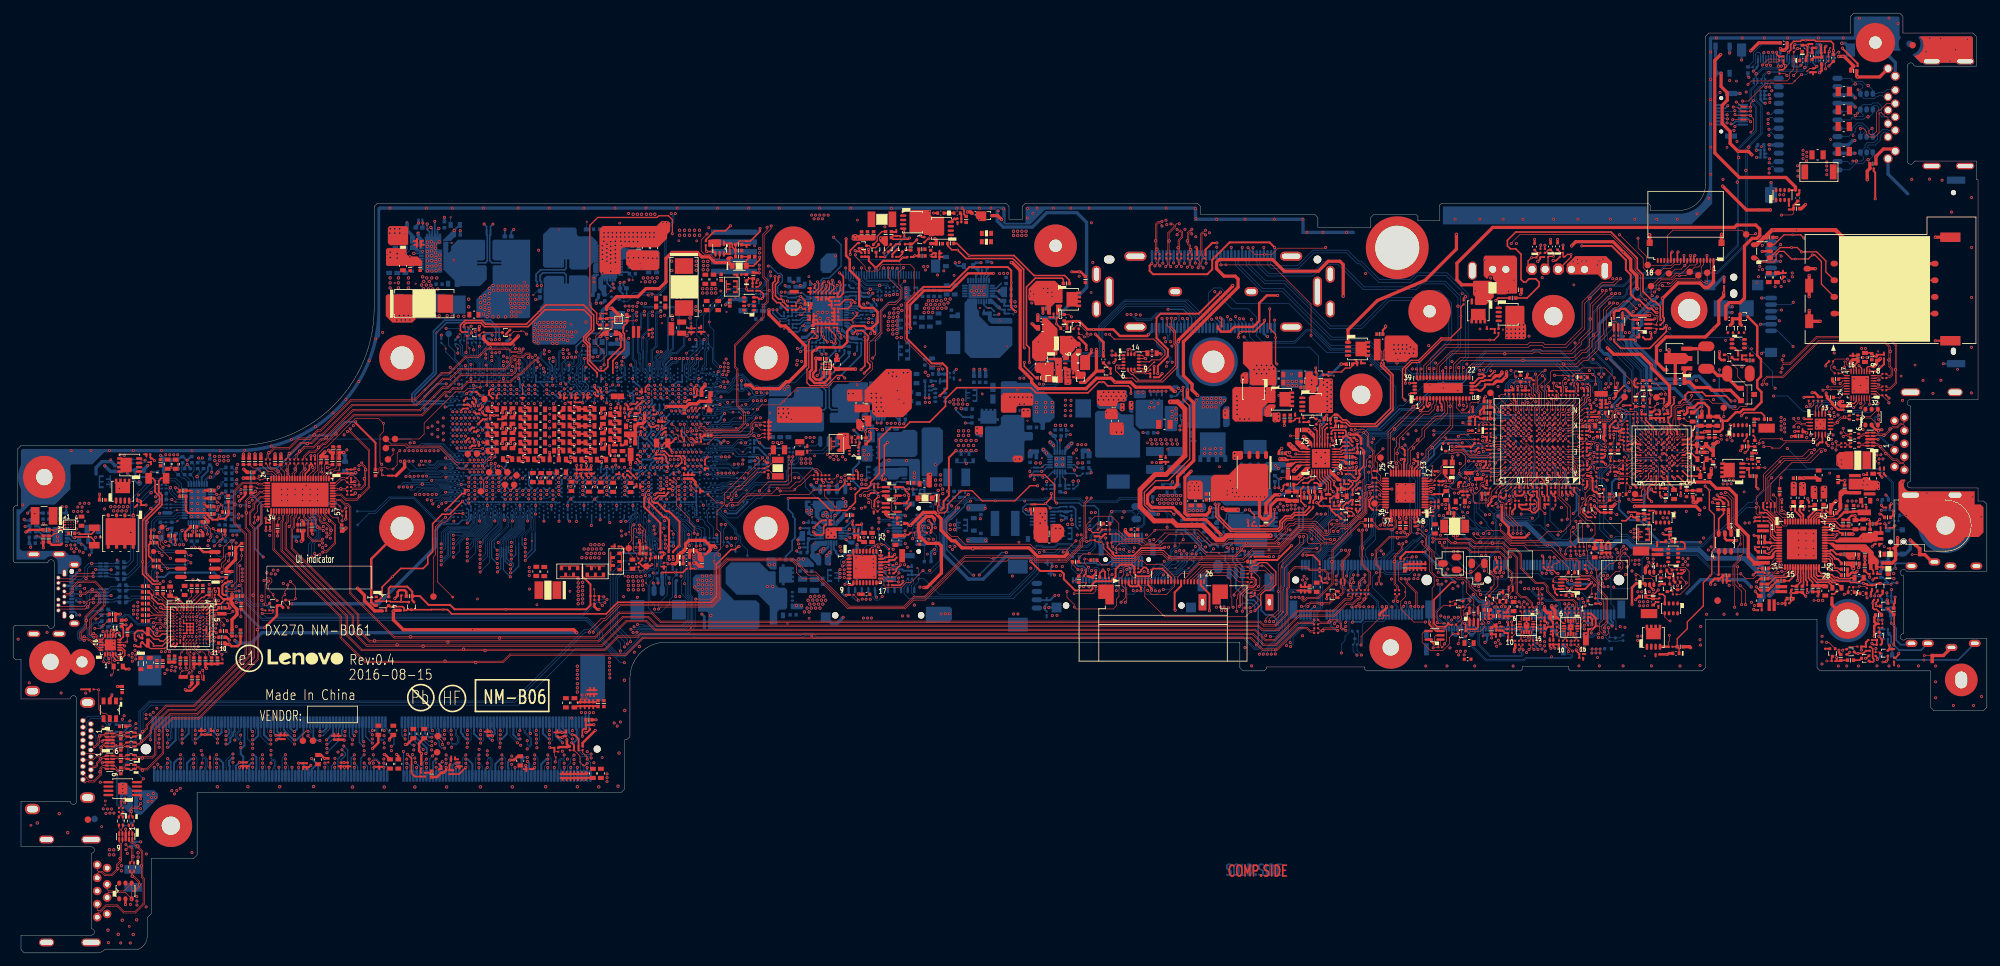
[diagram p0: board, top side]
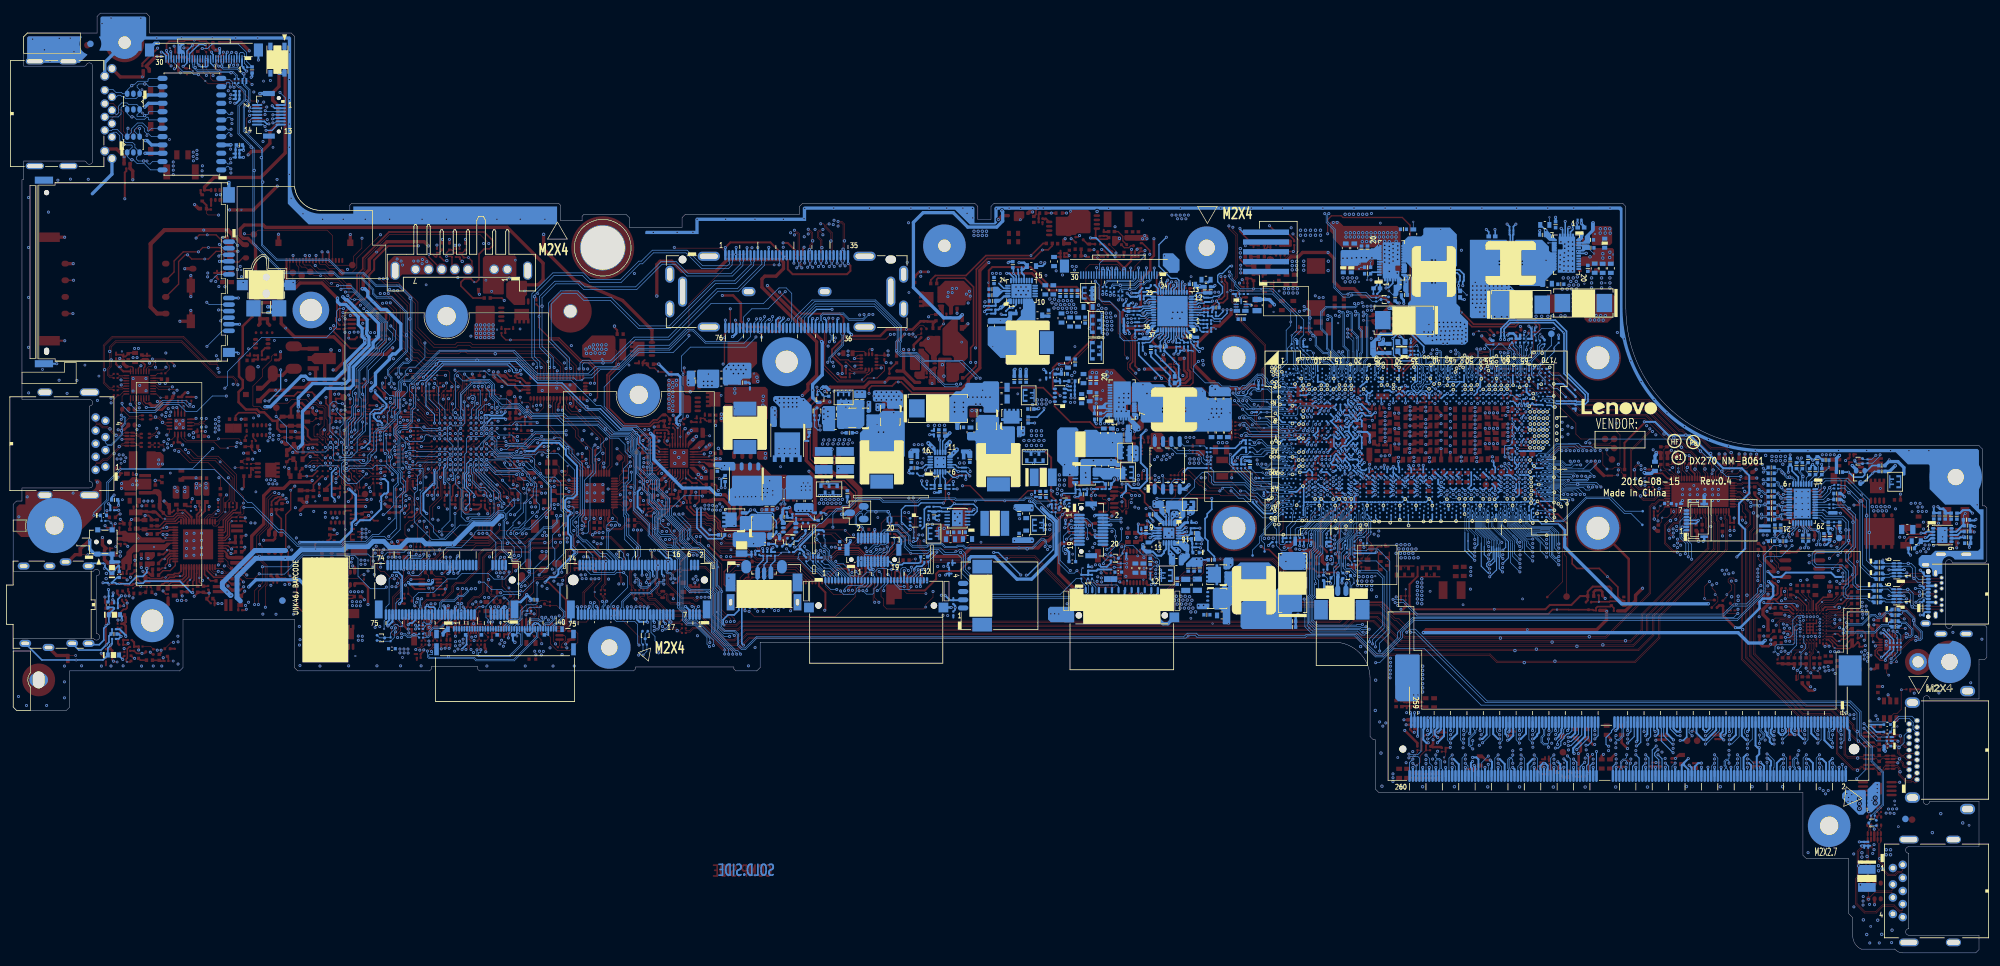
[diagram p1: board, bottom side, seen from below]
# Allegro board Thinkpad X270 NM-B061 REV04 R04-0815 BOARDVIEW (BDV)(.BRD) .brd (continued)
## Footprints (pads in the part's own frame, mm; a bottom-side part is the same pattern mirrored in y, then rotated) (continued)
JUMP_43X39
  custom 0.191x0.191 smd: 1(0,0) 2(0.914,0)
JUMP_43X79
  custom 0.188x0.188 smd: 1(0,0) 2(1.1,0)
JUMP_43X118
  custom 0.187x0.187 smd: 1(0,0) 2(1.1,0)
KX023-1025_LGA16_3X3
  oval 0.61x0.356 smd: 1(0,0) 2(0,-0.5) 3(0,-1) 4(0,-1.5) 5(0,-2) 9(2.325,-2) 10(2.325,-1.5) 11(2.325,-1) 12(2.325,-0.5) 13(2.325,0)
  oval 0.356x0.61 smd: 6(0.662,-2.163) 7(1.163,-2.163) 8(1.663,-2.163) 14(1.663,0.163) 15(1.163,0.163) 16(0.662,0.163)
LSK3541G1ET2L_VMT3
  rect 0.508x0.457 smd: 1(0,0)
  rect 0.406x0.457 smd: 2(-0.4,-1.15) 3(0.4,-1.15)
MEC1653TMP-TN_WFBGA_169P-T
  round 0.356 smd: A1(0,0) A2(0.8,0) A3(1.6,0) A4(2.4,0) A5(3.2,0) A6(4,0) A7(4.8,0) A8(5.6,0) A9(6.4,0) A10(7.2,0) A11(8,0) A12(8.8,0) A13(9.6,0) B1(0,-0.8) B2(0.8,-0.8) B3(1.6,-0.8) B4(2.4,-0.8) B5(3.2,-0.8) B6(4,-0.8) B7(4.8,-0.8) B8(5.6,-0.8) B9(6.4,-0.8) B10(7.2,-0.8) B11(8,-0.8) B12(8.8,-0.8) B13(9.6,-0.8) C1(0,-1.6) C2(0.8,-1.6) C3(1.6,-1.6) C4(2.4,-1.6) C5(3.2,-1.6) C6(4,-1.6) C7(4.8,-1.6) C8(5.6,-1.6) C9(6.4,-1.6) C10(7.2,-1.6) C11(8,-1.6) C12(8.8,-1.6) C13(9.6,-1.6) D1(0,-2.4) D2(0.8,-2.4) D3(1.6,-2.4) D4(2.4,-2.4) D5(3.2,-2.4) D6(4,-2.4) D7(4.8,-2.4) D8(5.6,-2.4) D9(6.4,-2.4) D10(7.2,-2.4) D11(8,-2.4) D12(8.8,-2.4) D13(9.6,-2.4) E1(0,-3.2) E2(0.8,-3.2) E3(1.6,-3.2) E4(2.4,-3.2) E5(3.2,-3.2) E6(4,-3.2) E7(4.8,-3.2) E8(5.6,-3.2) E9(6.4,-3.2) E10(7.2,-3.2) E11(8,-3.2) E12(8.8,-3.2) E13(9.6,-3.2) F1(0,-4) F2(0.8,-4) F3(1.6,-4) F4(2.4,-4) F5(3.2,-4) F6(4,-4) F7(4.8,-4) F8(5.6,-4) F9(6.4,-4) F10(7.2,-4) F11(8,-4) F12(8.8,-4) F13(9.6,-4) G1(0,-4.8) G2(0.8,-4.8) G3(1.6,-4.8) G4(2.4,-4.8) G5(3.2,-4.8) G6(4,-4.8) G7(4.8,-4.8) G8(5.6,-4.8) G9(6.4,-4.8) G10(7.2,-4.8) G11(8,-4.8) G12(8.8,-4.8) G13(9.6,-4.8) H1(0,-5.6) H2(0.8,-5.6) H3(1.6,-5.6) H4(2.4,-5.6) H5(3.2,-5.6) H6(4,-5.6) H7(4.8,-5.6) H8(5.6,-5.6) H9(6.4,-5.6) H10(7.2,-5.6) H11(8,-5.6) H12(8.8,-5.6) H13(9.6,-5.6) J1(0,-6.4) J2(0.8,-6.4) J3(1.6,-6.4) J4(2.4,-6.4) J5(3.2,-6.4) J6(4,-6.4) J7(4.8,-6.4) J8(5.6,-6.4) J9(6.4,-6.4) J10(7.2,-6.4) J11(8,-6.4) J12(8.8,-6.4) J13(9.6,-6.4) K1(0,-7.2) K2(0.8,-7.2) K3(1.6,-7.2) K4(2.4,-7.2) K5(3.2,-7.2) K6(4,-7.2) K7(4.8,-7.2) K8(5.6,-7.2) K9(6.4,-7.2) K10(7.2,-7.2) K11(8,-7.2) K12(8.8,-7.2) K13(9.6,-7.2) L1(0,-8) L2(0.8,-8) L3(1.6,-8) L4(2.4,-8) L5(3.2,-8) L6(4,-8) L7(4.8,-8) L8(5.6,-8) L9(6.4,-8) L10(7.2,-8) L11(8,-8) L12(8.8,-8) L13(9.6,-8) M1(0,-8.8) M2(0.8,-8.8) M3(1.6,-8.8) M4(2.4,-8.8) M5(3.2,-8.8) M6(4,-8.8) M7(4.8,-8.8) M8(5.6,-8.8) M9(6.4,-8.8) M10(7.2,-8.8) M11(8,-8.8) M12(8.8,-8.8) M13(9.6,-8.8) N1(0,-9.6) N2(0.8,-9.6) N3(1.6,-9.6) N4(2.4,-9.6) N5(3.2,-9.6) N6(4,-9.6) N7(4.8,-9.6) N8(5.6,-9.6) N9(6.4,-9.6) N10(7.2,-9.6) N11(8,-9.6) N12(8.8,-9.6) N13(9.6,-9.6)
MMBT3904_SOT23-3
  oval 1.016x1.524 smd: 1(0,0) 2(0.965,2.083) 3(-0.965,2.083)
MOLEX_52435-2671_26P-T
  oval 0.305x0.787 smd: 1(0,0) 2(-0.5,0) 3(-1,0) 4(-1.5,0) 5(-2,0) 6(-2.5,0) 7(-3,0) 8(-3.5,0) 9(-4,0) 10(-4.5,0) 11(-5,0) 12(-5.5,0) 13(-6,0) 14(-6.5,0) 15(-7,0) 16(-7.5,0) 17(-8,0) 18(-8.5,0) 19(-9,0) 20(-9.5,0) 21(-10,0) 22(-10.5,0) 23(-11,0) 24(-11.5,0) 25(-12,0) 26(-12.5,0)
  custom 0.597x0.597 smd: 27(2.45,1.925) 28(-14.95,1.925)
MOLEX_78048-0543_5P-T
  rect 0.838x7.01 smd: 1(0,0) 2(1.5,0) 3(3,0) 4(4.5,0) 5(6,0)
MURAT_BLM18PG221SN1D_2P
  rect 0.61x0.711 smd: 1(0,0) 2(1.3,0)
NCP431AISNT1G_SOT23-3
  rect 0.787x0.889 smd: 1(0,0) 2(0.95,2) 3(-0.95,2)
NCP81208MNTXG_QFN48_6X6
  oval 0.787x0.305 smd: 1(0,0) 2(0,-0.4) 3(0,-0.8) 4(0,-1.2) 5(0,-1.6) 6(0,-2) 7(0,-2.4) 8(0,-2.8) 9(0,-3.2) 10(0,-3.6) 11(0,-4) 12(0,-4.4) 25(5.72,-4.4) 26(5.72,-4) 27(5.72,-3.6) 28(5.72,-3.2) 29(5.72,-2.8) 30(5.72,-2.4) 31(5.72,-2) 32(5.72,-1.6) 33(5.72,-1.2) 34(5.72,-0.8) 35(5.72,-0.4) 36(5.72,0)
  oval 0.305x0.787 smd: 13(0.66,-5.06) 14(1.06,-5.06) 15(1.46,-5.06) 16(1.86,-5.06) 17(2.26,-5.06) 18(2.66,-5.06) 19(3.06,-5.06) 20(3.46,-5.06) 21(3.86,-5.06) 22(4.26,-5.06) 23(4.66,-5.06) 24(5.06,-5.06) 37(5.06,0.66) 38(4.66,0.66) 39(4.26,0.66) 40(3.86,0.66) 41(3.46,0.66) 42(3.06,0.66) 43(2.66,0.66) 44(2.26,0.66) 45(1.86,0.66) 46(1.46,0.66) 47(1.06,0.66) 48(0.66,0.66)
  rect 4.648x4.648 smd: 49(2.86,-2.2)
NCP81382MNTXG_QFN39-31_6X4
  rect 0.711x0.305 smd: 1(0,0) 2(0,-0.4) 3(0,-0.8) 4(0,-1.2) 5(0,-1.6) 6(0,-2)
  rect 0.305x0.711 smd: 7(0.65,-2.85) 8(1.05,-2.85) 9(1.45,-2.85) 10(1.85,-2.85) 11(2.25,-2.85) 12(2.65,-2.85) 13(3.05,-2.85) 14(3.45,-2.85) 15(3.85,-2.85) 16(4.25,-2.85) 17(4.65,-2.85) 18(5.05,-2.85) 20(5.05,0.85) 21(4.65,0.85) 22(4.25,0.85) 23(3.85,0.85) 24(3.45,0.85) 25(3.05,0.85) 26(2.65,0.85) 27(2.25,0.85) 28(1.85,0.85) 29(1.45,0.85) 30(1.05,0.85) 31(0.65,0.85)
  custom 0.665x0.665 smd: 19(2.85,-1)
NL17SG07DFT2G_SC-88A5
  rect 0.406x0.508 smd: 1(0,0) 2(0.65,0) 3(1.3,0) 4(1.3,1.9) 5(0,1.9)
PAD_C5P6D3P4
  round 5.588 hole 3.404: 1(0,0)
PAD_C6P5D1P9
  round 6.502 hole 1.905: 1(0,0)
PAD_C6P5D2P5
  round 6.502 hole 2.489: 1(0,0)
PAD_C6P5D2P8
  round 6.502 hole 2.794: 1(0,0)
PAD_CT4P0B2P7D1P7
  round 3.988 hole 1.702: 1(0,0)
PAD_CT5P0D1P8X2P6
  round 5.004 hole 2.591x1.803: 1(0,0)
PAD_CT5P6B6P6D3P4
  round 5.588 hole 3.404: 1(0,0)
PAD_CT6P0B5P0D1P9
  round 5.994 hole 1.905: 1(0,0)
PAD_CT6P5B7P5D3P4
  round 6.502 hole 3.404: 1(0,0)
PAD_CT6P5B8P0D2P5
  round 6.502 hole 2.489: 1(0,0)
PAD_CT6P5D1P9
  round 6.502 hole 1.905: 1(0,0)
PAD_CT7P0B6P5D3P5
  round 7.01 hole 3.505: 1(0,0)
PAD_CT7P0B8P4D2P8
  round 7.01 hole 2.794: 1(0,0)
PAD_CT9P6D6P7
  round 9.601 hole 6.706: 1(0,0)
PANAS_EXC24CH900U_4P
  oval 0.356x0.559 smd: 1(0,0) 2(0,1.25) 3(0.6,1.25) 4(0.6,0)
PESD5V0U2BT_SOT23-3
  oval 1.016x1.524 smd: 1(0,0) 2(0.965,2.083) 3(-0.965,2.083)
PI2EQX862XUAEX_TQFN18_2X2
  custom 0.05x0.05 smd: 1(0,0) 5(0,-1.6) 6(0.4,-1.8) 9(1.6,-1.8) 10(2,-1.6) 14(2,0) 15(1.6,0.2) 18(0.4,0.2)
  rect 0.61x0.305 smd: 2(0,-0.4) 3(0,-0.8) 4(0,-1.2) 11(2,-1.2) 12(2,-0.8) 13(2,-0.4)
  rect 0.305x0.61 smd: 7(0.8,-1.8) 8(1.2,-1.8) 16(1.2,0.2) 17(0.8,0.2)
  rect 0.889x0.889 smd: 19(1,-0.8)
PI3L720ZHELFCX_TQFN42_9X3P5
  oval 0.381x0.737 smd: 1(0,0) 2(0.5,0) 3(1,0) 4(1.5,0) 5(2,0) 6(2.5,0) 7(3,0) 8(3.5,0) 9(4,0) 10(4.5,0) 11(5,0) 12(5.5,0) 13(6,0) 14(6.5,0) 15(7,0) 16(7.5,0) 17(8,0) 22(8,3.18) 23(7.5,3.18) 24(7,3.18) 25(6.5,3.18) 26(6,3.18) 27(5.5,3.18) 28(5,3.18) 29(4.5,3.18) 30(4,3.18) 31(3.5,3.18) 32(3,3.18) 33(2.5,3.18) 34(2,3.18) 35(1.5,3.18) 36(1,3.18) 37(0.5,3.18) 38(0,3.18)
  oval 0.737x0.381 smd: 18(8.34,0.84) 19(8.34,1.34) 20(8.34,1.84) 21(8.34,2.34) 39(-0.34,2.34) 40(-0.34,1.84) 41(-0.34,1.34) 42(-0.34,0.84)
  rect 5.994x1.499 smd: 43(4,1.59)
PS8349BQFN66GTR-A0_QFN66_5X10
  oval 0.914x0.305 smd: 1(0,0) 2(0,-0.4) 3(0,-0.8) 4(0,-1.2) 5(0,-1.6) 6(0,-2) 7(0,-2.4) 8(0,-2.8) 9(0,-3.2) 10(0,-3.6) 11(0,-4) 12(0,-4.4) 13(0,-4.8) 14(0,-5.2) 15(0,-5.6) 16(0,-6) 17(0,-6.4) 18(0,-6.8) 19(0,-7.2) 20(0,-7.6) 21(0,-8) 22(0,-8.4) 23(0,-8.8) 34(4.95,-8.8) 35(4.95,-8.4) 36(4.95,-8) 37(4.95,-7.6) 38(4.95,-7.2) 39(4.95,-6.8) 40(4.95,-6.4) 41(4.95,-6) 42(4.95,-5.6) 43(4.95,-5.2) 44(4.95,-4.8) 45(4.95,-4.4) 46(4.95,-4) 47(4.95,-3.6) 48(4.95,-3.2) 49(4.95,-2.8) 50(4.95,-2.4) 51(4.95,-2) 52(4.95,-1.6) 53(4.95,-1.2) 54(4.95,-0.8) 55(4.95,-0.4) 56(4.95,0)
  oval 0.305x0.914 smd: 24(0.675,-9.375) 25(1.075,-9.375) 26(1.475,-9.375) 27(1.875,-9.375) 28(2.275,-9.375) 29(2.675,-9.375) 30(3.075,-9.375) 31(3.475,-9.375) 32(3.875,-9.375) 33(4.275,-9.375) 57(4.275,0.575) 58(3.875,0.575) 59(3.475,0.575) 60(3.075,0.575) 61(2.675,0.575) 62(2.275,0.575) 63(1.875,0.575) 64(1.475,0.575) 65(1.075,0.575) 66(0.675,0.575)
  rect 3.708x8.712 smd: 67(2.475,-4.4)
PS8743BQFN40GTR-B0_QFN40_4X6
  oval 0.914x0.305 smd: 1(0,0) 2(0,-0.4) 3(0,-0.8) 4(0,-1.2) 5(0,-1.6) 6(0,-2) 7(0,-2.4) 8(0,-2.8) 21(5.95,-2.8) 22(5.95,-2.4) 23(5.95,-2) 24(5.95,-1.6) 25(5.95,-1.2) 26(5.95,-0.8) 27(5.95,-0.4) 28(5.95,0)
  oval 0.305x0.914 smd: 9(0.775,-3.375) 10(1.175,-3.375) 11(1.575,-3.375) 12(1.975,-3.375) 13(2.375,-3.375) 14(2.775,-3.375) 15(3.175,-3.375) 16(3.575,-3.375) 17(3.975,-3.375) 18(4.375,-3.375) 19(4.775,-3.375) 20(5.175,-3.375) 29(5.175,0.575) 30(4.775,0.575) 31(4.375,0.575) 32(3.975,0.575) 33(3.575,0.575) 34(3.175,0.575) 35(2.775,0.575) 36(2.375,0.575) 37(1.975,0.575) 38(1.575,0.575) 39(1.175,0.575) 40(0.775,0.575)
  rect 4.597x2.591 smd: 41(2.975,-1.4)
R0201_SHORT
  rect 0.483x0.305 smd: 1(0,0) 2(0.584,0)
R0402_SHORT
  rect 0.737x0.559 smd: 1(0,0) 2(0.914,0)
R0603_SHORT
  rect 1.041x0.889 smd: 1(0,0) 2(1.397,0)
R0805_SHORT
  rect 1.295x1.397 smd: 1(0,0) 2(1.702,0)
R_0201
  rect 0.33x0.305 smd: 1(0,0) 2(0.584,0)
R_0402
  rect 0.508x0.559 smd: 1(0,0) 2(0.914,0)
R_0402-TH
  rect 0.711x0.61 smd: 1(0,0) 2(0.989,0)
R_0603
  rect 0.635x0.889 smd: 1(0,0) 2(1.397,0)
R_0603_LE
  rect 0.508x1.803 smd: 1(0,0) 2(0.747,0)
R_0805
  rect 0.813x1.397 smd: 1(0,0) 2(1.702,0)
R_1206
  rect 1.016x1.651 smd: 1(0,0) 2(2.667,0)
R_1206_LE
  rect 1.041x3.302 smd: 1(0,0) 2(1.65,0)
R_1210
  oval 1.524x2.489 smd: 1(-1.715,0) 2(1.715,0)
RB520CS-30GT2RA_VMN2-2
  rect 0.457x0.559 smd: 1(0,0) 2(0.95,0)
RB520SM-30T2R_EMD2-2
  rect 0.61x0.787 smd: 1(0,0) 2(1.7,0)
RB521CS-30GT2RA_VMN2-2
  rect 0.457x0.559 smd: 1(0,0) 2(0.95,0)
RB751V-40_SOD323-2
  rect 0.787x0.889 smd: 1(0,0) 2(2.14,0)
RCLAMP0502BPTCT_SC75-3
  oval 0.406x0.787 smd: 1(0,0) 2(-0.5,-1.4) 3(0.5,-1.4)
RSB5P6SGTE61_SC-79-2-2
  rect 0.61x0.787 smd: 1(0,0) 2(1.7,0)
RT8068AZQW_WDFN10_3X3
  oval 0.254x0.889 smd: 1(0,0) 2(0.5,0) 3(1,0) 4(1.5,0) 5(2,0) 6(2,3.1) 7(1.5,3.1) 8(1,3.1) 9(0.5,3.1) 10(0,3.1)
  rect 2.464x1.626 smd: 11(1,1.55)
RTM002P02GT2L_VMT3
  oval 0.508x0.457 smd: 1(0,0)
  oval 0.406x0.457 smd: 2(-0.4,-1.15) 3(0.4,-1.15)
RTS5232-GR_QFN32_4X4
  oval 0.203x0.914 smd: 1(0,0) 2(0.4,0) 3(0.8,0) 4(1.2,0) 5(1.6,0) 6(2,0) 7(2.4,0) 8(2.8,0) 17(2.8,4.077) 18(2.4,4.077) 19(2,4.077) 20(1.6,4.077) 21(1.2,4.077) 22(0.8,4.077) 23(0.4,4.077) 24(0,4.077)
  oval 0.914x0.203 smd: 9(3.438,0.639) 10(3.438,1.039) 11(3.438,1.438) 12(3.438,1.838) 13(3.438,2.239) 14(3.438,2.639) 15(3.438,3.039) 16(3.438,3.438) 25(-0.639,3.438) 26(-0.639,3.039) 27(-0.639,2.639) 28(-0.639,2.239) 29(-0.639,1.838) 30(-0.639,1.438) 31(-0.639,1.039) 32(-0.639,0.639)
  rect 2.692x2.692 smd: 33(1.4,2.039)
RW1E014SNT2R_WEMT6
  oval 0.406x0.457 smd: 1(0,0) 3(1.1,0) 4(1.1,1.55) 6(0,1.55)
  oval 0.305x0.457 smd: 2(0.55,0) 5(0.55,1.55)
SI7121DN-T1-GE3_POWERPAK-8-5
  oval 0.406x0.991 smd: 1(0,0) 2(0.66,0) 3(1.32,0) 4(1.98,0)
  custom 0.559x0.559 smd: 5(0.99,2.247)
SINGA_2RJ3047-108411F_12P
  round 1.295 hole 0.889: 1(0,0) 2(-1.02,-1.1) 3(-2.04,0) 4(-3.06,-1.1) 5(-4.08,0) 6(-5.1,-1.1) 7(-6.12,0) 8(-7.14,-1.1)
  round 1.397 hole 0.991: 9(2.15,-1.1) 10(3.3,0) 11(-10.44,0) 12(-9.29,-1.1)
  oval 0.991x2.794 hole 0.61x2.388: 13(-11.56,-6.65) 14(-11.56,-11.75) 15(4.42,-6.65) 16(4.42,-11.75)
SINGA_2SJ3052-012111F_6P
  oval 1.092x1.803 hole 0.508x1.194: 1(0,0) 2(-11.8,0) 3(0,9.9) 4(0,5.95) 5(-11.8,2.5) 6(-11.8,9.65) 7(0.625,3.5) 8(-12.425,6.1)
SINGA_2UB3908-000101F_9P
  round 1.295 hole 0.711: 1(0,0) 2(-2.5,0) 3(-4.5,0) 4(-7,0) 5(-7.5,-1.5) 6(-5.5,-1.5) 7(-3.5,-1.5) 8(-1.5,-1.5) 9(0.5,-1.5)
  oval 1.194x2.311 hole 0.787x1.956: 10(4.35,-9.23) 13(-11.35,-9.23)
  oval 1.194x2.997 hole 0.787x2.591: 11(4.35,-2.43) 12(-11.35,-2.43)
SIP32451DB-T2-GE1_WCSP_4P
  round 0.305 smd: A1(0,0) A2(0.4,0) B1(0,-0.4) B2(0.4,-0.4)
SIS402DNT1GE_POWERPAK1212-8-5
  oval 0.406x0.991 smd: 1(0,0) 2(0.66,0) 3(1.32,0) 4(1.98,0)
  custom 0.559x0.559 smd: 5(0.99,2.247)
SIS406DN-T1-GE3_PAK1212-8-5
  oval 0.406x0.991 smd: 1(0,0) 2(0.66,0) 3(1.32,0) 4(1.98,0)
  custom 0.559x0.559 smd: 5(0.99,2.248)
SKYLAKE-U_BGA_1356P-T
  round 0.356 smd: A3(-0.965,0) A70(-40.166,0) B2(-0.483,0.483) B71(-40.629,0.462) BA1(0,22.166) BA71(-40.629,22.166) BB2(-0.462,22.628) BB70(-40.166,22.628) C1(0,0.965)
  round 0.33 smd: A4(-1.615,0) A69(-39.516,0) AY1(0,21.516) AY71(-40.629,21.516) B3(-1.118,0.635) B70(-39.999,0.63) BA2(-0.629,21.999) BA70(-39.999,21.999) BB3(-1.113,22.628) BB69(-39.516,22.628) C2(-0.635,1.118) C71(-40.629,1.113) D1(0,1.615)
  round 0.305 smd: A5(-2.266,0) A68(-38.866,0) AA2(-0.975,10.804) AA4(-1.951,10.804) AA63(-35.427,10.719) AA64(-36.077,10.719) AA65(-36.727,10.719) AA66(-37.377,10.719) AA67(-38.028,10.719) AA68(-38.678,10.719) AA69(-39.328,10.719) AA70(-39.978,10.719) AA71(-40.629,10.719) AB4(-1.951,11.467) AB6(-2.729,11.181) AB7(-3.379,11.181) AB8(-4.029,11.181) AB9(-4.679,11.181) AB10(-5.33,11.181) AB11(-5.98,11.181) AB12(-6.63,11.181) AB13(-7.28,11.181) AB15(-8.126,11.305) AB16(-8.776,11.305) AB17(-9.426,11.305) AB18(-10.077,11.305) AB19(-10.727,11.305) AB20(-11.377,11.305) AB21(-12.027,11.305) AB62(-34.958,11.176) AC3(-1.626,12.13) AC63(-35.427,11.633) AC64(-36.077,11.633) AC65(-36.727,11.633) AC66(-37.377,11.633) AC67(-38.028,11.633) AC68(-38.678,11.633) AC69(-39.328,11.633) AC70(-39.978,11.633) AC71(-40.629,11.633) AD4(-1.951,12.792) AD6(-2.729,12.248) AD7(-3.379,12.248) AD8(-4.029,12.248) AD9(-4.679,12.248) AD10(-5.33,12.248) AD11(-5.98,12.248) AD12(-6.63,12.248) AD13(-7.28,12.248) AD15(-8.126,12.143) AD16(-8.776,12.143) AD17(-9.426,12.143) AD18(-10.077,12.143) AD19(-10.727,12.143) AD20(-11.377,12.143) AD21(-12.027,12.143) AD62(-34.958,12.09) AE62(-34.958,13.005) AE63(-35.427,12.547) AE64(-36.077,12.547) AE65(-36.727,12.547) AE66(-37.377,12.547) AE67(-38.028,12.547) AE68(-38.678,12.547) AE69(-39.328,12.547) AF2(-0.975,13.455) AF4(-1.951,13.455) AF6(-2.729,13.315) AF7(-3.379,13.315) AF8(-4.029,13.315) AF9(-4.679,13.315) AF10(-5.33,13.315) AF11(-5.98,13.315) AF12(-6.63,13.315) AF13(-7.28,13.315) AF15(-8.126,12.982) AF16(-8.776,12.982) AF17(-9.426,12.982) AF18(-10.077,12.982) AF19(-10.727,12.982) AF20(-11.377,12.982) AF21(-12.027,12.982) AF63(-35.427,13.462) AF64(-36.077,13.462) AF65(-36.727,13.462) AF66(-37.377,13.462) AF67(-38.028,13.462) AF68(-38.678,13.253) AF69(-39.328,13.253) AG4(-1.951,14.118) AG15(-8.126,13.82) AG16(-8.776,13.82) AG17(-9.426,13.82) AG18(-10.077,13.82) AG19(-10.727,13.82) AG20(-11.377,13.82) AG21(-12.027,13.82) AG62(-34.958,13.919) AG69(-39.003,13.916) AH3(-1.626,14.781) AH6(-2.729,14.381) AH7(-3.379,14.381) AH8(-4.029,14.381) AH9(-4.679,14.381) AH10(-5.33,14.381) AH11(-5.98,14.381) AH12(-6.63,14.381) AH13(-7.28,14.381) AH63(-35.427,14.376) AH64(-36.077,14.376) AH65(-36.727,14.376) AH66(-37.377,14.376) AH67(-38.028,14.376) AJ4(-1.951,15.444) AJ15(-8.126,14.658) AJ16(-8.776,14.658) AJ17(-9.426,14.658) AJ18(-10.077,14.658) AJ19(-10.727,14.658) AJ20(-11.377,14.658) AJ21(-12.027,14.658) AJ62(-34.958,14.833) AK6(-2.729,15.321) AK7(-3.379,15.321) AK8(-4.029,15.321) AK9(-4.679,15.321) AK10(-5.33,15.321) AK11(-5.98,15.321) AK12(-6.63,15.321) AK13(-7.28,15.321) AK15(-8.126,15.496) AK16(-8.776,15.496) AK17(-9.426,15.496) AK18(-10.077,15.496) AK19(-10.727,15.496) AK20(-11.377,15.496) AK21(-12.027,15.496) AK22(-12.719,15.323) AK23(-13.633,15.323) AK25(-14.547,15.323) AK27(-15.462,15.323) AK28(-16.376,15.323) AK30(-17.291,15.323) AK32(-18.205,15.323) AK33(-19.119,15.323) AK35(-20.034,15.323) AK37(-20.948,15.323) AK38(-21.863,15.323) AK40(-22.777,15.323) AK42(-23.691,15.323) AK43(-24.606,15.323) AK45(-25.52,15.323) AK46(-26.435,15.323) AK48(-27.349,15.323) AK50(-28.263,15.323) AK52(-29.178,15.323) AK53(-30.092,15.323) AK55(-31.007,15.323) AK56(-31.921,15.323) AK58(-32.835,15.323) AK60(-33.75,15.323) AK62(-34.774,15.458) AK63(-35.427,15.291) AK64(-36.077,15.291) AK65(-36.727,15.291) AK66(-37.377,15.291) AK67(-38.028,15.291) AK68(-38.678,15.143) AK69(-39.653,15.143) AL2(-0.975,16.107) AL4(-1.951,16.107) AL23(-13.176,15.788) AL25(-14.09,15.788) AL27(-15.005,15.788) AL28(-15.919,15.788) AL30(-16.833,15.788) AL32(-17.748,15.788) AL33(-18.662,15.788) AL35(-19.577,15.788) AL37(-20.491,15.788) AL38(-21.405,15.788) AL40(-22.32,15.788) AL42(-23.234,15.788) AL43(-24.149,15.788) AL45(-25.063,15.788) AL46(-25.977,15.788) AL48(-26.892,15.788) AL50(-27.806,15.788) AL52(-28.721,15.788) AL53(-29.635,15.788) AL55(-30.549,15.788) AL56(-31.464,15.788) AL58(-32.378,15.788) AL60(-33.293,15.788) AL61(-34.207,15.788) AL63(-35.427,16.159) AL64(-36.077,16.159) AL65(-36.727,16.159) AL66(-37.377,16.159) AM4(-1.951,16.77) AM5(-2.66,16.261) AM7(-3.575,16.261) AM8(-4.489,16.261) AM10(-5.403,16.261) AM11(-6.318,16.261) AM13(-7.232,16.261) AM15(-8.147,16.261) AM16(-9.061,16.261) AM18(-9.975,16.261) AM20(-10.89,16.261) AM21(-11.804,16.261) AM22(-12.719,16.261) AM23(-13.633,16.261) AM25(-14.547,16.261) AM27(-15.462,16.261) AM28(-16.376,16.261) AM30(-17.291,16.261) AM32(-18.205,16.261) AM33(-19.119,16.261) AM35(-20.034,16.261) AM37(-20.948,16.261) AM38(-21.863,16.261) AM40(-22.777,16.261) AM42(-23.691,16.261) AM43(-24.606,16.261) AM45(-25.52,16.261) AM46(-26.435,16.261) AM48(-27.349,16.261) AM50(-28.263,16.261) AM52(-29.178,16.261) AM53(-30.092,16.261) AM55(-31.007,16.261) AM56(-31.921,16.261) AM58(-32.835,16.261) AM60(-33.75,16.261) AM61(-34.664,16.261) AM68(-38.353,16.37) AM69(-39.003,16.37) AN3(-1.626,17.433) AN5(-2.66,16.911) AN7(-3.575,16.911) AN8(-4.489,16.911) AN10(-5.403,16.911) AN11(-6.318,16.911) AN13(-7.232,16.911) AN15(-8.147,16.911) AN16(-9.061,16.911) AN18(-9.975,16.911) AN20(-10.89,16.911) AN21(-11.804,16.911) AN22(-12.719,16.911) AN23(-13.633,16.911) AN25(-14.547,16.911) AN27(-15.462,16.911) AN28(-16.376,16.911) AN30(-17.291,16.911) AN32(-18.205,16.911) AN33(-19.119,16.911) AN35(-20.034,16.911) AN37(-20.948,16.911) AN38(-21.863,16.911) AN40(-22.777,16.911) AN42(-23.691,16.911) AN43(-24.606,16.911) AN45(-25.52,16.911) AN46(-26.435,16.911) AN48(-27.349,16.911) AN50(-28.263,16.911) AN52(-29.178,16.911) AN53(-30.092,16.911) AN55(-31.007,16.911) AN56(-31.921,16.911) AN58(-32.835,16.911) AN60(-33.75,16.911) AN61(-34.664,16.911) AN63(-35.579,16.911) AN65(-36.493,16.911) AN66(-37.407,16.911) AN68(-38.678,17.033) AN69(-39.328,17.033) AP4(-1.951,18.096) AP5(-2.66,17.561) AP7(-3.575,17.561) AP8(-4.489,17.561) AP10(-5.403,17.561) AP11(-6.318,17.561) AP13(-7.232,17.561) AP15(-8.147,17.561) AP16(-9.061,17.561) AP18(-9.975,17.561) AP20(-10.89,17.561) AP21(-11.804,17.561) AP22(-12.719,17.561) AP23(-13.633,17.561) AP25(-14.547,17.561) AP27(-15.462,17.561) AP28(-16.376,17.561) AP30(-17.291,17.561) AP32(-18.205,17.561) AP33(-19.119,17.561) AP35(-20.034,17.561) AP37(-20.948,17.561) AP38(-21.863,17.561) AP40(-22.777,17.561) AP42(-23.691,17.561) AP43(-24.606,17.561) AP45(-25.52,17.561) AP46(-26.435,17.561) AP48(-27.349,17.561) AP50(-28.263,17.561) AP52(-29.178,17.561) AP53(-30.092,17.561) AP55(-31.007,17.561) AP56(-31.921,17.561) AP58(-32.835,17.561) AP60(-33.75,17.561) AP61(-34.664,17.561) AP63(-35.579,17.561) AP65(-36.493,17.561) AP66(-37.407,17.561) AP68(-38.353,17.646) AP70(-39.572,17.646) AR5(-2.66,18.211) AR7(-3.575,18.211) AR8(-4.489,18.211) AR10(-5.403,18.211) AR11(-6.318,18.211) AR13(-7.232,18.211) AR15(-8.147,18.211) AR16(-9.061,18.211) AR18(-9.975,18.211) AR20(-10.89,18.211) AR21(-11.804,18.211) AR22(-12.719,18.211) AR23(-13.633,18.211) AR25(-14.547,18.211) AR27(-15.462,18.211) AR28(-16.376,18.211) AR30(-17.291,18.211) AR32(-18.205,18.211) AR33(-19.119,18.211) AR35(-20.034,18.211) AR37(-20.948,18.211) AR38(-21.863,18.211) AR40(-22.777,18.211) AR42(-23.691,18.211) AR43(-24.606,18.211) AR45(-25.52,18.211) AR46(-26.435,18.211) AR48(-27.349,18.211) AR50(-28.263,18.211) AR52(-29.178,18.211) AR53(-30.092,18.211) AR55(-31.007,18.211) AR56(-31.921,18.211) AR58(-32.835,18.211) AR60(-33.75,18.211) AR61(-34.664,18.211) AR63(-35.579,18.211) AR65(-36.493,18.211) AR66(-37.407,18.211) AR68(-38.678,18.26) AR69(-39.328,18.26) AT2(-0.975,18.759) AT4(-1.951,18.759) AT5(-2.66,18.862) AT7(-3.575,18.862) AT8(-4.489,18.862) AT10(-5.403,18.862) AT11(-6.318,18.862) AT13(-7.232,18.862) AT15(-8.147,18.862) AT16(-9.061,18.862) AT18(-9.975,18.862) AT20(-10.89,18.862) AT21(-11.804,18.862) AT22(-12.719,18.862) AT23(-13.633,18.862) AT25(-14.547,18.862) AT27(-15.462,18.862) AT28(-16.376,18.862) AT30(-17.291,18.862) AT32(-18.205,18.862) AT33(-19.119,18.862) AT35(-20.034,18.862) AT37(-20.948,18.862) AT38(-21.863,18.862) AT40(-22.777,18.862) AT42(-23.691,18.862) AT43(-24.606,18.862) AT45(-25.52,18.862) AT46(-26.435,18.862) AT48(-27.349,18.862) AT50(-28.263,18.862) AT52(-29.178,18.862) AT53(-30.092,18.862) AT55(-31.007,18.862) AT56(-31.921,18.862) AT58(-32.835,18.862) AT60(-33.75,18.862) AT61(-34.664,18.862) AT63(-35.579,18.862) AT65(-36.493,18.862) AT66(-37.407,18.862) AT68(-38.353,18.823) AT69(-39.003,18.823) AU4(-1.951,19.422) AU5(-2.66,19.512) AU7(-3.575,19.512) AU8(-4.489,19.512) AU10(-5.403,19.512) AU11(-6.318,19.512) AU13(-7.232,19.512) AU15(-8.147,19.512) AU16(-9.061,19.512) AU18(-9.975,19.512) AU20(-10.89,19.512) AU21(-11.804,19.512) AU22(-12.719,19.512) AU23(-13.633,19.512) AU25(-14.547,19.512) AU27(-15.462,19.512) AU28(-16.376,19.512) AU30(-17.291,19.512) AU32(-18.205,19.512) AU33(-19.119,19.512) AU35(-20.034,19.512) AU37(-20.948,19.512) AU38(-21.863,19.512) AU40(-22.777,19.512) AU42(-23.691,19.512) AU43(-24.606,19.512) AU45(-25.52,19.512) AU46(-26.435,19.512) AU48(-27.349,19.512) AU50(-28.263,19.512) AU52(-29.178,19.512) AU53(-30.092,19.512) AU55(-31.007,19.512) AU56(-31.921,19.512) AU58(-32.835,19.512) AU60(-33.75,19.512) AU61(-34.664,19.512) AU63(-35.579,19.512) AU65(-36.493,19.512) AU66(-37.407,19.512) AV3(-1.626,20.113) AV68(-38.343,20.026) AV69(-39.328,20.215) AV70(-39.978,20.215) AW1(0,20.866) AW5(-2.534,20.226) AW6(-3.184,20.353) AW7(-3.75,20.678) AW8(-4.328,20.353) AW9(-4.898,20.678) AW10(-5.561,20.353) AW11(-6.171,20.678) AW12(-6.749,20.353) AW13(-7.319,20.678) AW14(-7.982,20.353) AW15(-8.592,20.678) AW16(-9.17,20.353) AW17(-9.74,20.678) AW18(-10.403,20.353) AW20(-11.012,20.678) AW21(-11.59,20.353) AW22(-12.16,20.678) AW23(-12.849,20.353) AW25(-13.486,20.678) AW26(-14.05,20.353) AW27(-14.713,20.678) AW28(-15.326,20.353) AW29(-15.94,20.678) AW30(-16.603,20.353) AW31(-17.167,20.678) AW32(-17.83,20.353) AW33(-18.467,20.678) AW34(-19.031,20.353) AW35(-19.694,20.678) AW36(-20.307,20.353) AW37(-20.921,20.678) AW38(-21.584,20.353) AW39(-22.148,20.678) AW41(-22.785,20.353) AW42(-23.423,20.678) AW43(-23.986,20.353) AW44(-24.649,20.678) AW45(-25.263,20.353) AW46(-25.876,20.678) AW47(-26.477,20.353) AW48(-27.041,20.678) AW49(-27.669,20.353) AW50(-28.298,20.678) AW51(-28.862,20.353) AW52(-29.463,20.678) AW53(-30.076,20.353) AW54(-30.69,20.678) AW55(-31.352,20.353) AW56(-31.916,20.678) AW57(-32.554,20.353) AW59(-33.191,20.678) AW60(-33.755,20.353) AW61(-34.418,20.678) AW62(-35.032,20.353) AW63(-35.645,20.678) AW64(-36.308,20.353) AW65(-36.872,20.678) AW66(-37.407,20.215) AW67(-38.332,20.685) AW68(-38.936,20.936) AW69(-39.581,20.85) AW70(-39.999,21.349) AW71(-40.629,20.866) AY2(-0.629,21.348) AY3(-1.286,21.342) AY4(-2.04,21.357) AY5(-2.649,21.003) AY8(-4.328,21.003) AY12(-6.749,21.003) AY16(-9.17,21.003) AY21(-11.59,21.003) AY26(-14.05,21.003) AY27(-14.713,21.328) AY29(-15.94,21.328) AY30(-16.603,21.003) AY34(-19.031,21.003) AY35(-19.694,21.328) AY37(-20.921,21.328) AY38(-21.584,21.003) AY43(-23.986,21.003) AY44(-24.649,21.328) AY46(-25.876,21.328) AY47(-26.477,21.003) AY51(-28.862,21.003) AY52(-29.463,21.328) AY54(-30.69,21.328) AY55(-31.352,21.003) AY60(-33.755,21.003) AY61(-34.418,21.328) AY63(-35.645,21.328) AY64(-36.308,21.003) AY66(-37.535,21.003) AY68(-38.85,21.581) B5(-2.266,0.65) B6(-2.847,0.975) B10(-5.325,0.975) B14(-7.803,0.975) B18(-10.281,0.975) B22(-12.759,0.975) B26(-15.237,0.975) B30(-17.715,0.975) B34(-20.194,0.975) B39(-22.672,0.975) B44(-25.15,0.975) B48(-27.628,0.975) B53(-30.106,0.975) B58(-32.584,0.975) B62(-35.062,0.975) B66(-37.54,0.975) B69(-39.349,0.63) BA3(-1.279,21.999) BA5(-2.599,21.94) BA8(-4.328,21.653) BA12(-6.749,21.653) BA16(-9.17,21.653) BA21(-11.59,21.653) BA23(-12.849,21.572) BA28(-15.326,21.572) BA32(-17.83,21.572) BA36(-20.307,21.572) BA41(-22.785,21.572) BA45(-25.263,21.572) BA49(-27.669,21.653) BA53(-30.076,21.572) BA57(-32.554,21.572) BA62(-35.032,21.572) BA68(-39.349,21.999) BB4(-1.763,22.628) BB68(-38.866,22.628) C4(-1.699,0.978) C5(-2.266,1.3) C7(-3.523,1.3) C8(-4.086,0.975) C9(-4.65,1.3) C11(-6.001,1.3) C12(-6.564,0.975) C13(-7.128,1.3) C15(-8.479,1.3) C16(-9.042,0.975) C17(-9.606,1.3) C19(-10.957,1.3) C20(-11.52,0.975) C21(-12.084,1.3) C23(-13.435,1.3) C24(-13.998,0.975) C25(-14.562,1.3) C27(-15.913,1.3) C28(-16.476,0.975) C29(-17.04,1.3) C31(-18.391,1.3) C32(-18.954,0.975) C33(-19.518,1.3) C36(-20.869,1.3) C37(-21.433,0.975) C38(-21.996,1.3) C40(-23.347,1.3) C41(-23.911,0.975) C42(-24.474,1.3) C45(-25.825,1.3) C46(-26.389,0.975) C47(-26.952,1.3) C50(-28.303,1.3) C51(-28.867,0.975) C52(-29.43,1.3) C54(-30.781,1.3) C55(-31.345,0.975) C56(-31.908,1.3) C59(-33.259,1.3) C60(-33.823,0.975) C61(-34.386,1.3) C63(-35.737,1.3) C64(-36.301,0.975) C65(-36.864,1.3) C67(-38.799,1.015) C68(-38.936,1.693) C70(-39.999,1.28) D3(-0.975,1.706) D4(-1.624,1.646) D5(-2.224,1.951) D6(-2.873,1.991) D7(-3.523,1.951) D8(-4.086,1.626) D9(-4.65,1.951) D10(-5.325,1.991) D11(-6.001,1.951) D12(-6.564,1.626) D13(-7.128,1.951) D14(-7.803,1.991) D15(-8.479,1.951) D16(-9.042,1.626) D17(-9.606,1.951) D18(-10.281,1.991) D19(-10.957,1.951) D20(-11.52,1.626) D21(-12.084,1.951) D22(-12.759,1.991) D23(-13.435,1.951) D24(-13.998,1.626) D25(-14.562,1.951) D26(-15.237,1.991) D27(-15.913,1.951) D28(-16.476,1.626) D29(-17.04,1.951) D30(-17.715,1.991) D31(-18.391,1.951) D32(-18.954,1.626) D33(-19.518,1.951) D34(-20.194,1.991) D36(-20.869,1.951) D37(-21.433,1.626) D38(-21.996,1.951) D39(-22.672,1.991) D40(-23.347,1.951) D41(-23.911,1.626) D42(-24.474,1.951) D44(-25.15,1.991) D45(-25.825,1.951) D46(-26.389,1.626) D47(-26.952,1.951) D48(-27.628,1.991) D50(-28.303,1.951) D51(-28.867,1.626) D52(-29.43,1.951) D53(-30.106,1.991) D54(-30.781,1.951) D55(-31.345,1.626) D56(-31.908,1.951) D58(-32.584,1.991) D59(-33.259,1.951) D60(-33.823,1.626) D61(-34.386,1.951) D62(-35.062,1.991) D63(-35.737,1.951) D64(-36.301,1.626) D65(-36.864,1.951) D66(-37.54,1.991) D67(-38.213,1.3) D68(-39.582,1.779) D69(-38.876,2.343) D71(-40.629,1.763) E1(0,2.274) E2(-0.65,2.274) E3(-1.3,2.274) E5(-2.66,2.723) E6(-3.575,2.723) E8(-4.489,2.723) E10(-5.403,2.723) E11(-6.318,2.723) E13(-7.232,2.723) E15(-8.147,2.723) E16(-9.061,2.723) E18(-9.975,2.723) E20(-10.89,2.723) E21(-11.804,2.723) E22(-12.719,2.723) E23(-13.633,2.723) E25(-14.547,2.723) E27(-15.462,2.723) E28(-16.376,2.723) E30(-17.291,2.723) E32(-18.205,2.723) E33(-19.119,2.723) E35(-20.034,2.723) E37(-20.948,2.723) E38(-21.863,2.723) E40(-22.777,2.723) E42(-23.691,2.723) E43(-24.606,2.723) E45(-25.52,2.723) E46(-26.435,2.723) E48(-27.349,2.723) E50(-28.263,2.723) E52(-29.178,2.723) E53(-30.092,2.723) E55(-31.007,2.723) E56(-31.921,2.723) E58(-32.835,2.723) E60(-33.75,2.723) E61(-34.664,2.723) E63(-35.629,2.659) E65(-36.645,2.659) E66(-37.661,2.659) E68(-38.213,1.951) F2(-0.975,2.848) F4(-1.951,2.848) F5(-2.66,3.373) F6(-3.575,3.373) F8(-4.489,3.373) F10(-5.403,3.373) F11(-6.318,3.373) F13(-7.232,3.373) F15(-8.147,3.373) F16(-9.061,3.373) F18(-9.975,3.373) F20(-10.89,3.373) F21(-11.804,3.373) F22(-12.719,3.373) F23(-13.633,3.373) F25(-14.547,3.373) F27(-15.462,3.373) F28(-16.376,3.373) F30(-17.291,3.373) F32(-18.205,3.373) F33(-19.119,3.373) F35(-20.034,3.373) F37(-20.948,3.373) F38(-21.863,3.373) F40(-22.777,3.373) F42(-23.691,3.373) F43(-24.606,3.373) F45(-25.52,3.373) F46(-26.435,3.373) F48(-27.349,3.373) F50(-28.263,3.373) F52(-29.178,3.373) F53(-30.092,3.373) F55(-31.007,3.373) F56(-31.921,3.373) F58(-32.835,3.373) F60(-33.75,3.373) F61(-34.664,3.373) F63(-35.629,3.31) F65(-36.645,3.31) F66(-37.661,3.31) F68(-38.876,2.994) G4(-1.951,3.511) G5(-2.66,4.023) G6(-3.575,4.023) G8(-4.489,4.023) G10(-5.403,4.023) G11(-6.318,4.023) G13(-7.232,4.023) G15(-8.147,4.023) G16(-9.061,4.023) G18(-9.975,4.023) G20(-10.89,4.023) G21(-11.804,4.023) G22(-12.719,4.023) G23(-13.633,4.023) G25(-14.547,4.023) G27(-15.462,4.023) G28(-16.376,4.023) G30(-17.291,4.023) G32(-18.205,4.023) G33(-19.119,4.023) G35(-20.034,4.023) G37(-20.948,4.023) G38(-21.863,4.023) G40(-22.777,4.023) G42(-23.691,4.023) G43(-24.606,4.023) G45(-25.52,4.023) G46(-26.435,4.023) G48(-27.349,4.023) G50(-28.263,4.023) G52(-29.178,4.023) G53(-30.092,4.023) G55(-31.007,4.023) G56(-31.921,4.023) G58(-32.835,4.023) G60(-33.75,4.023) G61(-34.664,4.023) G63(-35.629,3.96) G65(-36.645,3.96) G66(-37.661,3.96) G68(-38.678,3.655) G69(-39.328,3.655) H3(-1.626,4.174) H5(-2.66,4.674) H6(-3.575,4.674) H8(-4.489,4.674) H10(-5.403,4.674) H11(-6.318,4.674) H13(-7.232,4.674) H15(-8.147,4.674) H16(-9.061,4.674) H18(-9.975,4.674) H20(-10.89,4.674) H21(-11.804,4.674) H63(-35.629,4.61) H65(-36.645,4.61) H66(-37.661,4.61) H69(-39.003,4.218) J4(-1.951,4.837) J5(-2.66,5.324) J6(-3.575,5.324) J8(-4.489,5.324) J10(-5.403,5.324) J11(-6.318,5.324) J13(-7.232,5.324) J22(-13.176,4.488) J23(-14.09,4.488) J25(-15.005,4.488) J27(-15.919,4.488) J28(-16.833,4.488) J30(-17.748,4.488) J32(-18.662,4.488) J33(-19.577,4.488) J35(-20.491,4.488) J37(-21.405,4.488) J38(-22.32,4.488) J40(-23.234,4.488) J42(-24.149,4.488) J43(-25.063,4.488) J45(-25.977,4.488) J46(-26.892,4.488) J48(-27.806,4.488) J50(-28.721,4.488) J52(-29.635,4.488) J53(-30.549,4.488) J55(-31.464,4.488) J56(-32.378,4.488) J58(-33.293,4.488) J60(-34.207,4.488) J68(-38.676,4.794) K15(-8.126,5.438) K16(-8.776,5.438) K17(-9.426,5.438) K18(-10.077,5.438) K19(-10.727,5.438) K20(-11.377,5.438) K21(-12.027,5.438) K22(-12.719,4.952) K23(-13.633,4.952) K25(-14.547,4.952) K27(-15.462,4.952) K28(-16.376,4.952) K30(-17.291,4.952) K32(-18.205,4.952) K33(-19.119,4.952) K35(-20.034,4.952) K37(-20.948,4.952) K38(-21.863,4.952) K40(-22.777,4.952) K42(-23.691,4.952) K43(-24.606,4.952) K45(-25.52,4.952) K46(-26.435,4.952) K48(-27.349,4.952) K50(-28.263,4.952) K52(-29.178,4.952) K53(-30.092,4.952) K55(-31.007,4.952) K56(-31.921,4.952) K58(-32.835,4.952) K60(-33.75,4.952) K61(-34.664,4.952) K63(-35.447,5.26) K64(-36.097,5.26) K65(-36.747,5.26) K66(-37.398,5.26) K67(-38.048,5.26) K68(-38.666,5.468) K70(-39.653,5.57) L2(-0.975,5.5) L4(-1.951,5.5) L6(-2.729,5.974) L7(-3.379,5.974) L8(-4.029,5.974) L9(-4.679,5.974) L10(-5.33,5.974) L11(-5.98,5.974) L12(-6.63,5.974) L13(-7.28,5.974) L15(-8.126,6.276) L16(-8.776,6.276) L17(-9.426,6.276) L18(-10.077,6.276) L19(-10.727,6.276) L20(-11.377,6.276) L21(-12.027,6.276) L62(-34.958,5.689) L63(-35.427,6.147) L64(-36.077,6.147) L65(-36.727,6.147) L66(-37.377,6.147) L67(-38.028,6.147) L68(-38.678,6.147) L69(-39.328,6.147) L70(-39.978,6.147) L71(-40.629,6.147) M4(-1.951,6.163) M62(-34.958,6.604) N3(-1.626,6.826) N6(-2.729,6.914) N7(-3.379,6.914) N8(-4.029,6.914) N9(-4.679,6.914) N10(-5.33,6.914) N11(-5.98,6.914) N12(-6.63,6.914) N13(-7.28,6.914) N15(-8.126,7.114) N16(-8.776,7.114) N17(-9.426,7.114) N18(-10.077,7.114) N19(-10.727,7.114) N20(-11.377,7.114) N21(-12.027,7.114) N63(-35.427,7.061) N64(-36.077,7.061) N65(-36.727,7.061) N66(-37.377,7.061) N67(-38.028,7.061) N68(-38.678,7.061) N69(-39.328,7.061) N70(-39.978,7.061) N71(-40.629,7.061) P4(-1.951,7.489) P15(-8.126,7.952) P16(-8.776,7.952) P17(-9.426,7.952) P18(-10.077,7.952) P19(-10.727,7.952) P20(-11.377,7.952) P21(-12.027,7.952) P62(-34.958,7.518) R6(-2.729,7.981) R7(-3.379,7.981) R8(-4.029,7.981) R9(-4.679,7.981) R10(-5.33,7.981) R11(-5.98,7.981) R12(-6.63,7.981) R13(-7.28,7.981) R63(-35.427,7.975) R64(-36.077,7.975) R65(-36.727,7.975) R66(-37.377,7.975) R67(-38.028,7.975) R68(-38.678,7.975) R69(-39.328,7.975) R70(-39.978,7.975) R71(-40.629,7.975) T2(-0.975,8.152) T4(-1.951,8.152) T15(-8.126,8.791) T16(-8.776,8.791) T17(-9.426,8.791) T18(-10.077,8.791) T19(-10.727,8.791) T20(-11.377,8.791) T21(-12.027,8.791) T62(-34.958,8.433) U4(-1.951,8.815) U6(-2.729,9.047) U7(-3.379,9.047) U8(-4.029,9.047) U9(-4.679,9.047) U10(-5.33,9.047) U11(-5.98,9.047) U12(-6.63,9.047) U13(-7.28,9.047) U63(-35.427,8.89) U64(-36.077,8.89) U65(-36.727,8.89) U66(-37.377,8.89) U67(-38.028,8.89) U68(-38.678,8.89) U69(-39.328,8.89) U70(-39.978,8.89) U71(-40.629,8.89) V3(-1.626,9.478) V15(-8.126,9.629) V16(-8.776,9.629) V17(-9.426,9.629) V18(-10.077,9.629) V19(-10.727,9.629) V20(-11.377,9.629) V21(-12.027,9.629) V62(-34.958,9.347) W4(-1.951,10.141) W6(-2.729,10.114) W7(-3.379,10.114) W8(-4.029,10.114) W9(-4.679,10.114) W10(-5.33,10.114) W11(-5.98,10.114) W12(-6.63,10.114) W13(-7.28,10.114) W63(-35.427,9.804) W64(-36.077,9.804) W65(-36.727,9.804) W66(-37.377,9.804) W67(-38.028,9.804) W68(-38.678,9.804) W69(-39.328,9.804) W70(-39.978,9.804) W71(-40.629,9.804) Y15(-8.126,10.467) Y16(-8.776,10.467) Y17(-9.426,10.467) Y18(-10.077,10.467) Y19(-10.727,10.467) Y20(-11.377,10.467) Y21(-12.027,10.467) Y62(-34.958,10.261)
  oval 0.254x0.343 smd: A6(-2.847,0.325) A7(-3.523,0) A9(-4.65,0) A10(-5.325,0.325) A11(-6.001,0) A13(-7.128,0) A14(-7.803,0.325) A15(-8.479,0) A17(-9.606,0) A18(-10.281,0.325) A19(-10.957,0) A21(-12.084,0) A22(-12.759,0.325) A23(-13.435,0) A25(-14.562,0) A26(-15.237,0.325) A27(-15.913,0) A29(-17.04,0) A30(-17.715,0.325) A31(-18.391,0) A33(-19.518,0) A34(-20.194,0.325) A36(-20.869,0) A38(-21.996,0) A39(-22.672,0.325) A40(-23.347,0) A42(-24.474,0) A44(-25.15,0.325) A45(-25.825,0) A47(-26.952,0) A48(-27.628,0.325) A50(-28.303,0) A52(-29.43,0) A53(-30.106,0.325) A54(-30.781,0) A56(-31.908,0) A58(-32.584,0.325) A59(-33.259,0) A61(-34.386,0) A62(-35.062,0.325) A63(-35.737,0) A65(-36.864,0) A66(-37.54,0.325) A67(-38.215,0) AY7(-3.763,21.328) AY9(-4.898,21.328) AY11(-6.184,21.328) AY13(-7.319,21.328) AY15(-8.604,21.328) AY17(-9.74,21.328) AY20(-11.025,21.328) AY22(-12.16,21.328) AY25(-13.486,21.328) AY31(-17.167,21.328) AY33(-18.467,21.328) AY39(-22.148,21.328) AY42(-23.423,21.328) AY48(-27.103,21.328) AY50(-28.236,21.328) AY56(-31.916,21.328) AY59(-33.191,21.328) AY65(-36.872,21.328) AY67(-38.216,21.328) B7(-3.523,0.65) B9(-4.65,0.65) B11(-6.001,0.65) B13(-7.128,0.65) B15(-8.479,0.65) B17(-9.606,0.65) B19(-10.957,0.65) B21(-12.084,0.65) B23(-13.435,0.65) B25(-14.562,0.65) B27(-15.913,0.65) B29(-17.04,0.65) B31(-18.391,0.65) B33(-19.518,0.65) B36(-20.869,0.65) B38(-21.996,0.65) B40(-23.347,0.65) B42(-24.474,0.65) B45(-25.825,0.65) B47(-26.952,0.65) B50(-28.303,0.65) B52(-29.43,0.65) B54(-30.781,0.65) B56(-31.908,0.65) B59(-33.259,0.65) B61(-34.386,0.65) B63(-35.737,0.65) B65(-36.864,0.65) B67(-38.215,0.65) BA4(-1.948,22.004) BA6(-3.141,21.572) BA7(-3.705,21.978) BA9(-4.898,21.978) BA10(-5.561,21.572) BA11(-6.125,21.978) BA13(-7.319,21.978) BA14(-7.982,21.572) BA15(-8.546,21.978) BA17(-9.74,21.978) BA18(-10.403,21.572) BA20(-10.966,21.978) BA22(-12.16,21.978) BA25(-13.486,21.978) BA26(-14.149,21.653) BA27(-14.812,21.978) BA29(-15.841,21.978) BA30(-16.504,21.653) BA31(-17.167,21.978) BA33(-18.467,21.978) BA34(-19.13,21.653) BA35(-19.793,21.978) BA37(-20.822,21.978) BA38(-21.485,21.653) BA39(-22.148,21.978) BA42(-23.423,21.978) BA43(-24.086,21.653) BA44(-24.748,21.978) BA46(-25.777,21.978) BA47(-26.44,21.653) BA48(-27.103,21.978) BA50(-28.236,21.978) BA51(-28.899,21.653) BA52(-29.562,21.978) BA54(-30.59,21.978) BA55(-31.253,21.653) BA56(-31.916,21.978) BA59(-33.191,21.978) BA60(-33.854,21.653) BA61(-34.517,21.978) BA63(-35.546,21.978) BA64(-36.209,21.653) BA65(-36.872,21.978) BA66(-37.535,21.653) BA67(-38.216,21.978) BB5(-2.529,22.628) BB6(-3.141,22.303) BB7(-3.705,22.628) BB9(-4.898,22.628) BB10(-5.561,22.303) BB11(-6.125,22.628) BB13(-7.319,22.628) BB14(-7.982,22.303) BB15(-8.546,22.628) BB17(-9.74,22.628) BB18(-10.403,22.303) BB20(-10.966,22.628) BB22(-12.16,22.628) BB23(-12.849,22.222) BB25(-13.486,22.628) BB26(-14.149,22.303) BB27(-14.812,22.628) BB29(-15.841,22.628) BB30(-16.504,22.303) BB31(-17.167,22.628) BB32(-17.83,22.222) BB33(-18.467,22.628) BB34(-19.13,22.303) BB35(-19.793,22.628) BB37(-20.822,22.628) BB38(-21.485,22.303) BB39(-22.148,22.628) BB41(-22.785,22.222) BB42(-23.423,22.628) BB43(-24.086,22.303) BB44(-24.748,22.628) BB46(-25.777,22.628) BB47(-26.44,22.303) BB48(-27.103,22.628) BB50(-28.236,22.628) BB51(-28.899,22.303) BB52(-29.562,22.628) BB54(-30.59,22.628) BB55(-31.253,22.303) BB56(-31.916,22.628) BB57(-32.554,22.222) BB59(-33.191,22.628) BB60(-33.854,22.303) BB61(-34.517,22.628) BB63(-35.546,22.628) BB64(-36.209,22.303) BB65(-36.872,22.628) BB66(-37.535,22.303) BB67(-38.216,22.628)
  oval 0.343x0.254 smd: AA1(-0.325,10.804) AB1(0,11.467) AB2(-0.65,11.467) AB3(-1.3,11.467) AC1(-0.325,12.13) AC2(-0.975,12.13) AD1(0,12.792) AD2(-0.65,12.792) AD3(-1.3,12.792) AF1(-0.325,13.455) AF70(-39.978,13.154) AF71(-40.629,13.154) AG1(0,14.118) AG2(-0.65,14.118) AG3(-1.3,14.118) AG70(-39.653,13.817) AG71(-40.303,13.817) AH1(-0.325,14.781) AH2(-0.975,14.781) AH68(-38.678,14.48) AH69(-39.328,14.48) AH70(-39.978,14.48) AH71(-40.629,14.48) AJ1(0,15.444) AJ2(-0.65,15.444) AJ3(-1.3,15.444) AK70(-40.303,15.143) AL1(-0.325,16.107) AL68(-38.678,15.806) AL69(-39.328,15.806) AL70(-39.978,15.806) AL71(-40.629,15.806) AM1(0,16.77) AM2(-0.65,16.77) AM3(-1.3,16.77) AM70(-39.653,16.469) AM71(-40.303,16.469) AN1(-0.325,17.433) AN2(-0.975,17.433) AN70(-39.978,17.132) AN71(-40.629,17.132) AP1(0,18.096) AP2(-0.65,18.096) AP3(-1.3,18.096) AR70(-39.978,18.16) AR71(-40.629,18.16) AT1(-0.325,18.759) AT70(-39.653,18.823) AT71(-40.303,18.823) AU1(0,19.422) AU2(-0.65,19.422) AU3(-1.3,19.422) AU68(-38.678,19.461) AU69(-39.328,19.486) AU70(-39.978,19.486) AU71(-40.629,19.486) AV1(0,20.142) AV2(-0.95,20.113) AV71(-40.629,20.215) AW2(-0.625,20.677) AW3(-1.275,20.677) E70(-39.978,2.305) E71(-40.629,2.413) F1(-0.325,2.848) F70(-39.526,2.994) F71(-40.176,2.931) G1(0,3.511) G2(-0.65,3.511) G3(-1.3,3.511) G70(-39.978,3.555) G71(-40.629,3.555) H1(-0.325,4.174) H2(-0.975,4.174) H70(-39.653,4.218) H71(-40.303,4.218) J1(0,4.837) J2(-0.65,4.837) J3(-1.3,4.837) J69(-39.328,4.881) J70(-39.978,4.881) J71(-40.629,4.881) K71(-40.303,5.57) L1(-0.325,5.5) M1(0,6.163) M2(-0.65,6.163) M3(-1.3,6.163) N1(-0.325,6.826) N2(-0.975,6.826) P1(0,7.489) P2(-0.65,7.489) P3(-1.3,7.489) T1(-0.325,8.152) U1(0,8.815) U2(-0.65,8.815) U3(-1.3,8.815) V1(-0.325,9.478) V2(-0.975,9.478) W1(0,10.141) W2(-0.65,10.141) W3(-1.3,10.141)
SLB9670VQ2P0_VQFN32_5X5
  oval 0.356x0.813 smd: 1(0,0) 2(0.5,0) 3(1,0) 4(1.5,0) 5(2,0) 6(2.5,0) 7(3,0) 8(3.5,0) 17(3.5,4.8) 18(3,4.8) 19(2.5,4.8) 20(2,4.8) 21(1.5,4.8) 22(1,4.8) 23(0.5,4.8) 24(0,4.8)
  oval 0.813x0.356 smd: 9(4.15,0.65) 10(4.15,1.15) 11(4.15,1.65) 12(4.15,2.15) 13(4.15,2.65) 14(4.15,3.15) 15(4.15,3.65) 16(4.15,4.15) 25(-0.65,4.15) 26(-0.65,3.65) 27(-0.65,3.15) 28(-0.65,2.65) 29(-0.65,2.15) 30(-0.65,1.65) 31(-0.65,1.15) 32(-0.65,0.65)
  rect 3.607x3.607 smd: 33(1.75,2.4)
SLG59M1470VTR_FC-TDFN9_1P5X2
  rect 0.787x0.203 smd: 1(0,0) 2(0,-0.4) 5(1.5,-0.4) 6(1.5,0)
  rect 0.991x0.61 smd: 3(0.1,-1) 4(1.4,-1)
  rect 0.203x0.787 smd: 7(0.75,0.4)
SSM6J402TU_UF6
  oval 0.457x0.787 smd: 1(0,0) 2(0.65,0) 3(1.3,0) 4(1.3,1.9) 5(0.65,1.9) 6(0,1.9)
SSM6K210FE_2-2N1A
  oval 0.305x0.457 smd: 1(0,0) 2(0.5,0) 3(1,0) 4(1,1.35) 5(0.5,1.35) 6(0,1.35)
SW_SKRPABE010_4P
  rect 1.041x0.66 smd: 1(0,0) 2(4.15,0) 3(0,-2.15) 4(4.15,-2.15)
SW_SPVR310100_4P
  round 0.711 hole 0.711 unplated: (-1.8,-1.85) (0.2,-1.85)
  rect 0.787x0.787 smd: 1(0,0) 2(-2.2,0) 3(-2.2,-3.7) 4(0,-3.7)
SW_SPVT210101_4P
  oval 1.092x1.295 hole 1.092x1.295 unplated: (3.65,-1.3)
  round 1.092 hole 1.092 unplated: (3.65,1.2)
  rect 1.702x1.6 smd: 1(0,0) 4(7.3,0)
  rect 2.21x2.489 smd: 2(1.7,-3.55) 3(5.6,-3.55)
TC7SB385FU_SSOP5
  oval 0.381x1.321 smd: 1(0,0) 2(0.65,0) 3(1.3,0) 4(1.3,1.8) 5(0,1.8)
TC7SG17FE_SON5
  oval 0.305x0.457 smd: 1(0,0) 2(0.5,0) 3(1,0) 4(1,1.35) 5(0,1.35)
TC7SPB9306TU_UF6
  oval 0.457x0.787 smd: 1(0,0) 2(0.65,0) 3(1.3,0) 4(1.3,1.9) 5(0.65,1.9) 6(0,1.9)
TDK_FLF3215T-4R7M_2P
  rect 1.194x2.007 smd: 1(0,0) 2(3.2,0)
TDK_MMZ1005Y152CT_2P
  rect 0.508x0.508 smd: 1(0,0) 2(0.9,0)
TDK_MPZ1608S300AT_2P
  rect 0.61x0.787 smd: 1(0,0) 2(1.4,0)
TE_2-2199119-2_75P-T
  round 1.092 hole 1.092 unplated: (-0.75,-5.275)
  round 1.6 hole 1.6 unplated: (19.25,-5.275)
  oval 0.406x1.651 smd: 1(0,0) 2(0.25,-7.55) 3(0.5,0) 4(0.75,-7.55) 5(1,0) 6(1.25,-7.55) 7(1.5,0) 8(1.75,-7.55) 9(2,0) 10(2.25,-7.55) 11(2.5,0) 20(4.75,-7.55) 21(5,0) 22(5.25,-7.55) 23(5.5,0) 24(5.75,-7.55) 25(6,0) 26(6.25,-7.55) 27(6.5,0) 28(6.75,-7.55) 29(7,0) 30(7.25,-7.55) 31(7.5,0) 32(7.75,-7.55) 33(8,0) 34(8.25,-7.55) 35(8.5,0) 36(8.75,-7.55) 37(9,0) 38(9.25,-7.55) 39(9.5,0) 40(9.75,-7.55) 41(10,0) 42(10.25,-7.55) 43(10.5,0) 44(10.75,-7.55) 45(11,0) 46(11.25,-7.55) 47(11.5,0) 48(11.75,-7.55) 49(12,0) 50(12.25,-7.55) 51(12.5,0) 52(12.75,-7.55) 53(13,0) 54(13.25,-7.55) 55(13.5,0) 56(13.75,-7.55) 57(14,0) 58(14.25,-7.55) 59(14.5,0) 60(14.75,-7.55) 61(15,0) 62(15.25,-7.55) 63(15.5,0) 64(15.75,-7.55) 65(16,0) 66(16.25,-7.55) 67(16.5,0) 68(16.75,-7.55) 69(17,0) 70(17.25,-7.55) 71(17.5,0) 72(17.75,-7.55) 73(18,0) 74(18.25,-7.55) 75(18.5,0)
  rect 1.194x2.743 smd: 76(-1.1,-0.775) 77(19.6,-0.775)
TE_2-2199119-3_75P-T
  round 1.092 hole 1.092 unplated: (-0.75,-5.275)
  round 1.6 hole 1.6 unplated: (19.25,-5.275)
  oval 0.406x1.651 smd: 1(0,0) 2(0.25,-7.55) 3(0.5,0) 4(0.75,-7.55) 5(1,0) 6(1.25,-7.55) 7(1.5,0) 16(3.75,-7.55) 17(4,0) 18(4.25,-7.55) 19(4.5,0) 20(4.75,-7.55) 21(5,0) 22(5.25,-7.55) 23(5.5,0) 24(5.75,-7.55) 25(6,0) 26(6.25,-7.55) 27(6.5,0) 28(6.75,-7.55) 29(7,0) 30(7.25,-7.55) 31(7.5,0) 32(7.75,-7.55) 33(8,0) 34(8.25,-7.55) 35(8.5,0) 36(8.75,-7.55) 37(9,0) 38(9.25,-7.55) 39(9.5,0) 40(9.75,-7.55) 41(10,0) 42(10.25,-7.55) 43(10.5,0) 44(10.75,-7.55) 45(11,0) 46(11.25,-7.55) 47(11.5,0) 48(11.75,-7.55) 49(12,0) 50(12.25,-7.55) 51(12.5,0) 52(12.75,-7.55) 53(13,0) 54(13.25,-7.55) 55(13.5,0) 56(13.75,-7.55) 57(14,0) 58(14.25,-7.55) 59(14.5,0) 60(14.75,-7.55) 61(15,0) 62(15.25,-7.55) 63(15.5,0) 64(15.75,-7.55) 65(16,0) 66(16.25,-7.55) 67(16.5,0) 68(16.75,-7.55) 69(17,0) 70(17.25,-7.55) 71(17.5,0) 72(17.75,-7.55) 73(18,0) 74(18.25,-7.55) 75(18.5,0)
  rect 1.194x2.743 smd: 76(-1.1,-0.775) 77(19.6,-0.775)
TE_2041180-2_2P-T
  oval 0.787x1.6 smd: 1(0,0) 2(-1.25,0)
  rect 2.108x2.997 smd: 3(2.55,2.9) 4(-3.8,2.9)
TE_2129525-2_70P
  round 1.194 hole 1.194 unplated: (-6.525,-0.65)
  oval 1.6x1.194 hole 1.6x1.194 unplated: (25.225,-0.65)
  oval 0.381x1.6 smd: 1(0,0) 2(0.55,0) 3(1.1,0) 4(1.65,0) 5(2.2,0) 6(2.75,0) 7(3.3,0) 8(3.85,0) 9(4.4,0) 10(4.95,0) 11(5.5,0) 12(6.05,0) 13(6.6,0) 14(7.15,0) 15(7.7,0) 16(8.25,0) 17(8.8,0) 18(9.35,0) 19(9.9,0) 20(10.45,0) 21(11,0) 22(11.55,0) 23(12.1,0) 24(12.65,0) 25(13.2,0) 26(13.75,0) 27(14.3,0) 28(14.85,0) 29(15.4,0) 30(15.95,0) 31(16.5,0) 32(17.05,0) 33(17.6,0) 34(18.15,0) 35(18.7,0) 36(18.7,-11.1) 37(18.15,-11.1) 38(17.6,-11.1) 39(17.05,-11.1) 40(16.5,-11.1) 41(15.95,-11.1) 42(15.4,-11.1) 43(14.85,-11.1) 44(14.3,-11.1) 45(13.75,-11.1) 46(13.2,-11.1) 47(12.65,-11.1) 48(12.1,-11.1) 49(11.55,-11.1) 50(11,-11.1) 51(10.45,-11.1) 52(9.9,-11.1) 53(9.35,-11.1) 54(8.8,-11.1) 55(8.25,-11.1) 56(7.7,-11.1) 57(7.15,-11.1) 58(6.6,-11.1) 59(6.05,-11.1) 60(5.5,-11.1) 61(4.95,-11.1) 62(4.4,-11.1) 63(3.85,-11.1) 64(3.3,-11.1) 65(2.75,-11.1) 66(2.2,-11.1) 67(1.65,-11.1) 68(1.1,-11.1) 69(0.55,-11.1) 70(0,-11.1)
  oval 1.397x4.597 hole 0.787x3.988: 71(25.225,-5.55) 72(-6.525,-5.55)
  oval 3.404x1.397 hole 2.794x0.787: 73(21.225,-0.15) 76(21.225,-10.95) 77(-2.525,-10.95) 80(-2.525,-0.15)
  oval 1.397x2.591 hole 0.787x2.007: 74(27.175,-2.9) 75(27.175,-8.2) 78(-8.475,-8.2) 79(-8.475,-2.9)
  oval 2.108x1.397 hole 1.499x0.787: 81(15.15,-5.55) 82(3.55,-5.55)
TPC12
  round 0.305 smd: 1(0,0)
TPC16
  round 0.406 smd: 1(0,0)
TPC32
  round 0.813 smd: 1(0,0)
TPC40
  round 1.016 smd: 1(0,0)
TPCA8059-H_PPAK56-8-5
  oval 0.61x1.27 smd: 1(0,0) 2(1.27,0) 3(2.54,0) 4(3.81,0)
  custom 1.105x1.105 smd: 5(1.905,3.715)
TPCF8002_2-3U1A
  oval 0.406x0.66 smd: 1(0,0) 2(0.65,0) 3(1.3,0) 4(1.95,0) 5(1.95,1.5) 6(1.3,1.5) 7(0.65,1.5) 8(0,1.5)
TPCF8004_2-3U1S
  oval 0.406x0.66 smd: 1(0,0) 2(0.65,0) 3(1.3,0) 4(1.95,0) 5(1.95,1.5) 6(1.3,1.5) 7(0.65,1.5) 8(0,1.5)
TPD8S300_QFN20_3X3
  oval 0.711x0.305 smd: 1(0,0) 2(0,-0.4) 3(0,-0.8) 4(0,-1.2) 5(0,-1.6) 11(2.8,-1.6) 12(2.8,-1.2) 13(2.8,-0.8) 14(2.8,-0.4) 15(2.8,0)
  oval 0.305x0.711 smd: 6(0.6,-2.2) 7(1,-2.2) 8(1.4,-2.2) 9(1.8,-2.2) 10(2.2,-2.2) 16(2.2,0.6) 17(1.8,0.6) 18(1.4,0.6) 19(1,0.6) 20(0.6,0.6)
  rect 1.702x1.702 smd: 21(1.4,-0.8)
TPS2069DGNR_MSOP8
  oval 0.381x1.575 smd: 1(0,0) 2(0.65,0) 3(1.3,0) 4(1.95,0) 5(1.95,4.35) 6(1.3,4.35) 7(0.65,4.35) 8(0,4.35)
  rect 1.753x1.422 smd: 9(0.975,2.175)
TPS2546RTER_QFN16_4X4
  oval 0.254x0.889 smd: 1(0,0) 2(0.5,0) 3(1,0) 4(1.5,0) 9(1.5,3.1) 10(1,3.1) 11(0.5,3.1) 12(0,3.1)
  oval 0.889x0.254 smd: 5(2.3,0.8) 6(2.3,1.3) 7(2.3,1.8) 8(2.3,2.3) 13(-0.8,2.3) 14(-0.8,1.8) 15(-0.8,1.3) 16(-0.8,0.8)
  rect 1.702x1.702 smd: 17(0.75,1.55)
TPS2553DBVR_SOT23-6
  rect 0.61x1.041 smd: 1(0,0) 2(0.95,0) 3(1.9,0) 4(1.9,2.7) 5(0.95,2.7) 6(0,2.7)
TPS22918DBVR_SOT23-6
  oval 0.61x1.041 smd: 1(0,0) 2(0.95,0) 3(1.9,0) 4(1.9,2.7) 5(0.95,2.7) 6(0,2.7)
TPS51285BRUKR_WQFN20_3X3
  oval 0.889x0.305 smd: 1(0,0) 2(0,-0.4) 3(0,-0.8) 4(0,-1.2) 5(0,-1.6) 11(3,-1.6) 12(3,-1.2) 13(3,-0.8) 14(3,-0.4) 15(3,0)
  oval 0.305x0.889 smd: 6(0.7,-2.3) 7(1.1,-2.3) 8(1.5,-2.3) 9(1.9,-2.3) 10(2.3,-2.3) 16(2.3,0.7) 17(1.9,0.7) 18(1.5,0.7) 19(1.1,0.7) 20(0.7,0.7)
  rect 1.803x1.803 smd: 21(1.5,-0.8)
TPS51367RVER_QFN28_3P5X4P5
  oval 0.305x0.889 smd: 1(0,0) 2(0.4,0) 3(0.8,0) 4(1.2,0) 5(1.6,0) 6(2,0) 7(2.4,0) 8(2.8,0) 9(3.2,0) 15(3.2,3.17) 16(2.8,3.17) 17(2.4,3.17) 18(2,3.17) 19(1.6,3.17) 20(1.2,3.17) 21(0.8,3.17) 22(0.4,3.17) 23(0,3.17)
  oval 0.889x0.305 smd: 10(3.685,0.785) 11(3.685,1.185) 12(3.685,1.585) 13(3.685,1.985) 14(3.685,2.385) 24(-0.485,2.385) 25(-0.485,1.985) 26(-0.485,1.585) 27(-0.485,1.185) 28(-0.485,0.785)
  rect 3.099x2.108 smd: 29(1.6,1.585)
TPS51716RUKR_WQFN20_3X3
  oval 0.305x0.889 smd: 1(0,0) 2(0.4,0) 3(0.8,0) 4(1.2,0) 5(1.6,0) 11(1.6,3) 12(1.2,3) 13(0.8,3) 14(0.4,3) 15(0,3)
  oval 0.889x0.305 smd: 6(2.3,0.7) 7(2.3,1.1) 8(2.3,1.5) 9(2.3,1.9) 10(2.3,2.3) 16(-0.7,2.3) 17(-0.7,1.9) 18(-0.7,1.5) 19(-0.7,1.1) 20(-0.7,0.7)
  rect 1.702x1.702 smd: 21(0.8,1.5)
TPS61041DRVR_SON6_2X2
  oval 0.305x0.711 smd: 1(0,0) 2(-0.65,0) 3(-1.3,0) 4(-1.3,-2.1) 5(-0.65,-2.1) 6(0,-2.1)
  rect 1.6x0.991 smd: 7(-0.65,-1.05)
TPS65982DAZQZR_BGA_96P
  round 0.254 smd: A1(0,0) A2(0.5,0) A3(1,0) A4(1.5,0) A5(2,0) A6(2.5,0) A7(3,0) A8(3.5,0) A9(4,0) A10(4.5,0) A11(5,0) B1(0,-0.5) B2(0.5,-0.5) B3(1,-0.5) B4(1.5,-0.5) B5(2,-0.5) B6(2.5,-0.5) B7(3,-0.5) B8(3.5,-0.5) B9(4,-0.5) B10(4.5,-0.5) B11(5,-0.5) C1(0,-1) C2(0.5,-1) C10(4.5,-1) C11(5,-1) D1(0,-1.5) D2(0.5,-1.5) D5(2,-1.5) D6(2.5,-1.5) D7(3,-1.5) D8(3.5,-1.5) D10(4.5,-1.5) D11(5,-1.5) E1(0,-2) E2(0.5,-2) E4(1.5,-2) E5(2,-2) E6(2.5,-2) E7(3,-2) E8(3.5,-2) E10(4.5,-2) E11(5,-2) F1(0,-2.5) F2(0.5,-2.5) F4(1.5,-2.5) F5(2,-2.5) F6(2.5,-2.5) F7(3,-2.5) F8(3.5,-2.5) F10(4.5,-2.5) F11(5,-2.5) G1(0,-3) G2(0.5,-3) G4(1.5,-3) G5(2,-3) G6(2.5,-3) G7(3,-3) G8(3.5,-3) G10(4.5,-3) G11(5,-3) H1(0,-3.5) H2(0.5,-3.5) H4(1.5,-3.5) H5(2,-3.5) H6(2.5,-3.5) H7(3,-3.5) H8(3.5,-3.5) H10(4.5,-3.5) H11(5,-3.5) J1(0,-4) J2(0.5,-4) J10(4.5,-4) J11(5,-4) K1(0,-4.5) K2(0.5,-4.5) K3(1,-4.5) K4(1.5,-4.5) K5(2,-4.5) K6(2.5,-4.5) K7(3,-4.5) K8(3.5,-4.5) K9(4,-4.5) K10(4.5,-4.5) K11(5,-4.5) L1(0,-5) L2(0.5,-5) L3(1,-5) L4(1.5,-5) L5(2,-5) L6(2.5,-5) L7(3,-5) L8(3.5,-5) L9(4,-5) L10(4.5,-5) L11(5,-5)
TYCO_2041180-4_4P-T
  oval 0.787x1.6 smd: 1(0,0) 2(-1.25,0) 3(-2.5,0) 4(-3.75,0)
  rect 2.108x2.997 smd: 5(2.55,2.9) 6(-6.3,2.9)
W25Q80BLSNIG_SO8
  oval 0.635x1.854 smd: 1(0,0) 2(1.27,0) 3(2.54,0) 4(3.81,0) 5(3.81,5.165) 6(2.54,5.165) 7(1.27,5.165) 8(0,5.165)
W25Q128FVSIQ_SO8
  oval 0.635x1.676 smd: 1(0,0) 2(1.27,0) 3(2.54,0) 4(3.81,0) 5(3.81,7.25) 6(2.54,7.25) 7(1.27,7.25) 8(0,7.25)
WGI219LM-QREF-A0_QFN48_6X6
  oval 0.305x1.092 smd: 1(0,0) 2(0.4,0) 3(0.8,0) 4(1.2,0) 5(1.6,0) 6(2,0) 7(2.4,0) 8(2.8,0) 9(3.2,0) 10(3.6,0) 11(4,0) 12(4.4,0) 25(4.4,6) 26(4,6) 27(3.6,6) 28(3.2,6) 29(2.8,6) 30(2.4,6) 31(2,6) 32(1.6,6) 33(1.2,6) 34(0.8,6) 35(0.4,6) 36(0,6)
  oval 1.092x0.305 smd: 13(5.2,0.8) 14(5.2,1.2) 15(5.2,1.6) 16(5.2,2) 17(5.2,2.4) 18(5.2,2.8) 19(5.2,3.2) 20(5.2,3.6) 21(5.2,4) 22(5.2,4.4) 23(5.2,4.8) 24(5.2,5.2) 37(-0.8,5.2) 38(-0.8,4.8) 39(-0.8,4.4) 40(-0.8,4) 41(-0.8,3.6) 42(-0.8,3.2) 43(-0.8,2.8) 44(-0.8,2.4) 45(-0.8,2) 46(-0.8,1.6) 47(-0.8,1.2) 48(-0.8,0.8)
  rect 2.997x2.997 smd: 49(2.2,3)
Y_8Y24000011_4P
  rect 0.889x0.787 smd: 1(0,0) 2(1.4,0) 3(1.4,1.1) 4(0,1.1)
Y_8Y25000004_4P
  rect 0.889x0.787 smd: 1(0,0) 2(1.4,0) 3(1.4,1.1) 4(0,1.1)
Y_9H03200042_2P
  rect 0.991x1.803 smd: 1(0,0) 2(2.5,0)

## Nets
1.2V_B+: PC308.1 PC309.1 PC310.1 PC319.1 PC320.1 PC321.1 PJ301.2 PQ301.5(D)
1.2V_GND: PC305.2 PC306.2 PC307.2 PR303.1 PR304.2 PR308.2 PR312.1 PU301.7(GND)
3V_VIN: PC206.1 PC207.1 PC208.1 PC209.1 PC221.1 PC229.2 PJ202.2 PQ202.5(D)
5V_VIN: PC203.1 PC204.1 PC205.1 PC219.1 PC226.1 PC228.2 PJ201.1 PQ201.5(D)
+3V_MUX: C8337.1 C8338.1 C8339.1 C8340.1 C8341.1 R679.1 R681.2 R682.2 R9083.2 R9084.1 R9087.2 R9090.2 R9091.1 R9093.1 R9096.1 R9100.1 R9106.1 R9112.1 R9116.1 U183.6(VDD33_1) U183.20(VDD33_2) U183.28(VDD33_3)
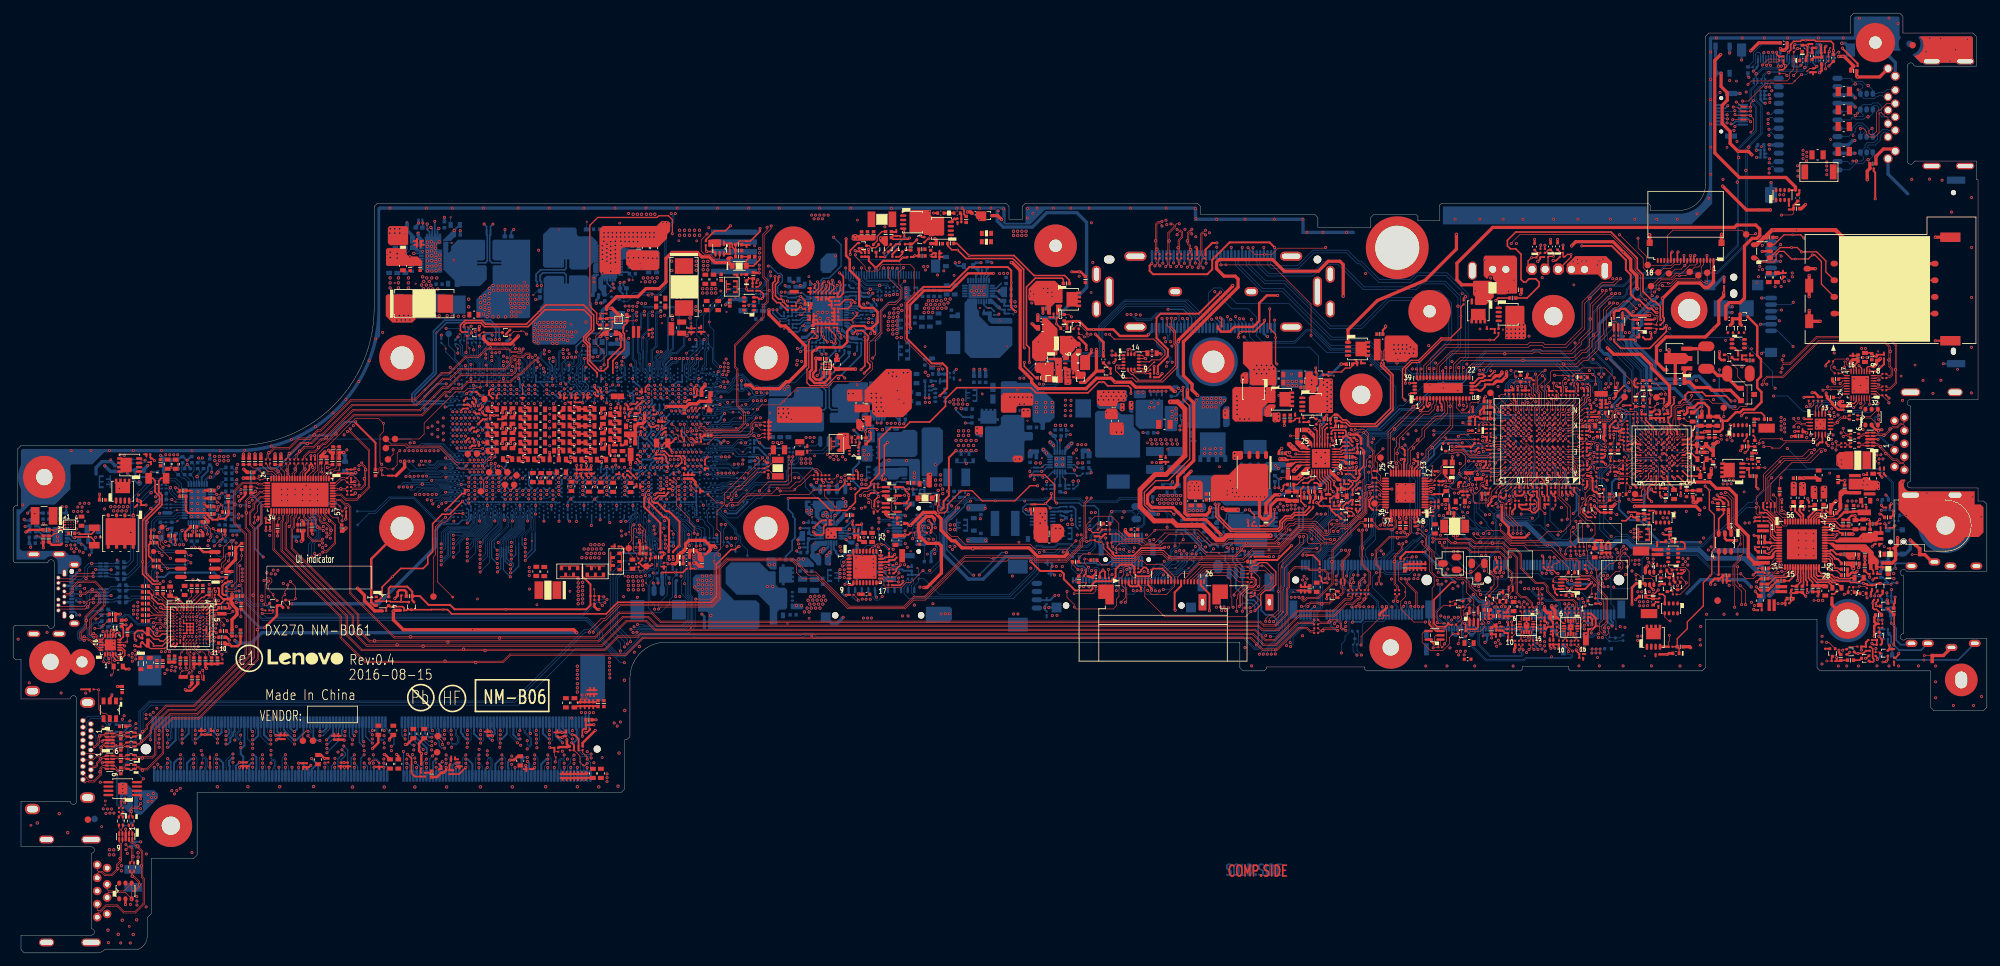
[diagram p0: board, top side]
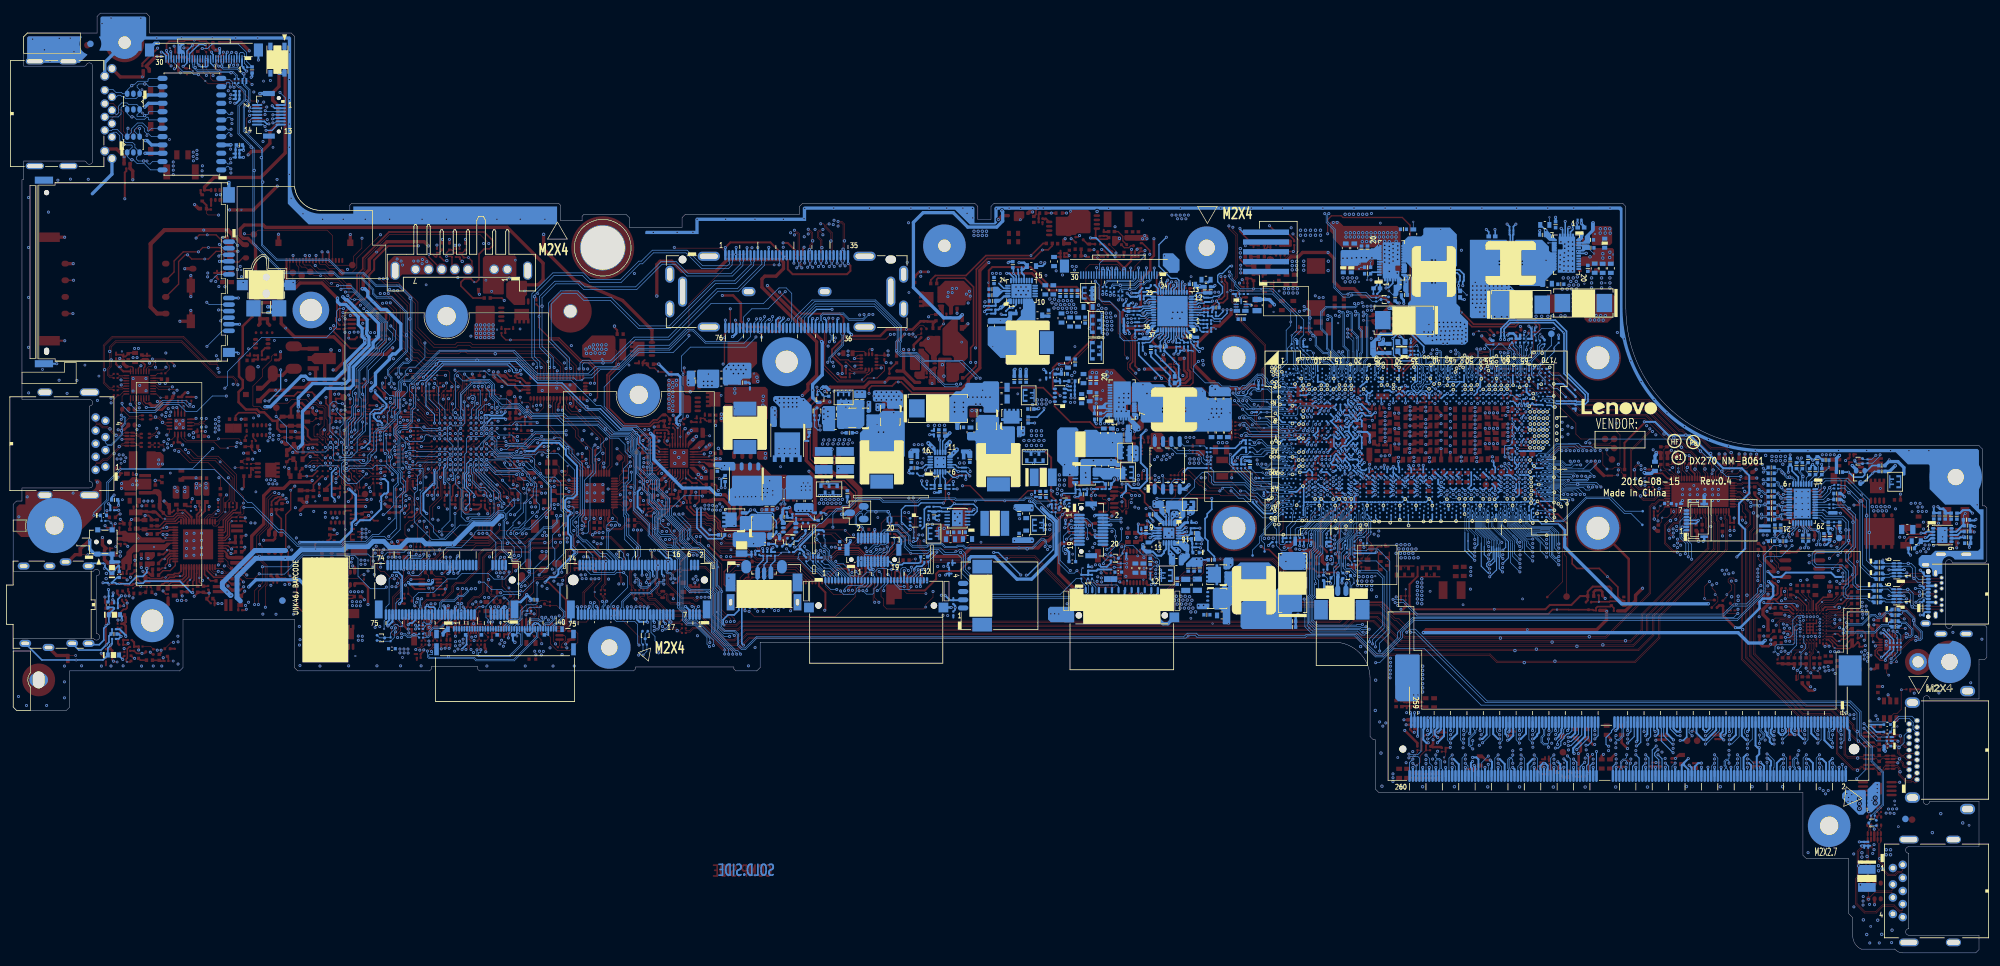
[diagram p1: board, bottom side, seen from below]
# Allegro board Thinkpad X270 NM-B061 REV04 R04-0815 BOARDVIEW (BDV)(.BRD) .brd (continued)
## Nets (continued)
GND: C1.2 C2.1 C3.1 C4.1 C5.1 C6.1 C7.1 C8.1 C19.1 C20.1 C21.1 C36.1 C75.1 C76.1 C77.1 C78.1 C79.1 C90.1 C91.1 C92.1 C99.1 C100.1 C101.2 C107.1 C108.1 C109.2 C110.2 C111.1 C112.1 C113.1 C114.1 C115.1 C116.1 C117.1 C118.1 C119.1 C120.1 C121.1 C122.1 C123.1 C124.1 C125.1 C126.1 C127.1 C128.1 C129.1 C130.1 C131.1 C132.1 C133.1 C134.1 C135.1 C136.2 C138.2 C140.1 C141.1 C142.1 C143.1 C155.2 C156.2 C157.2 C158.1 C159.1 C168.1 C169.1 C170.1 C171.1 C172.1 C173.1 C174.1 C175.2 C176.1 C177.1 C178.2 C180.1 C181.1 C184.1 C185.1 C186.2 C187.2 C188.1 C189.1 C190.2 C191.1 C192.1 C193.2 C194.1 C195.1 C196.1 C197.1 C198.1 C199.1 C200.1 C201.1 C203.1 C205.1 C206.1 C207.1 C208.1 C209.1 C211.1 C212.1 C213.1 C215.1 C216.1 C217.1 C229.2 C230.1 C232.1 C234.2 C238.2 C256.1 C257.2 C258.2 C259.2 C260.1 C261.2 C262.2 C263.2 C264.2 C265.2 C266.1 C267.1 C268.2 C269.1 C271.2 C272.2 C273.2 C274.2 C275.1 C277.1 C278.2 C279.1 C280.2 C281.2 C282.1 C283.1 C284.1 C285.1 C286.1 C287.1 C288.1 C289.1 C290.1 C292.2 C293.2 C294.2 C296.2 C297.2 C298.1 C299.2 C300.2 C301.2 C302.1 C303.2 C304.1 C305.1 C306.2 C307.1 C308.2 C309.1 C310.2 C311.1 C312.2 C318.1 C333.1 C500.2 C502.1 C535.2 C536.2 C537.2 C538.2 C539.2 C546.2 C547.2 C549.2 C553.2 C555.2 C556.2 C558.2 C564.1 C709.2 C796.2 C800.1 C809.2 C810.1 C811.2 C812.1 C813.1 C814.2 C815.2 C816.1 C817.2 C818.1 C821.2 C822.2 C823.2 C824.2 C830.1 C852.1 C900.2 C1417.1 C2543.1 C2544.1 C2545.1 C2546.1 C2573.1 C2574.1 C2575.1 C2576.1 C2587.1 C2729.1 C2730.1 C8333.2 C8337.2 C8338.2 C8339.2 C8340.2 C8341.2 C8356.2 C9130.1 C9142.1 C9197.1 C9463.1 C9464.2 C9487.1 CA5.2 CA37.1 CA44.1 CA45.1 CA46.1 CA52.1 CA53.1 CA54.1 CA55.1 CA56.1 CA73.1 CA117.2 CA119.1 CA122.2 CA124.1 CA127.2 CA142.1 CA243.2 CA913.2 CC5.2 CC10.1 CC11.1 CC12.2 CC13.2 CC14.2 CC15.2 CC17.1 CC18.2 CC19.2 CC20.2 CC21.2 CC22.2 CC23.2 CC24.2 CC25.1 CC26.1 CC27.1 CC28.1 CC29.1 CC30.1 CC31.2 CC32.1 CC33.1 CC34.1 CC35.1 CC36.1 CC37.1 CC38.1 CC39.1 CC40.1 CC41.2 CC42.1 CC43.1 CC44.1 CC45.1 CC46.1 CC47.1 CC48.1 CC49.1 CC50.1 CC51.1 CC52.1 CC53.1 CC54.1 CC55.1 CC56.1 CC57.1 CC58.1 CC59.1 CC60.1 CC61.1 CC62.1 CC63.1 CC64.1 CC65.1 CC66.1 CC67.1 CC68.1 CC69.2 CC70.2 CC71.2 CC72.2 CC73.1 CC76.1 CC78.1 CC79.1 CC80.1 CC81.1 CC82.1 CC83.1 CC84.1 CC85.1 CC86.1 CC87.1 CC88.1 CC89.1 CC90.1 CC91.1 CC92.1 CC93.1 CC94.1 CC95.1 CC96.1 CC97.1 CC99.1 CD1.2 CD2.2 CD3.2 CD4.2 CD5.2 CD6.2 CD7.2 CD8.2 CD9.2 CD10.2 CD11.1 CD12.1 CD13.2 CD14.2 CD15.1 CD16.1 CD17.1 CD18.1 CD19.1 CD20.1 CD21.1 CD22.1 CD23.1 CD24.2(G) CD25.1 CD27.2 CD28.1 CD29.1 CD30.2 CD31.1 CD32.2 CD33.1 CD34.2 CD35.1 CD36.2 CD37.1 CD38.1 CD39.1 CD40.1 CD41.1 CD42.1 CD43.1 CD44.1 CD45.1 CD46.1 CD47.1 CD48.1 CD49.1 CD50.1 CD51.1 CL5.2 CL6.1 CL7.1 CL8.1 CL9.1 CL10.1 CL11.1 CL12.1 CL13.1 CL14.1 CL16.1 CL17.1 CW1.1 CW2.1 D13.2(GND) D15.3(GND) D17.1 D18.4 D19.1 D24.2 D26.2 D51.3(GND) D52.3(GND) D53.3(GND) D54.2(GND) D55.2 D56.2 D57.2 D70.2 D87.3(GND) D88.3(GND) D94.2 D99.2 D710.2 D711.1 DA5.2 H1.1 H2.1 H3.1 H4.1 H5.1 H6.1 H8.1 H9.1 H10.1 H11.1 H12.1 H13.1 H14.1 H15.1 H16.1 J1.15 J1.16 J1.17 J1.18 J1.19 J1.25 J1.28 J1.31 J1.34 J1.37 J1.40 J1.41(GND1) J1.42(GND2) J1.43(GND3) J1.44(GND4) J1.45(GND5) J1.46(GND6) J1.47(GND7) J1.48(GND8) J1.49(GND9) J1.50(GND10) J1.51(GND11) J1.52(GND12) J3.10(GREEN_LED-) J3.12(YELLOW_LED-) J3.13(G1) J3.14(G2) J3.15(G3) J3.16(G4) J4.5(GND1) J4.6(GND2) J5.3 J5.12 J5.15(GND1) J5.16(GND2) J8.3 J8.6 J8.9 J8.19 J8.25 J10.2 J10.5 J10.8 J10.11 J10.16 J10.17 J10.19 J10.20 J10.21 J10.22 J10.31(G1) J10.32(G2) J11.3 J11.7 J11.14 J11.15 J11.18 J11.21 J11.30 J11.31(G1) J11.32(G2) J12.2 J12.3(GND1) J12.4(GND2) J15.3 J15.4 J15.8(GND1) J15.9(GND2) J16.7 J16.9 J16.12 J16.21(GND1) J16.22(GND2) J17.4(GND_5) J17.7(GND_6) J17.10(GND_7) J17.13(GND_8) J17.20(GND_9) J17.23(GND_10) J17.26(GND_11) J17.29(GND_12) J17.32(GND_13) J17.39(GND_4) J17.42(GND_3) J17.45(GND_2) J17.55(DOCK_DISCHARGE) J17.70(GND_1) J17.72(GND_14) J17.73(SHELL_1) J17.74(SHELL_2) J17.75(SHELL_3) J17.76(SHELL_4) J17.77(SHELL_5) J17.78(SHELL_6) J17.79(SHELL_7) J17.80(SHELL_8) J17.81(SHELL_9) J17.82(SHELL_10) J21.1(VSS_1) J21.2(VSS_2) J21.5(VSS_3) J21.6(VSS_4) J21.9(VSS_5) J21.10(VSS_6) J21.14(VSS_7) J21.15(VSS_8) J21.18(VSS_9) J21.19(VSS_10) J21.22(VSS_11) J21.23(VSS_12) J21.26(VSS_13) J21.27(VSS_14) J21.30(VSS_15) J21.31(VSS_16) J21.35(VSS_17) J21.36(VSS_18) J21.39(VSS_19) J21.40(VSS_20) J21.43(VSS_21) J21.44(VSS_22) J21.47(VSS_23) J21.48(VSS_24) J21.51(VSS_25) J21.52(VSS_26) J21.56(VSS_27) J21.57(VSS_28) J21.60(VSS_29) J21.61(VSS_30) J21.64(VSS_31) J21.65(VSS_32) J21.68(VSS_33) J21.69(VSS_34) J21.72(VSS_35) J21.73(VSS_36) J21.77(VSS_37) J21.78(VSS_38) J21.81(VSS_39) J21.82(VSS_40) J21.85(VSS_41) J21.86(VSS_42) J21.89(VSS_43) J21.90(VSS_44) J21.93(VSS_45) J21.94(VSS_46) J21.98(VSS_47) J21.99(VSS_48) J21.102(VSS_49) J21.103(VSS_50) J21.106(VSS_51) J21.107(VSS_52) J21.167(VSS_53) J21.168(VSS_54) J21.171(VSS_55) J21.172(VSS_56) J21.175(VSS_57) J21.176(VSS_58) J21.180(VSS_59) J21.181(VSS_60) J21.184(VSS_61) J21.185(VSS_62) J21.188(VSS_63) J21.189(VSS_64) J21.192(VSS_65) J21.193(VSS_66) J21.196(VSS_67) J21.197(VSS_68) J21.201(VSS_69) J21.202(VSS_70) J21.205(VSS_71) J21.206(VSS_72) J21.209(VSS_73) J21.210(VSS_74) J21.213(VSS_75) J21.214(VSS_76) J21.217(VSS_77) J21.218(VSS_78) J21.222(VSS_79) J21.223(VSS_80) J21.226(VSS_81) J21.227(VSS_82) J21.230(VSS_83) J21.231(VSS_84) J21.234(VSS_85) J21.235(VSS_86) J21.238(VSS_87) J21.239(VSS_88) J21.243(VSS_89) J21.244(VSS_90) J21.247(VSS_91) J21.248(VSS_92) J21.251(VSS_93) J21.252(VSS_94) J21.261(GND_1) J21.262(GND_2) J22.3(GND1) J22.5(GND2) J22.11(GND3) J22.27(GND4) J22.33(GND5) J22.39(GND6) J22.45(GND7) J22.51(GND8) J22.57(GND9) J22.71(GND10) J22.73(GND11) J22.76(PEG1) J22.77(PEG2) J23.3(VSS1) J23.6(VSS2) J23.11(COM) J23.13(GND1) J23.14(GND2) J23.15(GND3) J23.16(GND4) J25.5(GND1) J25.8(RESERVED2) J25.9(SWITCH) J25.10(GND2) J25.11(GND3) J25.12(GND4) J25.13(GND5) J26.8 J26.14 J26.16 J26.21(GND1) J26.22(GND2) J32.1(GND1) J32.7(GND2) J32.18(GND16) J32.23(GND3) J32.24(GND13) J32.29(GND4) J32.30(GND14) J32.33(GND5) J32.36(GND15) J32.39(GND6) J32.45(GND7) J32.51(GND8) J32.57(GND9) J32.63(GND10) J32.69(GND11) J32.75(GND12) J32.76(PEG1) J32.77(PEG2) J34.4(GND_1) J34.7(GND_DRAIN) J34.10(GND_2) J34.11(GND_3) J34.12(GND_4) J34.13(GND_5) J37.7 J37.12 J37.13(GND1) J37.14(GND2) J38.30 J38.33(GND1) J38.34(GND2) J41.8(GND4) J41.10(GND3) J41.12(GND2) J41.14(GND1) J41.19(PEG1) J41.20(PEG2) J42.4(GND_1) J42.7(GND_DRAIN) J42.10(GND_2) J42.11(GND_3) J42.12(GND_4) J42.13(GND_5) J43.2(D2_SHIELD) J43.5(D1_SHIELD) J43.8(D0_SHIELD) J43.11(CK_SHIELD) J43.17(DDC/CEC_GND) J43.20(GND1) J43.21(GND2) J43.22(GND3) J43.23(GND4) JTYC1.1(GND_A1) JTYC1.12(GND_A12) JTYC1.13(GND_B1) JTYC1.24(GND_B12) JTYC1.25(GND25) JTYC1.26(GND26) JTYC1.27(GND27) JTYC1.28(GND28) JTYC1.29(GND29) JTYC1.30(GND30) JTYC1.31(GND31) JTYC1.32(GND32) JTYC1.33(GND33) JTYC1.34(GND34) PC3.1 PC4.1 PC5.2 PC6.2 PC7.2 PC8.2 PC9.1 PC11.1 PC13.1 PC14.2 PC15.2 PC16.1 PC17.2 PC18.1 PC19.1 PC20.1 PC21.1 PC22.1 PC23.1 PC24.1 PC25.1 PC28.2 PC50.2 PC51.2 PC53.2 PC54.2 PC80.2(G) PC81.2 PC82.2 PC83.2 PC84.2 PC102.2 PC129.2 PC132.2 PC134.2 PC135.2 PC136.2 PC138.2 PC140.2 PC146.2 PC149.2 PC150.2 PC151.2 PC153.2 PC154.2 PC156.2 PC160.2 PC161.2 PC163.2 PC167.2 PC180.2 PC181.2 PC182.2 PC183.2 PC203.2 PC204.2 PC205.2 PC206.2 PC207.2 PC208.2 PC209.2 PC210.2 PC211.2 PC212.2 PC213.2 PC216.2 PC217.2 PC218.2 PC219.2 PC220.2(G) PC221.2 PC222.2(G) PC223.2(G) PC224.2 PC225.1 PC226.2 PC227.2 PC228.1 PC229.1 PC230.1 PC231.1 PC301.2 PC302.1 PC303.2 PC304.2 PC308.2 PC309.2 PC310.2 PC312.2 PC313.2 PC314.2(G) PC316.2 PC317.2 PC319.2 PC320.2 PC321.2 PC401.2 PC435.2 PC436.2 PC437.2 PC438.2 PC439.2 PC440.1 PC441.1 PC442.1 PC443.1 PC444.1 PC445.1 PC446.1 PC447.1 PC448.1 PC450.2 PC451.2 PC452.1 PC453.2 PC454.1 PC455.1 PC456.1 PC457.1 PC458.1 PC459.1 PC460.2(G) PC461.1 PC462.1 PC463.2 PC464.2 PC465.2 PC466.2 PC467.2 PC468.2 PC469.2 PC471.2 PC472.1 PC473.1 PC474.1 PC475.1 PC476.1 PC477.1 PC478.1 PC479.1 PC480.2 PC481.1 PC482.1 PC483.1 PC484.1 PC485.1 PC486.2 PC487.2(G) PC488.1 PC489.1 PC490.1 PC491.1 PC492.1 PC493.1 PC494.1 PC495.1 PC496.1 PC497.1 PC498.2 PC499.2 PC500.2(G) PC501.2(G) PC502.2(G) PC503.2(G) PC506.1 PC507.1 PC508.1 PC510.1 PC511.1 PC512.1 PC513.1 PC514.1 PC515.1 PC516.1 PC517.1 PC522.2 PC523.2 PC524.2 PC525.2 PC526.2 PC528.2 PC529.2 PC530.1 PC531.1 PC532.1 PC533.1 PC534.1 PC535.1 PC536.2 PC537.1 PC538.1 PC539.1 PC540.1 PC712.2 PC713.2 PC714.2 PC715.2 PC716.1 PC717.2 PC718.2 PC719.1 PC720.1 PC721.1 PC722.1 PC723.2 PC724.1 PC737.2 PC738.2 PC739.2 PC740.2 PC743.2 PC745.1 PC746.2 PC756.2 PC776.2 PC783.2 PC784.2 PC785.2 PC786.2 PC787.2 PC788.2 PC790.2 PC791.2 PC792.1 PC793.2 PC794.2 PC795.2 PC801.2 PC802.1 PD5.2 PD7.2 PD8.2 PD9.2 PD30.2 PJ1.1 PJ1.2 PJ2.5 PJ2.9(GND) PJ3.6 PJ3.7 PJ3.8(GND1) PJ3.9(GND2) PQ5.3(S) PQ9.3(S) PQ11.4(S2) PQ15.3(S) PQ22.3(GND) PQ24.3(GND) PQ41.3(S) PQ104.3(S) PQ109.3(S) PQ111.1(S1) PQ111.2(S2) PQ111.3(S3) PQ113.1(S1) PQ113.2(S2) PQ113.3(S3) PQ203.1(S1) PQ203.2(S2) PQ203.3(S3) PQ204.1(S1) PQ204.2(S2) PQ204.3(S3) PQ302.1(S1) PQ302.2(S2) PQ302.3(S3) PR19.2 PR46.2 PR79.2 PR83.2 PR88.2 PR89.1 PR98.2 PR153.2 PR156.2 PR162.2 PR216.2 PR217.2 PR218.2 PR219.2 PR220.1 PR312.2 PR417.2 PR437.2 PR462.2 PR721.2 PR753.2 PR761.1 PR762.2 PR766.1 PR801.2 PR802.2 PRT402.2 PRT404.2 PU4.11(GND) PU5.1(GND) PU5.7(THERMAL_PAD) PU101.33(PAD) PU201.21(GND) PU301.4(VTTGND) PU301.10(PGND) PU301.21(PAD) PU402.3(SMOD#) PU402.5(CGND1) PU402.19(PGND1) PU402.26(PGND2) PU403.5(CGND1) PU403.19(PGND1) PU403.26(PGND2) PU405.3(SMOD#) PU405.5(CGND1) PU405.19(PGND1) PU405.26(PGND2) PU701.11(GND) PU702.10(PGND1) PU702.11(PGND2) PU702.12(PGND3) PU702.13(PGND4) PU702.14(PGND5) PU702.19(GND1) PU702.23(GSNS) PU702.24(REFIN2) PU702.29(GND2) PU706.11(GND) Q4.3(EMITTER) Q7.3(S) Q28.3(EMITTER) Q29.3(S) Q34.B2(GND) Q35.B2(GND) Q36.3(S) Q39.3(S) Q40.3(S) Q60.2(GND) Q175.3(GND) Q197.3(S) Q226.3(S) Q227.3(S) Q228.3(S) Q263.3(S) QA7.3(S) QA8.3(GND) QC2.3(S) QC3.3(S) R3.1 R51.2 R67.2 R89.2 R90.2 R100.1 R113.1 R118.2 R130.1 R132.1 R133.1 R146.1 R147.2 R149.2 R154.2 R156.1 R168.1 R170.1 R171.1 R182.1 R183.1 R184.1 R185.1 R186.1 R187.1 R192.1 R193.1 R194.1 R195.1 R196.1 R197.1 R198.1 R200.1 R201.1 R202.1 R205.1 R206.1 R207.1 R230.1 R236.1 R239.2 R265.1 R266.1 R268.1 R269.1 R279.1 R312.1 R314.2 R346.1 R347.1 R348.1 R349.1 R352.2 R360.1 R361.1 R362.1 R363.1 R369.1 R374.1 R377.1 R399.2 R401.1 R402.2 R403.2 R413.1 R428.2 R436.1 R443.1 R458.2 R486.1 R490.2 R509.1 R537.2 R678.1 R680.1 R721.1 R722.1 R723.1 R724.1 R727.1 R728.2 R729.1 R780.1 R781.1 R783.2 R784.2 R785.2 R786.2 R790.1 R791.1 R799.1 R819.1 R849.1 R850.1 R862.2 R908.1 R1119.1 R1239.1 R1897.2 R1899.2 R2512.1 R2515.1 R2516.1 R2517.1 R2524.2 R2526.2 R2528.2 R2530.2 R2562.2 R9085.1 R9097.2 R9098.1 R9102.1 R9107.1 R9108.1 R9110.2 R9113.1 R9117.1 R9130.2 R10082.1 R10141.1 R10248.1 R10250.1 R10324.2 RA8.1 RA9.1 RA22.1 RA25.1 RA37.1 RA124.1 RC2.2 RC3.2 RC4.2 RC5.2 RC9.1 RC11.2 RC12.2 RC13.2 RC17.1 RC18.1 RC19.1 RC20.1 RC21.2 RC35.1 RC43.2 RC48.1 RC51.2 RC52.2 RC53.2 RC54.2 RC82.2 RC90.1 RC91.1 RC92.2 RC100.1 RC101.1 RC102.1 RC103.1 RC104.2 RC107.2 RC137.2 RC142.2 RC150.1 RC151.1 RC156.1 RC157.1 RC159.2 RC162.2 RC166.2 RD4.1 RD5.1 RD6.1 RD9.1 RD10.1 RL3.2 RL10.1 RL11.1 RT8.2 S1.1 S1.2 S2.3 S3.3 S3.4 ST1.1 ST2.1 ST3.1 ST4.1 ST5.1 TP5.1 TP8.1 TP9.1 U1.A67(VSS_A67) U1.A70(VSS_A70) U1.AA2(VSS_AA2) U1.AA4(VSS_AA4) U1.AA65(VSS_AA65) U1.AA68(VSS_AA68) U1.AB8(VSS_AB8) U1.AB15(VSS_AB15) U1.AB16(VSS_AB16) U1.AB18(VSS_AB18) U1.AB21(VSS_AB21) U1.AD8(VSS_AD8) U1.AD13(VSS_AD13) U1.AD16(VSS_AD16) U1.AD19(VSS_AD19) U1.AD20(VSS_AD20) U1.AD21(VSS_AD21) U1.AD62(VSS_AD62) U1.AE64(VSS_AE64) U1.AE65(VSS_AE65) U1.AE66(VSS_AE66) U1.AE67(VSS_AE67) U1.AE68(VSS_AE68) U1.AE69(VSS_AE69) U1.AF1(VSS_AF1) U1.AF2(VSS_AF2) U1.AF4(VSS_AF4) U1.AF10(VSS_AF10) U1.AF15(VSS_AF15) U1.AF17(VSS_AF17) U1.AF63(VSS_AF63) U1.AG16(VSS_AG16) U1.AG17(VSS_AG17) U1.AG18(VSS_AG18) U1.AG19(VSS_AG19) U1.AG20(VSS_AG20) U1.AG21(VSS_AG21) U1.AG71(VSS_AG71) U1.AH6(VSS_AH6) U1.AH13(VSS_AH13) U1.AH63(VSS_AH63) U1.AH64(VSS_AH64) U1.AH67(VSS_AH67) U1.AJ4(VSS_AJ4) U1.AJ15(VSS_AJ15) U1.AJ18(VSS_AJ18) U1.AJ20(VSS_AJ20) U1.AK8(VSS_AK8) U1.AK11(VSS_AK11) U1.AK16(VSS_AK16) U1.AK18(VSS_AK18) U1.AK21(VSS_AK21) U1.AK22(VSS_AK22) U1.AK27(VSS_AK27) U1.AK63(VSS_AK63) U1.AK68(VSS_AK68) U1.AK69(VSS_AK69) U1.AL2(VSS_AL2) U1.AL4(VSS_AL4) U1.AL28(VSS_AL28) U1.AL32(VSS_AL32) U1.AL35(VSS_AL35) U1.AL38(VSS_AL38) U1.AL45(VSS_AL45) U1.AL48(VSS_AL48) U1.AL52(VSS_AL52) U1.AL55(VSS_AL55) U1.AL58(VSS_AL58) U1.AL64(VSS_AL64) U1.AL65(VSS_AL65) U1.AL66(VSS_AL66) U1.AM8(VSS_AM8) U1.AM13(VSS_AM13) U1.AM21(VSS_AM21) U1.AM25(VSS_AM25) U1.AM27(VSS_AM27) U1.AM43(VSS_AM43) U1.AM45(VSS_AM45) U1.AM46(VSS_AM46) U1.AM55(VSS_AM55) U1.AM60(VSS_AM60) U1.AM61(VSS_AM61) U1.AM68(VSS_AM68) U1.AM71(VSS_AM71) U1.AN20(VSS_AN20) U1.AN23(VSS_AN23) U1.AN28(VSS_AN28) U1.AN30(VSS_AN30) U1.AN32(VSS_AN32) U1.AN33(VSS_AN33) U1.AN35(VSS_AN35) U1.AN37(VSS_AN37) U1.AN38(VSS_AN38) U1.AN40(VSS_AN40) U1.AN42(VSS_AN42) U1.AN58(VSS_AN58) U1.AN63(VSS_AN63) U1.AP10(VSS_AP10) U1.AP18(VSS_AP18) U1.AP20(VSS_AP20) U1.AP23(VSS_AP23) U1.AP28(VSS_AP28) U1.AP32(VSS_AP32) U1.AP35(VSS_AP35) U1.AP38(VSS_AP38) U1.AP42(VSS_AP42) U1.AP58(VSS_AP58) U1.AP63(VSS_AP63) U1.AP68(VSS_AP68) U1.AP70(VSS_AP70) U1.AR5(VSS_AR5) U1.AR8(VSS_AR8) U1.AR11(VSS_AR11) U1.AR15(VSS_AR15) U1.AR16(VSS_AR16) U1.AR20(VSS_AR20) U1.AR23(VSS_AR23) U1.AR28(VSS_AR28) U1.AR35(VSS_AR35) U1.AR42(VSS_AR42) U1.AR43(VSS_AR43) U1.AR45(VSS_AR45) U1.AR46(VSS_AR46) U1.AR48(VSS_AR48) U1.AR50(VSS_AR50) U1.AR52(VSS_AR52) U1.AR53(VSS_AR53) U1.AR55(VSS_AR55) U1.AR58(VSS_AR58) U1.AR63(VSS_AR63) U1.AT2(VSS_AT2) U1.AT4(VSS_AT4) U1.AT20(VSS_AT20) U1.AT23(VSS_AT23) U1.AT28(VSS_AT28) U1.AT35(VSS_AT35) U1.AT42(VSS_AT42) U1.AT56(VSS_AT56) U1.AT58(VSS_AT58) U1.AT63(VSS_AT63) U1.AT68(VSS_AT68) U1.AT71(VSS_AT71) U1.AU10(VSS_AU10) U1.AU15(VSS_AU15) U1.AU20(VSS_AU20) U1.AU32(VSS_AU32) U1.AU38(VSS_AU38) U1.AV68(VSS_AV68) U1.AV69(VSS_AV69) U1.AV70(VSS_AV70) U1.AV71(VSS_AV71) U1.AW6(VSS_AW6) U1.AW8(VSS_AW8) U1.AW10(VSS_AW10) U1.AW12(VSS_AW12) U1.AW14(VSS_AW14) U1.AW16(VSS_AW16) U1.AW18(VSS_AW18) U1.AW21(VSS_AW21) U1.AW23(VSS_AW23) U1.AW26(VSS_AW26) U1.AW28(VSS_AW28) U1.AW30(VSS_AW30) U1.AW32(VSS_AW32) U1.AW34(VSS_AW34) U1.AW36(VSS_AW36) U1.AW38(VSS_AW38) U1.AW41(VSS_AW41) U1.AW43(VSS_AW43) U1.AW45(VSS_AW45) U1.AW47(VSS_AW47) U1.AW49(VSS_AW49) U1.AW51(VSS_AW51) U1.AW53(VSS_AW53) U1.AW55(VSS_AW55) U1.AW57(VSS_AW57) U1.AW60(VSS_AW60) U1.AW62(VSS_AW62) U1.AW64(VSS_AW64) U1.AW66(VSS_AW66) U1.AY66(VSS_AY66) U1.B10(VSS_B10) U1.B14(VSS_B14) U1.B18(VSS_B18) U1.B22(VSS_B22) U1.B30(VSS_B30) U1.B34(VSS_B34) U1.B39(VSS_B39) U1.B44(VSS_B44) U1.B48(VSS_B48) U1.B53(VSS_B53) U1.B58(VSS_B58) U1.B62(VSS_B62) U1.B66(VSS_B66) U1.BA6(VSS_BA6) U1.BA10(VSS_BA10) U1.BA14(VSS_BA14) U1.BA18(VSS_BA18) U1.BA23(VSS_BA23) U1.BA28(VSS_BA28) U1.BA32(VSS_BA32) U1.BA36(VSS_BA36) U1.BA41(VSS_BA41) U1.BA45(VSS_BA45) U1.BA49(VSS_BA49) U1.BA53(VSS_BA53) U1.BA57(VSS_BA57) U1.BA62(VSS_BA62) U1.BA66(VSS_BA66) U1.BB6(VSS_BB6) U1.BB18(VSS_BB18) U1.BB26(VSS_BB26) U1.BB30(VSS_BB30) U1.BB34(VSS_BB34) U1.BB38(VSS_BB38) U1.BB43(VSS_BB43) U1.BB55(VSS_BB55) U1.BB60(VSS_BB60) U1.BB64(VSS_BB64) U1.C1(VSS_C1) U1.C5(VSS_C5) U1.C25(VSS_C25) U1.D6(VSS_D6) U1.D10(VSS_D10) U1.D11(VSS_D11) U1.D14(VSS_D14) U1.D18(VSS_D18) U1.D22(VSS_D22) U1.D25(VSS_D25) U1.D26(VSS_D26) U1.D30(VSS_D30) U1.D34(VSS_D34) U1.D39(VSS_D39) U1.D44(VSS_D44) U1.D45(VSS_D45) U1.D47(VSS_D47) U1.D48(VSS_D48) U1.D53(VSS_D53) U1.D58(VSS_D58) U1.D62(VSS_D62) U1.D66(VSS_D66) U1.D69(VSS_D69) U1.E6(VSS_E6) U1.E11(VSS_E11) U1.E15(VSS_E15) U1.E18(VSS_E18) U1.E21(VSS_E21) U1.E46(VSS_E46) U1.E50(VSS_E50) U1.E53(VSS_E53) U1.E56(VSS_E56) U1.E65(VSS_E65) U1.F1(VSS_F1) U1.F2(VSS_F2) U1.F4(VSS_F4) U1.F8(VSS_F8) U1.F13(VSS_F13) U1.F22(VSS_F22) U1.F23(VSS_F23) U1.F27(VSS_F27) U1.F28(VSS_F28) U1.F32(VSS_F32) U1.F33(VSS_F33) U1.F35(VSS_F35) U1.F37(VSS_F37) U1.F38(VSS_F38) U1.F40(VSS_F40) U1.F42(VSS_F42) U1.F68(VSS_F68) U1.G5(VSS_G5) U1.G6(VSS_G6) U1.G10(VSS_G10) U1.G22(VSS_G22) U1.G43(VSS_G43) U1.G45(VSS_G45) U1.G48(VSS_G48) U1.G52(VSS_G52) U1.G55(VSS_G55) U1.G58(VSS_G58) U1.G60(VSS_G60) U1.G63(VSS_G63) U1.G66(VSS_G66) U1.H15(VSS_H15) U1.H18(VSS_H18) U1.H71(VSS_H71) U1.J8(VSS_J8) U1.J11(VSS_J11) U1.J13(VSS_J13) U1.J25(VSS_J25) U1.J28(VSS_J28) U1.J32(VSS_J32) U1.J35(VSS_J35) U1.J38(VSS_J38) U1.J42(VSS_J42) U1.K16(VSS_K16) U1.K18(VSS_K18) U1.K22(VSS_K22) U1.K61(VSS_K61) U1.K63(VSS_K63) U1.K64(VSS_K64) U1.K65(VSS_K65) U1.K66(VSS_K66) U1.K67(VSS_K67) U1.K68(VSS_K68) U1.K70(VSS_K70) U1.K71(VSS_K71) U1.L2(VSS_L2) U1.L4(VSS_L4) U1.L8(VSS_L8) U1.L11(VSS_L11) U1.L16(VSS_L16) U1.L17(VSS_L17) U1.L18(VSS_L18) U1.L20(VSS_L20) U1.N6(VSS_N6) U1.N10(VSS_N10) U1.N13(VSS_N13) U1.N19(VSS_N19) U1.N21(VSS_N21) U1.N65(VSS_N65) U1.N68(VSS_N68) U1.P17(VSS_P17) U1.P19(VSS_P19) U1.P20(VSS_P20) U1.P21(VSS_P21) U1.R6(VSS_R6) U1.R13(VSS_R13) U1.T2(VSS_T2) U1.T4(VSS_T4) U1.T15(VSS_T15) U1.T17(VSS_T17) U1.T18(VSS_T18) U1.T21(VSS_T21) U1.U10(VSS_U10) U1.U63(VSS_U63) U1.U64(VSS_U64) U1.U66(VSS_U66) U1.U67(VSS_U67) U1.U69(VSS_U69) U1.U70(VSS_U70) U1.V16(VSS_V16) U1.V17(VSS_V17) U1.V18(VSS_V18) U1.W6(VSS_W6) U1.W9(VSS_W9) U1.W13(VSS_W13) U1.Y17(VSS_Y17) U1.Y19(VSS_Y19) U1.Y20(VSS_Y20) U1.Y21(VSS_Y21) U5.A1(GND_1) U5.B8(GND_2) U5.D8(GND_4) U5.E5(GND_5) U5.E6(GND_6) U5.E7(GND_7) U5.E8(GND_8) U5.F5(GND_9) U5.F6(GND_10) U5.F7(GND_11) U5.F8(GND_12) U5.G5(GND_13) U5.G6(GND_14) U5.G7(GND_15) U5.G8(GND_16) U5.H4(GND_17) U5.H5(GND_18) U5.H8(GND_19) U5.L1(GND_20) U5.L11(NC_L11) U7.3(GND) U12.14(GND) U12.17(GPAD) U13.1(GND_1) U13.9(GND_2) U14.42(LEDA2) U14.43(PAD_GND) U15.33(GND) U16.A3(BGND) U16.F7(VSS2) U16.G4(VSS_RO) U16.G5(VSS1) U16.H5(VSS0) U16.K4(VSS_ADC) U17.5(GND_1) U17.10(NC_3) U17.12(GND_2) U17.13(TRIG) U17.15(NC_4) U17.16(NC_5) U19.3(GND) U20.3(GND) U21.A3(PGND1) U21.B9(PGND2) U21.G5(TEST) U21.G9(DGND1) U21.J2(AGND1) U23.2(GND) U24.3(GND1) U24.12(GND2) U24.19(GND_PAD) U25.3(GND1) U25.12(GND2) U25.19(GND_PAD) U26.9(GND2) U26.16(GND/NCI10) U26.23(GND3) U26.32(GND4) U26.33(GND5) U27.3(GND) U36.3(GND) U147.67(EPAD) U163.2(GND) U183.41(EPAD) U184.3(GND) U185.3(GND) U186.4(GND) U187.A1(EN#) U187.A4(GND_1) U187.B4(GND_2) U187.C4(GND_3) U191.4(GND) U193.8(GND1) U193.13(GND2) U193.18(GND3) U193.21(THERMAL_PAD) UA1.57(THERMAL_PAD) UC3.3(GND) UC4.6(GND) UC5.4(GND) UL1.49(GND) Y1.2(GND1) Y1.4(GND2) YL1.2(GND1) YL1.4(GND2)
GND_81208: PC402.2 PC403.2 PC408.2 PC409.1 PC411.1 PC412.1 PC417.1 PC418.2 PC425.2 PC428.1 PC431.1 PC432.1 PR412.2 PR418.1 PR419.1 PR420.1 PR425.1 PR441.1 PR442.1 PR443.1 PR444.1 PR445.1 PR446.2 PR447.1 PR448.2 PR449.2 PR462.1 PU401.49(TAB)
GNDA: C30.1 C36.2 C73.1 C540.2 C541.2 C542.2 C543.2 C544.2 C545.2 C551.2 C552.2 C559.2 C561.2 C1416.1 C2571.1 C2572.1 C2575.2 C9134.2 C9135.2 C9137.2 C9138.2 C9139.2 C9140.2 C9141.1 C9146.2 CA37.2 CA46.2 CA47.1 CA52.2 Q50.3(S) R484.2 R537.1 R742.1 R743.1 R10082.2 RA35.1 RA36.1 RA37.2 UA1.20(AVSS2) UA1.30(CPVREF) UA1.42(AVSS1)
VCC0R6B: CD13.1 CD14.1 CD15.2 CD36.1 CD37.2 CD46.2 CD47.2 CD48.2 CD49.2 J21.258(VTT) PJ304.1
VCC0R6BP: PC303.1 PC304.1 PJ304.2 PU301.1(VTTSNS) PU301.3(VTT)
VCC0R9GBE: CL6.2 CL7.2 CL9.2 FL6.2 UL1.8(VDD0P9_8) UL1.11(VDD0P9_11) UL1.16(VDD0P9_16) UL1.22(VDD0P9_22) UL1.37(VDD0P9_37) UL1.40(VDD0P9_40) UL1.43(VDD0P9_43) UL1.46(VDD0P9_46) UL1.47(VDD0P9_47)
VCC0R9GBE_L: FL6.1 UL1.7(CTRL0P9)
VCC1R0_SUS: C292.1 C296.1 CC50.2 CC51.2 CC52.2 CC63.2 CC66.2 CC67.2 CC68.2 J8.16 PJ702.1 PJ703.1 Q33.1 Q33.2 Q33.3 Q33.6 Q33.7 Q33.8 Q34.A1(IN) Q35.A1(IN) R431.1 RC57.1 RC73.2 RC95.2 RC96.2 RC98.1 RC99.2 RC116.1 U1.A10(VCCCLK6) U1.A14(VCCCLK1) U1.AB17(VCCPRIM_1P0_AB17) U1.AB19(VCCPRIM_1P0_AB19) U1.AB20(VCCPRIM_1P0_AB20) U1.AF18(VCCPRIM_CORE_AF18) U1.AF19(VCCPRIM_CORE_AF19) U1.AK20(VCCPRIM_1P0_AK20) U1.K17(VCCMPHYAON_1P0_K17) U1.L1(VCCMPHYAON_1P0_L1) U1.L21(VCCCLK3) U1.P18(VCCPRIM_1P0_P18) U1.T1(VCCPRIM_1P0_T1) U1.V20(VCCPRIM_CORE_V20) U1.V21(VCCPRIM_CORE_V21) U1.Y18(VCCPRIM_1P0_Y18) UC4.2(D1) UC4.3(D2)
VCC1R2A: C709.1 CC18.1 CC19.1 CC20.1 CC21.1 CC22.1 CC23.1 CC24.1 CC25.2 CC26.2 CC27.2 CC31.1 CC32.2 PJ302.1 PJ303.1 QC1.2(BASE) RC10.2 RJ2.2 U1.AL23(VCCPLL_OC) U1.AM40(VDDQC) U1.AU23(VDDQ_AU23) U1.AU28(VDDQ_AU28) U1.AU35(VDDQ_AU35) U1.AU42(VDDQ_AU42) U1.BB23(VDDQ_BB23) U1.BB32(VDDQ_BB32) U1.BB41(VDDQ_BB41) U1.BB47(VDDQ_BB47) U1.BB51(VDDQ_BB51) U36.5(VCC)
VCC1R2A_DIMN: C310.1 C311.2 CD1.1 CD2.1 CD3.1 CD4.1 CD5.1 CD6.1 CD7.1 CD8.1 CD16.2 CD17.2 CD18.2 CD19.2 CD20.2 CD21.2 CD22.2 CD23.2 CD24.1(P) CD32.1 CD33.2 CD38.2 CD39.2 CD40.2 CD41.2 CD42.2 CD43.2 CD44.2 CD45.2 J21.12(DM0_N/DBL0_N) J21.33(DM1_N/DBL1_N) J21.54(DM2_N/DBL2_N) J21.75(DM3_N/DBL3_N) J21.96(DM8_N/DBL8_N/NC) J21.111(VDD_1) J21.112(VDD_2) J21.117(VDD_3) J21.118(VDD_4) J21.123(VDD_5) J21.124(VDD_6) J21.129(VDD_7) J21.130(VDD_8) J21.135(VDD_9) J21.136(VDD_10) J21.141(VDD_11) J21.142(VDD_12) J21.147(VDD_13) J21.148(VDD_14) J21.153(VDD_15) J21.154(VDD_16) J21.159(VDD_17) J21.160(VDD_18) J21.163(VDD_19) J21.178(DM4_N/DBL4_N) J21.199(DM5_N/DBL5_N) J21.220(DM6_N/DBL6_N) J21.241(DM7_N/DBL7_N) Q26.5(D) RD7.1 RD11.1 RJ2.1
VCC1R8_SUS: C2573.2 C2574.2 C9464.1 CC62.2 CC65.2 PJ711.1 Q60.1(VIN) R322.1 R600.2 R601.2 R10203.1 RC152.2 U1.AA1(VCCATS_1P8) U1.AF16(VCCPGPPF) U163.1(VCC(A)) U191.8(VCC(B))
VCC1R8_SUSA: C556.1 C2571.2 C2572.2 Q60.5(QOD) Q60.6(VOUT) R10076.1 R10203.2 R10324.1
VCC1V2B: C308.1 C309.2 Q26.1(S1) Q26.2(S2) Q26.3(S3) R355.1 R372.1
VCC2R5A: CD9.1 CD10.1 CD11.2 CD12.2 CD34.1 CD35.2 CD50.2 CD51.2 J21.257(VPP_1) J21.259(VPP_2) PJ716.1
VCC3_LDO_TBTA: C814.1 C816.2 C900.1 PR87.1 PR90.1 R489.1 R711.2 R712.2 R713.1 R714.1 R715.1 R716.1 U5.G1(LDO_3V3) U186.8(VCC) U193.10(VPWR)
VCC3_MC: C133.2 CW1.2 CW2.2 J23.4(VDD) U15.12(CARD_3V3)
VCC3_SUS: CC33.2 CC34.2 CC35.2 CC53.2 CC58.2 CC59.2 CC60.2 CC61.2 CC64.2 DC4.2 J41.1(VCCSUS3_3) Q41.3(S) Q170.2(G) Q171.2(G) R237.2 R238.1 R251.2 R252.2 R397.1 R485.2 R2745.2 R9134.2 R9135.2 R10199.1 RC23.2 RC24.2 RC25.2 RC26.2 RC27.2 RC28.2 RC32.2 RC33.2 RC34.2 RC36.1 RC38.2 RC44.2 RC45.2 RC47.2 RC72.2 RC117.2 RC134.2 RC135.2 RC140.2 RC141.2 RC153.2 RC164.2 RC167.2 RC168.2 RJ4.1 TP1.1 U1.AD15(VCCPGPPG) U1.AG15(VCCPGPPB) U1.AJ16(VCCSPI) U1.AJ19(VCCHDA) U1.AJ21(VCCPRIM_3P3_AJ21) U1.AK15(VCCPGPPA) U1.AK17(VCCRTCPRIM_3P3) U1.T16(VCCPGPPE) U1.V19(VCCPRIM_3P3_V19) U1.Y15(VCCPGPPD) U1.Y16(VCCPGPPC) U163.6(VCC(B)) UC4.1(VDD)
VCC3B: C131.2 C132.2 C134.2 C135.2 C284.2 F3.2 F5.2 F15.2 F41.2 F42.2 PR405.1 Q20.1(S1) Q20.2(S2) Q20.3(S3) R6.2 R46.2 R52.2 R108.2 R109.2 R110.2 R112.2 R117.1 R126.2 R164.2 R226.2 R227.2 R248.2 R249.2 R284.2 R296.2 R302.2 R325.1 R354.1 R368.2 R370.2 R375.1 R376.1 R382.2 R394.1 R409.2 R532.2 R951.2 R1867.2 R1868.2 R1869.2 R1875.1 R1877.1 R2378.2 R2379.2 R2500.2 R2523.1 R2527.1 R2529.1 R2531.1 R2561.1 R2572.2 R2746.2 R2747.2 R9129.1 R9131.1 R9136.2 R9137.2 R10095.2 R10133.2 R10197.1 RC22.2 RC29.2 RC111.2 RC169.2 RD1.2 RD2.2 RD3.2 RD12.1 RL1.2 RX55.1 U15.11(3V3_IN) U15.27(3V3AUX)
VCC3B_DRV: C212.2 D44.1 R299.1 U21.A6(3B_DRV)
VCC3B_PS8349B: C2543.2 C2544.2 C2545.2 C2546.2 C2576.2 RX55.2 U147.1(VDD33_1) U147.10(VDD33_2) U147.34(VDD33_3)
VCC3FP: F152.2 Q14.1(DRAIN1) Q14.2(DRAIN2) Q14.5(DRAIN3) Q14.6(DRAIN4)
VCC3GBE: C111.2 C112.2 C113.2 C114.2 C115.2 CL5.1 CL13.2 CL14.2 R91.2 R395.2 RL2.2 RL6.2 RL7.1 RL8.1 U14.1(VDD1) U14.4(VDD2) U14.8(VDD3) U14.14(VDD4) U14.21(VDD5) U14.30(VDD6) U14.39(VDD7) UL1.4(VDD3P3_4) UL1.5(VDD3P3_IN) UL1.15(VDD3P3_15) UL1.19(VDD3P3_19) UL1.29(VDD3P3_29)
VCC3LAN: CL11.2 CL12.2 R395.1 RJ5.1
VCC3LAN_DRV: C211.2 D42.1 R295.1 U21.C3(RD1_DRV)
VCC3LCD: C3.2 C4.2 C5.2 C265.1 C266.2 F2.1 J10.13 J10.14
VCC3M: C184.2 C185.2 C194.2 C312.1 C796.1 F4.2 F9.2 J41.3(VCCDSW3_3) J41.7(+V3.3DS) PD4.1 PJ203.1 PR15.1 PR26.2 PR33.2 PR305.1 PR738.1 PR751.2 Q1.1 Q1.2 Q1.3 Q1.6 Q1.7 Q1.8 Q14.4(S) Q17.1(D1) Q17.2(D2) Q17.5(D3) Q17.6(D4) Q19.1 Q19.2 Q19.3 Q19.6 Q19.7 Q19.8 Q20.5(D) Q23.1 Q23.2 Q23.3 Q23.6 Q23.7 Q23.8 Q24.1 Q24.2 Q24.3 Q24.6 Q24.7 Q24.8 Q266.1(DRAIN_1) Q266.2(DRAIN_2) Q266.3(DRAIN_3) Q266.6(DRAIN_4) Q266.7(DRAIN_5) Q266.8(DRAIN_6) R120.2 R124.1 R125.1 R128.2 R129.2 R131.2 R134.2 R136.2 R138.2 R148.2 R151.2 R152.2 R153.2 R155.2 R158.2 R159.2 R160.2 R161.2 R172.1 R173.1 R181.2 R188.1 R189.1 R208.2 R209.2 R210.2 R211.2 R212.2 R213.2 R214.2 R215.2 R216.2 R217.2 R218.2 R219.2 R234.2 R235.2 R270.2 R285.2 R350.2 R353.2 R398.2 R404.2 R405.2 R439.1 R440.2 R450.2 R483.2 R702.2 R703.2 R782.2 R798.2 R851.2 R852.2 R2574.2 R9083.1 R10251.2 RC8.2 RC64.2 RC69.1 RC70.1 U1.AD17(VCCDSW_3P3_AD17) U1.AD18(VCCDSW_3P3_AD18) U1.AJ17(VCCDSW_3P3_AJ17) U5.B1(VDDIO) U5.H1(VIN_3V3) U17.1(IO_VDD) U17.14(VDD) UC3.5(VCC)
VCC3M_BST: PR208.1 PU201.9(VBST2)
VCC3M_DH: PQ202.4(G) PU201.10(DRVH2)
VCC3M_DL: PQ204.4(G) PU201.11(DRVL2)
VCC3M_EC: C169.2 C170.2 C171.2 R173.2 R175.2 U16.F12(VTR_FLASH) U16.G6(VTR) U16.G8(VTR_18) U16.H3(VTR_REG) U16.H8(VTR_LPC)
VCC3M_LX: PC215.2 PL202.1 PQ202.1(S1) PQ202.2(S2) PQ202.3(S3) PQ204.5(D) PR213.2 PU201.8(SW2)
VCC3M_VFB2: PR214.2 PR219.1 PU201.4(VFB2)
VCC3MP: PC218.1 PC220.1(P) PC227.1 PC231.2 PJ203.2 PL202.2 PR211.1
VCC3P: F2.2 Q1.5 R1.2 R4.2
VCC3P_DRV: C2.2 D1.1 R2.1 R3.2 U21.B5(3P_DRV)
VCC3SW: C189.2 C191.2 C192.2 C198.2 DC5.2 J11.1 PR163.2 PR164.2 PR167.2 R5.2 R116.1 R127.2 R174.2 R176.2 R177.2 R178.2 R179.2 R180.2 R254.1 R256.2 R257.2 R258.2 R259.2 R271.2 R283.2 R288.2 R427.1 R10088.2 R10089.2 R10090.2 R10198.1 RC158.1 U21.J4(VCC3SW) U191.1(VCC(A)) U191.5(DIR)
VCC3TP: F6.2 Q266.5(SOURCE) R15.2 R10320.1
VCC3TP_ON: C9487.2 D744.1 R200.2 R350.1 R10321.1 U16.M3(ADC6/GPIO206)
VCC3WAN: C125.2 C126.2 C127.2 C277.2 C278.1 J22.2(3.3VAUX1) J22.4(3.3VAUX2) J22.70(3.3VAUX3) J22.72(3.3VAUX4) J22.74(3.3VAUX5) Q30.2(G) R101.2 R385.1
VCC3WAN_DRV: C216.2 D47.1 R306.1 U21.E3(RD6_DRV)
VCC3WLAN: C128.2 C129.2 C130.2 C279.2 C280.1 C299.1 C300.1 C303.1 C304.2 C305.2 J32.2(3.3VAUX1) J32.4(3.3VAUX2) J32.72(3.3VAUX4) J32.74(3.3VAUX5) R384.1
VCC3WLAN_DRV: C215.2 D46.1 R305.1 U21.D1(RD5_DRV)
VCC5_TP: C174.2 F10.2 R220.2 R221.2 R222.2 R304.2
VCC5B: C229.1 C318.2 C333.2 F7.2 F8.2 F11.2 F14.2 F16.2 F40.2 R277.2 R304.1 R387.1 R10200.2 R10201.2 R10202.1 U7.5(VCC) U23.1(IN) U23.3(EN) U27.5(VCC)
VCC5B_DRV: C213.2 D43.1 R301.1 U21.C4(5B_DRV)
VCC5B_HDMI: C238.1 J43.18(+5V) R340.1 R341.1 U23.6(OUT)
VCC5B_NFC: F40.1 J26.19
VCC5BA: C30.2 C9141.2 R10079.2 R10202.2
VCC5M: C107.2 C108.2 C109.1 C110.1 C188.2 C195.2 C274.1 C275.2 C306.1 C307.2 C809.1 C9130.2 D37.2 PC312.1 PC450.1 PC480.1 PC529.1 PC716.2 PJ204.1 PJ712.2 PJ715.2 PR403.1 PR450.2 PR451.1 PR457.1 PR469.1 PR474.2 PR708.2 PU301.12(V5IN) PU402.7(VCCD) PU402.31(ZCD_EN) PU403.3(SMOD#) PU403.7(VCCD) PU403.31(ZCD_EN) PU405.7(VCCD) PU405.31(ZCD_EN) PU702.18(V5) Q21.1 Q21.2 Q21.3 Q21.6 Q21.7 Q21.8 U5.A11(PP_5V0_1) U5.B11(PP_5V0_2) U5.C11(PP_5V0_3) U5.D11(PP_5V0_4) U5.H10(PP_CABLE) U12.1(IN) U12.4(ILIM_SEL) U12.7(CTL2) U13.2(IN#2) U13.3(IN#3) U19.5(VCC) U20.5(VCC) U21.A5(VCC5M) U184.5(VCC) U185.5(VCC)
VCC5M_BST: PR209.2 PU201.17(VBST1)
VCC5M_DH: PQ201.4(G) PU201.16(DRVH1)
VCC5M_DL: PQ203.4(G) PU201.15(DRVL1)
VCC5M_FB1: PR215.2 PR220.2 PU201.2(VFB1)
VCC5M_LX: PC214.1 PL201.2 PQ201.1(S1) PQ201.2(S2) PQ201.3(S3) PQ203.5(D) PR212.2 PU201.18(SW1)
VCC5MP: PC210.1 PC222.1(P) PC223.1(P) PC224.1 PC225.2 PC230.2 PJ204.2 PL201.1 PR210.1 PU201.14(VO1)
VCC_SENSE: PC404.1 PC406.1 PR414.1 RC75.2 U1.E32(VCC_SENSE)
VCCCPUCORE: CC78.2 CC79.2 CC80.2 CC81.2 CC82.2 CC83.2 CC84.2 CC85.2 PC440.2 PC441.2 PC442.2 PC443.2 PC444.2 PC445.2 PC446.2 PC447.2 PC448.2 PC452.2 PC454.2 PC455.2 PC456.2 PC457.2 PC458.2 PC459.2 PC460.1(P) PC461.2 PC462.2 PL401.2 PR464.1 RC75.1 U1.A30(VCC_A30) U1.A34(VCC_A34) U1.A39(VCC_A39) U1.A44(VCC_A44) U1.AK33(VCC_AK33) U1.AK35(VCC_AK35) U1.AK37(VCC_AK37) U1.AK38(VCC_AK38) U1.AK40(VCC_AK40) U1.AL33(VCC_AL33) U1.AL37(VCC_AL37) U1.AL40(VCC_AL40) U1.AM32(VCC_AM32) U1.AM33(VCC_AM33) U1.AM35(VCC_AM35) U1.AM37(VCC_AM37) U1.AM38(VCC_AM38) U1.G30(VCC_G30) U1.G32(VCC_G32) U1.G33(VCC_G33) U1.G35(VCC_G35) U1.G37(VCC_G37) U1.G38(VCC_G38) U1.G40(VCC_G40) U1.G42(VCC_G42) U1.J30(VCC_J30) U1.J33(VCC_J33) U1.J37(VCC_J37) U1.J40(VCC_J40) U1.K33(VCC_K33) U1.K35(VCC_K35) U1.K37(VCC_K37) U1.K38(VCC_K38) U1.K40(VCC_K40) U1.K42(VCC_K42) U1.K43(VCC_K43)
VCCCPUIO: C286.2 C287.2 C288.2 C289.2 C290.2 RC1.2 RC86.2 RJ3.1 U1.AK28(VCCIO_AK28) U1.AK30(VCCIO_AK30) U1.AL30(VCCIO_AL30) U1.AL42(VCCIO_AL42) U1.AM28(VCCIO_AM28) U1.AM30(VCCIO_AM30) U1.AM42(VCCIO_AM42)
VCCCPUIO_DRV: R407.1 U21.D2(RD4_DRV)
VCCGFXCORE_I: CC86.2 CC87.2 CC88.2 CC89.2 CC90.2 CC91.2 CC92.2 CC94.2 PC472.2 PC473.2 PC474.2 PC475.2 PC476.2 PC477.2 PC478.2 PC479.2 PC481.2 PC482.2 PC483.2 PC484.2 PC485.2 PC487.1(P) PC488.2 PC489.2 PC490.2 PC491.2 PC492.2 PC493.2 PC494.2 PC495.2 PC496.2 PC497.2 PC506.2 PC507.2 PC508.2 PC510.2 PC511.2 PC512.2 PC513.2 PC514.2 PC515.2 PC516.2 PC517.2 PL402.2 PR466.1 RC88.2 U1.A48(VCCGT_A48) U1.A53(VCCGT_A53) U1.A58(VCCGT_A58) U1.A62(VCCGT_A62) U1.A66(VCCGT_A66) U1.AA63(VCCGT_AA63) U1.AA64(VCCGT_AA64) U1.AA66(VCCGT_AA66) U1.AA67(VCCGT_AA67) U1.AA69(VCCGT_AA69) U1.AA70(VCCGT_AA70) U1.AA71(VCCGT_AA71) U1.AC64(VCCGT_AC64) U1.AC65(VCCGT_AC65) U1.AC66(VCCGT_AC66) U1.AC67(VCCGT_AC67) U1.AC68(VCCGT_AC68) U1.AC69(VCCGT_AC69) U1.AC70(VCCGT_AC70) U1.AC71(VCCGT_AC71) U1.J43(VCCGT_J43) U1.J45(VCCGT_J45) U1.J46(VCCGT_J46) U1.J48(VCCGT_J48) U1.J50(VCCGT_J50) U1.J52(VCCGT_J52) U1.J53(VCCGT_J53) U1.J55(VCCGT_J55) U1.J56(VCCGT_J56) U1.J58(VCCGT_J58) U1.J60(VCCGT_J60) U1.K48(VCCGT_K48) U1.K50(VCCGT_K50) U1.K52(VCCGT_K52) U1.K53(VCCGT_K53) U1.K55(VCCGT_K55) U1.K56(VCCGT_K56) U1.K58(VCCGT_K58) U1.K60(VCCGT_K60) U1.L62(VCCGT_L62) U1.L63(VCCGT_L63) U1.L64(VCCGT_L64) U1.L65(VCCGT_L65) U1.L66(VCCGT_L66) U1.L67(VCCGT_L67) U1.L68(VCCGT_L68) U1.L69(VCCGT_L69) U1.L70(VCCGT_L70) U1.L71(VCCGT_L71) U1.M62(VCCGT_M62) U1.N63(VCCGT_N63) U1.N64(VCCGT_N64) U1.N66(VCCGT_N66) U1.N67(VCCGT_N67) U1.N69(VCCGT_N69) U1.N70(VCCGT_N70) U1.N71(VCCGT_N71) U1.R63(VCCGT_R63) U1.R64(VCCGT_R64) U1.R65(VCCGT_R65) U1.R66(VCCGT_R66) U1.R67(VCCGT_R67) U1.R68(VCCGT_R68) U1.R69(VCCGT_R69) U1.R70(VCCGT_R70) U1.R71(VCCGT_R71) U1.T62(VCCGT_T62) U1.U65(VCCGT_U65) U1.U68(VCCGT_U68) U1.U71(VCCGT_U71) U1.W63(VCCGT_W63) U1.W64(VCCGT_W64) U1.W65(VCCGT_W65) U1.W66(VCCGT_W66) U1.W67(VCCGT_W67) U1.W68(VCCGT_W68) U1.W69(VCCGT_W69) U1.W70(VCCGT_W70) U1.W71(VCCGT_W71) U1.Y62(VCCGT_Y62)
VCCGT_SENSE: PC413.2 PU401.47(VSP_2PH) RC88.1 U1.J70(VCCGT_SENSE)
VCCLAN_ON: TP40.1 U21.D9(LANON) U21.G4(RD1_ON)
VCCMPHY_GATE: CC54.2 CC55.2 CC56.2 CC57.2 R431.2 RC97.1 U1.AF20(VCCSRAM_1P0_AF20) U1.AF21(VCCSRAM_1P0_AF21) U1.N15(VCCMPHYGT_1P0_N15) U1.N16(VCCMPHYGT_1P0_N16) U1.N17(VCCMPHYGT_1P0_N17) U1.N18(VCCAPLLEBB) U1.P15(VCCMPHYGT_1P0_P15) U1.P16(VCCMPHYGT_1P0_P16) U1.T19(VCCSRAM_1P0_T19) U1.T20(VCCSRAM_1P0_T20) UC4.4(S1) UC4.5(S2)
VCCPD_VBUS: C811.1 C821.1 C822.1 C823.1 C824.1 C8333.1 D70.1 PC80.1(P) PC81.1 PF11.1 PJ4.2 PR82.1 PR95.1 PR97.1 PR99.1 PU4.2(VIN) U5.H11(VBUS_1) U5.J10(VBUS_2) U5.J11(VBUS_3) U5.K11(VBUS_4) U187.A2(OUT1) U187.A3(OUT2) U187.B2(OUT3)
VCCPD_VBUS_1: PC13.2 PJ4.1 PQ13.1(S1) PQ13.2(S2) PQ13.3(S3) PQ37.1(S1) PQ37.2(S2) PQ37.3(S3) PR20.2 PU4.5(VOUT)
VCCPD_VBUS_CONN: C502.2 JTYC1.4(VBUS_A4) JTYC1.9(VBUS_A9) JTYC1.16(VBUS_B4) JTYC1.21(VBUS_B9) R508.1 U187.B3(IN1) U187.C2(IN2) U187.C3(IN3)
VCCRE: C77.2 C78.2 C79.2 C90.2 C91.2 C92.2 C272.1 C273.1 R342.2 R343.2 R344.2 R345.2 R351.1 R354.2 R355.2 R356.2 R357.2 R358.2 R359.2 R365.2 R383.1 U24.6(VDD1) U24.15(VDD2) U25.6(VDD1) U25.15(VDD2)
VCCSA: CC93.2 CC95.2 CC96.2 CC97.2 PC530.2 PC531.2 PC532.2 PC533.2 PC534.2 PC535.2 PC537.2 PC538.2 PC539.2 PC540.2 PL404.2 PR468.1 RC87.2 U1.AK23(VCCSA_AK23) U1.AK25(VCCSA_AK25) U1.G23(VCCSA_G23) U1.G25(VCCSA_G25) U1.G27(VCCSA_G27) U1.G28(VCCSA_G28) U1.J22(VCCSA_J22) U1.J23(VCCSA_J23) U1.J27(VCCSA_J27) U1.K23(VCCSA_K23) U1.K25(VCCSA_K25) U1.K27(VCCSA_K27) U1.K28(VCCSA_K28) U1.K30(VCCSA_K30)
VCCSA_SENSE: PC424.1 PC426.2 PR435.1 RC87.1 U1.H20(VCCSA_SENSE)
VCCST: C293.1 PC401.1 PR401.1 PR404.1 Q34.A2(OUT) RC15.2 RC76.1 RC77.2 RC85.1 RC110.2 RC161.2 U16.B11(VREF_VTT)
VCCST_CPU: CC28.2 CC30.2 RC85.2 U1.A18(VCCST) U1.K20(VCCPLL_K20) U1.K21(VCCPLL_K21)
VCCST_PWRGD: QC3.1(D) RC73.1 U1.B65(VCCST_PWRGD)
VCCSTG: C294.1 Q35.A2(OUT) Q199.2(BASE) RC14.2 RC74.1 RC112.2 RC138.1 RC139.1
VCCSTG_CPU: CC29.2 RC74.2 U1.A22(VCCSTG_A22) U1.G20(VCCSTG_G20)
VDD10: C196.2 C201.2 D36.1 U21.A2(VDD10)
VDDA: PC165.1 PR136.2 PR147.2 PR154.2 PR168.1 PU101.7(VDDA)
VDDPALW_PWRGD: PR738.2 PR749.1 PU702.1(PGOOD)
VDDSPD: CD30.1 CD31.2 J21.255(VDDSPD) RD12.2
VINT20_IN: PC14.1 PC15.1 PC16.2 PC138.1 PC149.1 PC151.1 PC163.1 PL102.2 PL103.2 PR25.2 PR92.2 PR158.1 PR196.2
VSS_SENSE: PC406.2 PC407.1 PR415.1 RC82.1 U1.E33(VSS_SENSE)
VSSGT_SENSE: PC413.1 PC416.1 PR424.1 RC92.1 U1.J69(VSSGT_SENSE)
VSSSA_SENSE: PC426.1 PC427.1 PR438.1 RC91.2 U1.H21(VSSSA_SENSE)
1R2A_BST: PR309.1 PU301.15(VBST)
1R2A_LG: PQ302.4(G) PU301.11(DRVL)
1R2A_LX: PC311.2 PL301.1 PQ301.1(S1) PQ301.2(S2) PQ301.3(S3) PQ302.5(D) PR311.2 PU301.13(SW)
1R2A_SW: PC314.1(P) PC316.1 PC317.1 PJ302.2 PJ303.2 PL301.2 PU301.2(VLDOIN) PU301.9(VDDQSNS)
1R2A_UG: PQ301.4(G) PU301.14(DRVH)
2R5A_PWRGD: PR306.1 PR751.1 PU701.4(PG)
3FP_DRV: C180.2 R231.2 U21.D3(RD3_DRV)
3FP_ON: C181.2 D31.2 R232.2 U21.J5(RD3_ON)
5M_3M_PWRG: D714.1 PR222.2 R307.1
+VTT_REFP: PC305.1 PU301.5(VTTREF)
-AOU_IFLG: R158.1 U12.9(STATUS#) U16.H9(GPIO025/UART_CLK)
-BATLOW: R206.2 U1.AU13(GPD0/BATLOW#) U16.C1(BGPO0)
-BEEP_ENABLE: Q228.2(G) R124.2 TP15.1 U16.K5(GPIO166)
-CHG_PROCHOT: Q199.1(COLLECTOR) R2574.1 U16.H7(GPIO223)
-CL_RST_WLAN: J32.38(RESERVED1) RC23.1 U1.G1(CL_RST#)
-CLKREQ_DEVSLP: J1.23 Q5.3(S) R426.1 U7.1(A)
-CLKREQ_PCIE0: R112.1 U1.AR10(GPP_B5/SRCCLKREQ0#) U15.2(CLK_REQ#)
-CLKREQ_PCIE1: J32.68(CLKREQ1#) R108.1 U1.AT7(GPP_B6/SRCCLKREQ1#)
-CLKREQ_PCIE2: J32.53(CLKREQ0#) R370.1 U1.AT8(GPP_B7/SRCCLKREQ2#)
-CLKREQ_PCIE3: RL1.1 U1.AT10(GPP_B8/SRCCLKREQ3#) UL1.48(CLK_REQ_N)
-CLKREQ_PCIE4: Q5.1(D) R52.1 R426.2 U1.AU8(GPP_B9/SRCCLKREQ4#)
-CLKREQ_PCIE5: J22.52(CLKREQ#) R2746.1 U1.AU7(GPP_B10/SRCCLKREQ5#)
-CLKRUN: J5.7 RC29.1 U1.AW11(GPP_A8/CLKRUN#) U16.L5(CLKRUN#)
-DCIN_PWR_DTCT: D709.1 PR166.1
-DOCK_ATTACHD_20: D707.2 PR2.1
-DOCK_ATTACHED_3M: D25.3 R120.1 R208.1 TP11.1 U16.B10(GPIO150/JTAG_TMS)
-DOCK_ATTACHED_AUX: D25.2 R91.1 U14.13(SEL)
-DOCK_CAP_ID: R1119.2 U1.V1(GPP_D21/SPI1_IO2)
-DOCK_HP_DCT: J17.59(DOCK_MICIN_DCT#) Q175.2(IN) R1868.1
-DOCK_MIC_DCT: CA73.2 J17.58(DOCK_HPOUT_DCT#) QA8.2(IN) R951.1
-DOCK_PWR_DTCT: C9197.2 D708.1 J17.54(#DOCK_PWRDCT)
-DOCK_PWR_DTCT_R: D708.2 R440.1 U16.K1(ADC1/GPIO201)
-DOCKED0: J17.1(DOCKED0#) J17.35(DOCKED1#)
-DRAMRST: CD29.2 J21.108(RESET_N) RC154.2
-EC_RESET: R134.1 U16.F1(RESETI#) U21.B6(EC_RST#)
-EC_SCI: RC33.1 U1.AD3(GPP_C22/UART2_RTS#) U16.K6(EC_SCI#)
-EC_SLP_LAN: R192.2 U16.N4(ADC15/GPIO217) U21.G6(SLP_LAN#)
-EC_WAKE: RC32.1 U1.AD4(GPP_C23/UART2_CTS#) U16.N7(SMI#)
-ECSPI_SS: R263.2 U16.L10(SPI_CS#)
-ECSPI_SS_R: R263.1 R269.2 U21.G8(SPISS#)
-EXT_PWR_GATE: RC155.1 U1.AM10(GPP_B11/EXT_PWR_GATE#)
-EXTPWR: D28.1 PC128.1 PQ106.1(D) PR164.1 Q16.3(S)
-EXTPWR_ASIC: Q16.1(D) R254.2 U21.F5(EXTPWR#)
-FLT_REPORT: R439.2 U193.9(\\F\L\T)
-HDA_RST: RA124.2 RC42.1 UA1.15(AUDIOLINK_RESETO/MCLK)
-HDA_RST_R: RC42.2 U1.AW22(HDA_RST#/I2S1_SCLK)
-HDD_DTCT: C302.2 J1.20 R176.1 U16.D2(VCI_IN0#/GPIO163)
-HOTKEY: C852.2 J38.29 R127.1 U16.C2(VCI_IN2#/GPIO161)
-INT_MIC_DTCT: J11.6 U1.AH12(GPP_F7/I2C3_SCL)
-INTRUDER: CC17.2 DC1.1 RC62.1 RC71.2 U1.AP16(INTRUDER#)
-INTRUDER_EC: DC1.2 R177.1 U16.G1(VCI_IN1#/GPIO162)
-JTAG_RST: C173.2 R181.1 R182.2 U16.A10(JTAG_RST#)
-KBD_BL_DTCT: J37.9 R125.2 U16.A6(GPIO036)
-KBRC: R126.1 U1.AW13(GPP_A0/RCIN#) U16.J5(KBRST)
-LANWAKE: RC70.2 U1.AM15(GPD2/LAN_WAKE#) UL1.2(LANWAKE_N)
-LED_CAPSLOCK: R404.1 U16.H2(GPIO221)
-LED_FNLOCK: R225.1 U16.F6(GPIO034)
-LED_LOGO: R10.1 U16.A4(LED0/GPIO156)
-LED_MICMUTE: R223.1 U16.C3(GPIO024)
-LED_MUTE: R224.1 U16.D12(GPIO035)
-LED_PWR: R7.1 U16.F5(LED1/GPIO157)
-LID_CLOSE: C21.2 C269.2 D2.1 J11.2 R5.1 R393.1
-LPC_FRAME: J5.5 U1.BA12(GPP_A5/LFRAME#/ESPI_CS#) U16.L6(LFRAME#)
-M_A_CAS: J21.156(A15/CAS_N) U1.AU48(DDR0_CAS#/DDR0_CAB[1]/DDR0_MA[1)
-M_A_CS0: J21.149(CS0_N) U1.AU45(DDR0_CS#[0])
-M_A_CS1: J21.157(CS1_N) U1.AU43(DDR0_CS#[1])
-M_A_DDRCLK0_1866M: J21.139(CK0_C) U1.AU53(DDR0_CKN[0])
-M_A_DDRCLK1_1866M: J21.140(CK1_C/NF) U1.AU55(DDR0_CKN[1])
-M_A_DQS0: J21.11(DQS0_C) U1.AM70(DDR0_DQSN[0])
-M_A_DQS1: J21.32(DQS1_C) U1.AT69(DDR0_DQSN[1])
-M_A_DQS2: J21.198(DQS5_C) U1.AH66(DDR1_DQSN[0]/DDR0_DQSN[2])
-M_A_DQS3: J21.177(DQS4_C) U1.AG69(DDR1_DQSN[1]/DDR0_DQSN[3])
-M_A_DQS4: J21.53(DQS2_C) U1.BA64(DDR0_DQSN[2]/DDR0_DQSN[4])
-M_A_DQS5: J21.74(DQS3_C) U1.AY60(DDR0_DQSN[3]/DDR0_DQSN[5])
-M_A_DQS6: J21.219(DQS6_C) U1.AR66(DDR1_DQSN[2]/DDR0_DQSN[6])
-M_A_DQS7: J21.240(DQS7_C) U1.AR61(DDR1_DQSN[3]/DDR0_DQSN[7])
-M_A_DQS8: J21.95(DQS8_C) TP30.1
-M_A_ODT0: J21.155(ODT0) U1.AT45(DDR0_ODT[0])
-M_A_ODT1: J21.161(ODT1) U1.AT43(DDR0_ODT[1])
-M_A_RAS: J21.152(A16/RAS_N) U1.AU50(DDR0_RAS#/DDR0_CAB[3]/DDR0_MA[1)
-M_A_WE: J21.151(A14/WE_N) U1.AT46(DDR0_WE#/DDR0_CAB[2]/DDR0_MA[14)
-MIC_HW_EN: RC35.2 RC152.1 U1.AH11(GPP_F6/I2C3_SDA)
-NFC_DTCT: J26.7 R394.2 U1.V2(GPP_D22/SPI1_IO3)
-PAD_RESET: C157.1 J16.17 R375.2 U16.J7(GPIO052)
-PCH_SLP_LAN: R201.2 RC64.1 U1.AW15(SLP_LAN#) U16.F10(GPIO135)
-PCH_SLP_M: J41.6(SLP_A#) TP47.1 U1.AN16(GPD6/SLP_A#) U21.F6(SLP_M#)
-PCH_SLP_S0: D63.1 J41.15(SLP_S0#) TP45.1 U1.AT11(GPP_B12/SLP_S0#)
-PCH_SLP_S3: D60.1 D65.1 J41.2(SLP_S3#) TP42.1 U1.AP15(GPD4/SLP_S3#) U16.G11(GPIO110) U21.H7(SLP_S3#)
-PCH_SLP_S4: J41.5(SLP_S4#) PR302.1 TP48.1 U1.BA16(GPD5/SLP_S4#) U16.G12(GPIO111) U21.J7(SLP_S4#)
-PCH_SLP_S5: J41.4(SLP_S5#) TP43.1 U1.AY16(GPD10/SLP_S5#) U21.J8(SLP_S5#)
-PCH_SLP_SUS: U1.AN15(SLP_SUS#) U16.K12(GPIO140/SMB06_CLK)
-PCH_SLP_WLAN: U1.BB17(GPD9/SLP_WLAN#) U16.A12(GPIO043)
-PCIE0_CLK_100M: U1.D42(CLKOUT_PCIE_N0) U15.6(REFCLKN)
-PCIE1_CLK_100M: J32.73(REFCLKN1) U1.B42(CLKOUT_PCIE_N1)
-PCIE2_CLK_100M: J32.49(REFCLKN0) U1.D41(CLKOUT_PCIE_N2)
-PCIE3_CLK_100M: U1.D40(CLKOUT_PCIE_N3) UL1.45(PE_CLKN)
-PCIE4_CLK_100M: J1.39 U1.B40(CLKOUT_PCIE_N4)
-PCIE5_CLK_100M: J22.53(REFCLKN) U1.E40(CLKOUT_PCIE_N5)
-PCIE_WAKE: J32.55(PEWAKE0#) J32.70(PEWAKE1#) RC69.2 U1.BB15(WAKE#) U21.F7(PME#)
-PE_DTCT: Q4.1(COLLECTOR) Q29.2(G) Q36.2(G) RC47.1 U1.H3(GPP_E1/SATAXPCIE1/SATAGP1) U7.4(OE)
-PLTRST: U1.AN10(GPP_B13/PLTRST#) UC3.2(IN_A)
-PLTRST_FAR: C260.2 CC15.1 J32.52(PERST0#) J32.66(PERST1#) R435.1 R2750.1 RC60.1 U16.M5(LRESET#) U21.A7(PLTRST#) U26.17(RST#) U27.1(A) UL1.36(PE_RST_N)
-PLTRST_FAR_HDD: J1.24 R435.2 U27.2(B)
-PLTRST_FAR_WWAN: J22.50(PERST#) R2750.2
-PLTRST_NEAR: CC14.1 J5.11 RC59.1 U15.1(PERST#)
-PROCHOT: PR142.1 PR410.2 Q199.3(EMITTER) R392.2 RC14.1 RC16.1
-PROCHOT_R: RC16.2 U1.C65(PROCHOT#)
-PWRON_DOCK: J17.52(DOCK_PWRON#) U21.B8(PWRON_DOCK#)
-PWRSHUTDOWN: PQ5.2(G) PQ105.2(G) PQ109.2(G) R283.1 R289.1 U21.D8(PWRSHUTDWN#)
-PWRSW: D34.2 R270.1 U16.D7(GPIO127/A20M)
-PWRSW_ASIC: C193.1 D35.2 R271.1 U21.F8(PWRSW#)
-PWRSW_EC: U1.BA15(GPD3/PWRBTN#) U16.G2(GPIO106)
-PWRSWITCH: D34.1 D35.1 J5.2 J11.27 J17.65(DOCK_PWR_SW#) J41.11(PWRBTN#) TP49.1
-REAR_EJECT_LEVER: R131.1 R414.2 S2.1 S2.2 U16.G7(GPIO224)
-RSMRST: Q40.1(D) R430.1 RC118.1 U1.AY17(RSMRST#)
-RSMRST_EC: R146.2 R430.2 U16.E3(BGPO3/GPIO172)
-RTCRST: CC70.1 J41.9(RTCRST#) RC123.2 TP44.1 U1.AM16(RTCRST#)
-SC_DTCT: J26.10 U1.AF13(GPP_F23)
-SD_MMC_CD: J23.10(CD) U15.30(SD_CD#)
-SHUTDOWN: Q8.1(OUT) R288.1 R289.2 U21.D7(SHUTDWNIN#)
-SPI_CS0: RC128.1 U1.AU3(SPI0_CS0#)
-SPI_CS0_R: RC125.1 RC128.2 UC5.1(/CS)
-SPI_CS2: R240.1 R434.2 U1.AU1(SPI0_CS2#)
-SPI_CS2_R: R238.2 R240.2 U26.20(CS#)
-SPK_MUTE: R144.1 R908.2 TP10.1 UA1.52(EAPD+PD#/GPIO11)
-SRTCRST: CC71.1 RC124.2 U1.AN18(SRTCRST#)
-SUS_STAT: J5.14 U1.BA11(GPP_A14/SUS_STAT#/ESPI_RESET#) U16.H6(LPCPD#)
-SUSWARN: RC68.1 U1.AR13(GPP_A13/SUSWARN#/SUSPWRDNACK)
-SVID_ALERT: PR409.1 RC76.2 RC79.1
-SVID_ALERT_R: RC79.2 U1.B63(VIDALERT#)
-THRM: R164.1 R166.1 R169.2
-TPM_IRQ: R396.1 RC153.1 U1.BB11(GPP_A7/PIRQA#)
-TPM_IRQ_R: R396.2 R397.2 U26.18(PIRQ#)
-USB_PORT0_OC0: RC44.1 U1.A9(GPP_E9/USB2_OC0#) U12.13(FAULT#)
-USB_PORT1_OC1: RC45.1 U1.C9(GPP_E10/USB2_OC1#) U13.5(OC#)
-USB_PORT2_OC2: RC135.1 U1.D9(GPP_E11/USB2_OC2#)
-WIGIG_RF_KILL: J32.56(W_DISABLE#1) R209.1 TP6.1 U16.C10(GPIO147/JTAG_CLK)
-WWAN_DISABLE: J22.8(W_DISABLE#1) R210.1 TP12.1 U16.A11(GPIO146/JTAG_TDO)
-WWAN_PE_DTCT: R2745.1 U1.G4(GPP_E2/SATAXPCIE2/SATAGP2) U163.4(B)
-WWAN_RESET: Q30.1(D) R408.2 U1.AH9(GPP_F4/I2C2_SDA)
-WWAN_SSD_DTCT: Q263.1(D) R178.1 R602.1 U16.B1(VCI_IN4#/GPIO234)
-XDP_DBR: J8.18 J41.13(SYS_RESET#) RC111.1 RC164.1 TP46.1 U1.B5(SYS_RESET#)
-XDP_PRDY: J8.2 U1.D56(PROC_PRDY#)
-XDP_PREQ: J8.1 U1.D61(PROC_PREQ#)
-XDP_TRST: J8.21 RC137.1 U1.B59(PROC_TRST#) U1.C61(PCH_TRST#)
A_ON: PD301.1 PR750.2 R457.1 TP38.1 U21.F9(AON)
AC_PRESENT: R151.1 U1.AY15(GPD1/ACPRESENT) U16.E2(GPIO022)
ACDC_ID: PD4.2 PD5.1 PR17.2 U16.L2(ADC2/GPIO202)
ACDC_ID_DOCK: J17.47(DOCK_ACDC_ID) PC5.1 PC17.1 PC28.1 PJ1.5 PQ11.1(S1) PR16.1 PR17.1
ADAPTER_ID_ON#: PQ11.5(G2) R184.2 U16.N10(GPIO056/PWM3)
ADDR_SEL: R234.1 R236.2 U17.7(SDO/ADDR)
AOU_SEL1: R152.1 U12.6(CTL1) U16.M10(GPIO015/PWM7)
AOU_SEL2: R154.1 U12.8(CTL3) U16.L8(GPIO016)
B_DRV: C256.2 D58.1 R373.1 R406.1 R437.2
B_DRV_R: R437.1 U21.F3(RD7_DRV)
B_ON: D62.1 D64.1 J5.13 R205.2 U16.N11(GPIO014/PWM6) U21.E9(BON)
BACKLIGHT_ON: C19.2 J10.23 R4.1 U16.A8(GPIO144/SMB04_CLK)
BAT-PWR: PC141.2 PC153.1 PQ18.5(D) PQ20.5(D) PR151.2 PR155.2
BAT_CRG: R436.2 TP84.1 U21.B7(BATCRG)
BATDRV#: PR170.1 PU101.21(BATDRV#)
BDC_ON: J32.54(RESERVED/W_DISABLE#2) R211.1 TP7.1 U16.C11(GPIO145/JTAG_TDI)
BEEP_MIX_ATT: C2503.1 Q228.1(D) R66.2 R67.1
BPWRG: C207.2 D714.2 Q8.2(IN) R284.1 R324.1 RC65.1 U16.F3(VCC_PWRGD) U19.4(OE) U20.4(OE) U21.D5(B_PGS) U184.4(OE) U185.4(OE)
BYPASS_PAD: J16.5 R374.2 U16.C12(GPIO134)
CACHE_DTCT: D705.2 R2747.1 U163.5(OE)
CACHE_DTCT_SW: D705.1 Q226.1(D) Q227.1(D) Q263.2(G) R10090.1
CFG3: J8.8 RC101.2 U1.D67(CFG[3])
CFG_RCOMP: RC103.2 U1.E60(CFG_RCOMP)
CH_AGND: PC128.2 PC131.1 PC133.1 PC137.2 PC139.1 PC144.2 PC148.1 PC152.1 PC155.2 PC157.2 PC158.2 PC164.2 PC165.2 PC166.2 PQ105.3(S) PQ106.3(S) PQ107.3(S) PR101.1 PR135.2 PR140.1 PR145.1 PR150.1 PR162.1 PR190.2 PU101.27(PGND)
CL_CLK_WLAN: J32.42(RESERVED3) U1.G3(CL_CLK)
CL_DATA_WLAN: J32.40(RESERVED2) U1.G2(CL_DATA)
CLKREQ_SLECTE: Q5.2(G) Q36.1(D) R409.1 U27.4(OE)
COEX1: J32.48(COEX1) R425.2
COEX2: J32.46(COEX2) R424.2
COEX3: J32.44(COEX3) R423.2
CPU_PWRGD: TP41.1 U1.A68(PROCPWRGD)
CPUCORE_ON: D59.2 D60.2 PR406.1 QC2.2(G) R382.1
CPUCORE_ON_ASIC: D59.1 U21.E6(CPUON)
CPUCORE_PWRGD: PR477.2 RC66.1
CPUCORE_PWRGD_R: PR405.2 PR477.1 PU401.38(VR_RDY)
CSN1: PR423.1 PR466.2
CSN_1A: PC405.2 PC433.2 PR464.2 PRT401.2 PU401.28(CSN_1A)
CSN_1B: PC430.2 PC434.1 PR468.2 PRT405.2 PU401.41(CSN_1B)
CSP1: PR421.2 PR427.2 PR465.2
CTL0: R572.2 R574.2 U5.B2(GPIO0)
CTL1: R573.2 U5.G11(GPIO3)
CV20: PQ6.5(D) PQ7.5(D)
DAV12: C140.2 C141.2 C142.2 U15.10(AV12) U15.14(DV12S)
DCIN_ID_ON: PQ11.2(G1) PQ11.3(D2) PR18.2 PR19.1
DCIN_PWR: PC3.2 PC6.1 PC7.1 PC8.1 PF2.1 PJ1.3 PJ1.4 PQ2.1(S1) PQ2.2(S2) PQ2.3(S3) PR1.1
DCIN_PWR20_F: PC9.2 PC10.2 PD102.2 PF2.2 PF6.1 PQ6.1(S1) PQ6.2(S2) PQ6.3(S3) PQ8.3(GND) PR8.2 PR14.2 PR18.1 PR152.2
DDI_PRIORITY1: R2500.1 U1.D8(GPP_D17/DMIC_CLK1) U147.5(SW0)
DDI_PRIORITY2: R532.1 R2526.1 U1.C8(GPP_D18/DMIC_DATA1) U147.4(SW1)
DDIP1_0N: C8346.1 U1.E55(DDI1_TXN[0])
DDIP1_0N_TYPEC: C8346.2 U183.10(ML0N)
DDIP1_0P: C8342.1 U1.F55(DDI1_TXP[0])
DDIP1_0P_TYPEC: C8342.2 U183.9(ML0P)
DDIP1_1N: C8353.1 U1.E58(DDI1_TXN[1])
DDIP1_1N_TYPEC: C8353.2 U183.13(ML1N)
DDIP1_1P: C8352.1 U1.F58(DDI1_TXP[1])
DDIP1_1P_TYPEC: C8352.2 U183.12(ML1P)
DDIP1_2N: C8351.1 U1.F53(DDI1_TXN[2])
DDIP1_2N_TYPEC: C8351.2 U183.16(ML2N)
DDIP1_2P: C8350.1 U1.G53(DDI1_TXP[2])
DDIP1_2P_TYPEC: C8350.2 U183.15(ML2P)
DDIP1_3N: C8344.1 U1.F56(DDI1_TXN[3])
DDIP1_3N_TYPEC: C8344.2 U183.19(ML3N)
DDIP1_3P: C8343.1 U1.G56(DDI1_TXP[3])
DDIP1_3P_TYPEC: C8343.2 U183.18(ML3P)
DDIP1_AUXN: C8355.1 U1.G50(DDI1_AUXN)
DDIP1_AUXN_TYPEC: C8355.2 R9084.2 U183.25(AUXN)
DDIP1_AUXP: C8354.1 U1.F50(DDI1_AUXP)
DDIP1_AUXP_TYPEC: C8354.2 R9085.2 U183.24(AUXP)
DDIP1_CTRLCLK: TP80.1 U1.L13(GPP_E18/DDPB_CTRLCLK)
DDIP1_CTRLDATA: RC117.1 U1.L12(GPP_E19/DDPB_CTRLDATA)
DDIP1_HPD: R725.1 R9095.2 RC162.1 U1.L9(GPP_E13/DDPB_HPD0)
DDIP2_0N: C2523.1 U1.C50(DDI2_TXN[0])
DDIP2_0N_C: C2523.2 U147.12(IN_D0N)
DDIP2_0P: C2522.1 U1.D50(DDI2_TXP[0])
DDIP2_0P_C: C2522.2 U147.11(IN_D0P)
DDIP2_1N: C2525.1 U1.C52(DDI2_TXN[1])
DDIP2_1N_C: C2525.2 U147.15(IN_D1N)
DDIP2_1P: C2524.1 U1.D52(DDI2_TXP[1])
DDIP2_1P_C: C2524.2 U147.14(IN_D1P)
DDIP2_2N: C2527.1 U1.A50(DDI2_TXN[2])
DDIP2_2N_C: C2527.2 U147.17(IN_D2N)
DDIP2_2P: C2526.1 U1.B50(DDI2_TXP[2])
DDIP2_2P_C: C2526.2 U147.16(IN_D2P)
DDIP2_3N: C2529.1 U1.D51(DDI2_TXN[3])
DDIP2_3N_C: C2529.2 U147.20(IN_D3N)
DDIP2_3P: C2528.1 U1.C51(DDI2_TXP[3])
DDIP2_3P_C: C2528.2 U147.19(IN_D3P)
DDIP2_AUXN: C2531.1 U1.E48(DDI2_AUXN)
DDIP2_AUXN_C: C2531.2 R9129.2 U147.63(IN_AUXN)
DDIP2_AUXP: C2530.1 U1.F48(DDI2_AUXP)
DDIP2_AUXP_C: C2530.2 U147.64(IN_AUXP)
DDIP2_CTRLCLK: R2378.1 U1.N7(GPP_E20/DDPC_CTRLCLK) U147.66(IN_DDC_SCL)
DDIP2_CTRLDATA: R2379.1 U1.N8(GPP_E21/DDPC_CTRLDATA) U147.65(IN_DDC_SDA)
DDIP2_HPD: RC5.1 U1.L7(GPP_E14/DDPC_HPD1) U147.7(IN_HPD)
DDR4_VREF_CA: CD25.2 CD27.1 CD28.2 J21.164(VREFCA) RD7.2 RD8.2 RD9.2
DDR4_VREF_CA_M3: CD26.2 RD8.1 U1.AY67(DDR_VREF_CA)
DDR_PG_CTRL: QC1.3(EMITTER) RC9.2 U1.AW67(DDR_VTT_CNTL) U36.2(A)
DDR_VREF: PC306.1 PR307.1 PU301.6(VREF)
DDR_VTT_PG_CTRL: PR301.1 QC1.1(COLLECTOR) RC8.1 RC169.1 U36.4(Y)
DH2_CHG: PR161.1 PU101.24(HIDRV2)
DISCHARGE: PQ9.2(G) PQ41.2(G) PQ104.2(G) R265.2 U21.E4(PGPIO4) U21.J6(DISCHARGE)
DL1_CHG: PQ111.4(G) PU101.29(LODRV1)
DL2_CHG: PQ113.4(G) PU101.26(LODRV2)
DMIC_CLK: C500.1 J11.4 R677.2
DMIC_DATA: J11.5 UA1.54(DMIC-DATA1)
DN1_DP4: C160.1 C161.2 C255.2 Q9.1(COLLECTOR) Q9.2(BASE) Q25.3(EMITTER) U16.F13(DN1_DP4)
DN2_DP5: C162.1 C163.2 C164.2 Q10.1(COLLECTOR) Q10.2(BASE) Q11.3(EMITTER) U16.D13(DN2_DP5)
DN3_DP6: C165.1 C166.2 C167.2 Q12.1(COLLECTOR) Q12.2(BASE) Q13.3(EMITTER) U16.B13(DN3_DP6)
DOCK_CONSUMP: J17.46(DOCK_CONSUMP) PR165.2
DOCK_DCIN20: J17.67(DOCK_DCIN20) PF5.1
DOCK_DDIP2_0N: C150.1 U147.54(DP1_D0N)
DOCK_DDIP2_0P: C152.1 U147.55(DP1_D0P)
DOCK_DDIP2_1N: C148.1 U147.51(DP1_D1N)
DOCK_DDIP2_1P: C149.1 U147.52(DP1_D1P)
DOCK_DDIP2_2N: C146.1 U147.49(DP1_D2N)
DOCK_DDIP2_2P: C147.1 U147.50(DP1_D2P)
DOCK_DDIP2_3N: C144.1 U147.46(DP1_D3N)
DOCK_DDIP2_3P: C145.1 U147.47(DP1_D3P)
DOCK_DDIP2_AUXN: J17.21(DOCK_DP0_AUXN) R117.2 U147.61(DP1_AUXN_SDA)
DOCK_DDIP2_AUXP: J17.22(DOCK_DP0_AUXP) R118.1 U147.62(DP1_AUXP_SCL)
DOCK_DDIP2_HPD: J17.16(DOCK_DP0_HPD) U147.53(DP1_HPD)
DOCK_DP0N: C150.2 J17.33(DOCK_DP0_LANE0N)
DOCK_DP0P: C152.2 J17.34(DOCK_DP0_LANE0P)
DOCK_DP1N: C148.2 J17.30(DOCK_DP0_LANE1N)
DOCK_DP1P: C149.2 J17.31(DOCK_DP0_LANE1P)
DOCK_DP2N: C146.2 J17.27(DOCK_DP0_LANE2N)
DOCK_DP2P: C147.2 J17.28(DOCK_DP0_LANE2P)
DOCK_DP3N: C144.2 J17.24(DOCK_DP0_LANE3N)
DOCK_DP3P: C145.2 J17.25(DOCK_DP0_LANE3P)
DOCK_HP_JD: Q197.1(D) R319.1
DOCK_I2S_BCLK: J17.61(DOCK_I2S_BCLK) R1236.2
DOCK_I2S_LRCLK: J17.60(DOCK_I2S_LRCLK) R1238.2
DOCK_I2S_MCLK: J17.64(DOCK_I2S_MCLK) R1235.2
DOCK_I2S_SD_I: J17.63(DOCK_I2S_SD_I) R1239.2 UA1.5(GPIO5/I2S-IN)
DOCK_I2S_SD_O: J17.62(DOCK_I2S_SD_O) R1237.2
DOCK_MDI_0+: J17.2(DOCK_MDI_0P) U14.24(B3-)
DOCK_MDI_0-: J17.3(DOCK_MDI_0N) U14.25(B3+)
DOCK_MDI_1+: J17.5(DOCK_MDI_1P) U14.28(B2-)
DOCK_MDI_1-: J17.6(DOCK_MDI_1N) U14.29(B2+)
DOCK_MDI_2+: J17.8(DOCK_MDI_2P) U14.33(B1-)
DOCK_MDI_2-: J17.9(DOCK_MDI_2N) U14.34(B1+)
DOCK_MDI_3+: J17.11(DOCK_MDI_3P) U14.37(B0-)
DOCK_MDI_3-: J17.12(DOCK_MDI_3N) U14.38(B0+)
DOCK_MIC_EN: QA8.1(OUT) R46.1 RA50.1
DOCK_MIC_JD: QA7.1(D) RA290.1
DOCK_PWR20_IN: J17.71(PWR20) PC4.2 PQ2.5(D)
DOCKID0: J17.48(DOCK_ID0) U1.M1(GPP_D0/SPI1_CS#)
DOCKID1: J17.49(DOCK_ID1) U1.M2(GPP_D1/SPI1_CLK)
DOCKID2: J17.50(DOCK_ID2) U1.M3(GPP_D2/SPI1_MISO)
DOCKID3: J17.51(DOCK_ID3) U1.J4(GPP_D3/SPI1_MOSI)
DP1_DN4: C160.2 C161.1 C255.1 Q9.3(EMITTER) Q25.1(COLLECTOR) Q25.2(BASE) U16.G13(DP1_DN4)
DP2_DN5: C162.2 C163.1 C164.1 Q10.3(EMITTER) Q11.1(COLLECTOR) Q11.2(BASE) U16.E13(DP2_DN5)
DP3_DN6: C165.2 C166.1 C167.1 Q12.3(EMITTER) Q13.1(COLLECTOR) Q13.2(BASE) U16.C13(DP3_DN6)
DRV0: J38.7 U16.L11(KSO0)
DRV1: J38.13 U16.B7(KSO1)
DRV2: J38.11 U16.E6(KSO2)
DRV3: J38.14 U16.B6(KSO3)
DRV4: J38.10 U16.H12(KSO4)
DRV5: J38.17 U16.G10(KSO5)
DRV6: J38.15 U16.G9(KSO6)
DRV7: J38.16 U16.H13(KSO7)
DRV8: J38.23 U16.C6(KSO8)
DRV9: J38.20 U16.C7(KSO9)
DRV10: J38.22 U16.B5(KSO10)
DRV11: J38.24 U16.H10(KSO11)
DRV12: J38.21 U16.H11(KSO12)
DRV13: J38.19 U16.A5(KSO13)
DRV14: J38.4 U16.L13(KSO14)
DRV15: J38.18 U16.N12(KSO15)
DRV16: R130.2 U16.M11(KSO16/GPIO152)
DRV17: R132.2 U16.D5(KSO17/GPIO175)
DRVON: PR474.1 PR475.2 PU402.2(DISB#) PU403.2(DISB#) PU405.2(DISB#)
DSWPWROK: RC67.2 U1.BB20(DSW_PWROK)
EC_PWRREQ: R207.2 U16.D1(VCI_OUT) U21.C7(PGPIO1)
EC_SCL2: R167.2 RC27.1 U1.W3(GPP_C6/SML1CLK)
EC_SDA2: R165.2 RC28.1 U1.V3(GPP_C7/SML1DATA)
EC_SPKR: D740.2 R490.1 U16.J8(PWM2/GPIO055)
ECSPI_CLK: R261.2 U16.J9(SPI_CLK)
ECSPI_CLK_R: C259.1 R261.1 R268.2 U21.H9(SPICLK)
ECSPI_MISO: R264.2 U16.K8(SPI_MISO)
ECSPI_MISO_R: R264.1 U21.G7(SPIMISO)
ECSPI_MOSI: R262.2 U16.K9(SPI_MOSI)
ECSPI_MOSI_R: R262.1 U21.H8(SPIMOSI)
EDP_AUXN: C9.1 U1.E45(EDP_AUXN)
EDP_AUXN_CONN: C9.2 J10.10
EDP_AUXP: C10.1 U1.F45(EDP_AUXP)
EDP_AUXP_CONN: C10.2 J10.9
EDP_COMP: RC1.1 U1.E52(EDP_RCOMP)
EDP_HPD: J10.18 RC4.1 U1.L10(GPP_E17/EDP_HPD)
EDP_TXN0: C12.1 U1.C47(EDP_TXN[0])
EDP_TXN0_CONN: C12.2 J10.6
EDP_TXN1: C14.1 U1.D46(EDP_TXN[1])
EDP_TXN1_CONN: C14.2 J10.3
EDP_TXP0: C11.1 U1.C46(EDP_TXP[0])
EDP_TXP0_CONN: C11.2 J10.7
EDP_TXP1: C13.1 U1.C45(EDP_TXP[1])
EDP_TXP1_CONN: C13.2 J10.4
EN_+1.8VS: PC794.1 PD701.2 PR718.1 PR762.1 PU706.5(EN)
FAN_FRQ: J15.2 U16.D6(FAN_TACH0/GPIO050)
FAN_ID: J15.1 R159.1 U16.M1(ADC3/GPIO203)
FAN_ON: J15.5 U16.N9(PWM1/GPIO054)
FLIP: R571.2 R576.2 U5.G10(GPIO6)
GSENSE_INT: U16.K2(ADC9/GPIO211) U17.11(INT1)
HDA_BCLK: CC5.1 RA163.1 RC40.1 UA1.13(AUDIOLINK_BCLK/BCLK)
HDA_BCLK_R: RC40.2 U1.AY22(HDA_BLK/I2S0_SCLK)
HDA_SDIN0: U1.BA21(HDA_SDI0/I2S0_RXD) UA1.16(AUDIOLINK_SDATA-IN/DOUT)
HDA_SDO: C9142.2 RC41.1 UA1.17(AUDIOLINK_SDATA-OUT/DIN)
HDA_SDO_R: RC37.2 RC41.2 TP2.1 U1.BB22(HDA_SDO/I2S0_TXD)
HDA_SYNC: RC39.1 UA1.14(AUDIOLINK_SYNC/LRCK)
HDA_SYNC_R: RC38.1 RC39.2 U1.BA22(HDA_SYNC/I2S0_SFRM)
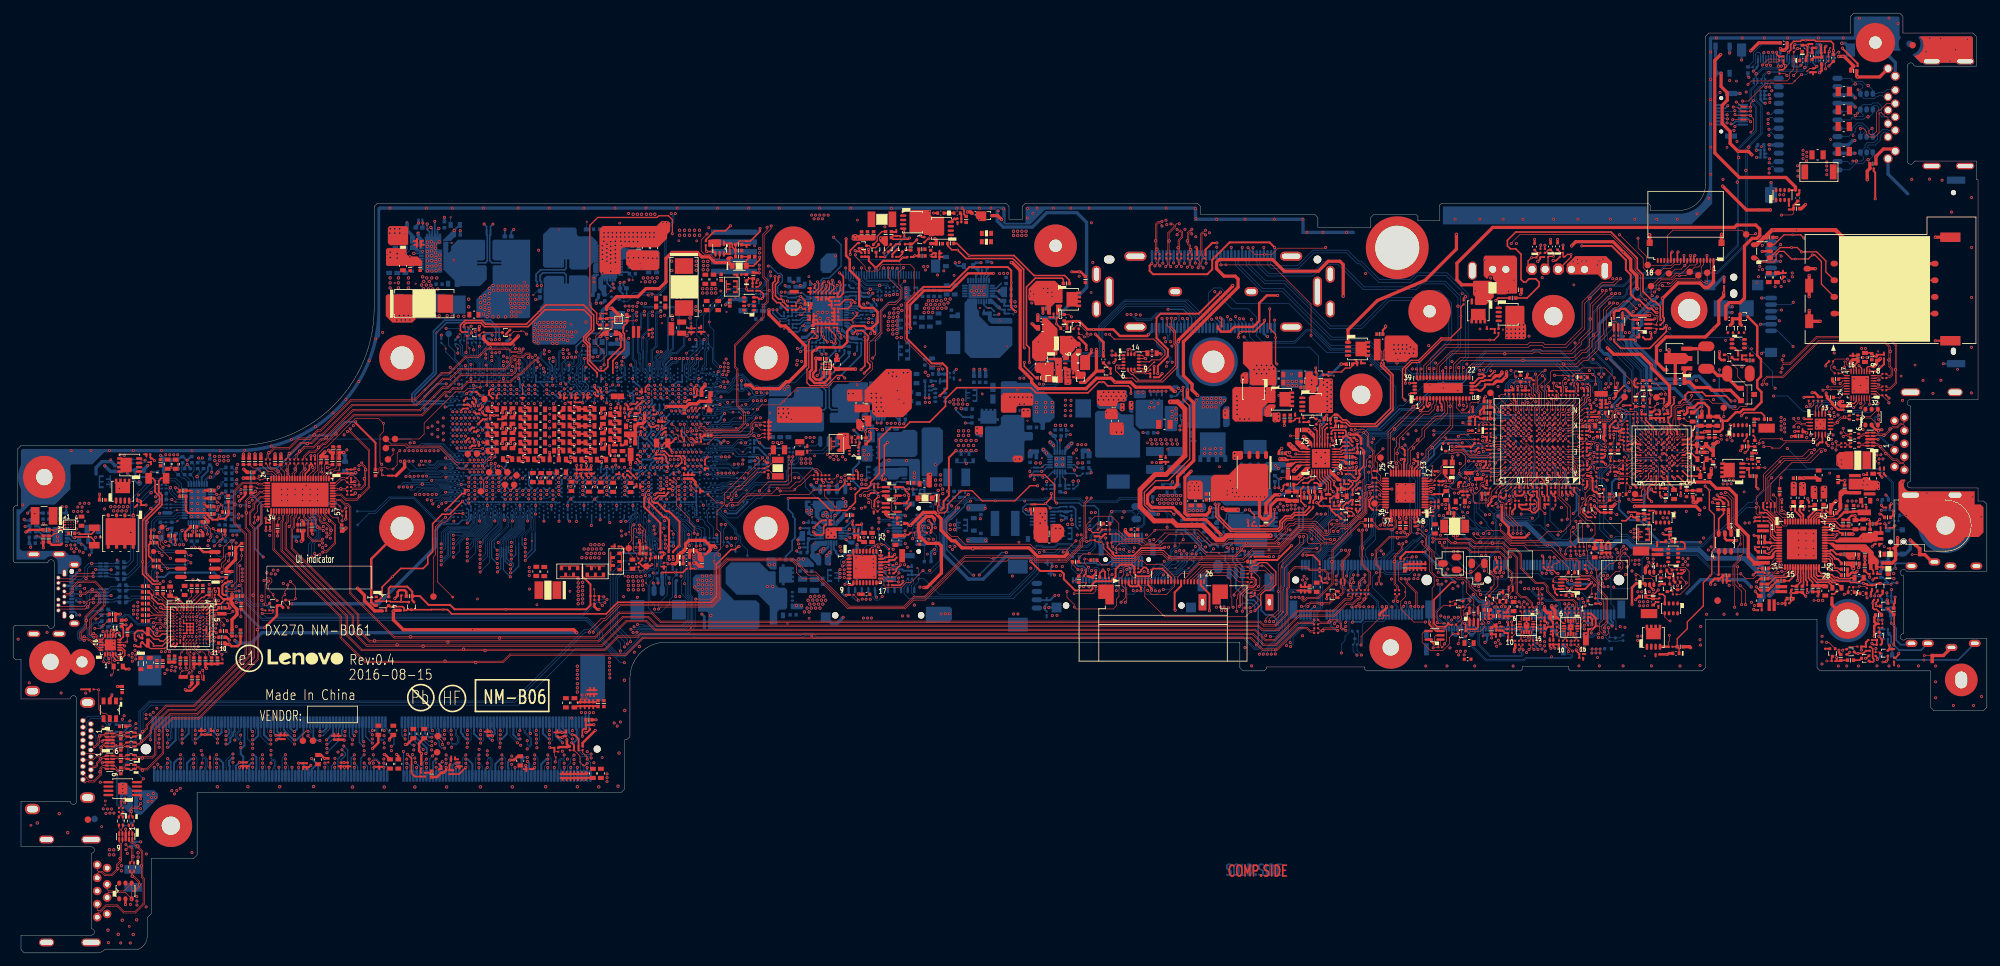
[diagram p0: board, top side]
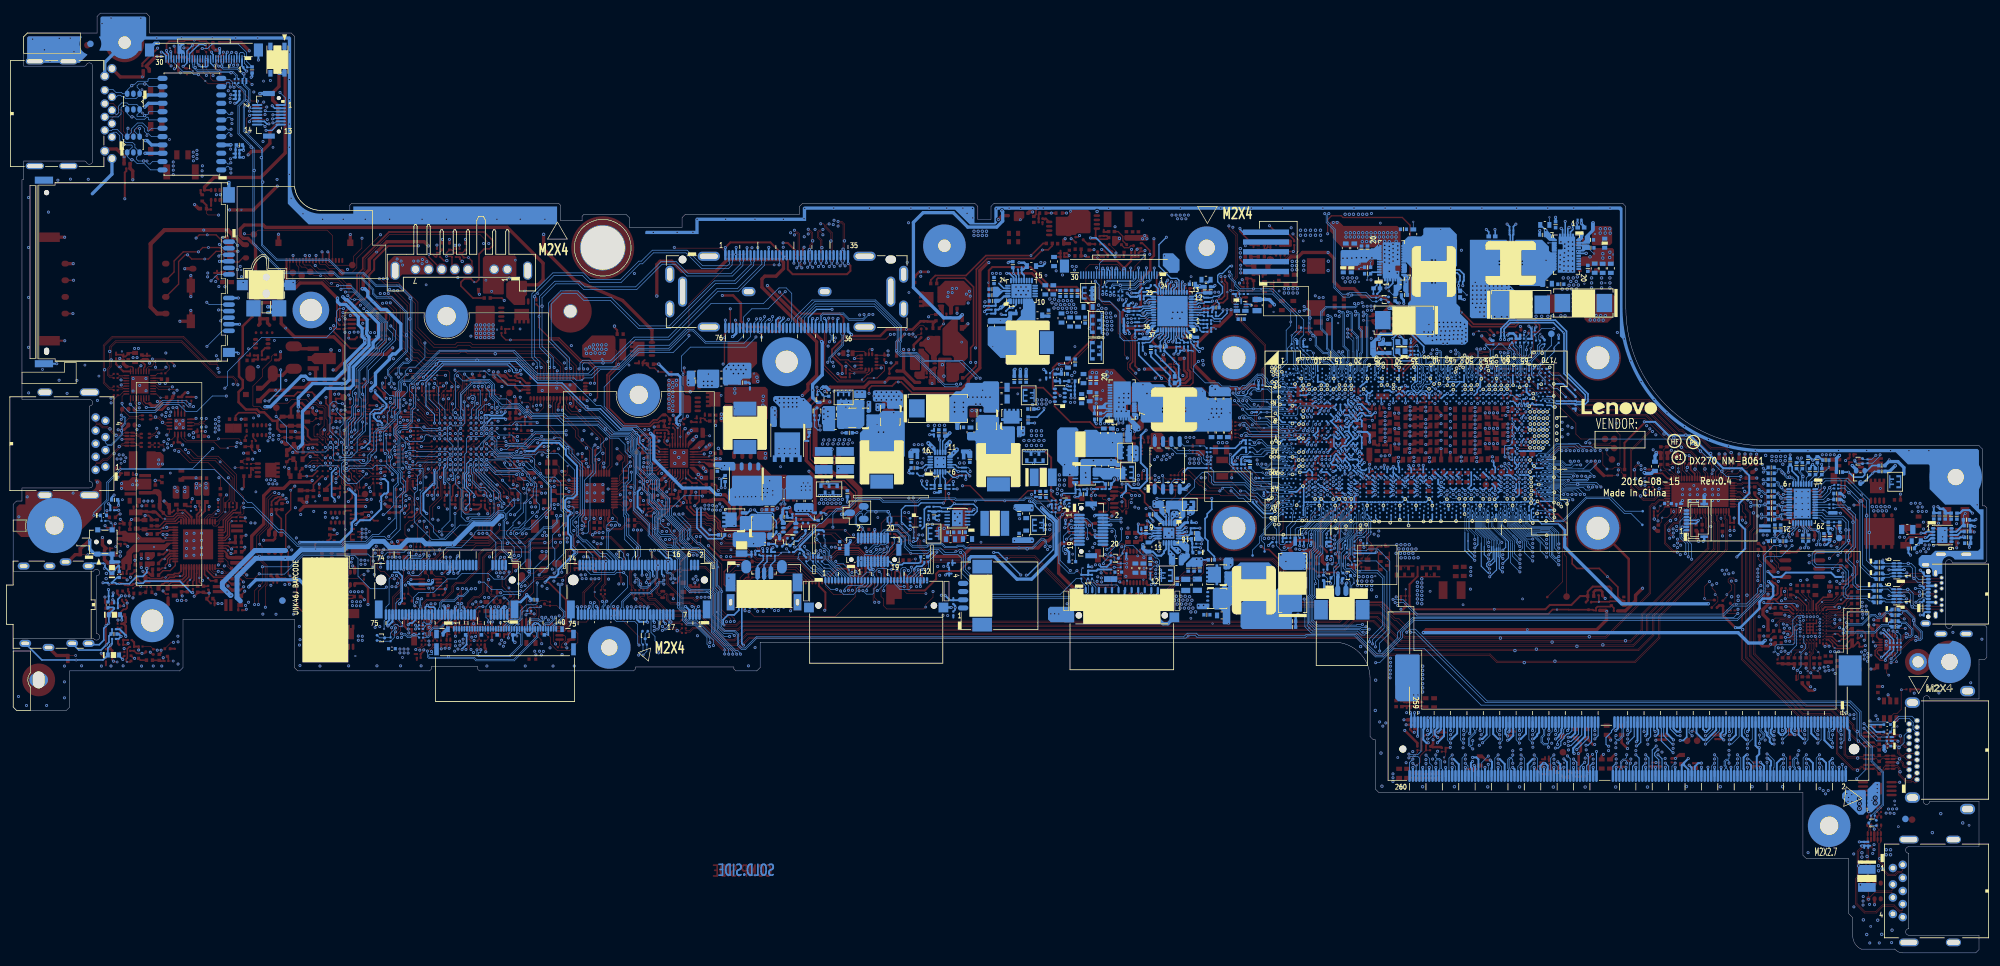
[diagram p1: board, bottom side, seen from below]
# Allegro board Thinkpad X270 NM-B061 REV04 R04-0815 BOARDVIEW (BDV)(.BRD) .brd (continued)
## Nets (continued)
HDMI_CLKN: L7.4 R309.1 U147.24(TMDS_CLKN)
HDMI_CLKN_CONN: D51.1(LINE-1) D51.9(NC1) J43.12(CK-) L7.3 R309.2 R9121.1
HDMI_CLKP: L7.1 R310.1 U147.25(TMDS_CLKP)
HDMI_CLKP_CONN: D51.2(LINE-2) D51.8(NC2) J43.10(CK+) L7.2 R310.2 R9121.2
HDMI_DATA0N: L9.4 R318.1 U147.27(TMDS_CH0N)
HDMI_DATA0N_CONN: D51.4(LINE-3) D51.7(NC3) J43.9(D0-) L9.3 R318.2 R9125.1
HDMI_DATA0P: L9.1 R316.1 U147.28(TMDS_CH0P)
HDMI_DATA0P_CONN: D51.5(LINE-4) D51.6(NC4) J43.7(D0+) L9.2 R316.2 R9125.2
HDMI_DATA1N: L8.4 R313.1 U147.29(TMDS_CH1N)
HDMI_DATA1N_CONN: D52.1(LINE-1) D52.9(NC1) J43.6(D1-) L8.3 R313.2 R9123.1
HDMI_DATA1P: L8.1 R311.1 U147.30(TMDS_CH1P)
HDMI_DATA1P_CONN: D52.2(LINE-2) D52.8(NC2) J43.4(D1+) L8.2 R311.2 R9123.2
HDMI_DATA2N: L10.4 R320.1 U147.32(TMDS_CH2N)
HDMI_DATA2N_CONN: D52.4(LINE-3) D52.7(NC3) J43.3(D2-) L10.3 R320.2 R9127.1
HDMI_DATA2P: L10.1 R323.1 U147.33(TMDS_CH2P)
HDMI_DATA2P_CONN: D52.5(LINE-4) D52.6(NC4) J43.1(D2+) L10.2 R323.2 R9127.2
HDMI_DDC_CLK: C2729.2 D55.1 J43.15(SCL) R340.2 U147.58(TMDS_SCL)
HDMI_DDC_DATA: C2730.2 D56.1 J43.16(SDA) R341.2 U147.57(TMDS_SDA)
HDMI_HPD_CONN: D57.1 J43.19(HP_DET) R2512.2 U147.31(TMDS_HPD)
HP_JACK_IN: D253.1 R145.1 RA25.2 TP14.1
HP_JACK_SYS: D253.3 D710.1 J19.6(#6) RA22.2 RA49.1
HP_JD_SYS: CA119.2 R10132.2 R10133.1 UA1.9(HP-JD/LINE-JD)
HP_L_JACK: C559.1 FL3.1 R315.1 R742.2
HP_L_JACK_CONN: CA44.2 D99.1 FL3.2 J19.1(#1)
HP_L_JACK_R: R315.2 UA1.32(HPOUT-L)
HP_R_JACK: C561.1 FL5.1 R317.1 R743.2
HP_R_JACK_CONN: CA45.2 D94.1 FL5.2 J19.2(#2)
HP_R_JACK_R: R317.2 UA1.33(HPOUT-R)
HV_GATE1: PR22.1 PR23.1 U5.B9(HV_GATE1)
HV_GATE2: PR20.1 PR21.1 U5.A9(HV_GATE2)
I2C0_CLK: R9134.1 U1.U6(GPP_C17/I2C0_SCL) U184.2(B)
I2C0_CLK_NFC: J26.13 R9136.1 U184.1(A)
I2C0_DATA: R9135.1 U1.U7(GPP_C16/I2C0_SDA) U185.2(B)
I2C0_DATA_NFC: J26.15 R9137.1 U185.1(A)
I2C_CLK_BT0: PR27.2 R129.1 U16.A7(SMB00_CLK)
I2C_CLK_BT1: PR34.2 R850.2 R851.1 U16.K11(GPIO013/SMB07_CLK)
I2C_CLK_CHARGE: PR146.1 R138.1 R142.1
I2C_CLK_CPU: Q170.3(S) RC168.1 U1.U9(GPP_C19/I2C1_SCL)
I2C_CLK_CPU_PD: Q170.1(D) R703.1 U5.D2(I2C_SCL1)
I2C_CLK_GSENSE: R160.1 U16.C8(SMB01_CLK/GPIO006) U17.4(SCLK/SCL)
I2C_CLK_USBPD: R189.2 U5.B5(I2C_SCL2) U16.B9(GPIO142/SMB05_CLK)
I2C_DATA_BT0: PR28.2 R128.1 U16.E7(SMB00_DATA)
I2C_DATA_BT1: PR35.2 R849.2 R852.1 U16.L12(GPIO012/SMB07_DATA)
I2C_DATA_CHARGE: PR148.1 R136.1 R140.1
I2C_DATA_CPU: Q171.3(S) RC167.1 U1.U8(GPP_C18/I2C1_SDA)
I2C_DATA_CPU_PD: Q171.1(D) R702.1 U5.D1(I2C_SDA1)
I2C_DATA_GSENSE: R161.1 U16.D8(SMB01_DATA/GPIO005) U17.6(SDI/SDA)
I2C_DATA_USBPD: R188.2 U5.A5(I2C_SDA2) U16.E9(GPIO141/SMB05_DATA)
I2S_CTRL: D22.2 R10071.2
I2S_JD: CA124.2 R319.2 R2572.1 RA290.2 UA1.8(I2S-OUT-JD/MIC-JD)
IFDET: C800.2 J1.21 Q4.2(BASE) Q28.2(BASE) R51.1 R377.2
INT#_TYPEC: R171.2 R483.1 R801.1 U16.D11(GPIO220/VIN)
INT#_TYPEC_CPU: R485.1 R486.2 R802.1 U1.AD2(GPP_C21/UART2_TXD)
INT#_TYPEC_CPU_R: R802.2 U5.C1(I2C_IRQ1Z)
INT#_TYPEC_R: R801.2 U5.B6(I2C_IRQ2Z)
IPDCLK: J16.15 R137.2 R226.1
IPDCLK_R: C155.1 R137.1 U16.F11(PS2_CLK0A/GPIO114)
IPDDATA: J16.13 R139.2 R227.1
IPDDATA_R: C156.1 D26.1 R139.1 U16.K13(PS2_DAT0A/GPIO115)
IRQSER: J5.9 RC22.1 U1.AY11(GPP_A6/SERIRQ) U16.N5(SER_IRQ)
ITP_PMODE: J8.17 RC116.2 U1.E8(ITP_PMODE)
KBD_BL_PWM: C175.1 J37.11 R133.2 U16.M9(PWM0/GPIO053)
LANPHYPC: RL2.1 U1.AW17(GPD11/LANPHYPC) UL1.3(LAN_DISABLE_N)
LDO_1V8D_LFT: C812.2 U5.A2(LDO_1V8D)
LPC_AD0: R244.1 U1.AY13(GPP_A1/LAD0/ESPI_IO0) U16.M6(LAD0)
LPC_AD1: R245.1 U1.BA13(GPP_A2/LAD1/ESPI_IO1) U16.M7(LAD1)
LPC_AD2: R246.1 U1.BB13(GPP_A3/LAD2/ESPI_IO2) U16.L7(LAD2)
LPC_AD3: R247.1 U1.AY12(GPP_A4/LAD3/ESPI_IO3) U16.K7(LAD3)
LPC_AD_DBG0: J5.4 R244.2
LPC_AD_DBG1: J5.6 R245.2
LPC_AD_DBG2: J5.8 R246.2
LPC_AD_DBG3: J5.10 R247.2
LPCCLK_DEBUG_24M: C258.1 J5.1 RC31.2
LPCCLK_DEBUG_24M_R: RC31.1 U1.AY9(GPP_A10/CLKOUT_LPC1)
LPCCLK_EC_24M: C257.1 RC30.2 U16.N6(PCI_CLK)
LPCCLK_EC_24M_R: RC30.1 U1.AW9(GPP_A9/CLKOUT_LPC0/ESPI_CLK)
LX1_CHG: PC142.1 PC147.2 PL101.1 PQ14.1(S1) PQ14.2(S2) PQ14.3(S3) PQ110.1(S1) PQ110.2(S2) PQ110.3(S3) PQ111.5(D) PU101.32(SW1)
LX2_CHG: PC143.1 PC162.2 PL101.2 PQ112.1(S1) PQ112.2(S2) PQ112.3(S3) PQ113.5(D) PU101.23(SW2)
M1_DRV: PR31.1 U21.E2(M1_DRV)
M2_DRV: PR32.1 U21.C1(M2_DRV)
M-BAT-PWR: PF3.2 PF7.1 PQ17.1(S1) PQ17.2(S2) PQ17.3(S3)
M-BAT-TRCL: PD12.2 PD12.3 PD15.1 PD16.1 PF7.2
M-BAT-TRCL_A: PD15.2 PD15.3 PD16.2 PD16.3 PQ21.1(D1) PQ21.2(D2) PQ21.5(D3) PQ21.6(D4)
M_A_A0: J21.144(A0) U1.AY50(DDR0_MA[0]/DDR0_CAB[9]/DDR0_MA[)
M_A_A1: J21.133(A1) U1.BB50(DDR0_MA[1]/DDR0_CAB[8]/DDR0_MA[)
M_A_A2: J21.132(A2) U1.AY51(DDR0_MA[2]/DDR0_CAB[5]/DDR0_MA[)
M_A_A3: J21.131(A3) U1.BA50(DDR0_MA[3])
M_A_A4: J21.128(A4) U1.BB52(DDR0_MA[4])
M_A_A5: J21.126(A5) U1.BA51(DDR0_MA[5]/DDR0_CAA[0]/DDR0_MA[)
M_A_A6: J21.127(A6) U1.BA52(DDR0_MA[6]/DDR0_CAA[2]/DDR0_MA[)
M_A_A7: J21.122(A7) U1.AW52(DDR0_MA[7]/DDR0_CAA[4]/DDR0_MA[)
M_A_A8: J21.125(A8) U1.AY52(DDR0_MA[8]/DDR0_CAA[3]/DDR0_MA[)
M_A_A9: J21.121(A9) U1.BB54(DDR0_MA[9]/DDR0_CAA[1]/DDR0_MA[)
M_A_A10: J21.146(A10/AP) U1.AT50(DDR0_MA[10]/DDR0_CAB[7]/DDR0_MA)
M_A_A11: J21.120(A11) U1.BA54(DDR0_MA[11]/DDR0_CAA[7]/DDR0_MA)
M_A_A12: J21.119(A12) U1.AW54(DDR0_MA[12]/DDR0_CAA[6]/DDR0_MA)
M_A_A13: J21.158(A13) U1.AU46(DDR0_MA[13]/DDR0_CAB[0]/DDR0_MA)
M_A_ACT_N: J21.114(ACT_N) U1.BA55(DDR0_MA[15]/DDR0_CAA[8]/DDR0_AC)
M_A_ALERT_N: J21.116(ALERT_N) U1.AW50(DDR0_ALERT#)
M_A_BG0: J21.115(BG0) U1.AY55(DDR0_BA[2]/DDR0_CAA[5]/DDR0_BG[)
M_A_BG1: J21.113(BG1) U1.AY54(DDR0_MA[14]/DDR0_CAA[9]/DDR0_BG)
M_A_BS0: J21.150(BA0) U1.AU52(DDR0_BA[0]/DDR0_CAB[4]/DDR0_BA[)
M_A_BS1: J21.145(BA1) U1.AT48(DDR0_BA[1]/DDR0_CAB[6]/DDR0_BA[)
M_A_CKE0: J21.109(CKE0) U1.BA56(DDR0_CKE[0])
M_A_CKE1: J21.110(CKE1) U1.BB56(DDR0_CKE[1])
M_A_DDRCLK0_1866M: J21.137(CK0_T) U1.AT53(DDR0_CKP[0])
M_A_DDRCLK1_1866M: J21.138(CK1_T/NF) U1.AT55(DDR0_CKP[1])
M_A_DQ0: J21.7(DQ1) U1.AL71(DDR0_DQ[0])
M_A_DQ1: J21.3(DQ5) U1.AL68(DDR0_DQ[1])
M_A_DQ2: J21.21(DQ3) U1.AN68(DDR0_DQ[2])
M_A_DQ3: J21.16(DQ6) U1.AN69(DDR0_DQ[3])
M_A_DQ4: J21.4(DQ4) U1.AL70(DDR0_DQ[4])
M_A_DQ5: J21.8(DQ0) U1.AL69(DDR0_DQ[5])
M_A_DQ6: J21.17(DQ7) U1.AN70(DDR0_DQ[6])
M_A_DQ7: J21.20(DQ2) U1.AN71(DDR0_DQ[7])
M_A_DQ8: J21.28(DQ8) U1.AR70(DDR0_DQ[8])
M_A_DQ9: J21.24(DQ12) U1.AR68(DDR0_DQ[9])
M_A_DQ10: J21.38(DQ14) U1.AU71(DDR0_DQ[10])
M_A_DQ11: J21.42(DQ11) U1.AU68(DDR0_DQ[11])
M_A_DQ12: J21.29(DQ9) U1.AR71(DDR0_DQ[12])
M_A_DQ13: J21.25(DQ13) U1.AR69(DDR0_DQ[13])
M_A_DQ14: J21.41(DQ10) U1.AU70(DDR0_DQ[14])
M_A_DQ15: J21.37(DQ15) U1.AU69(DDR0_DQ[15])
M_A_DQ16: J21.194(DQ41) U1.AF65(DDR1_DQ[0]/DDR0_DQ[16])
M_A_DQ17: J21.195(DQ40) U1.AF64(DDR1_DQ[1]/DDR0_DQ[17])
M_A_DQ18: J21.204(DQ47) U1.AK65(DDR1_DQ[2]/DDR0_DQ[18])
M_A_DQ19: J21.203(DQ46) U1.AK64(DDR1_DQ[3]/DDR0_DQ[19])
M_A_DQ20: J21.190(DQ45) U1.AF66(DDR1_DQ[4]/DDR0_DQ[20])
M_A_DQ21: J21.191(DQ44) U1.AF67(DDR1_DQ[5]/DDR0_DQ[21])
M_A_DQ22: J21.207(DQ42) U1.AK67(DDR1_DQ[6]/DDR0_DQ[22])
M_A_DQ23: J21.208(DQ43) U1.AK66(DDR1_DQ[7]/DDR0_DQ[23])
M_A_DQ24: J21.186(DQ35) U1.AF70(DDR1_DQ[8]/DDR0_DQ[24])
M_A_DQ25: J21.174(DQ32) U1.AF68(DDR1_DQ[9]/DDR0_DQ[25])
M_A_DQ26: J21.173(DQ33) U1.AH71(DDR1_DQ[10]/DDR0_DQ[26])
M_A_DQ27: J21.183(DQ38) U1.AH68(DDR1_DQ[11]/DDR0_DQ[27])
M_A_DQ28: J21.182(DQ39) U1.AF71(DDR1_DQ[12]/DDR0_DQ[28])
M_A_DQ29: J21.187(DQ34) U1.AF69(DDR1_DQ[13]/DDR0_DQ[29])
M_A_DQ30: J21.169(DQ37) U1.AH70(DDR1_DQ[14]/DDR0_DQ[30])
M_A_DQ31: J21.170(DQ36) U1.AH69(DDR1_DQ[15]/DDR0_DQ[31])
M_A_DQ32: J21.46(DQ20) U1.BB65(DDR0_DQ[16]/DDR0_DQ[32])
M_A_DQ33: J21.62(DQ18) U1.AW65(DDR0_DQ[17]/DDR0_DQ[33])
M_A_DQ34: J21.63(DQ19) U1.AW63(DDR0_DQ[18]/DDR0_DQ[34])
M_A_DQ35: J21.45(DQ21) U1.AY63(DDR0_DQ[19]/DDR0_DQ[35])
M_A_DQ36: J21.50(DQ16) U1.BA65(DDR0_DQ[20]/DDR0_DQ[36])
M_A_DQ37: J21.49(DQ17) U1.AY65(DDR0_DQ[21]/DDR0_DQ[37])
M_A_DQ38: J21.59(DQ23) U1.BA63(DDR0_DQ[22]/DDR0_DQ[38])
M_A_DQ39: J21.58(DQ22) U1.BB63(DDR0_DQ[23]/DDR0_DQ[39])
M_A_DQ40: J21.66(DQ28) U1.BA61(DDR0_DQ[24]/DDR0_DQ[40])
M_A_DQ41: J21.70(DQ24) U1.AW61(DDR0_DQ[25]/DDR0_DQ[41])
M_A_DQ42: J21.79(DQ30) U1.BB59(DDR0_DQ[26]/DDR0_DQ[42])
M_A_DQ43: J21.84(DQ27) U1.AW59(DDR0_DQ[27]/DDR0_DQ[43])
M_A_DQ44: J21.67(DQ29) U1.BB61(DDR0_DQ[28]/DDR0_DQ[44])
M_A_DQ45: J21.71(DQ25) U1.AY61(DDR0_DQ[29]/DDR0_DQ[45])
M_A_DQ46: J21.83(DQ26) U1.BA59(DDR0_DQ[30]/DDR0_DQ[46])
M_A_DQ47: J21.80(DQ31) U1.AY59(DDR0_DQ[31]/DDR0_DQ[47])
M_A_DQ48: J21.211(DQ52) U1.AT66(DDR1_DQ[16]/DDR0_DQ[48])
M_A_DQ49: J21.215(DQ49) U1.AU66(DDR1_DQ[17]/DDR0_DQ[49])
M_A_DQ50: J21.225(DQS5) U1.AP65(DDR1_DQ[18]/DDR0_DQ[50])
M_A_DQ51: J21.229(DQ51) U1.AN65(DDR1_DQ[19]/DDR0_DQ[51])
M_A_DQ52: J21.216(DQ48) U1.AN66(DDR1_DQ[20]/DDR0_DQ[52])
M_A_DQ53: J21.212(DQ53) U1.AP66(DDR1_DQ[21]/DDR0_DQ[53])
M_A_DQ54: J21.224(DQ54) U1.AT65(DDR1_DQ[22]/DDR0_DQ[54])
M_A_DQ55: J21.228(DQ50) U1.AU65(DDR1_DQ[23]/DDR0_DQ[55])
M_A_DQ56: J21.233(DQ61) U1.AT61(DDR1_DQ[24]/DDR0_DQ[56])
M_A_DQ57: J21.237(DQ56) U1.AU61(DDR1_DQ[25]/DDR0_DQ[57])
M_A_DQ58: J21.246(DQ63) U1.AP60(DDR1_DQ[26]/DDR0_DQ[58])
M_A_DQ59: J21.250(DQ59) U1.AN60(DDR1_DQ[27]/DDR0_DQ[59])
M_A_DQ60: J21.236(DQ57) U1.AN61(DDR1_DQ[28]/DDR0_DQ[60])
M_A_DQ61: J21.232(DQ60) U1.AP61(DDR1_DQ[29]/DDR0_DQ[61])
M_A_DQ62: J21.249(DQ58) U1.AT60(DDR1_DQ[30]/DDR0_DQ[62])
M_A_DQ63: J21.245(DQ62) U1.AU60(DDR1_DQ[31]/DDR0_DQ[63])
M_A_DQS0: J21.13(DQS0_T) U1.AM69(DDR0_DQSP[0])
M_A_DQS1: J21.34(DQS1_T) U1.AT70(DDR0_DQSP[1])
M_A_DQS2: J21.200(DQS5_T) U1.AH65(DDR1_DQSP[0]/DDR0_DQSN[2])
M_A_DQS3: J21.179(DQS4_T) U1.AG70(DDR1_DQSP[1]/DDR0_DQSN[3])
M_A_DQS4: J21.55(DQS2_T) U1.AY64(DDR0_DQSP[2]/DDR0_DQSP[4])
M_A_DQS5: J21.76(DQS3_T) U1.BA60(DDR0_DQSP[3]/DDR0_DQSP[5])
M_A_DQS6: J21.221(DQS6_T) U1.AR65(DDR1_DQSP[2]/DDR0_DQSP[6])
M_A_DQS7: J21.242(DQS7_T) U1.AR60(DDR1_DQSP[3]/DDR0_DQSP[7])
M_A_DQS8: J21.97(DQS8_T) TP29.1
M_A_PARITY: J21.143(PARITY) U1.AT52(DDR0_PAR)
M_BAT_IN: PC21.2 PF3.1 PJ2.1 PJ2.8(VCC)
M_BAT_PWR_A: PQ17.5(D) PQ18.1(S1) PQ18.2(S2) PQ18.3(S3) PR29.2
M_ON: PR221.1 R232.1 R233.1 R260.2 TP39.1
M_TEMP: PC19.2 PJ2.4 PR26.1 R135.1
M_TRCL: PQ22.2(IN) U21.H3(MTRCL)
MDI_0+: U14.12(A3-) UL1.13(MDI_PLUS[0])
MDI_0-: U14.11(A3+) UL1.14(MDI_MINUS[0])
MDI_1+: U14.10(A2-) UL1.17(MDI_PLUS[1])
MDI_1-: U14.9(A2+) UL1.18(MDI_MINUS[1])
MDI_2+: U14.7(A1-) UL1.20(MDI_PLUS[2])
MDI_2-: U14.6(A1+) UL1.21(MDI_MINUS[2])
MDI_3+: U14.3(A0-) UL1.23(MDI_PLUS[3])
MDI_3-: U14.2(A0+) UL1.24(MDI_MINUS[3])
MIC1_VREFOL: C1416.2 R1219.2 UA1.38(MIC1-VREFO-L/AGPO-0)
MIC1_VREFOR: C73.2 R460.2 UA1.39(MIC1-VREFO-L/AGPO-1)
MIC_RING2: CA142.2 DA5.1 J19.3(#3) RA36.2 RA126.1
MIC_SLEEVE: C1417.2 D24.1 J19.4(#4) RA35.2 RA125.1
MPWRG: Q39.2(G) R285.1 R286.2 R307.2 RC67.1
MUX_TYPEC_C_TXN1: C8359.2 L12.1 R9104.1
MUX_TYPEC_C_TXN2: C8360.2 L13.4 R9105.1
MUX_TYPEC_C_TXP1: C8358.2 L12.4 R9103.1
MUX_TYPEC_C_TXP2: C8361.2 L13.1 R9109.1
MUX_TYPEC_RXN1: L14.1 R9114.1 U183.31(RX1N)
MUX_TYPEC_RXN2: L15.4 R9115.1 U183.39(RX2N)
MUX_TYPEC_RXP1: L14.4 R9111.1 U183.30(RX1P)
MUX_TYPEC_RXP2: L15.1 R9118.1 U183.40(RX2P)
MUX_TYPEC_TXN1: C8359.1 U183.34(TX1N)
MUX_TYPEC_TXN2: C8360.1 U183.36(TX2N)
MUX_TYPEC_TXP1: C8358.1 U183.33(TX1P)
MUX_TYPEC_TXP2: C8361.1 U183.37(TX2P)
NFC_ACTIVE: R904.1 R9133.1
NFC_ACTIVE_R: R9133.2 U1.AK6(GPP_F0/I2S2_SCLK)
NFC_DLREQ: J26.3 U1.AN8(GPP_B15/GSPI0_CS#)
NFC_INT: J26.9 R401.2 U1.B9(GPP_E12/USB2_OC3#)
NFC_ON: J26.5 R230.2 U1.J1(GPP_E4/DEVSLP0)
PA_CDE_TI_DPEQ0: R9112.2 R9113.2 U183.14(CDE/DCI_CLK)
PA_CEDP_ TI_CTL1: R573.1 R9090.1 U183.23(CE_DP)
PA_CEQ_TI_CTL0: R572.1 R9091.2 R10248.2 U183.22(CEQ/CSDA)
PA_CEXT_TI_VCC: C8356.1 R682.1 U183.1(CEXT)
PA_DCICFG_TI_ SSEQ1: R9100.2 R9102.2 U183.3(DCICFG/ADDR)
PA_DPEQ_TI_FLIP: R571.1 R9093.2 R10250.2 U183.21(DPEQ/CSCL)
PA_FLIP_TI_EQ0: R576.1 R9116.2 R9117.2 U183.38(FLIP)
PA_I2C_EN_TI_EN: R678.2 R9087.1 R9089.1 U183.29(I2C_EN)
PA_REXT_TI_DPEQ1: R681.1 R9097.1 U183.2(REXT)
PA_SSDE_TI_SSEQ: R9096.2 R9098.2 U183.11(SSDE/DCI_DATA)
PA_TI_HPD_PD: R9095.1 U183.32(IN_HPD)
PA_USB_TI_EQ1: R574.1 R9106.2 R9107.2 U183.35(CE_USB)
PA_VDDDCI_TI_I2CEN: R679.2 R680.2 U183.17(VDD_DCI)
PANEL_BKLT_CTRL: J10.24 U1.R11(EDP_BKLTCTL)
PANEL_POWER_ON: RC2.1 U1.U13(EDP_VDDEN) U21.F4(3P_ON)
PCH_PWROK: RC66.2 U1.BA20(PCH_PWROK)
PCH_SPKR: D739.2 RA39.1 U1.AW5(GPP_B14/SPKR)
PCH_TCK: RC142.1 RC149.1 U1.B56(PCH_JTAG_TCK)
PCIE0_CLK_100M: U1.C42(CLKOUT_PCIE_P0) U15.5(REFCLKP)
PCIE0_RXN: C139.1 U1.H13(PCIE1_RXN/USB3_5_RXN)
PCIE0_RXN_C: C139.2 U15.8(HSON)
PCIE0_RXP: C137.1 U1.G13(PCIE1_RXP/USB3_5_RXP)
PCIE0_RXP_C: C137.2 U15.7(HSOP)
PCIE0_TXN: CC75.1 U1.B17(PCIE1_TXN/USB3_5_TXN)
PCIE0_TXN_C: CC75.2 U15.4(HSIN)
PCIE0_TXP: CC74.1 U1.A17(PCIE1_TXP/USB3_5_TXP)
PCIE0_TXP_C: CC74.2 U15.3(HSIP)
PCIE1_CLK_100M: J32.71(REFCLKP1) U1.A42(CLKOUT_PCIE_P1)
PCIE1_RXN: J32.67(PERN1) U1.F16(PCIE5_RXN)
PCIE1_RXP: J32.65(PERP1) U1.E16(PCIE5_RXP)
PCIE1_TXN: C219.2 U1.C19(PCIE5_TXN)
PCIE1_TXN_C: C219.1 J32.61(PETN1)
PCIE1_TXP: C220.2 U1.D19(PCIE5_TXP)
PCIE1_TXP_C: C220.1 J32.59(PETP1)
PCIE2_CLK_100M: J32.47(REFCLKP0) U1.C41(CLKOUT_PCIE_P2)
PCIE2_RXN: J32.43(PERN0) U1.H16(PCIE3_RXN)
PCIE2_RXP: J32.41(PERP0) U1.G16(PCIE3_RXP)
PCIE2_TXN: C254.2 U1.D17(PCIE3_TXN)
PCIE2_TXN_C: C254.1 J32.37(PETN0)
PCIE2_TXP: C253.2 U1.C17(PCIE3_TXP)
PCIE2_TXP_C: C253.1 J32.35(PETP0)
PCIE3_CLK_100M: U1.C40(CLKOUT_PCIE_P3) UL1.44(PE_CLKP)
PCIE3_RXN: CL3.1 U1.G15(PCIE4_RXN)
PCIE3_RXN_C: CL3.2 UL1.39(PETN)
PCIE3_RXP: CL2.1 U1.F15(PCIE4_RXP)
PCIE3_RXP_C: CL2.2 UL1.38(PETP)
PCIE3_TXN: CL1.1 U1.B19(PCIE4_TXN)
PCIE3_TXN_C: CL1.2 UL1.42(PERN)
PCIE3_TXP: CL4.1 U1.A19(PCIE4_TXP)
PCIE3_TXP_C: CL4.2 UL1.41(PERP)
PCIE4_CLK_100M: J1.38 U1.A40(CLKOUT_PCIE_P4)
PCIE4_L0_SATA1_RXN: C86.2 U1.G21(PCIE8_RXN/SATA1A_RXN)
PCIE4_L0_SATA1_RXN_C: C86.1 U24.4(BO-)
PCIE4_L0_SATA1_RXN_CONN: C420.1 J1.33
PCIE4_L0_SATA1_RXN_CONN_R: C420.2 U24.11(BI-)
PCIE4_L0_SATA1_RXP: C84.2 U1.F21(PCIE8_RXP/SATA1A_RXP)
PCIE4_L0_SATA1_RXP_C: C84.1 U24.5(BO+)
PCIE4_L0_SATA1_RXP_CONN: C419.1 J1.32
PCIE4_L0_SATA1_RXP_CONN_R: C419.2 U24.10(BI+)
PCIE4_L0_SATA1_TXN: C85.1 U1.D21(PCIE8_TXN/SATA1A_TXN)
PCIE4_L0_SATA1_TXN_C: C85.2 U24.2(AI-)
PCIE4_L0_SATA1_TXN_CONN: C422.2 J1.35
PCIE4_L0_SATA1_TXN_CONN_R: C422.1 U24.13(AO-)
PCIE4_L0_SATA1_TXP: C83.1 U1.C21(PCIE8_TXP/SATA1A_TXP)
PCIE4_L0_SATA1_TXP_C: C83.2 U24.1(AI+)
PCIE4_L0_SATA1_TXP_CONN: C421.2 J1.36
PCIE4_L0_SATA1_TXP_CONN_R: C421.1 U24.14(AO+)
PCIE4_L1_RXN: C244.2 U1.F20(PCIE7_RXN/SATA0_RXN)
PCIE4_L1_RXN_C: C244.1 U25.4(BO-)
PCIE4_L1_RXN_CONN: J1.27 R416.1
PCIE4_L1_RXN_CONN_R: R416.2 U25.11(BI-)
PCIE4_L1_RXP: C243.2 U1.E20(PCIE7_RXP/SATA0_RXP)
PCIE4_L1_RXP_C: C243.1 U25.5(BO+)
PCIE4_L1_RXP_CONN: J1.26 R415.1
PCIE4_L1_RXP_CONN_R: R415.2 U25.10(BI+)
PCIE4_L1_TXN: C242.1 U1.B21(PCIE7_TXN/SATA0_TXN)
PCIE4_L1_TXN_C: C242.2 U25.2(AI-)
PCIE4_L1_TXN_CONN: C418.2 J1.29
PCIE4_L1_TXN_CONN_R: C418.1 U25.13(AO-)
PCIE4_L1_TXP: C241.1 U1.A21(PCIE7_TXP/SATA0_TXP)
PCIE4_L1_TXP_C: C241.2 U25.1(AI+)
PCIE4_L1_TXP_CONN: C417.2 J1.30
PCIE4_L1_TXP_CONN_R: C417.1 U25.14(AO+)
PCIE5_CLK_100M: J22.55(REFCLKP) U1.E38(CLKOUT_PCIE_P5)
PCIE10_L0_SATA2_RXN: J22.43(PERP0/SATA-B-) U1.E30(PCIE12_RXN/SATA2_RXN)
PCIE10_L0_SATA2_RXP: J22.41(PERN0/SATA-B+) U1.F30(PCIE12_RXP/SATA2_RXP)
PCIE10_L0_SATA2_TXN: C2764.1 U1.A25(PCIE12_TXN/SATA2_TXN)
PCIE10_L0_SATA2_TXN_C: C2764.2 J22.47(PETN0/SATA-A-)
PCIE10_L0_SATA2_TXP: C2765.1 U1.B25(PCIE12_TXP/SATA2_TXP)
PCIE10_L0_SATA2_TXP_C: C2765.2 J22.49(PETP0/SATA-A+)
PCIE10_L1_RXN: R547.1 U1.E28(PCIE11_RXN/SATA1B_RXN)
PCIE10_L1_RXN_R: J22.29(USB3.0-TX-(DEVICE)) R547.2
PCIE10_L1_RXP: R546.1 U1.E27(PCIE11_RXP/SATA1B_RXP)
PCIE10_L1_RXP_R: J22.31(USB3.0-TX+(DEVICE)) R546.2
PCIE10_L1_TXN: C9113.1 U1.D24(PCIE11_TXN/SATA1B_TXN)
PCIE10_L1_TXN_C: C9113.2 J22.35(USB3.0-RX-(DEVICE))
PCIE10_L1_TXP: C9112.1 U1.C24(PCIE11_TXP/SATA1B_TXP)
PCIE10_L1_TXP_C: C9112.2 J22.37(USB3.0-RX+(DEVICE))
PCIE REDR _EN: Q28.1(COLLECTOR) R351.2 U25.7(EN#)
PCIE_RCOMPN: RC49.2 U1.F5(PCIE_RCOMPN)
PCIE_RCOMPP: RC49.1 U1.E5(PCIE_RCOMPP)
PECI: R163.2 U1.A54(PECI)
PECI_R: C159.2 R163.1 U16.B12(PECI_DAT)
PLANARID0: RC54.1 U1.AP4(GPP_F12/EMMC_CMD)
PLANARID1: RC51.1 U1.AP2(GPP_F13/EMMC_DATA0)
PLANARID2: RC52.1 U1.AP1(GPP_F14/EMMC_DATA1)
PLANARID3: RC53.1 U1.AP3(GPP_F15/EMMC_DATA2)
PROCHOT_EC: Q7.2(G) R156.2 U16.D3(LED2/GPIO153)
PS8349B_DP_CFG0: R2531.2 U147.2(DP_CFG0/SDA_CTL)
PS8349B_DP_CFG1: R2523.2 R2524.1 U147.3(DP_CFG1/SCL_CTL)
PS8349B_MODE: R2527.2 R2528.1 U147.21(MODE)
PS8349B_PC1: R2529.2 R2530.1 U147.22(PC1)
PS8349B_PC2: R9130.1 R9131.2 U147.45(PC2)
PS8349B_PEQ: R2561.2 R2562.1 U147.18(PEQ)
PS8349B_TMDS_DDCBUF: R1877.2 R1899.1 U147.23(TMDS_DDCBUF)
PS8349B_TMDS_PRE: R1875.2 R1897.1 U147.26(TMDS_PRE)
PSYS: PC152.2 PR150.2 PR412.1 PU101.10(PSYS) PU401.46(PSYS)
PWM1_2PH: PU401.16(PWM1_2PH) PU403.4(PWM)
PWM_1A: PU401.22(PWM_1A) PU402.4(PWM)
PWM_1B: PU401.36(PWM_1B) PU405.4(PWM)
REFIN: PC307.1 PR307.2 PR308.1 PU301.8(REFIN)
REGN: PC155.1 PR136.1 PU101.28(REGN)
RING2: C9134.1 R10096.2 RA126.2 UA1.36(MIC1-L/RING2)
RJ45_ACTIVITY: R92.2 UL1.27(LED1)
RJ45_ACTIVITY_SYS: CL16.2 R94.2 RL13.1
RJ45_LINKUP: R93.2 U16.G3(GPIO033) UL1.26(LED0)
RJ45_LINKUP_SYS: CL17.2 R95.2 RL12.2
RJ45_TXD0N: DL2.3(CH2) J3.2(PR1-) T1.23(MX1-)
RJ45_TXD0P: DL2.1(CH1) J3.1(PR1+) T1.24(MX1+)
RJ45_TXD1N: DL2.6(CH4) J3.6(PR2-) T1.19(MX2-)
RJ45_TXD1P: DL2.4(CH3) J3.3(PR2+) T1.20(MX2+)
RJ45_TXD2N: DL1.6(CH4) J3.5(PR3-) T1.17(MX3-)
RJ45_TXD2P: DL1.4(CH3) J3.4(PR3+) T1.18(MX3+)
RJ45_TXD3N: DL1.3(CH2) J3.8(PR4-) T1.13(MX4-)
RJ45_TXD3P: DL1.1(CH1) J3.7(PR4+) T1.14(MX4+)
RT1_R: RT1.2 RT2.1
RT2_R: RT2.2 RT3.1
RT3_R: RT3.2 RT4.1
RT4_R: RT4.2 RT5.1
RT5_R: RT5.2 RT6.1
RT6_R: RT6.2 RT7.1
RT7_R: RT7.2 RT8.1
RTCVCC: CC43.2 CC69.1 DC2.1 DC3.1 RC62.2 RC123.1 RC124.1 U1.AK19(VCCRTC_AK19) U1.BB14(VCCRTC_BB14)
RTCX1: CC12.1 RC58.2 U1.AM18(RTCX1) Y2.2
RTCX2: CC13.1 RC58.1 U1.AM20(RTCX2) Y2.1
S1_DRV: PR38.1 U21.F1(S1_DRV)
S2_DRV: PR39.1 U21.C2(S2_DRV)
S3_1.2V: PC302.2 PR301.2 PU301.17(S3)
S5_1.2V: PC301.1 PD301.2 PR302.2 PR306.2 PU301.16(S5)
S-BAT-PWR: PF4.2 PF8.1 PQ19.1(S1) PQ19.2(S2) PQ19.3(S3)
S-BAT-TRCL: PD13.2 PD13.3 PD17.1 PD18.1 PF8.2
S-BAT-TRCL_A: PD17.2 PD17.3 PD18.2 PD18.3 PQ23.1(D1) PQ23.2(D2) PQ23.5(D3) PQ23.6(D4)
S_BAT_IN: PC25.2 PF4.1 PJ3.1 PJ3.2
S_BAT_PWR_A: PQ19.5(D) PQ20.1(S1) PQ20.2(S2) PQ20.3(S3) PR36.2
S_TEMP: PC23.2 PD9.1 PJ3.5 PR33.1 R143.1
S_TRCL: PQ24.2(IN) U21.G3(STRCL)
SA0: J21.256(SA0) RD1.1 RD4.2
SA1: J21.260(SA1) RD2.1 RD5.2
SA2: J21.166(SA2) RD3.1 RD6.2
SATA1_DEVSLP: R433.1 U1.J2(GPP_E5/DEVSLP1) U7.2(B)
SATA2_DEVSLP: R789.1 U1.J3(GPP_E6/DEVSLP2)
SATA2_DEVSLP_C: J22.38(DEVSLP) R789.2
SATA_PCIE_SELECT: Q29.1(D) R383.2 U24.18(MODE)
SD_MMC_CLK: R111.1 U15.17(SP3)
SD_MMC_CLK_R: C138.1 J23.5(CLK) R111.2
SD_MMC_CMD: J23.2(CMD) U15.19(SP4)
SD_MMC_D0: J23.7(DAT0) U15.16(SP2)
SD_MMC_D1: J23.8(DAT1) U15.15(SP1)
SD_MMC_D2: J23.9(DAT2) U15.21(SP6)
SD_MMC_D3: J23.1(CD/DAT3) U15.20(SP5)
SD_MMC_WP: J23.12(WP) U15.29(SP7)
SENSE0: J38.9 R213.1 U16.N13(KSI0)
SENSE1: J38.6 R215.1 U16.J6(KSI1)
SENSE2: J38.8 R214.1 U16.N8(KSI2)
SENSE3: J38.1 R219.1 U16.J11(KSI3)
SENSE4: J38.5 R216.1 U16.J12(KSI4)
SENSE5: J38.12 R212.1 U16.J13(KSI5)
SENSE6: J38.3 R217.1 U16.M12(KSI6)
SENSE7: J38.2 R218.1 U16.M13(KSI7)
SENSEN: PR92.1 U5.A10(SENSEN)
SENSEP: PR91.1 U5.B10(SENSEP)
SLEEVE: C9135.1 R10097.2 RA125.2 UA1.37(MIC1-R/SLEEVE)
SM_RCOMP0: RC11.1 U1.AR18(DDR_RCOMP[0])
SM_RCOMP1: RC12.1 U1.AT18(DDR_RCOMP[1])
SM_RCOMP2: RC13.1 U1.AU18(DDR_RCOMP[2])
SMB_CLK: R251.1 U1.R7(GPP_C0/SMBCLK) U19.2(B)
SMB_CLK_3B: J16.14 J21.253(SCL) R249.1 U19.1(A)
SMB_DATA: R252.1 U1.R8(GPP_C1/SMBDATA) U20.2(B)
SMB_DATA_3B: J16.20 J21.254(SDA) R248.1 U20.1(A)
SML0_CLK: RC25.1 RL4.1 U1.R9(GPP_C3/SML0CLK)
SML0_DATA: RC26.1 RL5.1 U1.W2(GPP_C4/SML0DATA)
SP_OUTL+: CA53.2 J4.4 LA14.2
SP_OUTL+_AUDIO: CA122.1 LA14.1 UA1.47(SPK-OUT-LP)
SP_OUTL-: CA54.2 J4.3 LA13.2
SP_OUTL-_AUDIO: CA127.1 LA13.1 UA1.48(SPK-OUT-LN)
SP_OUTR+: CA55.2 J4.2 LA12.2
SP_OUTR+_AUDIO: CA243.1 LA12.1 UA1.50(SPK-OUT-RP)
SP_OUTR-: CA56.2 J4.1 LA11.2
SP_OUTR-_AUDIO: CA117.1 LA11.1 UA1.49(SPK-OUT-RN)
SPI_CLK: R241.1 RC129.1 U1.AV2(SPI0_CLK)
SPI_CLK_2_R: R241.2 U26.19(SCLK)
SPI_CLK_LFT: R441.1 U186.6(CLK)
SPI_CLK_LFT_R: R441.2 U5.A3(SPI_CLK)
SPI_CLK_R: RC129.2 UC5.6(CLK)
SPI_CS#_LFT: R715.2 U5.B3(SPI_SSZ) U186.1(/CS)
SPI_IO2: RC131.2 RC151.2 U1.AW2(SPI0_IO2)
SPI_IO2_R: RC126.1 RC131.1 UC5.3(/WP(IO2))
SPI_IO3: RC133.2 RC150.2 U1.AU4(SPI0_IO3)
SPI_IO3_R: RC127.1 RC133.1 UC5.7(/HOLD/RESET(IO3))
SPI_MISO_IO1: R243.1 RC132.1 RC141.1 U1.AW3(SPI0_MISO)
SPI_MISO_IO1_2_R: R243.2 U26.24(MISO)
SPI_MISO_IO1_R: RC132.2 UC5.2(DO(IO1))
SPI_MISO_LFT: R714.2 U5.A4(SPI_MISO) U186.2(DO(IO1))
SPI_MOSI_IO0: R242.1 RC130.1 RC140.1 U1.AV3(SPI0_MOSI)
SPI_MOSI_IO0_2_R: R242.2 U26.21(MOSI)
SPI_MOSI_IO0_R: RC130.2 UC5.5(DI(IO0))
SPI_MOSI_LFT: U5.B4(SPI_MOSI) U186.5(DI(IO0))
SUS_DRV: C209.2 D41.1 R290.1 U21.D4(RD2_DRV)
SUS_ON1: PD701.1 PR718.2 R147.1 U16.B2(BGPO1/GPIO101) U21.H4(RD2_ON)
SUS_ON2: PR755.1 R149.1 U16.C4(BGPO2/GPIO102)
SUSACK: RC68.2 U1.AP11(GPP_A15/SUSACK#)
SUSCLK_32K: J32.50(SUSCLK) U1.BA17(GPD8/SUSCLK) U16.B3(32KHZ_IN/GPIO165)
SVID_CLK: PR404.2 PR407.1 RC77.1 U1.A63(VIDSCK)
SVID_DATA: PR401.2 PR408.1 RC161.1 U1.D64(VIDSOUT)
SW_1A: PR411.2 PR463.2
SW_1B: PR439.2 PR467.2
SYS_MDI_0+: T1.1(TD1+) U14.22(C3-)
SYS_MDI_0-: T1.2(TD1-) U14.23(C3+)
SYS_MDI_1+: T1.5(TD2+) U14.26(C2-)
SYS_MDI_1-: T1.6(TD2-) U14.27(C2+)
SYS_MDI_2+: T1.7(TD3+) U14.31(C1-)
SYS_MDI_2-: T1.8(TD3-) U14.32(C1+)
SYS_MDI_3+: T1.11(TD4+) U14.35(C0-)
SYS_MDI_3-: T1.12(TD4-) U14.36(C0+)
SYS_PWROK: RC65.2 U1.B6(SYS_PWROK)
T1_PIN3: C116.2 C117.2 C118.2 C119.2 C120.2 C121.2 C123.2 T1.3(TCT1) T1.4(TCT2) T1.9(TCT3) T1.10(TCT4)
T1_PIN15: R96.2 T1.15(MCT4)
T1_PIN16: R97.2 T1.16(MCT3)
T1_PIN21: R99.2 T1.21(MCT2)
T1_PIN22: R98.2 T1.22(MCT1)
TH_DET: C208.2 RT1.1 U21.J3(TH_DTCT)
TOUCH_EN: D16.1 J11.11 R353.1 R10141.2 U16.N3(ADC7/GPIO207)
TP4_RESET: J16.11 J37.2 R222.1 U16.A13(GPIO133)
TP4CLK: J16.18 J37.6 R221.1
TP4DATA: J16.16 J37.1 R220.1
TP_DIMM0_CHA_S2_N: J21.162(C0/CS2_N/NC) TP31.1
TP_DIMM0_CHA_S3_N: J21.165(C1/CS3_N/NC) TP32.1
TYPEC_CON_RXN1: D87.2(LINE-2) D87.8(NC2) JTYC1.22(RX1-_B10) L14.2 R9114.2
TYPEC_CON_RXN2: D88.4(LINE-3) D88.7(NC3) JTYC1.10(RX2-_A10) L15.3 R9115.2
TYPEC_CON_RXP1: D87.1(LINE-1) D87.9(NC1) JTYC1.23(RX1+_B11) L14.3 R9111.2
TYPEC_CON_RXP2: D88.5(LINE-4) D88.6(NC4) JTYC1.11(RX2+_A11) L15.2 R9118.2
TYPEC_CON_TXN1: D87.5(LINE-4) D87.6(NC4) JTYC1.3(TX1-_A3) L12.2 R9104.2
TYPEC_CON_TXN2: D88.1(LINE-1) D88.9(NC1) JTYC1.15(TX2-_B3) L13.3 R9105.2
TYPEC_CON_TXP1: D87.4(LINE-3) D87.7(NC3) JTYC1.2(TX1+_A2) L12.3 R9103.2
TYPEC_CON_TXP2: D88.2(LINE-2) D88.8(NC2) JTYC1.14(TX2+_B2) L13.2 R9109.2
TYPEC_HPD_PD: R725.2 U5.C10(GPIO4)
U24_DE_A: R342.1 R346.2 U24.17(DE_A)
U24_DE_B: R343.1 R347.2 U24.8(DE_B)
U24_EN#: R352.1 U24.7(EN#)
U24_EQ_A: R344.1 R348.2 U24.16(EQ_A)
U24_EQ_B: R345.1 R349.2 U24.9(EQ_B)
U25_DE_A: R356.1 R360.2 U25.17(DE_A)
U25_DE_B: R357.1 R361.2 U25.8(DE_B)
U25_EQ_A: R358.1 R362.2 U25.16(EQ_A)
U25_EQ_B: R359.1 R363.2 U25.9(EQ_B)
U25_MODE: R365.1 U25.18(MODE)
U28_HOLD#: R716.2 U186.7(/HOLD(IO3))
U28_WP#: R713.2 U186.3(/WP(IO2))
UIM_CLK: D18.5(P1_5) J25.3(CLOCK) R104.2
UIM_DATA: D18.3(P1_3) J22.34(UIM-DATA) J25.7(IO)
UIM_PWR: C124.2 D18.2 J22.36(UIM-PWR) J25.1(VCC)
UIM_RESET: D18.1 J22.30(UIM-RESET) J25.2(RESET)
USB2_ID: RC157.2 U1.AG3(USB2_ID)
USB2_VBUSSENSE: RC156.2 U1.AG4(USB2_VBUSSENSE)
USB3P0_RXN: E_L2.1 U1.H8(USB3_1_RXN)
USB3P0_RXN_CONN: D15.5(LINE-4) D15.6(NC4) E_L2.2 J34.5(STDA_SSRX-)
USB3P0_RXP: E_L2.4 U1.G8(USB3_1_RXP)
USB3P0_RXP_CONN: D15.4(LINE-3) D15.7(NC3) E_L2.3 J34.6(STDA_SSRX+)
USB3P0_TXN: C97.2 U1.C13(USB3_1_TXN)
USB3P0_TXN_C: C97.1 E_L3.1
USB3P0_TXN_CONN: D15.2(LINE-2) D15.8(NC2) E_L3.2 J34.8(STDA_SSTX-)
USB3P0_TXP: C98.2 U1.D13(USB3_1_TXP)
USB3P0_TXP_C: C98.1 E_L3.4
USB3P0_TXP_CONN: D15.1(LINE-1) D15.9(NC1) E_L3.3 J34.9(STDA_SSTX+)
USB3P1_RXN: C8345.1 U1.J10(USB3_3_RXN/SSIC_2_RXN)
USB3P1_RXN_TYPEC: C8345.2 U183.4(SSRXN)
USB3P1_RXP: C8347.1 U1.H10(USB3_3_RXP/SSIC_2_RXP)
USB3P1_RXP_TYPEC: C8347.2 U183.5(SSRXP)
USB3P1_TXN: C8349.1 U1.B15(USB3_3_TXN/SSIC_2_TXN)
USB3P1_TXN_TYPEC: C8349.2 U183.7(SSTXN)
USB3P1_TXP: C8348.1 U1.A15(USB3_3_TXP/SSIC_2_TXP)
USB3P1_TXP_TYPEC: C8348.2 U183.8(SSTXP)
USB3P3_RXN_DOCK: J17.40(DOCK_USB_SS_RXN) U1.E10(USB3_4_RXN)
USB3P3_RXN_SYS: E_L8.1 U1.G11(PCIE2_RXN/USB3_6_RXN)
USB3P3_RXN_SYS_CONN: D53.1(LINE-1) D53.9(NC1) E_L8.2 J42.5(STDA_SSRX-)
USB3P3_RXP_DOCK: J17.41(DOCK_USB_SS_RXP) U1.F10(USB3_4_RXP)
USB3P3_RXP_SYS: E_L8.4 U1.F11(PCIE2_RXP/USB3_6_RXP)
USB3P3_RXP_SYS_CONN: D53.2(LINE-2) D53.8(NC2) E_L8.3 J42.6(STDA_SSRX+)
USB3P3_TXN_DOCK: J17.43(DOCK_USB_SS_TXN) U1.C15(USB3_4_TXN)
USB3P3_TXN_SYS: C236.2 U1.D16(PCIE2_TXN/USB3_6_TXN)
USB3P3_TXN_SYS_C: C236.1 E_L7.1
USB3P3_TXN_SYS_CONN: D53.4(LINE-3) D53.7(NC3) E_L7.2 J42.8(STDA_SSTX-)
USB3P3_TXP_DOCK: J17.44(DOCK_USB_SS_TXP) U1.D15(USB3_4_TXP)
USB3P3_TXP_SYS: C235.2 U1.C16(PCIE2_TXP/USB3_6_TXP)
USB3P3_TXP_SYS_C: C235.1 E_L7.4
USB3P3_TXP_SYS_CONN: D53.5(LINE-4) D53.6(NC4) E_L7.3 J42.9(STDA_SSTX+)
USB20_N1_B: L16.1 R10253.1 U5.L7(C_USB_BN)
USB20_N1_B_C: JTYC1.19(D-_B7) L16.2 R10253.2 U193.17(D3)
USB20_N1_T: L17.4 R10255.1 U5.L6(C_USB_TN)
USB20_N1_T_C: JTYC1.7(D-_A7) L17.3 R10255.2 U193.19(D2)
USB20_P1_B: L16.4 R10254.1 U5.K7(C_USB_BP)
USB20_P1_B_C: JTYC1.18(D+_B6) L16.3 R10254.2 U193.16(D4)
USB20_P1_T: L17.1 R10256.1 U5.K6(C_USB_TP)
USB20_P1_T_C: JTYC1.6(D+_A6) L17.2 R10256.2 U193.20(D1)
USB_ON1: U13.4(EN) U16.B4(BGPO4/GPIO173)
USB_ON2: U12.5(EN) U16.E4(BGPO5/GPIO174)
USB_PWR_S1: C99.2 C100.2 C101.1 J34.1(VBUS) U12.12(OUT)
USB_PWR_S2: C230.2 C232.2 C234.1 J42.1(VBUS) U13.6(OUT#6) U13.7(OUT#7) U13.8(OUT#8)
USBC_CC1: C815.1 R707.2 R10245.1 TP77.1 U5.L9(C_CC1) U193.12(CC1)
USBC_CC1_CONN: JTYC1.5(CC1_A5) R10245.2 U193.4(C_CC1) U193.7(RPD_G1)
USBC_CC2: C817.1 R708.2 R10246.1 TP78.1 U5.L10(C_CC2) U193.11(CC2)
USBC_CC2_CONN: JTYC1.17(CC2_B5) R10246.2 U193.5(C_CC2) U193.6(RPD_G2)
USBC_DPAUX1: R10243.1 U183.27(SBU1) U193.15(SBU1)
USBC_DPAUX1_C: JTYC1.8(SBU1_A8) R9110.1 R10243.2 U193.1(C_SBU1)
USBC_DPAUX2: R10244.1 U183.26(SBU2) U193.14(SBU2)
USBC_DPAUX2_C: JTYC1.20(SBU2_B8) R9108.2 R10244.2 U193.2(C_SBU2)
USBCOMP: RC48.2 U1.AB6(USB2_COMP)
USBP0+: U1.AB10(USB2P_1) U12.3(DP_OUT)
USBP0+_AOU: E_L1.4 U12.10(DP_IN)
USBP0+_CONN: D13.3(I/O1) E_L1.3 J34.3(D+)
USBP0-: U1.AB9(USB2N_1) U12.2(DM_OUT)
USBP0-_AOU: E_L1.1 U12.11(DM_IN)
USBP0-_CONN: D13.4(I/O3) E_L1.2 J34.2(D-)
USBP1+: U1.AD7(USB2P_2) U5.L5(USB_RP_P)
USBP1-: U1.AD6(USB2N_2) U5.K5(USB_RP_N)
USBP2+: R102.2 U1.AJ3(USB2P_3)
USBP2+_CONN: D17.2 J22.7(USB_D+) R102.1
USBP2-: R103.2 U1.AH3(USB2N_3)
USBP2-_CONN: D17.3 J22.9(USBD-) R103.1
USBP3+_DOCK: J17.38(DOCK_USB_SS_DP) U1.AD10(USB2P_4)
USBP3+_SYS: E_L9.1 U1.AF7(USB2P_6)
USBP3+_SYS_CONN: D54.3(I/O1) E_L9.2 J42.3(D+)
USBP3-_DOCK: J17.37(DOCK_USB_SS_DN) U1.AD9(USB2N_4)
USBP3-_SYS: E_L9.4 U1.AF6(USB2N_6)
USBP3-_SYS_CONN: D54.4(I/O3) E_L9.3 J42.2(D-)
USBP4+: J26.6 U1.AJ2(USB2P_5)
USBP4-: J26.4 U1.AJ1(USB2N_5)
USBP6+: R105.2 U1.AH2(USB2P_7)
USBP6+_CONN: D19.3 J32.3(USB_D+) R105.1
USBP6-: R106.2 U1.AH1(USB2N_7)
USBP6-_CONN: D19.2 J32.5(USB_D-) R106.1
USBP7+: R12.1 U1.AF9(USB2P_8)
USBP7+_CONN: J11.8 R12.2
USBP7-: R11.1 U1.AF8(USB2N_8)
USBP7-_CONN: J11.9 R11.2
USBP8+: R461.1 U1.AG2(USB2P_9)
USBP8+_CONN: D711.2 J16.6 R461.2
USBP8-: R462.1 U1.AG1(USB2N_9)
USBP8-_CONN: D711.3 J16.4 R462.2
USBP9+: R9.1 U1.AH8(USB2P_10)
USBP9+_CONN: J11.19 R9.2
USBP9-: R8.1 U1.AH7(USB2N_10)
USBP9-_CONN: J11.20 R8.2
VBL20: C6.2 C7.2 C8.2 C267.2 C268.1 F1.2 J10.26 J10.27 J10.28 J10.29
VGA_BLON: RC3.1 U1.R12(EDP_BKLTEN) U16.C9(GPIO143/SMB04_DATA)
VIDEO_ID: R183.2 U16.F2(GPIO062)
VL5: PC212.1 PU201.13(VREG5) R255.1
VREGIN20: PD10.1 PD11.1 PD12.1 PD13.1 PD14.1 PD31.1 R274.2 R275.2 R276.2 R280.2
VSYS: C1.1 C205.2 D38.2 F1.1 PC167.1 PC211.1 PC500.1(P) PC501.1(P) PC502.1(P) PC503.1(P) PJ201.2 PJ202.1 PJ301.1 PJ701.1 PL405.1 PL406.1 PL407.1 PL408.1 PL410.1 PQ108.5(D) PR402.1 PU201.12(VIN) R273.2
VSYS_OUT: PC129.1 PC132.1 PC135.1 PC140.1 PC150.1 PC156.1 PC160.1 PC161.1 PC170.2 PC182.1 PC183.1 PF9.1 PQ42.2(COLLECTOR) PQ103.1(S1) PQ103.2(S2) PQ103.3(S3) PQ108.1(S1) PQ108.2(S2) PQ108.3(S3) PQ112.5(D) PR24.1 PR169.1 PU101.22(VSYS)
WIGIG_AUXN: J32.20(DP_AUXN) R368.1 U147.59(DP2_AUXN_SDA)
WIGIG_AUXP: J32.22(DP_AUXP) R369.2 U147.60(DP2_AUXP_SCL)
WIGIG_DP0N: C247.1 U147.43(DP2_D0N)
WIGIG_DP0N_C: C247.2 J32.32(DP_ML0N)
WIGIG_DP0P: C248.1 U147.44(DP2_D0P)
WIGIG_DP0P_C: C248.2 J32.34(DP_ML0P)
WIGIG_DP1N: C245.1 U147.40(DP2_D1N)
WIGIG_DP1N_C: C245.2 J32.26(DP_ML1N)
WIGIG_DP1P: C246.1 U147.41(DP2_D1P)
WIGIG_DP1P_C: C246.2 J32.28(DP_ML1P)
WIGIG_DP2N: C251.2 U147.38(DP2_D2N)
WIGIG_DP2N_C: C251.1 J32.25(DP_ML2N)
WIGIG_DP2P: C252.2 U147.39(DP2_D2P)
WIGIG_DP2P_C: C252.1 J32.27(DP_ML2P)
WIGIG_DP3N: C249.2 U147.35(DP2_D3N)
WIGIG_DP3N_C: C249.1 J32.19(DP_ML3N)
WIGIG_DP3P: C250.2 U147.36(DP2_D3P)
WIGIG_DP3P_C: C250.1 J32.21(DP_ML3P)
WIGIG_HPD: J32.31(DP_HPD) U147.42(DP2_HPD)
WWAN_CFG0: D30.2 R601.1 U1.AF11(GPP_F8/I2C4_SDA) U191.7(1B)
WWAN_CFG0_SW: D30.1 J22.21(CONFIG_0) Q226.2(G) R10089.1 U191.2(1A)
WWAN_CFG1: J22.69(CONFIG_1) R322.2 U1.AF12(GPP_F9/I2C4_SCL) U163.3(A)
WWAN_CFG2: J22.75(CONFIG_2) U1.AD11(GPP_F10/I2C5_SDA/ISH_I2C2_SDA)
WWAN_CFG3: D29.2 R600.1 U1.AD12(GPP_F11/I2C5_SCL/ISH_I2C2_SCL) U191.6(2B)
WWAN_CFG3_SW: D29.1 J22.1(CONFIG_3) Q227.2(G) R602.2 R10088.1 U191.3(2A)
XCLK_BIASREF: RC57.2 U1.E42(XCLK_BIASREF)
XDP_TCK0: J8.26 RC21.1 U1.A59(JTAGX) U1.B61(PROC_TCK)
XDP_TCK1: J8.24 RC149.2
XDP_TDI: J8.22 RC138.2 U1.D59(PCH_JTAG_TDI) U1.D60(PROC_TDI)
XDP_TDO: J8.20 RC112.1 U1.A56(PCH_JTAG_TDO) U1.A61(PROC_TDO)
XDP_TMS: J8.23 RC139.2 U1.C59(PCH_JTAG_TMS) U1.C60(PROC_TMS)
XTAL24_IN: CC11.2 RC55.2 U1.E37(XTAL24_IN) Y1.3
XTAL24_OUT: RC55.1 RC56.1 U1.E35(XTAL24_OUT)
XTAL24_OUT_R: CC10.2 RC56.2 Y1.1
N8823807: C202.2 D36.2 D37.1
N8824787: C202.1 U21.A4(CP10OUT)
N8840754: C197.2 R273.1 U21.G1(VINT20)
N8903373: R276.1 R278.1 R279.2
N8905800: C199.2 R278.2 U21.G2(BAT_VOLT)
N8910919: C200.2 R274.1 R275.1 U21.H1(VREGIN20)
N8950489: CC72.1 CC73.2 DC4.1 RC125.2 RC126.2 RC127.2 UC5.8(VCC)
N8978758: C204.2 U21.E1(CP25OUT)
N8979199: C204.1 D38.1 D39.2
N8985093: C206.2 D39.1 U21.B1(VCPIN25)
N9125912: J8.10 RC118.2
N9822465: C281.1 F16.1 J15.6 J15.7
N10270973: C190.1 Q16.2(G) R255.2
N11760620: J12.1 RC122.1
N16856048: C564.2 J19.5(#5) R1867.1
N17607913: C203.2 R280.1 R281.2 U21.H2(SW_OFF#)
N18158289: Q197.2(G) R2481.2
N18159741: D253.2 Q175.1(OUT) R1869.1 R2481.1
N18161722: QA7.2(G) RA50.2
N18163387: R1219.1 R10096.1
N18163400: R460.1 R10097.1
N19352549: PC133.2 PR134.2 PU101.16(COMP1)
N19352559: PC134.1 PC141.1 PC154.1 PC159.1 PQ103.5(D) PR139.2 PR151.1
N19352573: PR138.1 PR165.1 PU101.2(ACN)
N19352583: PC144.1 PR133.1 PU101.3(ACP)
N19352658: PC136.1 PC146.1 PC180.1 PC181.1 PD102.1 PQ14.5(D) PQ110.5(D) PR102.1 PR103.1 PR158.2 PR197.2
N19352692: PR149.1 PU101.30(BTST1)
N19352696: PR137.1 PU101.25(BTST2)
N19352868: PR145.2 PR154.1 PU101.18(CELL_BATPRES)
N19352870: PC139.2 PR101.2 PR157.2
N19352874: PQ107.1(D) PR135.1 PR147.1 PU101.6(ILIM_HIZ)
N19352884: PC148.2 PR134.1
N19352890: PC131.2 PR141.2
N19352894: PR146.2 PU101.13(SCL)
N19352896: PR148.2 PU101.12(SDA)
N19352902: PC137.1 PR144.1 PU101.17(COMP2)
N19352908: PQ106.2(G) PR163.1 PU101.4(CHRG_OK)
N19352926: PC157.1 PR144.2
N19352946: PR142.2 PU101.11(PROCHOT#)
N19353084: PR157.1 PU101.8(IADPT)
N19353108: PR141.1 PU101.9(IBAT)
N19353922: PR139.1 PU101.20(SRP)
N19353928: PR155.1 PU101.19(SRN)
N19358397: PQ14.4(G) PQ110.4(G) PR160.1
N19358401: PR160.2 PU101.31(HIDRV1)
N19359177: PC142.2 PR153.1
N19359682: PC147.1 PR149.2
N19359877: PC162.1 PR137.2
N19359919: PC143.2 PR156.1
N19361354: PQ112.4(G) PR161.2
N19364702: PC159.2 PQ103.4(G) PR170.2 PR179.1
N19366130: PQ104.1(D) PR179.2
N19368369: PC166.1 PR152.1 PR190.1 PU101.14(CMPIN)
N19368440: PR140.2 PR168.2 PU101.5(ENZ_OTG)
N19370291: PQ105.1(D) PQ107.2(G) PR167.1
N19397717: PD14.2 PD14.3 PF9.2
N19399630: PC145.2 PC164.1 PR133.2 PR196.1
N19402841: PR166.2 PU101.15(CMPOUT)
N19577504: RL7.2 UL1.33(JTAG_TMS)
N19577505: RL8.2 UL1.35(JTAG_TCK)
N19577509: RL9.2 UL1.9(XTAL_OUT)
N19577510: CL10.2 UL1.10(XTAL_IN) YL1.3
N19577511: CL8.2 RL9.1 YL1.1
N19577517: RL10.2 UL1.30(TEST_EN)
N19577520: RL11.2 UL1.12(RBIAS)
N19577582: RL6.1 UL1.1(RSVD1_VCC3P3)
N19578386: C176.2 C177.2 F11.1 J37.10
N19578390: F10.1 J37.8
N19578404: C217.2 F9.1 J38.25
N20831933: PC24.2 PD7.1 PJ3.3 PR34.1
N20831943: PC22.2 PD8.1 PJ3.4 PR35.1
N20861957: PC145.1 PC158.1 PR138.2 PR197.1
N21745234: D22.1 D25.1 D707.1 J17.36(DOCKED2#)
N21915637: J17.56(#DOCK_PWRSHUTDOWN) R116.2
N22083088: R93.1 U14.16(LEDA1)
N22083090: R92.1 U14.15(LEDA0)
N22083114: R95.1 U14.20(LEDC1)
N22083116: R94.1 U14.19(LEDC0)
N22933987: J22.32(UIM-CLK) R104.1
N23175964: C136.1 U15.18(DV33_18)
N23177820: R113.2 U15.9(RREF)
N23204723: R109.1 U15.28(GPIO)
N23216653: C9140.1 C9146.1 UA1.21(VBG/VREF1)
N23216659: R677.1 UA1.53(DMIC-CLK1)
N23216890: C535.1 C536.1 R10197.2 UA1.7(DVDD)
N23216953: R10198.2 UA1.10(VD33STB)
N23216975: C537.1 C538.1 UA1.18(LDO3-CAP)
N23217017: C539.1 R10199.2 UA1.19(DVDD-IO)
N23217050: C545.1 R484.1 UA1.44(LDO1-CAP)
N23217060: C544.1 UA1.31(CPVEE)
N23217075: C543.1 UA1.29(CPVPP)
N23217089: C541.1 C542.1 R10076.2 UA1.24(AVDD2/CPVDD)
N23217095: C540.1 UA1.22(LDO2-CAP)
N23217182: C546.1 C547.1 C549.1 R10200.1 UA1.51(PVDD2)
N23217319: C553.1 C555.1 CA913.1 R10201.1 UA1.46(PVDD1)
N23217371: C551.1 C552.1 R10079.1 UA1.45(AVDD1)
N23217529: C9136.2 UA1.27(CBP1)
N23217531: C9136.1 UA1.28(CBN1)
N23217548: C557.2 UA1.25(CBN2)
N23217550: C557.1 UA1.26(CBP2)
N23217742: C9137.1 C9138.1 UA1.43(VREF)
N23217756: C9139.1 UA1.41(MIC1-CAP)
N23217805: C2503.2 UA1.23(PCBEEP)
N23217875: R1235.1 R10071.1 UA1.55(GPIO8/I2S-MCLK/SPDIF-IN)
N23217894: R1236.1 UA1.56(GPIO7/I2S-BCLK)
N23217896: R1237.1 UA1.3(GPIO6/I2S-OUT)
N23217898: R1238.1 UA1.1(I2S-LRCK/GPIO9)
N23330164: PQ108.4(G) PR171.2
N23330167: PC170.1 PR169.2 PR171.1 PR172.2
N23330170: PQ109.1(D) PR172.1
N23333711: PC18.2 PJ2.3 PR28.1
N23759272: R10095.1 UA1.6(GPIO0/IRQOUT/HD-I2S-SEL)
N24322210: RL3.1 UL1.6(SVR_EN_N)
N24475194: R135.2 U16.K3(ADC0/GPIO200)
N24475200: R143.2 U16.L4(ADC4/GPIO204)
N24476449: D28.2 R148.1 U16.L9(GPIO001/PWM4)
N24476470: R155.1 R393.2 U16.A1(VCI_IN3#/GPIO000)
N24476566: R170.2 U16.E11(VSET)
N24476572: R169.1 U16.E12(SYS_SHDN#)
N24476580: Q8.3(GND) R166.2 R168.2
N24477822: C168.2 R172.2 U16.J1(AVTR_ADC) U16.J3(VREF_ADC)
N24477835: R174.1 R175.1 U16.F4(VBAT)
N24477845: C172.2 U16.H4(VR_CAP)
N24628827: R110.1 U15.32(WAKE#)
N24848500: Q50.1(D) R10132.1
N24852194: PC50.1 PF11.2 PL1.1 PR77.1
N24852299: PC51.1 PD30.1 PR77.2 PU5.2(VIN) PU5.3(EN)
N24852549: PD32.2 PL1.2 PU5.6(SW)
N24852575: PC52.2 PR78.2 PR79.1 PU5.4(FB)
N24852818: PC52.1 PC53.1 PC54.1 PD31.2 PD31.3 PD32.1 PR78.1
N26183937: PC449.1 PR453.2
N26485146: PC214.2 PR209.1
N26485301: PR221.2 PU201.6(EN2) PU201.20(EN1)
N26485546: PC213.1 PU201.3(VREG3)
N26485948: PR217.1 PU201.1(CS1)
N26485951: PR218.1 PU201.5(CS2)
N26486260: PR216.1 PU201.19(VCLK)
N26487268: PC215.1 PR208.2
N28056116: J22.6(FULL_CARD_POWER_OFF#) R101.1
N29079723: PR222.1 PU201.7(PGOOD)
N29084014: PR210.2 PR215.1
N29087944: PR211.2 PR214.1
N29091068: PC435.1 PC436.1 PC437.1 PC438.1 PC439.1 PC498.1 PC499.1 PL405.2 PL406.2 PU402.20(VIN1) PU402.21(VIN2) PU402.22(VIN3) PU402.23(VIN4) PU402.24(VIN5) PU402.25(VIN6)
N29092457: PL401.1 PR455.2 PR463.1 PU402.12(VSW1) PU402.13(VSW2) PU402.14(VSW3) PU402.15(VSW4) PU402.16(VSW5) PU402.17(VSW6) PU402.18(VSW7)
N29129873: PC402.1 PR402.2 PU401.12(VRMP)
N29129876: PC403.1 PR403.2 PU401.13(VCC)
N29130035: PR406.2 PU401.37(EN)
N29130072: PR407.2 PU401.34(SCLK)
N29134352: PR409.2 PU401.33(ALERT#)
N29134792: PR408.2 PU401.32(SDIO)
N29138194: PC429.1 PR441.2
N29138197: PC428.2 PC429.2 PU401.43(COMP_1B)
N29140206: PR410.1 PU401.31(VR_HOT#)
N29143318: PC419.2 PC420.1 PR427.1 PR430.2 PU401.7(CSSUM_2PH)
N29338898: PC430.1 PC434.2 PR439.1 PR440.1 PU401.40(CSP_1B)
N29339953: PR444.2 PU401.14(ROSC_COREGT)
N29340096: PR445.2 PU401.15(ROSC_SAUS)
N29340279: PR447.2 PU401.19(ICCMAX_1A)
N29340282: PR446.1 PU401.18(ICCMAX_2PH)
N29340285: PR448.1 PU401.20(ICCMAX_1B)
N29340288: PR449.1 PU401.21(ADDR_VBOOT)
N29342092: PC432.2 PR442.2 PU401.42(ILIM_1B)
N29342095: PC431.2 PR443.2 PU401.39(IOUT_1B)
N29343341: PC427.2 PR438.2 PU401.44(VSN_1B)
N29343369: PR435.2 PR473.2 PU401.45(VSP_1B)
N29343684: PC421.2 PC423.2 PU401.4(COMP_2PH)
N29343703: PC422.2 PC423.1 PR428.2 PR432.1 PU401.3(FB_2PH)
N29343706: PC421.1 PR432.2
N29343716: PC422.1 PR434.2
N29343719: PR428.1 PR434.1 PU401.2(DIFFOUT_2PH)
N29344201: PC417.2 PR425.2 PU401.1(IOUT_2PH)
N29344430: PC416.2 PR424.2 PU401.48(VSN_2PH)
N29344768: PC412.2 PR419.2 PU401.27(ILIM_1A)
N29344811: PC411.2 PR420.2 PU401.30(IOUT_1A)
N29345521: PC409.2 PC410.2 PU401.26(COMP_1A)
N29345533: PC410.1 PR418.2
N29346155: PR414.2 PR452.2 PU401.24(VSP_1A)
N29346158: PC407.2 PR415.2 PU401.25(VSN_1A)
N29347050: PR440.2 PRT405.1
N29347534: PC425.1 PR436.1 PU401.11(TSENSE_2PH)
N29348069: PR436.2 PR437.1 PRT404.1
N29348378: PR433.1 PU401.5(ILIM_2PH)
N29348381: PC419.1 PC420.2 PR429.1 PR433.2 PRT403.1 PU401.6(CSCOMP_2PH)
N29348448: PR429.2 PR430.1 PRT403.2
N29349112: PC414.2 PC418.1 PR423.2 PU401.8(CSREF_2PH)
N29349219: PC414.1 PR421.1 PU401.10(CSP1_2PH)
N29349790: PC408.1 PR416.1 PU401.23(TSENSE_1PH)
N29349854: PR416.2 PR417.1 PRT402.1
N29350272: PC405.1 PC433.1 PR411.1 PR413.1 PU401.29(CSP_1A)
N29350295: PR413.2 PRT401.1
N29547847: PR453.1 PU402.30(BOOT)
N29548224: PC449.2 PU402.27(PHASEF) PU402.29(PHASED)
N29548894: PU402.8(GL1) PU402.9(GL2) PU402.10(GL3) PU402.11(GL4)
N29600783: PC424.2 PR473.1
N29600817: PR475.1 PU401.35(DRVON)
N29612662: PR305.2 PU301.20(PGOOD)
N29612670: PR304.1 PU301.19(MODE)
N29612674: PR303.2 PU301.18(TRIP)
N29612764: PC311.1 PR309.2
N29665536: PR749.2 TP56.1
N29668691: PC404.2 PR452.1
N29795820: PR450.1 PU401.9(CSP2_2PH)
N29796111: PC451.1 PR451.2 PU402.6(VCC)
N30910915: R90.1 U12.16(ILIM_HI)
N31995447: R89.1 U12.15(ILIM_LO)
N36983374: Q14.3(G) R231.1
N37033408: PC27.1 PR43.1 PR44.1 PR45.2
N37033752: Q23.4 R305.2
N37033767: Q33.4 R389.2
N39421875: CC76.2 RC10.1 RC154.1 U1.AT13(DRAM_RESET#)
N39422981: RC15.1 U1.C63(THERMTRIP#)
N39424064: RC17.2 U1.AT16(PROC_POPIRCOMP)
N39424067: RC18.2 U1.AU16(PCH_OPIRCOMP)
N39424070: RC19.2 U1.H66(OPCE_RCOMP)
N39424073: RC20.2 U1.H65(OPC_RCOMP)
N39427468: RC24.1 U1.R10(GPP_C2/SMBALERT#)
N39479511: RC34.1 U1.AR7(GPP_B18/GSPI0_MOSI)
N39481801: RC36.2 RC37.1
N39482349: RC43.1 U1.AB7(SD_RCOMP)
N39518225: QC2.1(D) QC3.2(G) RC72.1
N39518574: RC59.2 RC60.2 UC3.4(OUT_Y)
N39523416: RC71.1 S1.3 S1.4
N39556609: TP26.1 U1.AK42(VCCGTX_AK42) U1.AK43(VCCGTX_AK43) U1.AK45(VCCGTX_AK45) U1.AK46(VCCGTX_AK46) U1.AK48(VCCGTX_AK48) U1.AK50(VCCGTX_AK50) U1.AK52(VCCGTX_AK52) U1.AK53(VCCGTX_AK53) U1.AK55(VCCGTX_AK55) U1.AK56(VCCGTX_AK56) U1.AK58(VCCGTX_AK58) U1.AK60(VCCGTX_AK60) U1.AK70(VCCGTX_AK70) U1.AL43(VCCGTX_AL43) U1.AL46(VCCGTX_AL46) U1.AL50(VCCGTX_AL50) U1.AL53(VCCGTX_AL53) U1.AL56(VCCGTX_AL56) U1.AL60(VCCGTX_AL60) U1.AM48(VCCGTX_AM48) U1.AM50(VCCGTX_AM50) U1.AM52(VCCGTX_AM52) U1.AM53(VCCGTX_AM53) U1.AM56(VCCGTX_AM56) U1.AM58(VCCGTX_AM58) U1.AU58(VCCGTX_AU58) U1.AU63(VCCGTX_AU63) U1.BB57(VCCGTX_BB57) U1.BB66(VCCGTX_BB66)
N39575490: RC86.1 U1.AM23(VCCIO_SENSE)
N39575498: RC90.2 U1.AM22(VSSIO_SENSE)
N39920601: PC26.2 PC27.2 PQ21.4(S) PQ23.4(S) PR6.2 PR40.2 PR43.2 PU6.1(ANODE)
N39920640: PC26.1 PR40.1 PR41.1 PR42.2
N39920674: PQ22.1(OUT) PR42.1
N39920740: PQ24.1(OUT) PR45.1
N39921018: PQ21.3(G) PR41.2
N40031233: D1.2 R1.1
N40031285: Q1.4 R2.2
N40033673: C298.2 F5.1 F6.1 J11.23 J11.24 J11.25
N40033695: C20.2 J11.13 R10.2
N40033718: F3.1 J11.10
N40033888: D2.2 D16.2 J11.22 R6.1 R15.1
N40033918: F4.1 J11.12 J11.29
N40034001: J11.28 R7.2
N40088132: CC39.2 CC40.2 CC41.1 RC97.2 U1.K15(VCCAMPHYPLL_1P0_K15) U1.L15(VCCAMPHYPLL_1P0_L15)
N40088146: CC46.2 CC47.2 CC99.2 RC98.2 U1.V15(VCCAPLL_1P0)
N40088321: CC38.2 U1.AL1(DCPDSW_1P0)
N40089937: CC36.2 CC37.2 RC95.1 U1.K19(VCCCLK2)
N40089981: CC42.2 U1.BB10(DCPRTC)
N40089989: CC44.2 CC45.2 RC96.1 U1.N20(VCCCLK4)
N40090005: CC48.2 CC49.2 RC99.1 U1.L19(VCCCLK5)
N40121322: RC100.2 U1.E70(CFG[4])
N40140775: RC102.2 U1.G69(CFG[9])
N40141073: TP27.1 U1.AR56(ZVM#)
N40141075: TP28.1 U1.AP56(MSM#)
N40141187: RC104.1 U1.AY3(RSVD_AY3)
N40141189: RC107.1 U1.AY71(VSS_AY71)
N40141199: RC110.1 U1.C64(PROC_SELECT#)
N40169308: RL4.2 UL1.28(SMB_CLK)
N40169311: RL5.2 UL1.31(SMB_DATA)
N40199736: R140.2 U16.E8(SMB02_DATA)
N40199739: R142.2 U16.B8(SMB02_CLK)
N40201576: R144.2 U16.D10(GPIO171/MSDATA)
N40201579: R145.2 U16.E10(GPIO170/MSCLK)
N40213362: R165.1 U16.D9(SMB03_DATA/GPIO007)
N40213365: R167.1 U16.F8(SMB03_CLK/GPIO010)
N40218948: R186.2 U16.F9(GPIO104/UART_TX)
N40218953: R187.2 U16.A9(GPIO105/UART_RX)
N40218963: R185.2 U16.E5(GPIO051/FAN_TACH1)
N40220825: R180.1 U16.D4(VCI_IN6#/GPIO167)
N40220830: R179.1 U16.A2(VCI_IN5#/GPIO235)
N40224251: R193.2 U16.M4(ADC14/GPIO216)
N40224256: R194.2 U16.N2(ADC13/GPIO215)
N40224261: R195.2 U16.M2(ADC12/GPIO214)
N40224266: R196.2 U16.L3(ADC11/GPIO213)
N40224271: R197.2 U16.L1(ADC10/GPIO212)
N40224294: R198.2 U16.J2(ADC8/GPIO210)
N40224614: R202.2 U16.E1(GPIO023)
N40238712: D31.1 R233.2
N40247293: R266.2 U21.H6(SUS_PWR_ACK)
N40247656: R258.1 U21.C6(PGPIO0)
N40247661: R257.1 U21.C8(PGPIO2)
N40247666: R256.1 U21.C9(PGPIO3)
N40248108: R259.1 U21.A8(PGPIO5)
N40249057: R260.1 U21.E7(MON)
N40255208: R286.1 U21.D6(M_PGS)
N40255459: R277.1 U21.C5(VCC5B)
N40256670: D64.2 D65.2 R405.1 U21.H5(RD4_ON)
N40257016: R281.1 S3.1 S3.2
N40263086: Q17.3(G) R290.2
N40263128: Q17.4(S) R292.2 RJ4.2
N40263130: D41.2 R292.1
N40263477: Q19.4 R295.2
N40263481: Q19.5 R294.2 RJ5.2
N40263483: D42.2 R294.1
N40264076: C283.2 Q21.5 R297.1 R387.2
N40264078: D43.2 R297.2
N40264116: Q20.4(G) R299.2
N40264120: Q21.4 R301.2
N40264254: D44.2 R296.1
N40298441: J21.134(EVENT_N/NF) RD11.2
N40300707: CD26.1 RD10.2
N40660374: C75.2 C76.2 C271.1 C301.1 F7.1 J1.10 J1.11 J1.12
N40843801: J38.28 R223.2
N40843803: J38.27 R224.2
N40843805: J38.26 R225.2
N40893685: TP17.1 U1.AY68(DDR0_VREF_DQ)
N40914474: TP19.1 U1.AJ62(VSSEOPIO_SENSE)
N40914475: TP18.1 U1.AL63(VCCEOPIO_SENSE)
N40914505: TP21.1 U1.AE63(VSSOPC_SENSE)
N40914507: TP20.1 U1.AC63(VCCOPC_SENSE)
N40914545: TP22.1 U1.AE62(VCCEOPIO_AE62) U1.AG62(VCCEOPIO_AG62)
N40914597: TP23.1 U1.AB62(VCCOPC_AB62) U1.P62(VCCOPC_P62) U1.V62(VCCOPC_V62)
N40914964: TP24.1 U1.AK62(VCCGTX_SENSE)
N40914967: TP25.1 U1.AL61(VSSGTX_SENSE)
N40915396: RC134.1 RC155.2 UC4.7(ON)
N40941652: J22.67(RESET#) Q30.3(S) R408.1
N41161893: R314.1 U23.5(ILIM)
N41183802: Q26.4(G) R373.2
N41183816: D58.2 R372.2
N41203653: TP37.1 U1.G61(VCC_OPC_1P8_G61) U1.H63(VCC_OPC_1P8_H63)
N41608255: PC216.1 PR212.1
N41608262: PC217.1 PR213.1
N41611184: PC453.1 PR455.1
N41615282: PC313.1 PR311.1
N41768122: PC718.1 PC719.2 PC720.2 PC721.2 PC722.2 PC723.1 PC724.2 PJ702.2 PJ703.2 PL702.2 PU702.22(VSNS)
N41768357: PC787.1 PR760.1
N41768359: PC789.2 PL702.1 PR760.2 PU702.6(SW1) PU702.7(SW2) PU702.8(SW3) PU702.9(SW4)
N41769760: PR761.2 PU702.3(MODE)
N41769790: PR709.1 PU702.5(BST)
N41769795: PC789.1 PR709.2
N41772153: PC712.1 PC713.1 PC714.1 PC715.1 PC788.1 PC790.1 PJ701.2 PU702.15(VIN1) PU702.16(VIN2) PU702.17(VIN3)
N41772969: PC776.1 PU702.21(SLEW)
N41773230: PR708.1 PU702.20(TRIP)
N41773891: PC792.2 PR765.2 PU702.26(VREF)
N41773970: PR765.1 PR766.2 PU702.25(REFIN)
N41775214: PC717.1 PR755.2 PU702.28(EN)
N41952574: Q23.5 R303.2 R384.2
N42326188: TP50.1 U1.D63(CATERR#)
N42347050: TP52.1 UL1.34(JTAG_TDO)
N42347059: TP51.1 UL1.32(JTAG_TDI)
N42411102: C297.1 U15.24(NC4)
N42801050: D61.2 R390.1
N42801054: C282.2 D61.1 R389.1 R406.2 R407.2
N42801106: C285.2 Q33.5 R390.2 RJ3.2
N43195754: PC737.1 PC738.1 PC795.1 PJ712.1 PU706.8(SVIN1) PU706.9(PVIN1) PU706.10(PVIN2)
N43196090: PL703.1 PR722.2 PU706.1(LX1) PU706.2(LX2) PU706.3(LX3)
N43196119: PC745.2 PR722.1
N43196335: PC739.1 PC740.1 PC741.1 PC743.1 PC746.1 PJ711.2 PL703.2 PR723.1
N43196339: PC741.2 PR721.1 PR723.2 PU706.6(FB)
N43202964: PC783.1 PC784.1 PC791.1 PC801.1 PJ715.1 PU701.8(SVIN1) PU701.9(PVIN1) PU701.10(PVIN2)
N43202984: PL704.1 PR803.2 PU701.1(LX1) PU701.2(LX2) PU701.3(LX3)
N43203008: PC803.2 PR724.2 PR753.1 PU701.6(FB)
N43203016: PC756.1 PC785.1 PC786.1 PC793.1 PC803.1 PJ716.2 PL704.2 PR724.1
N43203049: PR750.1 PR801.1 PR802.1 PU701.5(EN)
N43203071: PC802.2 PR803.1
N43454717: R413.2 U16.K10(GPIO131/SMB10_CLK)
N43522042: R414.1 S2.4
N43583220: J22.60(COEX3) R423.1
N43583233: J22.62(COEX2) R424.1
N43583240: J22.64(COEX1) R425.1
N43980886: DC2.2 DC5.1 RC158.2 RC159.1
N44069167: C158.2 Q7.1(D) R392.1
N45388838: Q39.1(D) Q40.2(G) R427.2
N45392029: CA47.2 Q50.2(G) RA49.2
N45551848: PQ37.5(D) PR95.2 PU4.3(ISENSE)
N45551858: PQ37.4(G) PR96.2
N45551860: PC82.1 PR96.1 PU4.4(DRV)
N45551870: PC83.1 PR97.2 PR98.1 PU4.1(VCNTL)
N45551886: PR88.1 PR90.2 PU4.9(EN)
N45551892: PR46.1 PR84.1 PR99.2 PU4.10(VINSEL)
N45551902: PR89.2 PU4.7(OCSET)
N45551908: PC84.1 PU4.6(DELAY)
N45551914: PR87.2 PU4.8(POK)
N45799415: C2587.2 U147.56(CEXT)
N45799418: R2515.2 U147.9(REXT)
N45799426: R2517.2 U147.37(DP2_CA_DET)
N45799427: R2516.2 U147.48(DP1_CA_DET)
N45907884: R9089.2 TC5.1
N45959248: F41.1 J1.1 J1.2 J1.3 J1.4 J1.5 J1.6 J1.7
N46276125: R235.1 U17.8(NCS)
N46276518: TP16.1 U17.9(INT2)
N46487430: R785.1 U5.K2(DEBUG2)
N46487432: R786.1 U5.L2(DEBUG1)
N46487434: R781.2 U5.K3(DEBUG4)
N46487436: R780.2 U5.L3(DEBUG3)
N46487444: C810.2 U5.E1(LDO_BMC)
N46487448: C813.2 U5.K1(LDO_1V8A)
N46487566: R784.1 U5.G2(R_OSC)
N46487568: R728.1 U5.E11(MRESET)
N46487592: R707.1 U5.K9(RPD_G1)
N46487596: R708.1 U5.K10(RPD_G2)
N46487598: R729.2 U5.L4(LSX_R2P)
N46487604: R727.2 U5.E2(UART_TX) U5.F2(UART_RX)
N46487612: R819.2 U5.F1(I2C_ADDR)
N46487616: R782.1 R783.1 U5.F10(BUSPOWERZ)
N46487618: TP57.1 U5.F4(SWD_DATA)
N46487626: R489.2 R724.2 U5.H6(GPIO8)
N46487628: R723.2 U5.D7(GPIO7)
N46487646: TP58.1 U5.F11(RESETZ)
N46487654: R712.1 U5.D5(DEBUG_CTL2)
N46487656: R711.1 U5.E4(DEBUG_CTL1)
N46487724: C818.2 U5.H7(SS)
N46487818: R721.2 U5.E10(GPIO5)
N46508024: PQ13.4(G) PR21.2
N46508038: PQ12.1(S1) PQ12.2(S2) PQ12.3(S3) PR23.2 PR25.1 PR91.2
N46508050: PQ12.4(G) PR22.2
N46508065: PQ12.5(D) PQ13.5(D)
N46562271: PC20.2 PJ2.2 PR27.1
N46562292: PR29.1 PR30.1 PR32.2
N46562298: PD11.2 PD11.3 PF6.2
N46562306: PD10.2 PD10.3 PF5.2
N46562316: PQ17.4(G) PR31.2
N46562349: PQ19.4(G) PR38.2
N46562353: PR36.1 PR37.1 PR39.2
N46562358: PQ20.4(G) PR37.2
N46562406: PQ18.4(G) PR30.2
N46688728: J19.7(GND1) RA8.2
N46688732: J19.8(GND2) RA9.2
N46889804: R508.2 R509.2 U187.C1(OVLO)
N46889918: R450.1 U187.B1(ACOK#)
N46895327: D739.1 D740.1 R66.1 RA39.2
N46963521: R153.1 U16.J4(GPIO227)
N46986221: D709.2 R798.1 U16.N1(ADC5/GPIO205)
N47211988: TP82.1 U5.G4(SWD_CLK)
N47236723: C9463.2 U193.3(VBIAS)
N47456916: F14.1 J16.19
N47681284: J26.11 R904.2
N47749037: C178.1 F42.1 F152.1 J16.2
N47750172: F15.1 J26.20
N47750211: C143.2 F8.1 J26.2
N47896201: CA5.1 RA163.2
N47953170: R10251.1 U16.M8(GPIO222)
N48013537: Q24.5 R302.1 R385.2 R10252.2
N48013539: D47.2 R10252.1
N48013583: Q24.4 R306.2
N48033774: C830.2 U5.H2(VOUT_3V3)
N48288623: TP83.1 U16.J10(GPIO130/SMB10_DATA)
N48312738: R790.2 U5.J1(AUX_P)
N48312901: R791.2 U5.J2(AUX_N)
N48496902: J1.22 R433.2
N49159192: R862.1 U5.A6(PP_FCM_A6) U5.A7(PP_FCM_A7) U5.A8(PP_FCM_A8) U5.B7(PP_FCM_B7)
N49224973: RC166.1 U1.AN43(DDR1_ALERT#)
N49767541: J3.9(GREEN_LED+) RL12.1
N49767564: J3.11(YELLOW_LED+) RL13.2
N50058241: R799.2 U5.C2(GPIO1)
N50058724: R722.2 U5.D10(GPIO2)
N50063965: R443.2 U26.2(GND1)
N50065476: Q41.1(D) R376.2 R428.1 U26.3(NCI1)
N50065544: Q41.2(G) R434.1
N50065958: C186.1 C187.1 C261.1 C262.1 C263.1 C264.1 R237.1 U26.1(NCI/VDD1) U26.8(VDD2) U26.14(VDD/NCI8) U26.22(VDD3)
N50066946: R239.1 U26.27(NCI13)
N50533265: R402.1 U16.H1(GPIO226)
N50533267: R403.1 U16.C5(GPIO225)
N50672369: PC10.1 PD1.2 PR8.1 PR9.1 PR11.2
N50672380: PQ6.4(G) PR9.2
N50672386: PQ8.2(IN) PQ9.1(D)
N50672387: PQ8.1(OUT) PR11.1
N50672395: PQ7.4(G) PR10.2
N50672396: PD2.2 PR10.1 PR12.1
N50672400: PC11.2 PL102.1 PL103.1 PQ7.1(S1) PQ7.2(S2) PQ7.3(S3) PR12.2
N50672407: PQ10.1(D) PR13.1
N50672411: PQ10.2(G) PQ41.1(D) PR14.1
N50672484: PQ11.6(D1) PR15.2 PR16.2
N50674722: PQ5.1(D) PQ10.3(S)
N50675461: PQ2.4(G) PR3.2
N50675493: PR1.2 PR2.2 PR3.1
N50708166: PC102.1 PR102.2 PR103.2 PU101.1(VBUS)
N50730040: PQ15.2(G) PR82.2 PR83.1
N50730081: PQ15.1(D) PR84.2
N50760102: PL404.1 PR467.1 PR476.2 PU405.12(VSW1) PU405.13(VSW2) PU405.14(VSW3) PU405.15(VSW4) PU405.16(VSW5) PU405.17(VSW6) PU405.18(VSW7)
N50760177: PC522.1 PC523.1 PC524.1 PC525.1 PC526.1 PL410.2 PU405.20(VIN1) PU405.21(VIN2) PU405.22(VIN3) PU405.23(VIN4) PU405.24(VIN5) PU405.25(VIN6)
N50760367: PC527.2 PU405.27(PHASEF) PU405.29(PHASED)
N50767547: PC527.1 PR470.2
N50767548: PR470.1 PU405.30(BOOT)
N50767551: PC528.1 PR469.2 PU405.6(VCC)
N50767593: PC536.1 PR476.1
N50767596: PU405.8(GL1) PU405.9(GL2) PU405.10(GL3) PU405.11(GL4)
N50768257: PC463.1 PC464.1 PC465.1 PC466.1 PC467.1 PC468.1 PC469.1 PL407.2 PL408.2 PU403.20(VIN1) PU403.21(VIN2) PU403.22(VIN3) PU403.23(VIN4) PU403.24(VIN5) PU403.25(VIN6)
N50768281: PL402.1 PR461.2 PR465.1 PU403.12(VSW1) PU403.13(VSW2) PU403.14(VSW3) PU403.15(VSW4) PU403.16(VSW5) PU403.17(VSW6) PU403.18(VSW7)
N50768289: PC470.1 PR456.2
N50768292: PR456.1 PU403.30(BOOT)
N50768448: PC470.2 PU403.27(PHASEF) PU403.29(PHASED)
N50768459: PU403.8(GL1) PU403.9(GL2) PU403.10(GL3) PU403.11(GL4)
N50768485: PC471.1 PR457.2 PU403.6(VCC)
N50768505: PC486.1 PR461.1
N50781896: PD1.1 PD2.1 PR13.2
N50782907: PQ42.3(EMITTER) PR7.1
N50782909: PR6.1 PR7.2 PU6.2(REFERENCE)
N50782911: PQ42.1(BASE) PR24.2 PU6.3(CATHODE)
N51213401: TP85.1 U1.A5(VSS_A5)
N51220377: TP88.1 U1.AV1(VSS_AV1)
N51221448: TP90.1 U1.BA71(VSS_BA71)
N51224590: TP92.1 U1.BB70(VSS_BB70)
N51224599: TP91.1 U1.BB67(VSS_BB67)
N51225679: TP94.1 U1.E71(VSS_E71)
N51228720: TP97.1 U1.BA2(VSS_BA2)
N51228736: TP96.1 U1.BA1(VSS_BA1)
N51228745: TP95.1 U1.B71(VSS_B71)
N51231994: C122.2 R96.1 R97.1 R98.1 R99.1 R100.2
N52114023: Q34.B1(EN) R457.2 R458.1
N52114279: D62.2 D63.2 Q35.B1(EN) R398.1 R399.1
N52338190: R312.2 U5.D6(GND_3/HRESET)
N52703631: Q266.4(GATE) R10321.2
N52703637: D744.2 R10320.2
N52706025: C558.1 Q60.4(CT)
N52706078: Q60.3(ON) R324.2 R325.2
N84550702: D46.2 R303.1
N100056917: DC3.2 RC122.2
N529948291: PQ23.3(G) PR44.2
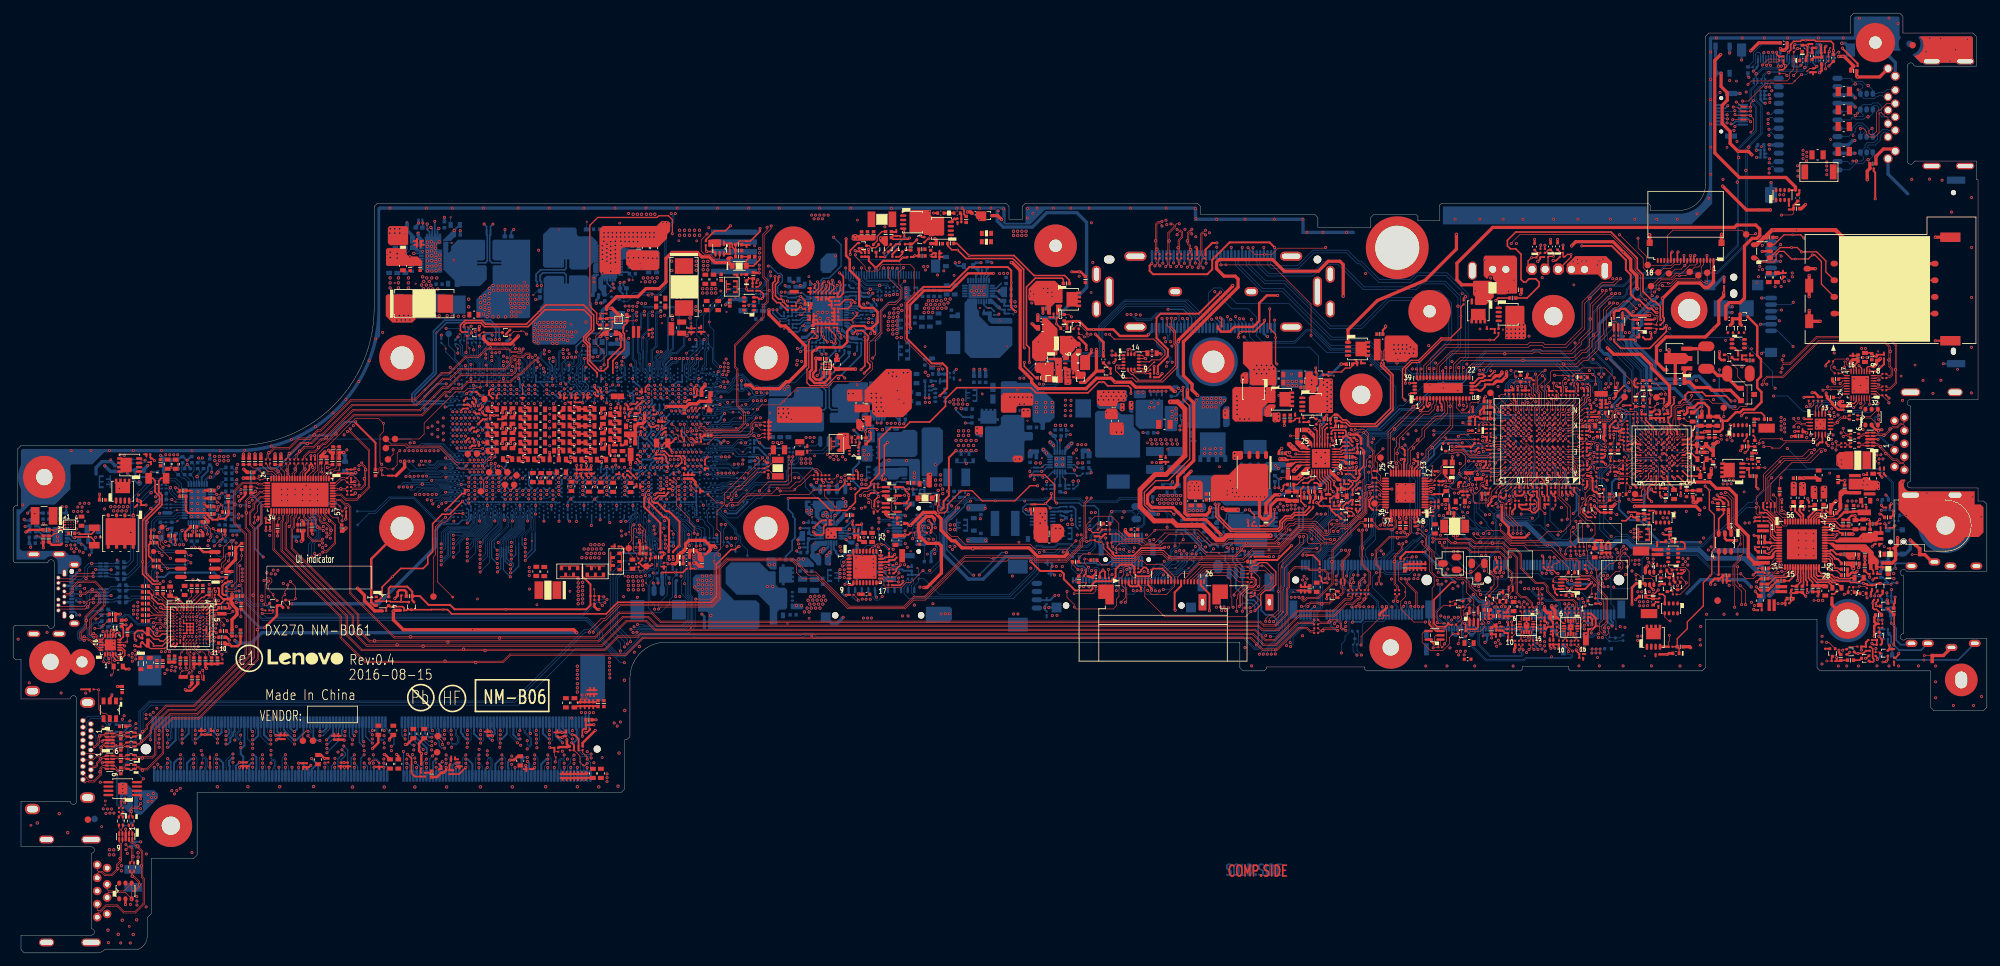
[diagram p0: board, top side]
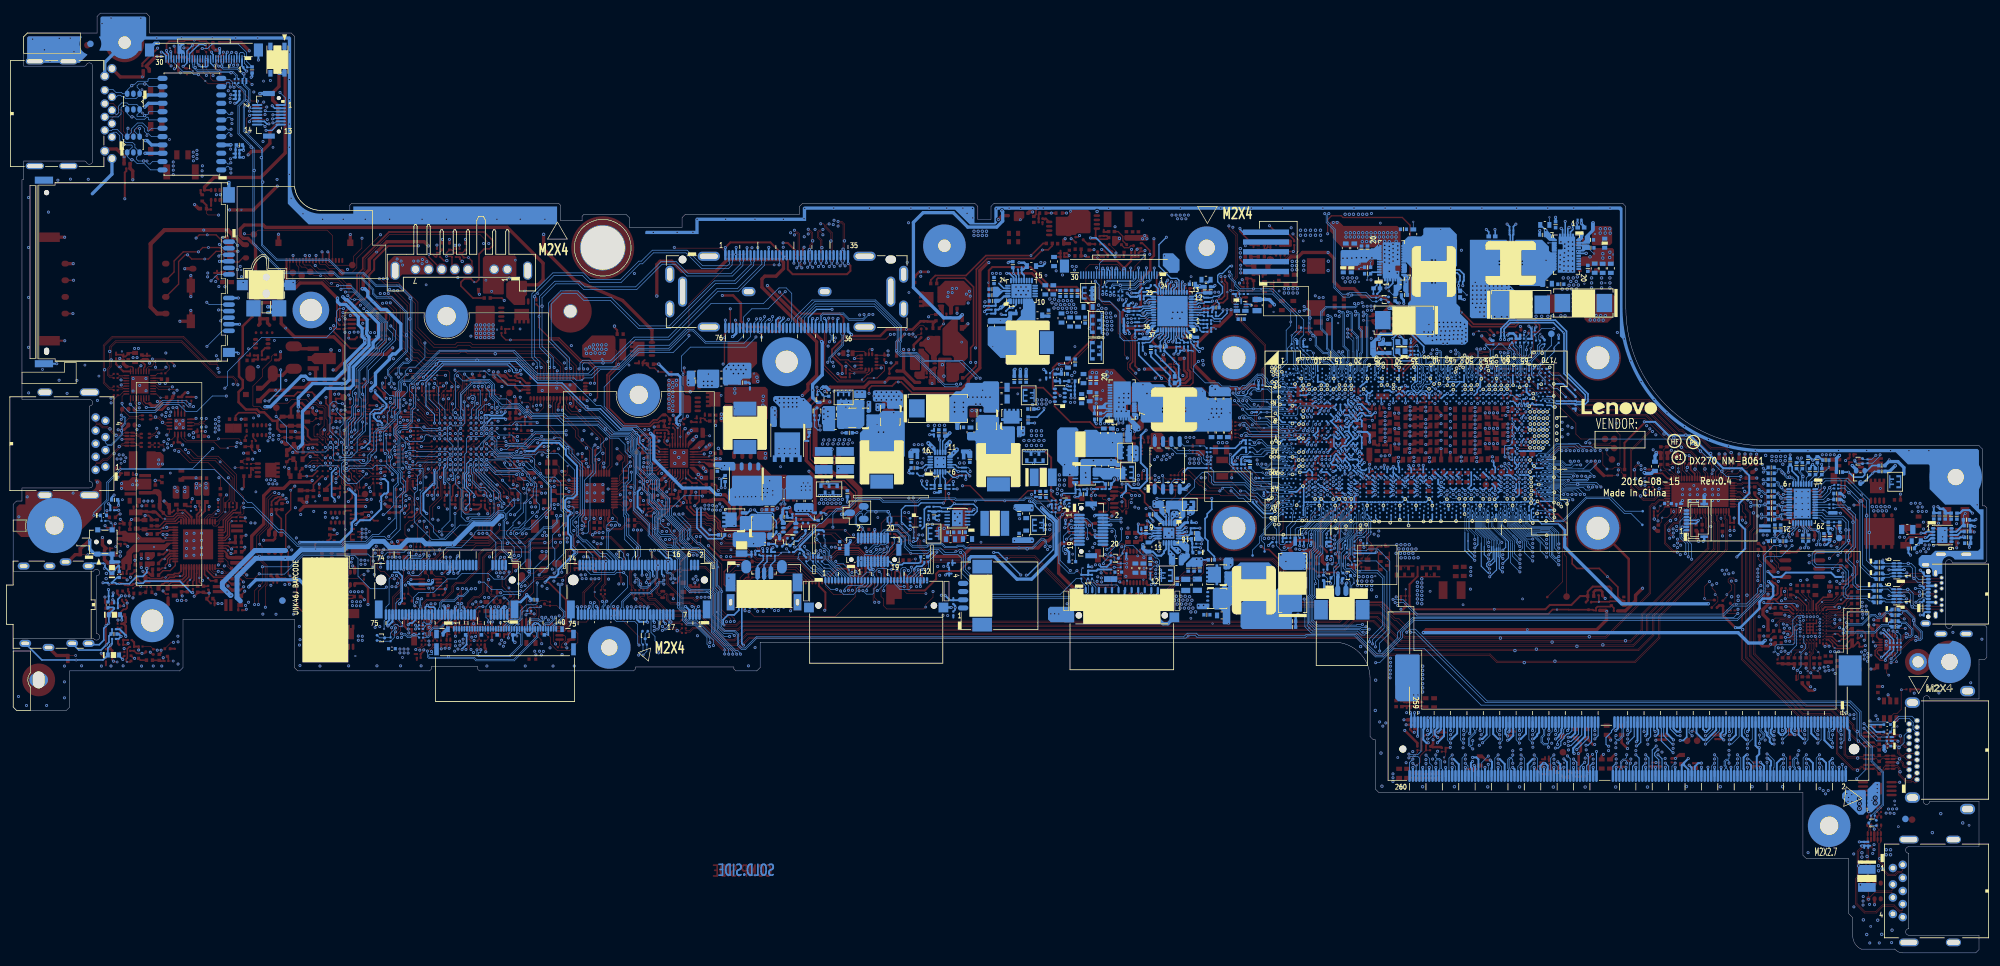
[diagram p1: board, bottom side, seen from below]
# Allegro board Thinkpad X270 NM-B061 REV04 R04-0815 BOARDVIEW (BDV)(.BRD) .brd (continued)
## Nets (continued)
Pads without a net: D13 1 5 6; D54 1 5 6; DL1 2 5; DL2 2 5; FD1 1; FD2 1; FD3 1; FD4 1; FD5 1; FD6 1; H7 1; J1 8 9 13 14; J8 4 5 7 11 12 13 14 15 27 28; J10 1 12 15 25 30; J11 16 17 26; J16 1 3 8 10; J17 14 15 17 18 19 53 57 66 68 69; J21 87 88 91 92 100 101 104 105; J22 10 20 22 23 24 25 26 28 40 42 44 46 48 54 56 58 59 61 63 65 66 68; J25 4 6; J26 1 12 17 18; J32 6 16 17 58 60 62 64; J37 3 4 5; J38 31 32; J41 16 17 18; J43 13 14; PJ2 6 7; PU5 5; PU401 17; PU402 1 28; PU403 1 28; PU405 1 28; PU701 7; PU702 2 4 27; PU706 4 7; U1 A3 A4 A6 A7 A11 A13 A23 A26 A27 A29 A31 A33 A36 A38 A45 A47 A52 A65 A69 AB1 AB2 AB3 AB4 AB11 AB12 AB13 AC1 AC2 AC3 AD1 AH10 AK7 AK9 AK10 AK12 AK13 AK32 AL25 AL27 AM1 AM2 AM3 AM4 AM5 AM7 AM11 AN1 AN2 AN3 AN5 AN7 AN11 AN13 AN21 AN22 AN25 AN27 AN45 AN46 AN48 AN50 AN52 AN53 AN55 AN56 AP5 AP7 AP8 AP13 AP21 AP22 AP25 AP27 AP30 AP33 AP37 AP40 AP43 AP45 AP46 AP48 AP50 AP52 AP53 AP55 AR21 AR22 AR25 AR27 AR30 AR32 AR33 AR37 AR38 AR40 AT1 AT5 AT15 AT21 AT22 AT25 AT27 AT30 AT32 AT33 AT37 AT38 AT40 AU2 AU5 AU11 AU21 AU22 AU25 AU27 AU30 AU33 AU37 AU40 AU56 AW1 AW7 AW20 AW25 AW27 AW29 AW31 AW33 AW35 AW37 AW39 AW42 AW44 AW46 AW48 AW56 AW68 AW69 AW70 AW71 AY1 AY2 AY4 AY5 AY7 AY8 AY20 AY21 AY25 AY26 AY27 AY29 AY30 AY31 AY33 AY34 AY35 AY37 AY38 AY39 AY42 AY43 AY44 AY46 AY47 AY48 AY56 B2 B3 B7 B11 B13 B23 B26 B27 B29 B31 B33 B36 B38 B45 B47 B52 B54 B67 B69 B70 BA3 BA4 BA5 BA7 BA8 BA9 BA25 BA26 BA27 BA29 BA30 BA31 BA33 BA34 BA35 BA37 BA38 BA39 BA42 BA43 BA44 BA46 BA47 BA48 BA67 BA68 BA70 BB2 BB3 BB4 BB5 BB7 BB9 BB25 BB27 BB29 BB31 BB33 BB35 BB37 BB39 BB42 BB44 BB46 BB48 BB68 BB69 C2 C4 C7 C11 C12 C20 C23 C27 C28 C29 C31 C32 C33 C36 C37 C38 C54 C55 C56 C67 C68 C70 C71 D1 D3 D4 D5 D7 D12 D20 D23 D27 D28 D29 D31 D32 D33 D36 D37 D38 D54 D55 D65 D68 D71 E1 E2 E3 E13 E22 E23 E25 E43 E61 E63 E66 E68 F6 F18 F25 F43 F46 F52 F60 F61 F63 F65 F66 F70 F71 G18 G46 G65 G68 G70 G71 H1 H2 H5 H6 H11 H69 H70 J5 J6 J68 J71 K32 K45 K46 L6 M4 N1 N2 N3 N9 N11 N12 P1 P2 P3 P4 U1 U2 U3 U4 U11 U12 W1 W4 W7 W8 W10 W11 W12; U5 K4 K8 L8; U14 5 17 18 40 41; U15 13 22 23 25 26 31; U17 2 3; U21 A1 A9 B2 B3 B4 E8 F2 J1 J9; U23 4; U26 4 5 6 7 10 11 12 13 15 25 26 28 29 30 31; U36 1; U147 6 8 13; UA1 2 4 11 12 34 35 40; UC3 1; UL1 25

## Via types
v1: diameter 0.457, hole 0.203, TOP to BOTTOM, 4065 vias
v2: diameter 0.508, hole 0.254, TOP to BOTTOM, 1089 vias
v3: diameter 0.406, hole 0.203, TOP to BOTTOM, 345 vias
v4: diameter 0.305, hole 0.152, TOP to BOTTOM, 351 vias

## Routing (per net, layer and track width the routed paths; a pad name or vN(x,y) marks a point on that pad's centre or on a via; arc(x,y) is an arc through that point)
1.2V_B+:
  vias: v4(116.88,60.16)
1.2V_GND: length 4.3
  TOP w0.305: 124.86,66 PR304.2 PR303.1 124.86,65.39
  BOTTOM w0.254: PU301.7 127.32,64.45 v2(127.52,64.66) ; PC305.2 127.64,66.51 127.14,66 v1(127.14,65.87)
  BOTTOM w0.305: PR308.2 128.94,64.9
  vias: v4(125.75,65.98)
3V_VIN:
  vias: v3(147.76,85.31)
5V_VIN:
  vias: v1(173.29,83.25) v1(173.97,83.27) v1(174.56,83.86) v3(173.57,83.98)
+3V_MUX: length 24.3
  TOP w0.305: v1(26.41,62.99) 26.24,63.16 R9084.1 26.24,64.2 R9090.2 ; R9116.1 v3(26.34,68.52) 26.34,67.5 26.72,67.12 29.57,67.12 R679.1 29.72,66.74 30.35,66.11 31.14,66.11 v1(31.27,66.23) 32.23,66.23 32.84,66.84 R9112.1 32.84,68.75 32.79,68.8 R9096.1
  BOTTOM w0.254: U183.6 28.75,72.6 29.71,73.55 29.71,74.19 C8339.1 30.28,74.19 v1(30.28,73.35)
  BOTTOM w0.305: v1(23.55,64.63) 23.73,64.81 R9087.2 24.18,64.23 C8338.1 ; R9100.1 27.1,75.73 v1(26.56,75.19) 26.43,75.19 25.91,75.71 R681.2 25.6,75.71 25.1,75.2 R682.2
  BOTTOM w0.381: v1(21.72,69.59) 22.23,70.1 R9106.1
  vias: v1(31.08,63.5) v1(34.01,62.55)
GND: length 1521.8
  TOP w0.102: 159.38,88.35 159.05,88.02 v2(159.03,88.02) ; v2(92.67,108.6) v3(92.74,107.91) ; C77.1 234.41,51.91
  TOP w0.152: v1(172.6,89.55) 172.45,89.7 U17.10 ; U17.5 168.66,89.2 v1(168.59,89.27) ; U17.13 172.18,91.2 v1(172.68,90.7) U17.12 ; U17.15 170.47,92.06 170.29,92.24 170.15,92.24 v1(169.97,92.06) U17.16
  TOP w0.203: v2(22.51,52.72) 22.79,52.44 24.32,52.44 U5.L1 ; v1(15.01,49.27) 14.82,49.07 U193.13 ; v1(188.72,54.4) 189.1,54.4 189.33,54.62 RC137.2 ; U5.G6 U5.G5 ; U5.G6 U5.G7 ; U5.G6 U5.F6 ; U5.G5 U5.H5 U5.H4 ; U5.G5 U5.F5 ; Q35.B2 91.42,96.39 R399.2 91.34,95.42 C296.2 ; U5.F7 U5.F8 U5.E8 U5.E7 ; U5.F7 U5.E7 ; U5.F7 U5.G7 ; U5.F7 U5.F6 ; U5.F5 U5.F6 ; U5.F5 U5.E5 U5.E6 ; U5.F6 U5.E6 ; v1(103.6,82.69) 103.62,82.69 104.09,83.16 RC162.2 ; U187.A1 7.53,65.74 v1(7.37,65.57) ; U5.E7 U5.E6 ; U5.G7 U5.G8
  TOP w0.254: RC35.1 102.42,75.62 v1(102.42,75.3) CC58.1 ; C312.2 32.87,53.22 32.87,52.82 v1(33.07,52.62) 33,52.54 32.41,52.54 C812.1 ; CC79.1 85.16,85.22 85.07,85.31 v1(85.02,85.31) ; v1(271.68,138.6) 271.5,138.42 C21.1 ; PC22.1 232.91,106.18 PC24.1 232.84,105.89 v2(232.47,105.52) ; C2576.1 v1(39.18,64.45) ; v1(273.19,68.11) 273.16,68.08 CA117.2 ; R133.1 230.61,85.83 R154.2 ; v1(133.41,66.66) 133.64,66.43 C143.1 ; C113.1 225.19,88.03 v1(225.89,88.73) ; C134.1 283.26,91.57 C135.1 283.82,91.01 C142.1 284.41,91.29 R113.1 ; v1(259.82,69.87) 260.1,69.59 260.61,69.59 260.78,69.41 260.99,69.41 261.55,68.85 C9464.2 ; v1(69.78,83.43) 69.71,83.43 69.48,83.65 CC86.1 68.77,83.65 RC19.1 ; U13.1 19.24,24.09 19.44,23.89 v1(19.44,23.51) ; v1(214.21,65.21) 214.09,65.1 CL9.1 ; C184.1 168.11,90.36 v1(167.83,90.08) ; PC51.2 155.94,87.74 154.18,89.5 v1(154.18,90.11) ; C539.2 268.97,56.78 v1(268.18,55.99) ; R230.1 136.51,63.79 v1(135.99,63.79) ; PC17.2 111.15,108.03 PC5.2 112.32,108.03 112.33,108.01 ; v1(95.08,72.45) 94.93,72.45 93.84,73.55 RC90.1 ; v1(244.97,78.29) 244.99,78.27 245.41,78.27 R269.1 ; R374.1 224.08,75 224.06,75.02 v1(224.01,75.02) ; R194.1 237.01,85.7 237.01,85.71 236.81,85.71 R200.1 ; CC28.1 97.34,95.06 v1(97.47,95.19) ; J25.5 v1(291.83,97.56) ; C9142.1 266.35,57.12 v1(265.84,56.61) ; v1(268.89,137.45) 268.89,137.15 269.24,136.8 269.34,136.8 ; TP9.1 245.94,65.96 v1(246.74,66.76) ; C549.2 278.6,72.1 v2(279.28,72.1) 279.28,71.41 C555.2 ; v1(96.91,86.62) 96.78,86.62 96.42,86.26 CC29.1 ; R402.2 240.12,79.03 240.32,78.83 v1(240.37,78.83) ; CA122.2 276.7,67.22 277.01,67.22 CA913.2 ; RC166.2 58.4,72.83 ; CA243.2 271.12,68.05 v1(271.05,68.11) ; U26.23 132.73,60.14 132.95,60.36 133.49,60.36 C187.2 R239.2 ; D19.1 200.31,54.51 200.31,54.06 v1(200.29,54.04) ; CC83.1 v1(87.44,74.36) ; C238.2 17.71,34.58 v1(17.84,34.71) ; CA127.2 273.82,68.87 273.63,69.06 v1(273.63,69.32) ; R369.1 199.22,59.68 198.2,60.69 v1(197.24,60.69) ; Q175.3 279.69,45.54 v1(280.04,45.89) ; v1(252.97,106.97) 252.76,106.77 J41.14 ; v1(128.56,73.6) 128.83,73.33 CC72.2 CC73.1 ; J41.10 v1(254.76,106.43) ; U12.14 275.81,83.04 v1(276,83.23) ; CD33.1 v1(50.45,29.04) CD32.2 ; v1(240.47,77.08) 240.46,77.08 239.96,77.08 R183.1 R202.1 ; U7.3 223.36,49.71 223.05,49.39 221.77,49.39 Q36.3 221.49,50.11 v1(221.32,50.28) ; v1(24.75,62.29) 24.75,63.07 24.64,63.19 C818.1 ; v1(30.03,28.33) 30.01,28.34 CD42.1 ; v2(50.71,66.2) 50.77,66.27 C2730.1 C2729.1 ; v1(214.54,82.77) 214.67,82.77 215.11,83.21 C111.1 ; v1(286.65,67.49) 286.65,66.84 R10082.1 ; CC99.1 99.36,80.11 99.16,79.91 v1(98.91,79.91) 98.91,80.45 CC56.1 ; C2544.1 v1(38.54,64.45) ; v1(98.74,70.68) 98.88,70.81 RC17.1 ; CC78.1 86.99,85.27 v1(86.9,85.36) ; v1(215.95,50.47) 215.95,50.11 216.94,49.11 U27.3 ; U14.42 213.17,85.45 v1(212.93,85.21) ; R352.2 234.78,50.39 R347.1 ; 102.93,95.34 102.97,95.3 CC63.1 103.93,95.3 103.97,95.34 ; PC153.2 203.08,80.35 203.18,80.25 v1(203.21,80.25) ; 269.34,136.8 C20.1 ; 269.34,136.8 C500.2 ; TP5.1 244.45,85.38 C260.1 ; RL10.1 207.25,71.15 206.84,71.15 v1(206.74,71.06) ; CC67.1 99.82,77.32 100.39,76.75 100.39,76.48 v1(100.49,76.38) ; CC67.1 100.34,77.81 v1(101.05,78.52) ; CC67.1 99.35,77.81 v1(98.92,77.38) ; v1(265.64,55.21) 265.64,55.1 266.26,54.48 C2574.1 ; D51.3 13.76,32.49 v1(13.57,32.3) ; v1(19.11,48.37) 19.43,48.06 19.72,48.06 C817.2 C815.2 ; v1(17.01,46.84) 16.85,47 U193.8 ; v1(247.3,77.99) 246.95,77.63 246.36,77.63 C193.2 ; J41.12 253.76,106.88 v1(253.86,106.97) ; C538.2 266.3,55.36 v1(265.79,55.87) ; v1(265.57,66.38) 265.67,66.48 R1239.1 ; CC60.1 105.5,75.3 v1(105.88,75.68) ; PC23.1 235.28,105.65 v2(234.82,105.65) ; 104.5,95.36 104.52,95.35 CC51.1 ; U25.19 U25.12 ; RD9.1 CD25.1 68.01,27.29 v1(69.03,28.3) ; C78.1 C272.2 R349.1 ; v1(265.31,57.67) 265.76,58.11 CA5.2 266.89,58.11 RA124.1 ; C190.2 244.82,79.61 v1(244.97,79.46) 245.09,79.46 245.2,79.35 R268.1 ; v1(254.67,82.71) 254.25,82.71 C203.1 ; U24.12 U24.19 U24.3 ; v1(282.42,44.95) 282.57,44.95 Q197.3 ; U5.G8 U5.H8 ; U19.3 250.17,96.63 v1(250.33,96.79) ; v1(96.96,80.75) 96.96,80.51 97.21,80.26 97.81,80.26 98.02,80.47 CC54.1 ; v1(128.53,60.31) 128.12,60.73 U26.32 ; RC2.2 102.33,78.41 v1(102.19,78.55) 101.89,78.85 RC3.2 ; R2515.1 46.03,75.83 v1(45.98,75.88) ; C536.2 C535.2 266.02,63.64 265.54,63.64 v1(265.44,63.74) ; RC91.1 94.88,83.76 v1(94.17,83.76) ; R197.1 240.63,83.52 v1(240.42,83.73) ; C195.1 251.09,69.78 v1(251.32,69.56) ; D52.3 14.74,29.09 13.67,29.09 v1(13.58,29.01) ; RC43.2 104.89,78.55 v1(104.89,78.55) 104.8,78.64 104.8,79.09 104.78,79.11 RC48.1 ; RD6.1 81.89,31.29 v1(81.82,31.36) ; C207.1 244.93,71.68 v1(244.88,71.63) 244.79,71.54 TP8.1 ; v1(240.29,56.96) 240.23,57.02 U191.4 ; R348.1 240.12,50.67 R346.1 ; D17.1 226.69,55.04 v1(226.6,54.95) ; RC103.1 73.72,85.03 v1(74.05,85.35) ; PC11.1 145,112.71 145,113.34 v1(144.69,113.65) ; C318.1 282.22,72.95 v1(282.15,73.01) ; v1(173.05,58.06) 173.05,58.46 172.7,58.82 172.39,58.82 171.96,58.39 171.96,58.23 171.8,58.08 CC68.1 ; PQ11.4 107.08,106.78 106.84,107.02 v1(105.75,107.02) 105.61,107.16 PR19.2 ; C274.2 276.45,77.75 v1(276.79,77.41) ; CC80.1 86.79,84.01 v1(86.85,83.95) ; RC18.1 100.3,70.81 v1(100.54,70.57) ; v1(234.83,69.86) 235.16,69.53 R403.2 ; RA25.1 283.98,45.32 284.24,45.06 v1(284.24,44.77) ; v1(17.17,18.89) D53.3 ; PQ41.3 138.57,109.23 v1(138.34,109.46) ; v1(85.17,32.06) 85.52,31.71 RD4.1 ; v1(238.34,46.24) 238.34,46.08 C308.2 C309.1 ; CC52.1 95.12,75.37 v1(95.63,74.86) ; v1(52.13,73.93) 51.97,73.76 C2545.1 C2543.1 ; J41.8 v1(255.76,106.41) ; v1(227.95,47.71) R363.1 R361.1 ; v1(45.68,63.89) 45.53,64.05 R2516.1 ; C138.2 276.86,90.26 276.38,89.78 v1(276.38,89.58) ; CL13.1 218.02,70.01 RL3.2 ; v1(85.28,33.29) 85.58,33.29 86.2,32.66 RD5.1 ; v1(69.43,70.57) 69.33,70.67 RC107.2 ; v1(88.15,74.36) CC82.1 ; v1(24.06,46.8) 24.48,47.22 U5.L11 ; R2517.1 v1(40.32,63.62) ; U193.18 U193.21 ; R908.1 v1(269.68,69.18) ; v1(163.56,58.41) 163.56,57.87 163.26,57.57 C217.1 ; v1(98.24,82.38) 98.05,82.18 CC50.1 ; v1(217.22,82.82) C112.1 ; C2546.1 v1(45.4,75.88) ; C2573.1 265.52,52.29 265.39,52.41 v1(265.39,52.44) ; v1(86.62,74.41) CC84.1 ; CA124.1 v1(265.62,61.91) ; v1(193.42,70.58) 193.68,70.83 193.68,71.28 193.87,71.47 PC102.2 ; CC32.1 92.81,62.01 93.1,61.72 v1(93.1,61.18) ; U5.A1 30.06,52.84 v2(30.64,52.84) ; CC57.1 95.69,79.09 v1(95.66,79.06) ; CC33.1 99.58,75.02 CC61.1 99.58,75.68 99.22,76.03 CC34.1 98.03,76.33 v1(98.26,76.56) ; C155.2 224.09,78.75 v1(224.04,78.8) ; v1(85.94,74.41) 85.91,74.38 CC81.1 ; v1(286.93,65.19) 286.6,64.86 R537.2 ; R401.1 139.9,64.51 140.12,64.72 140.12,65.44 v1(139.61,65.95) ; D15.3 284.33,78.39 v1(284.36,78.36) ; R10141.1 235.31,84.54 v1(235.37,84.49) ; v1(284.48,48.3) 284.96,47.83 QA8.3 ; v2(198.13,81.9) 198.57,81.46 PQ109.3
  TOP w0.305: v1(250.98,56.11) 251.16,56.29 Q263.3 ; C140.1 281.19,91.12 C141.1 ; 260.69,57.56 C556.2 ; 260.69,57.56 260.24,57.1 C558.2 260.02,56.76 ; 260.69,57.56 R10324.2 260.69,56.46 ; R849.1 223.66,81.55 223.38,81.82 v1(222.82,81.82) ; 87.99,39.17 C311.1 ; C311.1 C310.2 ; C311.1 87.56,39.51 v1(87.41,39.36) ; CL12.1 CL11.1 220.63,70.42 v1(220.35,70.14) ; v1(68.99,77.95) 68.99,78.05 CC88.1 ; v1(247.01,69.18) 247.05,69.14 R436.1 ; CC62.1 121.09,77.56 ; v1(249.64,94.68) 249.79,94.53 v3(249.79,93.82) 249.61,93.64 248.82,93.64 C188.1 ; C180.1 165.6,63.58 v1(165.85,63.33) 165.88,63.33 166.47,63.92 C181.1 ; v1(67.53,28.94) 67.63,29.04 CD45.1 ; CC81.1 CC84.1 CC83.1 CC82.1 ; C198.1 250,82.52 v1(250.35,82.87) ; R723.1 31.24,44.19 R312.1 ; U21.A3 v1(253.32,72.35) ; CD12.1 86.51,38.25 CD11.1 ; CD12.1 87.16,38.6 ; CD12.1 CD35.1 ; PR162.2 204.5,78.6 v1(204.91,78.19) ; v1(240.85,81.27) 240.37,81.27 R198.1 ; PC134.2 208.85,95.03 209.25,95.44 v2(209.25,95.64) ; v1(175.04,91.38) 174.91,91.51 C185.1 ; CD46.1 CD37.1 ; CD46.1 85.55,26.7 CD47.1 ; CD46.1 85.56,26.36 ; CD37.1 86.14,26.36 ; CD37.1 CD36.2 ; C175.2 127.09,54.65 v1(127.01,54.57) ; CC92.1 v1(73.35,82.02) 73.34,82.03 CC91.1 CC90.1 ; v1(228.43,86.4) 228.74,86.09 R205.1 228.1,85.85 R130.1 228.08,85.83 R413.1 ; C91.1 225.59,49.8 C75.1 ; C91.1 225.83,50.11 ; C91.1 226.17,49.28 C271.2 C301.2 227.11,49.2 227.5,48.81 R361.1 ; C91.1 226.17,50.17 226.16,50.18 ; R850.1 224.29,84.67 v1(224.49,84.87) ; C212.1 v1(265.82,76.26) ; QA7.3 276.3,46.41 276.29,46.41 276.28,46.42 ; C293.2 123.62,89.04 Q34.B2 ; C115.1 212.19,76.71 v1(211.77,77.13) ; v1(104.89,78.55) 105.32,78.99 R1119.1 ; C310.2 89.01,39.51 ; C310.2 88.58,39.17 ; U21.G5 v1(251.76,77.93) ; v1(220.11,67.77) 220.01,67.88 CL14.1 ; v1(69.64,79.78) 70,80.14 CC87.1 ; v1(235.66,46.4) 235.66,47.02 R349.1 235.71,46.73 ; C141.1 280.53,91.47 ; C141.1 280.1,91.12 ; v1(247.4,53.89) 247.4,53.92 247.86,54.37 C215.1 ; v1(34.53,29.09) 34.54,29.07 CD22.1 CD41.1 ; v1(248.3,82.76) R266.1 R265.1 ; C156.2 222.92,81.72 v1(222.82,81.82) ; C209.1 130.08,77.67 130.79,78.38 130.79,79.34 v1(130.56,79.57) ; C267.1 141.59,106.77 ; C267.1 C268.2 ; C267.1 141.25,107.15 ; R171.1 224.2,74.12 224.57,74.48 R374.1 ; RC102.1 70.67,85.61 v1(71.21,85.08) ; C125.1 226.25,59.83 226.02,60.06 v1(226.02,60.36) ; CL17.1 283.69,119.32 283.92,119.08 v1(283.92,115.08) ; v1(283.26,54.47) 283.26,55.03 283.41,55.19 R67.2 ; R51.2 224.99,52.12 225.21,52.34 C800.1 ; R51.2 R377.1 225.33,51.02 ; R51.2 225.33,51.6 ; CD19.1 83.17,32.88 v1(83.73,32.88) 83.91,33.06 CD44.1 ; CA119.1 266,61.2 265.62,61.58 v1(265.62,61.91) ; CC41.2 102.89,84.38 102.64,84.13 v1(102.32,84.13) ; 83.47,26.7 CD49.1 ; CD49.1 83.8,26.36 ; CD49.1 CD48.1 ; v1(219.44,75.73) YL1.2 ; Q228.3 285.06,54.82 284.74,54.5 v1(284.43,54.5) ; CC95.1 93.21,83.22 ; C158.1 241.92,69.82 Q7.3 241.13,70.33 240.83,70.64 R156.1 240.83,72.44 v1(240.55,72.71) 240.48,72.78 240.07,72.78 R206.1 ; CD39.1 CD23.1 43.54,28.94 v1(43.53,28.96) ; C280.2 195.81,55.3 ; C280.2 196.93,55.3 C279.1 ; C280.2 196.35,54.95 ; Q227.3 252.14,58.25 252.56,57.82 v1(252.99,57.82) 253.17,57.64 253.17,56.8 Q226.3 ; C268.2 141.71,106.21 ; C268.2 141.25,105.88 ; CL16.1 281.24,135.72 278.92,138.04 v1(278.92,138.07) ; R168.1 222.82,77.67 R201.1 222.15,77.27 v1(219.99,77.27) ; CD11.1 86.04,38.24 ; CD11.1 86.5,38.59 ; v1(219.06,72.05) 219.06,72.13 218.34,72.85 YL1.4 ; 215.33,59.66 C300.2 C299.2 ; R118.2 180.53,107.5 v1(180.35,107.68) ; v1(134.43,60.79) 134.07,60.44 C187.2 ; C305.1 212.33,59.32 C303.2 ; C305.1 212.94,59.66 ; C305.1 C304.1 ; J8.25 181.08,56.1 182.41,54.77 v1(182.41,52.21) ; C278.2 242.93,61.7 242.83,61.8 242.83,62.32 v1(243.21,62.7) 243.52,62.39 C277.1 ; PC154.2 199.91,81.65 v1(200.31,82.05) ; U16.H5 v1(234.31,79.25) ; v1(27.25,70.38) 27.1,70.54 R9117.1 ; CC51.1 104.91,95.69 ; v1(177.2,52.29) 177.1,52.39 177.1,55 178.08,55.99 J8.19 ; C9130.1 136.85,68.43 v1(136.18,67.75) ; CD36.2 CD15.1 ; CD36.2 86.72,26.36 ; CD15.1 87.31,26.36 ; CD15.1 88.39,26.71 CD14.2 ; CA73.1 284.96,47.22 QA8.3 ; 84.97,26.36 CD47.1 ; CD47.1 CD48.1 ; v1(276.4,138.37) 276.24,138.21 C298.1 ; C130.1 197.53,55.27 C279.1 ; R490.2 222.28,81.82 v1(222.82,81.82) ; RC11.2 99.12,61.12 v1(99.35,60.9) 98.84,60.39 CC69.2 ; J8.6 171.58,56.15 ; 171.58,56.15 171.97,55.76 v1(171.97,55.26) ; 171.58,56.15 171.38,55.94 170.37,55.94 170.08,56.23 J8.3 ; v1(40.12,32.5) 40.24,32.63 CD18.1 CD40.1 ; U16.G4 v1(235.11,78.45) ; v1(15.06,39.39) 15.06,39.17 14.74,38.85 U23.2 ; R10250.1 32.26,63.82 v1(32.33,63.75) ; R1897.2 36.7,70.19 v2(36.93,70.43) ; R185.1 242.62,76.14 v1(242.71,76.06) 242.71,75.77 242.49,75.55 R146.1 ; C6.1 138.1,106.4 C7.1 137.5,106.36 v1(137.47,106.39) 137.3,106.21 C265.2 ; C114.1 v1(214.18,76.19) ; 84.39,26.36 CD48.1 ; CC89.1 71.02,77.88 v1(70.94,77.95) ; CC40.1 106.18,83.18 v1(105.88,83.48) 105.62,83.48 105.32,83.17 105.28,83.17 RC5.2 ; v1(217.28,73.49) 216.75,73.49 RL11.1 ; R132.1 234.51,70.18 v1(234.83,69.86) 235.15,70.18 R149.2 ; v1(22.66,58.34) 22.28,58.72 C816.1 ; R9113.1 29.19,69.36 v1(29.08,69.47) ; C199.1 257.78,79.4 v1(257.93,79.56) ; v1(79.53,28.3) 79.28,28.05 CD43.1 ; C299.2 C128.1 ; C299.2 214.74,59.66 ; 93.3,81.57 CC30.1 ; 94.75,71.16 CC43.1 95.04,71.58 ; CA37.1 286.8,43.88 ; v1(239.12,86.19) 239.38,86.19 239.53,86.04 R195.1 ; v1(83.25,85.43) 83.25,85.32 83.44,85.13 CC85.1 ; D26.2 v1(221.86,79.7) ; 92.61,82.84 CC93.1 92.61,83.46 ; C279.1 196.96,54.93 ; C171.1 243.16,83.22 ; v1(247.61,73.48) 247.65,73.53 U21.B9 ; C128.1 C304.1 ; C128.1 214.11,59.66 ; C304.1 213.52,59.66 ; 88.87,38.25 CD34.2 ; CD34.2 88.45,38.6 ; CD34.2 CD35.1 ; CD38.1 29.25,33.31 v1(29.28,33.29) 29.29,33.3 CD16.1 ; U21.J2 253.75,79.57 v1(253.5,79.82) ; v1(114.61,75.07) 114.88,74.8 CC13.2 ; C284.1 265.77,71.08 v1(266.05,70.8) ; C194.1 v1(254.27,71.53) ; v1(234.04,86.4) 234.17,86.27 R192.1 R193.1 ; v1(71.57,83.46) 71.57,83.28 71.17,82.88 CC94.1 ; v1(230.63,86.44) 230.61,86.42 R133.1 230.33,85.83 R184.1 ; 92.66,77.74 CC96.1 93.04,77.46 CC48.1 ; U16.A3 235.53,72.98 235.8,72.71 v1(235.8,72.58) ; PC13.1 v1(13.18,70.02) ; R2512.1 37.4,66.17 v1(37.26,66.03) ; U26.9 128.12,56.3 127.96,56.15 127.49,56.15 v1(127.42,56.22) ; J25.13 v1(293.07,93.41) ; CC12.2 v1(115.15,72.5) ; U16.G5 v1(234.31,78.45) ; v1(237.09,69.83) 236.8,70.13 R147.2 ; C213.1 263.66,76.92 v1(263.38,76.64) ; v1(236.81,86.28) R200.1 ; v1(87.3,33.67) 87.53,33.67 87.93,34.07 CD31.1 ; R346.1 240.49,51.23 240.78,50.94 240.78,50.12 v1(240.72,50.06) ; C266.1 129.11,107.05 128.5,107.05 v1(128.37,107.18) ; 11.68,39.89 R314.2 10.35,40.22 ; 243.16,83.78 C169.1 C170.1 ; R236.1 174.7,87.84 175.19,88.33 v1(175.19,88.4) ; R680.1 29.54,68.11 v1(29.1,68.55) ; v1(271.63,79.56) 271.66,79.59 C108.1 ; PC129.2 v1(193.84,80.48) ; v1(73.03,78.17) 73.34,77.86 PC510.1 ; C273.2 C90.1 227.86,51.99 227.86,52.42 228.15,52.72 v1(228.15,52.82) ; CD30.2 v1(88.88,35.57) ; C79.1 234.35,50.96 234.78,50.53 R352.2 ; R170.1 v1(224.01,75.02) ; v1(286.39,68.54) 286.18,68.33 C36.1 ; CD35.1 87.82,38.6 ; PQ9.3 129.43,107.52 v1(129.57,107.38) 129.9,107.05 129.9,106.84 C5.1 ; 284.3,73.19 C100.1 284.63,72.92 v1(284.96,72.59) ; C4.1 130.46,106.83 130.46,107.31 v1(130.41,107.36) ; v1(247.3,77.99) 247.66,77.63 248.04,77.63 U21.G9 ; R196.1 237.37,85.71 R194.1 ; U16.K4 v1(235.11,80.85) ; C142.1 284.13,91.35 ; C189.1 251.82,82.28 C208.1 252.29,82.35 252.29,82.71 v1(252.18,82.82) ; R207.1 v1(240.01,74.97) ; v1(29.08,70.43) 29.22,70.58 R9098.1 ; C307.1 C306.2 62.49,108.62 ; C307.1 62.65,108.06 ; C307.1 62.15,107.73 ; R347.1 234.03,49.77 233.7,49.44 R362.1 233.51,50.01 R360.1 ; C263.2 128.84,64.64 ; R113.1 285.25,91.63 ; CC63.1 103.41,95.64 ; C318.1 282.69,73.29 ; U163.2 249.52,55.96 250.08,55.4 v1(250.13,55.4) ; v1(250.94,82.82) 251.09,82.66 C192.1 C191.1 ; v1(100.06,60.01) 99.96,60.11 RC13.2 ; v1(209.74,65.28) CL7.1 ; RC82.2 88.98,84.96 88.67,85.27 v1(88.67,85.4) ; v1(132.22,56.62) 132.09,56.49 U26.16 ; 285.56,72.76 285.26,73.05 C99.1 ; R186.1 224.71,78.27 C155.2 ; v1(271.14,78.76) 271.23,78.85 C107.1 ; PD7.2 v1(231.99,108.88) ; U16.F7 v1(232.71,76.9) ; 234.85,46.73 C272.2 ; v1(173.59,55.33) 173.59,55.61 173.08,56.12 J8.9 ; 269.66,102.78 269.86,102.98 CW1.1 270.19,103.17 ; 94.09,97.14 93.61,97.14 C294.2 93.61,97.57 ; 234.29,46.73 C78.1 ; C216.1 252.16,64.71 v1(252,64.55) ; C262.2 128.25,64.64 ; C9197.1 243.75,83.6 ; v1(218.45,72.01) 217.98,72.01 CL8.1 217.42,71.95 CL10.1 ; v1(246.74,66.76) 247.05,66.46 247.35,66.46 C211.1 ; C173.1 229.02,67.86 228.58,67.42 v1(228.58,67.02) ; R187.1 230.41,70.14 230.06,69.79 229.22,69.79 v1(229.17,69.84) 229.03,69.98 R182.1 ; v1(70.34,83.48) 70.32,83.5 70.32,83.65 70.01,83.96 RC20.1 ; C159.1 v1(224.69,71.46) ; U25.3 U25.19 ; v1(75.17,94.25) 75.17,94.47 QC2.3 ; PC224.2 175.73,75.86 ; RC12.2 v1(100.64,60.03) ; 111.82,107.68 PC5.2
  TOP w0.381: R862.2 34.67,47.21 34.27,46.8 33.28,46.8 v1(32.97,47.11) ; PC506.1 83.22,82.32 v1(83.22,82.03) 83.5,81.75 PC477.1 ; C127.1 241.15,62.7 241.42,62.97 242.18,62.97 v1(242.35,62.8) 242.19,62.64 C126.1 ; CD6.2 55.69,32.07 v1(54.8,31.18) ; v1(87.94,81.44) 87.53,81.44 PC442.1 87.22,81.75 PC445.1 ; v1(29.49,43.43) 29.35,43.57 29.35,44.1 29.34,44.11 ; v1(87.36,74.99) 86.94,74.99 PC447.1 ; v1(85.56,83.3) 85.98,83.3 PC454.1 87.22,83.02 PC446.1 87.53,82.71 v1(87.94,82.71) ; v3(161.4,103.92) v1(162.57,103.92) 162.79,103.92 PC4.1 ; PD9.2 v1(235.49,108.88) ; PC456.1 89.3,74.99 v1(89.72,74.99) ; C9463.1 17.12,43.32 v1(17.68,43.32) ; PC440.1 89.67,82.78 v1(89.67,82.36) ; CD17.1 CD20.1 50.39,32.54 v1(50.48,32.45) ; PC507.1 78.46,78.14 v1(78.04,78.14) ; v1(58.2,54.09) 58.64,54.53 RC9.1 58.64,55.1 58.89,55.35 59.68,55.35 59.95,55.08 C709.2 ; 122.41,90.72 122.41,88.89 121.97,88.46 121.97,87.93 122.4,87.5 123.15,87.5 123.62,87.97 C293.2 ; v1(57.36,32.47) 57.36,32.55 57.39,32.57 57.39,32.69 CD7.2 ; PD8.2 v1(234.43,108.88) ; v1(284.94,79.82) 284.02,79.82 283.37,80.48 D13.2 ; D54.2 v1(17.13,7.35) ; PQ24.3 260.45,90.47 260.17,90.75 v1(260.17,91.74) ; v1(242.78,78.12) 242.5,78.4 C172.1 242.63,78.9 C168.1 ; v1(75.85,80.05) 75.85,80.47 PC512.1 ; PC490.1 83.59,78.22 v1(83.22,78.22) ; v1(91.75,78.68) 92.17,78.68 PC534.1 ; PC452.1 85.42,75.58 v1(85,75.58) ; v1(104.28,71.24) 104.05,71.47 104.05,71.86 CC53.1 CC59.1 CC35.1 ; v1(87.99,76.34) 87.58,76.34 PC441.1 87.25,76.67 PC459.1 ; PC476.1 79.73,75.04 v1(80.15,75.04) ; CD5.2 60.05,31.8 v1(59.8,31.8) ; R89.2 R90.2 275.19,85.03 274.74,85.48 v1(274.3,85.48) ; v1(26.24,40.2) 26.42,40.02 27.15,40.02 28.15,41.02 R783.2 ; PC475.1 74.61,82.83 v1(74.61,82.41) ; v1(89.34,52.44) 89.04,52.44 88.63,52.84 CC76.1 ; v1(73.09,33.08) 73,33.17 CD21.1 ; v1(83.22,80.76) 83.64,80.76 PC484.1 ; v1(244.05,84.62) 244.36,84.92 C260.1 ; v1(78.04,80.68) 78.46,80.68 PC516.1 ; CD27.2 64.63,26.83 CD28.1 65.64,27.49 66.03,27.88 v1(66.03,28.3) ; PC53.2 163.43,90.62 164.39,91.58 v1(164.39,92.04) ; v1(276.44,85.44) 276.44,85.1 276.64,84.9 C297.2 276.64,84.65 277.25,84.04 277.4,83.89 C131.1 277.4,83.76 278.28,82.88 C132.1 ; v1(58.48,30.29) 58.73,30.03 CD3.2 ; CD8.2 61.91,32 61.91,30.8 v1(62.29,30.42) 62.24,30.37 RD10.1 ; v1(78.04,81.95) 78.46,81.95 PC517.1 ; C229.2 v1(15.9,40.65) ; v1(91.09,75.93) 90.9,76.12 CC97.1 ; PC491.1 83.59,79.49 v1(83.22,79.49) ; C157.2 v1(223.96,69.15) ; R9085.1 28.93,64.13 v1(28.6,64.47) ; v1(74.61,80.05) 74.61,80.47 PC513.1 ; v1(73.03,80.71) 73.45,80.71 PC496.1 ; PC472.1 83.21,76.94 v1(83.22,76.95) 83.59,76.95 PC514.1 ; v1(29.1,66.57) 29.72,65.96 R10248.1 ; v1(89.65,80.02) 89.65,80.44 PC443.1 ; CD1.2 76.95,30 76.38,29.43 v1(75.73,29.43) ; v1(89.65,77.66) 89.65,78.08 PC461.1 ; CD4.2 46.96,30.2 v1(47.48,29.68) 47.5,29.69 48.04,29.69 CD29.1 ; v1(56.58,30.29) 56.7,30.29 CD2.2 ; v1(78.04,76.87) 78.46,76.87 PC478.1 ; U186.4 29.01,61.18 v1(28.4,61.79) ; PC533.1 92.17,81.22 v1(91.75,81.22) ; v1(73.03,79.44) 73.45,79.44 PC492.1 ; H3.1 54.61,60.12 54.61,53.48 55.08,53.01 U36.3 ; v1(78.04,79.41) 78.46,79.41 PC483.1 ; PC535.1 92.17,79.95 v1(91.75,79.95) ; v1(258.83,56.25) 258.83,56.48 259.45,57.1 C558.2 ; v1(75.85,77.71) 75.85,78.13 PC494.1 ; D18.4 v1(266.68,107.06) ; 29.34,44.11 R728.2 ; 29.34,44.11 R722.1 30.27,44.11 R723.1 ; v1(277.75,86.9) 277.42,87.23 C136.2 ; C282.1 112.91,103.77 v1(113.78,103.77) ; v1(133.87,69.23) 133.28,69.23 133.07,69.44 U184.3 ; v1(73.03,76.9) 73.45,76.9 PC479.1 ; v1(27.56,43.45) R724.1 27.57,44.11 R721.1 ; PC489.1 74.61,78.13 v1(74.61,77.71) ; v1(87.97,77.61) 87.55,77.61 PC458.1 86.31,77.89 PC444.1 ; QC3.3 71.04,95.51 v1(71.13,95.59) ; v1(73.03,83.25) 73.45,83.25 PC481.1 ; v1(17.25,50.84) 17.18,50.77 C900.2 ; C283.1 v1(266.18,81.44) ; CL5.2 219.68,66.53 v1(219.6,66.46) ; v1(16.36,51.7) R9110.2 15.6,50.79 R9108.1 ; PC25.1 229.98,100.63 v1(229.85,100.5) ; PC474.1 78.2,75.6 v1(77.78,75.6) ; v1(32.95,47.74) 32.51,48.18 R799.1 ; v1(268.18,55.99) 268.18,55.94 267.6,55.36 C537.2 ; PC473.1 74.98,75.07 v1(75.4,75.07) ; v1(44,66.01) 44.33,65.68 R9130.2 ; CC71.2 95.6,60.96 CC70.2 95.6,62.48 95.49,62.6 v1(95.49,62.98) ; v1(4.6,61.82) R509.1 ; PC511.1 75.85,82.83 v1(75.85,82.41) ; v1(244.97,79.46) 244.97,79.56 245.35,79.95 C259.2 ; PC3.1 v1(157.02,97.6) ; v1(87.97,80.43) PC457.1 86.31,80.43 PC455.1 85.98,80.76 v1(85.56,80.76) ; PC493.1 78.46,83.22 v1(78.04,83.22) ; PC532.1 92.17,82.49 v1(91.75,82.49) ; C124.1 v1(268.94,109.19) ; v1(262.77,62.97) 261.28,62.97 261.01,63.24 Q60.2 ; v1(87.97,78.88) 87.55,78.88 PC448.1 87.22,79.21 PC462.1 85.98,79.49 v1(85.56,79.49)
  TOP w0.508: v1(287.33,63.39) 287.33,62.27 286.8,61.73 C1417.1 287.02,61.51 D24.2 287.03,60.83 287.03,60.01 286.51,59.49 DA5.2 285.07,59.49 CA142.1 ; v1(133.41,66.66) 133.07,67 U185.3 ; C821.2 C822.2 ; J41.19 v1(260.49,109.66) ; PC50.2 156.27,95.39 155.99,95.39 v1(155.37,96) ; R2530.2 v1(36,76.11) ; C196.1 256.17,69.55 v1(256.17,68.77) 256.71,68.77 C201.1 ; v1(169.58,64.6) 169.58,64.3 170.14,63.74 C178.2 ; v1(105.5,86.8) 105.5,86.58 104.96,86.04 CC39.1 ; C9487.1 272.67,113.58 v1(273.28,114.19) ; 58.4,72.83 59.7,74.13 59.7,75.02 v1(59.71,75.03) ; C546.2 275.02,72.49 v1(273.06,72.49) 273.01,72.44 C547.2 ; C292.2 125.6,91.2 v1(125.53,91.28) ; v1(48.12,76.69) 48.5,76.31 R2524.2 48.7,76.24 R2526.2 ; C809.2 32.44,47.11 v1(32.97,47.11) ; v1(257.49,82.69) 257.49,82 C200.1 ; 255.78,46.58 255.63,46.72 C256.1 ; v1(273.86,100.15) J25.12 v1(273.86,103.37) ; C197.1 v1(258.31,76.38) ; v1(257.93,79.56) R279.1 ; v2(50.73,64.83) 50.28,64.38 C2587.1 ; v1(89.52,94.04) 90.05,94.58 C296.2 ; v1(233.49,52.82) 233.49,52.36 233.94,51.91 234.41,51.91 234.41,51.23 C79.1 ; CA913.2 277.12,68.11 C553.2 v1(277.94,68.95) ; C206.1 258.91,73.01 v1(258.91,73.93) ; RC159.2 104.66,58.99 104.15,59.5 v2(103.82,59.5) ; v1(273.86,98.04) J25.11 v1(275.52,96.39) ; v1(289.26,63) 290.09,62.18 290.19,62.18 290.68,61.69 RA8.1 ; v1(260,77.96) 259.78,77.96 259.46,77.65 C205.1 ; v1(122.39,90.74) 122.41,90.72 122.8,90.71 122.84,90.67 R458.2 ; J25.10 v1(293.1,109.21) ; R2528.2 v1(37.78,76.14) ; RA37.1 277.33,53.13 ST4.1 ; J25.9 v1(274.78,104.41) ; R2562.2 v1(39.94,76.14) ; J25.8 v1(291.79,105.18) ; v1(135.99,63.79) 135.87,63.68 134.55,63.68 C186.2 ; J41.20 v1(249.54,109.61) ; v1(35.09,72.45) R1899.2
  GND1 w0.102: 92.8,74.36 92.8,73.7 ; 279.4,55.24 279.12,55.24 278.72,54.83 278.72,54.7
  GND1 w0.127: 94.57,74.33 94.57,73.8 94.6,73.77
  GND1 w0.152: 95.89,76.14 95.31,76.14
  IN3 w0.102: v1(91.75,82.49) 91.9,82.49 92.08,82.31 92.08,82.06 93.3,80.84 93.88,80.84 94.11,81.07 94.11,81.42 93.88,81.65 93.17,81.65 92.58,82.24 92.58,82.57 91.7,83.45 91.7,84.04 90.73,85.01 89.07,85.01 v1(88.67,85.4) 88.67,85.72 86.84,87.55 84.99,87.55 v1(84.87,87.67) 84.76,87.77 82.33,87.77 v1(82.19,87.64) 81.87,87.31 81.87,85.77 v1(82.25,85.38) 82.83,85.96 82.83,86.83 83.24,87.24 84.38,87.24 84.58,87.04 86.62,87.04 88.13,85.52 88.13,85.04 88.72,84.45 90.01,84.45 v1(90.51,83.95)
  GND2 w0.089: 84.54,86.44 83.84,86.44 ; 83.69,85.69 84.56,85.69
  BOTTOM w0.102: v3(141.45,89.81) 140.6,89.81 PC720.1 ; 85.89,91.71 85.86,91.68 85.86,91.5 86.17,91.2 86.17,90.03 85.63,89.5 85.23,89.5 85.07,89.34 85.07,88.55 U1.B39 ; 61.82,111.85 PR437.2
  BOTTOM w0.127: U1.D39 84.67,87.08 84.97,86.78 85.61,86.78 85.99,86.4 85.99,86.16 U1.F37
  BOTTOM w0.152: v1(87.11,90.72) 87.11,89.8 86.8,89.5 86.8,87.26 86.93,87.13 U1.D34 87.72,86.57 87.72,86.16 U1.F35 U1.F33 ; v1(14.94,54.53) 14.91,54.5 D87.3 ; v1(73.45,65.91) 73.47,65.93 73.47,66.8 U1.BB60 ; U1.F37 U1.F38
  BOTTOM w0.178: U1.BB64 71.14,66.64 71.14,66.29 71.14,65.91 v1(71.14,65.91) ; v1(65.94,75.53) 65.96,75.46 66.16,75.31 U1.AG71 ; v1(88.17,65.23) 88.21,65.27 88.21,66.55 U1.BB34 ; U1.BB26 93.19,66.42 93.19,66.35 v1(92.67,65.82) ; v1(90.97,65.65) 90.84,65.78 90.84,66.17 U1.BB30 ; v1(85.9,65.84) 85.87,65.86 85.87,66.81 U1.BB38 ; v1(96.97,65.9) 96.94,65.93 U1.BB18 ; v1(76.13,65.91) 76.09,65.95 76.09,66.43 U1.BB55 ; v1(83.23,65.87) 83.26,65.89 U1.BB43 ; v1(66.04,84.99) 66.12,84.91 U1.H71 ; U1.AM71 67.04,72.64 66.05,72.64 v1(65.99,72.59)
  BOTTOM w0.203: U1.AT71 65.94,70.3 v1(65.94,70.3) ; U1.J32 88.64,84.6 v1(88.64,83.92) ; v1(278.36,137.46) 278.18,137.46 277.65,136.92 J11.30 ; D88.3 v1(14.94,58.46) ; v1(271.68,138.6) 272.65,138.6 274.05,137.2 J11.21 ; J10.20 134.15,104.45 v1(134.09,104.51) 134.09,104.41 133.75,104.07 J10.19 ; U1.AP63 U1.AR63 ; U1.C1 107.34,88.42 107.5,88.58 v1(107.5,88.68) ; U1.AV69 U1.AV70 U1.AV71 66.17,68.91 v1(65.99,68.73) ; U1.AB16 98.57,77.73 v1(98.92,77.38) 99.22,77.68 U1.AB15 ; 271.64,135.23 271.39,135.23 271.25,135.37 J11.14 ; 271.64,135.23 272.36,135.23 v1(272.6,135.47) 272.85,135.72 J11.18 ; 271.64,135.23 271.65,135.24 J11.15 ; U1.D47 80.39,86.92 U1.E46 ; U1.D47 80.11,87.17 80.07,87.13 U1.D48 ; U1.D47 80.74,87.17 80.81,87.11 81.11,87.11 81.18,87.17 U1.D45 81.81,87.17 81.85,87.13 U1.D44 v1(82.19,87.64) U1.B44 ; U1.AW12 100.2,68.77 100.17,68.8 99.88,68.8 99.85,68.77 U1.AW14 99.27,68.77 v1(98.75,69.29) 98.24,68.77 U1.AW16 97.78,68.77 97.75,68.8 97.46,68.8 97.43,68.77 U1.AW18 96.51,68.77 96.48,68.8 96.18,68.8 96.15,68.77 U1.AW21 95.68,68.85 94.57,68.85 U1.AW23 94.04,68.77 94.01,68.8 93.71,68.8 93.68,68.77 U1.AW26 92.81,68.77 92.78,68.8 92.48,68.8 92.45,68.77 U1.AW28 91.58,68.77 91.55,68.8 91.26,68.8 91.23,68.77 U1.AW30 90.36,68.77 90.32,68.8 90.03,68.8 90,68.77 U1.AW32 89.17,68.77 v1(88.68,69.26) 88.31,68.9 U1.AW34 87.83,68.77 87.8,68.8 87.5,68.8 87.47,68.77 U1.AW36 86.6,68.77 86.57,68.8 86.28,68.8 86.25,68.77 U1.AW38 85.53,68.77 v1(85.02,69.28) ; U1.W13 100.6,78.47 101,78.47 v1(101.05,78.52) ; J10.22 134.95,104.34 v1(134.8,104.49) 134.55,104.24 J10.21 ; U1.J25 92.34,83.88 v1(92.24,83.78) ; J11.7 268.45,137.29 v1(268.28,137.45) ; v1(69.48,68.64) 69.03,69.1 U1.AV68 ; v1(69.48,68.64) 69.59,68.71 U1.AW66 70.02,68.82 70.99,68.82 U1.AW64 71.52,68.77 71.55,68.8 71.85,68.8 71.88,68.77 U1.AW62 72.75,68.77 72.78,68.8 73.07,68.8 73.1,68.77 U1.AW60 73.97,68.77 74.01,68.8 74.3,68.8 74.33,68.77 U1.AW57 75.25,68.77 75.28,68.8 75.58,68.8 75.61,68.77 U1.AW55 76.48,68.77 76.51,68.8 76.8,68.8 76.83,68.77 U1.AW53 77.7,68.77 77.73,68.8 78.03,68.8 78.06,68.77 U1.AW51 78.76,68.77 78.84,68.85 79.15,68.85 79.22,68.77 U1.AW49 80.13,68.77 80.16,68.8 80.45,68.8 80.48,68.77 U1.AW47 81.29,68.77 81.32,68.8 81.62,68.8 81.65,68.77 U1.AW45 82.52,68.77 82.55,68.8 82.84,68.8 82.95,68.69 83.28,68.69 U1.AW43 ; v1(69.48,68.64) U1.AY66 U1.BA66 ; J10.8 v1(129.35,104.54) ; U1.F2 U1.F4 105.39,86.7 v1(105.5,86.8) ; U1.J28 v1(90.51,83.95) ; U1.K71 66.44,83.55 66.19,83.3 v1(65.87,83.3) ; U1.AL48 80.45,73.32 U1.AM46 ; U1.F40 85.02,85.36 v1(85.02,85.31) 85.03,85.36 U1.F38 ; U1.K61 72.2,84.17 U1.K63 ; v1(90.59,93.76) 90.48,93.66 90.48,91.2 89.62,90.33 87.84,90.33 87.46,90.72 v1(87.11,90.72) ; U1.AL64 71.17,72.97 71.12,72.92 70.74,72.92 70.7,72.97 U1.AL65 70.53,72.97 70.49,72.92 70.11,72.92 70.06,72.97 U1.AL66 ; U1.AF1 107.07,75.72 107.97,75.72 v1(108,75.69) ; U1.F1 107.14,86.4 107.83,86.4 v1(107.88,86.45) ; U1.AK27 v1(91.88,74.43) ; U1.AT68 69.16,70.3 v1(69.43,70.57) ; J10.17 132.95,104.3 v1(132.74,104.51) 132.55,104.32 J10.16 ; PR220.1 v2(161.63,71.97) ; U1.J35 v1(86.85,83.95) ; v1(66.65,89.35) 66.88,89.12 U1.A70 ; U1.AW10 102.27,68.77 102.3,68.8 102.59,68.8 102.62,68.77 U1.AW8 103.42,68.77 103.45,68.8 103.74,68.8 103.77,68.77 U1.AW6 ; v1(112.18,98.82) 112.18,98.93 112.23,98.98 UC4.6 ; v1(130.74,94.5) 130.74,94.77 PC401.2 ; J11.3 266.85,137.29 v1(266.95,137.39) ; J10.2 v1(126.95,104.51) ; 95.32,78.72 v1(95.66,79.06) 95.97,78.76 U1.Y20 ; J10.5 v1(128.15,104.54) ; J10.11 v1(130.55,104.51) ; PR219.2 v2(157.59,71.92) ; U1.AF63 71.99,75.59 72.02,75.56 72.02,74.85 U1.AH63 ; U1.G10 v1(101.47,85.36)
  BOTTOM w0.254: U1.BB6 U1.BA6 104.2,68.26 104.16,68.31 U1.AW6 104.16,71.12 v1(104.28,71.24) 104.36,71.24 U1.AR5 105.23,70.37 U1.AT4 U1.AT2 ; U1.AF2 105.89,75.67 v1(105.88,75.68) 105.87,75.67 U1.AF4 ; U1.BA57 74.84,67.6 v1(74.84,68.26) 74.84,68.72 U1.AW57 ; U1.AD62 72.9,77.03 v1(73.03,76.9) ; CA45.1 C2575.1 284.98,53.95 v1(284.43,54.5) ; U1.W6 104.74,78.8 104.81,78.68 v1(104.89,78.55) 105.16,78.55 U1.AA4 U1.AA2 ; U1.AR45 v1(81.37,70.55) 81.1,70.76 U1.AR46 ; U1.AN38 v1(85.94,71.82) 85.95,71.83 U1.AN37 ; v1(71.57,74.29) 71.62,74.22 U1.AK63 ; v1(71.57,74.29) U1.AH63 ; v1(71.57,74.29) U1.AH64 ; J1.47 231.81,48.39 231.81,47.08 232.5,46.39 v1(232.5,46.29) ; J17.29 v1(176.95,105.3) ; PR761.1 150.19,97.36 v1(150.3,97.47) ; J17.70 v1(192.35,96.57) ; J17.10 187.4,107.62 v1(187.41,107.63) ; U1.AB8 103.36,77.93 v1(103.62,77.53) ; 96.48,68.8 96.45,68.83 U1.AU20 v1(96,69.91) U1.AT20 ; U1.A67 68.95,89.3 v1(68.95,89.62) ; 204.28,50.53 204.3,50.56 J32.33 204.3,52.62 v1(204.12,52.79) ; U1.K66 70.13,83.84 70.35,83.56 v1(70.34,83.48) 70.34,83.54 U1.K65 ; U1.AP23 v1(93.25,71.18) ; U1.D14 99.58,87.17 v1(99.58,87.64) 99.54,87.67 U1.B14 ; v1(67.94,86.78) 67.94,86.78 U1.D69 U1.F68 ; U1.AR43 v1(83.2,71.18) U1.AP42 ; J17.20 v1(181.9,105.24) ; v1(104.89,80.69) 104.81,80.82 104.71,80.98 U1.R6 ; U1.F37 86.78,85.36 v1(86.9,85.36) 86.92,85.36 U1.F35 ; U1.G45 81.64,85.1 v1(81.38,85.36) ; v2(64.9,110.55) 64.7,110.34 PU403.5 ; PR753.2 v2(161.38,66.1) ; J32.24 202.05,57.79 v1(201.75,57.5) ; U1.F42 83.54,85.75 83.25,85.46 v1(83.25,85.43) ; U1.AT56 v1(74.97,69.91) ; U1.AN58 v1(74.05,71.82) ; v1(103.31,85.35) U1.G6 U1.G5 ; U1.AD13 100.42,76.42 100.49,76.35 v1(100.49,76.38) ; J17.55 184.1,96.16 183.5,96.76 v1(183.5,96.89) ; J1.34 220.55,49.93 220.9,50.28 v1(221.32,50.28) 221.55,50.28 221.75,50.08 J1.31 221.75,49.01 222.23,48.53 J1.51 222.54,48.53 222.95,48.94 J1.28 ; U1.B66 v1(69.8,87.64) U1.D66 ; J26.16 135.88,63.31 136.04,63.47 136.04,63.74 v1(135.99,63.79) 135.95,63.79 135.91,63.84 134.81,63.84 J26.14 ; U1.L20 95.97,82.9 96.29,83.22 v1(96.29,83.31) ; U1.AW36 v1(87.04,68.26) U1.BA36 ; U1.AM60 73.41,72.86 73.34,72.93 72.96,72.93 72.89,72.86 U1.AM61 72.62,72.86 v1(72.22,72.47) 72.02,72.47 U1.AN63 ; J32.30 203.55,58.42 203.42,58.29 203.42,57.6 v1(203.33,57.51) ; v1(70.94,77.95) U1.AA65 ; v1(140.23,86.61) 140.07,86.45 C2.1 ; PC794.2 137.17,70.14 137.17,70.67 137.19,70.7 v1(137.19,70.78) 137.25,70.73 PR762.2 ; v1(100.54,70.57) 100.62,70.65 100.76,70.65 U1.AR11 101.05,70.91 101.32,71.18 v1(101.51,71.18) 101.94,71.54 U1.AP10 ; U1.AW12 100.93,68.77 100.98,68.82 101.05,68.82 v1(101.5,69.27) ; v1(93.1,61.18) 93.29,60.98 CC5.2 ; U1.BA45 v1(82.08,68.26) ; U1.B58 v1(74.76,87.64) U1.D58 ; v1(108.57,67.4) 108.92,67.05 110.26,67.05 111.95,68.74 RC151.1 ; R3.1 v1(139.66,84.7) ; U1.Y19 96.94,79.08 97.09,79.26 U1.V18 ; U1.Y19 96.38,78.42 96.2,78.42 U1.Y20 ; U1.Y19 96.62,78.47 U1.AB18 97.42,77.63 97.6,77.4 98.15,77.4 U1.AD16 v1(98.26,76.56) ; U1.AW53 v1(77.27,68.26) U1.BA53 ; J15.3 44.34,65.51 44,65.85 v1(44,66.01) J15.4 ; U1.AP28 v1(90.51,71.18) ; 102.64,79.01 U1.W9 ; 102.64,79.01 102.59,79.01 102.01,79.59 U1.U10 ; 102.64,79.01 v1(102.19,78.55) ; U1.G52 77.71,85.56 77.71,85.94 U1.E53 77.25,86.42 77.29,86.46 77.25,86.5 77.25,86.88 77.24,86.89 U1.D53 77.24,87.45 v1(77.07,87.62) 77.07,87.98 U1.B53 ; U1.D34 87.15,87.38 v1(87.39,87.62) 87.15,87.85 U1.B34 ; J1.50 224.36,48.53 224.15,48.74 J1.25 ; U1.B30 89.63,87.81 v1(89.82,87.62) 89.63,87.42 U1.D30 ; J32.23 201.8,50.56 201.48,50.24 v1(201.48,50.23) ; v1(65.78,32.65) 65.67,32.65 65.29,33.03 65.29,33.22 64.88,33.62 64.88,33.97 64.88,34.18 64.78,34.28 J21.167 ; J21.99 45.78,32.94 46.29,32.42 v1(46.77,32.42) ; RC150.1 v1(110.25,69.79) ; U1.AR55 76.43,70.91 v1(76.79,70.55) U1.AR53 ; v1(96.93,83.31) 96.93,83.35 U1.K18 97.4,83.79 97.47,84.32 U1.H18 ; U1.C5 104.9,87.64 v1(104.56,87.64) 104.56,87.63 104.47,87.55 U1.D6 ; 96.98,82.41 96.67,82.02 U1.N19 96.62,81.93 95.97,81.28 ; 96.98,82.41 v1(96.97,82.39) ; 96.98,82.41 97.28,82.79 U1.L18 ; v1(102.42,75.3) 102.42,75.5 102.12,75.81 U1.AF10 ; U1.AR63 72.13,70.55 ; 72.13,70.55 72.05,70.55 U1.AT63 ; 72.13,70.55 v1(72.2,70.55) ; U1.B48 U1.D48 ; U1.B22 94.55,88.11 94.55,87.74 v1(94.46,87.65) 94.55,87.57 94.55,87.17 U1.D22 94.57,87.12 94.71,87.12 95.08,86.75 95.19,86.75 U1.E21 ; JTYC1.30 9.82,55.95 10.11,55.95 v1(10.21,56.05) ; v1(102.43,86.07) 102.82,85.87 U1.F8 ; U1.J42 82.74,85.09 U1.G43 82.64,85.1 82.36,85.38 v1(82.25,85.38) ; D55.2 16.85,33.72 v1(17.84,34.71) 17.71,34.84 D57.2 ; v1(185.73,107.66) 185.75,107.64 J17.13 ; U1.H15 99.04,84.45 98.76,84.72 v1(98.76,84.75) ; CA56.1 157.31,52.37 v1(157.31,52.69) ; U1.K16 U1.L16 98.24,82.43 ; U1.BA49 v1(79.67,68.26) U1.AW49 ; v1(88.43,90.9) 88.27,90.9 87.88,91.29 CC10.1 ; J32.18 200.55,60.03 200.8,60.29 201.36,60.29 v1(202.53,61.46) ; U1.V18 U1.T18 ; U1.V18 97.36,79.59 97.82,79.59 U1.V17 ; 94.32,85.43 94.63,85.73 U1.F22 ; 94.32,85.43 94.63,85.12 U1.G22 94.57,85.05 94.57,84.22 U1.K22 94.55,84.17 94.19,83.82 94.19,83.79 v1(94.17,83.76) ; 94.32,85.43 94.04,85.43 U1.F23 ; v1(102.42,71.13) 102.68,71.13 102.86,70.95 U1.AR8 ; v1(136.56,70.8) 136.08,70.8 136.05,70.78 PR721.2 ; U1.AL52 78.62,71.37 U1.AR50 v1(78.62,70.55) U1.AR52 v1(77.71,70.55) ; v1(89.11,90.99) 89.21,90.99 89.82,91.6 Y1.4 ; U1.AR35 86.89,70.58 v1(86.85,70.55) 86.98,70.47 U1.AT35 ; U1.AR20 v1(96,70.55) ; v1(103.36,86.73) 103.69,86.4 U1.E6 ; RC4.2 112.02,82.51 v1(112.1,82.43) ; v1(46.42,69.02) 46.76,68.68 C281.2 ; J17.42 176.95,96.51 v1(177.25,96.81) ; v1(261.45,129.27) 261.07,128.89 J5.3 ; v1(89.72,74.99) 89.72,74.99 89.72,74.22 89.6,74.09 U1.AL32 ; U1.AW14 v1(99.36,68.26) U1.BA14 ; U1.AT23 v1(93.25,70.55) U1.AR23 ; J22.45 236.6,52.55 236.81,52.77 237.51,52.77 v1(237.8,53.05) 238.1,52.75 J22.51 ; U1.AL4 v1(105.88,73.02) U1.AL2 ; U1.AL38 v1(85.94,74.41) ; 97.59,75.72 U1.AG18 97.17,75.3 97.13,75.27 96.75,75.27 96.71,75.3 U1.AG19 U1.AG20 95.97,75.2 v1(95.63,74.86) ; 97.59,75.72 U1.AF17 ; 97.59,75.72 97.92,75.4 U1.AG17 ; v1(75.4,75.07) 75.19,74.87 75.19,74.36 74.97,74.13 U1.AL58 ; R9102.1 26.8,74.11 26.8,74.31 v1(26.56,74.55) 26.13,74.12 R9097.2 ; v1(101.5,69.27) 101.78,68.99 U1.AW10 v1(101.78,68.26) U1.BA10 ; v1(101.5,69.27) U1.AU10 ; U1.P17 v1(97.59,81.59) ; v1(284.24,44.77) 284.8,45.34 D710.2 ; U1.B10 U1.D10 U1.D11 101.18,87.06 v1(100.57,86.62) U1.E11 ; U1.U66 69.85,80.07 69.76,79.95 v1(69.64,79.78) 69.52,79.95 69.43,80.07 U1.U67 ; U1.N6 104.62,82.13 v1(104.24,81.75) ; U1.AR15 99.06,70.93 v1(98.74,70.68) 98.65,70.68 98.41,70.91 U1.AR16 ; U1.AM21 95.54,72.8 95.15,72.45 v1(95.08,72.45) ; v1(88.68,71.82) U1.AN32 ; v1(107.27,63.82) 107.38,63.72 RC104.2 C257.2 ; v1(90.59,93.76) 89.8,94.55 87.87,94.55 85.86,92.54 85.86,91.73 85.89,91.71 v1(85.87,91.71) ; v1(240.72,50.06) 240.44,50.33 240.11,50.33 239.6,50.84 J22.57 ; v1(109.53,62.17) 109.03,62.67 C258.2 ; U1.T18 97.14,80.5 v1(96.96,80.75) 96.77,80.98 U1.P19 U1.P20 95.97,81.28 ; U1.T18 97.4,80.2 97.78,80.2 U1.T17 ; v1(232.33,52.78) 232.1,52.55 J22.27 ; CC42.1 104.76,62.17 v1(104.78,62.14) ; U1.G58 v1(74.05,85.35) ; v1(70.19,86.62) U1.E65 ; v2(91.82,105.41) 91.89,105.48 PU402.26 ; U1.AK22 94.8,73.63 U1.AK21 95.64,73.95 v1(95.64,74.05) 95.97,74.37 U1.AJ20 95.97,74.52 v1(95.63,74.86) ; v1(91.35,74.13) 91.43,74.05 U1.AL28 ; U1.AJ4 v1(104.89,74.29) U1.AH6 ; 95.97,81.28 v1(95.66,81.59) ; U1.G48 79.99,85.12 79.57,85.35 v1(79.56,85.38) ; U1.D25 92.74,87.13 U1.D26 92.11,87.56 v1(92.22,87.67) 92.34,87.79 92.75,87.79 U1.C25 ; RA22.1 284.86,47.92 v1(284.48,48.3) ; U1.AP58 v1(74.05,71.18) ; U1.L17 98.24,82.43 ; 98.24,82.43 v1(98.24,82.38) ; U1.AP35 86.98,71.29 v1(86.85,71.18) ; JTYC1.29 9.88,53.51 v1(10.19,53.51) ; CA54.1 158.23,58.79 v1(158.43,58.99) ; U1.G55 v1(75.88,85.35) ; U1.AW62 v1(72.31,68.26) U1.BA62 ; v1(98.75,69.29) 99.2,69.61 U1.AU15 ; 219.36,48.48 219.35,48.49 J1.37 ; U1.AD19 96.62,76.91 v1(96.28,76.57) 96.28,76.67 U1.AD20 ; v1(95.66,81.59) 95.32,81.93 U1.N21 ; v1(95.66,81.59) 95.32,81.25 U1.P21 U1.T21 ; U1.AL66 69.97,72.94 v1(69.48,72.45) 69.18,72.75 U1.AM68 ; U1.AP32 v1(88.68,71.18) ; v1(69.78,83.43) 69.34,83.86 U1.K67 69.09,83.66 U1.K68 67.79,83.66 U1.K70 ; JTYC1.1 9.43,52.01 9.63,51.81 JTYC1.28 v1(10.16,51.56) ; U1.AM46 80.55,72.56 v1(80.45,72.47) ; U1.AL55 76.79,73.32 U1.AM55 v1(75.88,72.47) ; v1(67.69,77.07) 67.69,76.9 U1.AE69 U1.AE68 U1.AE67 U1.AE66 U1.AE65 U1.AE64 ; U1.AW18 v1(96.94,68.08) U1.BA18 ; U1.N13 100.06,82.19 v1(99.49,81.61) 99.95,81.14 U1.R13 99.4,80.5 99.22,80.34 U1.T15 98.91,80.02 v1(98.91,79.91) U1.V16 98.39,79.26 U1.Y17 ; U1.T4 105.7,80.97 v1(105.88,80.79) 106.06,80.97 U1.T2 ; U1.AP20 96.25,71.56 v1(96,71.82) 96.04,71.82 96.45,72.18 U1.AN20 ; J17.39 175.3,96.68 v1(175.17,96.81) ; U1.E15 99.2,86.33 99.45,86.08 99.54,86.08 99.58,86.03 v1(99.62,86.03) 99.78,86.03 100.06,85.75 U1.F13 ; J17.45 178.6,96.53 v1(178.32,96.81) ; Y1.2 88.72,93.42 89.34,94.04 v1(89.52,94.04) ; U1.B18 97.08,88.13 v1(97.08,87.64) 97.02,87.58 97.02,87.18 U1.D18 ; v1(266.61,91.48) 266.77,91.64 J23.14 ; PC529.2 136.04,80.99 v1(135.79,80.74) ; v1(71.21,85.08) 71.38,85.01 U1.G63 ; U1.AT42 v1(83.2,70.55) U1.AR42 ; U1.AM27 v1(91.43,72.47) ; J17.32 v1(175.3,105.24) ; v1(10.16,58.41) 9.71,57.96 JTYC1.31 9.63,57.73 9.41,57.51 JTYC1.12 ; U1.N68 v1(68.99,81.61) ; U1.AU32 v1(88.68,69.26) ; v1(102.32,84.13) 102.33,84.13 U1.J8 ; U1.AL45 82.28,73.32 U1.AM43 v1(82.28,72.47) ; v1(92.54,102.3) 92.53,101.9 92.53,101.41 PRT402.2 92.53,101 PR417.2 ; 142.78,113.63 v1(147.32,113.63) ; U1.N65 v1(70.94,81.61) ; U1.AW32 v1(89.51,68.26) U1.BA32 ; U1.U64 71.38,80.07 71.47,79.95 v1(71.59,79.78) 71.71,79.95 71.8,80.07 U1.U63 ; J17.4 v1(190.7,107.64) ; U1.AK69 U1.AK68 68.74,73.98 v1(69.06,74.3) 69.32,74.56 U1.AH67 ; J5.12 262.64,126.89 262.26,126.51 v1(261.95,126.51) ; v1(95.63,74.86) 95.32,75.17 U1.AG21 ; U1.B39 84.87,87.95 v1(84.87,87.67) 84.87,87.33 U1.D39 ; U1.J13 v1(100.57,84.08) U1.J11 ; PU403.26 v2(61.1,106.75) ; U1.AN28 v1(90.51,71.82) U1.AN30 ; U1.AN35 86.98,71.93 v1(86.85,71.82) ; U1.E18 96.94,86.61 v1(96.91,86.62) ; U1.F27 91.79,85.85 91.06,85.85 U1.F28 90.8,85.58 v1(90.53,85.58) ; C852.1 162,59.4 162.41,59 163.17,59 163.56,58.61 v1(163.56,58.41) ; U1.AT58 v1(74.05,70.55) U1.AR58 ; J16.12 169.6,64.53 169.58,64.55 v1(169.58,64.6) ; U1.AD21 U1.AB21 U1.Y21 95.32,78.72 ; U1.AN40 84.88,72.53 v1(85,72.53) ; RT8.2 119.69,59.98 v2(119.8,60.08) ; U1.AD8 v1(103.6,76.42) ; U1.BA41 v1(84.56,68.26) U1.AW41 84.56,68.81 v1(85.02,69.28) U1.AU38 ; CC15.2 CC14.2 142.86,68.45 v1(143.11,68.2) ; U1.AA68 v1(68.99,77.95) ; U1.E56 v1(74.97,86.62) ; U1.F32 89.02,85.75 v1(88.67,85.4) 88.32,85.75 U1.F33 ; v1(85.02,71.18) 85.4,71.5 U1.AP38 ; U1.AW28 v1(92.02,68.26) U1.BA28 ; U1.AT28 v1(90.51,70.55) 90.73,70.73 U1.AR28 ; U1.AR48 v1(79.54,70.55) ; U1.AG17 97.27,74.65 U1.AJ18 97.05,74.25 97.05,73.85 U1.AK18 ; U1.AG17 97.92,75.22 v1(98.26,74.89) 98.3,74.94 98.33,74.99 U1.AG16 U1.AF15 99.49,75.87 99.49,75.6 99.65,75.43 99.65,75.15 U1.AH13 99.79,74.47 U1.AJ15 98.86,74.1 v1(98.86,74.05) 98.57,73.76 U1.AK16 ; U1.AP18 97.36,71.52 96.96,71.18 v1(96.91,71.18) ; C8356.2 25.17,74.53 v1(25.2,74.57) ; J16.9 170.1,58.79 169.83,58.52 v1(169.81,58.52) 169.9,58.43 170.34,58.43 170.6,58.69 J16.7 ; U1.U70 67.48,80.07 67.57,79.95 v1(67.69,79.78) 67.81,79.95 67.9,80.07 U1.U69 ; U1.AN23 93.64,72.16 v1(93.25,71.82) ; J17.26 v1(178.6,105.24) ; v1(103.6,82.69) U1.L8 ; U1.K63 v1(71.57,83.46) U1.K64 ; J17.7 v1(189.05,107.62) ; U1.AM8 102.86,73.34 U1.AK8 103.78,73.34 v1(104.76,73.34) ; U1.AM45 v1(81.37,72.47) ; J17.23 v1(180.25,105.27) ; U1.AK11 101.58,73.52 v1(101.56,73.37) 100.62,73.37 U1.AM13 ; v1(29.99,76) C8339.2 ; U1.AM25 v1(92.34,72.47) ; v1(66.04,86.84) 64.61,86.84 62.71,84.94 RC92.2 ; U1.AW23 v1(94.5,68.26) U1.BA23 ; U1.L11 v1(101.7,82.69) 101.7,82.53 U1.N10 ; U1.G60 v1(73.14,85.35) ; J32.36 v1(205.05,57.64) ; U1.B62 U1.D62 72.28,86.68 v1(72.22,86.62) ; U1.AL35 87.77,73.93 88.15,74.31 v1(88.15,74.36) ; U1.AP68 v1(68.33,71.48) U1.AP70 ; U1.E50 v1(78.62,86.63) ; D87.3 13.69,54.5 ; CC11.1 v1(87.84,93.66)
  BOTTOM w0.305: v1(74.28,32.65) 74.53,32.65 75.28,33.4 J21.209 ; J21.22 26.53,28.97 27.15,29.6 v1(27.53,29.6) ; PR216.2 164.32,73.71 164.32,73.34 v1(164.37,73.29) 164.25,73.16 PR217.2 ; CA55.1 157.31,52.96 v1(157.31,52.69) ; v1(70.19,86.62) 70.19,85.59 69.77,85.16 U1.G66 ; J22.33 233.6,52.7 v1(233.49,52.82) ; C8341.2 C8340.2 v1(32.33,63.75) ; v1(85.28,33.29) 85.16,33.29 84.78,33.67 J21.247 ; J21.56 35.03,28.14 35.09,28.21 35.09,29.96 34.71,30.34 v1(34.71,31.33) 34.97,31.33 35.28,31.64 J21.57 ; v1(1.68,66.16) 1.85,65.99 2.57,65.99 PR88.2 ; RC53.2 RC52.2 113.7,75.37 v1(113.51,75.56) 113.36,75.71 RC157.1 ; CA52.1 286.13,68.27 v1(286.39,68.54) ; J21.175 v1(66.78,33.92) ; v1(78.42,29.84) 77.83,29.84 77.53,29.53 J21.218 ; J21.93 44.28,33.56 43.22,32.5 v1(42.91,32.5) 42.78,32.5 41.28,34.01 J21.81 ; 144.81,69.6 PC218.2 ; v1(285.56,69.86) 285.93,69.49 CA46.1 ; J21.168 65.03,28.2 65.05,28.23 65.05,28.8 v1(65.43,29.17) ; J21.252 v1(86.03,28.31) ; PC213.2 159.78,70.24 v1(160.49,70.24) ; J21.103 v1(46.78,33.77) 47.31,33.77 47.78,34.24 J21.107 ; D94.2 284.38,51.34 v1(284.38,50.79) ; v1(81.78,33.92) J21.235 ; J11.31 v1(263.55,136.24) ; v1(140.67,68.51) 140.67,68.87 140.44,69.11 UC3.3 ; v1(203.16,50.43) 203.3,50.57 J32.29 ; v2(179.31,67.5) 178.97,67.16 PQ22.3 ; v1(34.53,29.09) 33.97,28.53 33.97,28.08 34.03,28.02 J21.52 ; v1(143.65,105.32) 143.65,105.17 144,104.81 PC716.1 ; v1(69.28,32.65) 69.07,32.65 68.57,33.15 68.57,33.33 68.28,33.63 J21.181 ; C118.1 C123.1 C121.1 266.44,130.15 266.93,129.66 v1(267.16,129.66) ; J21.36 v1(30.03,28.33) ; R486.1 112.96,77.07 RC156.1 113.59,77.11 115.04,75.66 v1(115.04,75.54) 115.13,75.44 115.13,74.76 114.92,74.55 RC54.2 RC51.2 ; C19.1 143.43,88.68 143.79,89.05 v1(143.82,89.05) ; U1.AN33 88.29,72.21 v1(88.68,71.82) ; v1(185.1,61.84) 185.38,61.56 PC18.1 PC19.1 ; J21.210 75.53,28.2 75.46,28.27 75.46,29.15 v1(75.73,29.43) ; v1(165.85,63.33) 165.54,63.03 165.54,62.42 165.9,62.06 J16.22 ; J21.184 v1(69.03,28.3) ; v1(32.45,33.14) 32.58,33.14 32.96,33.52 32.96,34.04 32.78,34.23 J21.47 ; v1(2.21,67.1) 2.66,67.56 3.66,67.56 4.11,67.1 PR46.2 ; J21.60 36.03,27.95 35.95,28.02 35.95,28.64 36.27,28.96 v1(36.53,28.96) ; J37.12 126.4,54.88 126.7,54.57 v1(127.01,54.57) ; v1(22.28,64.18) 22.43,64.33 R678.1 ; v1(131.15,60.08) 131.21,60.15 R428.2 ; v1(72.96,93.53) 72.75,93.74 RC21.2 ; J23.15 v1(294.3,89.91) ; v2(91.12,104) 90.99,103.87 PU402.3 ; J21.176 67.03,28.02 66.96,28.08 66.96,28.57 67.33,28.94 v1(67.53,28.94) 67.7,28.94 68.08,28.56 68.08,28.08 68.03,28.02 J21.180 ; v1(28.68,28.33) 28.53,28.17 J21.30 ; J21.238 v1(82.53,28.3) ; v1(43.53,28.96) 44.01,28.96 44.53,28.45 J21.94 ; J21.196 72.03,28.03 v1(72.3,28.3) ; U1.J38 v1(85.02,85.31) ; J21.48 33.03,28.52 32.9,28.64 32.9,29.25 33.38,29.72 v1(33.53,29.72) ; v1(39.28,32.5) 39.02,32.5 38.28,33.25 J21.69 ; J21.77 40.28,33.76 40.61,33.43 40.61,33 v1(40.12,32.5) ; J21.189 70.28,33.45 71.07,32.65 v1(71.27,32.65) ; v1(38.02,28.33) 38.03,28.32 J21.68 ; v1(8.1,68.09) PC83.2 PR98.2 ; v1(136.46,58.91) 137.01,58.91 C174.1 137.02,59.25 ; v1(23.53,33.92) 23.28,34.17 J21.9 ; J21.197 72.28,34.3 72.22,34.25 72.22,33.15 72.85,32.53 73.01,32.53 v1(73.09,32.45) ; J21.231 80.78,33.49 81.61,32.65 v1(81.78,32.65) ; J21.244 v1(84.03,28.3) ; v1(19.45,16.94) C232.1 C230.1 ; v1(162.62,55.92) 162.62,56.84 J38.30 ; v1(85.17,32.06) 85.47,32.06 85.93,32.52 85.93,34.09 85.78,34.25 J21.251 ; J21.98 45.53,28 46.16,28.64 46.16,29.02 ; v1(198.43,52.84) 198.38,52.84 197.8,52.27 J32.7 ; J21.217 v1(77.28,33.92) ; J21.5 v1(22.28,33.92) ; J21.192 v1(71.03,28.3) ; v1(210.21,52.82) 210.3,52.73 J32.57 ; J21.222 78.53,28.19 78.67,28.33 78.67,28.97 v1(78.42,29.22) ; PC21.1 v1(187.78,61.32) 187.75,61.34 PC20.1 ; v2(224.44,47.39) 224.75,47.7 J1.50 ; J21.65 37.28,34.3 37.37,34.2 37.37,33.16 36.72,32.5 v1(36.51,32.5) ; v1(208.74,52.84) 208.8,52.78 J32.51 ; v1(213.11,52.9) 213.11,52.65 213.3,52.45 J32.69 ; J22.5 226.6,52.42 226.12,52.89 225.97,52.89 v1(225.84,52.77) 226.1,52.51 J22.3 ; v1(214.94,52.82) 214.8,52.69 J32.75 ; J21.1 21.28,34.23 20.94,33.89 v1(20.94,32.52) ; R9107.1 22.16,69.19 v1(21.79,68.83) ; J22.71 243.1,50.53 243.15,50.53 v1(243.8,49.88) 243.9,49.99 243.9,50.48 243.6,50.78 J22.73 ; 160.54,80.02 PC225.1 160.91,79.68 ; v1(83.73,32.88) 84.19,33.34 84.19,33.91 83.78,34.32 J21.243 ; PC776.2 149.08,105.47 v1(149.23,105.32) ; v1(69.03,29.57) 69.27,29.57 70.03,28.82 J21.188 ; v1(158.43,58.99) 158.43,59.37 CA53.1 ; J21.27 v1(27.78,33.92) ; v1(12.63,54.5) 13.68,54.5 13.69,54.5 ; v1(204.2,50.46) 204.28,50.53 205.48,50.53 205.8,50.86 J32.39 ; v1(25.78,32.65) 25.94,32.65 26.78,33.48 J21.23 ; D88.3 12.63,58.46 v1(12.57,58.51) ; J21.82 v1(41.53,28.33) ; U1.L2 106.03,83.62 v1(105.88,83.48) 105.73,83.62 U1.L4 ; J21.39 30.78,34.28 30.67,34.18 30.67,33.67 31.05,33.29 v1(31.18,33.29) 31.43,33.29 31.78,33.63 J21.43 ; J21.44 32.03,28.98 31.41,29.6 v1(31.03,29.6) ; C8337.2 24.82,63.09 C8338.2 23.95,62.76 24.42,62.29 v1(24.75,62.29) ; J21.239 82.78,33.07 v1(83.78,32.07) ; J21.193 71.28,33.92 v1(71.27,33.92) ; v1(25.53,29.6) 25.12,29.6 24.53,29 J21.14 ; J21.205 v1(74.28,33.92) ; J21.227 v1(79.78,33.92) ; v1(32.45,31.87) 32.75,31.87 33.11,32.22 33.11,32.75 33.57,33.21 33.57,33.61 33.78,33.82 J21.51 ; v1(23.53,31.38) 23.71,31.38 24.78,32.45 J21.15 ; v1(81.53,29.57) 81.3,29.57 80.53,28.79 J21.230 ; J21.171 v1(65.78,33.92) ; J21.213 76.28,33.29 76.91,32.65 v1(77.28,32.65) ; J21.106 v1(47.53,28.33) ; 46.16,29.02 46.53,28.66 J21.102 ; 46.16,29.02 v1(45.53,29.65) ; J21.2 v1(21.53,28.33) ; PC312.2 127.43,62.64 v1(127.01,63.05) 126.81,63.25 PU301.10 ; RC100.1 65.29,94.27 v1(65.29,94.28) ; v1(78.87,33.5) 78.83,33.5 78.83,33.49 78.78,33.54 J21.223 ; J21.73 v1(39.28,33.77) ; J21.85 42.28,34.25 42.75,33.77 v1(42.91,33.77) 43.28,34.14 J21.89 ; v1(284.48,48.3) 284.84,48.66 C564.1 ; v1(100.64,60.03) 100.64,60.43 CC17.1 ; v1(131.65,54.27) 131.48,54.45 131.48,55.28 J37.7 ; J21.90 v1(43.53,28.33) ; J32.77 215.9,50.51 v1(215.95,50.47) ; J21.172 v1(66.03,28.3) ; PR218.2 v1(155.69,72.25) ; v1(74.53,29.57) 74.27,29.57 73.53,28.82 J21.202 ; J21.206 v1(74.53,28.3) ; PR89.1 PC84.2 2.67,62.32 v1(2.67,61.89) ; v1(67.85,94.01) 67.45,93.6 RC101.1 ; J21.61 36.28,34.01 v1(36.51,33.77) ; J21.226 v1(79.53,28.3) ; 46.41,68.52 C281.2 ; J21.86 v1(42.53,28.33) ; U1.AP42 U1.AN42 ; PU402.5 90.19,103.46 v2(89.9,103.75) ; J21.234 v1(81.53,28.3) ; v1(212.02,52.89) 211.82,52.69 211.82,51.65 J32.63 ; J21.64 37.03,28.01 37.09,28.08 37.09,29.83 36.69,30.23 v1(36.53,30.23) ; v1(40.53,28.33) J21.78 ; J22.11 228.1,52.77 v1(228.15,52.82) ; J21.185 v1(69.28,33.92) ; J21.31 28.78,34.26 28.71,34.2 28.71,33.31 28.05,32.65 v1(27.78,32.65) ; v1(29.28,33.29) 29.4,33.29 29.84,33.73 29.84,34.16 29.78,34.23 J21.35 ; v1(265.82,121.4) 265.83,121.39 C119.1 C117.1 C120.1 265.9,122.55 v1(265.82,122.47) 265.82,123.1 C116.1 ; J21.19 v1(25.78,33.92) ; J21.10 v1(23.53,28.33) ; J21.26 v1(27.53,28.33) ; J21.201 73.28,34.19 73.42,34.05 73.42,33.41 v1(73.09,33.08) ; J21.18 v1(25.53,28.33) ; v1(39.02,28.33) 39.03,28.33 J21.72 ; J21.214 v1(76.53,28.3) ; J21.6 v1(22.53,28.33) ; PC210.2 v1(173.75,68.8) ; J32.45 v1(207.3,52.82) ; J21.248 v1(85.03,28.3) ; J21.40 v1(31.03,28.33)
  BOTTOM w0.381: v1(235.27,52.96) 235.1,52.79 J22.39 ; v1(97.6,56.45) 97.73,56.32 J12.2 ; J26.21 136.58,68.16 v1(136.18,67.75) ; v1(101.03,54.37) 101.03,56.7 Q40.3 ; v1(113.11,75.1) 112.46,75.1 CC38.1 ; C302.1 221.98,54.01 v1(222.64,54.67) 222.64,54.47 223.57,53.54 224.28,53.54 224.5,53.32 J22.76 ; J38.34 v1(157.91,52.71) ; RC142.2 75.5,93.43 v1(75.75,93.69) ; PC317.2 PC316.2 105.39,51.32 v1(105.03,51.69) ; PC480.2 68.17,110.22 v1(68.18,110.22) ; Q39.3 98.33,57.02 v1(98.33,56.45) ; 147.38,88.18 PC206.2 ; v1(65.76,112.25) PC471.2 ; J23.6 v1(266.6,99.93) ; PC451.2 89.9,99.17 v1(89.6,99.17) ; v1(173.31,62.95) 173.31,62.65 173.8,62.16 J16.21 ; v2(144.56,83.1) 144.66,82.99 PC207.2 ; J23.3 v1(269.49,105.53) ; PC450.2 89.26,99.96 88.91,99.61 v1(88.91,99.12) ; J23.11 v1(266.42,95.93) ; PRT404.2 61.4,110.85 61.82,111.27 v1(61.82,111.39) 61.82,111.85 ; v1(264.65,133.62) 264.52,133.76 C269.1 ; J26.8 v1(133.56,65.31) ; v1(43.24,62.8) 43.1,62.94 J15.8
  BOTTOM w0.508: PQ15.3 19.93,73.77 v1(20.52,74.36) ; v1(108.63,98.9) 109.44,99.71 CC55.1 ; v1(289.26,63) 289.26,61.61 288.52,60.86 S1.1 S1.2 285.89,60.82 D99.2 285.86,59.66 CA44.1 ; v1(121.66,71.42) 122.3,70.78 UC5.4 ; 288.88,115.84 285.88,118.84 J3.10 ; v1(174.63,66.94) 174.1,66.94 173.87,67.17 D711.1 ; J37.14 124.88,50.23 125.59,50.23 v1(126.55,51.19) ; J11.32 280.15,137.98 279.33,138.8 v2(278.83,138.8) ; D56.2 15.67,30.97 v1(15.5,30.8) ; v1(42.99,69.91) 43.1,69.8 J15.9 ; v1(262.1,97.73) 261.03,97.73 S2.3 260.63,98.59 v1(262.13,98.59) ; PC221.2 148.29,88.94 v1(148.19,89.05) ; J1.41 234.77,49.4 235.39,48.78 235.39,48.48 ; H9.1 286.98,135.88 J3.12 ; v1(22.48,75.91) 22.94,75.46 PR83.2 ; v1(92.03,93.66) 92.03,93.29 CC44.1 CC45.1 ; S3.3 v1(261.73,137.33) ; v1(147.38,89.05) 147.38,88.18 ; PC229.1 v1(146.49,89.05) ; J5.15 v1(263.32,131.14) ; J23.13 v1(268.04,117.57)
  vias: v1(0.76,47.87) v1(1.47,68.37) v1(2.47,41.22) v1(5.18,48.91) v1(6.76,63.49) v1(6.78,62.88) v1(7.32,39.67) v1(8.85,76.65) v1(9.68,65.73) v1(9.65,64.69) v1(11.08,39.64) v1(11.89,76.65) v1(12.57,63.42) v1(13.29,63.44) v1(14.53,1.57) v1(14.69,76.64) v1(15.34,47.54) v1(15.34,46.96) v1(16.44,38.77) v1(16.41,1.52) v1(16.72,25.67) v1(16.71,25.07) v1(16.72,24.47) v1(17.41,15.18) v1(17.54,23.28) v1(17.89,7.4) v1(17.86,1.52) v1(18.32,76.67) v1(18.35,52.29) v1(18.35,51.7) v1(18.4,52.92) v1(18.93,51.68) v1(18.86,8.6) v1(18.88,7.91) v1(18.88,7.3) v1(19.01,53.5) v1(19.01,52.89) v1(19.01,52.29) v1(18.96,51.09) v1(20.3,15.1) v1(20.28,7.02) v1(21.9,37.32) v1(22.28,32.65) v1(22.28,31.38) v1(22.41,50.81) v1(22.46,49.62) v1(22.62,76.67) v1(22.89,56.7) v1(23.14,42.64) v1(23.27,76.01) v1(23.48,43.19) v1(23.88,76.01) v1(23.94,56.63) v1(24.09,43.12) v1(24.21,43.71) v1(24.49,76.01) v1(24.6,24.27) v1(24.66,43.02) v1(24.82,43.6) v1(25.1,76.01) v1(25.49,25.11) v1(27.25,68.61) v1(27.22,67.67) v1(27.22,66.57) v1(27.29,76.64) v1(27.27,69.44) v1(27.26,15.3) v1(27.42,56.93) v1(28.14,67.67) v1(28.19,70.38) v1(28.21,69.44) v1(28.15,68.57) v1(28.19,66.6) v1(28.41,56.83) v1(28.68,30.87) v1(29.1,67.67) v1(29.91,56.22) v1(31.15,32.04) v1(31.58,76.64) v1(33.81,32.48) v1(34.24,74.54) v1(34.37,69.66) v1(34.9,66.67) v1(35.32,76.69) v1(36.45,69.11) v1(36.51,31.23) v1(38.02,29.6) v1(39.33,30.9) v1(39.38,77.33) v1(40.94,70.72) v1(40.95,69.91) v1(40.95,69.02) v1(41.2,56.38) v1(41.53,29.6) v1(41.82,69.89) v1(41.84,69.02) v1(41.86,70.76) v1(42.45,78.35) v1(43,70.76) v1(44.14,70.76) v1(44.13,69.91) v1(44.13,69.02) v1(45.29,70.76) v1(45.27,69.91) v1(45.27,69.02) v1(46.11,80.3) v1(46.39,70.76) v1(46.42,69.91) v1(46.69,62.22) v1(46.75,60.77) v1(47.69,62.17) v1(47.84,64.71) v1(47.84,31.21) v1(48.37,63.28) v1(48.78,82.41) v1(49.06,29.68) v1(49.54,30.64) v1(50.48,79.06) v1(50.73,84.44) v1(51.7,31.84) v1(51.88,80.45) v1(52.03,29.6) v1(52.71,87.18) v1(52.71,73.75) v1(53.53,30.87) v1(54.29,90.36) v1(54.29,29.58) v1(54.77,32.65) v1(55.28,93.69) v1(56.53,29.6) v1(56.58,31.3) v1(57.46,113.65) v1(57.69,30.87) v1(59.78,33.29) v1(60.03,29.57) v1(60.36,76.63) v1(60.54,77.81) v1(60.98,75.03) v1(61.1,30.97) v1(61.25,29.73) v1(61.63,76.63) v1(61.78,72.76) v1(63,113.65) v1(63.03,28.94) v1(63.27,69.95) v1(63.8,30.97) v1(64.37,31.94) v1(66.01,29.56) v1(66.35,31.99) v1(66.96,113.65) v1(67.12,63.09) v1(67.12,61.12) v1(67.2,65.89) v1(69.25,62.48) v1(69.25,60.52) v1(69.22,31.38) v1(71.03,29.57) v1(71.05,31.05) v1(71.18,60.74) v1(71.18,58.79) v1(71.71,113.65) v1(72.3,30.84) v1(73.81,60.77) v1(73.85,58.79) v1(74.2,31.38) v1(75.96,61.37) v1(76.51,90.51) v1(76.59,92.21) v1(77,113.65) v1(77.39,31.68) v1(78.09,62.45) v1(78.09,61.18) v1(78.7,58.81) v1(78.7,58.2) v1(78.7,57.59) v1(78.75,55.51) v1(79.53,29.57) v1(79.64,91.2) v1(79.79,32.65) v1(79.87,31.3) v1(80.37,89.7) v1(81.75,113.65) v1(81.74,91.79) v1(83.75,30.77) v1(84.54,92.01) v1(84.52,29.58) v1(84.77,91.43) v1(85.53,29.5) v1(86.75,39.36) v1(86.75,38.77) v1(87,113.65) v1(87.33,38.77) v1(87.54,30.72) v1(88.55,29.02) v1(90.56,27.32) v1(90.56,26.73) v1(90.56,26.15) v1(91.75,113.65) v1(91.76,75.84) v1(92.36,75.84) v1(93.32,98.7) v1(93.81,98.06) v1(93.91,98.7) v1(94.45,98.06) v1(94.49,98.67) v1(94.72,45.89) v1(95.08,98.67) v1(95.18,54.27) v1(95.26,99.22) v1(96.5,113.65) v1(98.72,86.68) v1(99.07,111.47) v1(99.32,97.29) v1(99.65,111.44) v1(101.2,100.01) v1(101.25,113.65) v1(101.65,54.37) v1(101.81,99.99) v1(102.4,100.27) v1(104.81,97.9) v1(106.08,110.65) v1(107.4,113.65) v1(108.67,73.21) v1(109.94,74.56) v1(111.28,75.22) v1(112.15,113.65) v1(113.78,104.94) v1(113.78,104.36) v1(116.82,113.65) v1(117.13,100.82) v1(117.71,100.82) v1(119.67,63) v1(120.91,78.65) v1(121.52,78.65) v1(122.13,78.65) v1(122.97,113.65) v1(125.39,106.37) v1(127.72,113.65) v1(128.08,108.98) v1(128.41,109.46) v1(128.51,58.71) v1(128.74,108.98) v1(129.73,63.41) v1(130.97,64.83) v1(131.05,63.41) v1(131.17,58.86) v1(131.28,57.47) v1(133.28,80.81) v1(133.92,113.63) v1(133.89,80.81) v1(134.52,80.81) v1(135.08,84.5) v1(135.82,83.89) v1(140.95,103.45) v1(141.51,51.73) v1(141.91,104.08) v1(142.15,51.75) v1(142.73,51.75) v1(143.22,61.56) v1(143.87,113.65) v1(144.25,105.38) v1(148.22,67.83) v1(148.27,62.9) v1(149.08,113.65) v1(150.43,103.67) v1(151.04,113.55) v1(151.04,103.69) v1(151.62,103.69) v1(152.35,57.5) v1(152.54,51.73) v1(153.2,51.73) v1(154.64,112.16) v1(154.67,113.6) v1(155.18,58.71) v1(156.14,113.66) v1(158.61,113.65) v1(159.06,75.42) v1(159.06,74.51) v1(160.03,75.4) v1(160.03,74.48) v1(161.27,113.66) v1(162.34,77.56) v1(162.92,77.56) v1(163.56,77.56) v1(164.07,113.65) v1(169.86,97.42) v1(170.37,113.65) v1(170.96,61.81) v1(171.87,97.34) v1(175.57,93.84) v1(175.83,113.65) v1(175.78,111.8) v1(175.9,111.14) v1(175.85,89.52) v1(176.69,92.6) v1(178.67,110.4) v1(180.25,113.6) v1(180.35,112.05) v1(180.32,109.28) v1(182.41,109.89) v1(183.5,111.95) v1(183.47,52.74) v1(184.06,52.79) v1(184.27,52.24) v1(184.64,52.79) v1(184.86,52.24) v1(185.3,52.67) v1(187.84,111.95) v1(187.82,46.6) v1(188.83,43.8) v1(192.31,111.95) v1(194.87,54.27) v1(195.46,54.27) v1(196.66,111.95) v1(197.29,109.94) v1(199.7,109.94) v1(203.34,109.94) v1(206.36,64.55) v1(211.03,71.46) v1(211.01,70.17) v1(211.01,64.15) v1(211.06,69.02) v1(211.64,57.11) v1(212.28,71.44) v1(212.26,70.19) v1(212.28,69.05) v1(212.4,62.75) v1(213.34,89.12) v1(213.45,71.44) v1(213.45,70.22) v1(213.45,68.97) v1(213.95,60.44) v1(215.39,43.78) v1(215.45,64.45) v1(216.04,86.65) v1(216.9,90.03) v1(217.15,56.86) v1(217.64,63.74) v1(217.68,51.43) v1(218.05,86.19) v1(218.63,43.78) v1(219.33,50.8) v1(219.39,90.23) v1(219.77,70.17) v1(219.87,111.95) v1(219.92,64.2) v1(220.28,85.81) v1(220.3,61.26) v1(221.24,45.48) v1(221.42,46.04) v1(221.65,89.85) v1(222.89,56.05) v1(222.86,43.78) v1(223.63,111.95) v1(226.65,50.41) v1(227.19,111.95) v1(228.71,43.78) v1(230.21,111.95) v1(230.74,50.23) v1(230.76,45.84) v1(230.87,53.23) v1(234.47,46.47) v1(234.88,111.95) v1(235.08,46.5) v1(237.51,49.68) v1(237.88,105.47) v1(238.54,105.8) v1(238.59,111.95) v1(238.59,105.17) v1(238.74,43.8) v1(239.2,105.57) v1(239.45,53.51) v1(239.86,105.57) v1(241.56,104.96) v1(241.79,105.57) v1(241.87,43.8) v1(242.17,87.87) v1(242.33,48.12) v1(242.4,105.88) v1(243.27,86.36) v1(243.44,84.01) v1(243.54,111.95) v1(243.54,101.26) v1(243.9,102.88) v1(244.61,99.12) v1(244.97,100.62) v1(245.04,49.8) v1(245.47,43.8) v1(245.83,94.65) v1(245.75,49.67) v1(246.44,94.65) v1(247.25,111.95) v1(249.79,43.8) v1(250.61,111.95) v1(253.35,67.19) v1(253.76,111.95) v1(254.16,43.78) v1(256.75,112.79) v1(257.2,47.79) v1(257.21,43.85) v1(257.31,49.82) v1(257.29,46.98) v1(257.76,63.31) v1(258.2,51.68) v1(258.56,115.15) v1(258.84,137.45) v1(258.84,133.26) v1(258.84,130.21) v1(258.84,126.48) v1(258.84,122.95) v1(258.84,118.81) v1(259.51,56.2) v1(259.7,139.61) v1(260.44,78.96) v1(260.87,51.68) v1(261.73,133.13) v1(262.85,123.81) v1(262.87,51.7) v1(263.66,139.61) v1(266.13,103.19) v1(267.01,139.61) v1(267.59,126.56) v1(267.74,119.02) v1(267.82,121.18) v1(268.15,131.56) v1(268.67,101.66) v1(269.58,101.69) v1(269.55,88.61) v1(269.96,91.12) v1(270.06,102.45) v1(270.57,139.61) v1(272.09,120.11) v1(272.14,119.35) v1(272.14,118.53) v1(272.21,81.57) v1(272.24,80.23) v1(272.22,64.06) v1(272.23,62.97) v1(272.23,61.82) v1(272.23,60.74) v1(272.92,122.47) v1(272.92,121.84) v1(272.92,121.2) v1(273.36,64.03) v1(273.38,62.9) v1(273.38,61.76) v1(273.38,60.68) v1(273.48,122.19) v1(273.48,121.53) v1(273.46,120.87) v1(274.48,64.01) v1(274.48,62.86) v1(274.51,61.72) v1(274.56,60.6) v1(275.02,80.15) v1(275.07,81.22) v1(275.27,139.61) v1(275.56,80.68) v1(275.83,48.32) v1(275.8,47.46) v1(275.8,44.08) v1(276.08,81.19) v1(276.08,80.12) v1(277.43,77.69) v1(277.38,77.08) v1(278.18,74.59) v1(278.29,43.78) v1(278.73,79.34) v1(278.75,75.22) v1(278.79,74.59) v1(279.05,139.61) v1(279.58,43.78) v1(280.7,87.64) v1(280.68,85.77) v1(281.37,43.78) v1(281.49,142.63) v1(281.64,86.6) v1(281.85,92.24) v1(282.43,92.24) v1(282.65,87.65) v1(282.66,85.74) v1(284.18,43.8) v1(286.01,142.66) v1(286.03,43.78) v1(287.38,141.82) v1(287.49,43.78) v1(288.1,84.31) v1(288.12,71.84) v1(289.49,118.05) v1(290.51,43.8) v1(291.22,87.36) v1(291.68,137.5) v1(291.8,70.17) v1(292.24,139.59) v1(292.21,118.07) v1(292.72,85.38) v1(293.13,43.78) v1(293.13,41.36) v1(293.13,38.92) v1(293.91,139.56) v1(293.94,87.39) v1(294.12,117.91) v1(295.32,136.08) v1(295.56,113.04) v1(295.84,37.76) v1(296.17,137.81) v1(297.98,139.43) v1(298.61,115.27) v1(298.61,107.65) v1(298.61,100.03) v1(298.61,92.41) v1(298.59,85.46) v1(298.81,69.59) v1(298.92,37.76) v1(300.08,66.54) v1(300.14,39.13) v2(3.68,19.83) v2(7.04,21.25) v2(8.32,18.35) v2(14.46,3.47) v2(16.04,2.83) v2(16.65,4.99) v2(18.32,2.81) v2(18.83,5.04) v2(31.15,25.36) v2(35.8,25.36) v2(40.65,25.36) v2(45.81,25.39) v2(51.75,25.31) v2(56.6,25.31) v2(57.48,103) v2(57.48,102.24) v2(57.48,101.48) v2(58.75,103) v2(58.75,102.24) v2(58.75,101.48) v2(60.28,103) v2(60.28,102.24) v2(60.28,101.48) v2(61.25,25.31) v2(62.29,101.92) v2(62.44,103.16) v2(62.61,102.47) v2(62.56,101.32) v2(63,101.92) v2(63.05,97.91) v2(63.07,103) v2(63.08,100.55) v2(63.05,99.89) v2(63.05,99.26) v2(63.06,98.57) v2(63.17,108.47) v2(63.17,107.83) v2(63.17,107.05) v2(63.17,106.35) v2(63.17,105.58) v2(63.17,104.75) v2(63.17,104.08) v2(63.32,101.32) v2(63.45,102.47) v2(63.7,101.88) v2(63.81,108.5) v2(63.8,107.83) v2(63.81,107.12) v2(63.84,106.39) v2(63.84,105.63) v2(63.84,104.81) v2(63.83,103) v2(63.85,104.06) v2(63.98,101.3) v2(64.32,97.22) v2(64.37,108.17) v2(64.37,107.53) v2(64.4,106.82) v2(64.47,106.13) v2(64.47,105.5) v2(64.47,104.84) v2(64.5,104.1) v2(64.59,103) v2(64.75,101.3) v2(64.96,108.5) v2(64.96,97.22) v2(65.06,106.49) v2(65.06,105.78) v2(65.08,105.02) v2(65.11,104.36) v2(66.1,25.31) v2(66.18,97.22) v2(66.94,97.14) v2(67.88,97.14) v2(68.74,97.14) v2(69.45,99.76) v2(69.45,98.59) v2(71.26,25.34) v2(76.11,25.34) v2(81.19,25.36) v2(86.04,25.36) v2(89.29,25.34) v2(89.82,107.89) v2(89.82,107.25) v2(89.85,106.59) v2(89.85,105.83) v2(90.09,109.88) v2(90.09,109.25) v2(90.08,108.6) v2(90.54,107.47) v2(90.54,106.84) v2(90.54,106.2) v2(90.54,105.57) v2(90.55,108.14) v2(90.73,109.88) v2(90.73,109.25) v2(91.12,108.52) v2(91.12,107.81) v2(91.12,107.17) v2(91.12,106.54) v2(91.12,105.9) v2(91.12,105.27) v2(91.36,109.88) v2(91.36,109.25) v2(91.82,108.58) v2(91.82,107.95) v2(91.82,107.31) v2(91.82,106.68) v2(91.82,106.04) v2(92,109.88) v2(92,109.25) v2(92.24,25.44) v2(92.39,30.49) v2(92.63,109.88) v2(92.63,109.25) v2(93.2,41.62) v2(93.27,109.88) v2(93.27,109.25) v2(93.3,108.57) v2(93.25,36.99) v2(93.9,109.88) v2(93.9,109.25) v2(93.94,108.55) v2(94.55,112.71) v2(94.54,109.88) v2(94.54,109.25) v2(94.57,108.55) v2(95.18,112.71) v2(95.17,109.88) v2(95.17,109.25) v2(95.23,108.52) v2(95.49,46.75) v2(95.82,112.71) v2(95.81,109.88) v2(95.81,109.25) v2(96.44,109.88) v2(96.44,109.25) v2(96.58,112.71) v2(97.08,109.88) v2(97.08,109.25) v2(97.22,112.71) v2(97.71,109.88) v2(97.71,109.25) v2(97.85,112.71) v2(103.82,60.77) v2(103.82,60.13) v2(105.25,105.52) v2(105.23,104.24) v2(105.27,104.88) v2(105.92,105.53) v2(105.92,104.87) v2(105.92,104.23) v2(107.65,60.74) v2(113.83,107.48) v2(113.83,106.82) v2(115.88,77.86) v2(116.54,77.86) v2(117.18,77.86) v2(117.66,86.02) v2(118.14,86.45) v2(120.48,60.08) v2(120.66,52.03) v2(121.07,52.62) v2(121.22,53.81) v2(121.37,52.03) v2(121.47,53.23) v2(121.57,54.37) v2(121.7,52.62) v2(121.93,53.83) v2(122.13,53.23) v2(122.23,54.42) v2(122.36,52.62) v2(122.59,53.83) v2(122.79,53.23) v2(122.89,54.42) v2(123.02,52.62) v2(123.25,53.83) v2(123.45,53.23) v2(123.58,54.42) v2(123.89,53.81) v2(124.27,64.53) v2(124.27,63.54) v2(124.73,64.05) v2(125.33,66.76) v2(125.26,63.54) v2(126.93,68.85) v2(126.93,68.21) v2(130.87,85.36) v2(130.9,84.7) v2(131.25,82.64) v2(131.58,85.36) v2(131.61,84.7) v2(131.63,84.01) v2(131.63,83.27) v2(131.98,82.67) v2(132.27,109.03) v2(132.32,84.7) v2(132.34,84.01) v2(132.36,83.3) v2(132.56,79.85) v2(132.67,82.66) v2(133.5,88.49) v2(133.54,75.17) v2(134.04,88) v2(134.16,88.64) v2(134.7,87.98) v2(135.76,88.54) v2(136.23,75.12) v2(136.4,88.56) v2(137.42,73.24) v2(137.4,72.58) v2(138.91,97.71) v2(138.96,98.37) v2(139.1,88.61) v2(139.24,98.95) v2(139.55,99.51) v2(139.52,88.1) v2(139.6,98.39) v2(139.57,97.76) v2(139.9,98.95) v2(140.18,99.53) v2(140.21,97.73) v2(140.29,98.37) v2(140.59,98.92) v2(140.65,72.15) v2(140.67,71.39) v2(140.83,99.53) v2(140.95,98.37) v2(141.06,70.57) v2(141.25,98.92) v2(141.41,72.94) v2(141.41,72.17) v2(141.41,71.39) v2(141.51,99.5) v2(141.61,98.37) v2(141.72,70.78) v2(141.74,70.09) v2(141.94,99) v2(142.17,99.76) v2(142.24,98.42) v2(142.55,99.2) v2(142.88,99.79) v2(145.63,67.88) v2(145.6,62.95) v2(146.19,101.03) v2(146.52,101.61) v2(146.52,100.44) v2(146.9,101.05) v2(147.28,101.61) v2(147.28,100.44) v2(147.66,101.05) v2(148.04,101.61) v2(148.04,100.44) v2(152,84.8) v2(152.66,84.8) v2(152.76,99.35) v2(153.29,84.8) v2(153.49,83.74) v2(153.95,84.8) v2(154.15,83.74) v2(154.61,84.8) v2(155.27,84.8) v2(156.06,83.99) v2(156.06,83.25) v2(156.06,82.57) v2(156.6,67.07) v2(156.6,65.57) v2(156.96,66.51) v2(157.34,65.95) v2(157.41,83.99) v2(157.43,83.28) v2(157.41,82.57) v2(157.36,67.04) v2(158.45,83.98) v2(158.48,83.27) v2(158.48,82.56) v2(158.94,80.5) v2(159.26,89.76) v2(159.7,80.5) v2(160.46,80.5) v2(165.52,84.39) v2(165.9,84.95) v2(166.28,85.56) v2(166.28,84.39) v2(166.66,84.95) v2(167.04,85.56) v2(167.04,84.39) v2(167.42,84.95) v2(167.8,85.56) v2(167.8,84.39) v2(168.18,84.95) v2(168.56,85.56) v2(168.56,84.39) v2(168.94,84.95) v2(169.33,85.56) v2(169.33,84.39) v2(169.66,84.98) v2(171.51,85.56) v2(172.27,85.56) v2(173.47,78.29) v2(173.64,77.69) v2(174.2,78.29) v2(174.38,77.69) v2(174.96,78.29) v2(175.14,77.69) v2(175.75,78.29) v2(175.93,77.69) v2(176.56,78.27) v2(176.72,82.64) v2(176.72,81.85) v2(176.74,77.66) v2(177.33,83.02) v2(177.33,82.23) v2(177.35,81.42) v2(177.35,78.27) v2(177.53,77.66) v2(179.94,67.5) v2(180.58,67.5) v2(181.21,67.5) v2(181.47,84.59) v2(181.47,83.96) v2(181.47,83.32) v2(182.1,84.59) v2(182.1,83.96) v2(182.1,83.32) v2(182.74,84.59) v2(182.74,83.96) v2(182.74,83.32) v2(183.41,84.62) v2(183.41,83.96) v2(183.41,83.3) v2(184.1,84.62) v2(184.1,83.94) v2(184.44,67.86) v2(184.68,84.29) v2(186.78,67.6) v2(189.21,89.01) v2(189.59,89.65) v2(189.59,88.4) v2(189.98,89.01) v2(190.36,89.65) v2(190.36,88.4) v2(190.74,89.01) v2(191.12,89.65) v2(191.12,88.4) v2(191.5,89.01) v2(191.83,89.65) v2(192.21,89.12) v2(197.7,85.64) v2(197.98,87.39) v2(197.98,86.73) v2(198.71,76.36) v2(198.66,74.69) v2(199.45,75.6) v2(200.06,76.34) v2(200.06,74.69) v2(230.46,55.59) v3(2.72,19.47) v3(13.5,19.27) v3(14.06,23.18) v3(17.71,4.05) v3(18.04,8.19) v3(25.45,50.94) v3(25.48,50.41) v3(25.47,48.81) v3(25.5,48.28) v3(25.83,51.33) v3(26.75,48.3) v3(27.28,48.28) v3(27.97,50.74) v3(28.47,48.96) v3(28.47,48.35) v3(44.69,71.34) v3(62.42,107.05) v3(70.8,54.01) v3(79.87,53.12) v3(92.49,111.37) v3(113.06,107.89) v3(121.37,51.07) v3(121.88,78.02) v3(129.47,60.59) v3(142.43,70.45) v3(153.12,85.86) v3(155.5,112.84) v3(172.96,77.84) v3(176.03,76.85) v3(180.44,84.32) v3(234.58,45.2) v3(237.97,101.95) v3(261.32,122.92) v3(262.77,133.03) v3(265.87,102.3) v3(287.87,88.02) v3(290,89.7) v3(296.47,89.04) v4(58.18,102.22) v4(61.38,102.12) v4(103.39,96.1) v4(108.76,97.82) v4(195.2,55.05) v4(245.63,94.12) v4(284.36,91.78)
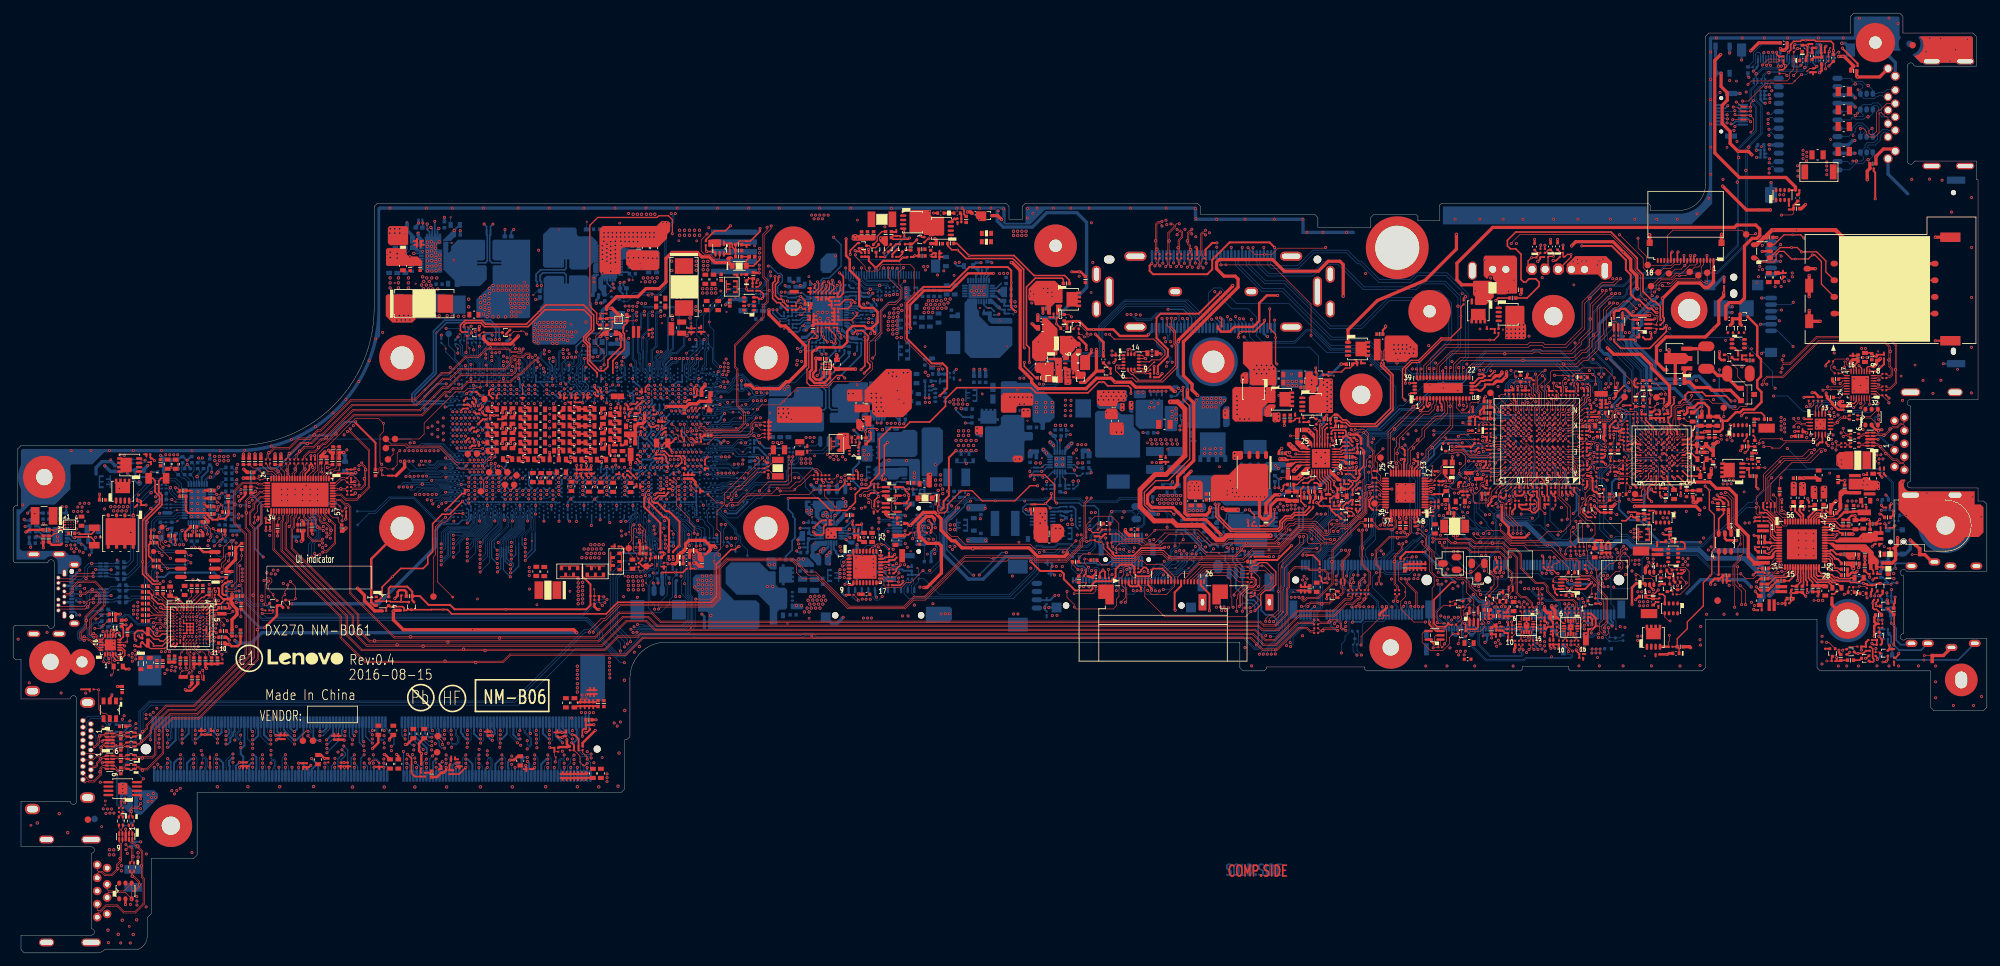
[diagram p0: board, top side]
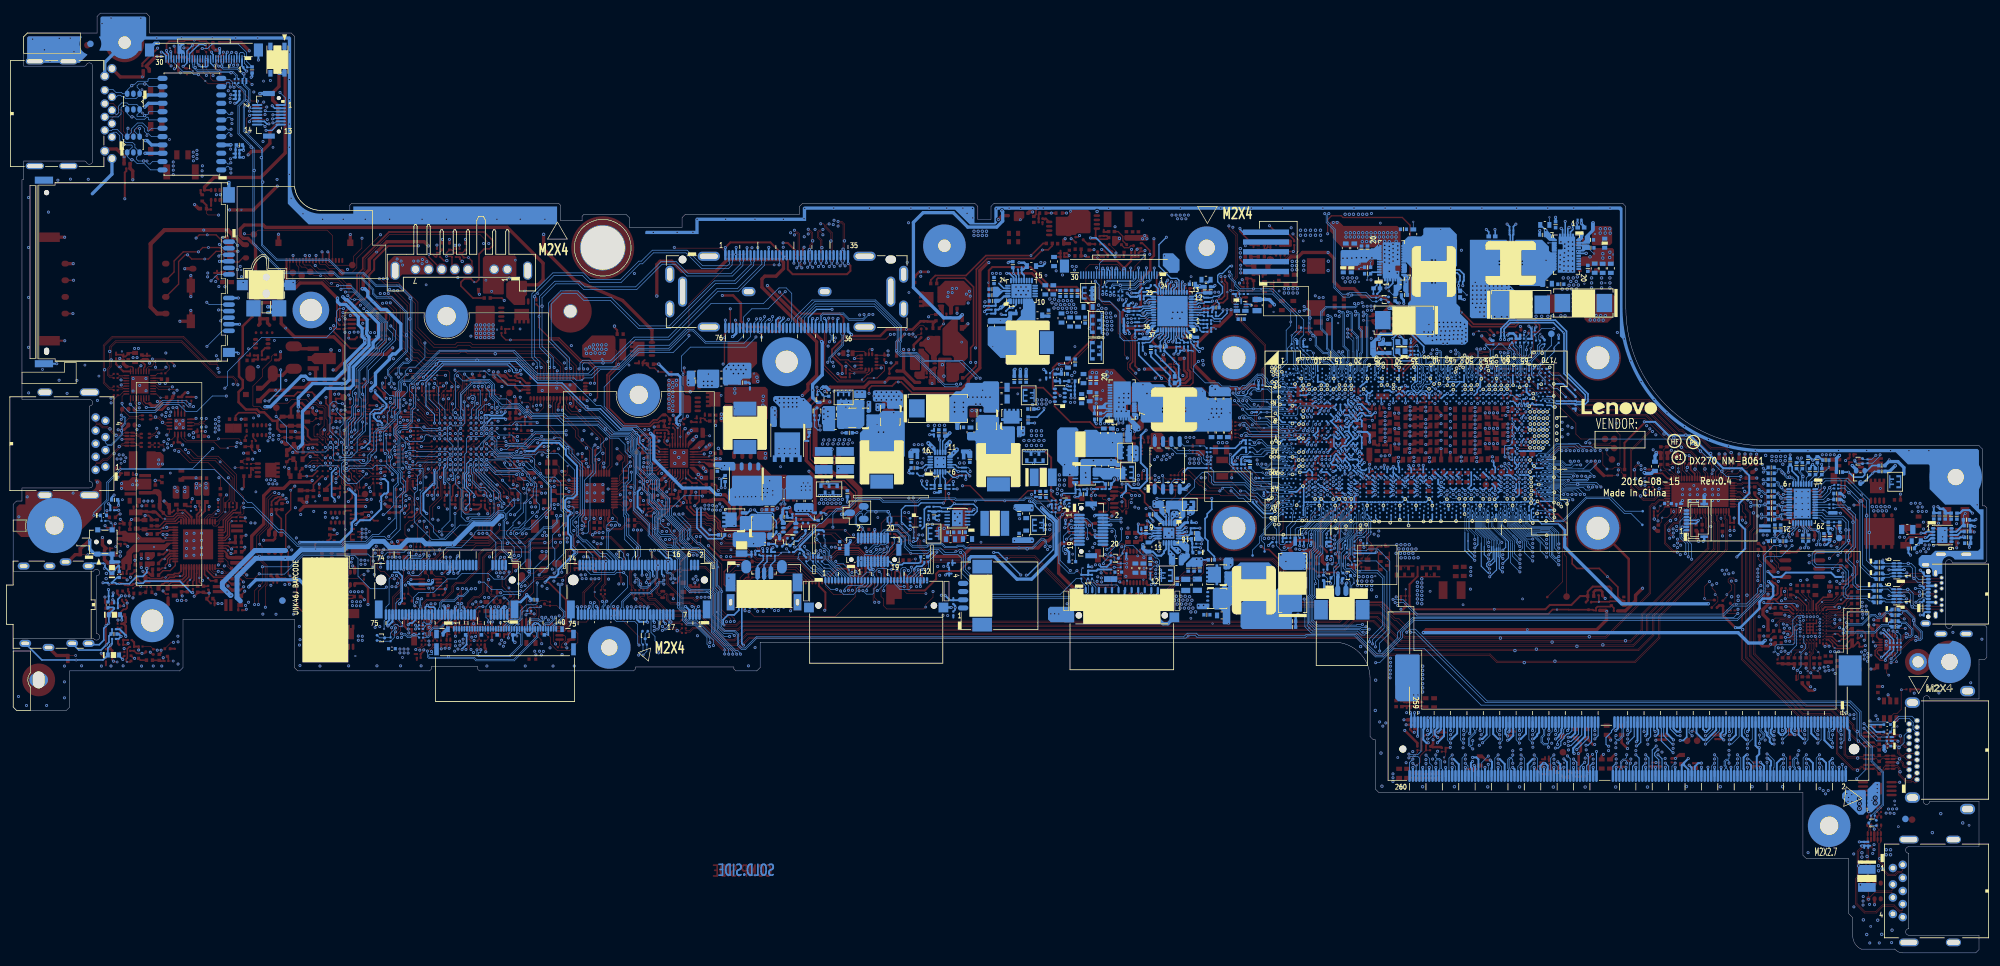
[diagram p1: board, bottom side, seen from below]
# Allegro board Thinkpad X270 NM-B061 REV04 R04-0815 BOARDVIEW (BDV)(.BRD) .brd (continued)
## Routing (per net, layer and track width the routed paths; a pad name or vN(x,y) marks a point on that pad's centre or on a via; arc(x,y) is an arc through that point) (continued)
GND_81208: length 22.4
  TOP w0.203: PC418.2 121.83,98.28 ; PC418.2 121.36,97.89 121.35,97.88 ; PC418.2 121.36,98.7 PC425.2
  TOP w0.254: PR449.2 124.55,99.92 124.28,99.66 ; PR448.2 123.91,99.59 ; PR446.2 122.74,99.54 ; PR447.1 123.33,99.57
  TOP w0.305: PR445.1 PR444.1 121.23,101.43 ; PR445.1 121.57,100.52 ; PR445.1 121.22,100.85 ; PC428.1 122.68,96.02 PR441.1 ; PC428.1 123.28,96.01 PC432.1 ; PC428.1 123.27,96.37 ; 121.89,96.28 PC417.1 ; PC417.1 122.54,96.61 122.54,96.61 ; PC417.1 122.06,95.86 PR412.2 121.94,95.76 122.21,96.02 PR441.1 ; PC417.1 122.07,96.61 PR425.1 ; 124.88,97.57 PR419.1 ; PR419.1 PR420.1 ; PR419.1 124.77,97.73 ; PR419.1 PC412.1 124.88,98.31 ; PC431.1 124.47,96 PR442.1 ; PC431.1 125.1,95.99 PR443.1 ; PC431.1 125.22,96.13 PC411.1 ; 123.17,99.71 PR447.1 ; PR448.2 124.23,99.72 PR449.2 PC408.2 ; 122.41,100.06 PR446.2 ; PC432.1 123.89,96 PR442.1 ; PC432.1 123.88,96.35 ; PR420.1 PC411.1 ; PR420.1 124.88,97.15 ; PR425.1 122.53,97.21 ; PR425.1 122.07,97.54 ; PC411.1 124.83,96.58 ; PR441.1 122.68,96.37 ; PC409.1 PR418.1 124.43,99.48 ; PC409.1 124.37,98.89 ; PC409.1 124.77,98.56 ; PR442.1 124.46,96.35 ; PC418.2 121.7,98.6
  vias: v1(120.02,101.85) v2(122.72,97.75) v2(123.04,96.82) v2(123.4,97.75) v2(124.11,97.75) v2(124.24,96.83) v4(121.62,99.92)
GNDA: length 36.7
  TOP w0.203: v1(277.07,59.12) 277.07,59.93 276.86,60.14 UA1.30
  TOP w0.254: UA1.20 272.15,58.14 272.13,58.11 272.13,56.89 v1(272.07,56.83) ; R10082.2 284.84,66.97 v1(284.63,66.97) ; v1(271.08,54.9) 271.08,54.39 C2571.1 271.41,53.95 C2572.1 ; v1(277.53,64.94) UA1.42 ; v1(285.75,53.89) 285.88,53.76 Q50.3 ; CA37.2 287.02,45.03 287.51,45.53 v1(287.51,45.73) ; C9135.2 283.14,65.47 C73.1 283.12,65.49 283.12,65.94 v1(282.91,66.14) ; C36.2 285.18,67.96 284.87,68.26 v1(284.87,68.31) ; RA37.2 277.67,54.76 278.09,55.18 v1(278.09,55.23) ; RA36.1 283.88,57.23 v1(283.57,56.91) ; v1(285.38,65.49) 285.54,65.33 R537.1 ; C542.2 C541.2
  TOP w0.305: C9146.2 271.09,55.33 271.09,54.92 v1(271.08,54.9) 271.79,54.9 C9140.2 C540.2 272.81,54.95 v1(273.34,54.42) ; v1(286.95,54.3) 286.95,53.43 286.75,53.24 CA47.1 ; v1(282.38,59.92) 282.33,59.87 C1416.1 ; C541.2 275.27,54.57 v1(275.17,54.47) ; C30.1 281.99,68.44 ; v1(282.91,66.14) C9137.2 282,66.04 C9138.2 280.91,66.66 v1(280.83,66.74) 280.27,66.74 279.87,66.33 R484.2 C545.2 ; RA35.1 283.85,62.42 v1(283.47,62.04)
  TOP w0.381: C544.2 C543.2 279.94,57.64 280.32,58.03 280.96,58.03 v1(281.16,58.23) ; C9134.2 282.34,59.96 v1(282.38,59.92) ; v1(281.39,58.79) 281.47,58.86 C559.2 ; C561.2 v1(281.4,60.18)
  TOP w0.508: C9139.2 280.5,63.92 v1(280.53,63.89)
  BOTTOM w0.254: R742.1 286.51,56.48 v1(287.25,56.48) ; CA52.2 v1(284.84,67.55)
  BOTTOM w0.305: v1(285.7,54.93) 285.7,54.51 R743.1 ; v1(285.75,53.89) 285.54,53.67 285.54,53.38 C2575.2 ; CA46.2 284.87,68.99 v1(284.87,68.31)
  vias: v1(279.74,68.95) v1(280.4,68.95) v1(281.01,68.95) v1(281.31,68.21)
VCC0R6B: length 8
  TOP w0.254: 87.66,27.47 87.47,27.29 CD15.2
  TOP w0.305: CD49.2 83.8,27.63 ; CD49.2 83.45,27.29 ; CD49.2 CD48.2 ; CD36.1 86.72,27.64 ; CD36.1 CD37.2 ; CD36.1 CD15.2 87.31,27.64 ; CD48.2 84.39,27.63 ; CD48.2 CD47.2 ; CD46.2 84.98,27.29 CD47.2 ; CD46.2 85.56,27.64 ; CD46.2 CD37.2 ; CD47.2 84.97,27.63 ; CD37.2 86.14,27.64
  BOTTOM w0.305: J21.258 v1(87.53,28.3)
  vias: v1(91.65,35.09) v1(92.11,34.61) v1(92.59,35.24) v2(121.04,67.47) v2(121.47,66.94) v2(121.73,67.53) v3(89.82,29.81)
VCC0R6BP:
  vias: v4(124.75,66.59)
VCC0R9GBE: length 13.2
  TOP w0.254: UL1.46 213.66,66.33 v1(213.61,66.28) ; CL9.2 213.94,65.68 214.16,65.9 214.16,66.41 214.06,66.5 UL1.47 ; v1(211.4,66.3) 211.4,66.43 211.26,66.57 UL1.40 ; UL1.8 215.86,70.79 216.05,70.98 216.51,70.98 v1(216.61,70.88) ; UL1.11 216.04,71.99 v1(216.2,72.15) ; v1(210.86,74.13) UL1.22 ; v1(212.38,66.28) 212.4,66.28 212.46,66.34 UL1.43 ; v1(213.26,74.18) UL1.16
  TOP w0.305: CL9.2 213.67,66.03 ; UL1.37 210.06,66.54 210.25,66.36 CL7.2 210,65.86 v1(209.56,66.31)
  IN4 w0.381: v1(216.2,72.15) 216.2,71.28 v1(216.61,70.88)
  vias: v1(215.15,65.72) v3(214.89,65.11)
VCC0R9GBE_L: length 0.9
  TOP w0.254: UL1.7 216.17,70.39 v1(216.2,70.42)
  vias: v1(221.14,66.61) v1(221.78,67.2) v3(221.01,67.27)
VCC1R0_SUS: length 174.7
  TOP w0.254: v1(92.67,93.66) 92.67,92.44 90.69,90.46 90.69,89.45 90.08,88.84 89.39,88.84 87.94,90.28 87.94,92.87 87.36,93.46 87.36,93.87 88.53,95.03 88.53,97.32 86.98,98.87 81.19,98.87 v4(80.04,97.73) 78.27,95.95 72.05,95.95 71.49,96.51 68.92,96.51 68.2,95.79 68.2,95 68.46,94.74 RC73.2 ; RC57.1 95.35,82.29 95.64,82.58 v1(95.64,83.24) ; CC52.2 95.42,75.97 v1(95.67,75.73) ; J8.16 176.58,57.27 175.21,58.64 173.86,58.64 173.64,58.41 173.64,57.88 173.25,57.49 171.36,57.49 170.96,57.89 CC68.2
  TOP w0.305: 103.41,94.37 CC63.2 ; CC63.2 103.86,94.72 ; CC63.2 102.97,94.72 ; 92.51,97.2 Q35.A1 ; RC99.2 93.46,79.02 93.89,78.59 93.89,78.59 94.03,78.45 94.03,78.45 94.1,78.38 v1(94.1,77.94) ; 104.91,94.42 CC51.2 ; CC51.2 104.44,94.77 ; CC51.2 105.43,94.77 ; Q34.A1 124.69,89.81 125.4,89.1 C292.1 ; CC68.2 RC116.1 170.96,58.89 170.61,59.24 168.79,59.24 168.11,58.56 168.11,57.42 167.4,56.7 165.01,56.7 164.58,56.27 164.58,55.54 164.35,55.31 161.93,55.31 160.21,57.03 160.21,57.85 159.78,58.28 156.63,58.28 v1(155.18,59.73) ; CC50.2 97.65,83.06
  TOP w0.508: v1(91.14,98.36) 91.35,98.36 92.51,97.2 ; v1(94.12,74.56) 94.12,75.35 RC98.1 ; v1(128.45,89.1) C292.1 ; C296.1 92.39,94.58 92.67,94.3 v1(92.67,93.66)
  IN2 w0.081: 113.29,77.44 114.33,77.44 ; 115.39,77.44 117.73,77.44
  IN3 w0.305: v1(107.78,83.68) 107.78,83.04 v1(108.5,82.33)
  IN3 w0.508: v1(144.13,67.91) 144.13,68.82 143.29,69.66 143.29,73.34 142.43,74.21 142.43,80.56 140.52,82.46 138.77,82.46 135.84,85.39 134.06,85.39 131.5,87.95 131.5,88.41 130.28,89.63 128.98,89.63 v1(128.45,89.1)
  BOTTOM w0.203: U1.A14 99.54,89.84 v1(100.42,90.72) ; v1(95.08,73.09) 95.38,73.27 95.46,73.27 95.59,73.4 95.69,73.46 95.78,73.51 U1.AK20 ; v1(102.22,90.72) 102.04,90.54 102.04,88.82 U1.A10
  BOTTOM w0.254: v1(97.59,79.08) 97.27,78.75 U1.Y18 97.68,78.24 97.68,78.06 U1.AB17 ; 96.62,77.77 96.94,77.44 v1(96.94,77.35) ; 96.62,77.77 96.29,77.44 v1(96.29,77.35) 95.97,77.67 U1.AB20 ; 96.62,77.77 U1.AB19 ; U1.AF18 v1(96.94,75.72) U1.AF19 ; v1(97.59,80.75) U1.P18 ; v1(97.57,83.31) 97.57,83.37 97.82,83.69 U1.K17 ; v1(107.78,83.68) 107.73,83.62 U1.L1 ; U1.T1 107.42,80.97 107.91,81.46 107.91,81.75 108.49,82.33 108.49,82.33 v1(108.5,82.33) ; v1(95.64,83.24) 95.34,82.85 U1.L21
  BOTTOM w0.305: v1(94.1,77.94) 94.1,79.09 94.5,79.5 U1.V21 95.36,79.54 95.92,79.54 U1.V20
  BOTTOM w0.508: v1(155.18,59.73) 155.18,60.16 154.87,60.46 151.32,60.46 147.89,57.04 145.67,57.04 141.91,60.79 141.91,65.87 142.68,66.64 142.86,66.64 v1(144.13,67.91) ; RC96.2 93.6,93.17 93.13,93.64 92.69,93.64 v1(92.67,93.66) 92.69,93.68 92.69,94.1 92.38,94.4 90.76,94.4 89.84,95.32 89.84,98.01 90.19,98.36 v1(91.14,98.36)
  vias: v1(103.16,93.61) v2(119.49,89.75) v2(119.57,90.39) v2(133.44,95.72) v2(133.44,95.08) v2(133.45,96.36) v2(133.63,97.63) v2(133.58,96.99) v2(134.12,96.35) v2(134.12,95.72) v2(134.12,95.08) v2(134.12,94.45) v2(134.22,96.99) v2(134.31,98.31) v2(134.27,97.63) v2(134.76,96.43) v2(134.76,95.8) v2(134.76,95.16) v2(134.76,94.53) v2(134.76,93.89) v2(134.93,97.71) v2(134.86,97.07) v2(134.96,98.37) v2(135.43,98.85) v2(135.42,93.92) v2(135.51,98.04)
VCC1R2A: length 51.5
  TOP w0.305: C709.1 62,54.45 63.35,53.1 66.63,53.1 67.29,52.44 75.1,52.44 v3(75.11,52.44) 75.11,52.44 87.41,52.44 88.03,53.06 RC10.2 88.03,56.24 86.8,57.47 86.8,58.91 ; C709.1 60.86,53.8 QC1.2 ; C709.1 60.86,55.14 60.1,55.9 57.56,55.9 57.26,55.6 U36.5 ; 91.22,62.01 CC32.2 91.72,62.34
  BOTTOM w0.178: U1.BB23 94.22,66.62 94.22,66.36 93.71,65.85 v1(93.41,65.85) ; U1.BB51 78.45,65.93 v1(78.46,65.92) ; U1.BB47 80.9,65.92 v1(80.94,65.88)
  BOTTOM w0.203: U1.AL23 94.17,73.99 v1(94.17,73.99)
  BOTTOM w0.254: v1(89.51,66.1) U1.BB32 ; U1.AU42 83.19,69.92 v1(83.19,69.96) ; v1(86.85,69.91) 86.98,69.83 U1.AU35 ; v1(84.13,72.5) 84.21,72.5 U1.AM40 ; U1.BB41 84.56,66.15 v1(84.85,65.87) ; v1(90.51,69.91) 90.79,69.73 U1.AU28 ; U1.AU23 v1(93.25,69.91)
  vias: v2(86.72,60.31) v2(87.06,61.63) v2(87.39,60.29) v2(87.51,60.97) v2(87.69,61.63) v2(88.05,60.29) v2(88.07,62.29) v2(88.15,60.97) v2(88.33,61.63) v2(88.71,62.29) v2(88.68,60.31) v2(88.78,60.97) v2(88.96,61.63) v2(89.34,62.29) v2(89.32,60.29) v2(89.42,60.97) v2(89.65,61.66) v2(89.98,62.29) v2(90.08,60.97)
VCC1R2A_DIMN: length 77.3
  TOP w0.305: v1(78.17,28.61) 78.24,28.54 CD43.2 ; 51.44,28.46 CD33.2 ; CD33.2 50.66,28.46 v1(50.53,28.33) 50.39,28.46 CD32.1 ; CD33.2 51.04,28.12 ; C310.1 C311.2 ; C310.1 88.58,40.44 ; C310.1 88.96,40.09 ; C311.2 87.99,40.44 ; C311.2 87.54,40.09 ; CD17.2 CD20.2 ; CD17.2 48.96,33.46 ; CD17.2 48.59,33.12 ; CD20.2 49.59,33.46 ; CD20.2 49.99,33.12 ; CD41.2 36.03,28.49 ; CD41.2 35.62,28.14 ; CD41.2 CD22.2 ; 35.04,28.14 CD22.2 ; CD22.2 34.68,28.49 v1(34.53,28.33) ; CD40.2 41.89,33.21 ; CD40.2 CD18.2 ; CD40.2 41.39,33.55 ; CD32.1 49.62,28.46 ; CD32.1 49.95,28.12 ; CD18.2 40.8,33.55 ; CD18.2 v1(40.07,33.21) ; 30.16,34.23 CD16.2 30.6,33.88 ; v1(55.03,28.33) 55.1,28.4 RD11.1 ; v1(45.4,28.64) 45.12,28.36 CD39.2 ; CD38.2 29.25,33.9 v1(29.28,33.92) ; CD38.2 28.33,33.9 ; CD38.2 28.69,34.24 ; CD45.2 67.68,28.46 v1(67.53,28.3) ; CD45.2 68.08,28.12 ; CD45.2 68.44,28.46 ; 78.24,27.72 CD43.2 ; CD43.2 77.83,28.05 ; 44.79,28.02 CD39.2 ; CD39.2 CD23.2 44.21,28.02 ; CD21.2 71.93,33.76 ; CD21.2 72.37,34.1 ; CD21.2 72.87,33.76 v1(72.91,33.72) ; 84.31,33.99 CD44.2 83.74,33.64 v1(83.7,33.67) 83.67,33.64 CD19.2 ; 55.81,28.05 RD11.1 ; RD11.1 56.45,28.4 v1(56.53,28.33) ; 67.37,29.88 RD7.1 67.85,29.55 ; CD19.2 82.51,33.64 ; CD19.2 82.99,33.99 ; CD42.2 30.01,29.98
  BOTTOM w0.127: v1(63.84,32.91) 63.83,32.91
  BOTTOM w0.254: v1(23.56,29.65) 24.03,29.18 J21.12 ; J21.117 50.28,34.17 50.09,33.99 50.09,33.44 50.4,33.14 v1(50.59,33.14) ; v1(40.07,33.21) 39.78,33.5 J21.75 ; J21.163 63.78,34.1 v1(63.95,33.92)
  BOTTOM w0.305: J21.112 v1(49.03,28.33) ; J21.136 v1(55.03,28.33) ; J21.124 v1(52.03,28.33) ; J21.159 62.78,33.53 63.4,32.91 63.83,32.91 ; J21.142 v1(56.53,28.33) ; v1(47.79,32.5) 48.78,33.49 J21.111 ; J21.129 53.28,32.39 v1(53.45,32.22) ; J21.148 v1(60.03,28.3) ; J21.135 54.77,35.2 v1(54.77,33.92) ; J21.147 v1(59.78,33.92) ; v1(83.7,33.67) 83.28,34.1 J21.241 ; J21.178 v1(67.53,28.3) ; J21.220 78.03,28.47 v1(78.17,28.61) ; v1(45.4,28.64) 45.03,28.26 J21.96 ; J21.118 v1(50.53,28.33) ; J21.160 v1(63.03,28.3) ; J21.123 51.78,33.39 v1(52.03,33.14) ; J21.153 61.28,33.03 63.08,31.23 63.08,30.57 v1(62.93,30.42) ; J21.33 v1(29.28,33.92) ; J21.154 v1(61.53,28.3) ; J21.130 v1(53.53,28.33) ; v1(72.91,33.72) 72.78,33.85 J21.199 ; v1(56.59,33.92) 56.28,34.23 J21.141 ; J21.54 v1(34.53,28.33)
  vias: v1(247.71,48.32) v1(247.71,47.69) v1(248.32,48.35) v1(248.32,47.71) v2(86.04,43.75) v2(86.04,43.12) v2(86.04,42.48) v2(86.04,41.85) v2(86.04,41.08) v2(86.04,40.45) v2(86.04,39.81) v2(86.17,57.09) v2(86.17,56.45) v2(86.17,55.82) v2(86.17,55.18) v2(86.17,54.55) v2(86.17,53.91) v2(86.17,53.28) v2(86.83,56.55) v2(86.83,55.92) v2(86.83,55.28) v2(86.83,54.65) v2(86.83,54.01) v2(86.83,53.38) v3(84.9,55.18)
VCC1R8_SUS: length 181.3
  TOP w0.254: v1(235.06,55.54) 235.06,54.99 R601.2 ; v1(235.06,55.54) 235.08,55.52 U191.8 ; v1(235.06,55.54) 234.82,55.77 R600.2 ; v1(98.91,76.56) 99.35,76.56 100.08,75.84 RC152.2
  TOP w0.305: 121.09,76.29 CC62.2 ; C2573.2 266.62,52.62
  TOP w0.381: v1(246.84,53.15) 246.84,55.73 247.47,56.37 R322.1 248.69,56.38 U163.1
  TOP w0.508: Q60.1 261.96,64.45 261.55,64.86 v1(261.55,66.9) C9464.1
  TOP w0.762: v1(191.7,63.66) 185.07,63.66 184.46,63.05 183.52,63.05 181.33,65.24 177.45,65.24 176.77,65.93 173.97,65.93 171.83,68.07 171.83,70.68 174.15,73 175.79,73 178.67,75.88 178.67,82.99 177.58,84.09 v1(176.44,84.09)
  IN2 w0.762: v1(226.42,66.66) 226.73,66.66 227.53,65.85 227.53,65.02 225.44,62.92 222.67,62.92 221.78,62.04 218.68,62.04 218.07,61.43 216.14,61.43 215.55,62.01 212.51,62.01 212.15,61.66 210.58,61.66 209.91,62.32 202.02,62.32 201.69,61.99 199.73,61.99 199.17,62.55
  IN3 w0.381: v1(259.46,60.22) 259.46,59.87 251.5,51.91 247.55,51.91 246.84,52.62 v1(246.84,53.15) 245.29,51.6 241.5,51.6 240.92,52.19 239.32,52.19 238.56,52.95 238.56,53.08 236.79,54.85 235.75,54.85 v1(235.06,55.54)
  IN3 w0.508: v1(261.55,66.9) 260,65.35 260,61.71 259.46,61.18 v1(259.46,60.22)
  BOTTOM w0.203: U1.AA1 107.37,78.32 107.56,78.13
  BOTTOM w0.254: U1.AF16 v1(98.91,76.56)
  BOTTOM w0.381: 107.56,78.13 v1(107.91,77.79) 108.04,77.79 v1(108.39,78.14)
  BOTTOM w0.762: v1(226.42,66.66) 226.65,66.66 227.84,65.47 230.69,65.47 233.74,62.42 238.03,62.42 238.59,62.98 240.83,62.98 241.95,61.86 243.49,61.86 244.43,62.8 246.04,62.8 246.85,61.99 250.1,61.99 250.58,61.51 257.06,61.51 258.35,60.22 v1(259.46,60.22) 263.96,60.22 266.81,57.37 266.81,54.22 266.3,53.71
  vias: v1(265.06,53.5) v1(265.52,53.02) v2(120.18,75.37) v2(120.18,74.74) v2(120.86,75.37) v2(120.86,74.74) v2(121.52,75.37) v2(121.55,74.74) v2(129.75,76.69) v2(129.75,76.01) v2(130.06,75.37) v2(130.41,76.01) v3(122.21,75.86)
VCC1R8_SUSA: length 12.4
  TOP w0.102: v3(274.58,53.78) v2(275.27,53.78)
  TOP w0.254: v1(269.71,53.3) 269.76,53.35 C2572.2 270.23,53.8 C2571.2
  TOP w0.305: C556.1 261.28,57.23 R10324.1 ; R10324.1 261.82,56.79 ; R10324.1 261.28,56.46 ; 270.23,53.02 C2572.2
  IN4 w0.508: v1(261.65,56.1) 263.04,54.7 265.25,54.7 266.73,53.23 268.66,53.23
  vias: v1(269.12,53.3) v2(275.9,53.78)
VCC1V2B: length 1
  TOP w0.305: C308.1 239.74,45.61 ; 250.44,45.22 R372.1 ; 239.39,44.69 C309.2
  vias: v4(248.77,45.31)
VCC2R5A: length 7.2
  TOP w0.305: 86.5,37.31 CD11.2 ; CD11.2 86.12,37.66 ; CD11.2 87.15,37.66 CD12.2 ; CD12.2 CD35.2 ; CD12.2 87.16,37.32 ; CD35.2 87.82,37.32 ; CD35.2 CD34.1 ; 88.45,37.32 CD34.1 ; CD34.1 88.97,37.67
  BOTTOM w0.254: J21.259 87.78,36.55 v1(87.89,36.66) ; J21.257 v1(87.28,36.66)
  vias: v1(86.65,36.69) v1(88.48,36.66) v1(92.72,64.38) v1(92.8,63.64) v1(93.43,63.89) v2(142.88,65.32) v2(142.88,64.6) v2(143.54,65.32) v2(143.57,64.6) v3(85.15,35.83)
VCC3_LDO_TBTA: length 62.6
  TOP w0.254: v3(21.01,64.56) R489.1 ; R711.2 20.68,62.27 20.68,60.57 R716.1 ; 16.57,49.92 C900.1 16.78,49.62 16.8,48.25 16.35,47.8 U193.10 ; R712.2 34.77,62.48 34.16,61.87 33.95,61.87 ; U5.G1 26.48,53.74
  TOP w0.305: R711.2 R489.1 ; 16.57,49.92 16.7,50.06 v1(17.22,50.06)
  TOP w0.508: v1(33.38,58.19) R715.1 32.49,58.62 33.92,60.05 R714.1 R713.1 33.95,61.87
  IN4 w0.254: v1(21.97,57.37) 21.74,57.37 17.73,53.36 17.73,50.56 v1(17.22,50.06)
  IN4 w0.305: v1(1.83,65.07) 2.06,65.07 2.16,64.96 2.19,64.96 4.93,62.22 7.34,62.22 9.42,60.14 19.79,60.14 v1(21.97,57.95)
  BOTTOM w0.305: v1(21.97,57.37) 23.09,57.37 23.75,58.03 30.66,58.03 31.32,57.37 32.56,57.37 v1(33.38,58.19) ; v1(1.83,65.07) 2.06,65.07 2.18,65.19 2.55,65.19 ; 2.55,65.19 2.55,64.31 PR87.1 ; 2.55,65.19 PR90.1
VCC3_MC: length 2.7
  TOP w0.203: v1(281.46,89.6) 281.85,89.21 U15.12
  TOP w0.305: CW1.2 270.28,103.76 270.29,103.77 ; CW1.2 CW2.2 ; CW1.2 269.86,104.1
  vias: v1(266.33,104.76) v1(266.73,104.28) v1(271.27,103.75) v1(271.3,103.17) v1(277.67,91.54) v4(266.17,104.21)
VCC3_SUS: length 458.9
  TOP w0.254: v1(97.39,59.24) 97.14,58.99 TP1.1 96,58.99 95.5,59.49 RC36.1 95.93,60.03 RC38.2 ; R9134.2 130.79,70.19 v1(130.41,69.81) ; v1(251.49,99.91) 251.56,99.83 251.56,97.05 251.75,96.86 251.75,96.42 R251.2 ; v1(135.29,59.22) 134.65,58.58 134.65,58.26 134.31,57.92 R238.1 ; v1(135.67,56.7) 135.67,56.5 135.26,56.09 R397.1 ; v1(123.55,71.8) 123.28,72.07 RC141.2
  TOP w0.305: 105.97,73.94 CC60.2 105.5,73.65 ; RC34.2 105.22,70.45 ; RC34.2 104.77,70.81 ; RC34.2 104.77,70.17 ; RC168.2 32.12,54.62 31.9,54.83 31.9,56.02 32.3,56.42 RC167.2 32.75,56.68 v1(33.3,56.68) ; 115.19,78.35 RC25.2 ; RC25.2 RC26.2 ; RC25.2 115.58,78.68 ; R252.2 247.13,93.6 v1(247.33,93.41) ; CC59.2 102.92,73.25 ; CC59.2 CC53.2 ; CC59.2 CC35.2 102.28,73.25 ; RC117.2 55.25,77.84 52.23,80.86 v1(52.23,81.04) ; CC53.2 103.54,73.25 ; CC53.2 103.91,72.95 ; RC26.2 RC27.2 ; RC26.2 115.53,79.23 ; RC27.2 RC28.2 ; RC27.2 115.53,79.79 ; RC164.2 189.44,59.96 192.74,59.96 v1(194.93,62.14) ; 131.23,67.02 R9135.2 ; 98.99,75.2 CC61.2 98.56,75.48 98.54,75.45 CC34.2 97.75,75.45 ; 99.81,73.91 CC33.2 99.5,74.21 ; RC28.2 RC24.2 ; RC28.2 115.53,80.4 ; RC24.2 115.19,81.32 ; RC24.2 115.6,80.99 ; RC153.2 100.72,73.32 ; 102.05,74.02 CC58.2 102.42,73.72 ; J41.1 259.26,104.46
  TOP w0.381: Q170.2 40.81,53.03 40.34,53.03 Q171.2 40.22,52.91 R485.2 40.22,51.49 v1(38.36,49.62)
  TOP w0.508: 257.2,67.53 256.57,68.16 247.25,68.16 v1(247.2,68.11) ; v1(77.02,94.14) 77.02,94.09 75.85,92.93 72.49,92.93 71.76,93.65 RC72.2 ; 259.26,104.46 259.26,102.38 258.42,101.54 257.87,101.54 257.18,102.22 253.86,102.22 251.55,99.91 v1(251.49,99.91) ; U163.6 248.87,58.73 v1(249.18,59.04) ; v1(115.24,98.14) 115.24,97.45 117.03,95.67 117.76,95.67 120.84,92.6 120.84,89.7 118.3,87.16 117.89,87.16 116.82,86.09 113.95,86.09 113.9,86.14 112.94,86.14 112.43,86.65 111.62,86.65
  IN1 w0.305: v1(38.13,60.42) 35,60.42 34.01,59.43 34.01,57.4 v1(33.3,56.68) ; v1(77.02,94.14) 77.02,94.42 75.7,95.74 72.09,95.74 69.73,93.38 67.27,93.38 64.12,90.23 64.12,88.96 59.22,84.06 55.58,84.06 52.56,81.04 v1(52.23,81.04)
  IN1 w0.508: v1(249.18,59.04) 248.85,59.04 248.57,59.33 248.57,60.7 250.09,62.22 251.12,62.22 256.83,67.94 v1(257.91,67.94) 257.91,69.02 259.22,70.32 259.22,73.24 260.13,74.15 260.13,75.17 263.15,78.19 263.15,81.02 262.54,81.62 v1(262.54,83.35)
  IN2 w0.508: v1(115.24,98.14) 110.25,98.14 105.72,93.61 v1(105.37,93.61)
  IN2 w0.635: 235.64,64.81 235.29,64.46 232.41,64.46 232.06,64.81 228.46,64.81 225.31,61.66 223.05,61.66 221.7,60.31 215.05,60.31 214.18,61.18 212.84,61.18 211.74,60.08 198.97,60.08 197.49,61.56 195.84,61.56 195.26,62.14 v1(194.93,62.14) 194.8,62.27 192.13,62.27 189.9,64.5 182.79,64.5 182.51,64.23 176.04,64.23 170.6,58.79 170.6,57.37 169.94,56.7 142.91,56.7 142.45,57.16 138.03,57.16 137.58,56.7 v1(135.67,56.7)
  IN3 w0.508: 94.29,71.54 94.19,71.44 94.19,70.45 93.92,70.18 93.92,66.83 94.04,66.71 94.04,61.51 94.88,60.67 95.97,60.67 v1(97.39,59.24) ; v1(105.37,93.61) 105.34,93.59 v1(104.07,93.59) 103.26,92.77 100.26,92.77 99.83,93.2 96.38,93.2 94.9,94.68 93.41,94.68 92.9,95.19 87.28,95.19 84.79,92.7 83.61,92.7 83.29,92.37 82.02,92.37 81.76,92.63 80.57,92.63 80.32,92.37 79.33,92.37 77.56,94.14 v1(77.02,94.14)
  BOTTOM w0.152: R2745.2 114.51,86.05 114.51,85.28 114.27,85.03 113.31,85.03 113.23,85.11 113.03,85.11 112.71,85.43 112.71,85.71 112.17,86.25 111.51,86.25 111.3,86.04 RC47.2
  BOTTOM w0.203: U1.AD15 99.57,77.33 99.57,79.01
  BOTTOM w0.254: U1.AK17 97.94,73.61 97.94,73.17 v1(97.86,73.09) ; v1(113.83,77.84) 113.83,77.81 114.63,77.01 RC140.2 ; U1.AJ19 v1(96.29,74.05) ; U1.AK15 99.32,73.63 99.45,73.47 v1(99.7,73.44) ; v1(96.32,79.04) 96.32,79.2 U1.V19 ; v1(135.29,59.22) 135.29,59.12 135.09,58.91 134.17,58.91 133.58,59.51 Q41.3 ; v1(104.07,93.59) 104.25,93.41 104.25,92.85 104.2,92.8 RC44.2 RC45.2 ; v1(98.21,74.08) 98.57,74.43 U1.AJ16 ; U1.Y16 98.8,78.42 98.98,78.42 U1.Y15 99.57,79.01 v1(99.57,79.03) ; U1.T16 98.28,79.95 v1(98.26,79.91) ; U1.AJ21 95.28,74.47 v1(94.93,74.82) ; v1(98.91,74.89) 98.95,74.94 98.98,74.99 99.16,75.23 U1.AG15
  BOTTOM w0.305: v1(113.83,77.84) 113.8,77.84 113.39,78.24 RC32.2 RC33.2 ; v1(111.06,87.34) RC23.2 RC47.2 ; v1(38.13,60.42) 36.86,61.69 36.86,64.61 37.8,65.55 37.8,68.57 36.23,70.13 36.23,72.83 37.36,73.96 40.21,73.96 45.21,78.96 48.52,78.96 50.59,81.04 v1(52.23,81.04) ; 114.55,100.21 RC134.2 115,100.54
  BOTTOM w0.381: v1(33.3,56.68) 32.59,55.97 32.59,54.5 33.02,54.07 34.19,54.07 34.67,53.59 34.67,52.57 37.62,49.62 v1(38.36,49.62) ; v1(105.37,93.61) 105.17,93.41 RC135.2
  BOTTOM w0.508: v1(262.54,83.35) 261.7,83.35 257.06,88 256.37,88 255.91,87.54 251.8,87.54 250.87,88.47 250.36,88.98 250.36,89.99 247.33,93.03 v1(247.33,93.41) 247.33,93.67 247.74,94.08 247.74,95.29 248.32,95.87 248.32,97.04 250.22,98.95 251.07,98.95 251.49,99.36 v1(251.49,99.91)
  BOTTOM w0.762: 259.41,61.41 264.09,61.41 269.05,56.45 269.05,55.79 v1(268.32,55.07) 267.83,54.57 v1(267.73,54.57)
  vias: v1(124.16,76.09) v1(124.57,75.63) v1(125,76.03) v1(125.13,75.3) v1(125.56,75.81) v1(125.82,75.25) v1(127.75,70.85) v1(128.36,70.83) v1(130.46,68.72) v1(133.41,64.32) v1(135.92,59.22) v1(258.47,61.49) v1(258.9,61.94) v3(115.4,82.41)
VCC3B: length 383
  TOP w0.203: 280.13,83.83 280.68,83.83 281.05,84.2 U15.27 ; R112.2 v1(286.03,84.66)
  TOP w0.254: v1(131.95,69.64) 131.93,69.64 131.33,69.04 131.33,68.52 131.31,68.5 R9137.2 ; R284.2 v1(244.87,72.32) ; R368.2 199.47,57.28 199.47,56.73 199.72,56.48 v1(200.33,56.48) ; v1(239.98,58.03) 239.98,58.27 R2746.2 ; v1(52.13,71.94) 51.98,71.94 51.85,71.82 R2379.2 R2378.2 ; R409.2 219.04,50.08 R52.2 218.81,50.14 218.44,49.78 217.12,49.78 216.65,50.25 216.65,53.9 219.31,56.56 v1(219.84,56.56) ; v2(52.18,70.17) 51.93,69.91 R9129.1 ; C284.2 264.69,72.92 R296.2 Q20.3 ; 265.41,65.75 265.57,65.9 R10095.2 ; R382.2 245.55,83.55 v1(245.5,83.5) ; R375.1 224.49,70.89 v1(224.09,71.28) ; v1(252.08,95.72) 252.08,94.82 249.53,92.26 245.14,92.26 244.1,93.31 R248.2 ; R226.2 166.87,61.87 167.64,61.11 R227.2 167.64,60.91 167.95,60.59 170.81,60.59 172.01,61.78 175.47,61.78 v1(175.6,61.91) ; v1(131.26,71.54) 131.29,71.51 R9136.2 ; RL1.2 216.49,67.23 215.95,67.23 v1(215.83,67.12)
  TOP w0.305: v1(252.08,95.72) 251.56,95.2 R249.2 ; v1(34.49,68.95) 35.39,69.85 R1875.1 ; v1(215.27,61.18) 212.38,61.18 211.54,60.34 R108.2 ; R117.1 181.8,107.3 182.84,108.34 v1(183.55,108.34) ; R6.2 274.9,134.38 ; R6.2 274.44,134.04 ; R6.2 274.04,134.38 273.97,134.31 ; v1(250.66,97.7) 250.45,97.7 249.82,98.34 249.26,98.34 247.9,99.69 247.45,99.69 246.64,100.49 246.64,103.49 245.91,104.23 245.91,105.73 243.75,107.89 v1(239.18,107.89) ; 264.35,73.69 R296.2 ; v1(222.89,76.57) 223.36,77.03 R164.2 ; v1(281.81,46.22) 281.8,46.23 R1868.2 282.44,46.75 R1869.2 282.5,47.38 282.54,47.42 282.54,47.43 282.86,47.74 R951.2 ; v1(241.89,81.75) 241.84,81.8 R126.2 ; v1(278.39,46.19) 278.39,45.84 R2572.2 ; v1(273.06,84.77) 273.12,84.84 R109.2 R110.2 ; R325.1 260.81,68.67 260.28,69.21 259.49,69.21 v1(259.34,69.36) ; v1(191.55,60.46) RC111.2 ; R2747.2 250.67,59.4
  TOP w0.381: v1(209.4,52.87) 209.4,52.64 208.8,52.03 208.68,52.03 208.38,51.73 R370.2 ; v1(275.44,134.31) 275.74,134.61 F5.2 ; RD3.2 83.23,31.41 84.49,31.41 84.6,31.51 84.79,31.51 ; 84.79,31.51 84.44,31.86 v1(84.44,32.52) ; 84.79,31.51 RD1.2 ; v1(283.77,48.3) 283.77,49.88 284.11,50.22 ; v1(88.76,33.95) 86.84,32.03 RD2.2 ; 284.11,50.22 284.08,50.22 283.8,50.5 283.8,51.22 283.97,51.4 R10133.2 ; 284.11,50.22 R46.2 ; RD12.1 v1(88.55,34.81)
  TOP w0.508: R2527.1 v1(36.89,76.14) ; v1(47.53,76.44) 46.92,75.83 R2500.2 R532.2 ; F3.2 266.17,138.88 v1(264.95,137.66) ; v1(50.43,76.36) 49.77,76.36 R2523.1 R2531.1 ; v1(35.18,73.8) 35.64,73.34 R1877.1 ; v2(43.95,62.83) 44.15,63.03 44.15,64.27 R9131.1 ; v1(278.95,84.14) 278.62,84.14 C131.2 278.69,83.46 C132.2 279.09,83.48 279.78,83.48 280.13,83.83 ; v1(52.5,55.64) 53.57,54.58 53.57,53.74 55.12,52.19 RC169.2 ; v1(140.48,66.04) 140.48,66.24 140.12,66.61 139.28,66.61 138.05,65.38 138.05,64.23 138.18,64.1 F15.2 138.48,63.37 139.35,62.5 141.12,62.5 141.54,62.09 141.54,57.96 139.34,55.77 v1(138.87,55.77) ; R2561.1 v1(40.83,76.14) ; R2529.1 v1(35.11,76.11)
  IN1 w0.305: v1(128.2,79.77) 128.35,79.77 129.12,80.54 129.12,85.61 127.77,86.96 126.55,86.96 v1(125.84,87.67) ; v1(131.95,69.64) 132.67,69.64 133.92,68.39 136.36,68.39 138.06,66.69 139.63,66.69 140.28,66.04 v1(140.48,66.04) ; v1(104.17,62.06) 103.22,62.06 v1(103.13,62.16)
  IN2 w0.305: v1(222.89,76.57) 222.89,75.22 222.51,74.84 222.51,72.86 v1(224.09,71.28)
  IN2 w0.381: v1(278.39,46.19) 278.39,46.52 278.64,46.78 281.26,46.78 v1(281.81,46.22)
  IN2 w0.508: v1(250.5,87.57) 249.04,86.1 247.64,86.1 245.5,83.96 v1(245.5,83.5) 244.69,82.69 243.06,82.69 242.12,81.75 v1(241.89,81.75) ; v1(281.81,46.22) 281.81,46.88 282.81,47.87 283.34,47.87 v1(283.77,48.3) 283.77,51.48 281.14,54.11 278.37,54.11 276.72,52.46 272.88,52.46 272.35,51.93 267.83,51.93 265.03,54.73 v1(265.03,55.85)
  IN3 w0.305: v1(183.55,108.34) 183.55,108.44 184.39,109.28 190.4,109.28 191.01,108.67 200.49,108.67 207.98,101.19 214.34,101.19 222.56,109.41 237.83,109.41 239.18,108.06 v1(239.18,107.89) ; v1(93.07,54.37) 93.33,54.37 93.81,54.85 97.57,54.85 100.19,57.47 100.62,57.47 103.13,59.98 v1(103.13,62.16)
  IN4 w0.508: v1(256.65,87.36) 256.45,87.16 250.91,87.16 v1(250.5,87.57)
  BOTTOM w0.254: R376.1 127.54,57.04 126.83,56.32 v1(126.83,56.22) ; v1(104.17,62.06) 104.17,62.17 104.15,62.19 RC29.2 ; PR405.1 129.31,91.22 125.84,87.74 v1(125.84,87.67) ; v1(140.48,66.04) R394.1
  BOTTOM w0.305: v1(103.13,62.16) 103.11,62.16 103.01,62.26 RC22.2 ; v1(248.7,65.37) 248.04,66.03 246.54,66.03 244.83,67.74 244.83,69.62 244.36,70.09 244.03,70.09 243.77,70.34 243.77,71.79 244.3,72.32 244.5,72.32 244.5,72.32 v1(244.87,72.32) ; v1(222.89,76.57) 221.5,76.57 220.23,77.84 217.74,77.84 216.67,76.77 216.67,76.03 214.97,74.33 214.97,69.96 215.55,69.38 216.44,69.38 216.77,69.05 216.77,67.88 216.35,67.46 216.18,67.46 v1(215.83,67.12) 216.34,66.61 216.34,63.99 215.88,63.54 215.88,61.78 v1(215.27,61.18) 215.27,61.05 217.81,58.51 217.81,57.8 218.29,57.32 219.1,57.32 219.84,56.58 v1(219.84,56.56) ; R1867.2 284.71,49.39 283.77,48.45 v1(283.77,48.3) ; v1(131.95,69.64) 131.95,69.77 131.26,70.46 v1(131.26,71.54) 131,71.54 130.39,70.93 129.17,70.93 128.05,72.05 128.05,73.82 129.01,74.78 129.01,78.96 v1(128.2,79.77)
  BOTTOM w0.508: v1(265.03,55.85) 263.93,56.94 257.32,56.94 255.23,54.85 ; RX55.1 50.61,75.86 50.43,76.03 v1(50.43,76.36)
  vias: v1(38.69,58.01) v1(39.35,57.85) v1(39.68,58.41) v1(39.98,57.8) v1(40.36,58.39) v1(50.89,76.77) v1(176.18,61.91) v1(228.43,54.24) v1(229.07,54.24) v1(247.73,55.11) v1(248.31,55.11) v1(248.9,55.11) v1(249.48,55.11) v1(250.07,60.11) v1(250.07,59.52) v1(264.07,65.59) v1(264.7,65.62) v1(282.05,90.84) v1(282.66,90.84) v3(263.93,70.35)
VCC3B_DRV: length 26
  TOP w0.102: R299.1 265.73,74.61 D44.1 265.74,75.35 C212.2 v1(264.42,75.35)
  TOP w0.254: U21.A6 250.55,71.76 250.17,71.39 249.72,71.39 249.23,70.9 249.23,69.48 v1(249.84,68.88)
  IN4 w0.203: v1(264.42,75.35) 259.23,75.35 257.56,73.68 257.56,73.07 254.71,70.22 254.07,70.22 253.67,69.82 253.67,69.36 252.7,68.39 250.32,68.39 v1(249.84,68.88)
VCC3B_PS8349B: length 12.9
  TOP w0.254: v1(38.54,66.36) C2544.2 C2576.2 39.18,66.61 39.35,66.78 U147.34 ; v2(45.68,74.08) 45.63,74.13 45.63,74.47 C2546.2 45.4,74.61 45.17,74.38 45.17,73.75 44.55,73.13 U147.10 ; U147.1 48.69,72.39 49.48,73.18 C2543.2 C2545.2 52.12,73.18 v2(52.23,73.29)
  BOTTOM w0.508: v2(52.23,73.29) 52.1,73.16 51.16,73.16 50.78,73.55 RX55.2
  vias: v3(41.92,73.11)
VCC3FP:
  vias: v1(164.4,67.2) v1(165.01,67.2) v3(169.1,66.43)
VCC3GBE: length 26.6
  TOP w0.254: v1(213.6,75.32) 213.89,75.03 C114.2 214.23,74.98 214.23,74.44 213.66,73.88 UL1.15 ; UL1.29 v1(210.23,70.79) ; U14.1 213.91,84.47 213.62,84.47 v1(213.42,84.26) ; v1(217.98,88.83) 218.05,88.75 U14.30 ; v1(215.99,83.86) 215.99,83.55 215.78,83.35 C111.2 215.5,83.54 215.5,84.24 215.55,84.28 U14.4 ; v1(217.84,82.84) 217.84,83.31 C112.2 217.8,83.72 217.55,83.97 U14.8 ; U14.14 220.55,83.62 v1(220.51,83.58) ; U14.39 213.7,86.94 v1(212.91,86.94) ; v1(211.64,75.27) 211.73,75.36 C115.2 212.19,75.06 212.06,74.93 212.06,74.18 212.06,74.17 UL1.19 ; 224.33,88.03 C113.2
  TOP w0.305: v1(223.5,88.3) 224.11,88.3 224.33,88.08 224.33,88.03 224.02,87.72 223.48,87.72 222.7,86.94 222.4,86.94 U14.21 ; RL2.2 217.33,69.12 ; RL7.1 207.29,69.54 v1(206.79,69.05) 206.79,68.12 RL8.1 ; R91.2 v1(222.55,83.31) ; 218.97,68.43 CL14.2 218.97,67.55 ; 217.33,67.82 RL6.2
  IN1 w0.305: v1(206.79,69.05) 208.49,69.05 v1(210.23,70.79)
  vias: v1(217.87,68.41) v1(218.45,68.41) v1(218.4,67.8)
VCC3LAN: length 1
  TOP w0.305: 221.76,69.49 CL12.2 222.07,69.83 ; CL11.2 221.31,69.83
  vias: v1(221.28,68.06) v1(221.89,68.06) v1(222.09,68.72) v1(247.15,64.66) v1(247.15,64.05) v1(247.15,63.44) v1(247.74,64.66) v1(247.74,64.05) v1(247.74,63.44) v3(246.64,64.3)
VCC3LAN_DRV: length 18.4
  TOP w0.254: v1(246.28,67.25) 247.45,67.25 247.71,66.99 C211.2 247.78,67.04 D42.1 248.81,66.9 R295.1
  TOP w0.305: U21.C3 253.32,74.7 v1(253.32,74.74)
  IN3 w0.203: v1(253.32,74.74) 253.32,73.19 252.74,72.61 252.74,71.87 252.16,71.28 251.34,71.28 250.86,71.77 250.86,72.02 250.2,72.68 249.26,72.68 248.22,71.64 248.22,69.51 247.43,68.72 247.05,68.72 246.28,67.95 v1(246.28,67.25)
VCC3LCD: length 33.8
  TOP w0.305: C266.2 C5.2 130.28,106.24 130.29,106.23 C4.2 130.48,105.58 v1(131.57,104.49) 131.57,104.54 132.64,105.6 135.12,105.6 v4(135.62,106.11) 136.24,106.11 C265.1
  IN3 w0.254: v1(131.57,104.49) 131.95,104.11 131.95,103.8 132.79,102.96 134.29,102.96 135.36,101.9 136.55,101.9 136.93,101.52 136.93,96.33 137.64,95.62 137.64,92.5 141.07,89.07 v1(141.12,89.07)
  BOTTOM w0.203: J10.14 131.75,104.31 v1(131.57,104.49) 131.47,104.49 131.35,104.37 J10.13
  BOTTOM w0.381: F2.1 141.15,88.32 C3.2 v1(141.12,89.07)
VCC3M: length 297.2
  TOP w0.152: U17.1 168.13,91.2 C184.2 ; C185.2 172.69,91.78 171.21,91.78 170.98,91.55 U17.14
  TOP w0.254: R212.2 166.48,58.13 v1(166.18,58.43) 165.68,57.93 F9.2 ; R350.2 236.02,86.19 R353.2 235.52,86.34 v1(235.33,86.53) ; v1(276.86,135.35) 277.56,136.04 F4.2 ; J41.3 v1(258.26,106.43) ; v1(238.52,86.83) 238.62,86.73 R798.2 ; v1(240.47,76.24) 240.47,76.16 240.22,75.91 R151.2 ; R129.2 R125.1 232.34,69.56 232.62,69.28 232.62,67.73 232.09,67.2 231.66,67.2 v1(231.17,67.68) 231.34,67.84 R138.2 231.34,68.48 R161.2 ; PR15.1 109.28,105.63 ; PR15.1 109.01,106.12 108.82,105.93 ; PR15.1 109.55,106.12 109.66,106.01 ; C194.2 v1(254.27,69.76) ; v1(243.56,75.67) 243.56,75.67 R285.2 ; R270.2 v1(243.48,79.07) ; U5.B1 28.98,52.38 29.91,53.3 30.99,53.3 31.07,53.23 31.64,53.23 32.41,54 ; R153.2 240.52,79.49 v1(240.37,79.64) 240.34,79.62 R404.2 ; U5.H1 25.98,52.47 26.04,52.52 26.04,53.18 24.95,54.27 24.18,54.27 C796.1 23.96,54.53 v1(23.96,55.18) ; R440.2 240.95,82.49 v1(241.18,82.71) ; R208.2 227.61,69.68 v1(227.31,69.38) 227.06,69.38 R210.2 ; 230.64,87.74 231.21,87.74 R10251.2 231.41,87.74 231.76,87.38 R124.1 ; v1(256.42,106.44) 256.26,106.28 J41.7 ; v1(242.76,76.64) 242.62,76.78 R131.2 ; v1(239.35,67.7) 239.35,67.25 240.12,66.48 R2574.2
  TOP w0.305: 168.11,91.52 C184.2 167.57,91.17 v1(167.52,91.22) ; R188.1 224.89,68.35 225.41,68.87 225.41,69.26 v1(225.61,69.46) 225.61,69.49 225.77,69.65 R209.2 ; v1(237.74,69.84) 237.74,69.92 237.43,70.23 R155.2 ; v1(239.99,86.27) 240.12,86.14 R159.2 ; v1(173.97,89.52) R235.2 R234.2 ; v1(247.43,87.57) 247.2,87.34 247.2,86.58 247.46,86.32 R405.2 ; R852.2 R851.2 223.68,82.69 v1(223.68,82.23) ; v1(229.43,86.45) 229.41,86.43 R152.2 ; R158.2 v1(224.16,79.95) ; C312.1 31.98,54 R703.2 31.4,54.72 31.4,55.53 31.28,55.64 R702.2 ; v2(143.77,76.67) 142.68,75.58 v3(142.68,70.6) 142.68,69.76 141.87,68.95 141.87,67.98 v1(141.49,67.6) ; v1(233.54,67.91) 233.51,67.93 R136.2 R128.2 ; v1(231.17,67.68) 230.03,67.68 229.6,68.11 R181.2 230.67,68.4 R160.2 ; R189.1 229.66,71.48 v1(229.6,71.54) ; R148.2 230.83,87.93 230.83,88.21 v1(230.95,88.33) ; R172.1 240.37,80.28 v1(240.37,79.64) ; R134.2 240.01,77.66 240.62,77.66 v1(240.64,77.64) ; v1(152.84,97.85) 152.18,98.51 152.18,104.13 151.65,104.66 145.81,104.66 142.78,101.64 138.81,101.64 136.27,99.1 136.27,93.77 140.08,89.96 141.73,89.96 142.42,89.27 142.42,86.15 v1(141.3,85.02) ; 108.96,105.78 PR15.1 ; PR33.2 v1(236.33,108.01)
  TOP w0.381: v1(18.01,50.06) 18.01,49.97 R439.1 ; v1(220.38,71.18) 220.38,71.67 220.54,71.83 R211.2 ; R120.2 163.63,92.78 v1(163.63,92.04) ; R782.2 27.26,41 v1(26.87,40.61) ; v1(1.93,64.23) 2.06,64.23 2.39,64.56 R450.2
  TOP w0.508: 33.22,54 C312.1 ; 33.22,54 33.22,53.56 33.4,53.38 33.4,53.15 34.14,52.42 34.14,51.63 33.38,50.87 R483.2 ; 33.22,54 33.38,54.15 v1(33.38,54.75) ; R398.2 90.48,98.59 92.04,100.14 95.26,100.14 96.49,101.37 98.52,101.37 99.55,102.4 99.55,105.98 v1(100.45,106.88) 104.34,106.88 105.01,106.21 106.16,106.21 107.02,105.35 109.12,105.35 PD4.1 ; RC8.2 59.01,52.27 58.1,52.27 v3(57.96,52.14) 57.99,52.11 57.99,50.82 59.49,49.32 v3(70.08,49.32) 85.48,49.32 v1(85.92,48.87)
  IN1 w0.305: v1(163.63,92.04) 163.63,91.99 ; 163.63,91.99 164.4,91.22 v1(167.52,91.22) ; 163.63,91.99 163.2,91.99 162.23,91.02 156.75,91.02 156.04,91.73 154.01,91.73 152.84,92.9 v1(152.84,97.85)
  IN2 w0.305: v1(26.87,40.61) 27.89,41.62 31.19,41.62 33.81,44.24 v1(33.81,47.69)
  IN4 w0.254: v1(247.43,87.57) 246.97,88.03 244.9,88.03 244.13,87.26 244.13,86.12 243.87,85.86 242.78,85.86 242.73,85.91 v1(242.73,86.12)
  BOTTOM w0.254: PR26.2 181.84,61.15 181.41,61.58 R219.2 ; PR751.2 161.63,68.08 162.01,67.7 162.01,65.09 162.39,64.71 ; UC3.5 141.39,68.11 141.49,68.01 v1(141.49,67.6) ; U1.AJ17 v1(97.59,74.05) ; U1.AD18 97.54,76.64 v1(97.61,76.56) U1.AD17 ; v1(152.84,97.85) 152.54,98.16 PR738.1
  BOTTOM w0.305: v1(120.53,65.65) PR305.1 121.29,65.98 ; 178.14,64.5 R214.2 ; 178.14,64.5 177.53,64.5 R213.2 ; 178.14,64.5 178.57,64.5 181.01,62.06 R219.2 180.81,61.58 180.37,61.15 v1(180.37,60.9) 180.37,60.69 R218.2 ; R217.2 178.98,60.9 v1(178.95,60.92) ; v1(178.12,60.9) 178.12,60.67 178.27,60.52 R216.2 R215.2
  BOTTOM w0.381: RC70.1 100.66,62.08 v2(100.67,62.09) 100.71,62.13 100.71,62.67 RC64.2 RC69.1
  BOTTOM w0.508: v1(85.92,48.87) 37.93,48.87 36.35,47.29 34.22,47.29 v1(33.81,47.69)
  vias: v1(33.5,63.75) v1(34.11,63.77) v1(119.19,72.5) v1(119.8,72.5) v1(126.48,75.7) v1(126.91,75.27) v1(162.26,63.77) v1(162.85,63.79) v1(167.55,91.86) v1(173.64,91.83) v1(173.64,91.2) v1(243.42,84.62) v1(251.58,66.4) v1(252.21,66.38) v1(254.61,60.16) v1(254.61,59.25) v1(254.99,59.71) v1(255.35,59.2) v1(255.37,60.19) v1(260.74,71.56) v1(261.05,72.07) v1(261.35,71.56) v1(261.68,72.2) v1(261.96,71.59) v1(262.29,72.17) v1(269.37,115.69) v1(269.95,115.69) v2(108.82,63.28) v2(109.51,63.28) v2(110.17,63.26) v2(143.77,78.19) v2(144.15,79.67) v2(144.15,78.96) v2(144.15,77.43) v2(144.54,78.19) v2(144.54,76.67) v2(144.92,79.67) v2(144.92,78.96) v2(144.92,77.43) v2(145.3,78.19) v2(145.3,76.67) v2(145.68,79.67) v2(145.68,78.96) v2(145.68,77.43) v2(146.06,78.19) v2(146.06,76.67) v2(146.44,77.43) v2(146.82,78.19) v2(146.82,76.67)
VCC3M_BST:
  vias: v4(156.88,75.5)
VCC3M_DH: length 7.6
  IN1 w0.889: 148.47,79.92 152.66,79.92 155.05,77.53
  vias: v2(146.97,80.05) v2(146.97,79.36) v2(157.08,76.82) v2(157.54,76.29) v4(147.55,78.86)
VCC3M_DL: length 3.3
  IN1 w0.889: 157.24,78.9 154.9,81.24
  vias: v1(158.63,77.43) v2(154.1,82.74) v2(154.74,82.74) v2(158.12,77.94)
VCC3M_EC: length 46.3
  TOP w0.305: U16.H8 231.15,78.5 v1(231.15,78.45) U16.G8 ; U16.F12 v1(227.92,77.69) ; C169.2 C171.2 241.89,83.22 ; C169.2 241.89,83.78 ; C169.2 C170.2 241.89,84.37 ; U16.H3 v1(235.91,79.25) ; U16.G6 v1(233.51,78.45)
  TOP w0.508: v1(244.26,68.49) 243.87,68.11 R175.2
  IN2 w0.381: v1(244.26,68.49) 244.36,68.49 245.66,69.79 246.71,69.79 247.99,71.07 247.99,72.66 248.4,73.06 248.4,73.95 250.05,75.6 250.25,75.6 250.76,76.11 250.76,77.29 250.34,77.7 250.34,78.23 250.94,78.83 251.82,78.83 252.82,79.82 252.82,84.34 252.51,84.64 252.51,86.35 250.15,88.71 247.15,88.71 244.61,86.17 244.1,86.17 243.16,85.23 241.28,85.23
  IN4 w0.254: v1(231.15,78.45) 230.69,77.99 229.75,77.99 229.5,78.24 228.56,78.24 228,77.69 v1(227.92,77.69)
  vias: v1(241.03,83.93) v1(241.33,84.44) v3(241.46,83.5)
VCC3M_LX:
  vias: v1(152.82,75.35) v2(153.45,75.37) v2(155.94,74.76) v2(156.63,74.76)
VCC3M_VFB2: length 2.8
  BOTTOM w0.203: PU201.4 159.21,72.68 v4(158.81,72.28) PR214.2 PR219.1
VCC3MP: length 17
  IN4 w0.254: v1(145.35,74.69) 145.35,72.33 148.62,69.05 153.78,69.05 155.53,70.8 v1(157.01,70.8)
  BOTTOM w0.203: PR211.1 v1(157.01,70.8)
  BOTTOM w0.305: PC218.1 145.14,70.52
VCC3P: length 1.9
  BOTTOM w0.254: 141.4,87.6 141.31,87.5 R1.2
  BOTTOM w0.305: F2.2 142,87.23 R1.2 141.31,86.9 ; 143.43,87.46 R4.2
  vias: v3(144.38,87.42)
VCC3P_DRV: length 188.3
  TOP w0.305: U21.B5 v1(251.72,73.15)
  IN2 w0.203: v1(162.56,103.25) 163.29,103.25 163.69,103.64 163.69,106.51 164.98,107.81 168.36,107.81 168.74,107.43 168.74,104.84 170.29,103.29 191.32,103.29 198.6,96.01 201.11,96.01 206.59,101.49 214.2,101.49 218.72,106.01 228,106.01 228.88,105.13 228.88,103.7 232.09,100.49 236.28,100.49 241.06,95.72 241.06,92.31 242.17,91.2 243.13,91.2 243.9,90.44 250.27,90.44 250.69,90.01 251.77,90.01 252.69,89.09 252.69,88.02 254.77,85.94 256.24,85.94 256.78,85.41 256.78,83.82 255.66,82.7 255.66,79.26 253.98,77.58 253.98,74.54 252.6,73.15 v1(251.72,73.15)
  IN3 w0.254: v1(139.07,84.69) 137.31,86.45 134.6,86.45 132.74,88.31 132.74,97.07 v1(132.87,97.2)
  IN4 w0.203: v1(132.87,97.2) 132.87,98.02 134.22,99.38 136.14,99.38 137.87,101.1 143.29,101.1 145.07,102.88 152.16,102.88 152.86,102.18 157.49,102.18 158,102.68 161.99,102.68 v1(162.56,103.25)
  BOTTOM w0.254: D1.1 139.07,87.2 C2.2 139.07,85.85 R2.1 139.08,85.24 R3.2 v1(139.07,84.69)
VCC3SW: length 418.3
  TOP w0.254: PR163.2 205.08,70.9 205.34,70.9 v1(205.37,70.93) ; v1(246.74,76.92) 246.64,76.81 R271.2 ; R258.2 250.16,70.3 249.82,70.64 v1(249.82,70.78) ; R10089.2 R10090.2 254.5,57.89 254.82,58.2 v1(254.82,58.36) 254.72,58.46 R10088.2 ; PR167.2 204.72,67.54 v1(204.99,67.27) 205.06,67.27 205.37,67.58 PR164.2
  TOP w0.305: RC158.1 105.62,60.82 105.99,61.19 ; R259.2 247.12,71.42 v1(247.12,71.49) ; v1(244.89,73.88) 245.36,73.88 R256.2 R283.2 ; v1(252.15,80.15) 252.26,80.04 252.26,79.23 U21.J4 ; v1(236.23,69.86) 236.16,69.93 R179.2 ; R180.2 242.43,74.97 v1(242.83,74.56) ; U191.1 239.68,55.52 v1(240.69,56.53) ; R176.2 240.11,73.73 v1(240.53,74.15) ; v1(237,56.82) 236.81,57.02 U191.5 ; 251.73,81.26 C189.2 C192.2 ; 251.09,81.26 C192.2 ; C192.2 C191.2 ; R127.2 R178.2 240.01,71.18 v1(239.71,70.88) ; 250.46,81.26 C191.2 ; C191.2 C198.2 ; R257.2 245.05,73.13 v1(244.89,73.29) 244.64,73.29 244.49,73.44 R288.2 ; R254.1 v1(249.56,84.54)
  TOP w0.381: R116.1 183.69,95.32 184.2,94.81 185.5,94.81 186.21,95.52 189.08,95.52 189.99,96.44 189.99,99.15 191.16,100.32 v1(192.81,100.32) ; v1(238.69,78.73) 238.95,78.47 R177.2 ; v1(241.98,68.09) 242,68.11 R174.2
  TOP w0.508: v1(252.03,83.45) 252.06,83.45 252.28,83.67 252.28,83.68 252.56,83.96 252.56,86.52 249.83,89.26 v4(249.83,89.69) 248.17,91.35 244.05,91.35 v1(243.07,92.33) ; v1(255.36,72.1) 255.61,71.84 258.73,71.84 259.69,70.88 261.62,70.88 262.74,69.77 262.74,65.45 264.57,63.62 264.57,60.5 265.56,59.5 265.82,59.5 ; 106.28,62.12 106.28,61.48 105.99,61.19 ; 106.28,62.12 106.89,62.12 v1(107.15,61.86) ; 106.28,62.12 105.44,62.95 103.07,62.95 102.52,62.41 102.52,61.67 102.52,61.66 102.52,61.61 DC5.2 101.97,61.07 101.81,61.07 101.33,60.59 101.33,59.73 100.97,59.37 v1(100.47,59.37)
  IN2 w0.508: v1(138.26,55.82) 138.26,56.17 138.57,56.48 141.66,56.48 142.17,55.97 161.58,55.97 162.26,55.28 166.18,55.28 166.89,55.99 170.27,55.99 171.46,57.19 171.46,58.31 172.09,58.94 173.54,58.94 174.25,59.65 174.25,61.43 175.75,62.93 177.3,62.93 177.89,62.34 179.3,62.34 180.16,63.21 189.75,63.21 191.55,61.4 194.78,61.4 196.83,59.35 224.14,59.35 226.91,62.12 238.11,62.12 238.97,62.98 240.83,62.98 241.79,62.01 243.49,62.01 244.07,62.59 245.11,62.59 246.43,63.91 246.43,64.9 247,65.47 247.63,65.47 249.2,67.03 249.2,70.16 v1(249.82,70.78) 250.58,70.78 250.91,70.45 254.21,70.45 255.36,71.59 v1(255.36,72.1)
  IN3 w0.381: v1(192.81,100.32) 194.39,100.32 198.96,95.75 207.23,95.75 208.29,96.81 211.87,96.81 214.91,93.77 225.66,93.77 226.9,92.52 235.33,92.52 236.96,94.15 241.81,94.15 243.07,92.89 v1(243.07,92.33) ; v1(237,56.82) 237,56.52 237.27,56.25 237.85,56.25 241.78,52.32 244.83,52.32 246.99,54.47 251.21,54.47 254.82,58.09 v1(254.82,58.36) 255.37,58.36 255.94,58.93 255.94,60.96 257.25,62.27 v1(257.25,62.67)
  IN3 w0.508: v1(265.34,134.56) 265.34,130.71 263.7,129.07 263.7,123.42 262.06,121.78 262.06,113.63 256.98,108.55 251.95,108.55 249.97,106.57 v1(249.97,104.3) ; v1(107.15,61.86) 108.06,61.86 108.62,61.3 117.13,61.3 121.22,57.21 123.68,57.21 125.64,55.26 128.43,55.26 128.71,55.54 133.08,55.54 133.67,54.95 136.28,54.95 137.14,55.82 v1(138.26,55.82)
  IN4 w0.508: v1(243.07,92.33) 242.94,92.46 242.94,94.12 244.31,95.49 246.19,95.49 249.23,98.54 249.23,103.57 v1(249.97,104.3)
  BOTTOM w0.254: v1(265.34,134.56) 265.39,134.56 265.85,135.01 R5.2 266.05,135.34 J11.1
  BOTTOM w0.305: v1(100.47,59.37) 100.56,59.28 R427.1 ; v1(204.99,67.27) 205.73,68.01 205.73,70.39 205.37,70.75 v1(205.37,70.93)
  BOTTOM w0.381: v1(249.82,70.78) 249.68,70.78 248.8,69.9 248.7,69.9 248.7,66.2 249.31,65.59 249.31,64.43 251.06,62.67 v1(257.25,62.67) ; v1(237,56.82) 237,56.52 237.24,56.27 240.43,56.27 v1(240.69,56.53)
  vias: v1(251.11,81.04) v1(251.73,81.07)
VCC3TP: length 49.2
  TOP w0.305: R15.2 274.3,138.08 F6.2 ; Q266.5 271.77,116.4 R10320.1
  TOP w0.381: R15.2 v1(274.92,138.1)
  TOP w0.508: v1(260.36,137.09) 259.46,136.19 259.46,122.06 263.2,118.33 270.31,118.33 271.77,116.87 R10320.1
  IN4 w0.508: v1(274.92,138.1) 273.61,136.8 272.26,136.8 270.38,138.68 261.98,138.68 260.39,137.09 v1(260.36,137.09)
VCC3TP_ON: length 73.2
  TOP w0.102: U16.M3 235.53,82.34 235.92,82.74 235.92,83.55 236.81,84.43 R200.2 R350.1 236.02,85.13 236.37,85.49 236.37,86.5 236.27,86.61 236.27,87.27 v1(236.65,87.65) ; C9487.2 271.48,112.87 271.22,112.62 269.65,112.62 v1(269.62,112.59)
  TOP w0.305: R10321.1 271.34,113.44 C9487.2 271.48,114.1 D744.1
  IN1 w0.076: v1(236.65,87.65) 237.52,87.65 238.08,87.09 238.08,86.15 238.51,85.72 244.91,85.72 246.64,83.99 249.71,83.99 250.34,84.62 252.2,84.62 253.62,83.2 253.62,82.85 254.26,82.21 255.58,82.21 257.79,84.42 v1(259.26,84.42)
  IN3 w0.081: v1(269.62,112.59) 267.92,110.89 267.92,90.31 264.31,86.71 262.28,86.71 260,84.42 v1(259.26,84.42)
VCC3WAN: length 11
  TOP w0.254: Q30.2 242.01,53.31 v1(242.05,53.28)
  TOP w0.305: C278.1 242.29,61.09 C126.2 ; C278.1 C277.2 243.52,60.74 ; C278.1 242.93,60.74 ; v1(226.09,58) 225.84,58.25 225.84,58.51 C125.2 ; v1(226.68,58) 226.68,58.22 226.88,58.42 R101.2
  BOTTOM w0.254: v1(242.05,53.28) 241.63,53.69 241.63,57.5 242.21,58.08 242.93,58.08
  vias: v1(226.98,57.47) v1(227.26,58) v1(242,60.38) v1(242.58,60.39) v1(243.16,60.39) v1(243.75,60.39) v1(247.32,59.91) v1(247.28,59.3) v1(247.91,59.94) v1(247.91,59.3) v4(246.81,59.88)
VCC3WAN_DRV: length 17.1
  TOP w0.254: R306.1 253.04,62.73 252.96,62.81 ; U21.E3 253.32,75.55 v1(253.35,75.55) ; 252.96,62.81 D47.1 ; 252.96,62.81 252.53,63.25 252.53,63.67 C216.2 251.74,63.8 v1(251.54,64)
  IN3 w0.203: v1(253.35,75.55) 253.37,75.53 253.37,75.5 254.01,74.86 254.01,72.3 252.83,71.12 252.83,64.51 252.33,64 v1(251.54,64)
VCC3WLAN: length 7.1
  TOP w0.305: 215.33,58.39 C300.1 C299.1 ; 196.35,56.22 C280.1 196.37,55.85 C279.2 ; C299.1 C128.2 ; C299.1 214.74,58.39 ; C279.2 197.53,55.85 C130.2 ; C279.2 196.96,56.2 ; C303.1 212.25,58.28 212.71,58.74 C305.2 ; C128.2 C304.2 ; C128.2 214.11,58.39 ; C305.2 C304.2 ; C305.2 212.94,58.39 ; C304.2 213.52,58.39
  vias: v1(196.61,56.91) v1(196.83,57.47) v1(197.01,56.48) v1(197.27,57.06) v1(213.57,57.11) v1(213.7,57.7) v1(214.18,57.11) v1(214.36,57.67) v1(247.99,53.58) v1(248.01,52.97) v1(248.57,53.58) v1(248.6,52.97) v1(249.23,53.61) v1(249.21,53)
VCC3WLAN_DRV: length 37.6
  TOP w0.102: U21.D1 255.43,75.13 v1(256.3,74.26)
  TOP w0.203: v1(250.83,55.38) 250.28,54.83 v3(250.04,54.83) 249.76,54.55 249.1,54.55 C215.2 249.2,54.09 250.01,54.09 D46.1 250.92,54.04 R305.1
  IN3 w0.203: v1(257.1,66.9) 254.79,66.9 253.35,68.34 253.35,69.71 254.8,71.16 254.8,72.94 254.57,73.16 254.57,74.38 254.9,74.71 256.02,74.71 256.3,74.43 v1(256.3,74.26)
  IN4 w0.203: v1(250.83,55.38) 250.33,55.89 250.33,56.65 250.96,57.29 253.35,57.29 254.11,58.05 254.11,59.86 252.81,61.16 252.81,63.69 253.24,64.13 254.33,64.13 v1(257.1,66.9)
VCC5_TP: length 7
  BOTTOM w0.102: v4(137.87,58.74) 138.07,58.54 R220.2
  BOTTOM w0.254: R220.2 138.07,57.7 R222.2 R221.2
  BOTTOM w0.305: R222.2 137.02,57.75 C174.2 135.76,58.32 135.57,58.51 133.47,58.51
VCC5B: length 40.7
  TOP w0.254: v1(221.51,51.73) 221.86,51.73 222.06,51.93 U7.5
  TOP w0.381: F8.2 136.31,65.54 136.6,65.25 v1(136.83,65.25) ; U27.5 216.01,47.81 v1(216.7,47.13)
  TOP w0.508: v1(136.83,65.25) 138.79,67.22 140.52,67.22 141.49,66.26 141.49,64.5 143.1,62.89 143.61,62.89 144.69,61.81 v3(147.58,61.81) 154.9,61.81 156.22,60.49 160.3,60.49 160.72,60.91 v1(160.72,61.18)
  IN3 w0.381: v1(136.83,65.25) 136.83,65.15 140.39,61.59 v1(140.49,61.59)
  BOTTOM w0.305: v1(160.72,61.18) 160.72,61.12 161.4,60.44 F14.2
  BOTTOM w0.381: F40.2 139.96,61.16 140.39,61.59 v1(140.49,61.59)
  vias: v1(20.28,36.36) v1(20.28,35.75) v1(20.89,36.33) v1(21.37,36.72) v1(129.47,53.99) v1(129.65,51.09) v1(130.06,53.96) v1(130.29,51.09) v1(130.69,53.96) v1(130.87,51.09) v1(135.01,57.21) v1(135.57,57.39) v1(219.08,46.54) v1(220.1,46.01) v1(220.41,45.48) v1(220.68,46.04) v1(269.58,81.72) v1(269.58,81.11) v1(269.58,80.4) v1(269.58,79.82) v1(270.11,81.39) v1(270.09,80.73) v1(270.11,80.1) v1(270.14,79.49) v1(282.05,71.41) v1(282.15,72.02) v1(282.71,71.44) v1(284.41,71.64) v1(284.41,70.88) v2(37.92,54.42) v2(37.92,53.79) v2(38.91,54.35)
VCC5B_DRV: length 19.2
  TOP w0.127: U21.C4 v1(252.56,73.91)
  TOP w0.203: R301.1 264.54,77.32 C213.2 ; D43.1 265.52,77.28 C213.2 ; C213.2 264.58,76.8 264.12,76.34 v1(264.07,76.34)
  IN3 w0.203: v1(252.56,73.91) 252,74.47 252,75.86 252.54,76.39 253.91,76.39 255.23,75.07 259.37,75.07 260.41,76.11 263.84,76.11 v1(264.07,76.34)
VCC5B_HDMI: length 0.7
  BOTTOM w0.305: 14.31,32.35 R341.1 ; 14.31,32.93 R340.1
  vias: v1(16.66,35.65) v1(16.92,36.19) v4(13.65,34.56)
VCC5B_NFC: length 3.2
  BOTTOM w0.102: J26.19 139,62.31 139,60.15 138.93,60.09 F40.1
  vias: v3(139.4,60.85)
VCC5BA: length 0.3
  TOP w0.305: 282.57,67.78 C30.2
  vias: v3(284.29,69.15)
VCC5M: length 49.2
  TOP w0.254: U185.5 136.25,68.61 C9130.2 136.27,68.86 136.56,69.15 v1(136.56,69.79) 136.56,70.04 v4(136.32,70.27) 136.05,70.54 136.05,70.74 135.72,71.07 U184.5 ; U5.H10 25.98,48.12 v1(26.16,48.3) ; U12.1 273.2,81.43 v1(273.06,81.57) ; U12.7 275.81,78.77 275.87,78.71 C274.1 ; U21.A5 v1(251.72,72.35)
  TOP w0.305: 251.09,71.23 C195.2 D37.2 ; 247.56,93.94 C188.2 247.94,94.42 ; C307.2 C306.1 ; C307.2 61.15,108.06 ; C307.2 61.57,107.73 ; C306.1 61.57,108.95 ; C306.1 61.12,108.62 ; v2(273.47,79.36) 273.39,79.44 272.86,79.44 C108.2 ; 272.86,79.92 C108.2 ; C108.2 273.2,79.59 ; C274.1 275.5,77.91 v1(275.09,77.51)
  TOP w0.381: v1(249.54,97.27) 246.82,97.27 245.8,98.28 245.12,98.28 244.84,98.01 244.38,98.01 244.09,97.71 U20.5
  IN1 w0.508: v2(135.15,80.74) 135.15,81.22 134.82,81.55 129.82,81.55 v2(129.72,81.65)
  VCC w0: 209.23,74.1 209.36,74.1
  IN4 w0.508: v1(249.54,97.27) 249.54,95.62 248.95,95.03 v1(248.95,94.73) v1(248.35,94.73)
  BOTTOM w0.203: v1(128.74,94.45) 128.78,94.5 PR474.2 ; PC529.1 134.93,81.42 134.1,82.25 PU405.31 ; PR450.2 118.22,99.33 v1(118.07,99.48)
  BOTTOM w0.254: PR457.1 67.27,110.32 v2(67.27,110.25) ; PU403.3 63.9,110.5 v2(63.7,110.69) ; 146.92,103.52 146.8,103.4 PU702.18
  BOTTOM w0.305: PR708.2 146.91,104.28 PC716.2 ; PR708.2 147.16,104.61 ; PR708.2 147.16,103.76 146.92,103.52 ; PC312.1 127.17,61.24 126.55,60.62 125.89,60.62 125.49,61.02 125.49,61.28 125.13,61.63 PU301.12
  BOTTOM w0.381: PC529.1 135.15,81.4 v2(135.15,80.74) ; PC716.2 146.38,104.9 146.8,105.32 v1(147.58,105.32) ; v1(119.06,102.35) 118.74,102.35 PR403.1
  BOTTOM w0.508: v1(128.69,62.29) 128.69,61.71 128.22,61.24 PC312.1
  vias: v1(20.61,24.14) v1(20.58,23.1) v1(21.09,23.71) v1(21.17,23.13) v1(21.37,24.32) v1(21.73,23.71) v1(28.23,46.75) v1(30.79,46.04) v1(31.23,46.54) v1(31.37,45.97) v1(31.81,46.54) v1(34.93,58.56) v1(34.93,57.98) v1(34.93,57.4) v1(34.93,56.81) v1(61.76,109.82) v1(88.55,102.96) v1(88.55,102.35) v1(93.91,102.7) v1(251.72,71.77) v1(261.3,78.98) v1(261.32,78.29) v1(261.81,80.58) v1(261.78,79.95) v1(261.81,79.31) v1(261.83,78.68) v1(262.09,78.14) v2(129.37,72.86) v2(129.4,72.2) v2(129.4,71.54) v2(130.03,72.17) v2(130.03,71.49) v2(160.79,65.39) v2(161.48,65.39) v2(174.51,69.2) v2(174.84,69.79) v2(174.84,68.62) v2(175.14,69.2) v2(175.47,69.79) v2(175.47,68.62) v2(175.78,69.2) v2(176.11,69.79) v2(176.11,68.62) v2(176.41,69.2) v2(176.74,69.79) v2(176.74,68.62) v2(177.05,69.2) v2(177.38,69.79) v2(177.38,68.62) v2(177.68,69.2) v2(178.01,69.79) v2(178.01,68.62) v2(273.47,78.65) v2(274.1,79.03) v4(32.51,45.89) v4(247.23,94.22)
VCC5M_BST:
  vias: v4(162.16,75.48)
VCC5M_DH: length 8.1
  IN1 w0.889: 169.5,81.27 168.49,81.27 163.94,76.72 163.26,76.72
  vias: v1(161.65,76.26) v2(162.11,76.75) v2(170.52,83.96) v2(170.54,83.27)
VCC5M_DL: length 8
  IN1 w0.889: 162.19,78.5 167.04,83.35 168.18,83.35
  vias: v2(160.86,77.21) v2(161.4,77.74) v2(169.12,83.58) v2(169.15,82.94)
VCC5M_FB1: length 2.8
  BOTTOM w0.203: PR220.2 PR215.2 v4(160.44,72.25) 160.01,72.68 PU201.2
VCC5M_LX: length 5.5
  IN1 w0.889: 168,78.55 164.4,74.94 164.02,74.94
  vias: v2(162.37,74.76) v2(163.05,74.76) v2(168.23,79.46) v2(169,79.46) v4(169.22,80.63)
VCC5MP: length 37.6
  TOP w0.305: 175.73,74.59 PC224.1 ; PC224.1 176.15,74.93 176.16,74.92 ; PC224.1 175.08,74.93 PC230.2
  IN1 w0.254: v2(176.77,71.87) 174.66,71.87 171.76,68.97 166.2,68.97 163.15,72.02 v2(162.42,72.02)
  IN4 w0.508: v1(173.67,74.84) 172.65,75.86 172.65,77.86 171.33,79.18 171.33,79.64 170.29,80.68 165.9,80.68 164.3,79.08 v1(161.2,79.08)
  BOTTOM w0.203: v2(162.42,72.02) 162.42,71.46 161.78,70.83 PR210.1
  BOTTOM w0.305: 160.87,79.1 PC225.2 160.54,78.76
  vias: v1(174.33,74.82) v3(175.09,73.9)
VCC_SENSE: length 71.3
  TOP w0.254: RC75.2 89.57,85.7 v1(89.57,86.12)
  IN3 w0.254: v1(130.41,100.7) 131.58,101.87 134.88,101.87 135.69,101.06 135.69,99.99 134.93,99.23 133.91,99.23 132.36,97.68 132.36,94.15 130.48,92.26 121.9,92.26 120.54,90.9 119.61,90.9 116.41,94.09 108.9,94.09 105.75,90.94 105.75,90.23 105.04,89.52 98.1,89.52 97.31,90.32 94.41,90.32 93.15,91.58 92.67,91.58 91.5,90.41 91.5,89.32 90.48,88.3 89.8,88.3 89.09,87.59 89.09,86.85 89.57,86.37 v1(89.57,86.12)
  BOTTOM w0.254: v1(130.41,100.7) PC406.1 129.35,100.7 PR414.1 129.18,101.02 PC404.1 ; v1(89.57,86.12) 89.29,86.4 U1.E32
VCCCPUCORE: length 41.4
  TOP w0.254: CC83.2 87.44,72.83 v1(87.74,72.53) ; CC85.2 84.02,85.23 v1(84.12,85.33) ; 88.15,72.73 CC82.2 ; CC81.2 85.91,72.5 v1(85.94,72.47) ; v1(86.85,72.45) 86.62,72.68 CC84.2
  TOP w0.305: CC79.2 86.17,84.72 ; CC79.2 85.75,84.44 ; CC79.2 85.75,85.17 v1(85.93,85.35) ; 89.99,84.67 RC75.1 89.72,84.47 ; 85.06,83.73 CC80.2 84.67,84.01 ; 88.58,73.16 88.57,73.15 CC82.2 87.87,73.15 ; 86.34,73.15 CC84.2 ; 87.16,73.15 CC83.2 ; 84.02,84.44 CC85.2 84.46,84.72 ; 85.63,73.15 CC81.2 ; CC78.2 88.05,84.77 ; CC78.2 87.58,85.16 87.74,85.33 v1(87.74,85.35) ; CC78.2 87.58,84.49
  TOP w0.381: PC444.2 85.21,77.58 v1(85.56,77.58) ; v1(87.36,75.63) 87.7,75.63 PC447.2 ; v1(90.28,77.66) 90.28,77.32 PC461.2 ; PC454.2 85.21,82.66 v1(85.56,82.66) ; v1(89.72,75.63) 90.07,75.63 PC456.2 ; v1(87.94,83.35) 88.29,83.35 PC446.2 ; PC448.2 88.31,79.51 v1(87.97,79.51) ; v1(85,74.94) 84.65,74.94 PC452.2 ; v1(85.56,76.31) 85.21,76.31 PC459.2 ; PC455.2 85.21,80.12 v1(85.56,80.12) ; PC440.2 90.31,82.02 v1(90.31,82.36) ; PC442.2 88.29,82.08 v1(87.94,82.08) ; v1(85.56,81.39) 85.21,81.39 PC445.2 ; PC462.2 85.21,78.85 v1(85.56,78.85) ; PC441.2 88.34,76.97 v1(87.99,76.97) ; PC443.2 90.28,79.68 v1(90.28,80.02)
  BOTTOM w0.127: U1.K43 82.38,83.81 v1(82.38,83.81)
  BOTTOM w0.203: v1(81.77,90.69) 81.77,90.03 82.19,89.61 U1.A44
  BOTTOM w0.254: U1.G32 89.6,85.4 U1.G30 ; U1.A39 84.77,88.9 v1(84.77,89.7) ; 84.33,101.16 84.33,103.47 84.02,103.78 80.77,103.78 80.35,103.36 PR464.1 ; U1.G35 87.56,85.35 v1(87.74,85.35) 87.97,85.35 U1.G33 ; v1(88.71,72.48) 88.61,72.48 U1.AM33 ; U1.G38 85.73,85.35 v1(85.93,85.35) 86.15,85.35 U1.G37 ; v1(87.74,72.53) 87.64,72.53 U1.AM35 ; U1.AM38 85.55,72.86 v1(85.94,72.47) 86,72.47 U1.AM37 86.44,72.86 v1(86.85,72.45)
  BOTTOM w0.305: U1.A34 87.15,89.18 v1(87.36,89.39) ; U1.A30 v1(89.63,89.34)
  vias: v1(84.16,83.83) v2(79.44,95.29) v2(79.44,94.63) v2(79.46,93.99) v2(79.46,93.33) v2(79.64,95.92) v2(79.99,94.96) v2(80.02,94.32) v2(80.04,93.05) v2(80.07,93.69) v2(80.27,96.18) v2(80.27,95.54) v2(80.63,94.96) v2(80.65,94.32) v2(80.71,93.69) v2(80.93,96.23) v2(80.91,95.57) v2(81.26,94.96) v2(81.31,94.32) v2(81.34,93.66) v2(81.54,95.57) v2(81.59,96.2) v2(81.9,94.91) v2(81.95,94.22) v2(81.98,93.59) v2(82.23,96.2) v2(82.18,95.54) v2(82.28,93.03) v2(82.56,94.91) v2(82.64,93.59) v2(82.66,94.22) v2(82.81,95.54) v2(82.86,96.2) v2(82.91,93.01) v2(83.22,94.91) v2(83.32,94.22) v2(83.27,93.59) v2(83.45,95.54) v2(83.5,96.2) v2(83.85,94.91) v2(83.91,93.59) v2(83.96,94.25) v2(84.13,96.2) v2(84.08,95.54) v2(84.52,94.75) v2(84.54,93.46) v2(84.59,94.12) v2(85.15,94.73) v2(85.23,94.09) v2(85.81,94.75) v2(87.33,96.25) v3(85.07,95.9)
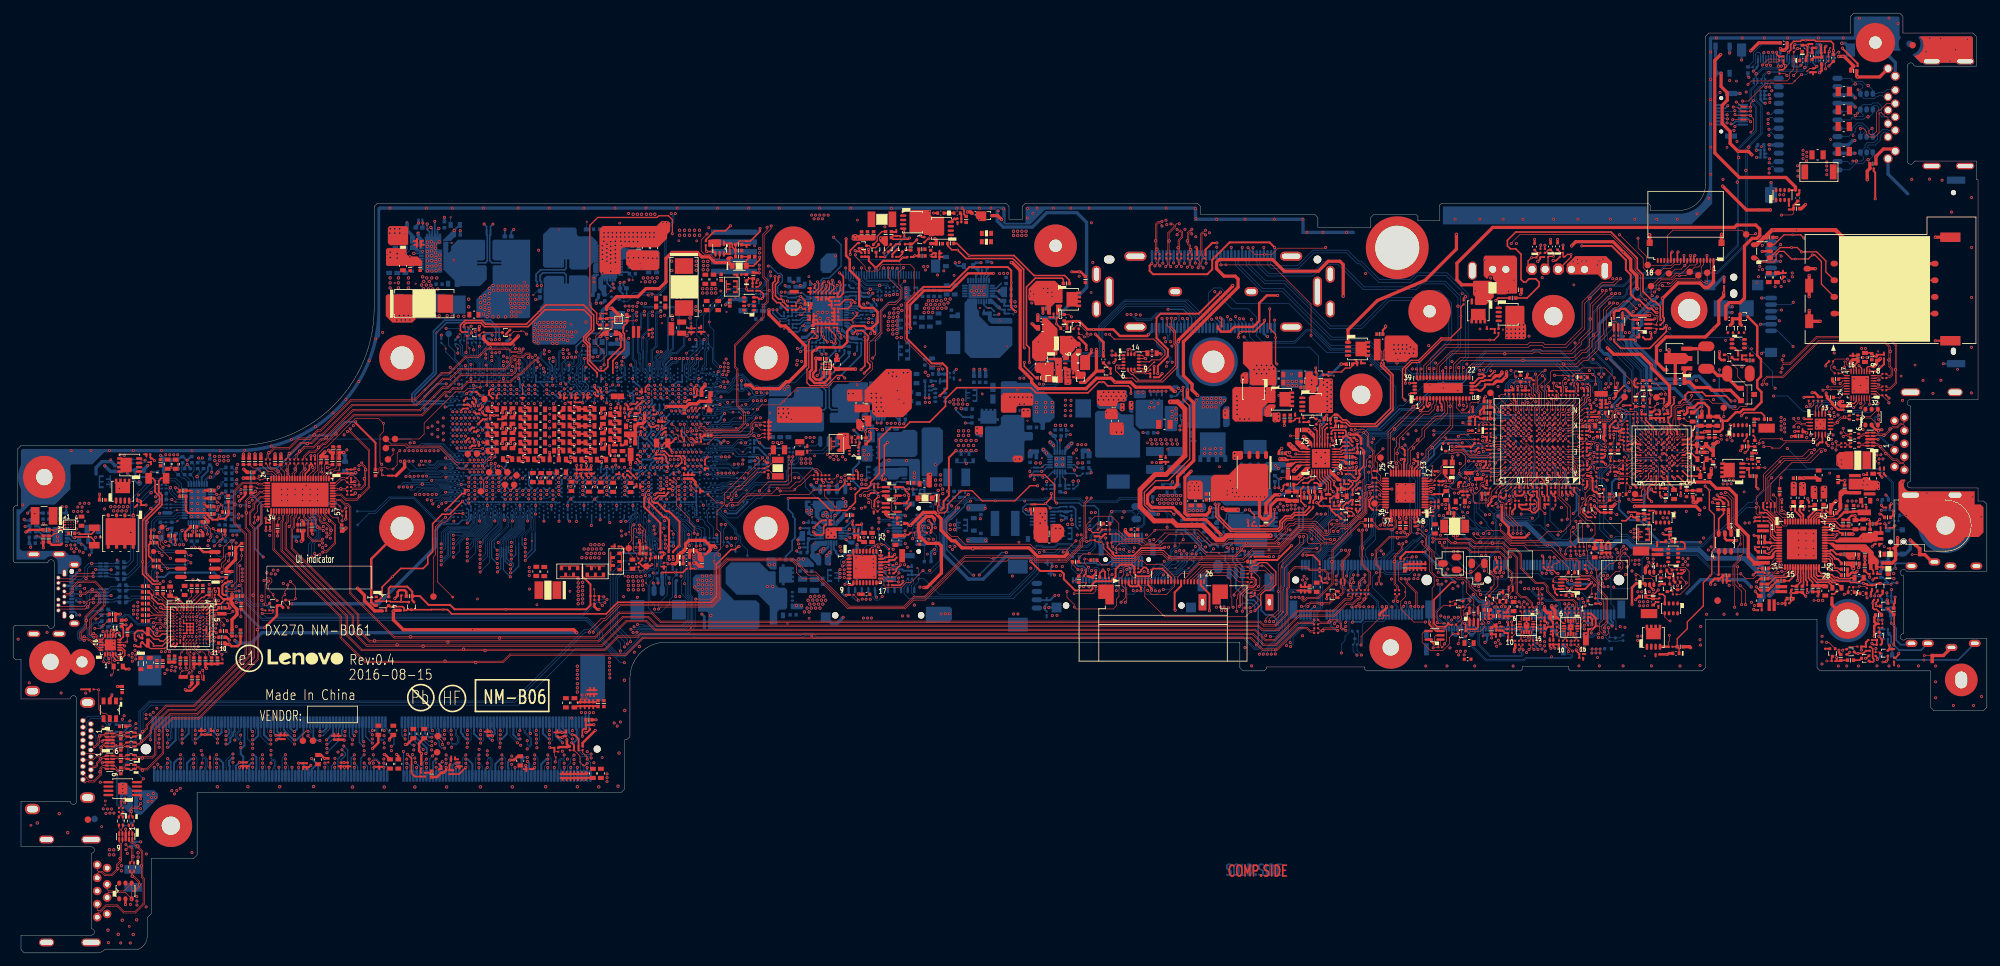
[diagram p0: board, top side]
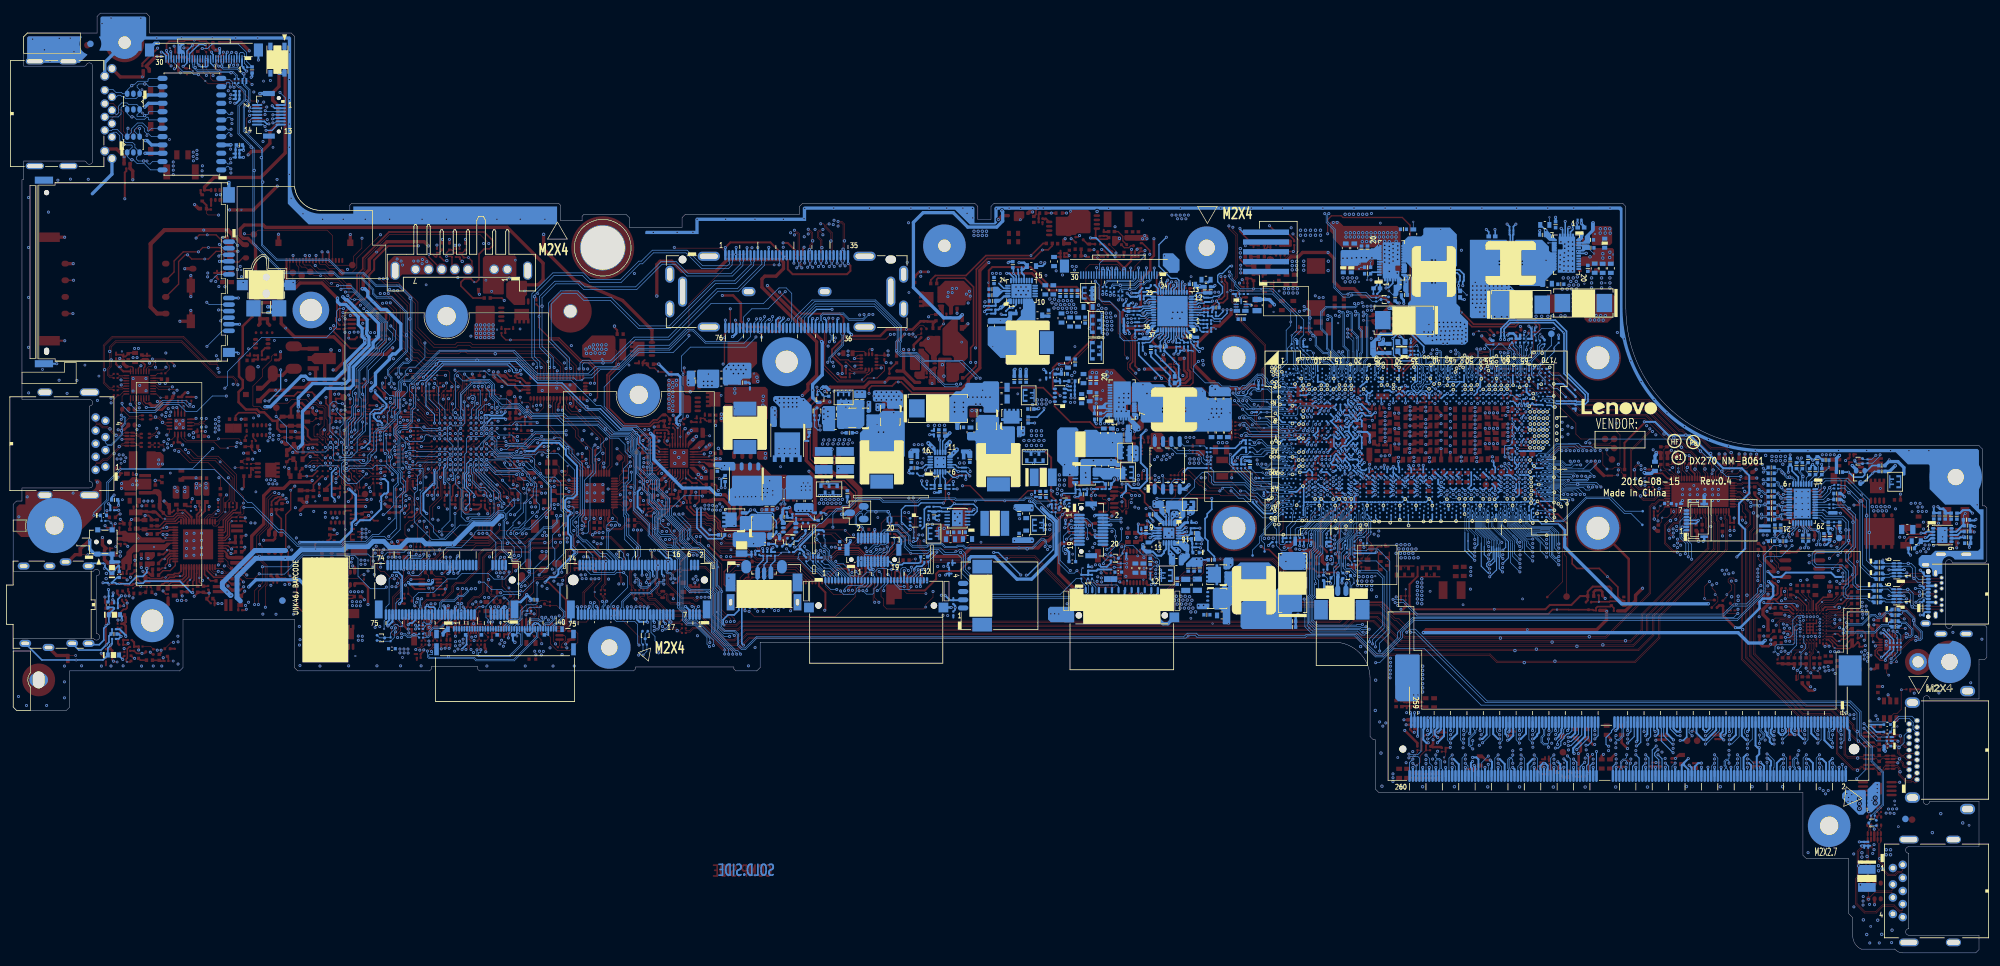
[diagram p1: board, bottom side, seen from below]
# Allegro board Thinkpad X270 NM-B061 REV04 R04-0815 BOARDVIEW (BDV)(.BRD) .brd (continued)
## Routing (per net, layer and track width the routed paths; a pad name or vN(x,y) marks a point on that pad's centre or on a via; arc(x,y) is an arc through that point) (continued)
VCCCPUIO: length 37.7
  TOP w0.254: 77.34,84.71 RC1.2 78,84.71
  TOP w0.305: 77.68,84.42 RC1.2 ; 91.93,73.06 RC86.2 92.41,73.34
  IN1 w0.508: v1(90.51,72.47) v1(89.6,72.47) 89.44,72.32 89.44,70.93 88.93,70.42 88.45,70.42 87.28,69.25 86.29,69.25 85.3,70.24 84.85,70.24 84.26,70.83 84.26,71.56 83.36,72.47 v1(83.2,72.47)
  IN3 w0.508: v1(83.2,72.47) 83.2,73.83 83.42,74.05 83.73,74.36 84.31,74.94 84.31,82.74 82.31,84.75 78.55,84.75 v1(77.64,83.85)
  BOTTOM w0.203: v1(90.51,74.22) U1.AK28 ; v1(90.51,74.22) U1.AK30 ; v1(90.51,74.22) U1.AL30 ; U1.AM30 90.05,72.88 U1.AL30 ; U1.AL30 v1(90.51,72.47)
  BOTTOM w0.254: v1(83.2,72.47) U1.AM42 84.11,73.32 U1.AL42 ; v1(89.6,72.47) U1.AM30 ; U1.AM28 v1(90.51,72.47)
  vias: v2(105.14,101.36) v2(105.14,100.7) v2(105.8,101.36) v2(105.8,100.7) v2(106.49,101.36) v2(106.49,100.7) v2(107.12,101.36) v2(107.12,100.7) v3(107.91,101.01)
VCCCPUIO_DRV: length 186.2
  TOP w0.102: U21.D2 253.89,75.13 254.31,75.55 255.48,75.55 v1(255.66,75.73)
  TOP w0.203: R407.1 113.62,101.64 113.95,101.97 v1(113.95,102.22)
  IN1 w0.203: v1(113.95,102.22) 115.38,102.22 115.91,102.76 116.99,102.76 117.25,103.01 123.57,103.01 125.88,105.33 137.31,105.33 139.65,107.66 155.3,107.66 158.18,104.79 160.54,104.79 163,107.25 167.55,107.25 170.87,103.93 178.82,103.93 182.66,100.09 184.13,100.09 184.57,100.52 184.57,102.09 186.99,104.52 194.79,104.52 195.31,105.04 196.61,105.04 197.11,105.55 197.11,106.16 198.13,107.17 202.63,107.17 203.33,106.47 203.33,103.55 205.31,101.57 213.36,101.57 214.28,102.48 217.24,102.48 220.89,106.13 228.23,106.13 231.2,103.16 232.37,103.16 232.95,102.58 237.19,102.58 241.8,97.97 245.18,97.97 245.73,97.42 248.17,97.42 248.55,97.8 249.69,97.8 250.25,97.24 251.57,97.24 252.56,96.25 v1(252.56,95.29)
  IN3 w0.203: v1(255.66,75.73) 256.47,76.54 256.47,80.17 256.22,80.43 256.22,83.35 253.43,86.14 253.43,94.42 v1(252.56,95.29)
VCCGFXCORE_I: length 38
  TOP w0.254: CC86.2 68.59,83.07 68.31,82.79 v1(68.31,82.56)
  TOP w0.305: v1(69.66,77.08) 69.99,77.41 CC89.2 ; CC88.2 70.29,78.28 v1(70.29,77.94) ; CC87.2 70.69,79.55 v1(70.9,79.76) ; v1(71.59,82.57) 71.59,82.33 71.9,82.03 CC91.2 ; PC496.2 72.69,80.07 v1(73.03,80.07) ; CC94.2 70.56,82.3 v1(70.29,82.56) ; PC475.2 74.61,81.43 CC92.2 ; v1(71.61,77.96) 71.71,77.86 PC510.2 ; v1(70.9,80.7) 71.62,81.42 CC90.2
  TOP w0.381: v1(78.04,82.59) 77.7,82.59 PC493.2 ; v1(80.15,75.68) 80.49,75.68 PC476.2 ; v1(75.24,82.41) 75.24,82.07 PC475.2 ; v1(73.03,78.8) 72.69,78.8 PC492.2 ; v1(76.49,77.71) 76.49,77.37 PC494.2 ; v1(81.82,76.39) 81.81,76.38 PC472.2 ; v1(78.04,77.51) 77.7,77.51 PC507.2 ; v1(73.03,82.61) 72.69,82.61 PC481.2 ; PC516.2 77.7,80.05 v1(78.04,80.05) ; PC483.2 77.7,78.78 v1(78.04,78.78) ; PC474.2 77.44,74.97 v1(77.78,74.97) ; v1(78.04,76.24) 77.7,76.24 PC478.2 ; PC512.2 76.49,79.7 v1(76.49,80.05) ; PC473.2 75.74,75.7 v1(75.4,75.7) ; v1(75.24,80.05) 75.24,79.7 PC513.2 ; v1(78.04,81.32) 77.7,81.32 PC517.2 ; PC479.2 72.69,76.26 v1(73.03,76.26) ; PC511.2 76.49,82.07 v1(76.49,82.41) ; v1(75.24,77.71) 75.24,77.37 PC489.2
  BOTTOM w0.203: U1.A48 79.72,89.19 v1(79.87,89.34) ; v1(72.12,89.7) 72.26,89.56 72.26,88.82 U1.A62 ; U1.A53 77.12,88.91 v1(77.12,89.27) ; U1.A58 v1(74.76,89.65) ; U1.A66 v1(69.8,89.81)
  BOTTOM w0.254: PL402.2 73.01,105.3 72.67,105.64 72.67,109.53 PR466.1
  BOTTOM w0.305: 62.71,82.71 RC88.2 63.17,83.05
  vias: v1(62.25,75.03) v1(62.9,76.63) v1(63.26,80.15) v1(63.89,80.4) v1(63.87,79.15) v1(64.17,76.63) v1(64.75,80.98) v1(64.75,79.86) v1(64.75,78.75) v1(65.59,81.62) v1(65.57,80.4) v1(65.59,79.3) v1(65.59,78.26) v1(67.04,82.58) v1(67.01,81.62) v1(67.04,80.73) v1(67.07,79.79) v1(67.07,78.9) v1(67.07,77.96) v1(67.62,81.59) v1(67.68,82.56) v1(67.67,80.71) v1(67.67,78.9) v1(67.7,77.96) v1(68.31,81.59) v1(68.34,80.7) v1(68.31,79.79) v1(68.34,78.88) v1(68.34,77.08) v1(68.36,77.96) v1(68.97,82.56) v1(68.97,80.71) v1(69,79.79) v1(68.97,78.85) v1(68.97,77.08) v1(69.63,82.56) v1(69.63,81.62) v1(69.61,80.7) v1(69.63,77.96) v1(70.29,81.62) v1(70.98,78.9) v1(73.09,83.88) v1(74.02,83.77) v1(74.99,83.88) v1(75.88,83.88) v1(76.77,83.88) v1(78.57,83.83) v1(79.46,83.83) v1(80.45,83.88) v1(81.82,83.07) v1(81.82,82.21) v1(81.8,81.11) v1(81.8,80.07) v1(81.8,78.73) v1(81.82,77.41) v2(71.31,99.99) v2(71.28,99.22) v2(71.31,98.49) v2(71.74,97.5) v2(71.92,100.32) v2(71.89,99.55) v2(71.94,98.82) v2(71.94,98.18) v2(72.27,97.09) v2(72.53,99.07) v2(72.63,101.41) v2(72.55,99.83) v2(72.58,98.34) v2(72.58,97.7) v2(72.65,100.65) v2(73.19,101.84) v2(73.16,97.07) v2(73.26,101.13) v2(73.95,101.76) v2(73.95,101.13) v2(74,97.07) v2(74.58,101.76) v2(74.58,101.13) v2(75.07,97.07) v2(75.22,101.76) v2(75.22,101.13) v2(75.85,101.76) v2(75.85,101.13) v2(75.85,100.39) v2(75.85,99.76) v2(75.85,99.12) v2(76.03,98.49) v2(76.03,97.8) v2(76.03,97.17) v2(76.49,101.76) v2(76.49,101.13) v2(76.49,100.39) v2(76.49,99.76) v2(76.49,99.12) v2(76.67,98.49) v2(76.67,97.8) v2(76.67,97.17) v2(77.12,101.76) v2(77.12,101.13) v2(77.12,100.39) v2(77.12,99.76) v2(77.12,99.12) v2(77.3,98.49) v2(77.3,97.8) v2(77.76,101.76) v2(77.76,101.13) v2(77.76,100.39) v2(77.76,99.76) v2(77.76,99.12) v2(77.94,98.49) v2(78.39,101.76) v2(78.39,101.13) v2(78.42,100.39) v2(78.42,99.76) v2(78.42,99.12) v3(78,102.33)
VCCGT_SENSE: length 90.9
  IN3 w0.203: v1(120.06,91.76) 120.06,92.53 119.85,92.75 119.24,92.75 116.95,95.03 108.26,95.03 104.89,91.66 99.98,91.66 99.4,91.07 97.98,91.07 97.65,91.4 94.83,91.4 93.56,92.66 92.18,92.66 90.05,90.54 89.06,90.54 88.71,90.18 87.03,90.18 85.37,88.52 84.32,88.52 84.32,88.52 82.01,88.52 81.49,88 80.25,88 78.09,90.16 78.09,90.72 77.4,91.4 76.56,91.4 74.36,93.61 v1(74.15,93.61)
  BOTTOM w0.127: 65.69,83.81 65.83,83.95 67.07,83.95 U1.J70
  BOTTOM w0.203: v1(120.06,91.76) 120.19,91.76 120.95,92.52 PC413.2 121.42,93.15 121.42,93.56 122.38,94.52 PU401.47
  BOTTOM w0.254: 65.69,83.81 62.88,83.81 RC88.1 62.64,83.71 61.27,83.71 60.82,84.16 v4(60.82,84.7) 60.82,85.29 64.1,88.57 64.1,94.86 65.8,96.56 72.8,96.56 74.1,95.26 74.1,94.15 74.15,94.09 v1(74.15,93.61)
VCCLAN_ON: length 23
  TOP w0.102: v1(260.84,81.85) 260.84,83.17 TP40.1 ; v1(252.53,77.94) 252.15,77.55 U21.G4 ; U21.D9 v1(247.51,75.13)
  BOTTOM w0.102: v1(247.51,75.13) 247.68,75.3 250.63,75.3 250.73,75.2 251.87,75.2 252.1,75.43 252.1,76.13 252.1,76.14 252.1,76.95 252.1,76.96 252.1,77.51 v1(252.53,77.94) 252.93,77.54 252.93,76.84 253.32,76.44 257.67,76.44 259.26,78.03 259.26,80.27 v1(260.84,81.85)
VCCMPHY_GATE: length 8.2
  TOP w0.254: CC57.2 96,80.21 v1(96.32,79.89)
  TOP w0.305: CC56.2 99.49,81.06 ; CC56.2 CC54.2 98.37,81.35 ; CC56.2 98.93,81.35
  BOTTOM w0.254: U1.P15 99.19,81.17 98.88,81.48 v1(98.88,81.59) ; v1(98.88,81.59) 98.57,81.28 U1.P16 ; v1(98.88,81.59) 98.88,81.7 99.19,82.01 U1.N15 ; v1(96.94,81.6) U1.N18 97.31,82.05 97.87,82.05 U1.N17 ; U1.N16 98.57,82.03 98.87,82.37 98.87,82.38 v1(98.89,82.41) ; U1.AF21 95.32,76.24 v1(95.64,76.56) 95.69,76.51 95.69,76.42 U1.AF20 ; U1.T19 96.62,80.28 96.32,79.98 v1(96.32,79.89) 96.28,79.94 96.28,80.05 95.99,80.33 U1.T20
  vias: v1(108.21,88.25) v1(108.44,90.03) v1(108.44,89.39) v1(108.39,88.81) v1(108.8,88.2) v1(109.03,89.95) v1(109.03,89.34) v1(109.03,88.76) v4(105.22,81.5)
VCCPD_VBUS: length 229.1
  TOP w0.254: v1(24.67,46.77) 24.98,47.08 U5.K11 ; U5.J10 U5.J11 ; v1(10.03,64.05) 10.19,63.9 11.94,63.9 12.37,64.33 PR95.1 ; 25.98,46.74 U5.H11
  TOP w0.508: PF11.1 v1(156.24,97.38)
  IN1 w0.508: v1(93.84,112.84) 93.81,112.86 57.18,112.86 55.84,111.52 55.84,96.28 56.35,95.77 v1(56.35,94.68) ; v2(33.73,75.91) 33.53,75.71 33.53,74.64 32.84,73.96 32.84,73.42 32.03,72.61 26.32,72.61 25.27,73.65 13.87,73.65 11.56,71.34 v1(11.56,68.6)
  IN4 w0.508: v1(93.84,112.84) 93.84,112.46 94.22,112.08 98.23,112.08 98.28,112.13 101.66,112.13 102.52,112.99 119.82,112.99 121.7,111.11 123.89,111.11 124.95,112.18 149.11,112.18 v1(150.17,113.25) ; v2(33.73,75.91) 34.83,74.82 41.54,74.82 45.88,79.16 47.13,79.16 54.92,86.96 54.92,90.76 55.35,92.38 55.89,93.51 v1(56.35,94.68)
  BOTTOM w0.254: v1(10.03,64.05) 9.45,64.05 9.23,64.27 PU4.2
  BOTTOM w0.381: PR99.1 6.33,67.1 PR97.1 6.35,67.45 6.66,67.76 7.14,67.76 v1(7.47,68.09)
  BOTTOM w0.508: v1(156.24,97.38) 156.71,96.91 159.04,96.91 163.68,101.54 163.68,111.47 162.19,112.96 157.6,112.96 155.4,110.76 150.98,110.76 150.06,111.68 150.06,113.1 150.17,113.21 v1(150.17,113.25) ; PR82.1 15.55,74.39 14.96,74.97 13.57,74.97 12.65,74.06 12.65,73.07
  vias: v1(9.22,67.38) v1(9.86,68.04) v1(9.86,67.35) v1(10.19,68.6) v1(10.52,68.04) v1(10.47,67.38) v1(10.9,68.62) v1(18.14,45.12) v1(18.17,45.71) v1(18.2,44.51) v1(18.58,46.16) v1(18.7,45.45) v1(18.7,44.84) v1(19.11,45.91) v1(22.61,45.97) v1(23.22,45.97) v1(23.85,45.97) v3(11.41,67.33) v3(17.65,45.43)
VCCPD_VBUS_1: length 12
  TOP w0.305: 18.58,68.02 PR20.2
  IN1 w0.381: v2(14.89,68.09) 14.58,68.39 13.49,68.39 11.89,66.79 9.17,66.79 8.13,65.75 v1(8.13,62.17)
  vias: v2(15.32,67.45) v2(15.52,68.09) v2(15.95,67.45) v2(16.16,68.09) v2(16.59,67.45) v2(16.82,68.09) v2(17.25,67.45) v2(17.48,68.09) v3(16.23,70.88)
VCCPD_VBUS_CONN: length 4.5
  TOP w0.381: 7.44,62.45 7.27,62.27 5.89,62.27 R508.1
  BOTTOM w0.381: JTYC1.9 7.86,56.01 JTYC1.16 ; JTYC1.4 7.86,53.51 JTYC1.21
  vias: v1(8.79,62.25) v1(8.89,61.66) v1(9.3,61.21) v1(9.42,62.25) v1(9.63,61.69) v1(10.11,61.31) v1(10.67,61.08) v3(10.39,62.35)
VCCRE: length 17.1
  TOP w0.203: 235.85,50.8 236.36,50.28 U24.6
  TOP w0.254: R343.2 234.78,48.61 R345.2 234.37,48.61 ; 226.76,52.16 226.74,52.17 R383.1
  TOP w0.305: 234.44,49.03 R343.2 ; R342.2 240.59,51.79 241.31,51.07 241.31,49.87 240.85,49.42 v1(240.7,49.42) 240.69,49.4 R344.2 240.17,49.06 ; 227.31,51.03 C273.1 C90.2 ; 234.79,48.28 R345.2 ; R358.2 233.51,48.88 v1(233.51,48.33) ; C91.2 227.1,49.8 ; 227.61,49.42 R357.2 ; v1(233.99,50.31) 233.93,50.31 233.64,50.61 R356.2 R365.2 ; C79.2 235.48,51.17 235.85,50.8 ; C90.2 228.66,51.37 ; C90.2 227.9,51.03 ; R351.1 227.95,50.33 ; C78.2 234.29,48 ; C272.1 234.85,48 ; 226.37,51.83 R383.1
  TOP w0.381: v1(228.88,45.94) 228.88,46.4 229.03,46.55 R359.2
  TOP w0.508: v1(234.6,52.97) 234.6,52.74 235.09,52.25 C77.2 235.09,51.34 C79.2
  vias: v1(227.85,50.51) v1(240.62,48.83)
VCCSA: length 14
  TOP w0.305: v1(93.41,83.76) 93.8,83.36 CC95.2 94.32,82.94 RC87.2 ; CC96.2 CC97.2 91.49,77.54 91.75,77.81 v1(91.75,78.04) 91.41,78.04 PC534.2 ; 91.73,83.12 CC93.2 92.02,83.34 92.01,83.35
  TOP w0.381: PC532.2 91.41,81.85 v1(91.75,81.85) ; v1(91.75,79.31) 91.41,79.31 PC535.2 ; v1(91.75,80.58) 91.41,80.58 PC533.2
  BOTTOM w0.254: PL404.2 122.3,82.92 122.35,82.87 123.66,82.87 123.91,83.13 123.91,85.85 PR468.1
  vias: v1(91.12,83.68) v1(91.12,83.1) v1(92.36,74.11) v1(93.23,74.1) v2(116.71,83.01) v2(116.71,82.34) v2(117.08,81.77) v2(117.43,83.02) v2(117.46,82.33) v2(117.94,81.75) v2(118.14,83.02) v2(118.25,82.36) v3(118.64,81.42) v4(119.59,85.71)
VCCSA_SENSE: length 41.8
  TOP w0.102: v1(96.01,84.19) 96.2,84.19 v4(96.51,83.88)
  TOP w0.254: v1(96.01,84.19) 95.96,84.19 95.01,83.24 RC87.1
  IN3 w0.254: v1(96.01,84.19) 95.79,84.19 95.51,84.47 95.51,87.31 96.97,88.76 105.55,88.76 108.39,91.61 110.27,91.61 111.56,90.31 111.56,89.42 113.44,87.53 116.22,87.53 117.65,88.97 120.3,88.97 121.57,90.24 122.57,90.24 123.33,91 v1(123.33,91.36)
  BOTTOM w0.203: v1(123.33,91.36) 123.3,91.36 123.01,91.65 PC426.2 122.71,91.91 122.71,91.92 PC424.1 122.39,92.17 122.43,92.2 PR435.1
  BOTTOM w0.254: U1.H20 96.27,84.26 96.08,84.26 v1(96.01,84.19)
VCCST: length 340.9
  TOP w0.102: U16.B11 v1(228.75,73.7)
  TOP w0.305: Q34.A2 124.54,89.25 C293.1
  TOP w0.381: 130.82,95.29 130.16,95.29 129.78,95.67 128,95.67 127.19,94.86 127.19,93.21 126.38,92.4 122.81,92.4 v3(122.4,91.99) 122.15,91.99 121.81,91.65 121.81,89.02 121.46,88.68 121.46,87.7 122.2,86.96 123.67,86.96 124.54,87.83 C293.1 ; 130.82,95.29 130.9,95.29 131.81,96.2 131.81,97.8 131.19,98.42 129.44,98.42 129.01,98.85 129.01,102.73 127.56,104.18 127.56,105.84 127.01,106.39 v1(127.01,108.98) ; 130.82,95.29 131.37,94.73 v1(131.37,94.51) ; v1(231.12,63.97) 230.54,63.39 228.56,63.39 228.03,63.92 228.03,64.96 226.98,66 226.98,68.26 v1(226.93,68.31)
  IN1 w0.381: v1(206.22,103.67) 205.79,104.11 205.79,108.35 204.78,109.36 183.6,109.36 182.84,108.6 170.04,108.6 166.25,112.38 158.38,112.38 154.27,108.27 137.97,108.27 136.4,106.7 134.55,106.7 132.97,108.27 127.72,108.27 v1(127.01,108.98)
  IN2 w0.381: v1(206.22,103.67) 207.95,101.95 213.89,101.95 218.75,106.8 227.99,106.8 229.41,105.38 229.41,103.83 232.24,101 236.46,101 241.54,95.92 241.54,92.59 242.42,91.71 243.28,91.71 244.08,90.92 250.42,90.92 250.77,90.57 251.82,90.57 253.17,89.22 253.17,88.15 254.8,86.52 256.27,86.52 258.05,84.75 258.05,81.9 256.63,80.48 256.63,79.49 254.52,77.38 254.52,74.38 254.23,74.09 254.23,72.39 252.97,71.13 251.22,71.13 250.83,71.51 249.41,71.51 248.35,70.45 248.35,67.25 247.23,66.13 246.62,66.13 244.66,64.17 242.2,64.17 241.74,63.72 237.83,63.72 237.25,63.13 231.96,63.13 v1(231.12,63.97)
  IN3 w0.381: v1(69.83,95.64) 69.68,95.64 69,94.96 69,92.46 69.96,91.49 70.8,91.49 72.32,93.02 72.32,93.69 72.91,94.27 v1(73.06,94.27) 73.17,94.16 74.42,94.16 75.73,92.85 77.96,92.85 79,91.81 79.94,91.81 80.35,91.39 80.35,91.24 81.11,90.48 81.11,90.26 81.75,89.62 82.94,89.62 83.58,90.26 85.89,90.26 86.45,90.82 86.45,93.26 87.79,94.6 92.67,94.6 93.48,93.79 v1(93.86,93.79) 94.43,93.79 95.83,92.39 99.77,92.39 100.05,92.11 104.68,92.11 107.97,95.4 117.14,95.4 119.29,93.26 123.05,93.26 123.85,94.06 124.89,94.06 125.76,93.18 130.22,93.18 131.37,94.33 v1(131.37,94.51) ; v1(228.75,73.7) 228.75,71.68 226.76,69.68 226.76,69.05 226.93,68.87 v1(226.93,68.31)
  BOTTOM w0.305: RC161.2 RC110.2 69.43,93.79 69.43,95.24 v1(69.83,95.64)
  BOTTOM w0.381: RC76.1 71.17,93.74 RC77.2 RC15.2 71.82,94.14 72.2,94.52 72.81,94.52 v1(73.06,94.27) ; v1(131.37,94.51) 131.58,94.71 PC401.1 131.58,95.03 PR404.1 131.59,95.66 PR401.1
  vias: v4(93.53,94.91)
VCCST_CPU: length 14.8
  TOP w0.254: CC30.2 93.89,82.28 v1(94.07,82.47)
  TOP w0.305: 96.91,94.13 CC28.2
  IN3 w0.508: v1(97.06,89.81) 95.51,89.81 93.81,88.11 93.81,85.05 94.46,84.4 94.46,84.35 94.75,84.06 94.75,83.34 94.07,82.67 v1(94.07,82.47)
  BOTTOM w0.203: v1(97.06,89.81) U1.A18
  BOTTOM w0.254: v1(94.07,82.47) 94.1,82.47 U1.K21 95.36,83.73 95.92,83.73 U1.K20
  vias: v4(96.1,93.89)
VCCST_PWRGD: length 8.6
  TOP w0.102: v1(69.05,91.6) 69.17,91.73 RC73.1 69.54,94.16 69.89,94.51 QC3.1 69.89,94.9 v4(69.34,95.45)
  BOTTOM w0.076: v1(69.05,91.6) 69.05,91.56 70.75,89.85 70.75,88.74 U1.B65
VCCSTG: length 322.6
  TOP w0.102: v3(95.05,96.54) 94.97,96.46 C294.1
  TOP w0.203: RC138.1 RC139.1 189.16,57.29 189.52,56.93 189.52,56.22 189.11,55.82 188.27,55.82 187.08,54.62 187.08,53 v1(186.95,52.87) ; RC112.2 189.05,59.14 189.62,59.14 190.03,59.55 191.14,59.55 192.53,58.16 192.53,56.19 191.68,55.33 190.92,55.33 190.23,54.65 190.23,53.1 v1(189.34,52.21) ; Q199.2 240.54,67.81 241.26,67.09 v1(241.28,67.09) ; Q35.A2 93.51,96.39 C294.1
  TOP w0.254: 91.45,88.43 91.45,90.39 93.2,92.14 93.2,94.5 93.02,94.69 93.02,95.57 93.58,96.13 C294.1 ; 89.06,88 89.06,88.53 87.59,90 87.59,92.72 86.98,93.33 86.98,93.99 88.15,95.16 88.15,97.01 87.03,98.13 v3(84.01,98.13) 81.09,98.13 78.52,95.57 71.89,95.57 71.33,96.13 69.05,96.13 68.75,95.83 v1(68.75,95.52)
  IN3 w0.254: v1(236.15,66.05) 236.15,65.29 227.14,56.27 226.2,56.27 224.44,54.52 224.44,52.48 221.21,49.24 217.66,49.24 216.98,48.55 213.57,48.55 212.38,49.75 208.76,49.75 206.49,47.47 206.49,47.08 205.8,46.39 203.44,46.39 203.34,46.49 196.96,46.49 192.06,51.4 190.41,51.4 189.59,52.21 v1(189.34,52.21) 189.34,51.78 186.45,48.88 98.08,48.88 96.28,50.69 94.32,50.69 91.72,48.08 65.68,48.08 52.77,61 52.77,68.21 54.44,69.89 54.44,79.54 68.47,93.57 68.47,95.23 v1(68.75,95.52)
  IN4 w0.203: 241.28,67.14 v1(241.28,67.09)
  IN4 w0.508: v1(236.15,66.05) 236.15,67.11 236.78,67.73 237.83,67.73 238.44,68.34 240.09,68.34 241.28,67.14
  BOTTOM w0.203: v1(186.95,52.87) 187.44,53.35 188.83,53.35 189.34,52.84 v1(189.34,52.21) ; RC14.2 68.94,95.33 v1(68.75,95.52)
VCCSTG_CPU: length 2.7
  TOP w0.305: 95.54,85.61 CC29.2 ; CC29.2 95.83,85.34 ; CC29.2 95.83,86.11
  BOTTOM w0.203: U1.A22 94.5,88.89 94.5,89.39 v1(94.17,89.72)
  BOTTOM w0.254: v1(96.86,84.77) 96.78,84.77 U1.G20
  vias: v3(94.07,85.03)
VDD10: length 4.8
  TOP w0.254: U21.A2 253.89,72.73 255.16,71.46 D36.1 256.08,70.56 C196.2 256.57,70.55 256.57,70.56 257.09,70.56 C201.2
VDDA: length 13.4
  TOP w0.178: v1(201.42,71.94) 200.42,72.95 PU101.7
  TOP w0.203: v1(201.23,78.12) 201.01,78.33 PR154.2
  TOP w0.254: PR147.2 200.78,68.8 PR168.1 200.99,69.37 201.3,69.68 PR136.2 201.93,70.69 PC165.1 201.42,71.35 v1(201.42,71.94)
  IN4 w0.381: v1(201.42,71.94) 201.42,73.38 201.69,73.65 201.69,75.78 201.23,76.24 v1(201.23,78.12)
VDDPALW_PWRGD: length 1.5
  BOTTOM w0.305: v4(150.4,98.46) 150.71,98.16 PR738.2 151.18,97.61 PR749.1
VDDSPD: length 5.1
  TOP w0.254: v1(86.8,33.06) 86.8,33.95 87.06,34.2 CD31.2 RD12.2 87.33,34.82 CD30.1
  BOTTOM w0.254: J21.255 86.78,33.08 v1(86.8,33.06)
VINT20_IN: length 25.2
  TOP w0.254: PR196.2 198.23,67.91 197.14,66.81 195.46,66.81 194.94,66.29 194.15,66.29 193.51,65.65 193.51,64.86 192.97,64.32 185.63,64.32 183.4,66.56 183.4,68.36 v1(183.27,68.49) ; PR25.2 22.57,72.42 22.21,72.06 PR92.2
  BOTTOM w0.114: PR158.1 183.12,70.93 183.32,70.73 183.32,68.54 v1(183.27,68.49)
  vias: v1(179.43,71.21) v1(179.43,70.62) v1(179.77,71.72) v1(180.12,71.21) v1(180.12,70.62) v1(180.45,71.72) v1(180.76,71.18) v1(180.76,70.6) v2(30.74,75.76) v2(30.76,75.12) v2(31.12,74.57) v2(31.45,75.76) v2(31.47,75.12) v2(32.11,75.73) v2(32.13,75.1) v2(32.77,75.76) v2(32.79,75.12) v2(152.54,110.12) v2(152.54,109.49) v2(153.17,110.12) v2(153.17,109.49) v2(153.81,110.12) v2(153.81,109.49) v2(154.44,110.12) v2(154.44,109.49) v3(31.01,73.09)
VSS_SENSE: length 70.5
  TOP w0.254: v1(88.68,86.61) 88.68,86.22 89.16,85.73 RC82.1
  IN3 w0.254: v1(88.68,86.61) 88.68,87.74 89.66,88.72 90.14,88.72 90.84,89.42 90.84,90.28 92.52,91.96 93.33,91.96 94.59,90.7 97.47,90.7 98.29,89.88 104.91,89.88 105.39,90.36 105.39,91.07 108.76,94.44 116.65,94.44 119.8,91.28 120.38,91.28 121.75,92.65 130.35,92.65 131.98,94.28 131.98,97.83 133.73,99.59 134.77,99.59 135.33,100.14 135.33,100.86 134.72,101.46 131.88,101.46 v1(131.09,100.68)
  BOTTOM w0.254: v1(88.68,86.61) 88.48,86.4 U1.E33
  BOTTOM w0.305: v1(131.09,100.68) 131.09,100.65 130.55,100.12 PC406.2 129.54,100.12 129.37,100.29 PC407.1 129.13,99.74 PR415.1
VSSGT_SENSE: length 87
  IN3 w0.203: v1(73.55,93.59) 73.55,93.48 73.87,93.15 74.36,93.15 76.44,91.07 77.25,91.07 77.73,90.59 77.73,90.08 80.15,87.67 81.62,87.67 82.18,88.23 85.51,88.23 87.13,89.85 88.81,89.85 89.16,90.21 90.15,90.21 92.29,92.34 93.48,92.34 94.75,91.07 97.55,91.07 97.88,90.74 99.54,90.74 100.12,91.33 105.11,91.33 108.54,94.75 116.81,94.75 119.31,92.25 v1(119.59,92.25)
  BOTTOM w0.127: 65.61,84.22 66.08,84.22 66.4,84.54 67.72,84.54 U1.J69
  BOTTOM w0.203: PC416.1 PR424.1 120.3,92.9 120.37,92.84 PC413.1 120.37,92.56 120.06,92.25 v1(119.59,92.25)
  BOTTOM w0.254: 65.61,84.22 62.74,84.22 RC92.1 62.57,84.11 61.54,84.11 61.23,84.43 61.23,85.16 64.48,88.42 64.48,94.57 v4(64.58,94.66) 66.09,96.18 72.64,96.18 73.61,95.2 73.61,94.18 73.55,94.12 v1(73.55,93.59)
VSSSA_SENSE: length 39.6
  TOP w0.254: RC91.2 95.89,84.64 v1(96,84.75)
  IN3 w0.254: v1(96,84.75) 95.87,84.88 95.87,87.18 97.11,88.42 105.71,88.42 105.84,88.54 108.55,91.26 110.11,91.26 111.18,90.19 111.18,89.3 113.28,87.2 116.36,87.2 117.79,88.63 120.6,88.63 121.79,89.83 122.63,89.83 123.96,91.16 v1(123.96,91.38)
  BOTTOM w0.203: PC427.1 PR438.1 PC426.1 123.6,91.75 123.96,91.38 v1(123.96,91.38)
  BOTTOM w0.254: v1(96,84.75) 95.84,84.75 U1.H21
1R2A_BST:
  vias: v4(122.21,62.45)
1R2A_LG: length 9.7
  IN4 w0.762: 119.44,53.48 119.44,53.5 126.22,60.29 126.25,60.29 126.25,60.39
  vias: v2(119.44,53.02) v2(120.2,52.97) v2(126.09,61.99) v2(126.25,61.33)
1R2A_LX: length 8.9
  IN4 w0.762: 116.67,55.92 119.29,55.92 123.73,60.36
  vias: v1(115.02,55.92) v2(115.81,55.92) v2(124.09,60.64) v2(124.52,61.12) v4(115.63,50.28)
1R2A_SW: length 36.6
  IN4 w0.254: v2(106.38,51.5) 107.71,50.18 127.49,50.18 127.9,50.58 127.9,58.78 127.59,59.09 v1(127.59,63.36)
  BOTTOM w0.254: PU301.9 127.03,63.65 127.11,63.57 127.31,63.57 127.52,63.36 v1(127.59,63.36)
  vias: v2(93.79,57.42) v2(93.79,56.73) v2(93.81,56.07) v2(93.81,55.41) v2(94.45,57.42) v2(94.55,56.73) v2(94.57,56.07) v2(94.57,55.41) v2(95.08,57.42) v2(95.31,56.73) v2(95.34,56.07) v2(95.34,55.41) v2(95.73,57.42) v2(95.97,56.76) v2(95.97,56.12) v2(96.1,55.41) v2(103.95,55.82) v2(104.45,56.91) v2(104.48,56.25) v2(104.45,55.43) v2(105.09,57.49) v2(105.09,56.81) v2(105.11,56.15) v2(105.11,55.49) v2(105.11,54.85) v2(105.75,57.52) v2(105.75,56.83) v2(105.77,56.17) v2(105.77,55.51) v2(105.77,54.88) v2(106.41,57.49) v2(106.41,56.81) v2(106.44,56.15) v2(106.44,55.49) v2(106.44,54.85) v2(123.5,66.71) v2(123.91,67.22) v2(124.19,66.64) v4(93.24,57.5)
1R2A_UG: length 7.4
  IN4 w0.762: 122.7,61.19 120.76,59.24 v2(116.06,59.24)
  vias: v2(115.3,59.22) v2(123.1,61.3) v2(123.61,61.68) v4(115.13,60.16)
2R5A_PWRGD: length 59.4
  IN3 w0.203: v1(147.3,57.67) 146.87,58.1 146.16,58.1 145.45,57.39 136.84,57.39 135.47,58.76 134.2,58.76 133.74,58.31 130.56,58.31 129.07,59.8 128.3,59.8 127.34,60.77 126.25,60.77 124.84,59.36 123.52,59.36 121.07,61.81 v1(119.9,61.81)
  IN4 w0.203: v1(158.12,67.91) 158.35,67.68 158.38,67.68 158.38,63.49 156.5,61.61 154.37,61.61 153.86,61.1 v1(151.44,61.1)
  BOTTOM w0.203: v1(151.44,61.1) 150.73,61.1 v1(147.3,57.67) ; PR751.1 159.6,68.08 159.42,67.91 v1(158.12,67.91) 157.57,68.47 154.49,68.47 153.96,67.93 153.96,67.37 154.5,66.83 PU701.4 ; v1(119.9,61.81) 119.97,61.89 PR306.1
3FP_DRV: length 106.9
  TOP w0.152: v1(163.69,62.78) 163.98,62.78 164.19,62.99 C180.2 165.17,62.72 v3(165.9,62.72) 166.3,62.32 166.3,61.73 167.85,60.18 170.84,60.18 172.06,61.4 175.42,61.4 176.38,60.44 186.32,60.44 187.39,61.51 187.39,61.68 187.7,62 193.11,62 196.07,64.96 198.18,64.96 200.01,63.13 200.82,63.13 v1(200.87,63.08) ; U21.D3 v1(252.56,74.74)
  IN4 w0.152: v1(252.56,74.74) 251.72,74.74 250.35,73.37 249.36,73.37 248.7,74.03 245.73,74.03 245.32,74.43 243.49,74.43 242.58,73.52 242.58,72.8 240.13,70.34 239.1,70.34 237.36,68.6 228.99,68.6 227.99,67.6 224.06,67.6 221.62,65.16 221.62,62.67 220.81,61.86 218.83,61.86 218.37,61.4 216.09,61.4 215.66,61.84 213,61.84 212.44,61.28 210.7,61.28 209.71,62.27 208.39,62.27 207.7,61.58 206.51,61.58 205.67,60.74 202.4,60.74 201.79,61.35 201.79,62.12 200.87,63.03 v1(200.87,63.08)
  BOTTOM w0.152: v1(163.69,62.78) 163.31,62.78 163.04,63.04 R231.2
3FP_ON: length 119.8
  TOP w0.102: U21.J5 v1(251.72,79.5) ; D31.2 167.22,65.51 R232.2 C181.2 v3(168.18,63.92) 168.46,63.92 169.35,63.03 172.35,63.03 172.85,62.52 174.05,62.52 175.6,64.07 180.58,64.07 182.41,62.24 184.95,62.24 185.38,62.67 192.39,62.67 194.08,64.36 194.08,65.07 194.51,65.51 195.22,65.51 195.59,65.87 198.66,65.87 v1(200.16,64.38)
  IN4 w0.076: v1(251.72,79.5) 251.61,79.5 249.67,81.44 249.67,83.68 250.3,84.31 250.3,85.69 249.23,86.75 247.2,86.75 246.54,87.41 246.16,87.41 245.2,86.45 245.2,84.8 242.48,82.08 242.48,80.5 241.39,79.41 241.39,78.09 241.12,77.83 241.12,77.22 242.05,76.29 242.05,73.31 240.93,72.2 236.84,72.2 234.96,70.32 230.51,70.32 230.31,70.52 224.32,70.52 222.84,69.05 222.84,67.09 221.08,65.33 221.08,62.83 220.47,62.22 218.66,62.22 218.36,61.92 216.15,61.92 215.88,62.19 212.86,62.19 212.38,61.71 210.79,61.71 209.78,62.72 208.36,62.72 207.67,62.04 203.84,62.04 202.03,63.86 200.68,63.86 v1(200.16,64.38)
5M_3M_PWRG: length 106.1
  TOP w0.102: D714.1 v3(244.97,68.91) 244.47,68.91 244.28,69.1 R307.1 242.96,68.64 241.46,68.64 241.26,68.85 241.25,68.85 v1(241.07,69.03)
  IN4 w0.076: v1(155.03,73.47) 155.48,73.93 157.16,73.93 159.17,71.92 159.17,69.79 162.52,66.43 182.38,66.43 183.22,65.59 197.8,65.59 201.56,61.83 201.56,61.28 202.41,60.44 206.08,60.44 206.99,61.35 207.74,61.35 208.45,62.06 209.65,62.06 210.19,61.52 210.19,61.15 210.35,61 212.43,61 213.01,61.58 215.55,61.58 215.96,61.18 218.45,61.18 218.93,61.66 220.96,61.66 221.95,62.65 221.95,64.87 224.38,67.3 228.04,67.3 229.14,68.39 237.63,68.39 238.13,68.9 240.93,68.9 v1(241.07,69.03)
  BOTTOM w0.102: PR222.2 155.32,74.05 155.03,73.76 v1(155.03,73.47)
+VTT_REFP: length 1.4
  BOTTOM w0.102: v3(127.61,67.99) 126.73,67.11 PC305.1
-AOU_IFLG: length 70.9
  TOP w0.102: U12.9 277.11,79.43 v1(277.5,79.03) ; U16.H9 v1(231.11,79.25) ; R158.1 v1(225.95,79.95)
  IN3 w0.081: v1(247.08,73.1) 247.08,75.44 245.74,76.78 244.73,76.78 242.63,78.87 242.63,79.47 241.55,80.56 240.93,80.56 240.39,81.09 240.39,81.55 238.87,83.07 235.17,83.07 233.91,81.81 233.91,79.9 233.67,79.66 231.51,79.66 v1(231.11,79.25) ; v1(255.41,73.67) 255.79,73.29 258.89,73.29 261.48,75.88 264.4,75.88 265.52,77 265.52,77.76 266.05,78.29 266.96,78.29 268.74,76.52 273.34,76.52 274,75.86 274.63,75.86 275.12,76.34 275.12,76.82 277.33,79.03 v1(277.5,79.03)
  IN4 w0.076: v1(231.11,79.25) 230.69,79.67 226.24,79.67 v1(225.95,79.95)
  BOTTOM w0.102: v1(247.08,73.1) 248.56,71.61 249.92,71.61 251.16,72.86 251.16,73.93 251.57,74.33 254.24,74.33 254.9,73.67 v1(255.41,73.67)
-BATLOW: length 180.8
  TOP w0.102: U16.C1 237.67,74.87 238.26,74.28 238.26,73.58 239,72.84 R206.2 239.88,73.3 v1(240.57,73.3)
  IN1 w0.076: v1(240.34,62.06) 240.09,62.06 239.55,62.6 223.18,62.6 220.79,60.21 215.03,60.21 214.39,60.85 213.19,60.85 212.59,60.25 210.77,60.25 210.35,59.83 187.16,59.83 186.04,60.95 181.67,60.95 180.68,61.94 180.68,62.37 180.45,62.6 177.78,62.6 177.48,62.9 175.42,62.9 174.53,62.01 171.99,62.01 171.23,62.78 167.37,62.78 167.07,62.47 164.23,62.47 163.92,62.15 161.62,62.15 161.22,62.55 158.98,62.55 156.17,59.73 156.17,58.89 155.6,58.32 145.31,58.32 144.33,57.34 137.65,57.34 135.96,55.65 126.34,55.65 123.99,58 123.53,58 120.48,61.05 120.48,62.88 118.94,64.41 118.94,66.05 116.44,68.56 111.5,68.56 109.22,66.28 107.93,66.28 104.8,63.14 103.11,63.14 100.89,65.37 100.89,69.56 v1(100.55,69.9)
  IN3 w0.081: v1(240.34,62.06) 240.37,62.1 240.37,62.93 242.42,64.98 242.42,71.45 v1(240.57,73.3)
  BOTTOM w0.076: U1.AU13 100.27,69.61 v1(100.55,69.9)
-BEEP_ENABLE: length 101.2
  TOP w0.102: R124.2 231.83,85.31 TP15.1 232.17,84.98 v1(232.17,84.09) ; v1(263.55,53.15) 263.55,55.21 262.51,56.25 262.51,59.07 263.37,59.94 v3(263.37,60.55) 263.81,60.98 263.81,63.67 262.26,65.22 262.26,69.36 261.37,70.25 v1(261.06,70.25) ; v1(283.85,54.47) 283.85,54.81 Q228.2 ; U16.K5 v1(234.31,80.85)
  IN4 w0.076: v1(235.57,63.78) 235.58,63.78 236.15,63.21 243.44,63.21 244.13,62.52 251.25,62.52 251.98,63.25 251.98,63.56 252.99,64.56 253.92,64.56 257.25,67.9 257.25,68.98 258.78,70.5 260.81,70.5 v1(261.06,70.25)
  IN4 w0.081: v1(263.55,53.15) 264.67,52.03 275.46,52.03 277.43,54 278.02,54 278.75,54.74 278.75,54.87 279.06,55.17 283.15,55.17 v1(283.85,54.47)
  BOTTOM w0.102: v1(232.17,84.09) 232.09,84.01 232.09,80.86 232.52,80.43 233.88,80.43 v1(234.31,80.85) 234.31,80.65 234.71,80.24 234.71,78.27 233.9,77.46 233.9,75.82 234.03,75.69 234.52,75.69 234.71,75.5 234.71,74.04 234.96,73.79 234.96,72.07 234.34,71.45 234.34,65.96 235.57,64.73 v1(235.57,63.78)
-CHG_PROCHOT: length 20.6
  TOP w0.102: R2574.1 240.45,67.26 Q199.1 240.14,68.92 v1(240.55,69.33) ; U16.H7 v1(232.71,79.25)
  IN3 w0.081: v1(240.55,69.33) 239.96,69.91 238.92,69.91 238.21,70.62 238.21,72.2 239.3,73.29 239.3,74.76 238.19,75.88 238.19,76.34 236.31,78.22 236.31,78.68 236.1,78.88 233.08,78.88 232.71,79.25 v1(232.71,79.25)
-CL_RST_WLAN: length 134.9
  IN3 w0.081: v1(113.4,85.51) 113.99,84.92 114.87,84.92 115.15,84.64 115.15,80.96 116.47,79.64 119.11,79.64 120.78,77.96 126.2,77.96 126.91,77.25 130.59,77.25 130.92,76.92 130.92,75.68 135.16,71.44 135.16,69.43 135.57,69.02 137.07,69.02 137.25,69.2 139.07,69.2 141.49,66.79 145.41,66.79 147.11,68.48 158.41,68.48 159.01,67.88 160.31,67.88 160.87,68.44 171.72,68.44 175.77,72.48 180.06,72.48 181.26,73.68 191.49,73.68 194.31,70.87 199.69,70.87 200.06,71.23 201.66,71.23 203.41,72.99 206.28,72.99 206.66,73.37 v1(206.69,73.37)
  BOTTOM w0.102: U1.G1 107.39,85.66 108.92,85.66 109.89,86.63 RC23.1 110.47,87.49 110.75,87.77 111.2,87.77 111.68,87.29 111.68,86.87 v4(111.74,86.8) 112.11,86.8 v1(113.4,85.51) ; J32.38 205.55,60.26 205.31,60.5 205.31,62 207.07,63.77 207.07,66.79 207.45,67.17 207.45,71.34 206.69,72.1 v1(206.69,73.37)
-CLKREQ_DEVSLP: length 20.2
  TOP w0.102: v1(220.35,47.18) 220.46,47.28 220.46,47.81 220.81,48.17 220.81,50.38 221.12,50.69 221.52,50.69 221.75,50.46 U7.1 222.06,51.16 221.97,51.25 221.42,51.25 221.11,51.56 221.11,52.23 221.52,52.64 221.52,52.88 222.18,53.53 v3(222.18,53.74) 222.18,53.92 222.02,54.07 221.5,54.07 Q5.3 220.61,53.65 220.48,53.78 219.69,53.78 219.48,53.57 R426.1
  IN3 w0.081: v1(220.35,47.18) 221.98,47.18 223.15,48.35 225.15,48.35 v1(225.43,48.07)
  BOTTOM w0.102: J1.23 224.95,49.11 225.43,48.63 v1(225.43,48.07)
-CLKREQ_PCIE0: length 235.4
  TOP w0.102: U15.2 284.07,85.7 284.67,85.1 R112.1 285,85.05 286.01,84.04 v1(286.01,83.93)
  IN3 w0.081: v1(196.61,48.4) 196.07,48.4 192.57,51.9 192.56,51.9 192.45,52.01 190.75,52.01 188.82,53.94 187.92,53.94 186.68,55.18 180.29,55.18 179.69,54.58 179.69,51.95 178.62,50.88 178.3,50.88 140.89,50.88 139.43,52.34 137.8,52.34 136.89,51.42 v1(136.46,51.42) ; v1(217.25,45.53) 218.55,44.23 228.53,44.23 229.15,44.85 231.87,44.85 239.24,44.85 239.35,44.74 242.6,44.74 249.18,51.32 252.14,51.32 257.65,56.83 261.57,56.83 266.61,61.87 266.61,62.47 269.18,65.04 272.63,65.04 278.66,71.07 278.66,72.09 281.31,74.73 281.31,81.73 282.24,82.66 283.83,82.66 284.31,83.15 285.23,83.15 v1(286.01,83.93)
  IN4 w0.076: v1(217.25,45.53) 216.18,45.53 211.76,49.95 208.71,49.95 206.19,47.43 206.19,46.97 205.74,46.52 199.95,46.52 198.1,48.38 196.63,48.38 v1(196.61,48.4) ; v1(102.42,70.57) 102.53,70.57 102.79,70.31 102.79,69.83 103.17,69.45 106.22,69.45 107.67,70.9 110.27,70.9 111.98,69.19 117.28,69.19 117.86,69.77 118.67,69.77 119.24,69.19 123.54,69.19 126.48,66.26 126.48,65.85 126.86,65.47 128.23,65.47 128.92,64.78 128.92,64.44 129.11,64.25 129.11,62.97 129.46,62.61 129.46,61.65 130.26,60.85 130.26,56.98 131.54,55.7 133.17,55.7 136.46,52.41 v1(136.46,51.42)
  BOTTOM w0.076: U1.AR10 102.08,70.91 v1(102.42,70.57)
-CLKREQ_PCIE1: length 149.3
  TOP w0.102: v1(215.35,50.48) 213.57,50.48 211.58,52.47 211.58,53.66 212.27,54.35 v4(212.27,55.06) 212.27,55.8 211.24,56.83 211.24,59.5 211.49,59.75 211.93,59.75 212.12,59.95 R108.1 212.42,60.38 213.18,60.38 213.23,60.43 v1(213.33,60.43)
  IN3 w0.081: v1(140.24,53.28) 140.47,53.5 159.88,53.5 160.18,53.81 163.23,53.81 164.3,52.74 175.62,52.74 179.22,56.34 192.13,56.34 193.56,54.91 193.56,52.67 195.92,50.3 200.29,50.3 202.32,48.27 204.1,48.27 204.38,48.55 205.64,48.55 208.31,51.22 214.61,51.22 v1(215.35,50.48)
  IN4 w0.076: v1(140.24,53.28) 139.86,53.66 136.33,53.66 131.66,58.33 131.66,60.77 130.5,61.92 130.5,63.78 129.9,64.38 129.9,64.64 129.82,64.72 129.82,65.63 129.57,65.88 129.26,65.88 128.4,66.74 127.26,66.74 124.05,69.95 119.61,69.95 119.04,70.53 117.54,70.53 116.96,69.95 112.34,69.95 110.63,71.67 106.92,71.67 105.55,70.29 103.69,70.29 v1(103.34,70.65)
  BOTTOM w0.076: U1.AT7 103.38,70.65 v1(103.34,70.65)
  BOTTOM w0.102: v1(213.33,60.43) 213.23,60.43 213.05,60.25 J32.68
-CLKREQ_PCIE2: length 136.6
  TOP w0.102: v1(205.52,46.98) 205.52,48.27 208.24,50.99 208.85,50.99 208.96,51.1 R370.1 209.61,51.5 v4(209.74,51.37)
  IN4 w0.076: v1(102.42,69.91) 102.3,69.91 101.96,69.58 101.96,69.07 102.17,68.87 106.72,68.87 107.99,70.14 109.14,70.14 110.85,68.43 122.29,68.43 122.84,67.88 122.84,66.64 123.92,65.56 125.12,65.56 126.5,64.17 127.85,64.17 128.35,63.67 128.35,62.91 128.25,62.81 128.25,61.79 129.45,60.59 129.45,56.53 131.1,54.88 131.81,54.88 132.11,54.57 132.11,53.71 137.52,48.3 188.44,48.3 189.53,47.21 191.53,47.21 192.64,48.32 195.53,48.32 196.01,48.81 198.25,48.81 200.1,46.96 205.44,46.96 205.46,46.98 v1(205.52,46.98)
  BOTTOM w0.076: U1.AT8 102.77,70.26 v1(102.42,69.91)
  BOTTOM w0.102: J32.53 209.3,50.91 208.97,50.58 206.18,50.58 205.73,50.14 205.73,47.19 v1(205.52,46.98)
-CLKREQ_PCIE3: length 140.8
  TOP w0.102: UL1.48 214.96,67.19 v1(214.99,67.22) 215.52,66.7 RL1.1
  IN3 w0.081: v1(213.55,74.71) 213.14,74.71 212.68,74.26 212.68,73.82 209.76,70.9 209.76,69.66 208.04,67.93 205.06,67.93 203.51,66.38 202.68,66.38 202.3,66.76 200.51,66.76 200.29,66.53 199.48,66.53 199,66.05 195.19,66.05 195.02,65.88 190.04,65.88 189.31,65.16 182.81,65.16 182.29,65.68 176.35,65.68 176.28,65.74 175.47,65.74 174.91,65.19 169.07,65.19 168.44,64.56 165.37,64.56 164.53,63.72 164.53,62.9 163.51,61.89 159.6,61.89 158.68,60.97 158.68,60.69 156.31,58.32 148.51,58.32 147.43,59.4 144.28,59.4 144.06,59.17 137.9,59.17 136.43,60.64 135.72,60.64 133.99,62.37 129.63,62.37 128.18,63.82 127.19,63.82 125.92,65.09 125.08,65.09 124.37,65.8 122.97,65.8 122.34,66.43 122.34,67.75 122.01,68.08 120.35,68.08 118.37,70.07 112.58,70.07 112.15,70.5 106.08,70.5 104.1,68.52 102.17,68.52 101.96,68.72 101.36,68.72 101.13,68.95 101.13,69.5 v1(101.55,69.91)
  IN4 w0.076: v1(213.55,74.71) 213.85,74.41 213.85,69.13 215.05,67.93 215.05,67.27 v1(214.99,67.22)
  BOTTOM w0.076: U1.AT10 101.88,70.26 101.53,69.91 v1(101.55,69.91)
-CLKREQ_PCIE4: length 146
  TOP w0.102: R52.1 217.25,50.31 v1(217.15,50.41) 217.13,50.43 217.13,52.07 218.04,52.98 R426.2 219.67,52.98 Q5.1
  IN3 w0.081: v1(217.15,50.41) 217.15,50.07 216.62,49.54 213.98,49.54 213.12,50.41 208.59,50.41 205.93,47.74 204.91,47.74 204.56,47.38 201.58,47.38 199.76,49.21 195.84,49.21 192.79,52.27 192.79,54.59 191.81,55.56 180.12,55.56 179.31,54.75 179.31,52.11 178.46,51.26 160.01,51.26 159.37,51.9 157.69,51.9 157.08,51.29 141.02,51.29 139.59,52.72 137.63,52.72 136.76,51.85 136.03,51.85 v1(135.59,51.42)
  IN4 w0.076: v1(102.42,69.28) 102.53,69.18 106.49,69.18 107.83,70.52 110.09,70.52 111.8,68.81 122.93,68.81 124.85,66.89 124.85,66.64 126.4,65.09 127.82,65.09 128.43,64.48 128.43,64.15 128.73,63.85 128.73,62.81 129.08,62.46 129.08,61.5 129.88,60.7 129.88,56.68 131.3,55.26 132.42,55.26 135.59,52.08 v1(135.59,51.42)
  BOTTOM w0.076: v1(102.42,69.28) 102.76,69.61 U1.AU8
-CLKREQ_PCIE5: length 171
  TOP w0.102: v1(240.64,58.01) 240.64,58.62 240.1,59.16 R2746.1
  IN3 w0.081: v1(228.3,60.44) 228.3,60.11 227.06,58.86 225.49,58.86 224.52,57.9 224.16,57.9 222.46,56.2 222.46,55.16 219.59,52.29 217.53,52.29 216.66,51.41 216.66,50.39 216.26,50 214.74,50 213.93,50.81 208.45,50.81 205.79,48.15 204.76,48.15 204.48,47.87 202.04,47.87 200.11,49.8 195.84,49.8 193.17,52.47 193.17,54.75 191.97,55.95 179.49,55.95 175.19,51.65 160.31,51.65 159.67,52.29 157.53,52.29 157.53,52.29 140.57,52.29 139.98,52.88 139.75,53.11 137.47,53.11 v1(137.43,53.07)
  IN4 w0.076: v1(103.39,69.91) 105.75,69.91 107.12,71.28 110.45,71.28 112.16,69.57 117.12,69.57 117.7,70.15 118.87,70.15 119.45,69.57 123.74,69.57 126.96,66.36 128.2,66.36 128.91,65.65 128.91,65.34 129.32,64.92 129.32,64.58 129.52,64.39 129.52,64.2 130.12,63.6 130.12,61.57 130.64,61.05 130.64,57.44 131.89,56.2 133.23,56.2 136.36,53.07 v1(137.43,53.07) ; v1(228.3,60.44) 228.43,60.57 232.44,60.57 233.64,59.37 239.27,59.37 v1(240.64,58.01)
  BOTTOM w0.102: v1(103.39,69.91) 103.69,69.61 U1.AU7 ; v1(240.64,58.01) 240.23,57.6 239.12,57.6 238.35,58.37 J22.52
-CLKRUN: length 277.9
  TOP w0.102: U16.L5 v1(234.31,81.65)
  IN1 w0.076: v1(246.03,59.8) 245.78,60.06 244.92,60.06 243.67,61.3 242.3,61.3 240.66,62.94 223.08,62.94 220.66,60.51 215.16,60.51 214.52,61.16 212.94,61.16 212.45,60.67 210.55,60.67 210.03,60.15 195.96,60.15 195.23,60.87 186.57,60.87 186.19,61.25 181.85,61.25 181.06,62.04 181.06,62.57 179.84,63.79 175.62,63.79 174.23,62.39 172.35,62.39 171.54,63.21 167.22,63.21 166.87,62.86 165.57,62.86 165.12,63.31 163.53,63.31 162.7,62.47 161.78,62.47 161.4,62.85 158.86,62.85 156.51,60.5 155.35,60.5 153.76,58.91 145.09,58.91 144.12,57.94 135.98,57.94 135.28,58.64 133.77,58.64 133.03,57.9 132.37,57.9 131.3,56.83 125.81,56.83 124.06,58.58 123.66,58.58 120.99,61.25 120.99,64.38 119.79,65.58 119.79,65.95 116.72,69.02 111.31,69.02 109.03,66.74 107.63,66.74 104.76,63.87 v1(104.4,63.87)
  IN3 w0.081: v1(234.31,81.65) 235.47,82.82 238.87,82.82 240.04,81.65 240.04,81.06 241.51,79.59 241.51,79.23 242.2,78.55 242.2,78.09 242.6,77.69 243.34,77.69 244.57,76.45 245.67,76.45 246.36,75.75 246.36,71.67 245.4,70.7 245.4,63.76 246.59,62.57 246.59,60.39 246.03,59.83 v1(246.03,59.8)
  IN4 w0.076: v1(234.31,81.65) 235.01,82.36 236.43,82.36 239.58,85.51 239.58,86.5 239.79,86.7 239.79,88.12 239.25,88.66 239.25,91.55 240.09,92.39 240.09,94.02 243.25,97.18 244.67,97.18 247.1,99.61 247.1,101.36 248.07,102.32 248.07,104.08 251.42,107.43 259.21,107.43 264.47,112.69 264.47,131.16 v1(264.25,131.37) 263.81,131.82 263.04,131.82 262.24,131.02 262.24,130.69 260.96,129.4 260.96,128.09 261.16,127.89 v1(261.34,127.89)
  BOTTOM w0.102: RC29.1 104.15,63.61 v1(104.4,63.87) 104.4,64.28 102.61,66.08 102.07,66.08 101.49,66.66 101.49,66.96 101.51,66.98 101.51,67.31 101.46,67.37 101.46,67.96 101.17,68.24 U1.AW11
  BOTTOM w0.127: v1(261.34,127.89) J5.7
-DCIN_PWR_DTCT: length 42.5
  TOP w0.203: D709.1 v1(238.39,87.85) ; PR166.1 204.23,76.72 v1(204.4,76.9)
  BOTTOM w0.203: v1(238.39,87.85) 235.95,90.28 224.32,90.28 221.01,86.98 v3(218.04,86.98) 217.26,86.98 213.29,83.02 211.39,83.02 208.31,79.95 206.54,79.95 205.39,78.8 205.39,77.89 v1(204.4,76.9)
-DOCK_ATTACHD_20: length 2
  TOP w0.254: D707.2 v3(159.08,95.99) 159.08,96.82 PR2.1
-DOCK_ATTACHED_3M: length 99.3
  TOP w0.102: R208.1 227.88,70.53 TP11.1 228.38,71.94 229.55,73.11 v1(229.55,73.69) U16.B10 ; D25.3 162.48,95.21 162.49,95.2 R120.1 162.63,94.37 162.98,94.37 v3(163.35,94) 163.93,94 v1(164.34,94.4)
  IN4 w0.076: v1(164.34,94.4) 164.9,93.84 167.22,93.84 167.62,94.25 167.62,96.92 169.98,99.28 172.04,99.28 174.93,96.39 177.52,96.39 177.83,96.71 177.83,97.34 179.18,98.69 195.82,98.69 199.35,95.16 206.54,95.16 207.98,93.71 218.87,93.71 222.31,90.27 222.31,84.06 221.67,83.42 221.67,81.9 223.07,80.5 223.07,77.8 222.3,77.02 222.3,76.56 222.87,75.98 224.24,75.98 224.6,75.63 226.22,75.63 228.53,73.32 229.17,73.32 v1(229.55,73.69)
-DOCK_ATTACHED_AUX: length 85.9
  TOP w0.102: v1(223.63,84.8) 223.63,84.26 v4(223.35,83.98) 222.34,83.98 222.13,83.78 222.13,82.82 221.97,82.65 R91.1 221.87,82.41 220.84,82.41 220.05,83.2 U14.13 ; v1(163.76,94.43) 163.76,94.68 162.66,95.78 162.22,95.78 D25.2
  IN4 w0.076: v1(163.76,94.43) 163.78,94.43 164.33,94.98 164.68,94.98 172.73,103.04 193.65,103.04 199.93,96.76 212.94,96.76 214.54,95.16 219.85,95.16 224.62,90.39 224.62,88 223.63,87.01 v1(223.63,84.8)
-DOCK_CAP_ID: length 15.9
  TOP w0.102: R1119.2 111.91,78.99 112.49,79.56 112.49,80.82 v1(113.32,81.65)
  BOTTOM w0.102: U1.V1 107.14,79.65 107.29,79.71 107.57,79.71 108.22,80.36 109.46,80.36 109.8,80.7 111.54,80.7 112.35,81.5 113.17,81.5 v1(113.32,81.65)
-DOCK_HP_DCT: length 169.9
  TOP w0.102: v1(278.97,46.19) 279.12,46.34 Q175.2 279.98,46.75 R1868.1
  IN1 w0.076: v1(185.63,96.66) 185.94,96.66 186.31,96.29 186.61,96.29 187.16,95.74 189.19,95.74 190.69,97.24 192.82,97.24 193.33,97.75 196.12,97.75 199.32,94.55 203.62,94.55 206.51,97.45 212.27,97.45 214.81,94.91 218.32,94.91 221.62,98.21 230.36,98.21 232.17,100.02 236.05,100.02 241.51,94.55 244.66,94.55 246.52,92.7 267.87,92.7 268.99,91.58 270.98,91.58 272.5,90.06 272.5,88.53 276.13,84.9 278.78,84.9 279.49,84.2 279.49,82.97 281.71,80.74 v1(281.71,80.46)
  IN3 w0.081: v1(278.97,46.19) 278.21,46.95 277.7,46.95 276.26,48.4 276.26,51.7 275.95,52.01 271.76,52.01 271.43,51.68 267.78,51.68 267.01,52.44 267.01,61.89 269.76,64.63 272.71,64.63 281.89,73.82 281.89,78.91 281.66,79.14 281.66,80.41 v1(281.71,80.46)
  BOTTOM w0.102: v1(185.63,96.66) 185.91,96.66 186.3,96.27 J17.59
-DOCK_MIC_DCT: length 176.2
  TOP w0.254: R951.1 284.15,47.74 QA8.2 284.16,47.06 CA73.2 283.62,47.03 v1(283.41,47.24)
  IN1 w0.076: v1(185.15,97.09) 185.78,97.09 186.27,96.61 186.62,96.61 187.11,96.13 188.81,96.13 190.1,97.42 192.62,97.42 193.15,97.95 196.17,97.95 199.42,94.7 203.45,94.7 206.53,97.78 212.19,97.78 214.86,95.11 218.19,95.11 221.49,98.41 230.16,98.41 232.04,100.29 236.15,100.29 241.61,94.83 244.87,94.83 246.74,92.95 267.98,92.95 269.1,91.83 271.76,91.83 277.56,86.04 277.93,86.04 279.76,84.2 279.76,83.02 282.14,80.64 282.14,79.93 v1(282.07,79.85)
  IN3 w0.081: v1(282.07,79.85) 282.07,79.29 282.32,79.04 282.32,73.94 272.84,64.46 269.86,64.46 267.22,61.81 267.22,52.56 267.9,51.88 271.38,51.88 271.69,52.18 276.06,52.18 276.44,51.8 276.44,48.5 277.81,47.13 279.46,47.13 280.46,46.13 280.46,45.52 280.85,45.13 281.59,45.13 283.41,46.96 v1(283.41,47.24)
  BOTTOM w0.102: v1(185.15,97.09) 185.15,96.56 185.75,95.96 J17.58
-DOCK_PWR_DTCT: length 77.5
  TOP w0.102: v1(243.19,81.8) 243.16,81.83 243.06,81.83 242.75,82.14 D708.1 242.99,82.68 C9197.2
  IN3 w0.081: v1(182.74,96.68) 183.17,96.25 185.1,96.25 187.28,94.07 187.28,93.79 188.17,92.9 198.46,92.9 199.65,94.09 213.55,94.09 215.6,92.04 216.04,92.04 217.33,93.33 225.58,93.33 226.73,92.19 237.27,92.19 v1(238.16,93.08)
  BOTTOM w0.102: J17.54 183.55,96.02 182.89,96.68 v1(182.74,96.68) ; v1(243.19,81.8) 243.19,81.83 243.21,81.85 243.21,82.97 242.6,83.58 242.6,85.58 242.22,85.97 242.22,87.11 241.16,88.18 241.16,88.76 240.53,89.38 239.62,89.38 238.16,90.84 v1(238.16,93.08)
-DOCK_PWR_DTCT_R: length 5.9
  TOP w0.102: D708.2 241.51,82.15 240.12,82.15 240.05,82.22 R440.1 239.68,82.49 239.15,81.95 238.88,81.95 237.4,80.47 U16.K1
-DOCKED0: length 26.2
  TOP w0.305: v1(192.36,107.63) 191.58,108.42 185.48,108.42 v3(183.22,106.16) 182.83,105.77 182.83,104.31 182.09,103.57 173.8,103.57 173.29,104.08 173.29,104.86 v1(173.62,105.19)
  BOTTOM w0.305: v1(173.62,105.19) 173.65,105.23 J17.35 ; J17.1 192.35,107.62 v1(192.36,107.63)
-DRAMRST: length 71
  TOP w0.102: RC154.2 89.34,53.5 v1(89.83,53.01) ; CD29.2 47.64,29.08 v1(47.53,28.96)
  IN4 w0.076: v1(47.53,28.96) 48.17,28.32 48.17,27.88 48.52,27.52 86.6,27.52 86.95,27.88 86.95,31.31 89.46,33.81 89.46,40.81 88.96,41.31 88.96,51.4 89.83,52.27 v1(89.83,53.01)
  BOTTOM w0.102: J21.108 48.03,28.46 v1(47.53,28.96)
-EC_RESET: length 30.4
  TOP w0.102: U16.F1 238.7,77.27 v1(238.7,77.27) 238.99,77.56 239.18,77.56 R134.1 ; v1(246.34,69.23) 246.85,68.72 248.52,68.72 248.8,69 v4(248.8,70.55) 248.8,71.21 249.26,71.67 249.89,71.67 250.17,71.94 250.17,73.15 U21.B6
  IN1 w0.076: v1(238.7,77.27) 238.75,77.22 238.75,75.37 239.7,74.42 239.7,74.22 240.17,73.75 240.85,73.75 241.07,73.53 242.18,73.53 242.51,73.86 242.97,73.86 244.04,74.93 244.04,75.21 245.11,76.28 245.93,76.28 246.62,75.59 246.62,72.6 247.63,71.59 247.63,70.62 246.34,69.33 v1(246.34,69.23)
-EC_SCI: length 151.9
  TOP w0.102: v1(232.71,80.85) 232.71,80.85 232.73,80.83 232.77,80.83 U16.K6
  IN1 w0.076: v1(213.9,79.69) 213.9,79.9 214.51,80.5 223.18,80.5 223.68,81.01 225.9,81.01 226.2,80.71 227.23,80.71 227.77,81.24 228.18,81.24 228.36,81.07 228.36,80.58 228.48,80.45 231.61,80.45 232,80.85 v1(232.71,80.85)
  IN3 w0.081: v1(213.9,79.69) 213.9,78.32 212.05,76.47 210.03,76.47 208.15,74.59 208.15,73.07 207.01,71.92 206.21,71.92 205.65,71.36 203.34,71.36 201.61,69.63 199.75,69.63 199.46,69.92 197.58,69.92 196.76,69.1 192.62,69.1 191.55,68.03 185.78,68.03 185.01,67.26 184.21,67.26 184.14,67.33 182.25,67.33 181.34,68.24 179.05,68.24 178.57,67.75 173.85,67.75 173.44,67.35 167.66,67.35 166.62,66.31 163.71,66.31 160.92,63.51 158.05,63.51 155.99,61.45 153.48,61.45 152.38,60.36 148.77,60.36 148.07,61.06 146.35,61.06 145.17,62.24 144.36,63.05 142.45,63.05 141.8,63.71 139.26,63.71 138.44,64.53 138.44,64.96 137.4,66 135.9,66 132.98,68.92 132.98,69.76 132.32,70.42 127.57,70.42 127.24,70.75 127.24,73.32 126.73,73.82 125.08,73.82 122.41,76.49 120.32,76.49 119.38,77.43 111.31,77.43 110.98,77.76 v1(110.98,77.84)
  BOTTOM w0.076: U1.AD3 106.04,76.52 106.68,76.83 106.68,77.11 106.78,77.21 106.97,77.27 107.06,77.27 107.31,77.2 107.62,77.2 107.66,77.16
  BOTTOM w0.102: 107.66,77.16 109.82,77.16 110.5,77.84 v1(110.98,77.84) 111.11,77.84 111.54,77.41 112.14,77.41 RC33.1
-EC_SLP_LAN: length 23.6
  TOP w0.102: U16.N4 234.73,84.39 v1(234.55,84.57) 234.53,84.57 234.17,84.92 R192.2 ; U21.G6 250.55,77.57 v1(250.9,77.92)
  IN1 w0.076: v1(250.9,77.92) 250.62,77.92 249.95,78.6 249.95,79.73 249.32,80.37 246.78,80.37 245.96,81.19 242.93,81.19 242.55,81.57 242.55,82.28 242.29,82.55 241.68,82.55 241.23,82.1 238.85,82.1 237.09,83.86 235.34,83.86 234.63,84.57 v1(234.55,84.57)
-EC_WAKE: length 165.1
  TOP w0.102: U16.N7 232.33,83.12 232.75,83.54 232.75,85.41 232.42,85.74 232.42,87.97 233.21,88.76 233.44,88.76 v1(233.59,88.91)
  IN3 w0.081: v1(111.69,77.84) 113.04,77.84 113.57,78.37 118.67,78.37 120.37,76.67 122.49,76.67 124.93,74.23 126.96,74.23 127.8,73.39 127.8,71.97 129.12,70.65 132.47,70.65 133.16,69.96 133.16,69 135.98,66.18 137.5,66.18 138.68,65 138.68,64.67 139.47,63.88 141.88,63.88 142.53,63.23 144.46,63.23 146.43,61.26 148.17,61.26 148.87,60.57 152.18,60.57 153.25,61.63 155.91,61.63 158,63.72 160.84,63.72 163.63,66.51 166.46,66.51 167.5,67.55 173.29,67.55 173.67,67.93 178.47,67.93 178.95,68.41 181.44,68.41 182.35,67.51 184.19,67.51 184.26,67.43 184.61,67.43 185.39,68.21 191.47,68.21 192.54,69.28 196.71,69.28 197.51,70.08 199.53,70.08 199.8,69.81 201.51,69.81 204.07,72.38 207.01,72.38 207.91,73.28 207.91,74.76 209.79,76.64 211.95,76.64 213.47,78.17 213.47,83.17 217.59,87.29 218.88,87.29 219.92,88.33 221.83,88.33 222.87,89.37 224.47,89.37 224.85,88.99 224.85,88.58 225.1,88.33 226.15,88.33 226.35,88.53 226.35,89.17 226.73,89.55 232.98,89.55 233.59,88.94 v1(233.59,88.91)
  BOTTOM w0.076: 107.79,77.37 107.3,77.37 107.08,77.44 106.91,77.44 106.75,77.38 106.15,77.38 106.05,77.28 106.05,76.89 105.49,76.33 U1.AD4
  BOTTOM w0.102: 107.79,77.37 109.63,77.37 110.6,78.35 111.13,78.35 111.64,77.84 v1(111.69,77.84) 111.74,77.84 112.15,78.24 RC32.1
-ECSPI_SS: length 22.3
  TOP w0.102: v1(229.56,81.66) 229.58,81.65 229.58,81.63 U16.L10 ; v1(244.97,78.88) 245.13,78.72 R263.2
  IN1 w0.076: v1(229.56,81.66) 229.59,81.66 230.18,82.26 232.11,82.26 232.72,82.87 235.87,82.87 237.55,81.19 238.67,81.19 239,80.86 239.45,80.86 240.28,81.69 241.07,81.69 241.62,82.24 241.99,82.24 242.33,81.9 242.33,81.52 242.81,81.04 245.43,81.04 245.72,80.75 245.72,79.62 244.98,78.88 v1(244.97,78.88)
-ECSPI_SS_R: length 3.9
  TOP w0.102: U21.G8 248.51,77.96 247.91,77.96 247.43,78.45 247.02,78.45 246.66,78.08 R269.2 R263.1
-EXT_PWR_GATE: length 49.4
  IN1 w0.076: v1(107.86,89.45) 107.58,89.45 106.33,88.2 106.33,85.36 105.5,84.52 105.5,80.09 104.55,79.14 103.56,79.14 103.38,78.96 101.6,78.96 100.64,79.92 100.34,79.92 100.11,79.69 100.11,77.09 99.72,76.7 99.72,76.04 99.42,75.73 99.42,74.82 99.06,74.46 97.41,74.46 97.13,74.19 97.13,73.89 96.55,73.31 96.55,72.45 96.78,72.22 97.21,72.22 97.49,72.5 98.13,72.5 98.51,72.88 100.09,72.88 100.56,72.41 v1(101.48,72.41)
  BOTTOM w0.102: U1.AM10 v1(101.48,72.41) ; RC155.1 108.95,100.55 106.14,97.74 v3(106.14,96.28) 106.14,95.7 106.84,95.01 106.84,90.46 v1(107.86,89.45)
-EXTPWR: length 61.9
  TOP w0.102: Q16.3 244.53,81.8 v1(244.43,81.8) ; v1(204.83,69.02) 205.32,69.51 PQ106.1 ; v1(229.14,87.9) 228.91,88.12 228.91,88.58 v4(229.12,88.79) 229.6,88.79 229.85,88.54 D28.1
  TOP w0.203: PQ106.1 205.37,69.49 PR164.1 205.33,68.39 PC128.1
  IN3 w0.081: v1(244.43,81.8) 244.43,82.03 242.98,83.49 242.98,85.24 242.07,86.15 242.07,87.24 241.16,88.15 239.43,88.15 239.12,88.45 236.46,88.45 235.67,87.67 229.37,87.67 v1(229.14,87.9) 228.41,87.16 225.74,87.16 225.46,86.88 219.52,86.88 219.24,86.6 217.81,86.6 215.5,84.29 215.5,78.35 211.72,74.56 211.72,74.21 207.04,69.53 206.33,69.53 205.83,69.02 v1(204.83,69.02)
-EXTPWR_ASIC: length 18.9
  TOP w0.102: v1(245.25,81.77) 245.25,81.84 Q16.1 ; v1(250.73,83.81) 250.73,83.78 v4(250.38,83.43) 250.22,83.27 R254.2 ; v1(251.7,77.13) 251.7,77.08 U21.F5
  IN3 w0.081: v1(245.25,81.77) 245.25,82.1 245.5,82.36 247.3,82.36 247.53,82.13 248.68,82.13 250.35,83.81 v1(250.73,83.81)
  BOTTOM w0.102: v1(250.73,83.81) 251.39,83.81 251.7,84.11 252.23,84.11 252.64,83.71 252.64,79.67 251.34,78.37 251.34,77.48 v1(251.7,77.13)
-FLT_REPORT: length 2.2
  TOP w0.102: R439.2 17.43,47.56 v3(17.33,47.46) 17.28,47.4 U193.9
-HDA_RST: length 202.4
  TOP w0.102: UA1.15 270.15,58.74 270.05,58.64 269.1,58.64 268.56,58.1 267.81,58.1 RA124.2 267.65,57.82 267.42,57.59 265.85,57.59 265.39,57.14 264.14,57.14 v1(263.42,57.85)
  IN1 w0.076: v1(94.98,61.89) 96.88,61.89 97.82,60.95 97.82,59.57 98.73,58.66 98.79,58.66 101.28,56.17 102.45,56.17 104.38,58.1 106.82,58.1 108.92,60.21 116.99,60.21 121.18,56.02 123.5,56.02 127.3,52.22 133.02,52.22 134.63,53.83 153.56,53.83 157.92,58.2 157.92,59.04 158.79,59.91 161.45,59.91 161.76,60.21 164.58,60.21 165.87,58.91 170.09,58.91 170.21,58.79 176.23,58.79 176.49,59.04 184.97,59.04 186.12,57.9 202.01,57.9 202.88,57.04 206.71,57.04 206.94,56.81 208.62,56.81 209.48,57.67 211.85,57.67 212.3,58.13 216.06,58.13 216.89,57.29 217.45,57.29 217.58,57.17 220.3,57.17 220.47,56.99 221.03,56.99 221.41,57.37 221.41,58.72 222.93,60.24 225.03,60.24 225.79,61 235.69,61 236.45,60.24 236.61,60.24 237.94,58.9 240.35,58.9 241.1,58.16 241.1,56.74 242.53,55.31 243.53,55.31 v1(244.04,55.82)
  BOTTOM w0.102: RC42.1 95.09,62 v1(94.98,61.89) ; v1(244.04,55.82) 244.3,55.57 246.46,55.57 248.36,57.47 248.36,60.15 248.85,60.64 256.73,60.64 259.57,57.8 263.2,57.8 263.25,57.85 v1(263.42,57.85)
-HDA_RST_R: length 6.6
  BOTTOM w0.076: U1.AW22 94.96,68.03 94.79,67.47 94.79,67.39 94.73,67.23 94.73,67.09 94.8,66.87 94.8,66.75 94.77,66.67 94.75,66.64 94.75,66.48 94.5,66.23
  BOTTOM w0.102: 94.5,66.23 93.94,65.67 v4(93.94,64.23) 93.94,63.89 94.51,63.32 RC42.2
-HDD_DTCT: length 54.2
  TOP w0.102: U16.D2 236.7,75.3 237.67,75.3 238.49,74.48 238.49,74.1 238.9,73.7 v1(238.9,73.52) 239.11,73.73 R176.1
  IN3 w0.081: v1(223.86,60.64) 223.86,59.69 221.03,56.86 v1(221.03,56.46)
  BOTTOM w0.102: v1(221.03,56.46) 221.03,56.1 221.07,56.07 C302.2 221.04,53.86 221.04,53.35 221.27,53.12 222.69,53.12 223.63,52.18 223.63,51.06 223.83,50.86 225.13,50.86 226.15,49.84 J1.20 ; v1(223.86,60.64) 224.37,60.13 224.7,60.13 226.24,61.68 226.24,65.96 225.87,66.33 225.87,66.97 226.17,67.27 226.88,67.27 228.14,66.01 230.96,66.01 231.68,65.29 232.8,65.29 235.01,63.08 237.09,63.08 239.79,65.77 239.79,70.09 239.28,70.6 239.28,72.78 238.89,73.16 238.89,73.51 v1(238.9,73.52)
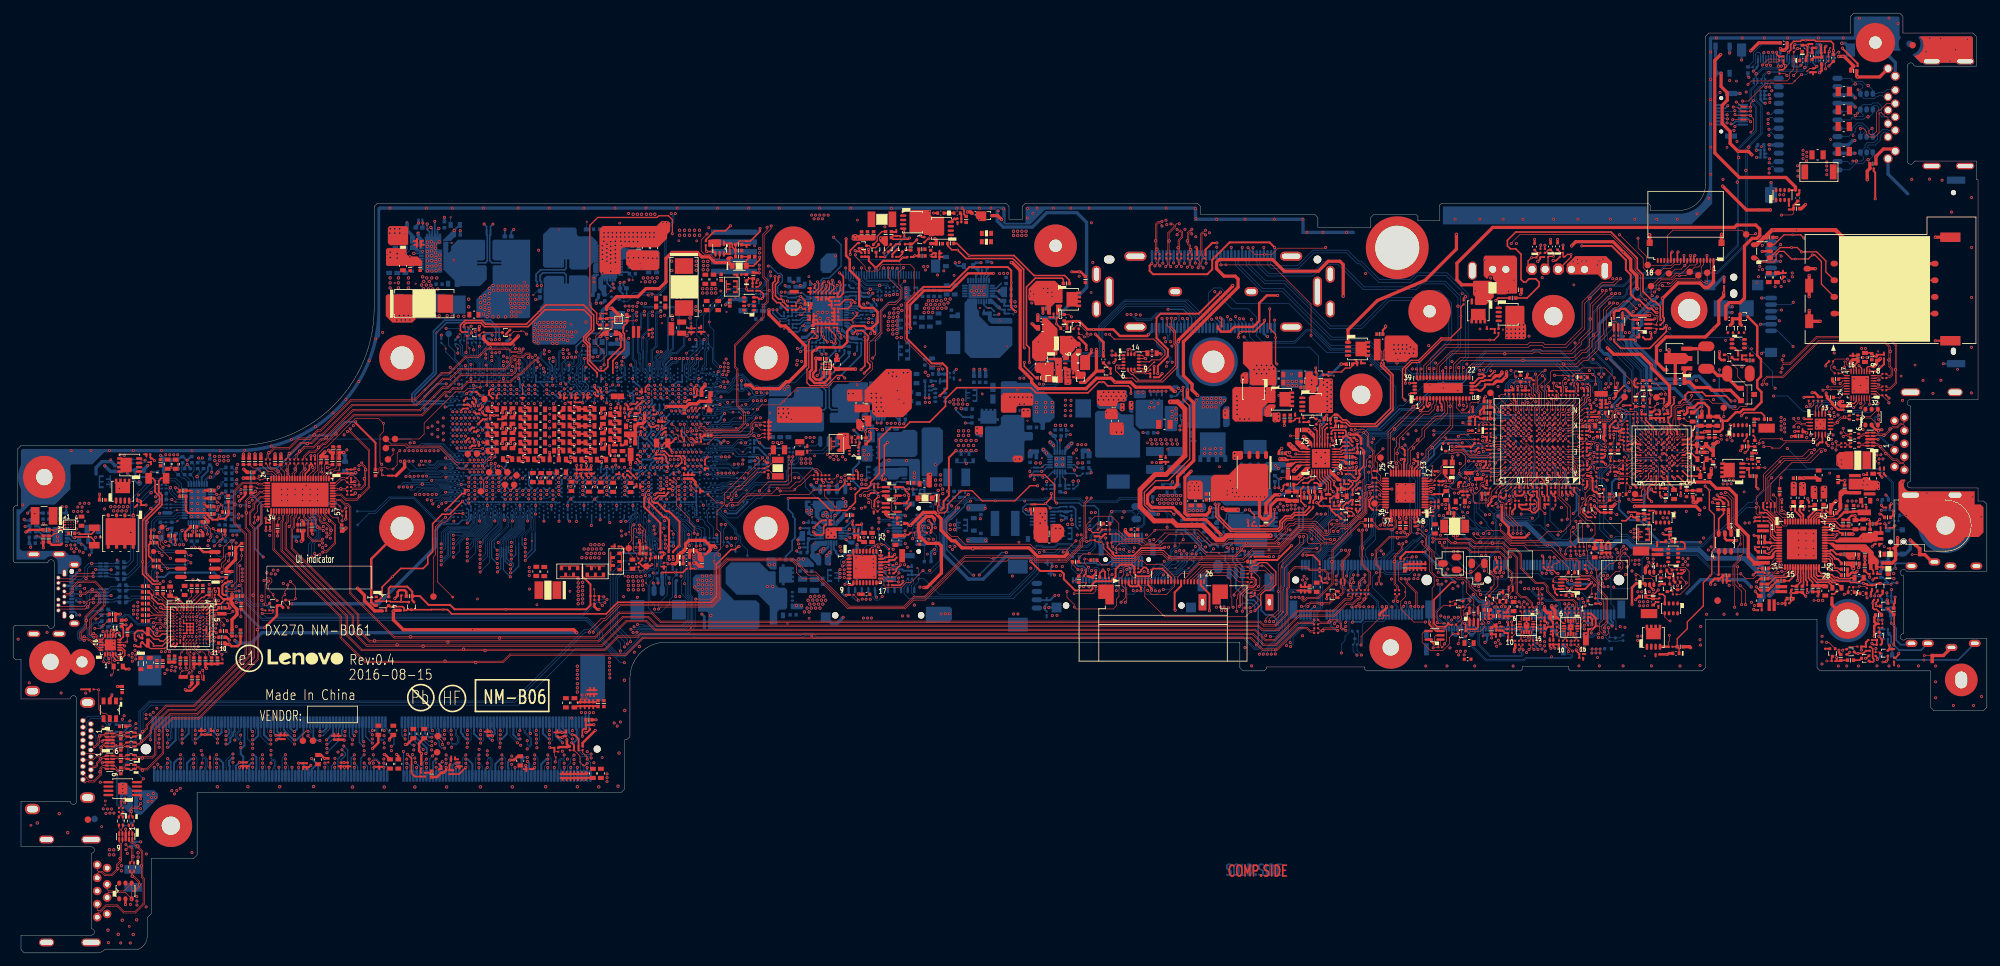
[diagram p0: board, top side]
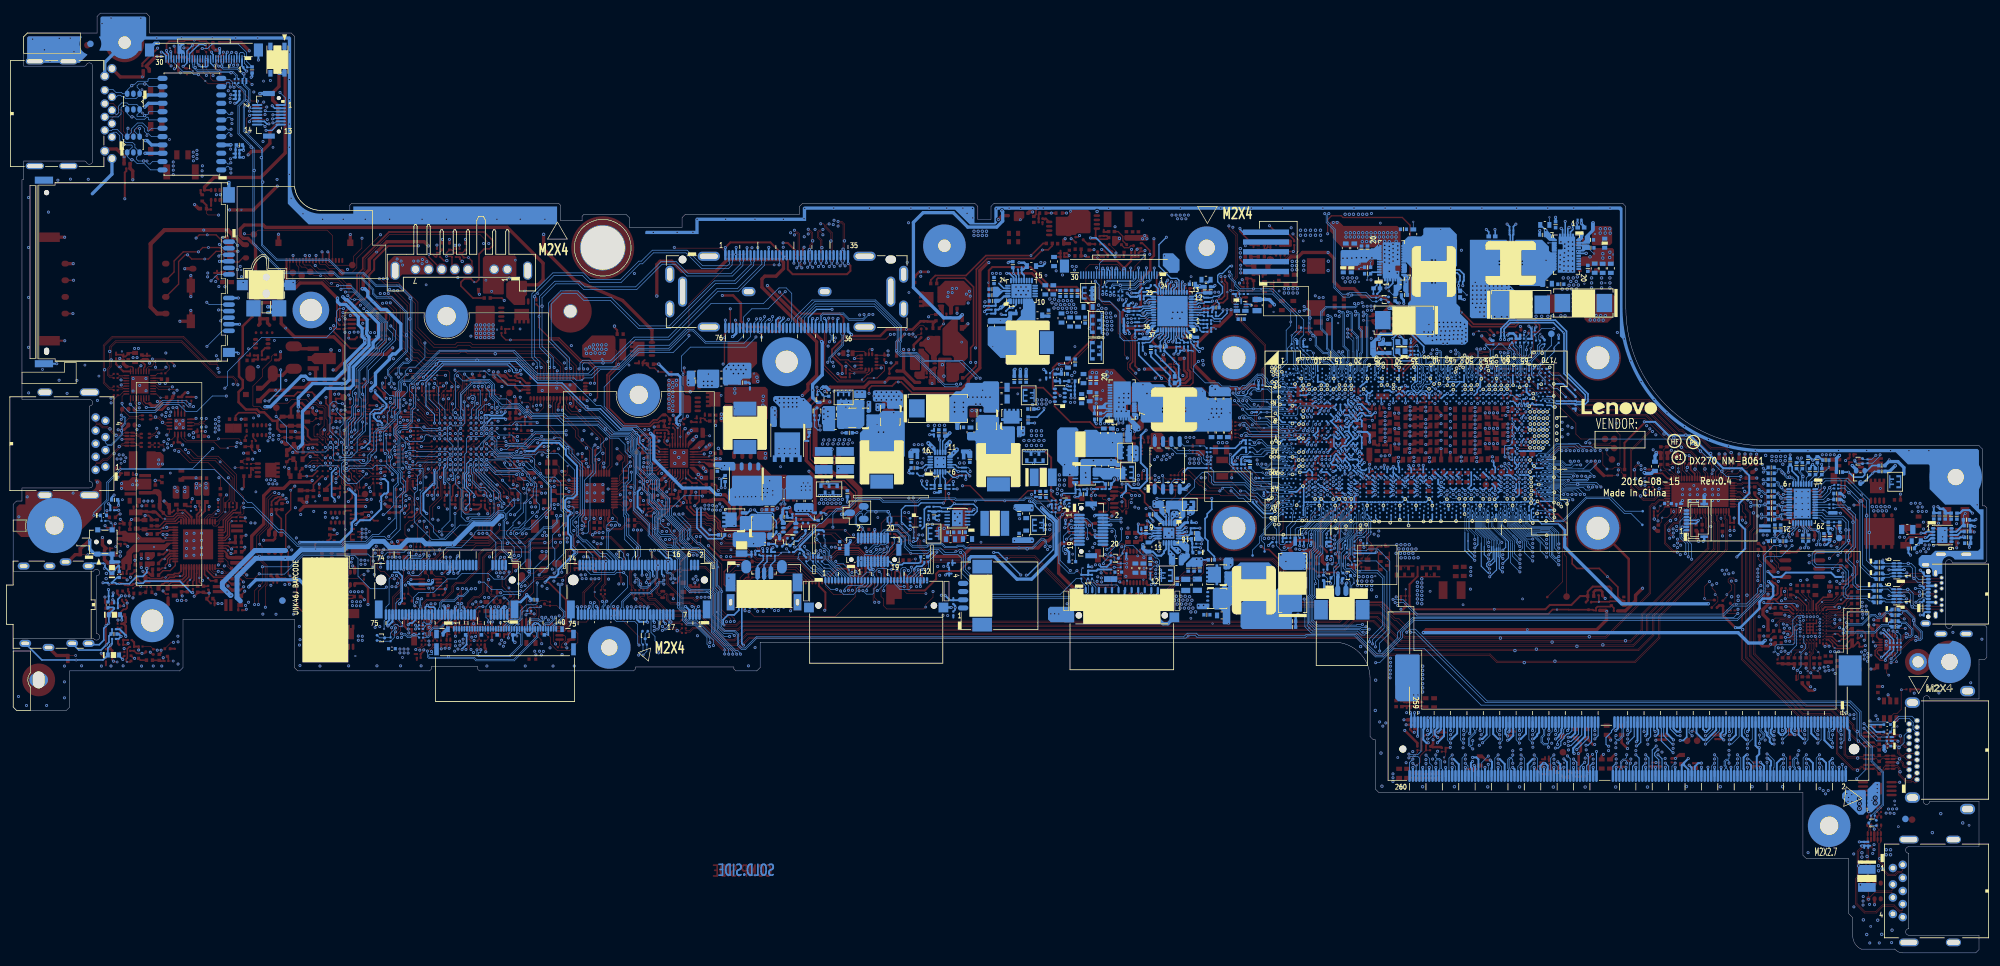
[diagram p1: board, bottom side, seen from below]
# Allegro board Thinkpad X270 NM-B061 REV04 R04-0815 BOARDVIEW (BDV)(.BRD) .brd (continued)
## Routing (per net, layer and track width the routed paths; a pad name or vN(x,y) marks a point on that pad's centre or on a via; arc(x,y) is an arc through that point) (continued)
-HOTKEY: length 122
  TOP w0.102: U16.C2 236.74,74.46 237.73,74.46 238.06,74.13 238.06,73.5 239.02,72.53 239.02,72.45 239.43,72.04 R127.1 239.43,72.22 239.63,72.42 240.26,72.42 240.44,72.24 240.44,70.87 239.68,70.12 239.68,69.07 239.24,68.63 239.24,68.27 238.95,67.98 238.95,67.12 240.12,65.95 240.52,65.95 241.2,65.27 241.2,63.82 239.93,62.55 239.93,61.41 240.09,61.25 240.09,59.8 241.41,58.48 v3(241.41,58.44) 241.41,57.24 241.94,56.71 241.94,56.2 242.27,55.87 v1(242.57,55.87)
  IN1 w0.076: v1(160.11,61.18) 160.5,60.78 160.93,60.78 161.21,61.06 167.1,61.06 168,60.16 171.48,60.16 172.17,60.85 175.68,60.85 176.67,59.85 185.51,59.85 186.62,58.74 206.59,58.74 207.71,57.62 208.26,57.62 209.23,58.58 210.96,58.58 211.39,59.02 221.1,59.02 223.52,61.43 236.86,61.43 237.09,61.2 237.09,60.44 238.06,59.47 240.39,59.47 241.61,58.25 241.61,57.47 242.22,56.86 242.45,56.86 242.77,56.53 242.77,56.07 v1(242.57,55.87)
  BOTTOM w0.102: v1(160.11,61.18) 160.11,60.99 C852.2 161.37,59.63 161.37,58.69 162.14,57.92 162.43,57.92 163.1,57.25 J38.29
-INT_MIC_DTCT: length 231.8
  IN1 w0.076: v1(267.62,137.43) 266.51,136.31 265.93,136.31 262.85,133.23 262.85,131.87 260.52,129.53 260.52,126.17 261.15,125.54 261.15,114.57 257.36,110.78 222.48,110.78 215.34,103.65 213.78,103.65 212.87,102.73 206.58,102.73 205.41,103.9 205.41,105.63 204.6,106.44 204.6,107.36 202.95,109 185.63,109 184.31,107.68 v1(183.52,107.68) ; v1(155.33,99.17) 153.98,99.17 150.73,102.42 149.03,102.42 148.6,102.86 146.2,102.86 144.65,101.31 144.65,98.57 142.52,96.44 141.66,96.44 140.9,95.67 140.9,94.81 137.19,91.1 133.22,91.1 131.41,92.91 129.21,92.91 129.02,93.1 125.84,93.1 125.2,93.74 123.61,93.74 123.3,93.43 118.93,93.43 117.59,94.78 112.96,94.78 109.97,91.78 109.97,88.79 108.87,87.69 107.68,87.69 106.56,86.58 106.56,85.23 106.26,84.92 106.26,80.47 104.7,78.91 104.04,78.91 103.79,78.66 103.79,78.33 103.53,78.07 101.61,78.07 100.12,76.58 100.12,75.87 99.76,75.51 99.76,74.94 v1(100.39,74.31)
  IN4 w0.076: v1(155.33,99.17) 154.59,99.92 154.59,101.29 155.17,101.87 157.72,101.87 158.3,102.45 162.37,102.45 163,103.09 163,104.46 166.86,108.32 182.03,108.32 182.66,107.68 v1(183.52,107.68)
  BOTTOM w0.076: v1(100.39,74.31) 100.71,74.63 U1.AH12
  BOTTOM w0.127: v1(267.62,137.43) 268.05,137 J11.6
-INTRUDER: length 260.2
  TOP w0.102: v1(99.86,59.37) 99.7,59.52 RC62.1
  IN3 w0.081: v1(270.52,76.97) 268.61,76.97 267.04,78.55 264.58,78.55 262.47,76.44 260.38,76.44 259.27,75.32 255.33,75.32 254.87,75.78 254.87,78.07 253.7,79.23 252.31,79.23 252.05,78.98 251.16,78.98 250.4,78.22 250.4,77.53 250.63,77.3 250.63,76.99 250.35,76.71 249.14,76.71 245.96,79.9 244.47,79.9 243.6,80.77 243.6,82 242.27,83.32 240.95,83.32 240.78,83.15 240.14,83.15 238.13,85.15 228.03,85.15 227.09,84.21 222.87,84.21 222.08,83.43 222.08,82.54 221.09,81.55 220.71,81.55 218.75,79.59 218.75,77.02 217.2,75.48 217.2,74.79 214.59,72.17 214.59,69.53 213.04,67.98 211.79,67.98 210.49,66.67 210.49,65.15 209.94,64.6 208.09,64.6 207.5,65.19 205.01,65.19 203.31,63.49 199.63,63.49 198.97,64.14 195.95,64.14 195.27,63.46 192.19,63.46 191.91,63.18 186.39,63.18 185.73,62.52 182.95,62.52 182.28,63.19 181.26,63.19 180.66,63.79 177.23,63.79 176.27,62.83 175.29,62.83 174.41,61.94 172.32,61.94 171,60.62 167.55,60.62 167.27,60.9 166.23,60.9 165.31,59.98 162.41,59.98 161.4,58.97 161.4,57.98 160.05,56.63 158.18,56.63 157.24,55.69 140.36,55.69 139.84,56.21 136.91,56.21 136.17,55.47 133.93,55.47 133.44,55.97 128.23,55.97 127.9,55.64 126.02,55.64 123.76,57.9 122.77,57.9 121.44,59.23 119.75,59.23 118.37,60.62 118.37,65.93 116.19,68.11 113.39,68.11 111.41,66.13 111.41,63.74 110.27,62.6 108.54,62.6 108.21,62.27 105.85,62.27 105.19,62.93 102.75,62.93 102.23,62.41 102.23,60.5 100.67,58.94 100.29,58.94 v1(99.86,59.37)
  IN4 w0.076: v1(99.86,59.37) 99.6,59.63 99.6,60.34 100.24,60.97 100.24,66 98.61,67.63 98.61,68.62 98.31,68.92 98.31,70.83 v1(98.74,71.26)
  BOTTOM w0.102: CC17.2 99.91,60.57 99.63,60.29 99.63,59.6 v1(99.86,59.37) ; U1.AP16 98.59,71.26 v1(98.74,71.26) ; RC71.2 287.47,66.58 DC1.1 v3(288.65,66.76) 288.65,67.18 286.67,69.15 286.67,71.82 284.55,73.94 273.55,73.94 v1(270.52,76.97)
-INTRUDER_EC: length 75.1
  TOP w0.102: U16.G1 237.39,77.81 238.64,77.81 238.92,78.09 239.61,78.09 239.85,78.33 R177.1 240.26,78.07 240.9,78.07 v4(241.13,77.84) 241.74,77.84 242.35,77.23 v1(242.81,77.23)
  BOTTOM w0.102: DC1.2 287.05,67.11 287.05,68.47 286.46,69.06 286.46,71.73 284.45,73.74 270.21,73.74 265.24,68.76 264.6,68.76 260.43,64.59 259.79,64.59 257.45,62.25 250.92,62.25 250.4,62.78 247.22,62.78 246.15,63.84 245.2,63.84 242.71,66.33 242.71,70.93 242.15,71.49 242.15,73.11 243.39,74.36 243.39,75.15 243.11,75.42 243.11,75.86 243.34,76.09 243.34,76.72 242.83,77.23 v1(242.81,77.23)
-JTAG_RST: length 5.7
  TOP w0.102: U16.A10 229.93,72.48 229.17,71.72 229.17,71.12 R182.2 228.96,70.97 228.56,70.57 228.56,69.79 v4(228.67,69.67) 229.02,69.33 C173.2 R181.1
-KBD_BL_DTCT: length 188.2
  TOP w0.102: v1(233.58,67.06) 232.93,67.7 232.93,69.51 232.75,69.68 232.75,70.87 232.62,70.99 R125.2 232.34,71.44 232.56,71.65 232.56,72.21 232.62,72.28 232.62,72.77 U16.A6
  IN4 w0.127: v1(191.7,48.3) 191.3,47.89 189.35,47.89 188.59,48.66 137.68,48.66 132.52,53.81 v1(132.52,54.37)
  BOTTOM w0.102: J37.9 129.4,54.69 129.57,54.52 130.77,54.52 131.45,53.83 131.99,53.83 v1(132.52,54.37) ; v1(191.7,48.3) 192.55,48.3 193.58,49.33 193.58,54.95 194.16,55.53 194.16,59.25 196.55,61.65 197.45,61.65 198.88,63.07 198.88,64.43 201.13,66.68 201.13,69.23 202.63,70.73 202.63,72.17 203.67,73.21 203.67,74.46 204,74.79 204,78.24 205.95,80.2 208.01,80.2 211.33,83.52 212.01,83.52 215.89,87.4 221.03,87.4 224.19,90.56 236.29,90.56 239.83,87.02 239.83,86.69 239.56,86.42 239.56,83.27 240.04,82.79 240.04,81.04 240.9,80.17 241.93,80.17 242.44,79.66 242.44,79.3 241.12,77.98 241.12,77.09 241.5,76.71 241.5,74.69 240.95,74.14 240.95,73.98 240.7,73.72 240.27,73.72 240.06,73.93 238.49,73.93 238.44,73.88 238.44,70.61 238.87,70.18 238.87,67.14 236.86,65.14 236.86,64.25 235.9,63.28 235.21,63.28 233.58,64.92 v1(233.58,67.06)
-KBRC: length 206.8
  TOP w0.102: R126.1 239.66,81.8 239.15,81.29 v1(239.12,81.29) ; U16.J5 v1(234.31,80.05)
  IN1 w0.076: v1(101.84,57.49) 103.43,59.08 105.15,59.08 107.39,61.32 117.26,61.32 121.54,57.04 123.88,57.04 127.73,53.19 132.39,53.19 134.02,54.83 153.18,54.83 156.94,58.59 156.94,59.43 159.24,61.72 160.95,61.72 161.31,61.37 167.25,61.37 168.08,60.54 171.28,60.54 171.91,61.17 175.96,61.17 176.95,60.18 185.63,60.18 186.76,59.06 210.79,59.06 211.06,59.32 220.98,59.32 223.39,61.74 239.14,61.74 240.06,60.82 240.06,60.29 240.29,60.06 240.9,60.06 241.66,59.3 243.65,59.3 244.76,58.18 245.73,58.18 245.87,58.03 v1(245.87,57.75)
  IN3 w0.081: v1(234.31,80.05) 234.35,80.05 234.76,80.46 236.87,80.46 238.14,81.73 238.69,81.73 v1(239.12,81.29) 239.43,81.29 241.26,79.46 241.26,79.01 241.82,78.45 241.82,78.09 242.25,77.66 242.25,75.78 242.4,75.63 242.93,75.63 243.33,75.23 243.89,75.23 244.33,75.68 244.94,75.68 245.68,74.94 245.68,71.36 245.07,70.75 245.07,63.66 246.41,62.32 246.41,60.79 245.6,59.98 245.6,58.31 245.87,58.03 v1(245.87,57.75)
  BOTTOM w0.076: 100.68,64.74 100.68,64.95 99.78,65.85 99.78,66.07 99.61,66.24 99.61,66.67 99.62,66.69 99.62,66.95 99.61,66.98 99.61,67.39 99.85,68.17 100.03,68.35 U1.AW13
  BOTTOM w0.127: v1(101.84,57.49) v4(101.84,59.4) 101.84,60.41 101.25,61 101.25,64.17 100.68,64.74
-LANWAKE: length 160.3
  TOP w0.102: v1(216.23,68.13) 216.18,68.13 215.92,68.39 UL1.2
  IN1 w0.076: v1(217.3,58.08) 217.15,58.08 216.54,58.69 211.54,58.69 211.11,58.25 209.33,58.25 208.39,57.31 207.55,57.31 206.45,58.42 186.48,58.42 185.35,59.55 176.18,59.55 175.95,59.31 170.64,59.31 170.38,59.58 168.11,59.58 166.92,60.76 161.37,60.76 161.05,60.44 158.6,60.44 157.41,59.25 157.41,58.41 153.36,54.36 134.33,54.36 132.7,52.73 127.51,52.73 123.66,56.58 121.35,56.58 117.21,60.72 108.69,60.72 106.6,58.62 104.17,58.62 102.35,56.79 101.55,56.79 99.17,59.17 99.17,60.44 98.96,60.65 98.96,61.29 v1(99.45,61.78) 98.66,62.57 98.66,66.01 100.46,67.8 100.46,69.44 100.06,69.83 100.06,72.13 v1(99.68,72.51)
  BOTTOM w0.102: U1.AM15 99.28,72.87 v1(99.68,72.51) ; v1(99.45,61.78) 99.74,61.49 RC70.2 ; v1(216.23,68.13) 216.2,68.16 215.66,68.16 215.43,67.93 215.43,66.66 215.99,66.1 215.99,64.22 215.58,63.82 215.58,62.12 214.84,61.38 214.84,61.02 217.3,58.57 v1(217.3,58.08)
-LED_CAPSLOCK: length 3.2
  TOP w0.102: U16.H2 236.79,79.34 237.58,79.34 237.85,79.62 R404.1
-LED_FNLOCK: length 96
  TOP w0.102: v1(206.92,70.17) 206.92,69.74 206.42,69.24 206.42,67.11 205.52,66.2 205.2,66.2 v4(202.23,63.24) 201.4,62.41 199.56,62.41 197.6,64.38 196.12,64.38 193.07,61.33 188.92,61.33 187.55,59.96 176.06,59.96 175.17,60.85 172.13,60.85 170.89,59.6 167.8,59.6 167.4,59.19 166,59.19 R225.1 ; U16.F6 v1(233.51,76.9)
  IN1 w0.076: v1(233.51,76.9) 233.1,76.49 232.56,76.49 232.13,76.06 232.13,75.2 232.44,74.89 232.9,74.89 233.11,74.69 233.11,73.21 233.51,72.81 233.51,70.14 233.74,69.91 233.74,69.25 233.38,68.9 230.72,68.9 229.35,70.27 228.79,70.27 228.41,70.65 226.45,70.65 225.03,72.07 223.12,72.07 221.98,73.21 221.37,73.21 220.86,72.71 220.86,72.1 221.04,71.92 221.04,69.76 220.3,69.02 217.79,69.02 217.08,69.74 214.79,69.74 213.55,68.49 206.61,68.49 206.36,68.74 206.36,69.61 v1(206.92,70.17)
-LED_LOGO: length 107.3
  TOP w0.102: v1(234.53,72.28) 234.73,72.48 U16.A4 ; v1(270.46,133.88) 270.17,134.17 R10.1
  IN4 w0.076: v1(270.46,133.88) 268.35,135.98 266.17,135.98 261.73,131.55 261.73,130.86 260.45,129.57 260.45,126.64 261.38,125.71 261.38,123.12 262.03,122.47 262.03,114.24 257.2,109.41 250.98,109.41 248.23,106.67 236.48,106.67 234.63,104.81 234.63,103.14 238.06,99.71 238.06,96.05 234.12,92.11 232.55,92.11 232.04,91.6 232.04,89.5 231.35,88.81 231.35,86 230.43,85.08 230.43,84.4 230.59,84.24 230.59,83.53 230.03,82.97 229.5,82.97 229.14,82.61 229.14,82.28 229.35,82.08 229.75,82.08 229.98,81.85 229.98,80.61 230.11,80.48 231.28,80.48 231.6,80.16 231.6,77.97 232.23,77.33 233.68,77.33 233.89,77.12 233.89,74.28 234.04,74.13 234.63,74.13 234.96,73.8 234.96,72.71 v1(234.53,72.28)
-LED_MICMUTE: length 95.4
  TOP w0.102: R223.1 162.43,60.19 163.09,60.85 166.81,60.85 167.8,59.85 170.84,59.85 172.13,61.15 175.19,61.15 176.13,60.21 187.47,60.21 189.03,61.77 193.21,61.77 196.1,64.66 197.9,64.66 v4(197.97,64.59) 199.89,62.66 201.06,62.66 v1(201.48,63.08) ; U16.C3 v1(235.91,74.5)
  IN4 w0.076: v1(236.89,69.25) 236.57,68.94 229.51,68.94 228.72,69.73 228.72,69.91 228.38,70.24 224.32,70.24 223.05,68.97 223.05,66.99 221.23,65.18 221.23,62.76 220.54,62.07 218.76,62.07 218.43,61.74 216.06,61.74 215.76,62.04 212.93,62.04 212.45,61.56 210.69,61.56 209.68,62.57 208.42,62.57 207.64,61.78 206.36,61.78 205.6,61.02 202.4,61.02 202.02,61.4 202.02,62.39 201.48,62.93 v1(201.48,63.08)
  BOTTOM w0.102: v1(236.89,69.25) 236.66,69.48 236.66,70.67 236.32,71.02 236.32,73.46 235.91,73.88 v1(235.91,74.5)
-LED_MUTE: length 102
  TOP w0.102: v1(163.2,55.89) 163.61,56.3 163.61,56.43 v4(163.56,56.48) 163.48,56.55 R224.1 ; U16.D12 227.95,76.05 v1(227.95,76.09)
  IN3 w0.081: v1(224.32,58.31) 223.81,58.31 222.03,56.53 222.03,55.21 219.47,52.64 217.36,52.64 216.29,51.57 208.14,51.57 205.48,48.91 204,48.91 203.72,48.63 202.73,48.63 202.52,48.83 202.52,49.95 201.65,50.82 196.24,50.82 193.94,53.12 193.94,55 192.27,56.67 178.97,56.67 175.4,53.1 171.66,53.1 170.54,54.22 164.53,54.22 163.2,55.54 v1(163.2,55.89)
  BOTTOM w0.102: v1(227.95,76.09) 227.36,75.5 225.41,75.5 224.01,74.1 223.35,74.1 222.25,73 222.25,72.67 221.17,71.59 221.17,70.8 221.19,70.78 221.19,68.9 220.71,68.41 220.71,67.68 222.92,65.47 222.92,65.24 223.61,64.55 224.39,64.55 224.65,64.3 224.65,63.87 222.88,62.1 222.88,59.74 v1(224.32,58.31)
-LED_PWR: length 100.2
  TOP w0.102: R7.1 276.35,135.73 v1(276.35,134.92) ; U16.F5 v1(234.31,76.9)
  IN3 w0.081: v1(276.35,134.92) 275.13,136.14 269.77,136.14 266.42,132.78 266.42,111.17 267.52,110.07 267.52,90.64 264.78,87.9 256.16,87.9 v1(255.69,88.38)
  IN4 w0.076: v1(234.31,76.9) 234.76,77.36 236.33,77.36 237.14,78.17 237.14,80.43 238.49,81.77 238.49,83.43 240.83,85.76 240.83,88.05 242.18,89.41 252.12,89.41 252.12,89.41 254.66,89.41 v1(255.69,88.38)
-LID_CLOSE: length 126.7
  TOP w0.102: D2.1 272.35,138.02 v1(272.11,138.02) 272.05,138.02 C21.2 v3(271.5,136.36) 271.5,134.87 270.87,134.23 270.87,133.47 270.46,133.06 265.06,133.06 v1(264.52,132.52) ; v1(240.14,65.11) 240.14,65.26 238.67,66.74 238.67,68.57 238.74,68.64 238.74,69.67 R393.1
  IN4 w0.076: v1(264.52,132.52) 265.33,131.72 265.33,124 266.48,122.85 266.48,120.97 265.97,120.46 265.97,111.26 264.47,109.77 264.47,90.54 267.93,87.08 267.93,75.74 263.02,70.83 258.65,70.83 256.92,69.11 256.92,68.08 253.81,64.97 248.13,64.97 247.91,65.19 246.78,65.19 246.57,64.97 240.28,64.97 v1(240.14,65.11)
  BOTTOM w0.102: 265.9,137.4 265.69,137.2 265.69,135.75 265.26,135.32 ; 266.63,138.7 265.34,137.4 265.34,136.05 264.52,135.23 C269.2
  BOTTOM w0.127: 265.9,137.4 266.28,137.4 266.45,137.23 J11.2 ; C269.2 264.57,135.14 R5.1 265.26,135.32 ; 266.63,138.7 270.59,138.7 271.27,138.02 v1(272.11,138.02)
-LPC_FRAME: length 277.1
  TOP w0.102: U16.L6 v1(233.51,81.65)
  IN1 w0.076: v1(190.04,45.59) 190.04,46.73 187.97,48.81 95.56,48.81 95.28,48.53 94.9,48.53 v1(94.52,48.91)
  IN4 w0.076: v1(262.51,128.52) 263.73,127.3 263.73,122.87 263.33,122.47 263.33,113.58 257.92,108.17 251.39,108.17 247.46,104.23 247.46,102.65 246.33,101.52 246.33,99.59 244.79,98.06 241.97,98.06 237.25,93.33 237.25,87.82 237.12,87.69 237.12,86.65 237.27,86.5 237.27,85.41 235.67,83.81 234.71,83.81 234.02,84.49 233.61,84.49 233.08,83.96 233.08,82.08 v1(233.51,81.65)
  BOTTOM w0.076: 101.8,65.2 101.2,65.8 101.05,65.8 100.62,66.22 100.62,67.1 100.6,67.13 U1.BA12
  BOTTOM w0.102: 101.8,65.2 102.61,64.39 102.61,61.95 103.29,61.28 103.29,54.67 103.64,54.32 103.64,49.92 v4(103.31,49.59) 102.83,49.11 95.97,49.11 95.36,48.5 94.93,48.5 v1(94.52,48.91) ; J5.5 262.39,128.39 v1(262.51,128.52) ; v1(233.51,81.65) 233.89,82.03 233.89,82.82 233.52,83.18 233.52,87.2 233.69,87.36 233.69,88.18 233.08,88.79 228.94,88.79 228.36,88.2 227.11,88.2 225.51,86.6 217.43,86.6 213.6,82.76 211.67,82.76 208.6,79.69 206.69,79.69 205.72,78.73 205.72,77.63 204.28,76.19 204.28,74.71 203.87,74.31 203.87,73.11 202.83,72.07 202.83,70.62 201.43,69.23 201.43,66.67 199.13,64.38 199.13,63 197.52,61.39 196.66,61.39 194.36,59.1 194.36,55.37 193.81,54.82 193.81,49.2 190.76,46.15 190.47,46.15 190.04,45.72 v1(190.04,45.59)
-M_A_CAS: length 58.7
  IN1 w0.076: 83.35,64.15 83.35,64.55 82.53,65.37 82.53,66.31 81.29,67.55 81.29,69.08 v1(80.45,69.91)
  IN1 w0.114: 83.35,64.15 83.35,49.85 75,41.49 74.84,41.49 74.51,41.82 74.35,41.82 74.11,41.57 74.11,41.41 74.43,41.09 74.43,40.93 73.88,40.37 73.57,40.37 73.42,40.53 73.02,40.53 69.67,37.17 64.94,37.17 61.79,34.02 61.79,29.56 v1(61.32,29.09)
  BOTTOM w0.076: U1.AU48 v1(80.45,69.91)
  BOTTOM w0.165: v1(61.32,29.09) 62.03,28.39 J21.156
-M_A_CS0: length 62.3
  IN1 w0.076: 82.96,64.06 82.96,64.43 82.23,65.16 82.23,66.26 81.12,67.37 81.12,68.64 v1(80.45,69.3)
  IN1 w0.114: 82.96,64.06 82.96,50.01 79.39,46.44 78.39,46.44 78.31,46.37 78.21,46.27 78.21,46.11 78.55,45.77 78.55,45.61 78.31,45.37 78.15,45.37 77.81,45.71 77.65,45.71 77.41,45.46 77.41,45.3 77.74,44.96 77.74,44.8 77.5,44.56 77.34,44.56 77,44.9 76.84,44.9 76.6,44.66 76.6,44.49 76.94,44.16 76.94,43.99 76.69,43.75 76.53,43.75 76.19,44.09 76.03,44.09 75.79,43.85 75.79,43.69 76,43.47 76.13,43.35 76.13,43.19 75.88,42.94 75.72,42.94 75.39,43.28 75.22,43.28 74.98,43.04 74.98,42.88 75.32,42.54 75.32,42.38 75.08,42.14 74.92,42.14 74.58,42.47 74.42,42.47 69.51,37.56 64.78,37.56 61.14,33.92 61.14,31.7 v1(61.12,31.69)
  BOTTOM w0.076: v1(80.45,69.3) 81.4,69.3 U1.AU45
  BOTTOM w0.165: J21.149 60.28,32.22 60.81,31.69 v1(61.12,31.69)
-M_A_CS1: length 64.4
  IN1 w0.076: v1(82.33,69.22) 84.44,67.12 84.44,65.57 84.57,65.44
  IN1 w0.114: 84.57,65.44 84.73,65.28 84.81,65.28 84.93,65.16 84.93,47.57 82.83,45.47 81.21,45.47 81.03,45.3 81.03,45.14 81.61,44.56 81.61,44.4 81.37,44.16 81.21,44.16 80.63,44.73 80.47,44.73 80.23,44.49 80.23,44.33 80.8,43.75 80.8,43.59 80.56,43.35 80.4,43.35 80.28,43.47 79.82,43.92 79.66,43.92 79.42,43.68 79.42,43.52 79.47,43.47 79.99,42.95 79.99,42.78 79.75,42.54 79.59,42.54 79.01,43.12 78.85,43.12 78.61,42.87 78.61,42.71 79.18,42.14 79.18,41.98 78.94,41.73 78.78,41.73 78.21,42.31 78.04,42.31 77.8,42.07 77.8,41.9 78.38,41.33 78.38,41.17 78.13,40.93 77.97,40.93 77.4,41.5 77.24,41.5 71.33,35.59 65.99,35.59 64.42,34.02 64.42,32.86 v1(63.83,32.27)
  BOTTOM w0.076: v1(82.33,69.22) U1.AU43
  BOTTOM w0.165: v1(63.83,32.27) 63.38,32.27 62.28,33.38 J21.157
-M_A_DDRCLK0_1866M: length 59
  IN1 w0.089: v1(76.79,69.28) 77.07,69.56 77.21,69.56 77.31,69.45 77.31,68.82 77.7,68.44 77.7,65.26 79.8,63.16 79.8,52.33 79.14,51.67 79.14,51.39 79.44,51.09 79.44,50.96 79.18,50.7 79.05,50.7 78.75,51 78.47,51 78.1,50.63 78.1,50.34 78.39,50.04 78.39,49.92 78.13,49.66 78.01,49.66 77.71,49.96 77.42,49.96 68.19,40.73 62.63,40.73 56.99,35.08 56.99,33.06 56.99,33.06 56.99,33.04 56.8,32.86 56.8,32.75 56.68,32.63 56.44,32.63 56.29,32.78 56.29,32.91 56.55,33.17 v1(56.55,33.17)
  BOTTOM w0.076: U1.AU53 v1(76.79,69.28)
  BOTTOM w0.102: J21.139 55.78,34.31 55.64,34.18 55.64,33.14 55.74,33.03 56.19,32.58 56.53,32.58 56.7,32.75 56.7,33.02 v1(56.55,33.17)
-M_A_DDRCLK1_1866M: length 59.8
  IN1 w0.089: v1(75.84,69.24) 76.08,69.24 76.15,69.17 76.15,66.84 76.81,66.18 76.81,65.13 79.11,62.83 79.11,52.61 67.91,41.41 62.35,41.41 55.86,34.93 55.86,33.45 55.5,33.09 55.5,29.78 55.23,29.51 55.11,29.51 54.92,29.7 v1(54.92,30.23)
  BOTTOM w0.076: v1(75.84,69.24) 75.84,69.25 U1.AU55
  BOTTOM w0.102: J21.140 56.03,28.08 55.88,28.23 55.88,29.18 55.48,29.58 55.14,29.58 54.92,29.8 v1(54.92,30.23)
-M_A_DQS0: length 74
  IN1 w0.094: v1(60.51,72.72) 60.73,72.5 60.73,72.29 60.41,71.96 57.41,71.96 53.05,67.6 53.05,63.26 42.32,52.53 42.18,52.53 41.95,52.76 41.62,52.76 41.23,52.38 41.23,52.04 41.46,51.81 41.46,51.67 41.21,51.42 41.07,51.42 40.83,51.65 40.5,51.65 40.12,51.26 40.12,50.93 40.35,50.7 40.35,50.55 40.1,50.3 39.95,50.3 39.72,50.53 39.39,50.53 39,50.15 39,49.82 39.23,49.58 39.23,49.44 38.6,48.8 37.57,48.8 23.99,35.22 23.99,32.7 23.89,32.6 23.64,32.6 23.53,32.71 v1(23.53,33.29)
  BOTTOM w0.076: U1.AM70 67.86,72.65 67.94,72.74 67.94,72.79 67.82,72.92 67.8,72.93 67.61,72.93 67.49,72.87 67.28,72.87 67.09,72.94 66.99,72.94 66.84,72.88 66.29,72.88 66.2,72.97 65.77,72.97 65.38,72.57 63.63,72.57 63.1,72.05 62.63,72.05 62.61,72.03
  BOTTOM w0.109: v1(23.53,33.29) 23.53,32.74 23.64,32.62 23.81,32.62 24.02,32.84 24.02,33.64 23.93,33.73 23.93,34.26 23.78,34.41 J21.11 ; 62.61,72.03 60.96,72.03 60.73,72.26 60.73,72.5 v1(60.51,72.72)
-M_A_DQS1: length 66.3
  IN1 w0.094: v1(28.83,28.96) 28.83,29.36 29.03,29.55 29.43,29.55 29.88,30.01 29.88,34.35 51.61,56.07 52.76,56.07 56.97,60.28 59.8,60.28 63.5,63.98 63.5,68.87 63.7,69.07 v1(63.77,69.07)
  BOTTOM w0.076: v1(63.77,69.07) 64.1,69.39 64.96,69.39 65.31,69.74 66.32,69.74 66.49,69.91 66.82,69.91 66.93,69.85 67.1,69.85 67.29,69.91 67.46,69.91 67.59,69.85 67.79,69.85 68.02,69.96 68.11,70.04 68.11,70.25 68.16,70.3 U1.AT69
  BOTTOM w0.109: J21.32 29.03,27.83 29.16,27.97 29.16,28.3 29.39,28.52 29.39,29.47 29.18,29.68 28.94,29.68 28.83,29.57 v1(28.83,28.96)
-M_A_DQS2: length 55.5
  IN4 w0.076: v1(70.3,74.29) 69.59,74.29 69.17,73.88 68.43,73.88 66.97,72.41 66.97,71.87 66.95,71.86 66.95,71.84
  IN4 w0.094: v1(72.3,28.94) 72.3,29.46 72.18,29.57 71.78,29.57 71.54,29.81 71.54,31.22 72.21,31.9 72.21,49.76 66.33,55.65 66.33,67.41 66.95,68.03 66.95,71.84
  BOTTOM w0.076: U1.AH66 v1(70.3,74.29)
  BOTTOM w0.109: v1(72.3,28.94) 72.3,29.5 72.43,29.63 72.67,29.63 72.84,29.47 72.84,28.27 72.68,28.11 72.68,27.91 72.53,27.75 J21.198
-M_A_DQS3: length 70
  IN4 w0.094: v1(66.85,32.65) 66.85,32.33 66.96,32.23 67.3,32.23 67.48,32.4 67.48,34.25 66.85,34.87 66.85,35.65 67.28,36.07 67.28,36.5 67.18,36.6 66.91,36.6 66.68,36.83 66.68,37.38 66.79,37.5 66.91,37.61 67.17,37.61 67.28,37.72 67.28,38.08 67.18,38.18 66.92,38.18 66.91,38.19 66.67,38.43 66.67,38.71 66.67,38.95 66.67,38.95 66.85,39.13 66.85,39.13 66.91,39.19 67.18,39.19 67.29,39.29 67.29,39.65 67.18,39.75 66.92,39.75 66.9,39.77 66.68,39.99 66.68,40.53 66.75,40.61 66.92,40.77 67.18,40.77 67.28,40.87 67.28,41.23 67.18,41.33 66.92,41.33 66.68,41.57 66.68,41.86 66.68,42.11 66.91,42.34 67.17,42.34 67.28,42.45 67.28,42.8 67.19,42.89 66.93,42.89 66.68,43.14 66.68,43.68 66.79,43.8 66.91,43.91 67.17,43.91 67.29,44.03 67.29,44.37 67.18,44.48 66.92,44.48 66.68,44.72 66.68,45.01 66.68,45.01 66.68,45.26 66.91,45.49 67.17,45.49 67.28,45.6 67.28,49.45 55.57,61.16 55.57,67.16 57.08,68.67 57.08,71.47 57.08,71.72 59.1,73.74 62.3,73.74 63.11,74.55 63.11,74.81 v1(62.88,75.03)
  BOTTOM w0.076: v1(62.88,75.03) 63.02,75.03 63.23,74.82 63.23,74.6 63.26,74.58 63.5,74.34 63.64,74.34 64.19,74.34 64.77,74.91 66.82,74.91 66.96,74.86 67.13,74.86 67.28,74.92 67.42,74.92 67.63,74.86 67.8,74.86 68.03,74.97 68.1,75.04 68.16,75.1 U1.AG69
  BOTTOM w0.109: v1(66.85,32.65) 66.85,32.04 66.94,31.96 67.5,31.96 67.77,32.23 67.77,32.86 67.41,33.21 67.41,34.07 67.28,34.21 J21.177
-M_A_DQS4: length 60.7
  IN1 w0.094: v1(34.69,31.97) 34.69,32.31 34.83,32.45 35.1,32.45 35.32,32.67 35.32,34.3 43.69,42.66 45.05,42.66 58.03,55.64 58.2,55.64 58.4,55.44 58.71,55.44 59.08,55.81 59.08,56.11 58.87,56.31 58.87,56.49 59.05,56.66 61.96,56.66 64.09,58.79 64.09,59.21 64.96,60.08 65.05,60.08 v1(65.27,59.86)
  BOTTOM w0.076: U1.BA64 70.99,67.47 70.91,67.4 70.91,67.04 70.85,66.88 70.85,66.75 70.91,66.62 70.91,66.21 70.75,66.05 70.75,65.26 69.85,64.37 68.02,64.37 68,64.35 67.98,64.35
  BOTTOM w0.109: J21.53 34.28,34.4 34.42,34.25 34.42,33.95 33.92,33.44 33.92,32.94 34.35,32.5 34.59,32.5 34.69,32.4 v1(34.69,31.97) ; 67.98,64.35 66.78,64.35 66.39,63.96 66.39,60.69 65.85,60.14 65.53,60.14 65.27,59.89 v1(65.27,59.86)
-M_A_DQS5: length 59.9
  IN1 w0.094: v1(39.32,28.95) 39.32,29.14 39.48,29.31 39.84,29.31 40.15,29.61 40.15,31.1 41.2,32.15 41.2,33.79 54.03,46.63 54.94,46.63 61.46,53.15 64,53.15 69.85,59 69.85,61.58 70.43,62.15 71.08,62.15 v1(71.21,62.02)
  BOTTOM w0.076: U1.AY60 73.59,67.81 73.87,67.52 73.87,67.1 73.94,66.87 73.94,66.72 73.87,66.58 73.87,66.33 74.05,66.16 74.05,65.36 72.32,63.64 72.32,63.61
  BOTTOM w0.109: J21.74 39.53,28.01 39.67,28.15 39.67,28.46 39.86,28.65 39.86,29.17 39.68,29.35 39.43,29.35 39.32,29.24 v1(39.32,28.95) ; v1(71.21,62.02) 71.63,62.43 71.63,62.53 71.77,62.68 71.77,63.05 72.32,63.61
-M_A_DQS6: length 49.4
  IN4 w0.076: 70.71,66.33 70.71,66.35 70.69,66.37 70.69,66.67 70.42,66.94 70.42,68.72 70.03,69.11 70.03,70.23 69.96,70.29 69.96,70.71 70.04,70.78 70.16,70.78 v1(70.39,70.55)
  IN4 w0.094: 70.71,66.33 70.71,64.85 71.83,63.73 71.83,55.9 77.95,49.78 77.95,31.92 78.16,31.71 78.31,31.71 78.39,31.8 v1(78.39,32.39)
  BOTTOM w0.076: U1.AR66 70.03,70.91 v1(70.39,70.55)
  BOTTOM w0.109: J21.219 77.78,34.13 77.92,33.98 77.92,33.59 78.85,32.65 78.85,31.79 78.74,31.68 78.51,31.68 78.39,31.8 v1(78.39,32.39)
-M_A_DQS7: length 51.6
  IN4 w0.076: v1(73.14,70.55) 72.9,70.78 72.82,70.78 72.74,70.71 72.74,70.36 72.77,70.33 72.77,69.11 73.19,68.69 73.19,67.73 74.5,66.42 74.5,66.2 74.51,66.19 74.51,66.17
  IN4 w0.094: 74.51,66.17 74.51,65.91 76.58,63.84 76.58,57.08 83.24,50.42 83.24,29.97 83.67,29.54 83.8,29.54 84.03,29.76 v1(84.03,30.21)
  BOTTOM w0.076: v1(73.14,70.55) 72.77,70.91 U1.AR61
  BOTTOM w0.109: v1(84.03,30.21) 84.03,29.78 83.91,29.67 83.44,29.67 83.18,29.41 83.18,28.16 83.03,28.01 J21.240
-M_A_DQS8: length 3.4
  TOP w0.127: TP30.1 44.18,33.36 44.64,33.82 v1(44.97,33.82)
  BOTTOM w0.127: v1(44.97,33.82) 44.78,34.01 J21.95
-M_A_ODT0: length 62.5
  IN1 w0.076: 84.11,65.85 84.11,66.86 81.96,69.01 81.96,69.52 v1(82.33,69.89)
  IN1 w0.114: 84.11,65.85 84.11,65.42 84.53,64.99 84.53,49.36 83.8,48.62 83.8,48.46 84.37,47.88 84.37,47.72 84.13,47.48 83.97,47.48 83.39,48.05 83.23,48.05 82.99,47.81 82.99,47.65 83.56,47.08 83.56,46.91 83.32,46.67 83.16,46.67 82.59,47.25 82.42,47.25 82.18,47 82.18,46.84 82.76,46.27 82.76,46.11 82.51,45.86 82.35,45.86 81.78,46.44 81.62,46.44 71.17,35.99 65.43,35.99 63.41,33.97 63.41,32.05 v1(63.83,31.64)
  BOTTOM w0.076: U1.AT45 v1(82.33,69.89)
  BOTTOM w0.165: v1(63.83,31.64) 63.41,31.64 61.78,33.27 J21.155
-M_A_ODT1: length 64.9
  IN1 w0.076: 84.41,67.7 82.81,69.3 82.81,70 v1(82.29,70.53)
  IN1 w0.114: 84.41,67.7 85.32,66.8 85.32,47.41 77.72,39.81 77.56,39.81 77.12,40.25 76.95,40.25 76.71,40.01 76.71,39.85 77.16,39.4 77.16,39.24 76.92,39 76.75,39 76.31,39.45 76.15,39.45 75.9,39.2 75.9,39.04 76.35,38.6 76.35,38.43 76.11,38.19 75.95,38.19 75.5,38.64 75.34,38.64 75.1,38.39 75.1,38.23 75.54,37.79 75.54,37.63 75.3,37.38 75.14,37.38 74.69,37.83 74.53,37.83 74.29,37.59 74.29,37.43 74.73,36.98 74.73,36.82 74.49,36.57 74.33,36.57 73.88,37.02 73.72,37.02 73.48,36.78 73.48,36.62 73.92,36.17 73.92,36.01 72.84,34.92 69.49,34.92 67.6,33.03 67.6,31.52 67,30.92 66.36,30.92 66.02,31.25 v1(65.8,31.25)
  BOTTOM w0.076: v1(82.29,70.53) U1.AT43
  BOTTOM w0.165: J21.161 63.28,33.9 63.74,33.44 63.99,33.44 64.47,32.96 64.47,32.75 64.96,32.27 64.96,31.66 65.36,31.25 v1(65.8,31.25)
-M_A_RAS: length 57.9
  IN1 w0.076: 82.57,63.94 82.57,64.24 81.87,64.93 81.87,66.2 80.87,67.21 80.87,67.96 v1(79.55,69.29)
  IN1 w0.114: 82.57,63.94 82.57,50.17 82.45,50.06 79.23,46.84 78.22,46.84 69.34,37.96 64.62,37.96 60.22,33.56 60.22,33.11 60.33,32.99 60.63,32.99 60.75,32.88 60.75,32.53 60.63,32.42 60.33,32.42 60.22,32.31 60.22,30.94 v1(60.89,30.26)
  BOTTOM w0.076: U1.AU50 v1(79.55,69.29)
  BOTTOM w0.165: J21.152 61.03,28.58 60.77,28.84 60.77,29.96 60.89,30.08 v1(60.89,30.26)
-M_A_WE: length 58.4
  IN1 w0.076: v1(80.45,70.55) 80.91,70.09 80.91,69.81 81.49,69.22 81.49,67.78 82.84,66.43 82.84,65.54 83.35,65.04
  IN1 w0.114: 83.35,65.04 83.75,64.64 83.75,49.68 73.84,39.78 72.83,39.78 69.83,36.78 65.11,36.78 62.53,34.2 v1(62.53,31.04)
  BOTTOM w0.076: v1(80.45,70.55) U1.AT46
  BOTTOM w0.165: v1(62.53,31.04) 60.78,32.79 J21.151
-MIC_HW_EN: length 3.4
  TOP w0.254: v1(101.1,74.28) 101.37,74.28 v4(101.58,74.49) 101.94,74.84 101.94,75.45 101.63,75.76 RC35.2 RC152.1
  BOTTOM w0.076: U1.AH11 101.36,74.54 v1(101.1,74.28)
-NFC_DTCT: length 47
  IN3 w0.081: v1(113.95,81.65) 116.49,79.11 118.95,79.11 120.67,77.39 125.98,77.39 129.02,74.36 130.32,74.36 134.62,70.07 134.62,69.21 135.39,68.44 137.55,68.44 137.63,68.52 138.95,68.52 141,66.46 141,65.26 v1(140.62,64.88)
  BOTTOM w0.102: v1(113.95,81.65) 113.53,82.07 113.05,82.07 112.72,81.73 112.22,81.73 111.55,81.06 109.63,81.06 109.21,80.64 108.13,80.64 107.49,80 106.66,80 106.37,79.7 U1.V2 ; v1(140.62,64.88) 140.32,64.88 139.9,65.3 R394.2 139.58,65.42 139.48,65.31 J26.7
-PAD_RESET: length 103.8
  TOP w0.102: U16.J7 v1(232.71,80.05) ; R375.2 225.05,70.71 225.05,70.27 C157.1 224.56,69.77 v1(224.56,69.14)
  IN1 w0.076: v1(166.6,63.32) 166.63,63.36 171.76,63.36 172.58,62.55 173.64,62.55 173.92,62.83 v1(173.92,63.08)
  IN4 w0.076: v1(173.92,63.08) 174,63.16 177.35,63.16 177.94,62.57 180.32,62.57 181.64,61.25 183.17,61.25 184.51,62.6 194.09,62.6 194.52,63.03 195.39,63.03 195.74,62.67 198.89,62.67 200.14,61.43 200.14,60.87 201.89,59.12 221.78,59.12 223.71,61.05 224.14,61.05 v1(224.55,60.64)
  BOTTOM w0.102: v1(166.6,63.32) 166.6,62.46 167.34,61.71 167.34,61.33 168.1,60.57 J16.17 ; v1(232.71,80.05) 233.11,79.65 233.11,73.24 233.54,72.81 233.54,72.43 233.51,72.4 233.51,71.56 232.64,70.69 232.64,66.6 231.91,65.87 231.4,65.87 230.97,66.31 228.13,66.31 226.94,67.5 226.19,67.5 225.21,68.49 225.21,68.69 224.76,69.14 v1(224.56,69.14) 224.47,69.05 224.47,68.23 225.66,67.04 225.66,66.23 226.04,65.85 226.04,63.4 224.55,61.91 v1(224.55,60.64)
-PCH_SLP_LAN: length 218.5
  TOP w0.102: v1(246.08,58.86) 246.46,59.24 246.46,60.29 v1(245.75,61) ; v1(223.5,76.39) 223.22,76.11 222.44,76.11 222.28,76.26 R201.2 ; U16.F10 v1(229.55,76.9)
  IN1 w0.076: v1(229.55,76.9) 229.73,76.9 230.36,77.53 231.76,77.53 231.94,77.71 239.2,77.71 239.38,77.53 239.38,75.02 239.85,74.54 240.69,74.54 240.77,74.46 241.64,74.46 242,74.1 242.93,74.1 243.75,74.92 243.75,75.2 244.98,76.43 245.99,76.43 246.77,75.65 246.77,75.02 248.04,73.75 248.04,67.47 245.07,64.5 245.07,61.97 245.75,61.29 v1(245.75,61) ; v1(100.67,63.89) 100.67,63.5 102.97,61.2 104.02,61.2 104.48,60.74 106.59,60.74 107.31,61.47 117.32,61.47 121.6,57.19 123.94,57.19 126.1,55.03 127.26,55.03 127.59,54.7 127.59,53.86 128.1,53.35 132.27,53.35 133.94,55.03 153.17,55.03 156.78,58.64 156.78,59.48 159.18,61.88 161.03,61.88 161.39,61.52 167.33,61.52 168.16,60.69 171.18,60.69 171.81,61.32 176.09,61.32 177.07,60.34 185.71,60.34 186.84,59.21 210.72,59.21 210.98,59.47 220.91,59.47 223.35,61.91 239.2,61.91 240.22,60.89 240.22,60.49 240.34,60.36 240.83,60.36 241.72,59.47 243.72,59.47 244.81,58.38 245.6,58.38 v1(246.08,58.86)
  BOTTOM w0.076: 100.14,64.63 98.98,65.79 98.98,66.25 99.07,66.34 99.07,67.81 98.91,68.15 98.75,68.3 U1.AW15
  BOTTOM w0.102: v1(229.55,76.9) 229.27,77.18 229.27,77.79 228.2,78.85 227.82,78.85 227.19,78.22 227.19,76.87 226.7,76.39 224.62,76.39 224.34,76.11 223.78,76.11 v1(223.5,76.39)
  BOTTOM w0.127: RC64.1 v1(100.67,63.89) 100.67,64.1 v4(100.39,64.38) 100.14,64.63
-PCH_SLP_M: length 226.1
  TOP w0.102: J41.6 256.76,105.2 256.52,104.96 255.66,104.96 254.42,103.72 253.57,103.72 252.82,102.97 251.24,102.97 251.23,102.96 250.96,102.96 TP47.1 249.74,100.47 v1(249.92,100.29) ; U21.F6 v1(250.15,77.12)
  IN3 w0.081: v1(250.15,77.12) 250.15,79.32 248.99,80.48 247.2,80.48 246.52,81.17 244.48,81.17 244.03,81.62 244.03,82.16 242.78,83.4 242.78,85.13 241.87,86.04 241.87,87.16 241.06,87.97 239.35,87.97 239.05,88.28 236.58,88.28 235.8,87.49 230.43,87.49 229.92,86.98 226.22,86.98 225.95,86.71 219.88,86.71 215.73,82.56 215.73,78.35 212.02,74.64 212.02,74.27 207.81,70.05 207.81,68.97 207.4,68.57 204.99,68.57 204.02,67.6 203.11,67.6 202.76,67.26 200.76,67.26 200.42,67.6 198.84,67.6 197.63,66.39 195.05,66.39 194.88,66.22 189.74,66.22 189.12,65.6 182.85,65.6 182.42,66.03 176.46,66.03 176.42,66.08 175.28,66.08 174.8,65.6 168.99,65.6 168.29,64.91 165.21,64.91 162.52,62.22 159.45,62.22 158.33,61.1 158.33,60.85 156.75,59.27 154.75,59.27 154.31,58.84 148.46,58.84 147.57,59.73 143.6,59.73 143.42,59.55 138.03,59.55 136.59,61 135.9,61 134.05,62.85 129.68,62.85 128.3,64.22 127.29,64.22 125.97,65.54 125.18,65.54 124.57,66.15 123.15,66.15 122.75,66.55 122.75,67.89 122.08,68.57 120.73,68.57 118.34,70.95 105.98,70.95 103.92,68.9 102.19,68.9 101.96,69.13 101.96,71.46 101.38,72.05 101.02,72.05 100.19,72.88 99.42,72.88 99.27,72.73 99.27,72.33 v1(98.76,71.82)
  BOTTOM w0.102: U1.AN16 98.68,71.82 v1(98.76,71.82) ; v1(249.92,100.29) 249.32,99.69 v3(248.9,99.69) 248.21,99.69 244.71,96.19 244.71,93.61 245.6,92.72 245.6,92.16 248.65,89.11 248.65,86.24 249.21,85.68 249.21,84.95 249.03,84.77 249.03,83.71 249.31,83.43 249.31,81.95 250.06,81.21 250.06,77.22 v1(250.15,77.12)
-PCH_SLP_S0: length 313.5
  TOP w0.102: D63.1 88.85,94.14 88.85,92.96 90.1,91.7 v1(90.1,89.72) ; v1(265.69,109.75) 265.58,109.64 TP45.1 263.61,110.28 253.07,110.28 252.26,109.47 J41.15
  IN3 w0.081: v1(94.17,80.35) 94.36,80.55 94.36,81.47 93.96,81.88 93.22,81.88 92.79,82.31 92.79,82.69 91.88,83.6 91.88,84.24 90.89,85.23 89.49,85.23 88.25,86.47 88.25,88.56 89.42,89.72 v1(90.1,89.72)
  IN4 w0.076: 103.53,72.58 103.91,72.96 105.04,72.96 106.38,74.31 106.38,75.81 105.24,76.95 95.64,76.95 93.63,78.96 93.63,79.82 v1(94.17,80.35) ; 103.53,72.58 102.9,71.95 102.9,71.79 102.61,71.49 102.12,71.49 101.9,71.27 101.9,70.92 v1(101.53,70.55) ; 103.53,72.58 104.09,72.02 110.83,72.02 111.96,70.89 119.28,70.89 119.85,70.32 124.16,70.32 126.78,67.7 127.39,67.7 127.92,68.24 128.38,68.24 128.74,67.87 128.74,67.47 129.43,66.78 129.84,66.78 130.48,66.13 130.48,65.01 130.56,64.94 130.56,64.63 130.81,64.38 131.01,64.38 131.88,63.52 131.88,62.83 132.3,62.42 132.3,61.8 131.99,61.49 131.99,58.5 136.37,54.12 140.22,54.12 140.78,53.56 140.78,50.33 142.2,48.91 195.18,48.91 195.44,49.16 198.38,49.16 200.17,47.37 205.66,47.37 208.7,50.41 212.99,50.41 213.57,50.99 215.86,50.99 217.08,52.22 224.44,52.22 225.36,51.29 227.21,51.29 227.59,50.91 237.65,50.91 238.71,49.85 238.71,49.14 240.2,47.65 242.87,47.65 244.28,49.06 244.28,53.1 241.56,55.81 241.56,57.35 242.85,58.64 244.59,58.64 244.81,58.41 246.24,58.41 246.72,58.89 247.98,58.89 249.01,57.87 251.27,57.87 252.33,58.94 252.33,63.58 253.13,64.37 254.01,64.37 256.99,67.35 264.56,67.35 268.54,71.34 268.54,84.18 269.13,84.77 269.13,86.97 265.03,91.07 265.03,109.09 v1(265.69,109.75)
  BOTTOM w0.076: U1.AT11 101.31,70.55 v1(101.53,70.55)
-PCH_SLP_S3: length 247.3
  TOP w0.102: J41.2 258.76,104.26 TP42.1 258.3,102.48 258.25,102.42 v3(258.25,102.3) 257.74,102.3 257.36,102.68 253.65,102.68 252.66,101.69 251.62,101.69 v1(251.48,101.83) ; D60.1 247.41,85 v1(247.66,85.25) 248.15,85.75 248.15,86.03 D65.1 ; v1(249.35,78.75) 249.75,78.35 U21.H7 ; v1(228.75,77.7) U16.G11
  IN1 w0.076: v1(220.75,57.68) 220.75,57.68 220.62,57.55 217.78,57.55 217.65,57.68 217.1,57.68 216.26,58.51 211.69,58.51 211.25,58.06 209.36,58.06 208.45,57.16 207.48,57.16 206.37,58.27 186.41,58.27 185.28,59.4 176.26,59.4 176.02,59.16 170.55,59.16 170.44,59.27 166.25,59.27 164.93,60.59 161.48,60.59 161.15,60.26 158.64,60.26 157.57,59.19 157.57,58.35 153.42,54.2 134.39,54.2 132.77,52.58 127.45,52.58 123.6,56.43 121.29,56.43 117.15,60.57 108.75,60.57 106.66,58.47 104.24,58.47 102.41,56.64 101.48,56.64 98.94,59.18 98.94,60.24 98.4,60.78 98.4,66.13 100.1,67.84 100.1,69.44 99.67,69.87 v1(99.67,71.32) ; v1(249.35,78.75) 248.98,78.75 247.8,77.57 245.97,77.57 245.15,76.75 244.03,76.75 242.92,75.64 242.39,75.64 241.25,76.78 240.84,76.78 240.71,76.66 240.14,76.66 239.9,76.9 239.9,77.47 239.48,77.89 231.84,77.89 231.66,77.71 228.77,77.71 v1(228.75,77.7)
  BOTTOM w0.102: v1(99.67,71.32) 99.44,71.32 U1.AP15 ; v1(251.48,101.83) 249.44,101.83 243.82,96.22 243.82,95.24 243.06,94.47 243.06,93.59 244.81,91.84 244.81,91.58 246.99,89.4 246.99,87.18 247.66,86.51 v1(247.66,85.25) 247.48,85.08 247.48,81.85 248.37,80.96 248.37,79.64 249.26,78.75 v1(249.35,78.75) ; v1(220.75,57.68) 218.35,60.08 218.35,61.63 218.68,61.96 218.68,63.77 216.93,65.52 216.93,67.07 217.43,67.58 217.43,71.69 218.35,72.61 219.95,72.61 221.42,74.08 221.42,75.25 221.98,75.81 223,75.81 223.17,75.63 224.67,75.63 225.02,75.97 227,75.97 228.72,77.7 v1(228.75,77.7)
-PCH_SLP_S4: length 262.2
  TOP w0.102: U16.G12 v1(227.95,78.45) ; v1(250.28,100.85) 250.5,101.08 250.5,101.94 251.28,102.72 252.93,102.72 253.55,103.34 v3(254.06,103.34) 255.05,103.34 TP48.1 256.36,104.65 256.94,104.65 257.26,104.97 J41.5 ; U21.J7 v1(249.37,79.5)
  IN1 w0.076: v1(227.95,78.45) 229.25,78.45 229.81,77.89 231.58,77.89 231.75,78.06 241.67,78.06 242.06,77.67 245.54,77.67 246.28,78.41 248.29,78.41 v1(249.37,79.5) ; v1(108.85,62.06) 108.26,62.65 106.84,62.65 106.02,61.82 106.02,61.39 105.67,61.05 104.66,61.05 104.15,61.56 103.11,61.56 101.48,63.18 101.48,63.89 100.91,64.46 99.72,64.46 99.03,63.78 99.03,62.81 v1(99.45,62.39) 99.84,62 99.84,60.55 99.46,60.17 99.46,59.09 101.61,56.95 102.28,56.95 104.11,58.78 106.53,58.78 108.63,60.87 117.27,60.87 121.41,56.73 123.74,56.73 127.59,52.88 132.64,52.88 134.27,54.51 153.3,54.51 157.26,58.47 157.26,59.31 158.54,60.59 160.97,60.59 161.29,60.91 167.02,60.91 167.95,59.98 171.76,59.98 172.45,60.67 175.37,60.67 176.34,59.7 185.43,59.7 186.56,58.57 206.52,58.57 207.63,57.47 208.33,57.47 209.28,58.42 211.02,58.42 211.46,58.86 217.4,58.86 218.31,57.95 v1(218.47,57.95)
  IN4 w0.076: v1(108.85,62.06) 109.92,61 118.32,61 v1(119.74,62.42)
  BOTTOM w0.076: 98.59,64.83 98.59,65.25 98.2,65.64 98.2,67.44 U1.BA16
  BOTTOM w0.102: 98.59,64.83 98.59,63.26 v1(99.45,62.39) ; v1(119.74,62.42) 120.55,62.42 PR302.1 ; v1(250.28,100.85) 249.06,100.85 244.36,96.15 244.36,93.43 245.34,92.45 245.34,91.92 248.35,88.91 248.35,83.6 248.78,83.17 248.78,81.57 249.37,80.97 v1(249.37,79.5) ; v1(227.95,78.45) 227.49,77.99 227.49,76.85 226.83,76.19 224.85,76.19 224.52,75.86 223.38,75.86 223.15,76.09 221.24,76.09 220.88,76.45 220.07,76.45 219.81,76.19 217.84,76.19 215.33,73.67 215.33,70.22 215.81,69.74 216.8,69.74 217.2,69.33 217.2,67.8 216.65,67.25 216.65,65.09 216.93,64.81 216.93,60.99 218.16,59.76 218.16,58.26 v1(218.47,57.95)
-PCH_SLP_S5: length 231.4
  TOP w0.102: J41.4 257.76,105.01 257.4,104.64 257.4,103.83 TP43.1 256.5,102.93 253.5,102.93 252.71,102.15 252.43,102.15 v3(252.41,102.17) 252.29,102.29 251.33,102.29 250.96,101.92 v1(250.96,101.26) ; U21.J8 248.95,79.7 v1(248.85,79.79)
  IN3 w0.081: v1(97.88,63.94) 98.36,64.43 98.36,65.16 98.74,65.55 102.67,65.55 103.17,65.05 105.43,65.05 107.07,63.41 107.5,63.41 108.11,64.02 109.51,64.02 111.22,65.73 111.22,66.17 113.34,68.29 116.27,68.29 118.53,66.02 118.53,60.68 119.82,59.39 121.6,59.39 122.81,58.18 123.83,58.18 126.2,55.82 127.82,55.82 128.23,56.22 133.63,56.22 134.2,55.65 136.04,55.65 136.76,56.37 139.93,56.37 140.44,55.86 157.11,55.86 158.08,56.83 160,56.83 161.17,58 161.17,59.02 162.31,60.16 164.52,60.16 165.64,61.28 166.3,61.28 167.48,62.46 172.06,62.46 172.4,62.12 174.33,62.12 175.27,63.05 176.18,63.05 177.08,63.95 180.75,63.95 181.34,63.36 181.36,63.36 181.5,63.36 181.5,63.36 182.56,63.36 183.22,62.7 185.53,62.7 186.19,63.36 190.56,63.36 191.27,64.07 192.8,64.07 193.23,63.64 195.21,63.64 195.9,64.32 199.04,64.32 199.7,63.66 203.26,63.66 205.01,65.42 207.58,65.42 208.19,64.81 209.89,64.81 210.26,65.18 210.26,66.85 211.59,68.19 212.51,68.19 212.99,68.67 212.99,69.18 213.34,69.53 213.65,69.53 214.41,70.29 214.41,72.28 217.04,74.9 217.04,75.59 218.55,77.1 218.55,80.12 220.56,82.13 221.19,82.13 221.68,82.61 221.68,83.73 222.34,84.39 227.01,84.39 227.95,85.33 238.24,85.33 240.24,83.32 240.67,83.32 240.85,83.5 242.38,83.5 243.8,82.08 243.8,80.9 244.55,80.15 248.5,80.15 v1(248.85,79.79)
  BOTTOM w0.076: U1.AY16 97.9,67.84 97.9,67.18 98.04,67.04 98.04,65.57 98.36,65.25 98.36,64.3 98,63.94 v1(97.88,63.94)
  BOTTOM w0.102: v1(248.85,79.79) 248.85,80.96 247.88,81.94 247.88,84.61 248.08,84.81 248.08,88.82 245.11,91.79 245.11,92.12 244.08,93.15 244.08,96.18 249.26,101.36 250.86,101.36 v1(250.96,101.26)
-PCH_SLP_SUS: length 229.7
  TOP w0.102: v1(245.59,62.06) 245.11,61.58 245.11,60.9 244.51,60.3 244.51,59.95 243.95,59.4 243.42,59.4 241.94,57.92 241.94,57.35 242.34,56.95 v1(242.34,56.41) ; U16.K12 v1(227.95,80.85)
  IN1 w0.076: v1(99.65,71.89) 99.26,71.5 99.26,69.2 98.88,68.83 98.88,67.14 97.31,65.57 97.31,62.61 98.03,61.9 98.03,59.65 98.77,58.91 98.83,58.91 101.25,56.49 102.47,56.49 104.3,58.32 106.72,58.32 108.82,60.41 117.07,60.41 121.24,56.25 123.56,56.25 127.39,52.42 132.83,52.42 134.44,54.04 153.47,54.04 157.72,58.28 157.72,59.12 158.7,60.11 161.3,60.11 161.6,60.41 164.78,60.41 166.07,59.12 170.19,59.12 170.3,59.01 176.12,59.01 176.36,59.24 185.18,59.24 186.32,58.1 206.31,58.1 207.4,57.01 208.52,57.01 209.38,57.87 211.52,57.87 211.97,58.33 216.16,58.33 216.99,57.5 217.55,57.5 217.68,57.37 220.5,57.37 220.63,57.24 220.96,57.24 221.21,57.49 221.21,58.8 223.68,61.28 235.72,61.28 236.53,60.46 236.71,60.46 238.03,59.14 240.47,59.14 241.4,58.21 241.4,57.25 242.24,56.41 v1(242.34,56.41) ; v1(227.95,80.85) 227.95,80.6 228.33,80.23 228.33,79.17 228.67,78.83 231.38,78.83 232.19,79.64 236.98,79.64 237.38,79.23 240.83,79.23 241.51,78.55 243.39,78.55 244.07,77.88 245.26,77.88 247.6,80.21 249.25,80.21 249.79,79.67 249.79,78.6 249.52,78.33 249.21,78.33 248.24,77.36 248.24,67.42 245.29,64.47 245.29,62.36 v1(245.59,62.06)
  BOTTOM w0.076: v1(99.65,71.89) 99.57,71.89 99.25,72.21 U1.AN15
-PCH_SLP_WLAN: length 168.1
  TOP w0.102: v1(222.28,70.65) 222.28,70.28 222.64,69.93 222.64,68.97 v4(222.97,68.64) 224.67,68.64 225,68.97 225,69.43 225.38,69.81 225.38,70.32 227.95,72.89 227.95,72.9 U16.A12
  IN3 w0.081: v1(97.71,65.11) 97.71,65.86 98.51,66.66 102.27,66.66 103.55,65.38 105.61,65.38 106.52,64.47 107.58,64.47 107.71,64.35 109.28,64.35 110.8,65.87 110.8,66.31 113.13,68.63 116.44,68.63 118.86,66.21 118.86,61.02 119.12,60.76 120.85,60.76 123.06,58.55 123.97,58.55 125.66,56.86 131.61,56.86 131.99,57.24 133.18,57.24 134.4,56.02 135.9,56.02 136.58,56.7 140.58,56.7 141.04,56.24 157,56.24 157.97,57.21 159.85,57.21 160.67,58.03 160.67,59.09 162.06,60.48 164.34,60.48 165.72,61.86 166.23,61.86 167.45,63.08 172.35,63.08 172.91,62.52 174.1,62.52 175.09,63.51 176.08,63.51 176.85,64.28 180.93,64.28 181.5,63.71 181.63,63.71 182.79,63.71 183.42,63.08 185.13,63.08 185.76,63.71 190.4,63.71 191.11,64.42 193.16,64.42 193.61,63.97 195.08,63.97 195.77,64.66 199.73,64.66 199.88,64.81 203.91,64.81 204.91,65.81 207.13,65.81 207.23,65.91 208.53,65.91 211.01,68.39 212.23,68.39 212.81,68.97 212.81,69.43 213.17,69.79 213.62,69.79 214.21,70.37 214.21,72.31 216.85,74.95 216.85,75.98 v1(217.79,76.92)
  IN4 w0.076: v1(217.79,76.92) 218.5,76.21 219.71,76.21 219.94,76.45 220.73,76.45 221.51,75.66 221.51,74.6 222.82,73.29 222.82,72.02 222.92,71.92 222.92,71.28 v1(222.28,70.65)
  BOTTOM w0.076: v1(97.71,65.11) 97.71,66.39 U1.BB17
-PCIE0_CLK_100M: length 238.8
  TOP w0.102: U15.6 284.36,87.3 v1(284.5,87.44)
  IN1 w0.089: v1(284.5,87.44) 284.84,87.1 285.14,87.1 285.34,87.3 285.34,89.21 283.03,91.53 283.03,92.29 280.63,94.69 251.77,94.69 250.49,95.97 248.63,95.97 248.02,96.58 245.4,96.58 244.83,97.15 241.58,97.15 236.87,101.86 232.56,101.86 232.06,102.36 226.4,102.36 225.99,101.95 225.32,101.95 224.32,100.94 214.71,100.94 213.5,99.73 205.65,99.73 201.86,95.95 200.11,95.95 196.58,99.48 186.75,99.48 184.6,97.33 174.73,97.33 173.46,98.6 169.24,98.6 166.76,96.13 164.75,96.13 162.56,98.32 162.56,99.35 154.98,106.92 140.11,106.92 136.45,103.27 128.96,103.27 126.93,101.24 118.92,101.24 117.91,102.25 117.5,102.25 117.27,102.02 116.45,102.02 115.68,101.26 110.37,101.26 109.71,101.92 104.7,101.92 103.63,100.86 101.2,100.86 100.13,99.79 98.74,99.79 97.01,98.06 97.01,97.22 94.39,94.59 88.04,94.59 86.46,93.01 86.46,90.7 85.96,90.21 83.33,90.21 83.04,90.5 82.57,90.5 v1(82.33,90.26)
  BOTTOM w0.076: U1.D42 82.87,87.43 82.58,87.72 82.58,87.88 82.49,87.97 82.49,88.22 82.44,88.34 82.44,88.62 82.48,88.72 82.48,88.87 82.44,88.99 82.44,89.28 82.72,89.8 82.72,90.42 82.65,90.5 82.57,90.5 v1(82.33,90.26)
-PCIE1_CLK_100M: length 177
  TOP w0.102: v1(214.3,52.82) 214.07,53.05 214.07,55.03 212.6,56.51 212.6,56.85 v1(212.82,57.08)
  IN4 w0.089: v1(212.82,57.08) 212.58,57.31 212.58,57.57 212.39,57.76 209.95,57.76 209.13,56.93 206.69,56.93 206.41,57.21 203.94,57.21 203.74,57.01 203.09,57.01 201.87,55.79 201.36,55.79 201.1,56.04 200.2,56.04 199.63,56.62 199.63,58.33 197.91,60.05 189,60.05 187.99,59.04 177.18,59.04 176.44,58.29 174.14,58.29 173.12,57.28 166.28,57.28 165.77,57.78 162.5,57.78 160.54,59.74 157.81,59.74 157.39,59.32 154.68,59.32 154.63,59.27 149.16,59.27 146.39,62.04 146.39,63.23 145.37,64.25 145.37,67.22 145.02,67.58 145.02,68.08 142.96,70.14 142.96,73.41 142.03,74.34 142.03,80.52 141.16,81.39 137.49,81.39 134.52,84.36 134.52,84.92 131.39,88.05 129.51,88.05 129.05,88.51 123.76,88.51 122.51,87.26 117.8,87.26 116.83,86.3 112.95,86.3 110.26,88.99 110.26,90.8 109.1,91.96 99.88,91.96 99.51,92.33 92.67,92.33 90.52,90.18 90.52,89.55 89.91,88.94 86.94,88.94 86.33,88.33 84.54,88.33 83.12,89.75 83.12,91.38 83.37,91.63 83.7,91.63 v1(83.88,91.45)
  BOTTOM w0.076: U1.B42 82.87,88.76 82.95,88.84 83.14,88.84 83.35,89.05 83.35,90.86 83.37,90.88 83.37,90.9
  BOTTOM w0.102: v1(83.88,91.45) 83.65,91.68 83.42,91.68 83.37,91.63 83.37,90.9 ; v1(214.3,52.82) J32.73
-PCIE2_CLK_100M: length 163.4
  IN4 w0.089: v1(84.54,90.85) 84.34,90.64 84.34,90.5 84.5,90.33 85.3,90.33 85.63,90 89.5,90 92.41,92.91 99.87,92.91 100.23,92.56 109.37,92.56 110.84,91.08 110.84,89.26 113.22,86.88 116.57,86.88 117.61,87.92 120,87.92 121.17,89.1 126.72,89.1 127.38,89.76 129.55,89.76 130.36,88.94 131.35,88.94 134.02,86.27 134.53,86.27 138.82,81.98 141.47,81.98 142.62,80.83 142.62,74.79 143.61,73.8 143.61,70.69 145.74,68.55 145.9,68.55 146.28,68.17 146.28,67.22 145.97,66.91 145.97,64.48 146.97,63.48 146.97,62.45 149.54,59.88 154.29,59.88 154.82,60.41 155.41,60.41 155.85,59.97 157.18,59.97 157.54,60.32 163.46,60.32 164.61,59.17 176.03,59.17 176.5,59.64 187.74,59.64 189.21,61.11 192.87,61.11 193.13,60.86 195.56,60.86 195.99,61.29 197.53,61.29 200.89,57.93 200.89,57.67 201.27,57.28 201.27,56.73 201.36,56.64 201.49,56.64 v1(201.73,56.89)
  BOTTOM w0.076: 84.04,90.14 83.73,89.83 83.73,88.05 83.43,87.75 U1.D41
  BOTTOM w0.102: J32.49 208.3,52.61 208.15,52.75 208.15,53.64 206.79,55.01 203.9,55.01 202.8,56.11 202.8,56.37 202.51,56.66 201.96,56.66 v1(201.73,56.89) ; 84.04,90.14 84.29,90.39 84.29,90.59 v1(84.54,90.85)
-PCIE3_CLK_100M: length 175
  TOP w0.102: UL1.45 213.26,66.5 213.17,66.4 213.17,64.08 212.41,63.33 v2(211.08,63.33) 209.88,63.33 207.88,61.33 207.88,59.37 208.52,58.74 208.52,57.42 208.35,57.24 208.35,56.56 208.59,56.31 v1(208.59,56.3)
  IN4 w0.089: v1(208.59,56.3) 208.47,56.3 207.87,55.7 207.55,55.7 207.35,55.9 203.1,55.9 202.18,54.99 200.84,54.99 200.62,55.22 199.89,55.22 198.85,56.26 198.85,58 197.61,59.24 189.55,59.24 188.57,58.27 177.53,58.27 175.75,56.49 165.95,56.49 165.49,56.95 162.14,56.95 160.93,58.15 157.29,58.15 157.18,58.05 154.71,58.05 154.26,58.5 148.75,58.5 144.6,62.65 144.6,65.94 143.52,67.02 143.52,68.37 142.19,69.71 142.19,73.02 141.25,73.96 141.25,80.16 140.79,80.62 137.17,80.62 133.75,84.04 133.75,84.6 131.06,87.28 127.45,87.28 127.19,87.03 123.4,87.03 122.86,86.49 119.39,86.49 118.27,85.37 116.32,85.37 115.71,84.76 113.24,84.76 112.67,85.33 112.67,85.45 112.11,86.02 111.49,86.02 109.45,88.06 109.45,90.46 108.73,91.17 100.05,91.17 99.91,91.03 98.09,91.03 97.58,91.54 92.99,91.54 91.31,89.86 91.31,89.18 90.15,88.02 87.18,88.02 86.53,87.38 85.75,87.38 85.45,87.08 84.63,87.08 84.36,87.35 84.01,87.35 83.84,87.18 83.84,86.9 83.93,86.8 v1(84.29,86.8)
  BOTTOM w0.102: v1(84.29,86.8) 84,87.09 U1.D40
-PCIE4_CLK_100M: length 180.4
  IN4 w0.089: v1(217.27,56.27) 217.66,56.67 217.66,56.92 217.32,57.26 216.99,57.26 216.1,58.15 209.79,58.15 208.98,57.34 207.17,57.34 206.41,58.1 201.39,58.1 197.81,61.68 195.82,61.68 195.46,61.33 193.43,61.33 193.2,61.56 189,61.56 187.48,60.03 177.2,60.03 176.44,60.79 172.15,60.79 171.27,59.92 167.9,59.92 166.54,61.28 162.08,61.28 161.68,61.67 158.26,61.67 156.96,60.36 156.02,60.36 155.53,60.85 154.68,60.85 154.1,60.27 149.74,60.27 147.37,62.65 147.37,63.66 146.38,64.66 146.38,66.69 146.69,67.01 146.69,69.56 144.07,72.19 144.07,74.1 143.01,75.16 143.01,81.1 141.74,82.37 138.99,82.37 134.57,86.79 134.06,86.79 131.51,89.34 130.53,89.34 129.71,90.15 126.97,90.15 126.31,89.49 120.16,89.49 119.08,88.41 117.45,88.41 116.33,87.29 113.38,87.29 111.25,89.42 111.25,91.31 109.58,92.98 100.42,92.98 100.09,93.31 96.45,93.31 94.78,94.98 87.84,94.98 85.4,92.54 85.4,91.43 85.52,91.31 85.52,91.16 v1(85.76,90.92)
  BOTTOM w0.076: v1(85.76,90.92) 85.61,90.77 85.61,89.96 85.46,89.81 85.21,89.81 84.93,90.09 84.63,90.09 84.34,89.8 84.34,89.6 84.46,89.47 84.46,89.05 84.28,88.86 84.13,88.86 84,88.73 U1.B40
  BOTTOM w0.102: v1(217.27,56.27) 217.45,56.09 217.45,52.71 216.79,52.05 216.79,51.36 218.1,50.06 218.27,50.06 218.36,49.97 218.43,49.97 218.55,49.86 J1.39
-PCIE5_CLK_100M: length 214.6
  IN4 w0.089: v1(217.44,66.74) 217.53,66.74 217.91,67.12 217.91,67.26 216.87,68.3 216.87,68.88 215.34,70.42 215.34,73.93 215.9,74.49 215.9,76.72 211.01,81.61 211.01,87.91 205.7,93.22 196.76,93.22 195.74,94.23 193.24,94.23 192.33,95.15 189.16,95.15 188.42,95.88 180.84,95.88 179.31,94.35 175.19,94.35 174.49,93.65 172.59,93.65 169.55,90.61 166.65,90.61 165.98,89.94 163.48,89.94 162.68,89.13 158.49,89.13 157.9,89.72 155.58,89.72 155.36,89.5 152.07,89.5 151.49,88.92 151.02,88.92 149.53,87.43 143.51,87.43 143.03,87.91 141.39,87.91 140.45,88.85 140.45,89.32 137.7,92.07 133.86,92.07 132.05,93.88 130.5,93.88 128.9,95.49 120.2,95.49 118.41,97.28 102.85,97.28 100.97,99.16 96.96,99.16 96.49,99.63 94.68,99.63 94.38,99.34 93.14,99.34 89.48,95.68 87.69,95.68 84.56,92.54 83.41,92.54 81.97,91.1 81.6,91.1 81.34,90.84 81.34,90.39 82.94,88.79 82.94,86.42 83.36,86 83.59,86 83.68,86.09 83.68,86.35 83.77,86.44 84.5,86.44 84.59,86.35 84.59,86.17 84.49,86.07 v1(84.06,86.07) ; v1(223.46,55.92) 223.77,55.92 223.93,55.76 225.18,55.76 226.06,56.63 227.59,56.63 228.7,57.75 231.41,57.75 232.5,56.66 234.01,56.66 234.33,56.34 234.33,55.36 235.24,54.45 238.76,54.45 238.84,54.37 238.84,54.22 v1(238.66,54.04)
  BOTTOM w0.102: v1(223.46,55.92) 223.46,56.19 222.08,57.58 222.08,62.69 219.96,64.8 218.77,64.8 217.89,65.68 217.89,66.35 217.66,66.59 217.59,66.59 v1(217.44,66.74) ; v1(84.06,86.07) 84.23,86.07 U1.E40 ; v1(238.66,54.04) 238.83,53.87 238.83,53.09 238.76,53.01 238.76,52.69 238.6,52.54 J22.53
-PCIE_WAKE: length 207.4
  TOP w0.102: v1(242.83,57.09) 243.24,57.09 244.36,58.2 244.89,58.2 245.45,58.76 245.45,59.55 245.04,59.96 v4(245.04,60.16) 245.04,60.44 245.34,60.75 245.34,61.31 245.66,61.63 v1(245.99,61.63) ; U21.F7 249.7,76.73 v1(249.31,77.11)
  IN1 w0.076: v1(245.99,61.63) 246.16,61.8 246.16,62.52 245.54,63.14 245.54,64.44 248.5,67.4 248.5,76.3 v1(249.31,77.11) ; v1(99.45,63.03) 99.91,62.57 99.91,62.23 101.05,61.09 101.05,57.72 101.67,57.1 102.18,57.1 104.01,58.93 105.23,58.93 107.46,61.16 117.2,61.16 121.48,56.88 123.82,56.88 127.67,53.03 132.53,53.03 134.15,54.66 153.23,54.66 157.1,58.52 157.1,59.36 159.3,61.57 160.88,61.57 161.23,61.22 167.18,61.22 168.08,60.31 171.41,60.31 172.09,61 175.9,61 176.87,60.03 185.56,60.03 186.7,58.89 206.74,58.89 207.6,58.03 v1(207.86,58.03) 208.19,58.03 208.98,58.81 210.86,58.81 211.22,59.17 221.04,59.17 223.45,61.58 237.5,61.58 237.93,61.15 237.93,60.26 238.49,59.7 240.47,59.7 241.94,58.23 241.94,57.49 242.35,57.09 v1(242.83,57.09)
  BOTTOM w0.076: U1.BB15 98.71,66.41 98.71,65.82 99.88,64.66 99.88,64.27
  BOTTOM w0.102: 99.88,64.27 100.09,64.07 RC69.2 99.88,63.09 99.51,63.09 v1(99.45,63.03) ; J32.55 209.8,53.23 207.27,55.75 207.27,57.44 v1(207.86,58.03) 208.94,58.03 209.23,57.74 212.89,57.74 213.55,58.4 J32.70
-PE_DTCT: length 168.9
  TOP w0.102: v1(214.23,64.63) 214.49,64.63 215.53,63.59 215.53,62.29 216.66,61.16 216.66,60.52 217.76,59.43 Q4.1 218.01,58.79 217.88,58.66 217.88,57.81 218.16,57.52 220.02,57.52 220.27,57.27 221.39,57.27 222,56.66 222,55.9 223.15,54.75 223.15,54.51 223.8,53.86 224.55,53.86 224.7,53.7 Q29.2 224.49,53.1 223.59,53.1 223.36,52.87 U7.4 223.36,51.61 223.76,51.22 223.76,51.07 224.39,50.43 224.39,49.72 223.68,49.01 222.19,49.01 Q36.2
  IN3 w0.081: v1(212.23,77.51) 212.05,77.69 211.54,77.69 211.29,77.94 209.29,77.94 208.28,76.93 208.28,75.85 207.5,75.07 207.5,73.48 206.8,72.78 203.51,72.78 201.76,71.03 201.08,71.03 200.25,70.2 199.87,70.2 199.37,70.7 194.19,70.7 191.5,73.39 181.23,73.39 180.14,72.31 175.88,72.31 171.84,68.26 161.05,68.26 160.44,67.65 158.99,67.65 158.34,68.3 147.22,68.3 145.45,66.53 141.46,66.53 139.02,68.97 137.35,68.97 137.22,68.85 135.49,68.85 134.98,69.35 134.98,71.36 131.45,74.89 129.04,74.89 126.19,77.75 120.77,77.75 119.06,79.46 116.39,79.46 114.87,80.99 114.87,82.81 114.08,83.6 112.89,83.6 112.46,84.04 112.46,85.05 v1(112.23,85.28)
  BOTTOM w0.102: v1(214.23,64.63) 214.21,64.63 213.8,65.04 213.8,65.49 214.23,65.93 214.23,66.43 213.85,66.81 213.85,72.12 212.56,73.42 212.56,77.18 v1(212.23,77.51) ; v1(112.23,85.28) 112.23,85.56 111.87,85.92 111.51,85.92 111.3,85.71 110.78,85.71 110.47,86.01 RC47.1 109.71,86.04 109.13,85.46 107.65,85.46 107.48,85.28 106.11,85.28 105.78,84.95 U1.H3
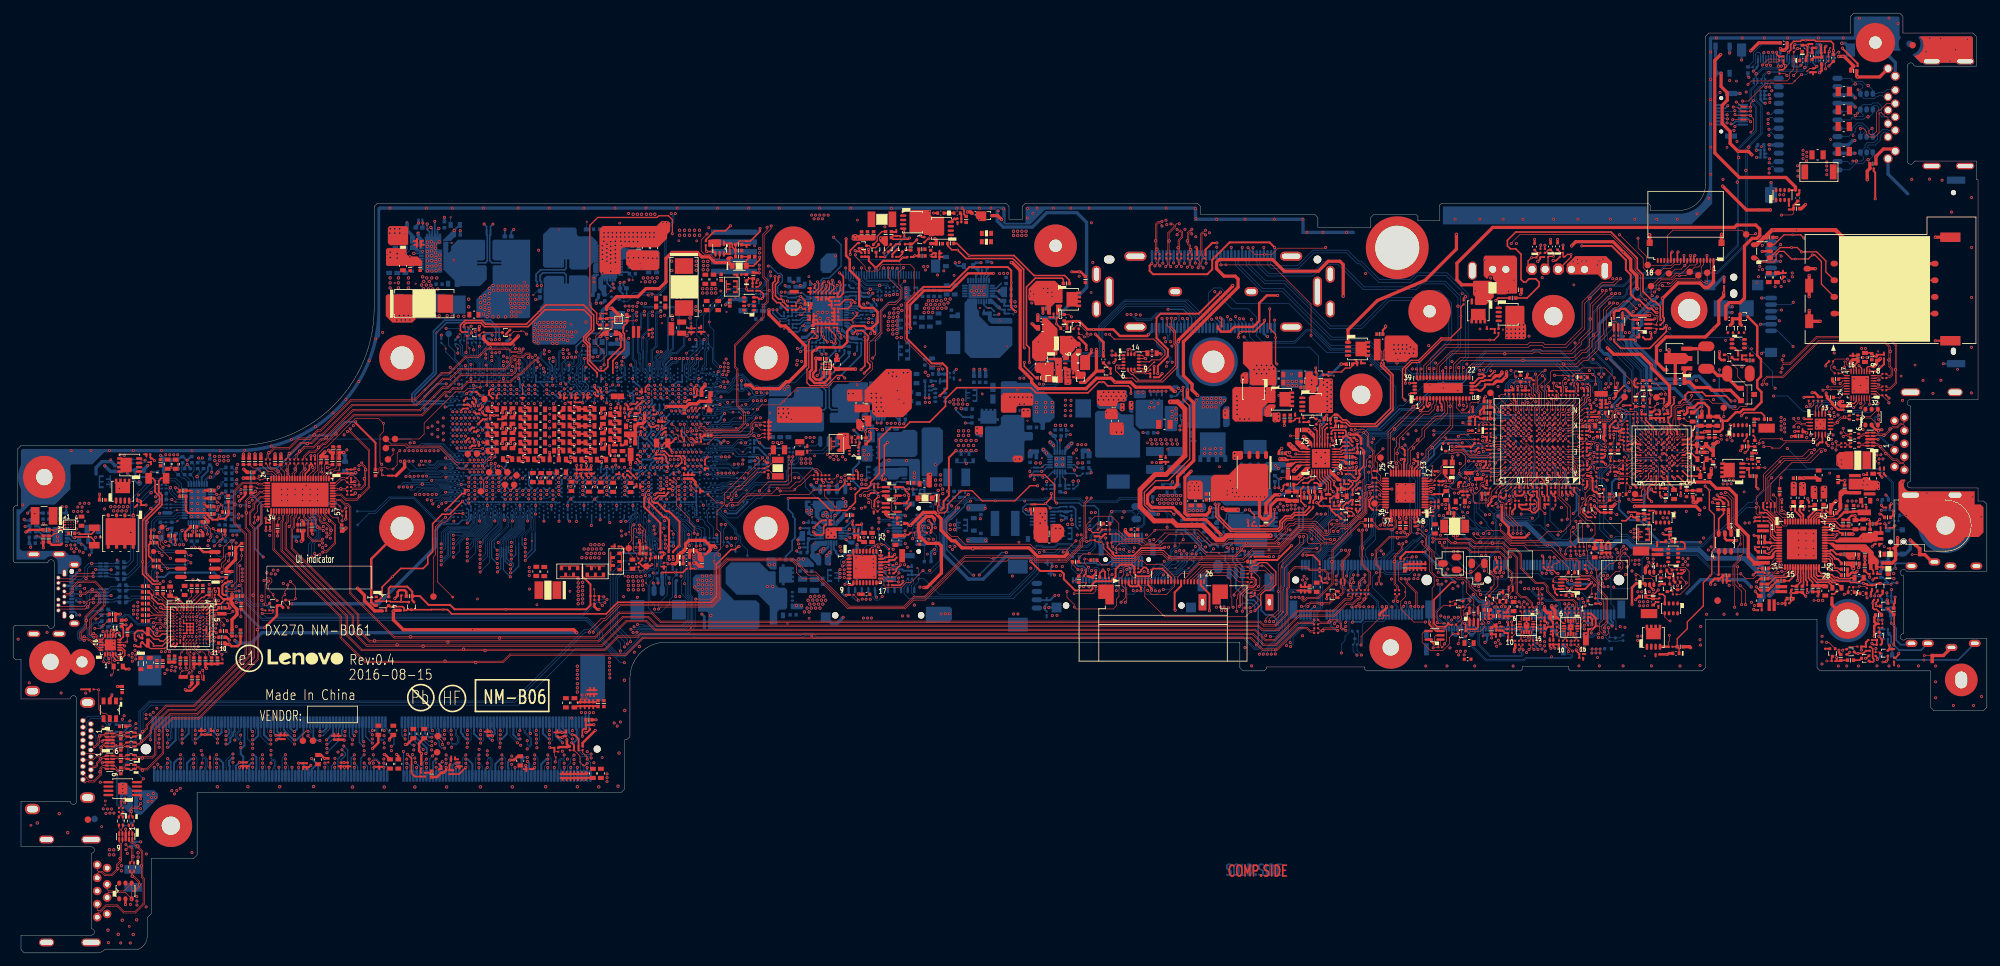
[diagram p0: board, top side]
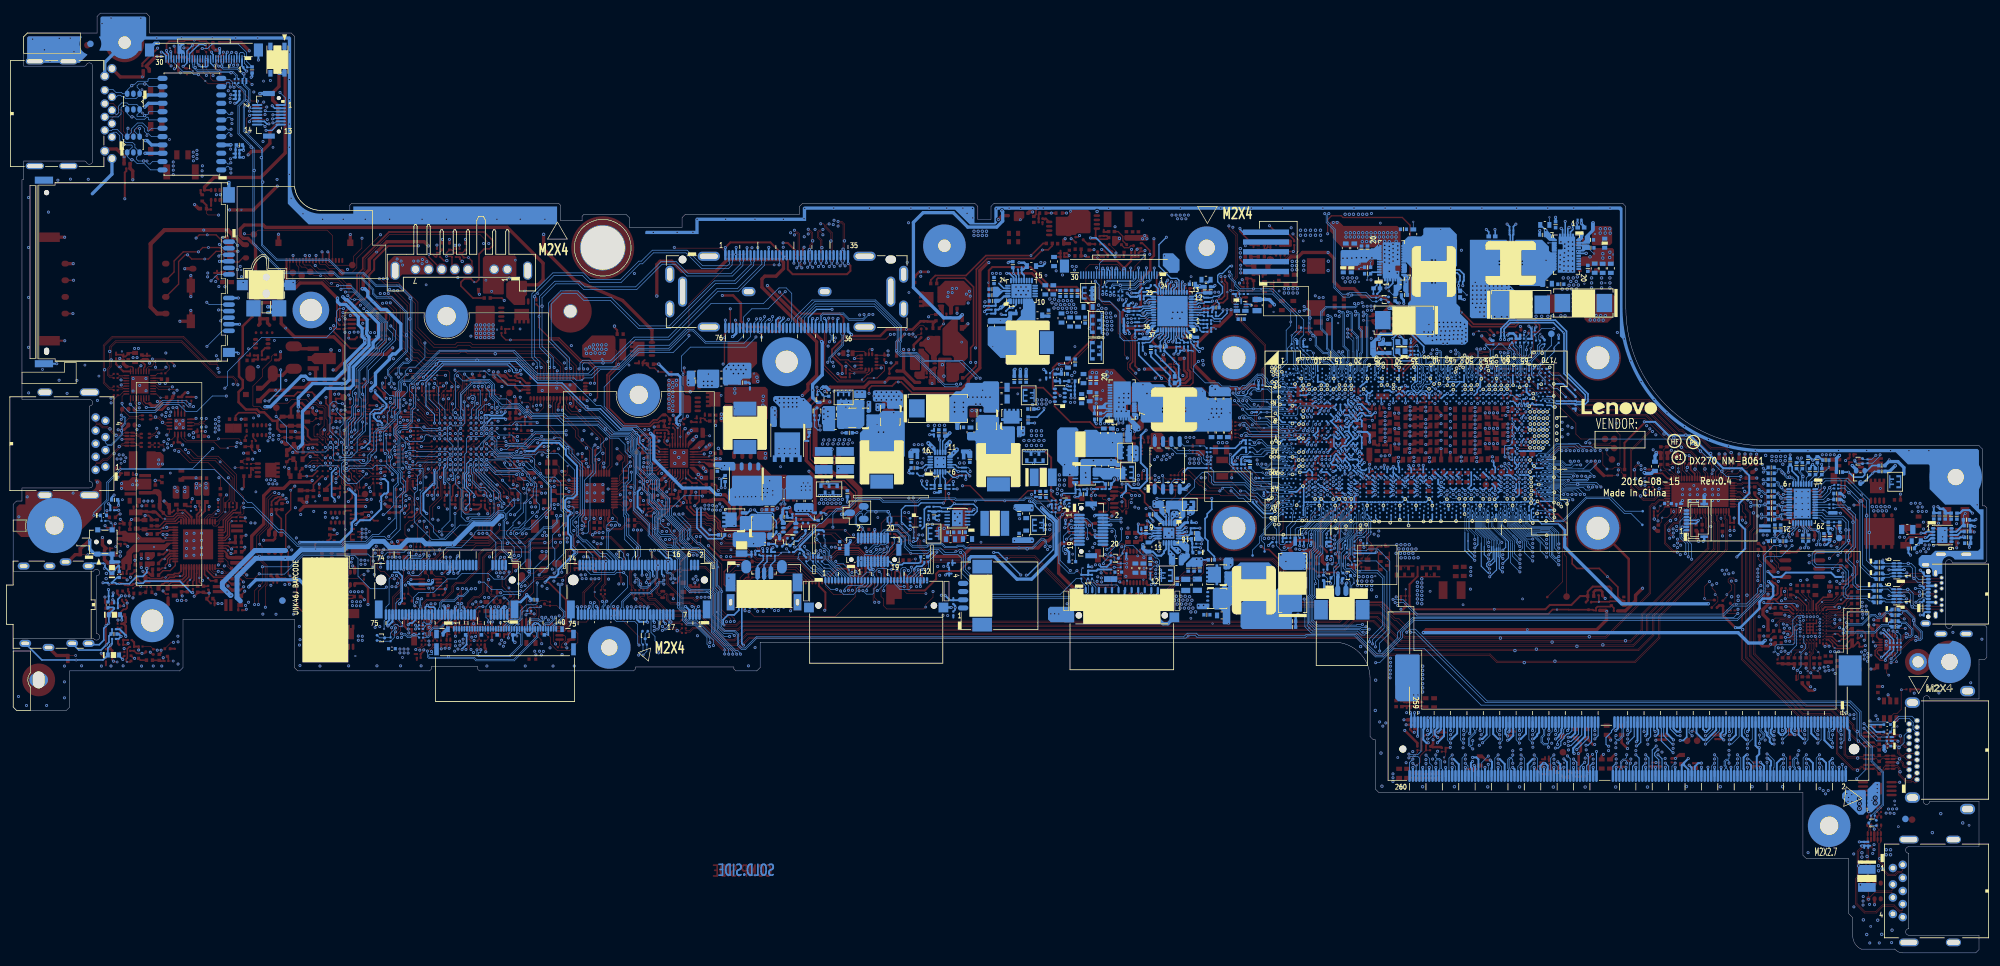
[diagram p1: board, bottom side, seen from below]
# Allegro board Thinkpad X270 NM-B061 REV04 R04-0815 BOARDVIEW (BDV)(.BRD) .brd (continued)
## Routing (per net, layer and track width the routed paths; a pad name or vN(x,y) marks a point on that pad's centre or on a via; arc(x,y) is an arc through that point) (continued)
-PLTRST: length 57.8
  IN1 w0.076: v1(102.4,71.84) 101.96,71.41 101.96,69.2 102.32,68.85 104.66,68.85 104.96,69.15 108.34,69.15 108.74,68.75 109.79,68.75 110.22,69.18 116.8,69.18 119.93,66.04 120.7,66.04 120.95,65.78 122.19,65.78 122.78,65.19 125.23,65.19 126.64,63.78 128.08,63.78 130.55,61.3 131.4,61.3 132.06,60.64 133.16,60.64 133.92,59.88 136.28,59.88 137.32,58.84 139.28,58.84 v1(139.76,58.36)
  BOTTOM w0.102: v1(139.76,58.36) 141.3,59.9 141.3,66.54 v3(140.93,66.92) 140.34,67.5 140.34,68.26 140,68.61 UC3.2 ; v1(102.4,71.84) 102.39,71.84 102.32,71.84 U1.AN10
-PLTRST_FAR: length 240.6
  TOP w0.102: U27.1 217.64,46.9 R435.1 218.25,47 v1(218.25,47.15) 218.25,47.26 218.55,47.56 218.55,49.26 218.32,49.49 216.97,49.49 216.37,50.1 216.37,55.66 216.67,55.96 216.67,57.47 215.99,58.15 215.99,61.2 214.84,62.34 v1(214.84,62.75) ; v1(138.74,58.33) 138.69,58.33 136.89,56.53 136.19,56.53 135.42,55.75 133.07,55.75 132.78,56.05 132.78,56.88 132.52,57.14 U26.17 ; v1(236.69,60.87) 236.69,61.51 237.16,61.98 R2750.1 ; U16.M5 234.38,82.52 234.38,83.9 233.79,84.49 233.79,85.76 233.59,85.97 233.59,86.52 234.38,87.31 234.38,88.58 234.65,88.86 238.79,88.86 239.2,89.27 242.66,89.27 v3(244.15,87.77) 244.15,86.5 C260.2 244.71,86.65 244.71,86.85 v1(244.61,86.96) ; U21.A7 v1(249.75,72.17) ; v1(208.49,65.26) 208.49,65.32 208.83,65.66 208.83,66.37 209.52,67.06 209.52,67.73 UL1.36
  IN1 w0.076: v1(214.84,62.75) 213.32,62.75 212.71,62.14 212.18,62.14 211.92,61.89 211.11,61.89 209.97,63.03 207.58,63.03 205.61,61.06 198.65,61.06 197.66,62.05 195.96,62.05 195.23,62.78 194.47,62.78 194.24,62.55 188.73,62.55 188.11,63.17 184.15,63.17 183.5,63.82 181.59,63.82 180.68,64.73 176.18,64.73 v1(175.96,64.96)
  IN3 w0.081: v1(249.23,60.22) 249.23,64.83 250.55,66.16 250.55,71.37 v1(249.75,72.17) ; v1(218.25,47.15) 219.16,48.07 221.22,48.07 225.31,52.16 225.31,54.27 226.48,55.43 227.64,55.43 231.94,59.73 235.42,59.73 236.56,60.87 v1(236.69,60.87)
  IN4 w0.076: v1(236.69,60.87) 236.88,60.87 237.57,61.56 243.49,61.56 244.48,60.57 246.25,60.57 246.69,61 248.44,61 v1(249.23,60.22)
  BOTTOM w0.102: v1(214.84,62.75) 214.64,62.75 212.55,60.66 J32.66 212.55,58.2 212.42,58.08 209.33,58.08 209.05,58.36 J32.52 209.05,60.08 210.42,61.45 210.42,65.29 209.89,65.82 209,65.82 208.49,65.32 v1(208.49,65.26) ; v1(138.74,58.33) 139.13,57.95 139.99,57.95 141.5,59.47 141.5,66.1 142,66.59 RC60.1 CC15.1 142.85,67.26 144.23,68.64 144.94,68.64 145.35,69.05 145.5,69.05 145.81,69.35 146.49,69.35 146.8,69.05 157.26,69.05 157.43,69.21 162.51,69.21 162.95,68.77 168.36,68.77 168.82,69.23 172.09,69.23 173.33,67.99 174.32,67.99 174.71,67.6 175.27,67.6 175.96,66.92 v1(175.96,64.96) ; v1(249.75,72.17) 250.86,73.29 250.86,74.69 250.45,75.09 248.27,75.09 247.84,74.66 247.31,74.66 246.86,75.11 246.86,75.95 245.96,76.85 245.96,79.39 245.2,80.15 244.55,80.15 243.9,80.8 243.9,82.41 243.57,82.74 243.57,83.3 242.88,83.98 242.88,84.95 242.99,85.05 243.57,85.05 244.71,86.19 244.71,86.85 v1(244.61,86.96)
-PLTRST_FAR_HDD: length 13.8
  TOP w0.102: U27.2 216.91,48.46 216.75,48.3 216.75,47.65 217.31,47.09 R435.2 216.62,46.65 v1(216.52,46.54)
  IN3 w0.081: v1(223.96,50.2) 223.96,50.13 221.64,47.8 219.66,47.8 218.4,46.54 v1(216.52,46.54)
  BOTTOM w0.102: v1(223.96,50.2) 224.14,50.2 224.55,49.79 J1.24
-PLTRST_FAR_WWAN: length 2.4
  TOP w0.102: R2750.2 v1(237.5,60.62)
  BOTTOM w0.102: J22.50 237.85,59.89 237.5,60.24 v1(237.5,60.62)
-PLTRST_NEAR: length 234
  TOP w0.102: U15.1 283.96,85.3 284.34,84.92 v1(284.34,83.86)
  IN4 w0.076: v1(261.34,126.66) 261.04,126.66 260.7,127 260.7,129.46 261.99,130.75 261.99,131.13 263.81,132.94 264.7,132.94 265.69,131.95 265.69,124.12 266.73,123.08 266.73,120.61 266.26,120.14 266.26,111.1 264.75,109.59 264.75,90.79 268.23,87.32 268.23,85.18 v1(268.43,84.98) 268.11,84.66 268.11,75.6 263.16,70.65 258.7,70.65 257.08,69.03 257.08,67.97 253.87,64.77 252.97,64.77 251.79,63.59 251.79,63.29 251.2,62.7 245.32,62.7 243.95,64.07 236.97,64.07 236.71,64.33 231.9,64.33 231.6,64.63 228.13,64.63 226.51,63.02 224.95,63.02 221.51,59.58 202.14,59.58 200.72,61 200.72,61.53 198.51,63.74 197.75,63.74 196.99,62.98 196.02,62.98 195.61,63.39 194.24,63.39 194.03,63.17 182.34,63.17 182.2,63.03 182.2,62.32 v1(181.82,61.94)
  BOTTOM w0.102: v1(284.34,83.86) 284.34,83.58 283.24,82.49 279.26,82.49 278.04,83.71 275.68,83.71 274.59,82.62 272.92,82.62 270.57,84.98 v1(268.43,84.98) ; J5.11 260.81,126.89 261.04,126.66 v1(261.34,126.66) ; RC59.1 CC14.1 142.67,68.95 144.94,68.95 145.25,69.25 145.37,69.25 145.68,69.56 146.59,69.56 146.9,69.25 157.13,69.25 157.31,69.43 162.67,69.43 163.13,68.97 168.21,68.97 168.69,69.46 172.22,69.46 173.47,68.21 174.46,68.21 174.85,67.82 175.41,67.82 177.71,65.52 178.01,65.52 181.59,61.94 v1(181.82,61.94)
-PROCHOT: length 347.1
  TOP w0.102: v1(192.18,50.54) v4(193.64,52) 193.63,52 193.63,55.76 193.84,55.97 193.84,58.71 196.81,61.68 198.74,61.68 v1(198.79,61.73) ; v1(204.28,74.13) 204.15,74 PR142.1 ; R392.2 241.82,69 v1(241.03,69.79) 240.98,69.84 240.37,69.84 239.91,69.38 239.91,68.91 239.74,68.74 Q199.3
  IN1 w0.076: v1(241.03,69.79) 238.77,69.79 237.83,70.73 236.86,70.73 236.31,71.28 236.31,72.99 235.47,73.82 235.47,77.05 235.21,77.3 232.6,77.3 231.78,76.49 231.78,74.51 231.38,74.1 228.51,74.1 226.27,76.34 225.28,76.34 224.44,77.18 220.53,77.18 219.62,76.26 217.31,76.26 215.93,77.63 213.5,77.63 212.23,76.37 208.15,76.37 207.67,76.85 205.53,76.85 204.28,75.6 v1(204.28,74.13)
  IN3 w0.081: v1(131.17,97.28) 131.14,97.32 129.74,97.32 129.29,96.87 125.2,96.87 124.78,97.28 122.84,97.28 122.7,97.14 118.78,97.14 118.2,97.73 106.46,97.73 105.44,96.71 103.57,96.71 101.74,98.54 97.75,98.54 96.78,99.5 96.28,99.5 96.15,99.63 93.48,99.63 92.76,98.91 90.85,98.91 89.58,97.63 78.25,97.63 77.21,96.59 71.44,96.59 71.29,96.44 67.19,96.44 v1(66.02,95.28) 66.02,92.14 53.83,79.95 53.83,70.37 52.33,68.87 52.33,60.77 66.25,46.85 91.91,46.85 93.05,47.99 95.03,47.99 95.49,48.46 188.25,48.46 190.79,50.99 191.73,50.99 v1(192.18,50.54)
  BOTTOM w0.102: RC16.1 68.74,93.97 68.94,94.17 RC14.1 68.79,94.38 67.89,95.28 v1(66.02,95.28) ; PR410.2 131.08,97.38 v1(131.17,97.28) ; v1(198.79,61.73) 198.84,61.73 199.73,62.62 199.73,63.31 200.75,64.32 200.75,64.53 201.13,64.91 201.63,64.91 202.27,65.54 202.27,66.18 201.89,66.56 201.89,67.8 203.18,69.1 203.18,72.12 204.28,73.21 v1(204.28,74.13)
-PROCHOT_R: length 7.9
  BOTTOM w0.076: 69.88,90.34 70.21,90.02 70.21,88.39 70.3,88.13 U1.C65
  BOTTOM w0.102: v4(68.08,94.47) 68.32,94.23 68.32,93.6 RC16.2
  BOTTOM w0.127: 69.88,90.34 69.67,90.34 68.54,91.48 68.54,92.67 68.13,93.08 68.13,93.41 RC16.2
-PWRON_DOCK: length 94
  TOP w0.102: v1(250.15,73.92) 249.53,73.92 249.13,73.53 U21.B8
  BOTTOM w0.102: v1(250.15,73.92) 249.77,74.31 247.34,74.31 246.49,75.16 246.49,75.65 245.55,76.59 245.55,79.47 245.13,79.9 244.48,79.9 242.78,81.6 242.78,82.71 242.33,83.17 242.33,85.53 241.95,85.91 241.95,87.05 241.58,87.41 240.52,87.41 235.98,91.96 224.52,91.96 221,88.44 213.23,88.44 212.23,89.45 209.03,89.45 v3(208.67,89.8) 208.52,89.8 205.6,92.72 200.9,92.72 194.55,99.07 186.57,99.07 184.17,101.47 183.05,101.47 182.23,100.65 182.23,96.43 182.45,96.21 J17.52
-PWRSHUTDOWN: length 184.3
  TOP w0.102: v1(241.56,73.95) 241.68,74.07 242.92,74.07 243.34,74.48 243.93,74.48 244.12,74.29 R289.1 244.5,74.07 245.2,74.76 245.88,74.76 246.05,74.59 R283.1 246.15,74.4 246.44,74.69 248.51,74.69 U21.D8 ; v1(201.05,65.42) 201.2,65.57 202.7,65.57 203.13,66 203.13,66.41 202.48,67.06 PQ105.2 ; PQ5.2 132.79,107.09 v1(132.79,106.8) ; PQ109.2 198.7,80.8 199.09,81.19 v1(199.25,81.19)
  IN3 w0.081: v1(132.79,106.8) 132.95,106.8 133.78,105.96 142.3,105.96 143.67,104.58 147.94,104.58 151.56,100.96 151.56,98.54 156.01,94.1 156.01,91.38 158.55,88.84 164.21,88.84 166.19,90.82 166.19,94.68 166.42,94.91 168.17,94.91 169.85,93.24 174.86,93.24 176,92.09 177.14,92.09 182.6,97.55 184.13,97.55 v1(187.69,93.99)
  IN4 w0.076: v1(241.56,73.95) 241.39,73.77 240.9,73.77 240.88,73.75 239.81,73.75 239.14,73.09 237.37,73.09 234.81,70.53 230.66,70.53 230.4,70.79 224.3,70.79 222.67,69.15 222.67,67.2 220.76,65.29 220.76,63.03 220.13,62.39 218.6,62.39 218.3,62.09 216.21,62.09 215.96,62.34 212.79,62.34 212.34,61.89 210.83,61.89 209.46,63.26 208.67,63.26 207.6,62.19 203.97,62.19 202.54,63.63 202.54,64.68 201.94,65.27 201.2,65.27 v1(201.05,65.42) 201.05,65.72 201.83,66.5 203.2,66.5 203.77,67.07 203.77,77.69 200.26,81.19 v1(199.25,81.19)
  BOTTOM w0.102: v1(187.69,93.99) 187.69,93.92 189.16,92.44 197.67,92.44 199.04,91.07 199.04,88.8 198.81,88.56 v3(198.81,88.28) 198.81,81.63 v1(199.25,81.19)
-PWRSW: length 35.8
  TOP w0.102: v4(242.53,77.67) D34.2 244.07,78.14 R270.1 v1(244.07,79.1) ; U16.D7 v1(232.71,75.3)
  IN1 w0.076: v1(232.71,75.3) 233.09,75.68 234.5,75.68 234.73,75.45 234.73,74.28 235.21,73.8 235.21,72.43 235.72,71.92 235.72,69.61 236.51,68.82 239.2,68.82 240.47,67.55 243.85,67.55 v1(244.52,66.88)
  BOTTOM w0.102: v1(244.07,79.1) 244.07,76.83 243.74,76.5 243.74,76.07 243.98,75.83 243.98,74.64 242.35,73.01 242.35,71.74 242.93,71.16 242.93,68.26 244.32,66.88 v1(244.52,66.88)
-PWRSW_ASIC: length 5.3
  TOP w0.102: U21.F8 248.54,76.31 247.99,76.31 247.84,76.47 245.94,76.47 R271.1 C193.1 245.37,77.67 D35.2
-PWRSW_EC: length 194.4
  TOP w0.102: U16.G2 v1(236.71,78.45)
  IN1 w0.076: v1(244.92,59.45) 244.56,59.8 241.97,59.8 241.47,60.3 241.47,61.14 240.95,61.66 240.14,61.66 239.4,62.4 223.19,62.4 220.8,60.01 210.8,60.01 210.46,59.67 187.09,59.67 185.96,60.79 181.59,60.79 180.78,61.61 179.64,61.61 178.93,62.32 177.83,62.32 177.5,62.66 175.46,62.66 174.66,61.86 171.81,61.86 171.17,62.51 167.43,62.51 167.24,62.32 164.36,62.32 164.04,62 161.55,62 161.22,62.33 158.99,62.33 156.32,59.67 156.32,58.83 154.45,56.96 137.55,56.96 136.09,55.5 126.28,55.5 123.99,57.78 123.49,57.78 120.74,60.54 119.62,60.54 118.75,61.41 118.75,65.94 116.29,68.4 112.42,68.4 107.01,62.99 102.84,62.99 101.05,64.78 v1(99.22,64.78)
  IN3 w0.081: v1(244.92,59.45) 245.12,59.65 245.12,61.4 244.84,61.68 244.84,63 242.99,64.86 242.99,70.67 243.57,71.26 243.57,72.31 243.28,72.61 242.78,72.61 242.48,72.91 242.48,73.9 241.89,74.48 241.89,75.04 241.69,75.25 241.69,76.59 241.46,76.82 240.88,76.82 240.7,76.64 240.29,76.64 238.87,78.07 238.59,78.07 238.26,78.4 238.26,78.8 238.01,79.06 237.31,79.06 v1(236.71,78.45)
  BOTTOM w0.076: v1(99.22,64.78) 99.22,65.08 98.53,65.77 98.53,66.88 U1.BA15
-PWRSWITCH: length 226.5
  TOP w0.102: v1(244.2,76.21) 243.7,76.21 243.6,76.31 D34.1 D35.1 ; J41.11 254.26,105.19 254.14,105.07 253.37,105.07 252.74,104.43 251.62,104.43 251.04,103.85 TP49.1 249.25,103.85 248.55,104.55 248.55,105.98 v1(244.94,109.59) ; v1(263.69,129.98) 264.56,129.98 267.21,132.63 271.23,132.63 v4(271.64,133.05) 272.61,134.02 v1(272.7,134.02)
  IN1 w0.076: v1(263.69,129.98) 263.38,130.29 261.85,130.29 260.86,129.3 260.86,126.23 261.48,125.61 261.48,114.03 257.78,110.34 245.69,110.34 v1(244.94,109.59) 244.38,110.15 222.36,110.15 215.68,103.47 213.85,103.47 212.94,102.55 206.5,102.55 205.13,103.92 205.13,105.27 204.37,106.04 204.37,107.1 202.7,108.77 192.62,108.77 190.38,106.54 184.82,106.54 183.22,104.94 v1(183.22,100.9)
  BOTTOM w0.102: J5.2 263.69,129.45 v1(263.69,129.98) ; v1(183.22,100.9) 185.84,98.28 188.32,98.28 189.6,97.01 J17.65 189.6,94.14 190.43,93.31 195.36,93.31 197.21,95.16 198.08,95.16 200.97,92.26 205.62,92.26 208.64,89.24 211.74,89.24 212.8,88.18 221.14,88.18 224.69,91.73 235.9,91.73 240.42,87.21 241.46,87.21 241.72,86.95 241.72,85.78 242.05,85.46 242.05,82.71 242.58,82.18 242.58,81.37 244.48,79.46 244.48,76.49 v1(244.2,76.21) ; v1(272.7,134.02) 273.38,134.02 273.88,134.51 275.06,134.51 276.45,135.9 J11.27
-REAR_EJECT_LEVER: length 61.5
  TOP w0.305: v1(241.54,77.41) 241.59,77.36 R131.1 ; v1(260.81,100.73) 260.88,100.8 R414.2 ; U16.G7 v1(232.71,78.45)
  TOP w0.508: v1(252.16,88.96) 251.75,88.96 250.57,90.14 250.57,92.52 252.05,94 258.04,94 v3(259.39,95.34) 260.07,96.03 260.07,99.46 260.81,100.2 v1(260.81,100.73)
  IN2 w0.381: v1(246.34,87.01) 246.19,87.01 245.14,85.97 245.14,84.94 243.53,83.32 242.6,83.32 241.28,82 240.78,82 239.71,80.94 239.71,80.68 238.44,79.41 237.78,79.41 237.25,78.88 237.25,78.27 236.92,77.94 233.21,77.94 v1(232.71,78.45)
  IN3 w0.381: v1(252.16,88.96) 247.38,88.96 246.31,87.9 246.31,87.03 v1(246.34,87.01)
  IN4 w0.381: v1(246.34,87.01) 246.94,86.41 246.94,82.12 245.96,81.14 244.46,81.14 241.92,78.6 241.92,77.79 v1(241.54,77.41)
-RSMRST: length 203.5
  TOP w0.102: v1(243.06,72.15) 242.83,72.15 242.53,72.45 241.66,72.45 R430.1 ; v1(160.69,55.16) 160.69,54.26 161.8,53.15 v3(161.8,52.77) 162.08,52.49 167.75,52.49 168.26,53 168.26,54.04 168.61,54.39 168.61,56.96 169.34,57.69 169.34,58.78 169.5,58.94 170.04,58.94 170.28,58.7 RC118.1
  IN1 w0.076: v1(238,72.61) 238.26,72.35 238.87,72.35 239.4,71.82 242.2,71.82 242.53,72.15 v1(243.06,72.15)
  IN3 w0.081: v1(100.06,56.4) 101.76,56.4 105.32,59.96 108.39,59.96 108.8,60.36 116.7,60.36 120.96,56.1 123.33,56.1 126.13,53.29 127.94,53.29 128.56,52.67 135.72,52.67 137.35,54.29 157.57,54.29 158.78,55.51 160.33,55.51 v1(160.69,55.16) 161.91,56.37 163.31,56.37 163.64,56.04 163.64,55.38 164.55,54.47 170.76,54.47 171.79,53.44 175.23,53.44 178.62,56.83 192.36,56.83 194.27,54.93 194.27,53.53 196.64,51.16 201.6,51.16 202.78,49.97 202.78,48.93 202.9,48.81 203.56,48.81 203.84,49.08 205.37,49.08 208.04,51.75 216.09,51.75 217.21,52.87 219.29,52.87 221.85,55.43 221.85,56.68 224.39,59.22 226.83,59.22 227.81,60.2 227.81,60.55 228.23,60.97 230.91,60.97 235.28,65.34 235.28,66.04 236.1,66.86 236.1,67.36 238.21,69.47 238.21,70.19 237.95,70.45 237.95,72.55 v1(238,72.61)
  BOTTOM w0.076: 98.37,63.17 98.1,63.44 97.86,63.44 97.47,63.83 97.47,64.2 97.27,64.4 97.27,65.37 97.49,65.59 97.49,66.19 97.35,66.33 97.35,66.63 97.36,66.65 97.36,66.98 97.35,67.02 97.35,67.27 97.4,67.42 97.5,67.53 97.6,67.64 U1.AY17
  BOTTOM w0.102: v1(100.06,56.4) 100.06,57.18 Q40.1 99.65,57.59 99.65,58.7 98.89,59.46 98.89,61.02 99.03,61.16 99.03,62.51 98.37,63.17
-RSMRST_EC: length 9.4
  TOP w0.102: R146.2 241.23,75.55 v1(241,75.78) 241,75.41 240.61,75.02 240.61,74.69 241.06,74.25 v4(241.06,74.08) 241.06,73.65 R430.2 ; U16.E3 v1(235.91,76.1)
  BOTTOM w0.102: v1(241,75.78) 240.95,75.83 239.94,75.83 239.89,75.78 236.22,75.78 v1(235.91,76.1)
-RTCRST: length 213.1
  TOP w0.102: RC123.2 96.92,61.83 CC70.1 96.52,62.69 96.43,62.78 96.43,64.5 95.67,65.26 v1(95.51,65.26) ; J41.9 255.26,105.28 v1(254.89,104.9) 254.31,104.33 253.4,104.33 252.76,103.69 TP44.1
  IN1 w0.076: v1(98.74,72.46) 98.25,71.97 98.25,68.18 95.51,65.44 v1(95.51,65.26)
  IN3 w0.081: v1(240.34,88.86) 239.94,89.27 235.01,89.27 234.2,88.45 233.38,88.45 233.11,88.73 229.16,88.73 228.06,87.64 225.46,87.64 225.16,87.35 219.63,87.35 219.16,86.88 217.79,86.88 214.94,84.04 214.94,78.45 212.3,75.81 211.54,75.81 210.22,74.48 210.22,73.72 207.1,70.6 206.54,70.6 205.44,69.51 204.76,69.51 203.31,68.06 202.91,68.06 202.57,67.72 201.11,67.72 200.75,68.08 198.64,68.08 197.4,66.85 194.81,66.85 194.64,66.68 189.51,66.68 189.37,66.53 186.45,66.53 186.19,66.28 183.24,66.28 183.02,66.51 176.67,66.51 176.54,66.64 175.02,66.64 174.53,66.15 168.61,66.15 167.85,65.39 164.27,65.39 163.53,64.65 163.53,63.89 162.96,63.31 161.91,63.31 161.28,62.68 159.02,62.68 157.82,61.48 157.82,61 157.01,60.18 154.31,60.18 153.45,59.32 148.64,59.32 147.76,60.19 143.25,60.19 143.07,60.02 138.23,60.02 136.76,61.48 136.1,61.48 134.25,63.33 132.01,63.33 131.51,63.84 130.24,63.84 128.74,65.34 126.91,65.34 126.09,66.15 125.26,66.15 124.67,66.74 124.67,67.4 123.02,69.05 121.16,69.05 118.78,71.44 105.95,71.44 103.95,69.43 103.23,69.43 102.93,69.74 102.93,72.35 102.3,72.99 101.1,72.99 101.03,73.06 99.34,73.06 v1(98.74,72.46)
  IN4 w0.076: v1(240.34,88.86) 240.34,91.27 241.13,92.06 241.13,93.99 243.34,96.2 244.69,96.2 248.52,100.04 248.52,103.82 249.92,105.22 254.24,105.22 254.56,104.9 v1(254.89,104.9)
  BOTTOM w0.076: v1(98.74,72.46) 98.29,72.86 U1.AM16
-SC_DTCT: length 46
  IN1 w0.076: v1(134.2,61.58) 133.92,61.86 132.67,61.86 132.13,62.4 129.93,62.4 128.24,64.08 126.97,64.08 125.54,65.52 122.91,65.52 122.34,66.09 121.13,66.09 120.76,66.46 119.95,66.46 116.93,69.48 111.91,69.48 110.5,70.89 106.17,70.89 104.84,72.22 103.97,72.22 103.1,73.1 102.76,73.1 101.86,74 101.86,74.35 101.46,74.75 100.71,74.75 v1(100.2,75.26)
  BOTTOM w0.102: v1(134.2,61.58) 134.02,61.76 133.84,61.76 132.88,62.72 v3(132.88,63.59) 132.88,64.45 133.23,64.81 J26.10 ; v1(100.2,75.26) 100.06,75.4 U1.AF13
-SD_MMC_CD: length 28.9
  TOP w0.102: U15.30 282.25,84.19 282.37,84.07 282.37,83.82 v1(281.72,83.17)
  IN4 w0.076: v1(271.43,99.28) 270.97,98.82 270.97,98.19 271.59,97.57 271.59,95.93 272.68,94.83 272.68,92.51 275.17,90.03 279.33,90.03 279.89,89.47 279.89,89.11 281.24,87.77 281.24,86.43 282.13,85.54 282.13,83.58 v1(281.72,83.17)
  BOTTOM w0.102: v1(271.43,99.28) 271.08,98.93 J23.10
-SHUTDOWN: length 58
  TOP w0.102: R289.2 R288.1 243.14,73.04 v1(243.14,73.01) ; v1(221.45,72.48) 221.04,72.48 220.5,73.02 v3(220.5,73.17) 220.5,73.75 221.45,74.7 221.45,75.78 220.83,76.39 219.74,76.39 219.56,76.21 219.08,76.21 218.73,76.57 Q8.1 ; U21.D7 249.75,75.09 v1(250.15,74.69)
  IN1 w0.076: v1(243.14,73.01) 243.24,73.01 243.42,73.19 243.61,73.19 244.76,74.33 245.2,74.33 245.4,74.13 245.4,71.03 245.04,70.67 245.04,66.1 244.71,65.77 240.17,65.77 237.56,68.39 227.75,68.39 226.27,69.86 222.41,69.86 221.45,70.83 v1(221.45,72.48)
  BOTTOM w0.102: v1(243.14,73.01) 243.14,73.27 244.28,74.41 245.7,74.41 246.15,73.95 249.53,73.95 249.98,73.5 250.33,73.5 250.63,73.81 250.63,74.21 v1(250.15,74.69)
-SPI_CS0: length 18.8
  TOP w0.102: RC128.1 v3(122.08,70.66) 121.39,69.97 117.01,69.97 116.8,69.77 112,69.77 110.55,68.31 109.68,68.31 v1(109.68,68.32)
  BOTTOM w0.076: U1.AU3 106.48,69.27 106.92,69.27 107.08,69.44 108.41,69.44 109.45,68.39
  BOTTOM w0.102: 109.45,68.39 109.53,68.32 v1(109.68,68.32)
-SPI_CS0_R: length 4.9
  TOP w0.102: RC128.2 RC125.1 v4(124.57,71.25) 125.43,71.25 126.11,71.92 v1(126.19,71.92)
  BOTTOM w0.102: v1(126.19,71.92) 126.39,71.92 126.88,71.43 UC5.1
-SPI_CS2: length 41.5
  TOP w0.102: R240.1 133.87,58.84 v1(133.05,58.84)
  IN4 w0.076: v1(133.05,58.84) 133.05,61.27 133.21,61.43 133.21,63 132.85,63.36 132.85,65.42 132.42,65.85 132.42,66.66 130.79,68.29 130.33,68.29 130.11,68.52 128.28,68.52 127.42,69.38 126.58,69.38 v1(126.55,69.35)
  BOTTOM w0.102: v1(133.05,58.84) 133.04,58.85 R434.2 ; U1.AU1 108.13,69.7 108.31,69.89 109.35,69.89 109.86,69.38 110.46,69.38 111.25,70.17 111.96,70.17 113.2,71.41 117.89,71.41 118.25,71.77 118.25,72.71 118.88,73.34 119.62,73.34 120.81,72.15 120.81,71.08 122.51,69.38 126.53,69.38 v1(126.55,69.35)
-SPI_CS2_R: length 2.1
  TOP w0.102: R238.2 R240.2 133.49,58.38 132.75,58.38 132.49,58.64 U26.20
-SPK_MUTE: length 57.1
  TOP w0.102: R908.2 v1(269.68,67.5) 270.04,67.5 270.65,66.89 271.15,66.89 271.75,66.29 UA1.52 ; R144.1 223,72.15 223.1,72.05 TP10.1 223.1,70.9 v1(223.12,70.88)
  IN1 w0.076: v1(243.6,66.28) 243.24,65.93 240.29,65.93 237.68,68.54 229.07,68.54 228.56,69.05 228.56,69.89 228.2,70.24 223.76,70.24 v1(223.12,70.88)
  IN3 w0.081: v1(253.34,66.48) 253.49,66.34 257.86,66.34 260.71,69.18 268,69.18 v1(269.68,67.5)
  IN4 w0.076: v1(243.6,66.28) 244.1,65.77 244.94,65.77 245.45,66.28 250,66.28 250.33,65.95 252.42,65.95 252.96,66.48 v1(253.34,66.48)
-SRTCRST: length 14
  TOP w0.102: v1(95.49,64.68) 95.61,64.68 95.94,64.35 95.94,62.7 96.05,62.6 96.05,61.38 CC71.1 96.49,60.24 RC124.2
  IN1 w0.076: v1(95.49,64.68) 95.05,65.12 95.05,65.57 97.36,67.89 97.36,71.32 v1(96.91,71.77)
  BOTTOM w0.076: v1(96.91,71.77) 97.24,72.05 97.36,72.16 U1.AN18
-SUS_STAT: length 272.1
  TOP w0.102: U16.H6 v1(233.51,79.25)
  IN1 w0.076: v1(104.78,61.56) 105.1,61.24 105.53,61.24 105.83,61.53 105.83,61.85 106.78,62.8 107.03,62.8 112.48,68.25 116.23,68.25 118.35,66.13 118.35,60.89 121.74,57.49 124.07,57.49 126.22,55.35 136.29,55.35 137.62,56.67 154.38,56.67 156.47,58.76 156.47,59.61 159.05,62.18 161.16,62.18 161.49,61.85 164.13,61.85 164.37,62.09 167.24,62.09 167.51,62.36 171.01,62.36 171.66,61.71 174.74,61.71 175.53,62.51 177.39,62.51 177.78,62.12 178.9,62.12 179.59,61.43 180.7,61.43 181.49,60.64 185.89,60.64 187.02,59.51 210.56,59.51 210.83,59.78 220.79,59.78 223.25,62.24 239.32,62.24 240.14,61.43 240.82,61.43 241.24,61.01 241.24,60.3 241.89,59.65 243.82,59.65 244.61,58.86 v1(244.92,58.86)
  IN3 w0.081: v1(244.92,58.86) 245.35,59.3 245.35,61.56 245.09,61.81 245.09,63.18 243.19,65.09 243.19,69.51 243.85,70.17 243.85,72.96 242.2,74.61 242.2,75.22 242,75.42 242,77.54 241.47,78.07 240.04,78.07 239.63,78.47 239.63,79.5 239.43,79.7 236.62,79.7 236.56,79.64 234.12,79.64 233.73,79.25 v1(233.51,79.25)
  IN4 w0.076: v1(233.51,79.25) 233.11,79.64 233.11,81.08 232.97,81.23 232.48,81.23 232.17,81.55 232.17,82.03 232.57,82.44 232.57,84.84 232.57,85.38 232.57,85.64 232.57,86.91 231.68,87.79 231.68,88.61 232.47,89.39 233.89,89.39 234.17,89.12 234.17,88.43 234.86,87.74 235.19,87.74 235.75,88.3 235.75,93.09 242.54,99.88 244.92,99.88 245.5,100.47 245.5,101.97 246.41,102.88 246.41,104.62 250.95,109.16 257.28,109.16 262.31,114.19 262.31,122.85 261.76,123.4 261.76,125.49 262.37,126.1 v1(262.54,126.1)
  BOTTOM w0.076: U1.BA11 101.22,66.99 100.96,66.74 100.96,66.35 101.16,66.15 101.36,66.15 101.96,65.54 102.14,65.54
  BOTTOM w0.102: 102.14,65.54 103.41,64.27 103.41,62.52 103.57,62.37 103.57,61.84 103.74,61.66 v4(103.77,61.66) 103.87,61.56 v1(104.78,61.56)
  BOTTOM w0.127: v1(262.54,126.1) 262.83,126.39 J5.14
-SUSWARN: length 1.2
  TOP w0.127: v1(100.59,71.16) 100.15,71.6 RC68.1
  BOTTOM w0.076: v1(100.59,71.16) 100.36,71.16 U1.AR13
-SVID_ALERT: length 64.9
  IN3 w0.081: v1(70.45,94.84) 70.64,94.65 71.51,94.65 71.52,94.66 71.52,94.66 72.06,95.2 72.06,95.21 72.36,95.5 77.64,95.5 79.16,97.01 88.3,97.01 88.63,96.68 93.68,96.68 94.17,96.2 98.26,96.2 99.53,94.93 105.3,94.93 107.01,96.65 117.72,96.65 118.35,96.02 121.57,96.02 121.83,95.77 129.72,95.77 130.08,96.13 130.36,96.13 v1(130.41,96.18)
  BOTTOM w0.102: PR409.1 130.35,96.24 v1(130.41,96.18) ; RC79.1 70.6,94.31 RC76.2 70.58,94.71 v1(70.45,94.84)
-SVID_ALERT_R: length 6.9
  BOTTOM w0.102: v4(69.88,94.6) 69.88,94.42 70.27,94.04 70.27,93.3 70.43,93.14 RC79.2 70.6,91.17 70.72,91.05 70.72,90.65 71.31,90.07 71.31,88.77 U1.B63
-THRM: length 1.9
  TOP w0.102: R166.1 223.69,77.76 223.78,77.67 223.78,77.63 224.01,77.41 R164.1 224.44,77.03 R169.2
-TPM_IRQ: length 55.8
  TOP w0.102: v1(103.84,64.05) 103.84,65.01 103.17,65.68 103.17,66.24 101.13,68.29 v4(101.13,71.77) 101.13,72.03 RC153.1 ; v1(134.98,56.6) 134.88,56.71 134.03,56.71 R396.1
  IN1 w0.076: v1(103.84,64.05) 103.84,63.83 104.23,63.45 104.59,63.45 107.73,66.59 109.09,66.59 111.37,68.87 116.59,68.87 119.36,66.09 119.36,64.55 120.84,63.08 120.84,61.16 123.6,58.4 124.02,58.4 125.75,56.68 131.38,56.68 131.86,57.16 134.43,57.16 v1(134.98,56.6)
  BOTTOM w0.102: v1(103.84,64.05) 103.84,64.38 102.37,65.85 101.99,65.85 101.34,66.5 U1.BB11
-TPM_IRQ_R: length 2.2
  TOP w0.102: U26.18 132.47,57.64 133.4,56.71 R396.2 R397.2
-USB_PORT0_OC0: length 222.6
  TOP w0.102: v1(276.58,83.2) 276.31,82.93 U12.13
  IN3 w0.081: v1(115.48,103.92) 115.55,103.85 116.93,103.85 117.2,104.13 124.6,104.13 125.94,105.47 141.72,105.47 143.44,103.75 148.04,103.75 150.99,100.8 150.99,98.23 155.31,93.91 155.31,91.06 159.01,87.36 175.47,87.36 178.14,90.03 178.14,92.26 180.73,94.86 184.77,94.86 187.41,92.21 200.8,92.21 201.89,93.31 213.39,93.31 215.2,91.5 216.42,91.5 217.87,92.95 225.61,92.95 226.54,92.03 242.45,92.03 242.82,91.66 243.7,91.66 244.08,92.04 244.08,93.81 242.88,95.01 242.88,96 243.6,96.71 249.59,96.71 250.09,97.21 251.36,97.21 253.68,94.88 253.68,87.97 257.66,83.99 261.01,83.99 262.71,85.69 273.49,85.69 275.29,83.88 276.15,83.88 276.58,83.45 v1(276.58,83.2)
  BOTTOM w0.102: U1.A9 102.69,89.67 103.18,90.16 103.18,90.97 103.62,91.41 103.69,91.41 RC44.1 104.74,92.46 104.74,93.74 104.17,94.32 104.17,96.6 108.9,101.34 v4(110.65,101.34) 113.83,101.34 114.52,102.02 114.52,102.37 115.1,102.95 115.1,103.54 v1(115.48,103.92)
-USB_PORT1_OC1: length 142.9
  TOP w0.102: v1(13.29,26.04) U13.5
  IN1 w0.076: v1(39.13,63.72) 38.46,63.72 37.78,64.4 37.78,68.26 44.76,75.25 50.96,75.25 56.78,81.06 60.11,81.06 65.19,86.14 65.92,86.14 68.21,88.43 77.51,88.43 78.14,87.79 79.82,87.79 80.47,87.14 80.47,85.31 80.91,84.87 91.12,84.87 92.8,86.55 92.8,87.69 93.43,88.33 99.65,88.33 101.23,89.9 101.99,89.9 v1(102.8,90.72)
  IN4 w0.076: v1(13.29,26.04) 17.27,30.02 17.27,31.69 19.51,33.93 19.51,36.47 22.43,39.39 28.68,39.39 35.78,46.49 35.78,56.39 39.13,59.73 v1(39.13,63.72)
  BOTTOM w0.102: U1.C9 102.4,88.12 102.4,89.7 102.8,90.11 v1(102.8,90.72) 102.65,90.87 102.65,91.5 v3(102.68,91.53) 103.07,91.92 RC45.1
-USB_PORT2_OC2: length 6.3
  BOTTOM w0.102: RC135.1 104.66,91.82 104.66,91.68 v4(104.2,91.22) 103.95,90.97 103.95,90 103.29,89.34 103.29,88.66 102.93,88.3 102.93,88.02 103.03,87.92 103.03,87.69 102.69,87.36 U1.D9
-WIGIG_RF_KILL: length 44.1
  TOP w0.102: R209.1 226.14,70.57 TP6.1 226.98,71.41 v1(227.14,71.41) ; U16.C10 v1(229.55,74.5)
  IN4 w0.076: v1(224.16,76.52) 224.55,76.52 225.23,75.83 226.73,75.83 228.46,74.1 229.17,74.1 229.55,74.49 v1(229.55,74.5)
  BOTTOM w0.102: v1(224.16,76.52) 223.66,77.02 222.59,77.02 221.27,78.35 220.86,78.35 220.74,78.22 217.61,78.22 216.19,76.8 216.19,76.24 214.49,74.54 214.49,67.07 215.6,65.95 215.6,65.32 214.99,64.71 214.99,63.69 214.03,62.72 213.67,62.72 211.48,60.53 210.66,60.53 210.05,59.92 J32.56 ; v1(227.14,71.41) 227.34,71.41 229.14,73.21 229.14,73.85 229.55,74.26 v1(229.55,74.5)
-WWAN_DISABLE: length 17
  TOP w0.102: v1(228.71,64.02) 228.71,65.04 227.34,66.41 227.34,68.57 227.16,68.74 226.86,68.74 TP12.1 226.73,68.87 226.47,69.13 226.47,69.89 R210.1 226.8,70.53 227.18,70.91 227.43,70.91 228.05,71.53 228.05,72.1 229.13,73.17 U16.A11
  BOTTOM w0.102: J22.8 227.35,62.66 v1(228.71,64.02)
-WWAN_PE_DTCT: length 188.2
  TOP w0.102: U163.4 250.14,58.13 250.14,58.61 249.74,59.01 249.74,59.27 v1(249.39,59.63) ; v1(145.65,69.96) 145.55,69.96 143.67,68.08 143.67,67.27 142.25,65.85 142.25,64.38 143.09,63.54 144,63.54 145.17,62.37 155.08,62.37 155.84,61.61 160.78,61.61 v1(162.05,62.88)
  IN3 w0.081: v1(145.65,69.96) 145.32,69.96 144.74,70.55 144.74,74.1 143.21,75.63 143.21,81.04 140.82,83.43 138.84,83.43 136.07,86.2 134.39,86.2 132.31,88.28 132.31,90.24 130.54,92.01 122.31,92.01 120.56,90.26 v1(120.23,90.26)
  IN4 w0.076: v1(249.39,59.63) 249.18,59.63 248.06,60.74 246.73,60.74 246.35,60.36 244.43,60.36 244,59.93 234.2,59.93 233.86,60.27 233.86,60.62 233.43,61.05 225.69,61.05 224.88,60.24 223.58,60.24 222.31,58.97 201.77,58.97 199.96,60.77 199.96,61.35 198.79,62.52 195.64,62.52 195.28,62.88 194.73,62.88 194.27,62.42 184.62,62.42 183.3,61.1 181.24,61.1 180.78,61.56 179.61,61.56 179,62.17 178.01,62.17 177.38,62.8 175.6,62.8 175.27,62.47 172.57,62.47 170.92,60.82 168.24,60.82 166.79,62.27 162.67,62.27 v1(162.05,62.88)
  BOTTOM w0.076: U1.G4 105.5,85.61 105.77,85.89 106.33,85.89 106.4,85.96 106.42,85.97 106.44,85.99 106.46,86 106.69,86.14
  BOTTOM w0.102: 106.69,86.14 106.69,86.42 107.02,86.75 107.02,87.03 107.15,87.16 107.71,87.16 108.14,86.73 108.87,86.73 108.9,86.7 109.13,86.7 109.66,87.24 109.66,87.54 110.45,88.33 111.24,88.33 112.96,86.6 113.46,86.6 R2745.1 113.98,86.09 114.31,86.42 115.3,86.42 115.38,86.5 116.65,86.5 117.13,86.98 119.19,86.98 120.94,88.73 120.94,89.55 v1(120.23,90.26)
-WWAN_RESET: length 171.4
  TOP w0.102: v1(241.12,56.13) 240.71,55.71 R408.2 240.7,54.8 240.12,54.22 Q30.1
  IN1 w0.076: v1(205.11,70.12) 205.44,69.79 205.44,68.29 205.83,67.91 213.62,67.91 215.1,69.38 216.52,69.38 216.98,68.92 216.98,66.51 217.43,66.05 222.51,66.05 225.03,68.57 225.49,68.57 225.94,69.02 226.86,69.02 228.43,67.45 230.66,67.45 230.84,67.27 232.57,67.27 233.23,66.62 234.82,66.62 236,65.44 238.54,65.44 239.46,64.53 v1(240.65,64.53)
  IN3 w0.081: v1(241.12,56.13) 241.4,56.41 241.4,59.13 239.9,60.63 239.9,61.16 239.71,61.35 239.71,63.26 240.62,64.17 240.62,64.5 v1(240.65,64.53) ; v1(205.11,70.12) 204.71,70.12 203.12,68.53 202.72,68.53 202.51,68.32 201.17,68.32 200.87,68.62 199.53,68.62 199.51,68.6 198.97,69.15 198.56,69.15 197.91,68.5 197.91,68.07 197.16,67.31 194.62,67.31 194.45,67.15 189.26,67.15 189.11,67 186.05,67 185.86,66.81 183.42,66.81 183.27,66.97 179.02,66.97 178.65,67.35 174.08,67.35 173.67,66.94 168.23,66.94 167.17,65.87 163.79,65.87 161.06,63.15 158.75,63.15 157.31,61.71 157.31,61.15 156.85,60.69 154.16,60.69 153.32,59.85 148.76,59.85 147.95,60.66 142.94,60.66 142.77,60.49 139.78,60.49 138.74,61.53 138.74,61.68 137.93,62.5 136.74,62.5 136.15,63.08 135.19,63.08 134.4,63.87 132.14,63.87 131.68,64.32 130.82,64.32 130.08,65.06 130.08,65.42 129.12,66.38 126.58,66.38 123.05,69.91 120.99,69.91 118.98,71.92 105.55,71.92 103.64,73.82 103.36,73.82 v1(102.9,74.28)
  BOTTOM w0.102: v1(102.9,74.28) 102.66,74.52 U1.AH9
-WWAN_SSD_DTCT: length 36.4
  TOP w0.102: R602.1 253.07,55.13 v1(252.92,55.28) 252.77,55.14 Q263.1 ; R178.1 239.14,71.44 v1(238.85,71.74) 238.85,72.34 237.97,73.21 237.7,73.21 237.13,73.79 U16.B1
  IN3 w0.081: v1(238.85,71.74) 240.27,71.74 241.97,70.04 241.97,68.82 241.54,68.39 241.54,67.45 241.79,67.2 241.79,64.76 239.91,62.88 239.91,61.43 240.12,61.23 240.12,60.74 241.64,59.22 241.64,57.67 243.18,56.13 v1(243.18,55.9)
  IN4 w0.076: v1(252.92,55.28) 252.18,54.55 244.41,54.55 243.18,55.77 v1(243.18,55.9)
-XDP_DBR: length 252.7
  TOP w0.102: v1(196.66,60.69) 196.66,61 196.83,61.18 199.04,61.18 199.4,61.53 199.4,62.24 199.15,62.5 197.52,62.5 197.39,62.62 197.39,63.74 197.16,63.97 196.02,63.97 193.05,61 189.25,61 RC111.1 188.27,60.02 RC164.1 187.82,59.7 187.72,59.6 180.87,59.6 179.16,57.89 178.11,57.89 177.58,57.37 J8.18 ; J41.13 253.26,105.36 252.83,104.93 249.27,104.93 TP46.1 249.04,105.16 249.04,106.3 247.78,107.56 247.78,109.03 v1(247.75,109.06)
  IN3 w0.081: v1(108.37,87.13) 108.98,86.52 108.98,86.09 108.8,85.91 108.31,85.91 107.48,85.08 107.48,84.7 107.76,84.42 109.26,84.42 109.96,83.72 109.96,77.28 110.62,76.62 118.92,76.62 119.64,75.91 121.98,75.91 123.07,74.82 123.07,71.64 124.57,70.14 126.37,70.14 127.16,69.35 130.49,69.35 132.14,67.7 133.87,67.7 135.75,65.82 137.12,65.82 137.62,65.32 137.62,65.03 139.13,63.53 141.7,63.53 142.43,62.8 144.31,62.8 146.29,60.82 148.02,60.82 148.66,60.18 152.97,60.18 154.06,61.28 156.07,61.28 158.1,63.31 160.97,63.31 163.75,66.09 166.96,66.09 168.02,67.14 173.54,67.14 173.97,67.58 178.67,67.58 179.03,67.93 181.39,67.93 182.17,67.15 183.78,67.15 183.9,67.03 185.29,67.03 185.43,67.17 188.91,67.17 189.09,67.35 191.15,67.35 192.72,68.92 196.83,68.92 197.67,69.76 199.35,69.76 199.64,69.47 201.04,69.47 201.62,68.88 v1(202.02,68.88) 202.17,69.04 202.17,69.94 202.75,70.52 205.6,70.52 206.1,71.03 206.1,71.16 206.52,71.58 207.34,71.58 209.69,73.93 209.69,74.79 211.18,76.29 212.12,76.29 214.39,78.55 214.39,79.95 214.03,80.3 214.03,83.45 217.69,87.11 219.08,87.11 219.8,87.82 224.42,87.82 224.72,88.12 227.86,88.12 228.4,88.66 v1(228.4,88.89)
  IN4 w0.076: v1(228.4,88.89) 228.4,92.55 226.65,94.3 226.65,95.95 230.25,99.56 230.25,102.84 229.8,103.29 229.8,105.17 232.04,107.42 232.04,108.03 232.43,108.42 239.4,108.42 240.34,107.48 246.18,107.48 v1(247.75,109.06)
  BOTTOM w0.102: v1(202.02,68.88) 202.02,68.57 201.69,68.24 201.69,66.64 199.39,64.34 199.39,62.91 197.61,61.14 197.05,61.14 196.66,60.74 v1(196.66,60.69) ; v1(108.37,87.13) 108.16,87.13 107.46,87.84 107.21,87.84 107.03,88.03 107.03,88.24 106.95,88.32 106.49,88.32 106.35,88.18 106.1,88.18 105.81,88.47 U1.B5
-XDP_PRDY: length 172
  TOP w0.102: J8.2 169.58,55.86 169.81,55.64 169.81,53.73 v1(169.58,53.5)
  IN3 w0.081: v1(74.76,90.23) 74.53,90.23 74.3,90 74.3,89.39 72.96,88.05 68.31,88.05 66.33,86.07 65.79,86.07 57.54,77.82 57.54,68.95 55.71,67.11 55.71,62.75 66.43,52.03 92.13,52.03 93.82,53.72 99.35,53.72 100.73,55.09 100.74,55.09 105.41,59.76 108.58,59.76 108.99,60.17 116.59,60.17 120.86,55.91 123.26,55.91 126.07,53.1 127.82,53.1 128.44,52.48 135.81,52.48 137.42,54.09 157.72,54.09 158.78,55.16 159.95,55.16 160.49,54.62 163.59,54.62 164.25,53.96 169.12,53.96 v1(169.58,53.5)
  BOTTOM w0.076: U1.D56 75.22,87.5 75.14,87.77 75.14,87.88 75.06,88.16 75.02,88.32 75,88.36 75,88.61 75.01,88.63 75.03,88.64 75.03,88.67 75.04,88.7 75.04,89.22 75.22,89.39 75.22,89.78 v1(74.76,90.23)
-XDP_PREQ: length 175.3
  TOP w0.102: J8.1 169.08,56.01 169.61,55.49 169.61,54.22 168.94,53.56 v1(168.94,53.5)
  IN3 w0.081: v1(168.94,53.5) 164.14,53.5 163.46,54.19 160.05,54.19 159.72,53.86 137.45,53.86 135.81,52.22 132.19,52.22 131.66,51.69 131.66,51.21 131.14,50.69 101.35,50.69 98.54,53.49 93.93,53.49 92.16,51.73 66.37,51.73 55.45,62.64 55.45,67.27 57.34,69.15 57.34,78.15 65.51,86.32 66.23,86.32 68.16,88.25 72.86,88.25 74.13,89.52 74.13,90.19 74.6,90.66 75.17,90.66 v1(75.32,90.82)
  BOTTOM w0.076: v1(75.32,90.82) 75.29,90.84 75.29,92.01 ; U1.D61 73.23,87.44 73.23,87.62 73.25,87.64 73.25,88.01 73.23,88.03 73.23,88.27 73.28,88.32 73.28,89.59 72.5,90.36 72.5,91.73 72.73,91.97
  BOTTOM w0.089: 72.73,91.97 73.05,91.97 74.02,92.93 v4(74.35,92.93)
  BOTTOM w0.102: 75.29,92.01 74.37,92.93 v4(74.35,92.93)
-XDP_TRST: length 220.2
  TOP w0.102: J8.21 179.08,56.89 181.26,59.06 186.67,59.06 186.99,58.74 187.05,58.74 187.41,58.38 190.84,58.38 191.82,57.4 v3(191.82,57.19) 191.82,56.58 191.34,56.1 190.77,56.1 189.98,55.31 189.07,55.31 RC137.1 188.59,54.83 188.2,54.83 187.97,54.6 187.97,52.78 v1(187.82,52.62)
  IN3 w0.081: v1(187.82,52.62) 187.29,52.62 187.13,52.46 186.8,52.46 186.7,52.56 186.42,52.56 183.86,50.01 98.95,50.01 96.77,52.18 93.81,52.18 92.29,50.66 66,50.66 54.44,62.22 54.44,67.42 56.6,69.58 56.6,79.01 65.41,87.82 66.43,87.82 67.59,88.98 72.57,88.98 73.39,89.79 73.39,91.2 v1(73.01,91.58) 73.49,92.06 75.04,92.06 76.11,90.99 76.11,90.13 76.72,89.52 76.72,88.15 75.57,87.01 73.54,87.01 v1(73.14,86.6)
  BOTTOM w0.076: v1(73.01,91.58) 73.8,90.79 73.8,88.76 U1.B59 ; U1.C61 72.89,87.82 72.63,87.57 72.63,86.85 72.81,86.68 73.06,86.68 v1(73.14,86.6)
A_ON: length 222.3
  TOP w0.102: v1(122.59,88.1) 122.91,88.42 122.91,88.99 R457.1
  TOP w0.203: TP38.1 245.7,84.64 v1(244.56,83.5) ; PR750.2 157.27,68.44 v3(157.43,68.6) ; U21.F9 v1(247.77,77.1)
  TOP w0.254: v1(158.3,70.09) 158.3,69.47 v3(157.43,68.6)
  IN3 w0.203: v1(244.56,83.5) 244.66,83.6 244.66,85.99 244.15,86.5 244.15,87.59 242.65,89.09 241.46,89.09 240.7,89.85 225.15,89.85 224.75,90.26 224.34,90.26 224.18,90.42 220.9,90.42 218.7,88.23 217.46,88.23 217.03,87.79 209.08,87.79 207.58,89.29 200.85,89.29 200.29,88.73 193.71,88.73 192.82,87.85 189.42,87.85 188.22,89.04 187.16,89.04 184.79,86.68 180.53,86.68 178.72,84.87 178.72,81.36 178.23,80.87 177.68,80.87 177.17,80.35 177.17,79.37 178.72,77.81 178.72,76.67 177.15,75.1 176.26,75.1 171.1,69.94 165.36,69.94 164.96,70.34 161.3,70.34 160.72,69.76 158.63,69.76 v1(158.3,70.09) 157.9,70.09 157.36,69.56 146.59,69.56 v1(145.98,68.95) 145.93,68.95 144.1,70.78 144.1,74.03 142.97,75.16 142.97,80.77 140.72,83.02 138.89,83.02 135.99,85.92 134.27,85.92 132.06,88.13 132.06,88.69 130.61,90.14 128.68,90.14 128.25,89.7 124.87,89.7 123.26,88.1 v1(122.59,88.1) ; v1(119.48,61.34) 121.03,61.34 123.35,59.02 125,59.02 126.43,60.44 127.24,60.44 128.28,59.4 128.89,59.4 130.36,57.92 134.05,57.92 134.58,58.46 135.37,58.46 136.74,57.09 145.91,57.09 v1(146.47,57.64)
  BOTTOM w0.203: v1(247.77,77.1) 247.42,77.1 246.54,77.98 246.54,82.28 245.89,82.93 245.13,82.93 v1(244.56,83.5) ; v1(119.48,61.34) 119.72,61.1 PD301.1 ; v1(146.47,57.64) 146.24,57.64 142.37,61.51 142.37,65.66 142.88,66.18 143.06,66.18 145.07,68.19 145.07,68.39 145.48,68.8 145.83,68.8 v1(145.98,68.95)
AC_PRESENT: length 189.8
  TOP w0.102: U16.E2 236.72,76.09 237.55,76.09 238.21,75.42 238.74,75.42 239.23,75.91 R151.1 239.35,75.65 239.63,75.38 240.37,75.38 240.45,75.45 v1(240.45,75.42)
  IN1 w0.076: v1(240.62,61.02) 240.32,61.02 239.26,62.08 223.3,62.08 220.85,59.63 210.91,59.63 210.64,59.36 186.91,59.36 185.78,60.49 177.25,60.49 176.24,61.5 171.68,61.5 171.03,60.85 168.23,60.85 167.41,61.67 161.45,61.67 161.09,62.03 159.11,62.03 156.63,59.54 156.63,58.7 153.12,55.19 126.15,55.19 124.01,57.34 121.68,57.34 118.2,60.82 118.2,66.07 116.16,68.1 113.44,68.1 110.91,65.57 110.91,62.98 109.6,61.67 108.49,61.67 107.91,62.25 106.98,62.25 106.21,61.48 106.21,61.37 105.74,60.9 104.58,60.9 104.1,61.38 103.07,61.38 101.31,63.14 101.31,63.81 100.83,64.29 100.3,64.29 99.63,63.61 v1(99.42,63.61)
  IN3 w0.081: v1(240.62,61.02) 241.08,61.48 241.08,62.8 242.78,64.5 242.78,71.79 242.2,72.38 242.2,73.9 241.61,74.48 241.61,74.87 241.16,75.32 240.53,75.32 240.45,75.4 v1(240.45,75.42)
  BOTTOM w0.076: v1(99.42,63.61) 99.37,63.61 98.92,64.07 v4(98.92,64.17) 98.92,64.5 98.84,64.58 98.84,65.23 98.37,65.7 98.37,67.23 98.48,67.34 U1.AY15
ACDC_ID: length 168.8
  TOP w0.102: 239.57,83.74 238.21,82.38 238.21,82.15 237.71,81.65 236.7,81.65 U16.L2
  TOP w0.127: 239.57,83.74 239.94,84.11 239.94,84.52 240.18,84.76 240.36,84.76 240.52,84.92 240.52,86.42 v4(240.14,86.8) v1(239.33,86.8)
  TOP w0.254: v1(113.83,106.16) 113.83,105.78 112.89,104.84 PD4.2 111.77,105.65 112.23,106.11 PD5.1 PR17.2
  IN3 w0.203: v1(166.61,94.4) 166.55,94.34 166.55,90.77 164.34,88.56 158.4,88.56 155.65,91.3 155.65,94 151.25,98.4 151.25,100.87 147.89,104.23 143.57,104.23 142.07,105.73 125.69,105.73 124.39,104.43 117.36,104.43 115.53,106.26 113.93,106.26 v1(113.83,106.16)
  IN4 w0.152: v1(224.22,88.96) 224.22,90.16 219.49,94.88 213.93,94.88 212.56,96.25 200.03,96.25 193.63,102.65 172.63,102.65 166.61,96.63 v1(166.61,94.4)
  BOTTOM w0.152: v1(239.33,86.8) 238.77,87.36 238.16,87.36 235.52,90 225.26,90 v1(224.22,88.96)
ACDC_ID_DOCK: length 93.9
  TOP w0.203: PC5.1 111.78,108.65 110.73,108.65 PC17.1 PC28.1 PR17.1
  TOP w0.254: PC28.1 109.65,107.69 109.65,108.17 109.55,108.27 PR16.1 108.39,108.27 PQ11.1 ; v1(113.9,110.56) 113.9,110.1 112.4,108.61 PC5.1
  IN3 w0.254: v1(113.9,110.56) 114.45,110 115.88,110 116.33,110.46 122.66,110.46 125.63,107.48 125.63,107.03 126.6,106.06 130.91,106.06 132.21,107.36 133.53,107.36 134.34,106.54 136.83,106.54 137.16,106.87 142.29,106.87 142.8,106.37 149.94,106.37 154.38,101.92 162.31,101.92 163.35,102.96 163.35,104.11 v1(164.62,105.38) 166.07,106.82 168.02,106.82 168.48,106.37 168.48,105.55 175.83,98.21 v1(176.08,98.21)
  BOTTOM w0.203: v1(176.08,98.21) 178.43,98.21 179.7,96.94 J17.47
  BOTTOM w0.254: v1(113.9,110.56) 113.9,110.46 113.42,109.98 PJ1.5
ADAPTER_ID_ON#: length 174.8
  TOP w0.102: v1(188.3,107.61) 189.32,106.59 v3(190.79,106.59) 191.93,106.59 192.87,107.53 200.01,107.53 v1(200.14,107.66) ; PQ11.5 107.73,106.01 107.6,105.88 107.07,105.88 106.33,106.62 105.39,106.62 104.91,107.1 104.91,108.77 105.8,109.66 v1(105.8,109.71) ; U16.N10 229.93,83.6 v1(230.18,83.86) 230.04,84 R184.2
  IN1 w0.076: v1(188.3,107.61) 187.74,107.05 183.35,107.05 182.23,108.17 169.75,108.17 165.87,112.05 158.76,112.05 154.59,107.89 138.2,107.89 136.63,106.32 134.26,106.32 132.69,107.89 123.78,107.89 120.66,111.01 116.87,111.01 115.88,110.02 106.11,110.02 v1(105.8,109.71)
  IN3 w0.081: v1(200.14,107.66) 206.91,100.88 216.9,100.88 218.55,102.53 227.34,102.53 227.9,103.09 233.11,103.09 v1(233.14,103.05)
  IN4 w0.076: v1(233.14,103.05) 233.6,103.05 237.85,98.79 237.85,96.15 234.04,92.34 232.24,92.34 231.45,91.55 231.45,90.11 230.53,89.18 230.53,88.1 231.17,87.47 231.17,86.1 230.18,85.11 v1(230.18,83.86)
ADDR_SEL: length 3.9
  TOP w0.152: U17.7 170.47,88.78 170.75,88.51 172.6,88.51 v4(172.68,88.42) R234.1
  TOP w0.254: R236.2 R234.1
AOU_SEL1: length 71
  TOP w0.102: U12.6 275.31,78.61 274.66,77.96 270.32,77.96 269.38,77.02 v4(268.23,77.02) 268,77.25 v1(266.94,77.25) ; U16.M10 v1(229.55,82.45) 229.55,83.52 229.41,83.67 R152.1
  IN4 w0.076: v1(266.94,77.25) 267.22,77.53 267.22,83.02 260.32,89.92 242.06,89.92 240.5,88.35 240.5,86.07 235.52,81.09 235.52,78.12 235.27,77.87 232.75,77.87 232.29,78.32 232.29,81.05 230.89,82.45 v1(229.55,82.45)
AOU_SEL2: length 75.5
  TOP w0.102: v1(277.25,78.37) 276.72,78.37 276.31,78.78 U12.8 ; U16.L8 v1(231.15,81.65) ; v1(231.47,84.65) 231.17,84.95 R154.1
  IN3 w0.081: v1(266.81,77.86) 266.91,77.86 268.54,76.24 273.34,76.24 273.92,75.65 274.79,75.65 275.29,76.16 275.29,76.67 277,78.37 v1(277.25,78.37)
  IN4 w0.076: v1(231.15,81.65) 231.4,81.65 232.04,81.01 232.04,78.12 232.47,77.69 235.75,77.69 236.33,78.27 236.33,81.55 240.67,85.89 240.67,88.23 242.11,89.66 252.01,89.66 252.01,89.66 260.32,89.66 266.81,83.17 v1(266.81,77.86)
  BOTTOM w0.102: v1(231.15,81.65) 231.07,81.73 231.07,82.94 230.55,83.46 230.55,84.19 230.43,84.31 230.43,84.81 230.72,85.1 231.02,85.1 v1(231.47,84.65)
B_DRV: length 235.8
  TOP w0.203: R373.1 C256.2 ; C256.2 253.73,47.93 255.27,49.47 255.27,50.51 257.72,52.96 257.72,56.51 v3(258.73,57.52) 259.01,57.8 259.01,61.21 259.39,61.59 259.39,66.87 258.63,67.63 v3(258.63,70.61) v1(258,71.23) ; C256.2 254.02,46.43 D58.1 ; R406.1 113.33,102.51 v1(113.55,102.73)
  TOP w0.254: v1(261.95,84.21) 261.95,84.22 261.16,85.01 258.12,85.01 257.56,85.56 255.39,85.56 254.97,85.14 R437.2
  IN1 w0.203: v1(258,71.23) 257.69,71.54 257.69,74.87 259.19,76.36 259.19,82.59 260.82,84.21 v1(261.95,84.21)
  IN3 w0.508: v1(260.16,88.97) 259.13,89.99 259.13,93.59 259.92,94.38 259.92,100.85 258.04,102.73 248.35,102.73 240.75,110.32 221.79,110.32 213.74,102.28 208.82,102.28 201.88,109.21 191.5,109.21 190.71,109.99 183.93,109.99 182.36,108.42 177.71,108.42 176.11,110.02 165.82,110.02 v1(164.42,111.42)
  IN4 w0.203: v1(164.42,111.42) 158.07,111.42 154.85,108.19 151.11,108.19 150.07,107.15 148.45,107.15 147.86,106.57 144,106.57 143.42,107.15 137.42,107.15 136.41,106.13 134.88,106.13 134.43,105.68 126.23,105.68 125.08,104.53 116.8,104.53 115.91,105.42 114.87,105.42 114.46,105.02 114.46,103.64 v1(113.55,102.73)
  BOTTOM w0.203: v1(261.95,84.21) 260.16,86.01 v1(260.16,88.97)
B_DRV_R: length 8.8
  TOP w0.102: v1(253.33,77.14) 252.95,76.75 U21.F3
  TOP w0.203: R437.1 254.56,84.43 v1(254.06,83.93)
  IN2 w0.203: v1(254.06,83.93) 254.09,83.91 254.09,78.63 253.33,77.87 v1(253.33,77.14)
B_ON: length 299.7
  TOP w0.203: v1(247.47,75.99) 247.54,75.93 U21.E9 ; D62.1 89.24,95.83 88.99,96.08 88.99,97.62 v3(87.94,98.67) 87.94,111.04 89.14,112.23 98.18,112.23 98.43,112.48 99.93,112.48 100.52,111.9 v1(100.52,109.74) ; v1(249.77,85.13) 249.54,85.36 249.54,85.97 249.56,85.99 D64.1 ; U16.N11 229.13,84.15 v1(228.89,84.39) 228.82,84.46 228.82,85.18 R205.2
  IN1 w0.203: v1(262.39,125.51) 261.81,124.93 261.81,113.68 258,109.87 250.68,109.87 249.28,108.47 242.99,108.47 242.1,109.36 230.32,109.36 v1(229.21,108.25)
  IN3 w0.203: v1(247.47,75.99) 246.99,75.99 245.6,77.38 244.48,77.38 242.95,78.92 242.95,81.05 242.44,81.56 242.44,81.91 242.12,82.23 240.12,82.23 238.95,83.4 234.71,83.4 234.3,82.99 230.29,82.99 v1(228.89,84.39)
  IN4 w0.203: v1(247.47,75.99) 246.76,75.99 246.11,76.64 246.11,80.43 247.7,82.02 247.7,83.36 249.46,85.13 v1(249.77,85.13) ; v1(228.89,84.39) 228.84,84.44 227.14,84.44 225.38,86.19 225.38,87.87 224.85,88.4 224.85,90.59 221.1,94.34 221.1,106.15 222.29,107.33 228.3,107.33 v1(229.21,108.25) 228.7,108.75 228.7,108.77 228.65,108.83 219.82,108.83 213.75,102.76 208.75,102.76 205.77,105.73 205.77,108.34 204.96,109.16 184.16,109.16 182.33,110.98 180.76,110.98 179.87,111.87 179.13,111.87 177.94,113.07 156.83,113.07 154.44,110.68 152.05,110.68 151.01,109.64 149.97,109.64 148.93,108.6 148.12,108.6 147.35,107.84 145.78,107.84 145.09,108.53 131.27,108.53 129.34,110.46 121.21,110.46 119.24,112.43 102.98,112.43 100.52,109.97 v1(100.52,109.74)
  BOTTOM w0.203: J5.13 260.6,126.39 261.48,125.51 v1(262.39,125.51)
BACKLIGHT_ON: length 174.4
  TOP w0.102: U16.A8 231.53,72.91 v1(231.38,72.76) ; v1(141.71,89.09) 141.28,89.53 139.96,89.53 135.97,93.51 135.97,99.23 137.39,100.65 137.39,104.44 136.81,105.02 132.51,105.02 132.18,104.69 132.18,104.41 131.83,104.06 130.2,104.06 129.9,104.36 129.9,104.77 128.42,106.24 v1(128.42,106.54)
  IN3 w0.081: v1(215.83,92.67) 215.64,92.87 215.05,92.87 213.29,94.63 199.32,94.63 194.64,99.3 181.21,99.3 176.61,103.9 170.82,103.9 168.96,105.76 168.96,106.49 168.23,107.23 165.09,107.23 160.88,103.01 155.91,103.01 151.61,107.31 143.38,107.31 142.63,108.07 139.8,108.07 139.07,108.81 139.07,109.41 137.26,111.23 132.22,111.23 129.11,108.12 129.11,107.23 v1(128.42,106.54)
  IN4 w0.076: v1(231.38,72.76) 231.15,72.99 228.46,72.99 226.02,75.42 224.49,75.42 224.19,75.73 222.87,75.73 222.06,76.54 222.06,77.04 222.89,77.87 222.89,80.36 219.62,83.63 219.62,86.04 217.48,88.18 217.48,91.02 v1(215.83,92.67)
  BOTTOM w0.102: J10.23 135.35,104.24 135.31,104.28 135.31,105.2 134.75,105.76 129.03,105.76 128.4,106.39 128.4,106.49 128.42,106.52 v1(128.42,106.54) ; R4.1 C19.2 142.23,89.09 v1(141.71,89.09)
BAT-PWR: length 21.7
  TOP w0.114: 209.03,90.03 208.91,90.14 208.91,91.85 209.13,92.06
  TOP w0.203: PC141.2 201.66,81.17 PC153.1 201.46,80.15 PR155.2
  TOP w0.254: PC141.2 202.29,81.19 202.55,80.94 203.21,80.94 203.79,80.35 207.88,80.35 210.4,82.87 210.4,88.2 209.03,89.57 209.03,90.03
  vias: v1(192.81,68.06) v1(193.12,67.56) v1(193.19,68.52) v1(193.68,68.17) v1(193.7,67.58) v1(194.29,68.29) v1(194.32,67.58) v1(194.87,68.32) v1(194.9,67.73) v1(195.48,68.32) v1(195.48,67.73) v2(210.55,92.8) v2(210.55,92.09) v2(210.83,91.5) v2(211.21,92.77) v2(211.21,92.14) v2(211.49,91.5) v2(211.85,92.77) v2(211.85,92.14) v2(212.2,91.55) v2(212.48,92.77) v2(212.48,92.14) v2(212.86,91.48) v2(213.04,92.44) v2(213.52,91.5) v2(213.6,92.14) v2(227.77,95.82) v2(227.77,95.19) v2(227.77,94.55) v2(227.77,93.92) v2(228.41,95.82) v2(228.41,95.19) v2(228.41,94.55) v2(228.41,93.92) v2(229.04,95.82) v2(229.04,95.19) v2(229.04,94.55) v2(229.04,93.92) v2(229.68,95.82) v2(229.68,95.19) v2(229.68,94.55) v2(229.68,93.92) v2(230.31,95.82) v2(230.31,95.19) v2(230.31,94.55) v2(230.31,93.92) v3(211.13,90.59)
BAT_CRG: length 5.5
  TOP w0.152: U21.B7 249.36,73.14 249.36,72.45 248.52,71.61 248.52,70.78 248.29,70.55 R436.2 247.6,69.72 TP84.1
BATDRV#: length 15.9
  TOP w0.203: v2(199.35,80.58) 199.22,80.45 v4(199.22,78.78) PU101.21
  TOP w0.381: PR170.1 203.29,89.85 v2(202.5,89.85)
  BOTTOM w0.381: v2(202.5,89.85) 200.92,88.28 199.6,88.28 199.22,87.9 199.22,82.16 199.81,81.57 199.81,80.86 199.53,80.58 v2(199.35,80.58)
BDC_ON: length 47.9
  TOP w0.102: U16.C11 v1(228.75,74.5) ; R211.1 221.33,71.83 221.04,71.54 TP7.1 221.07,71.16 221.65,71.16 v1(221.93,71.44)
  IN1 w0.076: v1(228.75,74.5) 226.53,76.72 v1(226.53,76.82)
  BOTTOM w0.102: v1(226.53,76.82) 225.69,76.82 225.23,77.28 222.69,77.28 221.37,78.6 220.76,78.6 220.58,78.42 218.63,78.42 v3(218.45,78.6) 217.51,78.6 215.72,76.81 215.72,76.22 214.11,74.61 214.11,67.04 214.72,66.43 214.72,63.72 214,63 213.5,63 211.41,60.92 210.42,60.92 209.55,60.05 J32.54 ; v1(228.75,74.5) 228.52,74.5 227.42,73.39 223.99,73.39 223.71,73.11 223.71,72.73 223.1,72.12 222.54,72.12 221.93,71.51 v1(221.93,71.44)
BEEP_MIX_ATT: length 14.5
  TOP w0.102: v3(286.34,56.24) 285.17,56.24 285.04,56.37 Q228.1
  TOP w0.254: C2503.1 273.54,55 v1(273.57,54.98) ; Q228.1 284.2,56.37 284.08,56.24 284.04,56.24 283.9,56.1 R67.1 282.79,56.1 R66.2 282.56,56.33 282.2,56.33 v1(282.12,56.41)
  BOTTOM w0.254: v1(282.12,56.41) 281.15,56.41 280.82,56.74 275.53,56.74 273.77,54.98 v1(273.57,54.98)
BPWRG: length 321.1
  TOP w0.102: U20.4 245.93,97.25 246.54,96.63 U19.4 247.63,96.51 v1(247.63,96.07) ; R284.1 C207.2 ; C207.2 245.92,71.56 D714.2 246.36,70.4 v1(246.48,70.4) ; C207.2 246.64,71.1 v1(246.64,70.98) ; U16.F3 v1(235.91,76.9) ; R324.1 259.31,68.57 v1(259.11,68.78) ; U21.D5 250.99,75.48 250.99,75.55 v1(251.09,75.65) ; v1(220.96,77.84) 218.94,77.84 Q8.2 ; v1(135.92,69.84) 135.86,69.77 U184.4 134.87,69.34 134.68,69.15 134.38,69.15 133.97,68.74 133.97,67.5 134.16,67.31 U185.4
  IN1 w0.076: v1(246.64,70.98) 246.64,72.2 246.27,72.57 246.27,75.65 245.84,76.07 245.13,76.07 244.29,75.23 244.29,74.88 243.02,73.61 242.84,73.61 241.53,72.3 240.22,72.3 239.96,72.55 239.96,73.49 239.32,74.13 239.32,74.54 239.09,74.78 238.88,74.78 237.27,76.39 236.41,76.39 v1(235.91,76.9) 235.29,77.51 232.52,77.51 231.5,76.49 228.36,76.49 227.62,77.23 226.2,77.23 225.89,76.92 225.66,76.92 224.9,77.69 221.12,77.69 v1(220.96,77.84) ; v1(255.12,67.38) 254.2,67.38 250.8,70.78 250.8,75.37 v1(251.09,75.65)
  IN3 w0.081: v1(246.48,70.4) 246.72,70.4 247.63,71.31 247.63,72.04 248.98,73.39 250.35,73.39 250.89,73.93 250.89,74.79 250.99,74.89 250.99,75.55 v1(251.09,75.65) ; v1(259.11,68.78) 259.11,68.32 258.17,67.38 v1(255.12,67.38) ; v1(108.98,87.13) 110.12,85.99 115.35,85.99 115.86,85.48 115.86,81.37 117.03,80.2 119.29,80.2 120.28,79.21 125.69,79.21 126.96,77.94 130.72,77.94 131.48,77.18 131.48,75.88 135.92,71.44 v1(135.92,69.84) ; v1(247.63,96.07) 243.77,96.07 v1(243.37,95.67) 243.37,95.19 244.33,94.22 244.33,91.91 243.82,91.4 242.74,91.4 242.28,91.86 226.33,91.86 225.5,92.7 217.89,92.7 215.71,90.51 209.51,90.51 208.06,91.96 187.31,91.96 184.67,94.6 180.83,94.6 178.37,92.14 178.37,89.93 175.62,87.18 158.88,87.18 155.06,91.01 155.06,93.74 150.81,97.99 150.81,100.7 147.94,103.57 143.33,103.57 141.63,105.27 126.04,105.27 124.72,103.95 117.43,103.95 117.1,103.62 115.81,103.62 v1(115.52,103.33)
  BOTTOM w0.102: v1(115.52,103.33) 115.52,103.05 114.74,102.27 114.74,101.84 113.9,101 109.05,101 105.26,97.21 105.26,94.97 v4(106,94.22) RC65.1 106,92.9 106.64,92.26 106.64,90.11 107.91,88.84 107.91,88.51 107.81,88.4 107.81,88 108.02,87.78 108.61,87.78 108.98,87.41 v1(108.98,87.13) ; v1(243.37,95.67) 242.67,94.97 242.67,93.46 244.45,91.69 244.45,91.2 246.76,88.9 246.76,87.05 247.23,86.58 247.23,79.65 248.49,78.39 248.49,76.53 249.42,75.6 251.03,75.6 v1(251.09,75.65)
BYPASS_PAD: length 84.2
  TOP w0.102: U16.C12 228.22,74.87 227.85,75.25 226.5,75.25 v1(226.02,74.76) 225.78,75 R374.2
  IN4 w0.076: v1(225.05,63.99) 225.05,63.77 221.32,60.03 202.38,60.03 201.23,61.19 201.23,61.71 198.74,64.2 195.54,64.2 195.28,63.94 194.22,63.94 193.6,64.57 175.43,64.57 175.14,64.86 172.22,64.86 169.78,62.42 169.78,62.04 v1(169.33,61.58)
  BOTTOM w0.102: v1(225.05,63.99) 225.05,64.43 224.62,64.86 223.88,64.86 222.77,65.98 222.77,68.64 221.65,69.76 221.65,70.85 221.45,71.06 221.45,71.56 222.63,72.75 222.63,73.02 223.5,73.9 225.49,73.9 226.02,74.43 v1(226.02,74.76) ; J16.5 171.1,60.75 171.03,60.82 170.01,60.82 169.33,61.51 v1(169.33,61.58)
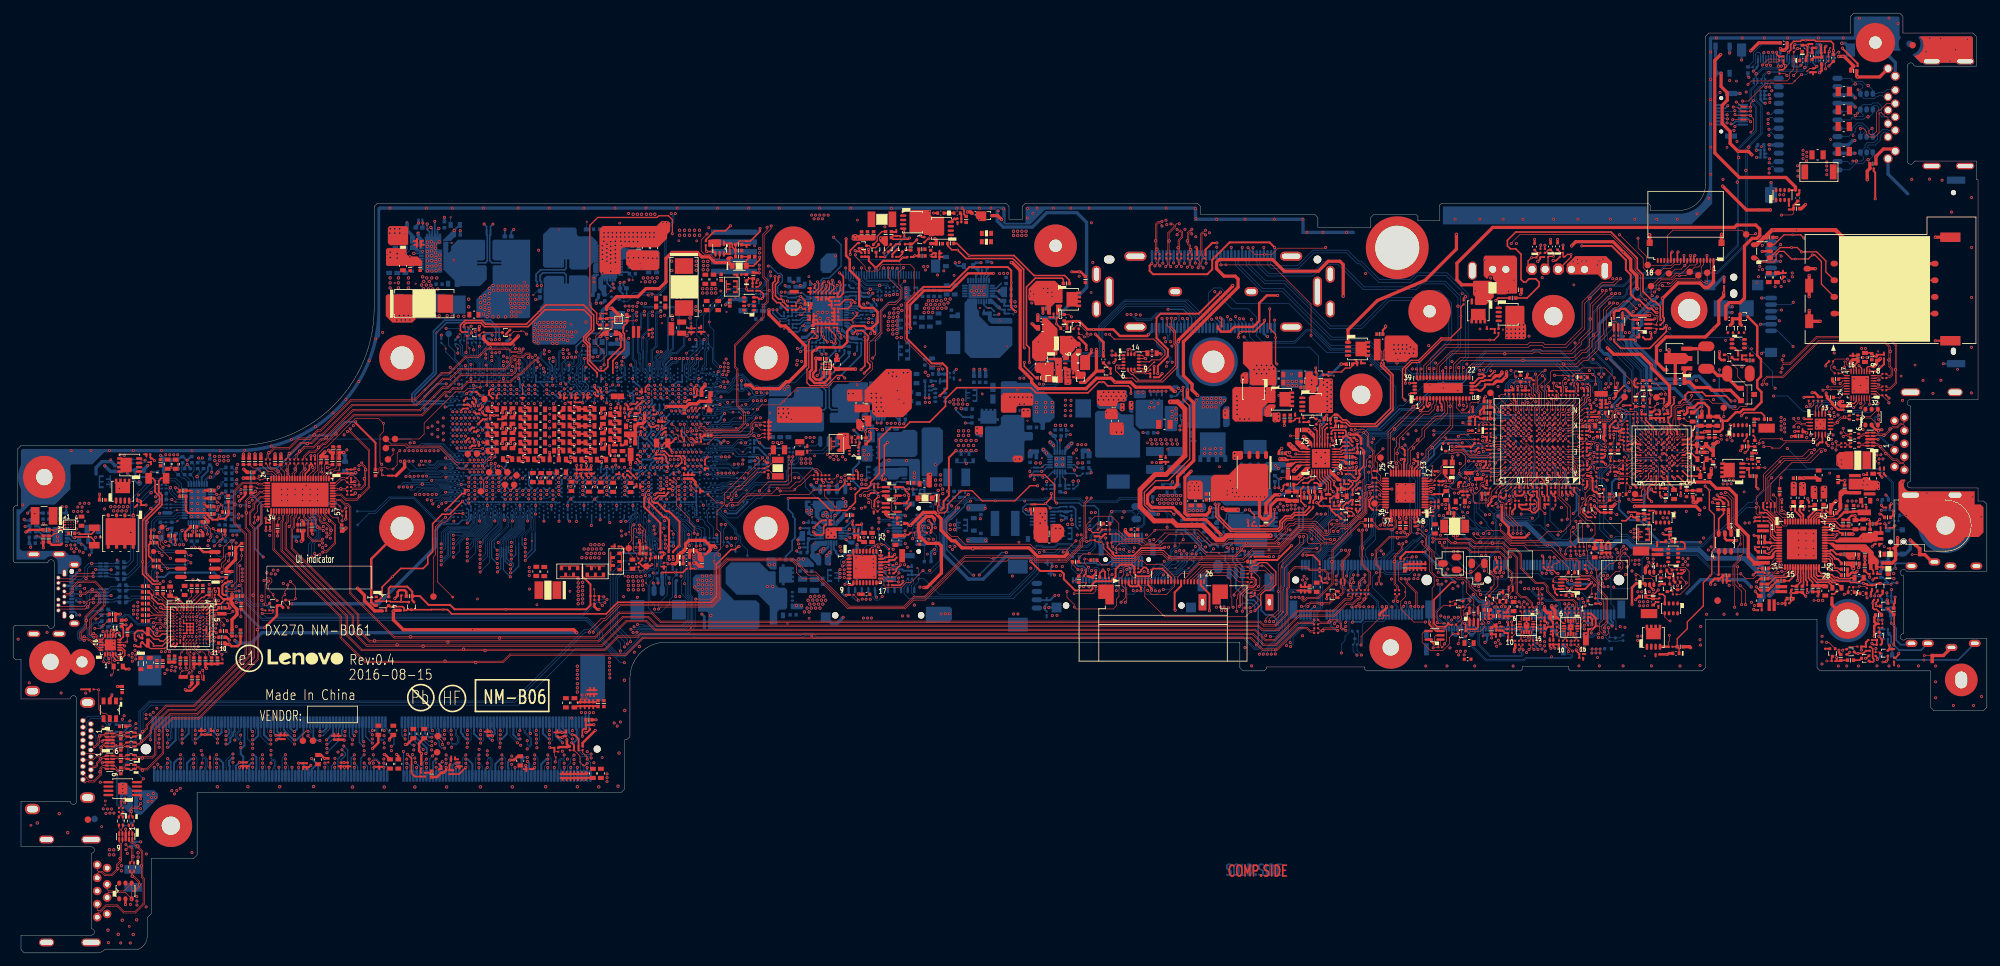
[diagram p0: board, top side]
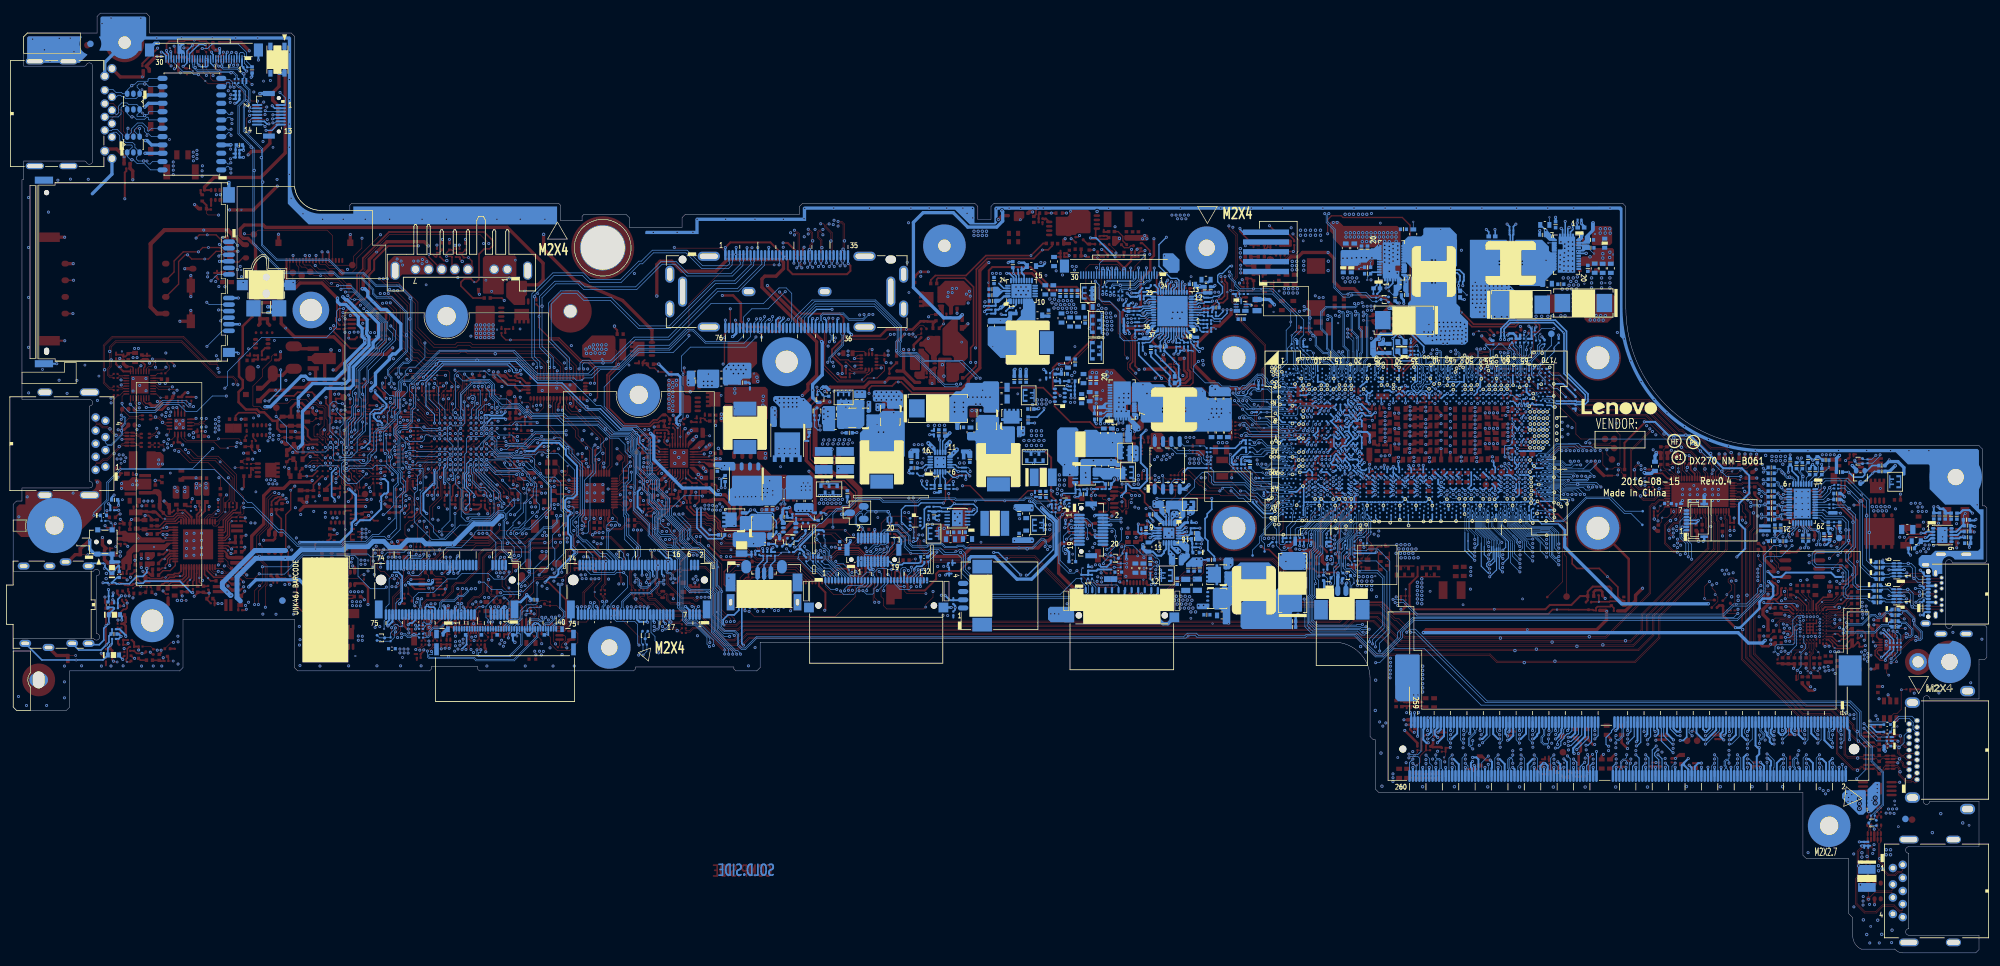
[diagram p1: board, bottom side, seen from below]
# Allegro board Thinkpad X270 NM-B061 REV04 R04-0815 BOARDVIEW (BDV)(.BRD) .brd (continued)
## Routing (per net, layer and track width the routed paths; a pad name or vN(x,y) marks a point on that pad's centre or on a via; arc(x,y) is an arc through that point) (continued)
CACHE_DTCT: length 3.3
  TOP w0.102: U163.5 249.52,57.84 249.91,57.45 250.49,57.45 D705.2 251.25,58.21 R2747.1
CACHE_DTCT_SW: length 6.9
  TOP w0.102: R10090.1 254.36,57.26 v3(255.13,56.5) 255.13,56.3 254.25,55.42 Q226.1 253.48,55.42 Q263.2 252.54,56.36 Q227.1 251.94,57.27 251.88,57.22 D705.1
CFG3: length 207.8
  TOP w0.102: v1(188.73,52.11) 187.92,51.29 175.6,51.29 172.55,54.34 172.55,55.79 172.58,55.82 J8.8
  IN3 w0.081: v1(67.8,91.53) 67.55,91.53 54.92,78.9 54.92,69.56 53.32,67.96 53.32,61.54 66.52,48.34 91.48,48.34 94.21,51.07 96.45,51.07 98.16,49.36 185.98,49.36 v1(188.73,52.11)
  BOTTOM w0.127: U1.D67 69.38,88.07 69.38,88.26 69.42,88.31 69.42,88.64 69.38,88.68 69.38,88.91 69.42,88.96 69.42,89.39 69.38,89.44 69.38,90.28 68.26,91.4 68.26,92.44 67.8,92.9 RC101.2 67.45,92.57 v4(67.8,92.22) v1(67.8,91.53)
CFG_RCOMP: length 2.6
  TOP w0.305: v1(73.14,86.02) 72.86,86.02 v4(72.56,85.71) 72.56,85.21 RC103.2
  BOTTOM w0.254: v1(73.14,86.02) 73.21,86.02 U1.E60
CH_AGND: length 34
  TOP w0.178: v1(195.58,76.14) 195.64,76.07 197.41,76.07 PU101.27
  TOP w0.203: PC137.2 PC157.2 202.78,78.47 202.47,78.17 v1(202.47,78.12) 202.47,78.07 202.61,77.93 PC133.1
  TOP w0.254: v2(204.25,71.94) 203.92,71.94 203.73,72.14 PR101.1 ; v2(204.25,71.94) 204.25,71.44 203.58,70.76 PC165.2 202.38,71.3 PC139.1 ; v2(204.25,71.94) 204.31,72 204.75,72 205.13,72.38 PC131.1 205.33,72.71 205.33,73.04 PR150.1 205.3,73.06 205.25,73.11 205.25,73.6 PC152.1 205.29,73.62 205.93,74.26 PC166.2 205.93,76.68 PR190.2 ; PC148.1 203.95,78.28 203.95,78.46 PR162.1 203.67,78.6 203.23,79.03 ; 203.23,79.03 202.97,78.76 PC157.2 ; 203.23,79.03 203.23,79.59 203.04,79.78 201.24,79.78 201.01,79.55 PR145.1 ; 201.02,67.68 200.81,67.89 PR135.2 v3(199.68,68.19) 199.27,68.19 v1(198.75,68.71) 199.07,68.71 199.52,69.16 PC164.2 ; 201.02,67.68 202.57,67.68 202.8,67.91 202.8,68.16 203.3,68.66 PQ107.3 203.56,68.66 204,69.11 PQ106.3 204.23,68.46 PC128.2 ; 201.02,67.68 201.02,67.5 201.71,66.81 201.93,66.81 PQ105.3 ; PC158.2 v1(196.85,70.3) ; PC164.2 199.62,69.35 PR140.1 ; PC164.2 199.52,70.22 PC144.2
  TOP w0.305: v2(193.42,76.99) 193.02,76.59 PC155.2
CL_CLK_WLAN: length 137.3
  IN3 w0.081: v1(206.87,74.92) 206.84,74.92 205.5,73.57 203.08,73.57 202.17,72.66 201.05,72.66 200.4,72.01 199.89,72.01 199.42,71.54 194.42,71.54 191.73,74.23 181,74.23 179.83,73.07 175.5,73.07 171.43,69 160.77,69 160.45,69.32 158.17,69.32 158,69.15 146.77,69.15 146.11,68.49 145.35,68.49 144.23,67.37 143.34,67.37 141.27,69.44 140.94,69.44 139.05,71.34 136.28,71.34 131.66,75.96 131.66,77.25 130.79,78.12 127.09,78.12 125.82,79.39 120.38,79.39 119.39,80.38 117.18,80.38 116.09,81.47 116.09,85.53 115.47,86.15 110.87,86.15 109.43,87.59 108.11,87.59 107.91,87.39 107.91,87.01 108.52,86.4 v1(108.52,86.32)
  BOTTOM w0.076: U1.G3 106.34,85.61 106.4,85.66 106.4,85.72 106.53,85.85 106.64,85.89 106.95,85.89 107.04,85.98 107.25,86.06 108.23,86.06 108.34,86.17 108.37,86.17 v1(108.52,86.32)
  BOTTOM w0.102: J32.42 206.55,60.26 206.17,60.64 206.17,61.53 207.69,63.06 207.69,66.46 207.86,66.62 207.86,73.93 v1(206.87,74.92)
CL_DATA_WLAN: length 137.2
  IN3 w0.081: v1(206.82,74.28) 206.61,74.28 205.67,73.34 203.11,73.34 202.19,72.43 201.18,72.43 200.5,71.75 200,71.75 199.53,71.28 194.42,71.28 191.65,74.05 181.1,74.05 179.94,72.89 175.63,72.89 171.56,68.82 160.61,68.82 160.37,69.06 158.34,69.06 158.2,68.92 146.8,68.92 146.19,68.31 145.42,68.31 144.31,67.2 143.21,67.2 141.31,69.1 140.93,69.1 139.79,70.24 137.78,70.24 136.92,69.38 135.77,69.38 135.52,69.63 135.52,71.59 131.28,75.83 131.28,77.1 130.64,77.74 126.92,77.74 125.61,79.05 120.19,79.05 119.24,80 116.8,80 115.6,81.19 115.6,85.38 115.16,85.83 114.44,85.83 v1(114.08,85.47)
  BOTTOM w0.076: U1.G2 106.94,85.61 107.19,85.86 107.21,85.87 107.91,85.87
  BOTTOM w0.102: v1(206.82,74.28) 207.1,74 207.1,72.2 207.65,71.64 207.65,66.97 207.4,66.71 207.4,63.69 205.7,61.99 205.7,60.66 206.05,60.31 J32.40 ; v1(114.08,85.47) 113.9,85.65 113.84,85.65 113.24,86.25 v4(113.17,86.25) 113.01,86.25 111.13,88.12 110.61,88.12 110.1,87.61 109.96,87.47 109.96,87.15 108.67,85.87 107.91,85.87
CLKREQ_SLECTE: length 15
  TOP w0.102: Q5.2 221.03,52.85 220.75,52.57 220.75,51.42 220.85,51.31 220.85,50.97 220.01,50.13 R409.1 220.34,49.75 Q36.1 v3(219.57,48.7) 219.01,48.15 219.01,47.15 217.97,46.12 216.11,46.12 214.84,47.38 214.84,48.73 215.23,49.11 U27.4
COEX1: length 40.3
  TOP w0.102: v1(238.95,65.87) 239.3,65.52 239.3,62.6 239.48,62.42 R425.2
  IN4 w0.076: v1(208.95,60.87) 209.41,60.41 212.52,60.41 213.13,61.02 214.39,61.02 214.97,60.44 221.29,60.44 223.78,62.93 223.78,64.17 224.29,64.68 226.91,64.68 227.67,65.44 232.34,65.44 232.62,65.73 235.33,65.73 235.61,65.44 238.52,65.44 v1(238.95,65.87)
  BOTTOM w0.102: J32.48 208.05,60.12 208.26,60.34 208.64,60.34 208.95,60.64 v1(208.95,60.87)
COEX2: length 41.8
  TOP w0.102: R424.2 238.85,63.16 v4(237.8,64.2) 238.36,64.76 238.36,65.8 v1(238.29,65.87)
  IN4 w0.076: v1(208.59,61.36) 209.02,61.36 209.81,60.57 212.45,60.57 213.05,61.18 214.47,61.18 215.02,60.63 221.22,60.63 222.27,61.69 222.27,64.11 223.05,64.88 226.88,64.88 227.59,65.59 232.11,65.59 232.42,65.9 235.38,65.9 235.69,65.59 238.01,65.59 v1(238.29,65.87)
  BOTTOM w0.102: v1(208.59,61.36) 208.27,61.36 207.87,60.96 207.87,60.53 207.55,60.21 J32.46
COEX3: length 39.3
  TOP w0.102: v1(237.91,64.96) 237.45,64.5 v4(237.45,62.88) 237.45,62.72 R423.2
  IN4 w0.076: v1(237.91,64.96) 237.76,64.81 232.46,64.81 231.98,65.29 227.82,65.29 227.01,64.48 224.85,64.48 224.62,64.25 224.62,63.55 221.34,60.27 214.91,60.27 214.31,60.87 213.19,60.87 212.53,60.21 207.98,60.21 207.43,60.77 v1(207.25,60.77)
  BOTTOM w0.102: J32.44 207.15,59.29 207.15,60.67 v1(207.25,60.77)
CPU_PWRGD: length 6.2
  BOTTOM w0.127: U1.A68 68.48,89.56 67.37,90.67 67.37,91.73 66.4,92.7 TP41.1
CPUCORE_ON: length 236.4
  TOP w0.102: QC2.2 76.33,94.83 77.43,94.83 v4(77.48,94.88) 77.83,94.88 v1(78.29,94.42) ; D60.2 246.85,83.95 246.85,87.18 243.37,90.66 v1(242.96,90.66) ; D60.2 246.98,82.97 R382.1 ; D60.2 248.55,83.39 D59.2
  IN1 w0.076: v1(80.12,107.23) 79.14,106.25 79.14,96.72 78.29,95.87 v1(78.29,94.42)
  IN3 w0.081: v1(242.96,90.66) 241.92,91.7 226.05,91.7 225.41,92.34 217.81,92.34 215.81,90.33 209.33,90.33 208.03,91.63 187.39,91.63 184.67,94.35 180.88,94.35 178.65,92.11 178.65,89.7 175.96,87.01 158.76,87.01 154.76,91 154.76,93.67 150.63,97.8 150.63,100.57 148.24,102.96 136.48,102.96 136.02,102.51 v1(135.94,102.51) 135.28,103.17 135.28,104.94 135.15,105.08 126.16,105.08 124.82,103.75 118.55,103.75 117.37,102.56 115.46,102.56 114.5,103.52 114.5,105.03 114.18,105.35 110.22,105.35 108.66,106.91 108.66,109.47 106.08,112.05 98.99,112.05 98.73,111.79 93.09,111.79 92.44,112.44 82.08,112.44 80.12,110.48 v1(80.12,107.23)
  BOTTOM w0.127: PR406.1 129.33,93.66 129.58,93.41 131.62,93.41 132.18,93.97 132.18,97.86 133.76,99.43 134.95,99.43 135.36,99.84 135.36,101.92 v1(135.94,102.51)
CPUCORE_ON_ASIC: length 11.4
  TOP w0.102: v1(250.13,76.29) 250.5,75.93 U21.E6 ; v1(248.77,85.39) 248.57,85.19 D59.1
  BOTTOM w0.102: v1(250.13,76.29) 249.74,76.68 249.74,77.38 249.8,77.44 249.8,80.95 249.03,81.72 249.03,83.3 248.7,83.63 248.7,85.32 v1(248.77,85.39)
CPUCORE_PWRGD: length 73.8
  IN1 w0.076: v1(96.39,57.57) 96.45,57.63 96.45,59.63 94.22,61.86 94.22,66.56 96.45,68.8 96.45,72.02 96.37,72.11 96.37,73.36 96.93,73.92 96.93,74.54 97.79,75.4 98.73,75.4 99.52,76.19 99.52,76.83 99.93,77.24 99.93,79.79 100.24,80.1 100.74,80.1 101.68,79.16 103.3,79.16 103.46,79.32 104.47,79.32 105.29,80.14 105.29,84.98 106.08,85.76 106.08,88.25 108.44,90.61 v1(108.72,90.61)
  IN3 w0.081: v1(108.72,90.61) 109.71,90.61 110.4,89.93 110.4,89.06 112.78,86.68 116.64,86.68 117.86,87.9 120.83,87.9 122.12,89.2 122.84,89.2 124.44,90.8 127.74,90.8 v1(128.3,91.36)
  BOTTOM w0.102: v1(96.39,57.57) 96.39,57.75 97.07,58.43 97.85,58.43 98.13,58.71 v4(98.13,59.04) 98.13,60.58 RC66.1 ; PR477.2 128.3,91.51 v1(128.3,91.36)
CPUCORE_PWRGD_R: length 4.5
  BOTTOM w0.127: PR405.2 128.73,92.79 128.7,92.77 PR477.1
  BOTTOM w0.203: PR405.2 128.39,93.08 128.32,93.15 127.64,93.15 v4(126.73,94.07) 126.45,94.35 126.22,94.35 125.98,94.59 PU401.38
CSN1: length 57.1
  TOP w0.254: PR423.1 117.99,98.11 116.88,99.22 116.44,99.22 115.81,99.86 v4(115.81,100.83) 115.81,102.17 116.16,102.53 v1(116.16,103.21)
  IN1 w0.254: v1(116.16,103.21) 116.16,105.04 114.94,106.26 114.94,108.04 113.98,109 112.71,109 111.69,107.99 101.12,107.99 97.72,111.39 73.34,111.39 v1(73.16,111.21)
  BOTTOM w0.254: PR466.2 72.78,110.83 v1(73.16,111.21)
CSN_1A: length 61.4
  IN3 w0.203: v1(80.55,101.84) 80.56,101.83 80.56,100.16 81.75,98.96 87.02,98.96 88.71,100.65 91.96,100.65 92.47,101.15 95.16,101.15 95.59,101.59 103.49,101.59 104.91,100.16 116.11,100.16 117.31,98.97 118.91,98.97 119.74,98.13 120.81,98.13 121.8,99.12 126.55,99.12 126.95,98.72 129.47,98.72 129.69,98.95 v1(129.69,99)
  BOTTOM w0.102: v4(79.32,100.4) 79.93,101.01 PRT401.2
  BOTTOM w0.203: v1(129.69,99) 130.08,98.61 PC433.2 129.22,98.54 PC405.2 128.87,98.56 128.73,98.7 127.62,98.7 127.38,98.94 PU401.28
  BOTTOM w0.254: PRT401.2 80.55,101.24 v1(80.55,101.84) 80.55,102.41 PR464.2
CSN_1B: length 10.2
  BOTTOM w0.203: PC430.2 125.13,92.87 125.32,93.06 125.32,93.45 124.78,93.99 PU401.41
  BOTTOM w0.254: PC430.2 125.41,92.26 PC434.1 125.32,91.81 123.71,90.2 v4(123.71,90.11) 123.22,89.62 123.22,87.79 123,87.57 PR468.2 123.29,87.35 123.67,86.97 PRT405.2
CSP1: length 59.8
  TOP w0.254: v1(116.8,103.21) 116.67,103.09 116.67,102.42 v4(116.67,102.42) 116.24,101.99 116.24,100.25 116.73,99.76 117.18,99.76 v1(117.46,99.48) 117.46,99.33 118.06,98.73 PR421.2
  IN1 w0.254: v1(116.8,103.21) 116.8,104.91 115.35,106.36 115.35,108.27 114.26,109.36 112.46,109.36 111.44,108.34 101.23,108.34 97.85,111.72 72.32,111.72 v1(71.82,111.21)
  BOTTOM w0.203: PR427.2 117.08,99.1 v1(117.46,99.48)
  BOTTOM w0.254: PR465.2 72.2,110.83 v1(71.82,111.21)
CTL0: length 8.5
  TOP w0.076: v1(28.91,52.95) 28.73,52.76 28.73,52.03 U5.B2
  TOP w0.102: R572.2 34.72,53.46 v1(34.01,53.46) R574.2
  BOTTOM w0.102: v1(28.91,52.95) 29.3,53.33 33.89,53.33 v1(34.01,53.46)
CTL1: length 6.4
  TOP w0.076: 26.42,45.76 26.42,46.3 26.48,46.36 U5.G11
  TOP w0.102: R573.2 25.48,42.71 v4(25.81,43.04) 26.57,43.04 26.87,43.35 26.87,45.31 26.42,45.76
CV20:
  vias: v3(139.73,113.17)
DAV12: length 7
  TOP w0.203: 280.86,89.78 280.86,89.45 281.05,89.26 U15.14 ; U15.10 282.65,89.27 282.85,89.47 283.55,89.47
  TOP w0.305: C140.2 281.31,90.23 280.86,89.78
  TOP w0.508: v1(280.15,90) 280.15,90.16 C141.2 281.11,90.54 C140.2 ; 283.55,89.47 283.7,89.47 284.13,89.9 C142.2 284.48,90.42 284.69,90.64 v1(284.69,90.72)
  vias: v3(284.59,89.45)
DCIN_PWR:
  vias: v1(121.75,112.58) v1(122.13,112.03) v1(122.36,112.58) v1(122.77,112.03) v1(123,112.58) v1(123.4,112.03) v1(123.63,112.58) v1(124.27,112.58) v1(155.02,100.22) v1(155.14,100.96) v1(155.6,100.52) v1(157.1,101.41) v1(157.76,101.39) v1(157.76,100.75) v1(158.37,100.8) v1(158.42,100.14) v2(101.61,110.27) v2(101.61,109.51) v2(102.37,110.27) v2(102.37,109.51) v2(103.13,110.27) v2(103.13,109.51) v2(103.9,110.27) v2(103.9,109.51) v2(104.66,110.27) v2(104.66,109.51) v3(101.5,108.68) v3(104.24,108.65) v3(128.74,111.82)
DCIN_PWR20_F: length 166.9
  TOP w0.203: PQ8.3 131.75,108.67 131.75,109.35 132.47,110.07 PC9.2
  TOP w0.254: PR14.2 136.32,107.26 136.27,107.31 v1(136.15,107.31) ; v1(109.38,110.96) 108.6,110.17 106.97,110.17 105.61,108.81 PR18.1
  TOP w0.305: 134.65,110.35 PR8.2 133.98,110.01 PC10.2
  TOP w0.381: PR152.2 205.53,78.56 204.99,79.11 203.92,79.11 v1(203.74,79.29)
  TOP w0.508: v1(193.12,69.94) 193.07,69.89 192.36,69.89 191.03,68.57 PD102.2 ; v1(145.5,113.07) 146,113.07 PF6.1 ; v1(152.18,105.35) 152.33,105.35 153.55,104.13 153.55,89.26 155.3,87.52 155.3,87.09 156.29,86.1 163.6,86.1 165.2,87.7 167.41,87.7 v3(168.02,87.08) 170.39,87.08 171.15,86.32 176.39,86.32 177.02,85.69 v1(177.2,85.69)
  IN1 w0.508: v1(132.93,110.81) 127.9,110.81 125.69,108.6 123.76,108.6 120.74,111.62 110.04,111.62 v1(109.38,110.96)
  IN3 w0.508: 136.15,107.31 v1(136.15,107.31) ; 136.15,107.31 136.35,107.51 142.5,107.51 143.07,106.93 150.59,106.93 v1(152.18,105.35) ; 136.15,107.31 135.56,107.9 135.56,110.2 134.96,110.81 v1(132.93,110.81) ; v2(135.67,113.14) 135.92,112.89 139.02,112.89 139.7,112.21 144.64,112.21 v1(145.5,113.07)
  IN4 w0.508: v1(177.2,85.69) 177.2,85.23 179.1,83.32 179.1,79.16 179.97,78.29 179.97,75.17 181.14,74 191.67,74 194.06,71.62 194.06,70.3 193.7,69.94 v1(193.12,69.94)
  BOTTOM w0.508: v1(193.12,69.94) 193.74,69.94 194.73,70.93 198.9,70.93 203.26,75.3 203.26,78.8 v1(203.74,79.29)
DDI_PRIORITY1: length 77.2
  TOP w0.102: v1(47.05,73.39) v4(47.05,73.93) 47.05,74.66 R2500.1 46.64,74.51 46.64,73.29 46.55,73.2 U147.5
  IN1 w0.076: v1(47.05,73.39) 47.13,73.47 50.05,73.47 56.93,80.35 60.24,80.35 65.34,85.46 65.95,85.46 68.49,88 77.25,88 78.09,87.16 79.64,87.16 80.02,86.78 80.02,85.05 80.55,84.52 91.27,84.52 93.98,87.22 99.72,87.22 100.36,87.87 100.58,88.09 101.66,89.17 103.41,89.17 v1(104.91,90.66)
  BOTTOM w0.102: U1.D8 103.98,87.5 104.12,87.64 104.12,89.1 104.5,89.48 104.5,90.26 v1(104.91,90.66)
DDI_PRIORITY2: length 75.7
  TOP w0.102: v1(47.91,74.05) 48.22,74.05 R2526.1 48.07,74.54 R532.1 47.51,74.48 47.51,73.29 46.95,72.73 U147.4
  IN1 w0.076: v1(47.91,74.05) 48.09,73.88 49.95,73.88 56.8,80.73 60.26,80.73 65.29,85.76 65.9,85.76 68.34,88.2 77.41,88.2 78.12,87.49 79.71,87.49 80.24,86.96 80.24,85.19 80.73,84.7 91.2,84.7 93,86.5 93,87.57 93.47,88.04 99.87,88.04 101.33,89.5 103.13,89.5 v1(104.33,90.69)
  BOTTOM w0.076: U1.C8 103.51,88.41 103.51,89.27 103.69,89.45
  BOTTOM w0.102: v1(104.33,90.69) 104.2,90.56 104.2,89.95 103.69,89.45
DDIP1_0N: length 77.2
  IN4 w0.089: v1(75.88,86.62) 75.88,86.52 76.13,86.28 76.29,86.28 76.34,86.33 76.34,86.76 74.69,88.4 67.73,88.4 66.62,87.3 65.59,87.3 59.94,81.65 58.43,81.65 50.96,74.18 50.96,70.12 50.28,69.43 50.28,67.27 49.74,66.74 49.74,65.09 50.3,64.53 50.3,61.15 47.71,58.55 44.29,58.55 42.04,60.8 42.04,63.71 42.64,64.31 42.64,65.37 40.5,67.5 35.59,67.5 35.12,67.97 35.12,69.3 35.23,69.41 35.23,71.39 34.61,72.01 34.51,72.01 34.09,71.59 v1(34.09,71.57)
  BOTTOM w0.076: U1.E55 v1(75.88,86.62)
  BOTTOM w0.102: v1(34.09,71.57) 34.09,71.65 33.89,71.84 33.7,71.84 33.35,71.49 C8346.1
DDIP1_0N_TYPEC: length 3.2
  BOTTOM w0.102: C8346.2 32.1,71.73 31.95,71.73 31.85,71.63 31.85,71.33 30.89,70.37 U183.10
DDIP1_0P: length 77.3
  IN4 w0.089: v1(75.88,85.99) 75.98,86.09 76.37,86.09 76.53,86.25 76.53,86.83 74.77,88.59 67.65,88.59 66.54,87.49 65.52,87.49 59.86,81.84 58.35,81.84 50.77,74.26 50.77,70.2 50.09,69.51 50.09,67.35 49.55,66.82 49.55,65.01 50.11,64.45 50.11,61.23 47.63,58.74 44.37,58.74 42.23,60.88 42.23,63.63 42.83,64.23 42.83,65.45 40.58,67.7 35.67,67.7 35.31,68.05 35.31,69.22 35.42,69.33 35.42,71.47 34.69,72.2 v1(34.11,72.2)
  BOTTOM w0.076: U1.F55 v1(75.88,85.99)
  BOTTOM w0.102: C8342.1 33.58,72.05 33.96,72.05 v1(34.11,72.2)
DDIP1_0P_TYPEC: length 3.3
  BOTTOM w0.102: U183.9 30.5,70.77 30.69,70.58 30.8,70.58 v2(31.29,71.06) 31.64,71.41 31.64,71.72 31.87,71.94 32.1,71.94 C8342.2
DDIP1_1N: length 77.1
  IN4 w0.089: v1(34.74,70.14) 34.48,70.14 34.39,70.22 34.39,70.44 34.3,70.53 33.76,70.53 33.03,69.8 33.03,66.09 33.91,65.21 37.01,65.21 37.69,65.89 39.88,65.89 40.93,64.84 40.93,60.23 43.68,57.48 48.69,57.48 51.77,60.57 51.77,69.15 53.17,70.54 53.17,73.59 53.84,74.27 53.84,75.53 58.59,80.28 60.29,80.28 65.75,85.73 66.64,85.73 67.29,86.38 69.85,86.38 69.99,86.25 70.35,86.25 71.41,87.3 73.29,87.3 73.69,86.9 73.69,86.47 73.84,86.33 73.92,86.33 74.05,86.46 v1(74.05,86.62)
  BOTTOM w0.076: U1.E58 v1(74.05,86.62)
  BOTTOM w0.102: C8353.1 33.72,69.97 33.91,69.97 34.31,70.37 34.51,70.37 v1(34.74,70.14)
DDIP1_1N_TYPEC: length 2.8
  BOTTOM w0.102: C8353.2 32.08,69.95 31.94,69.95 v2(31.41,69.42) 31.25,69.26 30.63,69.26 30.53,69.17 U183.13
DDIP1_1P: length 77.2
  IN4 w0.089: v1(74.05,85.99) 73.91,86.14 73.76,86.14 73.5,86.39 73.5,86.82 73.21,87.11 71.48,87.11 70.43,86.05 69.91,86.05 69.77,86.19 67.37,86.19 66.71,85.54 65.83,85.54 60.37,80.09 58.67,80.09 54.04,75.45 54.04,74.19 53.36,73.51 53.36,70.46 51.97,69.07 51.97,60.49 48.77,57.29 43.6,57.29 40.74,60.15 40.74,64.76 39.8,65.7 37.77,65.7 37.09,65.02 33.83,65.02 32.84,66.01 32.84,69.88 33.68,70.72 v1(34.74,70.72)
  BOTTOM w0.076: U1.F58 v1(74.05,85.99)
  BOTTOM w0.102: v1(34.74,70.72) 34.6,70.58 34.23,70.58 33.82,70.18 33.63,70.18 C8352.1
DDIP1_1P_TYPEC: length 2.8
  BOTTOM w0.102: U183.12 30.55,69.57 30.65,69.47 31.16,69.47 31.85,70.16 32.13,70.16 C8352.2
DDIP1_2N: length 76.4
  IN4 w0.089: v1(36,68.14) 36.27,68.14 36.35,68.22 36.35,68.44 36.41,68.51 40.41,68.51 43.27,65.65 43.27,63.98 42.64,63.34 42.64,61.27 44.62,59.29 47.44,59.29 49.7,61.56 49.7,64.18 49.12,64.76 49.12,67.19 49.72,67.79 49.72,69.74 50.16,70.18 50.16,74.24 58.25,82.33 59.67,82.33 65.25,87.91 66.39,87.91 67.46,88.98 75.05,88.98 75.76,88.27 77.06,88.27 77.46,87.87 77.46,87.42 77.13,87.09 77.13,86.44 77.47,86.1 77.47,85.7 77.31,85.55 77.16,85.55 77.09,85.62 77.09,85.92 77.02,85.99 v1(76.79,85.99)
  BOTTOM w0.076: U1.F53 v1(76.79,85.99)
  BOTTOM w0.102: C8351.1 33.64,68.22 v2(34.67,68.22) 35.92,68.22 v1(36,68.14)
DDIP1_2N_TYPEC: length 2.5
  BOTTOM w0.102: U183.16 30.52,67.97 30.62,68.06 v2(31.29,68.06) 31.54,68.06 31.67,68.2 32.05,68.2 C8351.2
DDIP1_2P: length 76.4
  IN4 w0.089: v1(36,68.72) 36.02,68.7 40.49,68.7 43.46,65.73 43.46,63.9 42.83,63.26 42.83,61.35 44.7,59.48 47.36,59.48 49.51,61.64 49.51,64.1 48.93,64.68 48.93,67.27 49.53,67.87 49.53,69.81 49.97,70.26 49.97,74.32 58.17,82.52 59.6,82.52 65.17,88.1 66.31,88.1 67.38,89.17 75.13,89.17 75.84,88.46 77.14,88.46 77.65,87.95 77.65,87.34 77.32,87.01 77.32,86.52 77.66,86.18 77.66,85.63 77.39,85.35 v1(76.79,85.35)
  BOTTOM w0.076: U1.G53 v1(76.79,85.35)
  BOTTOM w0.102: v1(36,68.72) 35.73,68.44 33.61,68.44 C8350.1
DDIP1_2P_TYPEC: length 2.5
  BOTTOM w0.102: U183.15 30.54,68.37 30.63,68.27 31.45,68.27 31.59,68.4 32.08,68.4 C8350.2
DDIP1_3N: length 76.4
  IN4 w0.076: 73.84,87.8 73.86,87.78 73.86,87.76 74.57,87.05 74.57,85.85 74.71,85.72 74.83,85.72 74.97,85.85 v1(74.97,85.99)
  IN4 w0.089: 73.84,87.8 73.65,87.99 70.58,87.99 70.34,87.75 70.34,87.36 70.2,87.22 69.08,87.22 68.96,87.34 68.96,87.57 68.72,87.81 67.91,87.81 66.45,86.36 65.54,86.36 60.28,81.1 58.44,81.1 51.52,74.17 51.52,69.83 51.18,69.48 51.18,64.37 50.93,64.12 50.93,63.38 51.18,63.13 51.18,62.69 50.93,62.44 50.93,61.77 51.18,61.53 51.18,61.07 48.25,58.14 44,58.14 41.52,60.62 41.52,65.88 40.39,67.01 37.33,67.01 37.12,66.81 37.12,66.67 37.07,66.62 36.53,66.62 36.45,66.69 36.45,66.84 36.29,67.01 35.53,67.01 35.33,66.81 35.33,65.92 35.15,65.74 34.05,65.74 33.61,66.18 33.61,66.67 33.69,66.76 33.88,66.76 33.96,66.68 33.96,66.34 34.09,66.21 34.22,66.21 v1(34.38,66.37)
  BOTTOM w0.076: U1.F56 v1(74.97,85.99)
  BOTTOM w0.102: C8344.1 33.63,66.48 34.26,66.48 v1(34.38,66.37)
DDIP1_3N_TYPEC: length 2.6
  BOTTOM w0.102: U183.19 30.54,66.77 30.64,66.86 31.28,66.86 v2(31.46,66.68) 31.69,66.45 32.08,66.45 C8344.2
DDIP1_3P: length 76.4
  IN4 w0.076: v1(74.97,85.35) 74.77,85.55 74.64,85.55 74.41,85.78 74.41,86.98 73.74,87.65 73.72,87.65 73.71,87.66
  IN4 w0.089: 73.71,87.66 73.58,87.79 70.66,87.79 70.53,87.67 70.53,87.29 70.28,87.03 69,87.03 68.77,87.26 68.77,87.49 68.65,87.62 67.98,87.62 66.53,86.17 65.62,86.17 60.36,80.91 58.52,80.91 51.71,74.09 51.71,69.75 51.37,69.4 51.37,64.29 51.12,64.04 51.12,63.46 51.37,63.21 51.37,62.61 51.12,62.36 51.12,61.85 51.37,61.6 51.37,60.99 48.33,57.95 43.92,57.95 41.33,60.55 41.33,65.8 40.31,66.82 37.41,66.82 37.31,66.73 37.31,66.59 37.15,66.43 36.45,66.43 36.26,66.61 36.26,66.76 36.21,66.82 35.61,66.82 35.52,66.73 35.52,65.84 35.23,65.55 33.97,65.55 33.42,66.11 33.42,66.75 33.62,66.95 v1(34.38,66.95)
  BOTTOM w0.076: U1.G56 v1(74.97,85.35)
  BOTTOM w0.102: C8343.1 33.61,66.69 34.12,66.69 v1(34.38,66.95)
DDIP1_3P_TYPEC: length 2.6
  BOTTOM w0.102: U183.18 30.52,67.17 30.61,67.07 31.36,67.07 31.77,66.67 32.04,66.67 C8343.2
DDIP1_AUXN: length 66.9
  IN1 w0.089: v1(27.21,61.81) 27.23,61.79 27.23,61.29 27.51,61.02 31.49,61.02 32.15,61.68 39.61,61.68 41.36,63.42 41.36,65.04 43.7,67.37 46.21,67.37 49.84,71 49.84,72.25 57.29,79.69 60.54,79.69 65.21,84.37 67.62,84.37 69.05,85.79 70.16,85.79 71.41,87.03 76.32,87.03 77.87,85.48 78.5,85.48 v1(78.62,85.36)
  BOTTOM w0.076: U1.G50 79.08,85.1 78.62,85.36 78.62,85.36 v1(78.62,85.36)
  BOTTOM w0.102: C8355.1 27.46,62.58 27.46,62.06 v1(27.21,61.81)
DDIP1_AUXN_TYPEC: length 3.3
  TOP w0.102: R9084.2 27.54,64.11 27.54,64.22 v1(27.38,64.38)
  BOTTOM w0.102: U183.25 27.95,65.26 27.99,65.22 27.99,65.07 27.92,65 27.83,65 27.59,64.76 27.59,64.59 v1(27.38,64.38) 27.56,64.2 27.56,64.12 C8355.2
DDIP1_AUXP: length 66.9
  IN1 w0.089: v1(27.8,61.81) 27.42,61.44 27.42,61.37 27.59,61.21 31.41,61.21 32.07,61.87 39.53,61.87 41.17,63.5 41.17,65.11 43.62,67.56 46.13,67.56 49.65,71.08 49.65,72.33 57.21,79.88 60.46,79.88 65.13,84.56 67.55,84.56 68.97,85.98 70.09,85.98 71.33,87.22 76.4,87.22 77.95,85.67 78.29,85.67 v1(78.62,86)
  BOTTOM w0.076: U1.F50 79.08,85.77 78.62,86 v1(78.62,86)
  BOTTOM w0.102: C8354.1 27.67,62.44 27.67,61.94 v1(27.8,61.81)
DDIP1_AUXP_TYPEC: length 3.2
  TOP w0.102: v1(27.97,64.38) 27.76,64.18 27.76,63.97 R9085.2
  BOTTOM w0.102: U183.24 28.35,65.25 28.2,65.1 28.2,64.98 28.01,64.79 27.92,64.79 27.8,64.67 27.8,64.55 v1(27.97,64.38) 27.79,64.2 27.79,64.03 C8354.2
DDIP1_CTRLCLK: length 55.1
  TOP w0.102: TP80.1 57.95,76.09 v1(57.95,76.77)
  IN1 w0.089: v1(100.43,82.69) 100.61,82.51 100.61,82.38 100.48,82.26 100.29,82.26 100.03,82.52 99.7,82.52 99.15,83.07 98.03,83.07 97.9,82.94 95.9,82.94 93.06,80.1 93.06,77.82 91.75,76.5 90.79,76.5 90.52,76.24 89.26,76.24 89.03,76 89.03,75.99 88.91,75.88 88.91,74.37 88.53,73.99 77.21,73.99 77.05,73.82 73.23,73.82 72.23,74.82 72.23,75.45 71.92,75.77 67.58,75.77 65.49,77.85 62.67,77.85 61.86,78.66 59.71,78.66 57.95,76.9 v1(57.95,76.77)
  BOTTOM w0.102: U1.L13 v1(100.43,82.69)
DDIP1_CTRLDATA: length 59.9
  TOP w0.102: RC117.1 55.76,73.34 55.76,73.9 55.97,74.1 56.78,74.1 57.05,73.84 v3(57.93,73.84) 58.56,74.46 58.56,76.26 v1(58.96,76.67)
  IN1 w0.089: v1(101.06,82.69) 100.8,82.43 100.8,82.31 100.56,82.07 100.22,82.07 99.95,82.34 99.61,82.34 99.07,82.88 98.11,82.88 97.98,82.75 95.98,82.75 93.25,80.02 93.25,77.74 91.83,76.31 90.87,76.31 90.59,76.03 89.34,76.03 89.17,75.86 89.16,75.86 89.1,75.8 89.1,74.29 88.61,73.8 77.29,73.8 77.13,73.63 73.15,73.63 72.04,74.74 72.04,75.37 71.84,75.58 67.5,75.58 65.41,77.66 62.59,77.66 61.78,78.47 60,78.47 58.96,77.43 v1(58.96,76.67)
  BOTTOM w0.102: U1.L12 v1(101.06,82.69)
DDIP1_HPD: length 124.8
  TOP w0.102: R725.1 28.85,41.66 28.7,41.81 28.7,42.51 v1(28.42,42.79) ; v1(102.97,82.69) 103.47,83.2 RC162.1
  IN1 w0.076: v1(22.33,67.09) 23.3,68.06 24.11,68.06 27.03,70.98 34.34,70.98 36.07,72.71 v1(37.52,72.71) ; v1(102.97,82.69) 102.27,82.69 101.39,81.81 100.1,81.81 99.93,81.98 96.69,81.98 94.6,79.9 94.14,79.9 93.48,79.24 93.48,77.61 92.72,76.85 92.72,75.58 92.49,75.35 90.94,75.35 89.25,73.66 89.18,73.58 77.8,73.58 77.55,73.34 73.06,73.34 71.79,74.61 71.66,74.74 67.78,74.74 66.56,75.96 66.11,75.96 64.91,77.15 61.87,77.15 v1(61.16,77.86)
  IN4 w0.076: v1(22.33,67.09) 24.39,65.04 24.39,64.46 26.39,62.45 26.39,62.14 26.19,61.93 26.19,53.31 24.77,51.88 24.77,47.87 27,45.64 27,44.98 27.99,43.98 27.99,43.22 v1(28.42,42.79)
  BOTTOM w0.102: v1(61.16,77.86) 60.61,78.41 45.42,78.41 39.73,72.71 v1(37.52,72.71) ; v1(22.33,67.09) 22.38,67.14 R9095.2 ; U1.L9 v1(102.97,82.69)
DDIP2_0N: length 45.9
  TOP w0.102: v1(80.04,90.77) 79.85,90.59 79.48,90.59 77.36,88.46 77.01,88.46 75.82,87.27 69.31,87.27 68.27,86.23 66.96,86.23 66.39,85.66 65.81,85.66 62.3,82.16 51.89,82.16 47.52,77.79 47.19,77.79 v2(46.56,77.16) 45.99,76.59 45.09,76.59 44.3,75.8 44.3,75.46 C2523.1
  BOTTOM w0.076: v1(80.04,90.77) 79.81,90.54 79.66,90.54 79.31,90.19 79.31,89.03 79.27,88.92 79.27,88.67 79.31,88.58 79.31,88.39 79.23,88.12 U1.C50
DDIP2_0N_C: length 2.6
  TOP w0.102: U147.12 43.75,73.21 44.26,73.72 44.26,74.57 C2523.2
DDIP2_0P: length 46
  TOP w0.102: v1(80.04,90.19) 79.85,90.38 79.57,90.38 77.44,88.25 77.1,88.25 75.91,87.06 69.4,87.06 68.36,86.03 67.05,86.03 66.48,85.46 65.89,85.46 62.39,81.95 51.97,81.95 v2(49.22,79.2) 47.61,77.58 47.28,77.58 46.08,76.38 45.18,76.38 44.51,75.71 44.51,75.54 C2522.1
  BOTTOM w0.076: v1(80.04,90.19) 79.85,90.38 79.73,90.38 79.48,90.12 79.48,89 79.44,88.89 79.44,88.7 79.47,88.61 79.47,88.36 79.42,88.2 79.37,87.86 U1.D50
DDIP2_0P_C: length 2.6
  TOP w0.102: C2522.2 44.76,74.69 44.51,74.43 v2(44.51,73.82) 44.51,73.6 44.15,73.23 U147.11
DDIP2_1N: length 44.6
  TOP w0.102: C2525.1 43.11,75.54 43.11,76.01 v2(43.67,76.57) 44.36,77.26 45.74,77.26 46.94,78.45 47.29,78.45 51.76,82.92 61.99,82.92 65.45,86.38 66.26,86.38 68.23,88.35 76.05,88.35 76.54,88.84 76.54,89.94 76.81,90.21 76.94,90.21 v1(77.17,90.45)
  BOTTOM w0.076: v1(77.17,90.45) 77.44,90.19 77.52,90.19 77.76,89.95 77.76,89.45 77.65,89.33 77.65,89.02 77.71,88.9 77.71,88.75 77.65,88.56 77.65,88.39 77.73,88.13 U1.C52
DDIP2_1N_C: length 2.5
  TOP w0.102: U147.15 42.55,73.16 42.99,73.6 v2(42.99,73.85) 42.99,74.57 C2525.2
DDIP2_1P: length 44.5
  TOP w0.102: C2524.1 43.32,75.46 43.32,75.92 44.45,77.05 45.83,77.05 47.03,78.24 47.38,78.24 v2(47.73,78.6) 51.85,82.71 62.08,82.71 65.54,86.17 66.35,86.17 68.31,88.14 76.14,88.14 76.75,88.75 76.75,89.86 76.9,90 77.04,90 v1(77.17,89.87)
  BOTTOM w0.076: v1(77.17,89.87) 77.33,90.03 77.45,90.03 77.59,89.88 77.59,89.51 77.48,89.4 77.48,88.95 77.51,88.92 77.54,88.86 77.54,88.78 77.48,88.58 77.48,88.36 77.62,87.88 77.62,87.77 77.7,87.5 U1.D52
DDIP2_1P_C: length 2.5
  TOP w0.102: U147.14 42.95,73.18 43.24,73.47 43.24,74.45 C2524.2
DDIP2_2N: length 47.4
  TOP w0.102: C2527.1 41.84,75.54 41.84,75.95 v2(42.11,76.22) 43.81,77.92 45.45,77.92 46.7,79.16 47.12,79.16 51.66,83.71 61.5,83.71 65.5,87.7 66.6,87.7 68.08,89.18 74.94,89.18 75.86,90.1 75.86,90.83 76.2,91.18 76.7,91.18 76.8,91.08 77.69,91.08 78.14,91.53 78.75,91.53 78.95,91.33 78.95,91.07 v1(79.15,90.87)
  BOTTOM w0.076: U1.A50 78.91,89.25 78.91,90.63 v1(79.15,90.87)
DDIP2_2N_C: length 2.4
  TOP w0.102: C2527.2 41.75,74.54 v2(41.75,73.69) U147.17
DDIP2_2P: length 47.3
  TOP w0.102: C2526.1 42.05,75.46 42.05,75.86 43.9,77.71 v2(44.86,77.71) 45.54,77.71 46.79,78.96 47.2,78.96 51.74,83.5 61.59,83.5 65.58,87.49 66.68,87.49 68.16,88.97 75.02,88.97 76.06,90.01 76.06,90.75 76.29,90.97 76.62,90.97 76.72,90.87 77.77,90.87 78.23,91.32 78.66,91.32 78.74,91.24 78.74,91.05 v1(78.57,90.87)
  BOTTOM w0.076: v1(78.57,90.87) 78.75,90.68 78.75,89.07 U1.B50
DDIP2_2P_C: length 2.5
  TOP w0.102: U147.16 42.15,72.78 41.97,72.96 41.97,74.45 C2526.2
DDIP2_3N: length 52.3
  TOP w0.102: v1(77.18,92.16) 77.4,91.95 77.4,91.83 77.28,91.71 77.04,91.71 76.95,91.81 76.03,91.81 75.54,92.3 72.13,92.3 70.92,91.09 69.02,91.09 66.49,88.57 65.3,88.57 61.15,84.42 51.43,84.42 46.84,79.82 46.42,79.82 45.18,78.58 43.51,78.58 42.04,77.11 39.75,77.11 v2(38.99,76.35) 38.71,76.07 38.71,75.46 C2529.1
  BOTTOM w0.076: U1.D51 78.19,88.03 78.19,88.3 78.41,88.52 78.41,88.72 78.33,88.79 78.33,90.09 77.49,90.93 77.49,91.85 v1(77.18,92.16)
DDIP2_3N_C: length 3.4
  TOP w0.102: U147.20 40.55,72.99 39.81,73.72 39.3,73.72 38.8,74.23 38.8,74.45 C2529.2
DDIP2_3P: length 52.4
  TOP w0.102: C2528.1 38.92,75.54 38.92,75.98 39.84,76.9 42.12,76.9 43.6,78.37 45.26,78.37 v2(45.9,79.01) 46.51,79.62 46.93,79.62 51.52,84.21 61.23,84.21 65.39,88.36 66.58,88.36 69.1,90.88 71.01,90.88 72.22,92.09 75.46,92.09 75.95,91.6 76.86,91.6 76.96,91.5 77.37,91.5 77.61,91.74 77.61,92 v1(77.77,92.16)
  BOTTOM w0.076: U1.C51 78.48,87.87 78.55,87.79 78.66,87.79 78.74,87.88 78.74,88.31 78.57,88.48 78.57,88.79 78.5,88.86 78.5,90.16 77.66,90.99 77.66,92.06 v1(77.77,92.16)
DDIP2_3P_C: length 3.4
  TOP w0.102: U147.19 40.95,72.97 v2(40.4,73.51) 39.94,73.98 39.43,73.98 39.05,74.36 39.05,74.57 C2528.2
DDIP2_AUXN: length 39
  TOP w0.102: C2531.1 51.76,70.72 53.11,70.72 53.76,71.37 v2(53.76,73.72) 53.76,74.17 v1(53.15,74.77)
  IN1 w0.089: v1(53.15,74.77) 53.37,74.55 53.65,74.55 58.35,79.25 60.71,79.25 65.44,83.97 68.1,83.97 68.41,84.28 71,84.28 71.36,84.63 78.62,84.63 78.99,85 78.99,86.23 79.17,86.4 79.31,86.4 v1(79.54,86.63)
  BOTTOM w0.076: v1(79.54,86.63) 79.55,86.63 79.55,86.62 79.54,86.62 U1.E48
DDIP2_AUXN_C: length 2.9
  TOP w0.102: R9129.2 C2531.2 50.82,70.62 49.41,70.62 49.3,70.51 U147.63
DDIP2_AUXP: length 38.9
  TOP w0.102: v1(52.74,74.36) 53.27,74.36 53.55,74.08 v2(53.55,72.35) 53.55,71.46 53.02,70.93 51.69,70.93 C2530.1
  IN1 w0.089: v1(79.55,85.99) 79.33,86.21 79.24,86.21 79.18,86.15 79.18,84.93 78.7,84.44 71.43,84.44 71.08,84.09 68.49,84.09 68.18,83.78 65.52,83.78 60.79,79.06 58.43,79.06 53.73,74.36 v1(52.74,74.36)
  BOTTOM w0.076: U1.F48 79.54,85.99 79.55,85.99 79.55,85.99 v1(79.55,85.99)
DDIP2_AUXP_C: length 2.4
  TOP w0.102: C2530.2 50.7,70.83 v2(49.97,70.83) 49.46,70.83 49.38,70.91 U147.64
DDIP2_CTRLCLK: length 65.4
  TOP w0.102: U147.66 49.16,71.71 50,72.55 50.56,72.55 50.66,72.45 R2378.1 51.33,72.83 51.85,72.83 v4(52.21,72.48) 52.74,71.94 v1(52.74,71.39)
  IN1 w0.076: v1(52.74,71.39) 52.74,71.67 56.98,75.9 64.48,75.9 65.64,74.74 66.81,74.74 68.64,72.91 77.73,72.91 77.95,73.13 93.02,73.13 93.68,73.8 93.68,74.64 94.7,75.65 94.7,76.59 96.8,78.69 96.8,79.46 98.28,80.94 99.65,80.94 100.13,81.42 103.27,81.42 v1(103.6,81.75)
  BOTTOM w0.102: v1(103.6,81.75) 103.6,81.85 U1.N7
DDIP2_CTRLDATA: length 64.9
  TOP w0.102: U147.65 49.19,71.31 v4(50.07,72.2) 50.57,72.2 R2379.1 51.3,71.46 52.03,71.46 v1(52.13,71.36)
  IN1 w0.076: v1(102.97,81.78) 101.77,81.78 101.63,81.65 100.12,81.65 99.62,81.14 96.6,81.14 95.81,80.36 95.39,80.36 94.69,79.65 94.15,79.65 93.7,79.2 93.7,77.43 93.05,76.78 93.05,75.17 92.8,74.92 92.8,73.9 92.24,73.35 77.86,73.35 77.64,73.13 72.97,73.13 72.32,73.77 68.21,73.77 66.91,75.07 65.69,75.07 64.61,76.16 56.92,76.16 v1(52.13,71.36)
  BOTTOM w0.102: U1.N8 102.97,81.86 v1(102.97,81.78)
DDIP2_HPD: length 88.6
  TOP w0.102: v1(56.19,74.56) 55.94,74.82 55.94,79.03 56.47,79.56 v3(56.47,80.81) 55.76,81.52 52.13,81.52 47.79,77.18 47.48,77.18 46.42,76.11 46.42,73.65 45.75,72.98 U147.7
  TOP w0.127: RC5.1 104.51,82.96 104.51,82.96 v1(104.24,82.69)
  IN1 w0.076: v1(56.19,74.56) 56.65,74.56 57.69,75.6 64.14,75.6 64.61,75.13 64.61,74.7 65.71,73.61 66.24,73.61 67.09,72.76 67.09,69.3 68.56,67.83 72.68,67.83 74.43,69.58 74.43,71.06 75.22,71.84 77.64,71.84 78.71,72.91 93.79,72.91 94.62,73.74 94.62,74.42 94.47,74.56 94.47,75.07 94.95,75.55 94.95,76.51 97,78.56 97,79.42 98.34,80.76 99.71,80.76 100.2,81.26 104.28,81.26 104.62,81.6 104.62,82.31 v1(104.24,82.69)
  BOTTOM w0.076: U1.L7 v1(104.24,82.69)
DDR4_VREF_CA: length 7.7
  TOP w0.305: 64.93,28.84 65.29,28.49 CD28.2 65.01,28.08 64.86,27.93 ; CD25.2 RD9.2 66.53,28.66 66.71,28.84 ; CD27.1 63.56,27.49 RD8.2 ; 66.79,29.22 RD7.2 66.79,29.98
  BOTTOM w0.254: v1(64.5,29.6) 64.03,29.12 J21.164
  vias: v4(64.47,29.02)
DDR4_VREF_CA_M3: length 71.5
  TOP w0.254: v1(60.13,30.29) 60.74,29.68 60.74,27.44 v4(60.77,27.41) 61.27,26.91 CD26.2 RD8.1
  IN4 w0.508: v1(60.13,30.29) 60.13,30.52 60.46,30.84 60.46,34.64 57.44,37.65 57.44,38.32 v1(42.48,53.28)
  BOTTOM w0.203: 65.11,65.26 65.31,65.46 67.88,65.46 68.47,66.05 69.2,66.05 69.46,66.31 69.46,67.58 69.25,67.8 U1.AY67
  BOTTOM w0.381: 65.11,65.26 64.37,64.52 64.37,63.21
  BOTTOM w0.508: 64.37,63.21 64.37,61.94 55.71,53.28 v1(42.48,53.28)
DDR_PG_CTRL: length 30.2
  TOP w0.254: RC9.2 59.16,54.51 v4(59.16,53.59) ; v4(59.16,53.59) 59.18,53.56 60.3,53.56 QC1.3 ; v4(59.16,53.59) 57.53,53.59 57.46,53.66 U36.2 55.49,53.79 55.7,53.79 56.26,54.35 56.26,55.82 v3(57.85,57.41) 59.11,58.67 62.51,58.67 63.23,59.39 63.23,60.48 63.97,61.21 63.97,65.49 65.41,66.94 66.56,66.94 v1(68.52,68.91)
  BOTTOM w0.254: v1(68.52,68.91) 68.99,68.44 U1.AW67
DDR_VREF: length 2.6
  TOP w0.305: PR307.1 128,65.65
  BOTTOM w0.254: v1(128.03,65.93) 127.92,65.93 126.85,64.85 PU301.6
DDR_VTT_PG_CTRL: length 74.8
  TOP w0.254: v1(110.68,62.04) 110.58,62.04 110.09,61.56 109.47,61.56 107.22,59.31 107.22,54.37 106.36,53.5 92.19,53.5 90.41,51.73 66.89,51.73 66.23,52.39 v4(65.54,52.39) 63.76,52.39 63.75,52.38 QC1.1 60.08,52.38 59.97,52.26 RC8.1 59.6,52.62 59.39,52.84 57.44,52.84 U36.4 56.88,52.63 RC169.1
  IN4 w0.254: v1(120,64.81) 119.95,64.76 119.95,63.97 117.26,61.28 111.34,61.28 110.68,61.94 v1(110.68,62.04)
  BOTTOM w0.254: v1(120,64.81) PR301.1
DH2_CHG: length 2.8
  IN1 w0.889: 194.15,81.33 196.14,79.35
  vias: v2(192.95,82.21) v2(192.95,81.57) v2(196.78,78.8) v2(197.29,78.29) v3(192.41,81.14)
DISCHARGE: length 214.6
  TOP w0.254: PQ9.2 128.77,108.32 127.64,107.18 v1(127.64,106.6) ; PQ41.2 138.95,108.43 139.51,108.98 v1(139.63,108.98) ; U21.E4 251.81,76.26 251.57,76.26 v1(251.44,76.14) ; U21.J6 250.55,79.67 v1(250.48,79.74) 248.93,81.29 R265.2 ; PQ104.2 v1(198.62,89.27)
  IN1 w0.254: v1(231.15,94.12) 231.26,94.23 244.54,94.23 246.52,92.25 246.54,92.25 246.86,91.93 v1(251.18,91.93)
  IN2 w0.254: v1(198.62,89.27) 198.62,92.58 207.1,101.06 214.45,101.06 214.99,101.59 227.61,101.59 230.95,98.26 230.95,96.23 231.15,96.02 v1(231.15,94.12)
  IN3 w0.254: v1(251.18,91.93) 252.71,90.4 252.71,82.56 251.98,81.83 251.09,81.83 250.48,81.22 v1(250.48,79.74) ; v1(127.64,106.6) 127.64,107.18 132.03,111.57 137.42,111.57 139.63,109.36 v1(139.63,108.98) 140.13,108.48 142.77,108.48 143.64,107.61 151.71,107.61 156.01,103.31 160.8,103.31 165.15,107.66 172.92,107.66 173.53,107.05 173.53,106.06 172.95,105.48 172.95,104.82 173.61,104.16 176.86,104.16 181.41,99.61 190.45,99.61 191.81,100.97 194.4,100.97 199.14,96.23 206.88,96.23 207.9,97.25 212.07,97.25 215.06,94.25 226.01,94.25 227.2,93.06 230.35,93.06 231.15,93.85 v1(231.15,94.12)
  IN4 w0.254: v1(250.48,79.74) 250.2,79.46 250.2,77.94 250.99,77.16 250.99,76.59 v1(251.44,76.14)
DL1_CHG: length 11.1
  TOP w0.203: 194.86,75.27 PU101.29
  IN1 w0.889: 185.07,81.25 189.97,76.34 191.62,76.34
  vias: v1(193.15,75.42) v1(193.76,75.42) v2(184.79,82.71) v2(184.79,82.08) v3(185.2,83.17)
DL2_CHG: length 11.6
  TOP w0.203: PU101.26 196.58,76.47
  IN1 w0.889: 188.11,86.28 188.11,84.18 194.21,78.08
  vias: v1(194.79,77.51) v1(195.3,77.19) v2(187.41,87.21) v2(187.54,87.85) v4(187.97,88.4)
DMIC_CLK: length 74.5
  TOP w0.102: v1(266.72,135.49) 267.62,136.38 269.15,136.38 269.33,136.21 C500.1 269.08,135.95 267.85,135.95 v1(267.34,135.44) ; R677.2 269.35,72.29 v1(269.57,72.51)
  IN4 w0.076: v1(269.57,72.51) 268.89,73.19 268.89,83.71 269.71,84.52 269.71,86.81 265.34,91.18 265.34,108.19 266.99,109.84 266.99,123.43 266.48,123.94 266.48,134.34 266.72,134.58 v1(266.72,135.49)
  BOTTOM w0.102: J11.4 267.25,135.54 v1(267.34,135.44)
DMIC_DATA: length 76.9
  TOP w0.102: v1(268.41,69.89) 268.92,69.38 268.92,67.3 269.78,66.43 270.77,66.43 270.95,66.25 UA1.54
  IN4 w0.076: v1(268.41,69.89) 269.1,70.57 269.1,71.14 269.98,72.02 269.98,72.84 269.1,73.72 269.1,83.53 269.91,84.34 269.91,86.99 265.62,91.29 265.62,108.04 267.27,109.69 267.27,123.48 266.73,124.01 266.73,134.15 267.31,134.73 267.31,134.8 v1(267.95,135.44)
  BOTTOM w0.127: v1(267.95,135.44) 267.65,135.75 J11.5
DN1_DP4: length 300.8
  TOP w0.102: U16.F13 227.24,77.56 225.92,77.56 v1(225.79,77.43) 225.71,77.36 C160.1
  IN3 w0.081: v1(100.96,112.81) 100.53,113.25 57.77,113.25 55.66,111.14 55.66,96.15 56.98,94.83 56.98,94.09 55.72,92.83 55.72,88.18 41.96,74.42 36.04,74.42 35.26,75.2 33.86,75.2 32.67,74.01 28.81,74.01 27.79,75.03 27.79,75.33 27.2,75.91 25.66,75.91 25.09,75.35 22.41,75.35 21.82,75.93 v1(16.93,75.93)
  IN4 w0.076: v1(96.83,100.39) 96.83,100.37 97.11,100.09 98.87,100.09 101.46,102.68 107.27,102.68 110.7,99.25 116.85,99.25 117.29,98.81 119.5,98.81 119.77,99.07 126.4,99.07 127.06,98.41 130.64,98.41 132.67,96.38 132.67,95.01 134.38,93.31 138.46,93.31 141.47,90.3 141.91,90.3 142.77,89.45 149.79,89.45 150.5,90.16 150.92,90.16 151.91,91.15 155.61,91.15 155.71,91.05 162.75,91.05 162.98,91.27 165.39,91.27 168.18,94.06 168.18,96.46 169.66,97.93 172.12,97.93 174.79,95.26 179.1,95.26 181.34,97.5 188.81,97.5 190.38,95.92 191.07,95.92 191.47,96.33 191.47,96.71 192.06,97.29 196.17,97.29 199.12,94.35 205.95,94.35 210.31,89.99 211.27,89.99 215.22,86.04 215.22,79.82 215.99,79.06 v1(216.62,79.06)
  BOTTOM w0.102: v1(16.93,75.93) 17.55,75.31 C255.2 18.83,75.31 Q25.3 ; Q9.2 91.63,99.71 Q9.1 92.62,99.71 92.92,99.4 C161.2 93.71,99.4 94.7,100.39 v1(96.83,100.39) 97.16,100.07 98.15,100.07 99.57,101.49 99.57,110.28 100.74,111.45 100.74,112.59 v1(100.96,112.81) ; v1(216.62,79.06) 216.87,79.31 221.24,79.31 223.07,77.48 225.74,77.48 v1(225.79,77.43)
DN2_DP5: length 281.5
  TOP w0.102: v1(164.37,69.4) 163.51,68.54 163.51,63.49 162.79,62.76 162.79,62.09 160.52,59.83 155.97,59.83 155.43,60.36 149.59,60.36 v3(149.44,60.21) 149.06,60.21 148.9,60.36 145.21,60.36 139.01,54.16 137.37,54.16 135.92,52.72 127.42,52.72 122.49,57.64 121.22,57.64 118.83,60.03 108.89,60.03 107.71,58.85 107.71,54.17 106.51,52.97 92.57,52.97 90.33,50.74 90.05,50.74 88.45,49.14 v1(88.45,48.93) ; U16.D13 225.73,75.67 225.66,75.6 C162.1 222.11,75.6 221.09,76.62 219.67,76.62 219.62,76.67 v1(219.39,76.67)
  IN1 w0.076: v1(219.39,76.67) 219.06,77 218.47,77 217.08,78.4 212.02,78.4 v1(211.95,78.47)
  IN3 w0.127: v1(211.95,78.47) 211.54,78.88 211.54,84.21 207.07,88.68 201.81,88.68 201.18,88.05 193.96,88.05 193.23,87.31 189.21,87.31 187.99,88.53 187.36,88.53 184.95,86.12 180.79,86.12 179.28,84.62 179.28,81.13 177.95,79.8 v1(177.9,79.8) 177.9,79.44 179.28,78.06 179.28,76.22 177.5,74.45 176.45,74.45 171.41,69.4 v1(164.37,69.4)
  BOTTOM w0.102: Q11.3 17.09,20.46 C164.2 17.09,21.22 15.76,22.55 15.76,27.6 17.43,29.27 17.43,31.44 19.19,33.2 19.19,36.84 20.79,38.44 76.18,38.44 87.13,49.39 87.99,49.39 v1(88.45,48.93)
  BOTTOM w0.152: v1(177.9,79.8) 178.26,79.8 178.73,80.27 C163.2 178.79,81.35 Q10.2 178.79,82.77 Q10.1
DN3_DP6: length 102.9
  TOP w0.102: v1(242.66,49.59) 242.66,49.86 243.1,50.31 243.1,54.3 241.73,55.67 241.73,56.56 240.7,57.59 239.1,57.59 238.89,57.81 238.89,59.68 238.38,60.19 236.76,60.19 235.93,61.02 v3(235.93,61.59) 235.93,61.75 235.01,62.67 228.48,62.67 226.71,64.43 224.63,64.43 v1(224.19,63.99) ; U16.B13 227.31,74.07 226.55,73.31 C165.1 225.24,73.44 223.83,73.44 223.12,74.15 v1(223.12,74.51)
  IN3 w0.081: v1(205.57,45.45) 205.85,45.17 207.06,45.17 208.3,43.93 211.16,43.93 213.38,46.14 217.55,46.14 218.73,44.97 228.08,44.97 228.45,45.35 231.35,45.35 240.25,45.35 240.27,45.33 242.15,45.33 242.86,46.04 242.86,48.17 242.2,48.83 242.2,49.31 242.48,49.59 v1(242.66,49.59)
  BOTTOM w0.102: Q13.3 205.11,48.96 205.11,47.26 C167.2 204.91,46.11 v1(205.57,45.45) ; v1(242.66,49.59) 242.66,49.54 243.39,48.81 C166.2 244.23,48.15 Q12.1 245.06,48.07 Q12.2 ; v1(223.12,74.51) 223.05,74.51 222.28,73.75 221.75,73.75 219.06,71.06 219.06,68.06 222.28,64.83 223,64.83 223.83,63.99 v1(224.19,63.99)
DOCK_CONSUMP: length 61.7
  TOP w0.203: v1(192.69,89.85) 192.49,90.06 v3(192.49,93.87) 192.49,94.4 191.6,95.29 v1(191.6,98.28)
  TOP w0.254: v1(197.02,68.23) 196.34,68.9 196.34,70.73 196.72,71.11 PR165.2
  IN4 w0.203: v1(192.69,89.85) 193.07,89.47 194.98,89.47 197.06,87.39 197.06,82.16 199.5,79.72 200.95,79.72 201.86,78.8 201.86,78.02 203.49,76.39 203.49,68.54 202.7,67.75 197.49,67.75 v1(197.02,68.23) ; v1(191.6,98.28) 180.45,98.28 179.03,96.86 v1(179.03,96.81)
  BOTTOM w0.254: v1(179.03,96.81) 179.15,96.69 J17.46
DOCK_DCIN20: length 37.5
  TOP w0.381: v1(165,94.43) 166.24,93.18 v3(166.24,91.91) PF5.1
  IN3 w0.508: v1(165,94.43) 165,95.17 168.02,98.19 173.71,98.19 174.35,97.55 180.09,97.55 181.31,98.77 188.27,98.77 190.12,96.93 190.12,95.2 v1(191.27,94.04)
  BOTTOM w0.381: v1(191.27,94.04) 191.22,94.09 191.14,94.09 190.7,94.54 J17.67
DOCK_DDIP2_0N: length 183.1
  TOP w0.102: v1(175.17,110.91) 175.17,111.04 174.79,111.41 174.66,111.41 174.4,111.15 v2(174.4,107.38) 174.4,107.02 C150.1 ; v1(47.18,61.85) 47.18,61.73 47.55,61.36 47.77,61.36 48.98,62.57 48.98,65.23 v2(48.25,65.96) 47.44,66.76 47.44,66.98 47.35,67.08 U147.54
  IN4 w0.089: v1(47.18,61.85) 47.18,61.71 46.89,61.42 46.67,61.42 45.27,62.83 45.27,67.02 47.1,68.85 47.1,72.02 46.59,72.53 46.59,76.21 48.75,78.37 50.73,78.37 57.41,85.05 58.53,85.05 63.51,90.03 63.51,91.07 68.87,96.43 76.95,96.43 79.32,98.8 87,98.8 90.68,102.48 92.07,102.48 92.35,102.76 93.3,102.76 95.64,105.09 98.33,105.09 99.59,106.35 99.59,106.63 100.36,107.4 100.85,107.4 101.52,108.08 106.89,108.08 108.82,106.14 108.82,104.96 112.16,101.62 114.32,101.62 115.22,102.53 116.96,102.53 118.16,103.72 125.38,103.72 126.61,104.94 135.02,104.94 135.33,105.26 137.89,105.26 139.05,106.41 142.64,106.41 143.28,105.78 148.11,105.78 148.74,106.41 156.14,106.41 157.55,105 160.12,105 166.55,111.43 174.77,111.43 174.86,111.34 174.86,111.21 174.87,111.21 v1(175.17,110.91)
DOCK_DDIP2_0P: length 183.1
  TOP w0.102: U147.55 47.75,67.06 47.65,66.96 47.65,66.85 49.18,65.32 49.18,62.48 47.85,61.15 v1(47.2,61.15) ; C152.1 v2(174.19,108.65) 174.19,111.24 174.58,111.62 v1(175.17,111.62)
  IN4 w0.089: v1(47.2,61.15) 47.12,61.23 46.6,61.23 45.08,62.75 45.08,67.1 46.91,68.93 46.91,71.94 46.4,72.45 46.4,76.29 48.67,78.56 50.65,78.56 57.33,85.24 58.45,85.24 63.32,90.11 63.32,91.15 68.79,96.62 76.87,96.62 79.24,98.99 86.92,98.99 90.6,102.67 92,102.67 92.27,102.95 93.22,102.95 95.56,105.28 98.25,105.28 99.4,106.43 99.4,106.71 100.29,107.59 100.77,107.59 101.44,108.27 106.97,108.27 109.01,106.22 109.01,105.04 112.24,101.82 114.24,101.82 115.14,102.72 116.88,102.72 118.08,103.91 125.3,103.91 126.53,105.13 134.94,105.13 135.25,105.45 137.81,105.45 138.97,106.6 142.72,106.6 143.35,105.97 148.03,105.97 148.66,106.6 156.22,106.6 157.63,105.19 160.04,105.19 166.47,111.62 v1(175.17,111.62)
DOCK_DDIP2_1N: length 178.8
  TOP w0.102: v1(47.81,64.07) 47.99,63.89 48.15,63.89 48.29,64.03 48.29,64.86 47.64,65.51 47.09,65.51 46.71,65.89 46.71,66.39 46.15,66.96 U147.51 ; v1(177.81,111.27) 177.43,111.27 177.23,111.07 177.23,110.77 176.26,109.8 v2(176.26,108.63) 176.26,106.81 C148.1
  IN4 w0.089: v1(47.81,64.07) 47.52,63.78 46.83,63.78 45.96,64.66 45.96,66.81 47.74,68.59 47.74,73.56 47.47,73.83 47.47,75.21 50.03,77.77 51,77.77 57.62,84.39 58.76,84.39 64.22,89.85 64.22,90.89 66.73,93.41 68.45,93.41 69.24,94.2 70.67,94.2 72.31,95.85 77.22,95.85 79.59,98.22 87.26,98.22 89.42,100.38 91.43,100.38 92.6,101.55 93.65,101.55 94.72,102.62 94.72,103.26 95.82,104.36 98.61,104.36 100.43,106.17 101.16,106.17 102.43,107.44 106.15,107.44 107.8,105.8 107.8,105.11 111.87,101.04 114.72,101.04 115.61,101.93 117.2,101.93 118.39,103.12 127.27,103.12 127.88,103.74 137.21,103.74 139.3,105.83 142.3,105.83 143.42,104.71 147.89,104.71 149.01,105.83 155.81,105.83 157.24,104.41 160.38,104.41 166.28,110.31 176.6,110.31 177.1,110.81 177.1,111.09 177.28,111.27 v1(177.81,111.27)
DOCK_DDIP2_1P: length 178.9
  TOP w0.102: C149.1 176.05,106.81 176.05,109.89 177.02,110.86 177.02,111.05 176.83,111.24 v1(176.52,111.24) ; U147.52 46.55,66.85 46.92,66.48 46.92,65.98 47.18,65.72 47.73,65.72 48.5,64.95 v2(48.5,64.5) 48.5,63.94 48.24,63.68 48.01,63.68 v1(47.81,63.49)
  IN4 w0.089: v1(176.52,111.24) 176.72,111.24 176.91,111.05 176.91,110.89 176.52,110.5 166.2,110.5 160.3,104.6 157.31,104.6 155.89,106.02 148.93,106.02 147.81,104.9 143.5,104.9 142.38,106.02 139.22,106.02 137.13,103.93 127.8,103.93 127.19,103.31 118.31,103.31 117.12,102.12 115.53,102.12 114.64,101.23 111.95,101.23 107.99,105.19 107.99,105.87 106.23,107.63 102.36,107.63 101.09,106.36 100.35,106.36 98.53,104.55 95.74,104.55 94.53,103.33 94.53,102.7 93.57,101.74 92.52,101.74 91.35,100.57 89.34,100.57 87.18,98.41 79.51,98.41 77.14,96.04 72.23,96.04 70.59,94.39 69.17,94.39 68.37,93.6 66.66,93.6 64.03,90.97 64.03,89.93 58.68,84.58 57.54,84.58 50.92,77.96 49.96,77.96 47.28,75.29 47.28,73.75 47.55,73.48 47.55,68.67 45.77,66.89 45.77,64.58 46.76,63.59 47.71,63.59 v1(47.81,63.49)
DOCK_DDIP2_2N: length 171.6
  TOP w0.102: C146.1 177.84,106.89 177.84,108.69 178.32,109.17 178.32,110.02 178.05,110.3 177.58,110.3 v1(177.48,110.4) ; v1(47.3,64.45) 47.13,64.62 46.78,64.62 v2(46.43,64.97) 46.08,65.32 46.08,66.06 45.35,66.79 U147.49
  IN4 w0.089: v1(47.3,64.45) 47.25,64.5 46.73,64.5 46.45,64.78 46.45,66.67 48.13,68.35 48.13,70.55 48.6,71.02 48.6,75.59 50.37,77.37 51.19,77.37 57.69,83.87 58.93,83.87 64.92,89.85 64.92,90.97 66.91,92.96 69.21,92.96 70.05,93.8 70.86,93.8 72.51,95.45 77.42,95.45 79.79,97.82 88.91,97.82 90.94,99.86 91.47,99.86 92.59,100.98 93.66,100.98 95.15,102.46 95.15,103.01 95.99,103.86 99.12,103.86 100.12,104.86 101.13,104.86 102.46,106.2 106.14,106.2 111.69,100.65 114.89,100.65 115.67,101.43 126.48,101.43 128.28,103.23 136.92,103.23 137.28,102.87 142.88,102.87 144.24,104.24 148.22,104.24 148.88,104.9 153.9,104.9 154.19,105.19 155.66,105.19 156.85,104 160.6,104 166.36,109.77 176.68,109.77 177.1,110.18 177.26,110.18 v1(177.48,110.4)
DOCK_DDIP2_2P: length 171.5
  TOP w0.102: v1(177.48,109.59) 177.48,109.71 177.85,110.09 177.96,110.09 178.11,109.94 178.11,109.26 177.63,108.77 v2(177.63,107.61) 177.63,106.74 C147.1 ; U147.50 45.75,66.9 45.71,66.86 45.71,66.72 46.29,66.14 46.29,65.41 46.86,64.83 47.05,64.83 v1(47.3,65.09)
  IN4 w0.089: v1(47.3,65.09) 47.3,65.04 46.96,64.69 46.81,64.69 46.64,64.86 46.64,66.6 48.32,68.27 48.32,70.47 48.79,70.94 48.79,75.51 50.45,77.18 51.27,77.18 57.77,83.68 59.01,83.68 65.11,89.78 65.11,90.89 66.99,92.77 69.29,92.77 70.13,93.61 70.93,93.61 72.59,95.26 77.49,95.26 79.87,97.63 88.99,97.63 91.02,99.67 91.55,99.67 92.67,100.79 93.74,100.79 95.34,102.38 95.34,102.93 96.07,103.67 99.2,103.67 100.2,104.67 101.21,104.67 102.54,106.01 106.06,106.01 111.61,100.46 114.97,100.46 115.75,101.24 126.56,101.24 128.36,103.04 136.84,103.04 137.2,102.68 142.96,102.68 144.32,104.05 148.29,104.05 148.95,104.71 153.97,104.71 154.27,105 155.58,105 156.78,103.81 160.68,103.81 166.44,109.58 176.76,109.58 177.17,109.99 177.73,109.99 177.86,109.87 177.86,109.74 177.71,109.59 v1(177.48,109.59)
DOCK_DDIP2_3N: length 175.1
  TOP w0.102: C144.1 179.54,106.76 v2(179.54,107.33) 179.54,107.95 179.26,108.23 179.26,109.84 179.43,110.01 179.59,110.01 179.71,109.89 v1(179.71,109.71) ; v1(47.18,62.55) 46.95,62.78 45.66,62.78 44.86,63.58 44.86,65.84 44.24,66.46 44.24,66.88 44.15,66.97 U147.46
  IN4 w0.089: v1(47.18,62.55) 47.25,62.62 48.56,62.62 48.98,63.04 48.98,63.86 48.45,64.39 48.45,67.55 49.03,68.13 49.03,70.19 49.48,70.64 49.48,74.52 57.95,82.99 59.34,82.99 65.72,89.37 65.72,90.64 67.15,92.07 69.43,92.07 70.37,93.02 71.24,93.02 72.89,94.68 77.78,94.68 80.15,97.04 89.23,97.04 91.01,98.82 91.62,98.82 92.99,100.19 94.03,100.19 95.43,101.59 98.59,101.59 100.38,103.38 107.54,103.38 111.05,99.87 116.34,99.87 116.7,100.23 119.09,100.23 119.46,100.6 126.84,100.6 128.12,101.87 143.26,101.87 144.83,103.44 148.57,103.44 149.23,104.1 151.98,104.1 153.31,102.77 157.24,102.77 157.68,103.21 161.1,103.21 166.79,108.9 178.19,108.9 179.23,109.94 179.49,109.94 v1(179.71,109.71)
DOCK_DDIP2_3P: length 175
  TOP w0.102: v1(179.71,110.43) 179.51,110.22 179.34,110.22 179.05,109.93 v2(179.05,108.65) 179.05,108.15 179.33,107.86 179.33,106.76 C145.1 ; v1(47.18,63.13) 47.03,62.99 45.75,62.99 45.07,63.66 45.07,65.93 44.45,66.54 44.45,66.93 44.55,67.03 U147.47
  IN4 w0.089: v1(47.18,63.13) 47.49,62.81 48.49,62.81 48.79,63.12 48.79,63.78 48.26,64.31 48.26,67.63 48.84,68.21 48.84,70.27 49.29,70.72 49.29,74.6 57.87,83.18 59.26,83.18 65.53,89.45 65.53,90.72 67.08,92.26 69.35,92.26 70.3,93.21 71.16,93.21 72.82,94.87 77.71,94.87 80.07,97.23 89.15,97.23 90.93,99.01 91.54,99.01 92.91,100.38 93.95,100.38 95.35,101.78 98.51,101.78 100.3,103.57 107.62,103.57 111.12,100.06 116.26,100.06 116.62,100.42 119.01,100.42 119.38,100.79 126.77,100.79 128.04,102.06 143.18,102.06 144.75,103.63 148.5,103.63 149.16,104.29 152.06,104.29 153.39,102.96 157.16,102.96 157.6,103.4 161.02,103.4 166.71,109.09 178.11,109.09 179.15,110.13 179.42,110.13 v1(179.71,110.43)
DOCK_DDIP2_AUXN: length 194.7
  TOP w0.102: v1(181.82,109.56) 181.6,109.79 181.41,109.79 181.26,109.65 181.26,106.48 R117.2 181.37,105.94 181.17,105.74 181.17,105.28 180.9,105.02 180.9,104.91 181,104.81 181.19,104.81 v1(181.46,104.54) ; U147.61 49.14,69.71 49.23,69.81 49.95,69.81 50.69,69.07 52.43,69.07 54.37,71.01 54.37,76.74 51.4,79.71 v1(51.4,79.98)
  IN4 w0.089: v1(51.4,79.98) 51.13,79.98 50.96,80.15 50.96,81.19 56.01,86.24 56.01,91.3 56.09,91.71 57.25,94.5 57.25,95.07 55.99,96.33 55.99,110.96 57.69,112.66 92.26,112.66 93.72,111.2 98.02,111.2 100.44,108.77 105.77,108.77 108.57,111.57 119.07,111.57 122.85,107.79 143.72,107.79 144.4,107.11 147.65,107.11 148.29,107.76 149.92,107.76 150.91,108.75 154.59,108.75 158.19,112.34 177.38,112.34 178.69,111.03 179.69,111.03 181.16,109.56 v1(181.82,109.56)
  BOTTOM w0.102: J17.21 181.35,105.51 181.18,105.34 181.18,104.82 v1(181.46,104.54)
DOCK_DDIP2_AUXP: length 194.7
  TOP w0.102: v1(181.82,110.28) 181.55,110 181.32,110 181.06,109.74 181.06,106.47 R118.1 180.96,105.51 180.96,105.37 180.69,105.1 v1(180.69,104.54) ; U147.62 49.14,70.11 49.23,70.02 50.03,70.02 50.77,69.28 52.34,69.28 v2(52.8,69.73) 54.16,71.1 54.16,76.65 51.25,79.56 v1(50.99,79.56)
  IN4 w0.089: v1(181.82,110.28) 181.82,110.15 181.43,109.76 181.24,109.76 179.77,111.22 178.77,111.22 177.46,112.53 158.11,112.53 154.52,108.94 150.83,108.94 149.84,107.95 148.22,107.95 147.57,107.3 144.47,107.3 143.8,107.98 122.93,107.98 119.15,111.76 108.49,111.76 105.7,108.97 100.52,108.97 98.09,111.39 93.8,111.39 92.34,112.85 57.61,112.85 55.8,111.04 55.8,96.25 57.06,94.99 57.06,94.53 55.91,91.77 55.82,91.32 55.82,86.32 51.18,81.68 50.77,81.27 50.77,80.07 50.99,79.86 v1(50.99,79.56)
  BOTTOM w0.102: J17.22 180.8,105.51 180.97,105.34 180.97,104.82 v1(180.69,104.54)
DOCK_DDIP2_HPD: length 258.2
  TOP w0.102: U147.53 46.95,66.84 47.43,66.36 v1(47.43,66.15) ; v1(184.16,104.99) v3(184.92,104.99) 191.95,104.99 197.9,99.04 v1(197.9,94.22)
  IN1 w0.076: v1(90.94,43.14) 90.46,43.62 90.46,47.59 94.19,51.32 96.1,51.32 97.24,50.18 188.68,50.18 190.43,48.42 v1(190.99,48.42)
  IN3 w0.081: v1(90.94,43.14) 90.59,43.14 88.5,45.22 58.15,45.22 44.59,58.79 44.59,60.87 46.59,62.88 46.59,65.21 47.43,66.05 v1(47.43,66.15)
  BOTTOM w0.102: J17.16 184.1,105.05 v1(184.16,104.99) ; v1(197.9,94.22) 197.9,94.02 200.31,91.6 205.57,91.6 210.83,86.35 210.83,83.4 207.86,80.43 205.85,80.43 203.77,78.35 203.77,74.92 203.46,74.61 203.46,73.32 202.41,72.26 202.41,70.89 200.85,69.33 200.85,66.73 198.62,64.51 198.62,63.15 197.37,61.9 196.45,61.9 193.94,59.39 193.94,55.67 193.38,55.11 193.38,49.53 192.58,48.73 191.3,48.73 v1(190.99,48.42)
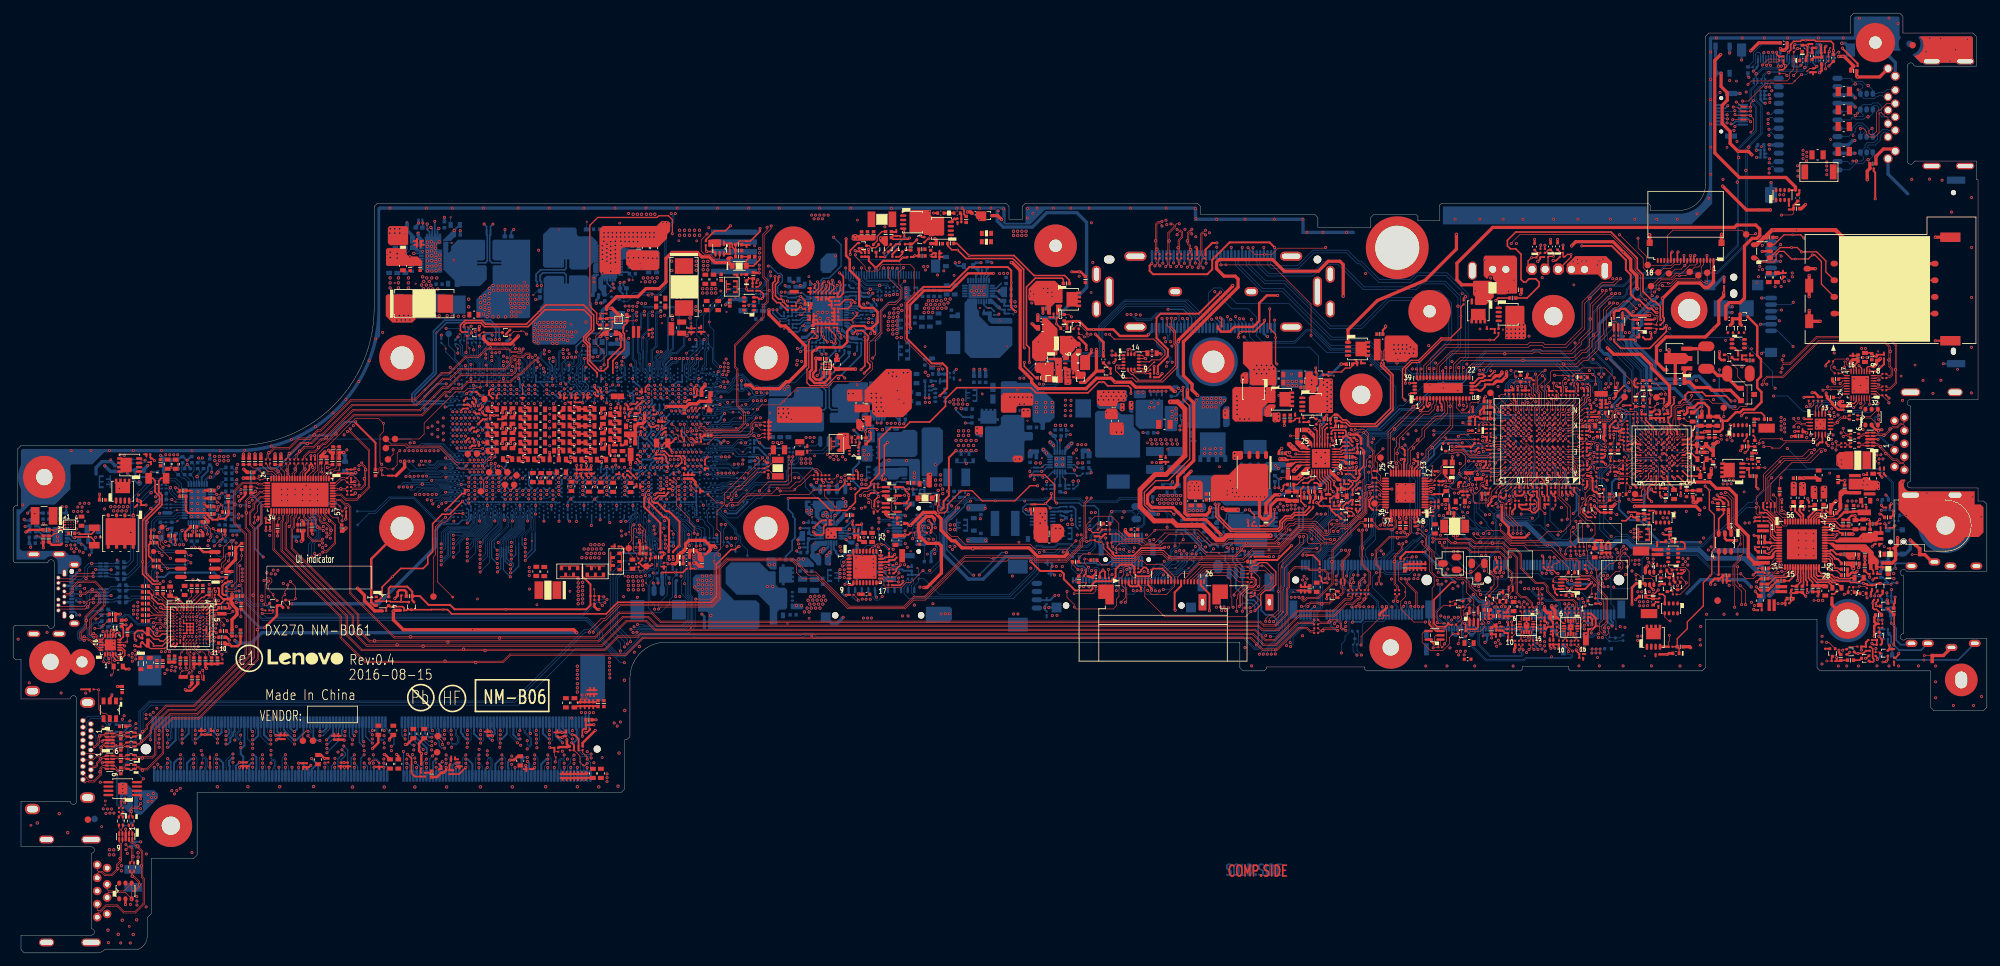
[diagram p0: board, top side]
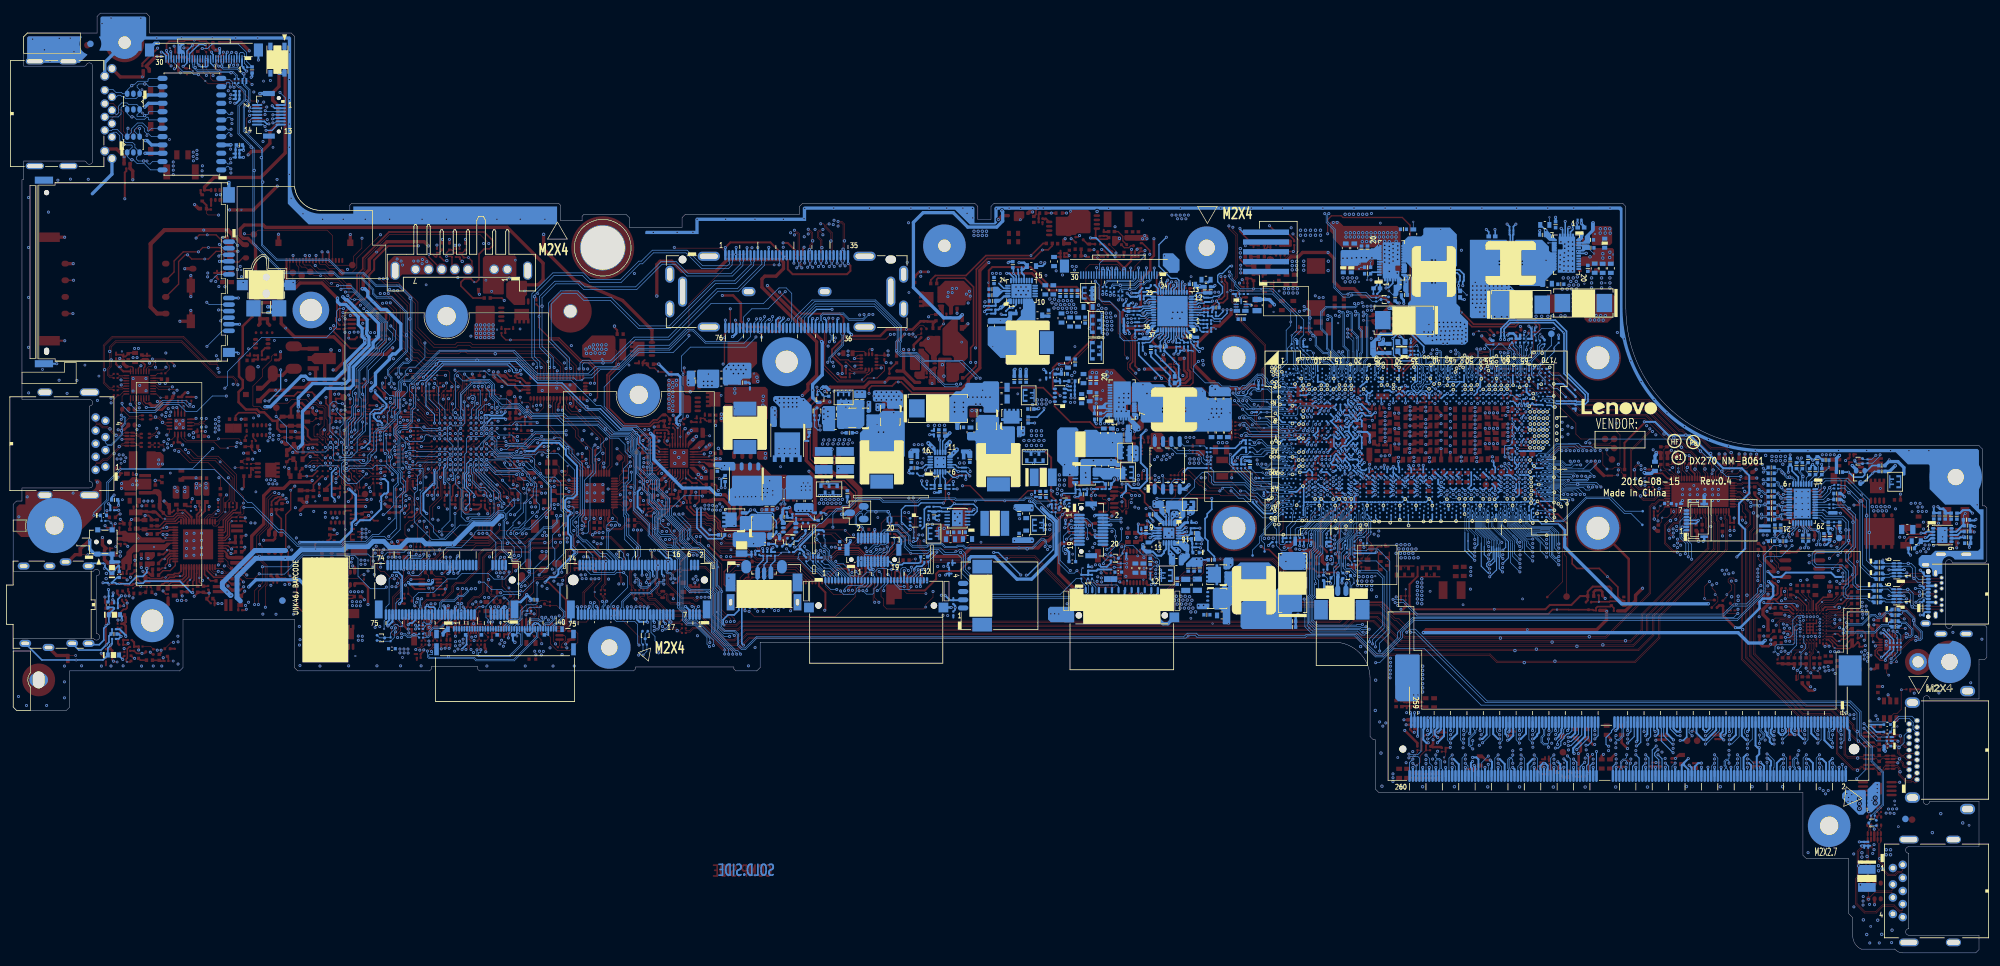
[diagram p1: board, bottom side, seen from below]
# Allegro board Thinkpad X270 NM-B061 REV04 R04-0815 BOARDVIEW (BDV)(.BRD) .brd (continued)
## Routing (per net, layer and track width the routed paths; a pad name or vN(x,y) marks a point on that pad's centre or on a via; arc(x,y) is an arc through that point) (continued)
DOCK_DP0N: length 3.2
  TOP w0.102: C150.2 174.61,105.8 174.61,105.08 v1(174.86,104.84)
  BOTTOM w0.102: J17.33 174.75,105.59 174.56,105.4 174.56,105.13 v1(174.86,104.84)
DOCK_DP0P: length 3.2
  TOP w0.102: v1(174.09,104.84) 174.41,105.15 174.41,105.8 C152.2
  BOTTOM w0.102: J17.34 174.2,105.51 174.35,105.36 174.35,105.1 v1(174.09,104.84)
DOCK_DP1N: length 3.4
  TOP w0.102: v1(176.51,104.73) 176.26,104.98 176.26,105.8 C148.2
  BOTTOM w0.102: J17.30 176.4,105.51 176.23,105.34 176.23,105.01 v1(176.51,104.73)
DOCK_DP1P: length 3.4
  TOP w0.102: v1(175.74,104.73) 176.05,105.04 176.05,105.8 C149.2
  BOTTOM w0.102: v1(175.74,104.73) 176.02,105.01 176.02,105.34 175.85,105.51 J17.31
DOCK_DP2N: length 3.4
  TOP w0.102: v1(178.16,104.73) 177.89,105 177.89,105.78 C146.2
  BOTTOM w0.102: v1(178.16,104.73) 177.88,105.01 177.88,105.34 178.05,105.51 J17.27
DOCK_DP2P: length 3.4
  TOP w0.102: C147.2 177.68,105.83 177.68,105.02 v1(177.39,104.73)
  BOTTOM w0.102: J17.28 177.5,105.51 177.67,105.34 177.67,105.01 v1(177.39,104.73)
DOCK_DP3N: length 3.5
  TOP w0.102: v1(179.81,104.63) 179.54,104.91 179.54,105.75 C144.2
  BOTTOM w0.102: J17.24 179.7,105.51 179.53,105.34 179.53,104.91 v1(179.81,104.63)
DOCK_DP3P: length 3.5
  TOP w0.102: C145.2 179.33,105.75 179.33,104.92 v1(179.04,104.63)
  BOTTOM w0.102: v1(179.04,104.63) 179.32,104.91 179.32,105.34 179.15,105.51 J17.25
DOCK_HP_JD: length 1.3
  TOP w0.254: R319.1 281.54,44.67 Q197.1
DOCK_I2S_BCLK: length 138.1
  TOP w0.102: v1(275.7,76.49) 274.02,74.82 271.19,74.82 268,71.62 268,69.22 R1236.2
  IN1 w0.076: v1(275.7,76.49) 276.08,76.11 279.99,76.11 282.91,79.03 282.91,82.47 282.25,83.13 282.25,84.06 281.77,84.54 281.03,84.54 279.13,86.44 279.13,87.19 278.56,87.76 276.88,87.76 271,93.64 248.34,93.64 246.53,95.44 244.94,95.44 244.26,96.13 241.18,96.13 236.45,100.86 231.79,100.86 229.75,98.82 220.95,98.82 217.6,95.47 215.01,95.47 212.17,98.31 206.31,98.31 203.11,95.11 199.53,95.11 196.35,98.28 192.59,98.28 192.19,97.88 189.29,97.88 187.77,96.35 187.44,96.35 v1(187,96.79)
  BOTTOM w0.102: v1(187,96.79) 187,96.56 187.4,96.16 J17.61
DOCK_I2S_LRCLK: length 140
  TOP w0.102: R1238.2 267.22,69 267.22,72.76 v3(269.39,74.93) 269.94,75.48 273.36,75.48 v1(274.23,76.34)
  IN1 w0.076: v1(274.23,76.34) 274.81,76.34 275.47,75.68 280.22,75.68 283.32,78.78 283.32,82.73 282.66,83.39 282.66,84.38 278.37,88.67 277.61,88.67 277,89.29 277,90.05 272.85,94.2 251.55,94.2 250.28,95.47 247.46,95.47 246.9,96.02 245.15,96.02 244.51,96.66 241.37,96.66 236.63,101.4 229.77,101.4 229.3,101.87 226.67,101.87 226.13,101.32 225.39,101.32 224.54,100.47 214.91,100.47 213.56,99.12 206.33,99.12 202.68,95.47 199.83,95.47 196.35,98.95 188.25,98.95 v1(186.39,97.09)
  BOTTOM w0.102: J17.60 186.85,96.33 186.39,96.79 v1(186.39,97.09)
DOCK_I2S_MCLK: length 134.9
  TOP w0.102: v1(276.31,76.69) 276.08,76.92 275.45,76.92 273.64,75.12 270.13,75.12 267.43,72.43 R1235.2
  IN1 w0.076: v1(188.81,96.68) 189.77,97.65 192.47,97.65 192.95,98.13 196.22,98.13 199.42,94.93 203.25,94.93 206.35,98.04 212.22,98.04 214.96,95.29 217.91,95.29 221.23,98.61 230.06,98.61 232.02,100.58 236.28,100.58 241.74,95.11 246.58,95.11 248.38,93.31 268.1,93.31 269.34,92.07 271.99,92.07 277.71,86.35 278.55,86.35 280.04,84.86 280.04,83.05 282.73,80.36 282.73,79.13 279.92,76.31 276.69,76.31 v1(276.31,76.69)
  BOTTOM w0.102: J17.64 189.05,96.16 188.81,96.41 v1(188.81,96.68)
DOCK_I2S_SD_I: length 120.8
  TOP w0.102: R1239.2 266.54,66.84 266,66.84 265.77,67.07 v1(265.77,67.99)
  TOP w0.203: R1239.2 267.57,66.48 268.26,65.8 268.26,63.79 268.71,63.34 UA1.5
  BOTTOM w0.102: v1(265.77,67.99) 264.31,67.99 260.52,64.2 259.8,64.2 257.65,62.05 250.82,62.05 250.35,62.52 247.1,62.52 246.11,63.51 244.28,63.51 243.87,63.11 243.42,63.11 241.93,64.59 241.93,67.39 241.56,67.75 241.56,69.91 241.08,70.4 241.08,71.92 241.64,72.48 241.64,73.37 241.97,73.7 241.97,78.42 242.73,79.18 242.73,79.84 242.12,80.45 240.98,80.45 240.29,81.14 240.29,82.99 239.91,83.37 239.91,85.2 240.5,85.79 240.5,86.73 236.43,90.79 224.11,90.79 221.06,87.74 215.43,87.74 215.08,87.39 v4(214.26,87.39) 213.91,87.74 212.69,87.74 211.39,89.04 208.52,89.04 205.57,91.99 200.85,91.99 197.93,94.91 197.29,94.91 195.44,93.05 189.49,93.05 188.5,94.05 J17.63
DOCK_I2S_SD_O: length 140.3
  TOP w0.102: R1237.2 266.32,68.02 265.82,68.52 v3(265.82,68.64) 265.82,69.61 266.89,70.67 266.89,72.99 269.68,75.78 272.83,75.78 273.85,76.8 v1(274.66,76.8)
  IN1 w0.076: v1(274.66,76.8) 275.55,75.91 280.12,75.91 283.14,78.93 283.14,82.6 282.46,83.29 282.46,84.21 281.84,84.83 281.03,84.83 279.51,86.35 279.51,87.1 278.45,88.16 276.89,88.16 271.1,93.94 248.54,93.94 246.79,95.69 245.12,95.69 244.41,96.41 241.26,96.41 236.48,101.19 229.54,101.19 229.32,101.41 226.73,101.41 225.62,100.3 214.95,100.3 213.43,98.78 206.3,98.78 202.8,95.29 199.65,95.29 196.2,98.74 189.57,98.74 v1(187.59,96.76)
  BOTTOM w0.102: v1(187.59,96.76) 187.59,96.56 187.95,96.2 J17.62
DOCK_MDI_0+: length 49.4
  TOP w0.102: v1(221.13,89.33) 220.98,89.18 220.98,88.8 221.05,88.73 U14.24
  BOTTOM w0.102: J17.2 191.8,105.48 191.73,105.41 191.73,105.14 192.01,104.86 195.82,104.86 198.18,107.23 203.49,107.23 205.15,105.56 205.56,105.56 208.39,102.73 212.93,102.73 213.98,103.77 218.65,103.77 221.85,100.57 221.85,90.85 221.04,90.04 221.04,89.42 v1(221.13,89.33)
DOCK_MDI_0-: length 49.5
  TOP w0.102: U14.25 220.55,88.77 220.57,88.79 220.57,89.18 v1(220.42,89.33)
  BOTTOM w0.102: v1(220.42,89.33) 220.48,89.33 220.63,89.48 220.63,90.21 221.45,91.02 v2(221.45,100.14) 221.45,100.4 218.48,103.36 214.14,103.36 213.1,102.32 208.22,102.32 205.39,105.16 204.98,105.16 203.32,106.82 198.35,106.82 195.99,104.46 191.84,104.46 191.32,104.97 191.32,105.41 191.25,105.48 J17.3
DOCK_MDI_1+: length 49.5
  TOP w0.102: U14.28 219.05,88.67 219.01,88.71 219.01,89.17 v1(219.16,89.33)
  BOTTOM w0.102: J17.5 190.15,105.48 190.08,105.41 190.08,105.07 191.45,103.69 198.04,103.69 199.84,105.5 202.16,105.5 206.02,101.64 213.77,101.64 214.64,102.5 218.37,102.5 220.71,100.16 220.71,92.39 219,90.69 219,89.48 v1(219.16,89.33)
DOCK_MDI_1-: length 49.5
  TOP w0.102: U14.29 218.55,88.66 218.6,88.71 218.6,89.17 v1(218.45,89.33)
  BOTTOM w0.102: v1(218.45,89.33) 218.6,89.47 218.6,90.85 220.3,92.56 v2(220.3,98.69) 220.3,100 218.2,102.09 214.8,102.09 213.94,101.23 205.85,101.23 201.99,105.09 200.01,105.09 198.21,103.29 191.28,103.29 189.67,104.9 189.67,105.41 189.6,105.48 J17.6
DOCK_MDI_2+: length 51.9
  TOP w0.102: v1(216.65,89.17) 216.49,89.01 216.49,88.66 216.55,88.6 216.55,87.92 U14.33
  BOTTOM w0.102: v1(216.65,89.17) 216.49,89.32 216.49,90.59 219.31,93.41 219.31,99.17 217.46,101.03 214.82,101.03 213.78,99.99 209.74,99.99 205.42,95.67 200.9,95.67 194.01,102.55 190.97,102.55 188.43,105.09 188.43,105.41 188.5,105.48 J17.8
DOCK_MDI_2-: length 51.9
  TOP w0.102: v1(215.93,89.17) 216.09,89.01 216.09,88.68 216.05,88.64 U14.34
  BOTTOM w0.102: v1(215.93,89.17) 216.09,89.32 216.09,90.76 218.91,93.58 218.91,99.01 217.29,100.62 214.99,100.62 213.94,99.58 209.91,99.58 205.59,95.26 200.73,95.26 193.85,102.15 190.8,102.15 188.02,104.92 188.02,105.41 187.95,105.48 J17.9
DOCK_MDI_3+: length 37.7
  TOP w0.102: v1(214.66,89.11) 214.51,88.96 214.51,88.66 214.55,88.62 214.55,87.92 U14.37
  BOTTOM w0.102: v1(214.66,89.11) 214.51,89.26 214.51,90 214.08,90.44 209.79,90.44 206.26,93.97 201.05,93.97 193.63,101.38 190.51,101.38 186.78,105.12 186.78,105.41 186.85,105.48 J17.11
DOCK_MDI_3-: length 37.7
  TOP w0.102: v1(213.95,89.11) 214.11,88.96 214.11,88.66 214.05,88.6 U14.38
  BOTTOM w0.102: J17.12 186.3,105.48 186.37,105.41 186.37,104.95 190.34,100.98 193.47,100.98 200.88,93.56 206.09,93.56 209.62,90.03 v2(211,90.03) 213.91,90.03 214.11,89.84 214.11,89.26 v1(213.95,89.11)
DOCK_MIC_EN: length 1.4
  TOP w0.102: RA50.1 R46.1 284.56,49.51 QA8.1
DOCK_MIC_JD: length 1.5
  TOP w0.102: RA290.1 v3(276.54,44.54)
  TOP w0.254: RA290.1 277.29,45.13 QA7.1
DOCK_PWR20_IN:
  vias: v3(164.36,100.78)
DOCKID0: length 87.3
  IN1 w0.127: v1(156.47,86.83) 152.71,86.83 151.66,85.77 140.85,85.77 140.64,85.56 134.27,85.56 132.33,87.5 129.85,87.5 128.9,88.45 124.49,88.45 123.33,87.29 120.46,87.29 120.23,87.06 117,83.83 114.51,83.83 v1(114.08,84.26)
  BOTTOM w0.102: U1.M1 107.93,82.96 108.16,83.2 109.33,83.2 109.43,83.1 112.46,83.1 113.09,83.73 113.55,83.73 v1(114.08,84.26) ; v1(156.47,86.83) 156.93,86.37 158.86,86.37 163.51,91.02 165.69,91.02 166.35,91.68 166.35,93.33 166.15,93.53 166.15,95.19 169.63,98.67 178.52,98.67 180.25,96.94 J17.48
DOCKID1: length 89
  IN1 w0.127: v1(112.86,84.26) 113.57,83.55 117.08,83.55 120.56,87.03 123.53,87.03 124.7,88.2 128.86,88.2 129.77,87.3 132.2,87.3 134.17,85.34 140.77,85.34 141,85.57 151.81,85.57 152.64,86.4 156.73,86.4 v1(157.11,86.78)
  BOTTOM w0.102: v1(112.86,84.26) 112.86,84.01 112.15,83.3 111.36,83.3 v4(111.11,83.55) 110.85,83.3 109.56,83.3 109.43,83.43 108.11,83.43 107.86,83.17 107.55,83.17 107.45,83.27 107.07,83.27 106.76,82.96 U1.M2 ; v1(157.11,86.78) 158.94,86.78 163.38,91.22 165.59,91.22 166.13,91.76 166.13,93.26 165.9,93.48 165.9,95.31 169.61,99.02 178.6,99.02 180.8,96.82 J17.49
DOCKID2: length 89.8
  IN1 w0.127: v1(154.11,87.69) 153.58,87.16 152.74,87.16 151.56,85.98 140.71,85.98 140.54,85.82 134.3,85.82 132.41,87.7 129.93,87.7 128.98,88.66 124.11,88.66 124.05,88.6 121.41,88.6 116.97,84.16 114.84,84.16 v1(114.72,84.29)
  BOTTOM w0.102: J17.50 181.35,96.78 178.75,99.38 169.53,99.38 165.67,95.52 165.67,93.41 165.87,93.2 165.87,91.81 165.49,91.43 163.26,91.43 162.04,90.21 156.63,90.21 v1(154.11,87.69) ; U1.M3 106.19,82.96 106.48,82.67 107.99,82.67 108.31,82.99 109.2,82.99 109.31,82.89 112.76,82.89 v4(112.84,82.97) 113.32,83.45 113.88,83.45 v1(114.72,84.29)
DOCKID3: length 91.8
  IN1 w0.127: v1(153.5,87.69) 153.25,87.44 152.67,87.44 151.45,86.22 140.51,86.22 140.36,86.07 134.33,86.07 132.5,87.91 131.47,87.91 129.79,89.58 127.06,89.58 126.49,89.01 124.04,89.01 123.9,88.87 121.32,88.87 117.2,84.75 113.95,84.75 v1(113.47,84.26)
  BOTTOM w0.076: U1.J4 105.77,83.91 107.5,83.91 107.63,84.04 108.19,84.04 108.57,83.65
  BOTTOM w0.102: J17.51 181.9,96.86 179.13,99.63 169.45,99.63 165.46,95.64 165.46,93.28 165.62,93.13 165.62,91.86 165.39,91.63 163.15,91.63 161.93,90.41 156.24,90.41 153.53,87.69 v1(153.5,87.69) ; 108.57,83.65 108.59,83.63 109.25,83.63 v4(109.71,84.09) 110.17,84.09 110.19,84.11 112.07,84.11 112.65,84.68 113.05,84.68 v1(113.47,84.26)
DP1_DN4: length 302.4
  TOP w0.102: U16.G13 225.85,78.07 v1(225.82,78.04) 225.54,77.76 225.09,77.76 C160.2
  IN3 w0.081: v1(16.28,76.01) 16.28,75.89 16.65,75.53 21.93,75.53 22.28,75.17 25.3,75.17 25.83,75.71 27.13,75.71 27.59,75.25 27.59,74.86 28.63,73.82 32.73,73.82 33.89,74.97 35.25,74.97 35.99,74.22 42.04,74.22 55.91,88.1 55.91,92.37 57.18,93.64 57.18,94.98 56.09,96.07 56.09,110.91 58.2,113.02 92.56,113.02 93.29,112.29 98.02,112.29 98.55,112.82 v1(100.34,112.82)
  IN4 w0.076: v1(216.62,79.69) 216.06,79.69 215.5,80.25 215.5,86.12 211.35,90.27 210.4,90.27 206.12,94.55 199.15,94.55 196.17,97.52 191.98,97.52 191.23,96.77 191.23,96.37 191.02,96.15 190.44,96.15 188.94,97.65 181.26,97.65 179.03,95.41 174.86,95.41 172.18,98.09 169.61,98.09 168.03,96.52 168.03,94.17 165.31,91.45 162.85,91.45 162.59,91.2 155.81,91.2 155.7,91.3 151.86,91.3 150.86,90.31 150.43,90.31 149.72,89.6 142.83,89.6 141.97,90.46 141.54,90.46 138.53,93.47 134.45,93.47 132.85,95.07 132.85,96.49 130.78,98.56 127.16,98.56 126.5,99.22 119.64,99.22 119.39,98.97 117.36,98.97 116.93,99.4 110.83,99.4 107.32,102.91 101.43,102.91 98.82,100.29 97.65,100.29 v1(97.42,100.52)
  BOTTOM w0.102: v1(16.28,76.01) 16.28,75.86 17.42,74.73 C255.1 18.88,74.73 Q25.2 19.72,74.64 Q25.1 ; Q9.3 91.65,100.11 91.78,100.24 92.59,100.24 92.82,100.01 93.1,100.01 C161.1 93.85,99.99 94.66,100.8 97.13,100.8 v1(97.42,100.52) 98.29,100.52 99.36,101.59 99.36,110.44 100.5,111.58 100.5,112.66 v1(100.34,112.82) ; v1(216.62,79.69) 216.8,79.51 221.41,79.51 223.19,77.74 225.51,77.74 v1(225.82,78.04)
DP2_DN5: length 281
  TOP w0.102: v1(163.71,69.43) 163.71,69.05 163.28,68.62 163.28,63.61 162.54,62.88 162.54,62.15 160.47,60.08 156.02,60.08 155.51,60.59 145.13,60.59 138.96,54.42 137.32,54.42 135.82,52.92 127.57,52.92 122.37,58.13 121.07,58.13 118.96,60.24 108.78,60.24 107.5,58.95 107.5,54.25 106.42,53.17 92.36,53.17 90.18,50.99 89.65,50.99 87.87,49.21 v1(87.87,48.93) ; v1(219.39,77.3) 219.39,77.25 219.8,76.85 221.17,76.85 222.16,75.86 224.92,75.86 C162.2 227.24,76.18 U16.E13
  IN1 w0.076: v1(219.39,77.3) 219.29,77.2 218.6,77.2 217.19,78.61 213.26,78.61 v1(212.7,79.17)
  IN3 w0.127: v1(163.71,69.43) 164.25,69.96 164.83,69.96 165.13,69.66 171.28,69.66 176.36,74.74 177.35,74.74 179.05,76.44 179.05,77.89 177.45,79.49 177.45,80.1 177.75,80.41 v1(177.93,80.41) 178.23,80.41 179.05,81.23 179.05,84.75 180.68,86.37 184.9,86.37 187.31,88.79 188.12,88.79 189.34,87.57 193.07,87.57 193.79,88.28 200.9,88.28 201.56,88.94 207.17,88.94 211.85,84.26 211.85,80.02 v1(212.7,79.17)
  BOTTOM w0.102: Q11.2 17.71,19.43 18.01,19.73 Q11.1 17.68,20.16 C164.1 17.66,20.94 15.96,22.64 15.96,27.49 17.66,29.2 17.66,31.31 19.42,33.07 19.42,36.72 20.89,38.19 76.46,38.19 87.21,48.93 v1(87.87,48.93)
  BOTTOM w0.152: Q10.3 177.99,81.46 C163.1 178.14,80.62 v1(177.93,80.41)
DP3_DN6: length 104
  TOP w0.102: v1(223.3,63.94) 223.78,63.46 227.4,63.46 228.41,62.45 230.47,62.45 230.7,62.22 v3(233.97,62.22) 234.4,62.22 236.67,59.95 238.32,59.95 238.69,59.58 238.69,57.68 238.97,57.39 240.55,57.39 241.53,56.41 241.53,55.5 242.88,54.16 242.88,50.49 242.22,49.83 242.22,49.39 v1(242.63,48.98) ; v1(223.71,74.51) 223.71,73.9 223.96,73.65 225.12,73.65 C165.2 226.55,73.9 U16.C13
  IN3 w0.081: v1(242.63,48.98) 243.04,48.58 243.04,45.91 242.22,45.1 239.76,45.1 239.67,45.19 231.44,45.19 228.8,45.19 228.36,44.74 218.62,44.74 217.43,45.94 213.43,45.94 211.24,43.75 208.16,43.75 206.99,44.92 205.42,44.92 v1(204.9,45.44)
  BOTTOM w0.102: v1(223.3,63.94) 223.3,64.07 222.74,64.63 222.03,64.63 218.86,67.81 218.86,71.16 222.61,74.92 223.3,74.92 v1(223.71,74.51) ; Q13.2 204.58,48.69 Q13.1 204.58,47.59 204.58,47.31 C167.1 204.31,47.04 204.31,46.03 v1(204.9,45.44) ; v1(242.63,48.98) 242.83,48.78 242.83,48.12 C166.1 244.81,47.56 244.92,47.67 Q12.3
DRV0: length 76.2
  TOP w0.102: U16.L11 229.1,81.27 v1(228.73,81.65)
  IN3 w0.081: v1(228.73,81.65) 228.21,81.65 227.31,80.76 225.8,80.76 225.29,80.24 224.84,79.79 224.84,75.01 224.49,74.66 224.49,74.21 225.37,73.33 225.37,71.23 224.24,70.1 223.82,70.1 223.12,69.4 223.12,67.02 220.98,64.88 219.61,64.88 218.04,63.31 217.26,63.31 216.9,62.95 216.9,61.12 215.81,60.03 211.79,60.03 211.54,59.78 198.18,59.78 197.9,60.06 178.16,60.06 177.3,60.92 v1(177.3,61.25)
  BOTTOM w0.102: v1(177.3,61.25) 177.03,60.98 177.03,60.11 175.4,58.48 v4(175.32,58.48) 175.18,58.34 175.08,58.34 174.1,57.36 J38.7
DRV1: length 78.7
  TOP w0.127: U16.B7 v1(232.71,73.7)
  IN3 w0.081: v1(232.71,73.7) 232.17,73.16 232.17,71.06 231.25,70.14 231.25,69.28 229.6,67.63 228.36,67.63 227.97,67.25 227.97,65.21 225.18,62.42 222.66,62.42 222.01,61.76 222.01,60.67 220.95,59.62 219.57,59.62 218.75,58.79 v1(218.75,58.56) 218.49,58.56 217.53,57.6 217.25,57.6 216.74,57.09 216.74,56.18 215.87,55.31 199.88,55.31 197.05,58.14 176.94,58.14 176.82,58.25 175.09,58.25 174.18,57.34 v1(174.18,55.26)
  BOTTOM w0.102: v1(174.18,55.26) 174.18,55.54 173.62,56.09 171.46,56.09 171.1,56.45 J38.13
DRV2: length 75.7
  TOP w0.127: U16.E6 v1(233.51,76.1)
  IN3 w0.081: v1(233.51,76.1) 233.11,75.7 232.57,75.7 231.58,74.71 231.58,73.65 230.9,72.96 230.9,70.88 230.03,70.01 230.03,69 229.35,68.31 228.25,68.31 227.44,67.5 227.44,66.74 226.84,66.13 226.11,66.13 v1(225.6,65.63) 225.58,65.63 224.59,64.63 224.59,63.67 223.9,62.98 222.14,62.98 221.19,62.03 221.19,60.7 220.72,60.23 218.24,60.23 216.52,58.51 212.56,58.51 212.2,58.15 208.62,58.15 208.04,57.57 207.71,57.57 207.12,58.15 197.73,58.15 197.26,58.62 177.29,58.62 177.12,58.79 174.86,58.79 174.54,58.46 172.67,58.46 172.45,58.25 v1(172.45,58.2)
  BOTTOM w0.102: J38.11 172.1,57.84 v1(172.45,58.2)
DRV3: length 80.2
  TOP w0.127: U16.B6 v1(233.51,73.7)
  IN3 w0.081: v1(174.79,55.23) 174.79,57.67 175.19,58.08 176.34,58.08 176.44,57.97 196.95,57.97 199.87,55.05 217.34,55.05 218.49,56.2 v1(218.49,56.74) 218.48,56.75 218.48,56.86 219.13,57.52 219.13,58.43 220.07,59.37 220.99,59.37 222.26,60.64 222.26,61.66 222.77,62.17 225.18,62.17 228.15,65.14 228.15,65.93 231.43,69.2 231.43,70.07 232.34,70.98 232.34,72.73 233.31,73.7 v1(233.51,73.7)
  BOTTOM w0.102: v1(174.79,55.23) 174.79,55.18 174.33,54.72 172.78,54.72 172.4,55.1 172.4,55.54 172.1,55.84 171.08,55.84 170.6,56.32 J38.14
DRV4: length 72.8
  TOP w0.102: U16.H12 v1(227.95,79.25)
  IN3 w0.081: v1(175.52,59.75) 177.35,59.75 177.77,59.33 197.58,59.33 197.9,59.02 212.03,59.02 212.28,59.27 216.19,59.27 218.75,61.84 219.95,61.84 221.6,63.49 221.6,64.43 224.04,66.86 224.04,67.63 225.15,68.74 225.15,69.76 226.5,71.11 226.5,71.61 226.83,71.94 226.83,75.83 226.91,75.91 226.91,78.07 226.55,78.42 226.55,78.81 226.99,79.25 v1(227.95,79.25)
  BOTTOM w0.102: J38.10 172.6,57.29 172.94,57.62 173.23,57.62 173.48,57.88 v4(173.48,58.46) 173.48,58.5 174.35,59.37 175.23,59.37 175.52,59.66 v1(175.52,59.75)
DRV5: length 102.4
  TOP w0.102: v1(231.15,76.88) 231.15,77.43 230.92,77.66 230.31,77.66 229.93,78.04 U16.G10
  IN3 w0.081: v1(171.38,55.28) 171.38,54.88 172.02,54.24 175.24,54.24 178.16,57.16 192.62,57.16 195.11,54.67 197.29,54.67 200.06,51.9 202.6,51.9 203.79,50.71 203.79,49.64 204,49.44 205.22,49.44 207.87,52.1 215.44,52.1 216.65,53.3 219.11,53.3 221.5,55.69 221.5,56.87 224.2,59.58 226.68,59.58 227.43,60.32 227.43,60.68 228.13,61.38 230.12,61.38 v1(234,65.26) 235.26,66.51 235.26,69.05 235.65,69.44 235.65,70.23 236.07,70.66 236.07,71.63 238.13,73.7 238.13,75.07 237.7,75.5 237.7,76.26 236.18,77.79 232.09,77.79 231.18,76.88 v1(231.15,76.88)
  BOTTOM w0.102: v1(171.38,55.28) 170.85,54.75 169.88,54.75 169.71,54.93 169.71,55.54 169.1,56.14 J38.17
DRV6: length 101.8
  TOP w0.102: U16.G9 v1(230.35,78.45)
  IN3 w0.081: v1(170.8,55.28) 170.8,55.13 171.98,53.95 175.23,53.95 178.28,57 192.5,57 194.48,55.02 194.48,53.86 196.63,51.7 202.47,51.7 203.62,50.56 203.62,49.52 203.87,49.26 205.27,49.26 207.94,51.93 215.76,51.93 216.95,53.12 219.21,53.12 221.68,55.59 221.68,56.82 224.25,59.4 226.76,59.4 227.61,60.25 227.61,60.6 228.15,61.15 230.7,61.15 234.93,65.38 234.93,65.95 235.74,66.76 235.74,67.58 236.07,67.91 v1(236.07,67.96) 235.92,68.11 235.92,69.51 235.82,69.61 235.82,70.05 236.28,70.5 236.28,71.56 238.39,73.67 238.39,75.12 237.93,75.58 237.93,76.31 236.23,78.02 230.79,78.02 v1(230.35,78.45)
  BOTTOM w0.102: J38.15 170.1,56.29 170.8,55.59 v1(170.8,55.28)
DRV7: length 74.7
  TOP w0.102: v1(226.93,78.65) 227.16,78.87 U16.H13
  IN3 w0.081: v1(226.93,78.65) 227.09,78.5 227.09,76.06 227.54,75.6 227.54,71.23 226.17,69.86 226.17,69.46 225.12,68.41 v1(225.12,66.9) 225.12,66.82 224.69,66.39 223.85,66.39 221.85,64.39 221.85,63.49 220.02,61.66 218.83,61.66 216.26,59.09 212.35,59.09 212.11,58.85 197.81,58.85 197.49,59.17 177.63,59.17 177.48,59.32 173.77,59.32 173.66,59.21 172.22,59.21 170.71,57.7 v1(169.88,57.7)
  BOTTOM w0.102: J38.16 169.6,57.41 v1(169.88,57.7)
DRV8: length 89.4
  TOP w0.102: v3(161.77,54.83) 164.67,54.83 165.08,55.24 v1(165.08,55.92)
  TOP w0.127: U16.C6 v1(233.51,74.5)
  IN3 w0.081: v1(165.08,55.92) 166.05,56.88 173.21,56.88 174.94,58.61 177.02,58.61 177.17,58.46 197.19,58.46 199.85,55.8 206.1,55.8 207.4,57.09 207.85,57.09 208.63,57.87 212.2,57.87 212.66,58.33 216.6,58.33 218.32,60.06 220.82,60.06 221.5,60.73 221.5,61.97 222.33,62.8 225,62.8 227.62,65.42 227.62,67.42 228.3,68.11 229.45,68.11 230.23,68.9 230.23,69.94 230.95,70.65 231.17,70.65 231.81,71.28 231.81,74.14 232.55,74.88 233.12,74.88 v1(233.51,74.5)
  BOTTOM w0.102: v1(165.08,55.92) 165.8,55.92 166.1,56.22 J38.23
DRV9: length 81.2
  TOP w0.127: U16.C7 v1(232.71,74.5)
  IN3 w0.081: v1(232.71,74.5) 231.99,73.78 231.99,71.18 231.07,70.27 231.07,69.41 229.55,67.88 228.33,67.88 227.8,67.35 227.8,65.34 225.08,62.62 222.51,62.62 221.75,61.87 221.75,60.72 220.91,59.88 218.4,59.88 216.67,58.15 212.79,58.15 212.28,57.64 210.77,57.64 v1(210.16,57.04) 209.92,56.8 207.36,56.8 206.1,55.55 199.87,55.55 197.12,58.3 177.06,58.3 176.92,58.43 175.02,58.43 172.98,56.4 169.05,56.4 168.21,55.56 v1(168.21,55.28)
  BOTTOM w0.102: v1(168.21,55.28) 168.21,55.75 167.6,56.36 J38.20
DRV10: length 91.3
  TOP w0.127: U16.B5 v1(234.31,73.7)
  IN3 w0.081: v1(164.04,55.89) 164.04,55.56 164.91,54.7 168.46,54.7 168.79,55.03 168.79,55.54 169.27,56.02 172.04,56.02 172.58,55.49 172.58,55.1 172.87,54.81 175.31,54.81 177.99,57.48 192.94,57.48 195.2,55.23 197.54,55.23 199.17,53.61 201.18,53.61 201.89,54.32 218.44,54.32 219.53,55.41 v1(219.53,55.59) 219.53,56.18 219.41,56.3 219.41,56.94 219.74,57.28 219.74,57.9 220.56,58.72 221.19,58.72 223.03,60.56 223.03,60.87 223.54,61.38 225.18,61.38 230.74,66.93 230.74,67.8 233.44,70.5 233.44,71.75 233.51,71.83 233.51,72.76 234.31,73.55 v1(234.31,73.7)
  BOTTOM w0.102: v1(164.04,55.89) 164.04,55.71 164.3,55.46 165.72,55.46 166.6,56.34 J38.22
DRV11: length 87.1
  TOP w0.102: U16.H10 v1(229.55,79.25)
  IN3 w0.081: v1(229.55,79.25) 229.55,78.07 229.93,77.69 229.93,73.34 230.13,73.14 230.13,70.45 229.77,70.08 229.77,69.09 229.21,68.53 228.17,68.53 227.12,67.48 226.54,67.48 225.83,66.77 225.83,66.62 225.32,66.11 225.02,66.11 224.54,65.63 224.54,65.22 223.72,64.41 223.72,63.54 223.34,63.16 222.06,63.16 220.99,62.09 220.99,60.86 220.61,60.49 218.22,60.49 216.42,58.69 212.48,58.69 212.25,58.46 197.71,58.46 197.37,58.8 177.39,58.8 177.23,58.97 174.79,58.97 174.51,58.69 172.35,58.69 170.72,57.06 165.72,57.06 v1(164.44,58.34)
  BOTTOM w0.102: v1(164.44,58.34) 164.92,58.82 165.36,58.82 165.6,58.57 J38.24
DRV12: length 79.8
  TOP w0.102: U16.H11 v1(228.75,79.25)
  IN3 w0.081: v1(228.75,79.25) 228.35,78.85 227.81,78.85 227.26,78.3 227.26,76.16 227.85,75.58 227.85,71.26 226.4,69.81 226.4,69.43 225.59,68.62 225.59,66.7 225.25,66.36 224.94,66.36 224.21,65.63 v1(223.8,65.63) 223.76,65.63 222.06,63.92 222.06,63.44 220.79,62.17 220.79,61 220.53,60.74 218.17,60.74 216.29,58.86 212.4,58.86 212.2,58.66 197.75,58.66 197.43,58.98 177.54,58.98 177.38,59.14 173.85,59.14 173.66,58.95 172.32,58.95 170.63,57.26 168.03,57.26 v1(167.57,57.73)
  BOTTOM w0.102: J38.21 167.1,57.32 167.5,57.73 v1(167.57,57.73)
DRV13: length 84.4
  TOP w0.127: U16.A5 233.93,73.08 v1(234.2,72.81)
  IN3 w0.081: v1(234.2,72.81) 234.59,72.81 234.95,72.45 234.95,72.08 233.97,71.11 233.97,68.95 232.29,67.27 231.33,67.27 225.18,61.12 223.65,61.12 223.29,60.76 223.29,60.43 221.38,58.52 220.72,58.52 220.3,58.09 v1(220.3,55.97) 220.3,55.34 219.05,54.09 202.78,54.09 202.02,53.33 199.02,53.33 197.37,54.98 195.09,54.98 192.75,57.32 178.08,57.32 175.26,54.5 172.86,54.5 172.4,54.95 172.4,55.41 172.02,55.79 169.71,55.79 v1(169.2,55.28)
  BOTTOM w0.102: J38.19 168.1,56.28 169.12,55.26 169.15,55.28 v1(169.2,55.28)
DRV14: length 73.2
  TOP w0.102: v1(227.01,81.14) 227.14,81.27 U16.L13
  IN3 w0.081: v1(178.52,61.35) 178.52,60.67 178.93,60.26 190.43,60.26 191.04,60.87 191.78,60.87 v1(192.18,60.47) 192.41,60.24 197.98,60.24 198.26,59.96 204.6,59.96 204.89,60.25 210.57,60.25 211.17,60.85 213.9,60.85 215.85,62.79 215.85,63.27 217.64,65.06 220.81,65.06 222.95,67.19 222.95,69.48 223.76,70.29 224.16,70.29 225.11,71.24 225.11,73.31 224.32,74.1 224.32,74.74 224.63,75.05 224.63,79.88 225.74,80.99 226.86,80.99 v1(227.01,81.14)
  BOTTOM w0.102: v1(178.52,61.35) 178.55,61.33 178.55,60.64 178.6,60.59 178.6,59.5 177.35,58.26 176.57,58.26 175.6,57.29 J38.4
DRV15: length 84.4
  TOP w0.102: U16.N12 v1(227.95,83.25)
  IN3 w0.081: v1(227.95,83.25) 227.55,83.65 225.82,83.65 223.05,80.89 223.05,78.29 221.47,76.72 221.47,74.84 222.11,74.21 222.11,72.55 221.32,71.77 221.32,69.02 220.53,68.24 220.53,66.64 219.8,65.9 216.06,65.9 214.84,64.68 214.84,63.89 212.53,61.58 211.01,61.58 210.07,62.52 206,62.52 204.17,60.69 198.66,60.69 197.73,61.63 196.19,61.63 195.51,60.95 193.35,60.95 192.67,61.63 190.49,61.63 189.78,60.92 181.55,60.92 180.88,61.58 180.88,62.27 180.5,62.65 180.04,62.65 179.71,62.32 177.71,62.32 177.45,62.57 177,62.57 176.64,62.22 176.64,61.71 176.18,61.25 172.75,61.25 171.56,60.06 170.14,60.06 168.9,58.82 v1(168.9,58.21)
  BOTTOM w0.102: v1(168.9,58.21) 168.6,57.9 J38.18
DRV16: length 3.6
  TOP w0.102: U16.M11 229.13,82.35 228.79,82.69 228.79,83.86 228.09,84.56 R130.2
DRV17: length 5.4
  TOP w0.102: U16.D5 v1(234.31,75.3) ; R132.2 234.51,71.63 v1(233.92,72.22)
  BOTTOM w0.127: v1(233.92,72.22) 233.77,72.38 233.77,73.16 233.91,73.31 233.91,74.9 v1(234.31,75.3)
DRVON: length 111.1
  TOP w0.254: v1(129.88,93.94) 129.88,89.59 v1(129.29,88.99)
  IN1 w0.254: v2(63.13,111.22) 63.13,110.4 63.83,109.71 72.96,109.71 73.02,109.64 87.89,109.64 87.98,109.55 87.98,101.53 88.45,101.05 90.48,101.05 v1(91.47,102.04)
  IN3 w0.203: v1(129.88,93.94) 129.88,94.32 130.54,94.98 130.96,94.98 131.65,95.67 131.65,97.98 132.89,99.23 132.89,99.81 132.49,100.22 127.43,100.22 126.77,100.88 118.78,100.88 118.27,100.37 116.57,100.37 116.21,100.72 110.37,100.72 109.2,101.89 95.44,101.89 95.01,101.46 92.36,101.46 91.88,100.98 91.27,100.98 91.07,101.18 91.07,101.64 v1(91.47,102.04)
  IN3 w0.254: v1(132.34,80.87) 132.34,81.02 131.93,81.42 131.37,81.42 129.41,83.38 129.41,87.24 130.43,88.26 130.43,88.74 130.18,88.99 v1(129.29,88.99)
  BOTTOM w0.203: v1(132.34,80.87) 132.45,80.98 PU405.2 ; v1(129.88,93.94) 129.87,93.95 PR474.1 129.87,95.06 PR475.2
  BOTTOM w0.254: PU403.2 63.5,110.01 63.15,110.35 v4(63.15,110.52) 63.15,111.2 v2(63.13,111.22) ; PU402.2 91.39,102.13 v1(91.47,102.04)
DSWPWROK: length 5.7
  BOTTOM w0.076: U1.BB20 96.58,66.29 96.58,65.72 96.83,65.47 96.83,64.27 97.11,63.99 97.11,63.72 97.82,63 RC67.2
  BOTTOM w0.127: RC67.2 97.82,62.85 98.2,62.47 98.2,61.81 v4(98.41,61.61)
EC_PWRREQ: length 17.5
  TOP w0.102: v1(238.9,74.37) R207.2 239.43,74.89 239.24,75.08 238.18,75.08 237.58,75.67 U16.D1 ; v1(244.29,72.82) 244.35,72.76 246.45,72.76 246.74,72.47 247.34,72.47 248.02,73.15 248.41,73.15 248.54,73.27 248.54,73.71 248.78,73.95 249.11,73.95 249.48,74.33 U21.C7
  IN1 w0.076: v1(244.29,72.82) 243.79,72.82 243.52,72.55 242.3,72.55 241.89,72.15 240.12,72.15 239.68,72.58 239.68,73.39 238.9,74.17 v1(238.9,74.37)
EC_SCL2: length 141
  TOP w0.102: R167.2 227.67,66.81 229.35,65.14 v1(229.35,64.02) ; RC27.1 114.03,79.79 v1(113.29,80.53)
  IN1 w0.076: v1(229.35,64.02) 228.79,64.58 226.32,64.58 226.09,64.81 216.24,64.81 215.86,65.19 215.1,65.19 214.49,65.8 213.95,65.8 213.42,65.26 211.08,65.26 210.37,64.55 206.99,64.55 206.59,64.96 200.9,64.96 200.21,65.65 186.34,65.65 185.88,66.11 182.88,66.11 181.64,67.35 181.64,67.69 181.08,68.25 179.19,68.25 178.85,67.91 165.69,67.91 165.36,68.24 163.43,68.24 162.52,69.15 157.57,69.15 157.2,68.79 146.99,68.79 146.57,68.36 144.98,68.36 143.82,69.52 142.8,69.52 142.3,70.01 142.3,73.16 141.18,74.28 135.34,74.28 130.95,78.68 123.43,78.68 122.89,79.21 118.81,79.21 118.07,79.95 113.88,79.95 v1(113.29,80.53)
  BOTTOM w0.076: U1.W3 106.24,79.18 106.4,79.18 106.59,79.25 106.78,79.25 106.91,79.21 107.16,79.21 107.4,79.31 107.93,79.31
  BOTTOM w0.102: v1(113.29,80.53) v3(112.78,80.01) 112.36,79.6 108.22,79.6 107.93,79.31
EC_SDA2: length 141.7
  TOP w0.102: R165.2 228.25,67.63 228.13,67.5 228.13,66.81 229.93,65.01 v1(229.93,63.99) ; RC28.1 114.45,80.56 v1(113.9,80.56)
  IN1 w0.076: v1(229.93,63.99) 229.93,64.3 229.33,64.9 226.46,64.9 226.32,65.04 216.49,65.04 215.4,66.13 214.03,66.13 213.52,65.62 211.08,65.62 210.32,64.86 207.07,64.86 206.44,65.49 201.66,65.49 201.24,65.92 189.96,65.92 189.39,66.48 187.3,66.48 187.08,66.26 182.98,66.26 181.8,67.45 181.8,67.75 181.11,68.44 179.1,68.44 178.72,68.06 165.77,68.06 165.44,68.39 163.51,68.39 162.54,69.35 157.39,69.35 157.01,68.97 146.82,68.97 146.36,68.52 145.14,68.52 143.82,69.84 143.14,69.84 142.63,70.34 142.63,73.19 141.39,74.43 135.54,74.43 131.12,78.85 123.53,78.85 123.01,79.37 118.94,79.37 118.22,80.1 114.36,80.1 v1(113.9,80.56)
  BOTTOM w0.076: U1.V3 105.99,79.38 106.46,79.38 106.56,79.42 106.8,79.42 106.93,79.38 107.13,79.38 107.37,79.48 107.7,79.48 108.16,79.95
  BOTTOM w0.102: 108.16,79.95 108.32,80.1 v4(110.24,80.1) 112.24,80.1 113.1,80.96 113.5,80.96 v1(113.9,80.56)
EC_SPKR: length 160.8
  TOP w0.102: v1(262.49,52.75) 262.49,55.87 262.23,56.13 262.23,59.12 262.99,59.89 262.99,62.02 v3(263.35,62.37) 263.35,63.72 262,65.07 262,69.13 261.34,69.79 260.89,69.79 260.58,70.1 v1(260.43,70.1) ; U16.J8 v1(231.15,80.05) ; D740.2 282.54,54.3 v1(282.68,54.17) ; v1(221.04,80.91) 221.24,80.71 R490.1
  IN3 w0.081: v1(260.43,70.1) 260.43,70.25 260.96,70.78 263.53,70.78 268.15,75.4 277.19,75.4 278.46,76.67 278.46,78.63 278.21,78.88 278.21,80.13 276.46,81.88 276.46,82.19 273.2,85.44 263.09,85.44 262.54,84.88 v1(262.54,84.24)
  IN4 w0.076: v1(221.04,80.91) 221.04,78.76 220.55,78.27 220.55,77 222.35,75.2 222.35,74.13 222.91,73.58 226.62,73.58 228.09,72.1 229.64,72.1 231.04,70.71 234.77,70.71 237.34,73.27 237.95,73.27 238.63,73.96 239.24,73.96 239.57,74.29 239.57,80.81 241.05,82.29 242.34,82.29 244.91,84.85 244.91,86.43 246.13,87.65 246.56,87.65 247.27,86.94 249.35,86.94 250.39,85.89 261.44,85.89 262.54,84.8 v1(262.54,84.24) ; v1(262.49,52.75) 262.94,52.75 263.98,51.71 275.64,51.71 277.52,53.59 278.18,53.59 278.49,53.89 280.47,53.89 280.75,54.17 v1(282.68,54.17)
  BOTTOM w0.102: v1(231.15,80.05) 230.76,79.66 229.33,79.66 229.14,79.84 229.14,80.2 228.86,80.48 224.95,80.48 224.39,81.04 221.17,81.04 v1(221.04,80.91)
ECSPI_CLK: length 18.4
  TOP w0.102: U16.J9 230.73,79.71 v1(230.36,80.08) ; R261.2 245.89,81.18 v1(245.3,80.58)
  IN1 w0.076: v1(230.36,80.08) 230.77,79.67 231.68,79.67 232.47,80.45 236.64,80.45 237.25,79.84 239.51,79.84 239.71,80.05 240.78,80.05 241.74,79.08 242.59,79.08 243.29,79.78 244.5,79.78 v1(245.3,80.58)
ECSPI_CLK_R: length 3.7
  TOP w0.102: R261.1 246.14,79.98 C259.1 246.17,79.36 R268.2 246.68,78.85 247.62,78.85 U21.H9
ECSPI_MISO: length 21.7
  TOP w0.102: R264.2 247.66,82.41 247.48,82.59 245.83,82.59 245.27,83.15 v4(245.02,83.15) 244.92,83.04 244.43,83.04 244.08,82.69 244.08,82.44 243.68,82.04 243.68,81.66 243.37,81.34 241.51,81.34 241.46,81.29 v1(241.44,81.29) ; U16.K8 v1(231.15,80.85)
  IN1 w0.076: v1(231.15,80.85) 231.52,80.85 231.91,81.24 236.97,81.24 237.55,80.66 238.5,80.66 238.91,80.25 241.81,80.25 242.33,80.77 242.33,81.1 242.09,81.34 241.49,81.34 v1(241.44,81.29)
ECSPI_MISO_R: length 4.9
  TOP w0.102: U21.G7 249.75,77.54 v1(249.38,77.91) ; R264.1 v1(247.66,81.02)
  BOTTOM w0.102: v1(249.38,77.91) 247.66,79.63 v1(247.66,81.02)
ECSPI_MOSI: length 19.9
  TOP w0.102: U16.K9 v1(230.35,80.85) ; R262.2 v4(246.13,82.19) 245.65,82.19 245.02,82.82 244.54,82.82 244.31,82.59 244.31,82.32 243.92,81.93 243.92,81.57 243.47,81.11 242.1,81.11 v1(241.92,80.94)
  IN1 w0.076: v1(230.35,80.85) 230.77,81.27 231.33,81.27 232.14,82.08 236.38,82.08 237.58,80.89 238.67,80.89 238.97,80.58 241.56,80.58 v1(241.92,80.94)
ECSPI_MOSI_R: length 4.1
  TOP w0.102: R262.1 247.02,81.6 v4(247.02,80.78) 248.5,79.31 248.5,78.77 U21.H8
EDP_AUXN: length 64.6
  IN1 w0.089: v1(81.38,86.69) 81.38,86.55 81.2,86.38 81.08,86.38 80.88,86.58 80.88,86.89 81.1,87.11 81.61,87.11 81.67,87.05 82.79,87.05 83.04,87.3 84.39,87.3 84.69,86.99 90.08,86.99 90.3,87.21 91.04,87.21 92.96,89.13 94.87,89.13 102.79,97.05 107.79,97.05 110.09,99.35 116.73,99.35 117.32,98.77 118.78,98.77 119.64,97.9 120.33,97.9 121.78,99.36 125.86,99.36 127.18,98.04 130.28,98.04 130.53,98.29 132.82,98.29 134.51,99.98 134.51,100.16 134.62,100.27 134.62,100.39 134.71,100.47 v1(134.81,100.47)
  BOTTOM w0.076: v1(81.38,86.69) 81.4,86.67 U1.E45
  BOTTOM w0.102: C9.1 134.64,100.83 134.64,100.65 v1(134.81,100.47)
EDP_AUXN_CONN: length 6.1
  BOTTOM w0.102: C9.2 134.63,101.78 134.63,102.15 134.13,102.64 130.26,102.64 130.05,102.85 130.05,102.94 130.15,103.04 J10.10
EDP_AUXP: length 64.7
  IN1 w0.089: v1(81.35,85.94) 81.11,86.19 81,86.19 80.69,86.5 80.69,86.97 81.02,87.3 81.69,87.3 81.75,87.24 82.71,87.24 82.96,87.49 84.46,87.49 84.77,87.18 90,87.18 90.22,87.4 90.96,87.4 92.88,89.32 94.79,89.32 102.71,97.24 107.72,97.24 110.01,99.54 116.81,99.54 117.4,98.96 118.86,98.96 119.72,98.09 120.25,98.09 121.7,99.55 125.94,99.55 127.26,98.23 130.2,98.23 130.45,98.48 132.74,98.48 134.32,100.06 134.32,100.38 v1(134.22,100.47)
  BOTTOM w0.076: v1(81.35,85.94) 81.75,85.78 81.82,85.75 U1.F45
  BOTTOM w0.102: v1(134.22,100.47) 134.43,100.68 134.43,100.83 C10.1
EDP_AUXP_CONN: length 6.1
  BOTTOM w0.102: J10.9 129.75,103.01 129.85,102.91 129.85,102.76 130.18,102.43 134.05,102.43 134.42,102.06 134.42,101.79 C10.2
EDP_COMP: length 2
  TOP w0.127: v1(77.71,86.69) 77.68,86.66 RC1.1
  BOTTOM w0.127: v1(77.71,86.69) 78,86.4 U1.E52
EDP_HPD: length 53.9
  TOP w0.102: v1(113.5,82.97) 114.16,83.63 116.9,83.63 v3(117.47,84.2) 119.52,86.25 124.13,86.25 125.1,87.22 129.19,87.22 131.02,89.05 131.02,90.03 130.61,90.44 130.61,93.13 132.22,94.74 132.22,98.02 133.45,99.25 134.49,99.25 135.26,100.02 135.26,101.19 133.45,102.99 v1(133.45,104.51)
  BOTTOM w0.102: U1.L10 102.33,83.46 104.83,83.46 105.07,83.23 105.07,82.25 105.35,81.96 107.16,81.96 107.45,82.25 107.88,82.25 108.34,82.71 108.95,82.71 109.15,82.51 v3(109.76,82.51) RC4.1 111.25,81.98 112.51,81.98 v1(113.5,82.97)
  BOTTOM w0.203: J10.18 133.35,104.41 v1(133.45,104.51)
EDP_TXN0: length 63.6
  IN1 w0.089: v1(133.06,100.34) 133.15,100.25 133.15,99.73 132.49,99.06 131.32,99.06 130.24,100.14 121.28,100.14 120.35,99.21 119.62,99.21 118.68,100.15 108.8,100.15 107.89,99.24 102.84,99.24 101.19,97.59 101.19,96.56 96.21,91.58 92.68,91.58 91.36,90.26 91.36,88.7 90.89,88.23 82.03,88.23 81.04,89.22 v1(80.86,89.22)
  BOTTOM w0.076: v1(80.86,89.22) 80.68,89.04 80.68,88.28 80.39,87.99 U1.C47
  BOTTOM w0.102: C12.1 133.27,100.69 133.27,100.55 v1(133.06,100.34)
EDP_TXN0_CONN: length 6.2
  BOTTOM w0.102: J10.6 128.55,102.91 128.65,102.82 128.65,102.69 128.86,102.48 129.37,102.48 129.98,101.87 v2(132.13,101.87) 133.2,101.87 133.28,101.79 133.28,101.67 C12.2
EDP_TXN1: length 67.7
  IN1 w0.089: v1(131.82,99.64) 131.95,99.77 131.95,100.87 131.66,101.16 128.4,101.16 127.81,100.58 118.57,100.58 117.91,101.24 116.92,101.24 116.26,100.57 108.64,100.57 107.76,99.69 102.61,99.69 101.8,98.89 99,98.89 98.18,98.07 98.18,96.86 97.8,96.48 97.23,96.48 95.97,95.22 95.97,93.89 94.83,92.75 92.18,92.75 89.32,89.89 87.29,89.89 86.5,89.1 82.5,89.1 81.17,90.43 81.17,90.94 81.22,90.99 81.22,91.16 v1(80.98,91.39)
  BOTTOM w0.076: v1(80.98,91.39) 80.77,91.61 80.65,91.61 80.49,91.45 80.49,91.16 80.62,91.03 80.62,90.68 81.95,89.35 81.95,88.94 81.93,88.92 81.91,88.87 81.91,88.72 81.96,88.59 81.96,88.44 81.81,87.91 81.81,87.75 81.78,87.67 81.61,87.5 U1.D46
  BOTTOM w0.102: C14.1 132.03,100.11 132.03,99.84 v1(131.82,99.64)
EDP_TXN1_CONN: length 6.4
  BOTTOM w0.102: J10.3 127.35,102.92 127.45,102.82 127.45,102.63 127.68,102.4 128.06,102.4 128.52,101.94 129.11,101.94 129.8,101.26 v2(130.68,101.26) 131.91,101.26 132,101.18 132,101.08 C14.2
EDP_TXP0: length 63.6
  IN1 w0.089: v1(81.04,88.66) 81.32,88.66 81.95,88.04 90.97,88.04 91.55,88.62 91.55,90.18 92.76,91.39 96.29,91.39 101.38,96.48 101.38,97.51 102.92,99.05 107.97,99.05 108.88,99.96 118.6,99.96 119.54,99.02 120.43,99.02 121.36,99.95 130.16,99.95 131.24,98.87 132.56,98.87 133.34,99.65 133.34,100 133.45,100.12 133.45,100.25 133.54,100.34 v1(133.65,100.34)
  BOTTOM w0.076: U1.C46 80.96,87.87 81.03,87.8 81.12,87.8 81.26,87.95 81.26,88.3 81.04,88.53 v1(81.04,88.66)
  BOTTOM w0.102: v1(133.65,100.34) 133.48,100.51 133.48,100.69 C11.1
EDP_TXP0_CONN: length 6.2
  BOTTOM w0.102: C11.2 133.48,101.62 133.48,101.88 133.29,102.07 130.06,102.07 129.46,102.68 128.95,102.68 128.86,102.78 128.86,102.89 128.95,102.98 J10.7
EDP_TXP1: length 67.6
  IN1 w0.089: v1(132.41,99.64) 132.15,99.91 132.15,100.94 131.74,101.35 128.32,101.35 127.74,100.77 118.65,100.77 117.99,101.43 116.84,101.43 116.18,100.76 108.56,100.76 107.68,99.88 102.53,99.88 101.73,99.08 98.92,99.08 97.99,98.15 97.99,96.94 97.72,96.67 97.15,96.67 95.78,95.3 95.78,93.97 94.75,92.94 92.1,92.94 89.24,90.08 87.21,90.08 86.42,89.29 82.57,89.29 81.36,90.51 81.36,90.86 81.41,90.91 81.41,91.56 81.01,91.96 v1(81.01,91.98)
  BOTTOM w0.076: U1.C45 81.62,87.99 81.74,88.29 81.79,88.46 81.79,88.56 81.74,88.68 81.74,88.9 81.78,88.99 81.78,89 81.79,89.02 81.79,89.28 80.46,90.61 80.46,90.96 80.33,91.09 80.33,91.52 80.58,91.77 80.81,91.77 v1(81.01,91.98)
  BOTTOM w0.102: C13.1 132.24,100.14 132.24,99.81 v1(132.41,99.64)
EDP_TXP1_CONN: length 6.4
  BOTTOM w0.102: C13.2 132.21,101.11 132.21,101.26 132,101.47 129.88,101.47 129.2,102.15 128.6,102.15 128.14,102.61 127.76,102.61 127.65,102.72 127.65,102.83 127.75,102.92 J10.4
EN_+1.8VS: length 4.8
  TOP w0.203: PD701.2 138.85,69.38 v1(139.07,69.61)
  BOTTOM w0.203: PU706.5 139,70.76 PR718.1 138.36,70.71 PR762.1 138.24,70.61 PC794.1 138.24,69.86 138.49,69.61 v1(139.07,69.61)
FAN_FRQ: length 245.1
  TOP w0.127: U16.D6 v1(233.51,75.3)
  IN1 w0.076: v1(90.92,44.34) 91.5,44.92 91.5,48.02 94.42,50.94 95.92,50.94 96.99,49.87 188.5,49.87 191.47,46.9 v1(194.17,46.9) ; v1(233.51,75.3) 233.92,74.88 233.92,74.23 234.1,74.05 234.5,74.05 234.98,73.57 234.98,72.12 233.94,71.08 233.94,69.13 233.54,68.72 229.35,68.72 228.74,69.33 228.74,69.96 228.3,70.4 226.37,70.4 224.88,71.89 223.01,71.89 221.94,72.96 221.34,72.96 221.01,72.63 221.01,72.2 221.19,72.02 221.19,69.63 220.38,68.82 217.61,68.82 216.9,69.53 214.94,69.53 213.57,68.16 206.05,68.16 205.77,68.44 205.77,71.13 205.57,71.34 205.19,71.34 203.92,70.07 203.92,67.86 v1(203.21,67.14)
  IN3 w0.081: v1(90.92,44.34) 90.18,44.34 88.69,45.82 58.26,45.82 45.53,58.56 v1(45.53,60.44)
  BOTTOM w0.102: v1(194.17,46.9) 194.19,46.93 194.19,47.76 196.88,50.45 198.03,50.45 198.46,50.88 198.46,52.05 199.12,52.71 199.12,60.16 200.54,61.58 201.3,61.58 203.49,63.78 203.49,66.86 v1(203.21,67.14) ; J15.2 46.24,65.01 46.54,64.71 46.54,63.49 45.53,62.47 v1(45.53,60.44)
FAN_ID: length 245.9
  TOP w0.102: R159.1 239.61,84.61 239.61,84.16 v1(237.78,82.33) 237.52,82.07 U16.M1
  IN1 w0.076: v1(237.78,82.33) 236.51,83.6 234.93,83.6 234.38,84.16 232.9,84.16 231.76,83.02 230.29,83.02 229.93,83.37 228.74,83.37 228.22,82.86 226.87,82.86 226.76,82.97 223.3,82.97 222.31,81.98 216.62,81.98 216.07,81.43 211.1,81.43 207.58,77.91 v1(207.2,77.91) ; v1(194.78,46.75) 194.52,46.49 192.64,46.49 192.59,46.54 191.6,46.54 188.43,49.72 96.82,49.72 95.81,50.74 94.52,50.74 91.7,47.92 91.7,44.51 v1(90.94,43.75)
  IN3 w0.081: v1(90.94,43.75) 90.33,43.75 88.55,45.53 58.23,45.53 45.02,58.74 v1(45.02,60.06)
  BOTTOM w0.102: v1(194.78,46.75) 195.16,47.13 195.16,48.15 197.03,50.02 198.21,50.02 198.9,50.72 198.9,51.92 199.63,52.64 199.63,60.06 200.27,60.7 201.13,60.7 204.12,63.69 204.12,65.31 206.36,67.55 206.36,70.85 206.28,70.93 206.28,75.73 207.2,76.64 v1(207.2,77.91) ; v1(45.02,60.06) 45.02,62.37 46.31,63.66 46.31,64.38 46.18,64.51 J15.1
FAN_ON: length 234.4
  TOP w0.102: U16.N9 230.9,83.04 230.9,83.93 v1(230.97,84.01)
  IN1 w0.076: v1(194.72,47.35) 193.16,47.35 193.05,47.46 191.14,47.46 188.58,50.02 97.12,50.02 96,51.14 94.32,51.14 90.94,47.76 v1(90.94,44.97) ; v1(230.97,84.01) 230.82,84.01 230.38,84.44 229.78,84.44 229.3,83.96 228.79,83.96 228.66,84.09 224.01,84.09 222.31,82.38 216.57,82.38 215.87,81.69 210.68,81.69 v1(207.44,78.45)
  IN3 w0.081: v1(90.94,44.97) 89.9,44.97 88.68,46.19 58.25,46.19 46.03,58.41 46.03,60.87 v1(45.98,60.93)
  BOTTOM w0.102: v1(194.72,47.35) 194.72,48.01 196.97,50.25 198.12,50.25 198.66,50.8 198.66,51.96 199.37,52.67 199.37,60.11 200.51,61.24 201.32,61.24 203.9,63.82 203.9,65.49 206.16,67.75 206.16,70.7 206.08,70.78 206.08,75.86 206.79,76.57 206.79,78.1 207.13,78.45 v1(207.44,78.45) ; J15.5 46.13,66.51 46.8,65.85 46.8,63.36 45.91,62.47 45.91,60.99 v1(45.98,60.93)
FLIP: length 4
  TOP w0.076: 25.57,45.76 v4(25.7,45.9) 26.23,46.42 26.23,47.51 U5.G10
  TOP w0.102: R571.2 25.49,45.02 R576.2 25.49,45.68 25.57,45.76
GSENSE_INT: length 103.5
  TOP w0.102: U16.K2 v1(236.71,80.85)
  TOP w0.152: U17.11 173.3,90.2 173.59,90.49 174.86,90.49 175.62,91.25 175.62,91.96 173.92,93.66 167.9,93.66 v1(167.19,94.37)
  IN4 w0.152: v1(223.61,88.91) 223.58,88.94 223.58,90.22 219.22,94.58 208.21,94.58 206.79,96 199.81,96 196.12,99.68 170.02,99.68 167.29,96.95 167.29,94.47 v1(167.19,94.37)
  BOTTOM w0.152: v1(236.71,80.85) 236.71,82.17 238.01,83.48 238.01,87.06 235.34,89.72 225.54,89.72 224.81,89 224.81,88.75 224.6,88.53 223.94,88.53 223.61,88.86 v1(223.61,88.91)
HDA_BCLK: length 233.1
  TOP w0.102: v1(268.74,59.04) 268.33,59.04 267.95,58.66 RA163.1 267.65,58.76 268.18,59.3 268.18,59.65 268.68,60.14 UA1.13
  IN1 w0.076: v1(268.74,59.04) 268.69,58.99 268.69,57.75 268.89,57.54 269.91,57.54 271.18,58.81 271.18,62.37 270.21,63.33 265.46,63.33 263.94,61.81 263.94,55.7 261.01,52.77 257.7,52.77 255.65,50.73 255.65,49.04 251.76,45.15 228.1,45.15 227.97,45.02 215.88,45.02 211.36,49.54 208.82,49.54 205.72,46.44 204.2,46.44 203.13,45.37 202.38,45.37 201.04,46.7 195.9,46.7 194.39,45.19 189.85,45.19 189.58,45.47 189.58,46.89 187.87,48.6 95.82,48.6 95.49,48.27 94.73,48.27 94.57,48.42 93.71,48.42 93,47.71 93,47.23 92.58,46.82 v1(92.58,46.07)
  BOTTOM w0.102: RC40.1 CC5.1 96.24,61.38 94.6,61.38 94.34,61.63 92.87,61.63 91.04,59.8 91.04,48.83 92.62,47.26 92.62,46.1 v1(92.58,46.07)
HDA_BCLK_R: length 6.8
  BOTTOM w0.076: 94.32,65.72 94.92,66.32 94.92,66.6 94.97,66.72 94.97,66.86 94.91,67.09 94.91,67.21 94.98,67.42 95.08,67.53 95.18,67.64 U1.AY22
  BOTTOM w0.102: 94.32,65.72 94.25,65.65 94.25,64.16 94.98,63.44 v4(95.05,63.44) 95.75,63.44 RC40.2
HDA_SDIN0: length 225
  TOP w0.102: v1(269.68,58.23) 269.76,58.15 270.27,58.15 270.55,58.44 UA1.16
  IN1 w0.076: v1(269.68,58.23) 269.68,58.58 269.22,59.04 269.22,59.45 269.48,59.7 270.19,59.7 270.54,60.06 270.54,62.04 269.91,62.67 265.82,62.67 264.58,61.43 264.58,55.42 261.26,52.11 257.94,52.11 256.34,50.5 256.34,48.4 252.4,44.46 228.46,44.46 228.18,44.19 212.38,44.19 211.9,43.7 208.72,43.7 207.84,44.58 189.3,44.58 188.86,45.02 188.86,46.7 187.56,47.99 96.45,47.99 95.95,47.48 v1(94.14,47.48)
  BOTTOM w0.076: 97.24,62.27 97.24,63.05 96.08,64.22 v4(96.08,64.43) 96.08,65.51 95.75,65.84 U1.BA21
  BOTTOM w0.102: v1(94.14,47.48) 94.14,47.94 92.16,49.92 92.16,57.19 92.95,57.98 96.22,57.98 96.9,58.66 97.67,58.66 97.8,58.79 97.8,60.34 97.24,60.9 97.24,62.27
HDA_SDO: length 228.6
  TOP w0.102: v1(269.1,58.05) 268.89,57.85 268.33,57.85 268.03,57.54 267.95,57.54 267.56,57.15 C9142.2 268.04,57.12 268.54,57.62 269.91,57.62 v4(270.01,57.72) 270.14,57.85 270.34,57.85 270.95,58.46 UA1.17
  IN1 w0.076: v1(269.1,58.05) 269.33,57.82 269.83,57.82 270.98,58.97 270.98,62.22 270.09,63.11 265.64,63.11 264.14,61.61 264.14,55.6 261.11,52.57 257.8,52.57 255.86,50.63 255.86,48.81 251.96,44.92 228.18,44.92 228.08,44.82 215.73,44.82 211.21,49.34 208.92,49.34 205.77,46.19 204.25,46.19 203.23,45.16 202.25,45.16 200.97,46.45 195.98,46.45 194.52,44.99 189.63,44.99 189.37,45.25 189.37,46.8 187.77,48.4 96.07,48.4 95.61,47.94 94.65,47.94 94.45,48.15 93.79,48.15 93.23,47.59 v1(93.23,46.7)
  BOTTOM w0.102: v1(93.23,46.7) 93.23,47.46 91.47,49.21 91.47,58.2 93.08,59.81 RC41.1
HDA_SDO_R: length 13.7
  TOP w0.102: v1(94.65,65.34) 94.29,64.99 94.29,62.93 93.87,62.5 TP2.1 93.87,61.03 94.44,60.46 RC37.2
  BOTTOM w0.102: U1.BB22 95.11,66.42 95.11,65.8 v1(94.65,65.34) 94.65,64.4 95.36,63.69 96.07,63.69 96.78,62.98 96.78,60.77 96.42,60.41 RC41.2
HDA_SYNC: length 214.5
  TOP w0.102: v1(269.66,59.19) 269.45,59.19 269.28,59.37 UA1.14
  IN1 w0.076: v1(269.66,59.19) 269.97,59.19 270.75,59.97 270.75,62.12 269.99,62.88 265.74,62.88 264.37,61.51 264.37,55.52 261.2,52.35 257.88,52.35 256.07,50.53 256.07,48.64 252.12,44.69 228.38,44.69 228.08,44.39 215.93,44.39 215.8,44.52 212.16,44.52 211.56,43.93 208.8,43.93 207.94,44.79 189.45,44.79 189.09,45.15 189.09,46.77 187.66,48.2 96.33,48.2 95.84,47.71 94.55,47.71 94.37,47.89 93.86,47.89 93.66,47.69 v1(93.66,47.15)
  BOTTOM w0.102: RC39.1 96.24,58.49 v4(96.12,58.36) 96.09,58.39 92.9,58.39 91.91,57.39 91.91,49.57 93.66,47.81 v1(93.66,47.15)
HDA_SYNC_R: length 15.9
  TOP w0.102: v1(95.54,64.1) 95.21,64.1 95.07,64.24 95.07,64.63 94.95,64.75 94.7,64.75 94.57,64.62 94.57,61.33 95.11,60.79 95.11,60.4 RC38.1
  BOTTOM w0.076: U1.BA22 95.45,66.88 95.45,65.71 95.11,65.37 95.11,64.53 v1(95.54,64.1)
  BOTTOM w0.102: RC39.2 96.83,59.62 v4(97.42,60.21) 97.42,60.36 97.01,60.77 97.01,63.03 95.94,64.1 v1(95.54,64.1)
HDMI_CLKN: length 53.9
  TOP w0.102: R309.1 18.6,33.62 L7.4 18.81,33.41 19.39,33.41 v2(19.76,33.78) 20.28,34.3 20.28,34.77 23.31,37.81 27.52,37.81 35.36,45.65 35.36,63.86 33.63,65.59 33.63,70.51 34.94,71.82 37.24,71.82 37.44,71.62 38.07,71.62 38.17,71.71 U147.24
HDMI_CLKN_CONN: length 7.7
  TOP w0.102: R309.2 17.36,33.62 L7.3 17.05,33.31 16.7,33.31 R9121.1 16.17,33.34 15.7,33.34 15.55,33.49 D51.9 D51.1 14.1,33.49 13.95,33.34 13.41,33.34 v2(13.19,33.12) 12.94,32.87 12.94,32.06 12.44,31.55 12.25,31.55 J43.12
HDMI_CLKP: length 53.9
  TOP w0.102: U147.25 38.17,71.31 38.07,71.41 37.36,71.41 37.15,71.61 35.02,71.61 33.83,70.43 v2(33.83,68.48) 33.83,65.68 35.57,63.94 35.57,45.56 27.6,37.6 23.4,37.6 20.49,34.69 20.49,34.22 19.48,33.2 18.79,33.2 L7.1 18.6,33.01 R310.1
HDMI_CLKP_CONN: length 7.7
  TOP w0.102: J43.10 12.25,31.35 12.52,31.35 13.15,31.97 13.15,32.78 13.5,33.13 13.93,33.13 14.07,32.99 D51.2 D51.8 15.53,32.99 15.67,33.13 15.96,33.13 R9121.2 16.84,33.1 17.27,33.1 L7.2 17.36,33.01 R310.2
HDMI_DATA0N: length 51.7
  TOP w0.102: U147.27 38.17,70.51 38.07,70.42 37.54,70.42 36.87,69.74 36.13,69.74 35.38,68.99 35.38,64.8 35.97,64.21 35.97,45.37 27.75,37.15 23.62,37.15 20.91,34.44 20.91,33.64 v2(19.59,32.32) 19.22,31.95 18.77,31.95 L9.4 18.6,32.12 R318.1
HDMI_DATA0N_CONN: length 9.2
  TOP w0.102: 17.73,32.12 17.36,32.12 L9.3 17.28,32.12 16.76,31.6 16.69,31.6 R9125.1 16.16,31.61 15.99,31.61 15.76,31.84 15.48,31.84 15.32,32 15.18,32 D51.7 D51.4 14.28,32.02 14.11,32.02 13.96,31.87 13.71,31.87 13.39,31.56 v2(13.39,31.33) 13.39,30.57 12.94,30.11 12.71,30.11 12.37,30.45 J43.9
HDMI_DATA0P: length 51.7
  TOP w0.102: U147.28 38.17,70.11 38.07,70.21 37.63,70.21 36.95,69.53 36.22,69.53 35.59,68.9 v2(35.59,67.15) 35.59,64.89 36.18,64.29 36.18,45.29 27.83,36.94 23.7,36.94 21.12,34.35 21.12,33.55 19.3,31.74 18.83,31.74 18.61,31.52 L9.1 18.6,31.51 R316.1
HDMI_DATA0P_CONN: length 9.2
  TOP w0.102: J43.7 12.2,29.45 12.65,29.9 13.02,29.9 13.6,30.48 13.6,31.47 13.79,31.66 13.95,31.66 14.1,31.52 14.28,31.52 D51.5 D51.6 15.2,31.52 15.41,31.52 15.52,31.63 15.67,31.63 15.9,31.4 15.94,31.4 16.39,30.95 R9125.2 16.42,30.96 16.98,31.52 L9.2 17.36,31.51 17.73,31.51
HDMI_DATA1N: length 53.6
  TOP w0.102: U147.29 38.34,69.71 38.29,69.66 37.68,69.66 36.57,68.56 36.57,67.82 36.02,67.27 36.02,65.4 36.59,64.84 v2(36.59,54.59) 36.59,45.1 28,36.51 23.9,36.51 21.57,34.19 21.57,30.33 21.17,29.93 18.86,29.93 L8.4 18.6,30.19 R313.1
HDMI_DATA1N_CONN: length 7.3
  TOP w0.102: J43.6 11.85,28.81 12.17,28.49 12.52,28.49 12.68,28.65 12.68,28.98 v2(13.31,29.61) 13.61,29.91 13.96,29.91 14.13,30.09 14.3,30.09 D52.1 D52.9 15.18,30.09 15.53,30.09 15.7,29.91 16.19,29.91 R9123.1 16.64,29.91 17.05,29.91 17.32,30.19 L8.3 17.36,30.19 R313.2
HDMI_DATA1P: length 53.6
  TOP w0.102: U147.30 38.3,69.31 38.16,69.45 37.76,69.45 36.78,68.47 36.78,67.73 36.23,67.18 36.23,65.49 36.8,64.92 36.8,45.02 28.08,36.3 23.98,36.3 21.78,34.1 21.78,30.25 21.26,29.73 v2(19.7,29.73) 18.75,29.73 L8.1 18.6,29.58 R311.1
HDMI_DATA1P_CONN: length 7.3
  TOP w0.102: R311.2 17.36,29.58 L8.2 17.24,29.7 16.9,29.7 R9123.2 15.94,29.7 15.64,29.7 15.53,29.59 D52.8 D52.2 14.09,29.59 13.98,29.71 13.7,29.71 12.89,28.9 12.89,28.57 12.61,28.28 12.18,28.28 J43.4
HDMI_DATA2N: length 53.1
  TOP w0.102: R320.1 18.6,28.69 L10.4 18.81,28.49 19.16,28.49 19.52,28.13 20.36,28.13 22.74,30.5 22.74,34.42 24.21,35.9 28.26,35.9 37.24,44.87 v2(37.24,49.34) 37.24,65.09 37.77,65.62 37.77,68.19 38,68.42 38.32,68.42 38.41,68.51 U147.32
HDMI_DATA2N_CONN: length 10
  TOP w0.102: J43.3 10.65,27.34 11.27,26.72 11.27,26.62 11.62,26.28 12.28,26.28 13.24,27.24 v2(13.24,27.64) 13.24,28.18 13.65,28.59 13.79,28.59 13.79,28.59 D52.4 D52.7 15.18,28.59 15.45,28.59 15.8,28.24 15.8,28.06 15.96,27.9 16.06,27.9 R9127.1 16.6,28.08 16.72,28.08 17.33,28.69 L10.3 17.36,28.69 R320.2
HDMI_DATA2P: length 53.1
  TOP w0.102: U147.33 38.31,68.11 38.21,68.21 38.08,68.21 37.97,68.1 37.97,65.53 37.45,65.01 37.45,44.78 28.35,35.69 24.3,35.69 22.95,34.34 22.95,30.42 20.45,27.92 19.79,27.92 v2(19.73,27.87) 19.68,27.92 19.43,27.92 19.07,28.28 18.8,28.28 L10.1 18.6,28.08 R323.1
HDMI_DATA2P_CONN: length 9.9
  TOP w0.102: J43.1 10.65,26.15 10.86,25.95 11.01,25.95 11.24,26.17 11.42,26.17 11.53,26.07 12.36,26.07 13.45,27.15 13.45,28.09 13.65,28.3 13.88,28.3 14.09,28.09 D52.5 D52.6 15.18,28.09 15.48,28.09 15.87,27.69 16.07,27.69 R9127.2 16.71,27.63 16.71,27.76 17.16,28.21 17.23,28.21 L10.2 17.36,28.08 R323.2
HDMI_DDC_CLK: length 65.3
  TOP w0.102: U147.58 49.47,68.51 v4(49.77,68.21) 49.97,68.01 49.97,67.59 C2729.2 50.72,67.91 v1(50.73,67.91)
  IN1 w0.076: v1(50.73,67.91) 50.71,67.88 48.4,67.88 46.08,65.57 46.08,63.09 39.22,56.23 38.03,56.23 35.18,53.38 35.18,50.18 34.01,49.01 33.31,49.01 31.64,47.34 31.09,47.34 28.67,44.92 28.67,43.95 22.97,38.25 22.97,37.71 20.46,35.19 19.67,35.19 19.24,34.76 18.96,34.76 v1(18.73,34.99)
  BOTTOM w0.102: v1(18.73,34.99) 16.67,32.93 R340.2 15.05,33.12 15.05,33.37 D55.1 14.49,33.93 14.49,34.35 14.3,34.54 14.3,34.81 13.34,35.78 11.83,35.78 11.24,35.19 11.24,34.71 11.26,34.69 11.26,34.15 10.65,33.54 J43.15
HDMI_DDC_DATA: length 61.4
  TOP w0.102: U147.57 49.03,68.11 49.23,67.92 49.23,67.7 C2730.2 50.19,65.96 v1(50.15,65.93)
  IN1 w0.076: v1(50.15,65.93) 49.84,65.62 46.95,65.62 46.59,65.26 46.59,62.81 39.6,55.82 38.43,55.82 35.71,53.1 35.71,50.35 34.11,48.76 33.38,48.76 31.68,47.06 31.15,47.06 29.39,45.31 29.39,44.31 23.25,38.18 23.25,37.48 20.58,34.81 19.82,34.81 19.39,34.38 18.83,34.38 v1(18.73,34.28)
  BOTTOM w0.102: v1(18.73,34.28) 16.8,32.35 R341.2 15.24,32.07 14.73,31.56 D56.1 13.14,31.56 12.63,32.07 12.63,33.17 J43.16
HDMI_HPD_CONN: length 60.3
  TOP w0.102: U147.31 37.93,68.91 37.26,68.24 37.26,67.33 36.82,66.88 R2512.2 36.82,65.69 v1(36.76,65.63)
  IN1 w0.076: v1(17.81,35.39) 17.94,35.39 21.87,39.32 21.87,45.86 24.26,48.26 24.26,52 20.91,55.36 20.91,61.03 25.05,65.17 35.31,65.17 35.76,65.63 v1(36.76,65.63)
  BOTTOM w0.102: J43.19 10.76,35.45 11.41,36.11 13.43,36.11 D57.1 15.1,35.24 17.66,35.24 v1(17.81,35.39)
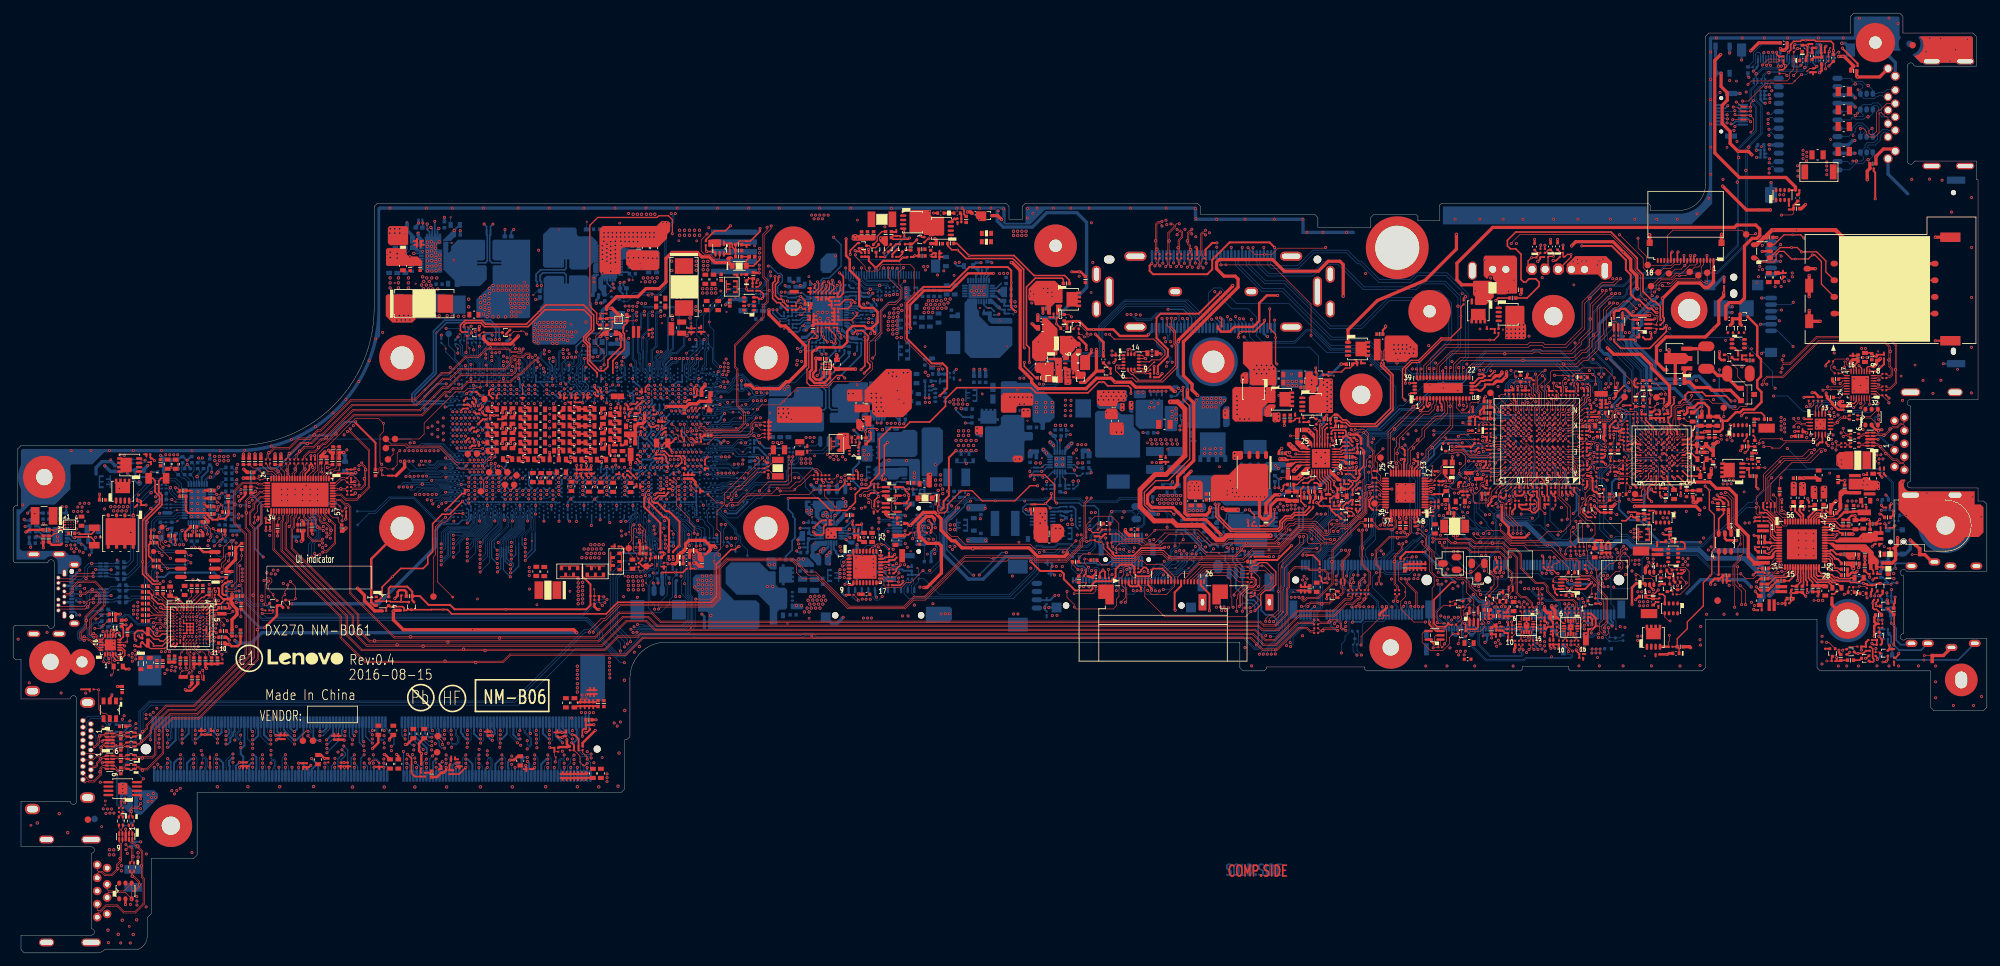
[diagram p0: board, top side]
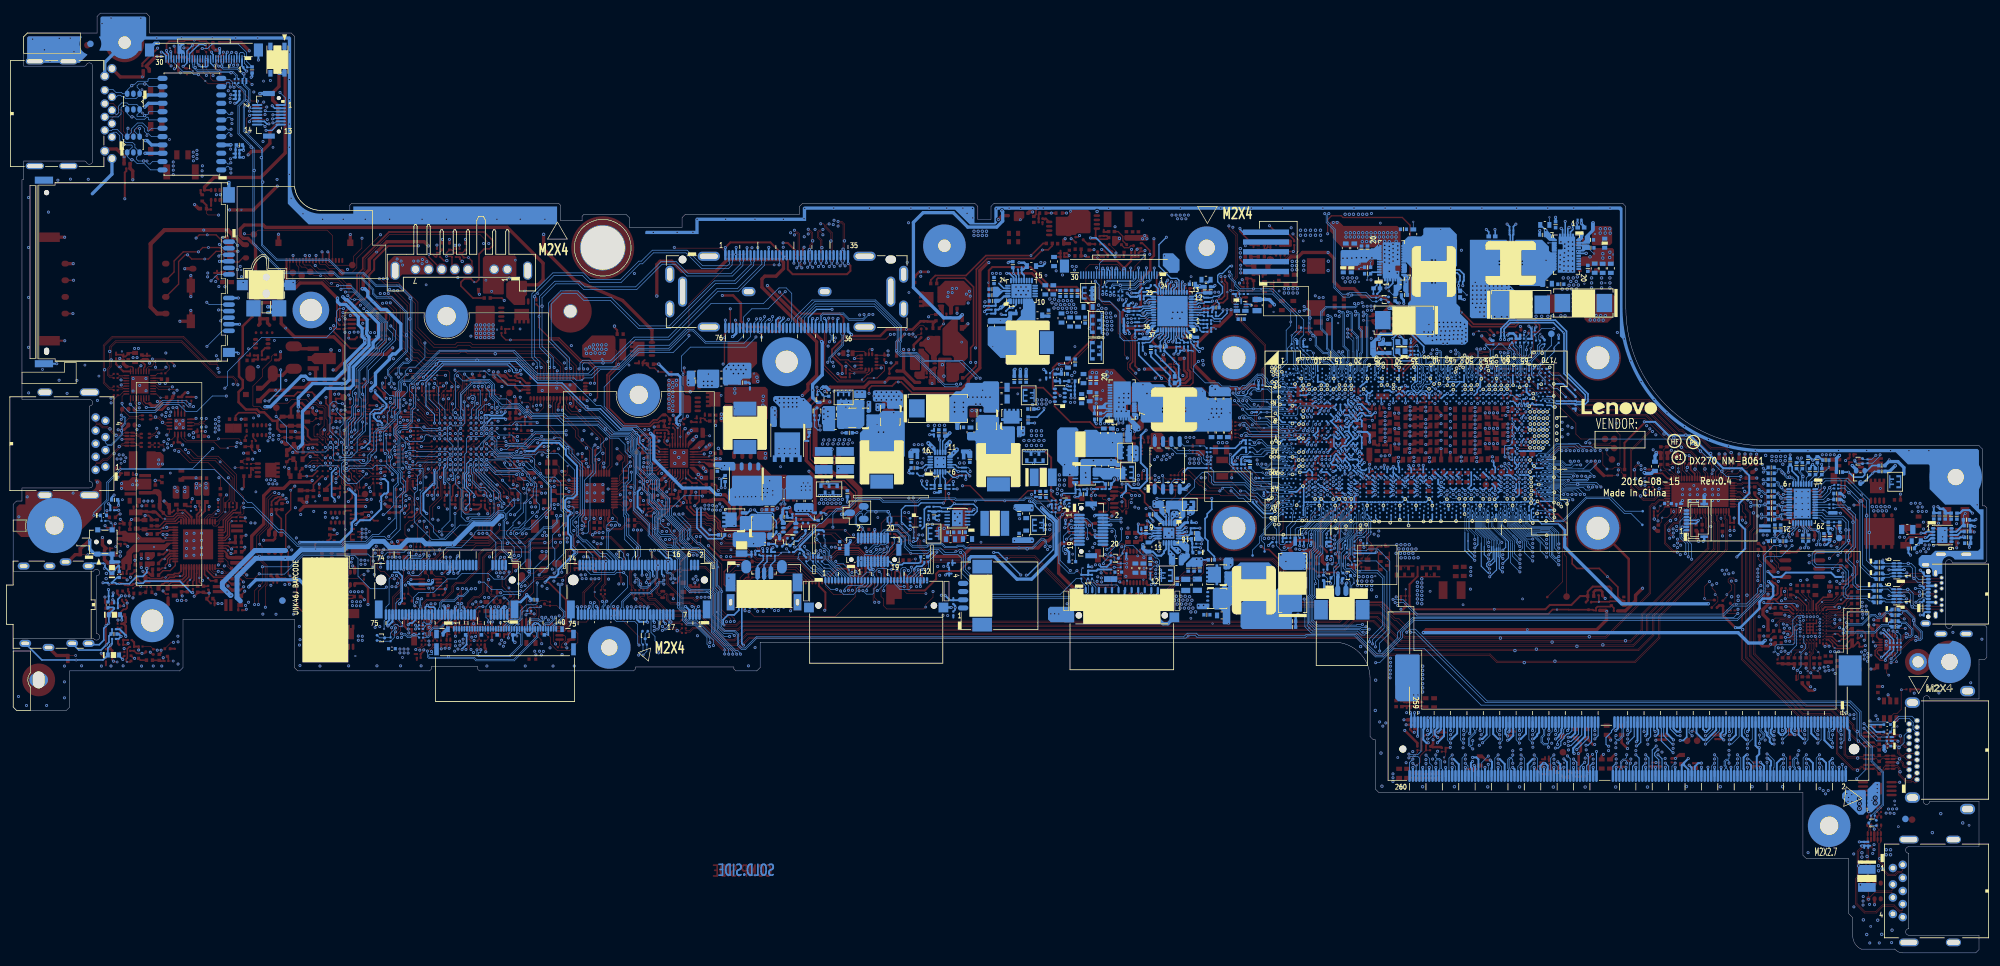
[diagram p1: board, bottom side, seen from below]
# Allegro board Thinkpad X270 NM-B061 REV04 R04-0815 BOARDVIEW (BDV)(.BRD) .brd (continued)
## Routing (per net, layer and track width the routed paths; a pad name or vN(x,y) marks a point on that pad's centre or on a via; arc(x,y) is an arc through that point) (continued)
HP_JACK_IN: length 92.8
  TOP w0.102: v1(262.94,58.92) 262.94,56.46 v3(263.37,56.02) 264.14,55.26 v1(264.14,53.15) ; D253.1 284.53,45.9 RA25.2 283.97,45.95 284.02,46 v1(284.02,46.45) ; v1(222.51,71.46) 222.06,71.92 TP14.1 222.06,72.52 221.5,73.08 R145.1
  IN1 w0.076: v1(284.02,46.45) 283.82,46.65 278.33,46.65 276.59,48.4 276.59,51.02 276.13,51.47 265.74,51.47 264.14,53.08 v1(264.14,53.15)
  BOTTOM w0.102: v1(222.51,71.46) 222.51,71.11 222.72,70.9 222.72,70.19 222.59,70.07 222.59,69.15 223.16,68.58 223.16,67.23 224.73,65.66 224.73,65.26 225.69,64.3 225.69,63.84 223.45,61.61 223.45,60.46 224.11,59.8 224.75,59.8 226.45,61.51 226.45,62.78 228.18,64.5 230.16,64.5 230.57,64.1 230.57,63.92 232.6,61.89 234.81,61.89 235.37,61.32 239.99,61.32 240.17,61.51 240.95,61.51 241.31,61.15 243.87,61.15 244.59,60.44 246.44,60.44 246.87,60.87 256.83,60.87 258.78,58.92 v1(262.94,58.92)
HP_JACK_SYS: length 18.4
  TOP w0.305: 286.04,46.34 286.11,46.4 286.11,46.94 v1(286.06,46.98) ; 286.04,46.34 D253.3 ; 286.04,46.34 286.4,46.34 286.42,46.35 RA49.1
  BOTTOM w0.254: J19.6 296.56,44.7 v3(291.34,44.7) 287.26,44.7 D710.1 286.5,46.54 v1(286.06,46.98) 285.87,47.18 RA22.2
HP_JD_SYS: length 36.4
  TOP w0.203: CA119.2 267.29,60.95 v1(267.73,60.95) v4(268.2,61.42) 268.52,61.74 UA1.9
  TOP w0.254: R10133.1 284.89,51.66 284.13,52.42 283.8,52.42 283.57,52.65 v1(283.57,53.38) 283.57,53.7 R10132.2
  IN1 w0.254: v1(267.73,60.95) 268.16,61.38 268.16,61.81 267.8,62.17 267.22,62.17 266.48,61.43 266.48,52.74 267.5,51.73 275.71,51.73 277.62,53.63 278.2,53.63 278.49,53.92 281.54,53.92 282.2,53.26 283.44,53.26 v1(283.57,53.38)
HP_L_JACK: length 8.2
  BOTTOM w0.254: 285.9,56.48 285.09,57.3 FL3.1 ; 285.9,56.48 285.35,56.48 285.19,56.32 v4(284.76,56.32) 283.22,56.32 282.08,57.46 281.17,57.46 280.57,58.06 v2(280.57,58.66) ; 285.9,56.48 R742.2
HP_L_JACK_CONN: length 7.1
  BOTTOM w0.254: FL3.2 284.77,59.03 CA44.2 284.91,59.08 285.45,58.53 285.45,58.37 D99.1 286.01,57.94 286.95,58.87 286.95,59.25 v4(286.96,59.26) 287.15,59.45 289.03,59.45 J19.1
HP_L_JACK_R: length 3.3
  TOP w0.305: 277.87,60.1 277.88,60.11 278.19,60.11 278.77,59.52 R315.2 ; 277.87,60.1 277.87,60.18 277.1,60.94 UA1.32 ; 277.87,60.1 v4(277.85,60.09)
HP_R_JACK: length 10
  IN4 w0.254: v1(280.37,60.18) 281.21,59.35 282,59.35 285.9,55.44 v1(286.41,55.44)
  BOTTOM w0.254: v1(286.41,55.44) 286.39,55.41 286.39,54.44 R743.2 286.37,53.67 FL5.1
HP_R_JACK_CONN: length 9.2
  BOTTOM w0.254: 285.57,52.6 CA45.2 ; 285.57,52.6 285.7,52.72 286.42,52.72 FL5.2 ; 285.57,52.6 285.57,52.47 286.35,51.69 D94.1 v3(286.35,50.31) 287.12,49.53 287.12,47.72 287.82,47.03 289.24,47.03 J19.2
HP_R_JACK_R: length 2.9
  TOP w0.305: UA1.33 277.03,61.34 277.14,61.46 v4(277.5,61.46) 277.5,61.36 278.04,60.82 R317.2
HV_GATE1: length 35
  TOP w0.076: U5.B9 29.24,48.53 29.74,48.53 29.87,48.66
  TOP w0.203: v1(30.96,48.84) 30.71,49.09 30.15,49.09 29.87,48.81 29.87,48.66
  TOP w0.254: v1(21.54,75.12) 21.21,75.46 PR23.1 20.91,75.57 PR22.1
  IN4 w0.203: v1(21.54,75.12) 22.81,73.85 22.81,68.29 28.98,62.12 28.98,56.15 28.45,55.62 28.45,52.6 29.54,51.5 29.54,49.32 29.77,49.09 30.71,49.09 v1(30.96,48.84)
HV_GATE2: length 28.3
  TOP w0.254: v1(30.35,48.63) 29.99,48.27 U5.A9
  TOP w0.305: PR21.1 PR20.1 v1(20.27,68.34)
  IN4 w0.254: v1(20.27,68.34) 20.85,67.76 22.68,67.76 27.13,63.31 27.13,62.41 26.6,61.88 26.6,53.89 29.19,51.3 29.19,49.06 29.62,48.63 v1(30.35,48.63)
I2C0_CLK: length 40.3
  TOP w0.102: v1(129.22,69.79) 129.22,69.86 129.75,70.4 130.31,70.4 130.54,70.62 131.43,70.62 R9134.1 132.11,70.19 132.34,70.42 U184.2
  IN3 w0.081: v1(129.22,69.79) 127.29,69.79 126.32,70.75 124.67,70.75 123.99,71.44 123.99,74.18 122.08,76.09 120.1,76.09 119.21,76.98 110.69,76.98 110.21,77.46 110.21,80.92 v1(110.92,81.63)
  BOTTOM w0.102: U1.U6 104.62,80.01 104.95,79.67 105.28,79.67 105.61,80 106.25,80 106.38,80.13 106.38,80.46 106.55,80.64 107.7,80.64 107.98,80.92 109.09,80.92 109.81,81.63 v1(110.92,81.63)
I2C0_CLK_NFC: length 17.5
  TOP w0.102: v1(131.86,71.54) 131.85,71.53 131.85,71.06 R9136.1 132.17,71.03 132.21,71.07 U184.1
  IN1 w0.076: v1(131.86,71.54) 131.56,71.23 131.56,69.48 131.8,69.23 132.67,69.23 135.75,66.15 136.77,66.15 139.32,63.6 139.85,63.6 v1(140.32,63.13)
  BOTTOM w0.102: J26.13 139.64,63.81 v1(140.32,63.13)
I2C0_DATA: length 41.6
  TOP w0.102: U185.2 132.42,67.96 R9135.1 131.41,67.76 131.04,67.76 130.89,67.91 130.89,68.98 130.58,69.28 v4(130.41,69.28) 130.33,69.28 129.83,69.79 v1(129.83,69.81) ; v1(112.02,80.59) 110.9,79.47 105.28,79.47 105.08,79.67 v1(104.22,79.67)
  IN3 w0.081: v1(112.02,80.59) 110.58,79.15 110.58,77.66 110.98,77.25 119.29,77.25 120.28,76.26 122.23,76.26 124.24,74.26 124.24,71.54 124.69,71.09 126.49,71.09 127.36,70.22 129.42,70.22 v1(129.83,69.81)
  BOTTOM w0.102: U1.U7 103.97,79.92 v1(104.22,79.67)
I2C0_DATA_NFC: length 13.4
  TOP w0.102: U185.1 132.58,68.61 132.36,68.83 v1(131.88,68.83) 131.88,68.15 R9137.1
  IN1 w0.076: v1(139.63,63.13) 139.56,63.13 136.79,65.9 135.72,65.9 133.4,68.22 132.48,68.22 v1(131.88,68.83)
  BOTTOM w0.102: v1(139.63,63.13) 139.61,63.13 139.43,63.31 J26.15
I2C_CLK_BT0: length 59.6
  TOP w0.254: U16.A7 232.33,72.44 v1(231.35,71.46) 231.71,71.11 R129.1
  IN1 w0.254: v1(220.65,74.67) 221.51,75.53 225.97,75.53 227.21,74.28 227.21,73.95 228.53,72.63 230.18,72.63 v1(231.35,71.46)
  IN3 w0.203: v1(186.67,61.71) 187.26,62.29 192.26,62.29 192.67,62.7 196.12,62.7 196.55,62.27 199.17,62.27 199.7,61.73 202.12,61.73 202.73,62.34 203.77,62.34 204.71,63.28 212.48,63.28 213.14,63.94 213.14,66.51 216.04,69.4 218.09,69.4 219.39,70.7 219.39,71.11 220.46,72.17 220.46,74.47 v1(220.65,74.67)
  BOTTOM w0.254: PR27.2 186.57,61.61 v1(186.67,61.71)
I2C_CLK_BT1: length 42.3
  TOP w0.203: v1(232.93,108.01) 232.88,107.96 PR34.2
  TOP w0.254: v1(225.92,82.56) 225.92,82.92 225.54,83.3 R851.1 R850.2 ; v1(229.55,80.05) U16.K11
  IN4 w0.152: 228.23,81.22 228.36,81.09 228.36,80.69 228.59,80.45 229.15,80.45 v1(229.55,80.05)
  IN4 w0.254: v1(232.93,108.01) 232.93,107.84 230.13,105.04 230.13,103.69 230.59,103.24 230.59,97.19 231.76,96.02 231.76,93.51 229.67,91.42 229.67,89.17 227.94,87.44 227.94,86.02 229.33,84.63 229.33,83.79 228.51,82.97 228.51,82.18 228.23,81.9 228.23,81.22
  BOTTOM w0.152: 229.09,82.03 229.12,82 229.12,81.04 229.14,81.01 229.14,80.55 229.55,80.15 v1(229.55,80.05)
  BOTTOM w0.254: v1(225.92,82.56) 225.92,82.46 226.37,82.01 228.23,82.01 228.32,82.1 229.03,82.1 229.09,82.03
I2C_CLK_CHARGE: length 39.8
  TOP w0.254: v1(204.78,75.45) 204.56,75.68 PR146.1 ; R138.1 231.34,69.36 v1(231.84,69.86) 231.29,69.86 231,70.15 R142.1
  IN1 w0.203: v1(204.78,75.45) 205.22,75.45 206.33,76.57 207.5,76.57 207.98,76.09 212.71,76.09 213.72,77.1 215.55,77.1 216.32,76.34 216.32,73.72 217.53,72.5 217.53,71.28 218.17,70.65 218.65,70.65 220.13,72.12 220.13,73.16 220.91,73.95 225.08,73.95 225.99,73.04 227.11,73.04 229.09,71.06 230.87,71.06 231.84,70.09 v1(231.84,69.86)
I2C_CLK_CPU: length 107.9
  TOP w0.102: Q170.3 41.02,53.62 41.02,54.27 v3(41.43,54.68) 41.43,55.19 41.89,55.64 v1(41.89,56.15) ; RC168.1 32.85,55.2 32.87,55.19 33.83,55.19 33.89,55.24 v1(34.44,55.24)
  IN1 w0.076: v1(102.8,79.54) 101.7,79.54 100.97,80.28 100.13,80.28 99.34,79.49 98.78,79.49 98.47,79.19 98.47,77.94 97.23,76.7 97.23,76.39 97.49,76.14 97.49,75.43 96.7,74.64 96.7,73.92 96.38,73.6 95.96,73.6 95.51,73.14 95.51,68.44 94.03,66.97 94.03,58.69 92.53,57.19 92.53,55.34 90.65,53.46 v1(90.22,53.46)
  IN3 w0.081: v1(34.44,55.24) 34.67,55.47 41.2,55.47 v1(41.89,56.15)
  BOTTOM w0.102: v1(102.8,79.54) 102.66,79.67 U1.U9 ; v1(90.22,53.46) 88.95,53.46 86.89,51.4 40.16,51.4 38.63,52.93 36.55,52.93 34.44,55.03 v1(34.44,55.24)
I2C_CLK_CPU_PD: length 22.6
  TOP w0.076: 30.71,54.01 30.49,53.78 29.7,53.78 29.5,53.58 28.77,53.58 28.23,53.04 28.23,52.01 27.98,51.77 U5.D2
  TOP w0.102: v1(42.29,56.66) 43.05,55.9 v3(43.05,54.07) 42.83,53.84 Q170.1 ; 30.71,54.01 v1(30.75,54.04) R703.1
  IN3 w0.081: v1(30.75,54.04) 31.03,54.32 34.29,54.32 34.9,54.93 41.33,54.93 42.44,56.05 42.44,56.51 v1(42.29,56.66)
I2C_CLK_GSENSE: length 101.1
  TOP w0.152: v1(176.59,96.86) 176.59,95.54 177.25,94.88 177.25,93.05 177.53,92.77 177.53,89.39 175.27,87.13 171.25,87.13 170.66,87.72 v4(169.72,87.72) 169.22,87.72 168.1,88.84 168.1,89.55 168.24,89.7 U17.4 ; v1(230.64,69.63) 230.74,69.53 R160.1 ; U16.C8 v1(231.15,74.5)
  IN4 w0.152: v1(176.59,96.86) 176.59,97.14 178.43,98.98 195.93,98.98 199.42,95.49 206.59,95.49 208.09,93.99 218.95,93.99 222.64,90.3 222.64,84.47 222.97,84.14 222.97,82.99 222.26,82.28 222.26,81.72 223.29,80.69 223.29,77.52 223.76,77.05 224.49,77.05 225.46,76.09 226.81,76.09 228,74.89 230.76,74.89 v1(231.15,74.5)
  BOTTOM w0.152: v1(230.64,69.63) 230.64,69.99 231.81,71.16 231.81,72.96 231.45,73.32 231.45,74.19 v1(231.15,74.5)
I2C_CLK_USBPD: length 254.8
  TOP w0.076: 30.93,51.1 30.71,51.1 30.43,50.82 30.18,50.82 29.88,50.52 29.23,50.52 U5.B5
  TOP w0.102: 30.93,51.1 32.26,51.1 v1(32.67,50.69) ; R189.2 229.88,70.39 230.03,70.54 230.03,71.67 230.34,71.97 v1(230.34,73.68) U16.B9
  IN1 w0.076: v1(226.4,68.03) 226.25,67.88 224.85,67.88 222.69,65.72 217.23,65.72 216.6,66.36 216.6,67.14 215.99,67.75 214.28,67.75 214.08,67.55 208.67,67.55 207.48,66.36 202.78,66.36 202.37,66.76 200.87,66.76 200.69,66.59 199.81,66.59 v1(199.44,66.95)
  IN4 w0.076: v1(32.67,50.69) 32.59,50.77 32.59,59.68 31.52,60.75 v1(31.52,62.17)
  BOTTOM w0.102: v1(230.34,73.68) 230.34,73.49 226.91,70.07 226.91,69.13 226.53,68.74 226.53,68.16 v1(226.4,68.03) ; v1(31.52,62.17) 32.51,62.17 34.04,60.65 34.04,55.03 38.08,50.99 87.41,50.99 89.44,48.96 89.44,48.15 92.18,45.4 93.13,45.4 96.3,48.58 103.81,48.58 103.98,48.4 120.15,48.4 120.52,48.78 121.93,48.78 122.47,48.24 187.65,48.24 189.36,46.52 189.82,46.52 190.32,47.03 190.32,48.66 190.88,49.22 192.41,49.22 192.97,49.78 192.97,55.55 193.53,56.12 193.53,59.91 196.23,62.6 196.53,62.6 197.62,63.69 197.62,65.13 v1(199.44,66.95)
I2C_DATA_BT0: length 68.8
  TOP w0.254: R128.1 234.1,69.58 233.92,69.76 233.92,71.23 233.46,71.69 233.46,72.02 233.11,72.38 v1(233.11,72.6) ; U16.E7 v1(232.71,76.1)
  IN1 w0.254: v1(220.3,75.99) 220.38,75.91 226.17,75.91 227.64,74.43 227.64,74.08 228.69,73.04 230.79,73.04 231.12,73.37 232.34,73.37 v1(233.11,72.6)
  IN3 w0.203: v1(220.3,75.99) 220.3,75.96 220.15,75.82 220.15,72.28 219.08,71.21 219.08,70.8 217.99,69.71 215.88,69.71 212.84,66.66 212.84,64.07 212.35,63.59 204.58,63.59 203.64,62.65 202.63,62.65 202.02,62.04 199.81,62.04 199.27,62.57 196.68,62.57 196.25,63 192.54,63 192.13,62.6 186.85,62.6 v1(185.96,61.71)
  IN4 w0.254: v1(232.71,76.1) 232.09,75.48 232.09,73.62 v1(233.11,72.6)
  BOTTOM w0.254: v1(185.96,61.71) 185.94,61.68 185.94,61.21 PR28.2
I2C_DATA_BT1: length 37.3
  TOP w0.203: v1(233.56,107.99) 233.54,107.96 PR35.2
  TOP w0.254: v1(225.84,81.42) 225.71,81.55 R849.2 R852.1 ; v1(228.75,80.85) U16.L12
  IN4 w0.076: 228.75,80.85 v1(228.75,80.85)
  IN4 w0.152: 228.89,82.13 229.12,81.9 229.12,81.22 228.75,80.85
  IN4 w0.254: 228.89,82.13 228.89,82.84 229.68,83.63 229.68,84.79 228.93,85.54 228.93,86.68 230.02,87.77 230.02,91.27 232.09,93.33 232.09,96.21 230.92,97.37 230.92,103.39 230.49,103.82 230.49,104.89 233.56,107.96 v1(233.56,107.99)
  BOTTOM w0.254: v1(228.75,80.85) 228.02,81.58 226.01,81.58 v1(225.84,81.42)
I2C_DATA_CHARGE: length 41.2
  TOP w0.254: PR148.1 204.73,74.76 v1(204.78,74.82) ; R140.1 233.13,69.96 v1(233.31,69.79) 233.51,69.58 R136.1
  IN1 w0.203: v1(233.31,69.79) 232.83,69.3 231.53,69.3 231.35,69.48 231.35,70.04 230.67,70.73 228.99,70.73 226.98,72.73 225.89,72.73 224.95,73.67 221.07,73.67 220.46,73.06 220.46,71.97 218.8,70.32 218.04,70.32 217.2,71.16 217.2,72.38 215.99,73.6 215.99,76.24 215.4,76.82 213.93,76.82 212.86,75.75 207.83,75.75 207.32,76.26 206.46,76.26 205.01,74.82 v1(204.78,74.82)
I2C_DATA_CPU: length 109.1
  TOP w0.102: RC167.1 32.79,55.52 33.78,55.52 34.34,56.07 v1(34.47,56.07) ; Q171.3 39.65,54.37 v3(39.65,54.68) 38.94,55.39 38.94,56.1 39.45,56.61 39.45,56.99 39.22,57.22 38.69,57.22 38.28,56.81 v1(38.25,56.81)
  IN1 w0.076: v1(90.55,53.94) 92.34,55.73 92.34,57.27 93.83,58.77 93.83,67.05 95.33,68.55 95.33,69.84 94.59,70.58 94.59,73.32 94.97,73.7 94.97,74.11 95.35,74.49 96.27,74.49 96.94,75.16 97.31,75.53 97.31,76.06 97.03,76.34 97.03,76.75 97.39,77.11 97.39,77.66 97.21,77.84 97.21,79.39 98.38,80.56 99.8,80.56 100.28,81.04 100.71,81.04 100.89,80.87 100.89,80.74 101.65,79.98 103.02,79.98 103.33,79.67 v1(103.61,79.67)
  IN3 w0.081: v1(34.47,56.07) 37.52,56.07 v1(38.25,56.81)
  BOTTOM w0.102: v1(34.47,56.07) 35,55.54 35,54.91 36.65,53.26 38.66,53.26 40.21,51.71 86.82,51.71 89,53.89 90.5,53.89 v1(90.55,53.94) ; U1.U8 103.61,79.78 v1(103.61,79.67)
I2C_DATA_CPU_PD: length 19.5
  TOP w0.076: 29.62,54.01 29.37,53.76 28.72,53.76 27.98,53.03 U5.D1
  TOP w0.102: 29.62,54.01 29.78,54.16 30.3,54.16 30.41,54.27 30.41,55.3 30.44,55.34 30.44,55.43 30.68,55.67 R702.1 30.72,55.64 30.72,55.3 v1(30.86,55.16) ; v1(38.97,56.74) 38.43,56.2 38.43,53.43 v3(38.2,53.21) 38.38,53.03 38.79,53.03 Q171.1
  IN3 w0.081: v1(38.97,56.74) 37.87,55.64 33.68,55.64 33.2,55.16 v1(30.86,55.16)
I2C_DATA_GSENSE: length 100.8
  TOP w0.152: v1(175.96,96.84) 175.96,95.74 177,94.7 177,92.93 177.2,92.72 177.2,89.6 175,87.4 171.6,87.4 v4(171.5,87.49) 170.75,88.25 170.52,88.25 169.97,88.8 U17.6 ; v1(231.91,67.7) 232.32,68.11 232.32,68.74 232,69.06 R161.1 ; U16.D8 v1(231.15,75.3)
  IN4 w0.152: v1(231.15,75.3) 230.97,75.3 230.58,75.69 227.61,75.69 226.96,76.34 225.56,76.34 224.49,77.41 223.91,77.41 223.57,77.74 223.57,81.71 223.25,82.03 223.25,84.47 223,84.72 223,90.36 219.09,94.27 208.14,94.27 206.66,95.74 199.65,95.74 196.07,99.33 178.22,99.33 175.96,97.06 v1(175.96,96.84)
  BOTTOM w0.152: v1(231.91,67.7) 231.91,68.01 231.35,68.57 231.35,70.19 232.11,70.95 232.11,73.06 231.78,73.39 231.78,74.66 v1(231.15,75.3)
I2C_DATA_USBPD: length 258.9
  TOP w0.076: 30.93,50.87 30.79,50.87 30.56,50.64 30.25,50.64 29.88,50.27 U5.A5
  TOP w0.102: v1(32.13,50) 32.13,50.26 31.52,50.87 30.93,50.87 ; U16.E9 v1(230.35,76.1) ; R188.2 225.76,68.21 v1(226.12,68.57)
  IN1 w0.076: v1(200.12,66.98) 202.46,66.98 202.78,66.66 207.45,66.66 208.49,67.7 213.75,67.7 215.25,69.2 216.42,69.2 216.8,68.82 216.8,66.43 217.36,65.87 222.61,65.87 224.88,68.14 225.68,68.14 226.11,68.57 v1(226.12,68.57)
  IN4 w0.076: v1(32.13,50) 32.13,51.55 32.36,51.78 32.36,59.38 31.12,60.62 31.12,62.3 30.89,62.53 30.08,62.53 v1(29.69,62.15)
  BOTTOM w0.102: v1(200.12,66.98) 197.85,64.71 197.85,63.59 196.63,62.37 196.33,62.37 193.74,59.78 193.74,55.99 193.17,55.43 193.17,49.67 192.51,49.01 190.98,49.01 190.53,48.56 190.53,46.93 189.89,46.3 189.28,46.3 187.55,48.03 122.12,48.03 v3(121.79,48.35) 121.69,48.45 120.73,48.45 120.45,48.18 103.86,48.18 103.66,48.37 96.43,48.37 93.22,45.17 92.04,45.17 89.13,48.07 89.13,48.94 87.36,50.71 38.06,50.71 33.81,54.96 33.81,60.22 33.5,60.52 31.32,60.52 v1(29.69,62.15) ; v1(230.35,76.1) 229.93,75.68 229.93,73.49 226.68,70.24 226.68,69.33 226.12,68.77 v1(226.12,68.57)
I2S_CTRL: length 151.4
  TOP w0.102: v1(228.42,108.25) 228.42,108.3 229.75,109.63 243.56,109.63 247.3,105.89 247.3,104.23 248.17,103.37 248.17,100.32 249.74,98.74 250.07,98.74 250.5,98.31 v1(250.58,98.31) ; v1(268.13,72.5) 267.73,72.1 267.73,68.9 R10071.2 ; v1(161.36,97.07) 161.02,97.41 D22.2
  IN4 w0.076: v1(228.42,108.25) 228.04,107.86 220,107.86 214.26,102.12 204.61,102.12 201.41,105.32 200.57,105.32 198.79,103.55 172.99,103.55 164.6,95.16 163.43,95.16 161.53,97.07 v1(161.36,97.07) ; v1(268.13,72.5) 268.36,72.73 268.36,84.35 268.84,84.83 268.84,86 v1(268.67,86.17)
  BOTTOM w0.102: v1(268.67,86.17) 268.26,86.58 268.26,88.71 263.03,93.93 253.15,93.93 251.65,95.44 251.65,97.93 251.27,98.31 v1(250.58,98.31)
I2S_JD: length 49
  TOP w0.203: CA124.2 267.45,61.91 267.62,61.74 v1(267.62,61.64) 267.68,61.64 268.19,62.14 UA1.8
  TOP w0.254: v1(278.06,45.05) 278.06,44.72 RA290.2 278.48,44.54 278.59,44.64 R2572.1 279.71,44.64 R319.2
  IN1 w0.254: v1(267.62,61.64) 267.62,61.53 266.94,60.85 266.94,52.87 267.75,52.06 275.46,52.06 277.42,54.02 278.09,54.02 278.32,54.25 281.74,54.25 282.3,53.69 282.98,53.69 283.21,53.92 283.77,53.92 284.13,53.56 284.13,51.91 283.82,51.6 283.82,50.31 284.96,49.17 284.96,47.59 284.66,47.29 284.66,46.17 282.93,44.44 278.66,44.44 v1(278.06,45.05)
IFDET: length 17.9
  TOP w0.102: Q4.2 220.98,58.46 221.51,57.93 222.35,57.93 223.85,59.43 Q28.2 224.79,58.97 224.79,58.08 225.15,57.73 225.45,57.73 225.81,57.37 225.81,56.15 v3(225.35,55.69) 225.35,55.47 224.56,54.67 224.56,54.25 225.1,53.71 225.1,52.97 224.98,52.84 224.44,52.84 224.32,52.72 C800.2 224.41,52.25 R51.1 R377.2 224.95,50.47 v1(224.95,50.43)
  BOTTOM w0.102: J1.21 225.75,49.84 225.15,50.43 v1(224.95,50.43)
INT#_TYPEC: length 238.1
  TOP w0.102: v1(34.01,48.35) R483.1 33.28,48.35 R801.1 ; v1(225.13,74.46) 224.79,74.12 R171.2 ; U16.D11 v1(228.75,75.3)
  IN1 w0.076: v1(97.6,57.97) 97.6,57.59 97.16,57.16 97.16,54.57 90.28,47.69 90.28,42.68 v1(90.99,41.97)
  IN3 w0.081: v1(90.99,41.97) 90.89,41.97 88.06,44.81 57.86,44.81 53.83,48.84 34.49,48.84 v1(34.01,48.35) ; v1(225.13,74.46) 225.74,73.85 225.74,71.08 224.37,69.71 223.94,69.71 223.48,69.25 223.48,66.84 221.09,64.45 221.09,63.51 219.87,62.29 218.68,62.29 216.06,59.68 212.07,59.68 211.79,59.4 198.03,59.4 197.74,59.69 177.97,59.69 176.64,61.02 172.78,61.02 171.46,59.7 170.32,59.7 169.34,58.73 169.34,58.06 169.08,57.8 168.49,57.8 167.37,58.91 164.75,58.91 164.36,59.3 162.59,59.3 161.95,58.67 161.95,57.72 160.31,56.07 158.51,56.07 157.41,54.98 137.47,54.98 135.57,53.07 128.89,53.07 128.3,53.66 126.27,53.66 123.45,56.48 121.12,56.48 116.85,60.74 108.26,60.74 107.83,61.18 106.39,61.18 104.99,62.57 102.96,62.57 102.65,62.27 102.65,60.08 101.08,58.51 98.13,58.51 v1(97.6,57.97)
  BOTTOM w0.102: v1(225.13,74.46) 225.89,75.22 228.68,75.22 v1(228.75,75.3)
INT#_TYPEC_CPU: length 114
  TOP w0.102: v1(37.97,51.81) 39.5,51.81 39.64,51.95 R485.1 R802.1 ; v1(114.28,75.56) 114.28,75.48 112.14,73.35 111.74,73.35 108.48,70.1 108.48,68.5 107.32,67.33 107.32,64.69 107.85,64.15 107.85,61.64 106.88,60.67 v3(106.88,59.73) 106.88,54.47 106.4,53.99 v1(104.09,53.99)
  BOTTOM w0.076: U1.AD2 106.87,76.33 107.08,76.53 107.14,76.53 107.19,76.59 107.29,76.59 107.43,76.73 107.67,76.73 107.77,76.62
  BOTTOM w0.102: v1(104.09,53.99) 103.99,53.89 103.99,49.78 103.02,48.81 96.14,48.81 92.97,45.64 92.28,45.64 89.84,48.08 89.84,48.91 87.56,51.2 38.58,51.2 v1(37.97,51.81) ; v1(114.28,75.56) 113.79,76.04 112.75,76.04 R486.2 111.96,76.42 111.61,76.06 110.67,76.06 110.11,76.62 107.77,76.62
INT#_TYPEC_CPU_R: length 11.8
  TOP w0.076: 30.93,53.58 29.75,53.58 29.57,53.4 28.86,53.4 28.48,53.02 U5.C1
  TOP w0.102: R802.2 38.13,52.26 v1(37.95,52.44) ; 30.93,53.58 31.16,53.58 v1(31.32,53.74)
  IN3 w0.081: v1(31.32,53.74) 31.5,53.92 36.48,53.92 v1(37.95,52.44)
INT#_TYPEC_R: length 4.5
  TOP w0.076: U5.B6 29.24,50.03 29.74,50.03 29.82,50.11 29.95,50.11 30.24,50.4 30.62,50.4 30.86,50.64 30.93,50.64
  TOP w0.102: R801.2 31.68,49.19 31.68,50.41 31.45,50.64 30.93,50.64
IPDCLK: length 96.1
  TOP w0.102: R137.2 224.66,79.29 222.01,79.29 v4(221.83,79.11) 220.63,79.11 v1(220.35,78.83) ; v1(201.86,65.98) 201.76,66.08 201.05,66.08 200.58,65.61 200.58,64.2 200.34,63.96 199.92,63.96 198.4,65.48 195.5,65.48 195.23,65.21 194.73,65.21 194.29,64.78 194.29,64.27 192.49,62.47 185.96,62.47 185.51,62.01 185.51,61.63 185,61.12 181.95,61.12 181.18,61.89 181.18,62.48 179.84,63.82 176.18,63.82 174.69,62.32 172.62,62.32 172.12,62.83 167.69,62.83 R226.1 167.46,62.18 v1(167.67,61.96)
  IN4 w0.076: v1(201.86,65.98) 201.86,65.82 202.73,64.96 202.73,63.74 204.1,62.37 207.52,62.37 208.59,63.44 209.5,63.44 210.89,62.04 212.25,62.04 212.73,62.52 214.03,62.52 214.69,63.18 214.97,63.18 215.66,62.5 216.09,62.5 216.34,62.24 216.67,62.24 217,62.57 217,62.9 217.23,63.13 218.47,63.13 219.06,62.55 220.02,62.55 220.61,63.13 220.61,65.39 222.49,67.27 222.49,68.95 221.8,69.63 219.52,69.63 218.47,70.67 218.09,70.67 216.84,71.93 216.84,76.66 219.01,78.83 v1(220.35,78.83)
  BOTTOM w0.102: J16.15 168.6,60.68 168.17,61.11 167.89,61.11 167.67,61.33 v1(167.67,61.96)
IPDCLK_R: length 5.3
  TOP w0.102: R137.1 225.28,78.77 C155.1 225.45,78.6 v1(226.07,78.6) ; U16.F11 v1(228.75,76.9)
  IN4 w0.076: v1(226.07,78.6) 227.77,76.9 v1(228.75,76.9)
IPDDATA: length 76.2
  TOP w0.102: v1(206.89,75.75) 206.36,75.22 206.36,74.26 206.05,73.95 206.05,72.43 205.8,72.17 205.8,70.66 205.69,70.55 205.69,69.94 205.8,69.83 205.8,67.42 205.19,66.81 204.95,66.81 203.45,65.32 201.61,65.32 200.83,64.54 200.83,64.1 200.44,63.7 199.81,63.7 198.29,65.23 195.96,65.23 192.97,62.24 187.54,62.24 187.13,61.84 187.13,61.58 186.24,60.69 181.95,60.69 180.81,61.84 180.81,62.14 180.39,62.55 175.35,62.55 174.91,62.12 172.07,62.12 v4(171.71,62.48) 171.68,62.5 168.74,62.5 168.16,61.91 v1(168.16,61.61) 168.22,61.54 R227.1 ; R139.2 v1(224.16,80.59)
  BOTTOM w0.102: v1(224.16,80.59) 224.04,80.47 211.86,80.47 209.94,78.55 208.62,78.55 207.64,77.57 207.64,76.5 v1(206.89,75.75) ; v1(168.16,61.61) 168.16,61.53 168.61,61.07 168.84,61.07 169.1,60.82 J16.13
IPDDATA_R: length 5.4
  TOP w0.102: D26.1 C156.1 223.92,81.01 225.03,81.01 225.28,80.76 R139.1 226.07,80.59 226.18,80.47 U16.K13
IRQSER: length 284.6
  TOP w0.102: U16.N5 233.93,83.41 233.97,83.46 v1(233.97,83.78)
  IN1 w0.076: v1(103.01,63.84) 103.55,63.3 104.7,63.3 107.83,66.43 109.15,66.43 111.43,68.71 116.53,68.71 119.12,66.12 119.12,64.52 120.66,62.98 120.66,61.13 123.58,58.2 124.01,58.2 126.39,55.82 135.67,55.82 137.64,57.78 144.29,57.78 145.14,58.64 154.06,58.64 154.64,59.22 155.44,59.22 158.92,62.7 161.3,62.7 161.68,62.32 163.79,62.32 164.12,62.65 166.94,62.65 167.31,63.02 171.29,63.02 172.07,62.24 174.49,62.24 175.82,63.57 179.81,63.57 180.88,62.5 180.88,61.99 181.77,61.1 186.12,61.1 187.23,59.98 210.25,59.98 210.74,60.48 212.56,60.48 213.09,61.01 214.45,61.01 215.1,60.36 220.72,60.36 223.11,62.75 240.55,62.75 242.19,61.11 243.63,61.11 244.89,59.85 245.4,59.85 245.98,59.27 246.34,59.27 246.84,58.77 v1(246.84,58.28)
  IN3 w0.081: v1(246.84,58.28) 246.84,58.84 246.82,58.86 246.82,62.83 245.73,63.92 245.73,70.74 248.29,73.31 248.29,75.83 247.3,76.82 247.3,77.25 246.92,77.63 244.87,77.63 244.48,78.02 244.48,79.31 243.24,80.56 243.24,81.17 242.73,81.67 242.73,82.54 242.12,83.15 241.03,83.15 240.85,82.97 239.89,82.97 239.18,83.68 234.07,83.68 v1(233.97,83.78)
  IN4 w0.076: v1(261.39,127.27) 261.69,127.27 261.74,127.33 261.74,128.97 261.85,129.07 261.85,129.66 262.59,130.4 262.59,131.01 263.14,131.56 263.49,131.56 264.21,130.84 264.21,122.38 264.02,122.19 264.02,112.6 259.05,107.64 251.37,107.64 247.89,104.15 247.89,102.53 246.86,101.5 246.86,99.62 244.94,97.7 242.2,97.7 237.73,93.23 237.73,87.54 238.11,87.16 238.11,86.55 238.26,86.4 238.26,85.5 236.2,83.44 234.31,83.44 v1(233.97,83.78)
  BOTTOM w0.076: U1.AY11 100.9,67.54 100.9,66.91 100.8,66.8 100.8,66.28 101.1,65.98 101.28,65.98 101.94,65.32 102.07,65.32
  BOTTOM w0.102: 102.07,65.32 103.01,64.38 v1(103.01,63.84) RC22.1
  BOTTOM w0.127: v1(261.39,127.27) 261.07,127.27 260.94,127.39 J5.9
ITP_PMODE: length 130.6
  TOP w0.102: v1(172.98,55.33) 173.64,54.67 175.83,54.67 177.08,55.93 J8.17 177.08,57.41 175.24,59.25 172.85,59.25 172.24,59.86 v3(171.71,59.86) 171.55,59.7 RC116.2
  IN3 w0.081: v1(108.44,81.32) 109.43,80.33 109.43,77.02 108.7,76.29 107.78,76.29 106.33,74.84 102.22,74.84 101.2,73.82 99.22,73.82 98.1,72.71 98.1,70.75 98.89,69.96 99.73,69.96 100.44,69.25 100.44,68.85 102.73,66.56 103.79,66.56 v1(104.38,65.98) ; v1(105.37,61.63) 106.69,60.31 108.31,60.31 108.57,60.57 116.77,60.57 121.07,56.27 123.4,56.27 126.2,53.48 128.15,53.48 128.79,52.84 135.62,52.84 137.55,54.77 157.62,54.77 158.68,55.84 160.77,55.84 161.68,56.76 163.79,56.76 164.6,55.94 164.6,55.36 165.1,54.86 168.37,54.86 168.61,55.1 168.61,55.61 169.18,56.18 172.14,56.18 v1(172.98,55.33)
  IN4 w0.076: v1(108.44,81.32) 107.25,81.32 103.7,84.87 103.7,85.61 v1(103.33,85.98) ; v1(104.38,65.98) 104.82,65.53 104.82,63.04 105.39,62.47 105.39,61.66 v1(105.37,61.63)
  BOTTOM w0.102: U1.E8 102.91,86.4 v1(103.33,85.98)
KBD_BL_PWM: length 135.4
  TOP w0.102: U16.M9 230.34,82.46 230.34,83.48 230.57,83.71 230.57,84.26 230.86,84.56 v1(230.86,84.6) 230.61,84.85 R133.2 ; v1(128.86,53.81) 128.86,53.92 C175.1
  IN3 w0.081: v1(128.86,53.81) 129.35,53.33 135.57,53.33 137.4,55.16 157.34,55.16 158.46,56.28 160.21,56.28 161.78,57.85 161.78,58.84 162.52,59.57 164.55,59.57 164.98,59.14 167.36,59.14 168.46,60.24 171.43,60.24 172.7,61.51 174.61,61.51 175.47,62.37 176.32,62.37 177.42,63.47 180.47,63.47 181.14,62.8 181.75,62.8 182.38,62.17 183.49,62.17 184.35,61.3 186.85,61.3 187.52,61.97 193.05,61.97 193.71,61.3 195.34,61.3 196,61.97 197.92,61.97 198.84,61.05 203.97,61.05 205.8,62.88 210.3,62.88 211.24,61.94 212.38,61.94 213.47,63.03 213.47,65.42 214.55,66.5 216.56,66.5 217.37,67.31 218.59,67.31 220.86,69.58 220.86,72.83 221.07,73.04 221.07,76.87 222.26,78.07 222.26,82.16 224.14,84.04 227.26,84.04 228.2,84.98 230.57,84.98 230.86,84.68 v1(230.86,84.6)
  BOTTOM w0.127: v1(128.86,53.81) 128.85,53.82 128.47,53.82 127.4,54.89 J37.11
LANPHYPC: length 172.3
  TOP w0.102: UL1.3 v1(216.2,68.79) RL2.1 ; v1(98.42,52.47) 98.73,52.77 106.59,52.77 107.91,54.08 107.91,58.72 109.01,59.83 118.73,59.83 119.44,59.12 119.44,58.05 120.41,57.09 v4(120.89,57.09) 122.69,57.09 127.26,52.51 136.03,52.51 137.35,53.83 139.08,53.83 145.03,59.78 151.5,59.78 151.85,60.13 155.36,60.13 155.86,59.63 160.63,59.63 163.01,62.01 163.01,62.69 163.71,63.39 163.71,65.39 164.96,66.64 167.5,66.64 168.59,65.54 168.59,64.38 169.71,63.26 172.88,63.26 174.18,64.55 180.7,64.55 182.73,62.52 184.79,62.52 185.38,63.11 192.21,63.11 193.81,64.71 193.81,65.52 194.28,65.99 195.14,65.99 195.36,66.2 198.03,66.2 v1(198.82,66.99)
  IN3 w0.081: v1(198.82,66.99) 199.25,67.42 200.36,67.42 200.69,67.09 202.65,67.09 203.01,66.74 203.39,66.74 205.01,68.36 207.76,68.36 209.18,69.79 209.18,70.98 212.28,74.08 212.28,74.59 213.45,75.75 214.49,75.75 v1(214.84,76.11)
  IN4 w0.076: v1(214.84,76.11) 214.87,76.09 214.87,70.12 v1(216.2,68.79)
  BOTTOM w0.076: U1.AW17 97.6,68.35 97.43,68.17 97.21,67.47 97.19,67.4 97.19,66.98 97.2,66.95 97.2,66.69 97.19,66.67 97.19,66.26 97.33,66.12 97.33,65.71 97.09,65.47 97.09,64.3 97.29,64.09 97.29,63.77 97.8,63.26 97.97,63.26 98.19,63.05
  BOTTOM w0.102: 98.19,63.05 98.79,62.45 98.79,61.3 98.66,61.18 98.66,59.12 99.45,58.33 99.45,57.51 99.46,57.49 99.46,56.31 99.73,56.04 99.73,54.6 98.42,53.29 v1(98.42,52.47)
LDO_1V8D_LFT: length 2.3
  TOP w0.254: U5.A2 29.64,51.77 30.18,52.31 31.02,52.31 C812.2
LPC_AD0: length 273.6
  TOP w0.102: R244.1 262.89,129.84 v1(262.74,129.84) ; U16.M6 v1(233.51,82.45)
  IN1 w0.076: v1(192.46,45.61) 191.92,46.15 191.54,46.15 188.27,49.42 95.89,49.42 v1(95.21,50.1)
  IN4 w0.076: v1(233.51,82.45) 233.51,83.91 233.84,84.24 234.04,84.24 234.68,83.61 236,83.61 238.01,85.61 238.01,86.37 237.93,86.45 237.93,87.01 237.5,87.44 237.5,93.33 242.05,97.88 244.87,97.88 246.54,99.55 246.54,101.49 247.74,102.68 247.74,104.25 251.32,107.84 257.97,107.84 263.66,113.53 263.66,122.33 263.97,122.64 263.97,127.42 263.22,128.16 263.22,129.35 v1(262.74,129.84)
  BOTTOM w0.076: 101.38,64.4 101.22,64.56 101.22,64.67 99.96,65.93 99.96,66.13 99.77,66.31 99.77,66.63 99.78,66.65 99.78,66.98 99.77,67.02 99.77,67.27 99.82,67.42 99.92,67.53 100.03,67.64 U1.AY13
  BOTTOM w0.102: v1(95.21,50.1) 96.05,50.1 96.14,50.01 102,50.01 102.77,50.78 102.77,53.94 101.89,54.83 101.89,56.86 102.27,57.24 102.27,60.44 101.55,61.16 101.55,64.23 101.38,64.4 ; v1(192.46,45.61) v3(192.46,46.22) 192.46,46.48 196.63,50.66 197.95,50.66 198.26,50.97 198.26,52.13 198.81,52.69 198.81,60.16 200.49,61.84 201.16,61.84 203.16,63.84 203.16,66.53 202.79,66.9 202.79,67.31 204.14,68.66 204.14,69.86 204.96,70.69 204.96,72.2 205.88,73.11 205.88,75.96 206.59,76.67 206.59,78.22 207.22,78.85 209.89,78.85 211.74,80.7 217.11,80.7 218,81.6 221.98,81.6 222.61,82.23 223.07,82.23 223.94,83.1 226.57,83.1 226.83,82.83 227.38,82.83 227.54,82.99 227.54,84.11 228.36,84.92 228.36,85.64 228.94,86.22 228.94,86.62 229.18,86.87 230.88,86.87 232.55,85.2 232.55,82.97 232.32,82.75 232.32,81.49 232.55,81.27 232.86,81.27 233.11,81.52 233.11,82.06 v1(233.51,82.45)
LPC_AD1: length 271.2
  TOP w0.102: R245.1 262.95,129.07 v1(262.28,129.07) ; v1(233.18,88.07) 233.61,87.64 v4(233.61,87.59) 233.61,87.52 232.62,86.52 232.62,85.91 233.03,85.51 233.03,83.4 232.7,83.07 232.7,82.44 U16.M7
  IN1 w0.076: v1(191.24,45.59) 191.24,46 188.12,49.11 95.64,49.11 95.4,49.35 94.23,49.35 v1(94.19,49.39)
  IN4 w0.076: v1(233.18,88.07) 233.69,88.07 234.32,87.44 235.54,87.44 236.54,88.44 236.54,93.36 241.61,98.44 244.66,98.44 245.88,99.66 245.88,101.61 246.97,102.7 246.97,104.39 251.25,108.67 257.63,108.67 262.82,113.87 262.82,123.13 263.3,123.6 263.3,126.66 262.41,127.55 262.36,127.55 261.98,127.93 261.98,128.77 v1(262.28,129.07)
  BOTTOM w0.076: U1.BA13 100.03,66.94 100.29,66.68 100.29,66.08 100.93,65.44 100.98,65.44 101.59,64.83
  BOTTOM w0.102: v1(191.24,45.59) 191.24,45.98 194.24,48.99 194.24,54.62 194.85,55.23 197.72,55.23 198.36,55.87 198.36,60.33 200.26,62.23 200.26,63.1 200.72,63.56 202.24,63.56 202.7,64.02 202.7,66.36 202.31,66.75 202.31,67.6 203.67,68.96 203.67,69.99 204.12,70.45 204.12,71.21 203.77,71.56 203.77,72.1 205.47,73.8 205.47,76.16 206.13,76.82 206.13,78.41 206.98,79.26 209.38,79.26 211.64,81.52 216.66,81.52 217.17,82.03 221.78,82.03 222.41,82.66 222.89,82.66 223.87,83.64 226.38,83.64 227.81,85.06 227.81,86.67 228.43,87.29 232.39,87.29 v1(233.18,88.07) ; 101.59,64.83 102.1,64.31 102.1,61.69 102.78,61.02 102.78,54.6 103.23,54.15 103.23,50.45 102.32,49.54 95.56,49.54 95.37,49.35 94.23,49.35 v1(94.19,49.39)
LPC_AD2: length 269
  TOP w0.102: U16.L7 v1(232.71,81.65) ; v1(262.54,127.93) 262.68,127.79 R246.1
  IN1 w0.076: v1(94.68,49.77) 94.74,49.71 95.37,49.71 95.82,49.26 188.2,49.26 191.85,45.61 v1(191.85,45.59)
  IN4 w0.076: v1(262.54,127.93) 263.53,126.94 263.53,123.32 263.08,122.87 263.08,113.76 257.73,108.42 251.36,108.42 247.25,104.31 247.25,102.7 246.1,101.55 246.1,99.62 244.71,98.23 241.72,98.23 237.04,93.56 237.04,88.66 236.25,87.87 236.25,86.39 234.82,84.95 233.44,84.95 232.83,84.34 232.83,81.77 v1(232.71,81.65)
  BOTTOM w0.076: 101.45,64.69 100.12,66.02 100.12,66.21 100.03,66.31 U1.BB13
  BOTTOM w0.102: v1(191.85,45.59) 191.85,46.27 194.45,48.87 194.45,54.47 194.95,54.98 197.79,54.98 198.61,55.8 198.61,60.26 200.59,62.24 201.24,62.24 202.93,63.94 202.93,66.43 202.55,66.81 202.55,67.37 203.9,68.72 203.9,69.91 204.68,70.7 204.68,72.3 205.67,73.29 205.67,76.06 206.36,76.75 206.36,78.32 207.1,79.06 209.64,79.06 211.72,81.14 217.01,81.14 217.7,81.83 221.88,81.83 222.49,82.44 222.97,82.44 223.83,83.3 226.61,83.3 226.98,83.67 226.98,83.91 228.04,84.97 228.04,86.2 228.01,86.22 228.01,86.57 228.52,87.08 231.05,87.08 232.75,85.38 232.75,81.7 v1(232.71,81.65) ; v1(94.68,49.77) 94.78,49.67 95.39,49.67 95.48,49.76 102.11,49.76 103.03,50.68 103.03,54.07 102.52,54.57 102.52,56.19 v3(102.36,56.35) 102.36,56.85 102.52,57.01 102.52,60.74 101.85,61.42 101.85,64.29 101.45,64.69
LPC_AD3: length 269.4
  TOP w0.102: R247.1 v1(262.19,127.16) ; v1(232.11,88.33) 232.19,88.25 232.19,85.61 232.55,85.25 232.55,83.75 231.94,83.14 231.94,80.89 232.33,80.49 U16.K7
  IN1 w0.076: v1(190.63,45.59) 190.63,46.38 188.05,48.96 95.13,48.96 v1(95.11,48.93)
  IN4 w0.076: v1(262.19,127.16) 262.42,127.16 263.02,126.56 263.02,125.12 262.16,124.27 262.16,123.45 262.59,123.03 262.59,114.1 257.39,108.9 251.01,108.9 246.67,104.56 246.67,102.81 245.68,101.82 245.68,100.39 244.94,99.66 242.53,99.66 236.13,93.26 236.13,88.38 235.34,87.59 234.73,87.59 233.84,88.48 232.27,88.48 v1(232.11,88.33)
  BOTTOM w0.076: 101.76,64.96 101.1,65.62 100.99,65.62 100.46,66.15 100.46,67.04 100.32,67.18 100.32,67.84 U1.AY12
  BOTTOM w0.102: v1(232.11,88.33) 231.28,87.49 228.27,87.49 227.56,86.77 227.56,85.24 226.84,84.53 225.68,84.53 225,83.86 223.78,83.86 222.79,82.87 222.21,82.87 221.6,82.26 216.84,82.26 216.35,81.77 211.52,81.77 209.2,79.46 206.85,79.46 205.93,78.54 205.93,76.92 205.27,76.26 205.27,73.9 203.44,72.07 203.44,69.05 202.09,67.7 202.09,66.66 202.5,66.26 202.5,64.25 202.12,63.87 200.67,63.87 200.01,63.21 200.01,62.29 198.1,60.39 198.1,55.94 197.65,55.49 194.78,55.49 194.04,54.75 194.04,49.11 190.63,45.7 v1(190.63,45.59) ; v1(95.11,48.93) 95.31,48.93 95.72,49.34 102.52,49.34 103.43,50.25 103.43,54.24 103.03,54.64 103.03,61.15 102.36,61.82 102.36,63.9 102.37,63.9 102.37,64.36 101.76,64.96
LPC_AD_DBG0: length 3.2
  TOP w0.102: R244.2 264.88,129.12 v1(264.92,129.07) 264.92,129.63 v3(265.36,130.07)
  BOTTOM w0.102: v1(264.92,129.07) 264.74,128.89 J5.4
LPC_AD_DBG1: length 2
  TOP w0.102: R245.2 264.89,128.43 v1(264.92,128.46)
  BOTTOM w0.102: J5.6 264.85,128.39 v1(264.92,128.46)
LPC_AD_DBG2: length 4.9
  TOP w0.102: v3(264.97,125.24) 265.39,125.66 265.39,127.28 v1(264.9,127.78) 264.89,127.79 R246.2
  BOTTOM w0.102: J5.8 264.79,127.89 v1(264.9,127.78)
LPC_AD_DBG3: length 2.4
  TOP w0.102: R247.2 264.61,127.16 v1(264.92,126.84)
  BOTTOM w0.102: v1(264.92,126.84) 264.92,127.02 264.55,127.39 J5.10
LPCCLK_DEBUG_24M: length 232.8
  IN3 w0.081: v1(226.42,86.43) 226.24,86.25 221.22,86.25 219.73,84.76 218.59,84.76 216.21,82.38 216.21,78.12 215.6,77.51 215.6,75.73 213.05,73.18 213.05,72.85 210.4,70.19 210.4,69.63 208.24,67.47 205.9,67.47 205.29,66.86 204.53,66.86 203.67,66 202.43,66 202.05,66.37 200.71,66.37 200.47,66.13 199.65,66.13 199.19,65.67 195.35,65.67 195.12,65.44 190.39,65.44 189.7,64.75 182.6,64.75 182.06,65.29 176.19,65.29 176.12,65.36 175.74,65.36 175.09,64.71 170.49,64.71 169.96,64.17 165.54,64.17 165.06,63.7 165.06,62.73 163.84,61.5 161.6,61.5 160.25,60.15 158.7,60.15 156.48,57.93 148.35,57.93 147.27,59.01 144.94,59.01 144.71,58.79 137.73,58.79 136.28,60.24 132.65,60.24 132.09,59.68 130.69,59.68 127.75,62.62 126.86,62.62 126.37,63.11 126.37,63.21 124.52,65.06 123.12,65.06 121.68,66.51 120.01,66.51 116.86,69.66 112.58,69.66 108.59,65.67 v1(108.59,65.37)
  IN4 w0.076: v1(226.42,86.43) 226.32,86.53 226.32,88.95 225.92,89.34 225.92,91.32 224.18,93.06 224.18,96.82 226.65,99.28 226.65,99.89 226.34,100.19 225.2,100.19 223.57,101.82 223.57,104.97 225.35,106.75 228.5,106.75 229.87,108.12 229.87,110.18 231.04,111.35 256.08,111.35 259.49,114.75 259.49,117.62 259.71,117.85 259.71,130.76 v1(260.26,131.3)
  BOTTOM w0.102: v1(108.59,65.37) 108.59,64.93 108.34,64.68 C258.1 108.34,62.17 107.63,61.45 106.88,61.45 v4(106.54,61.79) 106.06,61.79 RC31.2 ; J5.1 259.69,129.39 259.41,129.67 259.41,130.45 v1(260.26,131.3)
LPCCLK_DEBUG_24M_R: length 6.3
  BOTTOM w0.102: RC31.1 105.47,64.63 105.17,64.93 104.76,64.93 104.58,65.11 104.11,65.11 103.08,66.14 103.08,66.84 102.78,67.14 102.78,67.25 102.45,67.58 U1.AY9
LPCCLK_EC_24M: length 160.3
  TOP w0.102: v1(233.11,86.4) 233.11,85.98 233.46,85.62 233.46,83.21 U16.N6
  IN3 w0.081: v1(107.96,65.39) 107.96,65.19 108.18,64.97 108.81,64.97 109.08,65.24 109.08,65.47 112.86,69.25 116.72,69.25 119.85,66.12 121.48,66.12 122.64,64.96 122.64,63.74 123.38,63 125.89,63 127.03,61.86 127.9,61.86 130.49,59.27 132.67,59.27 133.21,59.8 136.15,59.8 138.03,57.92 145.02,57.92 145.72,58.63 147.11,58.63 148.83,56.91 156.65,56.91 158.33,58.58 159.34,58.58 159.57,58.81 159.57,59.39 159.78,59.59 160.26,59.59 161.78,61.11 164.03,61.11 165.45,62.53 165.45,63.52 165.69,63.77 171.56,63.77 171.99,64.2 175.86,64.2 176.57,64.9 181.27,64.9 181.83,64.35 189.85,64.35 190.55,65.05 195.28,65.05 195.51,65.28 199.42,65.28 199.81,65.68 200.67,65.68 200.81,65.81 201.42,65.81 201.65,65.58 203.8,65.58 204.67,66.46 205.52,66.46 206.05,66.99 208.44,66.99 212.84,71.39 212.84,71.94 216.01,75.12 216.01,77.36 217.03,78.37 217.03,81.52 221.37,85.86 225.23,85.86 225.51,85.58 227.03,85.58 227.45,86 232.7,86 v1(233.11,86.4)
  BOTTOM w0.102: RC30.2 106.78,62.71 C257.1 107.15,62.34 107.73,62.34 107.93,62.55 107.93,65.01 107.96,65.04 v1(107.96,65.39)
LPCCLK_EC_24M_R: length 7.7
  BOTTOM w0.102: RC30.1 106.21,64.76 105.47,65.49 105.47,65.77 105.09,66.15 104.73,66.15 104.47,66.42 104.14,66.42 103.92,66.63 103.92,67.89 103.7,68.12 103.49,68.12 103.16,68.45 U1.AW9
LX1_CHG: length 13.6
  IN1 w0.889: 195.12,72.1 186.44,72.1 184.15,74.39 184.15,75.46
  BOTTOM w0.305: PC142.1 180.31,78.13
  vias: v1(181.67,76.92) v1(181.67,76.21) v1(182.51,76.92) v1(182.51,76.21) v1(183.32,76.95) v1(183.35,76.21) v1(184.16,76.95) v1(184.18,76.21) v2(196,72.53) v2(196.48,73.01) v3(183.93,74.18)
LX2_CHG: length 9.2
  TOP w0.203: 198.42,78.9 PU101.23
  IN1 w0.889: 192.06,85.69 197.29,80.45
  BOTTOM w0.305: 188.6,85.94 PC143.1
  vias: v1(197.55,79.72) v1(198,79.31) v2(186.57,84.95) v2(186.62,84.26) v2(186.62,83.58) v2(186.62,82.89) v2(186.62,82.18) v2(187.05,81.47) v2(187.77,81.44) v2(188.45,81.47) v2(190.92,86.07) v2(190.92,85.43) v3(192.99,85.08)
M1_DRV: length 97.9
  TOP w0.102: v1(255.94,77) 255.58,76.64 255,76.64 254.68,76.33 254.15,76.33 U21.E2
  IN1 w0.203: v1(187.89,67.6) 187.89,67.74 188.24,68.08 189.9,68.08 190.96,67.02 197.08,67.02 197.79,67.73 197.79,68.44 196.29,69.94 196.29,70.4 198.95,73.06 201.04,73.06 202.02,74.04 202.02,80.78 202.27,81.04 207.86,81.04 210.45,83.63 213.56,83.63 214.37,84.44 221.83,84.44 222.74,85.36 231.73,85.36 232.06,85.03 235.61,85.03 236.46,84.19 237.19,84.19 238.13,83.25 242.47,83.25 243.21,82.51 247,82.51 247.81,81.7 252.81,81.7 254.72,79.78 254.72,76.8 255.1,76.42 255.61,76.42 255.94,76.75 v1(255.94,77)
  BOTTOM w0.203: v1(187.89,67.6) 187.46,67.17 185.23,67.17 185,66.94 185,66.28 184.57,65.85 PR31.1
M2_DRV: length 90.5
  TOP w0.102: U21.C1 254.98,74.33 v1(255.1,74.21)
  TOP w0.203: PR32.1 190.48,65.14 190.5,65.17 190.53,65.17 190.58,65.22 v3(191.01,65.22) 191.31,65.22 192.33,66.23 v1(192.33,67.68)
  IN1 w0.203: v1(192.33,67.68) 192.33,68.37 193.29,69.33 194.33,69.33 195.63,70.63 196.11,70.63 198.83,73.35 200.85,73.35 201.69,74.18 201.69,80.92 202.13,81.37 207.53,81.37 210.28,84.12 211.23,84.12 212.88,85.77 214.28,85.77 214.79,85.26 218.9,85.26 220.21,86.58 225.08,86.58 225.59,87.08 231.15,87.08 232.49,85.74 235.97,85.74 236.51,85.2 244.54,85.2 246.41,83.32 248.8,83.32 249.79,82.33 253.17,82.33 256.47,79.03 256.47,75.68 255.61,74.82 255.43,74.82 255.1,74.48 v1(255.1,74.21)
M-BAT-PWR:
  vias: v3(188.05,62.45)
M-BAT-TRCL: length 6.5
  BOTTOM w0.254: PD12.3 183.38,62.34 182.7,62.34 PD16.1 181.77,62.84 181.25,62.84 v3(180.7,63.39) 180.13,63.96 PD15.1 ; PF7.2 185.05,62.4 184.83,62.4 PD12.2
M-BAT-TRCL_A:
  vias: v4(180.78,66.2)
M_A_A0: length 55.9
  IN1 w0.076: 80.35,64.32 79.64,65.04 v1(79.64,66.96)
  IN1 w0.114: v1(56.53,28.96) 58.35,30.79 58.35,32.4 58.18,32.58 58.18,34.58 63.13,39.53 68.69,39.53 77.57,48.41 78.58,48.41 80.99,50.83 80.99,63.68 80.35,64.32
  BOTTOM w0.076: v1(79.64,66.96) 79.61,67 79.61,67.08 79.23,67.45 79.23,67.67 U1.AY50
  BOTTOM w0.165: v1(56.53,28.96) 57.03,28.46 J21.144
M_A_A1: length 56
  IN1 w0.114: v1(78.09,60.54) 78.5,60.13 78.5,59.63 78.24,59.37 78.24,52.61 72.32,46.69 72.16,46.69 71.81,47.04 71.65,47.04 71.41,46.8 71.41,46.64 71.76,46.28 71.76,46.12 71.52,45.88 71.35,45.88 71,46.23 70.84,46.23 70.6,45.99 70.6,45.83 70.95,45.48 70.95,45.31 70.71,45.07 70.55,45.07 70.2,45.42 70.03,45.42 69.79,45.18 69.79,45.02 70.14,44.67 70.14,44.51 69.9,44.26 69.74,44.26 69.39,44.61 69.23,44.61 68.98,44.37 68.98,44.21 69.33,43.86 69.33,43.7 69.09,43.46 68.93,43.46 68.58,43.81 68.42,43.81 68.18,43.56 68.18,43.4 68.53,43.05 68.53,42.89 68.28,42.65 68.12,42.65 67.77,43 67.61,43 67.37,42.76 67.37,42.59 67.57,42.39 67.57,42.17 67.42,42.02 62.1,42.02 55.23,35.15 55.23,33.74 v1(54.77,33.29)
  BOTTOM w0.076: U1.BB50 79.31,66.3 79.31,64.53 79.1,64.32 79.1,63.99
  BOTTOM w0.165: v1(54.77,33.29) 54.28,33.79 J21.133 ; v1(78.09,60.54) 79.1,61.56 v4(79.1,62.86) 79.1,63.99
M_A_A2: length 57
  IN1 w0.076: v1(78.09,61.81) 77.44,61.16 77.44,56.43
  IN1 w0.114: v1(53.53,28.96) 53.53,29.58 54.14,30.19 54.14,32.07 53.93,32.27 53.93,34.97 61.77,42.81 66.27,42.81 73.9,50.44 74.96,50.44 75.2,50.68 75.2,50.84 74.85,51.2 74.85,51.36 75.1,51.6 75.26,51.6 75.61,51.25 75.77,51.25 77.44,52.92 77.44,56.43
  BOTTOM w0.076: 77.61,63.41 77.61,63.61 78.85,64.86 78.85,66.1 78.66,66.28 78.66,66.61 78.72,66.75 78.72,66.87 78.66,67.09 78.66,67.23 78.68,67.28 78.71,67.39 78.71,67.54 78.71,67.54 78.71,67.57 78.68,67.67 78.68,67.67 78.61,67.86 78.61,68 U1.AY51
  BOTTOM w0.165: v1(53.53,28.96) 54.03,28.46 J21.132 ; v1(78.09,61.81) 77.61,62.29 77.61,63.41
M_A_A3: length 56.4
  IN1 w0.114: v1(78.09,59.91) 77.83,59.65 77.83,52.76 75.15,50.07 74.88,49.8 74.77,49.69 74.61,49.69 74.28,50.03 74.12,50.03 73.88,49.78 73.88,49.62 74.21,49.29 74.21,49.13 73.96,48.89 73.8,48.89 73.44,49.25 73.28,49.25 73.04,49.01 73.04,48.84 73.4,48.48 73.4,48.32 73.16,48.08 73,48.08 72.63,48.44 72.47,48.44 72.23,48.2 72.23,48.04 72.48,47.78 72.48,47.62 72.24,47.38 72.08,47.38 71.82,47.63 71.66,47.63 66.44,42.41 61.93,42.41 54.34,34.82 54.34,32.45 v1(54.77,32.02)
  BOTTOM w0.076: U1.BA50 79.11,66.94 79.59,66.46 79.59,64.12
  BOTTOM w0.165: J21.131 53.78,33.02 v1(54.77,32.02) ; 79.59,64.12 79.59,61.4 78.24,60.06 v1(78.09,59.91)
M_A_A4: length 55.9
  IN1 w0.076: v1(75.96,62) 76.83,61.14 76.83,56.82 76.51,56.5 76.51,56.02
  IN1 w0.114: v1(53.53,30.23) 53.11,29.82 53.11,29.62 52.89,29.39 52.55,29.39 52.44,29.51 52.44,30.88 52.61,31.05 52.61,32.55 53.1,33.03 53.1,35.25 61.44,43.6 65.95,43.6 76.51,54.16 76.51,56.02
  BOTTOM w0.076: v1(75.96,62) 76.13,62.17 76.34,62.38 76.34,63.29 77.68,64.64 77.68,66.4 U1.BB52
  BOTTOM w0.165: v1(53.53,30.23) 53.03,29.73 J21.128
M_A_A5: length 57.4
  IN1 w0.076: v1(75.83,58) 75.37,57.54 75.37,57.16 74.84,56.63
  IN1 w0.114: v1(52.03,28.96) 51.27,28.96 51,29.24 51,35.38 60.79,45.17 63.45,45.17 65.34,47.06 65.5,47.06 65.79,46.77 65.99,46.77 66.19,46.98 66.19,47.18 65.91,47.46 65.91,47.63 66.15,47.87 66.31,47.87 66.6,47.58 66.79,47.58 67,47.79 67,47.99 66.71,48.27 66.71,48.43 66.95,48.67 67.16,48.67 67.44,48.39 67.61,48.39 73.6,54.39 74.63,55.42 74.63,56.42 74.84,56.63
  BOTTOM w0.076: 77.1,62.55 77.1,63.46 78.02,64.38 78.02,66.07 78.21,66.27 78.21,66.63 78.21,66.63 78.18,66.72 78.18,66.92 78.21,67.01 78.21,67.01 78.22,67.01 78.22,67.03 78.22,67.13 78.31,67.33 U1.BA51
  BOTTOM w0.165: v1(75.83,58) 76.08,58 77.1,59.02 77.1,62.55 ; v1(52.03,28.96) 52.53,28.46 J21.126
M_A_A6: length 56.1
  IN1 w0.076: 77.02,56.22 77.02,56.48 77.19,56.64 77.19,61.42 v1(75.96,62.64)
  IN1 w0.114: 77.02,56.22 77.02,54.11 76.6,53.7 76.6,53.53 76.97,53.17 76.97,53.01 76.73,52.76 76.57,52.76 76.2,53.13 76.04,53.13 75.8,52.89 75.8,52.73 76.16,52.36 76.16,52.2 75.92,51.96 75.76,51.96 75.39,52.32 75.23,52.32 66.11,43.2 61.61,43.2 53.5,35.09 53.5,32.88 53.02,32.4 53.02,32.02 v1(53.45,31.58)
  BOTTOM w0.076: v1(75.96,62.64) 75.96,63.15 77.52,64.71 77.52,66.66 77.78,66.92 U1.BA52
  BOTTOM w0.165: v1(53.45,31.58) 53.32,31.58 52.78,32.13 J21.127
M_A_A7: length 58.4
  IN1 w0.076: 76.01,56.07 76.01,56.5 76.6,57.1 76.6,60.09 v1(75.96,60.73)
  IN1 w0.114: v1(52.03,30.23) 52.03,30.62 51.91,30.74 51.72,30.74 51.55,30.91 51.55,31.14 51.72,31.31 52.04,31.31 52.21,31.47 52.21,32.7 52.7,33.2 52.7,35.41 61.28,43.99 64.28,43.99 64.39,44.1 64.39,44.44 64.51,44.56 64.85,44.56 64.97,44.44 64.97,44.1 65.08,43.99 65.78,43.99 66.56,44.77 66.56,44.93 66.28,45.21 66.28,45.37 66.52,45.61 66.68,45.61 66.96,45.33 67.13,45.33 76.01,54.21 76.01,56.07
  BOTTOM w0.076: 75.55,61.99 75.55,62.97 77.35,64.77 77.35,67.18 77.56,67.39 77.56,67.93 77.88,68.26 U1.AW52
  BOTTOM w0.165: J21.122 51.53,29.73 v1(52.03,30.23) ; 75.55,61.99 75.55,61.15 v1(75.96,60.73)
M_A_A8: length 56.8
  IN1 w0.076: v1(75.96,60.1) 76.25,59.82 76.25,57.12 75.55,56.43 75.55,56.17
  IN1 w0.114: v1(52.28,33.77) 52.28,35.54 61.12,44.38 63.78,44.38 64.67,45.28 64.84,45.28 65.59,44.53 65.75,44.53 65.99,44.77 65.99,44.93 65.24,45.69 65.24,45.85 65.38,45.99 65.75,45.99 65.93,45.8 66.14,45.8 66.59,46.25 66.75,46.25 67.04,45.96 67.2,45.96 67.44,46.2 67.44,46.37 67.15,46.66 67.15,46.82 67.39,47.06 67.56,47.06 67.85,46.77 68.01,46.77 68.25,47.01 68.25,47.17 67.96,47.46 67.96,47.63 68.2,47.87 68.36,47.87 68.65,47.58 68.82,47.58 69.06,47.82 69.06,47.98 68.77,48.27 68.77,48.43 69.01,48.68 69.17,48.68 69.46,48.39 69.62,48.39 69.87,48.63 69.87,48.79 69.58,49.08 69.58,49.24 69.82,49.48 69.98,49.48 70.27,49.19 70.43,49.19 70.67,49.44 70.67,49.6 70.38,49.89 70.38,50.05 70.63,50.29 70.79,50.29 71.08,50 71.24,50 75.55,54.31 75.55,56.17
  BOTTOM w0.076: 76.64,62.04 76.64,63.36 77.85,64.57 77.85,66.14 78.05,66.34 78.05,66.6 78.01,66.69 78.01,66.7 78.01,66.95 78.05,67.04 78.05,67.25 77.98,67.43 77.98,67.7 U1.AY52
  BOTTOM w0.165: J21.125 v1(52.28,33.77) ; 76.64,62.04 76.64,60.78 75.96,60.1 v1(75.96,60.1)
M_A_A9: length 55.9
  IN1 w0.076: v1(75.81,57.39) 75.81,57.29 75.04,56.52 75.04,56.2
  IN1 w0.114: v1(51.78,32.5) 51.52,32.76 51.52,33.41 51.86,33.76 51.86,34.3 51.51,34.65 51.51,35.34 60.95,44.78 63.61,44.78 65.22,46.38 66.15,46.38 70.7,50.93 70.86,50.93 71.16,50.64 71.32,50.64 71.56,50.88 71.56,51.04 71.27,51.34 71.27,51.5 71.51,51.74 71.67,51.74 71.97,51.45 72.13,51.45 72.37,51.69 72.37,51.85 72.08,52.14 72.08,52.31 72.23,52.46 72.32,52.55 72.48,52.55 72.77,52.25 72.94,52.25 73.18,52.5 73.18,52.66 72.88,52.95 72.88,53.11 73.13,53.36 73.29,53.36 73.58,53.06 73.74,53.06 73.99,53.31 73.99,53.47 73.69,53.76 73.69,53.92 73.94,54.17 74.1,54.17 74.39,53.87 74.55,53.87 74.79,54.11 74.79,54.28 74.5,54.57 74.5,54.73 75.04,55.27 75.04,56.2
  BOTTOM w0.076: U1.BB54 76.86,66.39 76.86,64.98 75.09,63.21 74.76,62.89 74.76,61.81
  BOTTOM w0.165: J21.121 51.28,33 51.77,32.5 v1(51.78,32.5) ; v1(75.81,57.39) 74.76,58.44 74.76,61.81
M_A_A10: length 58.3
  IN1 w0.076: v1(78.62,69.91) 78.99,69.55 78.99,68.39 80.32,67.07 80.32,65.45 81.21,64.55
  IN1 w0.114: 81.21,64.55 81.78,63.99 81.78,50.5 78.9,47.62 77.9,47.62 69.02,38.74 63.46,38.74 58.97,34.26 58.97,32.9 59.14,32.73 59.14,31.12 v1(59.53,30.73)
  BOTTOM w0.076: U1.AT50 v1(78.62,69.91)
  BOTTOM w0.165: J21.146 v1(59.53,30.73)
M_A_A11: length 56.7
  IN1 w0.076: v1(75.84,59.23) 74.96,58.36 74.96,57.8 74.35,57.19
  IN1 w0.114: 74.35,57.19 73.27,56.1 73.27,55.94 73.57,55.63 73.57,55.47 73.33,55.23 73.17,55.23 72.86,55.54 72.7,55.54 63.12,45.96 62.97,45.96 62.86,46.07 62.86,46.64 62.75,46.76 62.4,46.76 62.29,46.64 62.29,46.07 62.17,45.96 60.46,45.96 50,35.49 50,31.9 50.33,31.57 v1(50.42,31.57)
  BOTTOM w0.076: U1.BA54 76.75,66.93 77.02,66.67 77.02,64.91 75.76,63.65 75.2,63.1 75.02,62.91 75.02,61.63
  BOTTOM w0.165: J21.120 51.03,30.96 v1(50.42,31.57) ; v1(75.84,59.23) 75.56,59.23 75.02,59.78 75.02,61.63
M_A_A12: length 57.7
  IN1 w0.076: 74.72,56.9 75.17,57.34 75.17,57.91 75.84,58.58 v1(75.84,58.58)
  IN1 w0.114: v1(50.59,33.77) 50.59,35.52 60.62,45.56 63.29,45.56 67.01,49.29 67.17,49.29 67.47,48.99 67.63,48.99 67.88,49.23 67.88,49.39 67.58,49.69 67.58,49.85 67.82,50.1 67.98,50.1 68.28,49.8 68.44,49.8 68.68,50.04 68.68,50.2 68.39,50.5 68.39,50.66 68.63,50.91 68.79,50.91 69.09,50.61 69.25,50.61 69.49,50.85 69.49,51.01 69.19,51.31 69.19,51.47 69.44,51.71 69.6,51.71 69.9,51.42 70.06,51.42 70.3,51.66 70.3,51.82 70,52.12 70,52.28 70.24,52.52 70.41,52.52 70.7,52.22 70.87,52.22 71.11,52.47 71.11,52.63 70.81,52.93 70.81,53.09 71.05,53.33 71.21,53.33 71.51,53.03 71.67,53.03 71.92,53.27 71.92,53.44 71.62,53.73 71.62,53.9 71.86,54.14 72.02,54.14 72.32,53.84 72.48,53.84 72.72,54.08 72.72,54.24 72.43,54.54 72.43,54.7 72.51,54.78 73.44,54.78 74.24,55.59 74.24,56.42 74.72,56.9
  BOTTOM w0.076: U1.AW54 76.65,68.25 76.96,67.94 76.96,67.37 77.19,67.15 77.19,64.84 75.27,62.93 75.27,62.04
  BOTTOM w0.165: 75.27,62.04 75.27,60.13 75.73,59.68 76.01,59.68 76.26,59.42 76.26,59.01 v1(75.84,58.58) ; v1(50.59,33.77) 50.78,33.96 J21.119
M_A_A13: length 60.8
  IN1 w0.076: 83.63,65.54 83.63,66.13 81.71,68.04 81.71,69.63 v1(81.38,69.96)
  IN1 w0.114: 83.63,65.54 83.63,65.31 84.14,64.8 84.14,49.52 74,39.38 73,39.38 72.77,39.15 72.77,38.99 73.11,38.65 73.11,38.49 72.87,38.24 72.7,38.24 72.36,38.59 72.2,38.59 71.96,38.34 71.96,38.18 72.3,37.84 72.3,37.68 72.06,37.44 71.9,37.44 71.55,37.78 71.39,37.78 71.15,37.54 71.15,37.37 71.49,37.03 71.49,36.87 71.25,36.63 71.09,36.63 70.75,36.97 70.58,36.97 70,36.38 69.05,36.38 65.27,36.38 63.02,34.13 63.02,31.89 63.38,31.52 63.38,29.93 v1(63.03,29.57)
  BOTTOM w0.076: U1.AU46 v1(81.38,69.96)
  BOTTOM w0.165: v1(63.03,29.57) 62.53,29.07 J21.158
M_A_ACT_N: length 56.9
  IN1 w0.076: 73.36,57.31 73.75,57.7 74.02,57.7 74.29,57.96 74.29,59.84 74.58,60.13 74.58,62.02 v1(73.97,62.63)
  IN1 w0.114: v1(50.14,30.23) 49.32,30.23 49.06,30.5 49.06,31.85 48.94,31.97 48.75,31.97 48.64,32.08 48.64,32.43 48.75,32.54 49.09,32.54 49.21,32.65 49.21,33 49.09,33.11 48.75,33.11 48.64,33.23 48.64,33.57 48.75,33.68 49.09,33.68 49.21,33.8 49.21,35.82 60.13,46.75 61.28,46.75 62.08,47.55 63.6,47.55 63.84,47.79 64,47.95 73.36,57.31
  BOTTOM w0.076: v1(73.97,62.63) 73.97,62.8 74.74,63.56 75.98,64.81 75.98,65.5 75.72,65.76 75.72,66.08 75.86,66.22 75.86,66.63 75.81,66.77 75.81,66.88 75.86,67.01 75.86,67.24 U1.BA55
  BOTTOM w0.165: v1(50.14,30.23) 49.53,29.61 J21.114
M_A_ALERT_N: length 57.5
  IN1 w0.114: v1(78.09,63.08) 75.7,63.08 75.19,62.57 75.19,59.37 74.67,58.84 74.67,58.06 63.76,47.15 62.24,47.15 61.44,46.35 60.3,46.35 49.6,35.66 49.6,31.53 v1(50.14,30.99)
  BOTTOM w0.076: U1.AW50 78.84,68.24 78.84,67.71 78.89,67.56 78.89,67.4 78.83,67.22 78.83,67.08 78.9,66.85 78.9,66.75 78.84,66.61 78.83,66.58 78.83,66.35 79.03,66.15 79.03,64.66 78.09,63.72 v1(78.09,63.08)
  BOTTOM w0.165: J21.116 50.03,29.48 50.66,30.11 50.66,30.48 v1(50.14,30.99)
M_A_BG0: length 57.9
  IN1 w0.114: v1(73.8,60.17) 72.78,59.15 72.78,58.51 64.98,50.71 62.42,50.71 46.31,34.6 46.31,32.08 v1(47.84,30.55)
  BOTTOM w0.076: 74.23,61.78 74.23,62.34 74.34,62.46 74.34,62.93 74.85,63.45 76.53,65.12 76.53,66.07 76.32,66.27 76.32,66.64 76.34,66.67 76.37,66.75 76.37,66.87 76.3,67.09 76.3,67.23 76.36,67.39 76.36,67.57 76.28,67.73 75.99,68.02 U1.AY55
  BOTTOM w0.165: 74.23,61.78 74.23,60.6 v1(73.8,60.17) ; v1(47.84,30.55) 49.64,32.35 49.64,34.25 49.78,34.39 J21.115
M_A_BG1: length 57.9
  IN1 w0.114: v1(47.84,31.84) 48.24,32.25 48.24,34.22 48.36,34.33 48.7,34.33 48.82,34.45 48.82,34.79 48.7,34.9 48.36,34.9 48.24,35.02 48.24,35.41 59.97,47.14 61.11,47.14 62.32,48.35 62.54,48.35 62.95,47.94 63.43,47.94 63.51,48.01 63.51,48.18 63.16,48.52 63.16,48.68 63.22,48.74 63.41,48.92 63.57,48.92 63.91,48.58 64.07,48.58 64.31,48.82 64.31,48.98 63.75,49.54 63.75,49.71 63.96,49.92 64.19,49.92 64.72,49.39 64.88,49.39 73.63,58.14 v1(73.85,58.14)
  BOTTOM w0.076: U1.AY54 76.55,67.7 76.55,67.44 76.48,67.22 76.48,67.09 76.54,66.86 76.54,66.72 76.49,66.6 76.49,66.34 76.69,66.14 76.69,65.05 74.97,63.33 74.58,62.94 74.58,62.45 74.51,62.37 74.51,61.84
  BOTTOM w0.165: J21.113 49.28,33.15 47.97,31.84 v1(47.84,31.84) ; 74.51,61.84 74.51,60.51 74.35,60.36 74.35,58.64 v1(73.85,58.14)
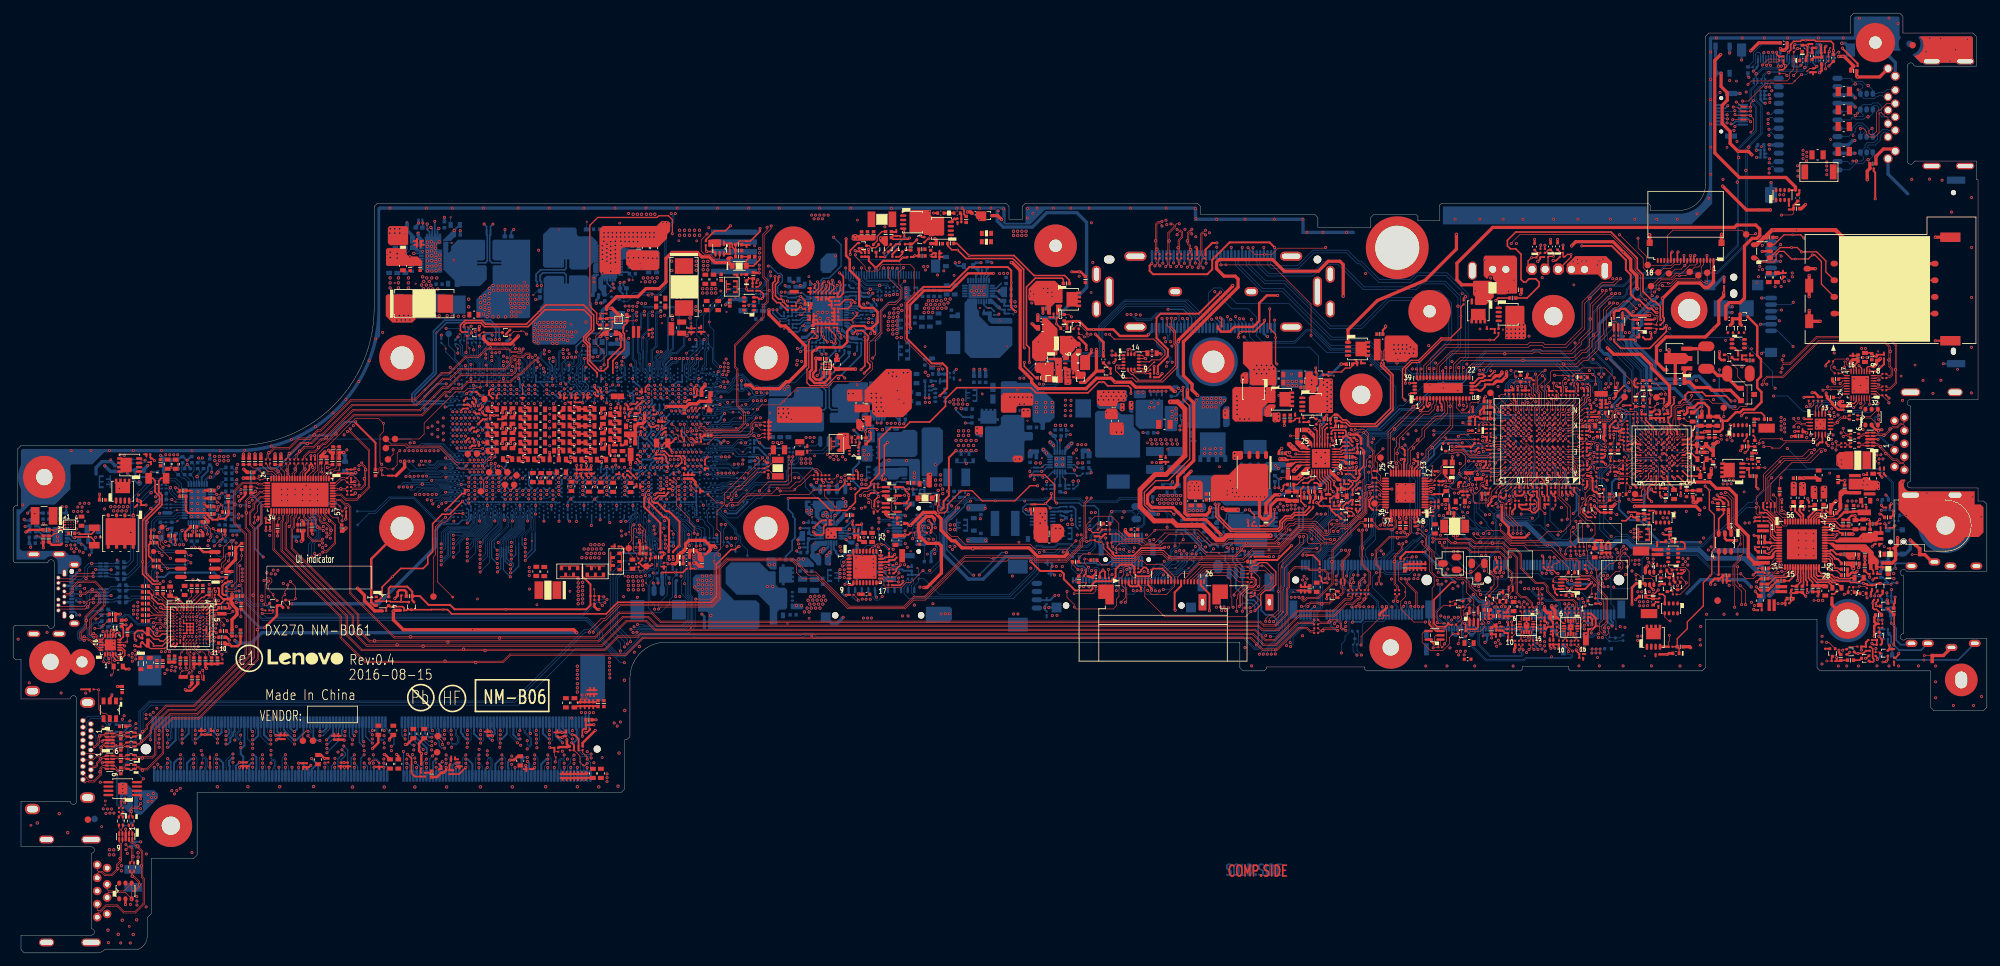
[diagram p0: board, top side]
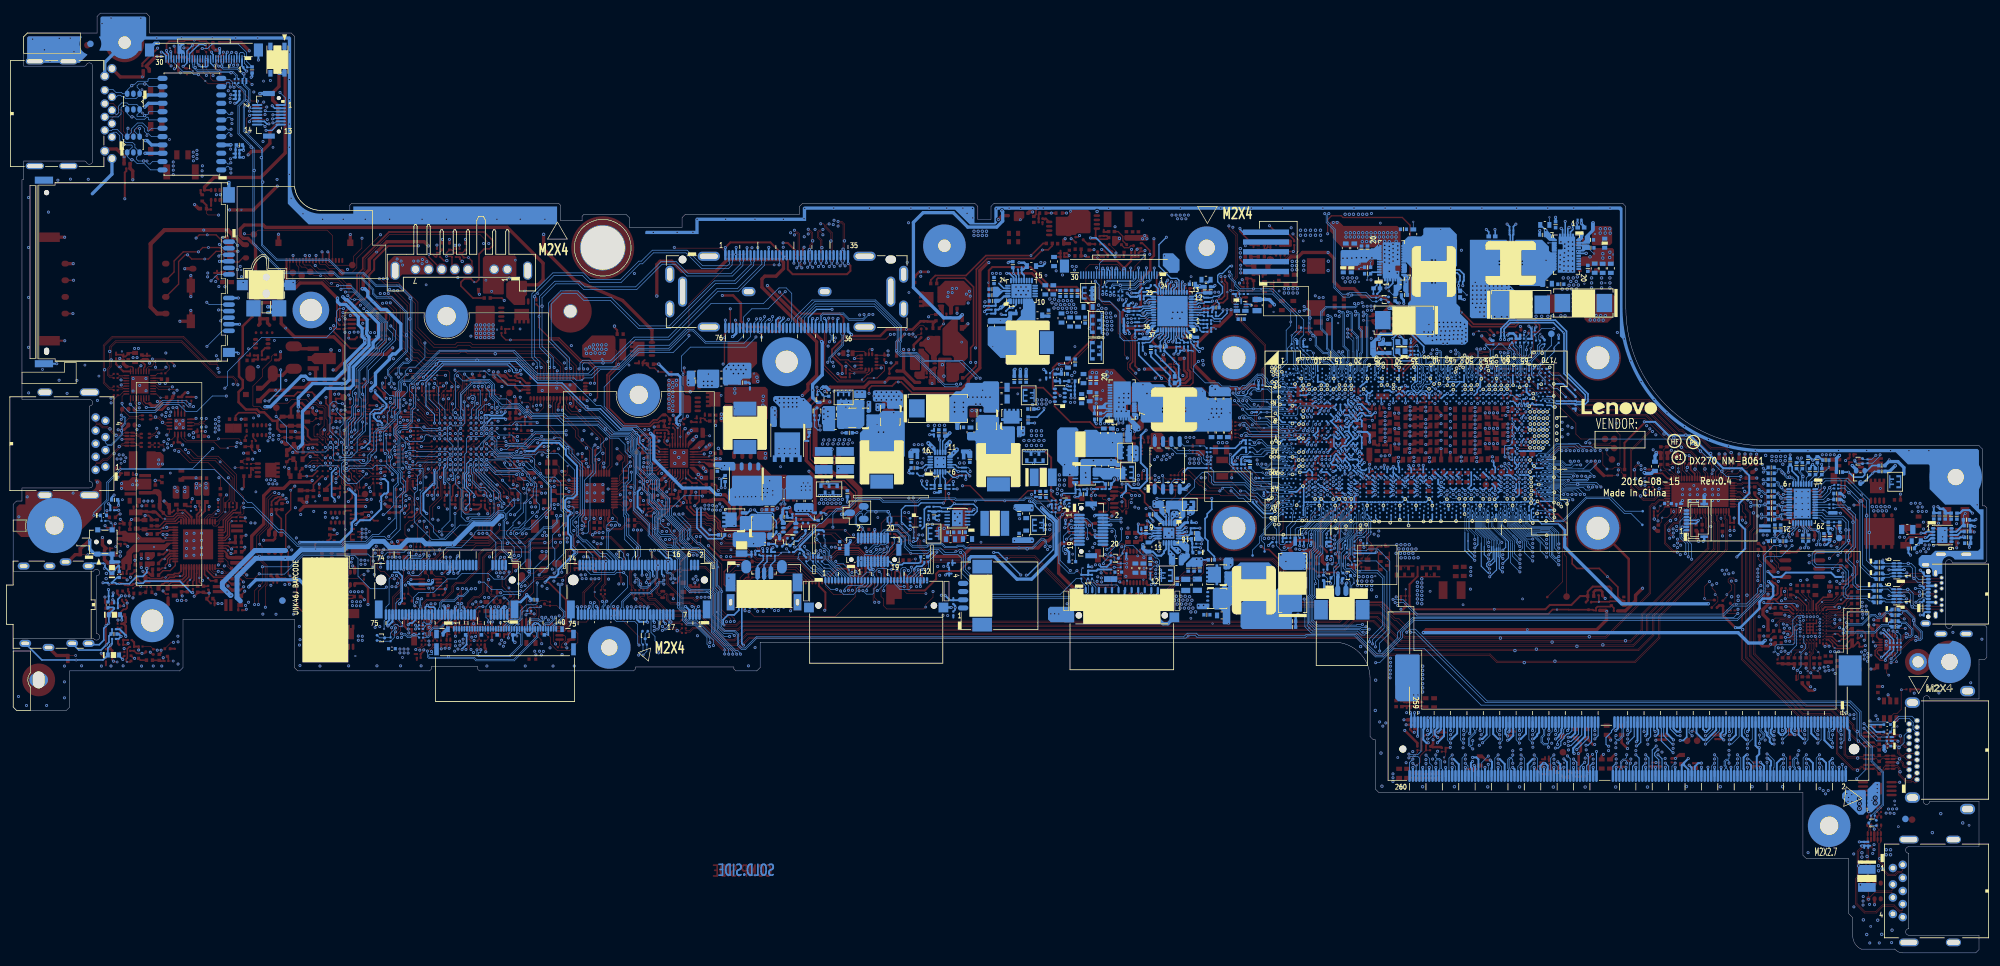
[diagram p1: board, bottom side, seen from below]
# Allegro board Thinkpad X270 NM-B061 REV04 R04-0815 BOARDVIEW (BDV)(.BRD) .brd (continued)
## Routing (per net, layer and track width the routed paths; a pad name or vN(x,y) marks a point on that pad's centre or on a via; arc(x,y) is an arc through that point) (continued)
M_A_BS0: length 58.3
  IN1 w0.076: 80.83,64.43 80.02,65.24 80.02,67.12 79.5,67.64 79.22,67.64 78.62,68.24 v1(78.62,69.28)
  IN1 w0.114: 80.83,64.43 81.38,63.87 81.38,50.66 78.74,48.02 77.73,48.02 68.85,39.14 63.29,39.14 58.57,34.42 58.57,32.74 58.75,32.57 58.75,30.95 58.89,30.81 58.89,30.52 59.5,29.91 59.5,29.47 v1(60.03,28.94)
  BOTTOM w0.076: U1.AU52 v1(78.62,69.28)
  BOTTOM w0.165: v1(60.03,28.94) 60.14,28.94 60.53,28.55 J21.150
M_A_BS1: length 59.2
  IN1 w0.076: 81.77,64.55 81.43,64.9 81.43,66.24 80.58,67.1 80.58,67.91 79.85,68.64 79.67,68.64 79.18,69.13 79.18,69.59 v1(79.53,69.95)
  IN1 w0.114: 81.77,64.55 82.17,64.15 82.17,50.34 79.07,47.23 78.06,47.23 69.18,38.35 63.62,38.35 63.35,38.08 63.35,37.92 63.6,37.66 63.6,37.5 63.36,37.26 63.2,37.26 62.94,37.51 62.78,37.51 62.54,37.27 62.54,37.11 62.79,36.85 62.79,36.69 62.55,36.45 62.39,36.45 62.13,36.7 61.97,36.7 61.73,36.46 61.73,36.3 61.99,36.04 61.99,35.88 61.74,35.64 61.58,35.64 61.33,35.9 61.16,35.9 60.92,35.65 60.92,35.49 61.18,35.24 61.18,35.07 60.93,34.83 60.77,34.83 60.52,35.09 60.36,35.09 59.36,34.09 59.36,33.07 v1(59.78,32.65)
  BOTTOM w0.076: U1.AT48 v1(79.53,69.95)
  BOTTOM w0.165: J21.145 59.28,33.15 v1(59.78,32.65)
M_A_CKE0: length 58.1
  IN1 w0.114: v1(46.78,33.14) 47.74,33.14 47.85,33.25 47.85,34.09 47.74,34.2 47,34.2 46.88,34.32 46.88,34.61 47.05,34.78 47.74,34.78 47.85,34.89 47.85,35.58 60.15,47.88 60.32,47.88 60.66,47.53 60.82,47.53 61.05,47.76 61.05,47.95 60.72,48.28 60.72,48.44 60.96,48.69 61.12,48.69 61.51,48.3 61.72,48.3 61.94,48.52 61.94,48.68 61.53,49.09 61.53,49.25 61.77,49.5 61.93,49.5 62.58,48.84 62.74,48.84 62.97,49.07 62.97,49.26 62.34,49.9 62.34,50.06 62.59,50.31 63,50.31 63.32,49.99 63.48,49.99 63.8,50.31 65.19,50.31 73.24,58.36 73.24,58.84 v1(73.82,59.42)
  BOTTOM w0.076: U1.BA56 75.43,67 75.29,66.86 75.28,66.85 75.28,66.85 75.27,66.83 75.16,66.6 75.16,66.6 75.16,66.34 75.32,66.18 75.32,65.13 74.2,64.02
  BOTTOM w0.165: 74.2,64.02 72.96,62.78 72.96,60.28 v1(73.82,59.42) ; v1(46.78,33.14) 47.23,33.14 48.28,34.18 J21.109
M_A_CKE1: length 58
  IN1 w0.114: v1(49.03,28.96) 47.87,30.11 47.05,30.11 46.85,29.91 46.85,29.3 46.64,29.1 46.29,29.1 46.08,29.3 46.08,30.52 45.73,30.87 45.73,34.57 62.26,51.1 64.79,51.1 72.23,58.54 72.23,59.86 v1(73.81,61.45)
  BOTTOM w0.076: 73.37,62.52 73.37,62.85 74.41,63.89 75.55,65.04 75.55,66.37 U1.BB56
  BOTTOM w0.165: v1(73.81,61.45) 73.37,61.89 73.37,62.52 ; v1(49.03,28.96) 48.53,28.46 J21.110
M_A_DDRCLK0_1866M: length 59.1
  IN1 w0.089: v1(76.79,69.91) 76.96,69.75 77.29,69.75 77.5,69.53 77.5,68.9 77.89,68.52 77.89,65.34 79.99,63.24 79.99,52.25 79.33,51.59 79.33,51.47 79.63,51.17 79.63,50.88 79.25,50.51 78.97,50.51 78.67,50.81 78.55,50.81 78.29,50.55 78.29,50.42 78.58,50.12 78.58,49.84 78.21,49.47 77.93,49.47 77.63,49.77 77.5,49.77 68.27,40.54 62.71,40.54 57.18,35 57.18,32.98 57.18,32.98 57.18,32.97 56.99,32.78 56.99,32.63 56.59,32.23 v1(56.59,32.02)
  BOTTOM w0.076: U1.AT53 v1(76.79,69.91)
  BOTTOM w0.102: J21.137 55.28,34.33 55.43,34.18 55.43,33.05 55.6,32.88 56.11,32.37 56.48,32.37 56.59,32.27 v1(56.59,32.02)
M_A_DDRCLK1_1866M: length 59.8
  IN1 w0.089: v1(54.92,28.96) 54.92,29.13 55.11,29.32 55.3,29.32 55.69,29.7 55.69,33.01 56.05,33.38 56.05,34.85 62.43,41.22 67.99,41.22 79.3,52.53 79.3,62.9 77,65.21 77,66.26 76.34,66.92 76.34,69.38 v1(75.84,69.88)
  BOTTOM w0.076: U1.AT55 v1(75.84,69.88)
  BOTTOM w0.102: J21.138 55.53,28.08 55.67,28.23 55.67,29.09 55.39,29.37 55.05,29.37 54.92,29.25 v1(54.92,28.96)
M_A_DQ0: length 72.6
  IN1 w0.076: v1(63.05,72.76) 62.3,73.51 57.43,73.51 51.97,68.05 51.97,64.73 49.59,62.35 49.59,62.24 49.87,61.97 49.87,61.86 49.67,61.66 49.56,61.66 49.29,61.94 49.18,61.94 48.98,61.74 48.98,61.63 49.26,61.36 49.26,61.25 49.06,61.05 48.95,61.05 48.68,61.33 48.57,61.33 48.37,61.13 48.37,61.02 48.65,60.75 48.65,60.64 48.45,60.44 48.34,60.44 48.07,60.72 47.96,60.72 47.76,60.52 47.76,60.41 48.03,60.14 48.03,60.03 47.84,59.83 47.73,59.83 47.45,60.11 47.35,60.11 47.15,59.91 47.15,59.8 47.42,59.53 47.42,59.42 47.23,59.22 47.12,59.22 46.84,59.49 46.74,59.49 46.54,59.3 46.54,59.19 46.81,58.91 46.81,58.81 46.61,58.61 46.51,58.61 46.23,58.88 46.12,58.88 21.78,34.54 21.78,33.72 v1(22.21,33.29)
  BOTTOM w0.076: v1(63.05,72.76) 63.32,73.03 65.05,73.03 65.32,73.3 66.7,73.3 U1.AL71
  BOTTOM w0.102: v1(22.21,33.29) 22.78,33.86 J21.7
M_A_DQ1: length 74
  IN1 w0.076: v1(63.82,72.11) 63.82,73.28 63.27,73.83 57.34,73.83 51.68,68.17 51.68,64.85 21.42,34.59 21.42,32.8 v1(22.21,32.02)
  BOTTOM w0.076: v1(63.82,72.11) 63.92,72.21 66.14,72.21 66.35,72.42 66.86,72.42 66.89,72.41 66.97,72.38 67.09,72.38 67.31,72.44 67.45,72.44 67.61,72.39 67.79,72.39 67.95,72.46 68.46,72.46 68.67,72.67 U1.AL68
  BOTTOM w0.102: J21.3 21.78,32.45 v1(22.21,32.02)
M_A_DQ2: length 74.3
  IN1 w0.076: v1(60.12,71.1) 59.36,70.34 57.72,70.34 54.36,66.98 54.36,62.72 34.46,42.82 34.36,42.82 33.96,43.22 33.85,43.22 33.65,43.02 33.65,42.92 34.05,42.52 34.05,42.41 33.85,42.21 33.75,42.21 33.35,42.61 33.24,42.61 33.04,42.41 33.04,42.3 33.44,41.9 33.44,41.8 33.24,41.6 33.13,41.6 32.73,42 32.63,42 32.43,41.8 32.43,41.69 32.83,41.29 32.83,41.19 32.63,40.99 32.52,40.99 32.12,41.39 32.02,41.39 31.82,41.19 31.82,41.08 32.22,40.68 32.22,40.57 32.02,40.38 31.91,40.38 31.51,40.78 31.4,40.78 31.21,40.58 31.21,40.47 31.61,40.07 31.61,39.96 31.41,39.77 31.3,39.77 30.9,40.17 30.79,40.17 30.6,39.97 30.6,39.86 31,39.46 31,39.35 30.8,39.15 30.69,39.15 30.29,39.55 30.18,39.55 29.98,39.36 29.98,39.25 30.38,38.85 30.38,38.74 30.26,38.61 29.23,38.61 25.76,35.14 25.76,34.53 26.17,34.13 26.17,33.41 26.05,33.29 v1(25.78,33.29)
  BOTTOM w0.076: U1.AN68 68.67,72.09 68.09,71.8 67.59,71.8 67.35,71.56 66.45,71.56 66.41,71.52 64.73,71.52 64.26,71.05 62.09,71.05
  BOTTOM w0.102: v1(25.78,33.29) 26.28,33.79 J21.21 ; 62.09,71.05 61.56,71.05 61.14,70.63 60.59,70.63 v1(60.12,71.1)
M_A_DQ3: length 73.5
  IN1 w0.076: v1(58.85,71.1) 57.65,71.1 53.78,67.22 53.78,62.96 38.5,47.68 38.39,47.68 37.99,48.08 37.88,48.08 37.68,47.88 37.68,47.77 38.08,47.38 38.08,47.27 37.89,47.07 37.78,47.07 37.38,47.47 37.27,47.47 37.07,47.27 37.07,47.16 37.47,46.76 37.47,46.66 37.27,46.46 37.17,46.46 36.77,46.86 36.66,46.86 36.46,46.66 36.46,46.55 36.86,46.15 36.86,46.05 36.75,45.93 35.72,45.93 25,35.21 25,29.3 25.34,28.96 v1(25.53,28.96)
  BOTTOM w0.076: 63.47,71.79 63.55,71.71 64,71.71 64.34,72.05 66.21,72.05 66.42,72.26 66.82,72.26 66.94,72.2 66.96,72.2 66.97,72.2 66.98,72.2 67.08,72.2 67.31,72.27 67.44,72.27 67.66,72.19 67.91,72.19 U1.AN69
  BOTTOM w0.102: J21.16 25.03,28.46 v1(25.53,28.96) ; v1(58.85,71.1) 59.54,71.79 63.47,71.79
M_A_DQ4: length 73.6
  IN1 w0.076: v1(22.06,28.76) 22.69,29.4 22.69,35.04 44.23,56.58 44.34,56.58 44.6,56.31 44.71,56.31 44.91,56.51 44.91,56.62 44.65,56.88 44.65,56.99 44.84,57.19 44.95,57.19 45.21,56.93 45.32,56.93 45.52,57.12 45.52,57.23 45.26,57.49 45.26,57.6 45.71,58.06 46.65,58.06 52.26,63.67 52.26,66.61 52.26,67.93 57.49,73.15 62.05,73.15 v1(62.45,72.75)
  BOTTOM w0.076: v1(62.45,72.75) 62.94,73.23 64.87,73.23 65.1,73.47 66.45,73.47 66.56,73.59 66.84,73.59 67.05,73.48 67.22,73.32 U1.AL70
  BOTTOM w0.102: J21.4 22.03,28.73 v1(22.06,28.76)
M_A_DQ5: length 74.1
  IN1 w0.076: v1(59.89,72.7) 57.45,72.7 52.56,67.81 52.56,65.95 52.56,63.46 44.5,55.41 44.39,55.41 44.1,55.7 44,55.7 43.8,55.5 43.8,55.4 44.09,55.1 44.09,55 43.89,54.8 43.78,54.8 43.49,55.09 43.38,55.09 43.19,54.89 43.19,54.78 43.48,54.49 43.48,54.39 42.97,53.88 41.95,53.88 23,34.93 23,29.49 v1(23.53,28.96)
  BOTTOM w0.076: 62.26,73.46 64.74,73.46 64.92,73.64 66.33,73.64 66.48,73.79 66.76,73.79 67.27,73.6 67.33,73.6 67.38,73.59 67.75,73.59 U1.AL69
  BOTTOM w0.102: 62.26,73.46 60.65,73.46 v1(59.89,72.7) ; J21.8 23.03,28.46 v1(23.53,28.96)
M_A_DQ6: length 72.6
  IN1 w0.076: v1(25.78,32.02) 26.51,32.75 26.51,34.56 26.1,34.96 26.1,35.07 26.3,35.27 26.41,35.27 26.81,34.86 26.92,34.86 27.12,35.06 27.12,35.17 26.71,35.57 26.71,35.68 26.91,35.88 27.02,35.88 27.42,35.47 27.53,35.47 27.73,35.67 27.73,35.78 27.33,36.18 27.33,36.29 27.52,36.49 27.63,36.49 28.03,36.09 28.14,36.09 28.34,36.28 28.34,36.39 27.94,36.79 27.94,36.9 28.13,37.1 28.24,37.1 28.64,36.7 28.75,36.7 28.95,36.89 28.95,37 28.55,37.4 28.55,37.51 28.75,37.71 28.85,37.71 29.26,37.31 29.36,37.31 29.56,37.51 29.56,37.61 29.16,38.02 29.16,38.12 29.36,38.32 29.46,38.32 29.87,37.92 29.97,37.92 54.65,62.6 54.65,66.86 57.81,70.01 59.67,70.01 v1(60.75,71.1)
  BOTTOM w0.076: v1(60.75,71.1) 60.9,71.25 64.18,71.25 64.61,71.68 66.32,71.68 66.36,71.73 67.11,71.73 U1.AN70
  BOTTOM w0.102: v1(25.78,32.02) 25.28,32.52 J21.17
M_A_DQ7: length 71.6
  IN1 w0.076: v1(59.48,71.1) 59.05,70.67 57.63,70.67 54.07,67.1 54.07,62.84 36.47,45.24 36.36,45.24 35.96,45.64 35.85,45.64 35.65,45.44 35.65,45.34 36.05,44.93 36.05,44.83 35.86,44.63 35.75,44.63 35.35,45.03 35.24,45.03 35.04,44.83 35.04,44.72 35.44,44.32 35.44,44.21 35.25,44.02 35.14,44.02 34.74,44.42 34.63,44.42 34.43,44.22 34.43,44.11 34.83,43.71 34.83,43.6 34.61,43.38 34.44,43.38 34.14,43.69 33.89,43.69 25.36,35.15 25.36,30.4 v1(25.53,30.23)
  BOTTOM w0.076: 63.45,71.51 64.14,71.51 64.49,71.87 66.27,71.87 66.35,71.95 66.39,71.99 U1.AN71
  BOTTOM w0.102: v1(25.53,30.23) 26.03,29.73 J21.20 ; 63.45,71.51 v2(62.4,71.51) 59.9,71.51 v1(59.48,71.1)
M_A_DQ8: length 66.8
  IN1 w0.076: v1(62,69.95) 61.22,69.18 58.23,69.18 55.53,66.48 55.53,62.23 27.38,34.09 27.38,31.48 27.46,31.41 28.14,31.41 28.21,31.33 28.21,31.05 28.14,30.97 27.46,30.97 27.38,30.9 27.38,30.37 v1(27.53,30.23)
  BOTTOM w0.076: v1(62,69.95) 62.7,70.66 64.6,70.66 65.12,71.18 66.54,71.18 66.58,71.22 66.96,71.22 67.22,70.96 U1.AR70
  BOTTOM w0.102: v1(27.53,30.23) 28.03,29.73 J21.28
M_A_DQ9: length 67.7
  IN1 w0.076: v1(61.36,69.95) 60.91,69.51 58.12,69.51 55.24,66.62 55.24,62.35 27.09,34.21 27.09,30.81 26.81,30.53 26.81,29.25 27.1,28.96 v1(27.53,28.96)
  BOTTOM w0.076: 62.49,70.85 64.48,70.85 64.99,71.35 66.47,71.35 66.51,71.38 67.37,71.38 67.59,71.16 68.14,71.16 U1.AR68
  BOTTOM w0.102: v1(61.36,69.95) 62.25,70.85 62.49,70.85 ; v1(27.53,28.96) 27.03,28.46 J21.24
M_A_DQ10: length 64.9
  IN1 w0.076: v1(31.03,30.23) 30.35,30.91 30.35,34.06 30.39,34.1 49.65,53.36 50.8,53.36 50.92,53.48 50.92,53.59 50.56,53.94 50.56,54.05 50.75,54.25 50.86,54.25 51.22,53.89 51.33,53.89 51.53,54.09 51.53,54.2 51.16,54.56 51.16,54.67 51.36,54.87 51.47,54.87 51.83,54.5 51.94,54.5 52.14,54.7 52.14,54.81 51.78,55.17 51.78,55.28 51.98,55.47 52.08,55.47 52.44,55.11 52.55,55.11 57.17,59.73 60.02,59.73 63.99,63.71 v1(63.99,68.52)
  BOTTOM w0.076: v1(63.99,68.52) 64.02,68.54 64.06,68.54 64.54,69.02 64.97,69.02 65.49,69.53 66.61,69.53 U1.AU71
  BOTTOM w0.102: v1(31.03,30.23) 30.53,29.73 J21.38
M_A_DQ11: length 67.1
  IN1 w0.076: v1(31.03,28.96) 31.48,29.42 31.48,30.62 30.64,31.46 30.64,33.94 48.89,52.19 49.24,52.19 49.53,51.89 49.75,51.89 50,52.15 50,52.34 49.57,52.76 49.57,52.87 49.77,53.07 49.88,53.07 50.35,52.6 50.45,52.6 57.29,59.44 60.14,59.44 64.42,63.72 64.42,68.27 64.54,68.38 v1(64.54,69.95)
  BOTTOM w0.076: v1(64.54,69.95) 64.87,69.95 65.59,70.67 66.35,70.67 66.49,70.53 66.86,70.53 66.89,70.55 66.97,70.58 67.09,70.58 67.31,70.51 67.45,70.51 67.61,70.57 68.2,70.57 68.22,70.59 68.46,70.59 68.67,70.39 U1.AU68
  BOTTOM w0.102: v1(31.03,28.96) 31.53,28.46 J21.42
M_A_DQ12: length 65.6
  IN1 w0.076: v1(62.66,69.95) 61.52,68.82 58.3,68.82 55.82,66.34 55.82,61.89 55.25,61.33 55.25,61 55.72,60.53 55.72,60.42 55.53,60.23 55.41,60.23 54.95,60.69 54.84,60.69 54.64,60.49 54.64,60.39 55.1,59.92 55.1,59.81 54.92,59.62 54.8,59.62 54.34,60.08 54.23,60.08 54.03,59.88 54.03,59.77 54.49,59.31 54.49,59.19 54.31,59.01 54.19,59.01 53.73,59.47 53.62,59.47 53.42,59.27 53.42,59.16 53.88,58.7 53.88,58.58 53.69,58.39 53.58,58.39 53.11,58.86 52.74,58.86 28.17,34.29 28.17,33.69 v1(27.78,33.29)
  BOTTOM w0.076: v1(62.66,69.95) 63.19,70.49 64.7,70.49 65.22,71.01 66.67,71.01 U1.AR71
  BOTTOM w0.102: v1(27.78,33.29) 28.28,33.79 J21.29
M_A_DQ13: length 66.8
  IN1 w0.076: v1(27.78,32.02) 28.48,32.72 28.48,33.96 51.27,56.76 52.47,56.76 52.54,56.83 52.54,56.94 52.08,57.4 52.08,57.51 52.28,57.71 52.38,57.71 52.85,57.24 52.96,57.24 53.15,57.44 53.15,57.55 52.69,58.01 52.69,58.12 52.89,58.32 53,58.32 53.46,57.85 53.57,57.85 53.84,58.12 56.11,60.4 56.11,66.17 58.4,68.47 61.78,68.47 62.87,69.56 63.5,69.56 v1(63.9,69.95)
  BOTTOM w0.076: U1.AR69 67.91,70.76 67.66,70.76 67.44,70.69 67.31,70.69 67.08,70.75 66.98,70.75 66.97,70.76 66.96,70.75 66.94,70.75 66.82,70.7 66.56,70.7 66.42,70.84 65.31,70.84 64.78,70.31 64.26,70.31 v1(63.9,69.95)
  BOTTOM w0.102: v1(27.78,32.02) 27.28,32.52 J21.25
M_A_DQ14: length 65.5
  IN1 w0.076: v1(31.18,33.92) 46.29,49.04 47.3,49.04 47.39,49.13 47.39,49.24 46.93,49.7 46.93,49.81 47.13,50 47.24,50 47.7,49.54 47.81,49.54 48,49.74 48,49.85 47.54,50.31 47.54,50.42 47.74,50.61 47.85,50.61 48.31,50.15 48.42,50.15 48.61,50.35 48.61,50.46 48.15,50.92 48.15,51.03 48.35,51.23 48.46,51.23 48.92,50.76 49.03,50.76 49.23,50.96 49.23,51.07 48.76,51.53 48.76,51.64 48.96,51.84 49.07,51.84 49.53,51.37 49.64,51.37 53.82,55.55 53.92,55.55 54.15,55.33 54.26,55.33 54.45,55.52 54.45,55.63 54.23,55.86 54.23,55.96 54.43,56.16 54.53,56.16 54.76,55.94 54.87,55.94 55.06,56.14 55.06,56.24 54.84,56.47 54.84,56.58 55.04,56.77 55.15,56.77 55.37,56.55 55.48,56.55 55.68,56.75 55.68,56.85 55.45,57.08 55.45,57.19 55.65,57.38 55.76,57.38 55.98,57.16 56.09,57.16 56.29,57.36 56.29,57.46 56.06,57.69 56.06,57.8 56.26,58 56.37,58 56.59,57.77 56.7,57.77 56.9,57.97 56.9,58.08 56.67,58.3 56.67,58.41 56.87,58.61 56.98,58.61 57.2,58.38 57.31,58.38 57.51,58.58 57.51,58.69 57.28,58.91 57.28,59.02 57.41,59.15 60.26,59.15 64.89,63.78 v1(64.89,68.1)
  BOTTOM w0.076: U1.AU70 67.09,69.36 65.62,69.36 64.89,68.64 v1(64.89,68.1)
  BOTTOM w0.102: J21.41 31.28,34.02 v1(31.18,33.92)
M_A_DQ15: length 66.1
  IN1 w0.076: v1(31.18,32.65) 31.73,33.21 31.73,33.88 46.53,48.68 48.02,48.68 48.17,48.82 48.17,48.93 47.94,49.15 47.94,49.26 48.14,49.46 48.25,49.46 48.47,49.23 48.58,49.23 48.78,49.43 48.78,49.54 48.55,49.77 48.55,49.87 48.75,50.07 48.86,50.07 49.08,49.85 49.19,49.85 49.39,50.04 49.39,50.15 49.16,50.38 49.16,50.48 49.36,50.68 49.47,50.68 49.69,50.46 49.8,50.46 50,50.65 50,50.76 49.77,50.99 49.77,51.1 49.97,51.29 50.08,51.29 50.3,51.07 50.41,51.07 50.61,51.27 50.61,51.37 50.38,51.6 50.38,51.71 50.58,51.9 50.69,51.9 50.92,51.68 51.02,51.68 51.22,51.88 51.22,51.98 51,52.21 51,52.32 51.19,52.52 51.3,52.52 51.53,52.29 51.63,52.29 51.83,52.49 51.83,52.6 51.61,52.82 51.61,52.93 51.8,53.13 51.91,53.13 52.14,52.9 52.25,52.9 52.44,53.1 52.44,53.21 52.22,53.43 52.22,53.54 52.42,53.74 52.52,53.74 52.75,53.51 52.86,53.51 53.05,53.71 53.05,53.82 52.83,54.04 52.83,54.15 53.03,54.35 53.13,54.35 53.36,54.12 53.47,54.12 53.67,54.32 53.67,54.43 53.44,54.65 53.44,54.76 53.64,54.96 53.75,54.96 53.97,54.73 54.08,54.73 58.2,58.86 60.38,58.86 65.35,63.82 v1(65.35,68.53)
  BOTTOM w0.076: v1(65.35,68.53) 65.35,68.71 65.82,69.18 67.17,69.18 67.25,69.26 67.43,69.26 67.81,69.64 U1.AU69
  BOTTOM w0.102: v1(31.18,32.65) 31,32.65 30.28,33.37 J21.37
M_A_DQ16: length 57.1
  IN4 w0.076: v1(71.03,28.94) 70.13,29.83 70.13,49.9 64.23,55.8 64.23,68.22 64.47,68.46 64.47,68.85 65.39,69.77 65.39,72.91 68.43,75.95 70.19,75.95 v1(70.93,75.21)
  BOTTOM w0.076: U1.AF65 v1(70.93,75.21)
  BOTTOM w0.102: J21.194 71.53,28.44 v1(71.03,28.94)
M_A_DQ17: length 55.4
  IN4 w0.076: v1(71.57,75.21) 71.14,74.78 68.86,74.78 66.63,72.55 66.63,68.54 66.23,68.13 65.92,68.13 65.57,67.79 65.57,63.46 65.67,63.37 65.67,55.61 71.71,49.56 71.71,36.09 71.64,36.02 71.3,36.02 71.23,35.94 71.23,35.66 71.3,35.59 71.64,35.59 71.71,35.51 71.71,35.23 71.64,35.15 71.3,35.15 71.23,35.08 71.23,34.8 71.3,34.72 71.64,34.72 71.71,34.65 71.71,32.46 v1(71.27,32.02)
  BOTTOM w0.076: U1.AF64 v1(71.57,75.21)
  BOTTOM w0.102: v1(71.27,32.02) 71.78,32.52 J21.195
M_A_DQ18: length 55.8
  IN4 w0.076: v1(70.93,73.38) 70.38,72.82 69.32,72.82 68.75,72.25 68.75,71.33 67.99,70.57 67.99,68.53 68.97,67.55 68.97,66.81 68.59,66.43 68.59,56.06 74.96,49.69 74.96,49.45 74.88,49.37 74.52,49.37 74.44,49.3 74.44,49.02 74.52,48.94 74.88,48.94 74.96,48.87 74.96,48.59 74.88,48.51 74.52,48.51 74.44,48.44 74.44,48.16 74.52,48.08 74.88,48.08 74.96,48 74.96,47.72 74.88,47.65 74.52,47.65 74.44,47.57 74.44,47.29 74.52,47.22 74.88,47.22 74.96,47.14 74.96,46.86 74.88,46.78 74.52,46.78 74.44,46.71 74.44,46.43 74.52,46.35 74.88,46.35 74.96,46.28 74.96,29.37 v1(74.53,28.94)
  BOTTOM w0.076: U1.AK65 v1(70.93,73.38)
  BOTTOM w0.102: v1(74.53,28.94) 74.03,28.44 J21.204
M_A_DQ19: length 56.7
  IN4 w0.076: v1(74.28,32.02) 73.48,32.81 73.48,34.09 72.97,34.6 72.97,42.1 73.04,42.17 73.25,42.17 73.33,42.25 73.33,42.53 73.25,42.6 73.04,42.6 72.97,42.68 72.97,42.96 73.04,43.04 73.25,43.04 73.33,43.11 73.33,43.39 73.25,43.47 73.04,43.47 72.97,43.54 72.97,43.82 73.04,43.9 73.25,43.9 73.33,43.98 73.33,44.26 73.25,44.33 73.04,44.33 72.97,44.41 72.97,44.69 73.04,44.76 73.25,44.76 73.33,44.84 73.33,45.12 73.25,45.2 73.04,45.2 72.97,45.27 72.97,45.55 73.04,45.63 73.25,45.63 73.33,45.7 73.33,45.98 73.25,46.06 73.04,46.06 72.97,46.14 72.97,46.41 73.04,46.49 73.25,46.49 73.33,46.57 73.33,46.85 73.25,46.92 73.04,46.92 72.97,47 72.97,47.28 73.04,47.35 73.25,47.35 73.33,47.43 73.33,47.71 73.25,47.79 73.04,47.79 72.97,47.86 72.97,48.14 73.04,48.22 73.25,48.22 73.33,48.29 73.33,48.57 73.25,48.65 73.04,48.65 72.97,48.73 72.97,49.01 73.04,49.08 73.25,49.08 73.33,49.16 73.33,49.44 73.25,49.51 73.04,49.51 72.97,49.59 72.97,50.28 67.67,55.58 67.67,67.93 67.44,68.16 67.44,72.1 68.88,73.55 69.31,73.55 69.51,73.74 71.2,73.74 v1(71.57,73.38)
  BOTTOM w0.076: U1.AK64 v1(71.57,73.38)
  BOTTOM w0.102: J21.203 73.78,34.3 73.85,34.23 73.85,32.45 v1(74.28,32.02)
M_A_DQ20: length 56
  IN4 w0.076: v1(71.03,30.21) 70.44,30.8 70.44,50.01 64.52,55.92 64.52,68.26 64.65,68.39 64.65,68.77 65.57,69.68 65.57,72.71 68.53,75.67 70.22,75.67 70.3,75.59 v1(70.3,75.21)
  BOTTOM w0.076: U1.AF66 v1(70.3,75.21)
  BOTTOM w0.102: J21.190 70.53,29.71 v1(71.03,30.21)
M_A_DQ21: length 55.6
  IN4 w0.076: v1(69.66,75.21) 68.9,75.21 66.4,72.71 66.4,68.57 66.18,68.34 65.69,68.34 64.88,67.52 64.88,55.98 71,49.86 71,48.37 71.08,48.3 71.23,48.3 71.31,48.22 71.31,47.95 71.23,47.87 71.1,47.87 71.02,47.79 71.02,47.51 71.1,47.43 71.26,47.43 71.34,47.36 71.34,47.08 71.26,47 71.1,47 71.02,46.93 71.02,46.65 71.1,46.57 71.26,46.57 71.34,46.49 71.34,46.22 71.26,46.14 71.09,46.14 71.01,46.06 71.01,45.78 71.09,45.71 71.26,45.71 71.34,45.63 71.34,45.35 71.26,45.28 71.09,45.28 71.01,45.2 71.01,44.92 71.09,44.84 71.26,44.84 71.34,44.77 71.34,44.49 71.26,44.41 71.09,44.41 71.01,44.34 71.01,44.06 71.09,43.98 71.26,43.98 71.34,43.9 71.34,43.62 71.26,43.55 71.1,43.55 71.02,43.47 71.02,43.19 71.1,43.12 71.26,43.12 71.34,43.04 71.34,42.76 71.26,42.68 71.1,42.68 71.02,42.61 71.02,42.33 71.1,42.25 71.26,42.25 71.34,42.18 71.34,41.9 71.26,41.82 71.1,41.82 71.02,41.75 71.02,41.47 71.1,41.39 71.26,41.39 71.34,41.31 71.34,41.03 71.26,40.96 71.1,40.96 71.02,40.88 71.02,40.6 71.1,40.53 71.26,40.53 71.34,40.45 71.34,40.17 71.26,40.09 71.08,40.09 71,40.02 71,39.74 71.08,39.66 71.26,39.66 71.34,39.59 71.34,39.31 71.26,39.23 71.08,39.23 71,39.15 71,38.87 71.08,38.8 71.26,38.8 71.34,38.72 71.34,38.44 71.26,38.37 70.98,38.37 70.88,38.27 70.88,33.68 v1(71.27,33.29)
  BOTTOM w0.076: U1.AF67 v1(69.66,75.21)
  BOTTOM w0.102: J21.191 70.78,33.79 v1(71.27,33.29)
M_A_DQ22: length 54.3
  IN4 w0.076: v1(69.66,73.38) 69.53,73.24 69.04,73.24 67.66,71.86 67.66,68.26 67.98,67.94 67.98,55.78 73.77,49.99 73.77,41.48 73.56,41.27 73.56,41 73.64,40.92 74.2,40.92 74.27,40.84 74.27,40.56 74.2,40.49 73.64,40.49 73.56,40.41 73.56,40.13 73.64,40.06 74.2,40.06 74.27,39.98 74.27,39.7 74.2,39.62 73.64,39.62 73.56,39.55 73.56,39.27 73.64,39.19 74.2,39.19 74.27,39.12 74.27,38.84 74.2,38.76 73.64,38.76 73.56,38.68 73.56,38.4 73.64,38.33 74.2,38.33 74.27,38.25 74.27,37.97 74.2,37.9 73.64,37.9 73.56,37.82 73.56,37.54 73.64,37.46 74.2,37.46 74.27,37.39 74.27,37.11 74.2,37.03 73.64,37.03 73.56,36.96 73.56,36.68 73.64,36.6 74.2,36.6 74.27,36.52 74.27,36.25 74.2,36.17 73.64,36.17 73.56,36.09 73.56,35.81 73.77,35.6 73.77,33.79 v1(74.28,33.29)
  BOTTOM w0.076: U1.AK67 v1(69.66,73.38)
  BOTTOM w0.102: J21.207 74.78,33.79 v1(74.28,33.29)
M_A_DQ23: length 55
  IN4 w0.076: v1(70.3,73.38) 69.92,73 69.13,73 67.83,71.7 67.83,68.34 68.16,68.01 68.16,66.76 68.28,66.64 68.28,55.91 74.08,50.11 74.08,45.41 74.16,45.33 74.53,45.33 74.61,45.26 74.61,44.98 74.53,44.9 74.16,44.9 74.08,44.83 74.08,44.55 74.16,44.47 74.53,44.47 74.61,44.4 74.61,44.12 74.53,44.04 74.16,44.04 74.08,43.96 74.08,43.68 74.16,43.61 74.53,43.61 74.61,43.53 74.61,43.25 74.53,43.18 74.16,43.18 74.08,43.1 74.08,42.82 74.16,42.74 74.53,42.74 74.61,42.67 74.61,42.39 74.53,42.31 74.16,42.31 74.08,42.24 74.08,42.04 74.67,41.45 74.67,30.35 v1(74.53,30.21)
  BOTTOM w0.076: U1.AK66 v1(70.3,73.38)
  BOTTOM w0.102: v1(74.53,30.21) 75.03,29.71 J21.208
M_A_DQ24: length 70.3
  IN4 w0.076: v1(60.99,76.63) 61.81,75.82 63.34,75.82 63.95,75.21 63.95,73.15 63.03,72.23 58.98,72.23 57.85,71.1 57.85,68.42 56.11,66.68 56.11,61.65 68.01,49.76 68.01,29.96 v1(69.03,28.94)
  BOTTOM w0.076: v1(60.99,76.63) 61.38,77.02 62.15,77.02 62.67,77.55 65.56,77.55 67.14,75.97 U1.AF70
  BOTTOM w0.102: J21.186 69.53,28.44 v1(69.03,28.94)
M_A_DQ25: length 72
  IN4 w0.076: v1(59.72,76.63) 57.96,74.87 55.61,72.52 55.61,69.14 54.37,67.9 54.37,59.78 64.19,49.96 64.19,41.76 64.26,41.68 64.48,41.68 64.56,41.61 64.56,41.33 64.48,41.25 64.2,41.25 64.12,41.18 64.12,40.9 64.2,40.82 64.48,40.82 64.56,40.74 64.56,40.46 64.48,40.39 64.2,40.39 64.12,40.31 64.12,40.04 64.2,39.96 64.48,39.96 64.56,39.88 64.56,39.6 64.48,39.52 64.2,39.52 64.12,39.45 64.12,39.17 64.2,39.09 64.48,39.09 64.56,39.02 64.56,38.74 64.48,38.66 64.26,38.66 64.19,38.59 64.19,38.31 64.26,38.23 64.48,38.23 64.56,38.15 64.56,37.87 64.48,37.8 64.26,37.8 64.19,37.72 64.19,37.44 64.26,37.37 64.48,37.37 64.56,37.29 64.56,37.01 64.48,36.93 64.26,36.93 64.19,36.86 64.19,36.58 64.26,36.5 64.48,36.5 64.56,36.43 64.56,36.15 64.48,36.07 64.26,36.07 64.19,35.99 64.19,35.71 64.26,35.64 64.48,35.64 64.56,35.56 64.56,35.28 64.48,35.21 64.26,35.21 64.19,35.13 64.19,34.66 64.35,34.5 64.35,33.21 64.77,32.79 64.77,32.58 64.93,32.42 64.93,31.18 65.9,30.21 v1(66.03,30.21)
  BOTTOM w0.076: U1.AF68 68.28,76.26 67.12,76.26 65.62,77.75 63.81,77.75
  BOTTOM w0.102: v1(59.72,76.63) 60.37,77.28 61.78,77.28 62.26,77.75 63.81,77.75 ; v1(66.03,30.21) 66.53,29.71 J21.174
M_A_DQ26: length 68.7
  IN4 w0.076: v1(66.81,33.28) 66.17,33.93 66.17,34.73 66.09,34.8 65.73,34.8 65.65,34.88 65.65,35.16 65.73,35.24 66.09,35.24 66.17,35.31 66.17,35.59 66.09,35.67 65.73,35.67 65.65,35.74 65.65,36.02 65.73,36.1 66.09,36.1 66.17,36.18 66.17,36.45 66.09,36.53 65.73,36.53 65.65,36.61 65.65,36.89 65.73,36.96 66.09,36.96 66.17,37.04 66.17,37.32 66.09,37.39 65.73,37.39 65.65,37.47 65.65,37.75 65.73,37.83 66.09,37.83 66.17,37.9 66.17,38.18 66.09,38.26 65.73,38.26 65.65,38.33 65.65,38.61 65.73,38.69 66.09,38.69 66.17,38.77 66.17,39.05 66.09,39.12 65.73,39.12 65.65,39.2 65.65,39.48 65.73,39.55 66.09,39.55 66.17,39.63 66.17,39.91 66.09,39.99 65.73,39.99 65.65,40.06 65.65,40.34 65.73,40.42 66.09,40.42 66.17,40.49 66.17,40.77 66.09,40.85 65.73,40.85 65.65,40.92 65.65,41.2 65.73,41.28 66.09,41.28 66.17,41.36 66.17,45.9 66.24,45.97 66.7,45.97 66.78,46.05 66.78,46.33 66.7,46.4 66.24,46.4 66.17,46.48 66.17,46.76 66.24,46.84 66.7,46.84 66.78,46.91 66.78,47.19 66.7,47.27 66.24,47.27 66.17,47.34 66.17,47.62 66.24,47.7 66.7,47.7 66.78,47.78 66.78,48.06 66.7,48.13 66.24,48.13 66.17,48.21 66.17,48.49 66.24,48.56 66.7,48.56 66.78,48.64 66.78,48.92 66.7,48.99 66.24,48.99 66.17,49.07 66.17,49.86 55.25,60.77 55.25,67.54 56.55,68.84 56.55,71.94 58.77,74.15 60.73,74.15 61.04,74.46 v1(61.93,74.46)
  BOTTOM w0.076: U1.AH71 66.55,74.64 66.47,74.72 64.94,74.72 64.29,74.07 63.3,74.07 62.91,74.46 v4(62.55,74.46) v1(61.93,74.46)
  BOTTOM w0.102: v1(66.81,33.28) 66.28,33.82 J21.173
M_A_DQ27: length 71.5
  IN4 w0.076: v1(69.28,33.29) 68.88,33.68 68.88,34.57 68.96,34.65 69.44,34.65 69.52,34.72 69.52,35 69.44,35.08 68.96,35.08 68.88,35.16 68.88,35.43 68.96,35.51 69.44,35.51 69.52,35.59 69.52,35.87 69.44,35.94 68.96,35.94 68.88,36.02 68.88,36.3 68.96,36.37 69.44,36.37 69.52,36.45 69.52,36.73 69.44,36.81 68.96,36.81 68.88,36.88 68.88,37.16 68.96,37.24 69.44,37.24 69.52,37.31 69.52,37.59 69.44,37.67 68.96,37.67 68.88,37.75 68.88,38.03 68.96,38.1 69.44,38.1 69.52,38.18 69.52,38.46 69.44,38.53 68.96,38.53 68.88,38.61 68.88,38.89 68.96,38.97 69.44,38.97 69.52,39.04 69.52,39.32 69.44,39.4 68.96,39.4 68.88,39.47 68.88,39.75 68.96,39.83 69.44,39.83 69.52,39.9 69.52,40.18 69.44,40.26 68.96,40.26 68.88,40.34 68.88,40.62 68.96,40.69 69.44,40.69 69.52,40.77 69.52,41.05 69.44,41.12 68.96,41.12 68.88,41.2 68.88,41.48 68.96,41.56 69.44,41.56 69.52,41.63 69.52,41.91 69.44,41.99 68.96,41.99 68.88,42.06 68.88,42.34 68.96,42.42 69.44,42.42 69.52,42.5 69.52,42.78 69.44,42.85 69.02,42.85 68.94,42.93 68.94,43.21 69.02,43.28 69.44,43.28 69.52,43.36 69.52,43.64 69.44,43.71 69.02,43.71 68.94,43.79 68.94,44.07 69.02,44.15 69.44,44.15 69.52,44.22 69.52,44.5 69.44,44.58 69.02,44.58 68.94,44.65 68.94,44.93 69.02,45.01 69.44,45.01 69.52,45.09 69.52,45.37 69.44,45.44 69.02,45.44 68.94,45.52 68.94,45.8 69.02,45.87 69.44,45.87 69.52,45.95 69.52,49.55 63.65,55.42 63.65,66.85 60.92,69.58 60.92,70.12 61.22,70.42 63.38,70.42 64.93,71.97 64.93,76.51 v1(64.8,76.63)
  BOTTOM w0.076: U1.AH68 68.67,75.3 68.46,75.5 68.01,75.5 67.91,75.57 67.59,75.57 67.47,75.53 67.24,75.53 67.23,75.54 67.23,75.54 67.23,75.54 67.14,75.57 66.94,75.57 66.85,75.54 66.85,75.54 66.46,75.54 65.36,76.63 v1(64.8,76.63)
  BOTTOM w0.102: v1(69.28,33.29) 68.78,33.79 J21.183
M_A_DQ28: length 69.4
  IN4 w0.076: v1(69.03,30.21) 68.3,30.94 68.3,49.9 62.52,55.68 62.52,58.21 62.44,58.29 62.08,58.29 62,58.36 62,58.64 62.08,58.72 62.44,58.72 62.52,58.79 62.52,59.07 62.44,59.15 62.08,59.15 62,59.23 62,59.51 62.08,59.58 62.44,59.58 62.52,59.66 62.52,59.94 62.44,60.01 62.08,60.01 62,60.09 62,60.37 62.08,60.44 62.44,60.44 62.52,60.52 62.52,60.8 62.44,60.88 62.08,60.88 62,60.95 62,61.23 62.08,61.31 62.44,61.31 62.52,61.38 62.52,62.15 62.52,62.16 62.59,62.23 63.06,62.7 63.06,65.91 58.4,70.57 58.4,71.18 59.16,71.94 63.09,71.94 64.32,73.17 64.32,75.32 63.52,76.13 62.77,76.13 v1(62.26,76.63)
  BOTTOM w0.076: v1(62.26,76.63) 62.95,77.32 65.38,77.32 66.72,75.98 U1.AF71
  BOTTOM w0.102: J21.182 68.53,29.71 v1(69.03,30.21)
M_A_DQ29: length 71.1
  IN4 w0.076: v1(63.53,76.63) 64.63,75.54 64.63,72.15 63.23,70.75 61.1,70.75 60.59,70.24 60.59,69.4 63.36,66.64 63.36,61.86 63.28,61.79 62.88,61.79 62.81,61.71 62.81,61.43 62.88,61.36 63.28,61.36 63.36,61.28 63.36,61 63.28,60.92 62.88,60.92 62.81,60.85 62.81,60.57 62.88,60.49 63.28,60.49 63.36,60.42 63.36,60.14 63.28,60.06 62.88,60.06 62.81,59.99 62.81,59.71 62.88,59.63 63.28,59.63 63.36,59.55 63.36,59.27 63.28,59.2 62.88,59.2 62.81,59.12 62.81,58.84 62.88,58.77 63.28,58.77 63.36,58.69 63.36,58.41 63.28,58.33 62.88,58.33 62.81,58.26 62.81,57.98 62.88,57.9 63.28,57.9 63.36,57.83 63.36,57.55 63.28,57.47 62.88,57.47 62.81,57.39 62.81,57.11 62.88,57.04 63.28,57.04 63.36,56.96 63.36,56.68 63.28,56.61 62.88,56.61 62.81,56.53 62.81,56.25 62.88,56.18 63.28,56.18 63.36,56.1 63.36,55.28 68.59,50.05 68.59,49.43 68.67,49.36 69.14,49.36 69.22,49.28 69.22,49 69.14,48.93 68.67,48.93 68.59,48.85 68.59,48.57 68.67,48.49 69.14,48.49 69.22,48.42 69.22,48.14 69.14,48.06 68.67,48.06 68.59,47.99 68.59,47.71 68.67,47.63 69.14,47.63 69.22,47.55 69.22,47.27 69.14,47.2 68.67,47.2 68.59,47.12 68.59,46.84 68.67,46.77 69.14,46.77 69.22,46.69 69.22,46.41 69.14,46.33 68.67,46.33 68.59,46.26 68.59,32.7 v1(69.28,32.02)
  BOTTOM w0.076: U1.AF69 67.91,75.77 67.65,75.77 67.55,75.73 67.55,75.73 67.47,75.7 67.26,75.7 67.17,75.74 66.92,75.74 66.91,75.74 66.82,75.7 66.56,75.7 65.22,77.04 63.94,77.04 v1(63.53,76.63)
  BOTTOM w0.102: v1(69.28,32.02) 69.83,32.57 69.83,34.2 69.78,34.25 J21.187
M_A_DQ30: length 69.9
  IN4 w0.076: v1(60.34,75.03) 59.81,74.5 58.68,74.5 56.2,72.02 56.2,68.9 54.96,67.66 54.96,60.39 65.53,49.82 65.78,49.82 65.86,49.74 65.86,49.46 65.77,49.38 65.29,49.38 65.22,49.3 65.22,49.02 65.29,48.95 65.78,48.95 65.86,48.87 65.86,48.6 65.77,48.52 65.29,48.52 65.22,48.44 65.22,48.16 65.29,48.08 65.78,48.08 65.86,48.01 65.86,47.73 65.77,47.65 65.29,47.65 65.22,47.58 65.22,47.3 65.29,47.22 65.78,47.22 65.86,47.14 65.86,46.87 65.77,46.79 65.29,46.79 65.22,46.71 65.22,46.43 65.29,46.36 65.78,46.36 65.86,46.28 65.86,46.01 65.77,45.93 65.29,45.93 65.22,45.85 65.22,45.57 65.29,45.49 65.78,45.49 65.86,45.42 65.86,45.14 65.77,45.06 65.29,45.06 65.22,44.99 65.22,44.71 65.29,44.63 65.78,44.63 65.86,44.55 65.86,44.28 65.77,44.2 65.29,44.2 65.22,44.12 65.22,43.84 65.29,43.77 65.78,43.77 65.86,43.69 65.86,43.42 65.77,43.33 65.29,43.33 65.22,43.26 65.22,42.98 65.29,42.9 65.78,42.9 65.86,42.83 65.86,42.55 65.77,42.47 65.29,42.47 65.22,42.39 65.22,42.12 65.29,42.04 65.78,42.04 65.86,41.96 65.86,41.69 65.78,41.61 65.36,41.61 65.29,41.54 65.29,33.79 v1(65.76,33.32)
  BOTTOM w0.076: 62.3,73.87 64.38,73.87 64.4,73.9 65.06,74.55 66.35,74.55 66.48,74.43 66.53,74.38 66.82,74.38 67.07,74.5 67.07,74.5 67.08,74.5 67.22,74.64 U1.AH70
  BOTTOM w0.102: 62.3,73.87 61.51,73.87 v1(60.34,75.03) ; v1(65.76,33.32) 65.28,33.81 J21.169
M_A_DQ31: length 70.8
  IN4 w0.076: v1(59.07,75.03) 58.54,75.03 55.91,72.4 55.91,69.02 54.66,67.78 54.66,60.02 64.92,49.76 64.92,49.59 64.85,49.51 64.62,49.51 64.54,49.43 64.54,49.15 64.62,49.08 64.85,49.08 64.92,49 64.92,48.72 64.85,48.65 64.62,48.65 64.54,48.57 64.54,48.29 64.62,48.21 64.85,48.21 64.92,48.14 64.92,47.86 64.85,47.78 64.62,47.78 64.54,47.71 64.54,47.43 64.62,47.35 64.85,47.35 64.92,47.27 64.92,46.99 64.85,46.92 64.62,46.92 64.54,46.84 64.54,46.56 64.62,46.49 64.85,46.49 64.92,46.41 64.92,46.13 64.85,46.05 64.62,46.05 64.54,45.98 64.54,45.7 64.62,45.62 64.85,45.62 64.92,45.55 64.92,45.27 64.85,45.19 64.62,45.19 64.54,45.11 64.54,44.84 64.62,44.76 64.85,44.76 64.92,44.68 64.92,44.4 64.85,44.33 64.62,44.33 64.54,44.25 64.54,43.97 64.62,43.9 64.85,43.9 64.92,43.82 64.92,43.54 64.85,43.46 64.62,43.46 64.54,43.39 64.54,43.11 64.62,43.03 64.85,43.03 64.92,42.96 64.92,42.68 64.85,42.6 64.62,42.6 64.54,42.52 64.54,42.24 64.62,42.17 64.77,42.17 64.85,42.09 64.85,33.42 65.06,33.21 65.06,32.7 65.52,32.24 65.69,32.24 65.92,32.02 65.92,31.79 66.46,31.25 66.46,29.37 v1(66.03,28.94)
  BOTTOM w0.076: 61.66,73.66 64.46,73.66 64.55,73.75 65.18,74.38 66.24,74.38 66.39,74.23 66.39,74.23 66.45,74.17 66.62,74.17 66.8,74.21 66.86,74.21 66.91,74.24 67.09,74.27 67.44,74.27 67.81,74.64 U1.AH69
  BOTTOM w0.102: 61.66,73.66 60.44,73.66 v1(59.07,75.03) ; v1(66.03,28.94) 65.53,28.44 J21.170
M_A_DQ32: length 59.9
  IN1 w0.076: v1(33.53,30.36) 33.15,30.74 33.15,32.37 33.64,32.87 33.64,32.87 33.81,33.05 33.81,33.77 43.4,43.35 44.76,43.35 58.76,57.35 61.25,57.35 65.03,61.13 v1(65.27,61.13)
  BOTTOM w0.076: U1.BB65 70.37,66.39 70.37,65.48 69.64,64.75 66.47,64.75 66.18,64.45 65.95,64.22 65.95,63.89
  BOTTOM w0.102: 65.95,63.89 65.95,61.8 v1(65.27,61.13) ; J21.46 32.53,28.25 32.45,28.33 32.45,29.4 33.4,30.36 v1(33.53,30.36)
M_A_DQ33: length 61.6
  IN1 w0.076: v1(36.53,28.33) 35.83,29.02 35.83,34.06 43.9,42.13 45.24,42.13 58.02,54.91 58.94,54.91 60.16,56.13 62.18,56.13 v1(65.27,59.22)
  BOTTOM w0.076: 68.39,64.12 68.59,64.12 68.67,64.2 69.96,64.2 71.52,65.76 71.52,66.07 71.37,66.22 71.37,66.64 71.41,66.75 71.41,66.87 71.41,66.89 71.35,67.09 71.35,67.23 71.4,67.39 71.4,67.57 71.33,67.73 71.33,68.24 71.12,68.45 U1.AW65
  BOTTOM w0.102: 68.39,64.12 66.91,64.12 66.71,63.92 66.71,60.66 v1(65.27,59.22) ; J21.62 v1(36.53,28.33)
M_A_DQ34: length 62.1
  IN1 w0.076: v1(36.51,33.14) 36.81,33.14 36.91,33.24 36.91,34.03 44.43,41.55 45.51,41.55 55.27,51.31 55.5,51.31 55.74,51.07 55.92,51.07 56.1,51.25 56.1,51.35 55.76,51.69 55.76,51.8 55.96,52 56.07,52 56.4,51.66 56.51,51.66 56.71,51.86 56.71,51.97 56.37,52.3 56.37,52.41 56.57,52.61 56.68,52.61 57.02,52.27 57.12,52.27 57.32,52.47 57.32,52.58 56.98,52.91 56.98,53.02 57.18,53.22 57.29,53.22 57.63,52.88 57.73,52.88 57.93,53.08 57.93,53.19 57.6,53.52 57.6,53.63 57.79,53.83 57.9,53.83 58.24,53.49 58.35,53.49 60.4,55.55 62.71,55.55 66.26,59.1 66.26,60.26 66.35,60.35 66.55,60.35 66.69,60.22 66.69,59.82 66.78,59.73 67.01,59.73 67.12,59.84 v1(67.12,60.4)
  BOTTOM w0.076: U1.AW63 71.7,68.23 72.01,67.92 72.01,67.37 72.23,67.15 72.23,65.51 70.24,63.52 69.03,63.52 68.87,63.36
  BOTTOM w0.102: 68.87,63.36 68.11,62.6 68.11,61.39 v1(67.12,60.4) ; v1(36.51,33.14) 36.97,33.59 36.97,34.02 36.78,34.21 J21.63
M_A_DQ35: length 61.2
  IN1 w0.076: v1(32.45,33.77) 44.49,45.82 45.99,45.82 46.09,45.92 46.09,46.03 45.56,46.57 45.56,46.68 45.76,46.87 45.86,46.87 46.4,46.34 46.51,46.34 46.7,46.53 46.7,46.64 46.17,47.18 46.17,47.29 46.37,47.48 46.47,47.48 47.01,46.95 47.12,46.95 47.32,47.15 47.32,47.25 46.78,47.79 46.78,47.9 46.98,48.1 47.09,48.1 47.62,47.56 47.73,47.56 58.44,58.27 60.56,58.27 66.02,63.74 v1(67.12,63.74)
  BOTTOM w0.076: 68.05,63.74 68.46,63.74 68.73,64.01 70.03,64.01 71.71,65.69 71.71,66.16 71.53,66.34 71.53,66.6 71.59,66.72 71.59,66.86 71.51,67.12 71.51,67.2 71.6,67.44 71.6,67.7 U1.AY63
  BOTTOM w0.102: 68.05,63.74 v1(67.12,63.74) ; J21.45 32.28,33.95 v1(32.45,33.77)
M_A_DQ36: length 60.4
  IN1 w0.076: v1(33.53,29.09) 33.09,29.09 32.85,29.32 32.85,32.49 33.35,32.99 33.35,32.99 33.52,33.17 33.52,33.89 43.28,43.65 44.64,43.65 58.64,57.65 61.13,57.65 65.25,61.76 v1(65.27,61.76)
  BOTTOM w0.076: U1.BA65 70.47,67 70.33,66.86 70.33,66.85 70.32,66.85 70.31,66.83 70.27,66.74 70.21,66.6 70.21,65.6 69.52,64.91 66.35,64.91 65.67,64.23 65.67,63.69
  BOTTOM w0.102: v1(65.27,61.76) 65.67,62.16 65.67,63.69 ; J21.50 v1(33.53,29.09)
M_A_DQ37: length 61
  IN1 w0.076: v1(65.27,62.4) 60.81,57.94 58.52,57.94 45.64,45.06 45.53,45.06 45.07,45.52 44.96,45.52 44.76,45.33 44.76,45.22 45.23,44.75 45.23,44.64 45.03,44.45 44.92,44.45 44.46,44.91 44.35,44.91 44.15,44.72 44.15,44.61 44.62,44.14 44.62,44.03 44.52,43.94 43.16,43.94 33.05,33.84 33.05,33.11 v1(32.45,32.5)
  BOTTOM w0.076: U1.AY65 70.47,67.59 70.21,67.33 70.21,67.04 70.15,66.91 70.15,66.87 70.13,66.83 70.04,66.64 70.04,65.68 69.44,65.08 66.24,65.08 65.87,64.71
  BOTTOM w0.102: 65.87,64.71 65.27,64.11 v1(65.27,62.4) ; J21.49 33.28,33.33 v1(32.45,32.5)
M_A_DQ38: length 60.8
  IN1 w0.076: v1(67.12,61.79) 67.52,61.39 67.52,59.74 63.04,55.26 60.52,55.26 55.84,50.57 55.73,50.57 55.45,50.85 55.34,50.85 55.15,50.65 55.15,50.54 55.42,50.26 55.42,50.16 55.22,49.96 55.14,49.96 54.79,50.31 54.68,50.31 54.48,50.11 54.48,49.98 54.81,49.65 54.81,49.55 54.61,49.35 54.52,49.35 54.17,49.69 54.06,49.69 53.87,49.49 53.87,49.38 54.2,49.04 54.2,48.93 54.04,48.78 53.15,48.78 45.63,41.26 44.55,41.26 37.2,33.91 37.2,32.11 36.96,31.87 v1(36.51,31.87)
  BOTTOM w0.076: U1.BA63 71.8,66.93 72.06,66.67 72.06,65.58 70.17,63.68 68.89,63.68 68.44,63.23
  BOTTOM w0.102: v1(67.12,61.79) 67.83,62.49 67.83,62.62 68.44,63.23 ; J21.59 35.78,32.61 v1(36.51,31.87)
M_A_DQ39: length 59.7
  IN1 w0.076: v1(36.53,29.6) 36.12,30 36.12,33.94 44.03,41.84 45.39,41.84 57.75,54.21 58.09,54.55 58.99,54.55 60.28,55.84 62.47,55.84 65.88,59.26 65.88,61.18 66.01,61.31 66.21,61.31 66.3,61.22 66.3,61.03 66.42,60.9 66.63,60.9 66.71,60.98 66.71,62.02 v1(67.12,62.44)
  BOTTOM w0.076: U1.BB63 71.88,66.42 71.88,65.62 70.1,63.85 68.8,63.85 68.47,63.51 68.2,63.51 68.08,63.39
  BOTTOM w0.102: 68.08,63.39 v1(67.12,62.44) ; v1(36.53,29.6) 36.22,29.6 35.53,28.9 J21.58
M_A_DQ40: length 58.6
  IN1 w0.076: v1(38.02,30.23) 38.24,30.45 38.24,33.71 43.92,39.38 45,39.38 45.19,39.58 45.19,39.69 44.8,40.08 44.8,40.18 45,40.38 45.11,40.38 45.5,39.99 45.61,39.99 53.52,47.9 54.41,47.9 60.89,54.38 63.41,54.38 68.35,59.32 68.35,60.95 v1(69.25,61.85)
  BOTTOM w0.076: U1.BA61 72.83,66.92 72.56,66.66 72.56,65.37 69.94,62.74 69.94,62.53 69.77,62.37
  BOTTOM w0.102: J21.66 37.53,29.73 v1(38.02,30.23) ; 69.77,62.37 v1(69.25,61.85)
M_A_DQ41: length 59.9
  IN1 w0.076: v1(69.25,63.15) 68.02,61.92 68.02,59.41 63.28,54.67 60.77,54.67 54.29,48.19 53.39,48.19 45.87,40.67 44.79,40.67 37.93,33.82 37.93,30.9 37.45,30.42 37.45,29.16 37.65,28.96 v1(38.02,28.96)
  BOTTOM w0.076: 69.95,63.15 70.11,63.15 72.4,65.44 72.4,67.18 72.6,67.39 72.6,67.93 72.93,68.26 U1.AW61
  BOTTOM w0.102: 69.95,63.15 v1(69.25,63.15) ; J21.70 38.53,28.46 v1(38.02,28.96)
M_A_DQ42: length 58.7
  IN1 w0.076: v1(71.19,60.08) 70.49,59.38 70.49,58.49 64.29,52.29 61.76,52.29 52.87,43.4 52.76,43.4 52.43,43.74 52.32,43.74 52.12,43.54 52.12,43.43 52.46,43.09 52.46,42.99 52.26,42.79 52.15,42.79 51.82,43.13 51.71,43.13 51.51,42.93 51.51,42.82 51.85,42.48 51.85,42.38 51.65,42.18 51.54,42.18 51.2,42.52 51.1,42.52 50.9,42.32 50.9,42.21 51.24,41.87 51.24,41.76 51.04,41.57 50.93,41.57 50.59,41.91 50.49,41.91 50.29,41.71 50.29,41.6 50.63,41.26 50.63,41.15 50.5,41.02 49.6,41.02 42.4,33.82 42.4,32.38 v1(42.91,31.87)
  BOTTOM w0.076: 72.02,62.22 72.02,62.89 73.71,64.59 74.21,65.09 74.21,66.44 U1.BB59
  BOTTOM w0.102: 72.02,62.22 72.02,60.91 v1(71.19,60.08) ; J21.79 40.78,33.9 42.8,31.87 v1(42.91,31.87)
M_A_DQ43: length 60.9
  IN1 w0.076: v1(41.53,28.96) 41.01,29.47 41.01,30.33 42.08,31.39 42.08,33.91 52.2,44.03 53.09,44.03 53.24,44.18 53.24,44.29 52.95,44.57 52.95,44.68 53.15,44.88 53.26,44.88 53.54,44.59 53.65,44.59 53.85,44.79 53.85,44.9 53.56,45.18 53.56,45.29 53.76,45.49 53.87,45.49 54.15,45.2 54.26,45.2 54.46,45.4 54.46,45.51 54.26,45.7 54.26,45.81 54.46,46.01 54.57,46.01 54.76,45.81 54.87,45.81 61.64,52.58 64.17,52.58 70.19,58.6 70.19,60.35 71.21,61.37 v1(71.21,61.37)
  BOTTOM w0.076: 72.83,64.86 73.06,65.08 73.06,66.07 73.26,66.27 73.26,66.63 73.26,66.63 73.22,66.72 73.22,66.92 73.26,67.01 73.26,67.01 73.26,67.01 73.27,67.03 73.27,67.25 73.22,67.38 73.22,68.17 73.5,68.45 U1.AW59
  BOTTOM w0.102: v1(41.53,28.96) 42.03,28.46 J21.84 ; v1(71.21,61.37) 70.77,61.81 70.77,62.8 72.83,64.86
M_A_DQ44: length 58.3
  IN1 w0.076: v1(39.28,31.87) 38.54,32.6 38.54,33.6 42.42,37.47 43.5,37.47 43.73,37.7 43.73,37.81 43.36,38.18 43.36,38.28 43.56,38.48 43.66,38.48 44.03,38.11 44.14,38.11 44.34,38.31 44.34,38.42 43.97,38.79 43.97,38.89 44.17,39.09 44.27,39.09 44.64,38.72 44.75,38.72 53.64,47.61 54.53,47.61 61.01,54.09 63.55,54.09 68.83,59.37 68.83,60.76 v1(69.25,61.17)
  BOTTOM w0.076: U1.BB61 72.73,66.39 72.73,65.3 70.16,62.74 70.16,62.6
  BOTTOM w0.102: 70.16,62.6 70.16,62.09 v1(69.25,61.17) ; J21.67 37.78,32.99 38.89,31.87 v1(39.28,31.87)
M_A_DQ45: length 59.5
  IN1 w0.076: v1(69.25,59.82) 69.25,59.38 63.67,53.8 61.13,53.8 54.65,47.32 53.76,47.32 43.21,36.77 43.1,36.77 42.69,37.18 42.54,37.18 42.38,37.02 42.38,36.88 42.8,36.46 42.8,36.35 42.6,36.16 42.49,36.16 42.08,36.57 41.93,36.57 41.77,36.41 41.77,36.27 42.18,35.85 42.18,35.74 41.99,35.55 41.88,35.55 41.46,35.96 41.32,35.96 41.16,35.8 41.16,35.65 41.57,35.24 41.57,35.13 41.38,34.93 41.27,34.93 40.85,35.35 40.71,35.35 40.55,35.19 40.55,35.04 40.96,34.63 40.96,34.52 40.76,34.32 40.66,34.32 40.24,34.74 40.1,34.74 39.94,34.58 39.94,34.43 40.18,34.19 40.18,34.04 v1(39.28,33.14)
  BOTTOM w0.076: U1.AY61 73.03,67.7 73.03,67.43 73.06,67.33 73.06,67.33 73.09,67.25 73.09,67.04 73.06,66.95 73.06,66.69 73.09,66.6 73.09,66.34 72.89,66.14 72.89,65.23 70.52,62.86 70.52,62.45
  BOTTOM w0.102: v1(69.25,59.82) 70.52,61.09 70.52,62.45 ; J21.71 38.78,33.64 v1(39.28,33.14)
M_A_DQ46: length 59.5
  IN1 w0.076: v1(42.91,33.14) 43.39,33.62 43.39,34.4 45.35,36.36 45.59,36.36 45.81,36.13 46.03,36.13 46.21,36.31 46.21,36.42 45.87,36.76 45.87,36.87 46.07,37.06 46.18,37.06 46.51,36.73 46.62,36.73 46.82,36.93 46.82,37.03 46.48,37.37 46.48,37.48 46.68,37.67 46.79,37.67 47.12,37.34 47.23,37.34 47.43,37.54 47.43,37.64 47.09,37.98 47.09,38.09 47.29,38.29 47.4,38.29 47.73,37.95 47.84,37.95 48.04,38.15 48.04,38.26 47.7,38.59 47.7,38.7 47.9,38.9 48.01,38.9 48.34,38.56 48.45,38.56 48.65,38.76 48.65,38.87 48.31,39.2 48.31,39.31 48.51,39.51 48.62,39.51 48.95,39.17 49.06,39.17 49.26,39.37 49.26,39.48 48.92,39.81 48.92,39.92 49.12,40.12 49.23,40.12 49.56,39.78 49.67,39.78 49.87,39.98 49.87,40.09 49.53,40.42 49.53,40.53 49.73,40.73 49.84,40.73 50.17,40.39 50.28,40.39 61.88,51.99 64.42,51.99 70.79,58.36 70.79,58.99 v1(71.2,59.41)
  BOTTOM w0.076: 72.32,62.5 72.32,62.83 74.38,64.88 74.38,66.3 74.42,66.34 74.42,66.59 74.36,66.74 74.31,66.83 U1.BA59
  BOTTOM w0.102: J21.83 41.78,34.12 42.75,33.14 v1(42.91,33.14) ; v1(71.2,59.41) 72.32,60.53 72.32,62.5
M_A_DQ47: length 60.6
  IN1 w0.076: v1(41.53,30.23) 43.37,30.23 44.05,30.91 44.05,34.23 43.91,34.38 43.91,34.48 44.11,34.68 44.22,34.68 44.55,34.35 44.65,34.35 44.85,34.55 44.85,34.66 44.52,34.99 44.52,35.09 44.72,35.29 44.83,35.29 45.16,34.96 45.27,34.96 45.46,35.16 45.46,35.27 45.13,35.6 45.13,35.7 45.33,35.9 45.44,35.9 45.77,35.57 45.88,35.57 62.01,51.7 64.54,51.7 70.97,58.14 v1(71.21,58.14)
  BOTTOM w0.076: 72.63,62.52 72.63,62.85 74.04,64.26 74.54,64.77 74.54,66.23 74.58,66.28 74.58,66.63 74.55,66.7 74.51,66.83 74.42,67.13 74.42,67.33 74.15,67.59 U1.AY59
  BOTTOM w0.102: J21.80 41.03,29.73 v1(41.53,30.23) ; 72.63,62.52 72.63,59.56 v1(71.21,58.14)
M_A_DQ48: length 47.6
  IN4 w0.076: v1(76.9,32.07) 76.9,32.23 76.56,32.57 76.56,41.33 76.97,41.73 76.97,42.03 76.89,42.11 76.66,42.11 76.58,42.18 76.58,42.46 76.66,42.54 76.89,42.54 76.97,42.62 76.97,42.9 76.89,42.97 76.66,42.97 76.58,43.05 76.58,43.33 76.66,43.4 76.89,43.4 76.97,43.48 76.97,43.76 76.89,43.84 76.66,43.84 76.58,43.91 76.58,44.19 76.66,44.27 76.89,44.27 76.97,44.34 76.97,49.37 70.42,55.91 70.42,63.89 69.93,64.38 69.93,66.46 69.63,66.76 69.63,67.97 69.11,68.49 69.11,69.55 v1(69.48,69.91)
  BOTTOM w0.076: v1(69.48,69.91) 69.83,70.26 U1.AT66
  BOTTOM w0.102: v1(76.9,32.07) 76.86,32.07 75.78,33.16 J21.211
M_A_DQ49: length 47.2
  IN4 w0.076: v1(69.48,69.28) 69.48,69.17 69.88,68.77 69.88,66.87 70.2,66.55 70.2,64.57 70.73,64.04 70.73,56.02 77.26,49.49 77.26,41.36 77.18,41.28 76.93,41.28 76.85,41.21 76.85,40.93 76.93,40.85 77.18,40.85 77.26,40.77 77.26,40.5 77.18,40.42 76.93,40.42 76.85,40.34 76.85,40.06 76.93,39.99 77.18,39.99 77.26,39.91 77.26,39.63 77.18,39.56 76.93,39.56 76.85,39.48 76.85,39.2 76.93,39.12 77.18,39.12 77.26,39.05 77.26,38.77 77.18,38.69 76.93,38.69 76.85,38.62 76.85,38.34 76.93,38.26 77.18,38.26 77.26,38.18 77.26,37.9 77.18,37.83 76.93,37.83 76.85,37.75 76.85,37.47 76.93,37.4 77.18,37.4 77.26,37.32 77.26,37.04 77.18,36.96 76.93,36.96 76.85,36.89 76.85,36.61 76.93,36.53 77.18,36.53 77.26,36.46 77.26,36.18 77.18,36.1 76.93,36.1 76.85,36.02 76.85,35.75 76.93,35.67 77.18,35.67 77.26,35.59 77.26,35.31 77.18,35.24 76.93,35.24 76.85,35.16 76.85,34.88 76.93,34.81 77.18,34.81 77.26,34.73 77.26,34.53 76.88,34.15 76.88,33.51 v1(77.11,33.29)
  BOTTOM w0.076: U1.AU66 v1(69.48,69.28)
  BOTTOM w0.102: J21.215 76.78,33.62 v1(77.11,33.29)
M_A_DQ50: length 50.4
  IN4 w0.076: v1(79.78,33.29) 80.17,33.68 80.17,36.55 80.09,36.63 79.89,36.63 79.81,36.7 79.81,36.97 79.91,37.06 80.09,37.06 80.17,37.14 80.17,37.42 80.09,37.49 79.89,37.49 79.81,37.57 79.81,37.83 79.91,37.92 80.09,37.92 80.17,38 80.17,38.28 80.09,38.36 79.9,38.36 79.83,38.43 79.83,38.71 79.9,38.79 80.09,38.79 80.17,38.86 80.17,39.14 80.09,39.22 79.94,39.22 79.86,39.3 79.86,39.57 79.94,39.65 80.09,39.65 80.17,39.73 80.17,40.01 80.09,40.08 79.94,40.08 79.86,40.16 79.86,40.44 79.94,40.51 80.09,40.51 80.17,40.59 80.17,40.87 80.09,40.95 79.94,40.95 79.86,41.02 79.86,41.3 79.94,41.38 80.09,41.38 80.17,41.45 80.17,41.73 80.09,41.81 79.94,41.81 79.86,41.89 79.86,42.17 79.94,42.24 80.09,42.24 80.17,42.32 80.17,42.6 80.09,42.67 79.94,42.67 79.86,42.75 79.86,43.03 79.94,43.11 80.09,43.11 80.17,43.18 80.17,43.46 80.09,43.54 79.94,43.54 79.86,43.61 79.86,43.89 79.94,43.97 80.09,43.97 80.17,44.04 80.17,44.32 80.09,44.4 79.94,44.4 79.86,44.48 79.86,44.76 79.9,44.79 79.94,44.83 80.09,44.83 80.17,44.91 80.17,45.19 80.09,45.26 79.94,45.26 79.86,45.34 79.86,45.62 79.94,45.7 80.09,45.7 80.17,45.77 80.17,46.29 79.67,46.79 79.67,50.23 73.12,56.78 73.12,63.81 72.02,64.91 72.02,66.58 71.77,66.83 71.54,67.05 71.09,67.51 71.09,69.37 70.76,69.7 70.76,71.45 v1(70.39,71.82)
  BOTTOM w0.076: U1.AP65 70.65,71.56 v1(70.39,71.82)
  BOTTOM w0.102: J21.225 79.28,33.79 v1(79.78,33.29)
M_A_DQ51: length 51.2
  IN4 w0.076: v1(70.39,72.45) 70.93,71.92 70.93,69.77 71.26,69.43 71.26,67.66 71.71,67.21 72.09,66.83 72.25,66.67 72.25,65.11 73.41,63.95 73.41,57.17 80.46,50.12 80.46,49.82 80.38,49.74 80.06,49.74 79.98,49.66 79.98,49.39 80.06,49.31 80.38,49.31 80.46,49.23 80.46,48.95 80.38,48.88 80.06,48.88 79.98,48.8 79.98,48.52 80.06,48.45 80.38,48.45 80.46,48.37 80.46,48.09 80.38,48.01 80.06,48.01 79.98,47.94 79.98,47.66 80.06,47.58 80.38,47.58 80.46,47.51 80.46,32.7 v1(79.78,32.02)
  BOTTOM w0.076: v1(70.39,72.45) 70.64,72.21 U1.AN65
  BOTTOM w0.102: J21.229 80.28,32.52 v1(79.78,32.02)
M_A_DQ52: length 49.9
  IN4 w0.076: v1(76.03,30.03) 75.96,30.1 75.96,49.51 69.81,55.66 69.81,63.43 69.16,64.09 69.16,64.74 68.87,65.03 68.87,66.38 69.17,66.69 69.17,67.63 68.16,68.65 68.16,70.25 69.11,71.2 69.11,71.45 v1(69.48,71.82)
  BOTTOM w0.076: U1.AN66 69.87,72.21 v1(69.48,71.82)
  BOTTOM w0.102: v1(76.03,30.03) 77.03,29.03 J21.216
M_A_DQ53: length 49.3
  IN4 w0.076: v1(76.03,28.76) 76.9,29.63 76.9,30.31 76.25,30.96 76.25,44.92 76.68,45.34 76.68,46.45 76.25,46.87 76.25,47.95 76.68,48.37 76.68,49.23 70.12,55.79 70.12,63.68 69.61,64.2 69.61,66.53 69.38,66.76 69.38,67.88 68.95,68.31 68.95,70.65 v1(69.48,71.18)
  BOTTOM w0.076: U1.AP66 v1(69.48,71.18)
  BOTTOM w0.102: J21.212 v1(76.03,28.76)
M_A_DQ54: length 49.2
  IN4 w0.076: v1(70.39,69.91) 70.6,69.71 70.6,69.61 70.91,69.3 70.91,67.24 71.32,66.83 71.74,66.41 71.74,64.77 72.83,63.68 72.83,56.36 79.38,49.81 79.38,36.29 79.45,36.21 79.71,36.21 79.78,36.14 79.78,35.86 79.71,35.78 79.45,35.78 79.38,35.7 79.38,35.42 79.45,35.35 79.71,35.35 79.78,35.27 79.78,34.99 79.71,34.92 79.45,34.92 79.38,34.84 79.38,31.06 79.99,30.44 79.99,29.41 v1(79.53,28.94)
  BOTTOM w0.076: v1(70.39,69.91) 70.74,70.26 U1.AT65
  BOTTOM w0.102: J21.224 79.03,27.95 79.1,28.03 79.1,28.52 v1(79.53,28.94)
M_A_DQ55: length 48.5
  IN4 w0.076: v1(79.53,30.21) 79.01,30.72 79.01,32.62 78.48,33.15 78.48,34.62 78.56,34.7 78.98,34.7 79.06,34.78 79.06,35.04 78.96,35.13 78.56,35.13 78.48,35.21 78.48,35.49 78.56,35.56 78.88,35.56 78.96,35.64 78.96,35.92 78.88,36 78.75,36 78.68,36.07 78.68,49.8 72.53,55.94 72.53,63.55 71.56,64.53 71.56,66.18 70.74,67 70.74,68.93 v1(70.39,69.28)
  BOTTOM w0.076: U1.AU65 70.73,69.61 v1(70.39,69.28)
  BOTTOM w0.102: v1(79.53,30.21) 80.03,29.71 J21.228
M_A_DQ56: length 50.2
  IN4 w0.076: v1(81.78,33.29) 82.17,33.68 82.17,39.34 81.63,39.88 81.63,40.04 81.71,40.12 82.09,40.12 82.17,40.19 82.17,40.47 82.09,40.55 81.71,40.55 81.63,40.63 81.63,40.9 81.71,40.98 82.09,40.98 82.17,41.06 82.17,41.34 82.09,41.41 81.71,41.41 81.63,41.49 81.63,41.77 81.71,41.84 82.09,41.84 82.17,41.92 82.17,42.2 82.09,42.28 81.71,42.28 81.63,42.35 81.63,42.63 81.71,42.71 82.09,42.71 82.17,42.78 82.17,43.06 82.09,43.14 81.71,43.14 81.63,43.22 81.63,43.5 81.68,43.54 81.71,43.57 82.09,43.57 82.17,43.65 82.17,43.93 82.09,44 81.71,44 81.63,44.08 81.63,44.36 81.71,44.44 82.09,44.44 82.17,44.51 82.17,44.79 82.09,44.87 81.71,44.87 81.63,44.94 81.63,45.22 81.71,45.3 82.09,45.3 82.17,45.38 82.17,45.65 82.09,45.73 81.71,45.73 81.63,45.81 81.63,50.6 75.01,57.22 75.01,63.78 73.03,65.76 73.03,66.95 71.84,68.15 71.84,69.53 v1(72.22,69.91)
  BOTTOM w0.076: v1(72.22,69.91) 72.57,70.26 U1.AT61
  BOTTOM w0.102: v1(81.78,33.29) 81.28,33.79 J21.233
M_A_DQ57: length 49.8
  IN4 w0.076: v1(81.78,32.02) 82.46,32.7 82.46,45.77 81.92,46.31 81.92,46.56 81.99,46.63 82,46.63 82.44,46.63 82.51,46.71 82.51,46.99 82.44,47.07 82,47.07 81.92,47.14 81.92,47.42 82,47.5 82.44,47.5 82.51,47.57 82.51,47.85 82.44,47.93 82,47.93 81.92,48.01 81.92,48.28 82,48.36 82.44,48.36 82.51,48.44 82.51,48.72 82.44,48.79 82,48.79 81.92,48.87 81.92,49.15 82,49.22 82.44,49.22 82.51,49.3 82.51,49.58 82.44,49.66 82,49.66 81.92,49.73 81.92,50.72 75.4,57.25 75.4,63.94 73.86,65.48 73.86,66.38 73.11,67.13 72.75,67.49 72.75,68.52 72.22,69.05 v1(72.22,69.28)
  BOTTOM w0.076: v1(72.22,69.28) 72.56,69.61 U1.AU61
  BOTTOM w0.102: v1(81.78,32.02) 82.28,32.52 J21.237
M_A_DQ58: length 53
  IN4 w0.076: v1(73.14,71.82) 73.52,71.44 73.52,70.09 74.15,69.46 74.15,68.38 74.86,67.68 75.33,67.68 77.69,65.32 77.69,58.04 84.96,50.77 84.96,36.53 85.04,36.45 85.39,36.45 85.46,36.37 85.46,36.09 85.39,36.02 85.04,36.02 84.96,35.94 84.96,35.66 85.04,35.59 85.39,35.59 85.46,35.51 85.46,35.23 85.39,35.15 85.04,35.15 84.96,35.08 84.96,34.9 85.67,34.2 85.67,30.33 v1(85.52,30.18)
  BOTTOM w0.076: U1.AP60 73.39,71.56 v1(73.14,71.82)
  BOTTOM w0.102: v1(85.52,30.18) 85.01,29.67 85.01,29 84.53,28.52 J21.246
M_A_DQ59: length 53.1
  IN4 w0.076: v1(85.52,28.91) 85.52,28.93 85.96,29.37 85.96,36.39 85.26,37.09 85.26,37.28 85.33,37.36 85.66,37.36 85.74,37.43 85.74,37.71 85.66,37.79 85.33,37.79 85.26,37.86 85.26,38.14 85.33,38.22 85.66,38.22 85.74,38.3 85.74,38.58 85.66,38.65 85.33,38.65 85.26,38.73 85.26,51.14 79.16,57.24 79.16,60.53 78.48,61.2 78.48,64.94 75.35,68.08 75.35,68.29 74.61,69.02 74.61,69.43 73.68,70.36 73.68,71.92 v1(73.14,72.47)
  BOTTOM w0.076: v1(73.14,72.47) 73.39,72.21 U1.AN60
  BOTTOM w0.102: J21.250 85.53,28.91 v1(85.52,28.91)
M_A_DQ60: length 52.6
  IN4 w0.076: v1(81.53,30.21) 81.05,30.69 81.05,34.82 81.12,34.89 81.48,34.89 81.55,34.97 81.55,35.25 81.48,35.33 81.12,35.33 81.05,35.4 81.05,35.68 81.12,35.76 81.48,35.76 81.55,35.83 81.55,36.11 81.48,36.19 81.12,36.19 81.05,36.26 81.05,36.54 81.12,36.62 81.48,36.62 81.55,36.7 81.55,36.98 81.48,37.05 81.12,37.05 81.05,37.13 81.05,50.36 74.38,57.03 74.38,63.57 72.55,65.39 72.55,66.7 71.49,67.76 71.49,71.09 v1(72.22,71.82)
  BOTTOM w0.076: U1.AN61 72.62,72.21 v1(72.22,71.82)
  BOTTOM w0.102: J21.236 82.03,29.71 v1(81.53,30.21)
M_A_DQ61: length 51.9
  IN4 w0.076: v1(72.22,71.18) 71.67,70.63 71.67,67.9 72.81,66.77 72.81,65.57 74.67,63.7 74.67,57.14 81.34,50.48 81.34,39.38 81.41,39.31 81.79,39.31 81.87,39.23 81.87,38.95 81.79,38.87 81.41,38.87 81.34,38.8 81.34,38.52 81.41,38.44 81.79,38.44 81.87,38.37 81.87,38.09 81.79,38.01 81.41,38.01 81.34,37.94 81.34,37.61 81.88,37.07 81.88,34.65 81.34,34.11 81.34,31.18 81.98,30.54 81.98,29.39 v1(81.53,28.94)
  BOTTOM w0.076: v1(72.22,71.18) 72.6,71.56 U1.AP61
  BOTTOM w0.102: J21.232 81.03,28.44 v1(81.53,28.94)
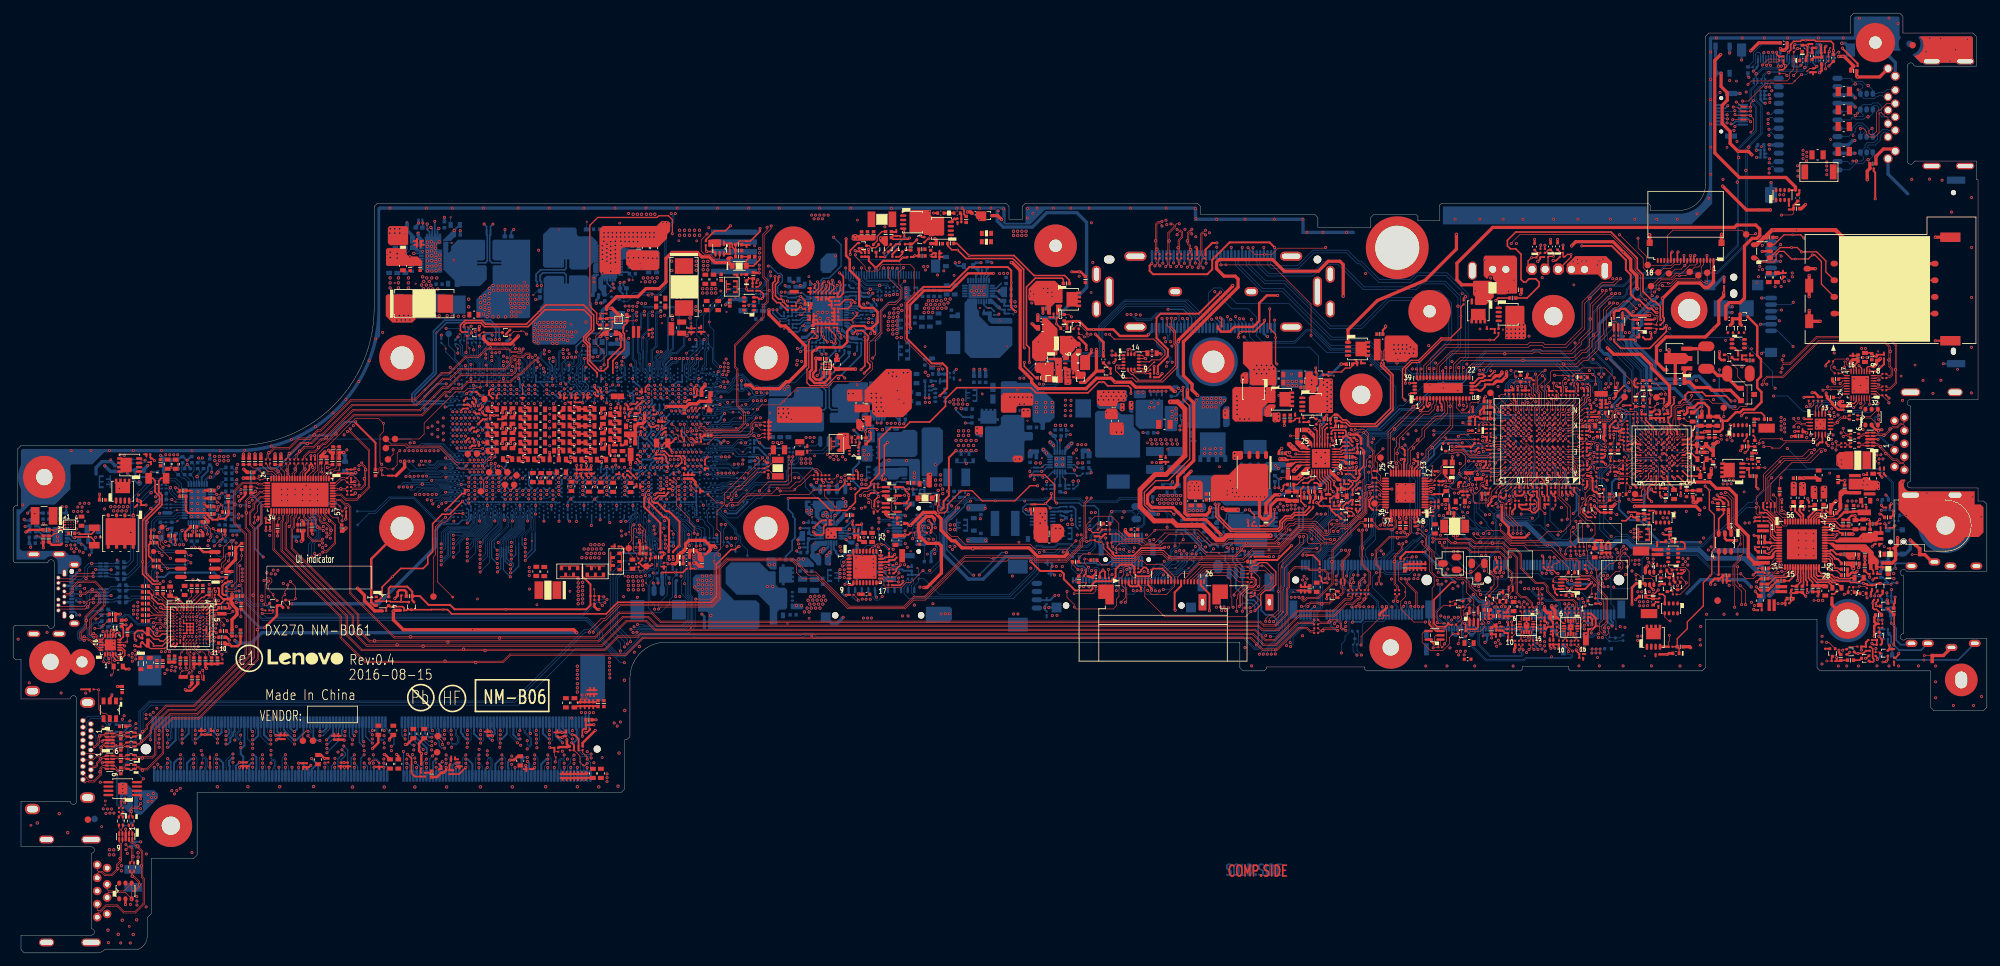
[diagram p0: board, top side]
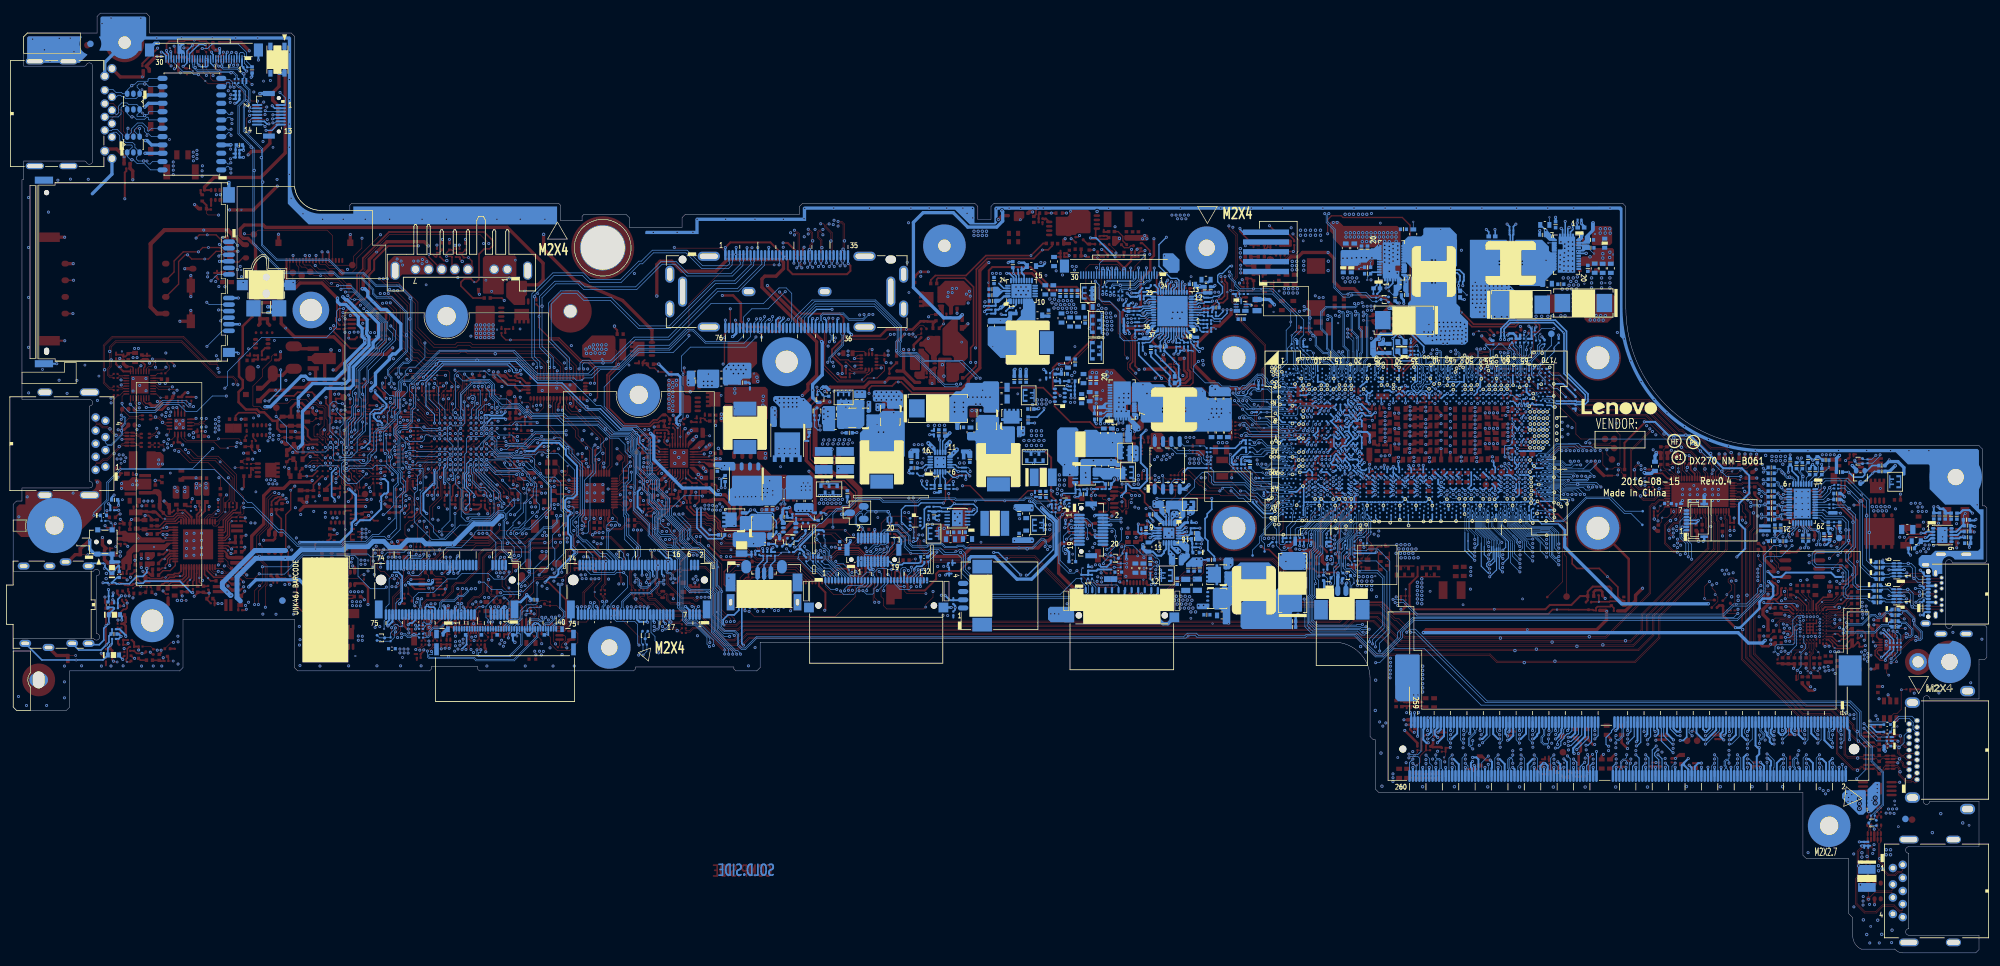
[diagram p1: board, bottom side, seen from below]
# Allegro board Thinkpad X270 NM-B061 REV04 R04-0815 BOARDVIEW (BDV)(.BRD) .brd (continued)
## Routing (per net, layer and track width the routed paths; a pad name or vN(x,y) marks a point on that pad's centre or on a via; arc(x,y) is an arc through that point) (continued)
M_A_DQ62: length 52.3
  IN4 w0.076: v1(85.28,33.92) 84.67,34.53 84.67,39.69 84.08,40.28 84.08,40.61 84.16,40.69 84.51,40.69 84.52,40.7 84.58,40.76 84.58,41.04 84.51,41.12 84.16,41.12 84.08,41.19 84.08,41.47 84.16,41.55 84.51,41.55 84.58,41.63 84.58,41.91 84.51,41.98 84.16,41.98 84.08,42.06 84.08,42.34 84.16,42.41 84.51,42.41 84.58,42.49 84.58,42.77 84.51,42.84 84.16,42.84 84.08,42.92 84.08,43.2 84.16,43.28 84.51,43.28 84.58,43.35 84.58,43.63 84.51,43.71 84.16,43.71 84.08,43.78 84.08,44.06 84.16,44.14 84.51,44.14 84.58,44.22 84.58,44.5 84.51,44.57 84.16,44.57 84.08,44.65 84.08,44.93 84.16,45 84.51,45 84.58,45.08 84.58,45.36 84.51,45.44 84.16,45.44 84.08,45.51 84.08,45.79 84.16,45.87 84.51,45.87 84.58,45.94 84.58,46.22 84.51,46.3 84.16,46.3 84.08,46.38 84.08,46.65 84.16,46.73 84.51,46.73 84.58,46.81 84.58,47.09 84.51,47.16 84.16,47.16 84.08,47.24 84.08,47.52 84.16,47.59 84.51,47.59 84.58,47.67 84.58,47.95 84.51,48.03 84.16,48.03 84.08,48.1 84.08,48.38 84.16,48.46 84.51,48.46 84.58,48.53 84.58,48.81 84.51,48.89 84.16,48.89 84.08,48.97 84.08,49.25 84.16,49.32 84.51,49.32 84.58,49.4 84.58,49.68 84.51,49.75 84.16,49.75 84.08,49.83 84.08,51.19 77.4,57.88 77.4,65.19 75.32,67.27 74.77,67.27 73.82,68.21 73.82,69.23 v1(73.14,69.91)
  BOTTOM w0.076: v1(73.14,69.91) 73.49,70.26 U1.AT60
  BOTTOM w0.102: J21.249 v1(85.28,33.92)
M_A_DQ63: length 51.5
  IN4 w0.076: v1(73.14,69.28) 73.48,68.93 73.48,68.06 74.8,66.74 75.1,66.74 75.6,66.24 75.6,65.53 77.11,64.02 77.11,57.71 83.79,51.03 83.79,39.72 83.87,39.65 84.3,39.65 84.38,39.57 84.38,39.29 84.3,39.22 83.87,39.22 83.79,39.14 83.79,38.86 83.87,38.79 84.3,38.79 84.38,38.71 84.38,38.43 84.3,38.35 83.87,38.35 83.79,38.28 83.79,38 83.87,37.92 84.3,37.92 84.38,37.85 84.38,37.57 84.3,37.49 83.87,37.49 83.79,37.41 83.79,37.13 83.87,37.06 84.3,37.06 84.38,36.98 84.38,36.7 84.3,36.63 83.87,36.63 83.79,36.55 83.79,36.27 83.87,36.19 84.3,36.19 84.38,36.12 84.38,35.84 84.3,35.76 83.87,35.76 83.79,35.69 83.79,35.41 83.87,35.33 84.3,35.33 84.38,35.25 84.38,34.98 84.3,34.9 83.87,34.9 83.79,34.82 83.79,34.44 84.74,33.5 84.74,33.19 v1(85.28,32.65)
  BOTTOM w0.076: U1.AU60 73.47,69.61 v1(73.14,69.28)
  BOTTOM w0.102: v1(85.28,32.65) 85.05,32.65 84.48,33.22 84.48,34.16 84.28,34.36 J21.245
M_A_DQS0: length 73.9
  IN1 w0.094: v1(61.16,72.72) 60.93,72.49 60.93,72.2 60.49,71.77 57.49,71.77 53.25,67.52 53.25,63.18 42.4,52.34 42.1,52.34 41.87,52.57 41.7,52.57 41.43,52.3 41.43,52.12 41.66,51.89 41.66,51.59 41.29,51.22 40.98,51.22 40.75,51.45 40.58,51.45 40.31,51.18 40.31,51.01 40.54,50.78 40.54,50.47 40.18,50.11 39.87,50.11 39.64,50.34 39.47,50.34 39.2,50.07 39.2,49.9 39.43,49.67 39.43,49.36 38.68,48.61 37.65,48.61 24.18,35.14 24.18,32.62 23.97,32.41 23.63,32.41 23.53,32.3 v1(23.53,32.02)
  BOTTOM w0.076: U1.AM69 68.21,72.75 68.21,72.76 67.92,73.05 67.84,73.09 67.57,73.09 67.46,73.04 67.35,73.04 67.16,73.11 66.95,73.11 66.81,73.04 66.36,73.04 66.27,73.13 65.7,73.13 65.31,72.74 63.56,72.74 63.03,72.21 62.64,72.21 62.61,72.24
  BOTTOM w0.109: v1(23.53,32.02) 23.53,32.35 23.59,32.41 23.89,32.41 24.23,32.75 24.23,33.73 24.14,33.82 24.14,34.28 24.28,34.41 J21.13 ; v1(61.16,72.72) 60.94,72.5 60.94,72.35 61.05,72.24 62.61,72.24
M_A_DQS1: length 66.4
  IN1 w0.094: v1(63.14,69.14) 63.31,68.97 63.31,64.06 59.72,60.47 56.89,60.47 52.68,56.26 51.53,56.26 29.69,34.43 29.69,30.09 29.35,29.75 28.93,29.75 28.83,29.85 v1(28.83,30.23)
  BOTTOM w0.076: v1(63.14,69.14) 63.55,69.55 64.89,69.55 65.24,69.9 66.25,69.9 66.42,70.07 66.86,70.07 66.97,70.02 67.08,70.02 67.26,70.08 67.49,70.08 67.63,70.01 67.76,70.01 67.93,70.1 67.94,70.11 67.94,70.26 67.9,70.3 U1.AT70
  BOTTOM w0.109: v1(28.83,30.23) 28.83,29.99 28.93,29.89 29.27,29.89 29.6,29.56 29.6,28.44 29.38,28.21 29.38,27.98 29.53,27.83 J21.34
M_A_DQS2: length 55.6
  IN4 w0.076: 67.15,71.84 67.15,71.86 67.14,71.87 67.14,72.35 68.5,73.71 69.24,73.71 69.66,74.13 69.89,74.13 70.1,73.91 70.55,73.91 v1(70.93,74.29)
  IN4 w0.094: 67.15,71.84 67.15,67.95 66.52,67.32 66.52,55.73 72.4,49.85 72.4,31.81 71.73,31.14 71.73,29.89 71.86,29.77 72.2,29.77 72.3,29.86 v1(72.3,30.21)
  BOTTOM w0.076: U1.AH65 v1(70.93,74.29)
  BOTTOM w0.109: v1(72.3,30.21) 72.3,30.01 72.46,29.85 72.76,29.85 73.05,29.55 73.05,28.18 72.89,28.02 72.89,27.86 73.03,27.73 J21.200
M_A_DQS3: length 70.1
  IN4 w0.094: v1(63.53,75.03) 63.31,74.81 63.31,74.47 62.38,73.54 62.22,73.54 62.22,73.55 59.18,73.55 57.27,71.64 57.27,68.57 55.76,67.06 55.76,61.24 67.48,49.53 67.48,45.52 67.36,45.4 67.36,45.4 67.25,45.29 66.99,45.29 66.87,45.17 66.87,45.09 66.87,44.8 67,44.67 67.26,44.67 67.48,44.45 67.48,43.95 67.37,43.83 67.25,43.72 67.09,43.72 66.99,43.72 66.87,43.6 66.87,43.22 67.01,43.09 67.27,43.09 67.48,42.88 67.48,42.37 67.36,42.25 67.36,42.25 67.25,42.14 67.09,42.14 66.99,42.14 66.87,42.03 66.87,41.94 66.87,41.65 67,41.52 67.26,41.52 67.48,41.31 67.48,40.79 67.26,40.57 67,40.57 66.95,40.53 66.95,40.53 66.87,40.45 66.87,40.07 67,39.95 67.26,39.95 67.48,39.73 67.48,39.21 67.26,38.99 66.99,38.99 66.93,38.93 66.87,38.87 66.87,38.51 67,38.38 67.26,38.38 67.48,38.16 67.48,37.64 67.25,37.42 67.09,37.42 66.99,37.42 66.87,37.3 66.87,36.91 66.99,36.8 67.26,36.8 67.48,36.58 67.48,35.99 67.36,35.88 67.36,35.88 67.05,35.57 67.05,34.95 67.67,34.33 67.67,32.32 67.38,32.03 67.08,32.03 66.85,31.8 v1(66.85,31.38)
  BOTTOM w0.076: U1.AG70 67.95,75.31 67.99,75.27 67.99,75.17 67.99,75.16 67.93,75.11 67.77,75.03 67.65,75.03 67.44,75.08 67.24,75.08 67.09,75.02 66.99,75.02 66.91,75.05 66.89,75.08 64.7,75.08 64.13,74.5 63.57,74.5 63.39,74.68 63.39,74.89 63.4,74.9 v1(63.53,75.03)
  BOTTOM w0.109: v1(66.85,31.38) 66.85,31.66 66.94,31.74 67.58,31.74 67.98,32.14 67.98,32.95 67.62,33.3 67.62,34.06 67.78,34.21 J21.179
M_A_DQS4: length 60.7
  IN1 w0.094: v1(34.69,33.24) 34.69,32.73 34.78,32.64 35.02,32.64 35.13,32.75 35.13,34.38 43.6,42.86 44.97,42.86 57.95,55.84 58.28,55.84 58.49,55.63 58.63,55.63 58.88,55.89 58.88,56.03 58.68,56.23 58.68,56.57 58.97,56.86 61.88,56.86 63.9,58.87 63.9,59.3 63.97,59.37 64.64,60.04 64.88,60.28 65.05,60.28 v1(65.27,60.49)
  BOTTOM w0.076: 67.98,64.56 68,64.56 68.02,64.53 69.78,64.53 70.58,65.33 70.58,66.12 70.75,66.28 70.75,66.58 70.69,66.72 70.69,66.91 70.75,67.07 70.75,67.51 71.04,67.79 U1.AY64
  BOTTOM w0.109: v1(65.27,60.49) 65.41,60.35 65.76,60.35 66.18,60.78 66.18,64.04 66.7,64.56 67.98,64.56 ; v1(34.69,33.24) 34.69,32.81 34.6,32.71 34.44,32.71 34.13,33.03 34.13,33.35 34.64,33.86 34.64,34.24 34.78,34.38 J21.55
M_A_DQS5: length 59.8
  IN1 w0.094: v1(39.32,30.22) 39.32,29.6 39.42,29.5 39.76,29.5 39.95,29.69 39.95,31.19 41,32.23 41,33.87 53.95,46.82 54.85,46.82 61.38,53.35 63.92,53.35 69.66,59.09 69.66,61.66 70.34,62.35 70.89,62.35 v1(71.21,62.67)
  BOTTOM w0.076: 72.17,63.75 72.2,63.75 73.88,65.43 73.88,66.09 73.71,66.26 73.71,66.62 73.77,66.75 73.77,66.84 73.76,66.89 73.71,67.07 73.71,67.25 U1.BA60
  BOTTOM w0.109: 72.17,63.75 71.56,63.14 71.56,62.76 71.46,62.67 v1(71.21,62.67) ; v1(39.32,30.22) 39.32,29.67 39.43,29.55 39.77,29.55 40.07,29.26 40.07,28.56 39.88,28.37 39.88,28.15 40.03,28.01 J21.76
M_A_DQS6: length 49.4
  IN4 w0.076: 70.51,66.33 70.51,66.35 70.53,66.37 70.53,66.6 70.25,66.87 70.25,68.65 69.86,69.04 69.86,70.16 69.8,70.23 69.8,70.78 69.97,70.95 70.16,70.95 v1(70.39,71.18)
  IN4 w0.094: 70.51,66.33 70.51,64.77 71.63,63.65 71.63,55.82 77.76,49.7 77.76,31.84 78.39,31.21 v1(78.39,31.12)
  BOTTOM w0.076: v1(70.39,71.18) 70.67,70.91 U1.AR65
  BOTTOM w0.109: v1(78.39,31.12) 78.73,31.47 78.83,31.47 79.07,31.7 79.07,32.74 78.13,33.67 78.13,33.99 78.28,34.13 J21.221
M_A_DQS7: length 51.6
  IN4 w0.076: 74.32,66.17 74.32,66.19 74.33,66.2 74.33,66.35 73.02,67.66 73.02,68.63 72.6,69.04 72.6,70.26 72.58,70.29 72.58,70.78 72.75,70.95 72.9,70.95 v1(73.14,71.18)
  IN4 w0.094: 74.32,66.17 74.32,65.83 76.39,63.76 76.39,57 83.04,50.34 83.04,29.89 83.59,29.34 83.92,29.34 84.03,29.23 v1(84.03,28.94)
  BOTTOM w0.076: U1.AR60 73.41,70.91 v1(73.14,71.18)
  BOTTOM w0.109: J21.242 83.53,28.01 83.39,28.14 83.39,29.32 83.53,29.46 83.93,29.46 84.03,29.36 v1(84.03,28.94)
M_A_DQS8: length 3.4
  TOP w0.127: TP29.1 v1(44.94,33.13)
  BOTTOM w0.127: J21.97 45.28,34.25 45.41,34.11 45.41,33.6 v1(44.94,33.13)
M_A_PARITY: length 57.9
  IN1 w0.076: 80.17,63.94 78.9,65.21 78.9,67.4 78.32,67.98 78.32,68.82 78.14,69 78.14,69.48 v1(77.71,69.91)
  IN1 w0.114: v1(57.67,31.53) 57.79,31.65 57.79,34.75 62.97,39.93 68.53,39.93 77.41,48.81 78.41,48.81 80.6,50.99 80.6,63.52 80.17,63.94
  BOTTOM w0.076: U1.AT52 v1(77.71,69.91)
  BOTTOM w0.165: J21.143 56.78,34.36 57.24,33.9 57.24,33.69 58.07,32.85 58.07,31.83 57.77,31.53 v1(57.67,31.53)
M_BAT_IN: length 2.4
  BOTTOM w0.305: PC21.2 189.7,60.77 PF3.1 ; PC21.2 188.36,61.24 188.38,61.25 ; PC21.2 188.36,60.44
  vias: v3(191.49,61.51) v3(192.97,62.5) v3(193.02,60.49)
M_BAT_PWR_A: length 0.9
  TOP w0.203: v1(188.27,66.05) 188.27,65.59 188.36,65.51 PR29.2
M_ON: length 145.9
  TOP w0.203: v1(159.11,68.64) 158.78,68.97 158.78,71.46 157.31,72.94 155.23,72.94 v1(155.08,72.78) ; v1(164.14,64.6) 164.63,64.12 165.62,64.12 166,64.5 R233.1 R232.1
  TOP w0.254: R260.2 250.75,84.58 TP39.1 251.06,85.28 v1(251.32,85.28)
  IN3 w0.203: v1(251.32,85.28) 251.32,85.36 250.7,85.97 247.51,85.97 246.81,85.27 245.53,85.27 245.22,85.57 245.22,87.56 243.16,89.62 242.71,89.62 241.28,91.05 240.45,91.05 239.9,90.49 231.71,90.49 231.35,90.84 225.33,90.84 224.82,91.35 218.98,91.35 217.18,89.55 217.18,89.04 216.8,88.66 209.46,88.66 207.37,90.74 187.23,90.74 184.39,93.59 181.59,93.59 179.66,91.66 179.66,89.45 176.41,86.19 165.46,86.19 163.46,84.19 163.46,80.33 164.7,79.08 164.7,74.28 163.33,72.91 155.2,72.91 v1(155.08,72.78)
  BOTTOM w0.203: v1(164.14,64.6) 164.35,64.6 165.51,65.76 165.51,67.63 164.9,68.24 162.95,68.24 162.52,68.67 159.14,68.67 v1(159.11,68.64) ; v1(155.08,72.78) 155.08,72.87 PR221.1
M_TEMP: length 103.2
  TOP w0.127: v1(241.29,86.78) 241.29,87.82 v3(240.86,88.26) 240.68,88.43 239.15,88.43 239.13,88.41 238.19,88.41 R135.1
  IN4 w0.076: v1(243.67,63.56) 237.12,63.56 236.5,64.18 231.82,64.18 231.55,64.45 228.28,64.45 226.65,62.83 224.98,62.83 221.57,59.42 202.04,59.42 200.52,60.95 200.52,61.51 198.46,63.56 197.85,63.56 197.11,62.83 195.84,62.83 195.46,63.21 194.32,63.21 193.96,62.85 184.13,62.85 183.02,61.73 v1(183.02,61.66)
  BOTTOM w0.102: PC19.2 184.3,60.6 v4(183.87,61.03) 183.75,61.15 PR26.1 182.61,61.26 v1(183.02,61.66) ; v1(241.29,86.78) 240.85,86.34 240.85,85.61 241.84,84.62 241.84,82.59 242.35,82.08 242.35,80.66 242.96,80.05 242.96,78.98 242.26,78.28 242.26,73.61 241.89,73.24 241.89,71.85 241.44,71.4 241.44,70.4 242.46,69.38 242.46,64.77 v1(243.67,63.56)
  BOTTOM w0.203: PJ2.4 185.45,59.17 184.79,59.83 PC19.2
M_TRCL: length 121.5
  TOP w0.102: v1(255.94,85.08) 255.94,84.75 255.22,84.02 254.76,84.02 254.24,83.5 253.55,83.5 253.25,83.2 253.25,81.5 253.07,81.32 253.07,79.59 253.35,79.31 253.35,78.93 252.95,78.53 U21.H3
  TOP w0.203: v1(177,66.92) 176.51,67.4 173.48,67.4 172.49,68.39 172.49,70.3 174.26,72.07 176.11,72.07 179.41,75.37 179.41,83.43 178.39,84.44 v1(178.39,86.32)
  IN2 w0.203: v1(255.94,85.08) 254.59,85.08 249.89,89.78 241.72,89.78 v1(240.9,90.59)
  IN3 w0.203: v1(178.39,86.32) 178.44,86.32 179.13,87.01 184.67,87.01 188.02,90.36 207.12,90.36 209.33,88.15 216.72,88.15 217.55,88.98 217.55,89.38 219.11,90.94 224.6,90.94 225.13,90.41 231.2,90.41 231.43,90.18 240.5,90.18 v1(240.9,90.59)
  BOTTOM w0.203: PQ22.2 177.24,67.16 v1(177,66.92)
MDI_0+: length 13.5
  TOP w0.102: U14.12 219.55,83.94 219.52,83.91 219.52,80.26 v2(216.37,77.12) 215.82,76.56 215.82,75.57 215.02,74.77 215.02,74.1 214.46,73.54 UL1.13
MDI_0-: length 13.5
  TOP w0.102: U14.11 219.05,84 219.11,83.93 v2(219.11,83.43) 219.11,80.43 216.09,77.41 215.41,76.73 215.41,75.74 214.61,74.94 214.61,74.27 214.06,73.71 214.06,73.2 UL1.14
MDI_1+: length 14.4
  TOP w0.102: U14.10 218.55,84.21 218.7,84.05 218.7,82.36 217.84,81.5 216.98,81.5 215.21,79.73 215.21,78.74 214.46,77.99 v2(213.53,77.06) 213.09,76.62 213.09,74.61 212.86,74.38 UL1.17
MDI_1-: length 14.4
  TOP w0.102: U14.9 218.05,84.13 218.3,83.88 218.3,82.53 217.67,81.9 216.81,81.9 214.81,79.9 214.81,78.91 v2(214.17,78.28) 212.68,76.79 212.68,74.77 212.46,74.56 UL1.18
MDI_2+: length 14.7
  TOP w0.102: U14.7 217.05,84.18 216.98,84.11 216.98,83.71 216.72,83.45 216.72,83 215.92,82.2 215.09,82.2 211.36,78.47 211.36,77.14 211.03,76.81 v2(211.03,76.24) 211.03,75.17 211.66,74.54 UL1.20
MDI_2-: length 14.6
  TOP w0.102: U14.6 216.55,84.47 216.55,84.47 216.55,84.16 216.57,84.14 216.57,83.87 216.32,83.62 216.32,83.17 215.75,82.61 214.92,82.61 210.96,78.64 210.96,77.3 210.63,76.97 210.63,75 v2(210.9,74.73) 211.26,74.37 211.26,73.2 UL1.21
MDI_3+: length 14
  TOP w0.102: U14.3 215.05,84.11 215.02,84.09 215.02,83.83 214.39,83.2 213.9,83.2 213.75,83.04 v2(210.64,79.94) 210.04,79.34 210.04,74.39 210.46,73.97 UL1.23
MDI_3-: length 14
  TOP w0.102: UL1.24 210.06,73.2 210.06,73.8 209.64,74.22 209.64,79.5 v2(213.46,83.33) 213.73,83.6 214.22,83.6 214.61,84 214.61,84.09 214.55,84.15 214.55,84.47 214.55,84.47 U14.2
MIC1_VREFOL: length 13.8
  TOP w0.203: v1(278.09,63.84) 278.09,63.72 v4(277.72,63.34) UA1.38
  TOP w0.254: v1(283.07,57.31) 283.05,57.33 R1219.2 282.79,57.85 C1416.2
  IN1 w0.254: v1(278.09,63.84) 278.97,62.96 281.66,62.96 283.06,61.56 283.06,57.32 v1(283.07,57.31)
MIC1_VREFOR: length 12
  TOP w0.203: UA1.39 277.41,63.74 v1(277.5,63.84)
  TOP w0.254: R460.2 284.06,65.51 C73.2 284.04,65.59 v1(284.61,66.16)
  IN1 w0.254: v1(277.5,63.84) 277.5,64.08 277.8,64.38 278.33,64.38 279.35,63.36 281.12,63.36 283.91,66.16 v1(284.61,66.16)
MIC_RING2: length 2.6
  TOP w0.254: 284.83,57.81 RA36.2 ; RA126.1 284.3,58.88 CA142.2 285.39,58.88
  TOP w0.305: RA36.2 284.24,58.15 ; 285.05,58.53 CA142.2
  vias: v2(286.72,57.9) v2(286.77,57.12) v3(287.05,58.66)
MIC_SLEEVE: length 1.5
  TOP w0.254: C1417.2 285.78,61.73 ; RA35.2 285,62.42
  TOP w0.305: 284.55,62.09 RA35.2 ; 286.2,61.4 C1417.2
  vias: v2(284.62,61.2) v2(284.62,60.57) v3(285.3,61.99)
MPWRG: length 185.7
  TOP w0.102: R286.2 244.91,75.11 v1(244.89,75.09) 244.83,75.04 R285.1 ; v1(244.05,69.56) 244.05,69.74 243.77,70.01 R307.2
  IN3 w0.081: v1(244.05,69.56) 244.76,70.27 244.76,70.8 245.42,71.46 245.42,74.56 v1(244.89,75.09) ; v1(239.28,69.33) 238.43,69.33 236.28,67.18 236.28,66.76 235.59,66.07 235.59,65.33 227.01,56.76 225.94,56.76 224.67,55.49 223.81,55.49 223.28,54.95 223.28,52.81 220.17,49.7 217.59,49.7 216.9,49.01 213.62,49.01 212.58,50.05 208.71,50.05 206.05,47.38 205.19,47.38 204.76,46.95 197.04,46.95 192.31,51.68 190.61,51.68 188.69,53.6 187.78,53.6 187.34,54.04 183.4,54.04 183.07,53.71 183.07,51.22 182.18,50.33 99.29,50.33 97.81,51.82 v1(97.81,52.45)
  IN4 w0.076: v1(239.28,69.33) 239.76,69.81 240.37,69.81 240.8,70.24 241.64,70.24 242.33,69.56 v1(244.05,69.56)
  BOTTOM w0.102: v1(97.81,52.45) 97.81,53.04 97.09,53.76 97.09,56.6 97.62,57.14 97.62,57.4 Q39.2 98.46,58.24 98.46,60.97 97.95,61.48 97.95,62.15 RC67.1
MUX_TYPEC_C_TXN1: length 18.4
  BOTTOM w0.102: L12.1 17.45,55.87 19.52,55.87 20.02,56.37 20.02,58.94 21.11,60.03 21.11,60.83 20.02,61.93 20.02,66.84 v2(21.01,67.83) 21.54,68.36 23,68.36 23.08,68.44 C8359.2
MUX_TYPEC_C_TXN2: length 16.9
  BOTTOM w0.102: C8360.2 22.35,70.85 22.26,70.94 21.75,70.94 v2(21.03,70.22) 19.36,68.55 19.36,59.03 17.59,57.27 17.12,57.27 L13.4
MUX_TYPEC_C_TXP1: length 18.3
  BOTTOM w0.102: L12.4 17.43,55.47 19.69,55.47 20.42,56.2 20.42,58.77 21.52,59.86 21.52,61 20.42,62.09 v2(20.42,65.73) 20.42,66.67 21.71,67.95 23,67.95 23.08,67.87 C8358.2
MUX_TYPEC_C_TXP2: length 17
  BOTTOM w0.102: C8361.2 22.35,71.42 22.26,71.34 21.58,71.34 v2(19.2,68.97) 18.95,68.71 18.95,59.2 17.43,57.68 17.15,57.68 L13.1
MUX_TYPEC_RXN1: length 30
  BOTTOM w0.102: L14.1 17.45,54.12 17.78,54.12 18.11,54.45 21.27,54.45 21.52,54.69 21.52,55.58 21.08,56.01 21.08,58.26 22.05,59.22 25.92,59.22 26.24,59.55 26.24,60.78 25.94,61.08 22.46,61.08 21.08,62.45 v2(21.08,62.94) 21.08,65.83 21.9,66.64 24.53,66.64 25.06,67.17 U183.31
MUX_TYPEC_RXN2: length 20.9
  BOTTOM w0.102: L15.4 17.15,59.02 17.48,59.02 18.34,59.88 v2(18.34,66.7) 18.34,68.98 21.39,72.03 24.61,72.03 25.27,71.37 25.27,70.81 25.72,70.37 U183.39
MUX_TYPEC_RXP1: length 30
  BOTTOM w0.102: L14.4 17.45,53.71 17.95,53.71 18.28,54.04 21.44,54.04 21.92,54.53 21.92,55.74 21.49,56.18 21.49,58.09 22.22,58.82 26.09,58.82 26.65,59.38 26.65,60.95 26.11,61.49 22.62,61.49 21.49,62.62 v2(21.49,64.55) 21.49,65.66 22.06,66.23 24.7,66.23 25.23,66.76 26.17,66.76 U183.30
MUX_TYPEC_RXP2: length 20.9
  BOTTOM w0.102: U183.40 26.17,70.77 25.88,70.77 25.68,70.98 25.68,71.53 24.78,72.43 21.22,72.43 17.93,69.15 v2(17.93,64.16) 17.93,60.05 17.31,59.43 17.12,59.43 L15.1
MUX_TYPEC_TXN1: length 2.2
  BOTTOM w0.102: U183.34 26.17,68.37 24.06,68.37 C8359.1
MUX_TYPEC_TXN2: length 3.9
  BOTTOM w0.102: U183.36 26.17,69.16 24.95,69.16 23.88,70.23 23.88,70.51 23.45,70.94 23.35,70.94 C8360.1
MUX_TYPEC_TXP1: length 2.2
  BOTTOM w0.102: U183.33 24.1,67.97 C8358.1
MUX_TYPEC_TXP2: length 3.8
  BOTTOM w0.102: C8361.1 23.34,71.35 23.62,71.35 v2(23.98,70.99) 24.28,70.68 24.28,70.4 25.12,69.57 U183.37
NFC_ACTIVE: length 40.7
  IN3 w0.081: v1(111.49,72.45) 111.82,72.78 111.82,74.51 113.32,76.01 117.59,76.01 117.71,75.88 117.71,75.25 120.3,72.66 120.3,71.51 121.56,70.26 123.07,70.26 126.77,66.56 129.3,66.56 130.59,65.26 132.14,65.26 132.62,64.78 134.15,64.78 135.57,63.36 136.37,63.36 136.96,62.78 137.96,62.78 139.81,60.93 v1(140.51,60.93)
  BOTTOM w0.102: v1(140.51,60.93) 140.9,61.31 140.9,61.92 140.72,62.09 140.7,62.09 R904.1 ; R9133.1 v1(111.49,72.45)
NFC_ACTIVE_R: length 6.6
  BOTTOM w0.076: 107.88,72.53 107.78,72.63 106.79,72.63 106.66,72.76 106.66,73.16 106.44,73.39 105.22,73.39 104.81,73.8 U1.AK6
  BOTTOM w0.102: R9133.2 109.33,72.45 109.25,72.53 107.88,72.53
NFC_DLREQ: length 47.7
  IN3 w0.081: v1(136,64.4) 135.98,64.38 135.72,64.38 134.26,65.84 133.22,65.84 132.32,66.74 126.83,66.74 123.07,70.5 121.63,70.5 120.48,71.64 120.48,72.78 117.89,75.37 117.89,75.96 117.66,76.19 110.35,76.19 108.39,74.23 105.93,74.23 105.5,74.66 102.7,74.66 102.5,74.46 102.5,73.67 103.33,72.84 v1(103.33,71.84)
  BOTTOM w0.102: v1(136,64.4) 136.38,64.78 136.38,65.47 137.22,66.31 J26.3 ; v1(103.33,71.84) 102.96,72.21 U1.AN8
NFC_INT: length 55.5
  TOP w0.102: R401.2 139.03,64.1 138.66,64.47 v3(138.66,65.09) 138.71,65.14 139.32,65.14 v1(139.58,64.88)
  IN3 w0.081: v1(111.72,83.71) 112.17,83.71 112.85,83.02 112.85,81.47 113.13,81.2 114.17,81.2 116.64,78.73 118.82,78.73 120.5,77.05 125.71,77.05 128.66,74.1 129.98,74.1 134.27,69.81 134.27,68.9 135.85,67.32 137.3,67.32 137.73,66.89 138.03,66.89 138.97,65.95 138.97,65.8 139.58,65.19 v1(139.58,64.88)
  IN4 w0.076: v1(111.72,83.71) 111.16,84.26 111.16,85.53 108.95,87.74 107.73,87.74 105.22,90.26 104,90.26 v1(103.57,90.69)
  BOTTOM w0.102: v1(103.57,90.69) 103.57,90.13 103.03,89.6 103.03,88.81 U1.B9 ; v1(139.58,64.88) 139.51,64.81 J26.9
NFC_ON: length 49.1
  TOP w0.102: R230.2 137.43,63.49 v1(137.14,63.21)
  IN3 w0.081: v1(108.95,84.01) 108.95,83.73 109.64,83.04 109.64,77.1 110.37,76.36 118.81,76.36 119.34,75.83 119.34,74.16 120.65,72.85 120.65,71.83 121.7,70.78 123.07,70.78 126.91,66.94 132.39,66.94 133.23,66.1 134.48,66.1 135.65,64.93 136.56,64.93 137.14,64.35 v1(137.14,63.21)
  BOTTOM w0.102: v1(137.14,63.21) 137.14,64.78 137.35,64.99 137.35,65.67 137.49,65.81 J26.5 ; v1(108.95,84.01) 108.75,84.21 107.65,84.21 107.58,84.29 U1.J1
PA_CDE_TI_DPEQ0: length 3.8
  TOP w0.102: R9112.2 31.93,68.19 v3(31.75,68.37) 31.35,68.77 v1(31.13,68.77) 31.13,68.87 R9113.2
  BOTTOM w0.102: U183.14 v1(31.13,68.77)
PA_CEDP_ TI_CTL1: length 36.3
  TOP w0.102: R573.1 26.39,42.28 v1(26.85,42.74) ; v1(29.64,63.9) 29.64,64.58 v3(29.39,64.84) 29.21,65.02 R9090.1
  IN4 w0.076: v1(29.64,63.9) 30.51,63.03 31.65,63.03 33.83,60.85 33.83,56.2 33.99,56.05 33.99,54.91 35.31,53.59 35.31,46.63 30.81,42.13 27.46,42.13 v1(26.85,42.74)
  BOTTOM w0.102: v1(29.64,63.9) 29.64,64.1 28.75,65 U183.23
PA_CEQ_TI_CTL0: length 23.8
  TOP w0.102: R572.1 34.72,52.34 v1(34.72,51.3) ; v1(29.77,62.91) 30.1,63.24 v3(30.1,63.44) 30.1,64.76 29.62,65.24 29.24,65.24 28.81,65.68 R10248.2
  IN4 w0.076: v1(34.72,51.3) 34.72,52.11 32.82,54.02 32.82,59.91 31.93,60.8 31.93,62.42 31.62,62.73 29.95,62.73 v1(29.77,62.91)
  BOTTOM w0.102: v1(29.77,62.91) 29.84,62.84 R9091.2 30.63,63.4 30.27,63.75 v4(30.27,63.87) 30.27,63.98 29.15,65.1 U183.22
PA_CEXT_TI_VCC: length 5
  BOTTOM w0.102: R682.1 v3(24.08,74.11) 24.08,74.06 C8356.1 25.19,72.97 25.71,72.45 26.07,72.45 26.75,71.77 U183.1
PA_DCICFG_TI_ SSEQ1: length 3.9
  BOTTOM w0.102: U183.3 27.55,72.47 27.05,72.97 R9102.2 27.58,73.53 27.58,74.5 R9100.2
PA_DPEQ_TI_FLIP: length 36.5
  TOP w0.102: v1(30.66,62.09) 31.7,63.14 v3(31.9,63.14) 31.9,63.92 R10250.2 30.76,64.48 v1(30.51,64.74) ; R571.1 v1(26.35,43.48)
  IN4 w0.076: v1(30.66,62.09) 30.66,60.8 31.37,60.09 31.37,56.28 32.03,55.62 32.03,51.91 31.68,51.55 31.68,48.79 32.39,48.07 32.39,44.06 30.66,42.33 27.99,42.33 26.85,43.48 v1(26.35,43.48)
  BOTTOM w0.102: U183.21 29.55,65.03 29.85,64.74 v1(30.51,64.74) 30.71,64.53 30.71,64.23 30.99,63.95 31.5,63.95 32.11,63.34 32.79,63.34 R9093.2
PA_FLIP_TI_EQ0: length 48.5
  TOP w0.102: R576.1 v1(25.49,43.45) ; R9116.2 25.43,69.67 R9117.2 24.98,70.98 v1(24.77,70.98)
  IN4 w0.076: v1(24.77,70.98) 24.77,68.09 27.23,65.63 30.68,65.63 31.88,64.43 31.88,63.62 34.39,61.1 34.39,60.16 35.54,59.02 35.54,46.6 30.79,41.85 26.26,41.85 25.49,42.63 v1(25.49,43.45)
  BOTTOM w0.102: U183.38 25.43,69.97 v4(25.1,70.3) 24.77,70.63 v1(24.77,70.98)
PA_I2C_EN_TI_EN: length 4
  BOTTOM w0.102: R678.2 R9089.1 R9087.1 24.88,65.73 v4(25.06,65.91) 25.52,66.37 U183.29
PA_REXT_TI_DPEQ1: length 4
  BOTTOM w0.102: U183.2 27.15,71.95 R9097.1 26.11,72.97 25.65,73.43 25.65,74.2 25.86,74.41 R681.1
PA_SSDE_TI_SSEQ: length 3.7
  TOP w0.102: R9096.2 32.36,70.2 v3(31.83,70.2) 31.6,69.97 v1(31.04,69.97) 30.63,70.38 R9098.2
  BOTTOM w0.102: U183.11 v1(31.04,69.97)
PA_TI_HPD_PD: length 2.4
  BOTTOM w0.102: U183.32 v4(24.97,67.57) 24.73,67.57 24.31,67.14 R9095.1
PA_USB_TI_EQ1: length 24.9
  TOP w0.102: v1(34.57,59.1) 34.49,59.02 34.49,56.63 34.88,56.25 34.88,54.5 R574.1
  IN4 w0.076: v1(24.2,69.19) 24.2,68.22 27.2,65.22 28.91,65.22 29.95,64.18 31.14,64.18 31.65,63.67 31.65,63.49 34.14,61 34.14,59.53 v1(34.57,59.1)
  BOTTOM w0.102: U183.35 24.83,68.77 v4(24.74,68.85) 24.54,68.85 v1(24.2,69.19) R9107.2 R9106.2
PA_VDDDCI_TI_I2CEN: length 2.7
  TOP w0.102: R679.2 30.63,67.02 v1(31.18,67.57) 30.64,68.11 R680.2
  BOTTOM w0.254: U183.17 v1(31.18,67.57)
PANEL_BKLT_CTRL: length 57.3
  TOP w0.102: v1(131.07,90.77) 131.07,90.82 131.51,91.26 131.51,93.6 132.46,94.56 132.46,97.9 133.51,98.95 134.6,98.95 135.54,99.89 135.54,101.49 135.05,101.98 135.05,103.86 v1(135.75,104.56)
  IN3 w0.081: v1(131.07,90.77) 131.01,90.82 128.73,90.82 128.16,90.26 124.63,90.26 123.06,88.69 122.33,88.69 121.03,87.39 118.07,87.39 117,86.32 111.06,86.32 109.58,87.79 107.93,87.79 107.44,87.3 107.44,85.5 107.27,85.33 107.27,81.01 106.49,80.23 102.12,80.23 101.73,80.61 v1(101.73,80.66)
  BOTTOM w0.076: U1.R11 101.73,80.78 v1(101.73,80.66)
  BOTTOM w0.102: J10.24 v1(135.75,104.56)
PANEL_POWER_ON: length 188.9
  TOP w0.102: v1(100.48,79.52) 100.83,79.16 101.19,79.16 v4(101.46,78.89) 101.47,78.87 101.47,78.31 RC2.1 ; U21.F4 252.52,77.1 v1(252.52,77.12)
  IN1 w0.076: v1(252.52,77.12) 252.1,76.69 251.44,76.69 248.73,73.98 248.73,67.3 246.16,64.73 246.16,63.16 246.74,62.57 246.74,60.79 246.26,60.31 244.89,60.31 243.7,61.51 242.43,61.51 240.84,63.09 223.01,63.09 220.58,60.67 215.23,60.67 214.56,61.33 212.86,61.33 212.4,60.87 210.42,60.87 209.85,60.3 196.16,60.3 195.31,61.15 188.55,61.15 187.44,62.27 183.19,62.27 182.56,62.9 181.21,62.9 180.17,63.94 175.52,63.94 175.12,63.54 173.29,63.54 172.96,63.21 172.37,63.21 171.81,63.77 163.51,63.77 163.1,63.36 159.14,63.36 157.49,61.71 156.42,61.71 155.46,60.74 155.22,60.74 153.65,59.18 137.39,59.18 136.51,60.06 134.2,60.06 133.46,60.79 132.19,60.79 131.45,61.53 130.58,61.53 128.18,63.93 126.82,63.93 125.38,65.37 122.82,65.37 122.25,65.93 121.06,65.93 120.68,66.31 119.88,66.31 116.87,69.33 111.85,69.33 110.45,70.73 106.08,70.73 104.76,72.05 103.9,72.05 103.03,72.91 102.7,72.91 101.76,73.85 100.34,73.85 99.59,74.6 99.59,75.61 99.93,75.94 99.93,76.65 100.48,77.2 v1(100.48,79.52)
  BOTTOM w0.076: U1.U13 100.06,79.94 100.48,79.53 v1(100.48,79.52)
PCH_PWROK: length 6.2
  BOTTOM w0.076: U1.BA20 96.1,66.87 96.1,65.77 96.54,65.33 96.54,64.21 96.86,63.89 96.86,63.69 97.47,63.08
  BOTTOM w0.127: RC66.2 97.6,61.94 97.47,62.06 97.47,63.08
PCH_SPKR: length 201.2
  TOP w0.102: RA39.1 279.79,55.64 D739.2 279.49,54.73 v1(279.2,54.73)
  IN4 w0.076: v1(279.2,54.73) 279.07,54.73 278.11,53.76 277.45,53.76 275.54,51.86 264.14,51.86 262.79,53.2 262.31,53.2 261.62,52.52 259.69,52.52 ; v1(105.24,68.31) 106.85,68.31 107.64,69.1 108.72,69.1 109.08,68.74 110.07,68.74 110.71,68.1 122.14,68.1 122.44,67.8 122.44,66.5 123.88,65.06 124.98,65.06 126.22,63.82 127.73,63.82 127.99,63.55 127.99,63.06 127.89,62.96 127.89,61.65 129.09,60.44 129.09,56.2 137.27,48.02
  IN4 w0.081: 259.69,52.52 257.18,52.52 249.51,44.85 216.16,44.85 211.62,49.39 208.92,49.39 206.56,47.03 206.56,46.67 205.81,45.92 203.96,45.92 203.04,45 198.84,45 196.05,47.79 192.87,47.79 191.78,46.7 189.57,46.7 188.3,47.97 137.32,47.97 137.27,48.02
  BOTTOM w0.102: U1.AW5 104.83,68.9 105.24,68.49 v1(105.24,68.31)
PCH_TCK: length 195.2
  TOP w0.102: v1(186.17,54.6) 186.17,54.8 187.64,56.27 188.49,56.27 RC149.1
  IN3 w0.081: v1(76.01,88.86) 75.73,89.14 75.73,89.8 75.83,89.9 75.83,90.92 75.27,91.48 74.61,91.48 73.8,90.66 73.8,89.52 72.78,88.51 67.9,88.51 66.74,87.34 65.85,87.34 57.05,78.54 57.05,69.24 55.03,67.22 55.03,62.55 66.2,51.37 92.14,51.37 93.68,52.92 98.59,52.92 99.17,52.34 99.17,51.42 100.08,50.52 182.11,50.52 182.89,51.29 182.89,53.83 183.9,54.84 185.92,54.84 v1(186.17,54.6)
  BOTTOM w0.127: U1.B56 75.62,88.47 v1(76.01,88.86) 75.73,89.14 75.73,91.99 76.36,92.62 v3(76.36,92.8) 76.31,92.85 RC142.1
PCIE0_CLK_100M: length 238.9
  TOP w0.102: U15.5 284.24,86.9 v1(284.47,86.67)
  IN1 w0.089: v1(284.47,86.67) 284.71,86.91 285.21,86.91 285.53,87.22 285.53,89.29 283.22,91.6 283.22,92.37 280.7,94.88 251.85,94.88 250.57,96.16 248.71,96.16 248.1,96.77 245.48,96.77 244.91,97.34 241.66,97.34 236.95,102.05 232.64,102.05 232.14,102.55 226.32,102.55 225.91,102.14 225.25,102.14 224.24,101.13 214.63,101.13 213.42,99.92 205.57,99.92 201.78,96.14 200.19,96.14 196.66,99.67 186.67,99.67 184.52,97.52 174.81,97.52 173.54,98.79 169.16,98.79 166.68,96.32 164.83,96.32 162.75,98.4 162.75,99.43 155.06,107.11 140.03,107.11 136.37,103.46 128.88,103.46 126.85,101.43 119,101.43 117.99,102.44 117.42,102.44 117.19,102.21 116.37,102.21 115.6,101.45 110.45,101.45 109.79,102.11 104.62,102.11 103.55,101.05 101.12,101.05 100.05,99.98 98.67,99.98 96.82,98.14 96.82,97.3 94.31,94.78 87.96,94.78 86.27,93.09 86.27,90.78 85.88,90.4 83.41,90.4 83.12,90.69 82.53,90.69 v1(82.36,90.87)
  BOTTOM w0.076: U1.C42 82.65,88.04 82.65,88.25 82.6,88.37 82.6,88.58 82.65,88.69 82.65,88.9 82.6,89.02 82.6,89.24 82.89,89.76 82.89,90.49 82.72,90.66 82.56,90.66 v1(82.36,90.87)
PCIE0_RXN: length 225
  TOP w0.102: v1(267.39,86.77) 267.17,86.77 267,86.94 267,87.3 267.5,87.79 269.89,87.79 275.29,93.19 285.25,93.19 286.01,92.43 v2(286.01,90.48) 286.01,89.44 286.34,89.1 286.34,88.25 286.15,88.05 285.92,88.05 C139.1
  IN1 w0.089: v1(99.7,84.75) 99.7,84.98 100.19,85.47 100.19,85.84 100.19,85.85 100.19,86.77 101.87,88.44 103.26,88.44 103.99,89.17 104.58,89.17 105.67,90.25 105.67,92.04 107.13,93.5 108.61,93.5 111.5,96.39 118.55,96.39 118.85,96.09 121.56,96.09 122.07,95.57 129.12,95.57 129.74,94.95 131.57,94.95 133.84,92.68 136.04,92.68 137.62,94.25 137.62,95.52 137.01,96.13 137.01,99.2 137.49,99.69 137.49,100.56 138.51,101.58 142.36,101.58 145.5,104.72 152.91,104.72 159.21,98.42 159.65,98.42 160.5,97.57 160.5,96.82 163.6,93.73 174,93.73 174.9,94.63 185.26,94.63 186.54,93.34 196.26,93.34 196.9,92.71 204.66,92.71 205.96,94.01 213.18,94.01 214.07,93.13 222.06,93.13 223.83,91.35 231.06,91.35 232.02,92.3 237.09,92.3 237.55,91.85 241.3,91.85 242.07,91.07 243.16,91.07 244.76,89.47 262.53,89.47 266.09,85.91 266.66,85.91 267.09,86.35 267.09,86.61 267.25,86.77 v1(267.39,86.77)
  BOTTOM w0.076: U1.H13 99.72,84.68 v1(99.7,84.75)
PCIE0_RXN_C: length 1.5
  TOP w0.102: U15.8 284.77,88.1 C139.2
PCIE0_RXP: length 224.9
  TOP w0.102: C137.1 285.74,87.85 286.24,87.85 286.55,88.16 286.55,89.19 286.22,89.52 v2(286.22,91.78) 286.22,92.52 285.33,93.4 275.21,93.4 269.81,88 267.41,88 266.8,87.39 266.8,86.81 v1(266.68,86.69)
  IN1 w0.089: v1(266.68,86.69) 266.79,86.59 266.79,86.31 266.58,86.1 266.17,86.1 262.61,89.66 244.84,89.66 243.24,91.26 242.15,91.26 241.38,92.04 237.63,92.04 237.17,92.49 231.94,92.49 230.98,91.54 223.91,91.54 222.13,93.32 214.14,93.32 213.26,94.2 205.88,94.2 204.58,92.9 196.98,92.9 196.34,93.53 186.62,93.53 185.34,94.82 174.82,94.82 173.92,93.92 163.68,93.92 160.69,96.9 160.69,97.65 159.72,98.61 159.29,98.61 152.99,104.91 145.42,104.91 142.28,101.77 138.43,101.77 137.3,100.64 137.3,99.77 136.82,99.28 136.82,96.05 137.43,95.44 137.43,94.33 135.97,92.87 133.92,92.87 131.65,95.14 129.82,95.14 129.2,95.76 122.15,95.76 121.64,96.28 118.93,96.28 118.63,96.58 111.42,96.58 108.54,93.7 107.05,93.7 105.48,92.12 105.48,90.33 104.5,89.36 103.91,89.36 103.18,88.63 101.79,88.63 100,86.85 100,85.77 100,85.77 100,85.54 99.92,85.46 v1(99.65,85.46)
  BOTTOM w0.076: U1.G13 v1(99.65,85.46)
PCIE0_RXP_C: length 1.5
  TOP w0.102: U15.7 284.08,87.7 284.27,87.89 284.86,87.89 C137.2
PCIE0_TXN: length 226.2
  TOP w0.102: CC75.1 285.86,86.2 286.15,86.2 287,87.05 v2(287,88.99) 287,92.63 285.79,93.85 275.02,93.85 270.99,89.82 269.88,89.82 269.73,89.67 v1(269.73,89.19)
  IN1 w0.089: v1(269.73,89.19) 269.73,89.43 269.28,89.89 266.43,89.89 265.5,90.82 245.32,90.82 242.63,93.51 231.53,93.51 230.71,92.68 224.48,92.68 222.84,94.32 214.55,94.32 212.77,96.11 206.1,96.11 203.91,93.92 199.1,93.92 196.32,96.7 193.38,96.7 191.79,95.11 186.66,95.11 185.88,95.88 175.18,95.88 173.15,97.92 169.48,97.92 167.04,95.48 164.56,95.48 160.63,99.41 160.63,100.44 154.73,106.34 143.98,106.34 143.22,105.58 143.22,104.35 141.68,102.81 137.59,102.81 136.67,101.88 135.98,101.88 135.6,101.5 135.6,100.22 133.09,97.71 130.79,97.71 130.04,96.96 127.39,96.96 125.58,98.77 122.16,98.77 120.68,97.29 119.36,97.29 118.62,98.02 117.15,98.02 116.62,98.55 113.31,98.55 112.91,98.16 109.89,98.16 108.16,96.43 103.03,96.43 100.49,93.89 99.32,92.72 98.61,92.01 98.61,91.94 v1(98.82,91.73)
  BOTTOM w0.076: 98.08,90.71 98.08,90.69 98.06,90.67 98.06,89.03 U1.B17
  BOTTOM w0.102: v1(98.82,91.73) 98.59,91.51 98.59,91.39 98.08,90.88 98.08,90.71
PCIE0_TXN_C: length 1.5
  TOP w0.102: U15.4 284.01,86.5 284.15,86.36 284.23,86.36 284.33,86.25 284.82,86.25 CC75.2
PCIE0_TXP: length 226.2
  TOP w0.102: CC74.1 285.73,85.99 286.24,85.99 287.21,86.96 287.21,92.72 285.87,94.06 274.94,94.06 270.91,90.03 269.9,90.03 269.73,90.2 v1(269.73,90.51)
  IN1 w0.089: v1(98.23,91.73) 98.42,91.92 98.42,92.09 102.95,96.62 108.08,96.62 109.37,97.91 109.81,98.35 112.83,98.35 113.23,98.74 116.7,98.74 117.23,98.21 118.7,98.21 119.44,97.48 120.6,97.48 122.08,98.96 125.66,98.96 127.47,97.15 129.96,97.15 130.71,97.9 133.01,97.9 135.41,100.3 135.41,101.58 135.9,102.07 136.59,102.07 137.51,103 141.6,103 143.03,104.43 143.03,105.66 143.9,106.53 154.81,106.53 160.82,100.52 160.82,99.49 164.64,95.67 166.96,95.67 169.4,98.11 173.23,98.11 175.26,96.07 185.96,96.07 186.74,95.3 191.72,95.3 193.3,96.89 196.4,96.89 199.18,94.11 203.83,94.11 206.02,96.3 212.84,96.3 214.63,94.51 222.92,94.51 224.56,92.87 230.63,92.87 231.45,93.7 242.71,93.7 245.4,91.01 265.58,91.01 266.51,90.08 269.58,90.08 269.73,90.23 v1(269.73,90.51)
  BOTTOM w0.076: U1.A17 97.83,89.12 97.89,89.18 97.89,90.67 97.87,90.69 97.87,90.71
  BOTTOM w0.102: v1(98.23,91.73) 98.38,91.58 98.38,91.48 97.87,90.96 97.87,90.71
PCIE0_TXP_C: length 1.5
  TOP w0.102: CC74.2 284.84,86.04 284.25,86.04 284.14,86.15 284.09,86.15 284.04,86.1 U15.3
PCIE1_CLK_100M: length 177.1
  TOP w0.102: v1(212.24,57.08) 212.39,56.92 212.39,56.42 213.86,54.95 213.86,52.97 v1(213.72,52.82)
  IN4 w0.089: v1(83.88,92.06) 83.64,91.82 83.29,91.82 82.93,91.46 82.93,89.67 84.46,88.14 86.41,88.14 87.02,88.75 89.99,88.75 90.71,89.47 90.71,90.11 92.74,92.14 99.43,92.14 99.8,91.77 109.02,91.77 110.07,90.73 110.07,88.91 112.87,86.11 116.91,86.11 117.88,87.07 122.59,87.07 123.84,88.32 128.97,88.32 129.43,87.86 131.31,87.86 134.33,84.84 134.33,84.28 137.41,81.2 141.08,81.2 141.84,80.44 141.84,74.26 142.77,73.33 142.77,70.06 144.83,68.01 144.83,67.5 145.18,67.14 145.18,64.17 146.2,63.15 146.2,61.96 149.08,59.08 154.7,59.08 154.76,59.13 157.47,59.13 157.89,59.55 160.46,59.55 162.42,57.59 165.69,57.59 166.2,57.09 173.2,57.09 174.22,58.1 176.51,58.1 177.26,58.85 188.07,58.85 189.08,59.85 197.83,59.85 199.44,58.25 199.44,56.54 200.12,55.85 201.02,55.85 201.28,55.6 201.95,55.6 203.17,56.82 203.82,56.82 204.02,57.02 206.33,57.02 206.61,56.74 209.21,56.74 210.03,57.57 212.31,57.57 212.39,57.49 212.39,57.23 v1(212.24,57.08)
  BOTTOM w0.076: U1.A42 82.99,89 83.07,89 83.18,89.12 83.18,90.86 83.16,90.88 83.16,90.9
  BOTTOM w0.102: 83.16,90.9 83.16,91.71 83.34,91.89 83.7,91.89 v1(83.88,92.06) ; J32.71 213.8,52.74 v1(213.72,52.82)
PCIE1_RXN: length 143.5
  IN4 w0.089: v1(97.83,85.99) 97.59,85.99 97.51,85.91 97.51,84.19 98.18,83.53 98.18,82.9 97.84,82.56 97.84,82.27 98.38,81.73 98.38,81.56 98.83,81.11 99.42,81.11 100.31,80.23 104.88,80.23 107.75,77.36 110.9,77.36 111.71,76.54 112.41,76.54 112.8,76.15 117.67,76.15 117.89,75.93 117.89,74.61 118.36,74.14 119.05,74.14 120.19,73 123.91,73 125.11,74.21 128.94,74.21 130.81,72.33 130.81,71.38 131.1,71.09 132.36,71.09 133.38,70.07 133.38,68.58 135.59,66.37 135.59,65.87 136.74,64.73 137.3,64.73 137.75,64.27 137.75,62.85 137.24,62.34 137.24,60.93 139.35,58.81 139.35,58.02 146.65,50.72 190.18,50.72 190.65,51.19 192.57,51.19 192.85,51.47 194.95,51.47 195.23,51.19 206.32,51.19 207.44,52.32 210.38,52.32 211.83,53.77 212.06,53.77 212.15,53.86 212.53,53.86 212.92,53.47 v1(212.92,53.46)
  BOTTOM w0.076: v1(97.83,85.99) 98.04,85.99 U1.F16
  BOTTOM w0.102: J32.67 212.8,52.57 212.66,52.71 212.66,53.2 v1(212.92,53.46)
PCIE1_RXP: length 143.6
  IN4 w0.089: v1(97.83,86.62) 97.83,86.55 97.32,86.05 97.32,84.12 97.99,83.45 97.99,82.98 97.65,82.64 97.65,82.19 98.07,81.77 98.19,81.65 98.19,81.48 98.75,80.92 99.35,80.92 100.24,80.03 104.8,80.03 107.67,77.16 110.82,77.16 111.63,76.35 112.33,76.35 112.72,75.96 117.6,75.96 117.7,75.85 117.7,74.53 118.28,73.95 118.97,73.95 120.11,72.81 123.99,72.81 125.19,74.02 128.86,74.02 130.62,72.25 130.62,71.3 131.02,70.9 132.28,70.9 133.19,69.99 133.19,68.5 135.4,66.29 135.4,65.8 136.66,64.54 137.22,64.54 137.56,64.2 137.56,62.93 137.05,62.42 137.05,60.85 139.16,58.73 139.16,57.94 146.57,50.53 190.26,50.53 190.73,51 192.65,51 192.93,51.28 194.88,51.28 195.15,51 206.4,51 207.52,52.13 210.46,52.13 211.91,53.58 212.21,53.58 v1(212.33,53.46)
  BOTTOM w0.076: v1(97.83,86.62) 98.05,86.4 U1.E16
  BOTTOM w0.102: J32.65 212.3,52.41 212.45,52.56 212.45,53.34 v1(212.33,53.46)
PCIE1_TXN: length 168.4
  TOP w0.102: v1(211.89,62.44) 211.89,61.6 210.78,60.49 210.78,56.35 211.21,55.92 211.21,55.47 C219.2
  IN4 w0.089: v1(97.47,94.58) 97.69,94.36 116.57,94.36 120.07,90.86 120.59,90.86 121.19,90.26 125.99,90.26 126.65,90.92 130.04,90.92 130.85,90.11 131.85,90.11 132.71,89.25 134.42,89.25 137.77,85.91 137.77,84.75 139.32,83.19 142.13,83.19 142.68,82.64 145.37,82.64 147.35,84.62 150.69,84.62 152.15,86.08 155.72,86.08 156.3,85.51 163.66,85.51 165.1,86.94 178.84,86.94 179.3,86.48 184.57,86.48 189.06,90.97 194.22,90.97 194.92,90.27 200.09,90.27 202.08,88.28 202.08,83.26 205.62,79.72 205.62,73.38 204.96,72.72 204.96,70.6 204.43,70.07 204.43,66.67 203.36,65.59 203.36,63.97 204.38,62.95 207.29,62.95 208.38,64.05 209.71,64.05 210.68,63.08 211.46,63.08 211.7,62.84 211.7,62.63 v1(211.89,62.44)
  BOTTOM w0.076: U1.C19 96.49,87.82 96.54,87.88 96.58,88.03 96.58,88.17 96.67,88.43 96.67,88.54 96.62,88.68 96.62,88.91 96.65,89.02 96.65,89.42 96.49,89.58 96.49,91.7 96.52,91.76 96.52,93.8 97.27,94.55 97.44,94.55 v1(97.47,94.58)
PCIE1_TXN_C: length 3.7
  TOP w0.102: v1(211.11,53.64) 210.91,53.84 210.91,54.13 211.13,54.35 211.13,54.54 C219.1
  BOTTOM w0.102: J32.61 211.3,52.29 211.16,52.43 211.16,52.86 210.87,53.15 210.87,53.53 210.98,53.64 v1(211.11,53.64)
PCIE1_TXP: length 168.3
  TOP w0.102: C220.2 210.85,55.33 211,55.49 211,55.83 210.57,56.26 v2(210.57,59.71) 210.57,60.58 211.68,61.69 211.68,62.07 v1(211.31,62.44)
  IN4 w0.089: v1(97.47,93.99) 97.65,94.17 116.49,94.17 119.99,90.67 120.51,90.67 121.11,90.07 126.06,90.07 126.73,90.73 129.96,90.73 130.77,89.92 131.77,89.92 132.63,89.06 134.34,89.06 137.58,85.83 137.58,84.67 139.24,83 142.05,83 142.6,82.45 145.45,82.45 147.43,84.43 150.77,84.43 152.23,85.89 155.65,85.89 156.22,85.32 163.74,85.32 165.18,86.75 178.76,86.75 179.22,86.29 184.65,86.29 189.14,90.78 194.14,90.78 194.84,90.08 200.01,90.08 201.89,88.2 201.89,83.18 205.43,79.64 205.43,73.46 204.77,72.8 204.77,70.68 204.24,70.15 204.24,66.75 203.17,65.67 203.17,63.89 204.3,62.76 207.37,62.76 208.46,63.86 209.63,63.86 210.6,62.89 211.39,62.89 211.51,62.76 211.51,62.65 v1(211.31,62.44)
  BOTTOM w0.076: U1.D19 96.6,87.5 96.7,87.83 96.75,88.01 96.75,88.14 96.83,88.4 96.83,88.57 96.78,88.71 96.78,88.88 96.82,88.99 96.82,89.49 96.66,89.65 96.66,91.67 96.68,91.73 96.68,93.38 97.27,93.97 97.44,93.97 v1(97.47,93.99)
PCIE1_TXP_C: length 3.8
  TOP w0.102: C220.1 210.92,54.54 210.92,54.43 210.7,54.21 210.7,53.92 210.45,53.67 v1(210.45,53.67)
  BOTTOM w0.102: J32.59 210.8,52.3 210.91,52.41 210.95,52.41 210.95,52.78 210.67,53.06 210.67,53.57 210.57,53.67 v1(210.45,53.67)
PCIE2_CLK_100M: length 163.3
  IN4 w0.089: v1(201.73,56.28) 201.56,56.45 201.28,56.45 201.08,56.65 201.08,57.21 200.7,57.59 200.7,57.86 197.45,61.1 196.07,61.1 195.64,60.67 193.05,60.67 192.8,60.92 189.29,60.92 187.82,59.45 176.58,59.45 176.11,58.98 164.53,58.98 163.38,60.13 157.62,60.13 157.26,59.78 155.77,59.78 155.33,60.22 154.9,60.22 154.37,59.69 149.46,59.69 146.78,62.37 146.78,63.4 145.78,64.4 145.78,66.98 146.09,67.3 146.09,68.09 145.82,68.36 145.67,68.36 143.42,70.61 143.42,73.72 142.43,74.71 142.43,80.75 141.39,81.79 138.74,81.79 134.45,86.08 133.94,86.08 131.27,88.75 130.29,88.75 129.47,89.57 127.46,89.57 126.8,88.9 121.25,88.9 120.08,87.73 117.69,87.73 116.65,86.69 113.14,86.69 110.65,89.18 110.65,91.01 109.29,92.37 100.15,92.37 99.79,92.72 92.49,92.72 89.58,89.81 85.55,89.81 85.22,90.14 84.43,90.14 84.15,90.42 84.15,90.63 v1(83.93,90.85)
  BOTTOM w0.076: 83.9,90.3 83.89,90.28 83.89,90.25 83.56,89.93 83.56,88.66 83.14,88.24 83.14,88 83.23,87.91 83.36,87.91 83.43,87.99 U1.C41
  BOTTOM w0.102: v1(83.93,90.85) 84.08,90.7 84.08,90.47 83.9,90.3 ; v1(201.73,56.28) 201.91,56.45 202.43,56.45 202.59,56.29 202.59,56.02 203.81,54.8 206.7,54.8 207.95,53.56 207.95,52.75 207.8,52.61 J32.47
PCIE2_RXN: length 131.5
  IN4 w0.089: v1(97.88,84.77) 98.12,84.53 98.12,84.4 98.96,83.57 98.96,83.07 100.86,81.17 101.84,81.17 101.96,81.04 102.8,81.04 102.93,81.17 104.92,81.17 105.31,80.78 105.31,80.5 107.17,78.64 111.49,78.64 113.58,76.54 117.64,76.54 117.84,76.75 118.42,76.75 119.4,75.77 119.4,74.51 120.22,73.68 121.75,73.68 122.71,74.64 129.08,74.64 131.12,72.59 131.42,72.59 134.29,69.72 134.29,68.66 135.85,67.09 136.25,67.09 136.5,66.85 136.5,66.45 138.15,64.79 138.15,62.77 139.04,61.88 139.04,59.74 145.58,53.2 158.5,53.2 160.57,51.13 189.8,51.13 190.26,51.59 192.39,51.59 192.67,51.87 195.71,51.87 195.99,51.59 206.01,51.59 206.34,51.92 206.34,52.45 v1(206.7,52.82)
  BOTTOM w0.076: v1(97.88,84.77) 97.88,84.74 98.17,84.45 U1.H16
  BOTTOM w0.102: J32.43 206.8,52.3 206.58,52.52 206.58,52.69 v1(206.7,52.82)
PCIE2_RXP: length 131.5
  IN4 w0.089: v1(205.96,52.83) 206.15,52.64 206.15,52 205.93,51.78 196.07,51.78 195.79,52.06 192.59,52.06 192.31,51.78 190.18,51.78 189.72,51.32 160.65,51.32 158.58,53.39 145.66,53.39 139.23,59.82 139.23,61.96 138.34,62.85 138.34,64.87 136.69,66.52 136.69,66.93 136.33,67.28 135.93,67.28 134.48,68.73 134.48,69.8 131.5,72.78 131.2,72.78 129.16,74.83 122.63,74.83 121.68,73.88 120.3,73.88 119.59,74.59 119.59,75.85 118.5,76.94 117.76,76.94 117.56,76.73 113.66,76.73 111.57,78.83 107.25,78.83 105.5,80.58 105.5,80.86 105,81.36 102.85,81.36 102.72,81.23 102.04,81.23 101.92,81.36 100.94,81.36 99.15,83.15 99.15,83.64 98.31,84.48 98.31,84.98 v1(97.88,85.41)
  BOTTOM w0.076: U1.G16 98.18,85.1 v1(97.88,85.41)
  BOTTOM w0.102: v1(205.96,52.83) 206.3,52.49 J32.41
PCIE2_TXN: length 171
  TOP w0.102: v1(205.75,64.53) v2(205.75,61.78) 205.75,59.33 206.94,58.14 206.94,56.27 206.63,55.96 C254.2
  IN4 w0.089: v1(205.75,64.53) 205.75,65.19 209.12,68.56 209.12,73.68 209.98,74.53 209.98,87.21 205.07,92.13 196.21,92.13 195.24,93.1 186.75,93.1 185.24,94.6 181.24,94.6 177.48,90.84 175.42,90.84 174.75,90.17 172.12,90.17 170.81,88.86 164.53,88.86 162.95,87.27 158.82,87.27 157.88,88.21 156.11,88.21 155.98,88.34 152.43,88.34 151.96,87.86 151.46,87.86 149.96,86.37 143.03,86.37 142.56,86.85 140.96,86.85 140.27,87.54 139.38,87.54 138.61,88.31 138.61,89.15 136.74,91.01 133.43,91.01 131.63,92.81 129.55,92.81 128.95,93.41 125.67,93.41 125.06,92.81 121.76,92.81 120.52,94.06 119.85,94.06 117.73,96.18 100.43,96.18 99.96,96.65 99.96,97.5 99.56,97.89 v1(98.76,97.89)
  BOTTOM w0.076: 97.46,89.65 97.45,89.64 97.45,89.61 97.31,89.47 97.31,88.98 97.33,88.93 97.33,88.67 97.31,88.61 97.31,88.37 97.35,88.21 97.35,87.9 U1.D17
  BOTTOM w0.102: 97.46,89.65 97.49,89.68 97.49,90.06 97.27,90.28 97.27,91.93 97.97,92.64 97.97,97.69 98.18,97.89 v1(98.76,97.89)
PCIE2_TXN_C: length 4
  TOP w0.102: v1(205.35,52.83) 205.17,53.01 205.17,53.15 205.26,53.24 205.54,53.24 206.41,54.12 206.41,54.54 C254.1
  BOTTOM w0.102: J32.37 205.3,52.77 v1(205.35,52.83)
PCIE2_TXP: length 171
  TOP w0.102: C253.2 206.07,55.38 206.42,55.73 206.42,56.05 206.73,56.36 206.73,58.06 205.55,59.25 205.55,64.15 v1(205.17,64.53)
  IN4 w0.089: v1(205.17,64.53) 205.56,64.92 205.56,65.27 208.93,68.64 208.93,73.76 209.79,74.61 209.79,87.13 204.99,91.93 196.13,91.93 195.16,92.91 186.67,92.91 185.16,94.41 181.32,94.41 177.56,90.65 175.5,90.65 174.83,89.98 172.2,89.98 170.89,88.67 164.61,88.67 163.03,87.08 158.74,87.08 157.8,88.02 156.03,88.02 155.9,88.15 152.51,88.15 152.03,87.67 151.53,87.67 150.04,86.18 142.95,86.18 142.48,86.66 140.88,86.66 140.19,87.35 139.31,87.35 138.42,88.23 138.42,89.07 136.66,90.82 133.35,90.82 131.55,92.62 129.47,92.62 128.87,93.22 125.74,93.22 125.14,92.62 121.69,92.62 120.44,93.87 119.77,93.87 117.65,95.99 100.35,95.99 99.77,96.57 99.77,97.42 99.48,97.7 99.13,97.7 98.76,97.33 v1(98.76,97.12)
  BOTTOM w0.076: 97.61,89.5 97.6,89.49 97.56,89.49 97.47,89.4 97.47,89.02 97.49,88.97 97.49,88.64 97.47,88.58 97.47,88.4 97.52,88.23 97.52,87.94 97.58,87.82 U1.C17
  BOTTOM w0.102: 97.61,89.5 97.7,89.59 97.7,90.15 97.47,90.37 97.47,91.85 98.18,92.55 98.18,97.6 98.27,97.69 98.38,97.69 98.76,97.31 v1(98.76,97.12)
PCIE2_TXP_C: length 4
  TOP w0.102: C253.1 206.21,54.63 206.21,54.21 v2(206.01,54.01) 205.45,53.45 205.17,53.45 204.96,53.24 204.96,53.05 v1(204.75,52.83)
  BOTTOM w0.102: v1(204.75,52.83) 204.8,52.77 J32.35
PCIE3_CLK_100M: length 175.1
  TOP w0.102: UL1.44 212.86,66.49 212.96,66.4 212.96,64.17 v2(212.59,63.8) 212.33,63.54 209.8,63.54 207.67,61.41 207.67,59.29 208.31,58.65 208.31,57.5 208.14,57.33 208.14,56.55 v1(207.88,56.3)
  IN4 w0.089: v1(207.88,56.3) 207.88,55.98 207.79,55.89 207.63,55.89 207.43,56.1 203.02,56.1 202.1,55.18 200.92,55.18 200.69,55.41 199.97,55.41 199.04,56.34 199.04,58.08 197.68,59.44 189.47,59.44 188.49,58.46 177.45,58.46 175.68,56.68 166.02,56.68 165.57,57.14 162.21,57.14 161.01,58.34 157.21,58.34 157.11,58.24 154.78,58.24 154.34,58.69 148.83,58.69 144.79,62.72 144.79,66.02 143.71,67.1 143.71,68.45 142.38,69.79 142.38,73.1 141.44,74.04 141.44,80.24 140.87,80.81 137.24,80.81 133.94,84.12 133.94,84.68 131.14,87.47 127.37,87.47 127.11,87.22 123.32,87.22 122.78,86.68 119.31,86.68 118.19,85.56 116.24,85.56 115.63,84.95 113.32,84.95 112.86,85.41 112.86,85.53 112.19,86.21 111.57,86.21 109.64,88.14 109.64,90.54 108.81,91.36 99.97,91.36 99.83,91.22 98.17,91.22 97.66,91.73 92.91,91.73 91.12,89.94 91.12,89.26 90.08,88.21 87.1,88.21 86.46,87.57 85.67,87.57 85.38,87.27 84.71,87.27 84.44,87.54 83.93,87.54 83.65,87.25 83.65,87.03 v1(83.47,86.85)
  BOTTOM w0.102: U1.C40 84,87.66 83.68,87.34 83.68,87.06 v1(83.47,86.85)
PCIE3_RXN: length 138
  TOP w0.102: CL3.1 205.78,65.59 205.45,65.59 201.29,61.42 201.29,56.31 199.04,54.06 197.34,54.06 196.97,53.68 196.67,53.68 196.08,54.27 v1(196.05,54.27)
  IN4 w0.089: v1(196.05,54.27) 196.12,54.27 196.3,54.44 196.3,54.59 196.21,54.67 194.23,54.67 193.42,55.49 190.36,55.49 189.96,55.09 179.04,55.09 176.07,52.12 162.66,52.12 160.96,53.82 145.83,53.82 139.87,59.78 139.87,61.88 138.74,63.01 138.74,65.11 137.88,65.98 137.88,66.67 136.24,68.31 135.6,68.31 134.92,69 134.92,71.31 132.9,73.33 131.21,73.33 128.06,76.48 125.15,76.48 125.03,76.61 124.07,76.61 123.51,76.05 119.96,76.05 118.68,77.33 117.59,77.33 117.46,77.2 115.06,77.2 113.96,78.29 112.72,78.29 111.66,79.35 108.06,79.35 105.43,81.98 105.43,82.13 104.1,83.46 100.03,83.46 99.13,84.36 99.13,85.2 99.02,85.32 v1(98.73,85.32)
  BOTTOM w0.076: U1.G15 98.94,85.1 v1(98.73,85.32)
PCIE3_RXN_C: length 6.6
  TOP w0.102: UL1.39 210.86,66.76 210.77,66.66 210.77,66.11 210.93,65.95 210.93,64.99 210.52,64.57 v2(210.25,64.57) 208.18,64.57 207.56,65.19 CL3.2
PCIE3_RXP: length 138
  TOP w0.102: CL2.1 205.93,65.8 205.37,65.8 201.08,61.51 v2(201.08,59.69) 201.08,56.39 198.95,54.27 197.26,54.27 196.88,53.89 196.75,53.89 196.66,53.99 v1(196.66,54.27)
  IN4 w0.089: v1(98.74,86.05) 99.27,85.52 99.27,85.33 99.32,85.28 99.32,84.44 100.11,83.65 104.17,83.65 105.62,82.21 105.62,82.05 108.14,79.54 111.74,79.54 112.8,78.49 114.04,78.49 114.17,78.36 115.14,77.39 117.38,77.39 117.51,77.52 118.76,77.52 120.04,76.24 123.43,76.24 123.99,76.8 125.1,76.8 125.23,76.67 128.14,76.67 131.29,73.52 132.98,73.52 135.11,71.39 135.11,69.08 135.68,68.5 136.32,68.5 138.07,66.75 138.07,66.05 138.93,65.19 138.93,63.09 140.06,61.96 140.06,59.85 145.91,54.01 161.04,54.01 162.74,52.31 175.99,52.31 178.96,55.28 189.88,55.28 190.28,55.68 193.49,55.68 194.31,54.86 196.29,54.86 196.49,54.67 196.49,54.44 v1(196.66,54.27)
  BOTTOM w0.076: U1.F15 99.05,85.75 v1(98.74,86.05)
PCIE3_RXP_C: length 6.6
  TOP w0.102: UL1.38 210.46,66.76 210.56,66.66 210.56,66.03 210.72,65.86 210.72,65.07 210.43,64.78 208.26,64.78 207.67,65.37 207.67,65.5 207.12,66.05 CL2.2
PCIE3_TXN: length 170.7
  TOP w0.102: CL1.1 212.05,64.49 212.05,64.26 v1(212.19,64.12)
  IN4 w0.089: v1(212.19,64.12) 212.19,64.79 211.78,65.19 211.46,65.19 210.77,65.89 208.26,65.89 206.5,64.12 204.9,64.12 204.63,64.39 204.63,64.9 207.93,68.2 207.93,77.72 209.38,79.17 209.38,86.74 204.61,91.52 195.93,91.52 195.06,92.39 186.37,92.39 185.05,93.71 181.31,93.71 176.69,89.09 174.11,89.09 173.27,88.25 164.75,88.25 163.18,86.68 158.56,86.68 157.62,87.62 154.9,87.62 154.54,87.26 151.68,87.26 150.21,85.79 142.75,85.79 142.34,86.2 139.9,86.2 138,88.1 138,88.93 136.5,90.43 133.18,90.43 131.4,92.21 129.31,92.21 128.7,92.83 125.94,92.83 125.33,92.21 121.31,92.21 120.05,93.47 119.53,93.47 117.46,95.54 99.5,95.54 98.31,96.74 98.31,97.61 98.09,97.83 v1(97.49,97.83)
  BOTTOM w0.076: 95.94,90.71 95.94,90.69 95.96,90.66 95.96,88.77 96.12,88.61 U1.B19
  BOTTOM w0.102: v1(97.49,97.83) 96.94,97.83 96.73,97.62 96.73,94.99 95.84,94.1 95.84,91.94 95.94,91.84 95.94,90.71
PCIE3_TXN_C: length 1.7
  TOP w0.102: CL1.2 212,66.04 212,66.6 212.06,66.66 UL1.42
PCIE3_TXP: length 170.6
  TOP w0.102: CL4.1 211.56,64.77 211.84,64.48 211.84,64.36 v1(211.6,64.12)
  IN4 w0.089: v1(97.49,97.24) 97.89,97.64 98.01,97.64 98.12,97.53 98.12,96.66 99.42,95.35 117.38,95.35 119.45,93.28 119.97,93.28 121.23,92.02 125.41,92.02 126.02,92.64 128.62,92.64 129.23,92.02 131.32,92.02 133.1,90.24 136.42,90.24 137.81,88.85 137.81,88.02 139.82,86.01 142.26,86.01 142.68,85.6 150.28,85.6 151.76,87.07 154.62,87.07 154.98,87.43 157.54,87.43 158.48,86.49 163.26,86.49 164.83,88.06 173.35,88.06 174.19,88.9 176.77,88.9 181.39,93.52 184.97,93.52 186.29,92.2 194.98,92.2 195.85,91.33 204.53,91.33 209.19,86.66 209.19,79.25 207.74,77.8 207.74,68.28 204.44,64.98 204.44,64.31 204.82,63.93 206.57,63.93 208.34,65.7 210.69,65.7 211.39,65 211.71,65 212,64.71 212,64.51 v1(211.6,64.12)
  BOTTOM w0.076: 96.15,90.71 96.15,90.69 96.13,90.66 96.13,88.84 96.2,88.76 96.31,88.76 96.39,88.84 U1.A19
  BOTTOM w0.102: 96.15,90.71 96.15,91.93 96.05,92.03 96.05,94.02 96.94,94.91 96.94,97.53 97.02,97.62 97.12,97.62 v1(97.49,97.24)
PCIE3_TXP_C: length 1.7
  TOP w0.102: UL1.41 211.66,66.73 211.79,66.6 211.79,66 CL4.2
PCIE4_CLK_100M: length 180.4
  IN4 w0.089: v1(85.18,90.92) 85.33,91.07 85.33,91.23 85.21,91.35 85.21,92.62 87.76,95.17 94.86,95.17 96.53,93.5 100.16,93.5 100.49,93.17 109.66,93.17 111.44,91.39 111.44,89.5 113.46,87.48 116.25,87.48 117.38,88.6 119,88.6 120.08,89.68 126.23,89.68 126.89,90.34 129.79,90.34 130.61,89.53 131.59,89.53 134.13,86.98 134.65,86.98 139.07,82.56 141.82,82.56 143.2,81.18 143.2,75.24 144.26,74.18 144.26,72.27 146.88,69.64 146.88,66.93 146.57,66.61 146.57,64.73 147.56,63.74 147.56,62.72 149.82,60.46 154.03,60.46 154.6,61.04 155.61,61.04 156.1,60.55 156.88,60.55 158.19,61.86 161.76,61.86 162.16,61.47 166.62,61.47 167.98,60.11 171.19,60.11 172.07,60.98 176.52,60.98 177.28,60.22 187.4,60.22 188.92,61.75 193.28,61.75 193.51,61.52 195.38,61.52 195.74,61.87 197.89,61.87 201.47,58.29 206.49,58.29 207.25,57.53 208.9,57.53 209.71,58.34 216.18,58.34 217.07,57.45 217.4,57.45 217.85,57 v1(217.85,56.27)
  BOTTOM w0.076: v1(85.18,90.92) 85.44,90.65 85.44,90.03 85.39,89.98 85.28,89.98 85,90.26 84.56,90.26 84.17,89.87 84.17,89.53 84.3,89.4 84.3,89.12 84.21,89.03 84.09,89.03 U1.A40
  BOTTOM w0.102: J1.38 218.95,49.75 218.52,50.18 218.44,50.18 218.36,50.26 218.18,50.26 217,51.44 217,51.97 217.66,52.63 217.66,56.09 v1(217.85,56.27)
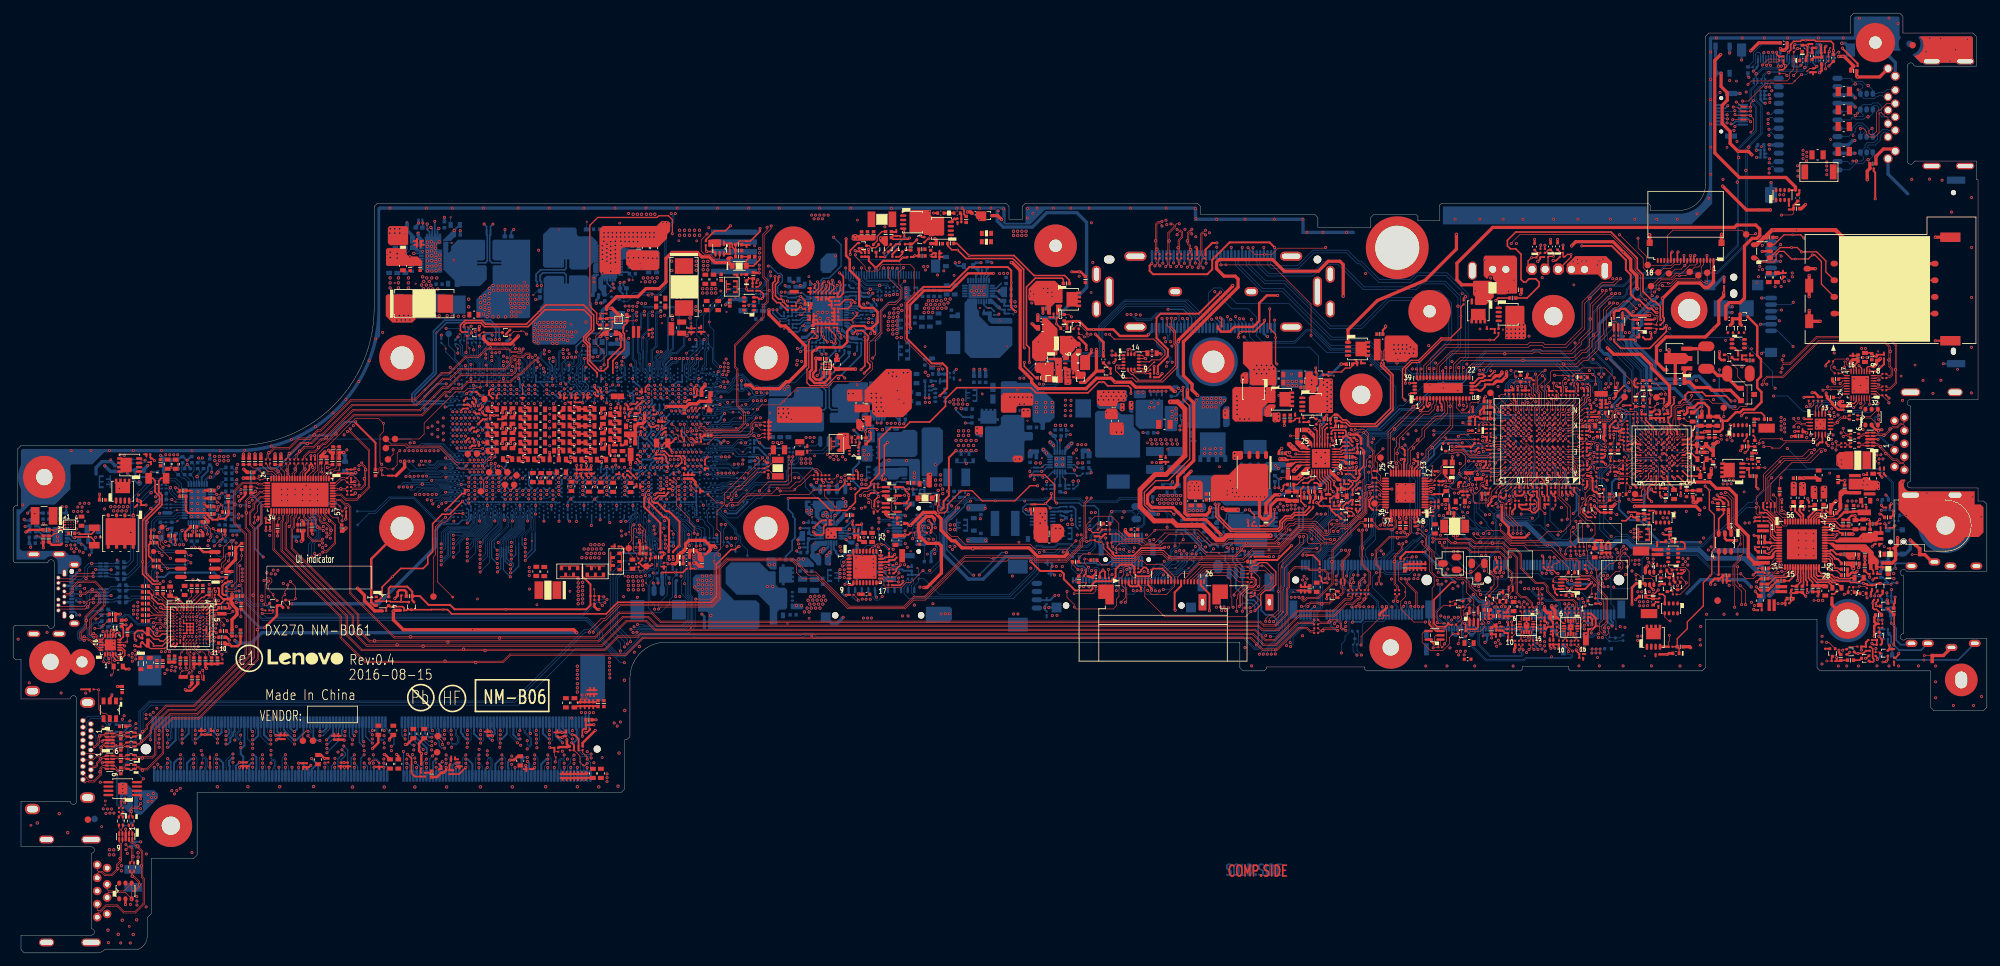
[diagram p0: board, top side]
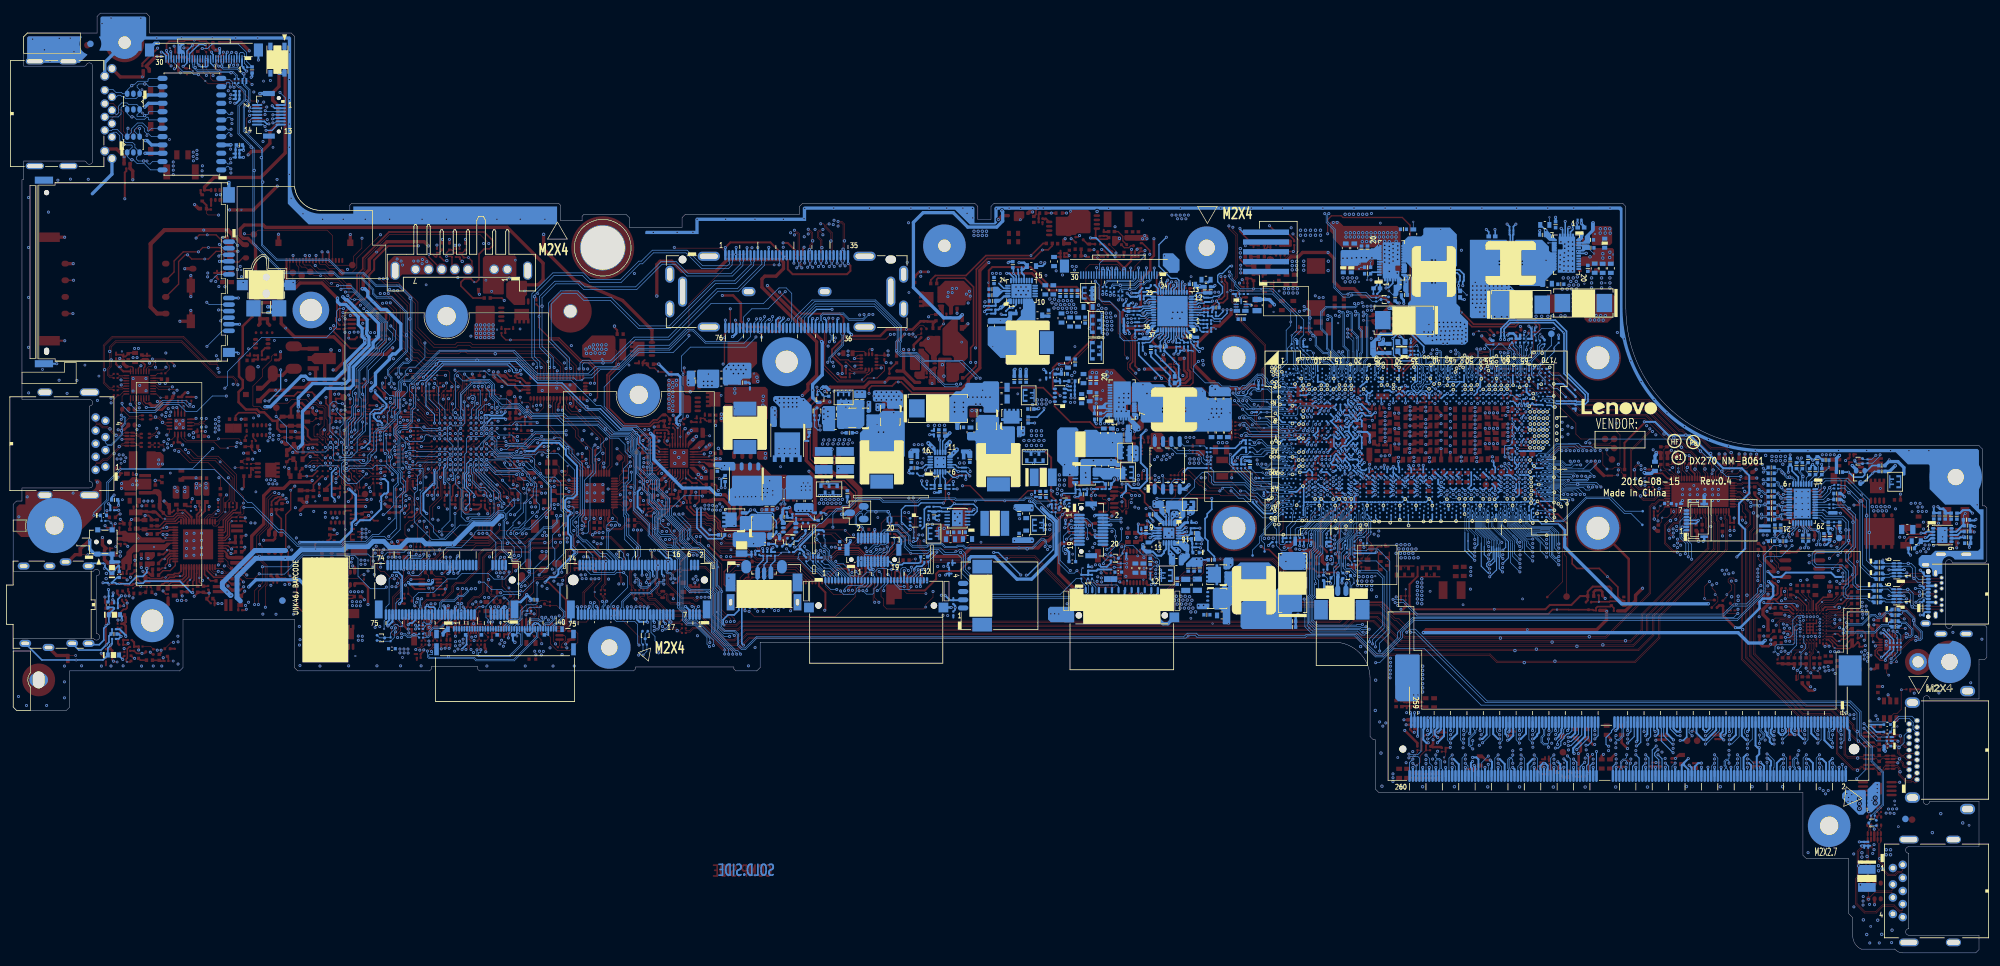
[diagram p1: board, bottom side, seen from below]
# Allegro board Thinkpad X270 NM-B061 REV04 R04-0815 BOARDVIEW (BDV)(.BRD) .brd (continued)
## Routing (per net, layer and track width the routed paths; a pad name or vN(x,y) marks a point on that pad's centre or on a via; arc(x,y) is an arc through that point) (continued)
PCIE4_L0_SATA1_RXN: length 171.8
  TOP w0.102: v1(237.23,53.27) 237,53.03 237,52.81 C86.2
  IN4 w0.089: v1(95.06,85.32) 95.06,85.58 94.96,85.67 94.73,85.67 94.64,85.59 94.64,84.58 94.78,84.44 94.78,79.39 96.21,77.95 100.73,77.95 100.87,78.09 104.96,78.09 109.22,73.84 110.11,73.84 110.74,73.2 111.71,73.2 111.82,73.09 113.43,71.48 119.99,71.48 120.56,70.9 126.3,70.9 126.78,70.42 127.63,70.42 128.68,69.38 130.86,69.38 131.23,69.01 131.23,68.71 133,66.93 133,66.36 133.3,66.06 133.77,66.06 134.26,65.58 134.26,65.39 135,64.64 135,62.09 135.26,61.84 135.26,61.45 135.84,60.87 135.84,60.45 137.6,58.69 137.6,57.89 146,49.49 194,49.49 194.29,49.78 199.4,49.78 200.99,48.2 205.48,48.2 208.3,51.02 211.74,51.02 212.4,51.68 215.55,51.68 216.67,52.79 224.98,52.79 225.54,52.23 227.12,52.23 227.82,51.54 234.87,51.54 235.87,52.54 235.87,53.53 236.29,53.95 236.84,53.95 237.04,53.75 237.04,53.46 v1(237.23,53.27)
  BOTTOM w0.076: U1.G21 95.3,85.1 95.08,85.32 95.06,85.32 v1(95.06,85.32)
PCIE4_L0_SATA1_RXN_C: length 1.4
  TOP w0.102: C86.1 237.08,51.72 237.08,51.29 236.99,51.2 236.99,51 237.09,50.89 U24.4
PCIE4_L0_SATA1_RXN_CONN: length 22.2
  TOP w0.102: v1(237.78,46.06) 237.73,46.06 237.39,46.4 237.34,46.4 236.94,46.8 C420.1
  BOTTOM w0.102: J1.33 220.95,48.16 224.54,44.57 230.38,44.57 230.7,44.89 237.53,44.89 237.78,45.15 v1(237.78,46.06)
PCIE4_L0_SATA1_RXN_CONN_R: length 1.2
  TOP w0.102: C420.2 236.77,47.81 236.77,47.95 236.97,48.15 236.97,48.32 237.09,48.45 U24.11
PCIE4_L0_SATA1_RXP: length 171.9
  TOP w0.102: v1(236.6,53.27) 236.79,53.08 236.79,52.64 C84.2
  IN4 w0.089: v1(236.6,53.27) 236.85,53.53 236.85,53.67 236.76,53.76 236.37,53.76 236.06,53.45 236.06,52.46 234.95,51.35 227.74,51.35 227.04,52.04 225.46,52.04 224.9,52.6 216.75,52.6 215.63,51.49 212.48,51.49 211.82,50.82 208.38,50.82 205.56,48.01 200.91,48.01 199.32,49.59 194.37,49.59 194.08,49.3 145.92,49.3 137.41,57.81 137.41,58.61 135.65,60.37 135.65,60.79 135.07,61.37 135.07,61.76 134.81,62.01 134.81,64.56 134.07,65.31 134.07,65.5 133.69,65.87 133.22,65.87 132.81,66.28 132.81,66.85 131.04,68.63 131.04,68.94 130.78,69.19 128.6,69.19 127.56,70.23 126.7,70.23 126.22,70.71 120.48,70.71 119.91,71.28 113.35,71.28 111.63,73.01 110.66,73.01 110.03,73.65 109.14,73.65 104.88,77.9 100.95,77.9 100.81,77.76 96.13,77.76 94.59,79.31 94.59,84.36 94.45,84.5 94.45,85.66 94.65,85.86 94.87,85.86 95.01,86 v1(95.03,86.03)
  BOTTOM w0.076: U1.F21 95.31,85.75 v1(95.03,86.03)
PCIE4_L0_SATA1_RXP_C: length 1.4
  TOP w0.102: U24.5 236.69,50.88 236.78,50.97 236.78,51.28 236.87,51.38 236.87,51.72 C84.1
PCIE4_L0_SATA1_RXP_CONN: length 22.1
  TOP w0.102: v1(237.17,46.01) 237.17,46.27 236.8,46.65 236.71,46.65 C419.1
  BOTTOM w0.102: v1(237.17,46.01) 236.98,45.83 236.98,45.58 237.06,45.51 237.52,45.51 237.57,45.45 237.57,45.23 237.44,45.1 230.62,45.1 230.29,44.78 224.62,44.78 221.16,48.24 221.16,48.83 221.35,49.02 J1.32
PCIE4_L0_SATA1_RXP_CONN_R: length 1.3
  TOP w0.102: U24.10 236.69,48.44 236.76,48.38 236.76,48.23 236.56,48.04 236.56,47.89 C419.2
PCIE4_L0_SATA1_TXN: length 194.2
  TOP w0.102: v1(219.63,63.69) 219.82,63.5 219.82,63.26 220.03,63.05 222.24,63.05 222.79,62.49 v2(225.58,62.49) 227.1,62.49 228.09,61.5 229.08,61.5 229.78,60.8 229.78,58.7 232.13,56.35 233.34,56.35 233.83,55.86 233.83,55.12 235.2,53.76 237.8,53.76 238.27,53.29 238.27,52.73 C85.1
  IN4 w0.089: v1(95.08,97.78) 95.21,97.65 95.42,97.65 95.54,97.77 95.54,98.06 96.15,98.67 100.54,98.67 102.42,96.79 118.22,96.79 120.35,94.65 127.26,94.65 127.87,94.05 129.19,94.05 129.82,93.41 131.85,93.41 133.67,91.6 137.04,91.6 141.19,87.44 142.83,87.44 143.31,86.96 149.72,86.96 151.21,88.45 151.69,88.45 152.24,89 155.89,89 156.14,89.26 157.7,89.26 158.29,88.66 163.51,88.66 164.3,89.46 167.85,89.46 168.33,89.94 169.75,89.94 172.84,93.03 175,93.03 176.08,91.95 177.58,91.95 180.96,95.33 187.21,95.33 187.86,94.68 192.13,94.68 193.12,93.69 195.6,93.69 196.55,92.73 205.46,92.73 210.66,87.53 210.66,80.59 213.6,77.66 213.6,76.19 214.47,75.31 214.47,69.32 216.52,67.27 216.52,65.93 218.75,63.69 v1(219.63,63.69)
  BOTTOM w0.076: U1.D21 94.99,87.71 94.97,87.78 94.97,87.88 94.83,88.36 94.83,88.61 94.86,88.7 94.86,88.89 94.83,88.99 94.83,89.33 94.81,89.35 94.81,89.37
  BOTTOM w0.102: 94.81,89.37 94.81,90.22 94.39,90.63 94.39,97.38 94.61,97.6 94.91,97.6 v1(95.08,97.78)
PCIE4_L0_SATA1_TXN_C: length 1.5
  TOP w0.102: C85.2 238.26,51.73 238.26,51.55 237.99,51.27 237.99,51.05 237.89,50.95 U24.2
PCIE4_L0_SATA1_TXN_CONN: length 28.5
  TOP w0.102: v1(238.95,46.2) 238.95,46.34 238.58,46.7 238.43,46.7 C422.2
  IN4 w0.089: v1(218.84,51.24) 218.79,51.24 218.62,51.4 218.62,51.59 218.67,51.64 220.59,51.64 221.12,51.11 221.82,51.11 223.38,49.55 236.75,49.55 239.37,46.94 239.37,46.7 239.32,46.65 238.94,46.65 238.86,46.58 238.86,46.28 v1(238.95,46.2)
  BOTTOM w0.102: J1.35 220.15,49.8 220.04,49.9 220.04,50.13 219.81,50.36 219.18,50.36 218.63,50.91 218.63,51.03 v1(218.84,51.24)
PCIE4_L0_SATA1_TXN_CONN_R: length 1.2
  TOP w0.102: U24.13 237.89,48.36 238.08,48.17 238.08,48.08 238.23,47.93 238.23,47.79 C422.1
PCIE4_L0_SATA1_TXP: length 194.1
  TOP w0.102: C83.1 238.48,52.73 238.48,53.38 237.89,53.97 235.28,53.97 234.04,55.21 234.04,55.95 233.43,56.56 232.21,56.56 229.99,58.78 229.99,60.89 229.17,61.71 228.18,61.71 227.18,62.7 v2(223.7,62.7) 222.88,62.7 222.33,63.26 220.12,63.26 220.02,63.35 220.02,63.5 v1(220.21,63.69)
  IN4 w0.089: v1(95.08,97.19) 95.34,97.45 95.49,97.45 95.73,97.69 95.73,97.98 96.07,98.32 96.23,98.48 100.46,98.48 102.34,96.6 118.14,96.6 120.28,94.46 127.18,94.46 127.79,93.86 129.11,93.86 129.74,93.22 131.77,93.22 133.59,91.41 136.96,91.41 141.11,87.25 142.75,87.25 143.23,86.77 149.8,86.77 151.29,88.26 151.77,88.26 152.32,88.81 155.97,88.81 156.22,89.06 157.62,89.06 158.21,88.47 163.59,88.47 164.38,89.27 167.93,89.27 168.41,89.75 169.83,89.75 172.92,92.84 174.92,92.84 176,91.76 177.66,91.76 181.04,95.14 187.13,95.14 187.78,94.49 192.05,94.49 193.04,93.5 195.52,93.5 196.48,92.54 205.38,92.54 210.47,87.45 210.47,80.51 213.41,77.58 213.41,76.11 214.28,75.23 214.28,69.24 216.33,67.19 216.33,65.85 218.68,63.5 219.25,63.5 219.49,63.26 219.78,63.26 v1(220.21,63.69)
  BOTTOM w0.076: U1.C21 95.08,88.13 94.99,88.39 94.99,88.56 95.03,88.67 95.03,88.95 94.99,89.02 94.99,89.33 95.02,89.35 95.02,89.37
  BOTTOM w0.102: 95.02,89.37 95.02,90.3 94.6,90.72 94.6,97.29 94.7,97.4 94.88,97.4 v1(95.08,97.19)
PCIE4_L0_SATA1_TXP_C: length 1.5
  TOP w0.102: C83.2 238.47,51.71 238.47,51.46 238.2,51.19 238.2,51.06 238.29,50.96 U24.1
PCIE4_L0_SATA1_TXP_CONN: length 28.5
  TOP w0.102: C421.2 238.67,47.05 238.67,46.91 238.67,46.91 238.95,46.63 239.22,46.63 v1(239.56,46.29)
  IN4 w0.089: v1(218.26,51.24) 218.43,51.41 218.43,51.67 218.59,51.83 220.67,51.83 221.2,51.3 221.9,51.3 223.46,49.74 236.83,49.74 239.56,47.01 v1(239.56,46.29)
  BOTTOM w0.102: J1.36 219.75,49.81 219.83,49.9 219.83,50.05 219.73,50.15 219.11,50.15 218.44,50.82 218.44,51.05 v1(218.26,51.24)
PCIE4_L0_SATA1_TXP_CONN_R: length 1.2
  TOP w0.102: U24.14 238.29,48.17 238.44,48.02 238.44,47.81 238.61,47.64 C421.1
PCIE4_L1_RXN: length 166
  TOP w0.102: v1(230.39,53.58) 230.12,53.31 230.12,53.04 C244.2
  IN4 w0.089: v1(230.39,53.58) 230.1,53.87 230.1,54.08 229.24,54.93 228.09,54.93 227.76,54.6 227.76,54.02 227.4,53.66 225.81,53.66 225.54,53.38 216.35,53.38 215.32,52.35 211.63,52.35 210.98,51.7 207.97,51.7 205.06,48.79 201.51,48.79 199.88,50.42 193.66,50.42 193.34,50.1 146.24,50.1 138.27,58.06 138.27,58.85 136.46,60.67 136.46,61.19 135.93,61.72 135.93,61.99 135.59,62.34 135.59,64.99 134.9,65.68 134.9,66.16 132.65,68.4 132.65,69.96 132.13,70.48 129.79,70.48 128.24,72.03 128.24,73 127.77,73.47 125.27,73.47 124.21,72.41 120.73,72.41 120.38,72.06 114.35,72.06 111.93,74.47 111.93,75.4 110.57,76.77 107.45,76.77 105.08,79.14 100.3,79.14 99.56,79.87 99.56,80.33 99.25,80.64 98.08,80.64 97.82,80.39 96.64,80.39 96.35,80.68 96.35,81.75 95.26,82.84 95.26,83.53 95.62,83.89 95.62,84.99 96.29,85.66 96.84,85.66 96.94,85.57 v1(96.94,85.38)
  BOTTOM w0.076: U1.F20 96.51,85.75 96.87,85.38 v1(96.94,85.38)
PCIE4_L1_RXN_C: length 1.3
  TOP w0.102: C244.1 230.24,51.93 230.24,51.4 230.36,51.28 U25.4
PCIE4_L1_RXN_CONN: length 11.9
  TOP w0.102: v1(230.23,46.25) 230.05,46.42 230.05,46.93 R416.1
  BOTTOM w0.102: J1.27 223.35,47 225.15,45.2 229.99,45.2 230.23,45.44 v1(230.23,46.25)
PCIE4_L1_RXN_CONN_R: length 1.5
  TOP w0.102: U25.11 230.36,48.77 230.03,48.45 230.03,47.75 R416.2
PCIE4_L1_RXP: length 166
  TOP w0.102: C243.2 229.91,52.8 229.91,53.29 v1(229.62,53.58)
  IN4 w0.089: v1(229.62,53.58) 229.9,53.86 229.9,54 229.17,54.74 228.16,54.74 227.95,54.52 227.95,53.94 227.48,53.47 225.89,53.47 225.61,53.19 216.43,53.19 215.4,52.16 211.71,52.16 211.06,51.51 208.05,51.51 205.14,48.6 201.43,48.6 199.8,50.23 193.74,50.23 193.41,49.91 146.16,49.91 138.08,57.98 138.08,58.77 136.27,60.59 136.27,61.11 135.74,61.64 135.74,61.91 135.4,62.26 135.4,64.91 134.71,65.6 134.71,66.08 132.46,68.33 132.46,69.88 132.05,70.29 129.71,70.29 128.05,71.95 128.05,72.92 127.69,73.28 125.35,73.28 124.29,72.22 120.81,72.22 120.46,71.87 114.27,71.87 111.74,74.39 111.74,75.32 110.49,76.58 107.37,76.58 105,78.95 100.22,78.95 99.37,79.79 99.37,80.25 99.17,80.45 98.15,80.45 97.9,80.2 96.56,80.2 96.16,80.6 96.16,81.67 95.07,82.76 95.07,83.61 95.43,83.97 95.43,85.07 96.21,85.85 96.75,85.85 v1(96.91,86.02)
  BOTTOM w0.076: U1.E20 96.53,86.4 v1(96.91,86.02)
PCIE4_L1_RXP_C: length 1.3
  TOP w0.102: C243.1 230.03,51.93 230.03,51.41 229.96,51.33 U25.5
PCIE4_L1_RXP_CONN: length 11.9
  TOP w0.102: v1(229.64,46.26) 229.84,46.46 229.84,46.8 R415.1
  BOTTOM w0.102: v1(229.64,46.26) 229.64,45.89 229.69,45.84 229.97,45.84 230.02,45.79 230.02,45.53 229.9,45.41 225.23,45.41 223.56,47.09 223.56,48.63 223.61,48.68 223.78,48.68 223.85,48.76 223.85,48.91 223.75,49.02 J1.26
PCIE4_L1_RXP_CONN_R: length 1.5
  TOP w0.102: U25.10 229.96,48.67 229.82,48.53 229.82,47.85 R415.2
PCIE4_L1_TXN: length 192.8
  TOP w0.102: v1(216.46,62.7) 216.83,63.08 218.55,63.08 219.21,62.41 221.94,62.41 222.57,61.78 226.92,61.78 227.84,60.87 228.6,60.87 229.16,60.3 229.16,54.91 229.88,54.19 230.6,54.19 231.47,53.31 231.47,52.79 231.4,52.72 C242.1
  IN4 w0.089: v1(96.28,97.32) 96.54,97.59 96.65,97.59 96.77,97.47 96.77,96.96 98.97,94.77 117.05,94.77 119.13,92.68 119.73,92.68 121.06,91.35 122.37,91.35 123.04,90.68 125.82,90.68 127.14,92 128.35,92 128.94,91.41 131.11,91.41 132.86,89.66 136.18,89.66 137.2,88.63 137.2,87.8 139.57,85.42 140.06,85.42 140.06,85.42 141.96,85.42 142.37,85.01 150.53,85.01 151.99,86.47 155.97,86.47 156.54,85.9 163.5,85.9 165.07,87.48 179.27,87.48 179.87,86.88 184.38,86.88 188.99,91.48 194.41,91.48 195.19,90.69 200.24,90.69 202.5,88.43 202.5,83.63 206.04,80.09 206.04,67.66 203.81,65.42 203.81,64.12 204.58,63.35 207.06,63.35 208.29,64.58 209.74,64.58 210.82,63.5 213.64,63.5 213.69,63.45 214.4,63.45 214.59,63.64 215.1,63.64 215.64,63.09 216.06,63.09 v1(216.46,62.7)
  BOTTOM w0.076: U1.B21 95.44,88.65 95.57,88.65 95.74,88.83 95.74,89.85 95.6,89.99 95.6,90.57 95.62,90.59 95.62,90.61
  BOTTOM w0.102: 95.62,90.61 95.62,91.47 95.41,91.68 95.41,94.86 95.84,95.29 95.84,97.4 95.95,97.5 96.1,97.5 v1(96.28,97.32)
PCIE4_L1_TXN_C: length 1.3
  TOP w0.102: U25.2 231.16,51.32 231.33,51.49 231.33,51.98 C242.2
PCIE4_L1_TXN_CONN: length 21.5
  TOP w0.102: C418.2 231.39,46.84 231.39,46.55 v1(231.13,46.29)
  IN4 w0.089: v1(231.13,46.29) 231.43,46.29 231.5,46.22 231.5,45.76 231.17,45.43 223.66,45.43 219.94,49.15 219.94,50.82 219.99,50.87 220.27,50.87 220.34,50.93 v1(220.34,51.21)
  BOTTOM w0.102: J1.29 222.55,50.04 222.44,50.15 222.44,50.57 222.04,50.97 220.79,50.97 220.59,50.77 220.29,50.77 220.17,50.89 220.17,51.04 v1(220.34,51.21)
PCIE4_L1_TXN_CONN_R: length 1.5
  TOP w0.102: C418.1 231.4,47.86 231.4,48.34 231.26,48.47 231.26,48.64 231.16,48.74 U25.13
PCIE4_L1_TXP: length 192.8
  TOP w0.102: C241.1 231.68,52.84 231.68,53.39 230.68,54.39 229.97,54.39 229.37,54.99 229.37,60.39 228.69,61.07 227.92,61.07 227,61.99 222.66,61.99 222.03,62.62 v2(219.87,62.62) 219.3,62.62 218.64,63.28 v1(216.46,63.28)
  IN4 w0.089: v1(96.28,97.9) 96.4,97.78 96.73,97.78 96.96,97.55 96.96,97.04 99.04,94.96 117.13,94.96 119.21,92.87 119.81,92.87 121.14,91.54 122.45,91.54 123.12,90.87 125.74,90.87 127.06,92.19 128.42,92.19 129.02,91.6 131.19,91.6 132.94,89.85 136.26,89.85 137.39,88.71 137.39,87.88 139.65,85.61 139.98,85.62 142.04,85.62 142.45,85.2 150.45,85.2 151.91,86.66 156.04,86.66 156.62,86.09 163.42,86.09 164.99,87.67 179.35,87.67 179.95,87.07 184.31,87.07 188.91,91.67 194.48,91.67 195.27,90.88 200.32,90.88 202.69,88.51 202.69,83.71 206.23,80.16 206.23,67.58 204,65.34 204,64.2 204.66,63.54 206.98,63.54 208.21,64.77 209.82,64.77 210.9,63.69 213.72,63.69 213.77,63.64 214.32,63.64 214.51,63.83 215.18,63.83 215.72,63.28 v1(216.46,63.28)
  BOTTOM w0.076: U1.A21 95.26,88.89 95.34,88.82 95.5,88.82 95.58,88.89 95.58,89.78 95.43,89.93 95.43,90.57 95.41,90.59 95.41,90.61
  BOTTOM w0.102: 95.41,90.61 95.41,91.39 95.2,91.59 95.2,94.94 95.64,95.37 95.64,97.48 95.86,97.71 96.08,97.71 v1(96.28,97.9)
PCIE4_L1_TXP_C: length 1.3
  TOP w0.102: U25.1 231.56,51.38 231.54,51.41 231.54,51.86 C241.2
PCIE4_L1_TXP_CONN: length 21.6
  TOP w0.102: v1(231.9,46.29) 231.6,46.59 231.6,46.89 C417.2
  IN4 w0.089: v1(231.9,46.29) 231.69,46.08 231.69,45.68 231.25,45.24 223.59,45.24 219.75,49.08 v1(219.75,51.21)
  BOTTOM w0.102: J1.30 222.15,49.99 222.23,50.08 222.23,50.48 221.95,50.77 220.88,50.77 220.68,50.56 220.2,50.56 219.96,50.81 219.96,51 v1(219.75,51.21)
PCIE4_L1_TXP_CONN_R: length 1.5
  TOP w0.102: C417.1 231.61,47.79 231.61,48.42 231.47,48.56 231.47,48.68 231.56,48.77 U25.14
PCIE5_CLK_100M: length 214.5
  IN4 w0.089: v1(223.88,56.33) 223.88,56.07 224,55.95 225.11,55.95 225.98,56.82 227.51,56.82 228.62,57.94 231.48,57.94 232.58,56.85 234.09,56.85 234.52,56.42 234.52,55.44 235.32,54.64 238.84,54.64 239.03,54.45 239.03,54.29 v1(239.25,54.07) ; v1(218.1,66.74) 218.1,67.34 217.07,68.38 217.07,68.96 215.53,70.5 215.53,73.85 216.09,74.41 216.09,76.8 211.2,81.69 211.2,87.99 205.78,93.41 196.83,93.41 195.82,94.42 193.32,94.42 192.4,95.34 189.24,95.34 188.5,96.07 180.77,96.07 179.23,94.54 175.11,94.54 174.42,93.84 172.51,93.84 169.48,90.8 166.57,90.8 165.9,90.13 163.41,90.13 162.6,89.32 158.57,89.32 157.97,89.92 155.51,89.92 155.28,89.69 151.99,89.69 151.41,89.11 150.94,89.11 149.45,87.62 143.59,87.62 143.11,88.1 141.47,88.1 140.64,88.93 140.64,89.4 137.78,92.26 133.94,92.26 132.13,94.07 130.58,94.07 128.98,95.68 120.28,95.68 118.49,97.47 102.93,97.47 101.05,99.35 97.04,99.35 96.57,99.82 94.6,99.82 94.3,99.53 93.06,99.53 89.4,95.87 87.61,95.87 84.48,92.73 83.33,92.73 81.89,91.29 81.52,91.29 81.15,90.92 81.15,90.31 82.75,88.71 82.75,86.34 83.28,85.81 83.68,85.81 83.8,85.69 84.65,85.69 v1(85.05,86.09)
  BOTTOM w0.102: v1(218.1,66.74) 218.1,65.77 218.86,65.01 220.05,65.01 222.28,62.78 v2(222.28,58.2) 222.28,57.67 223.62,56.33 v1(223.88,56.33) ; J22.55 239.1,52.54 238.96,52.67 238.96,52.93 239.04,53 239.04,53.86 v1(239.25,54.07) ; U1.E38 85.17,86.09 v1(85.05,86.09)
PCIE10_L0_SATA2_RXN: length 178.4
  IN4 w0.089: v1(90.46,86.7) 90.65,86.53 90.89,86.53 91.58,85.84 92.47,85.84 93.51,86.88 93.51,87.62 94.13,88.24 95.68,88.24 96.09,88.66 101.36,88.66 102.31,87.71 103.95,87.71 105.11,86.54 105.11,85.13 106.49,83.76 106.49,83.25 107.81,81.93 108.84,81.93 110.64,80.12 113.5,80.12 115.02,78.6 117.48,78.6 117.98,78.1 119.05,78.1 120.33,76.82 123.13,76.82 123.73,77.42 125.34,77.42 125.41,77.34 130.03,77.34 131.29,76.08 131.29,75.83 132.99,74.13 133.36,74.13 135.9,71.59 135.9,70.79 136.31,70.38 137.03,70.38 137.96,69.46 137.96,69.23 138.95,68.24 138.95,66.03 139.46,65.52 139.81,65.52 140.2,65.12 140.2,64.49 141.18,63.51 141.18,60.33 146.18,55.33 159.71,55.33 160.39,54.66 161.23,54.66 162.89,53 175.81,53 178.72,55.9 189.57,55.9 189.95,56.29 193.74,56.29 194.58,55.45 196.54,55.45 198.03,53.96 198.03,52.64 198.24,52.43 202.69,52.43 203.78,53.52 209.09,53.52 210.38,54.81 212.75,54.81 213.6,53.96 224.78,53.96 226.39,55.58 229.45,55.58 230.32,56.45 231.07,56.45 231.57,55.95 231.57,55.7 231.7,55.57 v1(231.84,55.57)
  BOTTOM w0.102: J22.43 236.1,52.59 235.9,52.78 235.9,53.45 235.49,53.87 233.74,53.87 233.03,54.57 232.35,54.57 231.68,55.24 231.68,55.41 v1(231.84,55.57) ; v1(90.46,86.7) 90.16,86.4 U1.E30
PCIE10_L0_SATA2_RXP: length 178.3
  IN4 w0.089: v1(90.48,86.14) 90.66,86.34 90.81,86.34 91.5,85.65 92.54,85.65 93.7,86.8 93.7,87.54 94.21,88.05 95.75,88.05 96.17,88.47 101.28,88.47 102.23,87.52 103.87,87.52 104.92,86.46 104.92,85.05 106.3,83.68 106.3,83.17 107.73,81.74 108.76,81.74 110.56,79.93 113.42,79.93 114.94,78.41 117.41,78.41 117.9,77.91 118.97,77.91 120.25,76.63 123.21,76.63 123.81,77.23 125.26,77.23 125.33,77.15 129.96,77.15 131.1,76 131.1,75.75 132.91,73.94 133.28,73.94 135.71,71.51 135.71,70.71 136.23,70.19 136.95,70.19 137.77,69.38 137.77,69.15 138.76,68.16 138.76,65.95 139.38,65.33 139.73,65.33 140.01,65.05 140.01,64.41 140.99,63.43 140.99,60.25 146.1,55.14 159.64,55.14 160.31,54.47 161.15,54.47 162.81,52.81 175.89,52.81 178.8,55.71 189.65,55.71 190.03,56.1 193.66,56.1 194.5,55.26 196.46,55.26 197.84,53.88 197.84,52.56 198.16,52.23 202.77,52.23 203.86,53.33 209.17,53.33 210.46,54.62 212.67,54.62 213.52,53.77 224.86,53.77 226.47,55.39 229.53,55.39 230.4,56.26 230.99,56.26 231.38,55.87 231.38,55.74 231.22,55.57 v1(231.08,55.57)
  BOTTOM w0.102: J22.41 235.6,52.49 235.7,52.59 235.7,53.36 235.4,53.66 233.65,53.66 232.94,54.36 232.27,54.36 231.47,55.15 231.47,55.32 231.22,55.57 v1(231.08,55.57) ; v1(90.48,86.14) 90.45,86.14 U1.F30
PCIE10_L0_SATA2_TXN: length 187.5
  IN4 w0.089: v1(92.02,89.97) 92.44,89.55 92.44,89.5 92.67,89.27 93.68,89.27 93.76,89.34 94.61,89.34 95.69,90.42 97.29,90.42 98.04,89.67 102.42,89.67 102.95,89.15 104.71,89.15 106.7,87.16 106.7,85.45 107.81,84.33 108.24,84.33 108.55,84.64 109.22,84.64 109.71,84.15 109.71,83.83 111.62,81.93 112.34,81.93 112.77,82.36 114.11,82.36 116.61,79.86 118.35,79.86 118.93,79.27 119.66,79.27 120.81,78.12 122.62,78.12 123.11,78.61 126.06,78.61 126.13,78.54 130.54,78.54 132.82,76.26 133.38,76.26 134.36,75.27 134.36,74.87 137.12,72.11 138.22,72.11 139.86,70.47 139.86,69.61 140.27,69.2 140.27,68.13 142.27,66.12 142.27,64.4 142.41,64.26 142.41,60.88 146.77,56.53 161.06,56.53 162.8,54.79 175.62,54.79 177.98,57.15 188.98,57.15 190.02,58.19 197.15,58.19 197.88,57.47 197.88,55.78 199.55,54.1 199.55,53.94 199.87,53.62 202.22,53.62 203.4,54.8 207.02,54.8 207.12,54.7 208.6,54.7 209.89,55.98 213.39,55.98 214.21,55.16 220.99,55.16 222.92,57.09 222.92,57.9 223.99,58.97 231.53,58.97 233.05,57.45 234.75,57.45 235.93,56.27 235.93,56.01 236.69,55.25 239.25,55.25 240.31,54.19 240.31,49.76 240.06,49.52 239.69,49.52 v1(239.6,49.43)
  BOTTOM w0.102: C2764.1 239.21,49.59 239.44,49.59 v1(239.6,49.43) ; U1.A25 92.78,89.15 92.02,89.91 v1(92.02,89.97)
PCIE10_L0_SATA2_TXN_C: length 3.1
  BOTTOM w0.102: J22.47 237.1,50.36 237.36,50.1 237.92,50.1 238.13,49.89 238.13,49.78 C2764.2
PCIE10_L0_SATA2_TXP: length 187.5
  IN4 w0.089: v1(239.6,50.01) 239.6,50.01 239.9,49.71 239.99,49.71 240.12,49.84 240.12,54.11 239.17,55.06 236.61,55.06 235.74,55.93 235.74,56.19 234.67,57.26 232.97,57.26 231.45,58.78 224.07,58.78 223.11,57.82 223.11,57.01 221.07,54.97 214.13,54.97 213.31,55.79 209.97,55.79 208.68,54.51 207.04,54.51 206.94,54.61 203.48,54.61 202.29,53.43 199.79,53.43 199.36,53.86 199.36,54.03 197.68,55.7 197.68,57.39 197.07,58 190.1,58 189.06,56.96 178.06,56.96 175.7,54.6 162.72,54.6 160.98,56.34 146.69,56.34 142.22,60.8 142.22,64.18 142.08,64.32 142.08,66.04 140.08,68.05 140.08,69.12 139.67,69.53 139.67,70.39 138.14,71.92 137.04,71.92 134.17,74.79 134.17,75.2 133.3,76.06 132.74,76.06 130.46,78.35 126.05,78.35 125.98,78.42 123.19,78.42 122.69,77.93 120.73,77.93 119.58,79.08 118.86,79.08 118.27,79.67 116.53,79.67 114.03,82.17 112.85,82.17 112.42,81.74 111.54,81.74 109.52,83.75 109.52,84.07 109.14,84.45 108.63,84.45 108.32,84.14 107.74,84.14 106.51,85.37 106.51,87.08 104.63,88.96 102.87,88.96 102.35,89.48 97.96,89.48 97.21,90.23 95.77,90.23 94.69,89.15 93.84,89.15 93.76,89.08 92.58,89.08 92.34,88.84 92.12,88.84 92.02,88.94 v1(92.02,89.38)
  BOTTOM w0.102: v1(239.6,50.01) 239.39,49.8 239.26,49.8 C2765.1 ; U1.B25 92.78,88.67 92.47,88.99 92.47,89.18 92.26,89.38 v1(92.02,89.38)
PCIE10_L0_SATA2_TXP_C: length 3.1
  BOTTOM w0.102: J22.49 237.6,50.99 237.31,50.7 237.31,50.44 237.45,50.3 238.08,50.3 238.27,50.49 238.41,50.49 238.48,50.42 C2765.2
PCIE10_L1_RXN: length 174.2
  TOP w0.102: v1(232.44,55.59) 232.59,55.44 R547.1
  IN4 w0.089: v1(91.42,86.68) 91.61,86.86 91.61,87.02 91.83,87.24 92.39,87.24 93.88,88.72 95.35,88.72 95.76,89.14 102.04,89.14 102.64,88.54 104.56,88.54 106.09,87.01 106.09,85.21 107.29,84 107.29,83.6 107.87,83.02 108.77,83.02 110.6,81.19 114.15,81.19 116.06,79.27 117.88,79.27 118.46,78.69 119.38,78.69 120.57,77.49 122.84,77.49 123.36,78.02 125.78,78.02 125.84,77.95 130.26,77.95 131.88,76.34 131.88,76.12 133.28,74.71 133.66,74.71 136.88,71.5 137.46,71.5 138.59,70.37 138.59,69.51 139.56,68.54 139.56,67.96 141.41,66.1 141.41,64.25 141.82,63.84 141.82,60.62 146.5,55.93 160.82,55.93 162.65,54.1 176.05,54.1 178.45,56.5 189.21,56.5 189.62,56.91 194.09,56.91 194.95,56.04 196.77,56.04 198.89,53.93 198.89,53.43 199.3,53.02 202.46,53.02 203.65,54.22 206.74,54.22 206.84,54.11 208.86,54.11 210.14,55.4 213.13,55.4 213.97,54.55 221.54,54.55 222.26,55.27 225.26,55.27 226.18,56.19 228.17,56.19 229.27,57.29 231.07,57.29 232.13,56.23 233.5,56.23 233.83,55.9 233.83,55.21 233.5,54.88 232.8,54.88 232.58,55.1 232.58,55.45 v1(232.44,55.59)
  BOTTOM w0.102: v1(91.42,86.68) 91.15,86.4 U1.E28
PCIE10_L1_RXN_R: length 2.8
  TOP w0.102: v1(232.56,53.34) 232.76,53.54 232.76,53.92 R547.2
  BOTTOM w0.102: J22.29 232.6,52.39 232.75,52.54 232.75,53.15 v1(232.56,53.34)
PCIE10_L1_RXP: length 174.1
  TOP w0.102: R546.1 233.15,54.7 232.8,55.05 232.8,55.39 232.99,55.59 v1(233.16,55.59)
  IN4 w0.089: v1(92.31,86.65) 92.14,86.48 91.92,86.48 91.8,86.61 91.8,86.94 91.91,87.05 92.47,87.05 93.95,88.53 95.42,88.53 95.84,88.95 101.96,88.95 102.56,88.35 104.48,88.35 105.9,86.93 105.9,85.13 107.1,83.93 107.1,83.52 107.79,82.83 108.69,82.83 110.52,81 114.07,81 115.99,79.08 117.8,79.08 118.38,78.5 119.3,78.5 120.49,77.3 122.92,77.3 123.44,77.83 125.7,77.83 125.76,77.76 130.18,77.76 131.69,76.26 131.69,76.04 133.2,74.52 133.59,74.52 136.8,71.31 137.38,71.31 138.4,70.29 138.4,69.43 139.37,68.46 139.37,67.88 141.22,66.02 141.22,64.17 141.63,63.76 141.63,60.54 146.43,55.74 160.74,55.74 162.57,53.91 176.13,53.91 178.53,56.31 189.29,56.31 189.7,56.72 194.01,56.72 194.88,55.85 196.69,55.85 198.7,53.85 198.7,53.35 199.22,52.83 202.54,52.83 203.73,54.03 206.66,54.03 206.76,53.92 208.94,53.92 210.22,55.21 213.05,55.21 213.89,54.36 221.62,54.36 222.34,55.08 225.34,55.08 226.25,56 228.25,56 229.35,57.1 230.99,57.1 232.05,56.04 233.42,56.04 233.64,55.82 233.64,55.29 233.42,55.07 232.88,55.07 232.77,55.18 232.77,55.37 232.99,55.59 v1(233.16,55.59)
  BOTTOM w0.102: v1(92.31,86.65) 92.06,86.65 91.88,86.48 U1.E27
PCIE10_L1_RXP_R: length 2.7
  TOP w0.102: R546.2 232.97,53.92 232.97,53.51 v1(233.14,53.34)
  BOTTOM w0.102: v1(233.14,53.34) 232.95,53.15 232.95,52.49 233.1,52.34 J22.31
PCIE10_L1_TXN: length 190.2
  IN4 w0.089: v1(92.82,89.7) 92.85,89.73 93.48,89.73 94.56,90.82 97.47,90.82 98.21,90.08 102.6,90.08 103.08,89.6 104.91,89.6 107.18,87.32 107.18,86.19 107.8,85.57 109.79,85.57 110.33,85.02 110.33,84.1 111.36,83.07 112.46,83.07 112.8,83.41 113.82,83.41 116.36,80.87 118.02,80.87 119.22,79.67 119.83,79.67 120.43,79.07 126.23,79.07 126.35,78.96 130.7,78.96 132.84,76.81 133.53,76.81 134.85,75.5 134.85,74.96 136.06,73.75 137.7,73.75 139.16,72.29 139.16,71.87 140.33,70.7 140.33,69.71 141.92,68.12 141.92,67.79 144.01,65.69 144.01,62.37 148.47,57.91 153.45,57.91 154.39,56.97 161.22,56.97 161.87,56.32 165.27,56.32 165.73,55.87 176,55.87 177.75,57.62 188.84,57.62 189.84,58.62 197.28,58.62 198.27,57.63 198.27,56.02 199.75,54.53 200.46,54.53 200.59,54.41 202.44,54.41 203.26,55.23 207.16,55.23 207.3,55.09 208.43,55.09 209.71,56.37 213.55,56.37 214.36,55.56 218.17,55.56 219.69,57.08 221.49,57.08 223.78,59.36 232.59,59.36 233.27,58.68 235.62,58.68 236.26,58.04 236.26,56.62 236.81,56.07 239.5,56.07 241.14,54.43 241.14,49.21 241.04,49.11 241.04,48.42 241.24,48.22 241.64,48.22 v1(241.74,48.12)
  BOTTOM w0.102: v1(92.82,89.7) 93.18,89.34 93.18,88.65 93.05,88.52 93.05,88.02 93.35,87.73 U1.D24 ; C9113.1 239.29,48.37 240.08,48.37 240.33,48.12 240.83,48.12 241.2,48.5 241.37,48.5 v1(241.74,48.12)
PCIE10_L1_TXN_C: length 6.6
  BOTTOM w0.102: C9113.2 237.61,48.12 237.34,48.39 237.34,48.99 236.81,49.52 235.69,49.52 235.11,50.1 234.84,50.1 234.1,50.83 J22.35
PCIE10_L1_TXP: length 190.2
  IN4 w0.089: v1(92.82,90.28) 93.18,89.92 93.4,89.92 94.48,91.01 97.55,91.01 98.28,90.27 102.68,90.27 103.16,89.79 104.99,89.79 107.38,87.4 107.38,86.27 107.88,85.76 109.86,85.76 110.52,85.1 110.52,84.18 111.44,83.26 112.38,83.26 112.72,83.6 113.9,83.6 116.44,81.06 118.09,81.06 119.3,79.86 119.91,79.86 120.51,79.26 126.31,79.26 126.43,79.15 130.78,79.15 132.92,77 133.61,77 135.04,75.58 135.04,75.04 136.14,73.94 137.78,73.94 139.35,72.37 139.35,71.94 140.52,70.78 140.52,69.79 142.11,68.2 142.11,67.87 144.21,65.77 144.21,62.45 148.55,58.1 153.53,58.1 154.47,57.16 161.3,57.16 161.95,56.51 165.35,56.51 165.81,56.06 175.92,56.06 177.67,57.81 188.76,57.81 189.77,58.81 197.36,58.81 198.46,57.71 198.46,56.1 199.83,54.72 200.54,54.72 200.67,54.6 202.36,54.6 203.18,55.42 207.24,55.42 207.38,55.28 208.35,55.28 209.63,56.57 213.63,56.57 214.44,55.75 218.09,55.75 219.61,57.27 221.41,57.27 223.7,59.55 232.67,59.55 233.35,58.87 235.7,58.87 236.45,58.12 236.45,56.7 236.89,56.26 239.58,56.26 241.33,54.51 241.33,49.14 241.23,49.03 241.23,48.5 241.32,48.41 241.45,48.41 v1(241.74,48.7)
  BOTTOM w0.102: v1(92.82,90.28) 92.97,90.28 93.2,90.06 93.2,89.61 93.39,89.42 93.39,88.57 93.26,88.43 93.26,88.24 U1.C24 ; v1(241.74,48.7) 241.12,48.7 240.77,48.35 240.39,48.35 240.17,48.58 v2(239.83,48.58) 239.16,48.58 C9112.1
PCIE10_L1_TXP_C: length 6.6
  BOTTOM w0.102: J22.37 234.6,50.63 234.92,50.3 235.2,50.3 235.78,49.73 236.9,49.73 237.55,49.07 237.55,48.48 237.7,48.33 237.91,48.33 238.02,48.43 238.02,48.74 238.11,48.83 238.32,48.83 C9112.2
PCIE REDR _EN: length 14.1
  TOP w0.102: v1(223.76,54.67) 223.57,54.86 v3(223.57,55.29) 222.99,55.29 222.4,55.87 222.4,56.38 Q28.1 ; U25.7 229.17,50.16 229.02,50 R351.2 228.53,50.46 v1(228.48,50.51)
  BOTTOM w0.102: v1(223.76,54.67) 226.22,54.67 226.42,54.47 227.24,54.47 228.86,52.84 228.86,51.22 228.48,50.84 v1(228.48,50.51)
PCIE_RCOMPN: length 2
  TOP w0.254: v1(104.25,86.02) 104.25,86.01 104.25,85.05 104.02,84.82 RC49.2
  BOTTOM w0.254: v1(104.25,86.02) 104.52,85.75 U1.F5
PCIE_RCOMPP: length 2
  TOP w0.254: RC49.1 103.84,85.76 103.79,85.81 103.79,86.19 v1(104.23,86.62)
  BOTTOM w0.254: U1.E5 104.46,86.62 v1(104.23,86.62)
PECI: length 234.3
  TOP w0.102: v1(218.45,71.18) 219.01,71.18 219.41,70.78 221.83,70.78 222.11,71.06 222.49,71.06 222.7,70.84 222.7,70.36 222.95,70.12 v4(222.97,70.12) 223.12,70.12 223.68,70.67 223.68,71.56 223.88,71.77 224.14,71.77 224.34,71.97 224.34,72.36 R163.2
  IN3 w0.081: v1(76.13,89.5) 76.16,89.5 76.39,89.27 76.39,88.12 75.47,87.21 69.02,87.21 67.55,85.74 65.9,85.74 58.43,78.27 58.43,69.1 55.97,66.64 55.97,63.41 62.62,56.76 79.05,56.76 81.06,58.76 100.85,58.76 102.49,60.4 102.49,62.38 102.85,62.75 105.09,62.75 106.49,61.35 107.91,61.35 108.34,60.92 116.95,60.92 121.23,56.65 123.54,56.65 126.33,53.85 128.07,53.85 128.58,54.37 129.17,54.37 129.93,55.13 132.88,55.13 133.56,54.44 136.41,54.44 137.33,55.37 157.27,55.37 158.36,56.46 160.14,56.46 161.6,57.93 161.6,58.94 162.42,59.75 164.9,59.75 165.33,59.32 167.22,59.32 168.34,60.44 171.21,60.44 172.45,61.68 174.46,61.68 175.4,62.62 176.33,62.62 177.34,63.63 180.59,63.63 181.22,63 182.03,63 182.68,62.34 185.96,62.34 186.62,63 192.01,63 192.29,63.28 195.34,63.28 196.03,63.98 198.88,63.98 200.36,62.5 201.51,62.5 202.17,63.16 203.21,63.16 205.04,64.99 207.43,64.99 208.01,64.4 209.99,64.4 210.65,65.06 210.65,66.33 212.12,67.8 213.14,67.8 214.98,69.65 214.98,70.18 216.11,71.31 218.32,71.31 v1(218.45,71.18)
  BOTTOM w0.102: U1.A54 76.56,89.19 76.26,89.5 v1(76.13,89.5)
PECI_R: length 4.2
  TOP w0.102: C159.2 R163.1 226.31,72.71 227.26,73.67 227.93,73.67 U16.B12
PLANARID0: length 13.5
  BOTTOM w0.076: 107.96,70.56 107.55,70.56 107.38,70.59 107.32,70.59 107.17,70.61 107.13,70.62 106.53,70.62 106.41,70.74 105.68,70.74 U1.AP4
  BOTTOM w0.102: v3(115.35,76.09) 115.45,75.98 115.45,74.52 RC54.1 114.89,73.91 111.91,70.93 108.33,70.93 107.96,70.56
PLANARID1: length 9.1
  BOTTOM w0.076: 107.55,70.75 107.33,70.75 107.21,70.77 107.1,70.8 106.93,70.8 U1.AP2
  BOTTOM w0.102: RC51.1 114.28,73.77 111.82,71.31 v4(110.7,71.31) 110.55,71.16 108.24,71.16 107.83,70.75 107.55,70.75
PLANARID2: length 7.7
  BOTTOM w0.102: RC52.1 113.7,73.7 111.69,71.69 109.53,71.69 v4(109.38,71.54) 109.13,71.54 108.98,71.39 108.11,71.39 107.75,71.03 U1.AP1
PLANARID3: length 8.7
  BOTTOM w0.102: U1.AP3 106.41,71.4 107.69,71.4 108.01,71.72 108.98,71.72 109.2,71.94 111.59,71.94 112.04,72.39 v4(112.04,73.14) 112.29,73.14 RC53.1
PROCHOT_EC: length 11.5
  TOP w0.102: v1(241.86,70.75) 241.77,70.75 Q7.2 241.41,71.16 R156.2 ; U16.D3 v1(235.91,75.3)
  IN1 w0.076: v1(241.86,70.75) 240.45,70.75 239.92,71.28 238.72,71.28 237.61,72.39 237.61,73.05 238.06,73.5 238.06,74.08 236.84,75.3 v1(235.91,75.3)
PS8349B_DP_CFG0: length 3.6
  TOP w0.102: R2531.2 49.72,73.98 49.74,73.95 v4(49.74,73.65) 49.67,73.57 48.96,73.57 48.43,73.05 48.03,73.05 47.75,72.77 U147.2
PS8349B_DP_CFG1: length 7.1
  TOP w0.102: R2524.1 48.85,77.23 ; 48.85,77.23 49.26,76.82 49.26,74.05 49.03,73.82 48.52,73.82 v4(48.37,73.67) 48.24,73.55 48.14,73.55 47.35,72.75 U147.3 ; 48.85,77.23 R2523.2
PS8349B_MODE: length 4.4
  TOP w0.102: R2527.2 R2528.1 v4(38.85,73.47) 39.56,73.47 40.15,72.88 U147.21
PS8349B_PC1: length 5.7
  TOP w0.102: R2529.2 R2530.1 36.56,73.98 37.22,73.98 v4(37.58,73.62) 38.11,73.09 39.43,73.09 39.75,72.77 U147.22
PS8349B_PC2: length 3.1
  TOP w0.102: U147.45 43.75,66.53 v4(43.57,66.36) 43.42,66.2 R9130.1 R9131.2
PS8349B_PEQ: length 3.3
  TOP w0.102: R2562.1 R2561.2 40.83,73.93 41.35,73.41 U147.18
PS8349B_TMDS_DDCBUF: length 3.7
  TOP w0.102: U147.23 38.25,72.39 38.06,72.2 v4(37.63,72.2) 37.52,72.31 37.34,72.31 37.19,72.45 R1899.1 R1877.2
PS8349B_TMDS_PRE: length 3.5
  TOP w0.102: U147.26 v4(37.17,70.91) 36.98,71.11 R1897.1 R1875.2
PSYS: length 124.2
  TOP w0.203: v1(126.81,87.72) 126.4,88.12 125.6,88.12 124.03,86.56 121.49,86.56 121.04,87.01 121.04,89.01 121.32,89.29 v3(121.32,93.46) 121.65,93.79 122.41,93.79 v1(122.59,93.97) 122.59,94.17 PR412.1 ; PC152.2 204.77,73.55 PR150.2 ; PC152.2 202.85,73.62 202.01,74.47 PU101.10 ; PC152.2 204.7,73.8 204.86,73.96 v1(204.86,74.18)
  IN1 w0.254: v1(126.81,87.72) 127.62,87.72 129.47,85.86 129.47,82.71 130.1,82.08 135.59,82.08 136.27,81.4 140.18,81.4 141.68,79.9 141.68,75.69 143.19,74.18 143.19,71.18 143.93,70.45 145.86,70.45 146.82,69.49 156.35,69.49 156.92,70.05 157.53,70.05 158.48,71.01 163.56,71.01 165.97,68.59 172.02,68.59 174.38,70.95 178.27,70.95 180.2,69.02 184.11,69.02 186.14,67 190.25,67 190.61,66.64 197.37,66.64 198.66,67.93 199.32,67.93 199.53,68.13 199.53,70.83 200.01,71.31 204.35,71.31 204.86,71.82 v1(204.86,74.18)
  BOTTOM w0.203: PU401.46 122.78,94.08 122.67,93.97 v1(122.59,93.97)
PWM1_2PH: length 75.2
  IN1 w0.254: v1(125.1,109.21) 125.05,109.26 123.91,109.26 120.96,112.2 69.71,112.2 69.12,111.62 v1(64.3,111.62)
  BOTTOM w0.203: v1(125.1,109.21) 126.24,108.07 126.24,104.79 124.39,102.94 123.49,102.94 123.18,102.63 PU401.16
  BOTTOM w0.254: v1(64.3,111.62) PU403.4
PWM_1A: length 39.7
  IN3 w0.254: v1(125.66,101.87) 125.12,101.33 110.4,101.33 109.25,102.48 100.44,102.48 99.16,103.76 95.92,103.76 95.41,103.25 95.41,102.55 94.68,101.82 91.98,101.82 v1(91.63,101.46)
  BOTTOM w0.203: PU401.22 125.58,101.79 v1(125.66,101.87)
  BOTTOM w0.254: v1(91.63,101.46) 91.55,101.54 91.22,101.54 90.59,102.17 PU402.4
PWM_1B: length 19.1
  TOP w0.254: v1(128.08,94.47) 128.53,94.93 129.57,94.93 130.41,94.1 130.41,93.74 130.25,93.59 130.25,90.19 130.64,89.8 130.64,89.33 v1(129.77,88.46)
  IN3 w0.254: v1(129.77,88.46) 129.01,87.7 129.01,83.23 131.37,80.87 v1(131.75,80.87)
  BOTTOM w0.203: v1(131.75,80.87) 131.65,80.96 PU405.4
REFIN: length 5.5
  TOP w0.305: PR307.2 129.26,65.32 v1(129.39,65.45)
  BOTTOM w0.254: v1(129.39,65.45) 129.42,65.41 129.42,64.22 129.17,63.97 PR308.1 128.89,64.02 PC307.1 128.15,63.97 v4(127.34,63.97) 127.21,63.97 127.13,64.05 PU301.8
REGN: length 16.1
  TOP w0.178: PU101.28 194.91,75.67 v4(194.8,75.78) 194.75,75.83 194.34,75.83 PC155.1
  TOP w0.203: PC155.1 194.17,76.47 194.5,76.47 v2(194.62,76.34) ; v1(202.65,69.84) 202.8,69.68 PR136.1
  IN4 w0.203: v1(202.65,69.84) 202.65,69.94 201.41,71.18 201.02,71.18 196.57,75.64 195.32,75.64 v2(194.62,76.34)
RING2:
  vias: v4(279.48,61.94)
RJ45_ACTIVITY: length 1.9
  TOP w0.102: UL1.27 208.65,71.59 207.86,72.39 R92.2
RJ45_ACTIVITY_SYS: length 107.4
  TOP w0.305: 225.88,86.96 225.68,86.76 R94.2
  TOP w0.508: v1(227.71,88.66) 227.71,88 v4(227.52,87.81) 226.95,87.24 226.16,87.24 225.88,86.96 ; v1(278.36,136.8) v3(279,136.8) 279.18,136.8 CL16.2 280.19,134.85 RL13.1
  IN1 w0.508: v1(260.71,118.03) 259.46,119.27 259.46,134.14 263.97,138.65 270.41,138.65 272.26,136.8 v1(278.36,136.8)
  IN4 w0.508: v1(260.71,118.03) 261.34,117.39 261.34,114.49 256.8,109.95 250.83,109.95 249.73,108.86 249.07,108.86 248.24,109.69 247.4,109.69 245.92,108.22 240.92,108.22 239.42,109.72 231.8,109.72 231.34,109.26 231.34,107.29 229.17,105.12 229.17,99.44 225.88,96.16 225.88,94.07 227.71,92.24 v1(227.71,88.66)
RJ45_LINKUP: length 37.4
  TOP w0.102: UL1.26 208.61,71.99 208.48,72.12 208.48,72.82 208.01,73.29 R93.2 208.01,74.79 207.73,75.07 207.73,75.79 v1(208.87,76.93) ; U16.G3 v1(235.91,78.46)
  IN1 w0.076: v1(235.91,78.46) 235.49,78.88 232.24,78.88 231.46,78.1 229.89,78.1 229.36,78.63 228.51,78.63 228.28,78.85 227.47,78.85 226.83,79.49 222.66,79.49 222.03,80.12 215.47,80.12 214.59,79.23 213.34,79.23 212.84,79.74 211.1,79.74 208.87,77.51 v1(208.87,76.93)
RJ45_LINKUP_SYS: length 96
  TOP w0.305: 225.78,87.81 225.37,87.4 R95.2
  TOP w0.508: v1(267.95,113.38) v4(266.14,113.38) 264.29,113.38 v1(260.66,117) ; 225.78,87.81 226.03,88.06 226.63,88.06 227,88.43 v1(227,88.64) ; v1(282.71,117.97) 282.71,119.31 283.09,119.7 CL17.2 283.12,119.71 RL12.2
  IN3 w0.508: v1(267.95,113.38) 278.41,113.38 282.71,117.67 v1(282.71,117.97)
  IN4 w0.508: v1(260.66,117) 260.66,114.87 256.43,110.63 247.32,110.63 245.59,108.91 242.24,108.91 240.51,110.63 231.57,110.63 230.61,109.67 230.61,107.66 229.01,106.06 225.73,106.06 224.31,104.64 224.31,102.56 224.99,101.87 226.24,101.87 227.45,100.66 227.45,98.99 225.15,96.7 225.15,93.18 227,91.33 v1(227,88.64)
RJ45_TXD0N: length 13.1
  BOTTOM w0.102: J3.2 285.92,125.53 285.8,125.64 285.06,125.64 284.28,124.86 284.28,124.18 283.79,123.68 282.75,123.68 282.38,123.32 282.38,122.92 281.66,122.2 DL2.3 281.66,121.92 282.15,121.42 282.15,121.13 281.86,120.84 v2(281.04,120.84) 280.77,120.84 280.32,120.39 280.06,120.39 279.69,120.76 T1.23
RJ45_TXD0P: length 13.1
  BOTTOM w0.102: T1.24 279.99,119.49 280.94,120.43 282.03,120.43 282.63,121.04 v2(282.84,121.04) 283.05,121.04 283.56,121.55 DL2.1 283.56,122.18 282.79,122.95 282.79,123.15 282.91,123.28 283.96,123.28 284.68,124.01 284.68,124.69 285.23,125.23 285.63,125.23 285.88,124.99 J3.1
RJ45_TXD1N: length 17.6
  TOP w0.102: v1(283.44,125.84) 283.38,125.84 282.96,125.42 282.96,125.11 283.16,124.91 283.68,124.91 284.1,125.33 284.1,128.26 284.46,128.62 284.7,128.62 285.69,129.61 J3.6
  BOTTOM w0.102: T1.19 279.85,125.84 280.28,125.4 280.39,125.4 280.49,125.51 280.49,125.94 281.19,126.64 282,126.64 282.89,125.74 282.89,125.23 DL2.6 283.56,125.72 v1(283.44,125.84)
RJ45_TXD1P: length 17.5
  TOP w0.102: J3.3 285.88,127.4 285.63,127.65 285.4,127.65 284.83,128.21 284.63,128.21 284.51,128.09 284.51,125.16 283.85,124.5 282.99,124.5 282.55,124.94 282.55,125.37 282.12,125.79 v1(281.66,125.79)
  BOTTOM w0.102: v1(281.66,125.79) 281.66,124.59 ; 281.66,124.59 DL2.4 ; 281.66,124.59 282.48,125.41 282.48,125.57 281.83,126.23 281.36,126.23 280.9,125.77 280.9,125.34 280.56,125 280.3,125 279.87,124.57 T1.20
RJ45_TXD2N: length 11.9
  BOTTOM w0.102: J3.5 285.27,127.97 285.11,127.97 284.9,128.18 284.9,129.2 284.39,129.7 283.58,129.7 283.31,129.44 282.07,129.44 281.66,129.03 DL1.6 281.66,128.31 282.07,127.91 282.07,127.69 282,127.63 281.06,127.63 v2(280.9,127.78) 280.74,127.94 280.43,127.94 280.33,128.05 280.33,128.27 280.23,128.38 T1.17
RJ45_TXD2P: length 12
  BOTTOM w0.102: J3.4 284.94,127.57 284.49,128.01 284.49,128.98 284.17,129.3 283.74,129.3 283.56,129.11 DL1.4 283.56,128.1 283.04,127.58 v2(282.83,127.58) 282.53,127.58 282.17,127.22 280.89,127.22 280.57,127.54 280.43,127.54 280.33,127.44 280.33,127.21 280.23,127.11 T1.18
RJ45_TXD3N: length 10.6
  BOTTOM w0.102: J3.8 286.88,131.74 285.71,131.74 285.25,131.28 284.41,131.28 284.24,131.11 DL1.3 283.56,131.65 v2(282.86,132.35) 282.66,132.55 282.41,132.55 281.95,133.01 280.43,133.01 280.37,133.06 280.37,133.31 280.23,133.46 T1.13
RJ45_TXD3P: length 10.5
  BOTTOM w0.102: J3.7 285.19,130.63 284.94,130.88 284.58,130.88 284.41,130.7 284.11,130.7 283.77,130.35 282.21,130.35 281.66,130.91 DL1.1 281.66,131.71 282.04,132.1 282.04,132.34 281.78,132.6 v2(280.87,132.6) 280.64,132.6 280.23,132.19 T1.14
RT1_R: length 72.1
  TOP w0.254: v1(226.06,99.56) 226.44,99.94 RT1.2
  IN3 w0.254: v1(225.31,88.84) 225.31,88.96 224.44,89.83 222.82,89.83 221.75,88.76 219.92,88.76 218.96,87.79 217.56,87.79 217.03,87.26 215.66,87.26 212.84,84.44 212.84,83.6 213.19,83.25 213.19,78.96 212.23,77.99 211.74,77.99 210.68,79.06 209.41,79.06 206.94,76.59 205.19,76.59 203.77,75.17 203.77,74.76 202.18,73.18 v1(202.05,73.18)
  IN4 w0.254: v1(225.31,88.84) 225.31,90.92 221.5,94.73 221.5,96.82 224.24,99.56 v1(226.06,99.56) ; v1(196.06,67.89) 196.06,68.09 196.72,68.75 197.41,68.75 198.1,68.06 202.37,68.06 203.13,68.82 203.13,72.1 v1(202.05,73.18)
  BOTTOM w0.254: v1(196.06,67.89) 196.06,65.03 194.83,63.79 RT2.1
RT2_R: length 89.4
  TOP w0.254: v1(154.95,90.11) 154.95,92.34 154.51,92.78 154.51,101.62 155.86,102.96 159.95,102.96 160.12,102.79 RT3.1
  IN3 w0.254: v1(154.95,90.11) 159.8,85.26 161.55,85.26 162.52,84.29 162.52,82.33 161.43,81.24 v1(161.43,80.45)
  IN4 w0.254: v1(161.43,80.45) 160.69,79.72 160.69,78.78 160.97,78.5 163.92,78.5 164.88,77.53 164.88,70.17 167.59,67.45 177.45,67.45 178.06,66.84 182.46,66.84 183.24,66.05 185.43,66.05 186.07,66.69 188.68,66.69 188.86,66.51 194.7,66.51 195.36,67.17 196.06,67.17 v1(196.65,67.76)
  BOTTOM w0.254: v1(196.65,67.76) 196.68,67.73 196.68,64.83 195.06,63.21 192.9,63.21 192.44,63.66 RT2.2
RT3_R: length 20.5
  TOP w0.254: RT3.2 161.04,102.66 160.33,103.37 155.66,103.37 152.61,106.41 v3(145.75,106.41) 143.9,108.27 RT4.1
RT4_R: length 47
  TOP w0.254: RT4.2 142.5,107.91 143.13,107.29 143.99,107.29 v3(144.01,107.26) 145.32,105.96 152.43,105.96 154.08,104.31 154.08,92.45 v1(154.21,92.32)
  IN3 w0.254: v1(154.21,92.32) 153.16,92.32 149.4,88.56 145.11,88.56 142.24,85.69 142.24,83.86 143,83.1 v1(143.77,83.1)
  BOTTOM w0.254: v1(143.77,83.1) 143.77,82.82 144.81,81.77 RT5.1
RT5_R: length 31
  IN4 w0.254: v1(172.3,79.41) 172.3,79.51 170.49,81.32 158.86,81.32 157.08,79.54 148.4,79.54 147.08,80.86 v1(145.2,80.86)
  BOTTOM w0.254: RT6.1 172.35,79.36 v1(172.3,79.41) ; RT5.2 v1(145.2,80.86)
RT6_R: length 25.1
  IN4 w0.254: v1(174.56,79.36) 175.07,78.85 177.81,78.85 179,77.66 179,74.82 180.78,73.04 191.32,73.04 192.39,71.97 v1(192.39,70.98)
  BOTTOM w0.254: v1(192.39,70.98) RT7.1 ; RT6.2 v1(174.56,79.36)
RT7_R: length 112.8
  TOP w0.254: v1(170.44,85.38) 170.44,86.12 170.04,86.52 166.91,86.52 166.32,87.11 v3(165.99,87.11) 165.53,87.11 163.88,85.46 155.99,85.46 155.2,86.25 143.89,86.25 142.17,84.52 142.17,83.43 139.75,81.02 136.76,81.02 135.92,80.18 133.81,80.18 132.06,78.44 132.06,73.14 130.74,71.82 130.74,71.41 130.24,70.9 129.35,70.9 128.42,69.98 128.42,68.77 127.18,67.53 124.64,67.53 122.76,69.41 118.24,69.41 v1(118.19,69.36)
  IN4 w0.254: v1(192.98,70.98) 192.98,71.93 191.45,73.47 180.96,73.47 179.43,74.99 179.43,77.84 177.99,79.28 176.72,79.28 175.14,80.86 175.14,84.21 174.46,84.9 170.93,84.9 v1(170.44,85.38)
  BOTTOM w0.254: RT7.2 192.98,72.24 v1(192.98,70.98) ; RT8.1 117.79,60.49 118.78,61.48 118.78,62.88 119.21,63.31 119.21,66.26 118.88,66.59 118.88,66.99 118.19,67.69 v1(118.19,69.36)
RTCVCC: length 5.6
  TOP w0.254: 98.82,58.94 RC62.2 99.55,58.94
  TOP w0.305: CC43.2 95.63,71.53 ; CC43.2 96.07,71.16 ; CC43.2 95.63,70.88 ; 99.22,58.6 RC62.2 ; DC2.1 DC3.1 ; 97.1,59.88 RC124.1 ; 97.22,60.6 RC123.1
  BOTTOM w0.127: v1(99.35,65.94) 99.36,65.96 U1.BB14
  BOTTOM w0.254: v1(96,73.09) 96.54,73.63 U1.AK19
  vias: v4(98.22,59.38)
RTCX1: length 25.1
  TOP w0.102: Y2.2 116.19,72.73 115.28,73.63 CC12.1 114.88,73.63 114.6,73.35 RC58.2 113.56,73.35 110.86,70.65 110.49,70.65 109.79,69.95 109.79,69.58 109.53,69.33 v1(109.53,69.15)
  IN1 w0.076: v1(109.53,69.15) 109.53,69.55 108.94,70.14 106.23,70.14 104.55,71.82 103.87,71.82 103.08,72.61 102.27,72.61 101.91,72.96 100.97,72.96 100.13,73.8 99.2,73.8 98.94,73.55 97.29,73.55 v1(96.96,73.21)
  BOTTOM w0.102: U1.AM18 97.02,73.21 v1(96.96,73.21)
RTCX2: length 25.4
  TOP w0.102: v1(109,69.48) 109.1,69.48 109.35,69.73 109.35,70.12 110.4,71.17 110.79,71.17 113.56,73.94 RC58.1 114.84,74.22 CC13.1 115.2,74.22 116.21,75.23 Y2.1
  IN1 w0.076: v1(96.94,72.61) 97.05,72.72 98.04,72.72 98.41,73.09 100.58,73.09 100.89,72.78 101.68,72.78 102.18,72.28 102.55,72.28 102.88,71.94 102.88,70.57 103.16,70.29 105.47,70.29 106.05,69.71 108.77,69.71 v1(109,69.48)
  BOTTOM w0.102: U1.AM20 96.68,72.86 v1(96.94,72.61)
S1_DRV: length 69.8
  TOP w0.102: v1(255.28,77.08) 254.9,77.08 U21.F1
  TOP w0.203: PR38.1 220.75,98.57 220.75,97.12 v3(220.76,97.12) 220.75,97.11 220.75,95.42 219.18,93.85 217.73,93.85 214.32,90.43 213.16,90.43 211.85,89.12 211.85,84.74 v1(212.24,84.35)
  IN1 w0.203: v1(255.28,77.08) 255.28,79.74 252.99,82.03 247.94,82.03 247.08,82.89 243.57,82.89 241.56,84.9 236.25,84.9 235.77,85.39 232.21,85.39 231.88,85.71 222.23,85.71 221.37,84.85 213.26,84.85 212.75,84.35 v1(212.24,84.35)
S2_DRV: length 76.6
  TOP w0.102: U21.C2 254.16,74.74 255.28,74.74 255.71,74.31 v1(255.71,74.23)
  TOP w0.203: v1(212.3,86.93) 212.3,89.09 213.31,90.09 214.41,90.09 217.85,93.53 v3(225.13,93.53) 225.82,93.53 226.49,94.21 PR39.1
  IN1 w0.203: v1(255.71,74.23) 255.71,74.33 256.88,75.5 256.88,79.03 253.25,82.66 253.25,83.11 252.07,84.29 250.52,84.29 249.88,83.65 246.52,83.65 244.69,85.48 236.66,85.48 236.07,86.07 235.05,86.07 233.69,87.44 225.43,87.44 224.93,86.93 219.99,86.93 218.75,85.69 214.94,85.69 214.48,86.15 213.09,86.15 v1(212.3,86.93)
S3_1.2V: length 2.9
  BOTTOM w0.254: PU301.17 122.27,63.65 v4(122.18,63.74) 121.63,63.74 PC302.2 121.4,64.13 PR301.2
S5_1.2V: length 4.1
  BOTTOM w0.254: PU301.16 122.48,63.25 122.41,63.18 PC301.1 121.29,62.83 121.15,62.69 PR302.2 PR306.2 121.15,61.2 PD301.2
S-BAT-PWR: length 73.3
  TOP w0.508: PF4.2 223.85,101.95 220.91,101.95 220.14,102.71 220.14,105.25 225.6,110.71 262.47,110.71 262.82,111.07 265.71,111.07 266.32,110.46 266.32,109.48 265.88,109.03 265.15,109.03 263.98,107.87 263.98,99.89 263.32,99.23 261.67,99.23 261.14,98.7 PF8.1
  vias: v3(222.92,101)
S-BAT-TRCL: length 4.1
  TOP w0.508: PD13.3 263.25,96.77 PF8.2 262.16,96.12 PD18.1 ; PD13.3 263.32,95.99 PD17.1 ; PD13.3 PD13.2
S-BAT-TRCL_A:
  vias: v3(261.11,93.46)
S_BAT_IN:
  vias: v3(224.39,105.71) v3(227.99,100.96) v3(228.86,102.66)
S_BAT_PWR_A: length 0.3
  TOP w0.305: PR36.2 224.71,95.54
  vias: v3(223.66,95.21)
S_TEMP: length 26.8
  TOP w0.102: v1(235.02,88.14) v4(236.28,88.14) 237.07,88.14 R143.1
  TOP w0.203: PJ3.5 235.66,104.31 237.54,106.19 v3(237.54,106.6) 236.98,106.6 236.63,106.24 PC23.2 236.33,106.36 PR33.1 235.97,106.83 PD9.1
  IN4 w0.076: v1(235.02,88.14) 235.26,88.38 235.26,89.75 235.24,89.78 235.24,92.89 238.21,95.86 238.21,100.55 235.6,103.16 PJ3.5
S_TRCL: length 28.2
  TOP w0.102: PQ24.2 261.27,91.27 261.52,91.03 261.52,90.49 262.94,89.07 262.94,87.93 264.39,86.48 264.39,83.51 264.26,83.38 263.32,83.38 262.87,82.92 262.23,82.92 261.26,83.89 259.08,83.89 258.5,84.47 v3(257.36,84.47) 256.3,84.47 255.53,83.71 254.82,83.71 254.39,83.27 253.76,83.27 253.53,83.04 253.53,80.45 254.16,79.82 254.16,79.01 253.86,78.7 253.58,78.7 253.32,78.44 253.32,77.9 U21.G3
SA0: length 6.4
  TOP w0.127: v1(87.53,28.94) 87.22,28.64 v4(86.9,28.64) 86.42,29.12 86.42,30.04 85.53,30.93 RD4.2 RD1.1
  BOTTOM w0.127: v1(87.53,28.94) 87.03,28.44 J21.256
SA1: length 5.1
  TOP w0.127: RD5.2 RD2.1 86.84,30.56 v4(87.29,30.11) 87.53,29.87 v1(87.53,29.57)
  BOTTOM w0.127: v1(87.53,29.57) 88.03,29.07 J21.260
SA2: length 27
  TOP w0.102: v1(82.66,29.15) 82.76,29.25 v4(82.76,29.83) 82.53,30.06 RD6.2 RD3.1
  IN3 w0.081: v1(82.66,29.15) 83.12,28.69 83.12,27.04 81.98,25.89 65.21,25.89 64.5,26.61 v1(64.5,28.33)
  BOTTOM w0.127: v1(64.5,28.33) 64.53,28.3 J21.166
SATA1_DEVSLP: length 163.1
  TOP w0.102: U7.2 222.71,51.54 v1(222.75,51.59) 222.71,51.63 222.71,53.89 221.62,54.99 221.62,56.56 221.13,57.04 220.09,57.04 219.82,57.31 217.13,57.31 216.34,58.1 216.34,61.15 215.33,62.17 215.33,63.26 214.54,64.05 v1(214.08,64.05)
  IN3 w0.081: v1(210.5,78.42) 210.3,78.22 209.17,78.22 207.98,77.03 207.98,75.9 207.32,75.25 207.32,74.05 207.04,73.77 206.46,73.77 205.85,73.16 203.34,73.16 201.69,71.51 200.09,71.51 199.6,71.03 194.42,71.03 191.58,73.88 181.2,73.88 180.01,72.69 175.66,72.69 171.62,68.64 160.61,68.64 160.08,68.11 159.04,68.11 158.48,68.67 147.03,68.67 145.35,66.99 143.09,66.99 141.16,68.92 140.85,68.92 139.73,70.04 137.83,70.04 136.99,69.2 135.65,69.2 135.34,69.51 135.34,71.51 131.1,75.75 131.1,77 130.59,77.51 126.91,77.51 126.28,78.14 120.84,78.14 119.16,79.82 116.65,79.82 115.35,81.11 115.35,85.03 v1(114.94,85.43)
  BOTTOM w0.076: 107.6,84.54 107.22,84.54 107.12,84.49 106.9,84.49 U1.J2
  BOTTOM w0.102: v1(114.94,85.43) 114.94,85.33 114.28,84.67 113.35,84.67 113.14,84.89 112.52,84.89 112.02,84.39 109.89,84.39 109.81,84.47 107.68,84.47 107.6,84.54 ; R433.1 221.95,51.96 222.16,51.75 222.59,51.75 v1(222.75,51.59) ; v1(214.08,64.05) 213.45,64.05 213.2,64.29 213.2,65.81 212.99,66.03 212.99,72.43 212.2,73.21 212.2,75.75 211.32,76.63 211.32,77.6 v1(210.5,78.42)
SATA2_DEVSLP: length 160.3
  TOP w0.102: R789.1 234.06,59.36 234.38,59.68 v4(234.38,59.8) 234.38,60.31 v1(234.3,60.39)
  IN3 w0.081: v1(195.86,69.71) 195.84,69.71 195.65,69.53 192.52,69.53 191.4,68.41 184.39,68.41 183.96,67.98 183.19,67.98 182.58,68.59 178.83,68.59 178.34,68.11 173.31,68.11 172.93,67.73 167.22,67.73 166.2,66.71 163.56,66.71 160.77,63.92 157.95,63.92 155.84,61.81 151.6,61.81 151.22,61.43 147.81,61.43 145.83,63.41 142.6,63.41 141.95,64.06 139.54,64.06 138.87,64.73 138.87,65.09 137.55,66.41 136.85,66.41 136.63,66.63 136.63,66.79 136.31,67.12 135.39,67.12 133.38,69.13 133.38,70.12 132.62,70.88 129.42,70.88 128.1,72.2 128.1,73.44 127.09,74.46 125.05,74.46 122.64,76.87 120.42,76.87 118.75,78.55 116.57,78.55 114.15,80.97 113.08,80.97 112.65,81.4 112.65,82.85 112.32,83.18 111.52,83.18 110.8,83.89 110.8,84.92 110.02,85.71 108.8,85.71 v1(107.93,84.85)
  IN4 w0.076: v1(198.03,63.16) 198.64,63.16 200.34,61.45 200.34,60.9 201.96,59.27 221.7,59.27 223.91,61.48 233.64,61.48 234.3,60.82 v1(234.3,60.39)
  BOTTOM w0.076: U1.J3 106.43,84.67 107.1,84.67 107.2,84.72 107.81,84.72 v1(107.93,84.85)
  BOTTOM w0.102: v1(198.03,63.16) 198.1,63.23 198.1,64.32 200.57,66.79 200.57,67.86 198.66,69.76 195.91,69.76 v1(195.86,69.71)
SATA2_DEVSLP_C: length 3.9
  TOP w0.102: R789.2 234.64,59.02 235.08,59.45 235.47,59.45 v4(235.72,59.7) 235.72,59.72 235.05,60.39 v1(234.95,60.39)
  BOTTOM w0.102: v1(234.95,60.39) 234.85,60.29 J22.38
SATA_PCIE_SELECT: length 28.9
  TOP w0.102: v1(225.32,58.13) 225.38,58.13 226.19,57.32 v3(226.39,57.32) 226.39,55.96 225.1,54.67 Q29.1 226.25,53.32 226.25,52.88 R383.2 ; U24.18 238.67,50.28 238.72,50.33 238.72,51.12 239.1,51.5 239.1,52.48 239.57,52.95 v1(239.7,52.95)
  BOTTOM w0.102: v1(239.7,52.95) 239.7,53.08 239.93,53.31 239.93,54.2 239.14,54.99 236.83,54.99 234.75,57.07 233.35,57.07 232.49,57.92 228.51,57.92 227.62,57.04 226.04,57.04 225.32,57.75 v1(225.32,58.13)
SD_MMC_CLK: length 1.4
  TOP w0.102: R111.1 278.92,88.44 279.26,88.1 U15.17
SD_MMC_CLK_R: length 30.5
  TOP w0.102: v1(279.71,90.61) 277.82,90.61 277.48,90.28 C138.1 277.48,89.92 277.14,89.58 277.14,89.05 R111.2
  IN4 w0.076: v1(279.71,90.61) 279.53,90.43 277.69,90.43 277.61,90.5 277.61,91.01 277.43,91.2 277.06,91.2 276.9,91.04 276.9,90.5 276.82,90.43 275.2,90.43 273.08,92.55 273.08,95 271.97,96.11 271.97,98.13 271.89,98.21 271.56,98.21 271.51,98.26 271.51,98.69 271.61,98.79 272.23,98.79 272.32,98.88 272.32,99.7 272.22,99.81 271.56,99.81 271.48,99.88 271.48,100.44 271.56,100.52 271.99,100.52 272.04,100.57 272.04,102.42 271.92,102.55 v1(270.77,102.55)
  BOTTOM w0.102: J23.5 269.79,103.53 v1(270.77,102.55)
SD_MMC_CMD: length 30.7
  TOP w0.102: U15.19 278.99,87.3 v1(278.59,86.89)
  IN4 w0.076: v1(269.58,106.34) 268.18,104.94 268.18,95.11 270.98,92.31 270.98,89.01 273.19,86.8 277.05,86.8 277.43,86.42 278.12,86.42 v1(278.59,86.89)
  BOTTOM w0.102: v1(269.58,106.34) 269.38,106.53 J23.2
SD_MMC_D0: length 31.1
  TOP w0.102: v1(277.65,89.37) 278.06,88.96 280.17,88.96 280.25,88.89 U15.16
  IN4 w0.076: v1(277.65,89.37) 277.65,88.99 277.47,88.81 276.62,88.81 276.29,89.14 275.62,89.14 275.31,89.45 275.17,89.45 275.04,89.32 274.89,89.32 274.75,89.46 274.75,89.6 274.88,89.74 274.88,89.88 274.65,90.12 274.5,90.12 273.58,89.2 273.44,89.2 273.29,89.34 273.29,89.48 274.21,90.41 274.21,90.55 274.07,90.69 273.93,90.69 273,89.77 272.86,89.77 272.72,89.91 272.72,90.06 273.64,90.98 273.64,91.12 273.5,91.27 273.35,91.27 272.55,90.46 272.4,90.46 272.26,90.6 272.26,90.75 273.06,91.56 273.06,91.7 272.77,92 272.62,92 272.37,91.75 272.23,91.75 272.09,91.89 272.09,92.04 272.33,92.29 272.33,94.73 271.13,95.94 270.82,95.94 270.72,96.04 270.72,96.24 270.82,96.34 271.13,96.34 271.23,96.44 271.23,96.65 271.1,96.78 269.78,96.78 269.68,96.88 269.68,97.08 269.78,97.18 270.34,97.18 270.49,97.33 270.49,97.93 270.32,98.11 v1(269.63,98.11)
  BOTTOM w0.102: J23.7 268.87,97.93 269.05,98.11 v1(269.63,98.11)
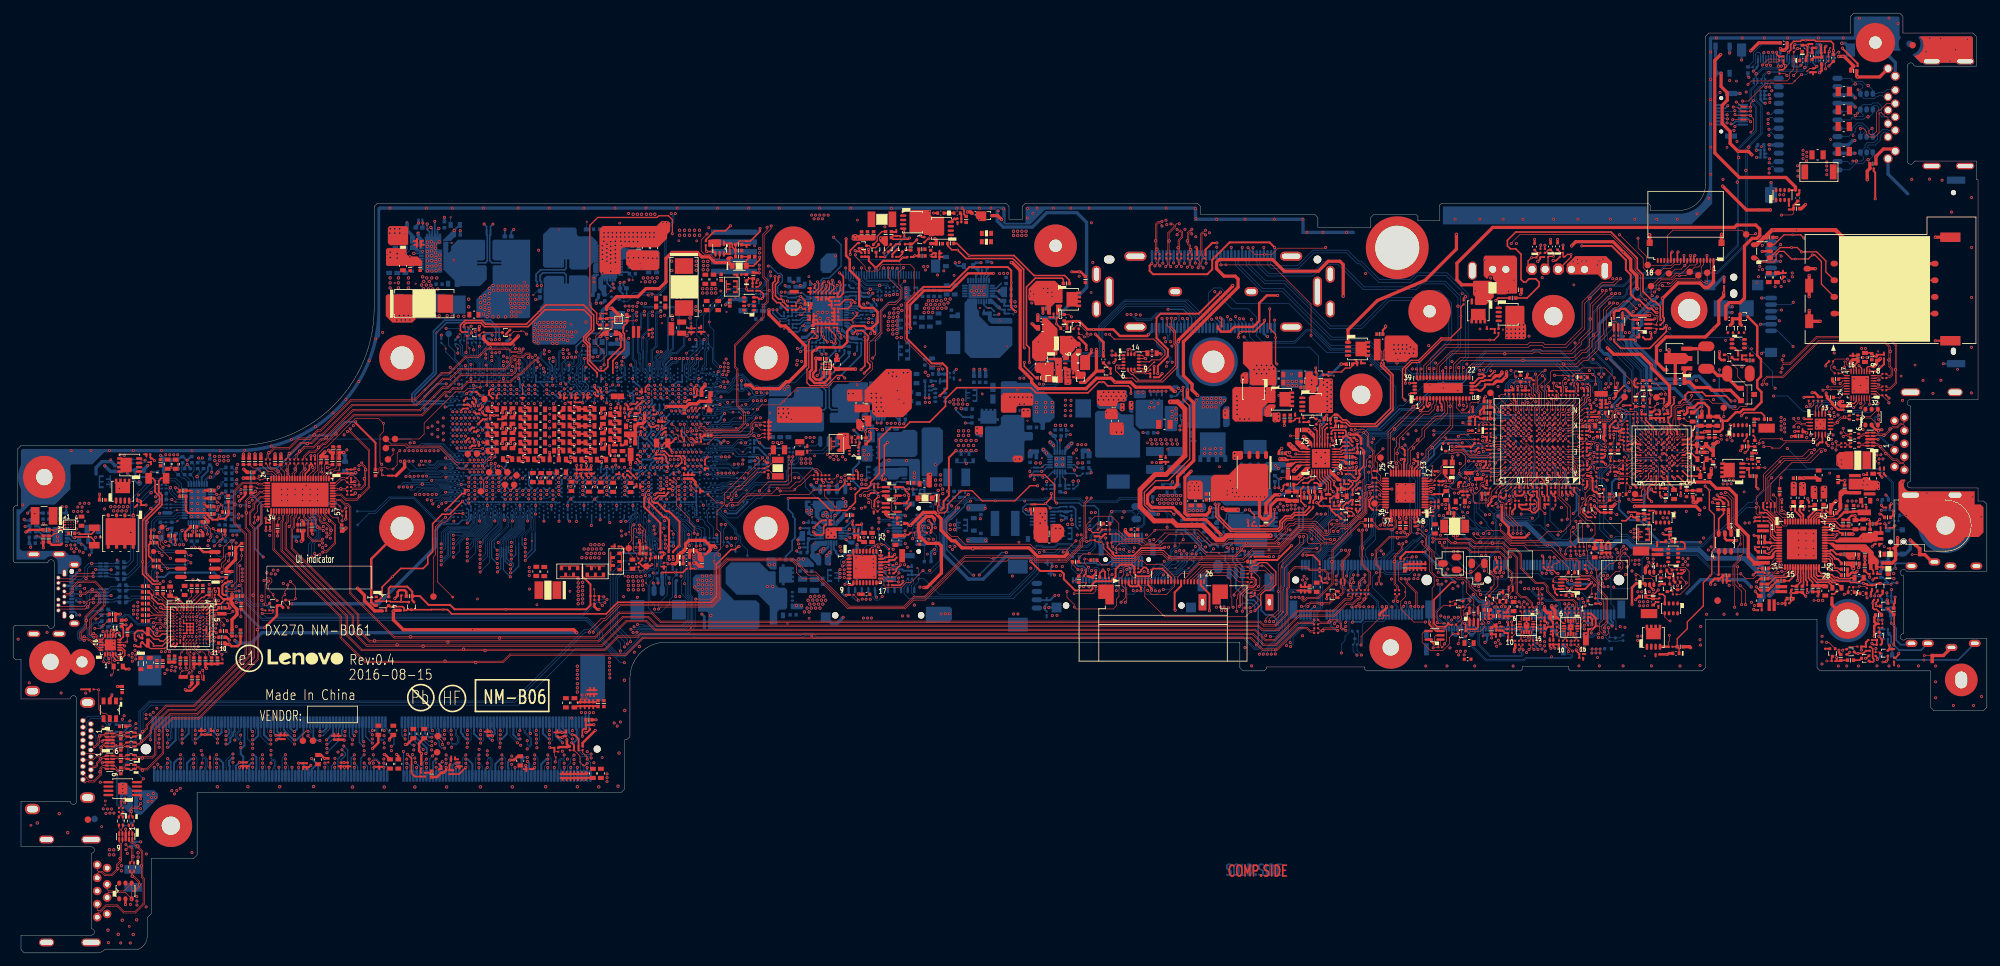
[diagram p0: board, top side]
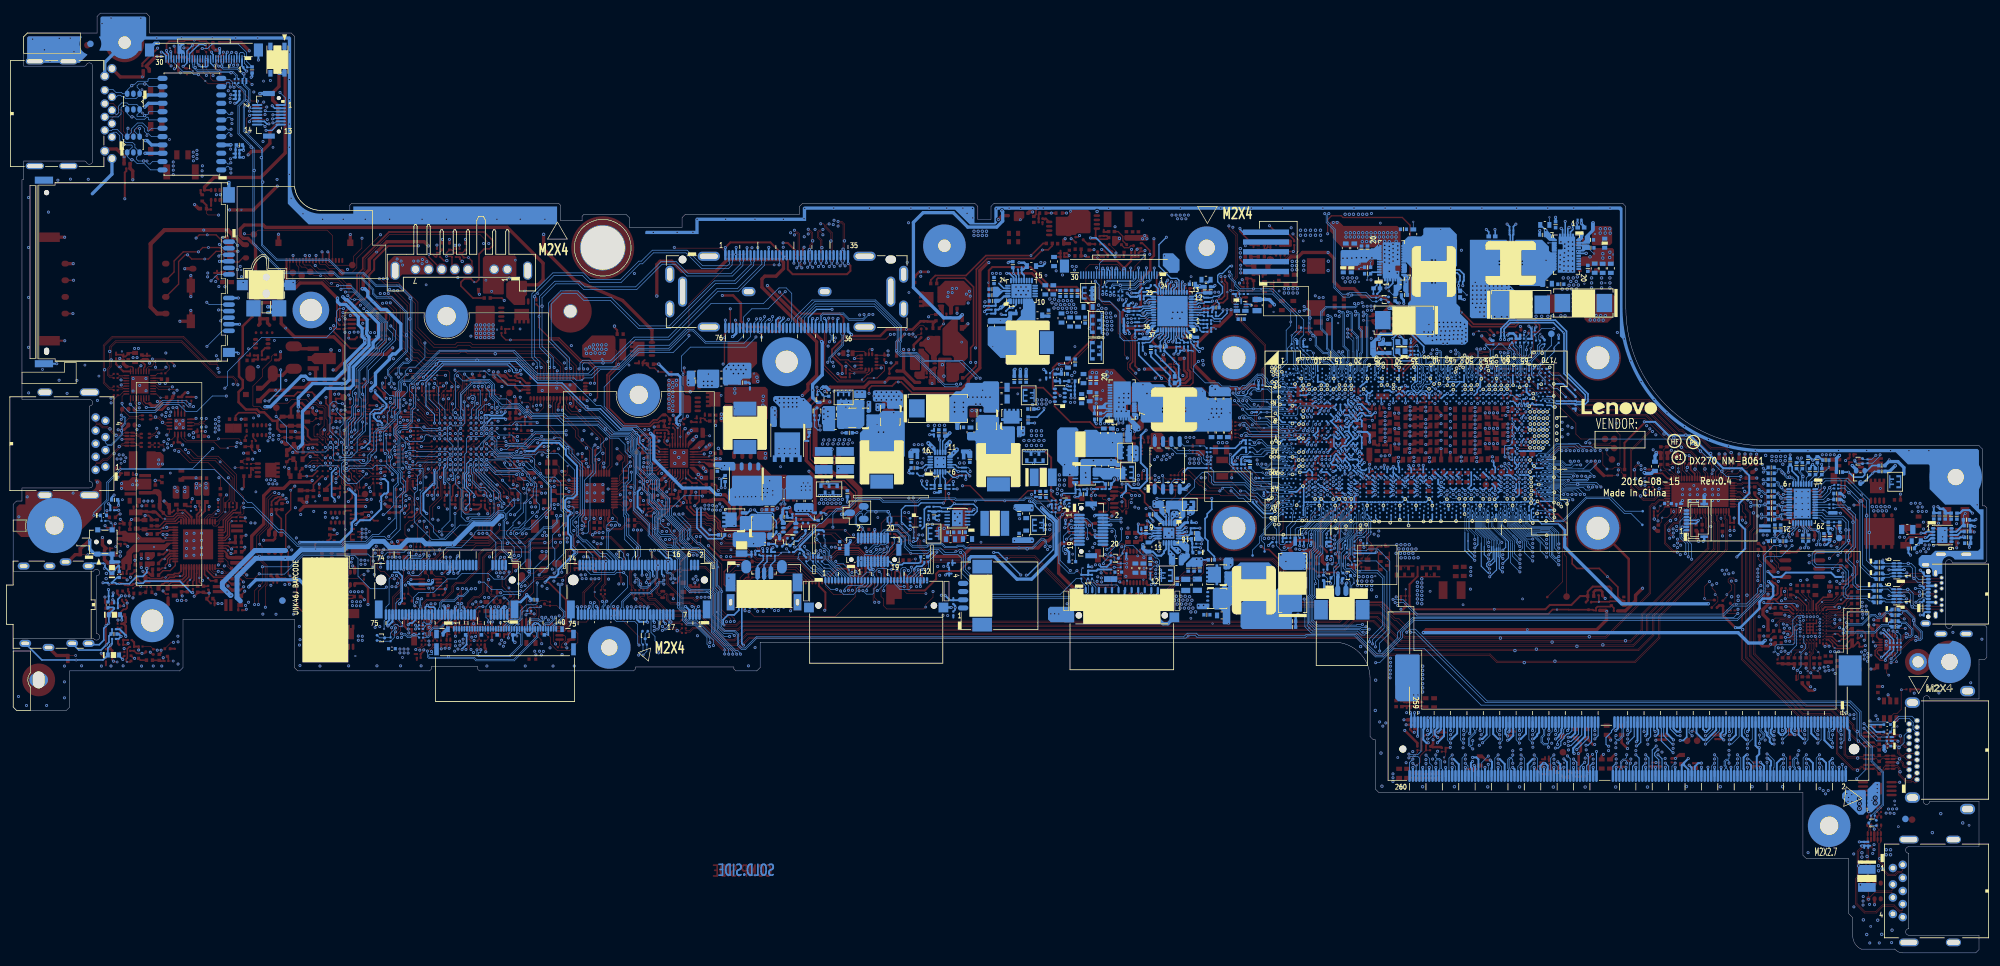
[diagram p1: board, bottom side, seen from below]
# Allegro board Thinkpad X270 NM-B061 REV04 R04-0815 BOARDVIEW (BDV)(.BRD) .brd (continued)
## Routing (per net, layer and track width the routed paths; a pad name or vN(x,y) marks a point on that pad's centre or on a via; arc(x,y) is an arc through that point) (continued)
SD_MMC_D1: length 31.8
  TOP w0.102: v1(279.23,89.37) 279.23,90.22 v4(279.25,90.24) 279.48,90.24 279.58,90.14 279.58,89.81 279.92,89.47 280.3,89.47 280.65,89.12 U15.15
  IN4 w0.076: v1(269.3,96.45) 269.66,96.45 271.79,94.32 271.79,90.02 273.02,88.8 273.4,88.8 273.52,88.68 273.52,87.79 273.62,87.69 273.82,87.69 273.92,87.79 273.92,88.68 274.02,88.79 274.23,88.79 274.33,88.68 274.33,87.79 274.43,87.69 274.63,87.69 274.74,87.79 274.74,88.68 274.84,88.79 275.04,88.79 275.14,88.68 275.14,87.79 275.24,87.69 275.45,87.69 275.55,87.79 275.55,88.68 275.65,88.79 276.11,88.79 276.39,88.51 276.71,88.51 276.81,88.4 276.81,87.79 276.91,87.69 277.12,87.69 277.22,87.79 277.22,88.4 277.32,88.51 277.52,88.51 277.63,88.4 277.63,87.79 277.73,87.69 277.93,87.69 278.03,87.79 278.03,88.4 278.13,88.51 278.34,88.51 278.44,88.4 278.44,87.79 278.54,87.69 278.74,87.69 278.84,87.79 278.84,88.4 278.95,88.51 279.43,88.51 279.49,88.56 279.49,89.27 279.38,89.37 v1(279.23,89.37)
  BOTTOM w0.102: v1(269.3,96.45) 268.82,96.93 J23.8
SD_MMC_D2: length 33.2
  TOP w0.102: v1(275.95,85.86) 276.06,85.97 v4(277.15,85.97) 278.72,85.97 279.26,86.5 U15.21
  IN4 w0.076: v1(275.95,85.86) 275.78,86.04 272.75,86.04 270.39,88.4 270.39,91.93 267.47,94.86 267.47,107.25 266.76,107.96 v1(266.71,107.96)
  BOTTOM w0.102: v1(266.71,107.96) 267.28,108.53 J23.9
SD_MMC_D3: length 33.1
  TOP w0.102: v1(276.67,86.37) 278.67,86.37 279.2,86.9 U15.20
  IN4 w0.076: v1(276.67,86.37) 273.08,86.37 270.7,88.76 270.7,92.16 267.83,95.03 267.83,106.44 v1(269.5,108.11)
  BOTTOM w0.102: J23.1 268.92,107.53 v1(269.5,108.11)
SD_MMC_WP: length 22.6
  TOP w0.102: U15.29 281.85,83.97 v1(281.72,83.85)
  IN4 w0.076: v1(281.72,83.85) 280.58,83.85 280.04,84.4 280.04,86.73 279.46,87.31 273.21,87.31 271.33,89.19 271.33,92.48 v1(271.4,92.55)
  BOTTOM w0.102: v1(271.4,92.55) 269.02,94.93 J23.12
SENSE0: length 79.1
  TOP w0.102: U16.N13 v1(227.15,83.25)
  IN3 w0.081: v1(177.17,62.11) 179.79,62.11 180.1,62.42 180.45,62.42 180.71,62.16 180.71,61.52 181.48,60.75 190.02,60.75 190.72,61.45 192.47,61.45 193.15,60.77 195.59,60.77 196.27,61.45 197.6,61.45 198.54,60.51 204.23,60.51 206.07,62.36 209.93,62.36 210.88,61.4 212.61,61.4 215.17,63.97 215.6,63.97 217.36,65.72 219.87,65.72 220.74,66.59 220.74,68.13 221.52,68.92 221.52,71.67 222.31,72.45 222.31,75.91 222.13,76.09 222.13,77.13 223.22,78.22 223.22,80.81 225.67,83.25 v1(227.15,83.25)
  BOTTOM w0.102: R213.1 177.33,63.31 177.15,63.13 177.15,62.13 v1(177.17,62.11) 176.44,61.38 176.44,60.64 v3(176.26,60.46) 176.23,60.44 176.23,59.89 175.46,59.12 175.03,59.12 173.1,57.19 J38.9
SENSE1: length 85.9
  TOP w0.102: v1(233.51,80.85) 233.51,80.05 U16.J6
  IN3 w0.081: v1(177.88,61.43) 177.65,61.66 177.11,61.66 176.87,61.43 176.87,61.05 178.04,59.88 193.99,59.88 193.99,59.89 197.82,59.89 198.1,59.6 211.67,59.6 211.92,59.85 215.91,59.85 217.08,61.02 217.08,62.83 217.33,63.08 218.12,63.08 219.67,64.63 221.01,64.63 223.3,66.92 223.3,69.33 223.88,69.91 224.29,69.91 225.56,71.18 225.56,73.4 224.7,74.27 224.7,74.61 225.09,75.01 225.09,79.69 225.91,80.5 226.93,80.5 226.96,80.48 228.99,80.48 229.14,80.63 229.14,81.78 229.39,82.03 231.52,82.03 232.32,81.24 232.86,81.24 233.26,80.83 233.49,80.83 v1(233.51,80.85)
  BOTTOM w0.102: J38.6 174.6,57.53 175.16,58.09 175.47,58.09 176.66,59.28 177.19,59.28 R215.1 177.57,59.74 177.3,60.01 177.3,60.65 177.73,61.07 177.73,61.31 177.85,61.43 v1(177.88,61.43)
SENSE2: length 85.4
  TOP w0.102: v1(231.61,83.48) 231.53,83.4 U16.N8
  IN3 w0.081: v1(231.61,83.48) 230.79,83.48 230.59,83.68 230.59,84.06 229.85,84.8 228.33,84.8 227.39,83.86 224.24,83.86 222.44,82.05 222.44,77.94 221.27,76.77 221.27,72.91 221.04,72.68 221.04,69.38 219.29,67.63 219.29,67.14 218.3,66.15 214.56,66.15 213.67,65.26 213.67,62.98 212.45,61.76 211.13,61.76 210.18,62.71 205.95,62.71 204.11,60.87 198.74,60.87 197.82,61.79 196.08,61.79 195.41,61.12 193.46,61.12 192.8,61.79 187.62,61.79 186.95,61.12 183.75,61.12 183.65,61.23 181.49,61.23 181.06,61.66 181.06,62.37 180.37,63.06 v1(178.41,63.06)
  BOTTOM w0.102: R214.1 178.41,63.66 v1(178.41,63.06) 177.8,62.45 177.8,62.06 177.42,61.67 177.15,61.67 176.68,61.2 176.68,60.05 175.5,58.86 175.23,58.86 173.6,57.23 J38.8
SENSE3: length 92.5
  TOP w0.102: U16.J11 v1(228.75,80.05)
  IN3 w0.081: v1(175.37,55.46) 177.56,57.65 193.14,57.65 195.33,55.46 197.65,55.46 198.56,54.55 217.5,54.55 219.18,56.23 219.18,56.95 219.55,57.33 219.55,58.01 220.43,58.89 221.12,58.89 222.78,60.55 222.78,61.46 222.98,61.66 225.21,61.66 230.56,67.01 230.56,67.99 232.52,69.96 232.52,72.61 233.18,73.27 233.61,73.27 233.89,73.54 233.89,76.25 233.66,76.48 230.96,76.48 230.72,76.72 230.72,77.2 229.93,77.99 229.93,79.41 229.68,79.66 229.14,79.66 v1(228.75,80.05)
  BOTTOM w0.102: R219.1 181.24,60.77 v4(181.24,60.18) 179.25,58.2 178.39,58.2 177.66,57.47 177.26,57.47 177.1,57.31 J38.1 177.1,56.28 176.29,55.46 v1(175.37,55.46)
SENSE4: length 86.5
  TOP w0.102: U16.J12 v1(227.95,80.05)
  IN3 w0.081: v1(175.37,57.67) 175.51,57.81 193.46,57.81 195.56,55.71 197.77,55.71 198.69,54.8 217.45,54.8 219,56.35 219,57.05 219.38,57.43 219.38,58.22 220.27,59.11 221.05,59.11 222.53,60.58 222.53,61.56 222.87,61.91 225.21,61.91 229.95,66.65 v1(229.95,66.97)
  BOTTOM w0.102: R216.1 177.74,59.21 177.74,59.2 v4(177.24,58.7) 176.4,58.7 v1(175.37,57.67) 175.1,57.4 J38.5 ; v1(227.95,80.05) 228.17,80.05 228.56,79.67 228.96,79.67 229.14,79.49 229.14,79.06 229.37,78.83 231.5,78.83 231.83,78.5 231.83,76.37 232.09,76.11 232.09,73.42 232.37,73.14 232.37,67.32 232.01,66.97 v1(229.95,66.97)
SENSE5: length 86
  TOP w0.102: R212.1 167.07,57.72 167.01,57.78 v1(167.01,58.51) ; U16.J13 v1(227.15,80.05)
  IN3 w0.081: v1(227.15,80.05) 226.66,80.05 226.09,79.49 225.51,79.49 225.35,79.32 225.35,74.83 225.92,74.26 225.92,70.95 224.98,70.01 224.98,68.82 223.81,67.65 223.81,66.92 221.33,64.44 221.33,63.47 219.91,62.06 218.72,62.06 216.14,59.47 212.15,59.47 211.87,59.19 197.98,59.19 197.66,59.51 177.85,59.51 176.65,60.71 172.82,60.71 170.21,58.1 169.69,58.1 169.19,57.59 168.44,57.59 167.52,58.51 v1(167.01,58.51)
  BOTTOM w0.102: v1(167.01,58.51) 167.65,58.51 167.8,58.66 169.07,58.66 169.63,58.1 170.8,58.1 171.6,57.3 J38.12
SENSE6: length 76.7
  TOP w0.102: U16.M12 v1(227.95,82.45)
  IN3 w0.081: v1(180.27,62.01) 180.27,61.57 181.25,60.59 190.15,60.59 190.85,61.29 192.39,61.29 193.09,60.59 195.67,60.59 196.37,61.29 197.51,61.29 198.47,60.32 204.34,60.32 206.18,62.17 209.84,62.17 210.8,61.2 212.71,61.2 215.15,63.64 215.63,63.64 217.51,65.52 220.74,65.52 222.54,67.32 222.54,69.61 223.58,70.65 223.58,70.98 223.48,71.08 223.48,71.54 222.49,72.53 222.49,76.06 222.31,76.24 222.31,77.05 223.43,78.17 223.43,80.75 225.7,83.02 226.68,83.02 226.89,82.81 227.59,82.81 v1(227.95,82.45)
  BOTTOM w0.102: J38.3 176.1,57.26 176.81,57.97 177.37,57.97 178.11,58.71 178.3,58.71 178.98,59.38 R217.1 179.09,59.74 179.36,60.01 179.36,61.1 179.69,61.43 v4(179.92,61.43) 180.27,61.78 v1(180.27,62.01)
SENSE7: length 74.9
  TOP w0.102: U16.M13 v1(227.15,82.45)
  IN3 w0.081: v1(179.77,60.9) 179.77,60.47 179.82,60.42 190.34,60.42 191.05,61.13 192.18,61.13 192.9,60.41 195.81,60.41 196.53,61.13 197.41,61.13 198.4,60.14 204.55,60.14 206.37,61.96 209.79,61.96 210.73,61.02 213.79,61.02 215.64,62.87 215.64,63.34 217.56,65.26 220.74,65.26 222.74,67.27 222.74,69.53 223.76,70.55 223.76,71.06 223.68,71.13 223.68,71.87 222.67,72.88 222.67,76.14 222.49,76.31 222.49,76.92 223.64,78.07 223.64,80.72 224.92,82 226.7,82 v1(227.15,82.45)
  BOTTOM w0.102: v1(179.77,60.9) 179.59,60.72 179.59,59.96 179.79,59.75 R218.1 180.02,59.49 179.28,58.75 v4(179.24,58.75) 178.95,58.45 178.2,58.45 177.5,57.75 177.04,57.75 176.6,57.31 J38.2
SENSEN: length 32.6
  TOP w0.076: v1(30.08,47.57) 30.08,47.67 29.97,47.77 U5.A10
  TOP w0.254: v1(21.97,56.76) 21.46,56.76 v3(20.52,57.7) 20.27,57.95 20.27,65.96 22.71,68.39 22.71,69.84 22.21,70.34 PR92.1
  IN1 w0.076: v1(21.97,56.76) 21.97,54.75 24.49,52.24 24.49,48.22 25.32,47.39 28.68,47.39 29.21,47.92 29.72,47.92 v1(30.08,47.57)
SENSEP: length 34.8
  TOP w0.076: v1(30.66,47.57) 30.21,48.02 29.27,48.02 29.02,47.77 U5.B10
  TOP w0.254: v1(22.4,56.35) 22.33,56.28 21.29,56.28 19.75,57.82 v3(19.75,59.71) 19.75,66.02 22.33,68.6 22.33,69.66 21.65,70.34 PR91.1
  IN1 w0.076: v1(22.4,56.35) 22.4,54.86 24.69,52.57 24.69,48.63 25.5,47.82 28.5,47.82 28.91,48.23 30,48.23 v1(30.66,47.57)
SLEEVE:
  vias: v4(281.84,63.24)
SM_RCOMP0: length 10.8
  TOP w0.152: v1(96.91,70.55) 96.8,70.55 v4(96.47,70.22) 96.43,70.18 96.43,69.58
  TOP w0.305: 96.43,69.58 96.22,69.38 96.22,68.06 98.69,65.59 RC11.1
  BOTTOM w0.305: U1.AR18 97.34,70.89 v1(96.91,70.55)
SM_RCOMP1: length 12.4
  TOP w0.152: 97.45,68.95 97.34,69.05 97.34,69.48 v1(96.91,69.91)
  TOP w0.305: 97.45,68.95 97.72,68.67 98.26,68.67 99.53,67.4 100.01,67.4 101.61,65.8 v4(101.61,62.04) 101.43,62.04 100.64,61.26 RC12.1
  BOTTOM w0.305: v1(96.91,69.91) 97.34,70.24 U1.AT18
SM_RCOMP2: length 10.3
  TOP w0.305: v1(96.91,69.28) 96.91,68.79 99.22,66.48 99.55,66.48 100.01,66.03 100.01,62.21 99.89,62.09 99.86,62.09 99.86,62.09 v4(99.87,62.08) 99.96,61.99 RC13.1
  BOTTOM w0.305: U1.AU18 97.34,69.6 v1(96.91,69.28)
SMB_CLK: length 199
  TOP w0.102: v1(104.24,80.69) 104.61,80.31 105.42,80.31 105.81,79.92 110.47,79.92 111.38,80.83 111.38,82.42 110.32,83.48 110.32,88.99 109.97,89.34 109.97,92.77 114.31,97.12 114.31,98.83 114.91,99.43 114.91,102.46 114.31,103.06 114.31,109.66 114.97,110.32 v1(114.97,110.73) ; U19.2 250.09,95.98 250.23,95.84 R251.1 250.58,96.15 250.76,96.33 250.76,97.1 v4(250.73,97.13) 250.63,97.23 250.24,97.23 249.72,97.75 249.08,97.75 v1(247.99,98.84)
  IN3 w0.081: v1(114.97,110.73) 114.97,111.04 115.27,111.34 130.61,111.34 131.44,112.17 138.3,112.17 140.7,109.77 142.68,109.77 144.18,108.27 151.89,108.27 155.89,104.27 160.65,104.27 164.88,108.49 174.76,108.49 176.87,106.39 182.4,106.39 183.08,105.7 183.08,103.55 185.4,101.24 186.82,101.24 193.39,107.81 197.16,107.81 197.82,107.15 200.19,107.15 206.66,100.67 217.59,100.67 219.14,102.22 228.23,102.22 228.58,102.58 238.21,102.58 242.33,98.46 246.41,98.46 246.8,98.84 v1(247.99,98.84)
  BOTTOM w0.076: U1.R7 104.06,80.98 v1(104.24,80.69)
SMB_CLK_3B: length 286
  TOP w0.102: U19.1 250.45,95.33 R249.1 250.58,94.93 v1(250.35,94.7) ; v1(196.17,63.52) 196.17,62.55 192.9,59.27 v3(192.9,55.14) 192.9,52.34 192.12,51.56 191.56,51.56 190.99,50.99 v1(190.99,50.59)
  IN3 w0.081: v1(190.99,50.59) 188.69,48.29 95.6,48.29 92.36,45.05 92.36,41.93 90.71,40.28 90.71,31.55 89.41,30.24 88.23,30.24 v1(88.13,30.34)
  IN4 w0.076: v1(170.78,61.24) 170.54,61.48 170.54,62.21 172.62,64.3 174.61,64.3 175.06,63.85 183.08,63.85 183.52,63.41 187.72,63.41 188.4,64.1 193.15,64.1 193.65,63.6 196.1,63.6 v1(196.17,63.52) 196.57,63.13 196.91,63.13 197.67,63.89 198.59,63.89 200.9,61.58 200.9,61.05 202.22,59.73 221.45,59.73 225.05,63.33 226.45,63.33 228.05,64.93 231.55,64.93 231.98,64.51 237.11,64.51 237.36,64.26 238.88,64.26 239.68,65.06 239.68,65.25 239.94,65.51 241.22,65.51 241.6,65.13 246.2,65.13 246.92,65.85 249.21,65.85 249.93,65.13 253.73,65.13 256.75,68.14 256.75,69.19 258.57,71.01 262.84,71.01 267.7,75.87 267.7,83.12 257.79,93.03 252.03,93.03 v1(250.35,94.7)
  BOTTOM w0.102: v1(88.13,30.34) 88.03,30.24 86.79,30.24 86.28,30.75 J21.253 ; v1(170.78,61.24) 169.75,62.27 169.17,62.27 169.1,62.34 J16.14
SMB_DATA: length 202.4
  TOP w0.102: v1(115.58,110.93) 115.58,110.53 114.51,109.46 114.51,103.21 115.12,102.6 115.12,99.31 114.51,98.7 114.51,97.02 110.17,92.67 110.17,89.45 110.52,89.09 110.52,83.58 111.63,82.47 111.63,80.79 110.57,79.72 105.65,79.72 105.27,80.1 104.23,80.1 103.64,80.69 v1(103.6,80.69) ; v1(247.48,98.31) 246.34,99.45 v4(246.06,99.45) 245.58,99.45 244.64,98.51 244.26,98.51 243.54,97.8 243.54,96.63 243.82,96.35 244.33,96.35 244.74,95.95 U20.2 R252.1
  IN3 w0.081: v1(247.48,98.31) 247.41,98.39 246.87,98.39 246.69,98.21 242.22,98.21 238.05,102.37 228.71,102.37 228.3,101.97 219.27,101.97 217.78,100.47 206.51,100.47 200.11,106.87 197.52,106.87 196.83,107.56 193.52,107.56 186.84,100.88 185.35,100.88 182.78,103.45 182.78,105.63 182.19,106.22 176.63,106.22 174.61,108.24 164.99,108.24 160.76,104.01 155.91,104.01 151.91,108.02 144.15,108.02 142.63,109.54 140.55,109.54 138.21,111.87 131.6,111.87 130.76,111.04 115.69,111.04 v1(115.58,110.93)
  BOTTOM w0.076: v1(103.6,80.69) U1.R8
SMB_DATA_3B: length 291.2
  TOP w0.102: v1(191.57,50.55) 191.57,50.99 191.87,51.28 192.38,51.28 193.3,52.2 193.3,58.73 v4(193.43,58.86) 193.43,59.2 196.76,62.52 v1(196.76,63.54) ; v1(243.59,93.68) 243.59,93.86 243.92,94.19 R248.1 244.09,94.2 U20.1
  IN3 w0.081: v1(88.13,29.76) 89.24,29.76 90.99,31.51 90.99,40.14 92.54,41.69 92.54,44.87 95.8,48.13 189.15,48.13 v1(191.57,50.55)
  IN4 w0.076: v1(170.18,61.24) 170.18,62.22 172.49,64.53 175.09,64.53 175.29,64.32 193.56,64.32 194.09,63.79 195.54,63.79 195.74,63.99 196.3,63.99 v1(196.76,63.54) 197.26,64.05 198.66,64.05 201.05,61.66 201.05,61.12 202.29,59.88 221.38,59.88 225.01,63.51 226.28,63.51 227.87,65.1 231.8,65.1 232.24,64.66 237.27,64.66 237.41,64.52 238.83,64.52 239.43,65.11 239.43,65.35 239.8,65.73 239.9,65.82 241.31,65.82 241.86,65.28 245.89,65.28 246.62,66 249.36,66 250.09,65.28 253.67,65.28 256.57,68.19 256.57,69.24 258.49,71.16 262.63,71.16 267.37,75.9 267.37,83.17 257.69,92.85 245.96,92.85 245.13,93.68 v1(243.59,93.68)
  BOTTOM w0.102: v1(170.18,61.24) 170.18,61.32 169.49,62.02 169.02,62.02 168.76,62.28 167.94,62.28 167.6,62.62 J16.20 ; J21.254 86.53,29.73 86.78,29.98 87.9,29.98 v1(88.13,29.76)
SML0_CLK: length 122.8
  TOP w0.102: RC25.1 114.13,78.68 113.93,78.47 113.42,78.47 v1(112.96,78.93) ; v1(201.3,64.32) 202.1,65.12 203.54,65.12 205.03,66.61 205.29,66.61 206.02,67.33 206.02,69.71 206.15,69.85 v3(206.15,70.12) 206.15,71.24 206.4,71.49 207,71.49 RL4.1
  IN1 w0.076: v1(201.3,64.32) 200.8,64.32 199.91,65.21 186.04,65.21 185.45,65.8 182.48,65.8 181.39,66.89 178.67,66.89 177.96,67.6 165.49,67.6 165.29,67.8 163.19,67.8 162.94,68.06 158.89,68.06 158.28,68.67 157.6,68.67 157.39,68.46 147.32,68.46 146.16,67.3 145.3,67.3 143.49,69.1 140.98,69.1 140.4,69.68 140.4,70.78 138.16,73.01 138.16,73.55 137.75,73.95 135.09,73.95 134.3,74.74 133.36,74.74 129.93,78.17 119.21,78.17 117.92,79.46 114.77,79.46 113.81,78.51 113.38,78.51 v1(112.96,78.93)
  BOTTOM w0.076: U1.R9 102.77,81.04 102.77,80.43 102.98,80.22 102.98,79.99 103.23,79.75 103.23,79.55 103.48,79.29 105.6,79.29 105.7,79.19 105.7,78.8 105.87,78.64 107.03,78.64 107.2,78.55 107.91,78.55 108.16,78.8
  BOTTOM w0.102: v1(112.96,78.93) 112.84,78.8 108.16,78.8
SML0_DATA: length 115.2
  TOP w0.102: RC26.1 114.18,79.23 113.88,78.93 v1(113.67,78.93) ; RL5.1 206.74,70.6 206.53,70.39 206.53,69.7 206.22,69.39 206.22,67.21 205.42,66.41 205.11,66.41 203.44,64.74 v3(203.13,64.74) 202.4,64.74 v1(201.99,64.32)
  IN1 w0.076: v1(201.99,64.32) 201.58,64.73 200.72,64.73 200.01,65.44 186.17,65.44 185.65,65.96 182.57,65.96 181.46,67.07 178.9,67.07 178.22,67.75 165.59,67.75 165.34,68.01 163.31,68.01 163.08,68.24 158.96,68.24 158.38,68.82 157.51,68.82 157.31,68.62 147.13,68.62 145.96,67.45 145.42,67.45 143.52,69.35 141,69.35 140.55,69.81 140.55,70.9 138.34,73.11 138.34,73.62 137.83,74.13 135.19,74.13 130.9,78.42 123.4,78.42 122.78,79.04 118.69,79.04 118.02,79.72 114.46,79.72 v1(113.67,78.93)
  BOTTOM w0.076: 108.17,79.09 107.8,78.72 107.24,78.72 106.99,78.84 106.98,78.84 106.84,78.98 U1.W2
  BOTTOM w0.102: 108.17,79.09 112.52,79.09 112.83,79.39 113.21,79.39 v1(113.67,78.93)
SP_OUTL+: length 136.5
  IN1 w0.762: 276.21,72.2 276.21,72.63 273.92,74.92 266.83,74.92 254.39,62.48 253.92,62.48 250.94,59.5 250.94,57.61 249.58,56.25 247.14,56.25 245.13,54.24 241.81,54.24 238.23,57.82 237.45,57.82 236,59.28 232.84,59.28 231.88,58.31 229.06,58.31 228.09,59.28 224.04,59.28 222.94,58.17 222.94,57.29 220.24,54.6 215.35,54.6 214.05,55.9 209.44,55.9 208.93,55.39 200.44,55.39 199.22,54.17 197.89,54.17 196.7,55.36 194.83,55.36 193.38,56.81 185.58,56.81 184.41,57.97 177.02,57.97 175.3,56.25 169.62,56.25 168.89,56.98 162.57,56.98 161.53,58.03
  BOTTOM w0.254: 157.72,59.93 CA53.2 157.29,59.5
  BOTTOM w0.305: 157.72,59.17 CA53.2
  vias: v1(159.06,58.99) v1(159.98,58.97) v2(275.95,70.45) v2(276.29,71.03) v4(159.49,59.96)
SP_OUTL+_AUDIO: length 3.6
  TOP w0.254: 273.75,66.49 UA1.47 ; 274.76,67.5 274.82,67.56 275.79,67.56 CA122.1
  TOP w0.305: 274.76,67.5 274.74,67.5 273.75,66.52 273.75,66.49 ; CA122.1 275.84,67.83
SP_OUTL-: length 137.1
  IN1 w0.762: 274.6,72.15 274.6,72.43 273.36,73.67 267.03,73.67 256.17,62.81 256.17,57.15 253.26,54.25 251.79,54.25 249.71,52.16 241.79,52.16 240.57,53.38 240.57,53.89 239.45,55.01 238.27,55.01 237.7,54.44 230.18,54.44 228.94,55.69 226.09,55.69 223.97,53.56 214.48,53.56 213.52,54.53 210.05,54.53 209.82,54.3 201.73,54.3 199.54,52.11 195.69,52.11 192.29,55.51 184.9,55.51 183.7,56.7 177.86,56.7 175.52,54.37 167.93,54.37 167.29,55 162.29,55 160.38,56.91
  BOTTOM w0.254: 157.84,57.87 157.86,57.89 CA54.2 158.57,57.89 v1(158.78,57.67)
  BOTTOM w0.305: 158.23,57.54 CA54.2
  vias: v1(159.67,57.62) v2(274.77,71.03) v2(274.77,70.4)
SP_OUTL-_AUDIO: length 1
  TOP w0.254: LA13.1 274.47,68.13 CA127.1
  vias: v4(273.85,67.45)
SP_OUTR+: length 161.8
  TOP w0.102: v2(271.54,70.97) 271.48,70.92 LA12.2
  IN1 w0.762: 270.38,71.29 267.43,71.29 267,70.86 267,69.95 268.91,68.04 268.91,67 268.12,66.21 267.01,66.21 265.99,67.23 265.23,67.23 264.47,67.99 263.83,67.99 257.35,61.51 257.35,60.14 257.79,59.71 258.57,59.71 259.18,59.1 259.18,57.9 260.33,56.76 260.33,55.82 259.82,55.31 258.62,55.31 257.71,56.23 256.9,56.23 254.95,54.28 254.95,53.37 253.8,52.21 251.82,52.21 250.96,51.35 250.96,49.7 250.39,49.14 247.93,49.14 247.4,49.67 247.4,50.64 247.07,50.97 241.23,50.97 240.18,52.01 238.53,52.01 237.03,50.51 236.24,50.51 234.77,51.99 233.83,51.99 232.67,50.82 231.34,50.82 230.23,51.93 226.37,51.93 225.86,51.43 225.86,49.62 225.05,48.81 223.19,48.81 222.56,49.45 222.56,50.21 223.67,51.33 223.67,52.01 223.14,52.54 216.94,52.54 216.26,51.86 203.94,51.86 203.33,52.47 203.33,52.9 203,53.23 202.13,53.23 200.94,52.04 200.94,51.15 200.38,50.58 195.38,50.58 193.96,52.01 192.91,52.01 192.38,51.47 190.74,51.47 190.2,52.01 190.2,52.77 189.42,53.56 187.94,53.56 187.77,53.73 183.67,53.73 183.29,54.12 183.29,54.93 182.58,55.64 178.49,55.64 175.49,52.64 174.5,52.64 173.86,53.28 170.92,53.28 170.28,52.64 168.08,52.64 166.9,53.81 165.86,53.81 165.51,53.46 165.51,52.82 165,52.32 163.88,52.32 163.27,52.93 163.27,53.48 162.87,53.89 161.82,53.89 161.39,54.32 160.3,54.32
  BOTTOM w0.305: J4.2 156.16,53.82 CA55.2 ; CA55.2 158.11,53.82 v1(158.84,54.55) ; CA55.2 157.59,54.17
  vias: v1(159.42,54.57) v2(271.54,71.6)
SP_OUTR+_AUDIO: length 3.4
  TOP w0.254: 272.5,66.64 272.55,66.58 UA1.50
  TOP w0.305: 272.5,66.64 271.7,67.44 CA243.1 271.7,68.59 LA12.1
SP_OUTR-: length 161.2
  IN1 w0.762: 159.98,51.24 189.11,51.24 191.04,49.32 192.25,49.32 193.24,50.31 194.11,50.31 195.12,49.29 200.51,49.29 202.36,47.44 204.78,47.44 206.3,48.96 206.3,50.03 206.86,50.59 213.56,50.59 214.28,49.88 214.28,48.58 214.92,47.94 216.43,47.94 217.04,48.56 217.04,49.19 217.83,49.98 219.13,49.98 219.69,49.42 219.69,48.3 220.07,47.92 222.2,47.92 222.7,47.43 222.7,46.36 223.06,45.99 227.38,45.99 228.7,47.31 228.7,48.89 229.26,49.44 236.36,49.44 237.11,48.68 239.73,48.68 241.15,47.26 243.18,47.26 243.54,47.62 243.54,48.56 243.87,48.89 245.77,48.89 246.2,48.45 246.2,46.63 246.71,46.12 251.39,46.12 252.68,47.41 252.68,48.84 252.25,49.27 252.25,50.08 253.19,51.02 254.63,51.02 256.08,52.47 256.08,53.79 256.88,54.58 257.6,54.58 258.45,53.74 260.66,53.74 262.89,55.97 262.89,57.27 262.43,57.73 260.91,57.73 260.36,58.28 260.36,59.36 261.01,60.01 262.33,60.01 262.89,60.57 262.89,61.71 262.31,62.3 261.22,62.3 260.76,62.76 260.76,63.39 262.21,64.84 273.31,64.84 273.87,65.4 273.87,66.74 273.46,67.15 272.34,67.15 271.86,67.63 271.86,69.21 272.77,70.12
  BOTTOM w0.305: 157.59,51.17 CA56.2
  vias: v1(158.45,51.47) v1(159.17,51.5) v2(273,71.6) v2(273,70.97) v3(272.47,71.31)
SP_OUTR-_AUDIO: length 3.3
  TOP w0.254: 272.95,66.58 UA1.49
  TOP w0.305: 272.95,66.58 272.95,66.84 272.4,67.4 CA117.1 272.4,67.98 272.58,68.16 272.58,68.68 LA11.1
SPI_CLK: length 50.2
  TOP w0.102: R241.1 134.52,57.34 135.06,57.89 v1(135.06,58) ; v1(113.8,70.5) 113.8,70.55 115.15,71.9 117.83,71.9 118.16,72.23 118.16,75.57 v1(118.3,75.7)
  IN1 w0.076: v1(129.9,68.03) 129.6,68.34 129.44,68.34 127,70.78 126.16,70.78 125.76,71.19 125.76,72.18 125.1,72.84 121.31,72.84 119.53,74.62 119.53,75.73 119.1,76.17 118.7,76.17 118.3,75.77 v1(118.3,75.7)
  IN4 w0.076: v1(129.9,68.03) 129.9,67.93 130.07,67.76 130.35,67.76 131.61,66.51 131.61,65.57 132.01,65.16 132.17,65.16 132.39,64.94 132.39,63.14 132.75,62.77 132.75,61.61 132.46,61.32 132.46,58.72 133.21,57.97 135.04,57.97 v1(135.06,58)
  BOTTOM w0.076: U1.AV2 106.89,69.01 107.13,69.25 108.32,69.25 109.25,68.32
  BOTTOM w0.102: RC129.1 118.36,75.65 118.31,75.7 v1(118.3,75.7) ; v1(113.8,70.5) 113.05,70.5 112.24,69.69 111.46,69.69 110.85,69.08 110.85,68.9 109.83,67.88 109.48,67.88 109.25,68.11 109.25,68.32
SPI_CLK_2_R: length 1.5
  TOP w0.102: R241.2 133.44,57.4 132.69,58.14 U26.19
SPI_CLK_LFT: length 16.1
  TOP w0.102: v1(33.53,52.14) 33.14,51.75 R441.1 ; U186.6 26.73,59.91 v1(27.1,59.53)
  IN1 w0.076: v1(27.1,59.53) 27.48,59.91 30.72,59.91 32.45,58.18 32.45,52.61 32.92,52.14 v1(33.53,52.14)
SPI_CLK_LFT_R: length 2.3
  TOP w0.076: 30.93,51.98 30.29,51.98 29.58,51.27 29.49,51.27 U5.A3
  TOP w0.102: 30.93,51.98 31.15,51.98 R441.2
SPI_CLK_R: length 7.1
  BOTTOM w0.102: UC5.6 124.34,77.67 123.34,76.67 v4(121.59,76.67) 120.16,76.67 119.41,75.91 119.41,75.4 119.17,75.17 RC129.2
SPI_CS#_LFT: length 11
  TOP w0.076: v3(28.55,51.12) 28.7,51.27 U5.B3
  TOP w0.102: U186.1 32.4,57.37 R715.2 31.91,56.69 v1(31.8,56.69)
  IN1 w0.076: v3(28.55,51.12) 28.55,51.2 29.54,52.18 30.97,52.18 31.8,53.01 v1(31.8,56.69)
SPI_IO2: length 18.7
  TOP w0.102: v1(116.95,70.5) 118.97,70.5 v3(119.2,70.73) 119.83,71.36 120.05,71.36 121.59,72.9 RC131.2
  BOTTOM w0.076: U1.AW2 106.81,68.54 107.47,68.54 108.21,67.8
  BOTTOM w0.102: v1(116.95,70.5) 116.9,70.55 116.85,70.55 116.39,71.01 115.02,71.01 113.88,69.87 113.18,69.87 112.52,69.21 111.72,69.21 RC151.2 111.37,68.64 110.18,67.45 109.25,67.45 108.9,67.8 108.21,67.8
SPI_IO2_R: length 4.4
  TOP w0.102: v1(122.48,71.77) 122.69,71.98 RC126.1 RC131.1
  BOTTOM w0.102: UC5.3 124.34,71.79 123.91,72.22 122.93,72.22 v1(122.48,71.77)
SPI_IO3: length 15.7
  BOTTOM w0.076: U1.AU4 105.76,70.07 107.96,70.07
  BOTTOM w0.102: RC133.2 117.88,73.52 117.88,71.93 117.69,71.74 113.08,71.74 111.91,70.58 v4(111.84,70.58) 111.51,70.58 111.43,70.65 110.02,70.65 RC150.2 108.19,70.3 107.96,70.07
SPI_IO3_R: length 9.4
  BOTTOM w0.102: RC133.1 RC127.1 119.33,74.57 119.74,74.99 119.74,75.58 v4(120.11,75.94) 120.33,76.17 123.53,76.17 124.3,76.93 125.08,76.93 125.61,77.46 UC5.7
SPI_MISO_IO1: length 21.6
  TOP w0.102: RC132.1 R243.1 RC141.1 123.28,73.24 122.64,73.88 121.93,73.88 119.9,71.84 119.38,71.84 118.47,70.93 116.56,70.93 v3(116.54,70.91) 116.5,70.91 115.64,70.04 111.85,70.04 110.55,68.74 109.33,68.74 v1(108.82,68.23)
  BOTTOM w0.076: U1.AW3 106.34,68.72 107.53,68.72 108.04,68.21 108.79,68.21 v1(108.82,68.23)
SPI_MISO_IO1_2_R: length 16.6
  TOP w0.102: U26.24 132.27,61.6 v1(131.9,61.97) ; R243.2 123.86,72.07 124.14,71.79 124.81,71.79 v1(124.84,71.82)
  IN1 w0.076: v1(128.2,67.8) 128.2,68.26 126.7,69.76 125.63,69.76 124.79,70.6 124.79,71.77 v1(124.84,71.82)
  IN4 w0.076: v1(131.9,61.97) 131.44,62.43 131.44,63.57 131.1,63.91 130.87,63.91 130.26,64.52 130.26,64.75 130.15,64.86 130.15,65.77 129.66,66.26 129.42,66.26 128.2,67.47 v1(128.2,67.8)
SPI_MISO_IO1_R: length 3.6
  TOP w0.102: RC132.2 125.21,72.31 125.71,72.81 v1(125.71,72.84)
  BOTTOM w0.102: v1(125.71,72.84) 125.71,72.81 125.61,72.72 UC5.2
SPI_MISO_LFT: length 16.2
  TOP w0.076: U5.A4 29.9,50.77 30.12,50.99 30.34,50.99 30.77,51.42 30.77,51.52 v1(30.79,51.55)
  TOP w0.102: U186.2 31.57,58.64 31.75,58.82 31.75,59.35 32.39,59.99 32.39,60.72 32.56,60.9 R714.2 33,59.99 v3(32.82,59.81) 32.03,59.02 32.03,58.27 v1(31.84,58.08)
  IN1 w0.076: v1(30.79,51.55) 32.22,52.97 32.22,57.7 v1(31.84,58.08)
SPI_MOSI_IO0: length 49.2
  TOP w0.102: R242.1 134.48,59.17 v1(134.71,59.4) ; v1(118.88,75.7) 118.88,75.43 118.68,75.23 v3(118.68,74.94) 118.68,72.01 118.09,71.42 115.55,71.42 115.25,71.12 v1(115.25,70.5)
  IN1 w0.076: v1(118.88,75.7) 118.88,74.58 121.11,72.36 124.87,72.36 125.3,71.92 125.3,70.78 125.83,70.25 126.87,70.25 129.27,67.86 v1(129.35,67.86)
  IN4 w0.076: v1(131.96,64.71) 131.71,64.71 130.99,65.42 130.99,66.34 130.05,67.28 129.64,67.28 129.35,67.57 v1(129.35,67.86)
  BOTTOM w0.102: v1(115.25,70.5) 115.2,70.5 114.09,69.38 113.41,69.38 110.42,66.39 108.92,66.39 107.95,67.35 107.95,67.58 107.6,67.94 107.06,67.94 106.84,68.16 105.88,68.16 105.72,68.32 U1.AV3 ; v1(134.71,59.4) 134.71,59.63 133.99,60.34 133.99,60.92 131.96,62.95 v1(131.96,64.71) ; v1(118.88,75.7) 118.88,76.3 118.96,76.38 RC130.1 RC140.1
SPI_MOSI_IO0_2_R: length 1.4
  TOP w0.102: R242.2 133.41,59.3 132.8,59.3 132.65,59.14 U26.21
SPI_MOSI_IO0_R: length 4.5
  BOTTOM w0.102: RC130.2 119.31,77.36 v4(119.94,77.36) 122.4,77.36 UC5.5
SPI_MOSI_LFT: length 21.4
  TOP w0.076: U5.B4 28.98,50.81 29.19,51.02 29.83,51.02 v1(30.16,51.35)
  TOP w0.102: v1(27.1,60.67) 26.68,60.67 26.18,61.18 U186.5
  IN1 w0.076: v1(30.16,51.35) 30.36,51.15 31.01,51.15 31.35,51.48 32.92,51.48 33.1,51.29 33.56,51.29 33.99,51.72 33.99,52.49 32.7,53.78 32.7,58.64 31.12,60.22 27.56,60.22 v1(27.1,60.67)
SUS_DRV: length 153.2
  TOP w0.102: U21.D4 252.15,75.14 v1(252.56,75.55)
  TOP w0.152: R290.1 128.49,78.34 D41.1 129.35,78.67 129.44,78.58 C209.2 130.05,78.99 129.98,79.05 v3(129.98,79.52) 129.98,79.78 130.23,80.03 131.62,80.03 131.73,79.93 v1(131.73,79.88)
  IN1 w0.152: v1(131.73,79.88) 131.78,79.88 132.06,79.59 132.06,78.27 135.67,74.66 141.87,74.66 142.83,73.7 142.83,70.5 143.21,70.12 144,70.12 144.74,69.38 146.36,69.38 146.54,69.2 156.73,69.2 157.15,69.62 158.9,69.62 159.95,70.67 161.65,70.67 163.66,68.67 165.49,68.67 165.9,68.26 172.27,68.26 174.63,70.62 178.11,70.62 180.02,68.72 181.16,68.72 182.18,67.7 182.18,67.44 182.93,66.69 189.54,66.69 190,66.23 200.72,66.23 201,66.51 202.09,66.51 202.5,66.1 207.63,66.1 208.67,67.14 214.23,67.14 214.84,66.53 215.88,66.53 216.93,65.49 223.05,65.49 223.69,66.13 230.4,66.13 231.11,66.84 232.24,66.84 233.05,66.03 234.7,66.03 235.62,65.11 236.15,65.11 237.22,64.05 241.74,64.05 242.05,64.35 244.2,64.35 245.69,65.84 245.69,70.38 245.98,70.67 245.98,75.35 v1(245.68,75.65)
  IN4 w0.152: v1(252.56,75.55) 252.21,75.2 249.54,75.2 248.9,74.56 246.77,74.56 v1(245.68,75.65)
SUS_ON1: length 153.4
  TOP w0.203: PD701.1 140.6,69.86 v1(141.11,69.86) 141.16,69.81 141.16,68.34 140.98,68.16 140.98,67.45 141.28,67.14 142.02,67.14 142.43,67.55 142.43,68.39 144.57,70.53 146.21,70.53 147.76,68.97 149.76,68.97 v3(149.76,68.98) 149.76,68.97 152.74,68.97 155.05,71.28 v1(156.19,71.28)
  TOP w0.305: U21.H4 252.55,78.73 v1(252.55,78.77) ; U16.B2 236.33,74.05 v1(236.7,73.67) ; R147.1 v1(236.8,71.51)
  IN2 w0.203: v1(194.7,64.55) 194.73,64.53 199.04,64.53 199.83,63.74 202.35,63.74 202.57,63.51 214.18,63.51 214.35,63.35 215.13,63.35 216.29,62.19 216.72,62.19 216.95,62.42 216.95,62.85 217.36,63.26 219.36,63.26 219.67,62.95 221.04,62.95 222.61,64.53 223.81,64.53 224.61,65.33 224.61,65.82 225.06,66.27 225.36,66.27 225.8,66.71 225.8,67.03 226.04,67.27 227.29,67.27 228.74,65.82 233.69,65.82 234.53,66.66 236.28,66.66 236.76,67.15 237.77,67.15 v1(237.88,67.04)
  IN4 w0.203: v1(156.19,71.28) 158.05,71.28 158.84,70.5 158.84,69.63 162.44,66.03 182,66.03 182.71,65.32 193.91,65.32 194.67,64.55 v1(194.7,64.55)
  IN4 w0.305: v1(237.88,67.04) 237.93,66.99 240.09,66.99 240.52,66.56 241.82,66.56 243.14,67.89 246.56,67.89 247.07,67.37 247.79,67.37 248.42,68.01 248.42,70.88 249.03,71.49 250.53,71.49 251.19,70.83 252.66,70.83 254.16,72.33 254.16,77.78 253.17,78.77 v1(252.55,78.77)
  BOTTOM w0.203: PR718.2 140.84,70.13 v1(141.11,69.86)
  BOTTOM w0.305: v1(236.7,73.67) 236.7,71.61 v1(236.8,71.51) 236.97,71.51 238.39,70.09 238.39,67.55 v1(237.88,67.04)
SUS_ON2: length 119.9
  TOP w0.254: R149.1 v1(235.15,71.65) ; v1(190.81,96.56) 190.81,96.32 189.32,94.82 187.25,94.82 v3(187.13,94.7) 186.83,94.4 v1(186.83,93.94) ; U16.C4 v1(235.11,74.5)
  IN1 w0.254: v1(152.87,98.67) 152.36,98.16 152.36,92.67 153.73,91.3 155.86,91.3 156.54,90.63 166.49,90.63 v1(167.09,90.03)
  IN3 w0.254: v1(167.09,90.03) 166.96,90.16 166.96,91.97 167.81,92.82 174.83,92.82 175.85,91.81 177.24,91.81 181.02,95.59 185.05,95.59 186.7,93.94 v1(186.83,93.94)
  IN4 w0.254: v1(235.15,71.65) 234.46,70.96 231.14,70.96 229.75,72.35 228.25,72.35 226.76,73.85 223.05,73.85 222.61,74.28 222.61,75.35 221.57,76.39 221.57,77.39 222.51,78.32 222.51,80.18 219.24,83.45 219.24,85.94 216.62,88.56 215.86,88.56 213.8,90.61 210.47,90.61 206.23,94.86 199.22,94.86 196.15,97.93 191.96,97.93 190.81,96.79 v1(190.81,96.56)
  BOTTOM w0.203: v1(235.11,74.5) 235.11,74.19 235.29,74 235.29,71.79 v1(235.15,71.65)
  BOTTOM w0.254: PR755.1 152.82,98.74 152.87,98.69 v1(152.87,98.67)
SUSACK: length 1.1
  TOP w0.127: RC68.2 100.3,72.19 v1(100.62,71.87)
  BOTTOM w0.076: v1(100.62,71.87) 100.92,71.56 U1.AP11
SUSCLK_32K: length 183.6
  TOP w0.102: U16.B3 235.91,73.7 235.91,73.11 236.22,72.8 236.22,72.39 235.81,71.98 235.81,69.7 237.42,68.08 237.42,65.38 236.35,64.3 v3(235.97,64.3) 233.97,64.3 232.62,62.95 228.48,62.95 226.77,64.66 v1(226.77,65.35)
  IN1 w0.076: v1(209.1,65.26) 210.58,66.74 214.11,66.74 214.54,66.31 215.55,66.31 216.65,65.21 226.56,65.21 226.7,65.35 v1(226.77,65.35)
  IN3 w0.081: v1(97.72,64.53) 97.75,64.53 98.1,64.88 98.1,65.57 98.89,66.36 102.24,66.36 103.39,65.21 105.54,65.21 106.45,64.3 107.47,64.3 107.59,64.18 109.39,64.18 110.99,65.79 110.99,66.19 113.27,68.47 116.37,68.47 118.69,66.14 118.69,60.91 119,60.6 120.76,60.6 122.98,58.37 123.9,58.37 125.58,56.68 131.71,56.68 132.09,57.06 133.08,57.06 134.32,55.82 135.95,55.82 136.67,56.54 140.1,56.54 140.61,56.02 157.04,56.02 158.03,57.01 159.9,57.01 160.89,58 160.89,59.04 162.17,60.32 164.41,60.32 165.67,61.58 166.28,61.58 167.41,62.71 172.41,62.71 172.83,62.29 174.23,62.29 175.22,63.28 176.11,63.28 176.94,64.12 180.84,64.12 181.43,63.52 182.64,63.52 183.26,62.9 185.35,62.9 185.99,63.54 190.48,63.54 191.19,64.24 192.93,64.24 193.37,63.8 195.15,63.8 195.83,64.49 199.31,64.49 199.96,63.84 203.17,63.84 204.97,65.64 207.42,65.64 207.5,65.72 208.64,65.72 v1(209.1,65.26)
  BOTTOM w0.076: U1.BA17 97.6,66.94 97.87,66.68 97.87,65.47 98.06,65.28 98.06,64.87 v1(97.72,64.53)
  BOTTOM w0.102: v1(209.1,65.26) 210.19,64.17 210.19,61.53 208.55,59.89 J32.50
SVID_CLK: length 71
  IN3 w0.081: v1(131,96.18) 131,95.94 130.65,95.59 130.3,95.59 129.79,95.08 121.73,95.08 121.35,95.47 118.12,95.47 117.47,96.11 107.39,96.11 105.65,94.37 99.07,94.37 97.8,95.64 93.58,95.64 93.23,96 88.53,96 87.79,96.74 87.79,96.76 79.66,96.76 77.86,94.96 72.61,94.96 71.1,93.46 v1(71.1,92.57)
  BOTTOM w0.102: U1.A63 71.53,89.19 71.53,90.16 70.93,90.77 70.93,92.39 v1(71.1,92.57) 71.18,92.65 RC77.1 ; PR407.1 131,95.65 PR404.2 v1(131,96.18)
SVID_DATA: length 74.2
  IN3 w0.081: v1(70.19,92.04) 70.19,93.71 69.96,93.94 69.96,94.93 70.4,95.37 70.69,95.37 70.88,95.19 71.28,95.19 71.29,95.2 71.29,95.2 71.53,95.43 71.53,95.43 72.15,96.05 77.43,96.05 78.7,97.32 93.81,97.32 94.37,96.76 98.46,96.76 99.73,95.49 105.09,95.49 106.79,97.19 117.95,97.19 118.55,96.58 121.83,96.58 122.08,96.33 129.51,96.33 129.96,96.78 v1(130.46,96.78)
  BOTTOM w0.102: PR401.2 130.47,96.77 v1(130.46,96.78) 130.43,96.81 PR408.1 ; RC161.1 69.94,92.77 70.19,92.52 v1(70.19,92.04) 70.19,91.22 70.49,90.92 70.49,90.61 71.12,89.99 71.12,89.97 71.12,88.51 71.36,88.27 71.36,88.02 71.04,87.71 U1.D64
SW_1A: length 57.8
  IN3 w0.203: v1(79.91,101.82) 79.92,101.81 79.92,100.34 81.58,98.68 87.15,98.68 88.81,100.34 92.06,100.34 92.56,100.85 95.28,100.85 95.72,101.28 103.34,101.28 104.76,99.86 116.01,99.86 117.2,98.67 118.81,98.67 119.64,97.83 120.99,97.83 121.98,98.82 126.45,98.82 126.85,98.42 129.85,98.42 130.28,98.85 130.28,99.15 v1(130.25,99.18)
  BOTTOM w0.254: v1(79.91,101.82) 79.92,101.83 79.92,102.43 PR463.2 ; v1(130.25,99.18) 130.53,99.18 PR411.2
SW_1B: length 5.6
  BOTTOM w0.254: PR467.2 124.65,87.67 124.52,87.79 124.52,88.05 v4(125.14,88.67) 127.47,90.99 PR439.2
SYS_MDI_0+: length 69.9
  TOP w0.102: U14.22 222.05,88.64 222,88.69 222,88.88 222.56,89.45 238.52,89.45 239.46,90.39 240.04,90.39 241.74,92.09 241.74,93.06 242.91,94.23 242.91,97.99 243.9,98.98 243.9,99.07 v1(244.03,99.2)
  IN1 w0.076: v1(267.75,119.64) 267.75,119.92 267.57,120.11 267.03,120.11 266.73,119.8 266.73,111.57 259.31,104.15 252.13,104.15 247.51,99.53 244.07,99.53 243.93,99.39 243.93,99.3 v1(244.03,99.2)
  BOTTOM w0.102: v1(267.75,119.64) 268.09,119.98 268.35,119.98 268.85,119.49 T1.1
SYS_MDI_0-: length 69.9
  TOP w0.102: U14.23 221.55,88.64 221.59,88.69 221.59,89.05 222.4,89.85 v2(236.42,89.85) 238.35,89.85 239.29,90.79 239.87,90.79 241.33,92.26 241.33,93.23 242.5,94.4 242.5,98.16 243.44,99.1 v1(243.44,99.2)
  IN1 w0.076: v1(243.44,99.2) 243.65,99.4 243.65,99.5 243.95,99.81 247.39,99.81 252.01,104.43 259.19,104.43 266.45,111.69 266.45,119.92 266.92,120.39 267.57,120.39 v1(267.75,120.57)
  BOTTOM w0.102: T1.2 268.59,120.76 268.23,120.39 267.94,120.39 v1(267.75,120.57)
SYS_MDI_1+: length 76.3
  TOP w0.102: v1(244.33,100.62) 243.52,99.81 243.31,99.81 241.93,98.43 241.93,94.66 240.73,93.46 240.73,92.49 239.81,91.58 239.23,91.58 238.08,90.44 v2(230.21,90.44) 220.8,90.44 220,89.64 220,88.69 220.05,88.64 U14.26
  IN1 w0.076: v1(244.33,100.62) 244.23,100.62 244.15,100.7 244.15,100.91 244.29,101.05 246.14,101.05 250.48,105.4 258.8,105.4 265.74,112.33 265.74,120.24 266.51,121.01 266.51,124.38 267.18,125.06 267.42,125.06 v1(267.72,124.76)
  BOTTOM w0.102: v1(267.72,124.76) 267.72,124.94 267.95,125.16 268.12,125.16 268.72,124.57 T1.5
SYS_MDI_1-: length 76.2
  TOP w0.102: v1(243.75,100.62) 243.75,100.62 243.35,100.22 243.14,100.22 241.52,98.6 241.52,94.83 v2(240.97,94.28) 240.32,93.63 240.32,92.66 239.64,91.99 239.06,91.99 237.92,90.84 220.63,90.84 219.59,89.8 219.59,88.69 219.55,88.64 U14.27
  IN1 w0.076: v1(243.75,100.62) 243.87,100.74 243.87,101.02 244.18,101.33 246.02,101.33 250.36,105.68 258.68,105.68 265.46,112.45 265.46,120.35 266.23,121.12 266.23,124.5 267.07,125.34 267.37,125.34 v1(267.72,125.69)
  BOTTOM w0.102: v1(267.72,125.69) 267.84,125.57 268.15,125.57 268.42,125.84 T1.6
SYS_MDI_2+: length 80.7
  TOP w0.102: v1(242.91,101.08) 242.75,100.92 242.75,100.67 240.87,98.79 240.87,95.05 239.18,93.36 239.18,92.93 237.68,91.43 232.99,91.43 232.73,91.68 231.93,91.68 231.67,91.43 v2(227.44,91.43) 219.44,91.43 217.5,89.49 217.5,88.69 217.55,88.64 217.55,87.92 U14.31
  IN1 w0.076: v1(267.59,127.2) 267.59,127.52 267.46,127.65 266.96,127.65 266.71,127.41 266.71,125.97 264.67,123.93 264.67,112.75 259.62,107.71 251.38,107.71 245.69,102.02 243.13,102.02 242.67,101.57 242.67,101.32 v1(242.91,101.08)
  BOTTOM w0.102: v1(267.59,127.2) 267.89,127.5 268.23,127.5 268.62,127.11 T1.7
SYS_MDI_2-: length 80.7
  TOP w0.102: v1(242.33,101.08) 242.33,100.82 240.47,98.96 v2(240.47,96.74) 240.47,95.22 238.77,93.53 238.77,93.09 237.51,91.83 233.16,91.83 232.9,92.09 231.76,92.09 231.5,91.83 219.27,91.83 217.1,89.66 217.1,88.69 217.05,88.64 U14.32
  IN1 w0.076: v1(242.33,101.08) 242.39,101.15 242.39,101.68 243.01,102.3 245.58,102.3 251.27,107.99 259.51,107.99 264.39,112.87 264.39,124.05 266.43,126.09 266.43,127.52 266.84,127.93 267.39,127.93 v1(267.59,128.13)
  BOTTOM w0.102: v1(267.59,128.13) 267.82,127.91 268.05,127.91 268.52,128.38 T1.8
SYS_MDI_3+: length 85.6
  TOP w0.102: U14.35 215.55,87.92 215.55,88.64 215.5,88.69 215.5,89.44 218.47,92.42 231.05,92.42 231.35,92.72 233.11,92.72 233.42,92.42 236.81,92.42 239.63,95.24 239.63,99.12 v2(240.41,99.9) 242.43,101.92 244.13,101.92 v1(245.09,102.88)
  IN1 w0.076: v1(245.09,102.88) 244.79,103.19 244.79,103.53 245.44,104.18 246.43,104.18 251.05,108.8 258.43,108.8 263.05,113.42 263.05,123 263.65,123.6 263.65,124.31 265.64,126.3 265.64,129.41 267.54,131.31 267.54,131.82 v1(267.84,132.12)
  BOTTOM w0.102: T1.11 268.72,132.19 268.45,132.45 268.45,132.73 268.33,132.86 268.06,132.86 267.9,132.69 267.9,132.17 v1(267.84,132.12)
SYS_MDI_3-: length 85.7
  TOP w0.102: v1(244.51,102.88) 244.51,102.87 243.96,102.32 242.26,102.32 239.23,99.29 239.23,95.41 236.64,92.82 233.59,92.82 233.28,93.13 231.18,93.13 230.88,92.82 218.31,92.82 215.1,89.61 215.1,88.69 215.05,88.64 U14.36
  IN1 w0.076: v1(244.51,102.88) 244.51,103.65 245.33,104.46 246.32,104.46 250.94,109.08 258.31,109.08 262.77,113.54 262.77,123.11 263.37,123.72 263.37,124.43 265.36,126.42 265.36,129.53 267.26,131.43 v1(267.26,132.1)
  BOTTOM w0.102: v1(267.26,132.1) 267.49,132.33 267.49,132.86 267.9,133.27 268.53,133.27 268.72,133.46 T1.12
SYS_PWROK: length 5
  BOTTOM w0.076: U1.B6 104.78,88.44 104.78,88.62 104.98,88.82 105.31,88.82 105.41,88.92 105.41,89.35
  BOTTOM w0.102: 105.41,89.35 105.75,89.69 105.75,91.77 106,92.02 RC65.2
T1_PIN3: length 5.9
  BOTTOM w0.305: 267.37,130.29 C121.2 C123.2 ; C117.2 C119.2 267.37,121.39 ; C117.2 C120.2 267.03,122.88 ; C117.2 267.37,121.97 ; C123.2 267.37,130.89 ; C123.2 C118.2 267.37,131.53
  BOTTOM w0.508: T1.4 267.78,123.3 v1(267.74,123.33)
  vias: v1(267.77,130.95) v1(267.84,129.79) v1(267.79,122.65) v1(267.87,130.37) v3(266.57,123.03)
T1_PIN15: length 2.9
  BOTTOM w0.508: v1(280.88,130.47) 280.43,130.92 T1.15
  vias: v3(281.31,131.72)
T1_PIN16: length 3
  BOTTOM w0.508: v1(280.88,129.07) 280.31,129.65 T1.16
  vias: v3(281.23,128.16)
T1_PIN21: length 2.9
  BOTTOM w0.508: T1.21 279.83,123.3 280.5,123.96 v1(280.81,123.96)
  vias: v3(280.55,124.73)
T1_PIN22: length 2.7
  BOTTOM w0.508: T1.22 v1(280.83,122.03)
  vias: v3(280.52,120.84)
TH_DET: length 67.7
  TOP w0.254: v1(253.25,84.77) 253.25,83.83 252.84,83.43 252.84,81.94 252.59,81.69 C208.2 252.36,80.93 252.71,80.58 252.71,79.36 U21.J3 ; RT1.1 230.84,99.94 232.67,101.76 232.67,102.35 232.17,102.86 231.14,102.86 v4(230.64,102.36) 230.33,102.36 229.92,102.76 229.92,106.62 229.11,107.43 228.3,107.43 227.84,107.89 227.84,108.73 229.11,110 243.64,110 247.63,106.01 247.63,104.38 248.52,103.49 248.52,100.93 250.05,99.4 250.4,99.4 251.14,98.67 251.14,96.68 v1(251.22,96.61)
  IN3 w0.254: v1(251.22,96.61) 251.22,94.55 253.09,92.67 253.09,84.92 v1(253.25,84.77)
TOUCH_EN: length 98.7
  TOP w0.102: U16.N3 235.53,83.54 235.9,83.91 235.9,84.57 235.66,84.8 235.66,85.38 R10141.2 234.88,86.16 v1(234.88,86.96) 234.9,86.99 235.82,86.99 235.87,86.94 R353.1 ; D16.1 271.98,135.77 271.98,134.41 v1(271.48,133.9)
  IN3 w0.081: v1(240.39,84.34) 240.12,84.34 238.94,85.51 235.54,85.51 234.88,86.17 v1(234.88,86.96) ; v1(271.48,133.9) 271.48,135.09 270.79,135.78 270.07,135.78 v1(269.6,135.32) 269.24,135.32 266.61,132.69 266.61,111.21 267.68,110.14 267.68,90.57 264.48,87.37 v1(259.36,87.37)
  IN4 w0.076: v1(240.39,84.34) 242.27,86.22 242.27,86.83 243.87,88.43 248.37,88.43 250.2,86.6 258.45,86.6 259.22,87.37 v1(259.36,87.37)
  BOTTOM w0.102: v1(269.6,135.32) 270.05,135.76 J11.11
TP4_RESET: length 120.7
  TOP w0.102: v1(226.34,72.13) 227.48,73.27 U16.A13
  IN4 w0.076: v1(224.49,66.84) 224.42,66.84 222.12,64.54 222.12,61.75 221.15,60.78 215.11,60.78 214.56,61.33 212.98,61.33 212.42,60.77 210.27,60.77 209.97,61.07 209.97,61.53 209.63,61.86 208.47,61.86 207.78,61.18 207.1,61.18 206.17,60.25 202.38,60.25 201.41,61.23 201.41,61.76 198.79,64.38 195.44,64.38 195.16,64.1 194.37,64.1 193.4,65.06 182.48,65.06 181.85,65.7 172.4,65.7 169.25,62.55 169.25,62.12 v1(168.74,61.61) 168.36,61.99 168.36,62.24 166.46,64.15 165.44,64.15 164.63,63.33 158.71,63.33 v1(156.49,61.11)
  BOTTOM w0.102: v1(156.49,61.11) 156.04,60.67 156.04,58.38 152,54.34 137.58,54.34 136.96,54.96 136.96,56.04 137.3,56.37 137.3,56.88 R222.1 136.89,56.93 136.89,56.4 136.4,55.91 J37.2 ; v1(226.34,72.13) 225.03,70.83 224.32,70.83 223.53,70.04 223.53,67.8 v1(224.49,66.84) ; v1(168.74,61.61) 168.74,61.56 169.6,60.7 J16.11
TP4CLK: length 48.3
  BOTTOM w0.102: J16.18 168.1,64.2 167.95,64.35 166.2,64.35 165.08,63.24 165.08,61.94 164.12,60.97 v3(164.09,60.97) 161.53,60.97 160.92,61.58 159.88,61.58 159.11,60.82 156.91,60.82 156.3,60.21 156.3,57.89 152.49,54.09 136.58,54.09 135.85,54.81 135.85,55.77 136.59,56.5 136.59,56.96 R221.1 136.15,56.83 136.15,56.55 135.75,56.15 132.64,56.15 132.4,55.91 J37.6
TP4DATA: length 41.4
  BOTTOM w0.102: J16.16 168.6,64.16 168.21,64.55 166.11,64.55 164.88,63.32 164.88,62.14 164.12,61.38 161.43,61.38 161.02,61.79 159.52,61.79 158.86,61.12 157.41,61.12 157.27,61.26 v3(157.2,61.26) 156.94,61.26 156.68,61.53 156.32,61.53 155.75,60.96 155.75,58.53 151.95,54.72 141.26,54.72 138.87,57.12 R220.1 138.07,56.64 137.4,55.97 J37.1
TP_DIMM0_CHA_S2_N: length 4.2
  TOP w0.127: v1(63.94,30.06) 64.5,30.62 TP31.1
  BOTTOM w0.127: v1(63.94,30.06) 63.53,29.64 J21.162
TP_DIMM0_CHA_S3_N: length 5.5
  TOP w0.102: TP32.1 64.75,32.96 65.47,32.24 v1(65.47,31.81)
  BOTTOM w0.127: v1(65.47,31.81) 65.47,32.24 64.86,32.85 64.86,33.2 64.53,33.53 64.53,34.07 64.28,34.32 J21.165
TYPEC_CON_RXN1: length 10.1
  TOP w0.102: JTYC1.22 7.1,52.86 10.82,52.86 11.25,53.3 11.25,53.56 11.63,53.94 12.15,53.94 v1(12.24,54.03)
  BOTTOM w0.102: L14.2 15.85,54.22 15.75,54.12 15.47,54.12 15.29,53.94 14.48,53.94 14.42,54 D87.8 D87.2 12.89,54 12.83,53.94 12.33,53.94 v1(12.24,54.03)
TYPEC_CON_RXN2: length 8.8
  BOTTOM w0.102: JTYC1.10 9.53,56.51 9.57,56.56 10.54,56.56 v2(11.12,57.13) 11.33,57.34 11.33,58.65 11.7,59.02 12.78,59.02 12.84,58.96 D88.4 D88.7 14.49,58.96 14.56,59.02 15.68,59.02 L15.3
TYPEC_CON_RXP1: length 10.1
  TOP w0.102: JTYC1.23 7.1,52.46 10.99,52.46 11.66,53.13 11.66,53.39 11.8,53.53 12.15,53.53 v1(12.24,53.45)
  BOTTOM w0.102: L14.3 15.85,53.62 15.75,53.71 15.64,53.71 15.46,53.54 14.47,53.54 14.44,53.5 D87.9 D87.1 12.84,53.5 12.8,53.53 12.33,53.53 v1(12.24,53.45)
TYPEC_CON_RXP2: length 8.7
  BOTTOM w0.102: JTYC1.11 9.53,57.01 9.57,56.96 10.37,56.96 10.92,57.51 10.92,58.82 11.53,59.43 v2(11.99,59.43) 12.75,59.43 12.78,59.46 D88.5 D88.6 14.37,59.46 14.4,59.43 15.71,59.43 L15.2
TYPEC_CON_TXN1: length 9.4
  BOTTOM w0.102: L12.2 16.04,55.92 14.92,55.92 14.5,55.5 D87.6 D87.5 12.81,55.5 12.78,55.47 v2(12.07,55.47) 11.84,55.47 11.25,54.88 11.25,53.25 10.96,52.95 9.37,52.95 9.32,53.01 JTYC1.3
TYPEC_CON_TXN2: length 9.5
  TOP w0.102: v1(12.2,57.4) 12.11,57.5 9.8,57.5 8.98,56.68 7.12,56.68 JTYC1.15
  BOTTOM w0.102: L13.3 15.65,57.32 14.79,57.32 14.66,57.46 D88.9 D88.1 12.97,57.46 12.94,57.49 12.29,57.49 v1(12.2,57.4)
TYPEC_CON_TXP1: length 9.5
  BOTTOM w0.102: L12.3 15.96,55.52 15.09,55.52 14.57,55 D87.7 D87.4 12.84,55 12.78,55.06 12.01,55.06 11.66,54.71 11.66,53.08 v2(11.38,52.8) 11.13,52.54 9.32,52.54 9.29,52.51 JTYC1.2
TYPEC_CON_TXP2: length 9.5
  TOP w0.102: v1(12.2,57.99) 12.12,57.9 9.63,57.9 8.82,57.09 7.07,57.09 JTYC1.14
  BOTTOM w0.102: v1(12.2,57.99) 12.29,57.9 12.95,57.9 13.01,57.96 D88.2 D88.8 14.27,57.86 14.82,57.86 14.96,57.73 15.73,57.73 L13.2
TYPEC_HPD_PD: length 7.5
  TOP w0.076: U5.C10 27.98,48.28 v3(27.92,48.28)
  TOP w0.102: R725.2 29.06,42.97 v1(28.91,43.12)
  BOTTOM w0.102: v3(27.92,48.28) 27.92,47.31 27.66,47.06 27.66,46.47 28.35,45.79 28.35,43.68 v1(28.91,43.12)
U24_DE_A: length 2.5
  TOP w0.102: U24.17 238.83,49.88 238.95,50 238.95,50.64 R346.2 R342.1
U24_DE_B: length 1.8
  TOP w0.102: U24.8 235.85,49.48 235.56,49.77 R347.2 R343.1
U24_EN#: length 1.3
  TOP w0.102: R352.1 235.87,49.88 U24.7
U24_EQ_A: length 2.8
  TOP w0.102: R344.1 240.17,50.04 R348.2 239.15,50.27 239.15,49.72 238.91,49.48 U24.16
U24_EQ_B: length 2.4
  TOP w0.102: U24.9 235.85,49.08 R345.1 235.71,48.26 R349.2
U25_DE_A: length 1.8
  TOP w0.102: U25.17 232.26,50.16 232.39,50.02 R360.2 R356.1
U25_DE_B: length 2
  TOP w0.102: U25.8 229.33,49.76 228.99,49.42 R357.1 R361.2
U25_EQ_A: length 1.9
  TOP w0.102: U25.16 232.2,49.76 232.52,49.44 R362.2 R358.1
U25_EQ_B: length 2.8
  TOP w0.102: R359.1 228.85,47.63 228.53,47.94 R363.2 229.12,48.81 229.12,49.11 229.37,49.36 U25.9
U25_MODE: length 2.6
  TOP w0.102: U25.18 232.12,50.56 232.22,50.66 232.22,51.04 232.37,51.19 R365.1 232.91,51.82 v4(232.65,52.08)
U28_HOLD#: length 3.8
  TOP w0.102: R716.2 23.45,58.72 23.47,58.72 v3(23.55,58.64) U186.7
U28_WP#: length 6.5
  TOP w0.102: R713.2 33.35,62.18 33.35,62.5 33.66,62.81 v4(33.66,63.01) 33.2,63.01 32.08,61.89 32.08,60.39 31.59,59.91 U186.3
UIM_CLK: length 110.9
  TOP w0.203: v1(235.56,57.9) 235.33,57.9 234.85,58.39 233.83,58.39 R104.2 ; J25.3 276.4,103.91 276.4,105.58 275.01,106.98 v1(272.7,106.98) 272.04,107.64 v3(271.17,107.64) 269.43,107.64 D18.5
  IN3 w0.203: v1(235.56,57.9) 236.09,58.44 237.72,58.44 238.94,57.22 238.94,56.61 241.33,54.22 245.14,54.22 247.3,56.38 248.95,56.38 250.12,57.55 250.98,57.55 253.04,59.61 253.04,60.47 257.53,64.97 258.04,64.97 261.14,68.06 264.7,68.06 265.33,67.43 266.12,67.43 267.36,66.18 271.96,66.18 275.44,69.66 275.44,71.01 276.7,72.27 277.13,72.27 280.27,75.4 280.27,81.86 279.45,82.67 279.45,86.94 278.37,88.02 275.93,88.02 274.32,89.63 274.32,94.35 272.82,95.85 272.82,106.85 v1(272.7,106.98)
UIM_DATA: length 129.2
  TOP w0.203: v1(273.05,109.08) 272.57,109.57 v3(271.35,109.57) 270,109.57 268.5,108.06 D18.3 ; J25.7 v1(291.74,102.64)
  IN3 w0.203: v1(291.74,102.64) 288.77,102.64 282.32,109.08 v1(273.05,109.08) 273.31,108.83 273.31,95.94 274.73,94.52 274.73,90.14 276.2,88.66 278.36,88.66 279.83,87.19 279.83,82.72 280.57,81.98 280.57,75.15 277.78,72.36 277.78,71.31 272.29,65.83 267.16,65.83 265.97,67.02 265.23,67.02 264.57,67.68 261.16,67.68 258.12,64.64 257.74,64.64 253.39,60.29 253.39,59.43 251.13,57.17 250.5,57.17 249.38,56.05 247.37,56.05 245.14,53.81 241.33,53.81 238.53,56.61 238.53,57.12 237.75,57.9 236.27,57.9 235.66,57.29 234.11,57.29 233.76,57.65 v1(233.76,57.9)
  BOTTOM w0.203: v1(233.76,57.9) 233.85,58 J22.34
UIM_PWR: length 127
  TOP w0.635: D18.2 265.86,108.06 266.98,109.19 C124.2 267.39,109.5 268.19,110.3 v3(268.48,110.3) v1(271.88,110.3) 277.88,110.3 279.99,108.2 279.99,98.57 278.98,97.56 J25.1
  IN3 w0.635: v1(234.65,57.88) 234.67,57.9 234.67,58.51 235.18,59.02 237.95,59.02 239.52,57.45 239.52,56.74 241.43,54.83 244.98,54.83 247.17,57.01 248.82,57.01 257.38,65.57 257.86,65.57 260.96,68.67 266.22,68.67 268.1,66.79 270.84,66.79 272.62,68.57 272.62,69.26 273.92,70.55 273.92,71.38 279.73,77.2 279.73,81.55 278.8,82.48 278.8,82.91 277.18,84.54 276.29,84.54 272.13,88.7 272.13,105.15 271.88,105.39 v1(271.88,110.3)
  BOTTOM w0.381: v1(234.65,57.88) 234.35,58.17 J22.36
UIM_RESET: length 117.6
  TOP w0.203: J25.2 275.72,102.06 275.72,105.5 274.7,106.52 v1(274.35,106.52) 273.71,105.88 v3(271.73,105.88) 271.17,105.88 270,107.05 269.29,107.05 268.81,106.57 268.81,105.73 268.5,105.43 266.55,105.43 265.91,106.06 D18.1
  IN3 w0.203: v1(274.35,106.52) 274.32,106.49 274.32,95.72 275.29,94.75 275.29,92.44 280.16,87.57 280.16,82.97 280.9,82.24 280.9,74.92 278.18,72.2 278.18,71.19 272.44,65.45 265.58,65.45 263.68,67.35 261.27,67.35 258.22,64.3 257.89,64.3 253.82,60.24 253.82,59.33 251.26,56.76 250.75,56.76 249.63,55.64 247.58,55.64 244.65,52.72 241.94,52.72 238.1,56.56 238.1,56.99 237.57,57.52 236.53,57.52 235.87,56.86 233.94,56.86 233.15,57.65 v1(233.15,57.95)
  BOTTOM w0.203: J22.30 232.85,58.31 233.15,58.01 v1(233.15,57.95)
USB2_ID: length 7.2
  BOTTOM w0.076: 107.97,76.2 107.73,75.96 106.85,75.96 106.67,75.79 106.67,75.45 106.23,75.01 U1.AG3
  BOTTOM w0.102: 107.97,76.2 108.13,76.37 109.61,76.37 v4(109.79,76.19) 110.27,75.71 RC157.2
USB2_VBUSSENSE: length 9.4
  BOTTOM w0.076: 107.77,76.9 107.33,76.9 107.32,76.89 107.18,76.75 107.13,76.75 107.12,76.74 106.95,76.74 106.39,76.5 106.39,76.16 106.27,76.03 105.21,76.03 105.07,75.89 105.07,75.6 105.39,75.27 U1.AG4
  BOTTOM w0.102: 107.77,76.9 110.63,76.9 111.07,76.47 v4(111.26,76.47) 111.9,77.11 RC156.2
USB3P0_RXN: length 209.5
  TOP w0.102: E_L2.1 279.99,79.04 279.78,79.04 279.63,79.19 279.46,79.19 279.05,79.6 v1(279.05,80.05)
  IN1 w0.076: 102.78,85.03 102.54,85.03 102.43,84.92 v1(102.43,84.74)
  IN1 w0.089: v1(279.05,80.05) 279.05,79.75 279.3,79.5 279.54,79.5 279.68,79.64 279.68,80.27 279.33,80.62 277.55,80.62 275.46,82.71 272.64,82.71 271.32,84.04 266.39,84.04 264.48,85.94 257.08,85.94 255.38,87.64 251.78,87.64 251.33,88.1 244.69,88.1 242.38,90.41 241.89,90.41 241.28,91.02 237.51,91.02 236.81,91.72 232.36,91.72 231.39,90.75 223.48,90.75 222.9,91.33 215.74,91.33 214.62,90.21 210.02,90.21 208.11,92.13 196.58,92.13 195.94,92.76 186.21,92.76 184.94,94.03 179.68,94.03 177.43,91.78 175.15,91.78 174.4,92.53 163.13,92.53 156.06,99.59 154.43,99.59 151.14,102.88 149.34,102.88 148.93,103.29 145.84,103.29 144.15,101.59 144.15,98.62 142.48,96.96 141.3,96.96 140.35,96 140.35,95.08 136.78,91.51 133.36,91.51 131.57,93.3 129.49,93.3 129.13,93.65 127.27,93.65 126.53,94.39 118.68,94.39 117.88,95.2 112,95.2 107.87,91.06 107.87,90.6 105.11,87.85 105.11,85.51 104.39,84.78 103.03,84.78 102.79,85.03 102.78,85.03
  BOTTOM w0.076: v1(102.43,84.74) 102.55,84.74 102.83,84.45 U1.H8
USB3P0_RXN_CONN: length 8.7
  TOP w0.102: E_L2.2 281.62,79.01 281.82,79.01 282.05,79.24 282.48,79.24 282.63,79.39 D15.6 D15.5 283.98,79.39 284.18,79.19 285.41,79.19 v2(286.18,79.96) 286.55,80.33 287.26,80.33 287.77,80.84 288.23,80.84 288.37,80.98 J34.5
USB3P0_RXP: length 209.5
  TOP w0.102: v1(279.05,78.78) 279.24,78.98 279.54,78.98 279.69,78.83 279.94,78.83 E_L2.4
  IN1 w0.076: v1(102.43,85.4) 102.43,85.27 102.51,85.19 102.7,85.19 102.71,85.2 102.75,85.2 102.77,85.22 102.78,85.22
  IN1 w0.089: v1(279.05,78.78) 279.05,78.97 279.38,79.31 279.62,79.31 279.87,79.56 279.87,80.35 279.41,80.81 277.63,80.81 275.54,82.91 272.72,82.91 271.4,84.23 266.47,84.23 264.56,86.13 257.16,86.13 255.46,87.83 251.86,87.83 251.41,88.29 244.77,88.29 242.46,90.6 241.97,90.6 241.36,91.21 237.59,91.21 236.89,91.91 232.28,91.91 231.31,90.94 223.56,90.94 222.98,91.52 215.66,91.52 214.54,90.4 210.1,90.4 208.18,92.32 196.66,92.32 196.02,92.95 186.29,92.95 185.02,94.22 179.6,94.22 177.35,91.97 175.23,91.97 174.48,92.72 163.2,92.72 156.14,99.78 154.51,99.78 151.22,103.07 149.41,103.07 149.01,103.48 145.76,103.48 143.96,101.67 143.96,98.7 142.4,97.15 141.23,97.15 140.16,96.08 140.16,95.16 136.7,91.7 133.44,91.7 131.65,93.49 129.57,93.49 129.21,93.84 127.35,93.84 126.61,94.58 118.76,94.58 117.96,95.39 111.92,95.39 107.67,91.14 107.67,90.67 104.92,87.92 104.92,85.59 104.31,84.98 103.11,84.98 102.87,85.22 102.78,85.22
  BOTTOM w0.076: U1.G8 102.71,85.1 102.43,85.38 v1(102.43,85.4)
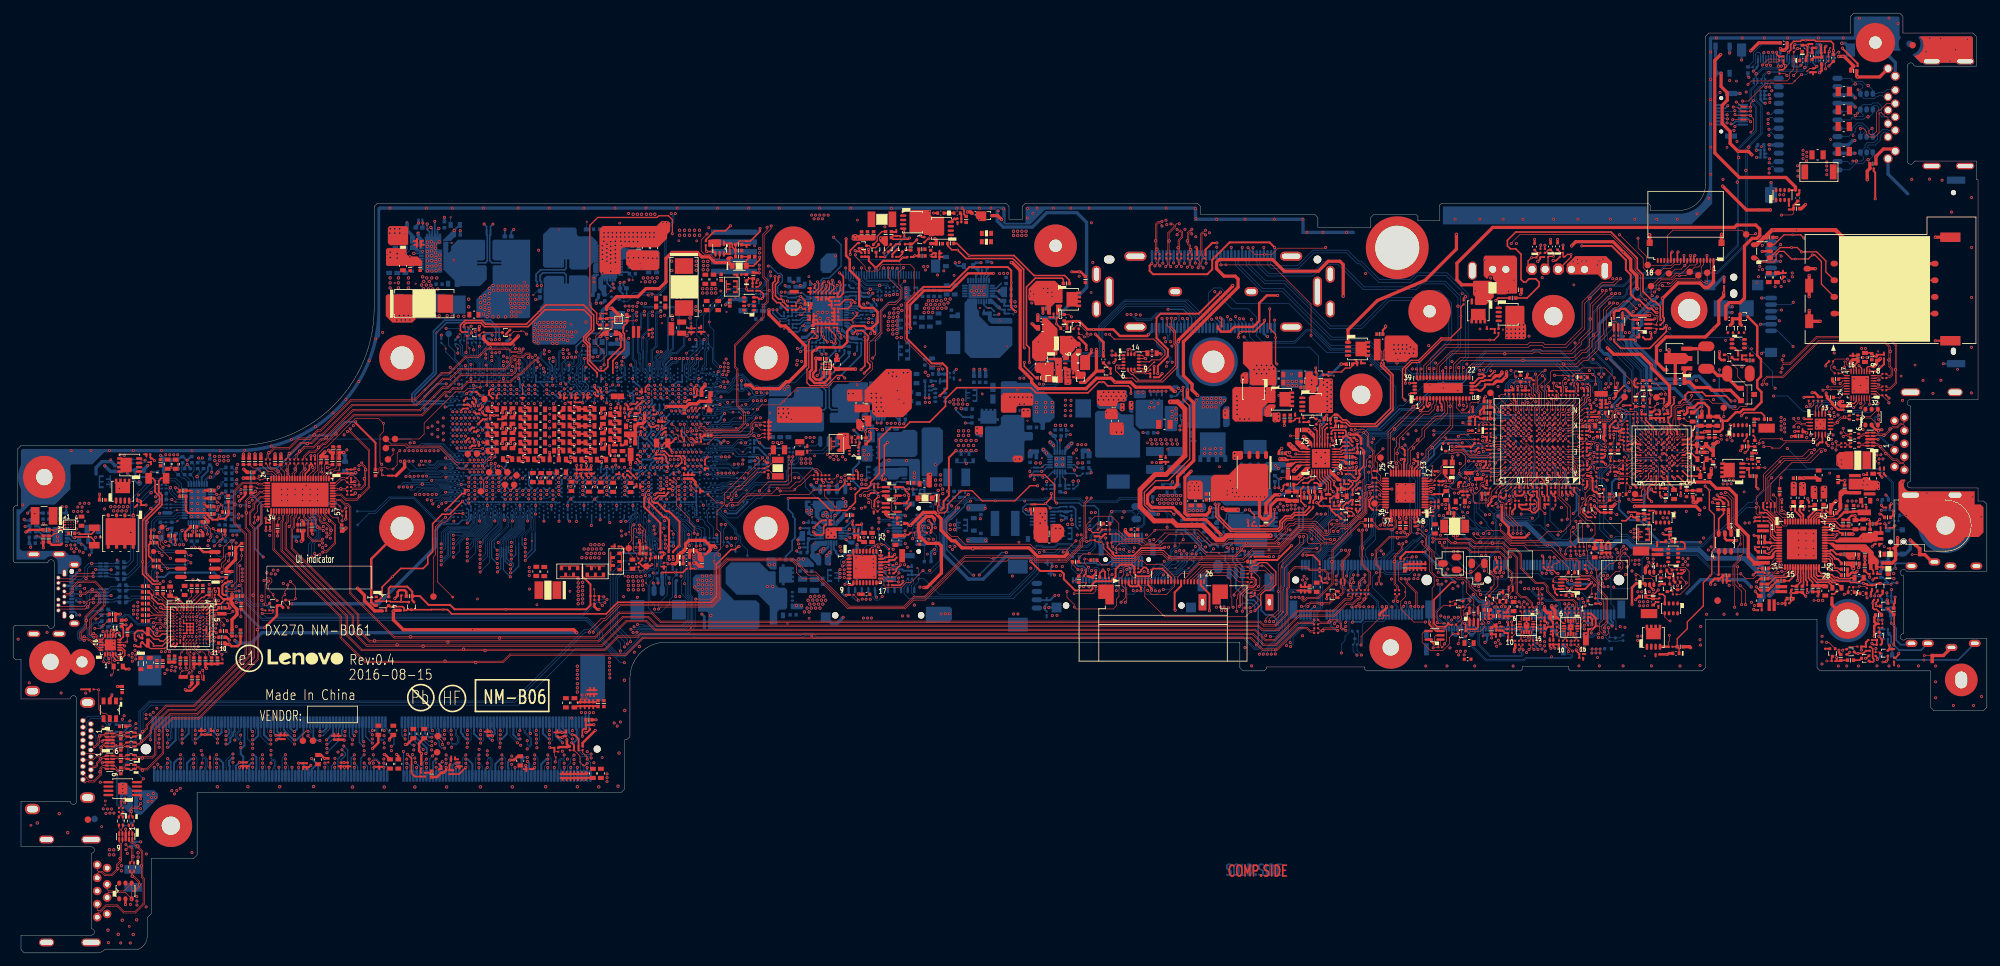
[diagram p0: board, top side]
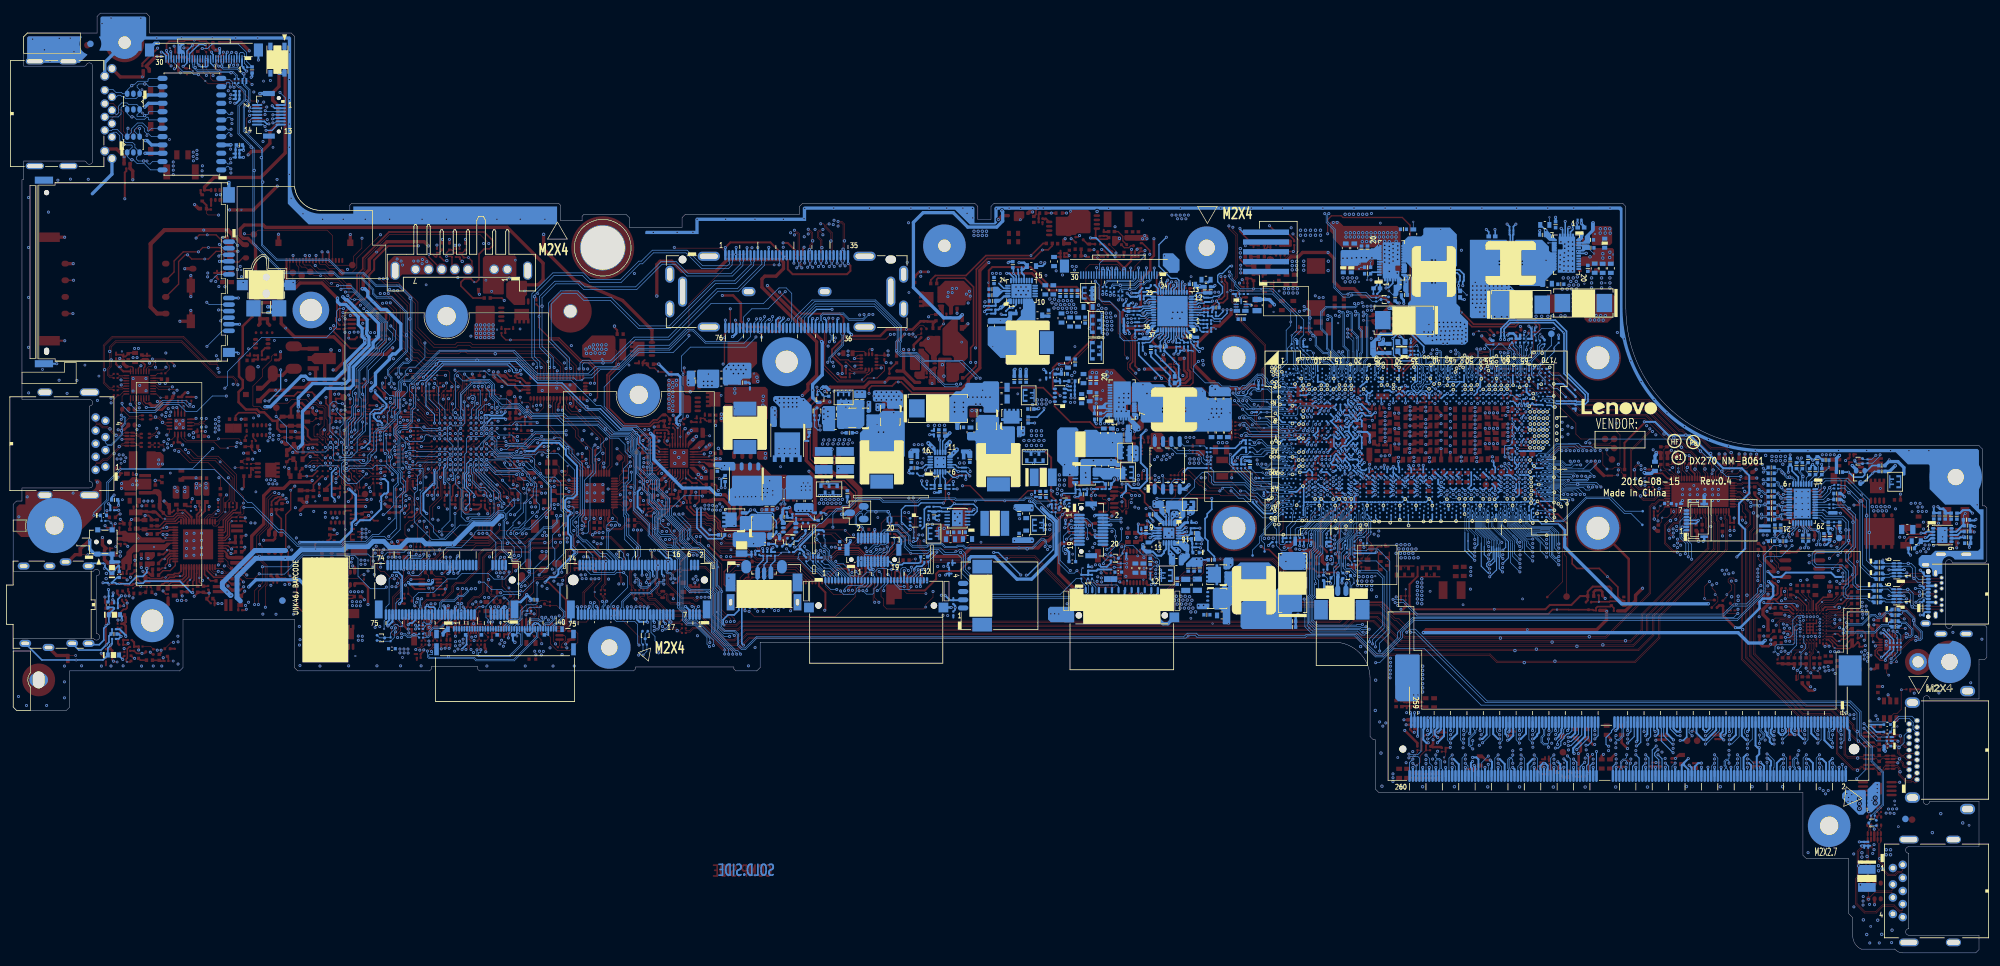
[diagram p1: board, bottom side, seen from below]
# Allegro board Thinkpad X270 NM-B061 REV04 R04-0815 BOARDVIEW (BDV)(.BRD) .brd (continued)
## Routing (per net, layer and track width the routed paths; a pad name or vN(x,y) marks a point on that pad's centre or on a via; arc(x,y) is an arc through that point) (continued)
USB3P0_RXP_CONN: length 8.8
  TOP w0.102: E_L2.3 281.6,78.8 281.91,78.8 282.14,79.03 282.3,79.03 282.45,78.89 D15.7 D15.4 283.98,78.89 284.08,78.98 v2(285.24,78.98) 285.5,78.98 286.63,80.12 287.34,80.12 287.86,80.63 288.24,80.63 288.37,80.5 J34.6
USB3P0_TXN: length 220.1
  TOP w0.102: v1(277.96,78.02) 277.96,77.72 278.09,77.59 278.57,77.59 C97.2
  IN1 w0.089: v1(277.96,78.02) 277.96,77.39 278.08,77.27 278.75,77.27 280.3,78.82 280.3,80.71 277.1,83.91 274.87,83.91 271.11,87.67 267.51,87.67 265.04,90.13 244.94,90.13 243.42,91.66 242.43,91.66 241.63,92.46 237.8,92.46 237.34,92.91 231.76,92.91 230.91,92.06 224.09,92.06 222.42,93.73 214.31,93.73 213.37,94.66 205.59,94.66 204.23,93.29 197.21,93.29 196.33,94.18 192.28,94.18 191.99,94.46 186.44,94.46 185.63,95.27 174.45,95.27 172.98,96.75 169.31,96.75 167.46,94.89 164.29,94.89 159.84,99.35 159.84,100.11 157.32,102.63 156.25,102.63 153.13,105.75 145.49,105.75 141.92,102.19 138.21,102.19 136.91,100.89 136.91,99.95 136.4,99.44 136.4,94 135.66,93.26 134.09,93.26 131.78,95.57 130.09,95.57 129.34,96.32 127.12,96.32 125.25,98.19 122.44,98.19 120.93,96.67 119.1,96.67 118.78,96.99 111.06,96.99 108.29,94.22 106.88,94.22 104.9,92.24 102.09,92.24 101.21,91.35 101.21,91.09 101.6,90.7 v1(101.62,90.7)
  BOTTOM w0.076: U1.C13 100.22,87.61 100.31,87.52 100.41,87.52 100.54,87.65 100.54,88 100.37,88.18 100.08,88.18 99.99,88.26 99.95,88.39 99.95,88.56 99.99,88.68 100.01,88.75 100.01,88.9 99.95,89.02 99.95,89.36 100.24,89.65 100.26,89.65
  BOTTOM w0.102: 100.26,89.65 100.59,89.98 101.13,89.98 101.41,90.25 101.41,90.48 v1(101.62,90.7)
USB3P0_TXN_C: length 1
  TOP w0.102: E_L3.1 279.94,77.59 279.53,77.59 C97.1
USB3P0_TXN_CONN: length 9.1
  TOP w0.102: E_L3.2 281.54,77.82 281.71,77.64 282.15,77.64 282.39,77.89 D15.8 D15.2 283.86,77.89 284.06,77.69 284.35,77.69 v2(284.77,77.27) 286.66,75.37 287.26,75.37 287.77,74.87 288.22,74.87 288.37,75.01 J34.8
USB3P0_TXP: length 220.2
  TOP w0.102: C98.2 278.58,77.38 278.02,77.38 277.95,77.31 277.95,76.87 277.95,76.87 v1(277.95,76.74)
  IN1 w0.089: v1(101.01,90.7) 101.01,91.43 102.01,92.43 104.82,92.43 106.8,94.41 108.21,94.41 110.54,96.74 110.98,97.18 118.86,97.18 119.18,96.86 120.85,96.86 122.36,98.38 125.33,98.38 127.19,96.51 129.41,96.51 130.16,95.76 131.86,95.76 134.17,93.45 135.58,93.45 136.21,94.08 136.21,99.52 136.72,100.03 136.72,100.97 138.13,102.38 141.85,102.38 145.41,105.94 153.21,105.94 156.33,102.82 157.4,102.82 160.03,100.19 160.03,99.43 164.37,95.08 167.38,95.08 169.23,96.94 173.06,96.94 174.53,95.47 185.71,95.47 186.52,94.65 192.07,94.65 192.36,94.37 196.41,94.37 197.29,93.48 204.15,93.48 205.51,94.85 213.45,94.85 214.39,93.92 222.5,93.92 224.17,92.25 230.83,92.25 231.68,93.1 237.42,93.1 237.88,92.65 241.71,92.65 242.51,91.85 243.5,91.85 245.02,90.32 265.12,90.32 267.59,87.86 271.19,87.86 274.95,84.1 277.18,84.1 280.49,80.79 280.49,78.74 278.82,77.08 278.09,77.08 277.95,76.94 v1(277.95,76.74)
  BOTTOM w0.076: U1.D13 100,87.5 99.84,88.07 99.82,88.13 99.82,88.24 99.78,88.36 99.78,88.61 99.82,88.7 99.82,88.89 99.78,88.99 99.78,89.43 100.11,89.76 100.11,89.8 100.16,89.85
  BOTTOM w0.102: 100.16,89.85 100.5,90.19 101.04,90.19 101.2,90.34 101.2,90.51 101.01,90.69 101.01,90.7 v1(101.01,90.7)
USB3P0_TXP_C: length 1
  TOP w0.102: C98.1 279.54,77.39 280,77.39 E_L3.4
USB3P0_TXP_CONN: length 9.2
  TOP w0.102: E_L3.3 281.54,77.22 281.76,77.43 282.2,77.43 282.25,77.39 D15.9 D15.1 283.95,77.39 284.04,77.48 284.27,77.48 v2(285.55,76.19) 286.58,75.17 287.17,75.17 287.68,74.66 288.25,74.66 288.37,74.54 J34.9
USB3P1_RXN: length 116
  IN4 w0.076: v1(101.5,84.08) 101.5,84.09 101.88,84.29 102.05,84.46 102.05,87.03 101.77,87.32 101.77,87.34 101.75,87.35
  IN4 w0.089: 101.75,87.35 100.88,88.23 96.53,88.23 95.54,87.24 94.58,87.24 92.27,84.92 72.95,84.92 72.2,85.67 69.79,85.67 69.51,85.95 67.97,85.95 65.95,83.93 64.91,83.93 64.17,83.2 64.16,83.2 63.36,82.4 60.52,79.56 58.82,79.56 54.59,75.34 54.59,74.08 53.84,73.33 53.84,70.22 52.44,68.82 52.44,60.22 49.05,56.82 43.32,56.82 39.82,60.33 39.82,64.71 39.4,65.13 37.97,65.13 37.34,64.49 33.66,64.49 32.31,65.84 32.31,72.43 29.9,74.85 29.9,75.35 29.12,76.13 28.68,76.13 28.47,75.93 28.47,75.73 v1(28.27,75.52)
  BOTTOM w0.102: v1(101.5,84.08) 101.77,83.8 U1.J10 ; v1(28.27,75.52) 28.37,75.42 28.37,75.04 C8345.1
USB3P1_RXN_TYPEC: length 2.7
  BOTTOM w0.102: U183.4 27.95,72.05 28.04,72.14 v2(28.04,72.69) 28.04,72.99 28.44,73.4 28.44,73.58 C8345.2
USB3P1_RXP: length 115.9
  IN4 w0.076: v1(101.48,84.8) 101.48,84.57 101.65,84.4 101.75,84.4 101.78,84.42 101.89,84.53 101.89,86.96 101.65,87.2 101.63,87.2 101.62,87.22
  IN4 w0.089: 101.62,87.22 100.8,88.04 96.62,88.04 95.61,87.03 94.65,87.03 92.35,84.73 72.87,84.73 72.12,85.48 69.71,85.48 69.43,85.76 68.05,85.76 66.03,83.74 64.99,83.74 64.25,83.01 64.23,83.01 60.6,79.37 58.9,79.37 54.78,75.26 54.78,73.96 54.04,73.21 54.04,70.14 52.63,68.74 52.63,60.14 49.12,56.63 43.24,56.63 39.63,60.25 39.63,64.63 39.32,64.94 38.05,64.94 37.42,64.3 33.58,64.3 32.12,65.76 32.12,72.35 29.71,74.77 29.71,75.27 29.04,75.94 28.75,75.94 28.67,75.85 28.67,75.65 28.79,75.52 v1(28.85,75.52)
  BOTTOM w0.102: C8347.1 28.77,74.8 28.62,74.96 28.62,75.29 v1(28.85,75.52) ; v1(101.48,84.8) 101.48,84.55 101.59,84.45 U1.H10
USB3P1_RXP_TYPEC: length 2.7
  BOTTOM w0.102: C8347.2 28.65,73.51 28.65,73.31 28.25,72.9 28.25,72.13 28.35,72.03 U183.5
USB3P1_TXN: length 94.4
  IN1 w0.089: v1(34.09,73.96) 34.27,73.78 34.62,73.78 35.03,73.37 40.92,73.37 45.96,78.41 51.96,78.41 56.48,82.93 59.87,82.93 65.33,88.38 65.33,90.03 67.51,92.21 69.49,92.21 72.23,94.96 75.45,94.96 76.82,93.59 78.44,93.59 79.46,92.57 80.2,92.57 80.28,92.65 81.96,92.65 82.03,92.57 83.19,92.57 83.4,92.79 84.84,92.79 87.57,95.51 94.06,95.51 95.67,97.12 95.67,98.68 95.84,98.86 v1(95.84,99.1)
  BOTTOM w0.076: 99.17,90.92 99.16,90.9 99.16,90.87 98.59,90.3 98.59,89.04 U1.B15
  BOTTOM w0.102: C8349.1 33.68,73.75 33.89,73.75 v1(34.09,73.96) ; 99.17,90.92 100.51,92.25 100.51,94.41 101.38,95.27 101.38,97.76 100.7,98.44 96.26,98.44 96.04,98.66 96.04,98.9 v1(95.84,99.1)
USB3P1_TXN_TYPEC: length 4.8
  BOTTOM w0.102: C8349.2 32.28,73.93 31.51,73.93 30.65,73.08 30.65,72.89 30.39,72.62 v2(30.08,72.62) 29.61,72.62 29.25,72.25 29.25,72 29.15,71.9 U183.7
USB3P1_TXP: length 94.4
  IN1 w0.089: v1(96.43,99.1) 96.43,98.88 96.24,98.7 95.95,98.7 95.86,98.6 95.86,97.04 94.14,95.32 87.64,95.32 84.92,92.6 83.48,92.6 83.27,92.38 81.95,92.38 81.88,92.46 80.35,92.46 80.28,92.38 79.38,92.38 78.37,93.4 76.74,93.4 75.37,94.77 72.31,94.77 69.57,92.02 67.59,92.02 65.52,89.95 65.52,88.3 59.95,82.74 56.56,82.74 52.04,78.22 46.03,78.22 41,73.18 34.95,73.18 34.54,73.59 34.3,73.59 v1(34.09,73.37)
  BOTTOM w0.076: 99.32,90.77 99.31,90.75 99.28,90.75 98.75,90.23 98.75,89.24 U1.A15
  BOTTOM w0.102: v1(96.43,99.1) 96.25,98.92 96.25,98.75 96.35,98.65 100.79,98.65 101.58,97.85 101.58,95.19 100.72,94.32 100.72,92.17 99.32,90.77 ; C8348.1 33.7,73.54 33.92,73.54 v1(34.09,73.37)
USB3P1_TXP_TYPEC: length 4.8
  BOTTOM w0.102: C8348.2 32.15,73.19 31.98,73.37 31.98,73.67 31.93,73.72 31.59,73.72 v2(31.23,73.36) 30.86,72.99 30.86,72.8 30.47,72.41 29.7,72.41 29.46,72.17 29.46,71.99 29.55,71.89 U183.8
USB3P3_RXN_DOCK: length 98.4
  IN1 w0.089: v1(101.48,86.62) 101.75,86.36 101.91,86.36 103.87,88.32 104.47,88.32 107.06,90.89 107.06,91.38 111.38,95.71 111.38,95.71 111.68,96 118.31,96 118.64,95.67 121.19,95.67 121.68,95.18 128.91,95.18 129.53,94.56 130.1,94.56 130.57,94.09 131.88,94.09 133.68,92.28 136.34,92.28 138.08,94.02 138.08,95.72 137.44,96.36 137.44,99.05 137.91,99.52 137.91,100.33 138.76,101.19 142.63,101.19 145.76,104.32 152.67,104.32 156.27,100.71 156.27,100.49 163.45,93.32 174.71,93.32 175.34,92.7 175.94,92.7 176.14,92.89 176.14,93.08 175.96,93.26 v1(175.73,93.26)
  BOTTOM w0.076: U1.E10 101.71,86.4 v1(101.48,86.62)
  BOTTOM w0.102: J17.40 175.85,94.41 176.02,94.24 176.02,93.55 v1(175.73,93.26)
USB3P3_RXN_SYS: length 132.2
  TOP w0.102: E_L8.1 18.03,20.93 v2(18.03,21.58) 18.03,21.88 18.21,22.06 19.39,22.06 v1(19.44,22.01)
  IN4 w0.076: v1(100.57,85.34) 100.75,85.51 100.93,85.51 101.11,85.7 101.11,86.93 100.81,87.24 100.07,87.24 100.06,87.25 100.04,87.25
  IN4 w0.089: v1(19.44,22.01) 18.59,22.01 18.18,22.41 18.18,31.33 20.19,33.34 20.19,34.54 23.96,38.3 28.62,38.3 40.88,50.56 40.88,53.94 42.57,55.63 49.16,55.63 53.13,59.6 53.13,68.51 54.7,70.09 54.7,72.99 55.34,73.63 55.34,75.12 58.97,78.75 60.84,78.75 63.93,81.84 64.7,82.61 66.26,82.61 67.89,84.24 71.04,84.24 71.32,84.52 92.6,84.52 94.79,86.7 96.01,86.7 96.55,87.25 100.04,87.25
  BOTTOM w0.102: U1.G11 100.81,85.1 v1(100.57,85.34)
USB3P3_RXN_SYS_CONN: length 22.3
  TOP w0.102: J42.5 12.83,6.03 13.04,6.24 13.33,6.24 14.22,7.12 15.82,7.12 16.85,6.09 18.66,6.09 20.02,7.45 20.02,11.36 19.77,11.61 19.77,15.53 v2(19.01,16.3) 18.34,16.96 18.24,16.96 18.17,17.03 D53.9 D53.1 18.17,18.53 17.99,18.71 17.99,19.12 18.23,19.36 E_L8.2
USB3P3_RXP_DOCK: length 98.5
  IN1 w0.089: v1(176.49,93.26) 176.33,93.09 176.33,92.81 176.02,92.51 175.26,92.51 174.63,93.13 163.37,93.13 156.08,100.42 156.08,100.63 152.59,104.13 145.84,104.13 142.71,100.99 138.84,100.99 138.1,100.26 138.1,99.44 137.63,98.97 137.63,96.44 138.27,95.8 138.27,93.94 136.42,92.09 133.6,92.09 131.8,93.9 130.49,93.9 130.02,94.37 129.45,94.37 128.83,94.99 121.6,94.99 121.11,95.48 118.56,95.48 118.23,95.81 111.75,95.81 107.25,91.3 107.25,90.82 104.55,88.12 103.95,88.12 101.99,86.17 101.66,86.17 v1(101.48,85.99)
  BOTTOM w0.076: U1.F10 101.72,85.75 v1(101.48,85.99)
  BOTTOM w0.102: v1(176.49,93.26) 176.23,93.52 176.23,94.24 176.4,94.41 J17.41
USB3P3_RXP_SYS: length 132.3
  TOP w0.102: v1(19.44,22.78) 19.29,22.62 19.29,22.47 19.09,22.27 18.12,22.27 17.81,21.95 17.81,20.92 E_L8.4
  IN4 w0.076: v1(100.55,86) 100.55,85.8 100.68,85.68 100.86,85.68 100.95,85.76 100.95,86.86 100.74,87.07 100.07,87.07 100.06,87.06 100.04,87.06
  IN4 w0.089: v1(19.44,22.78) 19.44,22.59 19.05,22.2 18.67,22.2 18.37,22.49 18.37,31.25 20.39,33.27 20.39,34.46 24.04,38.11 28.7,38.11 41.07,50.48 41.07,53.86 42.65,55.44 49.24,55.44 53.32,59.52 53.32,68.43 54.89,70.01 54.89,72.91 55.53,73.56 55.53,75.04 59.05,78.56 60.92,78.56 64.78,82.42 66.34,82.42 67.97,84.05 71.12,84.05 71.4,84.33 92.68,84.33 94.87,86.51 96.08,86.51 96.63,87.06 100.04,87.06
  BOTTOM w0.102: U1.F11 100.8,85.75 v1(100.55,86)
USB3P3_RXP_SYS_CONN: length 22.3
  TOP w0.102: J42.6 12.83,6.57 12.94,6.46 12.95,6.46 12.97,6.44 13.25,6.44 14.13,7.33 15.91,7.33 16.94,6.3 18.57,6.3 19.82,7.54 19.82,11.27 19.56,11.52 v2(19.56,13.28) 19.56,15.45 18.28,16.73 17.98,16.73 17.67,17.05 D53.8 D53.2 17.67,18.52 17.78,18.64 17.78,19.17 17.63,19.32 E_L8.3
USB3P3_TXN_DOCK: length 100.7
  IN4 w0.089: v1(170.44,97.42) 170.72,97.42 170.74,97.41 170.82,97.32 170.82,97.05 170.64,96.87 169.77,96.87 168.72,95.82 168.72,93.9 165.63,90.8 163.05,90.8 162.83,90.58 155.6,90.58 155.46,90.72 152.08,90.72 151.13,89.77 150.66,89.77 149.17,88.28 143.9,88.28 143.38,88.79 142.85,88.79 141.9,89.74 141.23,89.74 138.05,92.92 134.22,92.92 131.45,95.69 130.28,95.69 129.6,96.37 122.58,96.37 120.8,98.15 117.34,98.15 116.74,98.75 113.92,98.75 113.56,98.4 106.07,98.4 105.87,98.6 104.65,98.6 104.48,98.42 104.31,98.42 v1(104.1,98.64)
  BOTTOM w0.076: U1.C15 98.99,87.82 99.05,87.88 99.07,87.95 99.07,88.17 99.11,88.29 99.11,88.31 99.14,88.4 99.14,88.57 99.09,88.68 99.09,88.91 99.14,89.04 99.14,89.44 99.05,89.53 99.05,89.77 99.02,89.8 99.02,89.81
  BOTTOM w0.102: J17.43 177.5,96.31 177.67,96.48 177.67,97.16 177.39,97.44 174.43,97.44 173.54,96.55 171.31,96.55 v1(170.44,97.42) ; v1(104.1,98.64) 103.82,98.37 103.54,98.37 103.2,98.03 v2(103.2,96.89) 103.2,94.94 102.21,93.95 102.21,92.73 101.13,91.64 100.47,91.64 99.02,90.19 99.02,89.81
USB3P3_TXN_SYS: length 156.9
  TOP w0.102: v1(17.03,22.87) 16.75,23.15 16.64,23.15 16.53,23.05 16.53,22.29 C236.2
  IN1 w0.089: v1(100.49,97.27) 99.88,97.27 98.57,95.96 97.41,95.96 96.8,95.35 96.8,93.77 95.27,92.24 92.34,92.24 90.56,90.46 90.56,89.37 90,88.81 82.1,88.81 80.65,90.27 80.65,91.07 79.88,91.83 79.05,91.83 78.01,92.87 72.13,92.87 70.74,91.48 70.74,89.96 69.98,89.2 67.18,89.2 59.93,81.95 56.55,81.95 52.33,77.74 46.25,77.74 35.65,67.14 35.65,66.58 34.85,65.78 23.84,65.78 22.84,64.78 22.84,63.81 20.23,61.21 20.23,48.89 19.88,48.53 19.88,43.14 14.75,38.01 14.75,24.8 16.48,23.07 16.83,23.07 v1(17.03,22.87)
  BOTTOM w0.076: U1.D16 98.01,88.01 98.01,88.28 98.23,88.5 98.23,90.54 98.57,90.87 98.57,90.9 98.58,90.92
  BOTTOM w0.102: v1(100.49,97.27) 100.42,97.2 100.13,97.2 100,97.2 99.75,96.95 99.75,92.08 98.58,90.92
USB3P3_TXN_SYS_C: length 0.9
  TOP w0.102: E_L7.1 16.54,20.93 16.54,21.33 C236.1
USB3P3_TXN_SYS_CONN: length 11.6
  TOP w0.102: J42.8 12.83,12.07 12.99,12.23 13.53,12.23 13.96,11.8 15.1,11.8 15.96,12.66 v2(15.96,12.87) 15.96,13.41 16.53,13.98 16.53,16.73 16.67,16.86 D53.7 D53.4 16.67,18.55 16.53,18.68 16.53,18.89 16.73,19.08 E_L7.2
USB3P3_TXP_DOCK: length 100.8
  IN4 w0.089: v1(104.1,98.06) 104.28,98.23 104.56,98.23 104.73,98.41 105.79,98.41 105.99,98.21 113.64,98.21 113.99,98.56 116.66,98.56 117.27,97.95 120.72,97.95 122.5,96.18 129.52,96.18 130.2,95.5 131.37,95.5 134.14,92.73 137.98,92.73 141.15,89.55 141.82,89.55 142.77,88.6 143.31,88.6 143.82,88.09 149.25,88.09 150.74,89.58 151.21,89.58 152.16,90.53 155.38,90.53 155.52,90.39 162.9,90.39 163.13,90.61 165.71,90.61 168.91,93.82 168.91,95.74 169.85,96.68 170.71,96.68 171.01,96.97 171.01,97.22 v1(171.21,97.42)
  BOTTOM w0.076: U1.D15 99.18,87.75 99.24,87.93 99.24,88.15 99.26,88.24 99.27,88.26 99.3,88.38 99.3,88.6 99.26,88.71 99.26,88.88 99.31,89.01 99.31,89.5 99.22,89.6 99.22,89.8 99.23,89.81
  BOTTOM w0.102: J17.44 178.05,96.31 177.88,96.48 177.88,97.25 177.48,97.65 174.34,97.65 173.45,96.76 171.4,96.76 171.08,97.08 171.08,97.29 v1(171.21,97.42) ; v1(104.1,98.06) 104,98.16 103.63,98.16 103.41,97.94 103.41,94.86 v2(102.75,94.19) 102.42,93.87 102.42,92.65 101.21,91.44 100.56,91.44 99.23,90.1 99.23,89.81
USB3P3_TXP_SYS: length 156.9
  TOP w0.102: v1(17.03,23.64) 16.75,23.36 16.55,23.36 16.33,23.14 16.33,22.29 C235.2
  IN1 w0.089: v1(17.03,23.64) 17.03,23.37 16.92,23.26 16.56,23.26 14.94,24.88 14.94,37.93 20.07,43.06 20.07,48.45 20.42,48.81 20.42,61.13 23.03,63.73 23.03,64.7 23.92,65.59 34.93,65.59 35.84,66.5 35.84,67.06 46.33,77.55 52.41,77.55 56.63,81.76 60.01,81.76 67.26,89.01 70.06,89.01 70.93,89.88 70.93,91.4 72.21,92.68 77.93,92.68 78.98,91.64 79.8,91.64 80.46,90.99 80.46,90.19 82.02,88.62 90.08,88.62 90.75,89.29 90.75,90.38 92.42,92.05 95.35,92.05 96.99,93.69 96.99,95.27 97.48,95.77 98.65,95.77 99.96,97.08 100.12,97.08 100.52,96.68 v1(100.52,96.66)
  BOTTOM w0.076: U1.C16 98.3,88.01 98.38,87.93 98.54,87.93 98.63,88.02 98.63,88.28 98.4,88.51 98.4,90.47 98.69,90.76 98.72,90.76 98.73,90.77
  BOTTOM w0.102: 98.73,90.77 99.96,92 99.96,96.86 100.08,96.99 100.19,96.99 v1(100.52,96.66)
USB3P3_TXP_SYS_C: length 0.9
  TOP w0.102: E_L7.4 16.33,20.94 16.33,21.32 C235.1
USB3P3_TXP_SYS_CONN: length 11.5
  TOP w0.102: J42.9 12.83,12.59 12.98,12.44 13.62,12.44 14.05,12.01 15.01,12.01 15.75,12.75 15.75,13.49 16.33,14.07 v2(16.33,14.39) 16.33,16.74 16.17,16.9 D53.6 D53.5 16.17,18.55 16.33,18.71 16.33,18.89 16.13,19.08 E_L7.3
USB20_N1_B: length 10.9
  TOP w0.076: U5.L7 24.43,49.21 22.44,49.21
  TOP w0.102: v1(21.91,49.39) 22.09,49.21 22.44,49.21
  BOTTOM w0.102: L16.1 14.92,50.48 14.99,50.41 14.99,50.16 15.05,50.09 16.07,50.09 17.15,49.01 21.54,49.01 21.64,49.12 21.64,49.27 21.76,49.39 v1(21.91,49.39)
USB20_N1_B_C: length 22.6
  TOP w0.102: U193.17 13.31,47.51 13.01,47.51 12.73,47.79 12.73,48.23 12.6,48.35 12.49,48.35 v1(12.3,48.16) 12.11,48.35 11.9,48.35 11.68,48.57 11.68,50.95 13.82,53.09 13.82,55.16 12.45,56.53 9.96,56.53 9.17,55.74 9.17,55.11 8.69,54.63 8.08,54.63 JTYC1.19
  BOTTOM w0.102: v1(12.3,48.16) 11.61,48.16 11.27,48.5 11.27,49.42 12.34,50.48 L16.2
USB20_N1_T: length 12
  TOP w0.076: 22.99,49.7 23,49.69 23.02,49.69 23.2,49.51 23.65,49.51 23.97,49.83 24.13,49.83 24.21,49.75 24.47,49.75 U5.L6
  TOP w0.102: 22.99,49.7 22.51,50.18 21.81,50.18 21.71,50.08 21.71,49.92 21.49,49.69 v1(21.37,49.69)
  BOTTOM w0.102: L17.4 14.87,51.66 15.07,51.86 15.29,51.86 16.08,51.07 16.71,51.07 17.07,51.43 17.59,51.43 18.99,50.02 21.22,50.02 21.37,49.87 v1(21.37,49.69)
USB20_N1_T_C: length 24
  TOP w0.102: U193.19 13.31,46.5 13.1,46.5 11.73,47.86 11.56,47.86 11.34,48.08 11.03,48.08 v1(10.85,48.26) 10.64,48.05 10.55,48.05 10.39,48.22 10.39,48.79 11.18,49.57 v2(11.18,50.72) 11.18,51.27 13.26,53.36 13.26,54.74 12.79,55.22 11.22,55.22 10.91,54.91 10.46,54.91 v1(10.28,55.09)
  BOTTOM w0.102: L17.3 13,51.66 12.88,51.78 12.88,51.99 12.81,52.06 12.29,52.06 11.18,50.94 11.18,50.06 10.06,48.94 10.06,48.02 10.2,47.89 10.44,47.89 10.49,47.94 10.49,48.21 10.54,48.26 v1(10.85,48.26) ; JTYC1.7 9.17,55.01 9.32,54.86 10.05,54.86 v1(10.28,55.09)
USB20_P1_B: length 11
  TOP w0.076: 22.47,49 22.48,49.01 22.51,49.01 22.52,49.02 24.64,49.02 24.98,49.25 U5.K7
  TOP w0.102: 22.47,49 22.46,48.99 22.11,48.99 v1(21.91,48.8)
  BOTTOM w0.102: v1(21.91,48.8) 21.91,48.81 17.06,48.81 15.98,49.88 L16.4
USB20_P1_B_C: length 22.6
  TOP w0.102: U193.16 13.33,47.72 13.1,47.72 12.94,47.88 12.94,48.31 12.69,48.56 12.49,48.56 v1(12.3,48.75) 12.12,48.56 11.99,48.56 11.89,48.66 11.89,50.87 14.03,53.01 14.03,55.25 12.53,56.74 9.87,56.74 8.96,55.83 8.96,55.2 8.6,54.84 8.13,54.84 JTYC1.18
  BOTTOM w0.102: L16.3 13.08,49.88 13.03,49.93 13.03,50.22 12.98,50.27 12.42,50.27 11.48,49.33 11.48,48.58 11.69,48.37 11.91,48.37 11.96,48.42 11.96,48.68 12.03,48.75 v1(12.3,48.75)
USB20_P1_T: length 12.1
  TOP w0.076: 23.14,49.85 23.15,49.84 23.15,49.82 23.28,49.69 23.58,49.69 23.89,50.01 24.59,50.01 U5.K6
  TOP w0.102: v1(21.39,50.39) 22.6,50.39 23.14,49.85
  BOTTOM w0.102: v1(21.39,50.39) 21.23,50.23 19.08,50.23 17.67,51.63 16.98,51.63 16.63,51.28 16.17,51.28 15.38,52.07 15.01,52.07 14.81,52.26 L17.1
USB20_P1_T_C: length 24.1
  TOP w0.102: U193.20 13.33,46.29 13.01,46.29 11.65,47.65 11.47,47.65 11.25,47.87 11.04,47.87 v1(10.85,47.68) 10.68,47.85 10.47,47.85 10.18,48.13 10.18,48.87 10.97,49.66 10.97,51.36 13.05,53.44 13.05,54.66 12.7,55.01 11.3,55.01 11,54.7 10.48,54.7 v1(10.28,54.51)
  BOTTOM w0.102: v1(10.85,47.68) 10.11,47.68 9.85,47.94 9.85,49.02 10.97,50.14 10.97,51.03 12.2,52.26 L17.2 ; v1(10.28,54.51) 10.13,54.65 9.35,54.65 9.21,54.51 JTYC1.6
USB_ON1: length 259.5
  TOP w0.102: U13.4 19.33,26.04 v1(19.86,26.57) ; U16.B4 235.11,73.7 235.11,72.64 235.57,72.18 235.57,69.41 236.97,68.01 v1(236.97,66.18)
  IN3 w0.081: v1(236.97,66.18) 236.97,63.79 236.1,62.93 234.83,62.93 227.52,55.61 226.4,55.61 225.12,54.33 225.12,52.22 221.24,48.35 218.14,48.35 217.66,47.87 212.94,47.87 211.49,49.31 208.91,49.31 207.26,47.66 207.26,47.01 206.13,45.88 203.77,45.88 202.93,45.05 193.99,45.05 191.92,47.12 190.99,47.12 190.14,47.97 96.02,47.97 93.32,45.27 93.32,44.42 v1(93.19,44.29)
  BOTTOM w0.102: v1(93.19,44.29) 92.59,44.29 90.46,46.42 85.73,46.42 77.12,37.81 21.04,37.81 19.81,36.58 19.81,32.64 18.45,31.28 18.45,27.98 v1(19.86,26.57)
USB_ON2: length 58.1
  TOP w0.102: U16.E4 v1(235.11,76.1) ; v1(266.23,77.76) 266.23,78.17 266.51,78.45 v3(269.63,78.45) 269.87,78.21 274.44,78.21 274.81,78.57 U12.5
  IN4 w0.076: v1(235.11,76.1) 235.51,76.5 236.19,76.5 237.32,77.63 237.32,80.35 238.67,81.7 238.67,83.22 240.29,84.85 240.67,84.85 242.06,86.23 242.06,86.84 243.8,88.58 250.89,88.58 251.8,87.67 255.99,87.67 256.42,88.1 261.58,88.1 266.63,83.04 266.63,78.35 266.23,77.94 v1(266.23,77.76)
USB_PWR_S1: length 0.7
  TOP w0.305: C99.2 285.26,74.12 ; C100.2 284.63,74.12
  vias: v1(276.91,82.54) v1(277.07,81.98) v1(277.29,83.05) v1(277.63,82.46) v1(277.7,81.86) v1(278.26,82.08) v1(283.77,75.56) v1(283.95,75) v1(284.18,75.99) v1(284.51,75.37) v1(284.79,76.01) v1(285.1,75.37) v3(284.49,74.71)
USB_PWR_S2: length 2.1
  BOTTOM w0.305: 18.09,16.01 C230.2 ; C230.2 C232.2 ; C230.2 17.78,16.36 ; 19.22,16.36 C232.2 ; C232.2 18.7,16.01
  vias: v1(13.75,21.98) v1(14.15,21.28) v1(14.39,21.96) v1(14.76,21.33) v1(15,21.96) v1(15.37,21.33) v2(14.69,15.73) v2(14.69,14.97) v2(15.35,15.73) v2(15.35,14.97) v2(16.52,13.3) v2(16.52,12.53) v2(19.05,15.28) v2(19.06,14.62) v2(19.06,13.86) v4(14.06,22.57)
USBC_CC1: length 15.7
  TOP w0.203: C815.1 19.75,49.17 20.34,48.58 R707.2 20.77,48.58 21.48,47.87 22.16,47.87 22.46,47.57 v4(22.51,47.57) 22.91,47.57 23.62,48.27 U5.L9 ; U193.12 15.22,48.81 v1(15.72,49.32)
  TOP w0.254: v1(18.7,47.71) 18.52,47.9 TP77.1 18.93,49.17 C815.1
  IN4 w0.254: v1(18.7,47.71) 18.04,47.71 16.44,49.32 v1(15.72,49.32)
  BOTTOM w0.203: v1(15.72,49.32) 14.23,47.83 R10245.1
USBC_CC1_CONN: length 20.3
  TOP w0.203: U193.7 16.56,46.6 17.04,46.12 17.04,45.42 16.27,44.64 v1(15.48,44.64) 15.48,44.97 15.22,45.23 U193.4
  IN3 w0.081: v1(10.82,53.51) 13.08,51.25 13.08,48.33 15.48,45.93 v1(15.48,44.64)
  BOTTOM w0.102: v1(10.82,53.51) 10.34,53.99 10.09,53.99 9.91,54.17 9.4,54.17 9.24,54.01 JTYC1.5
  BOTTOM w0.203: v1(15.48,44.64) 15.48,44.89 v3(14.76,45.61) 14.23,46.14 R10245.2
USBC_CC2: length 14.1
  TOP w0.203: v1(16.16,48.81) 16.13,48.84 15.8,48.84 15.62,48.65 U193.11 ; U5.L10 24.13,47.77 23.52,47.16 23.52,46.83 v4(23.22,46.52) 23.14,46.45 20.93,46.45 R708.2
  TOP w0.254: R708.2 20.25,46.83 19.8,47.29 C817.1 19.61,47.4 19.44,47.22 TP78.1 18.93,46.72 18.77,46.89 v1(18.53,46.89)
  IN4 w0.254: v1(16.16,48.81) 18.08,46.89 v1(18.53,46.89)
  BOTTOM w0.203: v1(16.16,48.81) 15.77,48.81 14.79,47.83 R10246.1
USBC_CC2_CONN: length 22.9
  TOP w0.203: U193.5 15.62,45.44 15.93,45.12 v1(16.09,45.12) 16.7,45.73 16.7,46.04 16.53,46.2 U193.6
  IN3 w0.081: v1(16.09,45.12) 16.09,45.63 13.26,48.45 13.26,54.5 11.22,56.54 7.61,56.54 7.38,56.32 7.38,56.26 7.32,56.2 7.32,56.03 JTYC1.17
  BOTTOM w0.203: v1(16.09,45.12) 15.98,45.12 14.79,46.31 R10246.2
USBC_DPAUX1: length 30.3
  TOP w0.102: U193.15 14.02,48.74 v1(13.7,49.06)
  IN4 w0.089: v1(13.7,49.06) 13.91,49.27 13.91,49.7 14.39,50.18 16.38,50.18 16.99,49.57 18.66,49.57 19.74,50.65 19.74,52.21 21.77,54.25 23.88,54.25 25.59,55.96 25.59,62.08 v1(25.4,62.28)
  BOTTOM w0.102: R10243.1 13.12,48.48 v1(13.7,49.06) ; v1(25.4,62.28) 25.59,62.48 25.59,62.85 25.39,63.06 25.39,64.09 v2(25.75,64.46) 25.99,64.7 26.82,64.7 27.1,64.97 27.1,65.54 U183.27
USBC_DPAUX1_C: length 24.9
  TOP w0.102: R9110.1 13.69,51.7 12.96,50.97 v1(12.6,50.97) ; U193.1 14.02,45.25 13.77,45 v3(13.77,44.44) 13.93,44.28 v1(14.61,44.28)
  IN3 w0.081: v1(10.91,55.62) 10.09,55.62 9.58,55.11 9.58,53.36 10.01,52.93 10.64,52.93 v1(12.6,50.97) 12.9,50.66 12.9,48.23 15.06,46.07 15.06,44.73 v1(14.61,44.28)
  BOTTOM w0.102: JTYC1.8 9.28,55.51 9.44,55.35 9.85,55.35 10.11,55.62 v1(10.91,55.62) ; R10243.2 13.12,45.78 v1(14.61,44.28)
USBC_DPAUX2: length 30.4
  TOP w0.102: v1(14.31,49.11) 14.42,49 U193.14
  IN4 w0.089: v1(25.98,62.28) 25.78,62.08 25.78,55.88 23.96,54.06 21.85,54.06 19.93,52.14 19.93,50.58 18.73,49.38 16.92,49.38 16.31,49.99 14.47,49.99 14.1,49.62 14.1,49.3 14.28,49.11 v1(14.31,49.11)
  BOTTOM w0.102: v1(25.98,62.28) 25.8,62.46 25.8,62.94 25.6,63.14 25.6,64.01 26.08,64.49 26.91,64.49 27.55,65.13 U183.26 ; v1(14.31,49.11) 14.31,49.08 13.67,48.45 v4(13.67,48.02) R10244.1
USBC_DPAUX2_C: length 24.6
  TOP w0.102: v1(12.45,49.52) 13.29,49.52 v3(13.74,49.98) 14.53,50.76 R9108.2 ; v1(14.61,44.87) 14.61,44.94 14.42,45.14 U193.2
  IN3 w0.081: v1(14.61,44.87) 14.61,46.26 12.73,48.15 12.73,49.24 v1(12.45,49.52) 11.91,50.06 11.91,51.25 10.67,52.49 9.4,52.49 9.25,52.65 9.25,55.13 9.12,55.26 8.82,55.26 8.69,55.13 8.69,52.77 8.51,52.6 7.99,52.6 7.38,53.2 7.38,53.26 6.9,53.75 JTYC1.20
  BOTTOM w0.102: v1(14.61,44.87) 13.67,45.81 R10244.2
USBCOMP: length 3.1
  TOP w0.102: v4(103.34,80.1) 103.2,79.96 103.2,79.54 103.61,79.14 RC48.2 104.19,78.59 v1(104.26,78.52)
  BOTTOM w0.102: v1(104.26,78.52) 104.26,78.3 U1.AB6
USBP0+: length 197.6
  TOP w0.102: U12.3 273.41,80.43 273.27,80.58 272.6,80.58 272.35,80.83 271.92,80.83 271.53,80.43 v1(271.53,80.27)
  IN1 w0.089: v1(271.53,80.27) 271.06,80.74 270.85,80.74 270.61,80.98 270.61,81.72 269.88,82.45 266.54,82.45 263.76,85.23 256.37,85.23 254.76,86.84 247.12,86.84 246.53,87.44 244.42,87.44 242.23,89.62 241.51,89.62 241.16,89.98 240.5,89.98 240.12,90.36 237.15,90.36 236.85,90.66 232.34,90.66 231.77,90.09 223.16,90.09 222.58,90.67 216.49,90.67 215.36,89.54 209.67,89.54 207.74,91.46 196.25,91.46 195.61,92.1 185.76,92.1 184.49,93.37 180.05,93.37 177.33,90.65 175.66,90.65 174.99,89.98 168.64,89.98 168.08,89.42 159.92,89.42 159.62,89.13 158.4,89.13 157.66,89.87 156.2,89.87 155.53,90.54 151.66,90.54 150.57,89.45 142.01,89.45 141.02,90.44 132.95,90.44 131.17,92.22 128.94,92.22 128.72,92.44 120.94,92.44 120.63,92.75 118.65,92.75 117.29,94.11 113.36,94.11 110.73,91.48 110.73,88.58 109.61,87.46 109.61,86.92 109.13,86.43 109.13,86.04 108.79,85.7 107.89,85.7 106.96,84.77 106.96,80.26 105.51,78.82 105.51,78.13 104.16,76.78 102.8,76.78 102.49,77.1 102.49,77.33 v1(102.33,77.49)
  BOTTOM w0.076: U1.AB10 102.16,77.73 v1(102.33,77.49)
USBP0+_AOU: length 3.4
  TOP w0.102: U12.10 277.48,80.43 277.68,80.63 277.85,80.63 v2(278.17,80.95) 278.76,81.55 279.87,81.55 E_L1.4
USBP0+_CONN: length 12
  TOP w0.102: E_L1.3 281.68,81.42 281.88,81.61 283.27,81.61 D13.3 284.61,80.84 284.61,81.27 v1(284.46,81.42)
  BOTTOM w0.089: J34.3 286.87,77.84 286.64,77.61 285.98,77.61 284.43,79.16 v2(284.43,79.67) 284.43,80.33 283.95,80.81 283.95,81.6 284.02,81.68 284.3,81.68 284.46,81.53 v1(284.46,81.42)
USBP0-: length 197.6
  TOP w0.102: U12.2 273.41,80.93 273.27,80.79 272.69,80.79 272.44,81.04 271.86,81.04 271.5,81.39 v1(271.5,81.55)
  IN1 w0.089: v1(271.5,81.55) 271.5,81.34 271.1,80.93 270.93,80.93 270.8,81.06 270.8,81.8 269.96,82.64 266.62,82.64 263.84,85.42 256.45,85.42 254.84,87.03 247.2,87.03 246.61,87.63 244.5,87.63 242.31,89.81 241.59,89.81 241.24,90.17 240.58,90.17 240.19,90.55 237.23,90.55 236.93,90.86 232.26,90.86 231.69,90.28 223.24,90.28 222.66,90.86 216.41,90.86 215.28,89.73 209.75,89.73 207.82,91.66 196.33,91.66 195.69,92.29 185.84,92.29 184.57,93.56 179.97,93.56 177.25,90.84 175.58,90.84 174.91,90.17 168.56,90.17 168,89.61 159.84,89.61 159.54,89.32 158.48,89.32 157.74,90.06 156.28,90.06 155.61,90.73 151.58,90.73 150.49,89.64 142.09,89.64 141.1,90.63 133.02,90.63 131.25,92.41 129.02,92.41 128.8,92.64 121.02,92.64 120.71,92.94 118.73,92.94 117.37,94.3 113.28,94.3 110.54,91.56 110.54,88.66 109.42,87.54 109.42,86.99 108.94,86.51 108.94,86.12 108.71,85.89 107.81,85.89 106.77,84.85 106.77,80.34 105.32,78.89 105.32,78.21 104.08,76.97 102.88,76.97 102.68,77.18 102.68,77.36 102.81,77.49 v1(102.97,77.49)
  BOTTOM w0.076: U1.AB9 102.81,77.73 v1(102.97,77.49)
USBP0-_AOU: length 3.4
  TOP w0.102: U12.11 277.51,80.93 277.58,80.86 277.73,80.86 278.65,81.77 v2(279.23,81.77) 279.75,81.77 E_L1.1
USBP0-_CONN: length 12.1
  TOP w0.102: E_L1.2 281.7,82.02 281.9,81.82 283.19,81.82 D13.4 284.46,82.83 v1(284.46,82.05)
  BOTTOM w0.089: J34.2 286.87,77.13 286.57,77.44 285.91,77.44 284.25,79.09 284.25,80.26 283.77,80.74 283.77,81.68 283.95,81.85 284.26,81.85 v1(284.46,82.05)
USBP1+: length 166.5
  TOP w0.076: U5.L5 24.43,50.33 23.86,50.33 23.68,50.51 23.4,50.51 v1(23.2,50.31)
  IN1 w0.089: v1(23.2,50.31) 23.36,50.47 23.56,50.47 23.61,50.42 23.61,48.84 20.87,46.1 20.87,41.11 15.97,36.21 15.97,28.86 19.55,25.27 24.41,25.27 24.56,25.12 24.56,24.92 24.53,24.9 24.53,24.89 24.42,24.78 v1(24.19,24.78)
  IN4 w0.089: v1(24.19,24.78) 24.39,24.78 24.77,25.15 24.77,25.72 25.18,26.14 88.49,26.14 90.73,28.37 90.73,41.39 90.29,41.82 90.29,50.92 92.51,53.13 97.38,53.13 100.99,56.73 100.99,57.5 102.38,58.89 102.38,66.37 100.96,67.79 100.96,69.03 100.95,69.04 100.95,69.5 100.96,69.51 100.96,71.56 101.23,71.83 101.52,71.83 103.58,73.89 105.09,73.89 105.32,74.12 105.32,75.39 104.67,76.04 104.67,76.12 104.37,76.42 v1(104.21,76.42)
  BOTTOM w0.102: U1.AD7 103.97,76.67 v1(104.21,76.42)
USBP1-: length 166.6
  TOP w0.076: U5.K5 24.74,50.51 23.93,50.51 23.75,50.69 23.39,50.69 v1(23.2,50.89)
  IN1 w0.089: v1(24.96,24.78) 24.75,24.99 24.75,25.2 24.49,25.46 19.63,25.46 16.16,28.94 16.16,36.13 21.06,41.03 21.06,46.02 23.8,48.76 23.8,50.5 23.64,50.66 23.42,50.66 v1(23.2,50.89)
  IN4 w0.089: v1(24.96,24.78) 24.96,25.65 25.26,25.95 88.57,25.95 90.92,28.29 90.92,41.46 90.48,41.9 90.48,50.84 92.58,52.94 97.46,52.94 101.18,56.65 101.18,57.42 102.57,58.81 102.57,66.45 101.15,67.87 101.15,69.11 101.14,69.12 101.14,69.42 101.15,69.43 101.15,71.48 101.3,71.64 101.6,71.64 103.66,73.7 105.17,73.7 105.51,74.04 105.51,75.47 104.88,76.09 v1(104.88,76.43)
  BOTTOM w0.102: v1(104.88,76.43) 104.62,76.69 U1.AD6
USBP2+: length 151.5
  TOP w0.102: v1(217.5,62.65) 217.8,62.35 217.8,62.08 218.18,61.7 221.64,61.7 222.27,61.07 226.64,61.07 227.61,60.1 227.61,58.75 228.45,57.91 v2(228.45,56.96) 228.45,56.22 228.09,55.85 R102.2
  IN1 w0.089: v1(217.5,62.65) 217.73,62.42 217.73,62.22 217.68,62.17 216.42,62.17 215.01,63.58 213.57,63.58 213.43,63.72 207.18,63.72 206.52,63.05 202.06,63.05 201.49,62.48 200.82,62.48 199.17,64.13 192.29,64.13 191.91,64.52 185.39,64.52 184.77,65.14 182.21,65.14 181.11,66.24 172.45,66.24 171.92,66.78 163.06,66.78 162.46,67.39 159.37,67.39 158.44,66.46 158.44,66.07 156.64,64.26 155.68,64.26 153.55,62.13 145.46,62.13 143.93,63.66 143.16,63.66 142.4,64.43 142.4,66.1 139.68,68.82 139.68,70.07 137.63,72.12 136.99,72.12 135.82,73.29 134.81,73.29 134.05,74.05 133.13,74.05 132.76,74.42 130.21,74.42 127.13,77.5 118.57,77.5 117.28,78.79 115.58,78.79 114.03,77.24 108.3,77.24 107.39,76.33 107.39,74.98 108.06,74.31 109.01,74.31 109.46,73.86 109.46,73.42 v1(109.25,73.21)
  BOTTOM w0.076: U1.AJ3 105.97,73.68 105.81,73.84 105.81,73.97 105.85,74.01 106,74.01 106.24,73.91 106.48,73.91 106.64,73.96 106.73,73.96 106.95,73.9 107.12,73.9 107.25,73.95 108.98,73.95 109.41,73.52 109.41,73.37 v1(109.25,73.21)
USBP2+_CONN: length 4.9
  TOP w0.102: R102.1 228.03,54.75 227.88,54.6 227.53,54.6 227.09,54.15 227.09,53.96 226.77,53.64 D17.2 227.07,53.23 227.07,53.06 226.93,52.92 v1(226.93,52.82)
  BOTTOM w0.102: J22.7 227.1,52.23 227.23,52.36 227.23,52.52 v1(226.93,52.82)
USBP2-: length 151.5
  TOP w0.102: R103.2 228.66,58 227.82,58.84 227.82,60.18 226.72,61.28 222.36,61.28 221.73,61.91 218.26,61.91 218.01,62.16 218.01,62.4 v1(218.26,62.65)
  IN1 w0.089: v1(109.84,73.21) 109.65,73.41 109.65,73.94 109.09,74.5 108.14,74.5 107.58,75.06 107.58,76.25 108.38,77.05 114.11,77.05 115.66,78.6 117.2,78.6 118.5,77.31 127.06,77.31 130.13,74.23 132.68,74.23 133.05,73.86 133.97,73.86 134.73,73.1 135.74,73.1 136.91,71.93 137.55,71.93 139.49,69.99 139.49,68.74 142.21,66.02 142.21,64.35 143.08,63.47 143.85,63.47 145.38,61.94 153.63,61.94 155.76,64.07 156.72,64.07 158.63,65.99 158.63,66.38 159.45,67.2 162.38,67.2 162.99,66.59 171.84,66.59 172.37,66.05 181.03,66.05 182.13,64.95 184.69,64.95 185.31,64.32 191.83,64.32 192.21,63.94 199.09,63.94 200.75,62.29 201.57,62.29 202.14,62.86 206.6,62.86 207.26,63.52 213.35,63.52 213.49,63.39 214.93,63.39 216.34,61.98 217.76,61.98 217.92,62.14 217.92,62.51 218.06,62.65 v1(218.26,62.65)
  BOTTOM w0.076: v1(109.84,73.21) 109.57,73.48 109.57,73.59 109.04,74.12 107.22,74.12 107.09,74.07 106.97,74.07 106.75,74.13 106.61,74.13 106.45,74.07 106.27,74.07 106.03,74.18 105.88,74.18 U1.AH3
USBP2-_CONN: length 4.9
  TOP w0.102: R103.1 228.23,54.84 228.23,54.66 227.96,54.39 227.62,54.39 227.29,54.07 227.29,54.01 D17.3 227.28,53.26 227.28,53.06 v1(227.52,52.82)
  BOTTOM w0.102: v1(227.52,52.82) 227.44,52.74 227.44,52.36 227.6,52.2 J22.9
USBP3+_DOCK: length 96.7
  IN1 w0.089: v1(102.33,76.42) 102.46,76.29 102.46,75.93 102.71,75.68 104.96,75.68 105.61,76.33 105.61,77.32 106.05,77.76 106.05,78.47 107.71,80.12 107.71,82.38 108.42,83.1 108.42,84.31 109.8,85.7 109.8,86.17 110.27,86.64 110.27,87.16 111.01,87.9 112.85,87.9 113.44,87.3 116.25,87.3 118.42,89.47 118.42,90.44 118.92,90.93 120.72,90.93 121.58,91.78 128.44,91.78 128.67,91.55 130.89,91.55 132.65,89.78 139.55,89.78 140.87,88.45 150.56,88.45 151.6,89.5 155.64,89.5 155.93,89.21 157.38,89.21 158.13,88.46 160.47,88.46 160.84,88.09 173.4,88.09 174.22,88.9 176.21,88.9 176.56,89.25 176.56,89.95 v1(176.74,90.13)
  BOTTOM w0.076: v1(102.33,76.42) 102.18,76.64 U1.AD10
  BOTTOM w0.102: v1(176.74,90.13) 176.56,90.31 176.56,90.81 174.58,92.79 174.58,94.24 174.75,94.41 J17.38
USBP3+_SYS: length 144.9
  TOP w0.102: E_L9.1 18.27,13.88 v2(18.27,14.72) 18.27,15.99 18.02,16.24 17.48,16.24 17.21,16.51 v1(17.21,16.52)
  IN4 w0.076: 102.35,74.62 102.37,74.63 102.39,74.63 102.56,74.81 104.44,74.81 104.54,74.91 104.54,74.99 v1(104.31,75.21)
  IN4 w0.089: v1(17.21,16.52) 17.47,16.26 17.95,16.26 18.75,17.06 18.75,20.73 19.94,21.91 19.94,25.45 21.32,26.83 88.02,26.83 90.05,28.87 90.05,41.12 89.61,41.56 89.61,51.17 92.27,53.84 96.33,53.84 100.01,57.52 100.01,57.57 101.61,59.17 101.61,65.86 100.07,67.4 100.07,69.38 99.67,69.78 99.67,70.48 100.03,70.85 100.03,72.29 100.19,72.44 100.19,72.83 101.66,74.31 102.04,74.31 102.35,74.62
  BOTTOM w0.076: U1.AF7 104.31,75.46 v1(104.31,75.21)
USBP3+_SYS_CONN: length 10.3
  TOP w0.102: J42.3 14.33,9.05 14.52,9.24 17.08,9.24 D54.3 18.08,9.24 18.18,9.35 18.6,9.35 19.29,10.03 v2(19.29,10.38) 19.29,10.88 18.23,11.94 18.23,12.28 E_L9.2
USBP3-_DOCK: length 96.6
  IN1 w0.089: v1(102.97,76.42) 102.82,76.42 102.65,76.25 102.65,76.13 102.65,76.01 102.79,75.87 104.88,75.87 105.42,76.41 105.42,77.4 105.86,77.84 105.86,78.55 107.51,80.2 107.51,82.46 108.23,83.17 108.23,84.39 109.61,85.78 109.61,86.25 110.08,86.72 110.08,87.24 110.93,88.09 112.93,88.09 113.52,87.49 116.17,87.49 118.23,89.55 118.23,90.52 118.84,91.12 120.64,91.12 121.5,91.97 128.52,91.97 128.75,91.74 130.96,91.74 132.73,89.97 139.63,89.97 140.95,88.65 150.48,88.65 151.52,89.69 155.72,89.69 156.01,89.4 157.46,89.4 158.21,88.65 160.55,88.65 160.92,88.28 173.32,88.28 174.14,89.09 176.13,89.09 176.37,89.33 176.37,89.94 176.18,90.13 v1(175.98,90.13)
  BOTTOM w0.076: U1.AD9 102.82,76.64 v1(102.97,76.42)
  BOTTOM w0.102: J17.37 174.2,94.41 174.37,94.24 174.37,92.71 176.35,90.72 176.35,90.25 176.23,90.13 v1(175.98,90.13)
USBP3-_SYS: length 144.9
  TOP w0.102: v1(17.21,15.75) 17.49,16.03 17.93,16.03 18.06,15.9 18.06,13.97 E_L9.4
  IN4 w0.076: v1(104.94,75.21) 104.71,74.99 104.71,74.84 104.51,74.65 102.63,74.65 102.5,74.52 102.5,74.5 102.49,74.48
  IN4 w0.089: 102.49,74.48 102.12,74.12 101.74,74.12 100.38,72.76 100.38,72.36 100.23,72.21 100.23,70.77 99.86,70.4 99.86,69.86 100.26,69.46 100.26,67.47 101.8,65.94 101.8,59.09 100.2,57.49 100.2,57.44 96.41,53.65 92.35,53.65 89.8,51.09 89.8,41.64 90.24,41.2 90.24,28.79 88.1,26.64 21.4,26.64 20.13,25.37 20.13,21.83 18.95,20.65 18.95,16.98 18.03,16.06 17.52,16.06 v1(17.21,15.75)
  BOTTOM w0.076: U1.AF6 104.62,75.75 104.94,75.43 v1(104.94,75.21)
USBP3-_SYS_CONN: length 10.3
  TOP w0.102: E_L9.3 18.02,12.28 18.02,11.86 v2(18.17,11.71) 19.08,10.8 19.08,10.12 18.51,9.55 18.18,9.55 18.08,9.66 D54.4 16.88,9.45 14.55,9.45 14.33,9.67 J42.2
USBP4+: length 32
  IN1 w0.089: v1(107.49,73.19) 107.62,73.06 107.62,72.7 107.86,72.47 110.89,72.47 111.3,72.87 112.88,72.87 114.62,71.13 118,71.13 120.37,68.76 124.02,68.76 126.45,66.33 129.68,66.33 130.27,65.74 v1(132.01,65.74)
  BOTTOM w0.076: v1(107.49,73.19) 107.33,73.35 107.02,73.35 107.01,73.36 U1.AJ2
  BOTTOM w0.102: J26.6 133.86,65.81 133.77,65.9 132.18,65.9 v1(132.01,65.74)
USBP4-: length 31.9
  IN1 w0.089: v1(108.07,73.2) 107.81,72.94 107.81,72.78 107.93,72.66 110.81,72.66 111.22,73.06 112.96,73.06 114.7,71.32 118.08,71.32 120.45,68.95 124.1,68.95 126.53,66.52 129.76,66.52 130.35,65.93 131.62,65.93 v1(132.01,66.32)
  BOTTOM w0.076: U1.AJ1 107.47,73.55 107.71,73.55 v1(108.07,73.2)
  BOTTOM w0.102: J26.4 133.87,66.31 133.67,66.11 132.23,66.11 v1(132.01,66.32)
USBP6+: length 116.6
  TOP w0.102: R105.2 202.63,57.15 v2(202.63,59.17) 202.63,59.9 203.56,60.83 203.56,61.05 v1(203.16,61.46)
  IN1 w0.089: v1(203.16,61.46) 203.58,61.87 203.58,62.01 203.45,62.14 202.63,62.14 202.02,61.53 200.41,61.53 199.38,62.56 196.2,62.56 195.5,63.26 194.29,63.26 194.07,63.03 190.6,63.03 189.99,63.64 185.02,63.64 184.38,64.29 181.86,64.29 180.78,65.37 171.49,65.37 171,65.86 162.69,65.86 162.02,66.53 159.75,66.53 159.29,66.08 159.29,65.7 156.74,63.14 155.77,63.14 152.9,60.27 139.88,60.27 138.81,61.35 138.81,62.8 136.96,64.64 136.48,64.64 135.95,65.18 135.51,65.18 133.56,67.12 131.72,67.12 131.62,67.02 126.73,67.02 123.49,70.26 120.02,70.26 118.47,71.81 114.93,71.81 113.2,73.53 111,73.53 110.55,73.99 110.55,74.35 v1(110.56,74.6)
  BOTTOM w0.076: v1(110.56,74.6) 110.56,74.22 110.44,74.1 109.87,74.1 109.22,74.75 106.85,74.75 106.68,74.58 106.68,74.42 106.6,74.34 106.37,74.34 U1.AH2
USBP6+_CONN: length 10.9
  TOP w0.102: v1(196.45,52.86) 196.83,52.86 197.27,53.3 197.56,53.3 197.79,53.54 199,53.54 199.08,53.45 200.63,53.45 201.1,53.93 201.1,54.66 201.32,54.88 201.53,54.88 201.85,55.2 D19.3 202.35,54.75 202.44,54.75 202.72,55.03 202.72,55.41 202.44,55.68 R105.1
  BOTTOM w0.102: J32.3 196.8,52.51 v1(196.45,52.86)
USBP6-: length 116.7
  TOP w0.102: R106.2 202.84,57.15 202.84,59.81 203.77,60.74 v1(203.77,61.46)
  IN1 w0.089: v1(111.22,74.6) 111.13,74.6 110.74,74.22 110.74,74.21 110.74,74.06 111.08,73.72 113.28,73.72 115.01,72 118.55,72 120.1,70.45 123.57,70.45 126.81,67.21 131.54,67.21 131.64,67.31 133.64,67.31 135.58,65.37 136.03,65.37 136.56,64.83 137.04,64.83 139,62.88 139,61.43 139.96,60.46 152.83,60.46 155.7,63.33 156.66,63.33 159.1,65.78 159.1,66.16 159.67,66.73 162.1,66.73 162.77,66.05 171.08,66.05 171.57,65.56 180.86,65.56 181.94,64.48 184.45,64.48 185.1,63.83 190.07,63.83 190.67,63.22 193.99,63.22 194.22,63.45 195.58,63.45 196.28,62.75 199.46,62.75 200.49,61.72 201.94,61.72 202.55,62.33 203.53,62.33 203.77,62.09 v1(203.77,61.46)
  BOTTOM w0.076: v1(111.22,74.6) 111.12,74.6 110.72,74.2 110.72,74.15 110.51,73.94 109.8,73.94 109.15,74.59 106.92,74.59 106.84,74.51 106.84,74.41 106.91,74.34 U1.AH1
USBP6-_CONN: length 10.9
  TOP w0.102: 201.9,54.2 202.25,54.55 202.53,54.55 202.92,54.94 202.92,55.49 202.65,55.77 202.65,55.95 202.75,56.04 202.95,56.04 203.03,56.12 R106.1 ; 201.9,54.2 201.74,54.37 201.74,54.6 201.66,54.67 201.41,54.67 201.31,54.58 201.31,53.84 200.72,53.25 v2(199.53,53.25) 199,53.25 198.92,53.33 197.88,53.33 v1(197.42,52.87) ; 201.9,54.2 D19.2
  BOTTOM w0.102: v1(197.42,52.87) 197.11,52.87 197.04,52.79 197.04,52.62 197.3,52.35 J32.5
USBP7+: length 224.3
  IN1 w0.076: v1(103.03,75.23) 103.31,74.95 103.31,74.85 103.48,74.68 105.41,74.68 105.42,74.66 105.44,74.66
  IN1 w0.089: 105.44,74.66 105.71,74.66 106.45,75.4 106.45,77.23 106.58,77.35 106.58,78 109.48,80.91 109.48,83.65 110.46,84.63 110.46,85.89 111.48,86.91 112.85,86.91 113.11,86.64 116.68,86.64 117.88,87.83 118.64,87.83 120.94,90.13 122.96,90.13 123.4,90.57 126.17,90.57 126.33,90.73 130.27,90.73 131.92,89.08 139.31,89.08 140.6,87.79 150.84,87.79 151.88,88.84 155.37,88.84 156.21,88 157.6,88 158.2,87.4 180.11,87.4 180.64,86.87 184.38,86.87 186.15,88.65 186.15,89.08 188.51,91.44 195.21,91.44 195.87,90.78 207.26,90.78 209.55,88.49 216.49,88.49 216.85,88.12 218.81,88.12 219.18,88.49 221.95,88.49 222.9,89.43 232.08,89.43 232.64,89.99 236.57,89.99 236.97,89.6 239.9,89.6 240.21,89.28 240.64,89.28 241.02,88.9 241.97,88.9 242.06,88.81 242.06,88.6 v1(241.79,88.33)
  BOTTOM w0.076: U1.AF9 102.66,75.78 v1(103.03,75.23)
  BOTTOM w0.102: R12.1 265.59,132.55 265.59,132.47 264.83,131.71 264.83,129.81 265.66,128.99 265.66,125.46 262.9,122.7 v2(262.9,117.62) 262.9,108.04 260.74,105.88 252.75,105.88 250.7,103.83 247.47,103.83 245.57,101.92 242.03,101.92 240.14,100.03 240.14,90.47 240.65,89.95 241.39,89.95 242.06,89.27 242.06,88.49 241.9,88.33 v1(241.79,88.33)
USBP7+_CONN: length 5.9
  BOTTOM w0.102: J11.8 268.85,135.79 268.97,135.67 268.97,135.18 268.85,135.06 266.68,135.06 v2(265.77,134.15) 265.62,134 265.62,133.57 R12.2
USBP7-: length 224.3
  IN1 w0.076: 105.44,74.85 105.42,74.85 105.41,74.84 103.55,74.84 103.47,74.92 103.47,75 v1(103.69,75.22)
  IN1 w0.089: 105.44,74.85 105.64,74.85 106.26,75.48 106.26,77.3 106.38,77.43 106.38,78.08 109.29,80.99 109.29,83.73 110.27,84.71 110.27,85.97 111.4,87.1 112.93,87.1 113.19,86.83 116.61,86.83 117.8,88.02 118.56,88.02 120.86,90.32 122.88,90.32 123.32,90.76 126.09,90.76 126.25,90.92 130.34,90.92 132,89.27 139.39,89.27 140.68,87.99 150.76,87.99 151.8,89.03 155.45,89.03 156.28,88.19 157.68,88.19 158.28,87.59 180.19,87.59 180.72,87.06 184.3,87.06 185.96,88.73 185.96,89.16 188.43,91.63 195.28,91.63 195.94,90.97 207.34,90.97 209.63,88.68 216.56,88.68 216.93,88.31 218.73,88.31 219.1,88.68 221.87,88.68 222.82,89.62 232,89.62 232.56,90.18 236.65,90.18 237.05,89.79 239.98,89.79 240.29,89.47 240.72,89.47 241.1,89.09 242.05,89.09 242.25,88.89 242.25,88.63 v1(242.55,88.33)
  BOTTOM w0.076: U1.AF8 v1(103.69,75.22)
  BOTTOM w0.102: v1(242.55,88.33) 242.27,88.61 242.27,89.36 241.48,90.16 240.74,90.16 240.34,90.55 240.34,99.95 242.11,101.71 245.65,101.71 247.56,103.62 250.78,103.62 252.84,105.67 260.82,105.67 263.1,107.95 v2(263.1,121.36) 263.1,122.62 265.86,125.38 265.86,129.07 265.04,129.9 265.04,131.63 265.79,132.38 265.79,132.57 R11.1
USBP7-_CONN: length 5.8
  BOTTOM w0.102: J11.9 269.25,135.77 269.18,135.7 v2(269.18,135.32) 269.18,135.09 268.94,134.86 266.77,134.86 265.83,133.91 265.83,133.49 265.85,133.47 265.85,133.46 R11.2
USBP8+: length 75.4
  IN1 w0.089: v1(108.59,75.7) 108.57,75.73 108.57,76.33 108.82,76.58 114.64,76.58 114.88,76.83 126.87,76.83 129.93,73.76 132.46,73.76 132.85,73.37 133.74,73.37 134.48,72.63 135.47,72.63 136.66,71.44 137.37,71.44 138.27,70.54 138.27,69.24 141.59,65.92 141.59,64.16 142.8,62.95 143.11,62.95 143.38,62.67 143.38,62.22 v1(143.6,62.01)
  BOTTOM w0.076: v1(108.59,75.7) 108.82,75.48 108.82,75.37 108.67,75.22 107.86,75.22 107.67,75.42 107.11,75.42 106.94,75.25 106.94,75.08 106.86,75.01 U1.AG2
  BOTTOM w0.102: v1(143.6,62.01) 143.6,62.75 143.83,62.98 144.15,62.98 145.48,61.66 v2(146.34,61.66) 155.76,61.66 156.12,62.01 156.88,62.01 157.05,61.84 158.89,61.84 159.32,62.27 161.22,62.27 161.45,62.03 161.46,62.03 161.58,61.91 163.84,61.91 164.4,62.47 164.4,63.56 166,65.16 167.22,65.16 167.44,65.39 167.44,65.64 R461.1
USBP8+_CONN: length 11.5
  BOTTOM w0.102: R461.2 167.37,66.65 167.37,66.9 167.76,67.29 v2(169.39,67.29) 170.7,67.29 171.08,66.91 171.08,66.38 D711.2 171.46,66.41 171.46,66.99 171.59,67.12 171.81,67.12 172.35,66.59 172.35,65.47 172.02,65.14 171.53,65.14 171.25,64.86 171.25,64.46 171.1,64.31 J16.6
USBP8-: length 75.3
  IN1 w0.089: v1(109.17,75.7) 108.76,76.12 108.76,76.25 108.9,76.39 114.72,76.39 114.96,76.64 126.79,76.64 129.85,73.57 132.38,73.57 132.77,73.18 133.66,73.18 134.4,72.44 135.39,72.44 136.58,71.25 137.29,71.25 138.08,70.46 138.08,69.16 141.4,65.85 141.4,64.08 142.72,62.76 143.03,62.76 143.19,62.59 143.19,62.38 v1(142.83,62.01)
  BOTTOM w0.076: U1.AG1 107.14,75.01 107.11,75.04 107.11,75.18 107.18,75.25 107.6,75.25 107.79,75.06 108.74,75.06 108.98,75.3 108.98,75.51 v1(109.17,75.7)
  BOTTOM w0.102: R462.1 167.24,65.61 167.24,65.47 167.13,65.37 165.91,65.37 164.19,63.65 164.19,62.56 163.75,62.12 161.67,62.12 161.54,62.24 161.54,62.24 161.3,62.48 159.24,62.48 158.8,62.04 157.14,62.04 156.96,62.22 156.03,62.22 155.68,61.87 145.56,61.87 144.24,63.19 143.75,63.19 143.39,62.83 143.39,62.4 143,62.01 v1(142.83,62.01)
USBP8-_CONN: length 11.6
  BOTTOM w0.102: J16.4 171.6,64.31 171.45,64.46 171.45,64.78 171.61,64.93 172.11,64.93 172.56,65.38 172.56,66.67 171.9,67.33 171.68,67.33 171.46,67.55 171.46,67.93 D711.3 171.05,67.93 171.05,67.79 170.76,67.5 167.67,67.5 v2(167.51,67.34) 167.16,66.99 167.16,66.53 R462.2
USBP9+: length 226.8
  IN1 w0.076: 105.39,73.72 105.37,73.72 105.36,73.74 104.08,73.74 103.9,73.91 103.9,74.02 v1(103.67,74.26)
  IN1 w0.089: v1(242.86,86.85) 243.14,87.12 243.14,87.22 243.07,87.28 239.95,87.28 238.49,88.75 236.55,88.75 235.96,89.33 233.08,89.33 232.52,88.77 229.39,88.77 228.64,88.02 224.39,88.02 223.99,87.62 219.44,87.62 219.28,87.46 216.19,87.46 215.98,87.67 209.41,87.67 207.92,89.17 201.3,89.17 200.35,90.12 195.41,90.12 194.75,90.78 188.79,90.78 186.81,88.81 186.81,88.37 184.65,86.21 179.85,86.21 179.32,86.74 157.89,86.74 157.31,87.32 155.94,87.32 155.09,88.18 152.19,88.18 151.15,87.13 139.13,87.13 138.64,86.64 134.47,86.64 132.71,88.4 131.67,88.4 129.99,90.07 126.79,90.07 126.62,89.91 123.91,89.91 123.42,89.42 121.17,89.42 118.84,87.1 118.11,87.1 116.99,85.98 112.71,85.98 112.48,86.21 111.78,86.21 111.12,85.55 111.12,84.19 110.47,83.54 110.47,80.95 107.08,77.56 107.08,76.89 106.99,76.8 106.99,74.8 105.92,73.72 105.39,73.72
  BOTTOM w0.102: R9.1 266.64,132.75 266.74,132.65 266.74,132.51 266.47,132.23 266.25,132.23 265.53,131.51 265.53,130.13 266.47,129.19 266.47,125.08 264.19,122.81 v2(264.19,119.4) 264.19,108.28 259.81,103.9 251.99,103.9 251.21,103.12 247.8,103.12 245.95,101.27 245.95,100.63 245.44,100.12 243.2,100.12 240.85,97.77 240.85,91.75 243.67,88.92 243.67,88.32 243.19,87.84 243.19,87.18 v1(242.86,86.85) ; v1(103.67,74.26) 103.32,74.61 U1.AH8
USBP9+_CONN: length 9
  BOTTOM w0.102: R9.2 266.79,133.54 266.79,133.94 267.38,134.53 269.31,134.53 269.51,134.73 272.82,134.73 v2(273.2,135.11) 273.35,135.25 273.35,135.57 273.25,135.67 J11.19
USBP9-: length 226.8
  IN1 w0.076: v1(104.31,74.26) 104.07,74.02 104.07,73.98 104.15,73.9 105.36,73.9 105.37,73.91 105.39,73.91
  IN1 w0.089: 105.39,73.91 105.84,73.91 106.8,74.88 106.8,76.88 106.89,76.96 106.89,77.63 110.28,81.03 110.28,83.62 110.93,84.26 110.93,85.63 111.7,86.4 112.56,86.4 112.79,86.17 116.91,86.17 118.03,87.29 118.76,87.29 121.09,89.61 123.34,89.61 123.83,90.1 126.54,90.1 126.71,90.26 130.07,90.26 131.75,88.59 132.79,88.59 134.55,86.83 138.56,86.83 139.05,87.32 151.07,87.32 152.11,88.37 155.17,88.37 156.02,87.52 157.39,87.52 157.97,86.93 179.4,86.93 179.93,86.4 184.57,86.4 186.62,88.45 186.62,88.89 188.71,90.97 194.83,90.97 195.49,90.31 200.43,90.31 201.38,89.36 207.99,89.36 209.49,87.86 216.06,87.86 216.27,87.65 219.2,87.65 219.36,87.81 223.91,87.81 224.31,88.21 228.56,88.21 229.31,88.96 232.44,88.96 233,89.52 236.04,89.52 236.63,88.94 238.57,88.94 240.03,87.47 243.15,87.47 243.33,87.29 243.33,87.14 v1(243.63,86.85)
  BOTTOM w0.102: R8.1 267.1,132.75 266.95,132.6 266.95,132.42 266.55,132.02 266.34,132.02 265.74,131.43 265.74,130.21 266.68,129.28 266.68,125 v2(264.65,122.97) 264.4,122.72 264.4,108.2 259.9,103.69 252.07,103.69 251.29,102.91 247.89,102.91 246.16,101.18 246.16,100.55 245.53,99.91 243.28,99.91 241.06,97.69 241.06,91.83 243.88,89.01 243.88,88.23 243.4,87.75 243.4,87.07 v1(243.63,86.85) ; v1(104.31,74.26) 103.97,74.6 U1.AH7
USBP9-_CONN: length 9
  BOTTOM w0.102: J11.20 273.65,135.66 273.55,135.57 273.55,135.17 272.91,134.53 269.6,134.53 269.4,134.32 v2(267.72,134.32) 267.47,134.32 266.99,133.85 266.99,133.51 R8.2
VBL20: length 2.3
  TOP w0.305: v3(139.93,106.42) 140.28,106.77 C267.2 C268.1 140.14,106.21 v3(139.93,106.42)
  vias: v1(138.85,104.74) v1(139.12,104.21) v1(139.46,104.76)
VGA_BLON: length 161.3
  TOP w0.102: U16.C9 230.73,74.87 v1(230.34,74.48) ; v1(100.43,80.69) 100.68,80.43 100.85,80.43 101.05,80.23 101.05,79.94 101.3,79.7 RC3.1
  IN1 w0.076: v1(231.63,66.33) 230.64,65.34 230.64,63.97 230.26,63.59 226.98,63.59 225.94,64.63 216.14,64.63 215.76,65.01 214.97,65.01 214.36,65.62 214.06,65.62 213.45,65.01 211.24,65.01 210.52,64.3 207.1,64.3 206.87,64.07 203.97,64.07 203.64,63.74 200.24,63.74 198.99,64.99 185.68,64.99 185.02,65.65 182.38,65.65 181.31,66.71 178.44,66.71 177.72,67.44 165.43,67.44 165.24,67.63 163.08,67.63 162.82,67.88 158.81,67.88 158.2,68.49 157.69,68.49 157.49,68.29 147.56,68.29 146.41,67.14 144.26,67.14 143.72,67.68 143.72,68.34 143.37,68.69 141.13,68.69 140.17,69.66 140.17,70.7 137.96,72.91 137.96,73.52 137.7,73.77 135.01,73.77 134.22,74.56 133.28,74.56 129.88,77.96 119.16,77.96 117.84,79.29 115.02,79.29 113.98,78.24 109.36,78.24 v2(109,77.89)
  IN3 w0.081: v2(109,77.89) 109,78.17 107.11,80.06 101.43,80.06 100.8,80.69 v1(100.43,80.69)
  BOTTOM w0.102: v1(230.34,74.48) 230.34,74.36 230.74,73.95 230.74,73.39 227.72,70.37 227.72,69.18 227.62,69.07 227.62,67.2 228.28,66.53 231.43,66.53 v1(231.63,66.33)
  BOTTOM w0.254: v1(100.43,80.69) 100.43,80.86 U1.R12
VIDEO_ID: length 3.3
  TOP w0.102: R183.2 239.07,76.83 236.77,76.83 U16.F2
VL5: length 114.6
  TOP w0.203: v4(244.76,80.07) 244.76,80.53 v1(244.71,80.58)
  TOP w0.254: R255.1 244.03,80.24 244.2,80.07 v4(244.76,80.07)
  IN3 w0.203: v1(159.67,78.27) 159.67,78.9 160.46,79.69 161.68,79.69 163.1,81.11 163.1,84.29 165.36,86.55 176.29,86.55 179.36,89.62 179.36,91.83 181.42,93.89 184.54,93.89 187.32,91.11 207.77,91.11 208.97,89.9 216.16,89.9 217.94,91.68 225.1,91.68 225.54,91.25 231.45,91.25 231.91,90.79 239.46,90.79 240.01,91.35 241.41,91.35 242.61,90.16 243.65,90.16 245.75,88.05 v1(245.75,85.79)
  BOTTOM w0.203: PU201.13 159.61,78.21 v1(159.67,78.27) 159.8,78.4 PC212.1
  BOTTOM w0.305: v1(245.75,85.79) 245.75,85.48 244.03,83.76 244.03,83.27 244.94,82.36 245.78,82.36 245.96,82.18 245.96,81.7 245.4,81.14 244.99,81.14 244.71,80.86 v1(244.71,80.58)
VREGIN20: length 273.4
  TOP w0.305: R280.2 255.1,82.32
  TOP w0.381: 260.66,81.19 260.02,81.83 R275.2 R274.2 258.59,83.17 257.84,83.91 256.93,83.91 256.22,83.2 255.3,83.2 v1(255.28,83.17) 255.28,82.49 254.94,82.15 R280.2 ; 260.66,81.19 261.36,81.19 262.66,82.49 263.35,82.49 263.78,82.92 265.46,82.92 266.57,84.04 266.57,85.59 265.94,86.23 265.94,87.39 266.5,87.95 266.5,90.59 265.94,91.15 265.94,95.63 PD13.1 ; 260.66,81.19 260.66,80 260.22,79.56 R276.2
  TOP w0.508: v1(177.68,93.28) 177.68,93.5 185.94,101.75 v1(185.94,101.84) ; 165.18,88.79 163.45,87.06 PD31.1 ; 165.18,88.79 PD10.1 ; 165.18,88.79 v1(165.18,92.09) ; v1(184.16,63.82) 181.84,66.13 178.69,66.13 176.86,67.96 173.64,67.96 172.98,68.62 172.98,69.84 174.12,70.99 177.07,70.99 177.55,71.47 177.55,72.66 180.02,75.13 180.02,83.91 179.05,84.87 v1(179.05,85.89) ; v1(150.73,111.9) 150.12,112.51 PD11.1 ; v1(237.63,107.89) 238.26,108.52 243.95,108.52 v3(245.53,106.95) 246.64,105.83 246.64,104.25 247.57,103.33 247.57,101.5 v1(247.71,101.36)
  IN1 w0.508: v1(246.39,85.78) 246.71,86.09 253.3,86.09 255,84.39 255,83.45 v1(255.28,83.17) ; v1(225.27,102.99) 224.73,102.99 223.56,101.82 214.33,101.82 213.56,101.05 204.88,101.05 202.75,103.19 202.75,104.54 201.53,105.75 200.59,105.75 198.79,103.95 195.89,103.95 195.21,103.26 187.36,103.26 v1(185.94,101.84)
  IN3 w0.508: v1(237.63,107.89) 236.46,106.72 225.21,106.72 224.14,105.65 224.14,103.62 224.77,102.99 v1(225.27,102.99) ; v1(165.18,92.09) 165.74,92.65 165.74,94.84 167.59,96.69 174.14,96.69 177.55,93.28 v1(177.68,93.28) ; v1(150.73,111.9) 150.55,111.71 150.55,110.41 156.16,104.79 160.38,104.79 164.59,109.01 175.26,109.01 177.27,107 183.69,107 185.94,104.76 v1(185.94,101.84)
  BOTTOM w0.508: v1(177.68,93.28) 177.58,93.18 177.58,88.2 179.05,86.73 v1(179.05,85.89) 179.03,85.86 179.03,84.75 178.29,84.01 PD14.1 ; v1(184.16,63.82) 184.08,63.74 PD12.1 ; v1(247.71,101.36) 247.68,101.33 247.3,101.33 246.87,100.9 246.87,100.16 244.89,98.18 244.04,98.18 241.83,95.98 241.83,92.22 242.66,91.4 243.09,91.4 243.57,90.92 243.57,90.59 245.7,88.45 245.7,86.75 246.39,86.07 v1(246.39,85.78)
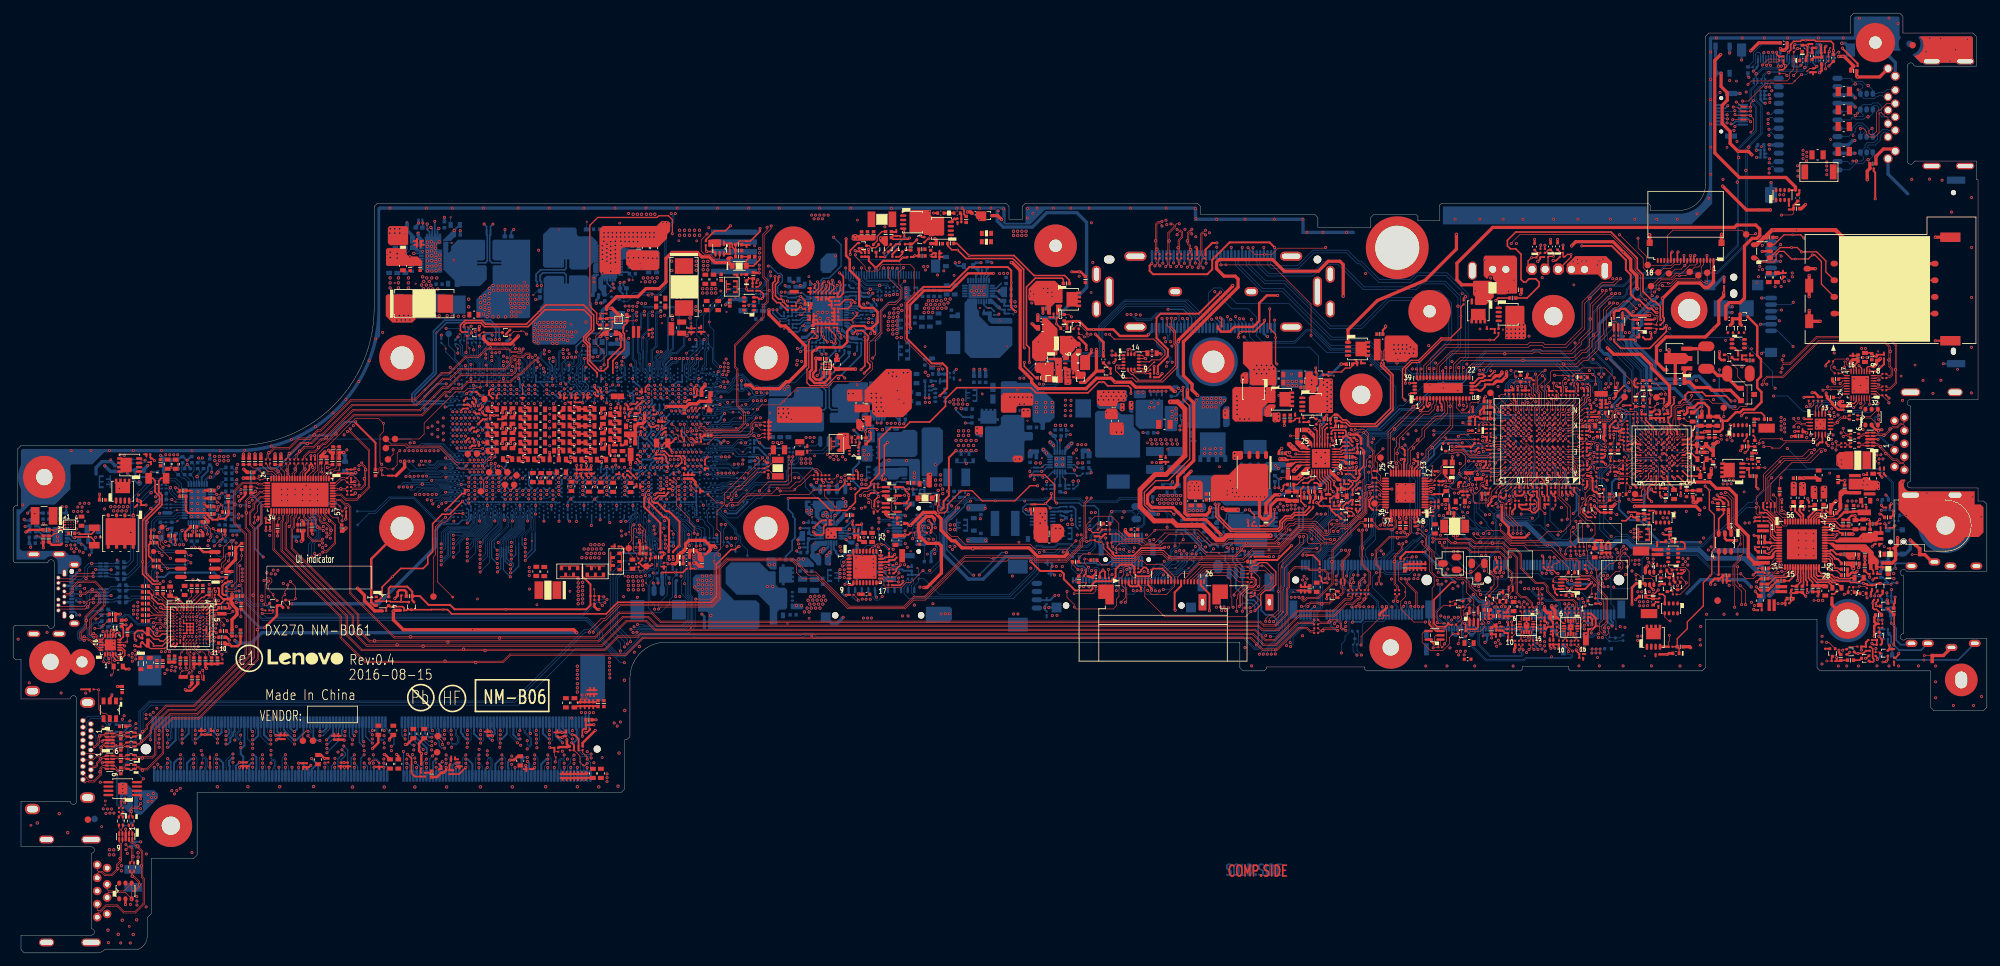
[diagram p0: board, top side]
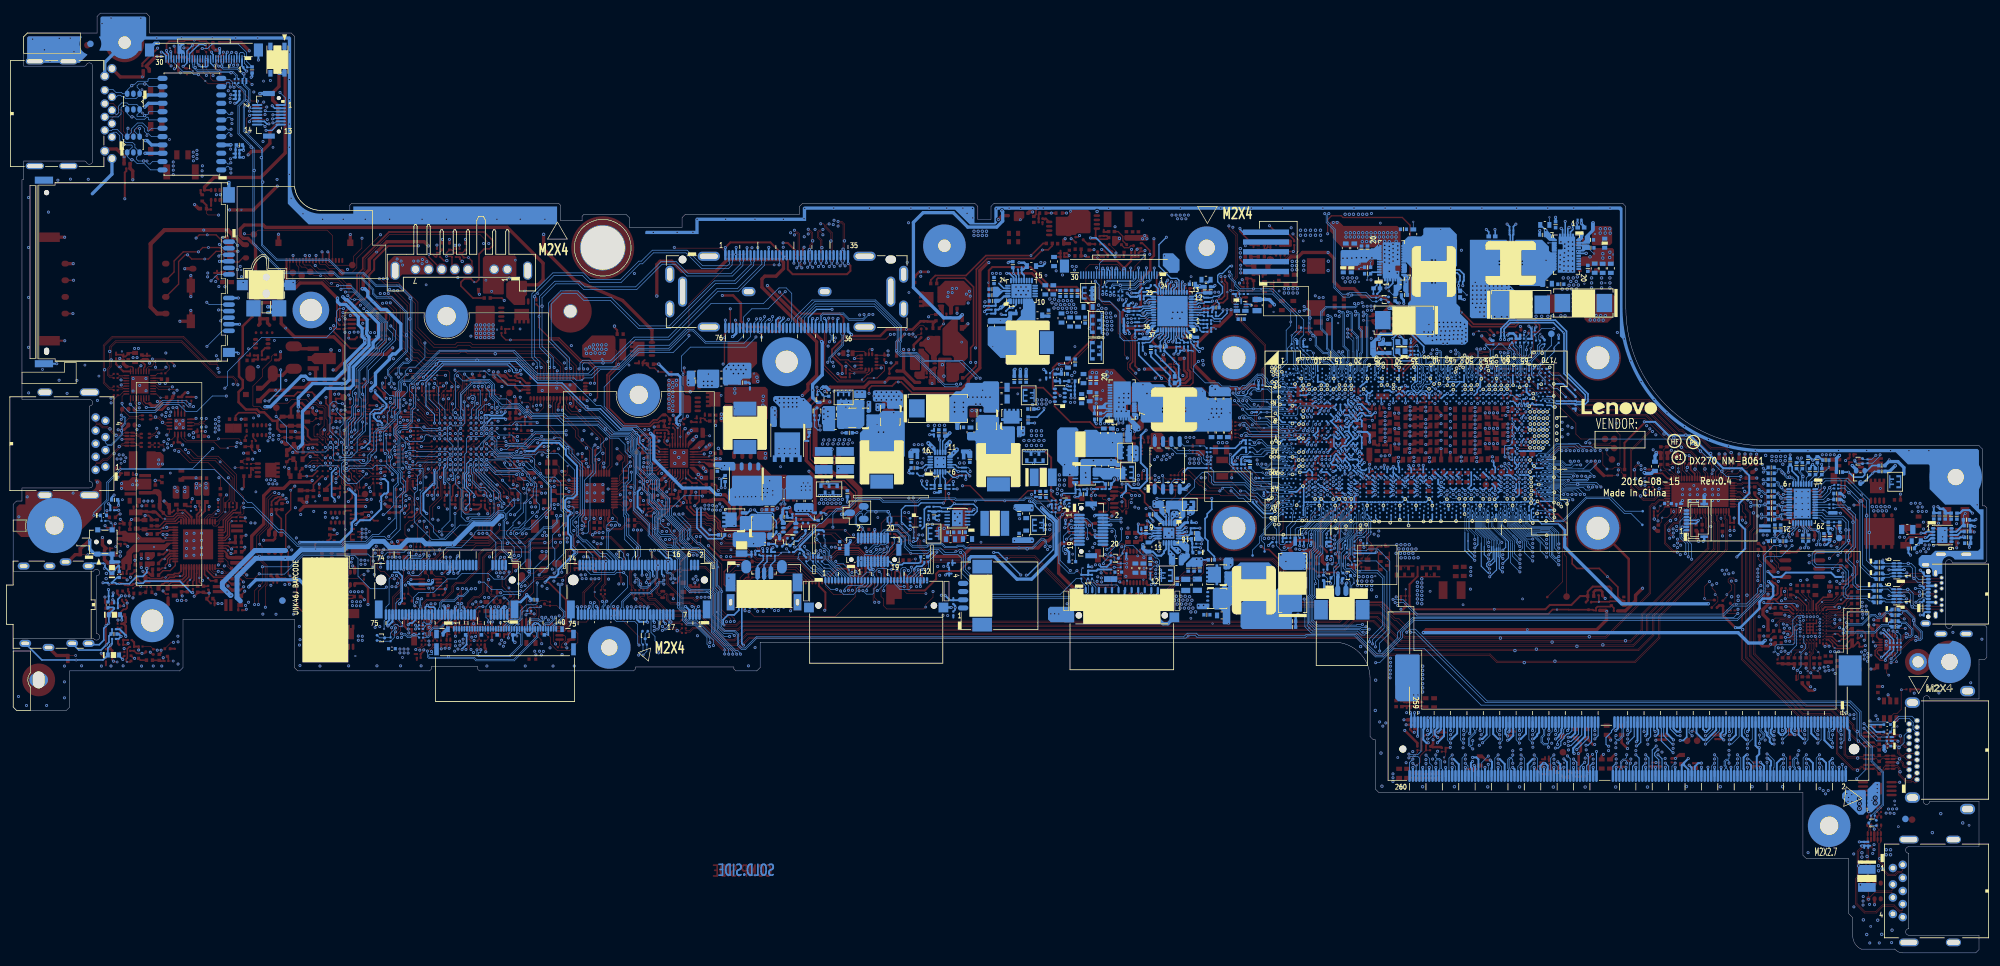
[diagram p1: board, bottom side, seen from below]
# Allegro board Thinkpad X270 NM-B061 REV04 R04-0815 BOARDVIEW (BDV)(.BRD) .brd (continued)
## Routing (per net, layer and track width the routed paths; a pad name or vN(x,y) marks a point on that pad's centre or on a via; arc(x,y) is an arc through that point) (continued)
VSYS: length 141.4
  TOP w0.305: v1(184.08,100.85) 180.78,97.55 174.96,97.55 174.33,96.91 174.33,93.84 176.08,92.09 176.08,91.1 174.53,89.55 v1(174.53,88.4)
  TOP w0.508: v1(257.45,77.05) 257.47,77.06 257.68,77.06 R273.2 258.93,76.74 C205.2 D38.2 ; v1(140.54,108.98) 140.77,108.75 C1.1 140.74,108.25 F1.1
  IN1 w0.508: v1(247.02,97.88) 245.91,97.88 245.37,98.41 242.12,98.41 239.86,100.67 239.86,102.43 240.85,103.42 240.85,105.78 239.79,106.84 220.58,106.84 216.7,102.96 214.07,102.96 213.23,102.13 205.46,102.13 203.89,103.7 203.89,106.75 202.29,108.34 194.09,108.34 191.17,105.42 185.84,105.42 184.08,103.67 v1(184.08,100.85)
  BOTTOM w0.203: PU201.12 159.21,78.07 158.89,78.4 PC211.1
  BOTTOM w0.381: v1(117.71,101.85) 117.91,101.64 PR402.1
  BOTTOM w0.508: PC211.1 158.61,78.88 158.15,79.34 v1(158.12,79.34) ; v1(257.45,77.05) 256.83,77.67 256.83,82.61 253.3,86.14 249.59,86.14 249.08,86.65 249.08,89.39 246.06,92.41 246.06,93.15 245.21,94 245.21,96.07 v1(247.02,97.88)
  vias: v1(126.09,58.49) v1(126.09,57.9) v1(126.09,57.31) v1(126.72,58.46) v1(126.73,57.87) v1(126.73,57.29) v1(136.15,101.38) v1(136.18,100.75) v1(136.18,100.09) v1(139.08,84.02) v1(139.72,83.99) v1(160.44,83.55) v1(160.44,82.77) v1(160.41,81.98) v1(160.46,84.34) v1(161.25,81.95) v1(161.3,84.31) v1(161.27,83.53) v1(161.27,82.74) v1(173.34,85.71) v1(173.95,85.71) v1(174.56,85.71) v1(175.17,85.71) v1(175.78,85.71) v2(57.44,109.84) v2(57.5,110.49) v2(58.18,110.49) v2(58.2,109.84) v2(58.18,97.24) v2(58.51,96.56) v2(58.94,110.49) v2(58.89,97.24) v2(58.96,109.84) v2(59.17,96.58) v2(59.58,97.27) v2(59.8,96.58) v2(60.26,97.27) v2(60.49,96.58) v2(60.92,97.27) v2(61.1,99.86) v2(61.1,99.1) v2(61.1,98.34) v2(96.09,103) v2(96.39,102.4) v2(96.77,103.01) v2(97.09,102.41) v2(97.45,103) v2(97.83,102.4) v2(98.19,103.02) v2(100.42,105.55) v2(100.44,104.13) v2(104.17,105.55) v2(104.17,104.89) v2(104.17,104.18) v2(142.83,84.09) v2(143.42,84.39) v2(143.44,83.76) v2(144.1,84.39) v2(144.1,83.76) v2(144.79,84.39) v2(144.79,83.76) v2(145.5,83.68) v2(199.81,87.36) v2(199.81,86.65) v2(200.36,87.03) v2(200.36,86.32) v2(200.36,85.61) v2(200.36,84.9) v2(200.36,84.19) v2(200.36,83.48) v2(200.36,82.77) v2(200.95,87.36) v2(200.95,86.65) v2(200.95,85.94) v2(200.95,85.23) v2(200.95,84.52) v2(200.95,83.81) v2(200.95,83.1) v4(95.76,102.4)
VSYS_OUT: length 104.5
  TOP w0.203: v2(198.48,80) 198.82,79.67 PU101.22
  TOP w0.305: PR169.1 195.48,82.34
  TOP w0.508: PR24.1 253.44,90.24 PQ42.2 252.7,90.7 252.48,90.92 v2(252.48,92.02) ; v2(220.07,109.64) 220.07,107.41 215.29,102.63 208.02,99.56 203.54,95.08 PQ103.1
  IN1 w0.508: v2(198.48,80) 198.48,81.34 198.84,81.7 198.84,83.4 v2(195.67,86.58)
  IN2 w0.508: v2(220.07,109.64) 222.23,107.48 228.22,107.48 230.02,105.68 230.02,104.11 232.56,101.57 236.91,101.57 242.32,96.16 242.32,94.05 244.58,91.79 250.39,91.79 250.88,91.31 251.77,91.31 v2(252.48,92.02)
  IN4 w0.508: v2(194.4,87.21) 194.07,87.54 189.95,87.54 188.63,86.22 185.76,86.22 185.23,85.69 180.17,85.69 179.77,85.28 178.55,85.28 177.68,86.14 v1(177.66,86.14)
  BOTTOM w0.508: v1(177.66,86.14) 177.45,86.35 176.97,86.35 PF9.1
  vias: v2(194.4,86.58) v2(195.03,87.21) v2(195.03,86.58) v2(195.67,87.21) v3(194.93,88.33)
WIGIG_AUXN: length 182
  TOP w0.102: v1(200.04,57.07) 200.33,57.36 200.33,57.89 199.92,58.3 199.4,58.3 R368.1 198.98,58.35 197.64,58.35 197.26,58.74 195.44,58.74 194.62,57.92 194.62,55.74 194.34,55.46 194.34,51.67 192.54,49.87 190.65,49.87 190.1,50.42 98.68,50.42 97.3,51.8 92.52,51.8 88.76,48.04 v2(74.17,48.04) 58.08,48.04 51.28,54.84 51.28,68.02 50.97,68.34 50.57,68.34 49.89,69.01 49.32,69.01 49.22,68.91 U147.59
  BOTTOM w0.102: v1(200.04,57.07) 200.14,57.07 200.31,57.24 200.31,57.7 200.67,58.06 201.09,58.06 201.2,58.16 201.2,58.34 201.05,58.48 J32.20
WIGIG_AUXP: length 182.1
  TOP w0.102: v1(200.65,57.07) 200.54,57.18 200.54,57.97 200,58.51 199.41,58.51 R369.2 199.08,58.56 197.73,58.56 197.34,58.95 195.35,58.95 194.42,58.01 194.42,55.83 194.13,55.54 194.13,51.76 192.45,50.08 190.74,50.08 190.18,50.63 98.77,50.63 97.39,52.01 92.43,52.01 88.67,48.25 v2(60.61,48.25) 58.17,48.25 51.49,54.93 51.49,68.11 51.06,68.55 50.65,68.55 49.98,69.22 49.27,69.22 49.17,69.31 U147.60
  BOTTOM w0.102: J32.22 201.55,58.5 201.4,58.35 201.4,58.08 201.18,57.85 200.76,57.85 200.52,57.61 200.52,57.2 v1(200.65,57.07)
WIGIG_DP0N: length 180.1
  TOP w0.102: U147.43 42.95,66.59 42.7,66.34 42.7,65 42.4,64.69 42.4,61.67 52.51,51.55 52.51,49.22 54.3,47.43 v2(66.3,47.43) 89.31,47.43 93.02,51.14 96.82,51.14 98.15,49.81 189.79,49.81 190.36,49.23 193.03,49.23 195.85,52.05 201.31,52.05 203.1,53.83 203.94,53.83 204.25,54.14 C247.1
WIGIG_DP0N_C: length 5.9
  TOP w0.102: C247.2 204.07,55.49 204.07,55.86 203.94,55.99 v2(203.94,56.22) 203.94,56.82 204.2,57.09 204.3,57.09 204.4,56.99 v1(204.4,56.53)
  BOTTOM w0.102: v1(204.4,56.53) 204.4,56.87 204.27,57 203.98,57 203.75,57.22 203.75,58.05 204.05,58.35 J32.32
WIGIG_DP0P: length 180
  TOP w0.102: C248.1 203.44,54.59 203.44,54.44 203.49,54.39 203.97,54.39 204.04,54.33 204.04,54.23 203.85,54.04 203.01,54.04 201.23,52.26 195.77,52.26 192.95,49.44 190.45,49.44 189.87,50.01 98.24,50.01 96.91,51.35 92.93,51.35 89.22,47.64 v2(55.1,47.64) 54.39,47.64 52.72,49.31 52.72,51.64 42.61,61.76 42.61,64.6 42.91,64.91 42.91,66.26 43.16,66.5 43.16,66.78 43.35,66.97 U147.44
WIGIG_DP0P_C: length 5.9
  TOP w0.102: C248.2 203.86,55.6 203.86,55.77 203.73,55.9 203.73,56.91 204.11,57.29 204.28,57.29 204.37,57.39 v1(204.37,57.7)
  BOTTOM w0.102: v1(204.37,57.7) 204.37,57.31 204.27,57.2 204.06,57.2 203.96,57.31 203.96,57.96 204.55,58.55 J32.34
WIGIG_DP1N: length 183.6
  TOP w0.102: U147.40 41.75,65.85 41.46,65.55 41.46,61.59 51.7,51.35 51.7,48.97 53.87,46.79 v2(62.51,46.79) 89.82,46.79 93.55,50.52 96.52,50.52 97.86,49.19 189.35,49.19 190.93,47.61 192.39,47.61 196.14,51.37 201.5,51.37 203.34,53.2 204.34,53.2 205,53.86 205.24,53.86 205.49,54.11 C245.1
WIGIG_DP1N_C: length 10.3
  TOP w0.102: C245.2 205.3,55.54 v2(205.3,56.27) 205.3,56.54 205.84,57.09 205.98,57.09 206.12,56.94 v1(206.12,56.58)
  BOTTOM w0.102: J32.26 202.55,58.46 202.7,58.31 202.7,57.21 204.25,55.66 205.28,55.66 205.67,56.05 205.67,56.89 205.79,57.01 206.02,57.01 206.12,56.91 v1(206.12,56.58)
WIGIG_DP1P: length 183.6
  TOP w0.102: U147.41 42.15,66.92 41.96,66.72 41.96,65.76 41.67,65.47 41.67,61.68 51.91,51.44 51.91,49.05 53.96,47 v2(58.56,47) 89.73,47 93.46,50.73 96.61,50.73 97.94,49.4 189.43,49.4 191.01,47.82 192.3,47.82 196.06,51.57 201.42,51.57 203.25,53.41 204.26,53.41 204.92,54.07 205.16,54.07 205.28,54.19 205.28,54.35 205.21,54.42 204.73,54.42 204.66,54.49 204.66,54.59 C246.1
WIGIG_DP1P_C: length 10.3
  TOP w0.102: C246.2 205.09,55.61 205.09,56.63 205.76,57.29 206.03,57.29 206.12,57.39 v1(206.12,57.7)
  BOTTOM w0.102: J32.28 203.05,58.4 202.9,58.25 202.9,57.3 204.34,55.87 205.2,55.87 205.46,56.14 205.46,56.98 205.71,57.22 206.02,57.22 206.12,57.32 v1(206.12,57.7)
WIGIG_DP2N: length 174.9
  TOP w0.102: U147.38 40.95,66.83 41.04,66.74 41.04,66.06 40.84,65.86 40.84,61.32 50.77,51.39 50.77,48.45 53.08,46.14 v2(71.96,46.14) 90.25,46.14 92.27,48.17 95.28,48.17 95.69,48.58 188.99,48.58 190.64,46.93 192.61,46.93 195.95,50.27 198.24,50.27 C251.2
WIGIG_DP2N_C: length 8.5
  TOP w0.102: C251.1 199.12,50.28 200.46,50.28 v2(200.67,50.49) 200.81,50.63 201.93,50.63 202.37,50.2 202.37,49.56 202.61,49.31 203.1,49.31 v1(203.2,49.21)
  BOTTOM w0.102: v1(203.2,49.21) 203.13,49.28 202.59,49.28 202.37,49.5 202.37,50.7 202.3,50.77 J32.25
WIGIG_DP2P: length 174.8
  TOP w0.102: U147.39 41.35,66.83 41.25,66.74 41.25,65.98 41.05,65.77 41.05,61.41 50.98,51.48 50.98,48.53 53.17,46.35 v2(68.68,46.35) 90.16,46.35 92.19,48.37 95.19,48.37 95.6,48.79 189.07,48.79 190.72,47.13 192.52,47.13 195.86,50.48 198.28,50.48 198.38,50.58 C252.2
WIGIG_DP2P_C: length 8.5
  TOP w0.102: v1(203.2,49.82) 202.9,49.52 202.7,49.52 202.57,49.64 202.57,50.29 202.02,50.84 200.72,50.84 200.37,50.49 199.32,50.49 C252.1
  BOTTOM w0.102: v1(203.2,49.82) 203.2,49.79 202.9,49.49 202.68,49.49 202.58,49.59 202.58,50.66 202.8,50.89 J32.27
WIGIG_DP3N: length 177.7
  TOP w0.102: C249.2 198.26,48.95 197.74,48.95 197.22,49.47 196.04,49.47 192.76,46.18 190.45,46.18 188.67,47.96 96.03,47.96 93.47,45.4 75.83,45.4 74.73,44.3 v2(70.54,44.3) 53.61,44.3 49.85,48.06 49.85,51.27 39.6,61.52 39.6,66.08 39.84,66.32 39.84,66.74 39.75,66.83 U147.35
WIGIG_DP3N_C: length 6.5
  TOP w0.102: v1(201.96,49.22) 201.79,49.39 199.91,49.39 v2(199.7,49.18) 199.5,48.98 199.12,48.98 C249.1
  BOTTOM w0.102: v1(201.96,49.22) 201.77,49.22 201.71,49.28 201.39,49.28 200.8,49.87 J32.19
WIGIG_DP3P: length 177.7
  TOP w0.102: U147.36 40.15,66.83 40.05,66.74 40.05,66.23 39.81,65.99 39.81,61.6 50.06,51.35 50.06,48.15 53.69,44.51 v2(65.86,44.51) 74.64,44.51 75.74,45.61 93.38,45.61 95.95,48.17 188.76,48.17 190.53,46.39 192.67,46.39 195.95,49.68 197.31,49.68 197.82,49.16 198.31,49.16 198.38,49.24 C250.2
WIGIG_DP3P_C: length 6.5
  TOP w0.102: C250.1 199.32,49.19 199.41,49.19 199.82,49.6 201.74,49.6 v1(201.96,49.82)
  BOTTOM w0.102: v1(201.96,49.82) 201.96,49.82 201.63,49.49 201.48,49.49 201.01,49.96 201.01,50.61 201.3,50.9 201.3,51.63 J32.21
WIGIG_HPD: length 190.1
  TOP w0.102: U147.42 42.55,66.81 42.35,66.61 42.35,65.32 v1(42.1,65.06)
  IN1 w0.076: v1(90.97,42.56) 91.12,42.56 91.96,43.4 91.96,47.87 94.64,50.55 95.63,50.55 96.61,49.57 188.35,49.57 191.61,46.3 192.58,46.3 193.2,45.68 194.55,45.68 195.8,46.93 201.39,46.93 v1(202.53,45.79)
  IN3 w0.081: v1(90.97,42.56) 90.76,42.56 88.35,44.97 58.05,44.97 42.1,60.92 v1(42.1,65.06)
  BOTTOM w0.102: v1(202.53,45.79) 202.55,45.8 202.55,47.1 203.08,47.64 203.08,48.3 203.69,48.91 203.69,51.53 J32.31
WWAN_CFG0: length 156.5
  TOP w0.102: U191.7 236.61,56.02 236.94,55.69 v1(236.94,55.66) 236.94,54.75 D30.2 236.74,54.6 R601.1
  IN1 w0.076: v1(101.39,75.29) 102.25,74.43 102.25,74.18 102.97,73.46 103.3,73.46 104.15,72.61 105.06,72.61 106.42,71.25 110.58,71.25 112.04,69.79 117.08,69.79 119.91,66.96 120.71,66.96 121.28,66.39 122.48,66.39 123.02,65.85 125.65,65.85 126.36,65.14 128.53,65.14 129.23,64.44 130.2,64.44 130.74,63.89 131.43,63.89 133.13,62.19 134.88,62.19 137.57,59.51 153.45,59.51 155.21,61.26 155.5,61.26 156.35,62.12 157.21,62.12 158.78,63.69 161.27,63.69 162.62,65.04 170.09,65.04 170.75,64.38 175.22,64.38 175.35,64.25 180.37,64.25 181.26,63.36 182.94,63.36 183.63,62.67 187.51,62.67 188.68,61.51 197.52,61.51 198.42,60.6 205.97,60.6 207.5,62.14 209.81,62.14 210.7,61.25 212.2,61.25 212.58,61.63 213.93,61.63 214.16,61.86 215.37,61.86 216.1,61.12 219.54,61.12 v1(219.67,61.25)
  IN3 w0.081: v1(236.94,55.66) 236.2,56.41 230.04,56.41 v1(229.87,56.58)
  BOTTOM w0.102: U1.AF11 101.36,75.32 v1(101.39,75.29) ; v1(219.67,61.25) 219.69,61.23 219.69,60.46 221.57,58.58 221.57,56.73 223.2,55.1 226.09,55.1 226.42,55.43 227.97,55.43 229.12,56.58 v1(229.87,56.58)
WWAN_CFG0_SW: length 40.1
  TOP w0.102: U191.2 237.93,56.02 v1(237.58,55.66) 237.31,55.4 237.31,54.98 D30.1 ; v1(253.78,56.02) 254.21,56.44 Q226.2 254.21,56.61 253.81,57.01 R10089.1
  IN3 w0.081: v1(229.32,52.84) 229.07,53.1 229.07,53.66 229.56,54.15 229.56,55.47 230.29,56.2 235.67,56.2 236.61,55.26 237.17,55.26 v1(237.58,55.66) 237.58,54.52 238.94,53.15 238.94,53.05 239.45,52.54 241.1,52.54 241.71,51.93 245.01,51.93 246.64,53.56 247.09,53.56 247.37,53.28 247.37,52.77 247.73,52.42 251.16,52.42 253.78,55.04 v1(253.78,56.02)
  BOTTOM w0.102: v1(229.32,52.84) 229.93,52.84 230.6,52.17 J22.21
WWAN_CFG1: length 180.5
  TOP w0.102: R322.2 247.45,56.99 v1(247.45,57.73) 247.82,57.73 248.4,57.14 249.81,57.14 250.17,56.79 250.17,56.21 U163.3
  IN1 w0.076: v1(244.43,61.61) 244.25,61.78 242.55,61.78 240.89,63.45 236.9,63.45 236.05,64.3 232.42,64.3 231.38,63.26 222.95,63.26 220.51,60.82 216.19,60.82 215.33,61.68 214.36,61.68 214.16,61.48 212.73,61.48 212.33,61.07 210.58,61.07 209.69,61.96 207.55,61.96 206.04,60.45 198.35,60.45 197.49,61.3 188.66,61.3 187.49,62.47 183.32,62.47 182.69,63.11 181.29,63.11 180.3,64.1 175.24,64.1 175.14,64.2 163.59,64.2 163.46,64.32 162.14,64.32 161.35,63.54 158.86,63.54 157.28,61.96 156.42,61.96 155.48,61.02 155.23,61.02 153.54,59.33 137.49,59.33 134.78,62.04 133,62.04 132.32,62.72 131,62.72 130.46,63.26 130.46,63.64 129.87,64.24 127.04,64.24 125.58,65.7 122.95,65.7 122.4,66.24 121.21,66.24 120.84,66.62 120.01,66.62 116.99,69.63 111.98,69.63 110.53,71.08 106.23,71.08 104.92,72.39 104.06,72.39 103.16,73.29 102.91,73.29 102.09,74.11 102.09,74.36 101.53,74.92 101.18,74.92 v1(100.8,75.3)
  IN3 w0.081: v1(242.5,57.59) 244.2,59.3 244.2,61.51 244.31,61.61 v1(244.43,61.61)
  IN4 w0.076: v1(247.45,57.73) 246.76,57.73 246.31,58.18 244.79,58.18 244.59,58.38 243.11,58.38 242.5,57.77 v1(242.5,57.59)
  BOTTOM w0.102: v1(100.8,75.3) 100.71,75.38 U1.AF12 ; v1(242.5,57.59) 241.92,57.01 241.92,54.06 242.6,53.38 J22.69
WWAN_CFG2: length 175.7
  IN1 w0.076: v1(101.74,76.41) 101.99,76.15 101.99,75.23 102.4,74.82 102.96,74.82 103.29,74.49 103.29,74.13 104.43,72.99 105.39,72.99 106.77,71.61 110.82,71.61 112.34,70.1 118.31,70.1 120.17,68.24 121.99,68.24 122.74,67.48 122.74,66.6 123.19,66.15 125.84,66.15 126.55,65.44 128.66,65.44 129.23,64.87 130.26,64.87 130.87,64.26 131.98,64.26 133.71,62.52 135.04,62.52 137.75,59.81 153.17,59.81 154.99,61.62 155.4,61.62 156.2,62.42 157.07,62.42 158.64,63.99 161.07,63.99 162.47,65.39 170.27,65.39 170.95,64.71 175.41,64.71 175.56,64.55 180.63,64.55 181.52,63.66 183.3,63.66 183.96,63 187.97,63 188.58,62.39 194.37,62.39 194.6,62.62 195.13,62.62 195.87,61.89 197.59,61.89 198.57,60.91 205.71,60.91 207.68,62.88 209.81,62.88 211.08,61.61 211.92,61.61 212.25,61.94 212.99,61.94 213.39,62.34 215.31,62.34 216.18,61.48 218.53,61.48 219.08,62.03 219.71,62.03 222.11,64.43 225.89,64.43 226.88,63.44 231.28,63.44 232.5,64.66 236.2,64.66 237.09,63.77 242.15,63.77 242.78,63.13 242.78,62.37 242.93,62.22 244.43,62.22 244.91,61.74 244.91,61.29 v1(244.69,61.07)
  IN3 w0.081: v1(243.11,57.62) 244.48,58.99 244.48,60.87 v1(244.69,61.07)
  BOTTOM w0.102: v4(244.38,49.44) 244.38,50.66 244.1,50.94 J22.75 244.1,52.77 243.62,53.25 243.62,57.11 v1(243.11,57.62) ; U1.AD11 101.36,76.78 v1(101.74,76.41)
WWAN_CFG3: length 159
  TOP w0.102: U191.6 235.01,56.52 R600.1 234.82,57.04 235.26,57.47 236.57,57.47 D29.2 237.15,58.83 234.52,61.45 231.05,61.45 230.37,62.13 228.39,62.13 227.31,63.21 223.15,63.21 222.72,63.64 v1(222.72,63.97)
  IN1 w0.076: v1(222.72,63.97) 222.13,63.97 219.85,61.68 219.01,61.68 218.65,61.33 216.11,61.33 215.4,62.04 213.62,62.04 213.37,61.78 212.43,61.78 212.05,61.4 210.91,61.4 209.89,62.42 207.52,62.42 205.85,60.76 198.5,60.76 197.55,61.71 188.91,61.71 187.77,62.85 183.68,62.85 183.02,63.51 181.39,63.51 180.5,64.4 175.5,64.4 175.35,64.55 170.88,64.55 170.23,65.2 162.51,65.2 161.15,63.84 158.71,63.84 157.13,62.27 156.27,62.27 155.46,61.45 155.13,61.45 153.33,59.66 137.65,59.66 134.93,62.37 133.61,62.37 131.89,64.1 130.77,64.1 130.22,64.65 129.24,64.65 128.6,65.29 126.49,65.29 125.78,66 123.13,66 122.59,66.54 122.59,67.42 121.96,68.04 120.15,68.04 118.25,69.94 112.28,69.94 110.81,71.41 106.64,71.41 105.28,72.77 104.31,72.77 103.46,73.62 103.04,73.62 102.42,74.25 102.42,74.5 101.79,75.13 101.79,75.7 v1(101.1,76.38)
  BOTTOM w0.076: U1.AD12 100.71,76.77 v1(101.1,76.38)
WWAN_CFG3_SW: length 46.7
  TOP w0.102: R602.2 254.18,54.7 255.55,56.07 255.55,58.23 254.94,58.84 253.82,58.84 253.69,58.71 R10088.1 252.97,58.46 Q227.2 252.93,58.42 252.31,59.04 v1(251.8,59.04) ; U191.3 237.91,56.52 v1(237.59,56.84) 237.59,57.55 D29.1 v3(238.1,59.23)
  IN3 w0.081: v1(226.09,54.16) 226.76,54.16 229.6,57.01 230.53,57.01 230.91,56.63 236.15,56.63 236.78,57.27 237.19,57.27 237.59,56.86 v1(237.59,56.84)
  IN4 w0.076: v1(251.8,59.04) 251.57,59.04 250.96,58.43 249.11,58.43 248.73,58.81 248.73,59.73 248.01,60.44 246.8,60.44 246.57,60.21 244.54,60.21 244.05,59.73 243.51,59.73 241.35,57.57 239.46,57.57 238.74,56.86 237.61,56.86 v1(237.59,56.84)
  BOTTOM w0.102: J22.1 225.6,52.35 225.33,52.62 225.33,53.63 225.87,54.16 v1(226.09,54.16)
XCLK_BIASREF: length 18
  TOP w0.102: v1(93.71,81.27) 93.82,81.38 94.45,81.37 RC57.2
  IN3 w0.081: v1(82.28,86.63) 82.28,86.79 82.98,87.49 84.51,87.49 84.71,87.29 86.75,87.29 88.31,85.72 88.31,85.21 88.8,84.73 90.63,84.73 91.52,83.84 91.52,83.25 92.33,82.44 92.33,82.16 93.22,81.27 v1(93.71,81.27)
  BOTTOM w0.076: U1.E42 83.32,86.4 82.97,86.75 82.41,86.75 v1(82.28,86.63)
XDP_TCK0: length 201.2
  TOP w0.102: v1(186.01,52.74) 185.84,52.92 185.84,54.22 185.68,54.37 185.68,56.86 184.95,57.59 182.19,57.59 181.58,56.98 J8.26
  IN1 w0.076: v1(73.59,91.58) 73.59,91.86 73.44,92.01 72.73,92.01 v1(72.07,91.35)
  IN3 w0.081: v1(186.01,52.74) 183.44,50.17 99.02,50.17 96.79,52.4 93.67,52.4 92.23,50.96 66.05,50.96 54.69,62.33 54.69,67.29 56.78,69.38 56.78,78.8 65.52,87.54 66.56,87.54 67.73,88.71 72.67,88.71 73.59,89.64 v1(73.59,91.58)
  BOTTOM w0.076: v1(73.59,91.58) 73.62,91.55 73.62,91.3 74,90.92 74,89.29 74.08,89.21 U1.A59 ; U1.B61 72.75,88.68 72.75,88.9 72.69,89.02 72.69,89.66 72.18,90.17 72.11,90.17 71.64,90.64 71.64,92.02 71.7,92.09
  BOTTOM w0.127: 71.7,92.09 72.22,92.61 72.22,92.98 RC21.1 72.8,92.76 v3(72.8,92.37) 72.67,92.37 72.07,91.77 v1(72.07,91.35)
XDP_TCK1: length 8.9
  TOP w0.102: J8.24 180.58,56.86 181.72,58 185.51,58 186.9,56.6 RC149.2
XDP_TDI: length 212.3
  TOP w0.102: v1(187.44,52.13) 187.41,52.16 187.41,54.52 188.4,55.51 189.47,55.51 v3(189.87,55.92) 190.1,56.15 190.1,57.24 189.16,58.18 188.57,58.18 RC138.2 187.22,57.85 186.21,58.86 181.59,58.86 179.58,56.85 J8.22
  IN1 w0.076: v1(74.79,91.07) 74.41,91.07 73.29,89.95 72.81,89.95 72.54,90.22 72.54,90.65 72.88,90.99 v1(72.98,90.99)
  IN3 w0.081: v1(187.44,52.13) 184.99,49.68 98.55,49.68 96.56,51.68 94.02,51.68 92.42,50.08 65.86,50.08 53.93,62.01 53.93,67.67 55.43,69.18 55.43,78.7 67.07,90.33 72.32,90.33 v1(72.98,90.99)
  BOTTOM w0.076: U1.D59 74.3,87.5 74.38,87.77 74.38,87.88 74.46,88.16 74.5,88.32 74.52,88.36 74.52,88.61 74.48,88.7 74.48,88.89 74.52,88.99 74.52,89.35 74.36,89.51 74.36,90.64 v1(74.79,91.07) ; U1.D60 73.8,88.03 73.8,88.26 73.68,88.39 73.62,88.46 73.62,90.36 v1(72.98,90.99)
XDP_TDO: length 212.6
  TOP w0.102: v1(188.6,52.68) 188.6,52.68 188.8,52.68 189.8,53.68 189.8,54.62 190.98,55.8 191.65,55.8 192.23,56.38 192.23,57.55 190.71,59.07 v3(190.41,59.07) 190.05,59.07 189.57,58.58 188.57,58.58 RC112.1 187.41,58.91 187.03,59.3 180.85,59.3 178.58,57.03 J8.20
  IN1 w0.076: v1(72.07,90.77) 72.07,90.41 72.7,89.78 73.42,89.78 74.28,90.64 74.94,90.64 75.35,90.23 v1(75.35,90.18)
  IN3 w0.081: v1(188.6,52.68) 188.54,52.68 185.38,49.52 98.36,49.52 96.46,51.42 94.13,51.42 92.53,49.82 65.76,49.82 53.67,61.9 53.67,67.85 55.18,69.35 55.18,78.81 67.14,90.77 v1(72.07,90.77)
  BOTTOM w0.076: v1(72.07,90.77) 72.07,90.54 72.96,89.65 U1.A61
  BOTTOM w0.127: v1(75.35,90.18) 75.44,90.09 U1.A56
XDP_TMS: length 204.9
  TOP w0.102: v1(186.57,52.13) 186.55,52.16 186.55,53.94 186.72,54.11 186.72,54.67 188.12,56.07 188.99,56.07 189.24,56.32 189.24,56.81 189.09,56.96 188.57,56.96 RC139.2 186.98,57.29 185.79,58.48 181.69,58.48 180.08,56.87 J8.23
  IN1 w0.076: v1(72.98,90.39) 73.44,90.39 74.18,91.12 v1(74.18,91.66)
  IN3 w0.081: v1(186.57,52.13) 184.29,49.85 98.75,49.85 96.67,51.93 93.92,51.93 92.32,50.33 65.97,50.33 54.18,62.12 54.18,67.55 55.69,69.05 55.69,78.5 65.29,88.1 66.25,88.1 67.34,89.19 72.45,89.19 72.98,89.72 v1(72.98,90.39)
  BOTTOM w0.076: v1(72.98,90.39) 73.46,89.91 73.46,88.22 U1.C60 ; U1.C59 74.27,88.13 74.35,88.39 74.35,88.56 74.29,88.75 74.29,88.9 74.35,89.02 74.35,89.28 74.18,89.45 v1(74.18,91.66)
XTAL24_IN: length 10.6
  BOTTOM w0.102: U1.E37 85.91,86.89 85.91,87.08 85.62,87.38 85.62,87.62 85.64,87.64 85.64,88.01 85.62,88.03 85.62,88.27 85.89,88.54 85.89,89.37 86.47,89.95 86.47,90.89 86.37,90.99 86.37,91.52 RC55.2 86.72,92.55 86.85,92.68 v3(86.94,92.68) 87.16,92.68 87.35,92.48 CC11.2 89.08,92.48 Y1.3
XTAL24_OUT: length 7.9
  BOTTOM w0.102: RC56.1 RC55.1 86.72,89.85 86.12,89.24 86.12,88.36 86.2,88.27 86.2,88.03 86.18,88.01 86.18,87.64 86.2,87.62 86.2,87.32 86.18,87.29 86.18,87.02 86.36,86.83 86.84,86.83 86.97,86.71 86.97,86.55 86.64,86.22 86.64,86.02 86.79,85.87 86.97,85.87 87.31,86.21 U1.E35
XTAL24_OUT_R: length 1.5
  BOTTOM w0.102: Y1.1 88.66,91.87 CC10.2 RC56.2
N8823807:
  vias: v4(254.87,68.92)
N8824787: length 2.5
  TOP w0.254: U21.A4 252.23,72.64 252.23,71.94 253.25,70.92 C202.1
N8840754: length 3.4
  TOP w0.305: U21.G1 254.63,77.61 255.79,77.61 255.87,77.53 R273.1 C197.2
N8903373: length 3
  TOP w0.102: R278.1 R279.2 R276.1 259.96,78.64 260.23,78.37 v3(260.49,78.37)
N8905800: length 4.2
  TOP w0.102: U21.G2 254.19,77.96 256.05,77.96 R278.2 C199.2
N8910919: length 6.7
  TOP w0.305: R275.1 R274.1 C200.2 256.66,80.43 256.03,79.81 256.03,78.87 255.49,78.33 U21.H1
N8950489: length 12.4
  TOP w0.102: RC125.2 123.73,69.71 v3(125.4,68.04)
  TOP w0.254: RC125.2 125.89,70.66 126.81,71.58 v1(126.81,72.17) ; RC126.2 122.69,73.16 v1(122.41,73.44)
  TOP w0.305: 127.9,72.35 CC73.2 ; 127.9,72.91 CC72.1
  BOTTOM w0.254: RC127.2 121.87,73.99 v1(122.41,73.44)
  vias: v1(126.26,72.53) v1(126.83,72.83)
N8978758: length 2.8
  TOP w0.254: U21.E1 254.58,75.96 254.9,75.96 255.25,76.31 255.85,76.31 C204.2
N8979199: length 3.7
  TOP w0.102: D38.1 259.22,74.48 v3(259.57,74.13)
  TOP w0.254: D39.2 257.82,74.94 C204.1 258.82,75.34 D38.1
N8985093: length 4.3
  TOP w0.254: U21.B1 255.32,72.75 v3(256.17,72.75) C206.2 257.25,73.51 D39.1
N9125912: length 4.3
  TOP w0.102: J8.10 173.58,56.94 173.31,57.21 170.88,57.21 170.32,57.77 RC118.2
N9822465: length 0.3
  BOTTOM w0.305: 47.34,68.19 C281.1
  vias: v3(47.76,67.35)
N10270973: length 2
  TOP w0.254: C190.1 R255.2 243.43,80.39 244.23,81.19 Q16.2
N11760620: length 6.7
  TOP w0.254: v1(98.94,57.95) 99.05,58.06 v4(100.86,58.06) 102.12,58.06 RC122.1
  BOTTOM w0.508: v1(98.94,57.95) 98.94,57.35 98.98,57.31 J12.1
N16856048: length 8.7
  BOTTOM w0.254: R1867.1 285.87,48.84 286.03,48.67 C564.2 286.34,48.35 286.34,47.41 v3(286.76,46.99) 287.53,46.22 290.93,46.22 J19.5
N17607913: length 7.3
  TOP w0.102: R281.2 255.26,81.08 R280.1 C203.2 254.01,80.78 254.14,80.66 v4(254.39,80.66) 254.75,80.66 255.08,80.33 255.08,78.88 254.94,78.74 254.28,78.74 253.86,78.33 U21.H2
N18158289: length 3.3
  TOP w0.254: R2481.2 283.25,46.69 283.54,46.4 283.54,45 283.69,44.85 283.69,44.52 v4(283.59,44.42) 283.11,44.42 Q197.2
N18159741: length 9.8
  TOP w0.254: v3(285.09,44.39) 285.52,44.39 v1(285.65,44.52) 285.84,44.71 D253.2 ; Q175.1 280.94,45.71 v1(281.31,45.71) 282.12,45.71 282.5,46.09 R1869.1 R2481.1
  IN4 w0.254: v1(281.31,45.71) 281.31,44.72 281.74,44.29 285.42,44.29 v1(285.65,44.52)
N18161722: length 15.9
  TOP w0.102: RA50.2 285.01,50.74 v1(284.96,50.79) ; v1(276.51,47.39) 276.85,47.39 QA7.2
  IN3 w0.081: v1(276.51,47.39) 276.58,47.39 279.05,44.92 281.81,44.92 285.04,48.15 285.04,50.72 v1(284.96,50.79)
N18163387: length 1
  TOP w0.254: R10096.1 283.64,58.32 R1219.1
N18163400: length 0.9
  TOP w0.254: R460.1 284.74,64.25 R10097.1
N19352549: length 2.4
  TOP w0.203: PU101.16 202.28,76.87 202.75,77.34 PC133.2 203.54,77.34 PR134.2
N19352559: length 22.9
  TOP w0.114: PR151.1 208.38,92.06 208.7,91.74 208.7,90.18 208.57,90.06
  TOP w0.203: PR139.2 200.82,80.8 PC154.1 200.82,81.55 201.38,82.1 PC141.1 201.99,82.1
  TOP w0.254: 208.57,90.06 208.57,89.52 210.04,88.05 210.04,83.1 207.68,80.73 203.92,80.73 203.31,81.34 202.75,81.34 201.99,82.1
  TOP w0.305: 205.53,90.31 PC159.1 206.13,89.98
  vias: v3(207.04,89.7)
N19352573: length 3
  TOP w0.178: v4(198.38,72.41) 198.42,72.45 PU101.2
  TOP w0.254: v4(198.38,72.41) 198.2,72.23 197.96,72.23 PR138.1 PR165.1
N19352583: length 3.4
  TOP w0.178: 199.29,71.34 199.29,71.92 198.82,72.4 PU101.3
  TOP w0.254: PC144.1 199.19,71.34 198.82,71.71 PR133.1
N19352658: length 32
  TOP w0.254: v1(183.88,68.49) 183.8,68.41 183.8,66.69 185.81,64.69 192.83,64.69 193.15,65.01 193.15,65.84 193.98,66.67 194.81,66.67 195.34,67.2 196.9,67.2 197.66,67.96 PR197.2
  TOP w0.508: 190.04,69.05 190.04,66.7 190.53,66.22 PD102.1 191.3,66.22 191.72,66.64 191.72,68.22 192.69,69.18 194.2,69.18 PR103.1 PR102.1
  BOTTOM w0.102: 183.55,70.73 183.75,70.93 PR158.2
  BOTTOM w0.114: v1(183.88,68.49) 183.55,68.82 183.55,70.73
  vias: v1(185.12,70.52) v1(185.12,69.89) v1(185.93,70.86) v1(185.95,70.25) v1(186.29,69.61) v1(186.54,70.88) v1(186.54,70.25) v1(186.89,69.61) v1(187.73,69.64) v1(188.34,69.61) v1(188.95,69.61) v1(189.56,69.61) v1(190.2,69.59) v1(190.83,69.56) v3(185.6,72.05)
N19352692: length 2.4
  TOP w0.203: PU101.30 v4(196.3,74.87) 195.52,74.87 195.2,74.55
N19352696:
  vias: v4(196.33,77.1)
N19352868: length 1.7
  TOP w0.203: PU101.18 200.42,78.61 PR154.1 PR145.2
N19352870: length 1.2
  TOP w0.254: PR101.2 PC139.2 202.97,72.1 PR157.2
N19352874: length 7.9
  TOP w0.178: PU101.6 200.02,72.84 200.9,71.96 v4(200.9,70.83)
  TOP w0.203: PQ107.1 202.15,68.19 PR135.1 PR147.1 ; v1(201.29,70.36) 200.9,70.75 v4(200.9,70.83)
  TOP w0.254: PQ107.1 202.23,68.4 202.57,68.74 v1(202.57,69.07)
  IN4 w0.254: v1(202.57,69.07) v1(201.29,70.36)
N19352884: length 0.9
  TOP w0.203: PR134.1 203.63,77.95 204.16,77.42 PC148.2
N19352890: length 1.6
  TOP w0.203: PC131.2 203.98,73.07 v4(203.86,73.07) 203.2,73.07 PR141.2
N19352894: length 1.8
  TOP w0.203: PU101.13 202.32,75.67
  TOP w0.254: PR146.2 203.25,75.67 202.32,75.67
N19352896: length 2.1
  TOP w0.203: PU101.12 202.22,75.27
  TOP w0.254: 202.22,75.27 202.25,75.27 202.35,75.17 v4(202.4,75.17) 202.85,75.17 PR148.2
N19352902: length 2.5
  TOP w0.203: PU101.17 201.24,77.47 201.71,77.94 201.71,78.32 201.6,78.43 PC137.1 PR144.1
N19352908: length 11.7
  TOP w0.178: v1(200.02,70.61) 200.21,70.8 200.21,71.51 199.22,72.51 PU101.4
  TOP w0.203: PQ106.2 204.24,69.91 PR163.1 204.24,70.76 204.86,71.39 204.86,71.47 v3(204.93,71.54) 204.97,71.54 205.33,71.89 v1(205.37,71.89)
  IN1 w0.203: v1(200.02,70.61) 200.34,70.93 204.4,70.93 v1(205.37,71.89)
N19352926: length 0.6
  TOP w0.203: PC157.1 202.76,79.34 PR144.2
N19352946: length 2.1
  TOP w0.203: PR142.2 202.98,74 202.12,74.87 PU101.11
N19353084:
  vias: v4(201.63,72.48)
N19353108: length 1.7
  TOP w0.203: PU101.9 201.83,74.07 202.61,73.29 PR141.1
N19353922: length 3.6
  TOP w0.203: PU101.20 199.62,80.06 199.64,80.09 v4(199.64,80.11) 200.24,80.71 PR139.1
N19353928: length 2.8
  TOP w0.203: PR155.1 200.02,79.84 PU101.19
N19358397: length 6
  IN1 w0.889: 191.77,73.85 187.43,73.85 186.29,75
  vias: v1(192.48,74.36) v1(192.91,73.96) v2(186.24,76.21) v2(186.27,75.53)
N19358401:
  vias: v1(195.34,73.44) v2(195.7,73.98)
N19359177: length 0.8
  BOTTOM w0.305: PR153.1 179.56,78.87 PC142.2
N19359682: length 1.1
  TOP w0.102: v3(193.27,72.38) 193.4,72.51 PC147.1
N19359877: length 1
  TOP w0.102: PR137.2 v3(194.75,78.9)
N19359919: length 0.8
  BOTTOM w0.305: PR156.1 188.77,87.03 PC143.2
N19361354:
  vias: v4(190.97,83.02)
N19364702: length 6
  TOP w0.203: PR170.2 204.23,89.62 203.84,89.24 203.13,89.24 v4(202.63,88.73) 202.54,88.65 PR179.1
  TOP w0.305: 204.95,89.65 PC159.2 ; PC159.2 204.38,89.98 PR170.2 ; PC159.2 204.95,90.17 204.66,90.46
N19366130: length 1.7
  TOP w0.102: v4(201.41,88.09) 201.38,88.06 PR179.2
  TOP w0.203: PR179.2 200.42,88.2 PQ104.1
N19368369: length 5.1
  TOP w0.203: PU101.14 202.62,76.07 202.82,76.26 204.94,76.26 PC166.1 205.01,77.01 PR190.1 PR152.1
N19368440: length 3.8
  TOP w0.178: 200.53,70.04 200.53,71.75 v4(199.9,72.38) 199.62,72.67 PU101.5
N19370291: length 3.3
  TOP w0.203: PR167.1 204.05,67.86 PQ107.2 203.38,67.66 203.69,67.35 204.07,67.35 204.4,67.02 v3(204.4,66.82) 204.24,66.66 PQ105.1
N19397717: length 2.7
  BOTTOM w0.203: PF9.2 177.29,84.94 PD14.2 177.71,85.36 177.71,85.46 178.06,85.81 v3(178.14,85.81) 178.31,85.64 PD14.3
N19399630: length 2.7
  TOP w0.254: PR133.2 PC145.2 198.43,70.12 198.6,69.94 PC164.1 198.6,69.36 198.23,68.99 PR196.1
N19402841: length 1.8
  TOP w0.203: PR166.2 202.68,76.72 v4(202.47,76.52) 202.42,76.47 PU101.15
N19577504: length 1.6
  TOP w0.102: RL7.2 208.29,69.19 UL1.33
N19577505: length 1.9
  TOP w0.102: RL8.2 207.9,67.94 208.34,68.39 UL1.35
N19577509: length 1.6
  TOP w0.102: UL1.9 215.8,71.19 215.95,71.33 216.67,71.33 RL9.2
N19577510: length 5.1
  TOP w0.102: YL1.3 217.71,74.2 217.71,73.23 216.74,72.26 CL10.2 216.34,71.64 215.85,71.64 215.8,71.59 UL1.10
N19577511: length 4.1
  TOP w0.102: RL9.1 217.37,71.37 CL8.2 218.14,71.59 219.33,71.59 v4(219.45,71.71) 219.62,71.88 219.62,73.25 YL1.1
N19577517: length 1.7
  TOP w0.102: UL1.30 208.84,70.39 208.05,71.18 RL10.2
N19577520: length 3.2
  TOP w0.102: v4(216.39,74.31) 216.39,73.28 216.75,72.92 RL11.2 216.17,72.91 215.66,72.39 UL1.12
N19577582: length 2
  TOP w0.102: RL6.1 216.74,67.8 216.62,67.67 215.85,67.67 215.53,67.99 UL1.1
N19578386: length 0.7
  TOP w0.508: v1(128.89,54.77) 128.94,54.72 F11.1
  vias: v4(128.61,56.96)
N19578390:
  vias: v4(131.1,56.81)
N19578404: length 3.5
  TOP w0.305: v1(165.08,58.34) 165.08,57.93 164.65,57.51 F9.1 164.25,57.34 164.12,57.47 C217.2
  BOTTOM w0.254: v1(165.08,58.34) 165.1,58.31 J38.25
N20831933: length 5.1
  TOP w0.203: PJ3.3 230.99,104.92 230.99,105.57 v3(231.52,106.11) PC24.2 232.25,106.2 232.88,106.82 PR34.1 232.41,106.83 PD7.1
N20831943: length 5.2
  TOP w0.203: PR35.1 233.66,106.83 234.12,107.28 PD8.1 234.88,106.83 v3(234.88,106.29) 234.14,106.29 PC22.2 234.03,104.74 PJ3.4
N20861957: length 2.6
  TOP w0.254: PR197.1 197.77,68.77 PC158.1 197.77,69.87 197.51,70.12 PC145.1 197.51,70.43 197.49,70.45 197.49,71.07 PR138.2
N21745234: length 16.3
  TOP w0.381: 160.37,96.34 160.7,96.01 D707.1 ; 160.37,96.34 161.52,96.34 161.56,96.38 D25.1 162.59,96.38 163.84,95.14 v3(164.75,95.14) 167.75,95.14 168.74,94.14 172.91,94.14 v1(173.11,94.35) ; 160.37,96.34 D22.1
  BOTTOM w0.381: v1(173.11,94.35) 173.65,94.89 J17.36
N21915637: length 3.3
  TOP w0.254: v1(184.08,96.91) 184.28,96.72 R116.2
  BOTTOM w0.254: v1(184.08,96.91) 184.29,96.91 184.65,96.55 J17.56
N22083088: length 28.8
  TOP w0.102: v1(204.63,79.87) 206.03,79.87 206.69,79.21 206.69,77.46 207.5,76.64 207.5,73.62 R93.1 ; U14.16 221.55,83.96 221.7,83.81 v4(221.7,83.4) 221.7,83.25 221.32,82.87 v1(221.05,82.87)
  IN1 w0.076: v1(221.05,82.87) 220.95,82.77 219.01,82.77 218.4,83.37 217.13,83.37 215.69,81.94 210.51,81.94 208.44,79.87 v1(204.63,79.87)
N22083090: length 30.2
  TOP w0.102: v1(204.02,79.84) 204.4,79.46 205.88,79.46 v3(205.93,79.41) 206.49,78.85 206.49,77.37 207.3,76.56 207.3,74.1 207.07,73.88 207.07,73.11 207.27,72.91 R92.1 ; v1(221.14,83.55) 221.05,83.65 U14.15
  IN1 w0.076: v1(221.14,83.55) 220.87,83.29 220.65,83.06 219.29,83.06 218.67,83.68 217,83.68 215.52,82.19 210.31,82.19 208.26,80.15 205.17,80.15 205.01,80.3 204.3,80.3 204.02,80.02 v1(204.02,79.84)
N22083114: length 2.4
  TOP w0.305: U14.20 223.02,86.45 v4(223.67,87.1) 223.84,87.27 224.3,87.27 R95.1
N22083116: length 2.7
  TOP w0.305: R94.1 224.43,86.41 223.82,85.8 v4(223.7,85.8) 223.45,85.8 223.3,85.95 U14.19
N22933987: length 2.7
  TOP w0.203: R104.1 233.35,60.4 v1(233.16,60.59)
  BOTTOM w0.203: v1(233.16,60.59) 233.16,60.49 233.35,60.3 J22.32
N23175964: length 1.3
  TOP w0.203: U15.18 278.48,87.7 C136.1
N23177820: length 3.5
  TOP w0.305: U15.9 284.15,88.74 v4(284.84,89.43) 285.25,89.84 R113.2
N23204723: length 9.8
  TOP w0.102: v1(280.65,83.23) 281.29,83.87 281.29,84.04 281.45,84.19 U15.28 ; R109.1 273.78,83.91 v1(273.98,83.71)
  BOTTOM w0.102: v1(273.98,83.71) 274.59,84.31 278.19,84.31 279.3,83.2 280.62,83.2 v1(280.65,83.23)
N23216653: length 3.9
  TOP w0.254: C9146.1 271.25,55.96 C9140.1 271.93,55.98 272.55,56.61 v4(272.55,57.24) UA1.21
N23216659: length 5.6
  TOP w0.102: R677.1 269.27,69.84 269.27,67.3 269.57,67 v4(270.05,67) 270.1,67 270.44,66.66 271,66.66 271.35,66.31 UA1.53
N23216890: length 3.1
  TOP w0.203: UA1.7 268.01,62.54
  TOP w0.381: C535.1 C536.1 267.93,62.62 268.01,62.54
  vias: v4(267.93,63.11)
N23216953: length 1.3
  TOP w0.254: R10198.2 268.11,60.3
N23216975: length 6.2
  TOP w0.254: C538.1 C537.1 267.67,56.27 268.72,57.31 270.34,57.31 271.35,58.33 UA1.18
N23217017: length 3.3
  TOP w0.254: C539.1 270.82,56.78 v4(271.23,57.19) 271.75,57.71 UA1.19
N23217050: length 6
  TOP w0.203: UA1.44 274.95,66.25 275.19,66.48 275.63,66.48 276.23,65.87 277.91,65.87 278.62,65.16 C545.1 R484.1
N23217060: length 4
  TOP w0.203: UA1.31 276.94,60.54 277.4,60.08 277.4,59.52 277.73,59.19 v4(277.73,58.74) 278.24,58.74 278.44,58.53 C544.1
N23217075: length 3.8
  TOP w0.203: UA1.29 276.23,59.1 277,58.33 278.09,58.33 C543.1
N23217089: length 5.1
  TOP w0.254: C542.1 274.38,56.55 v4(274,56.93) 273.75,57.18 UA1.24
  TOP w0.508: R10076.2 276.22,56.02 C541.1 C542.1
N23217095: length 3
  TOP w0.254: C540.1 272.98,56.13 272.98,57.93 272.95,57.95 UA1.22
N23217182:
  vias: v3(276.99,73.22)
N23217319: length 7.8
  TOP w0.203: CA913.1 277.52,66.59 276.56,66.59 276.06,67.09 275.19,67.09 v4(275.12,67.17) 274.99,67.17 274.15,66.33 UA1.46
  TOP w0.381: C553.1 278.6,67.67 CA913.1
  TOP w0.508: C553.1 278.6,69.51
N23217371: length 8.5
  TOP w0.203: UA1.45 274.55,66.3 275.04,66.79 275.85,66.79 276.44,66.2 277.73,66.2 v4(277.78,66.26) 278.16,66.26 278.52,66.61 278.55,66.61
  TOP w0.381: 278.55,66.61 279.22,67.28 C552.1 280.55,67.28 C551.1 281.42,67.36 R10079.1
N23217529: length 9.1
  TOP w0.254: UA1.27 274.95,57.73 275.19,57.49 v4(275.52,57.49) 276.23,57.49 276.4,57.33 277.07,57.33 277.52,56.88 278.06,56.88 278.24,56.7 279.99,56.7 280.17,56.53 281.46,56.53 C9136.2
N23217531: length 6.6
  TOP w0.254: C9136.1 280.22,57.24 280.1,57.11 278.37,57.11 278.19,57.29 v4(277.71,57.29) 277.29,57.71 276.53,57.71 276.34,57.9 275.7,57.9 275.35,58.25 UA1.28
N23217548: length 5.6
  TOP w0.254: UA1.25 274.15,57.39 274.98,56.57 276.81,56.57 277.39,55.98 C557.2
N23217550: length 6.3
  TOP w0.254: UA1.26 274.55,57.56 275.17,56.95 276.93,56.95 277.35,56.53 277.78,56.53 278.01,56.3 278.2,56.3 C557.1
N23217742: length 7.4
  TOP w0.203: C9137.1 282,64.64 C9138.1 278.48,64.64 278.29,64.83 v4(278.04,64.83) 278.04,65.09 277.58,65.54 275.98,65.54 275.71,65.82 UA1.43
N23217756: length 3
  TOP w0.254: C9139.1 278.8,64.1 278.55,64.1 278.27,64.38 277.33,64.38 277.16,64.54 UA1.41
N23217805: length 2.8
  TOP w0.254: C2503.2 273.54,56.68 273.35,56.87 UA1.23
N23217875: length 5.5
  TOP w0.102: R1235.1 R10071.1 268,67.37 269.54,65.84 269.54,65.51 269.91,65.14 270.37,65.14 270.55,65.33 UA1.55
N23217894: length 3
  TOP w0.102: R1236.1 v4(268.59,67.27) 268.59,67.11 269.88,65.82 UA1.56
N23217896: length 4.6
  TOP w0.203: UA1.3 268.77,64.14 268.56,64.35 268.56,65.95 267.35,67.17 R1237.1
N23217898: length 4.5
  TOP w0.203: R1238.1 266.85,67.82 267.12,67.55 267.42,67.55 268.92,66.05 268.92,64.99 268.97,64.94 UA1.1
N23330164: length 0.7
  TOP w0.102: PR171.2 197.04,81.57 197.06,81.6
  TOP w0.305: PR171.2 196.71,81.9
N23330167: length 2.2
  TOP w0.203: PC170.1 195.22,81.16 PR169.2 195.64,81.57 PR171.1 196.13,81 PR172.2
N23330170: length 0.9
  TOP w0.254: PQ109.1 197.48,80.99 PR172.1
N23333711: length 16.5
  BOTTOM w0.203: PJ2.3 186.45,59.24 185.99,59.7 185.99,60.58 PR28.1 PC18.2
  BOTTOM w0.254: v3(189.56,46.96) 189.84,47.24 189.84,53.15 189.16,53.84 188.27,53.84 186.45,55.65 PJ2.3
N23759272: length 4.7
  TOP w0.203: UA1.6 268.65,62.94 267.95,63.64 267.95,65.54 v4(267.62,65.87) 267.6,65.9 R10095.1
N24322210: length 1.5
  TOP w0.127: UL1.6 216.29,69.99 216.34,69.94
  TOP w0.254: 216.34,69.94 216.65,69.94 RL3.1
N24475194: length 7.9
  TOP w0.102: U16.K3 v1(235.91,80.85) ; v1(237.52,86.83) 237.81,87.12 R135.2
  BOTTOM w0.102: v1(235.91,80.85) 235.91,82.9 237.52,84.52 v1(237.52,86.83)
N24475200: length 7.2
  TOP w0.102: U16.L4 v1(235.11,81.65) ; R143.2 237.18,87.41 v1(236.68,86.91)
  BOTTOM w0.102: v1(236.68,86.91) 236.13,86.36 236.13,83.91 235.11,82.89 v1(235.11,81.65)
N24476449: length 8.5
  TOP w0.102: D28.2 229.85,86.66 230.03,86.47 v1(230.03,86.45) ; D28.2 229.86,87.15 230.35,87.15 230.35,87.15 R148.1 ; D28.2 229.78,87.24 229.06,87.24 v4(228.78,86.96) ; U16.L9 v1(230.35,81.65)
  BOTTOM w0.102: v1(230.35,81.65) 230.35,82.9 229.73,83.53 229.73,85.81 230.03,86.12 v1(230.03,86.45)
N24476470: length 4.2
  TOP w0.102: U16.A1 236.89,73.04 236.89,72 237.43,71.45 R155.1 237.44,70.97 R393.2 238.53,70.97 v4(238.88,70.61)
N24476566: length 9
  TOP w0.102: R170.2 221.93,75.02 v1(221.9,75.04) ; U16.E11 v1(228.75,76.1)
  BOTTOM w0.102: v1(221.9,75.04) 222.28,75.42 224.8,75.42 225.08,75.7 227.03,75.7 227.8,76.47 228.38,76.47 v1(228.75,76.1)
N24476572: length 3.6
  TOP w0.102: U16.E12 227.93,76.87 227.34,76.87 226.93,77.28 226.25,77.28 225.75,76.78 R169.1
N24476580: length 5.8
  TOP w0.102: Q8.3 218.02,77.88 218.47,78.33 v4(220.02,78.33) 222.76,78.33 R168.2 222.85,78.35 R166.2
N24477822: length 7.8
  TOP w0.102: C168.2 240.85,80.83 239.86,80.83 R172.2 239.28,80.25 v1(238.31,80.25) 238.08,80.25 237.51,79.67 U16.J1 ; U16.J3 v1(235.91,80.05)
  BOTTOM w0.102: v1(238.31,80.25) 238.11,80.05 237.12,80.05 237.12,80.05 v1(235.91,80.05)
N24477835: length 18.4
  TOP w0.305: U16.F4 v1(235.11,76.9) ; R175.1 R174.1 242.02,67.2 v3(241.65,67.56) 241.11,68.1 v1(241.11,68.21)
  IN1 w0.305: v1(241.11,68.21) 241.69,68.79 241.69,69.96 241.28,70.37 238.9,70.37 237.21,72.06 237.21,73.1 237.65,73.55 v1(237.65,73.85)
  IN3 w0.305: v1(235.11,76.9) 235.11,77.12 235.37,77.38 236.16,77.38 237.37,76.17 237.37,74.13 v1(237.65,73.85)
N24477845: length 8.2
  TOP w0.102: v1(240.95,78.52) 241.21,78.78 C172.2 ; U16.H4 v1(235.11,79.25)
  BOTTOM w0.102: v1(235.11,79.25) 235.49,78.87 237.34,78.87 237.52,79.06 237.98,79.06 238.26,78.78 238.26,78.32 238.52,78.07 240.5,78.07 v1(240.95,78.52)
N24628827: length 13.7
  TOP w0.102: U15.32 283.05,84.13 283.1,84.08 v1(283.1,83.73) ; v1(273.44,83.37) 273.52,83.3 274.2,83.3 274.51,83.6 R110.1
  BOTTOM w0.102: v1(283.1,83.73) 282.1,82.74 279.34,82.74 278.07,84.01 274.91,84.01 274.2,83.3 273.52,83.3 v1(273.44,83.37)
N24848500: length 1.7
  TOP w0.254: R10132.1 284.34,53.7 284.05,53.41 284.05,53 v3(284.08,52.98) 284.13,52.92 Q50.1
N24852194:
  vias: v3(156.31,93.21)
N24852549:
  vias: v3(161.42,93.74)
N24852575: length 3.5
  TOP w0.305: PC52.2 161.06,88.77 ; PC52.2 PR78.2 ; PC52.2 160.45,88.43 PR79.1 ; PR78.2 160.61,87.85 ; PR78.2 161.06,87.52 ; PR79.1 160.43,89.3 PU5.4 ; PR79.1 160.43,88.12
  vias: v3(160.83,86.89)
N24852818: length 0.7
  TOP w0.305: PC52.1 161.65,88.77 ; PR78.1 161.99,87.85
N26183937: length 1
  BOTTOM w0.102: PC449.1 95.49,104.63 v4(95.74,104.38)
N26485146:
  vias: v3(164.02,76.72)
N26485301: length 8.1
  IN3 w0.203: v1(161.83,73.67) 161.63,73.47 v1(156.83,73.47)
  BOTTOM w0.203: PU201.20 161.41,74.09 v1(161.83,73.67) ; PR221.2 v1(156.83,73.47) 156.98,73.47 157.61,74.09 PU201.6
N26485546: length 2.1
  BOTTOM w0.203: PC213.1 159.61,71.32 PU201.3
N26485948: length 3.1
  BOTTOM w0.203: PU201.1 160.64,73.16 161.86,73.16 v4(162.21,72.81) 162.76,72.81 PR217.1
N26485951: length 3
  BOTTOM w0.203: PR218.1 156.73,72.83 v3(157.01,72.55) 157.64,72.55 158.48,73.39 PU201.5
N26486260: length 2.2
  BOTTOM w0.203: PU201.19 161.82,74.49 v4(162.21,74.1) 162.32,74 PR216.1
N26487268:
  vias: v4(155.08,76.69)
N28056116: length 2.3
  TOP w0.127: v1(226.62,60.37) 226.88,60.11 R101.1
  BOTTOM w0.102: J22.6 226.85,60.14 v1(226.62,60.37)
N29079723: length 2
  BOTTOM w0.203: PR222.1 156.83,74.05 v4(156.94,74.17) 157.27,74.49 PU201.7
N29084014: length 0.6
  BOTTOM w0.203: PR210.2 PR215.1
N29087944: length 0.6
  BOTTOM w0.203: PR214.1 PR211.2
N29091068:
  vias: v2(93.77,106.06) v2(94.6,106.09) v2(95.36,106.09) v2(96.13,106.09) v2(96.83,106.03) v2(97.55,106.01) v2(98.18,106.01) v4(95.6,105.18)
N29092457: length 7.9
  BOTTOM w0.254: PR463.1 79.75,103.55 80.42,104.23 84.07,104.23 84.33,104.49 PL401.1
  vias: v4(83.27,110.38)
N29129873: length 3.2
  BOTTOM w0.203: PU401.12 120.96,100.14 120.38,100.72 v4(120.15,100.72) PC402.1
  BOTTOM w0.508: PR402.2 PC402.1
N29129876:
  vias: v3(121.34,103.19)
N29130035:
  vias: v4(128,93.87)
N29130072: length 2.6
  BOTTOM w0.102: PU401.34 127.71,96.54 v4(128.04,96.21) 128.6,95.65 PR407.2
N29134352: length 2.5
  BOTTOM w0.102: PU401.33 127.8,96.94 128.5,96.24 PR409.2
N29134792: length 2.5
  BOTTOM w0.102: PU401.32 127.83,97.34 128.36,96.81 PR408.2
N29138194: length 0.6
  TOP w0.203: PR441.2 122.68,95.44 PC429.1
N29138197: length 4.5
  TOP w0.203: PC428.2 123.27,94.8 PC429.2 123.26,94.23 v3(123.6,93.89) 123.6,93.77 v1(124.14,93.23)
  BOTTOM w0.203: v1(124.14,93.23) 123.98,93.39 PU401.43
N29140206: length 2.9
  BOTTOM w0.203: PU401.31 127.32,97.74 127.42,97.64 v4(128.09,97.64) 128.09,97.51 128.45,97.15 128.93,97.15 129.16,97.38 PR410.1
N29143318: length 4.3
  BOTTOM w0.203: PR430.2 118.14,98.01 117.99,98.16 PR427.1 118.35,98.49 118.5,98.34 PC419.2 PC420.1 119.61,98.34 119.81,98.14 PU401.7
N29338898: length 5.1
  BOTTOM w0.203: PU401.40 125.18,94.17 v4(125.42,93.93) 126.04,93.31 PC430.1 126.04,92.14 125.99,92.09 PC434.2
  BOTTOM w0.254: PR439.1 PR440.1 PC430.1
N29339953: length 2.7
  TOP w0.102: v4(121.5,102.48) 122.01,101.97 v1(122.26,101.97)
  TOP w0.203: PR444.2 v1(122.26,101.97)
  BOTTOM w0.203: PU401.14 122.38,101.85 v1(122.26,101.97)
N29340096: length 3.6
  TOP w0.203: PR445.2 122.25,100.85 122.84,101.45 122.84,102.18 122.64,102.38 122.64,102.4 v1(122.65,102.4)
  BOTTOM w0.203: v1(122.65,102.4) 122.65,102.39 122.78,102.27 PU401.15
N29340279: length 2.8
  TOP w0.203: PR447.2 123.33,100.81 123.99,101.47 v1(123.99,101.89)
  BOTTOM w0.203: v1(123.99,101.89) 123.99,101.76 124.38,101.37 PU401.19
N29340282: length 4
  TOP w0.203: v1(123.66,102.41) 123.36,102.12 v4(123.36,101.85) 123.36,101.43 122.74,100.81 PR446.1
  BOTTOM w0.203: v1(123.66,102.41) 123.53,102.29 123.53,101.69 123.98,101.24 PU401.18
N29340285: length 3.9
  TOP w0.203: v1(124.31,102.41) 124.32,102.41 124.47,102.25 124.47,101.35 123.91,100.79 PR448.1
  BOTTOM w0.203: v1(124.31,102.41) 124.34,102.41 v4(124.71,102.03) 124.78,101.96 PU401.20
N29340288: length 4.4
  TOP w0.203: v1(124.9,102.65) 124.9,101.99 125.22,101.67 v3(125.22,101.49) 125.22,101.39 124.55,100.71 PR449.1
  BOTTOM w0.203: PU401.21 125.18,102.38 v1(124.9,102.65)
N29342092: length 6.1
  TOP w0.203: v1(124.77,93.28) 125.05,93.01 v3(125.4,93.01) 125.4,94.23 124.46,95.17 PR442.2 124.46,95.43 PC432.2
  BOTTOM w0.203: PU401.42 124.38,93.68 v1(124.77,93.28)
N29342095: length 3.9
  TOP w0.203: PC431.2 125.68,95.42 PR443.2 125.69,94.91 v3(125.92,94.68) 126.22,94.38 v1(126.22,93.81)
  BOTTOM w0.203: v1(126.22,93.81) 125.58,94.46 PU401.39
N29343341: length 2.6
  BOTTOM w0.203: PU401.44 v4(123.58,94.04) 123.58,93.72 123.6,93.7 PR438.2 PC427.2
N29343369: length 3.1
  BOTTOM w0.203: PU401.45 123.18,93.77 122.92,93.51 122.64,93.51 122.43,93.3 PR435.2 122.42,93.14 PR473.2
N29343684: length 2.6
  BOTTOM w0.203: PU401.4 120.38,96.94 119.99,96.55 PC423.2 118.89,96.55 PC421.2
N29343703: length 3.9
  BOTTOM w0.203: PR428.2 119.41,95.4 PC422.2 118.86,95.4 PR432.1 118.86,95.96 PC423.1 119.94,95.96 120.52,96.54 PU401.3
N29343706: length 2
  BOTTOM w0.102: v4(116.93,96.37) 117.85,96.37 118.03,96.56 PC421.1
  BOTTOM w0.203: PC421.1 118.3,96 PR432.2
N29343716: length 1.4
  BOTTOM w0.102: PC422.1 117.76,95.4 v4(117.59,95.22)
  BOTTOM w0.203: PR434.2 118.28,94.79 PC422.1
N29343719: length 3.2
  BOTTOM w0.203: PR434.1 119.44,94.78 PR428.1 119.71,94.77 120,95.06 120,95.38 v4(120.32,95.7) 120.76,96.14 PU401.2
N29344201: length 1.3
  TOP w0.305: 121.14,96.61 PC417.2 121.48,97.2 PR425.2 121.14,97.21
  vias: v1(120.94,95.06) v3(120.63,95.72)
N29344768: length 4
  TOP w0.203: PR419.2 PC412.2 127.3,98.31 127.79,98.8 v1(127.79,99.18)
  BOTTOM w0.203: v1(127.79,99.18) 127.63,99.34 PU401.27
N29344811: length 5.9
  TOP w0.203: PR420.2 PC411.2 127.9,96.58 128.68,97.36 v1(128.68,97.63)
  BOTTOM w0.203: PU401.30 127.32,98.14 127.43,98.04 128.27,98.04 v1(128.68,97.63)
N29345521: length 5.1
  TOP w0.203: v1(128.37,99.2) 128.37,99.25 127.97,99.66 126.81,99.66 126.06,98.91 PC410.2 125.93,98.89 PC409.2
  BOTTOM w0.203: PU401.26 127.87,99.74 128.37,99.24 v1(128.37,99.2)
N29345533: length 0.6
  TOP w0.203: PC410.1 125.93,99.48 PR418.2
N29346155: length 3.6
  BOTTOM w0.254: PR414.2 127.06,100.87 127,100.8 PU401.24 126.38,101.39 PR452.2
N29346158: length 2.1
  BOTTOM w0.254: PR415.2 128.56,100.28 PC407.2 127.56,100.29 127.4,100.14 PU401.25
N29347050: length 5.2
  BOTTOM w0.254: PRT405.1 123.83,88.51 v4(125.87,90.54) 126.76,91.43 PR440.2
N29347534: length 3.7
  TOP w0.203: v1(120.08,100.16) 120.76,99.48 PC425.1
  BOTTOM w0.203: PU401.11 120.7,99.74 120.28,100.16 v1(120.08,100.16) 119.51,100.16 PR436.1
N29348069: length 68.4
  IN3 w0.254: v1(115.15,104.81) 114.36,105.6 110.42,105.6 109.13,106.9 109.13,109.71 106.51,112.33 98.74,112.33 98.45,112.04 93.19,112.04 92.55,112.69 67.83,112.69 66.68,111.54 65.44,111.54 64.7,112.28 63.36,112.28 v1(62.47,111.39)
  BOTTOM w0.102: 62.4,111.85 PR437.1
  BOTTOM w0.203: v1(115.15,104.81) 115.43,104.81 116.57,103.67 117,103.67 117.28,103.39 117.28,102.41 116.56,101.69 116.56,100.74 v3(117.1,100.19) 117.89,100.19 118.09,99.99 118.45,99.99 118.45,99.99 PR436.2
  BOTTOM w0.254: PRT404.1 62.47,110.76 v1(62.47,111.39) 62.4,111.45 62.4,111.85
N29348378: length 2
  BOTTOM w0.203: PR433.1 119.54,97.34 v4(120.28,97.34) PU401.5
N29348381: length 62.2
  IN3 w0.152: v1(115.86,98.15) 115.86,98.41 115.66,98.61 114.31,98.61 113.67,97.98 106,97.98 105.17,97.14 103.62,97.14 101.89,98.87 97.8,98.87 96.94,99.73 96.46,99.73 96.35,99.83 93.24,99.83 92.58,99.17 90.79,99.17 89.49,97.88 80.93,97.88 79.86,98.95 79.43,98.95 78.95,99.43 78.95,108.06 77.07,109.94 75.45,109.94 v1(75,110.39)
  BOTTOM w0.203: PU401.6 119.37,97.74 PC420.2 PC419.1 118.78,97.17 PR433.2 PR429.1 118.14,97.1 117.81,96.76 116.69,96.76 115.85,97.6 115.85,98.14 v1(115.86,98.15)
  BOTTOM w0.254: PRT403.1 74.96,110.35 v1(75,110.39)
N29348448: length 56.6
  IN3 w0.152: v1(116.47,98.13) 116.47,98.21 115.81,98.87 113.93,98.87 113.34,98.28 105.95,98.28 105.09,97.42 103.73,97.42 102,99.15 97.9,99.15 97.09,99.96 96.61,99.96 96.48,100.09 93.1,100.09 92.44,99.43 90.65,99.43 89.35,98.14 81.05,98.14 79.98,99.21 79.53,99.21 79.23,99.5 79.23,108.18 77.03,110.39 v1(76.32,110.39)
  BOTTOM w0.203: v1(116.47,98.13) 116.47,97.85 117.15,97.17 PR429.2 117.56,97.75 PR430.1
  BOTTOM w0.254: PRT403.2 75.95,110.02 v1(76.32,110.39)
N29349112: length 5
  TOP w0.102: PC418.1 120.77,97.9 120.25,97.38 v3(120.02,97.38)
  TOP w0.203: PC418.1 120.37,98.28 v1(120.05,98.61) 119.57,98.13 PC414.2 119.36,98.11 PR423.2
  BOTTOM w0.203: PU401.8 120.12,98.54 v1(120.05,98.61)
N29349219: length 3.4
  TOP w0.203: v1(119.82,99.63) 119.37,99.18 PC414.1 119.36,98.73 PR421.1
  BOTTOM w0.203: v1(119.82,99.63) 120.28,99.63 120.57,99.34 PU401.10
N29349790: length 4.4
  TOP w0.203: PC408.1 125.7,100.65 PR416.1 126.11,101.06 126.11,102.25 v1(125.96,102.4)
  BOTTOM w0.203: PU401.23 125.98,101.51 126.21,101.74 v4(126.21,101.95) 126.21,102.15 v1(125.96,102.4)
N29349854: length 42.6
  TOP w0.254: PR416.2 126.05,100.08 126.6,100.63 126.6,103.19 v1(126.01,103.78)
  IN3 w0.254: v1(126.01,103.78) 125.68,103.44 118.6,103.44 116.9,101.74 110.78,101.74 109.61,102.91 100.69,102.91 99.32,104.28 95.82,104.28 94.93,103.39 94.93,102.76 94.4,102.22 93.3,102.22 v1(93.17,102.35)
  BOTTOM w0.203: v1(93.17,102.35) 93,102.18 93,101.93 PRT402.1 93.54,101.38 PR417.1
N29350272: length 5
  BOTTOM w0.203: PR413.1 131.42,97.91 PR411.1 130.84,97.95 PC433.1 129.22,97.95 PC405.1 128.99,97.97 128.6,98.37 127.52,98.37 127.35,98.54 PU401.29
N29350295: length 58
  IN3 w0.203: v1(131.22,99.74) 131.14,99.66 131.14,99.27 129.98,98.11 126.37,98.11 126.22,98.26 122.44,98.26 121.55,97.37 118.88,97.37 118.3,97.95 117.31,97.95 115.86,99.4 104.5,99.4 102.93,100.98 96.76,100.98 96.15,100.37 92.97,100.37 92.36,99.76 88.83,99.76 87.47,98.4 81.46,98.4 80.14,99.71 v1(79.66,99.71)
  BOTTOM w0.254: v1(131.22,99.74) 131.22,99.41 131.65,98.97 PR413.2 ; v1(79.66,99.71) 80.02,99.71 80.32,100.01 PRT401.1
N29547847: length 2.6
  BOTTOM w0.102: v4(94.47,102.68) 94.47,103.14 PR453.1
  BOTTOM w0.254: PR453.1 93.73,103.88 PU402.30
N29548224: length 0.9
  BOTTOM w0.102: PC449.2 v4(93.96,105.5)
N29600783: length 1.4
  BOTTOM w0.203: PR473.1 121.81,91.92 PC424.2 121.18,91.92 v4(121.08,91.81)
N29600817: length 2.7
  BOTTOM w0.203: PR475.1 128.63,95.08 v4(128.56,95.01) 127.43,96.14 PU401.35
N29612662: length 0.9
  BOTTOM w0.102: PR305.2 121.88,66.1 121.83,66.15 v4(121.83,66.48)
N29612670: length 3.6
  TOP w0.254: PR304.1 123.31,66 v4(123.01,65.7) 122.9,65.7 v1(122.08,64.88)
  BOTTOM w0.254: v1(122.08,64.88) 122.26,64.88 122.69,64.45 PU301.19
N29612674: length 4.7
  TOP w0.254: PR303.2 123.6,65.05 123.6,64.03 v4(123.34,63.77) 122.48,63.77 v1(122.01,64.25)
  BOTTOM w0.254: v1(122.01,64.25) 122.36,64.25 122.56,64.05 PU301.18
N29612764:
  vias: v4(122.79,60.85)
N29665536: length 0.8
  BOTTOM w0.102: TP56.1 152.43,97.55 PR749.2
N29668691: length 1
  BOTTOM w0.254: PR452.1 127.48,101.72 127.76,101.44 PC404.2
N29795820: length 2.3
  BOTTOM w0.203: PU401.9 120.48,98.94 120.28,99.14 v4(120.08,99.14) 119.4,99.14 PR450.1
N29796111: length 1.2
  BOTTOM w0.102: v3(91.18,101.02) 90.57,100.42 PC451.1
N30910915: length 2.2
  TOP w0.102: R90.1 275.19,83.65 v4(274.96,83.42) 274.81,83.27 U12.16
N31995447: length 2.2
  TOP w0.102: R89.1 275.8,83.73 275.31,83.23 U12.15
N36983374: length 2.2
  BOTTOM w0.127: R231.1 v4(163.62,64.2) 163.62,64.72 164.13,65.22 Q14.3
N37033408: length 2.1
  TOP w0.305: PC27.1 264.22,90.56 PR45.2 PR44.1 PR43.1
N37033752: length 2
  TOP w0.254: Q23.4 251.84,53.33 v4(251.84,54.25) 251.84,54.43 251.54,54.73 R305.2
N37033767: length 3.4
  TOP w0.254: R389.2 113.9,101.05 114.38,100.58 114.38,100.04 v3(114.24,99.9) 114.12,99.79 113.72,99.79 113.47,100.03 Q33.4
N39421875: length 27.9
  TOP w0.102: v1(90.07,54.32) 90.07,54.34 89.97,54.44 RC154.1 89.32,54.47 RC10.1 ; RC10.1 88.62,55.47 v4(88.6,55.49) ; RC10.1 88.62,53.86 CC76.2
  IN4 w0.076: v1(90.07,54.32) 94.39,58.64 100.29,58.64 101.1,59.45 101.1,65.65 99.76,67 99.76,69.15 v1(99.66,69.25)
  BOTTOM w0.076: U1.AT13 99.66,69.81 v1(99.66,69.25)
N39422981: length 5.8
  BOTTOM w0.076: U1.C63 71.79,88.13 71.87,88.39 71.87,89.36 71.74,89.5 71.74,90.26 71.28,90.72 v4(71.28,91.3) 71.28,92.19 71.54,92.44
  BOTTOM w0.089: 71.54,92.44 71.82,92.72 RC15.1
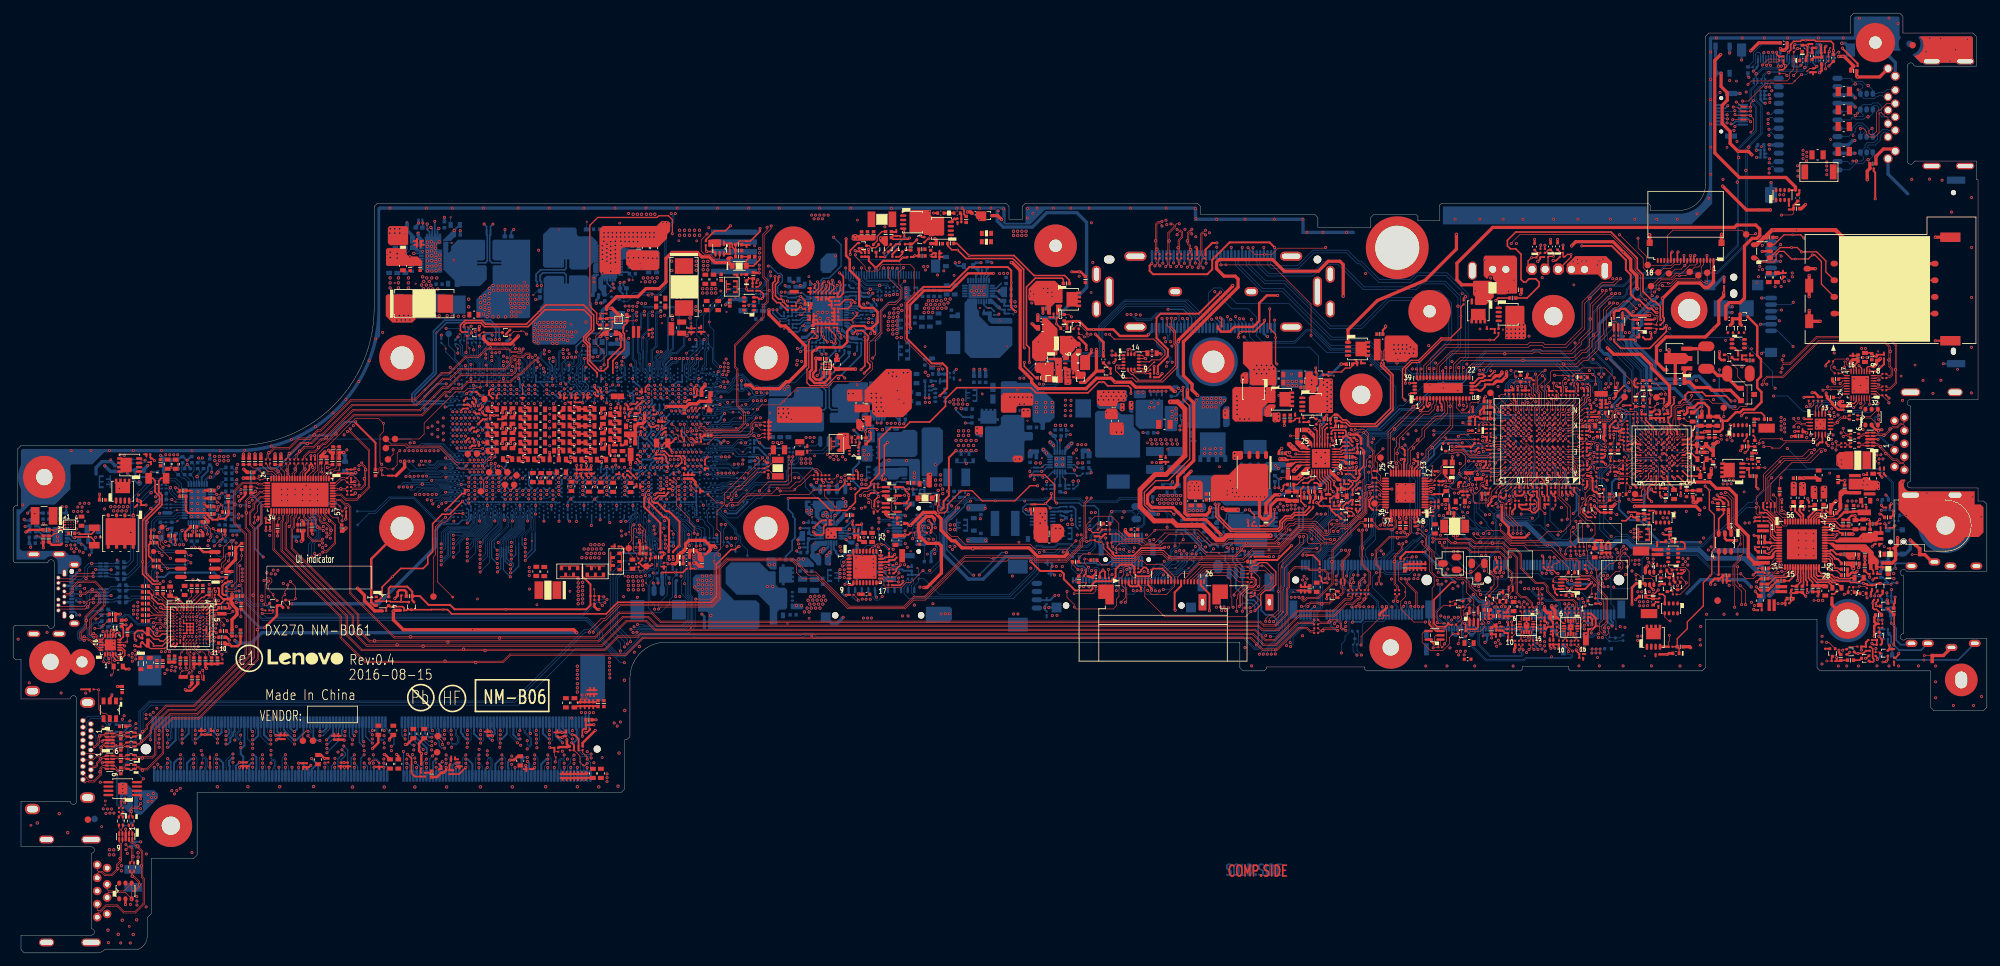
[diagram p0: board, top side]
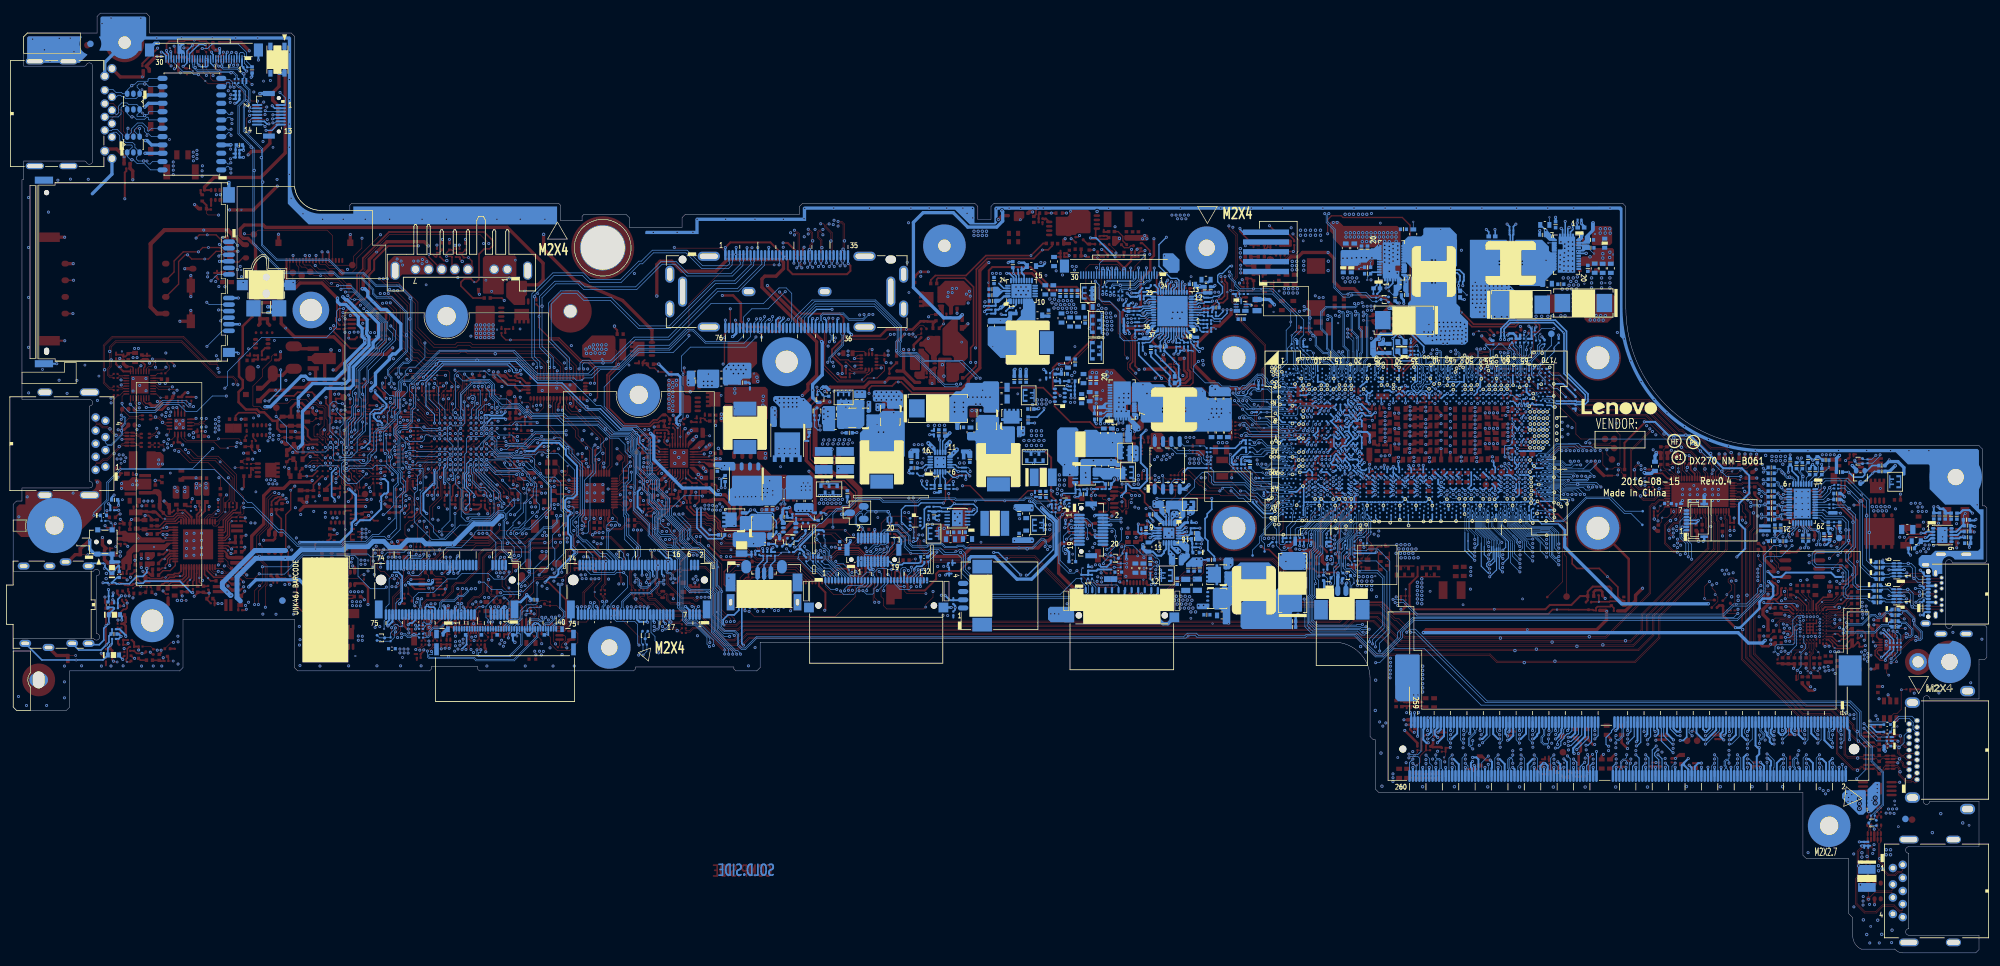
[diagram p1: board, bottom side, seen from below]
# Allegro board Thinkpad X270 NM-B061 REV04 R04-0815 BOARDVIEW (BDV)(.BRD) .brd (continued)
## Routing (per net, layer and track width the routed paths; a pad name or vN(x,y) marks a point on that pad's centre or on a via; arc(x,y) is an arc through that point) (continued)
N39424064: length 2.2
  TOP w0.254: RC17.2 99.21,70.17 v4(98.37,70.17) 98.08,70.17 v1(97.83,69.91)
  BOTTOM w0.254: U1.AT16 v1(97.83,69.91)
N39424067: length 3.1
  TOP w0.254: RC18.2 99.72,70.09 99.72,70 99.5,69.79 99.46,69.75 98.45,69.75 97.97,69.27 v1(97.81,69.27)
  BOTTOM w0.254: U1.AU16 97.83,69.28 v1(97.81,69.27)
N39424070: length 1.2
  TOP w0.254: v1(69.15,84.64) 69.12,84.64 68.82,84.35 RC19.2
  BOTTOM w0.254: U1.H66 69.28,84.51 v1(69.15,84.64)
N39424073: length 1.4
  TOP w0.254: v1(70.19,84.7) 70.6,84.3 RC20.2
  BOTTOM w0.254: U1.H65 70.38,84.51 v1(70.19,84.7)
N39427468: length 17.3
  TOP w0.102: v1(102.35,80.66) 102.35,79.23 102.92,78.66 102.92,78.33 103.31,77.94 103.74,77.94 104.03,77.65 105.91,77.65 v4(106.02,77.77) 106.93,78.68 112.09,78.68 112.78,79.37 112.78,80.73 113.04,80.99 RC24.1
  BOTTOM w0.076: U1.R10 102.35,80.81 v1(102.35,80.66)
N39479511: length 1.8
  TOP w0.127: RC34.1 104.1,70.45 v1(103.31,71.23)
  BOTTOM w0.076: U1.AR7 103.45,71.23 v1(103.31,71.23)
N39481801: length 1.9
  TOP w0.102: RC37.1 94.73,58.9 RC36.2 95.39,58.46 v4(95.64,58.2)
N39482349: length 2
  TOP w0.254: RC43.1 104.1,77.99 103.57,78.52 v1(103.35,78.52)
  BOTTOM w0.254: U1.AB7 103.93,77.94 v1(103.35,78.52)
N39518225: length 3.8
  TOP w0.102: QC2.1 74.58,94.7 v4(73.69,94.7) RC72.1 71.52,94.7 QC3.2
N39518574: length 1.8
  BOTTOM w0.102: UC3.4 141.26,68.79 141.6,68.45 RC59.2 RC60.2
N39523416: length 4.3
  BOTTOM w0.102: S1.4 S1.3 285.85,65.44 v3(286.03,65.63) 286.33,65.93 RC71.1
N39556609: length 9
  BOTTOM w0.127: v1(65.89,74) 65.91,73.98 U1.AK70 ; U1.AK55 76.34,73.46 76.34,73.46
  BOTTOM w0.203: U1.AU63 71.61,69.61 71.31,69.91 v1(71.31,71.82)
  BOTTOM w0.254: v1(69.24,65.59) 69.78,66.13 69.78,66.79 U1.BB66 ; v1(75.07,69.23) 74.89,69.23 U1.AU58 ; U1.AM56 75.03,72.47 v1(74.97,72.47) ; v1(74.94,66.03) 74.86,66.1 74.86,66.83 U1.BB57 ; v1(77.68,72.43) 78.12,72.86 U1.AM52 ; v1(74.05,72.47) 74.45,72.86 U1.AM58
N39575490: length 1.3
  TOP w0.254: RC86.1 93,72.73 v1(93.25,72.47)
  BOTTOM w0.254: v1(93.25,72.47) 93.65,72.86 U1.AM23
N39575498: length 1.4
  TOP w0.254: RC90.2 93.68,72.96 v1(94.17,72.47)
  BOTTOM w0.254: U1.AM22 94.56,72.86 v1(94.17,72.47)
N39920601: length 164.2
  TOP w0.305: 265.29,91.17 PR43.2 264.83,91.5
  TOP w0.508: v2(202.81,100.23) 202.81,105.03 202.3,105.54 200.52,105.54 199.01,104.03 193.8,104.03 192.03,105.81 183.9,105.81 183.49,105.4 183.49,104.41 184.63,103.27 186.34,103.27 186.78,102.83 186.78,101.59 178.44,93.25 178.44,88.1 179.76,86.78 179.76,85.92 v1(180.62,85.06) ; v1(179.61,73.5) 178.67,72.57 178.67,67.14 179,66.82 181.92,66.82 182.43,67.34 182.43,67.79 182.55,67.91 v1(182.55,67.99)
  IN3 w0.508: v2(263.6,89.45) 263.6,89.1 262.87,88.36 259.13,88.36 258.29,89.2 258.29,94.12 259.13,94.96 259.13,100.53 257.89,101.77 254.31,101.77 251.61,99.08 249.94,99.08 248.03,97.17 241.12,97.17 236.88,101.41 232.44,101.41 229.8,98.77 222.45,98.77 218.67,94.99 215.17,94.99 212.02,98.14 204.9,98.14 v2(202.81,100.23) ; v1(179.61,73.5) 179.61,74.77 180.06,75.23 180.06,84.5 v1(180.62,85.06)
  BOTTOM w0.381: v1(182.55,67.99) 182.58,68.01 182.65,68.01 182.81,67.86 183.44,67.86 183.61,67.69 PR40.2 183.61,66.98 183.85,66.74 PC26.2 183.85,66.19 183.51,65.85 PQ21.4
  vias: v3(265.08,92.19)
N39920640: length 2.2
  BOTTOM w0.254: PR42.2 182.13,66.42 PR41.1 182.8,66.4 PC26.1 182.94,67.21 PR40.1
N39920674: length 3.8
  BOTTOM w0.254: PR42.1 179.78,66.98 v4(179.52,66.73) 178.81,66.01 PQ22.1
N39920740: length 1.1
  TOP w0.305: PQ24.1 262.39,90.56 PR45.1
N39921018: length 0.8
  BOTTOM w0.254: PR41.2 181.57,65.57
N40031233: length 0.8
  BOTTOM w0.254: R1.1 140.69,87.26 D1.2
N40031285: length 1
  BOTTOM w0.254: R2.2 140.11,85.84 140.34,86.08 Q1.4
N40033673: length 7.3
  TOP w0.305: v1(275.54,138.55) 275.66,138.43 C298.2 275.74,137.32 F5.1 275.15,136.67 275.14,136.66 274.63,136.66 F6.1
  BOTTOM w0.203: J11.25 275.65,137.25 275.45,137.45 275.35,137.45 ; 275.35,137.45 275.02,137.45 274.85,137.29 J11.23 ; 275.35,137.45 275.25,137.36 J11.24
N40033695: length 3.7
  TOP w0.254: R10.2 269.86,134.75 270.24,135.13 v1(270.24,135.37) 269.92,135.69 C20.2
  BOTTOM w0.203: v1(270.24,135.37) 270.42,135.37 270.85,135.79 J11.13
N40033718: length 2.8
  TOP w0.508: F3.1 270.49,138.15 270.11,137.76 v4(270.08,137.76) 269.7,137.76 v1(269.47,137.99)
  BOTTOM w0.381: 269.48,137.24 269.44,137.28 269.44,137.96 v1(269.47,137.99)
N40033888: length 9.7
  TOP w0.127: R6.1 273.97,134.97 v4(273.55,134.55)
  TOP w0.254: R6.1 274.7,134.97 v1(275.03,135.3)
  TOP w0.305: v1(273.56,138.51) 273.59,138.48 273.59,136.93 273.37,136.71 D16.2 ; v1(273.56,138.51) 273.74,138.69 R15.1 ; v1(273.56,138.51) 273.56,138.52 D2.2
  BOTTOM w0.203: v1(275.03,135.3) 274.93,135.3 274.45,135.78 J11.22 274.45,137.62 v1(273.56,138.51)
N40033918: length 12.5
  TOP w0.254: F4.1 v1(277.56,137.7) 277.56,138.72 277.17,139.11 274.86,139.11 274.68,139.29 v3(273.33,139.29) 272.7,139.29 272.52,139.11 271.5,139.11 271.05,138.65 271.05,137.8 v1(270.7,137.45)
  BOTTOM w0.203: v1(277.56,137.7) 277.56,137.48 277.25,137.17 J11.29 ; J11.12 270.45,137.08 270.7,137.32 v1(270.7,137.45)
N40034001: length 2.6
  TOP w0.127: v1(276.92,137.53) 276.92,137.92 v4(277.06,138.07)
  TOP w0.203: v1(276.92,137.53) 276.78,137.39 R7.2
  BOTTOM w0.203: v1(276.92,137.53) 276.85,137.46 J11.28
N40088132: length 9.3
  TOP w0.508: CC39.2 106.23,85.15 106.23,84.23 CC40.2 104.64,84.18 104.25,83.79 103.19,83.79 CC41.1 103.1,83.8 102.6,83.3 RC97.2 102.25,83.39 101.29,83.39 99.68,83.39 v1(99.56,83.27)
  BOTTOM w0.254: U1.L15 99.22,82.85 v1(99.56,83.27) 99.22,83.68 U1.K15
N40088146: length 1.4
  TOP w0.305: v1(98.89,79.06) 99.36,79.53 CC99.2
  BOTTOM w0.254: v1(98.89,79.06) 98.89,79.17 U1.V15
  vias: v4(96.44,78.38)
N40088321: length 5.9
  BOTTOM w0.102: CC38.2 111.57,73.29 v4(110.45,73.29) 109.97,72.81 107.23,72.81 U1.AL1
N40089937: length 1.3
  TOP w0.102: 97.34,85.03 97.34,85.66
  BOTTOM w0.254: v1(96.96,84.16) 96.96,84.03 U1.K19
  vias: v4(98.92,96.1)
N40089981: length 5.6
  BOTTOM w0.076: 102.85,66.51 102.56,66.81 101.8,66.81 U1.BB10
  BOTTOM w0.102: 102.85,66.51 102.85,66.1 104.17,64.78 104.58,64.78 104.94,64.43 104.94,63.5 CC42.2
N40089989: length 15.7
  IN3 w0.508: v1(93.23,82.44) 93.23,83.02 92.82,83.42 92.82,84.87 93.02,85.08 93.02,88.73 93.46,89.17 93.46,90.51 93.07,90.89 v1(93.05,90.89)
  BOTTOM w0.254: v1(93.23,82.44) 93.37,82.44 93.82,81.98 94.73,81.98 95.16,82.41 95.57,82.41 U1.N20
  BOTTOM w0.508: 93.58,91.54 93.58,91.19 93.28,90.89 v1(93.05,90.89) ; 93.58,91.54 CC44.2 CC45.2 ; 93.58,91.54 RC96.1
N40090005: length 6.1
  TOP w0.508: v1(96.29,82.38) v4(96.29,81.24) 96.29,81.09 95.96,80.76 95.26,80.76 CC49.2 RC99.1 94.84,79.12 CC48.2
  BOTTOM w0.254: v1(96.29,82.38) 96.62,82.8 U1.L19
N40121322: length 7.9
  BOTTOM w0.127: U1.E70 67.37,87.42 68.31,88.36 68.31,88.63 68.16,88.78 68.16,89.52 65.97,91.71 v4(65.97,92.21) 65.97,92.43 RC100.2
N40140775: length 2.3
  TOP w0.127: RC102.2 69.43,85.61 v1(69.17,85.36)
  BOTTOM w0.076: U1.G69 68.25,85.47 68.6,85.13
  BOTTOM w0.127: 68.6,85.13 68.94,85.13 v1(69.17,85.36)
N40141073: length 1.7
  TOP w0.254: v1(75.85,70.55) 76.39,71.08 TP27.1
  BOTTOM w0.254: U1.AR56 75.49,70.91 v1(75.85,70.55)
N40141075: length 2.1
  TOP w0.254: v1(74.96,70.55) 74.99,70.57 TP28.1
  BOTTOM w0.254: v1(74.96,70.55) 74.96,71.16 75.37,71.56 U1.AP56
N40141187: length 5.1
  BOTTOM w0.102: RC104.1 106.79,64.93 105.9,65.82 105.9,66.84 105.75,66.99 105.75,67.47 U1.AY3
N40141189: length 4.8
  TOP w0.254: RC107.1 68.45,70.08 65.95,67.58 v1(65.95,67.55)
  BOTTOM w0.254: U1.AY71 66.01,67.61 v1(65.95,67.55)
N40141199: length 5.7
  BOTTOM w0.076: 69.57,91.51 69.91,91.17 69.91,90.93 70.93,89.91 70.93,88.27 U1.C64
  BOTTOM w0.102: RC110.1 69.35,92.48 v4(69.57,92.26) 69.57,91.51
N40169308: length 1.6
  TOP w0.102: RL4.2 208.17,71.76 208.56,71.37 208.59,71.37 208.77,71.19 UL1.28
N40169311: length 1.7
  TOP w0.102: RL5.2 208.22,70.6 208.82,69.99 UL1.31
N40199736: length 6.5
  TOP w0.152: U16.E8 v1(231.15,76.1) ; v1(232.98,71.77) 233.13,71.61 R140.2
  IN4 w0.152: v1(231.15,76.1) 231.73,75.51 231.73,73.01 v1(232.98,71.77)
N40199739: length 3.4
  TOP w0.152: U16.B8 231.15,73.7 231.15,73.14 230.9,72.88 230.9,71.08 R142.2
N40201576: length 7.9
  TOP w0.102: R144.2 223.91,72.73 v1(224.16,72.99) ; U16.D10 v1(229.55,75.3)
  BOTTOM w0.102: v1(229.55,75.3) 229.55,75.15 229.16,74.75 229.16,74.35 229.14,74.33 229.14,74.33 228.92,74.1 228.51,74.1 227.39,72.99 v1(224.16,72.99)
N40201579: length 10
  TOP w0.102: v1(223.3,72.99) 223.3,73.49 v4(223.28,73.52) 222.69,73.52 R145.2 ; U16.E10 v1(229.55,76.1)
  BOTTOM w0.102: v1(229.55,76.1) 229.17,75.71 229.17,75.07 229.02,74.92 228.51,74.92 227.21,73.62 223.88,73.62 223.3,73.04 v1(223.3,72.99)
N40213362: length 9.5
  TOP w0.102: U16.D9 v1(230.35,75.3) ; v1(228.15,69.74) 228.15,69.56 228.53,69.18 228.53,68.78 R165.1
  BOTTOM w0.102: v1(230.35,75.3) 230.74,74.9 230.74,74.33 231.02,74.05 231.02,73.11 230.84,72.94 230.84,72.1 229.78,71.03 229.04,71.03 228.15,70.14 v1(228.15,69.74)
N40213365: length 11.1
  TOP w0.102: v1(228.1,69.02) 227.67,68.59 R167.1 ; v1(231.35,72.17) 231.45,72.17 231.91,72.63 231.91,76.89 U16.F8
  BOTTOM w0.102: v1(231.35,72.17) 229.8,70.62 229.17,70.62 228.74,70.19 228.74,69.66 v1(228.1,69.02)
N40218948: length 10.4
  TOP w0.102: R186.2 224.86,77.84 224.34,77.84 v1(224.04,78.14) ; U16.F9 v1(230.35,76.9)
  BOTTOM w0.102: v1(224.04,78.14) 224.93,79.03 226.86,79.03 227.47,79.64 228.2,79.64 228.38,79.46 228.38,78.98 229.7,77.66 229.7,77.55 v1(230.35,76.9)
N40218953: length 2.4
  TOP w0.102: U16.A9 230.62,73.16 230.62,71.54 230.41,71.34 R187.2
N40218963: length 8.3
  TOP w0.102: U16.E5 v1(234.31,76.1) ; R185.2 241.28,76.14 v1(241.06,76.36)
  BOTTOM w0.102: v1(234.31,76.1) 234.31,76.1 234.71,76.49 239.46,76.49 239.63,76.67 240.75,76.67 v1(241.06,76.36)
N40220825: length 7.6
  TOP w0.102: U16.D4 v1(235.11,75.3) ; v1(241.02,74.85) 241.14,74.97 R180.1
  BOTTOM w0.102: v1(235.11,75.3) 235.51,74.89 239.2,74.89 239.63,74.46 240.27,74.46 240.36,74.55 240.68,74.55 240.99,74.86 241.02,74.86 241.02,74.85 v1(241.02,74.85)
N40220830: length 2.6
  TOP w0.102: U16.A2 236.56,73.04 236.56,72.2 236.23,71.87 236.23,71.04 R179.1
N40224251: length 3.4
  TOP w0.102: U16.M4 235.14,82.48 235.14,83.63 234.98,83.78 234.98,84.9 R193.2
N40224256: length 2.7
  TOP w0.102: U16.N2 236.33,83.47 237.31,84.45 237.31,84.77 237.36,84.83 R194.2
N40224261: length 4.7
  TOP w0.102: U16.M2 236.55,82.07 236.97,82.49 237.29,82.49 239.15,84.35 v4(239.15,84.42) 239.18,84.44 239.18,84.76 R195.2
N40224266: length 5
  TOP w0.102: R196.2 237.94,84.3 236.71,83.07 236.71,82.71 236.48,82.49 236.15,82.49 235.92,82.26 235.92,81.67 U16.L3
N40224271: length 3.7
  TOP w0.102: R197.2 239.47,83.06 v4(239.25,82.84) 238.54,82.13 238.54,82.05 237.76,81.27 U16.L1
N40224294: length 4
  TOP w0.102: U16.J2 236.73,80.07 237.47,80.07 238.23,80.83 239.35,80.83 R198.2
N40224614: length 2.2
  TOP w0.102: U16.E1 R202.2
N40238712: length 2.2
  TOP w0.102: D31.1 166.28,65.47 R233.2 v3(165.41,65.49)
N40247293: length 4.2
  TOP w0.102: R266.2 248.3,81.31 v4(248.8,80.81) 250.12,79.49 250.12,78.75 U21.H6
N40247656: length 3.8
  TOP w0.102: U21.C6 250.91,73.96 250.91,71.64 250.46,71.19 R258.1
N40247661: length 3.4
  TOP w0.102: R257.1 246.25,73.13 247.06,73.93 248.29,73.93 248.68,74.33 U21.C8
N40247666: length 2.3
  TOP w0.102: R256.1 246.61,74.33 U21.C9
N40248108: length 2.1
  TOP w0.102: R259.1 248.12,71.9 U21.A8
N40249057: length 11
  TOP w0.102: R260.1 251.6,83.84 v1(251.6,82.99) ; U21.E7 249.69,75.93 v1(249.35,76.27)
  BOTTOM w0.102: v1(249.35,76.27) 249.76,75.85 250.32,75.85 250.73,76.26 250.73,77.5 250.48,77.75 250.48,78.25 251.11,78.88 251.11,80.23 250.63,80.71 250.63,81.63 251.6,82.6 v1(251.6,82.99)
N40255208: length 5.8
  TOP w0.102: U21.D6 250.12,75.55 246.94,75.55 246.5,75.11 R286.1 246.05,75.39 246.31,75.65 v4(246.31,75.96)
N40255459: length 30.2
  TOP w0.254: R277.1 267.04,81.95 266.56,82.44 263.99,82.44 v1(263.51,81.95) ; U21.C5 v1(251.77,73.9)
  IN4 w0.254: v1(251.92,68.93) 252.13,68.93 253.76,70.55 254.53,70.55 257.14,73.16 257.14,73.74 259.13,75.73 261.38,75.73 263.51,77.86 v1(263.51,81.95)
  BOTTOM w0.254: v1(251.92,68.93) 251.92,69.24 252.38,69.71 252.38,73.29 v1(251.77,73.9)
N40256670: length 14.8
  TOP w0.102: v1(251.93,85.25) 251.93,85.56 v4(250.82,86.67) 250.6,86.89 250.07,86.89 249.62,87.35 D64.2 D65.2 248.47,87.35 248.03,86.91 R405.1 ; v1(251.55,80.12) 250.91,79.49 250.91,78.76 U21.H5
  IN4 w0.076: v1(251.55,80.12) 251.32,80.12 249.87,81.57 249.87,83.65 250.96,84.75 251.42,84.75 v1(251.93,85.25)
N40257016: length 78.2
  TOP w0.254: v1(257.46,83.32) 257.21,83.32 256.35,82.47 256.1,82.47 R281.1
  TOP w0.508: v1(260.42,134.23) 260.42,132.21 261.37,131.26 261.37,130.12 260.58,129.33 260.58,126.56 261.8,125.34 261.8,123.53 v4(263.01,122.32) 264.57,122.32 v1(265.11,121.78)
  IN4 w0.508: v1(250.68,100.11) 252.54,101.97 255.74,101.97 265.11,111.34 v1(265.11,121.78)
  BOTTOM w0.508: v1(257.46,83.32) 257.46,84.7 255.28,86.88 250.28,86.88 249.73,87.43 249.73,89.66 246.69,92.7 246.69,93.99 247.05,94.35 247.05,94.91 246.97,94.98 246.97,96.63 250.02,99.68 250.25,99.68 v1(250.68,100.11) ; S3.1 S3.2 v1(260.42,134.23)
N40263086: length 0.9
  TOP w0.254: R290.2 129.07,77.67 128.88,77.47 Q17.3
N40263128:
  vias: v3(126.9,78.93)
N40263130: length 0.8
  TOP w0.254: R292.1 D41.2
N40263477: length 1.2
  TOP w0.254: R295.2 250.22,67.48 Q19.4
N40263481: length 0.3
  TOP w0.305: 249.48,65.35 R294.2
  vias: v4(250.28,64.6)
N40263483: length 0.9
  TOP w0.254: D42.2 248.87,66.28 R294.1
N40264076: length 0.3
  TOP w0.305: R297.1 265.34,79.87
  vias: v3(264.29,81.63)
N40264078: length 0.9
  TOP w0.203: R297.2 265.57,78.71 D43.2
N40264116: length 1.1
  TOP w0.102: Q20.4 264.64,74.66 R299.2
N40264120: length 1.1
  TOP w0.203: R301.2 263.95,78.23 264.33,78.61 Q21.4
N40264254: length 1.9
  TOP w0.102: v3(267.12,74.04) D44.2 266.07,74 R296.1
N40298441: length 3.9
  TOP w0.127: RD11.2 55.37,29.43 54.8,29.43 v1(54.34,28.96)
  BOTTOM w0.127: v1(54.34,28.96) 54.53,28.77 J21.134
N40300707: length 0.7
  TOP w0.254: RD10.2 62.16,28.08 CD26.1
N40660374: length 1.1
  TOP w0.305: 226.73,48.27 C301.1 ; 225.76,48.62 C271.1 226.09,48.17
  vias: v1(225.99,47.36) v1(226.2,46.8) v1(226.48,47.71) v1(226.73,47.15) v1(230.44,48.3) v1(230.67,47.67) v1(231.01,48.18) v3(224.13,48.35)
N40843801: length 3.7
  TOP w0.102: v1(162.37,58.48) 161.52,59.33 R223.2
  BOTTOM w0.102: v1(162.37,58.48) 163.6,57.25 J38.28
N40843803: length 4.5
  TOP w0.102: R224.2 161.71,56.68 v4(161.62,56.68)
  TOP w0.127: R224.2 162.49,57.64 162.95,58.1 v1(162.95,58.48)
  BOTTOM w0.102: J38.27 164.1,57.21 162.95,58.36 v1(162.95,58.48)
N40843805: length 4.8
  TOP w0.102: v1(163.98,58.84) 163.37,59.45 v3(163.37,60.11) 163.76,60.11 163.93,59.94 R225.2
  BOTTOM w0.102: J38.26 164.6,57.54 163.98,58.16 v1(163.98,58.84)
N40893685: length 16.2
  TOP w0.102: TP17.1 64.09,60.43 64.42,60.77 64.42,65.06 65.83,66.46 v1(65.95,66.46)
  BOTTOM w0.076: U1.AY68 67.82,67.54 67.73,67.45 67.17,67.45 67.01,67.3 66.3,67.3 65.97,66.97 65.97,66.48 v1(65.95,66.46)
N40914474: length 2.2
  TOP w0.127: TP19.1 72.86,73.62 72.86,74.66 v1(72.89,74.7)
  BOTTOM w0.127: U1.AJ62 72.49,74.29 v1(72.89,74.7)
N40914475: length 3.2
  TOP w0.127: TP18.1 71.74,70.85 71.74,72.02 v1(71.31,72.45)
  BOTTOM w0.127: v1(71.31,72.45) 71.82,72.97 U1.AL63
N40914505: length 1.5
  TOP w0.102: v1(71.66,76.14) 71.61,76.19 TP21.1
  BOTTOM w0.127: U1.AE63 71.92,76.39 v1(71.66,76.14)
N40914507: length 3.3
  TOP w0.102: v1(71.59,76.97) 70.16,76.97 TP20.1
  BOTTOM w0.127: U1.AC63 71.92,77.31 v1(71.59,76.97)
N40914545: length 19.6
  TOP w0.102: TP22.1 57.59,77.66 59.98,77.66 60.28,77.36 65.13,77.36 67.68,74.81 71.73,74.81 72.6,75.68 v1(72.86,75.68)
  BOTTOM w0.127: v1(72.86,75.68) 72.86,75.42 72.64,75.21 U1.AG62 U1.AE62
N40914597: length 26.7
  TOP w0.102: v1(73.47,75.7) 73.47,75.7 72.94,75.17 72.5,75.17 72.27,74.94 72.27,74.4 71.69,73.82 68.26,73.82 65.01,77.08 60.08,77.08 59.75,77.41 57.21,77.41 TP23.1
  BOTTOM w0.127: U1.P62 72.39,81.14 72.07,80.82 72.07,80.56 72.32,80.31 72.32,79.84 U1.V62 72.39,79.31 72.07,78.99 72.07,78.73 72.39,78.41 U1.AB62 72.39,77.77 72.75,77.41 73.47,77.41 73.56,77.32 73.56,75.79 v1(73.47,75.7)
N40914964: length 3
  TOP w0.127: TP24.1 73.5,73.81 v1(73.5,74.7)
  BOTTOM w0.127: v1(73.5,74.7) 72.79,73.99 72.79,73.89 U1.AK62
N40914967: length 3.3
  TOP w0.127: TP25.1 74.43,74.28 v1(74.02,74.28)
  BOTTOM w0.127: U1.AL61 73.14,73.83 73.59,74.28 v1(74.02,74.28)
N40915396: length 3.6
  BOTTOM w0.102: v3(115.3,101.1) 114.33,101.1 113.97,100.74 RC134.1 ; UC4.7 113.71,99.87 113.97,100.13 RC134.1 ; RC134.1 113.96,100.55 RC155.2
N40941652: length 13.6
  TOP w0.102: v1(243.24,49.62) 243.24,48.75 242.99,48.5 242.53,48.5 241.86,49.17 241.86,50.26 242.47,50.87 242.47,53.97 242.33,54.11 Q30.3 241.27,54.5 241.3,54.52 R408.1
  BOTTOM w0.102: J22.67 242.1,50.75 241.63,50.27 v4(241.63,49.85) 241.68,49.8 242.05,49.8 242.35,50.1 242.76,50.1 v1(243.24,49.62)
N41161893: length 6.2
  TOP w0.102: R314.1 12.96,40.22 v3(13.03,40.15) 13.06,40.12 13.06,37.15 13.7,36.51 14.21,36.51 14.74,35.98 U23.5
N41183802: length 3.1
  TOP w0.102: v3(252.54,48.48) 252.54,47.6 252.42,47.48 R373.2
  TOP w0.381: R373.2 251.66,46.72 251.66,46.72 Q26.4
N41183816: length 2.1
  TOP w0.381: R372.2 v4(252.12,45.55) 252.29,45.55 252.45,45.71 D58.2
N41203653: length 4.3
  TOP w0.102: v1(70.93,83.48) 71.87,84.42 TP37.1
  BOTTOM w0.127: U1.G61 72.3,85.1 U1.H63 71.15,84.51 70.93,84.29 v1(70.93,83.48)
N41608255:
  vias: v3(166.68,82.44)
N41608262:
  vias: v4(154.67,81.22)
N41611184: length 1.2
  BOTTOM w0.102: v4(87.46,111.57) PR455.1
N41615282:
  vias: v4(118.07,50.25)
N41768122: length 20.1
  TOP w0.381: v1(136.86,95.31) 136.74,95.44 136.74,98.88 138.94,101.08 142.98,101.08 145.59,103.69 v1(149.46,103.69)
  BOTTOM w0.254: PU702.22 148.4,103.07 149.03,103.69 v1(149.46,103.69)
  vias: v3(139.05,92.52)
N41768357: length 1
  BOTTOM w0.508: PR760.1 143.96,97.17 PC787.1
N41768359:
  vias: v4(151.57,92.52)
N41769760: length 2.5
  BOTTOM w0.254: PU702.3 148,98.93 148.54,98.4 v4(148.75,98.4) 149.12,98.4 149.12,98.39 PR761.2
N41769790: length 0.5
  BOTTOM w0.305: PR709.1 148.03,98.07
  vias: v4(147.41,98.41)
N41769795:
  vias: v4(150.43,96.51)
N41772153:
  vias: v3(143.47,103.39)
N41772969: length 2.2
  BOTTOM w0.203: 148.29,103.55 148,103.26 PU702.21
  BOTTOM w0.254: 148.29,103.55 v4(148.43,103.69) 148.43,104.47 PC776.1
N41773230: length 1.7
  BOTTOM w0.203: 147.7,103.54 147.6,103.43 PU702.20
  BOTTOM w0.254: 147.7,103.54 147.7,104.23 PR708.1
N41773891:
  vias: v4(150.33,101.08)
N41773970: length 1.7
  BOTTOM w0.254: 150.66,102.17 149.89,101.41 PU702.25
  vias: v4(152.26,102.27)
N41775214: length 0.8
  BOTTOM w0.305: PR755.2 151.14,98.78 151.14,99.48
  vias: v4(150.33,99.78)
N41952574: length 2
  TOP w0.102: v3(252.66,50.66) 252.43,50.66 251.83,51.26 Q23.5
  TOP w0.305: 250.86,52.61 R303.2
N42326188: length 18.4
  TOP w0.102: v1(71.23,86.32) 70.66,86.32 70.44,86.1 69.26,86.1 68.78,85.62 67.45,85.62 62.67,80.83 62.67,79.18 61.91,78.42 TP50.1
  BOTTOM w0.127: U1.D63 71.42,87.17 71.23,86.98 v1(71.23,86.32)
N42347050: length 1.8
  TOP w0.102: TP52.1 207.78,68.79 UL1.34
N42347059: length 7.2
  TOP w0.102: UL1.32 208.56,69.59 208.37,69.79 v1(208.37,69.91) ; v1(208.9,74.61) 208.49,75.02 TP51.1
  IN4 w0.076: v1(208.9,74.61) 208.44,74.15 208.44,71.34 208.37,71.26 v1(208.37,69.91)
N42411102: length 2.3
  TOP w0.102: U15.24 279.1,85.3 278.53,84.72 v4(278.47,84.72) 277.61,84.72 C297.1
N42801050: length 0.8
  TOP w0.254: D61.2 111.04,103.53 R390.1
N42801054: length 4.9
  TOP w0.254: 112.76,102.18 R406.2 ; 112.76,102.18 112.75,102.17 R407.2 ; 112.76,102.18 112.76,102.81 C282.2 112.15,102.91 D61.1 v3(111.82,101.33) 111.82,101.23 112,101.05 R389.1
N42801106: length 0.9
  TOP w0.305: 110.42,103.16 R390.2 109.89,103.49
  vias: v4(110.15,99.95)
N43195754:
  vias: v3(132.42,72.48)
N43196090:
  vias: v2(139.84,72.99) v3(140.62,74.51)
N43196335: length 8.7
  TOP w0.254: v1(133,72.33) 132.8,72.12 v4(132.47,72.12) 132.44,72.15 132.44,72.81 132.83,73.19 132.83,77.39 v1(133.3,77.87)
  BOTTOM w0.254: v1(133,72.33) 133,72.07 PC741.1 133.56,71.51 133.56,70.93 133.71,70.78 PR723.1
N43196339: length 3
  BOTTOM w0.203: PR721.1 PR723.2 134.32,70.84 134.32,71.46 PC741.2 134.75,71.88 PU706.6
N43202964:
  vias: v2(158.99,64.78) v2(159.65,64.76) v3(158.4,65.14)
N43202984:
  vias: v3(153.37,62.67)
N43203008: length 3
  BOTTOM w0.254: PU701.6 159.33,67.33 159.38,67.39 PR724.2 160.07,67.39 160.16,67.3 PC803.2 160.89,67.3 161.01,67.41 PR753.1
N43203016: length 19.3
  IN3 w0.254: v1(147.48,66.26) 147.48,62.95 148.14,62.29 150.22,62.29 150.61,62.67 155.81,62.67 159.17,66.03 v1(159.83,66.03)
  BOTTOM w0.254: PR724.1 159.84,66.69 160.23,66.69 PC803.1 160.18,66.03 v1(159.83,66.03)
N43203049: length 1.5
  TOP w0.305: PR801.1 155.22,67.27
  BOTTOM w0.254: v1(154.44,67.65) 154.76,67.33 PU701.5
  vias: v3(154.24,68.95)
N43454717: length 8
  TOP w0.102: U16.K10 229.93,80.51 v1(229.54,80.9) ; v1(228.36,83.71) 227.59,83.71 226.6,84.7 v4(226.6,84.95) 226.89,85.24 R413.2
  BOTTOM w0.102: v1(229.54,80.9) 229.54,80.9 229.98,81.34 229.98,82.69 228.96,83.71 v1(228.36,83.71)
N43522042: length 3.5
  TOP w0.381: v1(260.88,103.12) R414.1
  BOTTOM w0.508: S2.4 259.55,101.91 260.76,103.12 v1(260.88,103.12)
N43583220: length 3.9
  TOP w0.102: R423.1 238.21,60.97 v1(238.34,60.85)
  BOTTOM w0.102: v1(238.34,60.85) 238.34,60.57 238.69,60.21 240.17,60.21 240.35,60.03 J22.60
N43583233: length 3.8
  TOP w0.102: v1(238.92,60.62) 238.85,60.69 R424.1
  BOTTOM w0.102: v1(238.92,60.62) 238.92,60.54 239.05,60.41 240.37,60.41 240.85,59.93 J22.62
N43583240: length 3.6
  TOP w0.102: R425.1 v1(239.48,60.82)
  BOTTOM w0.102: v1(239.48,60.82) 239.68,60.62 240.8,60.62 241.35,60.07 J22.64
N43980886: length 1
  TOP w0.508: DC5.1 103.14,61.29 DC2.2
  vias: v4(104.1,61.45)
N44069167: length 1.7
  TOP w0.102: R392.1 C158.2 242.5,70.7 Q7.1
N45388838: length 15.1
  BOTTOM w0.102: R427.2 101.16,58.48 Q40.2 101.04,57.63 100.54,57.14 100.54,54.32 100.06,53.83 100.06,53.25 98.74,51.93 97.57,51.93 96.83,52.67 96.83,56.1 v4(96.5,56.43) 96.5,57.04 Q39.1
N45392029: length 6
  TOP w0.254: Q50.2 285.9,52.52 286.25,52.17 286.25,52.15 286.72,51.68 CA47.2 286.8,51.62 v3(286.8,49.95) RA49.2
N45551848: length 5.3
  TOP w0.254: v1(9.4,63.36) 9.5,63.47 11.84,63.47 12.37,62.93 PR95.2
  BOTTOM w0.254: PU4.3 8.74,63.77 9.15,63.36 v1(9.4,63.36)
  vias: v3(15.85,59.96)
N45551858: length 9.2
  IN4 w0.254: v1(11.63,60.7) 13.95,63.01 v1(13.95,67.76)
  BOTTOM w0.305: v1(11.63,60.7) 11.96,61.03 PR96.2
N45551860: length 3.6
  BOTTOM w0.305: PR96.1 11.05,61.85 PC82.1 8.97,62.83 8.54,63.26 PU4.4
N45551886: length 4.3
  BOTTOM w0.102: PR88.1 3.58,66.77 v3(3.3,67.05)
  BOTTOM w0.305: PU4.9 4.66,64.27 3.74,65.19 PR90.2 3.58,65.31 3.58,66.07 PR88.1
N45551892: length 15.4
  IN1 w0.508: v1(13.97,74.34) 12.75,74.34 4.62,66.21 v1(4.62,65.5)
  BOTTOM w0.508: PR84.1 14.84,73.47 v1(13.97,74.34)
N45551902: length 2.1
  BOTTOM w0.305: PU4.7 4.22,63.26 4.07,63.42 PR89.2
N45551908:
  vias: v3(4.37,62.55)
N45551914: length 2.2
  BOTTOM w0.305: PR87.2 3.94,64.3 4.48,63.77 PU4.8
N45799415: length 3.4
  TOP w0.102: C2587.2 49.62,65.77 49.62,66.28 v4(49.49,66.41) 48.78,66.41 48.15,67.04 U147.56
N45799418: length 2.8
  TOP w0.102: U147.9 44.95,72.74 v4(45.79,73.58) 46.14,73.93 46.14,74.6 R2515.2
N45799426: length 2.3
  TOP w0.102: U147.37 v3(40.55,66.31) 40.55,66.14 40.32,65.91 R2517.2
N45799427: length 2.2
  TOP w0.102: U147.48 44.95,66.66 v4(45.23,66.37) 45.53,66.08 R2516.2
N45907884: length 2.1
  BOTTOM w0.102: TC5.1 22.99,63.77 22.99,64.84 R9089.2
N45959248:
  vias: v1(232.34,47.87) v1(232.34,47.28) v1(232.83,46.95) v1(232.87,47.57) v1(233.12,46.37) v1(233.5,47.49) v1(233.5,46.85) v1(233.63,46.04) v1(237.52,47) v1(237.55,47.59) v1(240.73,45.76) v1(240.75,46.37) v1(241.33,45.78) v1(241.36,46.37) v1(241.97,46.37) v1(241.97,45.78) v3(241.58,45.08)
N46276125: length 2.7
  TOP w0.152: U17.8 170.98,88.86 171.08,88.76 173.14,88.76 R235.1
N46276518: length 2.9
  TOP w0.152: TP16.1 173.92,90.13 172.88,89.09 172.22,89.09 172.12,89.2 U17.9
N46487430: length 5.2
  TOP w0.076: 22.75,51.9 22.8,51.96 23.76,51.96 24.19,51.52 24.74,51.52 U5.K2
  TOP w0.102: R785.1 22.03,51.9 22.75,51.9
N46487432: length 5.1
  TOP w0.076: U5.L2 24.29,51.77 23.95,52.12 22.75,52.12
  TOP w0.102: 22.75,52.12 22.35,52.12 v4(21.82,52.65) 21.4,53.07 21.4,53.43 R786.1
N46487434: length 4.7
  TOP w0.076: U5.K3 24.73,51.02 24.14,51.02 23.63,51.52 v4(23.1,51.52) 23.05,51.48 22.75,51.48
  TOP w0.102: R781.2 21.02,51.52 21.06,51.48 22.75,51.48
N46487436: length 4.4
  TOP w0.076: 22.75,51.68 22.77,51.68 22.89,51.8 23.61,51.8 24.14,51.27 U5.L3
  TOP w0.102: 22.75,51.68 21.36,51.68 R780.2
N46487444: length 3.8
  TOP w0.203: U5.E1 27.48,52.98 28.75,54.24 v4(29.07,54.24) 29.45,54.62 C810.2
N46487448: length 5.9
  TOP w0.254: U5.K1 24.98,52.48 24.67,52.79 v4(23.22,52.79) 22.74,53.28 22.08,53.28 21.17,54.19 21.17,54.6 20.68,55.08 C813.2
N46487566: length 3.7
  TOP w0.076: 26.78,54.01 26.73,53.96 26.73,52.03 26.48,51.79 U5.G2
  TOP w0.102: R784.1 27.21,54.44 26.78,54.01
N46487568: length 3.4
  TOP w0.076: U5.E11 27.48,46.68 28.25,45.91 v4(28.53,45.91) 28.96,45.91 29.11,45.76
  TOP w0.102: 29.11,45.76 29.34,45.53 R728.1
N46487592: length 5.4
  TOP w0.076: 23.48,48.53 24.72,48.53 24.98,48.27 U5.K9
  TOP w0.203: 23.48,48.53 23.32,48.68 v4(23.12,48.68) 22.71,48.68 22.35,48.33 21.72,48.33 21.39,48.66 21.39,48.95 20.84,49.5 R707.1
N46487596: length 5.6
  TOP w0.076: 23.7,47.82 23.9,48.02 24.77,48.02 24.98,47.81 U5.K10
  TOP w0.203: 23.7,47.82 22.73,46.85 v4(21.41,46.85) 21.41,47.12 20.79,47.74 R708.1
N46487598: length 4.3
  TOP w0.076: U5.L4 24.1,50.77 23.63,51.24 22.75,51.24
  TOP w0.102: R729.2 21.02,51.04 v4(21.75,51.04) 21.95,51.24 22.75,51.24
N46487604: length 4.7
  TOP w0.076: 27.23,53.12 27.23,52.01 U5.F2 U5.E2
  TOP w0.102: 27.23,53.12 27.23,53.44 v4(27.62,53.83) R727.2
N46487612: length 3.3
  TOP w0.076: U5.F1 26.98,53.68 27.31,54.01
  TOP w0.102: R819.2 28.08,54.77 27.31,54.01
N46487616: length 7
  TOP w0.076: U5.F10 26.73,47.52 26.73,46.3 26.72,46.3 26.65,46.22 26.65,45.84 26.72,45.76
  TOP w0.102: 26.72,45.76 27.1,45.38 27.1,43.22 v4(27.33,42.99) 27.26,42.93 R782.1 R783.1
N46487618: length 16.7
  TOP w0.076: U5.F4 26.98,51.22 v3(26.9,51.3)
  TOP w0.102: v1(23.75,62.12) 23.27,62.12 22.71,62.68 TP57.1
  IN1 w0.076: v1(23.75,62.12) 23.75,61.15 23.2,60.61 23.2,60 24.87,58.34 24.87,55.97 26.9,53.94 v3(26.9,51.3)
N46487626: length 22.2
  TOP w0.076: U5.H6 25.61,49.77 v3(25.48,49.9)
  TOP w0.102: R724.2 v1(27.56,45.64) ; R489.2 21.92,63.47 22.43,62.96 22.43,62.32 v1(22.86,61.89)
  IN1 w0.076: v3(25.48,49.9) 25.13,50.25 25.13,53.11 23.52,54.72 23.52,58.67 22.28,59.91 22.28,61.31 v1(22.86,61.89)
  IN4 w0.076: v3(25.48,49.9) 25.05,49.47 25.05,48.16 v1(27.56,45.64)
N46487628: length 6.4
  TOP w0.076: U5.D7 28.22,49.27 v1(28.45,49.5)
  TOP w0.102: v1(30.3,45.66) 30.52,45.66 R723.2
  BOTTOM w0.102: v1(28.45,49.5) 28.73,49.5 29.01,49.22 29.01,46.96 v1(30.3,45.66)
N46487646: length 1.4
  TOP w0.076: U5.F11 26.98,45.94 TP58.1
N46487654: length 18.2
  TOP w0.076: U5.D5 28.3,50.59 v3(28.5,50.59)
  TOP w0.102: v1(33.4,56) 34.14,56.74 34.14,59.35 34.85,60.06 v3(34.85,60.62) R712.1
  IN1 w0.076: v3(28.5,50.59) 31.37,50.59 31.95,51.17 32.87,51.17 33.02,51.02 33.66,51.02 34.16,51.53 34.16,52.65 32.92,53.89 32.92,55.52 v1(33.4,56)
N46487656: length 14.2
  TOP w0.076: v3(27.43,51.3) 27.48,51.25 U5.E4
  TOP w0.102: v1(24,60.22) 23.93,60.22 22.18,61.97 22.18,62.35 R711.1
  IN1 w0.076: v1(24,60.22) 24,59.55 25.22,58.34 25.22,56.2 27.43,53.99 v3(27.43,51.3)
N46487724: length 17.9
  TOP w0.076: U5.H7 25.55,49.27 v3(25.47,49.36)
  TOP w0.102: v1(23.24,62.76) v3(24.06,62.76) 24.06,63.34 C818.2
  IN1 w0.076: v1(23.24,62.76) 23.06,62.76 21.97,61.66 21.97,59.88 23.32,58.54 23.32,54.6 24.89,53.03 24.89,49.93 v3(25.47,49.36)
N46487818: length 3.4
  TOP w0.076: 28.02,45.76 27.24,46.54 27.24,47.52 U5.E10
  TOP w0.102: R721.2 28.46,45.32 28.02,45.76
N46508024: length 0.3
  TOP w0.305: PR21.2 18.92,69.3
  vias: v3(19.13,69.89)
N46508038: length 2.9
  TOP w0.254: PR25.1 21.29,72.42 21.65,72.07 PR91.2 ; 20.55,74.88 PR23.2
  TOP w0.305: 21.03,74.53 PR23.2
  vias: v3(19.2,71.9)
N46508050: length 1.7
  TOP w0.102: v3(20.14,75.2) 19.46,75.2 PQ12.4
  TOP w0.305: 19.96,76.08 PR22.2 20.33,75.75
N46508065:
  vias: v3(14.89,75.25)
N46562271: length 14.8
  BOTTOM w0.203: PJ2.2 187.45,59.05 186.57,59.93 PR27.1 187.03,60.6 PC20.2
  BOTTOM w0.254: PJ2.2 187.45,55.7 188.19,54.96 188.93,54.96 190.3,53.59 190.3,52.29 191.01,51.58 191.95,51.58 192.69,50.84 192.69,50.16 v3(192.56,50.03)
N46562292: length 1.4
  TOP w0.203: PR30.1 188.94,65.47 PR29.1 PR32.2
N46562298:
  vias: v3(147.38,111.87)
N46562306: length 2.3
  TOP w0.254: PF5.2 167.18,89.11 167.34,89.11 ; 167.34,89.11 PD10.3 ; 167.34,89.11 PD10.2
N46562316: length 1.6
  BOTTOM w0.305: PR31.2 184.57,64.12 185.11,63.58 PQ17.4
N46562349: length 0.3
  TOP w0.305: PR38.2 221.17,99.91
  vias: v3(220.96,100.6)
N46562353: length 1.2
  TOP w0.254: PR36.1 PR37.1 PR39.2
N46562358: length 0.3
  TOP w0.305: PR37.2 226.49,95.54
  vias: v4(227.16,95.11)
N46562406: length 2.7
  TOP w0.203: v2(188.5,67.6) 189.26,66.85 PR30.2
  BOTTOM w0.305: v2(188.5,67.6) 189.01,67.09 PQ18.4
N46688728: length 3.8
  TOP w0.102: v3(289.56,60.77) RA8.2
  TOP w0.508: J19.7 292.59,59.66 291.48,60.77 RA8.2
N46688732: length 4.6
  TOP w0.102: v3(291.42,45.38) RA9.2
  TOP w0.508: RA9.2 294.32,45.38 J19.8
N46889804: length 4.9
  TOP w0.102: R509.2 v3(3.61,63.62)
  TOP w0.203: U187.C1 7.68,64.61 7.24,64.61 6.63,64 6.28,64 5.89,63.62 R508.2 R509.2
N46889918: length 2.9
  TOP w0.203: U187.B1 7.84,65.34 7.49,64.99 7.01,64.99 6.48,64.46 v3(6.4,64.46) 6.1,64.46 6,64.56 R450.1
N46895327: length 4.1
  TOP w0.102: R66.1 282.36,55.95 v3(281.51,55.95) 281.38,55.82 RA39.2 280.56,55.22 D739.1 281.13,55.03 281.31,54.86 D740.1
N46963521: length 8.6
  TOP w0.102: U16.J4 v1(235.11,80.05) ; R153.1 241.5,79.49 v1(242.02,79.49)
  BOTTOM w0.102: v1(242.02,79.49) 241.65,79.86 240.84,79.86 240.55,80.15 238.85,80.15 238.36,79.67 235.49,79.67 v1(235.11,80.05)
N46986221: length 7.3
  TOP w0.102: D709.2 239.5,87.32 238.42,87.32 238.01,86.91 v4(238.01,86.52) 238.27,86.26 238.27,85.46 R798.1 238.27,84.77 238.27,84.02 U16.N1
N47211988: length 13
  TOP w0.076: v3(26.37,51.3) 26.48,51.19 U5.G4
  TOP w0.102: TP82.1 22.12,61.26 v3(22.29,61.09) v1(22.71,60.67)
  IN1 w0.076: v3(26.37,51.3) 26.37,53.87 24.41,55.83 24.41,58.16 22.71,59.86 v1(22.71,60.67)
N47236723: length 3.6
  TOP w0.102: U193.3 14.82,45.25 15.05,45.02 15.05,44.15 15.33,43.87 C9463.2 15.33,42.75 v3(14.96,42.38)
N47456916: length 6.2
  BOTTOM w0.254: F14.1 162.57,59.7 v4(162.79,59.48) 165.18,59.48 165.41,59.24 166.84,59.24 167.3,59.71 J16.19
N47681284: length 3.7
  BOTTOM w0.102: J26.11 v4(140.1,64.31) 140.79,63.61 140.79,62.79 140.69,62.69 R904.2
N47749037:
  vias: v1(172.81,63.79) v3(174.08,64.48)
N47750172:
  vias: v1(136.03,62.46) v1(136.33,61.89) v4(136.86,61.28)
N47750211: length 2.1
  TOP w0.305: 135.14,66.43 C143.2 134.74,66.1
  BOTTOM w0.381: v1(136.08,66.69) 135.95,66.81 J26.2
N47896201: length 0.7
  TOP w0.102: CA5.1 266.32,58.7 266.35,58.66 RA163.2
N47953170: length 5.8
  TOP w0.102: U16.M8 231.15,82.45 231.15,83.59 231.85,84.29 231.85,84.83 231.55,85.13 231.55,86.22 231.22,86.55 R10251.1
N48013537: length 0.6
  TOP w0.305: 250.68,62.06 250.67,62.08 R10252.2
N48013539: length 0.8
  TOP w0.254: R10252.1 251.9,62.7 D47.2
N48013583: length 2.5
  TOP w0.254: Q24.4 v4(254.81,61.62) 254.9,61.7 254.9,62.42 254.59,62.73 R306.2
N48033774: length 5.2
  TOP w0.076: 25.74,52.62 25.74,52.01 25.98,51.77 U5.H2
  TOP w0.152: C830.2 22.87,54.44 23.5,53.81 24.87,53.81 v4(25.13,53.56) 25.74,52.95 25.74,52.62
N48288623: length 14
  TOP w0.102: TP83.1 225.69,85.03 225.69,83.86 226.53,83.02 v1(226.53,82.54) ; U16.J10 229.93,79.65 v1(230.33,79.25)
  IN4 w0.076: v1(226.53,82.54) 226.04,83.02 225.76,83.02 225.26,82.51 225.26,79.84 225.89,79.21 227.14,79.21 227.52,78.83 229.9,78.83 v1(230.33,79.25)
N48312738: length 4.9
  TOP w0.076: 22.8,54.01 23.38,53.43 24.83,53.43 25.48,52.77 U5.J1
  TOP w0.102: 22.8,54.01 R790.2
N48312901: length 7.4
  TOP w0.076: 22.75,53.73 23.28,53.2 24.77,53.2 25.23,52.74 25.23,52.06 25.48,51.8 U5.J2
  TOP w0.102: R791.2 21.45,55.16 21.45,54.5 21.68,54.27 21.88,54.27 v4(22.23,53.91) 22.56,53.91 22.75,53.73
N48496902: length 7.2
  BOTTOM w0.102: J1.22 225.35,49.88 225.18,50.05 224.77,50.05 224.19,50.63 223.73,50.63 223.35,51.02 223.35,51.96 223.12,52.18 R433.2 222.54,52.41 222.25,52.7 220.68,52.7 v3(220.5,52.87)
N49159192: length 1.5
  TOP w0.254: U5.B7 U5.A7 ; U5.A7 U5.A8 ; U5.A7 U5.A6
  vias: v1(30.08,49.55) v1(30.48,50) v1(30.89,49.55) v1(31.04,50.18) v1(34.04,49.8)
N49224973: length 38.2
  TOP w0.102: RC166.1 56.4,72.83 v3(56.3,72.94) 56.19,73.04 v1(56.19,73.7)
  IN1 w0.076: v1(83.18,71.81) 77.92,71.81 77.76,71.64 75.27,71.64 74.61,70.98 74.61,69.51 72.75,67.65 68.49,67.65 66.89,69.25 66.89,72.71 66.18,73.42 65.54,73.42 64.42,74.54 64.42,75.07 64.04,75.45 57.95,75.45 v1(56.19,73.7)
  BOTTOM w0.102: U1.AN43 83.15,71.81 v1(83.18,71.81)
N49767541: length 4.7
  TOP w0.508: RL12.1 v3(284.03,121.45) 284.03,121.54 285.17,122.67 286.66,122.67 J3.9
N49767564: length 6.1
  TOP w0.508: J3.11 284.61,133.67 v3(281.23,133.67) 281.1,133.8 RL13.2
N50058241: length 6.9
  TOP w0.076: U5.C2 28.46,51.77 v1(27.99,51.3)
  TOP w0.102: v1(30.71,48.15) 30.74,48.18 R799.2
  BOTTOM w0.102: v1(30.71,48.15) 30.02,48.15 29.59,48.58 29.59,50.82 28.91,51.5 28.2,51.5 v1(27.99,51.3)
N50058724: length 4.7
  TOP w0.076: 29.85,45.76 v4(29.85,45.97) 29.59,46.22 28.22,46.22 28.17,46.28 28.16,46.28 27.96,46.48 27.96,46.48 27.72,46.72 27.72,47.09 27.73,47.09 27.73,47.51 U5.D10
  TOP w0.102: R722.2 29.85,45.44 29.85,45.76
N50063965: length 2.2
  TOP w0.102: U26.2 127.14,60.14 v1(126.63,59.63)
  BOTTOM w0.102: R443.2 126.98,59.63 v1(126.63,59.63)
N50065476: length 12
  TOP w0.102: v1(126.48,59.04) 126.67,59.04 127.27,59.64 U26.3
  BOTTOM w0.102: R376.2 127.45,58.57 126.98,59.04 v1(126.48,59.04) 126.15,59.37 126.15,59.91 126.5,60.26 126.76,60.26 127.21,60.72 128.74,60.72 130.18,62.17 v4(131.38,62.17) 131.47,62.07 131.47,61.62 131.8,61.29 R428.1 131.8,60.87 Q41.1
N50065544: length 3.2
  BOTTOM w0.102: Q41.2 133.29,60.64 133.07,60.42 133.07,59.97 132.53,59.44 R434.1 v3(131.15,59.44)
N50065958: length 6.5
  TOP w0.305: U26.22 133.35,59.64 C187.1 133.64,59.93 134.32,59.93 134.76,60.36 ; 128.25,63.23 C262.1 ; C262.1 C263.1 ; C262.1 128.41,63.37 ; C263.1 129.16,63.37 ; C263.1 128.84,62.94 129.26,62.94 129.5,62.7 C261.1
  vias: v4(124.54,59.29)
N50066946: length 3.9
  TOP w0.127: R239.1 132.88,62.32 v3(132.44,62.32) 132.36,62.4 131.73,62.4 131.24,61.91 130.93,61.91 130.62,61.6 U26.27
N50533265: length 2.3
  TOP w0.102: U16.H1 237.63,78.87 237.92,79.16 239.14,79.16 R402.1
N50533267: length 9.7
  TOP w0.102: R403.1 235.16,68.15 v1(234.75,67.73) ; v1(234.31,74.5) 233.94,74.87 U16.C5
  IN3 w0.081: v1(234.31,74.5) 235.42,73.39 235.7,73.39 236.2,72.88 236.2,72.3 235.65,71.74 235.65,70.93 235.24,70.52 235.24,69.65 234.75,69.16 v1(234.75,67.73)
N50672369: length 16.5
  TOP w0.254: v1(136.69,109.11) 136.48,108.9 134.17,108.9 PC10.1 134.18,109.42 PR8.1 135.21,109.42 PR9.1 ; v1(132.93,106.21) PR11.2
  TOP w0.305: PD1.2 v1(140.34,112.9)
  IN1 w0.254: v1(136.69,109.11) 136.69,109.85 139.73,112.9 v1(140.34,112.9)
  BOTTOM w0.254: v1(132.93,106.21) 135.82,109.11 v1(136.69,109.11)
N50672380: length 1.3
  TOP w0.254: PQ6.4 135.89,110.35 PR9.2
N50672386: length 2.2
  TOP w0.203: PQ9.1 130.51,107.92 130.81,107.61 131.51,107.61 131.96,108.05 PQ8.2
N50672387: length 0.7
  TOP w0.254: PQ8.1 131.62,106.87 PR11.1
N50672395: length 1.6
  TOP w0.305: 143.65,111.9 PR10.2 143.49,112.06 PQ7.4
N50672396: length 1.5
  TOP w0.305: PD2.2 144.58,112.74 PR10.1 PR12.1
N50672400: length 0.3
  TOP w0.305: 143.99,111.17 PR12.2
N50672407: length 1.5
  TOP w0.254: PQ10.1 135.59,106.67 135.13,106.21 PR13.1
N50672411: length 2.1
  TOP w0.254: PQ41.1 137.13,108.17 PR14.1 136.01,108.17 PQ10.2
N50672484: length 1.9
  TOP w0.254: PR16.2 109.25,107.23 109.28,107.2 PR15.2 109.26,106.68 PQ11.6
N50674722: length 2.2
  TOP w0.254: PQ10.3 134.6,108.15 PQ5.1
N50675493: length 1.2
  TOP w0.254: PR1.2 158.07,96.97 PR2.2 PR3.1
N50708166: length 6.3
  TOP w0.203: PU101.1 198.02,73.05 197.4,72.43 v4(196.85,72.43) 196.58,72.16 196.46,72.16 195.76,71.47 PC102.1
  TOP w0.254: PR103.2 PR102.2 195.61,70.43 195.26,70.77 PC102.1
N50730040: length 7
  BOTTOM w0.254: PR83.1 v3(21.08,73.37) 20.32,72.61 18.96,72.61 18.63,72.94 PQ15.2 18.27,73.59 17.5,74.36 PR82.2
N50730081: length 3.6
  BOTTOM w0.254: PQ15.1 18.92,71.69 v3(17.4,73.21) 17.14,73.47 PR84.2
N50760102: length 6.3
  BOTTOM w0.254: PL404.1 126.89,82.85 124.8,82.85 124.44,83.2 124.44,86.51 PR467.1
  vias: v2(127.41,85.36) v2(128.07,85.36) v3(128.68,86.71)
N50760177:
  vias: v3(134.82,85.79)
N50767547: length 0.9
  BOTTOM w0.254: PR470.2 PC527.1
N50767548: length 1.6
  BOTTOM w0.203: PR470.1 134.62,82.31 134.29,82.65 PU405.30
N50767551:
  vias: v2(129.34,79.9)
N50767596: length 1.2
  BOTTOM w0.102: PU405.11 PU405.10 PU405.9 PU405.8
N50768257:
  vias: v2(57.49,106.92) v2(57.51,106.11) v2(58.56,106.69) v2(58.56,106.03) v2(60.51,106.21) v4(57.01,106.57)
N50768281: length 6.9
  BOTTOM w0.254: PR465.1 72.29,109.54 72.29,105.58 72.01,105.3 PL402.1
  vias: v3(67.22,105.68)
N50768289:
  vias: v4(59.77,109.7)
N50768292:
  vias: v4(60.04,111.47)
N50768448: length 1.3
  BOTTOM w0.102: PC470.2 59.96,106.72 v4(59.88,106.72)
N50768459: length 0.9
  BOTTOM w0.102: PU403.8 v4(66.88,108.35)
N50768485: length 1.2
  BOTTOM w0.102: v4(66.71,112.25) PR457.2
N50781896: length 13.8
  TOP w0.305: PR13.2 134.06,106.62 134.77,107.33 v1(134.98,107.33) ; PD2.1 v1(142.65,112.9) PD1.1
  IN1 w0.254: v1(142.65,112.9) 141.86,112.11 139.75,112.11 137.34,109.69 137.34,108.75 136.65,108.07 135.59,108.07 134.98,107.46 v1(134.98,107.33)
N50782907: length 3.1
  TOP w0.508: PR7.1 257.8,92.2 PQ42.3
N50782909: length 7.2
  TOP w0.508: PU6.2 263.01,86.16 261.35,87.81 PR6.1 261.18,88.1 259.92,88.1 258.89,89.13 PR7.2
N50782911: length 12
  TOP w0.508: PQ42.1 254.84,88.84 PR24.2 255.63,87.11 256.47,86.28 258.6,86.28 259.01,85.87 v3(260.91,85.87) 261.85,85.87 263.46,84.26 PU6.3
N51213401: length 7.1
  BOTTOM w0.102: U1.A5 105.08,89.47 105.46,89.86 105.46,92.04 105.64,92.22 105.64,93.18 105.79,93.34 105.79,93.82 104.57,95.04 TP85.1
N51220377: length 3.5
  TOP w0.102: TP88.1 107.25,68.69 v1(108.07,68.69)
  BOTTOM w0.102: v1(108.07,68.69) 108.07,68.69 107.77,68.98 U1.AV1
N51221448: length 17.2
  BOTTOM w0.102: U1.BA71 66.72,66.63 66.12,66.03 64.64,66.03 61.11,69.56 57.33,69.56 55.17,67.4 TP90.1
N51224590: length 18
  BOTTOM w0.102: TP92.1 54.28,67.07 55.3,67.07 57.56,69.33 61.04,69.33 64.54,65.83 66.32,65.83 66.99,66.5 U1.BB70
N51224599: length 17.2
  TOP w0.102: TP91.1 64.7,56.63 64.7,64.99 65.41,65.7 65.89,65.7 67.26,67.07 v1(68.59,67.07)
  BOTTOM w0.102: v1(68.59,67.07) 68.59,67.07 69.13,66.53 U1.BB67
N51225679: length 3.3
  BOTTOM w0.102: TP94.1 65.53,86.15 66.09,86.15 66.66,86.71 U1.E71
N51228720: length 9.4
  BOTTOM w0.102: TP97.1 111.96,61.49 110.87,62.58 110.87,63.52 110.24,64.15 110.24,64.66 107.62,67.28 107.01,67.28 106.86,67.13 U1.BA2
N51228736: length 7.4
  BOTTOM w0.102: U1.BA1 107.58,66.96 110.03,64.51 110.03,64.05 110.62,63.47 110.62,62.93 110.14,62.45 TP96.1
N51228745: length 5.1
  BOTTOM w0.102: U1.B71 66.72,88.6 66.27,88.16 65.03,88.16 TP95.1
N51231994:
  vias: v1(276.53,120.69) v1(276.53,120.08) v1(276.53,119.45) v1(276.53,118.76) v3(277.12,124.12)
N52114023: length 1.7
  TOP w0.102: R458.1 124,90.1 123.99,90.09 Q34.B1 123.33,89.81 123.24,89.9 R457.2
N52114279: length 4.5
  TOP w0.203: R398.1 90.25,97.56 90.24,97.57 v4(89.52,97.57) D62.2 D63.2 90.67,96.92 R399.1 92.01,96.89 Q35.B1
N52338190: length 9.5
  TOP w0.076: U5.D6 28.27,50.06 v3(28.47,50.06)
  TOP w0.102: v1(31.83,45.56) 31.83,44.87 R312.2
  BOTTOM w0.102: v3(28.47,50.06) 29.03,50.06 29.29,49.8 29.29,47.31 29.58,47.02 32.02,47.02 32.31,46.73 32.31,46.04 v1(31.83,45.56)
N52703631: length 0.9
  TOP w0.305: Q266.4 270.77,114.9 R10321.2
N52703637: length 0.8
  TOP w0.305: R10320.2 272.35,115.92 D744.2
N52706025: length 3.6
  TOP w0.254: C558.1 260.06,57.73 Q60.4
N52706078: length 4.9
  TOP w0.254: R324.2 R325.2 260.81,67 260.06,66.25 Q60.3
N84550702: length 1
  TOP w0.254: R303.1 250.51,53.54 D46.2
N100056917: length 1.6
  TOP w0.254: v4(104.07,58.66) 104.05,58.64 RC122.2 103.29,59.29 DC3.2
N529948291: length 1.8
  TOP w0.305: PR44.2 263.02,91.78 262.5,92.31 PQ23.3

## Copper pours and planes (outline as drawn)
1.2V_B+ on BOTTOM: 116.93,56.15 117.64,56.15 117.84,56.35 122.54,56.35 123.07,56.88 124.06,56.88 124.34,56.6 124.67,56.6 124.67,58.53 119.52,58.53 119.08,58.97 119.08,59.27 118.98,59.37 117.71,59.37 117.7,59.38 117.45,59.38 117.31,59.52 117.31,60.33 117.17,60.47 116.83,60.47 116.75,60.39 116.75,60.04 116.75,56.32
1.2V_GND on TOP: 126.81,67.09 127.34,67.09 127.42,67.02 127.42,65.12 127.8,64.74 127.8,64.3 127.72,64.22 126.02,64.22 125.92,64.32 125.92,65.04 125.79,65.16 124.34,65.16 124.32,65.19 124.32,66.18 124.55,66.41 126.12,66.41
1.2V_GND on BOTTOM: 127.77,65.24 128.81,65.24 129.09,64.96 129.09,64.38 128.71,64.38 128.48,64.6 127.9,64.6 127.67,64.38 127.34,64.38 127.26,64.45 127.26,64.73
3V_VIN on BOTTOM: 146.95,80.68 146.72,80.91 146.72,82.18 146.52,82.38 146.01,82.38 145.88,82.51 145.88,84.39 146.47,84.39 146.47,84.95 145.88,84.95 145.88,85.2 146.47,85.2 146.47,85.76 145.88,85.76 145.88,87.03 146.26,87.41 150.07,87.41 150.28,87.21 150.28,80.89 150.07,80.68
5V_VIN on BOTTOM (solid shape): 175.35,84.39 175.35,80.23 175.1,79.98 171.7,79.98 171.14,80.54 171.14,84.2 171.36,84.42 175.32,84.42
5V_VIN on TOP: 172.83,84.34 174.53,84.34 174.91,83.96 174.91,80.15 174.69,79.92 171.69,79.92 171.48,80.12 171.48,82.99
+3V_MUX on BOTTOM: 24.63,64.97 24.63,64.53 24.49,64.38 23.57,64.38 23.48,64.29 23.48,64.16 23.5,64.15 23.5,63.75 23.57,63.67 25.07,63.67 25.3,63.9 25.3,64.03 25.45,64.18 25.45,64.64 25.85,65.04 26.8,65.04 26.9,65.14 26.9,65.98 26.8,66.08 25.74,66.08
+3V_MUX on BOTTOM: 30.53,64.85 35.02,64.85 35.28,64.58 35.28,63.57 34.95,63.24 34.47,63.24 33.63,62.4 33.02,62.4 32.92,62.5 32.92,63.01 32.67,63.26 31.85,63.26 31.4,63.72 30.86,63.72 30.86,62.98 32.36,61.49 35.18,61.49 36.09,62.4 36.09,65.83 35.91,66.01 33.84,66.01 33.51,65.68 31.8,65.68 30.94,66.54 29.77,66.54 29.67,66.43 29.67,66.23 29.81,66.08 29.81,65.56
+3V_MUX on IN3: 26.29,75.46 26.72,75.46 28.32,73.85 30.3,73.85 30.86,73.3 30.86,68.17 30.91,68.17 34.24,64.84 34.24,62.4 34.04,62.2 33.3,62.2 33.29,62.21 31.93,62.21 31.37,62.77 25.13,62.77 22.79,65.12 22.79,68.52 22.18,69.13 21.72,69.13 21.43,69.42 21.43,70.29 22.12,70.98 24.66,70.98 25.99,72.31 25.99,75.15
GND on TOP (solid shape): 200.8,76.75 200.8,74.15 200.72,74.08 198.05,74.08 198.05,76.75 198.13,76.82 200.72,76.82
GND on TOP (solid shape): 164.21,91.1 164.21,89.07 164.09,88.94 162.74,88.94 162.69,88.99 162.69,91.05 162.89,91.25 164.06,91.25
GND on TOP (solid shape): 280.6,76.39 280.6,73.9 280.54,73.84 278.69,73.84 277.99,74.54 277.99,75.96 278.47,76.44 280.55,76.44
GND on TOP (solid shape): 133.38,109.31 133.38,108 133.25,107.87 132.85,107.87 132.04,108.67 132.04,109.26 132.14,109.36 133.33,109.36
GND on TOP (solid shape): 157.67,67.86 157.67,65.32 157.84,65.14 157.84,62.72 157.69,62.57 156.24,62.57 155.58,63.23 155.58,67.83 155.76,68.01 157.51,68.01
GND on TOP (solid shape): 243.8,105.42 243.8,103.29 243.32,102.81 242.33,102.81 241.61,103.52 237.27,103.52 236.86,103.92 236.86,105.02 238.18,106.34 242.88,106.34
GND on TOP (solid shape): 125.49,64.87 125.49,64.14 125.5,64.13 125.51,64.13 125.59,64.05 125.59,63.31 125.49,63.21 123.94,63.21 123.86,63.28 123.86,64.61 124.16,64.91 125.45,64.91
GND on TOP (solid shape): 137.03,88.74 137.03,83.1 135.69,81.75 131.62,81.75 130.96,82.41 130.96,83.86 130.81,84.01 129.82,84.01 129.82,85.84 133.1,89.12 136.65,89.12
GND on TOP (solid shape): 155.58,85.13 155.58,83.73 155.35,83.5 153.22,83.5 152.97,83.25 152.97,82.56 152.84,82.44 150.83,82.44 150.61,82.66 150.61,85.03 151.06,85.48 155.22,85.48
GND on TOP (solid shape): 169.68,85.76 169.68,84.31 169.5,84.14 168.61,84.14 168.36,83.88 168.36,83.55 168.23,83.43 165.72,83.43 165.24,83.91 165.24,85.79 165.33,85.88 169.57,85.88
GND on TOP (solid shape): 184.72,67.96 186.95,67.96 187.05,67.86 187.05,67.37 186.95,67.27 184.85,67.27 184.57,67.55 184.26,67.55 184.08,67.73 184.08,67.91 184.34,68.16 184.51,68.16
GND on TOP (solid shape): 192.03,93.15 192.03,89.83 192.59,89.27 192.59,86.63 192.57,86.6 188.83,86.6 188.53,86.91 188.53,88.91 187.51,89.93 187.51,93.18 187.61,93.28 191.91,93.28
GND on TOP (solid shape): 198.15,88.58 198.15,88.28 198.36,88.07 198.74,88.07 198.94,87.87 198.94,86.75 198.66,86.47 198.66,85.66 198.38,85.38 197.62,85.38 197.01,85.99 197.01,88.4 197.32,88.71 198.03,88.71
GND on TOP (solid shape): 128.76,109.54 131.4,109.54 131.52,109.42 131.52,108.89 131.3,108.67 130.92,108.67 129.87,108.67 129.86,108.67 128.1,108.67 127.86,108.91 127.86,109.45 128.08,109.66 128.63,109.66
GND on TOP (solid shape): 159.89,90.74 159.89,89.06 160.02,88.93 160.02,87.01 160,86.99 159.11,86.99 158.92,87.17 158.92,90.11 158.9,90.13 158.9,90.23 158.67,90.46 157.88,90.46 157.83,90.51 157.83,90.72 157.96,90.84 159.79,90.84
GND on TOP (solid shape): 100.19,111.39 100.19,110.12 99.73,109.66 99.73,109.03 98.36,107.66 93.01,107.66 92.67,107.32 92.67,104.06 92.67,104.05 92.67,103.75 92.48,103.57 89.8,103.57 89.39,103.97 89.39,110.43 89.9,110.93 98.1,110.93 98.84,111.67 99.91,111.67
GND on TOP (solid shape): 288.44,72.25 288.53,72.19 288.39,71.02 289.3,70.44 299.09,70.44 299.09,68.44 300,68.44 300.44,68 300.44,64.17 299.73,63.46 291.65,63.46 291.14,63.97 291.12,63.97 287.46,67.63 287.46,71.82 287.89,72.25
GND on TOP (solid shape): 298.82,139.66 298.82,135.83 290.88,135.83 289.97,136.74 289.94,136.84 290.01,136.91 291.21,138.08 290.79,139.69 290.76,139.8 290.86,139.86 298.62,139.86
GND on BOTTOM (solid shape): 143.16,52.51 143.16,50.89 142.72,50.46 139.2,50.46 139.2,52.77 139.25,52.82 142.85,52.82
GND on BOTTOM (solid shape): 90.23,45.35 90.23,38.85 89.77,38.39 86.88,38.39 86.47,38.8 86.47,45.4 86.62,45.55 90.03,45.55
GND on BOTTOM (solid shape): 148.4,68.31 148.4,67.78 147.99,67.37 145.5,67.37 145.35,67.53 145.35,68.31 145.53,68.49 148.22,68.49
GND on BOTTOM (solid shape): 172.73,85.76 172.73,84.77 172.6,84.64 171,84.64 170.88,84.77 170.88,85.74 171,85.86 172.63,85.86
GND on BOTTOM (solid shape): 181.9,68.36 181.9,67.58 181.59,67.27 179.13,67.27 178.9,67.5 178.9,68.47 179.08,68.64 181.62,68.64
GND on BOTTOM (solid shape): 198.26,88.71 198.26,86.7 198,86.45 197.11,86.45 196.94,86.63 196.94,88.63 197.16,88.86 198.1,88.86
GND on BOTTOM (solid shape): 107.93,60.85 107.93,59.09 107.3,58.46 103.87,58.46 103.57,58.76 103.57,60.92 103.82,61.18 107.6,61.18
GND on BOTTOM (solid shape): 125.66,106.62 125.66,104.86 124.6,103.8 123.48,103.8 123.1,104.18 123.1,105.78 124.07,106.76 125.52,106.76
GND on BOTTOM (solid shape): 148.62,63.26 148.62,62.62 148.55,62.55 145.48,62.55 145.27,62.75 145.27,63.18 145.53,63.44 148.45,63.44
GND on BOTTOM (solid shape): 177.63,83.22 177.63,80.75 177.5,80.61 177.5,79.74 177.37,79.62 175.75,79.62 175.6,79.77 175.6,83.35 175.7,83.45 177.4,83.45
GND on BOTTOM (solid shape): 120.76,64.3 120.76,62.93 120.66,62.83 119.54,62.83 119.44,62.93 119.44,63.18 119.9,63.64 119.9,64.2 120.08,64.38 120.68,64.38
GND on BOTTOM (solid shape): 131.29,80.51 131.29,79.8 131.38,79.72 131.38,78.02 131.25,77.89 130.51,77.89 130.36,78.04 130.36,79.7 130.56,79.9 130.56,80.48 130.71,80.64 131.17,80.64
GND on BOTTOM (solid shape): 169.86,85.69 169.86,84.31 169.68,84.14 167.9,84.14 167.7,83.93 167.7,83.17 167.55,83.02 165.59,83.02 165.24,83.37 165.24,85.28 165.8,85.84 169.71,85.84
GND on BOTTOM (solid shape): 192.74,89.12 192.74,86.91 192.54,86.7 190,86.7 189.95,86.75 189.95,87.36 189.67,87.64 188.55,87.64 188.38,87.82 188.38,89.88 188.58,90.08 191.78,90.08
GND on BOTTOM (solid shape): 138.26,75.15 138.26,71.46 138.13,71.34 136.76,71.34 136.66,71.44 136.66,74.1 136.48,74.28 132.88,74.28 132.78,74.18 132.27,74.18 132.14,74.31 132.14,74.62 132.9,75.39 138.02,75.39
GND on BOTTOM (solid shape): 122.11,59.4 122.11,58.97 122.06,58.91 119.74,58.91 119.57,59.09 119.57,60.26 119.67,60.36 121.14,60.36
GND on BOTTOM (solid shape): 118.63,86.43 118.63,85.1 118.47,84.94 115.29,84.94 115.24,84.99 115.24,85.19 115.33,85.43 115.24,85.68 115.24,86 115.55,86.32 116.91,86.32 117.3,86.71 118.35,86.71
GND on BOTTOM (solid shape): 185.07,84.73 185.07,84.27 184.06,83.26 184.06,80.28 183.83,80.05 179.31,80.05 179.1,80.25 179.1,80.92 179.17,80.98 179.17,83.52 180.34,84.69 180.52,84.69 180.82,84.73 180.99,84.98 184.82,84.98
GND on BOTTOM (solid shape): 153.17,86.98 155.51,86.98 155.79,86.71 155.79,86.37 156.45,85.71 157.21,85.71 158.81,84.11 158.81,81.72 158.05,80.96 157.51,80.96 157.31,80.76 157.31,79.92 157.18,79.79 156.73,79.79 156.65,79.87 156.65,80.66 156.4,80.91 155.68,80.91 155.42,81.17 155.42,83.3 155.23,83.5 153.22,83.5 152.97,83.25 152.97,82.56 152.84,82.44 150.83,82.44 150.61,82.66 150.61,87.03 150.81,87.24 152.92,87.24
GND on BOTTOM (solid shape): 126.29,69.07 126.55,68.97 126.81,69.07 127.14,69.07 127.24,68.97 127.24,68.08 127.03,67.88 126.3,67.88 126.2,67.78 126.2,67.22 125.28,66.31 125.28,65.29 125.21,65.21 125.05,65.21 125.02,65.25 125.02,66.83 125.49,67.3 125.49,68.82 125.67,69 125.69,69 125.84,69.01 125.97,69.07
GND on BOTTOM (solid shape): 298.82,139.66 298.82,135.83 290.83,135.83 289.67,136.99 289.64,137.09 289.7,137.16 290.74,138.23 290.49,139.7 290.48,139.81 290.57,139.86 298.62,139.86
GND on BOTTOM (solid shape): outline of 92 points within 16.27,21.45 18.22,26.1
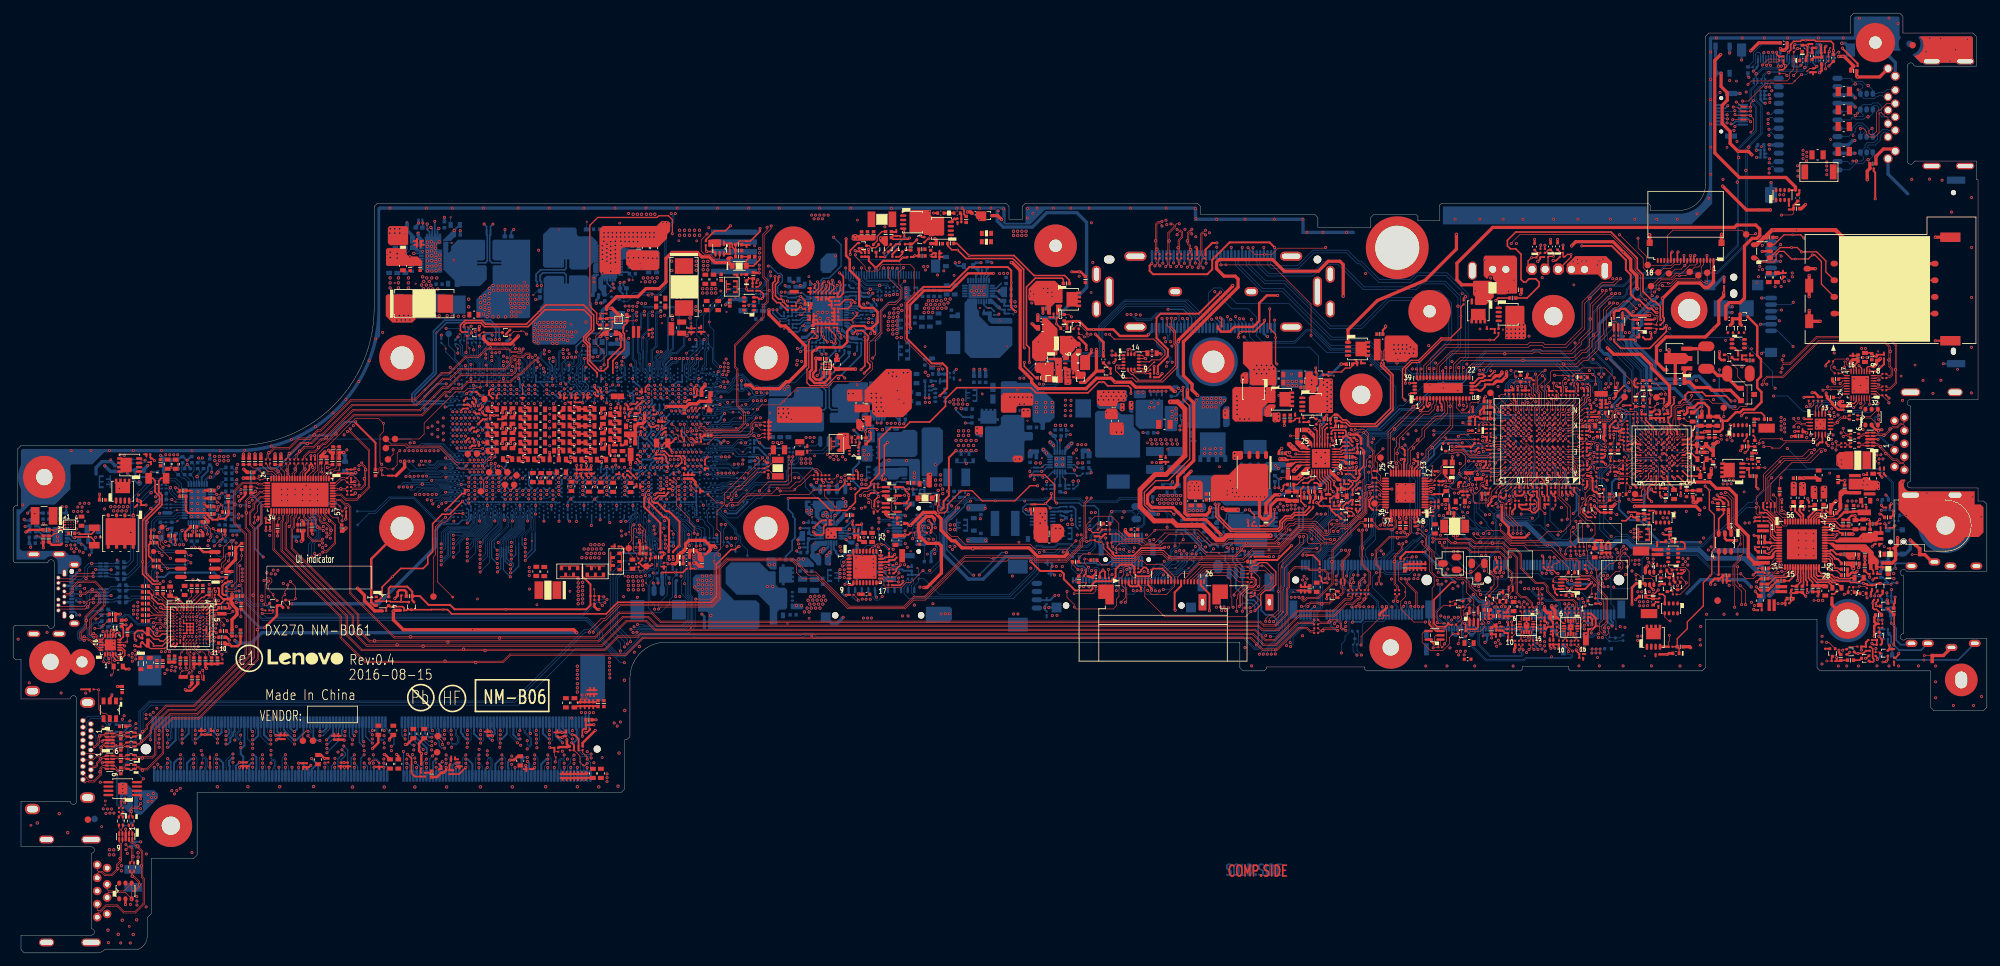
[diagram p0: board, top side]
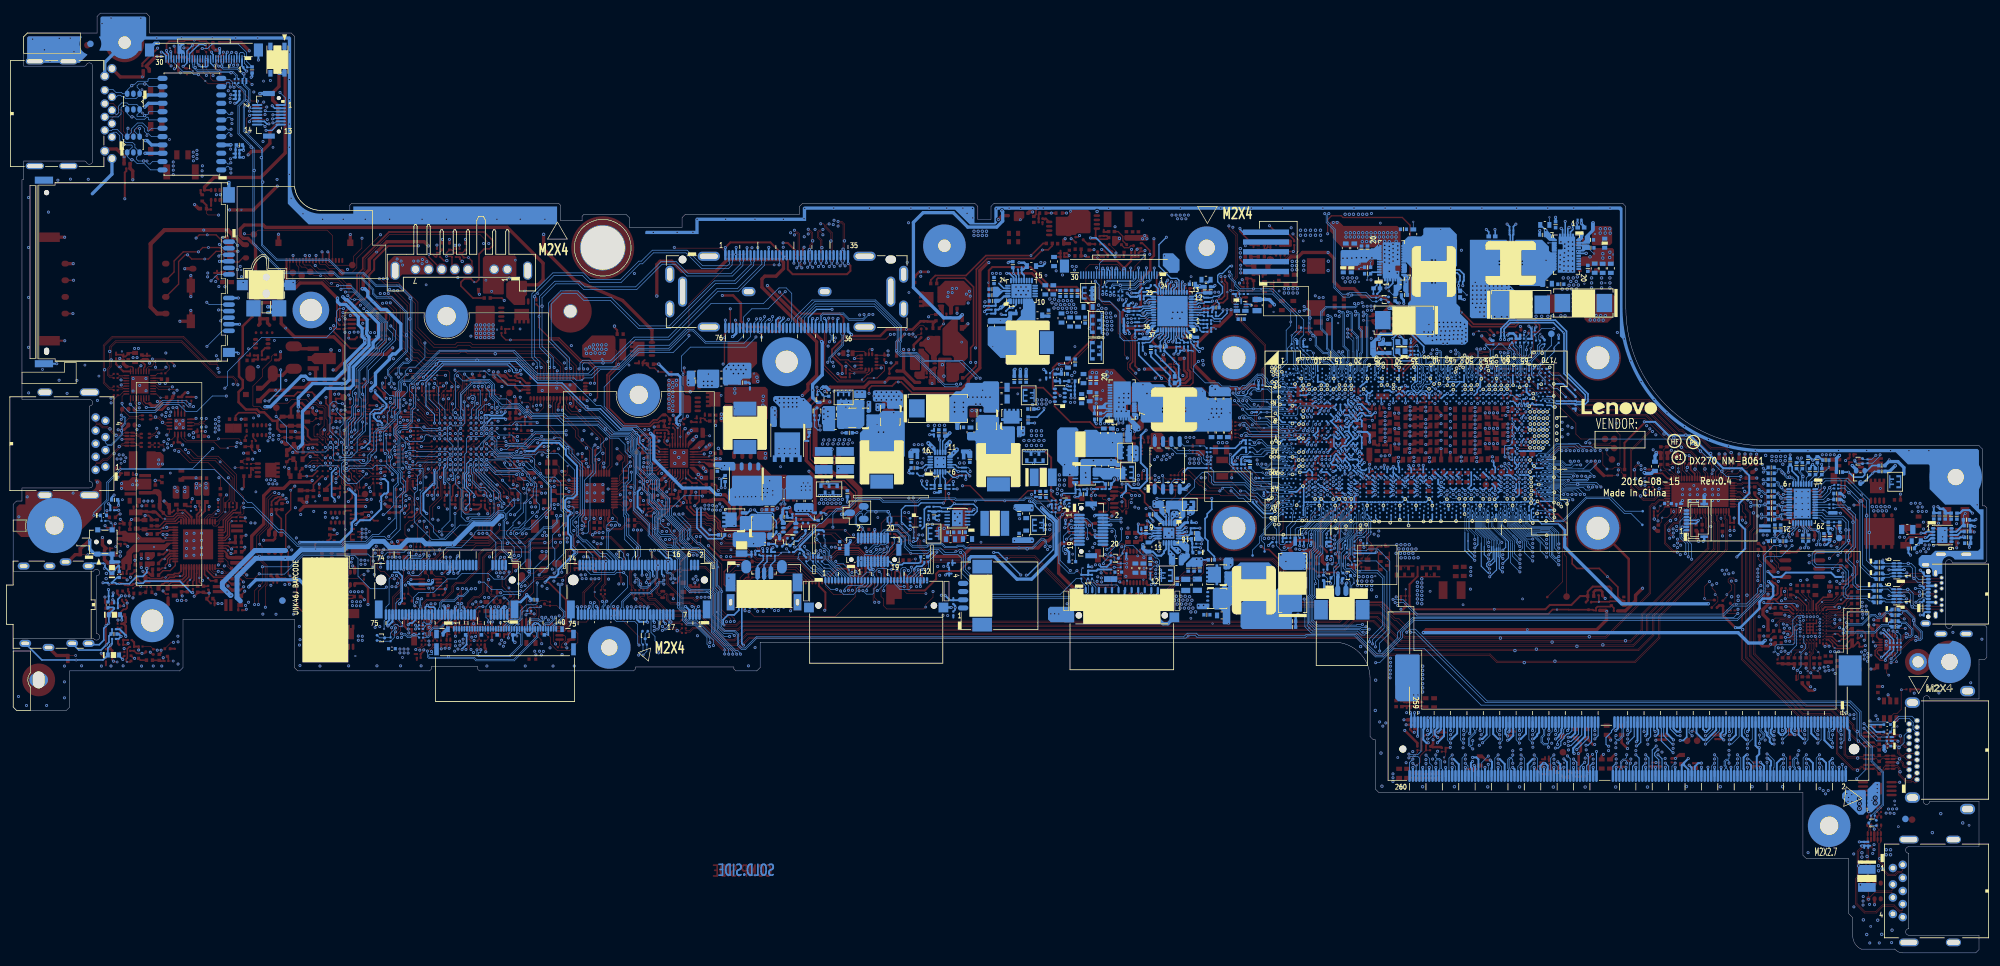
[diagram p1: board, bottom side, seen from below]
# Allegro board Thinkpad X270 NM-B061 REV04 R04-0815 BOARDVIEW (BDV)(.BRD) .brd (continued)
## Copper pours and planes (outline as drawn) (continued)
GND on BOTTOM (solid shape): 287.64,142.7 287.64,139.86 287.75,139.86 287.84,139.81 287.83,139.7 287.51,138.77 287.78,137.82 287.79,137.71 287.7,137.66 281.41,137.66 281.34,137.73 281.34,138.92 280.91,139.35 259.07,139.35 259.07,117.33 259.07,117.33 259.07,114.33 255.91,111.17 218.01,111.17 218.01,113.9 218.01,113.9 249.09,113.9 249.09,113.9 249.09,112.8 254.05,112.8 257.24,114.12 258.56,117.31 258.56,139.66 258.76,139.86 280.66,139.86 280.66,142.7 280.86,142.9 287.44,142.9
GND on BOTTOM (solid shape): outline of 112 points within 0.51,57.47 204.57,113.91
GND on IN1 (solid shape): 67.07,108.27 67.07,104.08 70.01,101.13 70.01,97.12 69.83,96.94 62.41,96.94 61.91,97.44 61.91,100.8 61.58,101.12 57.37,101.12 57.21,101.28 57.21,104.1 57.59,104.48 61.05,104.48 61.12,104.41 62.4,104.41 62.78,104.79 62.78,105.97 62.77,105.98 62.77,106.34 61.93,107.17 61.93,108.34 62.37,108.77 66.56,108.77
GND on IN1 (solid shape): 187.56,47.59 187.62,47.68 187.73,47.66 188.07,47.33 188.07,44.05 190.03,44.05 190.03,44.47 207.07,44.47 207.07,44.05 208.21,44.05 208.55,43.71 208.57,43.6 208.48,43.54 206.56,43.54 206.56,44.14 190.54,44.14 190.54,43.54 187.8,43.54 187.56,43.78
GND on IN1 (solid shape): 298.82,117.48 299.09,117.48 299.09,84.96 289.3,84.96 288.57,84.64 288.29,83.89 288.18,83.78 287.78,83.78 287.41,84.14 287.41,85.97 288.12,86.68 298.23,86.68 298.58,87.03 298.58,116.97 298.31,116.97 298.31,119.82 290.86,119.82 290.81,119.88 290.81,120.05 291.09,120.33 298.82,120.33
GND on IN1 (solid shape): 12.35,23.9 12.35,23.02 12.33,23.02 12.18,22.87 12.18,18.88 12.35,18.71 12.35,17.13 12.13,16.91 11.97,16.91 11.9,16.91 1.71,16.91 1.71,22.64 8.33,22.64 9.46,22.18 10.21,23.15 10.21,23.79 10.73,24.31 11.95,24.31
GND on IN1 (solid shape): 287.65,142.7 287.65,139.87 298.63,139.87 298.83,139.66 298.83,135.82 290.87,135.82 289.03,137.66 281.87,137.66 280.17,139.35 259.07,139.35 259.07,114.33 255.91,111.17 218.01,111.17 218.01,113.9 218.01,113.9 249.09,113.9 249.09,113.9 249.09,112.8 254.05,112.8 257.24,114.12 258.56,117.31 258.56,139.66 258.76,139.86 279.67,139.86 279.67,139.87 280.65,139.87 280.65,142.7 280.86,142.91 287.44,142.91
GND on IN1 (solid shape): 96.46,47.64 97.02,47.64 97.12,47.54 97.12,47.41 94.52,45.19 93.54,41.91 93.54,33.27 93.29,33.02 92.74,33.02 92.74,25.22 92.54,25.02 27.54,25.02 27.54,15.12 27.34,14.92 20.54,14.92 20.54,6.21 19.94,5.61 19.94,2.46 18.75,1.27 1.91,1.27 1.71,1.47 1.71,1.99 11.9,1.99 12.81,2.57 12.68,3.63 12.68,4.03 13.04,4.38 13.47,4.38 14.13,5.04 14.13,5.9 14.69,6.46 18.96,6.46 20.03,7.54 20.03,15.43 27.03,15.43 27.03,25.53 92.23,25.53 92.23,33.53 93.03,33.53 93.03,41.91 93.12,42.94 93.36,43.94 93.63,44.18 93.58,44.53 94.76,46.33 96.45,47.64
GND on IN1 (solid shape): outline of 148 points within 55.56,109.69 204.95,113.91
GND on IN2 (solid shape): 288.79,72.48 288.79,72.32 288.33,71.19 289.3,70.44 299.09,70.44 299.09,68.44 300.23,68.44 300.44,68.23 300.44,65.77 300.16,65.49 299.93,65.49 296.73,68.69 287.97,68.69 287.38,69.28 287.38,71.01 287.78,71.4 287.78,71.41 287.91,72.05 288.28,72.58 288.7,72.58
GND on IN3 (solid shape): 98.84,109.45 98.84,108.17 98.54,107.86 93.21,107.86 92.67,107.32 92.67,104.06 92.67,104.05 92.67,103.75 92.48,103.57 89.8,103.57 89.39,103.97 89.39,110.04 90.24,110.9 97.39,110.9
GND on IN3 (solid shape): 188.07,47.26 188.07,44.05 190.03,44.05 190.03,44.65 207.07,44.65 207.07,44.05 207.61,44.05 207.75,43.91 207.75,43.63 207.66,43.54 206.56,43.54 206.56,44.14 190.54,44.14 190.54,43.54 187.73,43.54 187.56,43.71 187.56,47.25 187.61,47.31 188.02,47.31
GND on IN3 (solid shape): 67.07,108.27 67.07,104.08 70.01,101.13 70.01,97.12 69.83,96.94 62.41,96.94 61.91,97.44 61.91,100.8 61.58,101.12 57.39,101.12 57.15,101.36 57.15,104.34 57.3,104.48 61.05,104.48 61.12,104.41 62.4,104.41 62.78,104.79 62.78,105.97 62.77,105.98 62.77,106.34 61.93,107.17 61.93,108.34 62.39,108.8 66.53,108.8
GND on IN3 (solid shape): 287.65,142.7 287.65,139.87 298.63,139.87 298.83,139.66 298.83,135.82 290.87,135.82 289.01,137.67 282.41,137.67 280.73,139.35 259.07,139.35 259.07,114.33 255.91,111.17 218.01,111.17 218.01,113.9 218.01,113.9 249.09,113.9 249.09,113.9 249.09,112.8 254.05,112.8 257.24,114.12 258.56,117.31 258.56,139.66 258.76,139.86 280.22,139.86 280.23,139.87 280.65,139.87 280.65,142.7 280.86,142.91 287.44,142.91
GND on IN3 (solid shape): outline of 127 points within 55.56,109.69 204.78,113.91
GND on IN4 (solid shape): 98.1,109.92 98.1,108.39 97.57,107.86 93.21,107.86 92.67,107.32 92.67,104.31 91.93,103.57 89.8,103.57 89.39,103.97 89.39,110.22 89.72,110.55 97.47,110.55
GND on IN4 (solid shape): 287.65,142.7 287.65,139.87 298.63,139.87 298.83,139.66 298.83,135.82 290.86,135.82 289.01,137.66 282,137.66 280.3,139.35 259.07,139.35 259.07,117.4 259.01,117.34 259.01,114.72 255.98,111.7 218.01,111.7 218.01,113.9 218.01,113.9 249.09,113.9 249.09,113.9 249.09,112.8 254.05,112.8 257.24,114.12 258.56,117.31 258.56,139.66 258.76,139.86 279.79,139.86 279.8,139.87 280.65,139.87 280.65,142.7 280.86,142.91 287.44,142.91
GND on IN4 (solid shape): 148.09,113.9 151.14,113.9 151.34,113.7 151.34,111.4 154.36,111.4 154.36,113.7 154.56,113.9 180.34,113.9 180.54,113.7 180.54,112.2 198.23,112.2 198.43,112.01 198.43,110.2 204.93,110.2 204.93,109.85 204.78,109.69 196.42,109.69 196.42,111.69 180.3,111.69 180.03,111.96 180.03,113.39 154.87,113.39 154.87,111.36 154.4,110.89 150.83,110.89 150.83,111.53 150.87,111.54 151.11,111.9 150.87,112.26 150.83,112.27 150.83,113.39 150.53,113.39 150.51,113.42 150.17,113.63 149.84,113.42 149.82,113.39 147.59,113.39 147.56,113.4 146.64,113.4 146.61,113.39 145.7,113.39 145.5,113.45 145.3,113.39 135.99,113.39 135.67,113.55 135.35,113.39 56.07,113.39 56.07,113.37 55.56,113.37 55.56,113.68 55.78,113.9 146.08,113.9 146.08,113.91 148.09,113.91
GND on TOP: 234.11,47.36 235.87,47.36 235.99,47.24 235.99,46.35 235.86,46.21 234.04,46.21 233.91,46.35 233.91,47.15
GND on TOP: 243.7,84.21 243.87,84.39 243.87,84.82 244.03,84.98 244.56,84.98 244.79,84.75 244.79,84.04 243.93,83.17 243.82,83.17 243.54,82.89 242.76,82.89 242.5,83.15 242.5,83.88 242.83,84.21
GND on TOP: 269.76,101.38 270.6,102.22 270.6,103.19 270.44,103.34 269.83,103.34 269.45,102.96 267.17,102.96 266.63,103.49 265.72,103.49 265.52,103.29 265.52,101.82 265.95,101.38
GND on TOP: 221.01,46.32 220.94,46.32 220.71,46.54 220.71,47.65 220.83,47.77 221.74,47.77 221.84,47.67 221.84,45.72 221.4,45.27 221.12,45.27 220.99,45.4 220.99,45.86 221.09,45.96 221.09,46.24
GND on TOP: 10.26,35.91 10.21,36 10.21,38.75 9.46,39.72 8.33,39.26 1.71,39.26 1.71,45.31 0.51,45.31 0.51,45.31 0.51,49.5 0.51,49.5 4.91,49.5 6.04,49.04 6.79,50.01 6.79,51.63 7.22,51.63 7.72,52.14 10.21,52.14 10.42,51.93 10.42,51.5 9.7,50.79 9.7,50.06 9.12,49.47 9.12,46.98 9.68,46.42 11.08,46.42 12.28,45.22 12.28,41.86 11.84,41.42 11.84,39.24 12.02,39.05 12.02,37.15 11.77,36.89 11.22,36.89 10.72,36.38 10.72,35.97 10.61,35.97 10.48,35.96 10.36,35.91
GND on TOP: outline of 144 points within 0.51,57.78 204.45,113.91
GND on TOP: 95.31,98.77 95.16,98.92 93.16,98.92 92.97,98.72 92.97,97.15 93.15,96.96 94.85,96.96 95.31,97.42
GND on TOP: 245.23,96.11 245.58,96.11 246.77,94.91 246.77,94.32 246.36,93.92 245.32,93.92 245.15,94.09 245.15,96.03
GND on TOP: 1.91,1.27 1.71,1.47 1.71,1.99 11.9,1.99 12.87,2.74 12.41,3.87 12.41,4.51 12.48,4.58 12.48,4.58 13.62,4.58 13.98,4.94 13.98,5.96 14.28,6.26 15.05,6.26 15.76,5.55 18.81,5.55 20.03,6.78 20.03,7.25 20.18,7.39 20.18,11.42 20.03,11.56 20.03,20.62 22.46,23.05 26.09,23.05 27.03,23.99 27.03,25.53 92.23,25.53 92.23,33.53 93.03,33.53 93.03,41.91 93.49,44.32 94.81,46.38 95.08,46.65 96.04,47.4 97.12,47.96 97.12,47.41 94.52,45.19 93.54,41.91 93.54,33.21 93.35,33.02 92.74,33.02 92.74,25.22 92.54,25.02 27.54,25.02 27.54,15.12 27.34,14.92 20.54,14.92 20.54,6.22 19.94,5.61 19.94,2.48 18.73,1.27
GND on TOP: 212.38,59.77 212.38,59.78 212.61,60.01 213.45,60.01 213.52,60.08 213.52,60.2 213.53,60.21 213.57,60.34 213.55,60.48 213.54,60.51 213.72,60.69 215.15,60.69 215.66,60.18 215.66,59.19 212.68,59.19 212.45,58.97 212.05,58.97 212.05,59.45
GND on TOP: 288.79,82.52 288.75,82.44 288.65,82.43 288.52,82.47 288.38,82.48 288.31,82.51 288.28,82.58 288.28,82.83 287.66,82.83 287.33,83.15 287.33,85.61 288.22,86.5 288.22,90.13 294.07,95.97 294.07,107.76 292.8,109.03 292.8,109.94 293.76,110.91 297.19,110.91 297.49,111.21 297.49,116.9 295.36,119.04 290.4,119.04 290.2,119.24 290.2,119.44 291.09,120.33 298.82,120.33 298.82,117.48 299.09,117.48 299.09,84.96 289.3,84.96 288.33,84.21 288.79,83.08
GND on TOP: 224.88,49.29 225.69,49.29 225.69,49.95 225.82,50.08 226.42,50.08 226.53,50.18 226.7,50.18 226.81,50.28 226.81,50.53 226.62,50.71 226.32,50.71 226.07,50.96 226.07,51.73 225.99,51.8 225.99,53.12 225.59,53.53 225.41,53.53 225.31,53.43 225.31,52.95 224.77,52.41 224.77,49.39
GND on TOP: 75.73,53.14 67.65,53.14 65.66,55.13 65.66,65 66.81,66.15 67.41,66.15 67.78,65.77 67.78,64.9 69.12,63.56 75.45,63.56 76.17,62.85 76.17,53.57
GND on TOP: 94.09,78.22 94.09,81.93 93.75,82.27 93.75,82.44 93.74,82.44 93.43,82.74 93.43,83.2 93.13,83.5 92.41,83.5 92.41,82.77 92.39,82.74 91.7,82.74 91.6,82.64 91.6,78.52 91.83,78.52 92.14,78.2 92.14,78.04 92.31,77.87 92.36,77.87 92.44,77.78 92.44,77.33 92.56,77.21 93.87,77.21 94.09,77.44 94.09,78.22
GND on TOP: 258.6,55.92 260.63,55.92 260.89,56.18 260.89,57.14 261.04,57.29 261.04,57.98 260.99,58.03 260.5,58.03 260.4,57.93 260.4,57.57 260.2,57.37 259.31,57.37 258.52,56.58 258.52,56
GND on TOP: 218.16,111.14 218.01,111.3 218.01,113.9 218.01,113.9 249.09,113.9 249.09,113.9 249.09,112.8 254.05,112.8 257.24,114.12 258.56,117.31 258.56,139.66 258.76,139.86 280.66,139.86 280.66,142.7 280.86,142.9 287.44,142.9 287.64,142.7 287.64,139.86 288.38,139.86 288.48,139.8 288.45,139.69 287.99,138.8 288.13,137.81 288.12,137.71 288.04,137.66 280.95,137.66 279.26,139.35 259.07,139.35 259.07,117.66 259.61,117.11 259.61,114.44 256.31,111.14
GND on TOP: 177.89,82.99 177.89,80.61 177.08,79.8 175.9,79.8 175.78,79.92 175.78,82.8 176.38,83.41 177.47,83.41
GND on TOP: 274.37,123.05 274.7,122.72 274.7,121.07 274,120.37 274,117.63 273.84,117.47 271.65,117.47 271.27,117.85 271.27,122.85 271.48,123.05
GND on TOP: 20,50.3 19.9,50.2 18.83,50.2 18.68,50.35 18.68,51.04 18.04,51.68 18.04,52.87 18.86,53.68 18.86,55.95 19.21,56.3 19.87,56.3 20,56.18
GND on TOP: 219.03,71.01 220.35,71.01 220.53,70.83 220.53,70.07 220.38,69.91 218.68,69.91 218.45,70.14 218.04,70.14 218.02,70.17 218.02,70.83 218.12,70.93 218.96,70.93
GND on TOP: 131.43,65.14 131.56,65.01 131.56,63.44 131.33,63.21 129.6,63.21 129.4,63.41 129.4,63.66 129.24,63.82 128.05,63.82 127.92,63.94 127.92,64.96 128.1,65.14
GND on TOP: 119.21,78.83 119.21,77.25 119.47,77 121.88,77 122.34,77.46 122.34,78.8 122.11,79.03 119.41,79.03
GND on TOP: 185.17,83.81 184.88,83.53 184.11,83.53 183.85,83.27 183.85,81.15 183.51,80.81 181.07,80.81 181.03,80.85 181.03,84.55 181.79,85.31 185.04,85.31 185.17,85.18
GND on TOP: 62.78,104.79 62.78,105.97 62.77,105.98 62.77,106.34 61.93,107.17 61.93,108.5 62.25,108.81 66.52,108.81 67.07,108.27 67.07,104.08 69.88,101.26 69.88,96.99 69.83,96.94 62.41,96.94 61.91,97.44 61.91,100.8 61.58,101.12 57,101.12 56.84,101.28 56.84,104.03 57.3,104.48 62.48,104.48
GND on TOP: 95.21,70.98 95.28,71.06 95.28,71.79 94.98,72.1 93.05,72.1 92.44,72.71 91.27,72.71 91.17,72.61 91.17,72.25 91.02,72.1 85.59,72.1 85.31,72.38 84.82,72.38 84.69,72.25 84.69,71.21 84.92,70.98
GND on TOP: 88.15,27.37 90.05,27.37 90.33,27.65 90.79,27.65 90.92,27.52 90.92,26.12 90.71,25.92 83.52,25.92 83.3,26.15 83.3,26.76 83.42,26.89 87.66,26.89
GND on TOP: 116.9,76.01 118.42,76.01 118.93,76.52 118.93,78.42 118.81,78.55 116.9,78.55 116.65,78.29 116.65,76.26
GND on TOP: 22.02,76.12 25.12,76.12 25.4,75.84 25.4,75.12 25.25,74.97 22.18,74.97 21.95,75.2 21.95,76.04
GND on TOP: 284.03,90.72 284.13,90.72 284.19,90.66 285.12,90.66 285.3,90.84 285.3,92.16 285.12,92.34 280.17,92.34 279.92,92.09 279.92,91.02 280.18,90.75 280.83,90.75 281.05,90.97 281.57,90.97 281.75,91.15 283.6,91.15
GND on TOP: 140.52,105.4 141.05,105.93 141.05,107.64 141.32,107.91 141.33,107.91 141.33,108.58 141.4,108.65 141.89,108.65 141.99,108.55 141.99,107.94 144.6,105.33 144.6,104.82 142.88,103.09 140.72,103.09 140.52,103.29
GND on TOP: 104.81,105.21 104.82,105.22 104.82,105.64 105.07,105.88 106,105.88 107.17,104.71 108.31,104.71 108.65,104.38 108.65,103.26 108.56,103.18 104.93,103.18 104.81,103.29
GND on TOP: 91.09,76.16 91.22,76.16 91.33,76.05 92.26,76.05 92.27,76.06 93.43,76.06 93.51,75.98 93.51,74.91 93.38,74.77 90.84,74.77 90.84,76.22 91.03,76.22
GND on TOP: 182.33,67.53 182.08,67.27 179.18,67.27 179.08,67.37 179.08,68.54 179.18,68.64 181.47,68.64 181.62,68.8 181.62,70.45 181.67,70.5 182.25,70.5 182.33,70.42 182.33,68.27 182.08,67.91 182.33,67.55
GND on TOP: 199.27,55.66 198.31,55.66 198.18,55.54 197.39,55.54 197.31,55.46 195.43,55.46 195.42,55.45 195.22,55.45 194.67,54.9 194.67,54.29 194.87,54.09 195.66,54.09 196.07,54.49 196.07,54.62 196.09,54.65 199.15,54.65 199.4,54.9 199.4,55.53
GND on TOP: 26.29,50.64 26.39,50.54 27.59,50.54 27.76,50.72 27.76,50.87 27.84,50.94 28.42,50.94 28.68,50.69 28.68,49.04 28.81,48.91 29.11,48.91 29.19,48.84 29.19,48.66 28.58,48.05 25.2,48.05 25.07,48.18 25.07,51.38 25.25,51.55 26.14,51.55 26.29,51.4
GND on TOP: 78.95,74.38 82.89,74.38 83.3,73.98 83.3,72.78 82.76,72.25 78.83,72.25 78.55,72.53 78.55,73.98
GND on TOP: 23.45,44.69 24.92,44.69 25,44.62 25,42.92 24.84,42.76 24.22,42.76 23.4,41.95 18.83,41.95 18.63,42.15 18.63,43.83 18.86,44.06 23.12,44.06 23.3,44.23 23.3,44.54
GND on TOP: 14.1,47.87 15.62,47.87 15.67,47.82 15.67,46.17 15.65,46.14 14.02,46.14 13.97,46.19 13.97,47.74
GND on TOP: 81.64,58.1 81.4,58.35 79.31,58.35 79.31,58.36 79.31,58.39 79.09,58.6 79.09,58.84 78.87,59.06 78.39,59.06 78.12,58.79 78.12,53.29 78.52,52.89 81.02,52.89 81.64,53.51
GND on TOP: 12.52,16.69 12.23,16.85 11.9,16.91 1.71,16.91 1.71,22.64 8.33,22.64 9.46,22.18 10.21,23.15 10.21,25.91 10.26,25.99 10.36,25.99 10.48,25.95 10.61,25.93 10.72,25.93 10.72,25.65 10.93,25.44 11.57,25.44 12.48,24.52 12.48,23.38 12,22.9 12,19.9 12.13,19.77 13.45,19.77 13.8,19.42 13.8,18.07 13.47,17.74 13.47,17.11 13.06,16.69
GND on TOP: 173.26,78.63 177.61,78.63 177.91,78.32 177.91,77.46 177.89,77.43 177.89,76.8 176.49,75.4 176.13,75.4 176.06,75.32 173.49,75.32 172.91,75.91 172.91,78.27
GND on TOP: 221.54,61.47 223.01,59.99 223.01,59 222.55,58.53 220.91,58.53 220,59.45 219.14,59.45 218.7,59.88 218.7,60.26 219.91,61.47
GND on TOP: 281.92,73.49 285.3,73.49 285.99,72.81 285.99,72.53 285.71,72.25 283.45,72.25 283.04,72.66 282.1,72.66 281.87,72.88 281.87,73.44
GND on TOP: 27.24,57.19 29.63,57.19 30.24,56.58 30.24,55.21 30.18,55.16 29.57,55.16 29.47,55.26 29.47,55.54 29.19,55.82 27.03,55.82 26.78,55.56 25.82,55.56 25.69,55.69 25.69,56.35 25.87,56.53 26.58,56.53
GND on TOP: 79.92,76.11 77.68,76.11 77.63,76.16 77.63,82.99 78.22,83.58 79.92,83.58 80.04,83.45 80.04,76.24
GND on TOP: 9.2,65.93 10.69,65.93 10.9,65.73 10.9,64.81 10.69,64.61 9.96,64.61 9.68,64.33 9.68,64.05 9.7,64.03 9.7,63.8 9.63,63.72 9.09,63.72 9.04,63.77 9.04,65.78
GND on TOP: 136.08,71.39 136.08,73.57 136.23,73.72 137.7,73.72 137.86,73.57 137.86,72.43 137.68,72.25 136.97,72.25 136.71,72 136.71,71.44 136.59,71.31 136.15,71.31
GND on TOP: 276.07,51.93 276.51,51.48 276.51,44.68 277.15,44.05 286.34,44.05 286.34,44.08 286.46,44.2 286.52,44.17 286.52,44.16 287.08,44.16 287.08,44.46 292.03,44.46 292.21,44.64 292.97,44.64 293.15,44.46 299.19,44.46 300.44,43.21 300.44,37.69 300.24,37.49 293.06,37.49 292.86,37.69 292.86,43.54 275.88,43.54 275.56,43.86 275.56,51.42 257.54,51.42 257.54,43.9 257.18,43.54 237.66,43.54 237.66,44.24 229.64,44.24 229.64,43.54 206.56,43.54 206.56,44.14 190.54,44.14 190.54,43.54 187.77,43.54 187.56,43.75 187.56,47.28 187.61,47.33 188.02,47.33 188.07,47.28 188.07,45.58 189,44.65 201.57,44.65 201.72,44.49 203.93,44.49 204.09,44.65 206.96,44.65 207.32,45 207.32,46.75 208.64,48.07 211.53,48.07 212.35,47.26 212.35,44.71 213.01,44.05 226.59,44.05 227.79,45.24 232.28,45.24 232.57,45.53 237.38,45.53 238.17,44.75 238.17,44.05 239.46,44.05 239.55,43.95 250.56,43.95 250.66,44.05 253.58,44.05 255.17,45.64 255.17,46.58 255.49,46.89 256.43,46.89 257.03,47.5 257.03,51.93 266.79,51.93 266.93,51.78 270.19,51.78 270.34,51.93
GND on TOP: 118.81,101.26 117.18,101.26 116.87,100.95 116.87,100.52 117,100.39 118.83,100.39 118.88,100.44 118.88,101.18
GND on TOP: 216.09,64.48 217.23,64.48 217.81,63.89 217.81,63.46 217.64,63.28 216.98,63.28 216.62,63.64 215.43,63.64 214.99,64.07 214.99,64.45 215.22,64.68 215.88,64.68
GND on TOP: 21.65,56.84 24.09,56.84 24.44,56.49 24.44,55.64 24.37,55.56 23.68,55.56 23.56,55.43 21.62,55.43 21.55,55.51 21.55,56.74
GND on TOP: 88.71,38.04 83.78,38.04 83.47,38.34 83.47,38.8 83.98,39.31 86.39,39.31 86.78,39.69 90.36,39.69 90.69,39.36 90.69,38.29 90.56,38.16 88.83,38.16
GND on TOP: 104.95,98.88 108.15,98.88 108.41,99.14 109.34,99.14 109.4,99.07 109.46,99.07 109.56,98.97 109.56,98.29 108.89,97.62 105.6,97.62 105.32,97.34 105.32,95.34 105.09,95.11 102.9,95.11 102.52,95.49 101.28,95.49 101.08,95.69 101.08,97.5 100.39,98.18 99.27,98.18 99.12,98.34 99.12,101.05 99.78,101.71 103.72,101.71 104.3,101.13 104.3,100.27 104.3,100.26 104.3,99.53
GND on TOP: 112.73,105.83 112.68,105.88 112.68,106.64 112.58,106.74 110.68,106.74 110.58,106.84 110.58,108.14 110.83,108.39 111.39,108.39 111.54,108.24 113.83,108.24 114.16,107.91 114.16,106.69 114,106.54 113.85,106.54 113.62,106.54 113.45,106.36 113.45,106.18 113.45,105.9 113.37,105.83
GND on BOTTOM: 151.85,100.75 152.79,100.75 153.02,100.52 153.02,99.07 152.97,99.02 151.88,99.02 151.72,99.17 151.72,100.62
GND on BOTTOM: 140.01,106.01 141.28,106.01 141.78,105.5 142.7,105.5 142.83,105.38 142.83,104.41 141.71,103.29 140.21,103.29 139.93,103.57 139.93,105.94
GND on BOTTOM: 137.17,61.25 137.51,60.91 137.51,58.88 137.22,58.58 136.31,58.58 135.47,59.42 135.47,59.68 135.01,59.68 134.22,60.46 134.22,60.95 134.53,61.25
GND on BOTTOM: 261.2,125.18 262.85,125.18 263.23,124.8 263.23,123.41 261.93,122.11 261.43,122.11 260.82,122.72 260.82,124.8
GND on BOTTOM: 261.48,134.91 262.87,134.91 263.25,134.53 263.25,133.03 262.95,132.73 261.63,132.73 261.22,133.13 261.22,134.66
GND on BOTTOM: 145.29,105.4 145.29,104.46 145.21,104.39 144.07,104.39 143.36,105.1 143.36,106.19 143.54,106.37 144.32,106.37
GND on BOTTOM: 12.24,16.85 12.07,16.89 11.9,16.91 1.71,16.91 1.71,22.64 8.33,22.64 9.46,22.18 10.21,23.15 10.21,24.95 13.93,24.95 14.37,24.51 14.37,23.16 14.16,22.95 13.24,22.95 12.79,22.49 12.79,18.25 13.31,17.73 13.31,17.04 13.11,16.85
GND on BOTTOM: 136.97,96.84 136.97,97.8 137.32,98.16 137.32,99.26 137.34,99.28 137.73,99.28 138.39,99.92 138.39,100.47 138.44,100.52 141.72,100.52 142.05,100.85 143.77,100.85 144.47,101.55 144.47,101.9 144.61,102.04 146.97,102.04 147.09,102.16 147.09,102.87 147.15,102.93 147.23,102.93 147.28,102.88 147.28,102.09 147.43,101.94 148.65,101.94 148.76,101.83 148.76,100.04 145.93,100.04 145.86,100.11 145.5,100.11 144.81,99.43 144.81,99.12 143.52,97.83 142.63,97.83 142.45,97.65 142.45,97.14 142.25,96.94 139.68,96.94 139.51,96.76 137.04,96.76
GND on BOTTOM: 162.29,78.42 164.53,78.42 164.68,78.27 164.68,77.38 164.53,77.23 162.29,77.23 162.14,77.38 162.14,78.27
GND on BOTTOM: 235.49,49.29 236.71,49.29 236.86,49.14 236.86,45.48 236.8,45.41 234.59,45.41 234.24,45.76 234.24,46.71 235.11,47.59 235.11,48.91
GND on BOTTOM: 100.75,54.7 102.09,54.7 102.78,54.01 102.78,50.99 102.55,50.76 100.47,50.76 100.19,51.04 100.19,54.06 100.75,54.62
GND on BOTTOM: 178.88,51.41 178.88,52.87 178.88,52.88 178.9,53.1 178.85,53.32 178.85,53.33 178.85,53.93 179.33,54.42 179.38,54.42 180.48,55.51 180.48,57.8 180.68,58 182.08,58 182.89,58.81 182.89,59.02 182.88,59.03 182.88,59.46 183.4,59.98 184.01,59.98 184.74,59.24 184.74,57.16 185.58,56.32 185.58,51.09 185.35,50.86 179.42,50.86
GND on BOTTOM: 41.59,71.77 46.54,71.77 46.97,71.34 46.97,68.34 46.87,68.24 45.27,68.24 44.89,67.86 44.89,63.31 44.54,62.95 44.54,62.12 43.44,61.02 38.85,61.02 37.55,62.32 37.55,64.63 37.98,65.06 39.33,65.06 40.65,66.38 40.65,70.83
GND on BOTTOM: 10.21,36.99 10.21,38.75 9.69,39.63 8.66,39.6 8.58,39.54 8.5,39.48 8.49,39.46 8.4,39.37 8.33,39.26 1.71,39.26 1.71,45.31 0.51,45.31 0.51,45.31 0.51,49.5 0.51,49.5 4.91,49.5 6.04,49.04 6.79,50.01 6.79,50.94 7.06,50.94 7.37,50.64 9.68,50.64 9.86,50.46 9.86,50.06 9.48,49.67 9.17,49.67 8.64,49.14 8.64,47.11 9.87,45.88 10.94,45.88 12.66,44.15 12.66,37.23 12.43,36.99
GND on BOTTOM: 290.84,63.8 290.84,68.82 290.39,69.27 288.26,69.27 287.73,69.8 287.73,72.08 288.27,72.63 288.79,72.63 288.79,72.32 288.33,71.19 289.3,70.44 299.09,70.44 299.09,68.44 300.15,68.44 300.44,68.15 300.44,63.47 291.17,63.47
GND on BOTTOM: 138.66,90.09 141.61,90.09 141.73,89.96 141.73,89.63 141.63,89.53 140.9,89.53 140.51,89.15 140.51,87.95 140.41,87.85 139.24,87.85 138.58,88.51 138.58,90.01
GND on BOTTOM: 131.12,81.25 131.12,82.03 131.07,82.08 130.68,82.08 130.61,82.16 130.61,83.1 130.68,83.18 131.14,83.18 131.24,83.28 131.24,83.99 131.17,84.07 130.48,84.07 130.48,87.6 130.46,87.62 130.46,88.89 131.4,89.83 136.91,89.83 136.92,89.82 138.06,89.82 138.3,89.58 138.3,88.1 137.8,87.6 135.05,87.6 134.95,87.7 133.78,87.7 133.12,87.04 133.12,84.4 134.52,84.4 134.88,84.75 137.21,84.75 137.34,84.62 137.34,83.89 137.24,83.79 134.98,83.79 134.67,84.09 133.12,84.09 133.12,82.14 133.07,82.08 132.18,82.08 132.18,81.27 131.9,81.27 131.9,82.08 131.45,82.08 131.4,82.03 131.4,81.25
GND on BOTTOM: 288.79,82.52 288.75,82.44 288.65,82.43 288.53,82.46 288.4,82.48 288.38,82.48 288.28,82.58 287.11,82.58 286.8,82.89 286.8,116.1 291.03,120.33 298.82,120.33 298.82,117.48 299.09,117.48 299.09,84.96 289.3,84.96 288.33,84.21 288.79,83.08
GND on BOTTOM: 244.66,53.91 245.98,53.91 246.57,53.33 246.57,49.92 245.98,49.34 245.17,49.34 244.54,49.97 244.54,53.78
GND on BOTTOM: 151.6,60.13 154.52,60.13 155.53,59.12 155.53,58.46 154.31,57.24 151.7,57.24 151.47,57.47 151.47,60.01
GND on BOTTOM: 118.55,55.05 119.2,55.7 122.68,55.7 123.14,56.16 123.14,56.48 123.19,56.53 123.71,56.53 124.11,56.13 124.11,53.43 123,52.31 122.67,52.31 122.36,52.01 122.36,51.22 121.83,50.69 119.54,50.69 119.01,51.22 119.01,51.88 119.29,52.16 120.56,52.16 120.84,52.44 120.84,53.25 120.53,53.56 118.58,53.56 118.55,53.58
GND on BOTTOM: 16.06,11.11 19.36,11.11 19.77,10.71 19.77,7.25 19.31,6.79 16.6,6.79 15.81,7.58 15.81,10.86
GND on BOTTOM: 93.84,107.91 93.73,107.91 93.23,108.41 92.28,108.41 92.1,108.23 92.1,103.5 92.04,103.44 89.6,103.44 89.54,103.49 89.54,104.38 89.62,104.46 90.1,104.46 90.18,104.53 90.18,105.19 90.07,105.3 89.48,105.3 89.41,105.37 89.41,108.72 89.14,108.99 89.14,112.46 89.57,112.89 99.83,112.89 99.96,112.76 99.96,111.51 99.1,110.66 99.1,108.56 98.15,107.61 94.14,107.61 94.09,107.66 94.09,107.66
GND on BOTTOM: 229.69,48.12 228.66,48.12 228.08,47.54 227.85,47.54 227.19,48.2 226.76,48.2 226.45,48.5 226.45,50.05 226.3,50.2 226.3,50.56 226.37,50.63 227.14,50.63 227.57,50.2 228.17,50.2 228.24,50.13 228.25,50.13 228.27,50.11 228.27,48.99 228.4,48.86 229.69,48.86 229.8,48.76 229.8,48.22
GND on BOTTOM: 178.47,75.48 178.72,75.73 178.72,78.5 178.46,78.76 172.64,78.76 172.48,78.6 172.48,75.68 172.68,75.48
GND on BOTTOM: 94.32,54.62 95.97,54.62 96.38,54.22 96.38,50.99 96.15,50.76 94.24,50.76 93.99,51.02 93.99,54.29
GND on BOTTOM: 150.05,102.09 150.05,102.35 150.5,102.81 151.88,102.81 151.95,102.88 151.95,103.87 151.83,104 150.25,104 149.74,103.49 149.16,103.49 148.73,103.06 148.73,102.25 148.75,102.22 148.95,102.22 149.06,102.12 149.06,101.76 149.08,101.74 149.69,101.74
GND on BOTTOM: 62.09,96.86 61.78,97.17 61.78,100.58 61.3,101.07 57.06,101.07 56.84,101.28 56.84,104.09 56.88,104.13 58.99,104.13 59.03,104.16 59.04,104.16 59.15,104.28 61.15,104.28 61.63,103.8 62.59,103.8 62.61,103.81 62.76,103.81 62.93,103.97 62.93,108.7 63.13,108.9 65.29,108.9 65.35,108.84 65.35,107.83 65.31,107.78 64.8,107.78 64.7,107.68 64.7,107.06 64.81,106.95 65.42,106.95 65.47,106.9 65.47,103.16 64.83,102.53 64.83,101.59 65.67,100.75 69.1,100.75 69.81,100.04 69.81,97.14 69.55,96.89 64.14,96.89 64.12,96.86
GND on BOTTOM: 114.02,105.3 113.5,105.83 113.47,105.83 113.36,105.94 106.45,105.94 106.36,106.03 104.88,106.03 104.69,105.85 104.69,103.86 105.18,103.38 113.73,103.38 114.02,103.67
GND on BOTTOM: 194.85,54.62 195.74,54.62 196.5,53.86 196.5,50.94 196.12,50.56 195.11,50.56 194.6,51.07 194.6,54.37
GND on BOTTOM: 118.81,78.98 118.75,79.03 115.27,79.03 115.15,78.9 115.15,77.86 115.5,77.51 118.55,77.51 118.81,77.76
GND on BOTTOM: 156.14,67.7 156.14,64.63 156.22,64.55 156.22,63.84 156.27,63.79 156.65,63.79 156.88,63.56 156.88,62.75 156.93,62.7 157.74,62.7 157.82,62.78 157.82,67.55 157.64,67.73 156.17,67.73
GND on BOTTOM: 158.25,79.64 158.25,80.68 158.38,80.81 160.99,80.81 161.15,80.66 161.15,79.72 160.92,79.49 158.4,79.49
GND on BOTTOM: 243.77,102.42 243.49,102.15 241.28,102.15 240.85,101.72 237.29,101.72 236.84,102.17 236.84,105.88 236.2,106.51 224.65,106.51 223.83,105.7 223.83,102.27 223.3,101.74 222.06,101.74 221.12,102.68 221.12,110.2 221.6,110.68 243.21,110.68 243.77,110.12
GND on BOTTOM: 11.2,62.25 11.08,62.37 11.08,63.34 11.18,63.44 11.99,63.44 12.45,63.9 12.45,65.27 12.55,65.37 15.14,65.37 15.29,65.22 15.29,63.11 14.43,62.25
GND on BOTTOM: 141.36,74.18 143.16,74.18 143.32,74.03 143.32,71.18 142.96,70.83 142.96,69.96 143.16,69.76 145.4,69.76 145.5,69.66 145.5,69.33 145.45,69.28 145.02,69.28 144.69,68.95 142.99,68.95 142.55,69.38 141.72,69.38 140.24,70.85 140.24,72.4 140.34,72.5 140.93,72.5 141.16,72.73 141.16,73.98
GND on BOTTOM: 19.48,45.61 22.51,45.61 23.78,44.34 23.78,41.65 22.63,40.5 19.38,40.5 18.9,40.99 18.9,45.03
GND on BOTTOM: 90.93,94.86 90.6,95.19 90.6,97.68 90.86,97.93 91.35,97.93 91.63,98.21 91.63,98.92 91.73,99.02 93.79,99.02 94.32,99.55 95.39,99.55 95.46,99.48 95.46,98.26 95.36,98.16 94.9,98.16 93.84,97.09 93.84,95.2 93.5,94.86
GND on BOTTOM: 293.06,37.49 292.86,37.69 292.86,43.54 275.78,43.54 275.56,43.76 275.56,51.42 257.54,51.42 257.54,43.88 257.2,43.54 237.85,43.54 237.66,43.73 237.66,44.24 229.69,44.24 229.68,44.24 229.64,44.2 229.64,43.77 229.41,43.54 206.85,43.54 206.56,43.83 206.56,44.14 201.37,44.14 201.37,44.14 197.09,44.14 197.09,44.14 190.54,44.14 190.54,43.88 190.2,43.54 187.73,43.54 187.56,43.71 187.56,46.96 187.63,47.03 187.84,47.03 190.22,44.65 206.07,44.65 206.07,49.52 206.61,50.06 215.28,50.06 215.83,50.61 217.48,50.61 218.27,49.82 218.27,48.93 218.4,48.81 220.25,48.81 220.3,48.75 220.3,48.27 220.18,48.15 216.26,48.15 215.93,47.81 215.93,44.05 228.46,44.05 228.87,44.46 232.82,44.46 233.11,44.75 238.31,44.75 239.01,44.05 248.61,44.05 248.62,44.04 256.82,44.04 257.02,44.24 257.02,51.68 257.91,52.56 267.62,52.56 267.98,52.21 271.94,52.21 272.63,52.89 276.72,52.89 277.86,54.04 281.37,54.04 282.94,52.46 282.94,48.3 282.94,48.3 284.79,46.45 284.79,45.71 285.22,45.28 285.45,45.28 286.46,44.27 299.93,44.27 300.44,43.75 300.44,37.69 300.24,37.49
GND on BOTTOM: 130.49,58.86 130.26,58.64 128.03,58.64 127.8,58.86 127.54,58.86 127.21,59.19 127.21,59.65 128.11,60.55 128.95,60.55 129.27,60.87 130.16,60.87 130.49,60.54
GND on BOTTOM: 132.2,80.07 132.2,79.79 132.36,79.62 132.82,79.62 132.88,79.68 135.1,79.68 135.21,79.79 135.21,80.53 134.67,81.07 133.2,81.07
GND on BOTTOM: 185.89,67.96 186.95,67.96 187.05,67.86 187.05,67.46 186.97,67.38 184.74,67.38 184.57,67.55 184.36,67.55 184.18,67.73 184.18,67.88 184.34,68.03 184.46,68.03 184.59,68.16 185.68,68.16
GND on BOTTOM: 152.08,49.01 154.7,49.01 154.92,49.24 154.92,51.17 154.11,51.98 151.98,51.98 151.67,51.68 151.67,49.42
GND on BOTTOM: 1.91,1.27 1.71,1.47 1.71,1.99 12.99,1.99 13.45,2.45 13.45,3.11 16.19,5.85 19.27,5.85 20.03,6.62 20.03,20.75 22.72,23.43 25.82,23.43 27.03,24.65 27.03,25.43 27.13,25.53 92.23,25.53 92.23,33.53 93.03,33.53 93.03,41.91 93.38,44.02 94.4,45.9 94.4,46.44 96.15,48.2 96.17,48.2 96.35,48.37 103.54,48.37 103.77,48.15 103.77,48.03 103.64,47.91 99.55,47.91 97.38,47.5 95.5,46.33 95.49,46.32 95.46,46.31 94.04,44.31 93.54,41.91 93.54,33.21 93.35,33.02 92.74,33.02 92.74,25.22 92.54,25.02 27.54,25.02 27.54,15.12 27.34,14.92 20.54,14.92 20.54,6.18 19.94,5.58 19.94,2.43 18.78,1.27
GND on GND1: outline of 215 points within 0.51,1.27 300.44,142.9 ; 1 cut-out
GND on IN1: 293.06,37.49 292.86,37.69 292.86,43.54 275.8,43.54 275.56,43.78 275.56,48.5 276.07,48.5 276.07,44.05 293.37,44.05 293.37,38 299.93,38 299.93,43.78 300.09,43.93 300.44,43.93 300.44,37.69 300.24,37.49
GND on IN1: 10.47,36.97 10.29,37.15 10.21,37.15 10.21,38.75 9.46,39.72 8.33,39.26 1.71,39.26 1.71,45.31 0.51,45.31 0.51,45.31 0.51,49.5 0.51,49.5 4.91,49.5 6.04,49.04 6.79,50.01 6.79,52.32 7.64,52.32 7.65,52.33 9.83,52.33 10.49,51.67 10.49,47.16 13.13,44.52 13.13,38.04 12.07,36.97
GND on IN1: 212.14,43.54 212.05,43.6 212.07,43.71 212.4,44.05 229.59,44.05 229.62,44.01 229.62,43.57 229.59,43.54
GND on IN1: 298.58,68.42 297.88,69.13 287.94,69.13 287.64,69.43 287.64,71.46 287.79,71.62 287.95,72.14 288.28,72.58 288.28,72.58 288.72,72.58 288.79,72.52 288.79,72.32 288.33,71.19 289.3,70.44 299.09,70.44 299.09,68.44 300.23,68.44 300.44,68.23 300.44,63.46 299.96,63.46 299.55,63.87 299.55,66.69 298.58,67.65
GND on IN1: 6.79,57.17 6.79,59.51 6.04,60.48 4.91,60.02 0.51,60.02 0.51,60.02 0.51,62.18 0.49,62.2 0.51,62.22 0.51,67.7 1.21,67.7 1.21,76.61 1.5,76.9 34.05,76.9 47.81,81.88 55.2,94.5 55.72,94.5 48.65,81.93 35.32,76.43 35.09,76.49 34.87,76.41 34.46,76.4 34.05,76.39 1.72,76.39 1.72,67.84 1.71,67.83 1.71,67.08 1.14,66.51 1.14,62.93 1.65,62.42 6.86,62.42 10.42,58.87 10.42,57.93 9.88,57.4 7.57,57.4 7.34,57.17
GND on IN1: 185.65,84.9 185.65,83.79 185.45,83.58 184.33,83.58 183.9,83.15 183.9,78.17 183.82,78.1 179.68,78.1 179.33,78.45 179.33,84.64 179.68,85 185.56,85
GND on IN1: 237.66,43.58 237.66,43.98 237.72,44.05 257.03,44.05 257.03,50.93 257.37,51.27 257.48,51.29 257.54,51.19 257.54,43.73 257.35,43.54 237.7,43.54
GND on VCC: 278.89,87.27 284.67,93.05 284.67,113.84 291.16,120.33 298.78,120.33 298.78,117.44 298.86,117.44 298.86,84.96 289.37,84.96 288.33,84.25 288.78,83.08 288.78,72.36 288.22,71.81 288.22,71.03 288.81,70.45 299.07,70.45 299.07,68.44 299.14,68.36 300.28,68.36 300.44,68.2 300.44,63.46 290.28,63.46 289.37,62.55 286.32,62.55 286.06,62.8 286.06,68.92 284.28,70.71 281.97,70.71 281.69,70.43 281.69,69.99 279.26,69.99 278.89,70.36
GND on VCC: outline of 98 points within 0.51,1.27 92.67,76.9
GND on VCC: 57.39,74.76 63.18,74.76 65.01,72.94 67.7,72.94 69.88,70.75 74.91,70.75 75.22,71.06 81.82,71.06 82.79,72.02 83.27,72.02 83.4,71.89 83.4,69.38 85.53,67.25 85.53,46.47 82.64,43.57 82.64,28.43 81.62,27.42 19.64,27.42 19.52,27.55 19.52,33.79 46.87,61.15 47,61.15 50.23,64.38 50.23,67.6
GND on IN2: 288.79,82.52 288.75,82.44 288.65,82.43 288.52,82.47 288.38,82.48 288.31,82.51 288.28,82.58 288.28,82.83 287.81,83.67 287.94,84.62 287.79,84.77 287.79,85.76 288.5,86.47 298,86.47 298.58,87.06 298.58,116.97 298.31,116.97 298.31,119.82 290.89,119.82 290.81,119.91 290.81,120.05 291.09,120.33 298.82,120.33 298.82,117.48 299.09,117.48 299.09,84.96 289.3,84.96 288.33,84.21 288.79,83.08
GND on IN2: 22.44,53.17 29.53,53.17 29.99,52.71 29.99,46.79 29.38,46.18 23.23,46.18 21.96,47.45 21.96,52.68
GND on IN2: outline of 103 points within 1.71,1.27 300.44,52.18
GND on IN2: outline of 159 points within 0.51,37.05 298.83,142.91
GND on IN2: 1.71,16.91 1.71,22.64 8.33,22.64 9.46,22.18 10.21,23.15 10.21,32.73 10.75,33.28 14.85,33.28 15.09,33.04 15.09,18.1 13.9,16.91
GND on IN3: 6.79,57.07 6.79,59.51 6.04,60.48 4.91,60.02 0.51,60.02 0.51,60.02 0.51,67.7 0.51,67.7 1.21,67.7 1.21,76.66 1.45,76.9 34.05,76.9 47.81,81.88 55.2,94.5 55.72,94.5 48.65,81.93 35.32,76.43 35.09,76.49 34.87,76.41 34.46,76.4 34.05,76.39 3.18,76.39 1.86,75.07 1.86,67.2 1.2,66.54 1.2,62.98 2.9,61.28 7.44,61.28 8.92,59.81 9.48,59.81 10.49,58.79 10.49,57.9 9.65,57.07
GND on IN3: 181.06,85.28 185.23,85.28 185.38,85.13 185.38,83.81 185.1,83.53 184.11,83.53 183.85,83.27 183.85,81.24 184.57,80.53 189.24,80.53 189.49,80.28 189.49,78.55 189.04,78.09 181.14,78.09 180.86,78.37 180.86,85.08
GND on IN3: 288.79,82.52 288.75,82.44 288.65,82.43 288.52,82.47 288.38,82.48 288.31,82.51 288.28,82.58 288.28,82.83 288.21,82.9 288.14,82.98 287.81,82.98 287.46,83.32 287.46,85.46 288.5,86.5 295,86.5 298.58,90.08 298.58,116.97 298.31,116.97 298.31,119.82 290.86,119.82 290.81,119.88 290.81,120.05 291.09,120.33 298.82,120.33 298.82,117.48 299.09,117.48 299.09,84.96 289.3,84.96 288.33,84.21 288.79,83.08
GND on IN3: 293.06,37.49 292.86,37.69 292.86,43.54 275.8,43.54 275.56,43.78 275.56,51.42 257.54,51.42 257.54,43.93 257.15,43.54 237.66,43.54 237.66,44.24 229.64,44.24 229.64,43.54 211.44,43.54 211.35,43.6 211.37,43.71 211.71,44.05 229.13,44.05 229.13,44.66 229.17,44.7 231.89,44.7 231.94,44.75 238.17,44.75 238.17,44.05 257.03,44.05 257.03,51.93 270.95,51.93 270.95,51.88 271.33,51.55 271.71,51.88 271.72,51.93 276.07,51.93 276.07,44.05 293.37,44.05 293.37,38 299.93,38 299.93,43.62 299.96,43.65 300.44,43.65 300.44,37.69 300.24,37.49
GND on IN3: 288.15,68.85 287.44,69.56 287.44,70.78 287.8,71.14 287.8,71.22 287.83,71.83 288.11,72.39 288.79,72.39 288.79,72.32 288.33,71.19 289.3,70.44 299.09,70.44 299.09,68.44 300.03,68.44 300.44,68.03 300.44,64.33 299.63,63.51 293.81,63.51 293.43,63.89 292.67,63.89 292.06,64.5 292.06,68.62 291.83,68.85
GND on IN3: 12.3,16.82 12.11,16.89 11.9,16.91 1.71,16.91 1.71,22.64 8.33,22.64 9.46,22.18 10.21,23.15 10.21,38.75 9.46,39.72 8.33,39.26 1.71,39.26 1.71,45.31 0.51,45.31 0.51,45.31 0.51,49.5 0.51,49.5 4.91,49.5 6.04,49.04 6.79,50.01 6.79,51.71 7.14,51.71 7.39,51.96 10.24,51.96 10.34,51.86 10.34,51.05 10.01,50.72 10.01,47.54 13.21,44.34 13.21,18.08 13.46,17.83 13.46,17.14 13.14,16.82
GND on IN3: 1.91,1.27 1.71,1.47 1.71,1.99 11.9,1.99 11.96,1.99 12.02,2 13.49,2 13.71,1.78 18.58,1.78 19.28,2.48 19.28,5.71 20.03,6.46 20.03,15.43 27.03,15.43 27.03,25.53 92.23,25.53 92.23,33.53 93.03,33.53 93.03,41.91 94,45.32 96.61,47.73 97.03,47.73 97.12,47.64 97.12,47.41 94.52,45.19 93.54,41.91 93.54,33.29 93.27,33.02 92.74,33.02 92.74,25.22 92.54,25.02 27.54,25.02 27.54,15.12 27.34,14.92 20.54,14.92 20.54,6.19 19.94,5.59 19.94,2.43 18.78,1.27
GND on GND2: outline of 214 points within 0.51,1.27 300.44,142.9 ; 1 cut-out
GND on IN4: 1.91,1.27 1.71,1.47 1.71,1.99 11.9,1.99 11.98,1.99 12.05,2 12.24,1.82 12.85,1.82 12.79,1.78 18.58,1.78 19.28,2.48 19.28,5.71 20.03,6.46 20.03,15.43 27.03,15.43 27.03,25.53 92.23,25.53 92.23,33.53 93.03,33.53 93.03,41.91 94.15,45.56 97.12,47.96 97.12,47.41 94.52,45.19 93.54,41.91 93.54,33.29 93.27,33.02 92.74,33.02 92.74,25.22 92.54,25.02 27.54,25.02 27.54,15.12 27.34,14.92 20.54,14.92 20.54,6.18 19.94,5.58 19.94,2.43 18.78,1.27
GND on IN4: 6.79,57.27 6.79,59.51 6.04,60.48 4.91,60.02 0.51,60.02 0.51,60.02 0.51,67.7 0.51,67.7 1.21,67.7 1.21,76.66 1.45,76.9 34.05,76.9 47.81,81.88 55.2,94.5 55.72,94.5 55.62,93.99 55.51,93.47 55.11,92.64 54.59,90.68 54.59,90.49 47.03,80.63 35.32,76.43 35.09,76.49 34.87,76.41 34.46,76.4 34.05,76.39 12.42,76.39 5.77,69.74 5.77,63.47 9.84,59.39 9.84,58.98 8.15,57.29 7.47,57.29 7.44,57.27
GND on IN4: 293.06,37.49 292.86,37.69 292.86,43.54 275.75,43.54 275.56,43.73 275.56,51.07 275.68,51.19 275.97,51.19 276.07,51.1 276.07,44.05 293.37,44.05 293.37,38 299.93,38 299.93,43.67 300.29,43.67 300.44,43.52 300.44,37.69 300.24,37.49
GND on IN4: 181.06,85.28 185.23,85.28 185.38,85.13 185.38,83.81 185.1,83.53 184.11,83.53 183.85,83.27 183.85,81.24 184.57,80.53 189.24,80.53 189.49,80.28 189.49,78.55 189.04,78.09 182.46,78.09 180.86,79.69 180.86,85.08
GND on IN4: 187.85,43.54 187.56,43.83 187.56,47.63 187.61,47.69 187.99,47.69 188.07,47.61 188.07,44.05 190.03,44.05 190.03,44.65 207.07,44.65 207.07,44.05 215.92,44.05 215.97,44 217,44 217.04,44.05 229.13,44.05 229.13,44.59 229.22,44.67 229.22,44.69 238.09,44.69 238.17,44.61 238.17,44.05 257.03,44.05 257.03,51.88 257.08,51.93 263.15,51.93 263.24,51.83 263.24,51.49 263.17,51.42 257.54,51.42 257.54,43.73 257.35,43.54 237.9,43.54 237.66,43.78 237.66,44.24 229.64,44.24 229.64,43.79 229.39,43.54 206.56,43.54 206.56,44.14 190.54,44.14 190.54,43.54
GND on IN4: 288.28,82.83 288.02,83.15 287.84,83.53 287.16,84.22 287.16,85.94 289.57,88.35 297.62,88.35 298.58,89.32 298.58,116.97 298.31,116.97 298.31,119.82 290.89,119.82 290.81,119.91 290.81,120.05 291.09,120.33 298.82,120.33 298.82,117.48 299.09,117.48 299.09,84.96 289.3,84.96 288.33,84.21 288.79,83.08 288.79,82.84 288.78,82.83
GND on IN4: 293.81,63.64 287.38,70.07 287.38,70.73 287.59,70.93 287.61,70.93 287.82,71.14 287.81,71.74 288.05,72.3 288.34,72.3 288.34,72.31 288.77,72.31 288.33,71.17 289.3,70.44 299.09,70.44 299.09,68.44 300.08,68.44 300.44,68.08 300.44,64.02 300.06,63.64
GND on IN4: 12.47,16.73 12.2,16.86 11.9,16.91 1.71,16.91 1.71,22.64 8.33,22.64 9.46,22.18 10.21,23.15 10.21,38.75 9.46,39.72 8.33,39.26 1.71,39.26 1.71,45.31 0.51,45.31 0.51,45.31 0.51,49.5 0.51,49.5 4.91,49.5 6.04,49.04 6.79,50.01 6.79,51.93 10.19,51.93 12.7,49.42 12.7,38.37 15.65,35.42 15.65,30.01 13.13,27.5 13.13,18.16 13.45,17.84 13.45,17.11 13.07,16.73
GND on GND3: outline of 215 points within 0.51,1.27 300.44,142.9 ; 1 cut-out
GND_81208 on BOTTOM (solid shape): 120.96,102.38 120.96,101.64 120.69,101.36 118.99,101.36 118.97,101.39 118.97,101.9 119.01,101.95 120.28,101.95 120.43,102.09 120.43,102.4 120.44,102.41 120.93,102.41
GND_81208 on TOP: 125.54,100.24 125.59,100.19 125.59,99.88 125.54,99.83 125.1,99.83 124.98,99.71 124.98,98.67 125.13,98.51 125.36,98.51 125.41,98.46 125.41,96.94 125.16,96.94 125.14,96.93 124.99,96.93 124.89,96.82 124.89,96.47 124.67,96.25 124.67,96.02 124.47,95.82 122.68,95.82 122.2,95.34 121.69,95.34 121.57,95.47 121.57,96 121.86,96.3 121.86,97.64 121.79,97.71 121.23,97.71 121.01,97.93 121.01,99.78 120.23,100.57 119.34,100.57 119.26,100.65 119.26,101.55 119.81,102.1 121.34,102.1 121.87,101.57 121.87,100.51 122.13,100.24
GND_81208 on BOTTOM: 121.98,100.27 126.45,100.27 126.48,100.24 126.48,95.77 126.37,95.67 121.95,95.67 121.85,95.77 121.85,100.14
GNDA on TOP: 279.36,67.86 282.1,67.86 282.25,68.01 282.25,69.3 282.18,69.38 279.43,69.38 279.26,69.2 279.26,67.96
GNDA on GND1, GND2, GND3: 300.44,45 286.68,45 286.47,45.16 286.42,45.58 286.03,45.94 285.52,45.94 285.52,46.37 285.8,46.65 285.8,51.94 285.5,52.24 285.5,54.48 284.08,55.9 282.75,55.9 279.09,55.89 278.8,55.65 277.83,54.67 277.12,54.67 275.88,53.43 272.42,53.43 271.71,52.72 268.39,52.72 268.33,52.77 268.33,53.78 268.39,53.83 270.12,53.83 270.87,54.59 270.87,55.13 270.75,55.26 270.75,55.59 272.07,56.91 272.07,58.81 272.2,58.94 275.25,58.94 275.65,59.34 275.65,64.3 275.2,64.76 274.64,64.76 274.49,64.91 274.51,66.3 275.07,66.86 275.85,66.86 276.49,66.23 277.86,66.23 278.95,67.32 279.13,67.32 279.28,67.47 279.28,69.33 279.41,69.46 282.2,69.46 282.2,70.19 282.2,70.2 284.05,70.2 285.55,68.7 285.55,68.19 285.56,68.18 285.56,62.57 286.09,62.04 289.6,62.04 290.49,62.93 300.44,62.93 300.44,58.76 288.94,58.76 287.44,58.63 287.74,57.16 287.74,49.1 287.44,47.63 288.94,47.5 300.44,47.5
GNDA on VCC: outline of 127 points within 268.33,45 300.44,70.2 ; 6 cut-outs
GNDA on IN2: outline of 126 points within 268.33,45 300.44,70.2 ; 6 cut-outs
VCC0R6B on BOTTOM (solid shape): 121.58,68.97 121.58,68.67 121.19,68.67 121.17,68.64 121.17,68.19 121.6,68.19 121.65,68.13 121.65,67.88 121.95,67.58 121.95,66.85 121.92,66.81 121.07,66.81 120.76,67.12 120.76,69.03 121.52,69.03
VCC0R6B on TOP: 87.84,27.49 89.82,27.49 90.33,28 90.81,28 91.31,28.5 91.31,32.82 92.87,34.38 92.87,35.57 92.77,35.67 91.02,35.67 88.87,33.53 88.87,31.17 88.71,31 88.71,29.12 88.58,28.99 87.69,28.99 87.69,28.76 87.46,28.54 83.4,28.54 83.22,28.36 83.22,27.27 83.35,27.14 87.49,27.14
VCC0R6B on IN4: 122.11,67.78 122.11,66.48 120.46,64.83 119.9,64.83 119.74,64.68 119.74,64.3 117,61.56 111.44,61.56 110.75,62.24 108.7,62.24 107.78,61.33 107.78,60.46 104.1,56.78 104.1,52.69 101.58,50.18 96.78,50.18 96.76,50.2 95.31,50.2 93.28,48.17 93.28,33.97 92.85,33.54 91.5,33.54 91.04,34 91.04,41.72 90.48,42.28 90.48,50.51 92.85,52.87 98.08,52.87 101.41,56.2 101.41,57.49 105.55,61.63 105.55,62.6 104.94,63.21 104.94,65.62 106.82,67.5 110.3,67.5 111.36,68.57 121.32,68.57
VCC0R6BP on BOTTOM (solid shape): 125.18,68.87 125.18,67.35 124.85,67.02 124.85,65.34 124.77,65.26 124.6,65.26 124.6,67.55 124.48,67.67 123.38,67.67 122.94,67.23 122.94,66.56 123.28,66.22 123.81,66.22 124.04,65.99 124.04,65.16 123.98,65.1 123.67,65.1 122.21,66.56 122.21,67.7 121.93,67.98 121.93,68.92 122.03,69.02 125.03,69.02
VCC0R9GBE on TOP: 218.8,66.43 215.55,66.43 215.27,66.15 214.64,66.15 214.28,66.51 213.5,66.51 213.29,66.31 213.29,65.24 213.62,64.91 215.99,64.91 216.19,64.71 217.19,64.71 217.87,64.02 218.93,64.02 219.16,64.25 219.16,64.25 219.16,66.07
VCC0R9GBE on IN1: 210.68,74.84 213.01,74.84 214.99,72.86 216.24,72.86 216.47,72.63 216.47,71.46 216.32,71.31 214.28,71.31 212.12,73.47 210.7,73.47 210.42,73.75 210.42,74.59
VCC0R9GBE on IN4: 213.34,74.56 215.1,72.81 215.1,68.41 215.08,68.4 215.76,67.73 215.76,65.47 215.58,65.29 214.39,65.29 214,65.67 213.09,65.67 212.71,66.05 209.51,66.05 209.15,66.41 209.15,67.14 209.47,67.46 209.47,73.76 210.27,74.56
VCC0R9GBE_L on TOP: 222.3,64.22 222.2,64.12 221.03,64.12 220.98,64.17 220.98,64.32 220.57,64.73 220.57,65.97 220.16,66.38 220.14,66.38 220.14,66.58 220.42,66.86 220.42,67.12 220.93,67.62 222.14,67.62 222.3,67.47
VCC0R9GBE_L on IN4: 216.04,70.67 216.77,70.67 217.1,70.34 218.63,70.34 219.87,69.1 220.28,69.1 222.08,67.3 222.08,67.17 221.14,66.23 219.92,66.23 216,70.15 216,70.64
VCC1R0_SUS on TOP: 97.34,76.84 97.34,75.68 97.14,75.48 95.67,75.48 95.51,75.63 95.51,75.92 95.95,76.35 95.95,76.87 96.07,77 96.07,77.54 96.31,77.78 97.17,77.78 97.91,78.52 98.58,78.52 98.62,78.47 98.62,77.21 98.39,76.98 97.48,76.98
VCC1R0_SUS on TOP: 99.93,94.91 105.24,94.91 105.52,95.19 105.52,96.66 106.03,97.17 108.72,97.17 109.92,98.37 109.92,98.89 110.6,99.58 111.59,99.58 111.62,99.55 113.27,99.55 113.62,99.2 113.62,96.62 109.46,92.46 109.46,90.89 109.1,90.54 107.78,90.54 102.75,85.51 102.75,84.14 102.43,83.82 99.61,83.82 98.38,82.59 97.47,82.59 97.37,82.69 97.37,83.29 97.74,83.66 98.34,83.66 98.91,84.23 98.91,85.88 98.91,85.88 98.91,86.84 98.93,86.87 98.93,88.11 99.91,89.09 99.91,94.88
VCC1R0_SUS on BOTTOM: 135.37,97.12 135.37,97.67 135.67,97.98 135.67,98.69 135.47,98.89 133.83,98.89 133.03,98.09 133.03,91.53 134.1,90.46 135.75,90.46 135.87,90.59 135.87,96.61
VCC1R0_SUS on BOTTOM: 114.87,98.67 114.87,97.56 118.21,94.22 119.49,94.22 119.85,93.87 119.85,89.78 119.59,89.51 119.09,89.51 118.98,89.62 118.98,91.51 118.7,91.79 118.7,92.54 116.09,95.16 114.96,95.16 113.87,96.25 113.87,98.45 114.09,98.67
VCC1R0_SUS on IN2: 94.75,72.83 94.75,73.45 93.85,74.35 93.85,86.98 94.21,87.34 94.55,87.34 95.28,88.07 95.28,90.92 92.57,93.64 92.57,94.04 92.87,94.35 110.04,94.35 111.64,95.95 124.27,95.95 127.96,99.64 133.5,99.64 133.51,99.63 135.06,99.63 135.65,99.05 135.65,82.92 131.4,78.68 120.8,78.68 119.51,77.39 111.61,77.39 111.39,77.6 111.39,78.03 110.7,78.73 108.01,78.73 107.17,77.89 107.17,73.55 106.31,72.68 94.9,72.68 ; 1 cut-out
VCC1R2A on TOP: 91.54,58.56 79.41,58.56 79.26,58.7 79.26,59.83 78.69,60.4 78.69,64.55 78.06,65.19 78.06,66.6 78.88,67.42 78.88,72.12 82.91,72.12 83.5,72.71 83.7,72.71 83.7,73.72 83.96,73.98 84.64,73.98 84.64,72.78 84.34,72.48 84.34,71.16 84.67,70.83 85.91,70.83 85.99,70.9 94.62,70.9 94.9,70.62 94.9,66.23 94.27,65.59 94.27,65.57 94.12,65.42 94.12,63.22 93.44,62.55 92.72,62.55 92.47,62.29 92.47,62.04 92.29,61.86 91.86,61.86 91.54,61.55
VCC1R2A on VCC: 83.75,72.78 84.46,72.78 85.28,71.97 90.53,71.97 91.6,73.04 92.82,73.04 94.04,74.26 94.42,74.26 94.6,74.08 94.6,65.75 93.71,64.86 91.35,64.86 90.41,63.92 90.41,60.9 89.34,59.83 86.57,59.83 86.12,60.29 86.12,67.45 83.68,69.89 83.68,72.71
VCC1R2A on IN4: 79.77,73.16 83.91,73.16 84.36,72.71 84.36,71.97 85.05,71.28 90.84,71.28 90.84,72.96 91.37,73.49 93.56,73.49 93.89,73.82 93.89,74.46 94.95,74.46 95.13,74.28 95.13,72.61 94.6,72.07 94.6,66.81 93.66,65.87 93.66,65.65 93.25,65.24 91.73,65.24 90.31,63.82 90.31,60.64 89.42,59.75 88.2,59.75 88.15,59.8 81.02,59.8 79.37,61.45 79.37,66.19 77.99,67.58 77.99,71.39
VCC1R2A_DIMN on TOP: 247.48,47.41 251.37,47.41 251.77,47.81 251.77,50.13 251.65,50.25 247.56,50.25 247.2,49.9 247.2,47.69
VCC1R2A_DIMN on TOP: 83.93,58.41 86.22,58.41 86.6,58.03 86.6,57.34 87.28,56.65 87.28,53.61 86.72,53.05 82.48,53.05 82.15,53.38 82.15,56.53 82.18,56.55 82.18,57.72 82.38,57.92 83.55,57.92 83.93,58.31
VCC1R2A_DIMN on TOP: 26.04,26.28 26.03,26.29 24.51,26.29 22.87,27.93 22.87,29.27 23.94,30.34 23.94,34.43 24.62,35.11 29.07,35.11 29.08,35.13 52.13,35.13 53.77,36.77 63.81,36.77 63.83,36.75 78.18,36.75 85.47,44.04 88.38,44.04 89.29,43.12 89.29,40.14 89.01,39.86 86.55,39.86 86.27,39.59 83.47,39.59 82.79,38.9 82.79,35.7 83.93,34.56 84.59,34.56 84.85,34.3 84.85,33.57 84.64,33.36 83.93,33.36 83.83,33.26 83.8,33.27 83.63,33.26 83.48,33.18 82.38,33.18 82.12,32.92 82.08,32.91 82.05,32.92 82.02,32.95 82,32.99 82.02,33.02 82.13,33.27 82.05,33.52 82.02,33.59 82.05,33.66 81.78,34.3 81.5,33.66 81.53,33.59 81.51,33.52 81.42,33.29 81.51,33.06 81.53,32.99 81.5,32.92 81.39,32.65 81.52,32.35 81.51,32.31 81.16,31.97 81.16,29.69 81.16,29.68 81.14,29.57 81.16,29.46 81.16,29.45 81.16,28.42 81.16,28.41 81.14,28.31 81.16,28.2 79.23,26.28 ; 1 cut-out
VCC1R2A_DIMN on IN1: 86.29,57.59 89.98,57.59 90.13,57.44 90.13,42.33 90.81,41.64 90.81,26.61 89.98,25.77 32.93,25.77 32.52,26.17 32.52,28.16 33.08,28.71 66.18,28.71 70.16,32.7 70.16,33.59 70.42,33.84 73.24,33.84 85.98,46.58 85.98,57.28
VCC1R2A_DIMN on VCC: 251.22,50.94 251.24,50.96 251.71,50.49 251.71,47.05 249.53,44.87 228.76,44.87 228.13,44.23 207.35,44.23 206.9,44.68 189.95,44.68 189.1,45.53 189.1,46.75 187.92,47.94 98.99,47.94 98.94,47.89 98.94,47.89 95.09,45.94 93.54,41.91 93.54,33.31 93.51,33.17 93.4,33.06 92.76,33.06 92.72,33.02 92.72,29.76 92.44,29.48 91.77,29.48 89.53,27.24 83.25,27.24 83.25,43.27 86.01,46.04 86.01,57.29 86.22,57.49 87.99,57.49 94.55,50.94
VCC1R2A_DIMN on IN3: 26.04,26.28 26.03,26.29 24.51,26.29 22.87,27.93 22.87,29.27 23.94,30.34 23.94,34.43 24.62,35.11 29.07,35.11 37.37,43.42 75.03,43.42 75.64,44.04 87.61,44.04 89.29,42.36 89.29,35.08 80.49,26.28
VCC1R8_SUS on BOTTOM (solid shape): 131.04,77.31 131.04,75.11 130.88,74.96 129.49,74.96 129.33,75.11 129.33,77.23 129.56,77.46 130.88,77.46
VCC1R8_SUS on TOP: 122.31,76.77 122.77,76.31 122.77,75.86 123.91,74.71 129.32,74.71 129.5,74.89 129.5,76.95 129.52,76.98 131.5,76.98 131.71,76.77 131.71,74.61 130.72,73.62 123.43,73.62 122.74,74.31 119.26,74.31 119.24,74.33 119.24,76.72 119.29,76.77
VCC1R8_SUS on TOP: 265.97,53.86 265.82,54.01 265.06,54.01 264.83,53.78 264.83,52.89 265.08,52.64 266.3,52.64 266.4,52.54 266.4,52.16 266.46,52.11 267.93,52.11 268.08,52.26 268.08,54.01 268,54.09 267.32,54.09 267.09,53.86
VCC1R8_SUS on BOTTOM: 264.75,54.37 266.79,54.37 267.01,54.14 267.01,53.1 266.73,52.82 264.63,52.82 264.55,52.89 264.55,54.16
VCC1R8_SUS on IN2: 108.34,73.7 107.43,74.61 107.43,77.76 108.11,78.45 110.22,78.45 111.55,77.11 119.74,77.11 121.05,78.42 131.73,78.42 135.94,82.64 147.56,82.64 151.39,78.8 169.35,78.8 175.42,84.87 176.11,84.87 176.84,84.14 176.84,83.68 169.54,76.38 169.53,76.38 168.2,75.04 161.11,75.04 159.78,76.38 150.92,76.38 146.82,80.48 139.38,80.48 139.37,80.47 137.82,80.47 133.77,76.42 131.56,76.42 130.29,75.15 128.38,75.15 127.24,76.29 124.14,76.29 124.11,76.31 124.11,75.86 124.71,75.26 124.39,74.94 122.56,74.94 121.32,73.7
VCC1R8_SUS on IN2: 196,63.61 199.27,63.61 199.83,63.05 199.83,62.45 199.42,62.04 195.79,62.04 194.93,62.9 192.08,62.9 191.5,63.49 191.5,63.94 191.7,64.15 195.46,64.15
VCC1R8_SUS on IN3: 98.69,77.1 98.69,76.39 98.94,76.14 98.94,75.96 99.25,75.65 106.84,75.65 108.67,77.48 108.67,78.39 107.37,79.69 101.34,79.69 101.04,79.99 100.7,79.99 100.44,79.73 100.44,78.85
VCC1R8_SUSA on TOP: 260.71,61.92 262.13,61.92 262.51,61.54 262.51,59.91 262.05,59.45 262.05,55.75 261.88,55.57 261.29,55.57 261.06,55.8 261.06,56.99 261.24,57.17 261.24,58.11 260.58,58.77 260.58,61.79
VCC1R8_SUSA on TOP: 275.85,54.93 276.74,54.93 276.82,54.85 276.82,54.34 275.98,53.5 275.09,53.5 274.99,53.61 274.99,54.06
VCC1R8_SUSA on TOP: 270.72,54.32 270.75,54.29 270.75,53.78 270.49,53.53 270.49,52.72 268.38,52.72 268.33,52.77 268.33,53.76 268.4,53.84 270.11,53.84 270.23,53.97 270.23,54.27 270.28,54.32
VCC1R8_SUSA on IN4: 268.84,53.81 270.06,53.81 272.07,55.82 275.57,55.82 276.31,55.08 276.31,53.91 275.83,53.43 272.42,53.43 271.71,52.72 268.89,52.72 268.89,52.72 268.4,52.72 268.35,52.77 268.35,53.76 268.4,53.81 268.84,53.81
VCC1V2B on TOP: 250.63,46.93 250.4,47.16 247.3,47.16 246.52,47.94 239.58,47.94 239.18,47.54 239.18,44.61 239.63,44.16 250.48,44.16 250.63,44.31
VCC2R5A on TOP: 86.98,36.08 85.94,35.04 84.18,35.04 83.5,35.72 83.5,37.65 83.72,37.87 90.45,37.87 90.66,37.65 90.66,36.18 90.56,36.08
VCC2R5A on BOTTOM: 144.43,66.26 144.43,64.27 144.15,63.99 142.6,63.99 142.48,64.12 142.48,65.49 142.88,65.9 142.99,65.9 143.44,66.36 144.33,66.36
VCC2R5A on BOTTOM: 86.8,36.38 86.42,36.38 86.22,36.59 86.22,37.32 86.42,37.53 89.93,37.53 90.18,37.27 90.18,34.58 89.85,34.25 87.18,34.25 87.08,34.35 87.08,36.11
VCC2R5A on VCC: 94.37,64.2 94.37,60.29 92.92,58.84 92.92,55.18 93.99,54.11 116.24,54.11 118.45,56.32 139.79,56.32 141.84,58.38 141.84,65.72 142.3,66.18 145.78,66.18 147.08,64.88 147.08,52.67 145.73,51.32 94.8,51.32 89.16,56.96 89.16,59.17 90.51,60.51 90.51,63.84 91.35,64.68 93.89,64.68
VCC2R5A on IN4: 86.32,36.33 86.32,55.04 86.42,55.13 86.42,57.77 88.1,59.45 89.19,59.45 90.7,60.96 90.7,63.65 91.88,64.83 94.34,64.83 94.83,64.35 94.83,59.4 89.86,54.43 89.86,53.72 88.83,52.69 88.83,42.28 89.26,41.85 89.26,36.51 88.76,36 86.65,36
VCC3_LDO_TBTA on TOP: 21.75,57.09 24.27,57.09 24.65,56.7 24.65,54.98 26.37,53.25 26.37,52.21 26.55,52.21 26.58,52.23 26.58,54.22 26.63,54.27 26.63,55.05 26.5,55.18 25.74,55.18 25.38,55.54 25.38,56.45 25.76,56.83 26.3,56.83 26.58,57.11 26.58,57.72 26.22,58.08 22.38,58.08 21.85,58.61 21.85,60.24 21.74,60.34 21.11,60.34 21.01,60.24 21.01,57.83
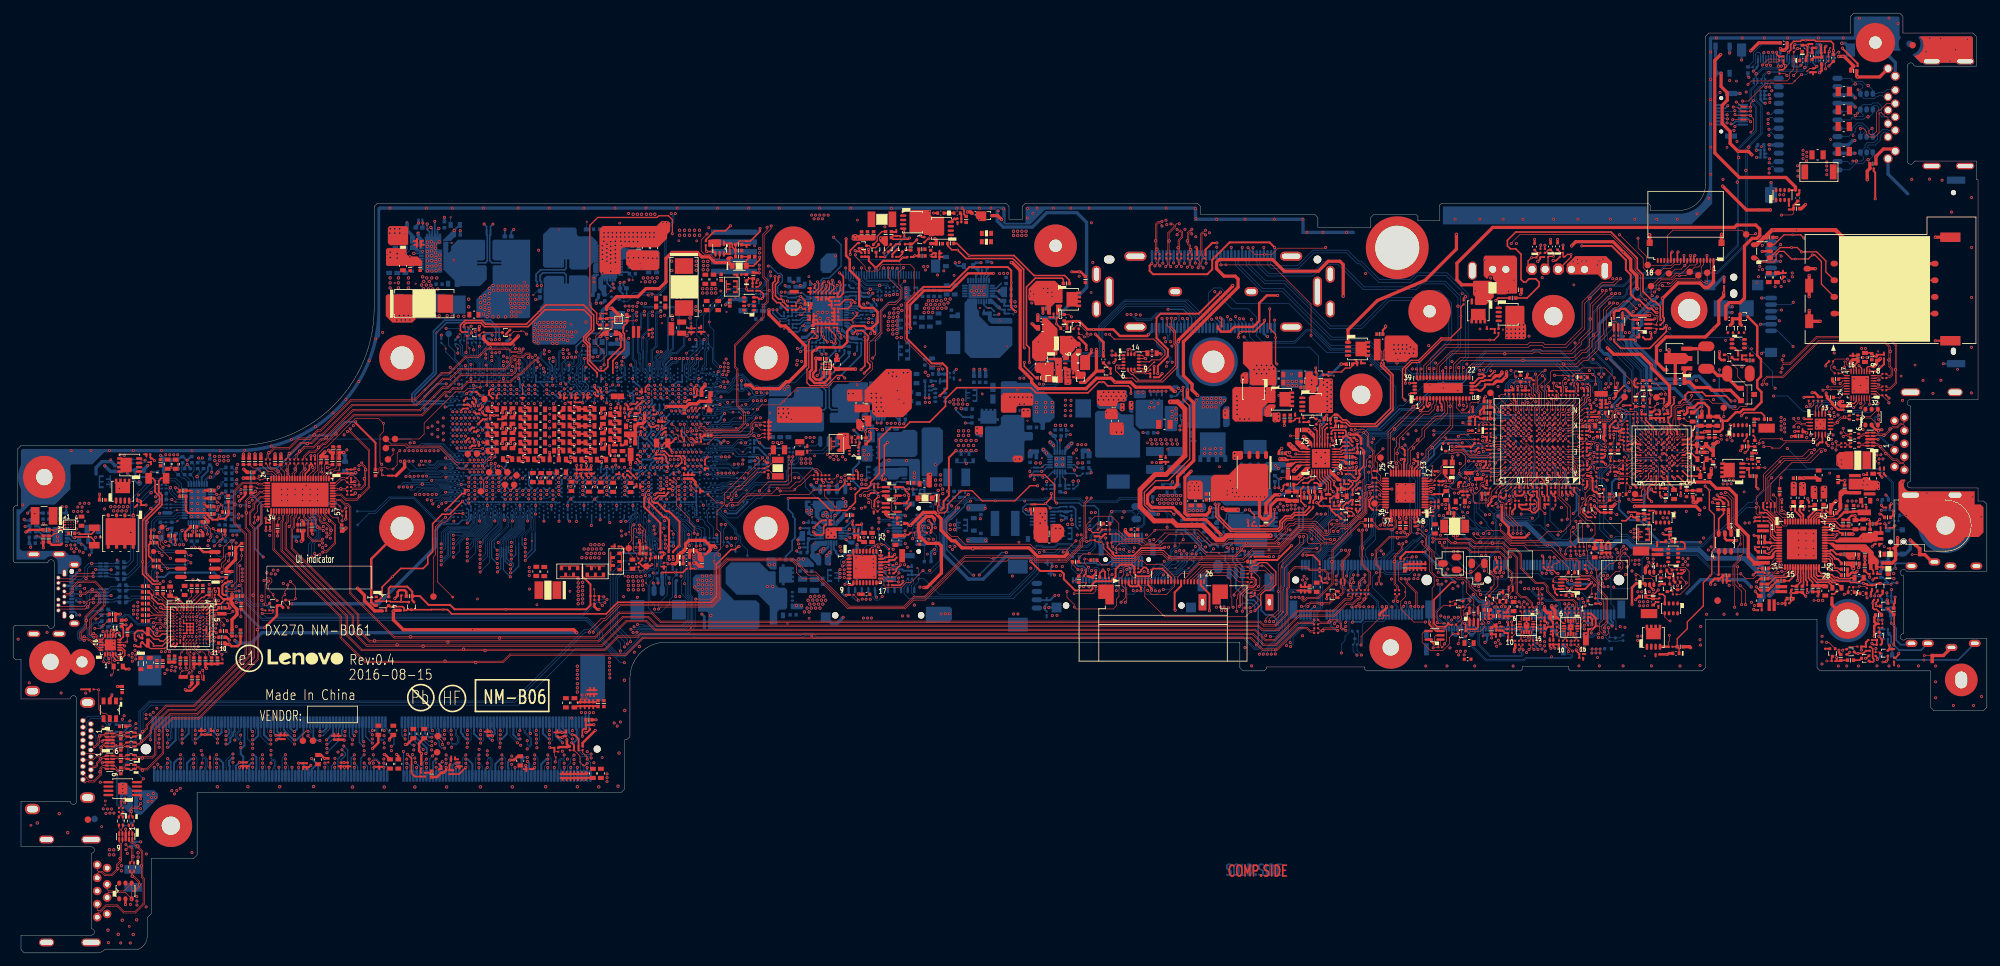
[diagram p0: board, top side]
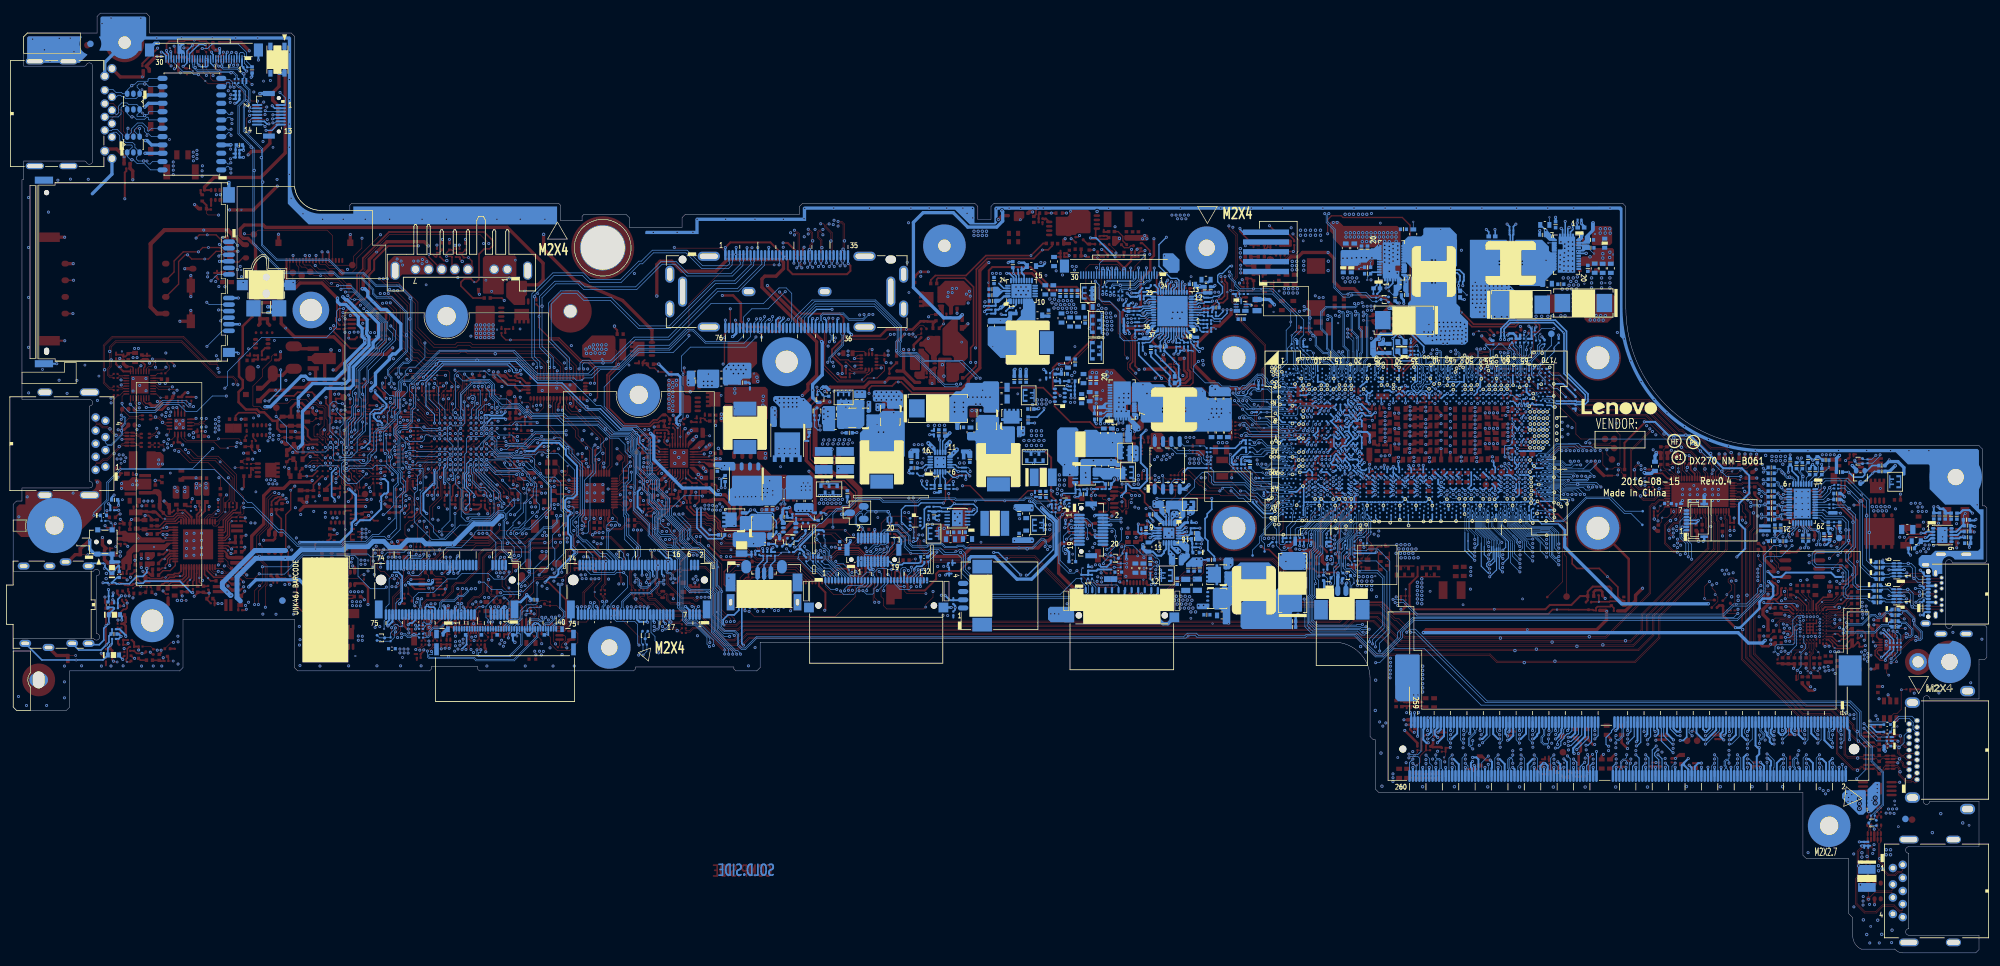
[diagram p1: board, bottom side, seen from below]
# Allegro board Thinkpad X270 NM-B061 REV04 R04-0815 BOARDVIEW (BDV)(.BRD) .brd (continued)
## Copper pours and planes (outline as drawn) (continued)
VCC3_MC on TOP: 270.39,103.62 269.66,103.62 269.32,103.29 267.37,103.29 266.96,103.69 266.28,103.69 266.07,103.9 266.07,104.89 266.48,105.3 271.56,105.3 272.32,104.53 272.32,103.03 272.2,102.91 271.1,102.91
VCC3_MC on BOTTOM: 272.75,95.47 275.67,92.55 282.58,92.55 283.55,91.58 283.55,90.74 282.97,90.16 282.97,89.78 282.48,89.29 281.37,89.29 281.21,89.45 281.21,90.21 280.96,90.46 275.77,90.46 271.62,94.61 271.62,102.24 270.72,103.14 270.72,103.54 270.73,103.55 270.73,104.13 270.84,104.23 271.88,104.23 272.75,103.36
VCC3_MC on BOTTOM: 266.05,105.02 266.94,105.02 267.12,104.84 268.69,104.84 268.82,104.71 268.82,104.36 268.67,104.2 267.22,104.2 266.86,103.85 266.25,103.85 265.9,104.2 265.9,104.86
VCC3_SUS on TOP: 127.11,71.77 128.38,71.77 128.63,71.51 128.63,70.57 128.43,70.37 127.16,70.37 127.01,70.52 127.01,71.67
VCC3_SUS on TOP: 270.54,54.98 270.54,55.26 270.39,55.41 268.11,55.41 267.47,54.77 267.47,54.39 267.52,54.34 267.88,54.34 267.9,54.37 269.94,54.37
VCC3_SUS on TOP: 134.86,59.09 134.86,60.01 135.09,60.24 136.28,60.24 136.41,60.11 136.41,59.32 136,58.91 135.04,58.91
VCC3_SUS on TOP: 130.39,69.05 130.82,68.62 130.82,68.36 131.05,68.13 131.45,68.13 134.1,65.49 134.1,64.1 133.84,63.84 132.98,63.84 131.56,65.26 129.42,65.26 128.61,66.08 128.61,68.21 129.45,69.05
VCC3_SUS on TOP: outline of 90 points within 94.8,69.99 125.97,87.72
VCC3_SUS on TOP: 259.18,66.16 259.18,61.66 258.7,61.18 257.1,61.18 256.49,61.79 256.49,67.3 257.42,68.23 258.18,68.23 258.35,68.06 258.35,67
VCC3_SUS on BOTTOM: 258.57,62.62 259.45,63.5 259.92,63.5 260.45,62.96 260.45,61.97 259.36,60.88 258.62,60.88 257.91,61.59 257.91,61.96
VCC3_SUS on BOTTOM: 115.22,100.82 115.66,100.39 115.66,98.03 115.43,97.8 115.2,97.8 115,98.01 115,98.74 114.89,98.84 114.13,98.84 114.06,98.92 114.06,99.78 114.21,99.94 114.21,100.75 114.28,100.82
VCC3_SUS on IN1: 130.13,68.69 130.41,68.41 130.59,68.41 130.72,68.54 130.72,70.78 130.57,70.93 129.4,70.93 128.85,71.48 128.85,74.57 127.07,76.35 123.91,76.35 123.59,76.03 123.59,75.04 126.17,72.47 126.17,71.41 128.89,68.69
VCC3_SUS on VCC: 94.73,79.46 95.3,80.03 122.87,80.03 125.99,76.91 125.99,73.34 123.66,71.01 103.67,71.01 101.84,69.18 95.34,69.18 94.73,69.79
VCC3_SUS on IN2: 245.63,68.9 247.41,68.9 247.74,68.57 247.74,67.04 246.82,66.13 245.75,66.13 244.18,64.55 240.41,64.55 239.99,64.13 234.67,64.13 234.44,64.36 234.44,65.68 235.08,66.31 236.79,66.31 236.84,66.36 237.6,66.36 238.08,66.84 243.57,66.84
VCC3_SUS on IN3: 94.98,71.16 93.53,71.16 93.3,71.39 93.3,75.35 93.53,75.58 96.17,75.58 96.48,75.27 96.48,74 95.39,72.91 95.39,71.56
VCC3_SUS on IN4: 135.54,60.11 136.64,59.02 136.64,58 136.99,57.64 136.99,56.86 136.51,56.37 135.49,56.37 135.26,56.6 135.26,57.9 134.78,58.38 134.02,58.38 133.18,59.22 133.18,61.84 132.8,62.22 132.8,64.66 133.03,64.88 134.15,64.88 134.48,64.55 134.48,62.34 134.9,61.92 134.9,61.38 135.54,60.74
VCC3B on TOP: 228.23,53.05 229.19,53.05 229.27,53.12 229.27,54.39 229.14,54.52 228.33,54.52 228.08,54.27 228.08,53.2
VCC3B on TOP: 282.33,88.25 282.46,88.38 282.46,89.32 282.83,89.69 283.22,89.69 283.38,89.85 283.4,89.85 283.65,90.11 283.65,90.79 283.52,90.92 282.13,90.92 281.85,90.64 281.85,89.14 281.95,89.04 281.95,88.33 282.03,88.25
VCC3B on TOP: 275.1,134.6 275.19,134.69 275.62,134.69 275.72,134.59 275.72,134.03 275.46,133.77 273.74,133.77 273.64,133.88 273.64,134.21 274.03,134.6
VCC3B on TOP: 263.79,64.53 263.05,65.26 263.05,74.05 263.25,74.26 264.8,74.26 264.93,74.13 264.93,73.72 265.24,73.42 265.24,66.2 265.46,65.98 265.46,65.93 265.79,65.59 267.62,65.59 267.88,65.34 267.88,65.06 267.75,64.93 265.36,64.93 264.96,64.53
VCC3B on TOP: 49.51,75.12 50.58,75.12 51.27,75.81 51.27,76.85 51.06,77.05 50.81,77.05 50.4,76.64 49.49,76.64 49.44,76.59 49.44,75.2
VCC3B on TOP: 251.72,59.63 251.49,59.4 250.99,59.4 250.91,59.32 250.91,59.04 250.73,58.86 250.33,59.27 249.89,59.27 249.69,59.47 249.69,60.88 249.86,61.05 251.61,61.05 251.72,60.94
VCC3B on BOTTOM: 174.63,62.09 176.26,62.09 176.44,61.91 176.44,60.92 176.08,60.57 174.76,60.57 174.51,60.82 174.51,61.96
VCC3B on BOTTOM: 256.5,60.36 256.98,59.88 256.98,53.66 256.9,53.58 256.9,44.35 256.8,44.24 249.19,44.24 249.13,44.18 243.62,44.18 243.29,44.51 243.29,47.21 243.47,47.38 245.7,47.38 245.79,47.47 245.79,48.03 246.69,48.93 246.69,55.64 248.35,57.29 248.35,60.08 248.62,60.36
VCC3B on BOTTOM: 49.84,74.61 51.44,74.61 51.67,74.84 51.67,77.33 51.39,77.61 49.82,77.61 49.62,77.41 49.62,74.84
VCC3B on IN1: 41.25,76.4 41.44,76.21 41.44,75.6 38.98,73.14 34.58,73.14 34.38,73.35 34.38,75.7 35.07,76.4
VCC3B on IN2: outline of 120 points within 36.48,32.3 286.45,138.93
VCC3B on IN3: 50.88,54.37 46.92,58.34 46.92,63.96 39.59,56.63 36.93,56.63 36.17,57.4 36.17,58.72 34.7,60.19 34.7,67.3 34.19,67.81 34.19,68.98 34.7,69.49 34.7,73.91 34.88,74.08 35.64,74.08 35.88,73.84 42.52,73.84 46.29,77.61 51.85,77.61 53.3,76.16 53.3,70.34 52.36,69.4 52.36,56.91 53.39,55.87 53.39,55.08 52.68,54.37 ; 1 cut-out
VCC3B_PS8349B on BOTTOM: 39.29,66.04 40.12,66.86 40.12,70.52 42.35,72.76 52.28,72.76 52.61,73.09 52.61,74.15 52.36,74.41 42.05,74.41 38.14,70.51 38.14,66.23 38.33,66.04
VCC3FP on TOP: 164.37,68.34 170.16,68.34 170.9,67.6 170.9,64.48 170.7,64.27 170.29,64.27 169.86,64.71 169.86,65.14 168.16,66.84 164.4,66.84 164.09,67.14 164.09,68.06
VCC3FP on BOTTOM: 162.29,65.73 162.29,66.45 162.52,66.67 162.57,66.67 163.55,67.66 165.13,67.66 165.28,67.5 165.28,65.93 164.98,65.63 162.39,65.63
VCC3GBE on TOP: 219.05,66.9 218.98,66.84 217.9,66.84 217.13,67.6 217.13,69.1 217.12,69.09 215.8,69.09 215.76,69.04 214.79,69.04 214.71,69.12 214.71,69.67 214.77,69.73 215.78,69.73 215.8,69.71 220.34,69.71 220.75,69.3 220.75,68.67 220.3,68.22 219.21,68.22 219.15,68.16 219.15,67.7 219.05,67.6
VCC3GBE on IN2: 212.61,87.39 214.31,89.09 223.83,89.09 224.06,88.87 224.06,78.75 219.06,73.75 219.06,67.63 218.73,67.3 211.36,67.3 208.9,69.76 208.9,73.16 212.61,76.87
VCC3LAN on TOP: 222.27,69.99 222.42,69.83 222.42,68.87 222.32,68.77 222.32,67.88 222.27,67.83 221,67.83 221,69.48 220.77,69.71 220.77,69.91 220.85,69.99
VCC3LAN on TOP: 246.69,65.24 248.07,65.24 248.27,65.04 248.27,62.8 248.12,62.65 246.69,62.65 246.68,62.66 246.45,62.66 246.29,62.83 246.29,64.83
VCC3LAN on VCC: 220.74,69.2 223.05,69.2 225.71,66.53 246.9,66.53 248.78,64.66 248.78,62.42 247.56,61.2 224.16,61.2 220.33,65.04 220.33,68.8
VCC3M on TOP: 129.26,76.64 129.16,76.74 127.28,76.74 127.16,76.62 127.16,76.62 126.78,76.24 126.78,76.24 126.6,76.06 126.3,76.06 126.2,75.96 126.2,75.07 126.43,74.84 129.04,74.84 129.26,75.06
VCC3M on TOP: 172.83,90.87 172.58,91.12 172.58,91.73 172.04,92.26 168.74,92.26 168.54,92.06 168.54,91.07 168.44,90.97 167.22,90.97 167.12,91.07 167.12,92.95 167.45,93.28 173.29,93.28 173.87,92.7 173.87,91.05 173.69,90.87
VCC3M on TOP: 110.21,104.5 109.93,104.22 109.17,104.22 108.7,104.69 108.7,105.98 109.03,106.31 109.51,106.31 109.76,106.06 109.76,105.85 110.21,105.41
VCC3M on TOP: 252.26,54.01 252.48,54.24 253.94,54.24 255.7,56 255.7,58.44 255.14,59 252.58,59 252.38,59.2 252.16,59.2 251.95,59.4 251.95,61.02 252.16,61.23 256.07,61.23 257.53,59.76 257.53,53.15 255.35,50.97 252.96,50.97 252.26,51.67
VCC3M on TOP: 267.79,117.04 270.03,117.04 270.23,116.83 270.23,114.67 270,114.44 267.79,114.44 267.54,114.7 267.54,116.78
VCC3M on TOP: 252.69,67.78 251.21,67.78 250.91,67.48 250.91,65.47 251.09,65.29 252.79,65.29 253.02,65.52 253.02,67.46
VCC3M on TOP: 242.25,86.45 243.44,86.45 243.8,86.09 243.8,84.64 243.49,84.34 243.29,84.34 243.13,84.51 242.72,84.51 242.17,85.05 242.17,86.37
VCC3M on TOP: 262.67,74.92 262.67,71.87 262.12,71.32 260.12,71.32 259.85,71.59 259.85,74.89 260,75.04 262.54,75.04
VCC3M on BOTTOM: 32.96,64.72 34.96,64.72 35.07,64.62 35.07,63.73 34.88,63.55 33.03,63.55 32.91,63.67 32.91,64.67
VCC3M on BOTTOM: 162.39,65.39 163.48,65.39 163.59,65.29 163.59,64.83 163.46,64.71 163.46,63.79 163.2,63.54 162.1,63.54 162.05,63.59 162.05,65.05
VCC3M on BOTTOM: 120.38,65.32 121.32,65.32 121.42,65.42 121.42,66.2 120.46,67.17 120.46,72.33 120.05,72.73 118.83,72.73 118.44,72.35 118.44,67.25
VCC3M on BOTTOM: 143.47,76.01 143.46,76.01 143.03,76.01 142.5,76.55 142.5,79.65 140.28,81.86 140.28,85.45 140.48,85.66 142.26,85.66 142.41,85.51 142.41,83.31 145.95,79.77 145.95,78.71 146.21,78.45 146.95,78.45 147.05,78.35 147.05,76.36 146.69,76.01
VCC3M on VCC: outline of 130 points within 16.32,43.19 277.44,138.87 ; 20 cut-outs
VCC3M on VCC: 99.96,61.96 107.72,61.96 108.36,62.6 109.96,62.6 110.49,63.13 110.49,67.65 112.07,69.23 118.52,69.23 119.64,68.11 119.64,65.78 120.1,65.32 120.56,65.32 120.96,65.72 120.96,70.17 120.51,70.62 103.9,70.62 99.69,66.42 99.69,62.23
VCC3M on IN2: 35.59,55.26 35.59,47.64 34.44,46.5 32.92,46.5 31.37,48.05 31.37,52.42 29.21,54.58 23.04,54.58 23.03,54.59 19.83,54.59 18.49,55.92 18.49,56.99 15.04,60.44 10.34,60.44 8.54,62.25 3.61,62.25 1.75,64.1 1.75,65.5 3.28,67.02 17.78,67.02 25.64,59.16 33.06,59.16 33.45,58.77 33.48,58.77 34.22,58.03 34.22,56.63
VCC3M on IN2: 118.91,73.75 121.75,73.75 122.67,74.66 124.93,74.66 126.17,75.91 127.09,75.91 128.03,74.97 130.46,74.97 131.66,76.16 133.94,76.16 137.91,80.12 145.83,80.12 147.13,78.83 147.13,76.14 146.47,75.48 143.57,75.48 142.81,76.24 136.2,76.24 133.61,73.65 126.88,73.65 126.02,72.78 125.41,72.78 124.52,71.89 119.08,71.89 118.75,72.22 118.75,73.6
VCC3M on IN3: 175.47,91.33 175.47,88.79 174.51,87.82 168.54,87.82 167.7,88.66 167.7,90.34 167.13,90.91 167.13,91.76 167.51,92.14 170.49,92.14 170.5,92.13 174.67,92.13
VCC3M on IN3: 97.44,76.8 97.9,76.8 98.69,76.01 98.69,73.88 98.65,73.84 98.65,72.92 98.21,72.48 98.21,71.21 98.36,71.06 98.36,67.8 97.39,66.84 97.39,64.22 97.75,63.87 98.21,63.87 98.41,64.07 98.41,64.96 98.89,65.44 102.75,65.44 103.06,65.14 105.47,65.14 106,64.6 106.11,64.6 107.38,63.33 107.53,63.33 108.26,64.07 109.56,64.07 109.71,63.92 109.71,63.89 109.94,63.89 110.49,63.35 110.47,63.33 110.47,63.03 110.17,62.72 108.49,62.72 108.16,62.39 105.7,62.39 105.29,62.8 103.67,62.8 103.62,62.85 103.11,62.85 102.19,61.94 102.19,61.56 100.59,59.96 100.21,59.96 99.76,59.5 97.67,59.5 95.16,62.01 95.16,71.18 95.64,71.67 95.64,72.99 96.78,74.13 96.78,76.14
VCC3M on IN4: 97.44,73.8 97.31,73.92 97.31,76.62 97.54,76.85 97.81,76.85 97.93,76.72 97.93,76.64 98.11,76.27 98.51,76.35 98.58,76.38 98.66,76.35 98.7,76.3 98.75,76.27 98.78,76.26 98.78,75.19 98.75,75.18 98.7,75.14 98.66,75.1 98.58,75.07 98.51,75.1 97.98,75.07 98.16,74.57 98.16,74.57 98.16,73.85 98.11,73.8
VCC3M_BST on BOTTOM: 158.3,75.17 155.74,75.17 155.66,75.25 155.66,75.75 155.81,75.91 157.08,75.91 157.57,75.42 158.33,75.42 158.4,75.35 158.4,75.27
VCC3M_DH on TOP (solid shape): 147.89,80.33 147.89,79.18 147.79,79.08 146.85,79.08 146.64,79.29 146.64,80.28 146.75,80.38 147.84,80.38
VCC3M_DH on BOTTOM (solid shape): 158.48,75.86 158.48,75.65 158.4,75.58 157.77,75.58 156.75,76.59 156.75,76.97 156.91,77.13 157.21,77.13
VCC3M_DH on BOTTOM (solid shape): 147.89,80.33 147.89,79.11 147.89,78.71 147.86,78.68 147.3,78.68 147.12,78.86 146.81,78.86 146.64,79.03 146.64,80.28 146.75,80.38 147.84,80.38
VCC3M_DH on IN1 (solid shape): 148.95,80.25 148.95,79.69 148.73,79.46 147.91,79.46 147.53,79.08 146.85,79.08 146.64,79.29 146.64,80.25 146.77,80.38 148.83,80.38
VCC3M_DH on IN1 (solid shape): 156.07,77.15 157.16,77.15 157.84,76.47 157.84,76.24 157.54,75.93 156.04,75.93 154.47,77.51 154.47,77.61 154.72,77.86 155.36,77.86
VCC3M_DL on TOP (solid shape): 155.18,82.92 155.18,81.85 155.03,81.7 153.86,81.7 153.7,81.85 153.7,82.97 153.86,83.12 154.97,83.12
VCC3M_DL on BOTTOM (solid shape): 158.94,77.63 158.94,76.09 158.89,76.03 158.73,76.03 158.66,76.11 158.66,76.95 157.81,77.8 157.81,78.05 158.05,78.29 158.28,78.29
VCC3M_DL on IN1 (solid shape): 158.91,77.89 158.91,77.38 158.67,77.14 158.34,77.14 156.83,78.65 156.83,78.85 157.21,79.23 157.57,79.23
VCC3M_DL on IN1 (solid shape): 154.99,82.9 154.99,81.78 155.53,81.24 155.53,80.94 155.2,80.61 154.92,80.61 153.91,81.62 153.91,82.91 154,83 154.89,83
VCC3M_DL on BOTTOM: 153.3,82.46 153.3,83.07 153.45,83.22 154.74,83.22 154.94,83.02 154.94,82.39 154.86,82.31 153.45,82.31
VCC3M_EC on TOP: 240.95,85.84 241.97,85.84 242,85.81 242,84.99 242,84.89 242.91,84.01 242.91,83.65 242.76,83.5 242.53,83.5 242.53,83.15 242.33,82.94 241.23,82.94 240.55,83.63 240.55,85.43
VCC3M_EC on VCC: 227.47,79.82 238.64,79.82 239.46,79.01 239.46,77.15 238.39,76.09 227.72,76.09 226.83,76.97 226.83,79.18
VCC3M_EC on IN2: 242.15,84.31 241.89,84.06 241.89,83.12 239.2,80.43 238.95,80.43 236.71,78.19 233.26,78.19 232.85,78.6 231.73,78.6 231.17,78.04 231.05,78.04 230.67,78.42 230.67,79.46 231.25,80.05 231.25,84.34 233.97,87.06 241.82,87.06 242.15,86.73
VCC3M_LX on TOP (solid shape): 153.96,75.68 153.96,75.12 153.7,74.87 152.69,74.87 152.38,75.17 152.38,75.6 152.66,75.88 153.76,75.88
VCC3M_LX on BOTTOM (solid shape): 154.19,81.57 154.19,79.64 154.34,79.49 155.3,79.49 155.51,79.29 155.51,78.4 155.3,78.19 154.34,78.19 154.19,78.04 154.19,75.27 153.83,74.92 148.68,74.92 148.19,75.4 148.19,80.2 148.37,80.38 150.3,80.38 150.61,80.68 150.61,81.7 151.01,82.1 153.65,82.1
VCC3M_LX on IN1 (solid shape): 156.07,75.07 156.78,75.07 156.93,74.92 156.93,74.43 156.8,74.31 155.28,74.31 154.92,74.66 152.66,74.66 152.38,74.94 152.38,75.63 152.56,75.81 155.33,75.81
VCC3M_LX on BOTTOM: 158.38,75.04 155.61,75.04 155.43,75.22 154.7,75.22 154.54,75.07 154.54,74.59 154.67,74.46 156.75,74.46 157.06,74.76 158.3,74.76 158.43,74.89 158.43,74.99
VCC3MP on BOTTOM: 143.6,71.13 143.6,75.86 144.15,75.86 144.15,75.3 144.92,75.3 144.92,75.86 145.37,75.86 145.37,75.3 146.11,75.3 146.11,75.86 147.15,75.86 147.35,75.65 147.35,74.71 148.1,73.96 154.17,73.96 154.54,73.6 154.54,70.34 154.02,69.82 145.7,69.82 145.59,69.94 143.24,69.94 143.11,70.07 143.11,70.65
VCC3P on BOTTOM: 142.6,87.49 143.09,87.49 143.14,87.54 143.7,87.54 143.7,87.95 143.95,88.2 144.59,88.2 144.78,88.01 144.78,86.89 144.48,86.6 142.85,86.6 142.44,86.19 142.44,86 142.32,85.87 141.73,85.87 141.12,86.48 141.12,87.52 141.28,87.67 142.42,87.67
VCC3SW on TOP (solid shape): 267.85,59.75 267.85,59.35 267.75,59.24 266.53,59.24 266.35,59.07 265.29,59.07 265.21,59.14 265.21,59.6 265.41,59.8 267.8,59.8
VCC3SW on TOP: 250.1,81.77 251.9,81.77 251.98,81.7 251.98,80.89 251.8,80.71 249.92,80.71 249.34,81.29 249.34,81.86 249.4,81.93 249.95,81.93
VCC3SW on BOTTOM: 244.65,72.93 244.64,72.96 244.5,73.14 244.29,73.2 244.26,73.22 244.24,73.26 244.24,73.73 244.68,74.17 245.27,74.17 248.4,71.04 249.69,71.04 249.86,70.87 249.86,70.56 249.56,70.27 249.56,69.15 249.39,69.15 249.07,69.47 247.42,69.47 246.87,70.01 246.87,70.67 246.86,70.69 246.76,70.87 246.58,70.97 246.56,70.97 245.61,71.93 245.61,72.26 244.94,72.93
VCC3SW on IN2: 247.66,85.05 251.14,85.05 252.33,83.86 252.33,79.97 252.23,79.87 249.59,79.87 249.08,79.36 249.08,75.78 247.44,74.14 247.44,71.32 247.15,71.03 246.47,71.03 243.65,68.21 243.65,67.8 243.16,67.32 237.35,67.32 237.07,67.04 225.84,67.04 223.9,65.1 223.01,65.1 222.03,64.12 207.2,64.12 206.99,63.92 205.8,63.92 204.59,65.13 204.59,67.26 205.72,68.39 208.52,68.39 209.91,66.99 219.39,66.99 221.26,68.86 221.26,69.65 222.67,71.06 224.39,71.06 224.62,71.28 224.62,71.59 225.51,72.48 229.8,72.48 230.92,73.6 234.91,73.6 236.81,75.5 238.67,75.5 239.07,75.91 239.07,77.38 238.45,78 238.45,78.82 240.04,80.4 243.65,80.4 244.66,81.42 244.99,81.42 246.82,83.25 246.82,84.21
VCC3WAN on TOP: 246.69,62.14 247.96,62.14 248.05,62.04 248.06,62.04 248.06,60.52 248.52,60.06 248.52,59.42 248.03,58.94 246.97,58.94 246.54,59.37 246.54,61.99
VCC3WAN on TOP: 241,61.09 241.21,61.3 243.39,61.3 243.52,61.43 243.93,61.43 244,61.35 244,59.91 243.8,59.7 240.75,59.7 240.5,59.96 240.5,60.59 240.55,60.65 240.58,60.64 240.89,60.75 241,61.07
VCC3WAN on BOTTOM: 242.45,60.08 242.64,59.9 242.64,58.05 242.88,57.8 243.62,57.8 244.02,58.2 244.02,58.31 244.15,58.44 244.15,60.64 244.03,60.77 242.44,60.77 241.92,60.77 241.74,60.59 241.74,60.34 242,60.08
VCC3WAN on BOTTOM: 226.32,60.21 225.53,60.21 225.22,59.91 225.22,57.75 225.92,57.06 226.83,57.06 226.84,57.06 227.23,57.06 227.58,57.42 227.58,57.95 227.27,58.27 226.6,58.27 226.55,58.31 226.55,59.97
VCC3WAN on VCC: 225.54,56.96 225.54,59.96 226.58,61 248.52,61 249.74,59.78 249.74,56.07 249.59,55.92 226.58,55.92
VCC3WLAN on TOP: 215.66,58.89 215.66,57.92 214.49,56.76 212.81,56.76 211.67,57.9 211.67,58.51 211.72,58.56 212.43,58.56 212.76,58.89
VCC3WLAN on TOP: 249.25,51.23 249.03,51.02 247.71,51.02 247.61,51.12 247.61,53.76 247.71,53.86 249.39,53.86 249.49,53.76 249.49,52.95 249.25,52.7
VCC3WLAN on TOP: 196.22,55.76 198.08,55.76 198.28,55.97 199.09,55.97 199.24,56.12 199.24,56.93 197.9,58.28 196.57,58.28 196.22,57.92
VCC3WLAN on BOTTOM: 213.9,60.01 214.94,60.01 215.12,59.83 215.12,57.62 214.28,56.78 214.05,56.78 214.04,56.79 213.68,56.79 213.36,57.11 213.36,57.64 213.38,57.66 213.38,57.98 213.62,58.22 213.73,58.22 213.85,58.34 213.85,59.96
VCC3WLAN on BOTTOM: 197.13,60.07 197.22,59.97 197.22,59.85 197.22,59.81 197.22,58.56 197.35,58.3 197.73,58.23 197.77,58.15 197.77,56.22 197.62,56.07 196.81,56.07 196.3,56.58 196.3,57.82 196.07,58.05 196.07,59.7 196.43,60.07
VCC3WLAN on VCC: 195.97,57.35 195.97,53.1 197.47,51.6 249.92,51.6 250.28,51.96 250.28,54.95 249.74,55.49 225.94,55.49 223.11,58.32 196.94,58.32
VCC5_TP on BOTTOM: 133.55,56.57 133.28,56.3 132.65,56.3 132.47,56.48 132.47,58.1 132.98,58.61 133.41,58.61 133.55,58.47
VCC5B on TOP (solid shape): 283.35,72.07 284.31,72.07 284.64,71.74 284.64,70.71 284.54,70.6 284.35,70.6 284.25,70.71 281.87,70.71 281.84,70.74 279.88,70.74 279.87,70.75 279.87,72.3 279.92,72.35 281.9,72.35 282.15,72.61 282.81,72.61
VCC5B on TOP: 138.7,56.25 138.08,55.64 138.08,55.43 135.73,53.09 134.85,53.09 134.58,52.82 130.18,52.82 129.24,53.76 129.24,54.06 129.45,54.27 130.08,54.27 130.24,54.42 130.24,54.8 130.92,55.49 135.42,55.49 136.36,56.43 136.99,56.43 137.35,56.78 137.35,56.88 137.25,56.88 137.09,56.73 136,56.73 135.77,56.96 134.96,56.96 134.76,57.16 134.76,57.54 134.87,57.66 134.87,57.89 135.19,58.2 135.37,58.2 135.68,58.52 136.36,58.52 139.12,61.28 139.12,61.94 139.27,62.09 140.93,62.09 141.15,61.87 141.15,58.16 139.24,56.25
VCC5B on TOP: 20.41,35.45 21.57,36.61 21.57,39.06 20.58,40.05 15.7,40.05 15.3,39.65 15.3,37.78 15.12,37.6 14.44,37.6 14.26,37.78 14.26,39.48 14.16,39.59 13.42,39.59 13.24,39.41 13.24,37.25 13.78,36.72 16.38,36.72 16.94,37.28 16.94,37.94 17.3,38.29 18.87,38.29 19.41,37.76 19.41,35.9 19.86,35.45
VCC5B on TOP: 221.44,44.36 218.75,44.36 218.45,44.67 218.45,45.25 218.47,45.27 218.47,46.49 218.78,46.8 220.46,46.8 220.84,46.42 220.84,45.4 221.12,45.12 221.49,45.12 221.54,45.08 221.54,44.46
VCC5B on TOP: 267.67,82.31 270.27,82.31 270.39,82.18 270.39,79.11 270.19,78.9 267.88,78.9 267.65,79.13 267.65,82.28
VCC5B on BOTTOM: 135.85,57.44 135.85,57.11 135.67,56.93 135.52,56.93 135.52,56.7 135.09,56.27 134.05,56.27 133.89,56.43 133.89,57.42 134.3,57.82 135.47,57.82
VCC5B on BOTTOM: 129.45,54.32 131.02,54.32 131.33,54.01 131.33,51.12 131.07,50.86 129.4,50.86 129.14,51.12 129.14,54.01
VCC5B on BOTTOM: 39.33,53.51 39.79,53.96 46.16,53.96 50.35,58.15 50.35,68.92 50.15,69.13 48.98,69.13 48.85,69 48.85,60.39 44.54,56.07 37.31,56.07 37.03,55.8 37.03,53.87 37.39,53.51
VCC5B on VCC: 19.95,35.32 20.48,35.32 39.55,54.39 39.55,54.58 39.45,54.67 34.12,54.67 19.59,40.14 19.59,35.67
VCC5B on IN2: 126.6,50.81 127.29,51.5 133.03,51.5 133.71,50.81 175.92,50.81 176.71,51.6 216.43,51.6 217.22,50.82 219.74,50.82 220.83,51.91 225.23,51.91 226.12,51.02 252.03,51.02 252.84,51.83 252.87,51.83 267.85,66.81 267.85,81.7 268.44,82.28 283.4,82.28 284.67,81.01 284.67,70.78 284.66,70.78 284.53,70.65 284.3,70.65 284.25,70.71 281.99,70.71 281.69,70.4 281.69,70.04 281.61,69.97 279.2,69.97 278.77,69.54 278.77,67.5 277.75,66.49 276.58,66.49 275.94,67.13 274.95,67.13 274.15,66.33 274.15,65.24 261.02,52.11 257.49,52.11 256.93,51.55 256.93,45.48 256.42,44.97 228.89,44.97 228.18,44.26 207.68,44.26 206.94,45 192.03,45 188.27,48.75 98.56,48.75 97.95,48.65 97.35,48.48 97.29,48.42 96.61,48.42 92.9,44.72 92.9,36.64 91.68,35.42 91.68,26.2 91.09,25.62 19.87,25.62 18.09,27.39 18.09,35.22 20.29,37.41 24.33,37.41 29.88,31.86 87.56,31.86 89.19,33.49 89.19,35.93 88.13,36.98 88.13,45.31 93.63,50.81
VCC5B_HDMI on TOP: 11.52,35.72 12.99,35.72 13.24,35.47 13.24,35.17 13.36,35.04 15.14,35.04 15.22,35.13 15.22,36.26 15.41,36.44 17.1,36.44 17.22,36.31 17.22,35.49 16.65,34.92 16.65,34.2 16.52,34.07 16.06,34.07 15.81,33.82 12.81,33.82 12.05,34.58 11.57,34.58 11.34,34.81 11.34,35.55
VCC5B_HDMI on BOTTOM: 11.52,35.09 12.1,35.67 12.63,35.67 12.64,35.68 13.31,35.68 14.2,34.79 14.2,34.51 14.33,34.38 14.33,33.54 14.49,33.39 14.67,33.39 14.84,33.21 14.84,32.12 14.69,31.97 14.4,31.97 14.1,31.67 13.21,31.67 12.78,32.1 12.78,33.24 12.47,33.55 12.47,34.17 12.09,34.56 11.69,34.56 11.52,34.73
VCC5B_HDMI on IN2: 16.46,33.8 12.07,33.8 11.33,34.54 11.33,35.75 12.07,36.49 17.12,36.49 17.17,36.44 17.17,34.51
VCC5B_NFC on BOTTOM: 137.62,62.48 139.73,62.48 139.88,62.32 139.88,60.32 139.35,59.78 139.35,59.43 139.09,59.17 138.36,59.17 137.95,59.58 137.95,60.95 137.49,61.41 137.49,62.35
VCC5BA on TOP: 284.03,68.47 284.03,66.65 283.91,66.52 282.55,66.52 282.41,66.67 282.41,69.46 282.2,69.67 282.2,70.12 282.27,70.2 284.03,70.2 284.57,69.66 284.57,69
VCC5M on TOP (solid shape): 130.86,81.88 130.86,80.46 130.71,80.31 130.05,80.31 129.95,80.41 129.95,81.07 129.64,81.37 129.64,81.37 129.49,81.53 129.49,81.91 129.59,82.01 130.74,82.01
VCC5M on BOTTOM (solid shape): 67.55,110.49 67.55,109.31 67.41,109.18 67.27,109.18 66.74,108.65 65.64,108.65 65.59,108.7 65.59,108.82 67.01,110.24 67.01,110.38 67.16,110.52 67.52,110.52
VCC5M on BOTTOM (solid shape): 62.05,109.99 62.05,109.41 62.57,108.89 62.57,108.7 62.49,108.62 61.96,108.62 61.86,108.72 61.58,108.95 61.58,109.29 61.48,109.39 61.48,109.98 61.59,110.09 61.95,110.09
VCC5M on BOTTOM (solid shape): 89.24,103.59 89.24,103.39 88.96,103.11 88.96,103.01 88.96,101.3 88.96,101.3 88.96,101 88.68,100.72 88.68,100.19 88.6,100.11 88.17,100.11 88.17,103.29 88.5,103.62 89.22,103.62
VCC5M on BOTTOM (solid shape): outline of 130 points within 18.45,21.07 22.08,24.83
VCC5M on TOP: 252.31,70.62 251.65,70.62 251.6,70.67 250.94,70.67 250.89,70.73 250.89,71.16 251.14,71.41 251.14,72.78 251.29,72.94 251.42,72.94 252,72.35 252,71.64 252.31,71.34
VCC5M on TOP: 18.4,25.54 19.62,25.54 20.63,26.56 21.8,26.56 21.98,26.38 21.98,23.63 21.17,22.82 20.28,22.82 19.99,23.11 19.99,24.26 19.67,24.57 18.35,24.57 18.25,24.68 18.25,25.39
VCC5M on TOP: 261.68,81.22 263.59,81.22 263.89,80.91 263.89,78.8 263,77.91 261.35,77.91 261.07,78.19 261.07,79.59 261.38,79.9 261.38,80.91
VCC5M on TOP: 29.85,47.41 30.59,47.41 30.79,47.61 31.63,47.61 31.73,47.51 31.73,46.95 31.81,46.88 31.9,46.88 32.28,46.5 32.64,46.5 32.77,46.37 32.77,45.76 32.69,45.68 30.62,45.68 30.03,46.27 28.24,46.27 27.81,46.7 27.81,47.44 27.87,47.49 29.77,47.49
VCC5M on TOP: 62.82,110.96 63.13,110.82 63.45,110.96 63.81,110.96 64.07,111.21 67.57,111.21 67.95,110.83 67.95,109.66 67.65,109.36 62.09,109.36 61.76,109.03 61.76,107.76 61.6,107.61 60.87,107.61 60.61,107.86 60.61,110.76 60.82,110.96
VCC5M on TOP: 248.1,95.59 248.22,95.47 248.22,95.34 248.6,94.96 249.13,94.96 249.23,94.86 249.23,94.42 249.11,94.3 248.17,94.3 248.14,94.27 248.14,93.92 248.05,93.83 247.37,93.83 247.08,94.12 247.08,94.87 246.8,95.15 246.8,95.44 246.94,95.59
VCC5M on TOP: 274.38,80.1 273.08,80.1 273.07,80.09 272.79,80.09 272.67,79.96 272.67,79.17 272.45,78.96 272.45,78.4 272.48,78.37 273.82,78.37 274.48,79.03 274.48,80
VCC5M on BOTTOM: 174.75,68.13 174.23,68.66 174.23,68.86 174.2,68.88 174.2,69.68 174.91,70.4 178.32,70.4 178.6,70.12 178.6,68.44 178.29,68.13
VCC5M on BOTTOM: 146.72,102.45 146.85,102.45 146.92,102.53 146.92,103.26 147.38,103.72 147.38,104.79 147.68,105.09 147.84,105.09 147.91,105.17 147.91,105.68 147.86,105.73 146.19,105.73 145.96,105.5 145.96,104.3 146.69,103.57 146.69,102.48
VCC5M on BOTTOM: 92.47,103.62 92.95,103.62 93.61,102.96 94.04,102.96 94.14,102.86 94.14,102.55 94.04,102.45 93.38,102.45 92.47,103.36
VCC5M on BOTTOM: 130.03,71.08 129.09,71.08 128.91,71.27 128.91,74.26 129.26,74.61 130.84,74.61 131,74.45 131,74.05 130.57,74.05 130.57,72.66 130.59,72.63 130.82,72.63 130.82,71.87
VCC5M on BOTTOM: 160.49,64.44 160.49,65.52 160.61,65.65 161.68,65.65 161.77,65.56 161.77,62.99 161.51,62.73 160.94,62.73 160.94,64.35 160.85,64.44
VCC5M on BOTTOM: 250.86,63.26 250.86,64.35 249.79,65.42 249.79,70.14 250.2,70.55 250.2,72.36 250.47,72.63 251.82,72.63 251.94,72.51 251.94,67.77 252.49,67.22 253.91,67.22 259.62,72.94 259.62,79.41 263.89,83.68 263.89,85.53 259.62,89.8 251.67,89.8 248.12,93.36 248.12,95.24 249.01,96.13 249.01,97.04 249.56,97.6 250.25,97.6 250.29,97.56 251,97.56 251.57,96.99 251.57,94.98 253.49,93.06 261.26,93.06 261.28,93.04 263.02,93.04 267.93,88.12 267.93,73.85 257.18,63.11 251.01,63.11
VCC5M on IN1: 272.83,81.75 274.23,81.75 274.48,81.5 274.48,79.87 275.24,79.11 276.01,79.11 276.36,78.75 276.36,77.69 275.9,77.23 273.39,77.23 272.6,78.02 272.6,81.52
VCC5M on IN1: 132.1,73.23 132.5,72.83 133.33,72.83 134.05,72.12 134.78,72.12 136.79,70.12 136.79,69.18 136.59,68.97 134.55,68.97 132.19,71.34 129.42,71.34 129.19,71.56 129.19,73.06 129.36,73.23
VCC5M on VCC: outline of 83 points within 30.31,55.42 264.04,107.86
VCC5M on IN3: 275.47,77.53 275.09,77.15 270.98,77.15 270.87,77.25 268.59,77.25 266.81,79.03 264.73,79.03 263.46,77.76 260.64,77.76 260.23,78.17 260.23,80.94 260.25,80.95 260.25,83.43 260.65,83.84 261.67,83.84 262.23,84.4 262.23,84.42 263.09,85.28 271.59,85.28 275.47,81.39
VCC5M on IN3: 35.87,51.86 35.87,44.26 29.27,37.65 21.9,37.65 20.63,36.38 20.63,29.53 22.06,28.1 22.06,22.41 21.88,22.24 16.32,22.24 14.41,24.14 14.41,39.18 19.72,44.49 24.47,44.49 25.54,45.55 25.54,48.28 25.87,48.61 26.39,48.61 26.54,48.45 28.2,48.45 28.68,48.94 28.68,50.51 25.68,53.51 25.68,58.69 26.93,59.94 34.09,59.94 35.87,58.15 35.87,57.07 35.21,56.41 31.7,56.41 30.63,55.34 30.63,54.3 30.99,53.94 33.79,53.94
VCC5M on IN4: 61.55,112.1 86.22,112.1 88.27,110.04 88.27,103.64 88.73,103.19 88.73,102.07 88.66,101.99 87.44,101.99 87.11,102.32 87.11,109.23 85,111.34 76.77,111.34 74.94,109.51 61.45,109.51 61.15,109.82 61.15,111.7
VCC5M_BST on BOTTOM: 163.33,75.91 163.41,75.83 163.41,75.34 163.28,75.21 162.12,75.21 162.07,75.16 160.83,75.16 160.77,75.22 160.77,75.4 160.79,75.42 161.86,75.42 162.34,75.91
VCC5M_DH on BOTTOM (solid shape): 170.8,84.14 170.8,82.54 170.7,82.44 170.29,82.44 170.11,82.61 170.11,84.14 170.21,84.24 170.7,84.24
VCC5M_DH on IN1 (solid shape): 164.27,76.97 164.27,76.42 164.14,76.29 162.54,76.29 162.05,75.79 161.74,75.79 161.44,76.1 161.44,76.38 162.24,77.18 164.07,77.18
VCC5M_DH on IN1 (solid shape): 171,84.06 171,82.16 169.68,80.83 169.33,80.83 169.02,81.14 169.02,81.42 170.11,82.51 170.11,84.14 170.21,84.24 170.82,84.24
VCC5M_DH on BOTTOM: 160.77,75.6 160.77,75.78 162.06,77.08 162.37,77.08 162.51,76.94 162.51,76.58 161.48,75.55 160.82,75.55
VCC5M_DL on BOTTOM (solid shape): 161.71,77.94 161.71,77.66 160.54,76.49 160.54,76.09 160.46,76.01 160.33,76.01 160.28,76.06 160.28,77.15 161.22,78.09 161.55,78.09
VCC5M_DL on BOTTOM (solid shape): 169.48,83.81 169.48,82.82 169.33,82.66 168.87,82.66 168.51,83.02 168.11,83.02 167.95,83.17 167.95,83.81 168.03,83.88 169.4,83.88
VCC5M_DL on IN1 (solid shape): 169.48,83.81 169.48,82.82 169.33,82.66 168.11,82.66 167.78,82.99 167.78,83.55 168.11,83.88 169.4,83.88
VCC5M_DL on IN1 (solid shape): 162.7,78.78 162.7,78.14 162.6,78.04 162.06,78.04 160.97,76.95 160.73,76.95 160.4,77.28 160.4,77.71 161.66,78.97 162.51,78.97
VCC5M_LX on TOP (solid shape): 169.38,80.68 169.38,79.16 169.22,79.01 167.45,79.01 167.17,79.29 167.17,80.76 167.37,80.96 169.1,80.96
VCC5M_LX on BOTTOM (solid shape): 168.94,82.18 170.75,82.18 170.85,82.08 170.85,80.33 171.84,79.34 171.84,75.7 171.71,75.58 165.21,75.58 164.98,75.81 164.98,82.41 165.29,82.71 168.41,82.71
VCC5M_LX on IN1 (solid shape): 164.78,75.2 164.78,74.69 164.59,74.5 162.23,74.5 162.07,74.65 162.07,74.95 162.49,75.37 164.6,75.37
VCC5M_LX on IN1 (solid shape): 169.27,79.69 169.27,79.23 168.11,78.07 167.45,78.07 167.27,78.24 167.27,78.7 167.55,78.98 167.57,78.98 167.57,79.29 168.11,79.82 169.15,79.82
VCC5M_LX on BOTTOM: 162.06,74.46 161.76,74.76 160.84,74.76 160.83,74.78 160.8,74.89 160.88,74.95 162.16,74.95 162.21,75 163.37,75 163.63,75.27 164.25,75.27 164.42,75.09 164.42,74.61 164.27,74.46
VCC5MP on TOP: 173.47,75.22 176.06,75.22 176.29,74.99 176.29,74.48 175.55,73.75 173.67,73.75 173.39,74.03 173.39,75.15
VCC5MP on BOTTOM: 159.93,76.06 160.08,76.06 160.13,76.11 160.13,77.2 161.2,78.27 161.71,78.27 161.83,78.4 161.83,79.11 161.65,79.29 160.36,79.29 160.23,79.16 160.23,78.27 159.85,77.89 159.85,76.92 159.9,76.87 159.9,76.09
VCC5MP on BOTTOM: 165.54,70.09 165.03,70.6 165.03,74.1 165.49,74.56 171.92,74.56 172.5,75.15 178.34,75.15 178.71,74.78 178.71,70.71 178.57,70.57 177.5,70.57 177.5,71.11 176.74,71.11 176.74,70.57 176.31,70.57 176.31,71.13 175.55,71.13 175.55,70.57 174.86,70.57 174.38,70.09
VCCCPUCORE on BOTTOM (solid shape): 87.83,103.03 87.83,99.6 88.28,99.15 88.28,95.45 85.66,92.82 79.56,92.82 79.1,93.28 79.1,96.35 80.31,97.56 80.31,98.54 80.87,99.1 80.87,101.53 80.96,101.62 80.96,102.11 80.87,102.21 80.87,102.91 81.28,103.32 83.85,103.32 84.01,103.16 84.01,101.43 84.18,101.26 84.62,101.26 84.74,101.38 84.74,103.24 84.9,103.39 85.07,103.39 85.08,103.39 87.46,103.39
VCCCPUCORE on TOP: 81.02,97.49 87.06,97.49 87.66,96.89 87.66,94.61 87.37,94.32 87.37,90.19 87.66,89.9 87.66,87.34 88.43,86.57 88.43,85.61 89.02,85.02 89.95,85.02 90.49,84.48 90.49,74.85 89.02,73.38 89.02,72.58 88.68,72.23 85.87,72.23 85.03,73.08 85.03,73.77 84.02,74.78 84.02,75.68 84.38,76.04 84.38,83.51 84.23,83.66 82.1,83.66 80.27,85.48 80.27,91.17 79.16,92.29 79.16,95.67 80.51,97.02 80.55,97.02 ; 1 cut-out
VCCCPUCORE on BOTTOM: 88.94,72.75 89.34,72.75 89.42,72.83 89.42,75.09 89.21,75.29 84.19,75.29 84.08,75.19 84.08,74.05 85.77,72.37 88.55,72.37
VCCCPUCORE on BOTTOM: outline of 88 points within 82.61,82.71 90.26,85.6
VCCCPUCORE on IN1: 83.5,83.76 83.5,74.74 83.83,74.41 88.27,74.41 88.27,84.16 83.91,84.16
VCCCPUCORE on VCC: 85.61,72.28 84.95,72.94 84.36,72.94 84.26,73.04 82.99,73.04 82.23,73.8 82.23,86.7 79,89.93 79,96.76 80.15,97.9 80.15,100.49 81.59,101.94 81.59,102.95 81.98,103.33 86.86,103.33 90.43,99.76 90.43,94.96 91.12,94.27 91.12,72.86 90.53,72.28 ; 1 cut-out
VCCCPUCORE on IN2: 87.73,102.02 87.73,93.8 91.09,90.44 91.09,89.04 90.59,88.53 90.59,76.09 88.96,74.46 88.96,72.38 88.86,72.28 85.61,72.28 84.95,72.94 83.37,72.94 82.66,73.65 82.66,73.72 82.32,74.07 82.32,86.35 80.98,87.68 80.98,89.34 80.15,90.18 80.15,90.92 79,92.06 79,96.02 80.15,97.17 80.15,100.49 80.98,101.33 80.98,102.17 81.26,102.45 87.3,102.45
VCCCPUCORE on IN3: 83.17,85.79 83.17,72.3 83.68,71.79 92.72,71.79 92.92,72 92.92,85.79 87.77,85.79 87.39,86.17 83.55,86.17 ; 2 cut-outs
VCCCPUCORE on IN4: 84.44,82.74 84.44,72.5 85.07,71.87 89.65,71.87 90.59,72.81 90.59,84.01 84.44,84.01 84.44,84.04 84.16,84.31 83.93,84.31 83.63,84.01 83.63,83.55
VCCCPUIO on TOP: 91.63,74.48 91.64,74.47 92.4,74.47 92.59,74.28 92.59,72.94 92.51,72.86 91.16,72.86 91.03,72.73 91.03,72.41 90.89,72.28 89.39,72.28 89.25,72.42 89.25,73.25 90.48,74.48
VCCCPUIO on TOP: 77.2,84.9 78.09,84.9 78.17,84.82 78.17,83.88 77.89,83.6 77.28,83.6 77.07,83.81 77.07,84.77
VCCCPUIO on TOP: 104.5,102.61 104.87,102.97 109.03,102.97 109.19,102.81 109.19,100.66 108.49,99.96 108.49,99.58 108.05,99.14 104.92,99.14 104.5,99.56
VCCCPUIO on IN2: 93.68,75.07 93.68,87.34 94.12,87.77 94.19,87.69 94.9,88.4 94.9,90.84 92.11,93.64 92.11,94.12 93.02,95.03 106.33,95.03 108.06,96.76 108.06,101.05 107.35,101.76 99.07,101.76 98.82,101.51 89.54,101.51 87.84,99.81 87.84,93.59 90.69,90.74 90.69,90.94 90.79,91.05 91.3,90.54 91.3,88.86 90.69,88.25 90.69,76.29 90.79,76.19 90.79,75.98 89.14,74.33 89.14,72.38 89.23,72.29 92.2,72.29 92.2,73.74 92.39,73.93 92.54,73.93
VCCGFXCORE_I on BOTTOM (solid shape): 78.84,108.76 78.84,97.09 78.59,96.84 73.77,96.84 73.77,96.84 71.92,96.84 71.82,96.94 70.7,96.94 70.62,97.01 70.62,99.73 73.11,102.22 73.11,104.76 73.29,104.94 75.45,104.94 75.55,105.04 75.55,105.52 75.42,105.65 73.34,105.65 73.07,105.92 73.07,108.61 73.28,108.83 78.78,108.83
VCCGFXCORE_I on TOP: 80.81,83.45 82.79,83.45 82.94,83.3 82.94,76.49 82.61,76.16 80.78,76.16 80.65,76.29 80.65,83.3
VCCGFXCORE_I on TOP: 70.6,96.99 70.6,102.29 70.89,102.58 78.79,102.58 79,102.37 79,96.99 78.57,96.56 72.2,96.56 71.84,96.91 70.67,96.91
VCCGFXCORE_I on BOTTOM: 82.36,84.72 73.03,84.72 72.73,84.42 72.73,83.96 71.94,83.17 62.58,83.17 62.09,82.68 62.09,79.03 63,78.12 65.82,78.12 67.75,76.19 73.69,76.19 73.69,81.75 75.37,83.43 82.36,83.43 ; 1 cut-out
VCCGFXCORE_I on IN1: 72.02,83.14 73.14,84.26 76.82,84.26 77.02,84.05 77.02,83.88 77.45,83.44 77.78,83.44 78.55,84.21 83.14,84.21 83.14,74.87 82.84,74.56 75.32,74.56 74.05,75.83 72.98,75.83 72.3,76.52 72.3,76.69 71.76,76.69 71.71,76.64 66.53,76.64 65.47,77.71 64.88,77.71 63.51,79.08 63.51,80.78 65.87,83.14
VCCGFXCORE_I on VCC: 79.69,100.82 79.09,101.42 79.1,101.43 79.1,102.63 78.14,103.59 69.53,103.59 65.92,99.99 65.92,84.75 62.09,80.91 62.09,76.47 64.12,74.43 67.57,74.43 70.94,71.07 74.69,71.07 74.83,71.21 81.66,71.21 82.01,71.56 82.01,86.49 79.69,88.81 79.69,88.84 78.7,89.83 78.7,96.99 79.69,97.98
VCCGFXCORE_I on IN2: 79.77,97.32 79.77,100.65 78.9,101.51 78.9,102.25 78.65,102.5 68.08,102.5 67.01,101.43 67.01,101.15 67,101.14 67,99.69 61.96,94.65 61.96,75.22 65.82,71.36 80.93,71.36 82.04,72.47 82.04,84.19 81.43,84.8 81.43,86.97 80.76,87.64 80.76,88.95 80.04,89.67 80.04,89.93 79.77,90.21 79.77,90.58 79.3,91.05 78.95,91.05 78.66,91.34 78.66,93.55 78.24,93.97 78.24,95.8
VCCGFXCORE_I on IN3: 62.37,73.75 61.78,74.33 61.78,78.85 66.38,83.45 72.58,83.45 73.59,84.47 82.76,84.47 83.85,83.37 83.85,75.3 82.31,73.75 ; 1 cut-out
VCCGFXCORE_I on IN4: 67.4,83.14 71.26,83.14 72.27,84.16 76.82,84.16 76.83,84.15 82.85,84.15 84.34,82.66 84.34,74.92 83.83,74.41 74.08,74.41 71.89,76.59 66.79,76.59 66.02,77.36 63.48,77.36 62.95,77.89 62.95,80.15 64.65,81.85 65.5,81.85 65.51,81.86 66.12,81.86
VCCMPHY_GATE on TOP: 109.56,90.21 109.79,89.98 109.79,89.21 110.15,88.85 110.15,83.39 111.21,82.33 111.21,80.86 110.47,80.12 105.99,80.12 105.19,80.92 98.07,80.92 98.05,80.94 98.05,81.67 98.23,81.85 98.51,81.85 98.69,82.03 98.69,82.54 98.82,82.66 105.72,82.66 105.9,82.49 106.74,82.49 106.74,87.59 106.77,87.62 106.77,89.14 107.83,90.21
VCCMPHY_GATE on BOTTOM: 110.68,98.87 111.82,98.87 112.07,98.61 113.47,98.61 113.6,98.49 113.6,97.73 113.59,97.71 113.59,97.64 113.58,97.63 113.58,94.69 111.24,92.34 111.24,89.17 109.85,87.78 108.22,87.78 107.45,88.55 107.45,89.39 106.94,89.9 106.94,97.95 107.48,98.49 110.3,98.49
VCCMPHY_GATE on IN3: 107.36,82.22 106.13,80.99 100.42,80.99 100.24,80.81 100.24,78.98 99.07,77.81 99.02,77.81 98.46,77.25 97.06,77.25 95.84,76.03 95.6,76.03 95.41,76.22 95.41,76.19 94.4,77.2 94.4,81.77 96.44,83.82 96.44,87.22 97.28,88.06 104.95,88.06 107.73,90.84 109.38,90.84 110.14,90.08 110.14,88.63 108.85,87.34 108.04,87.34 107.36,86.66 ; 1 cut-out
VCCPD_VBUS on TOP: 18.81,46.39 20.91,46.39 21.4,46.88 22.92,46.88 22.93,46.88 24.33,46.88 24.69,47.24 24.69,47.44 24.82,47.57 25.17,47.57 25.31,47.7 25.31,47.87 25.38,47.94 25.61,47.94 25.69,47.87 25.69,47.54 25.79,47.43 26.04,47.43 26.1,47.38 26.1,46.65 25.08,45.63 25.08,45.1 24.88,44.89 23.25,44.89 23.1,44.74 23.1,44.31 23,44.21 17.87,44.21 17.54,44.54 17.54,46.19 17.75,46.41 18.79,46.41
VCCPD_VBUS on TOP: 5.36,65.27 5.28,65.35 5.28,67.96 5.44,68.11 6.86,68.11 8.38,69.64 12.17,69.64 12.52,69.28 12.52,68.83 13.34,68.01 13.34,64.46 13.21,64.33 11.46,64.33 11.3,64.49 11.3,65.77 10.97,66.1 9.03,66.1 8.94,66.01 8.94,65.68 8.87,65.6 8.69,65.6 8.56,65.47 8.56,65.27 8.51,65.22 8.31,65.22 8.26,65.27 8.26,65.9 8.07,66.1 7.24,66.1 6.91,65.76 6.91,65.4 6.78,65.27
VCCPD_VBUS on BOTTOM: 10.77,73.42 13.13,73.42 13.64,72.92 13.64,67.25 12.04,65.65 12.04,64.13 11.77,63.86 9.39,63.86 9.15,64.1 8.18,64.1 8.05,64.23 8.05,64.36 8.1,64.41 8.59,64.41 8.79,64.61 8.79,69.23 9.86,70.3 9.86,72.51
VCCPD_VBUS on IN3: 6.99,66.54 6.99,69.08 9.01,71.11 16.7,71.11 22.46,65.35 22.46,65.06 24.96,62.56 24.96,45.62 24.21,44.87 19.23,44.87 18.57,44.21 17.3,44.21 16.49,45.03 16.49,51.61 14.2,53.89 14.2,57.52 10.47,61.26 10.47,64.43 10.1,64.8 8.73,64.8
VCCPD_VBUS_1 on TOP: 17.02,69.49 17.25,69.26 17.25,68.52 17.5,68.27 18.54,68.27 18.72,68.09 18.72,66.59 18.54,66.41 15.47,66.41 15.22,66.67 15.22,67.43 14.71,67.94 14.48,67.94 13.82,68.6 13.82,69.41 13.9,69.49
VCCPD_VBUS_1 on BOTTOM: 14.4,73.02 17.1,73.02 17.68,72.43 17.68,67.28 17.43,67.02 14.89,67.02 14.33,67.58 14.33,72.94
VCCPD_VBUS_CONN on TOP: 10.92,62.22 10.92,60.88 10.77,60.72 9.5,60.72 8.33,61.89 7.55,61.89 7.11,62.32 7.11,64.03 7.49,64.41 7.82,64.41 8.26,64.84 8.26,64.99 8.33,65.07 8.59,65.07 8.69,65.17 8.69,65.4 8.74,65.45 8.87,65.45 8.94,65.37 8.94,64.43 8.84,64.33 8.84,63.52 9.7,62.65 10.49,62.65
VCCPD_VBUS_CONN on IN1: 7.8,57.09 10.19,57.09 10.8,57.7 10.8,59.35 8.54,61.61 8.54,65.6 9.48,66.54 17.65,66.54 18.04,66.16 18.04,53.69 16.61,52.26 10.59,52.26 10.06,52.8 7.62,52.8 7.14,53.28 7.14,56.43
VCCPD_VBUS_CONN on VCC: 8.49,51.86 6.99,53.36 6.99,56.05 8.69,57.75 8.69,61.08 7.95,61.82 6.07,61.82 5.97,61.92 5.97,65.85 6.94,66.82 14.35,66.82 15.67,65.5 15.67,52.75 14.78,51.86
VCCPD_VBUS_CONN on IN2, IN4: 7.65,56.46 9.07,56.46 9.45,56.07 9.45,53.56 8.99,53.1 7.65,53.1 7.44,53.31 7.44,53.71 7.6,53.87 8.38,53.87 8.71,54.2 8.71,55.52 8.51,55.72 7.65,55.72 7.49,55.87 7.49,56.3
VCCRE on TOP: 233.08,47.51 233.28,47.51 233.35,47.44 234.93,47.44 235.03,47.54 235.03,49.34 235,49.37 234.6,49.37 233.8,48.58 232.64,48.58 232.61,48.61 232.61,49.19 232.32,49.49 231.53,49.49 231.5,49.47 231.5,49.34 231.8,49.04 231.8,48.38 232.06,48.13 232.46,48.13
VCCRE on TOP: 240.75,48.25 240.98,48.48 240.98,49.39 240.75,49.62 239.99,49.62 239.89,49.52 239.89,49.19 239.79,49.08 239.2,49.08 239.05,49.24 238.26,49.24 238.21,49.19 238.21,49.14 238.41,48.93 238.46,48.93 238.62,48.78 238.62,48.4 238.77,48.25
VCCRE on TOP: 228.23,51.6 227.06,51.6 226.91,51.75 226.91,52.26 226.73,52.44 226.27,52.44 226.17,52.34 226.17,51.96 226.3,51.83 226.3,51.04 226.5,50.84 226.73,50.84 226.91,50.66 226.91,50.15 226.83,50.08 226.63,50.08 226.53,49.97 226.53,49.67 226.6,49.59 226.91,49.59 227.36,49.14 228.05,49.14 228.2,49.29 228.2,50.28 228.43,50.51 229.04,50.51 229.12,50.43 230.01,50.43 230.06,50.48 230.06,50.58 229.96,50.69 229.6,50.69 229.55,50.74 229.55,51.6 229.27,51.88 229.27,52.36 229.22,52.41 228.33,52.41 228.28,52.36 228.28,51.65
VCCRE on IN3: 229.24,48.11 230.08,48.96 232.44,48.96 233.33,48.07 233.64,48.07 233.77,48.2 233.77,48.68 234.17,49.08 237.17,49.08 237.63,48.63 240.9,48.63 240.9,48.63 241.45,48.63 241.66,48.84 241.66,51.17 240.87,51.96 239.63,51.96 238.38,53.21 230.58,53.21 228.66,51.29 227.92,51.29 227.39,50.76 227.39,45.98 227.71,45.66 229.03,45.66 229.24,45.86
VCCSA on TOP (solid shape): 123.38,82.97 123.38,81.11 123.15,80.89 116.57,80.89 116.44,81.01 116.44,83.2 116.6,83.35 123,83.35
VCCSA on BOTTOM (solid shape): 123.5,85.66 123.5,83.35 123.38,83.22 121.55,83.22 121.37,83.04 121.37,82.66 121.52,82.51 123.53,82.51 123.66,82.38 123.66,79.74 123.45,79.54 115.43,79.54 115.12,79.84 115.12,84.47 115.33,84.67 118.81,84.67 119.06,84.92 119.06,85.66 119.69,86.3 122.87,86.3
VCCSA on TOP: 90.59,78.04 90.81,77.81 91.27,77.81 91.45,77.99 91.45,79.03 91.86,79.03 91.96,79.13 91.96,79.44 91.86,79.54 91.55,79.54 91.45,79.64 91.45,80.25 91.5,80.3 91.86,80.3 91.96,80.4 91.96,80.66 91.86,80.76 91.55,80.76 91.4,80.91 91.4,81.37 91.65,81.62 91.86,81.62 91.91,81.67 91.91,81.93 91.8,82.03 91.65,82.03 91.45,82.23 91.45,82.64 91.6,82.79 91.65,82.79 91.72,82.86 92.14,82.86 92.2,82.92 92.2,83.42 92.14,83.49 90.61,83.49 90.59,83.46
VCCSA on BOTTOM: 92.08,73.36 92.26,73.18 93.99,73.18 94.24,73.44 94.24,75.11 94.07,75.29 92.19,75.29 92.08,75.19
VCCSA on BOTTOM: 94.25,82.87 94.09,82.71 90,82.71 89.92,82.79 89.92,83.87 89.93,83.95 89.92,84.02 89.92,84.43 90.31,84.82 90.56,84.82 91.3,85.56 91.55,85.56 91.73,85.38 93.89,85.38 94.25,85.02
VCCSA on IN1: 88.55,76.52 92.06,76.52 92.97,77.43 92.97,79.82 96.76,83.6 96.76,86.42 96.2,86.98 93.86,86.98 93.43,86.55 93.43,85.86 92.08,84.52 89.87,84.52 88.6,83.25 88.55,83.25
VCCSA on VCC: 91.47,74.23 91.98,73.72 93.53,73.72 93.76,73.95 93.76,74.15 94.32,74.71 94.32,80.1 94.75,80.53 121.14,80.53 122.08,81.47 122.08,88.02 116.95,93.15 92.49,93.15 91.47,92.14
VCCSA on IN4: 90.76,84.06 90.76,74.99 91.75,74 91.78,74 92.03,73.75 93.43,73.75 93.74,74.05 93.74,81.9 93.35,82.29 93.35,82.69 93.41,82.69 93.74,83.02 93.74,84.06
VCCST on TOP: 93.58,93.51 93.46,93.64 93.46,94.6 93.33,94.73 93.33,95.21 93.34,95.22 93.34,95.68 93.58,95.92 94.62,95.92 94.89,95.66 94.89,93.7 94.7,93.51
VCCST_CPU on TOP: 96.55,94.91 96.71,94.75 97.11,94.75 97.24,94.63 97.24,89.67 97.11,89.55 96.63,89.55 95.08,91.1 95.08,95.74 95.26,95.92 96.43,95.92 96.55,95.8
VCCSTG on TOP: 91.61,84.35 91.83,84.57 91.83,88.43 91.63,88.63 90.84,88.63 90.53,88.33 88.86,88.33 88.58,88.05 88.58,86.78 89.04,86.32 89.6,86.32 90,85.91 90,85.18 90.83,84.35
VCCSTG_CPU on TOP: 95.96,84.91 95.03,83.98 93.63,83.98 93.62,83.99 93.46,83.83 92.64,83.83 92.29,84.18 92.29,85.48 92.19,85.59 92.19,88.51 93.71,90.03 95.06,90.03 95.07,90.02 95.81,90.02 96.3,89.52 96.3,85.31 96.73,85.31 97.04,85 97.04,84.64 96.94,84.54 96.33,84.54
VDDPALW_PWRGD on BOTTOM (solid shape): 150.24,98.81 150.43,98.81 150.63,98.61 150.63,98.34 150.47,98.17 150.19,98.17 149.33,99.03 148.74,99.03 148.65,99.12 148.65,99.71 148.79,99.85 149.2,99.85
VINT20_IN on TOP (solid shape): 181.39,71.77 181.39,69.25 181.34,69.2 179.23,69.2 179.03,69.4 179.03,71.77 179.36,72.1 181.06,72.1
VINT20_IN on BOTTOM (solid shape): 183.12,72.68 183.12,69.28 183.04,69.2 179.23,69.2 179.03,69.4 179.03,72.53 179.38,72.88 182.91,72.88
VINT20_IN on TOP: 24.36,74.77 24.39,74.74 29.29,74.74 30.66,76.12 32.79,76.12 33.2,75.71 33.2,71.47 32.74,71.01 23.22,71.01 22.81,71.42 22.81,73.12 22,73.93 22,74.59 22.18,74.77
VINT20_IN on TOP: 150.5,111.4 151.01,110.88 154.24,110.88 154.7,110.43 154.7,108.19 153.3,106.79 149.28,106.79 148.72,107.36 148.72,111.17 148.95,111.4
VINT20_IN on IN2: 49.06,50.96 40.81,59.21 34.41,59.21 33.3,60.32 25.43,60.32 19.57,66.18 19.57,75.04 20.3,75.78 29.16,75.78 29.42,76.04 32.77,76.04 33.03,75.78 59.19,75.78 63.99,70.98 67.01,70.98 69.3,68.69 84.69,68.69 85.68,69.68 103.11,69.68 105.32,71.89 107.22,71.89 108.75,73.42 134.02,73.42 136.69,76.09 136.71,76.06 141.26,76.06 142.63,74.69 168.13,74.69 177.05,83.6 177.05,86.78 172.83,90.99 154.9,90.99 151.08,94.82 151.08,102.08 151.09,102.09 151.09,109.87 151.8,110.58 155.18,110.58 156.32,109.44 156.32,109.41 163.28,102.45 186.32,102.45 192.23,96.54 192.23,94.63 195.05,91.81 195.05,86.43 191.45,82.83 191.45,68.8 189.67,67.02 183.17,67.02 181.26,65.11 175.62,65.11 169.63,59.12 169.63,58 168.73,57.1 137.39,57.1 137.21,56.92 126.68,56.92 126.68,56.93 126.4,57.21 119.44,57.21 117.24,55.01 106.86,55.01 106.03,55.84 103.74,55.84 102.32,54.42 93.89,54.42 93.25,55.05 91.09,55.05 87,50.96 ; 1 cut-out
(no net) on TOP: 161.24,89.23 160.69,89.23 160.47,89.45 160.2,89.45 160.15,89.4 160.15,89.4 160.15,89.1 160.28,88.97 160.28,86.73 160.33,86.68 161.19,86.68 161.37,86.86 161.37,89.1
(no net) on TOP: 162.07,92.16 162.07,91.96 161.29,91.18 161.29,89.02 161.47,88.84 161.47,87.65 161.57,87.55 163.15,87.55 163.55,87.95 163.55,88.56 163.4,88.71 162.79,88.71 162.51,88.99 162.51,91.08 162.92,91.48 162.92,92.17 162.87,92.22 162.13,92.22
(no net) on TOP: 159.25,91.35 159.25,95.25 157.61,96.89 157.02,96.89 156.9,96.77 156.9,94.86 155.37,93.33 155.37,90.83 155.88,90.31 157.33,90.31 157.51,90.49 157.51,90.85 157.81,91.15 159.05,91.15
(no net) on TOP: 156.72,87.49 157.13,87.09 158.4,87.09 158.67,87.36 158.67,90 158.58,90.09 158.57,90.09 155.91,90.09 155.75,89.93 155.75,88.89 156.16,88.49 156.54,88.49 156.72,88.31
(no net) on TOP: 229.32,100.72 229.19,100.6 227.78,100.6 227.66,100.47 226.25,100.47 226.12,100.6 226.12,102.32 225.55,102.89 224.64,102.89 224.22,103.31 224.22,106.18 224.44,106.41 228.96,106.41 229.32,106.06
1R2A_BST on BOTTOM (solid shape): 124.01,62.83 124.01,62.27 123.86,62.12 123.2,62.12 122.41,61.33 121.68,61.33 121.6,61.4 121.6,62.24 122.25,62.89 123.95,62.89
1R2A_LG on BOTTOM (solid shape): 120.48,53.2 120.48,52.59 120.33,52.44 118.68,52.44 118.56,52.55 118.56,53.26 118.6,53.3 120.38,53.3
1R2A_LG on IN4 (solid shape): 120.46,54.14 120.46,52.77 120.25,52.56 119.16,52.56 118.96,52.77 118.96,53.53 119.82,54.39 120.2,54.39
1R2A_LG on IN4 (solid shape): 126.6,62.01 126.6,60.24 126.38,60.01 125.89,60.01 125.89,61.43 125.69,61.63 125.66,61.66 125.66,62.17 125.82,62.32 126.3,62.32
1R2A_LG on BOTTOM: 125.38,62.72 125.64,62.98 126.65,61.96 126.65,61.16 126.55,61.06 126.35,61.06 126.34,61.07 126.05,61.07 125.89,61.23 125.89,61.52 125.38,62.03
1R2A_LX on BOTTOM (solid shape): 124.9,62.83 124.9,60.79 124.72,60.62 124.72,59.32 124.52,59.12 123.96,59.12 123.76,59.32 123.76,60.72 124.6,61.56 124.6,62.88 124.65,62.93 124.8,62.93
1R2A_LX on BOTTOM (solid shape): 115.2,58.23 116.11,58.23 116.27,58.08 116.27,56.2 116.72,55.74 117.69,55.74 117.99,55.43 117.99,52.64 117.74,52.39 116.87,52.39 116.52,52.03 116.52,50.23 116.42,50.13 115.44,50.13 115.36,50.2 115.36,52.88 113.6,54.65 110.35,54.65 108.65,56.35 108.65,58.76 109.48,59.6 113.83,59.6
1R2A_LX on IN4 (solid shape): 117.31,56.3 117.31,55.59 117.13,55.41 114.77,55.41 114.61,55.56 114.61,56.37 114.77,56.53 117.08,56.53
1R2A_LX on IN4 (solid shape): 124.9,61.3 124.9,60.85 123.89,59.83 123.71,59.83 123.4,60.13 123.4,60.59 124.19,61.38 124.82,61.38
1R2A_SW on BOTTOM (solid shape): 124.47,67.14 124.47,65.57 124.44,65.54 124.44,65.21 124.27,65.21 124.19,65.29 124.19,66.1 123.83,66.46 123.4,66.46 123.2,66.66 123.2,67.22 123.43,67.45 124.16,67.45
1R2A_SW on BOTTOM (solid shape): 107.83,57.55 107.83,55.92 109.94,53.81 113.24,53.81 113.8,53.25 113.8,49.74 113.48,49.43 106.04,49.43 105.98,49.49 105.98,51.9 105.75,52.13 104.56,52.13 104.43,52.26 104.43,53.81 104.47,53.99 104.43,54.17 104.43,54.93 103.64,55.71 103.64,57.26 104.13,57.75 107.63,57.75
1R2A_SW on TOP: 106.41,54.24 90.26,54.24 86.91,57.59 86.91,58.21 87.07,58.37 90.42,58.37 90.74,58.05 91.68,58.05 91.86,58.23 91.86,61.35 92.01,61.51 93.52,61.51 93.76,61.26 93.76,58.48 93.92,58.32 95.6,58.32 95.61,58.34 100.58,58.34 100.59,58.35 103.69,58.35 103.69,58.36 106.41,58.36 106.66,58.1 106.66,54.5
1R2A_SW on VCC: 124.2,67.61 124.67,67.14 124.67,64.17 120.61,60.11 120.61,60.08 120.46,59.93 117.53,59.93 117.1,60.37 114.86,60.37 113.82,59.33 113.82,57.12 111.15,54.44 94.09,54.44 93.38,55.16 93.38,58.62 96.36,61.61 107.8,61.61 108.46,62.27 110.14,62.27 110.95,63.09 110.95,67.5 112.27,68.83 118.37,68.83 119.25,67.94 119.25,65.34 119.81,64.78 120.51,64.78 123.34,67.61
1R2A_UG on BOTTOM (solid shape): 116.42,60.07 116.42,58.64 116.29,58.51 115.53,58.51 114.87,59.17 114.87,59.42 114.86,59.43 114.86,60.15 115.06,60.34 116.15,60.34
1R2A_UG on BOTTOM (solid shape): 124.47,62.88 124.47,61.84 123.48,60.85 123.22,60.85 122.87,61.2 122.87,61.48 123.33,61.94 123.99,61.94 124.19,62.14 124.19,62.88 124.29,62.98 124.37,62.98
1R2A_UG on IN4 (solid shape): 116.3,59.6 116.3,58.88 116.16,58.74 115.3,58.74 114.87,59.17 114.87,59.53 115.03,59.69 116.21,59.69
1R2A_UG on IN4 (solid shape): 123.94,61.91 123.94,61.68 122.97,60.72 122.59,60.72 122.23,61.07 122.23,61.28 123.22,62.27 123.58,62.27
+VTT_REFP on BOTTOM (solid shape): 127.03,66.61 125.57,65.15 125.47,65.15 125.41,65.21 125.41,65.9 126.45,66.94 126.45,67.25 127.03,67.25
-REAR_EJECT_LEVER on BOTTOM: 264.52,102.93 266.79,102.93 267.12,102.6 267.12,100.98 265.59,99.45 265.59,96.35 265.08,95.85 263.56,95.85 262.91,96.49 262.91,98.5 261.62,99.79 259.82,99.79 259.31,100.3 259.31,102.07 259.86,102.63 264.22,102.63
ACDC_ID_DOCK on BOTTOM: 106.38,110.41 113.46,110.41 113.77,110.71 114,110.71 114.12,110.58 114.12,110.48 113.49,109.85 113.49,109.59 113.44,109.54 106.4,109.54 106.38,109.57
BAT-PWR on TOP (solid shape): 230.44,98.61 230.44,96.05 230.69,95.8 230.69,93.89 230.44,93.64 227.57,93.64 227.52,93.69 227.52,98.61 227.64,98.74 230.31,98.74
BAT-PWR on TOP (solid shape): 214.18,92.74 214.18,91.05 213.98,90.84 213.09,90.84 212.43,90.18 209.53,90.18 209.13,90.59 209.13,93.97 209.38,94.22 212.7,94.22
BAT-PWR on BOTTOM: 190.56,67.53 190.79,67.75 191.37,67.75 192.77,69.15 194.5,69.15 194.51,69.14 195.27,69.14 195.64,68.77 195.64,65.95 194.09,64.4 191.04,64.4 190.56,64.88
BAT-PWR on IN2: 230.54,90.41 229.6,89.47 214.19,89.47 212.12,87.41 212.12,77.61 208.3,73.78 208.3,71.35 202.88,65.93 193.79,65.93 192.47,67.25 192.47,82.61 199.2,89.34 199.2,92.7 207.63,101.13 227.42,101.13 230.54,98.01 ; 2 cut-outs
CH_AGND on IN1: 202.63,78.35 204.66,76.31 204.66,71.94 204.38,71.67 199.86,71.67 199.12,70.93 199.12,68.77 198.82,68.47 198.1,68.47 196.52,70.04 196.52,70.55 198.8,72.83 201.33,72.83 202.17,73.67 202.17,78.19 202.32,78.35
CH_AGND on IN3: 197.19,72.74 197.19,73.21 195.77,74.64 195.21,74.64 193.02,76.82 193.02,77.23 193.25,77.46 193.74,77.46 194.85,76.34 196.15,76.34 198.21,78.4 202.52,78.4 203.06,77.86 203.06,75.17 200.14,72.25 197.68,72.25
CV20 on TOP (solid shape): 139.93,113.3 139.93,112.59 140.18,112.34 141.92,112.34 141.97,112.29 141.97,109.64 141.89,109.56 138.97,109.56 138.72,109.82 138.48,109.82 138.47,109.82 138.34,109.84 138.21,109.82 138.2,109.82 136.81,109.82 136.66,109.97 136.66,112.99 137.05,113.38 139.85,113.38
DAV12 on BOTTOM: 282.6,89.08 283.22,89.7 283.22,90.06 283.64,90.47 283.65,90.47 284.25,91.07 285,91.07 285.23,90.84 285.23,89.85 283.78,88.4 281.08,88.4 279.92,89.57 279.92,90.18 279.99,90.26 280.78,90.26 280.91,90.13 280.91,89.42 281.24,89.08
DCIN_ID_ON on TOP (solid shape): 107.96,108.77 107.96,107.86 107.84,107.74 106.08,107.74 105.98,107.84 105.98,108.71 106.13,108.86 106.61,108.86 106.66,108.9 107.83,108.9
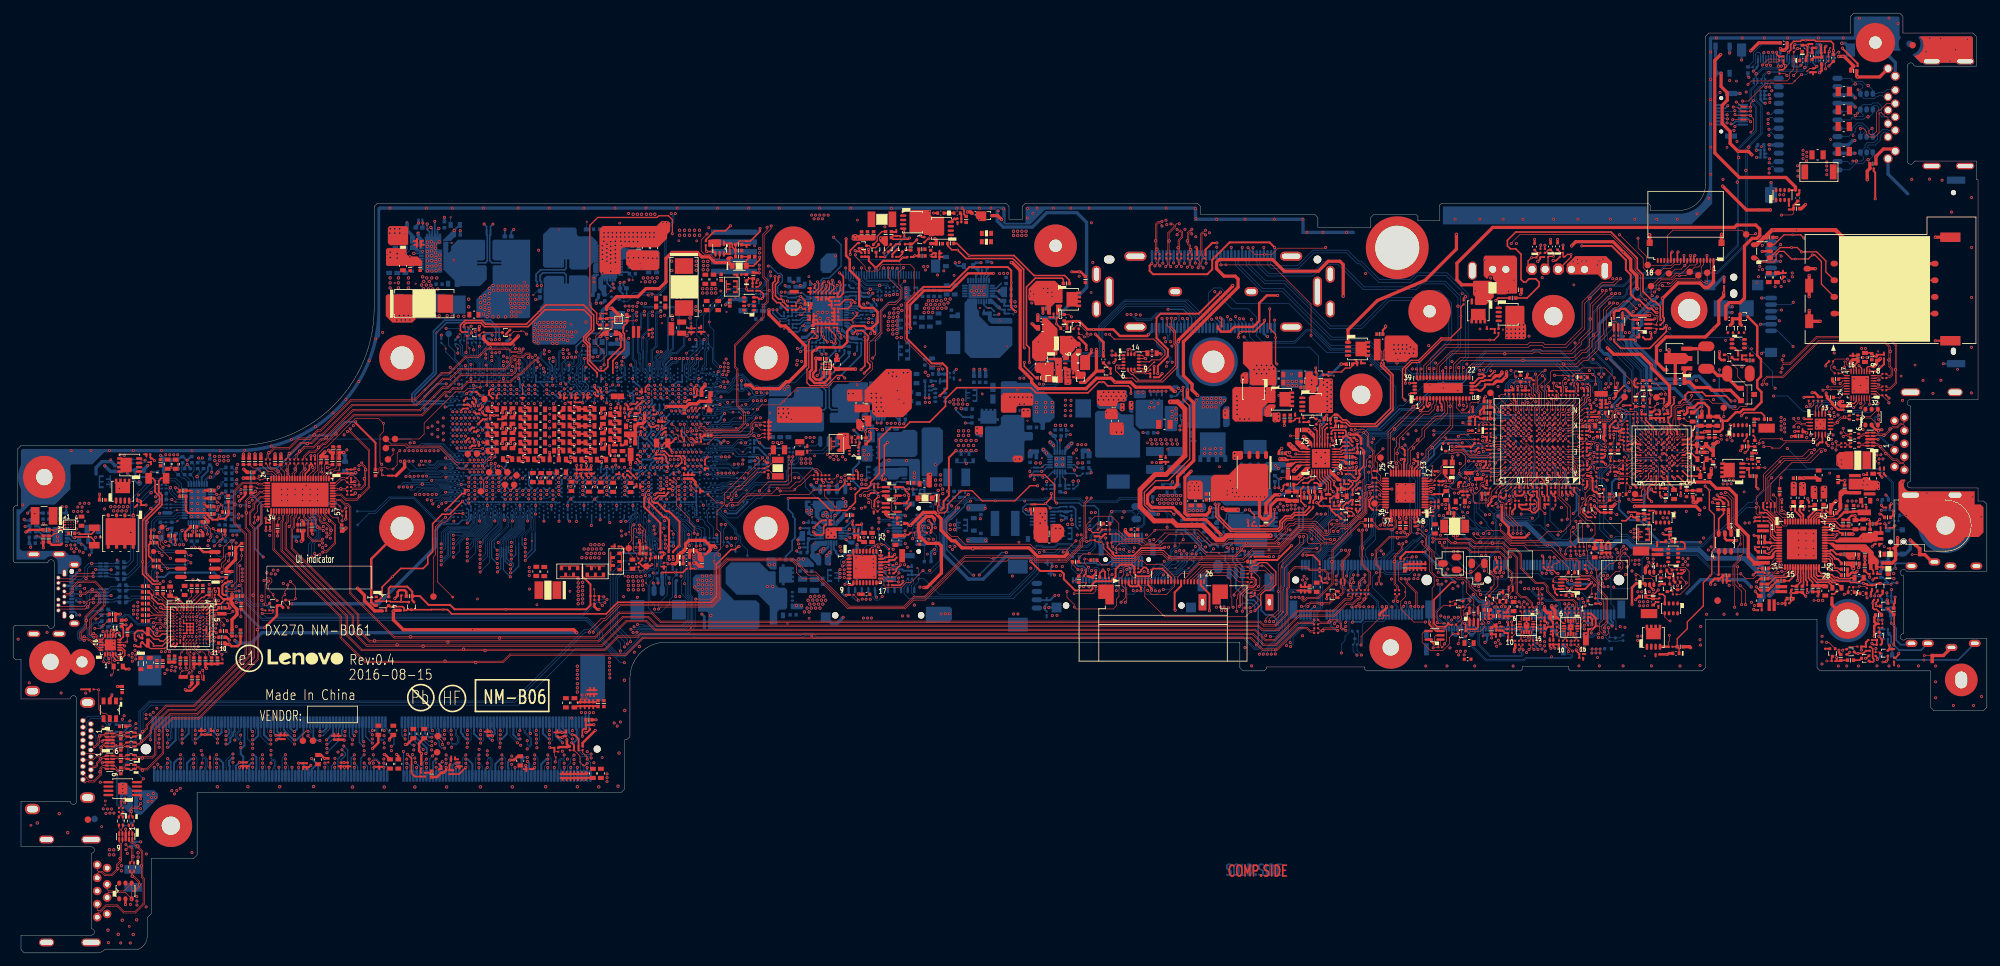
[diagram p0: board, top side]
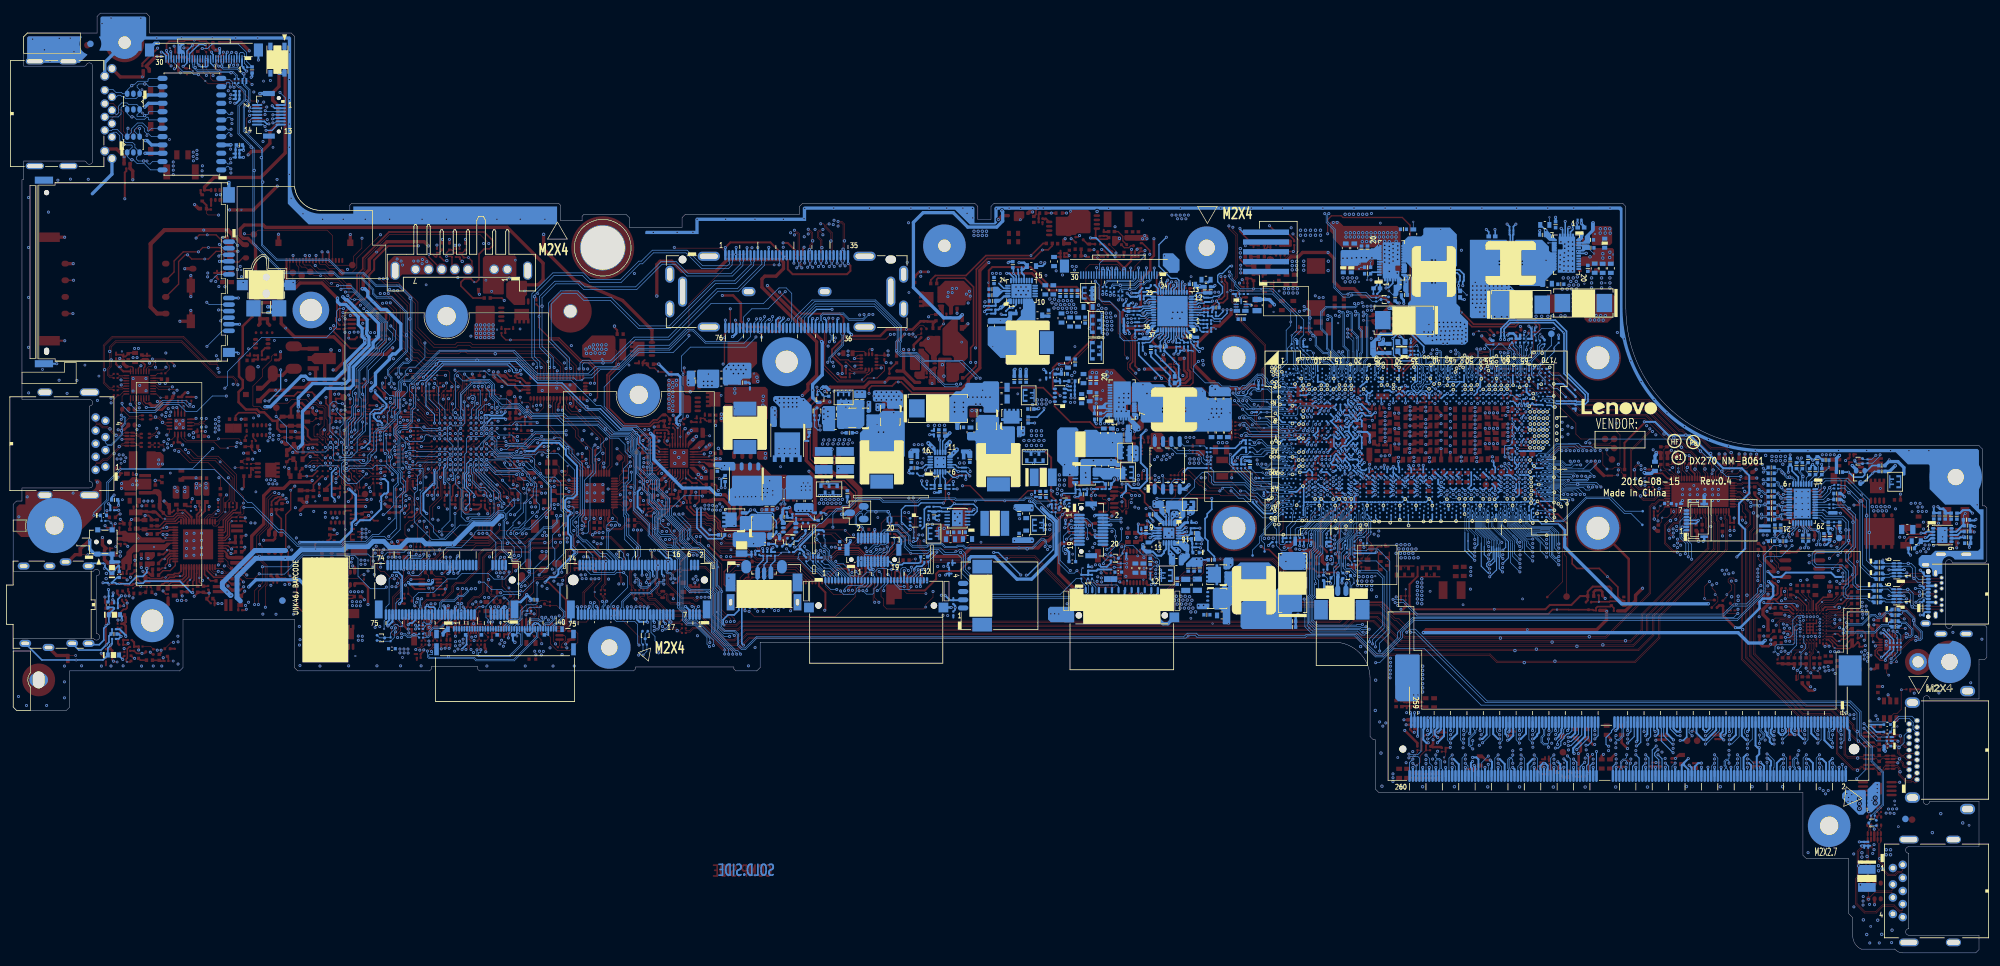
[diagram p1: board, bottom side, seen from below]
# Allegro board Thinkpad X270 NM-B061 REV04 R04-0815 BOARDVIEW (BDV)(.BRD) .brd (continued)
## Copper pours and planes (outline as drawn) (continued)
DCIN_PWR on TOP (solid shape): 159.72,101.72 159.95,101.72 160.02,101.64 160.02,99.31 159.92,99.2 158.9,99.2 158.24,98.54 158.24,97.45 158.19,97.4 157.74,97.4 157.63,97.5 157.63,98.62 157.43,98.82 155.86,98.82 155.7,98.98 155.7,99.08 155.58,99.46 155.19,99.53 154.95,99.53 154.81,99.66 154.81,101.36 156.01,102.56 158.88,102.56
DCIN_PWR on TOP: 121.33,111.48 114.74,111.48 114.21,110.95 109.77,110.95 109.76,110.99 109.38,111.34 109,110.99 109,110.95 106.33,110.95 106.08,111.04 105.83,110.95 105.69,110.95 105.42,110.68 105.42,109.54 104.78,108.9 104.77,108.9 104.4,108.53 101.14,108.53 101,108.67 101,112.18 102.19,113.37 131.45,113.37 131.84,112.99 131.84,110.02 131.61,109.79 128.99,109.79 128.86,109.92 127.87,109.92 127.75,109.79 123.02,109.79
DCIN_PWR on BOTTOM: 117.33,111.47 121.22,111.47 123.19,109.49 140.72,109.49 141.63,108.58 143.77,108.58 146.28,106.06 149.28,106.06 150.85,104.49 151.92,104.49 153.67,102.73 153.67,99.74 154.71,98.7 159.41,98.7 159.89,99.18 159.89,101.41 148.14,113.17 101.56,113.17 101.33,112.95 101.33,107.56 101.99,106.9 106.3,106.9 106.64,106.55 113.92,106.55 114.59,107.23 114.59,108.72
DCIN_PWR20_F on TOP: 132.34,109.77 132.18,109.93 132.18,113.11 132.42,113.35 135.95,113.35 136.38,112.92 136.38,111.21 136.13,110.96 135.19,110.96 134.86,110.63 134.86,109.79 134.83,109.77
DDR4_VREF_CA on TOP: 64.42,27.52 64.33,27.6 64.22,27.62 63.59,27.62 63.43,27.78 63.43,28.31 63.62,28.51 63.62,30.32 64.12,30.82 66.38,30.82 66.4,30.8 66.58,30.8 66.95,30.43 66.95,28.69 65.13,28.69 64.96,28.51 64.96,27.95 64.53,27.52
DDR_VREF on TOP: 127.82,67.14 128.25,67.14 128.38,67.02 128.38,65.98 128.18,65.77 128.18,65.21 128.11,65.15 127.8,65.15 127.72,67.04
DH2_CHG on TOP (solid shape): 198.05,77.98 198.05,77.28 197.99,77.22 196.53,78.68 196.53,78.93 196.66,79.06 196.97,79.06
DH2_CHG on TOP (solid shape): 193.25,82.33 193.25,81.19 193.05,80.99 192.16,80.99 192.01,81.14 192.01,82.41 192.06,82.46 193.13,82.46
DH2_CHG on IN1 (solid shape): 197.6,78.5 197.6,78.19 197.39,77.99 196.86,77.99 195.69,79.16 195.69,79.44 196,79.74 196.35,79.74
DH2_CHG on IN1 (solid shape): 194.62,81.47 194.62,81.22 194.29,80.89 193.96,80.89 193.56,81.29 192.77,81.29 192.67,81.39 192.67,82.41 192.77,82.51 193.58,82.51
DL1_CHG on TOP (solid shape): 185.4,82.84 185.4,81.65 185.23,81.47 184.59,81.47 184.41,81.65 184.41,82.82 184.64,83.04 185.2,83.04
DL1_CHG on TOP (solid shape): 194.32,75.37 195.07,75.37 195.13,75.31 195.13,75.25 195.07,75.18 194.62,75.18 194.47,75.02 193.04,75.02 192.91,75.15 192.91,75.44 193.11,75.64 194.05,75.64
DL1_CHG on BOTTOM (solid shape): 185.51,83.22 185.51,80.53 185.23,80.25 184.64,80.25 184.51,80.38 184.51,83.2 184.74,83.43 185.3,83.43
DL1_CHG on IN1 (solid shape): 185.4,82.84 185.4,81.7 186.06,81.04 186.06,80.44 185.85,80.23 185.43,80.23 184.41,81.25 184.41,82.82 184.64,83.04 185.2,83.04
DL1_CHG on IN1 (solid shape): 192.51,76.12 193.83,76.12 193.99,75.96 193.99,75.35 193.83,75.19 191.76,75.19 190.81,76.14 190.81,76.6 191.06,76.85 191.77,76.85
DL2_CHG on TOP (solid shape): 188.32,88.48 188.32,86.96 188.22,86.85 187.33,86.85 187.16,87.03 187.16,88.2 187.56,88.61 188.2,88.61
DL2_CHG on TOP (solid shape): 196.16,76.57 197.62,76.57 197.67,76.52 197.67,76.44 197.62,76.39 195.97,76.39 195.78,76.58 195.07,76.58 194.22,77.43 194.22,77.79 194.37,77.94 194.79,77.94
DL2_CHG on IN1 (solid shape): 195.59,77.33 195.59,77.05 195.44,76.9 194.75,76.9 193.79,77.86 193.79,78.32 194.01,78.55 194.37,78.55
DL2_CHG on IN1 (solid shape): 188.55,87.79 188.55,86.17 188.38,85.99 187.84,85.99 187.16,86.68 187.16,87.85 187.46,88.15 188.2,88.15
DOCK_PWR20_IN on TOP: 162.66,96.61 162.41,96.61 160.53,98.49 160.53,101.24 160.83,101.54 161.55,101.54 162.61,102.6 164.19,102.6 164.68,102.12 165.69,102.12 166.28,102.7 166.28,102.91 166.56,103.19 168.72,103.19 168.87,103.03 168.87,96.51 168.13,95.77 163.5,95.77
HP_L_JACK on TOP (solid shape): 280.87,59.68 280.87,58.53 280.74,58.41 280.37,58.41 280.18,58.6 280.18,58.85 279.99,59.04 279.49,59.04 279.36,59.17 279.36,59.68 279.42,59.74 280.81,59.74
HP_R_JACK on TOP (solid shape): 280.88,61.07 280.88,60.12 280.76,59.99 279.8,59.99 279.36,60.44 279.36,61.1 279.41,61.15 280.81,61.15
LX1_CHG on TOP (solid shape): 197.77,74.1 197.77,74.02 196.88,73.12 196.88,72.93 196.05,72.1 195.02,72.1 195,72.13 195,72.81 195.02,72.84 195.71,72.84 196.97,74.1 196.99,74.1 197.06,74.18 197.7,74.18
LX1_CHG on IN1 (solid shape): 184.66,76.93 184.66,75.02 184.53,74.9 183.85,74.9 183.78,74.96 183.78,76.9 184.1,77.21 184.38,77.21
LX1_CHG on IN1 (solid shape): 196.78,73.14 196.78,72.83 195.61,71.67 194.88,71.67 194.75,71.79 194.75,72.4 194.88,72.53 195.41,72.53 196.22,73.34 196.58,73.34
LX1_CHG on TOP: 188.09,75.25 187.96,75.38 187.96,76.7 187.66,77 185.9,77 185.57,76.67 185.57,74.16 184.92,73.51 181.46,73.51 181.31,73.65 181.31,79.93 181.56,80.18 183.72,80.18 184.06,80.52 192.04,80.52 192.41,80.15 192.41,75.53 192.13,75.25
LX1_CHG on BOTTOM: 180.98,79.49 186.01,79.49 186.45,79.92 192.59,79.92 193.07,79.44 193.07,77.65 192.83,77.4 192.83,75.99 192.44,75.6 190.66,75.6 190.28,75.22 190.28,73.82 190.13,73.67 180.43,73.67 180.06,74.04 180.06,78.41 180.53,78.88 180.53,79.03 ; 1 cut-out
LX2_CHG on TOP (solid shape): 198.51,79.21 198.51,77.25 198.48,77.23 198.38,77.23 198.33,77.28 198.33,78.46 197.35,79.44 196.5,79.44 196.48,79.46 196.48,80.12 196.53,80.17 197.55,80.17
LX2_CHG on TOP (solid shape): 192.49,86.25 192.49,84.14 192.29,83.93 191.37,83.93 191.35,83.91 191.34,83.91 190.56,83.13 190.56,83.12 190.52,83.08 190.52,81.18 190.41,81.06 186.32,81.06 185.89,81.5 185.89,85.99 186.27,86.37 192.36,86.37
LX2_CHG on IN1 (solid shape): 192.72,85.66 192.72,85.28 192.44,85 192.13,85 191.96,85.18 190.89,85.18 190.86,85.15 190.79,85.15 190.61,85.33 190.61,86.19 190.76,86.35 192.03,86.35
LX2_CHG on IN1 (solid shape): 197.84,80.54 197.84,80.06 198.43,79.46 198.43,78.88 198.31,78.75 198.08,78.75 196.81,80.02 196.81,80.3 196.66,80.45 196.66,80.78 196.91,81.04 197.34,81.04
LX2_CHG on BOTTOM: 192.47,86.45 186.34,86.45 185.86,85.97 185.86,81.16 186.31,80.71 192.25,80.71 192.51,80.97 192.51,82.59 192.66,82.74 197.03,82.74 197.31,83.02 197.31,85.26 196.9,85.67 193.25,85.67
M-BAT-PWR on BOTTOM (solid shape): 191.25,63.97 191.25,62.19 190.97,61.91 187,61.91 186.77,62.08 186.49,62.04 186.46,62.03 186.16,62.32 186.16,63.01 186.19,63.04 186.19,64.05 186.34,64.2 190.13,64.2 190.18,64.25 190.97,64.25
M-BAT-TRCL on BOTTOM: 186.04,62.7 186.04,62.14 186.01,62.12 185.07,62.12 184.69,61.73 182.23,61.73 181.49,62.47 181.31,62.47 179.66,64.12 179.66,64.6 179.82,64.76 180.43,64.76 181.01,64.17 181.01,63.74 181.82,62.93 183.52,62.93 183.75,62.7
M-BAT-TRCL_A on BOTTOM: 179.46,65.26 179.74,64.99 180.4,64.99 181.16,64.22 181.16,63.82 181.9,63.08 182.99,63.08 183.93,64.02 183.93,65.01 183.83,65.11 181.34,65.11 181.01,65.44 181.01,66.23 180.88,66.36 179.84,66.36 179.46,65.98
M_BAT_IN on BOTTOM: 188.68,55.07 188.21,55.54 188.21,59.8 188.2,59.81 188.2,61.46 188.38,61.63 191.31,61.63 192.44,62.76 194.01,62.76 194.36,62.4 194.36,61.18 193.17,59.99 193.17,55.98 192.71,55.52 192.71,55.44 192.34,55.07
M_BAT_PWR_A on BOTTOM (solid shape): 188.78,66.66 190,66.66 190.15,66.51 190.15,64.58 190.03,64.45 185.45,64.45 185.25,64.66 185.25,66.92 185.33,66.99 187.66,66.99 187.7,67.03 188.41,67.03
M_TEMP on BOTTOM (solid shape): 185.76,58.79 185.76,57.16 185.66,57.06 185.18,57.06 185.05,57.19 185.05,58.76 185.35,59.07 185.48,59.07
MIC_RING2 on TOP: 287.23,58.81 287.23,57.29 286.9,56.96 285.1,56.96 284.59,57.47 284.59,57.95 284.41,58.13 284.01,58.13 283.91,58.23 283.91,58.97 284.03,59.09 285.38,59.09 285.53,58.94 287.11,58.94
MIC_RING2 on IN1: 297.95,58.76 296.88,59.83 288.38,59.83 287.21,58.66 287.21,56.68 286.98,56.45 285.78,56.45 284.82,57.42 284.82,61.68 285.15,62.01 289.59,62.01 290.14,62.56 299.58,62.56 300.36,61.77 300.36,58.84 300.29,58.76
MIC_SLEEVE on TOP: 286.45,62.01 286.45,60.41 286.32,60.29 284.54,60.29 284.29,60.54 284.29,62.09 284.36,62.17 284.36,62.62 284.49,62.75 284.49,63.41 284.69,63.61 285.48,63.61 285.56,63.54 285.56,62.55 286.09,62.01
MIC_SLEEVE on IN4: 294.37,58.76 294.12,59.02 294.12,59.85 293.58,60.39 292.11,60.39 291.45,59.73 288.58,59.73 288.25,59.4 286.47,59.4 286.45,59.42 284.72,59.42 284.13,60.01 284.13,61.63 284.51,62.01 289.62,62.01 290.18,62.57 295.82,62.57 297.04,61.35 297.04,58.94 296.86,58.76
PWM_1B on BOTTOM (solid shape): 128.25,94.91 128.25,94.45 128.15,94.35 127.9,94.35 127.68,94.56 127.68,94.73 126.79,95.62 126.79,95.83 126.81,95.85 127.31,95.85
RING2 on TOP (solid shape): 277.81,62.37 282.51,62.37 283.7,61.18 283.7,60.74 284.46,59.98 284.46,59.4 284.39,59.32 282.94,59.32 282.84,59.42 282.84,60.87 282.57,61.14 281.84,61.14 281.52,61.45 277.89,61.45 276.92,62.42 276.03,62.42 275.95,62.5 275.95,62.57 276.01,62.62 277.56,62.62
RTCVCC on TOP: 95.41,73.16 95.73,73.49 96.45,73.49 96.61,73.34 96.61,67.88 96.62,67.87 96.62,67.14 97.58,66.19 97.58,63.86 98.31,63.13 98.31,60.11 98.94,59.47 98.94,59.07 98.99,59.02 101.18,59.02 101.76,59.6 101.76,60.48 101.97,60.68 102.55,60.68 102.68,60.56 102.68,59.09 102.55,58.97 102.45,58.97 102.4,58.91 102.4,58.81 101.91,58.33 98.2,58.33 97.57,58.96 97.57,59.24 96.86,59.96 96.86,61.02 97.29,61.45 97.29,61.81 96.86,62.24 96.86,62.85 96.4,63.31 96.4,64.72 95.4,65.72 95.4,65.77 95.14,66.04 95.14,70.83 95.4,71.08 95.41,71.18 95.4,71.29 95.4,71.72 95.41,71.82 95.4,71.92 95.4,72.35 95.41,72.45 95.4,72.56 95.4,72.99 95.41,73.07 95.41,73.14
RTCVCC on IN4: 96.48,73.65 95.46,73.65 94.75,72.94 94.75,66.36 95.79,65.32 99.48,65.32 99.7,65.54 99.7,66.1 96.61,69.2 96.61,73.52
S-BAT-PWR on TOP (solid shape): 225.76,102.15 225.76,100.06 224.57,98.87 222.97,98.87 222.89,98.95 222.89,100.14 222.59,100.44 222.59,102.45 222.72,102.58 225.33,102.58
S-BAT-TRCL on TOP: 262.89,97.91 263.53,97.91 263.86,97.58 263.86,95.5 263.78,95.42 261.67,95.42 261.44,95.65 261.44,96.08 261.8,96.44 261.8,97.07 261.95,97.22 262.59,97.22 262.74,97.38 262.74,97.76
S-BAT-TRCL_A on TOP: 260.99,95.17 264.49,95.17 264.67,94.99 264.67,92.96 264.44,92.73 260.96,92.73 260.71,92.98 260.71,94.89
S_BAT_IN on TOP (solid shape): 229.32,106.06 229.32,100.72 229.19,100.6 227.78,100.6 227.66,100.47 226.25,100.47 226.12,100.6 226.12,102.32 225.62,102.82 225.63,102.85 225.35,103.36 224.89,102.99 224.86,102.92 224.79,102.89 224.64,102.89 224.22,103.31 224.22,106.18 224.44,106.41 228.96,106.41
S_BAT_IN on TOP: 229.32,100.72 229.19,100.6 227.78,100.6 227.66,100.47 226.25,100.47 226.12,100.6 226.12,102.32 225.55,102.89 224.64,102.89 224.22,103.31 224.22,106.18 224.44,106.41 228.96,106.41 229.32,106.06
S_BAT_IN on BOTTOM: 224.82,105.7 228.25,105.7 228.63,105.32 228.63,103.44 228.43,103.24 225.21,103.24 224.72,103.72 224.72,105.6
S_BAT_PWR_A on TOP: 221.75,98.36 221.95,98.56 224.65,98.56 225.15,99.07 226.91,99.07 227.16,98.82 227.16,97.07 227.02,96.93 226.01,96.93 225.64,96.56 225.64,96.1 224.93,95.39 224.93,95.01 224.77,94.86 221.93,94.86 221.75,95.03
S_TEMP on TOP (solid shape): 236.46,104.72 236.46,103.94 235.99,103.47 235.99,103.45 235.24,103.45 234.78,103.92 234.78,104.77 235.23,105.21 235.96,105.21
S_TEMP on BOTTOM: 235.04,105.63 236.2,105.63 236.53,105.3 236.53,103.34 236.25,103.06 234.96,103.06 234.73,103.29 234.73,105.32
SLEEVE on TOP (solid shape): 284.31,64.32 284.31,62.9 284.16,62.75 283.55,62.75 283.4,62.6 277.94,62.6 277.71,62.83 276.03,62.83 275.98,62.88 275.98,63.03 276.03,63.08 278.16,63.08 278.49,63.41 281.31,63.41 282.03,64.12 283.47,64.12 283.78,64.43 284.21,64.43
SP_OUTL+ on TOP (solid shape): 276.62,71.16 276.62,69.44 276.49,69.32 275.66,69.32 275.6,69.38 275.6,71.09 275.79,71.28 276.49,71.28
SP_OUTL+ on BOTTOM: 155.25,56.07 155.25,56.58 155.51,56.83 156.02,56.83 156.52,57.34 156.52,60.03 157.08,60.58 160.03,60.58 161.02,59.6 161.02,58.79 160.92,58.69 158.96,58.69 158.84,58.81 158.84,59.47 158.56,59.75 157.95,59.75 157.87,59.68 157.87,59.02 157.29,58.43 157.29,56.58 156.78,56.07
SP_OUTL+ on IN1: 275.74,72.66 276.4,72.66 276.76,72.3 276.76,70.24 276.53,70.01 275.99,70.01 275.71,70.29 275.71,72.63
SP_OUTL+ on IN1: 158.98,59.59 158.68,59.3 158.68,58.61 158.89,58.41 160.41,58.41 161.48,57.34 162.11,57.34 162.47,57.7 162.47,58.08 160.96,59.59
SP_OUTL+_AUDIO on TOP: 273.7,65.52 273.7,66.63 274.88,67.81 275.07,67.81 275.54,68.28 275.54,68.62 275.66,68.74 276.49,68.74 276.58,68.65 276.58,67.99 276.43,67.84 276.21,67.84 275.98,67.6 275.98,67.42 275.96,67.4 274.79,67.4 273.85,66.46 273.85,65.82 273.86,65.74 273.89,65.67 273.9,65.65 273.9,65.59 273.82,65.52
SP_OUTL- on TOP (solid shape): 275.09,71.09 275.09,69.32 275.03,69.25 274.33,69.25 274.08,69.51 274.08,71.16 274.2,71.28 274.9,71.28
SP_OUTL- on BOTTOM: 155.25,54.8 155.25,55.56 156.78,55.56 157.67,56.45 157.67,58.05 157.82,58.2 159.8,58.2 159.93,58.08 159.93,57.11 158.63,55.82 157.79,55.82 156.78,54.8
SP_OUTL- on IN1: 275.1,72.1 275.1,70.27 274.88,70.04 274.34,70.04 274.06,70.32 274.06,72.07 274.27,72.28 274.93,72.28
SP_OUTL- on IN1: 158.47,57.9 158.77,58.2 160.03,58.2 161.16,57.07 161.16,56.86 160.45,56.15 160.45,56.15 159.39,56.15 158.47,57.07
SP_OUTL-_AUDIO on TOP: 273.49,66.71 273.49,65.54 273.44,65.49 273.26,65.49 273.22,65.54 273.22,67.06 273.45,67.3 273.45,67.45 273.47,67.5 273.57,67.59 273.57,68.24 273.69,68.36 274.01,68.36 274.39,68.74 275.02,68.74 275.09,68.67 275.09,68.11 275.04,68.06 274.84,68.06
SP_OUTR+ on TOP (solid shape): 271.98,71.73 271.98,69.89 271.85,69.76 271.15,69.76 271.03,69.89 271.03,71.73 271.22,71.92 271.79,71.92
SP_OUTR+ on BOTTOM: 155.43,53.35 155.25,53.53 155.25,54.29 155.51,54.55 156.91,54.55 157.69,55.33 160.28,55.33 160.46,55.16 160.46,54.29 159.88,53.71 157.97,53.71 157.77,53.5 157.34,53.5 157.18,53.35
SP_OUTR+ on IN1: 158.71,55.51 160.59,55.51 161.73,54.37 161.73,53.81 161.53,53.61 161.02,53.61 160.84,53.78 159.04,53.78 158.56,54.27 158.56,55.36
SP_OUTR+ on IN1: 271.42,70.38 271.83,70.8 271.83,71.93 271.63,72.14 269.57,72.14 269.22,71.78 269.22,70.65 269.49,70.38
SP_OUTR+_AUDIO on TOP: 270.96,68.63 270.96,69.06 271.15,69.25 271.79,69.25 272.06,68.99 272.06,68.01 271.98,67.94 271.5,67.94 271.47,67.96 271.47,68.33 271.31,68.49 271.1,68.49
SP_OUTR- on TOP (solid shape): 273.38,71.6 273.38,69.95 273.19,69.76 272.49,69.76 272.3,69.95 272.3,71.67 272.49,71.86 273.12,71.86
SP_OUTR- on BOTTOM: 155.61,51.7 155.18,52.13 155.18,52.97 155.28,53.07 156.68,53.07 156.91,52.84 156.91,52.01 156.98,51.93 158.2,51.93 158.43,51.7 159.39,51.7 159.68,51.41 159.68,49.6 159.3,49.22 156.95,49.22 155.61,50.56
SP_OUTR- on IN1: 273.15,71.95 273.42,71.68 273.42,69.61 272.86,69.05 272.21,69.05 271.71,69.56 271.71,69.82 272.24,70.35 272.24,71.67 272.52,71.95
SP_OUTR- on IN1: 158.28,52.31 161.24,52.31 161.54,52.02 161.54,50.95 161.19,50.61 158.37,50.61 158.1,50.89 158.1,52.13
SP_OUTR-_AUDIO on TOP: 272.25,67.99 272.25,69.14 272.36,69.25 273.12,69.25 273.25,69.13 273.25,68.62 273.12,68.49 273,68.49 272.81,68.3 272.81,67.96 272.75,67.91 272.32,67.91
T1_PIN3 on TOP: 266.76,122.14 268,122.14 268.23,122.37 268.23,123.89 267.7,124.42 267.7,129.07 268.06,129.43 268.39,129.43 268.72,129.76 268.72,130.94 268.46,131.2 266.54,131.2 265.79,130.45 265.79,123.11
T1_PIN3 on BOTTOM: 270.36,123.77 270.64,123.49 270.64,122.04 270.1,121.5 267.8,121.5 267.42,121.12 266.89,121.12 266.86,121.09 266.84,121.12 266.84,122.8 266.63,123 266.63,123.67 266.73,123.77
T1_PIN3 on BOTTOM: 267.06,131.71 267.75,131.71 268.08,131.38 270.11,131.38 270.28,131.21 270.28,129.51 270.03,129.25 268.07,129.25 267.36,129.96 267.17,129.96 266.94,130.19 266.94,131.58
T1_PIN3 on IN2: 266.73,122.39 266.07,123.05 266.07,130.66 266.69,131.28 268.36,131.28 268.36,131.28 268.44,131.28 268.59,131.13 268.59,129.63 268.44,129.48 267.9,129.48 267.7,129.27 267.7,124.52 268.03,124.2 268.46,124.2 268.46,124.19 268.61,124.04 268.61,122.49 268.51,122.39 268.51,122.39
T1_PIN15 on TOP: 279.6,132.19 281.19,132.19 281.52,131.86 281.52,130.38 281.28,130.14 279.73,130.14 279.48,130.4 279.48,132.06
T1_PIN16 on TOP: 279.6,129.43 281.51,129.43 281.64,129.3 281.64,128.06 281.38,127.8 279.66,127.8 279.53,127.93 279.53,129.35
T1_PIN21 on TOP: 281.26,124.12 280.77,123.64 279.99,123.64 279.53,124.1 279.53,126.71 279.68,126.86 280.47,126.86 281.26,126.08
T1_PIN22 on TOP: 281.03,120.83 280.72,120.51 279.91,120.51 279.55,120.87 279.55,123.11 279.63,123.18 280.86,123.18 281.03,123
USB_PWR_S1 on TOP: 281.9,76.36 284.77,76.36 286.39,74.74 287.23,74.74 287.51,74.46 287.51,73.93 287.5,73.91 287.5,73.29 287.35,73.14 286.09,73.14 285.63,73.6 284.36,73.6 284.2,73.76 283.46,73.76 283.37,73.67 281.95,73.67 281.82,73.8 281.82,76.29
USB_PWR_S1 on TOP: 276.77,81.32 277.92,81.32 278.51,81.91 278.51,82.24 277.45,83.3 277.12,83.3 276.63,82.82 276.63,81.45
USB_PWR_S1 on BOTTOM: 285.4,75.7 285.4,74.94 285.18,74.71 282.79,74.71 280.6,76.9 280.6,79.34 279.38,80.56 277.99,80.56 277.98,80.56 277.32,80.56 276.43,81.45 276.43,83.1 276.71,83.38 278.18,83.38 279.1,82.46 281.21,82.46 283.34,80.33 283.34,77.77
USB_PWR_S2 on TOP: 13.32,20.92 13.14,21.09 13.14,22.57 13.57,23 13.57,25.41 13.78,25.62 15.33,25.62 15.6,25.34 15.6,21.07 15.44,20.92
USB_PWR_S2 on BOTTOM: 19.62,11.82 14.49,11.82 13.73,12.59 13.73,15.35 14.59,16.22 17.1,16.22 17.1,16.29 17.26,16.45 19.41,16.45 19.67,16.19 19.67,11.87
USB_PWR_S2 on IN1: 14.59,11.87 18.81,11.87 19.62,12.69 19.62,15.91 19.64,15.94 19.64,20.71 19.38,20.98 16.41,20.98 15.05,22.34 13.67,22.34 13.47,22.14 13.47,18.99 14.03,18.43 14.03,14.52 13.67,14.16 13.67,12.79
VBL20 on TOP: 140.24,105.97 140.34,106.07 140.34,107.81 140.29,107.87 138.77,107.87 138.69,107.78 138.69,106.01 137.98,105.3 137.98,103.8 138.19,103.6 140.08,103.6 140.24,103.76
VBL20 on BOTTOM: 136.43,104.86 138.75,107.18 142.14,107.18 142.77,106.54 142.77,105.88 142.67,105.78 141.76,105.78 141.61,105.94 141.61,106.06 141.38,106.29 139.9,106.29 139.65,106.04 139.65,104.18 139.42,103.95 138.86,103.95 138.46,104.36 138,104.36 137.87,104.23 137.87,102.99 137.79,102.91 136.59,102.91 136.43,103.06
VREGIN20 on TOP: 254.52,81.9 255.18,81.9 255.53,82.26 255.53,82.87 255.63,82.97 256.42,82.97 256.98,83.53 257.67,83.53 258,83.2 258,81.47 258.2,81.27 260.18,81.27 260.49,80.96 260.49,80.1 260.21,79.82 259.14,79.82 259.09,79.77 259.09,79.16 259.17,79.08 260.26,79.08 261.07,79.9 261.07,81.77 260.41,82.44 259.34,82.44 258.94,82.84 258.94,83.58 258.15,84.37 256.75,84.37 255.94,83.55 255.15,83.55 254.95,83.35 254.95,82.69 254.77,82.51 254.57,82.51 254.47,82.41 254.47,81.95
VSYS on TOP (solid shape): 60.23,110.71 60.23,108.14 60.08,107.99 57.46,107.99 57.13,108.32 57.13,110.65 57.39,110.91 60.03,110.91
VSYS on TOP (solid shape): 61.36,100.38 61.36,96.67 60.87,96.18 57.83,96.18 56.82,97.19 56.82,100.28 57.01,100.47 61.27,100.47
VSYS on TOP (solid shape): 201.23,87.46 201.23,82.49 201.13,82.38 200.51,82.38 200.31,82.44 200.12,82.38 197.72,82.38 197.57,82.54 197.57,84.85 197.82,85.1 198.43,85.1 198.87,85.53 198.87,86.37 199.15,86.65 199.15,87.41 199.4,87.67 201.02,87.67
VSYS on BOTTOM (solid shape): 136.7,101.61 136.7,99.58 136.64,99.52 136.05,99.52 135.81,99.77 135.81,101.67 135.9,101.76 136.54,101.76
VSYS on TOP: 95.84,103.65 98.3,103.65 98.81,103.14 98.81,102.46 98.3,101.95 95.71,101.95 95.48,102.18 95.48,103.29
VSYS on TOP: 103.96,106.17 104.5,105.63 104.5,104.08 103.79,103.36 100.39,103.36 100.06,103.69 100.06,105.74 100.49,106.17
VSYS on BOTTOM: 126.53,56.35 125.45,56.35 125.45,58.56 125.59,58.7 127.12,58.7 127.24,58.58 127.24,57.06
VSYS on BOTTOM: 145.75,83.64 145.62,83.51 142.95,83.51 142.67,83.79 142.67,86.12 142.97,86.42 145.63,86.42 145.75,86.3
VSYS on BOTTOM: 139.97,84.18 139.97,83.42 139.8,83.25 137.62,83.25 137.54,83.33 137.54,84.37 137.62,84.45 138.61,84.45 138.69,84.37 139.78,84.37
VSYS on BOTTOM: 95.74,103.77 96.12,104.15 98.59,104.15 98.71,104.03 98.71,102.2 98.54,102.02 95.95,102.02 95.74,102.22
VSYS on BOTTOM: 173.03,84.57 172.93,84.67 172.93,85.79 172.4,86.32 165.49,86.32 164.4,85.23 164.4,81.62 164.07,81.29 160.11,81.29 159.55,81.85 159.55,86.17 163.84,90.46 175.12,90.46 177.15,88.43 177.15,87.57 176.06,86.47 176.06,84.75 175.88,84.57 175.02,84.57 175.02,85.13 174.46,85.13 174.46,84.57 174.23,84.57 174.23,85.13 173.64,85.13 173.64,84.57
VSYS on BOTTOM: 56.91,100.7 60.84,100.7 61.38,100.16 61.38,97.78 61.37,97.77 61.37,96.33 61.2,96.15 57.72,96.15 56.75,97.11 56.75,100.55
VSYS on BOTTOM: 57.19,110.31 57.2,110.31 57.2,110.63 57.32,110.76 59.25,110.76 59.32,110.69 59.32,108.85 59.15,108.69 57.35,108.69 57.19,108.84
VSYS on VCC: 150.5,80.54 150.5,80.54 143.3,80.54 141.49,78.73 141.49,74.43 140.45,73.39 140.45,57.92 139.33,56.81 125.64,56.81 125.26,57.19 125.26,60.9 126.04,61.68 128.79,61.68 131.15,64.05 131.15,82.66 131.23,82.74 131.23,83.93 134.82,87.53 138.47,87.53 139.47,86.53 152.07,86.53 152.6,87.06 156.95,87.06 157.58,86.43 179.05,86.43 179.99,85.49 184.3,85.49 187.8,88.99 200.49,88.99 202.32,87.16 202.32,79.16 200.14,76.97 190.2,76.97 184.79,71.57 161.19,71.57 160.63,72.13 160.63,73.5 160.91,73.78 160.91,75.84 160.61,76.14 159.34,76.14 158.5,76.98 154.05,76.98
VSYS on IN2: 150.4,93.87 151.95,92.32 151.98,92.32 153.7,90.59 172.88,90.59 176.44,87.03 176.44,85.51 176.13,85.2 175.29,85.2 169.2,79.11 151.34,79.11 147.05,83.4 139.38,83.4 136.66,86.12 136.66,98.78 135.51,99.94 133.82,99.94 130.26,103.49 126.37,103.49 125.59,102.7 119.95,102.7 118.78,101.54 114.28,101.54 113.52,102.3 98.64,102.3 98.36,102.02 90,102.02 88.62,103.4 68.96,103.4 68.94,103.42 67.85,103.42 66.35,101.92 66.35,99.76 62.77,96.18 56.83,96.18 56.27,96.74 56.27,112.92 56.65,113.3 144.36,113.3 144.48,113.17 148.7,113.17 150.4,111.47 ; 1 cut-out
VSYS_OUT on BOTTOM (solid shape): 196.66,88.86 196.66,86.4 196.45,86.19 193.51,86.19 193.28,86.42 193.28,88.94 193.35,89.01 196.5,89.01
VSYS_OUT on TOP: 193.06,83.03 193.06,93.24 193.86,94.04 197.82,94.04 199.42,95.64 203.97,95.64 204.2,95.41 204.2,91.81 203.97,91.58 203.01,91.58 202.73,91.3 202.73,90.87 201.63,89.78 198.48,89.78 197.7,88.99 197.16,88.99 196.78,88.61 196.78,85.89 197.21,85.46 197.21,83.37 197.01,83.17 196,83.17 195.67,82.84 195.67,81.88 195.59,81.8 193.58,81.8 193.53,81.85 193.53,82.56
N8823807 on TOP: 255.43,69.89 252.76,69.89 252.41,70.24 251.65,70.24 251.57,70.17 251.57,69.15 251.9,68.82 255.23,68.82 255.53,69.13 255.53,69.79
N8910919 on TOP: 254.44,78.12 255.74,78.12 256.35,78.73 256.35,79.72 256.68,80.05 260.26,80.05 260.36,80.15 260.36,80.86 260.26,80.96 256.96,80.96 255.48,79.49 255.48,78.93 255.13,78.57 254.42,78.57 254.34,78.5 254.34,78.22
N8950489 on TOP: 128.38,72.2 128.38,73.19 128.18,73.39 126.12,73.39 125.99,73.27 125.99,72.48 126.5,71.97 128.15,71.97
N8950489 on BOTTOM: 126.63,78.73 128.41,78.73 128.71,78.42 128.71,74.85 127.8,73.94 127.8,72.12 127.52,71.84 126.78,71.84 126.17,72.45 122.34,72.45 121.98,72.81 121.98,74.59 122.26,74.87 125.28,74.87 126.45,76.03 126.45,78.55
N9822465 on BOTTOM: 45.42,67.75 46.67,67.75 47.05,68.13 47.05,68.77 47.18,68.9 48.45,68.9 48.57,68.77 48.57,67.25 48.12,66.79 45.53,66.79 45.35,66.97 45.35,67.68
N19352559 on TOP: 205.65,89.52 205.34,89.83 205.34,90.29 205.32,90.32 205.32,90.33 204.61,91.05 204.61,95.41 204.91,95.72 208.11,95.72 208.35,95.48 208.35,94.03 208.52,93.87 208.52,90.54 207.5,89.52
N19352658 on TOP (solid shape): 191.39,74.29 191.39,69.66 190.7,68.97 182.69,68.97 182.61,69.05 182.61,72.5 183.08,72.96 185.34,72.96 187.02,74.64 191.03,74.64
N19352658 on BOTTOM (solid shape): 191.21,72.81 191.34,72.69 191.34,71.04 191.54,70.83 191.87,70.83 191.93,70.78 191.88,70.59 191.93,70.41 191.93,68.72 191.44,68.22 186.61,68.22 186.55,68.29 184.69,68.29 183.73,69.25 183.73,72.71 183.84,72.82 191.21,72.82
N19352692 on TOP (solid shape): 195.51,74.74 194.86,74.08 194.13,74.08 194.11,74.11 194.11,74.67 194.26,74.82 194.71,74.82 194.75,74.87 195.51,74.87
N19352696 on TOP (solid shape): 197.55,76.96 197.55,76.83 196.34,76.83 195.51,77.66 195.51,78.1 195.58,78.17 196.34,78.17
N19353084 on TOP (solid shape): 201.71,73.01 201.78,72.91 201.89,72.83 202.33,72.39 202.5,72.39 202.5,72.01 202.43,71.94 201.93,71.94 201.76,72.11 201.76,72.11 201.69,72.21 201.59,72.29 201.58,72.29 200.72,73.15 200.72,73.75 200.8,73.82 200.9,73.82
N19358397 on TOP (solid shape): 187.48,76.32 187.48,75.46 187.26,75.23 186.02,75.23 185.9,75.35 185.9,76.42 186.08,76.59 187.2,76.59
N19358397 on BOTTOM (solid shape): 194.16,74.72 194.16,74.29 193.96,74.08 193.44,74.08 192.97,73.62 190.94,73.62 190.84,73.72 190.84,74.69 191.07,74.92 193.96,74.92
N19358397 on IN1 (solid shape): 186.79,76.5 186.79,74.69 186.69,74.59 185.93,74.59 185.75,74.77 185.75,76.55 185.85,76.65 186.64,76.65
N19358397 on IN1 (solid shape): 193.14,74.13 193.14,73.55 192.99,73.4 191.54,73.4 191.37,73.58 191.37,74.24 191.72,74.59 192.69,74.59
N19358401 on TOP (solid shape): 197.67,74.42 197.63,74.38 196.98,74.38 196.95,74.36 196.53,74.36 195.39,73.21 195.13,73.21 194.94,73.41 194.94,73.72 195.77,74.55 197.67,74.55
N19358401 on BOTTOM: 196.02,74.48 196.15,74.36 196.15,73.88 195.06,72.79 193.35,72.79 193.22,72.92 193.22,73.7 193.35,73.83 194.18,73.83 194.84,74.48
N19359682 on TOP (solid shape): 194.74,73.75 194.74,72.25 194.69,72.2 194.11,72.2 194.04,72.27 194.04,73.75 194.08,73.79 194.69,73.79
N19359877 on TOP (solid shape): 196.15,80.07 196.15,78.68 196.08,78.61 195.51,78.61 195.45,78.68 195.45,79.95 195.64,80.14 196.08,80.14
N19361354 on TOP (solid shape): 192.48,83.62 192.48,83.21 191.78,82.51 191.78,81.98 191.59,81.79 190.98,81.79 190.76,82 190.76,83.04 191.42,83.71 192.39,83.71
N19364702 on TOP: 203.18,91.38 203.97,91.38 205.14,90.21 205.14,89.65 205.04,89.55 203.97,89.55 203.9,89.62 203.9,90.28 203.08,91.1 203.08,91.27
N19397717 on BOTTOM: 176.44,84.54 178.16,84.54 178.57,84.95 178.57,85.86 178.37,86.07 177.99,86.07 177.61,85.69 177.17,85.69 177,85.51 176.34,85.51 176.29,85.46 176.29,84.7
N19578386 on BOTTOM: 129.07,55.89 130.36,57.19 130.36,58.33 130.29,58.41 128.1,58.41 127.95,58.25 127.95,56.78 128.18,56.55 128.18,54.65 128.3,54.52 128.94,54.52 129.07,54.65
N19578390 on BOTTOM: 130.03,54.83 130.84,54.83 131.05,55.03 131.05,55.94 131.28,56.17 131.61,56.17 132.39,56.96 132.39,58.33 132.29,58.43 130.77,58.43 130.62,58.28 130.62,57.16 129.9,56.45 129.9,54.95
N20831933 on TOP (solid shape): 232.32,104.86 232.32,103.79 231.99,103.47 231.99,103.45 231.24,103.45 230.69,104 230.69,104.68 231.23,105.21 231.96,105.21
N20831933 on BOTTOM: 230.74,105.75 232.27,105.75 232.5,105.52 232.5,103.34 232.32,103.16 230.74,103.16 230.57,103.34 230.57,105.57
N20831943 on TOP (solid shape): 234.36,104.62 234.36,103.84 233.99,103.47 233.99,103.45 233.24,103.45 232.91,103.78 232.91,104.9 233.23,105.21 233.76,105.21
N20831943 on BOTTOM: 232.95,105.68 234.2,105.68 234.48,105.4 234.48,103.24 234.4,103.16 232.9,103.16 232.77,103.29 232.77,105.5
N23175964 on TOP: 279.16,87.79 279.92,87.79 279.97,87.74 279.97,87.64 279.92,87.59 279.03,87.59 278.67,87.24 278.11,87.24 278.01,87.34 278.01,87.97 278.09,88.05 278.9,88.05
N23216890 on TOP: 265.97,64.73 267.7,64.73 267.8,64.63 267.8,63.51 268.36,62.95 268.36,62.65 268.03,62.32 266.89,62.32 266.73,62.47 266.73,63.84 266.48,64.1 265.87,64.1 265.79,64.17 265.79,64.55
N23216953 on TOP (solid shape): 269.66,61.4 269.66,61.3 269.58,61.23 268.84,61.23 268.59,60.97 268.59,60.44 268.21,60.06 265.85,60.06 265.82,60.08 265.82,60.54 265.9,60.62 267.09,60.62 267.14,60.57 267.95,60.57 268.17,60.78 268.17,60.96 268.67,61.45 269.6,61.45
N23217017 on TOP: 270.66,56.21 271.87,57.42 271.87,58.97 271.84,58.99 271.69,58.99 271.64,58.94 271.64,58.13 270.57,57.06 269.71,57.06 269.58,56.93 269.58,56.4 269.43,56.25 268.79,56.25 268.69,56.15 268.69,55.64 268.72,55.61 270.49,55.61 270.66,55.78
N23217182 on TOP: 272.02,65.49 272.02,66.28 271.24,67.06 270.68,67.06 270.01,67.73 270.01,68.92 269.99,68.95 270.01,68.98 270.05,69.26 269.88,69.5 269.88,72.63 271.59,74.33 277.5,74.33 278.19,73.65 281.47,73.65 281.72,73.39 281.72,72.55 281.64,72.48 278.72,72.48 278.6,72.35 276.62,72.35 275.8,73.16 272.27,73.16 271.84,72.73 271.84,72.3 271.71,72.17 271.05,72.17 270.67,71.79 270.67,67.45 270.81,67.31 271.29,67.31 272.27,66.33 272.27,65.49
N23217319 on TOP (solid shape): 279.78,70.48 281.74,70.48 281.8,70.42 281.8,70.04 281.73,69.97 279.2,69.97 278.77,69.54 278.77,69 278.69,68.92 278.42,68.92 278.32,69.02 278.32,70.37 278.7,70.75 279.51,70.75
N23330164 on TOP: 196.02,82.99 197.04,82.99 197.11,82.92 197.11,81.47 197.04,81.39 196.55,81.39 196.48,81.47 196.48,81.85 196.4,81.93 196.1,81.93 195.87,82.16 195.87,82.84
N23333711 on BOTTOM (solid shape): 186.75,58.66 186.75,57.16 186.62,57.04 186.24,57.04 186.12,57.16 186.12,58.66 186.32,58.86 186.55,58.86
N24852194 on TOP (solid shape): 157.76,96.74 157.76,96.7 157.8,96.7 159.25,95.25 159.25,91.35 159.05,91.15 157.81,91.15 157.51,90.85 157.51,90.49 157.33,90.31 155.88,90.31 155.37,90.83 155.37,93.33 156.9,94.86 156.9,96.77 157.02,96.89 157.61,96.89
N24852299 on TOP (solid shape): 158.67,90 158.67,88.2 158.66,88.19 158.62,88.02 158.66,87.84 158.67,87.83 158.67,87.36 158.4,87.09 157.33,87.09 157.21,87.15 157.08,87.16 157.06,87.16 156.72,87.49 156.72,88.31 156.54,88.49 156.16,88.49 155.75,88.89 155.75,89.93 155.91,90.09 158.57,90.09 158.58,90.09
N24852549 on TOP (solid shape): 160.35,94.17 160.55,94.12 160.75,94.17 161.44,94.17 162.32,93.29 162.56,93.29 162.79,93.06 162.79,92.6 162.69,92.5 162.12,92.5 161.9,92.28 161.9,92.07 160.99,91.15 160.99,90.57 160.91,90.49 160.65,90.49 160.65,90.49 160.18,90.49 160.12,90.54 160.12,91.07 159.58,91.61 159.58,94.07 159.68,94.17
N24852575 on TOP (solid shape): 160.77,87.57 161.37,87.57 161.37,86.86 161.19,86.68 160.33,86.68 160.28,86.73 160.28,88.18 160.77,88.18
N24852818 on TOP (solid shape): 162.92,92.17 162.92,91.48 162.89,91.46 162.81,91.46 162.49,91.13 162.49,88.91 162.65,88.74 162.76,88.74 162.79,88.71 163.4,88.71 163.55,88.56 163.55,87.95 163.15,87.55 161.94,87.55 161.94,88.71 161.57,88.71 161.57,89.19 161.33,89.43 161.29,89.43 161.29,91.17 162.1,91.98 162.1,92.19 162.13,92.22 162.87,92.22
N26183937 on BOTTOM: 94.6,104.94 95.13,104.94 95.18,104.89 95.18,103.34 95.13,103.29 94.62,103.29 94.55,103.36 94.55,104.89
N26485146 on BOTTOM (solid shape): 164.46,76.51 164.46,75.59 164.35,75.48 163.71,75.48 163.66,75.53 163.66,76.16 163.53,76.29 162.89,76.29 162.76,76.43 162.76,76.85 162.89,76.98 163.99,76.98
N26487268 on BOTTOM (solid shape): 156.45,76.75 156.45,76.33 156.31,76.19 155.65,76.19 155.48,76.02 155.48,75.63 155.33,75.48 154.77,75.48 154.7,75.55 154.7,76.54 155,76.85 156.35,76.85
N29091068 on TOP (solid shape): 95.89,107.16 98.24,107.16 98.54,106.87 98.54,104.48 98.23,104.18 94.34,104.18 93.46,105.07 93.46,106.92 93.85,107.31 95.74,107.31
N29091068 on BOTTOM (solid shape): 93.43,107.53 93.86,107.53 93.96,107.43 95.74,107.43 95.92,107.25 98.38,107.25 98.54,107.1 98.54,104.94 98.43,104.84 95.95,104.84 95.45,105.33 94.59,105.33 94.09,105.83 92.97,105.83 92.9,105.75 92.81,105.76 92.8,105.77 92.72,105.8 92.64,105.81 92.36,105.81 92.34,105.83 92.34,107.89 92.47,108.01 92.95,108.01
N29092457 on BOTTOM (solid shape): 85.94,110.45 85.94,109.64 86.24,109.34 88.24,109.34 89.14,108.44 89.14,105.45 89.07,105.38 88.53,105.38 87.43,104.28 85.1,104.28 84.79,104.58 84.79,106.62 84.62,106.79 84.08,106.79 83.98,106.69 83.98,104.66 83.88,104.56 81.07,104.56 80.79,104.84 80.79,108.84 80.82,108.87 80.82,109.64 81.87,110.69 85.7,110.69
N29129873 on BOTTOM: 121.57,99.99 120.91,99.99 120.43,100.47 119.59,100.47 119.57,100.44 119.06,100.44 118.96,100.55 118.96,100.98 120.89,100.98 121.68,100.19 121.68,100.09
N29129876 on BOTTOM: 121.98,100.47 121.8,100.47 121.32,100.95 121.32,102.45 121.11,102.66 120.32,102.66 120.22,102.56 120.22,102.4 120.07,102.25 119.43,102.25 119.25,102.43 119.25,103.24 119.58,103.57 121.57,103.57 121.9,103.24 121.9,101.28 122.11,101.08 122.11,100.6
N29130035 on BOTTOM (solid shape): 126.54,95.3 126.54,95.2 127.59,94.15 127.65,94.09 128.6,94.09 128.67,94.07 128.74,94.07 128.86,93.95 128.86,93.58 128.75,93.48 128.35,93.48 128.35,93.48 127.75,93.48 126.56,94.67 126.43,94.67 126.35,94.75 126.35,95.39 126.45,95.39
N29344201 on BOTTOM (solid shape): 121.64,95.76 121.63,95.76 121.63,95.56 120.86,94.79 120.44,94.79 120.3,94.92 120.3,95.14 120.99,95.83 121.64,95.83
N29344201 on TOP: 120.3,96.47 120.3,94.93 120.43,94.8 121.14,94.8 121.32,94.98 121.32,96.18 121.62,96.48 121.62,97.42 121.52,97.52 121.12,97.52 120.79,97.19 120.79,96.95
N29344430 on BOTTOM (solid shape): 122.08,95.03 122.08,94.78 121.14,93.84 121.14,93.74 121.09,93.69 120.15,93.69 120.1,93.74 120.1,94.14 120.14,94.19 120.92,94.19 121.87,95.14 121.98,95.14
N29548224 on BOTTOM: 92.44,105.22 93.38,105.22 93.51,105.09 94.07,105.09 94.24,104.91 94.24,104.38 93.99,104.13 92.44,104.13 92.39,104.18 92.39,104.3 92.52,104.43 93.2,104.43 93.28,104.51 93.28,104.89 93.23,104.94 92.49,104.94 92.44,104.99
N29548894 on BOTTOM (solid shape): 89.19,105.17 89.19,103.95 88.99,103.75 88.55,103.75 88.43,103.87 88.43,105.04 88.6,105.22 89.14,105.22
N29612662 on BOTTOM (solid shape): 123.29,65 123.44,65 123.5,64.93 123.5,64.86 123.35,64.71 122.87,64.71 122.11,65.47 121.73,65.47 121.68,65.52 121.68,65.85 121.7,65.87 122.41,65.87
N29612764 on BOTTOM (solid shape): 123.22,60.54 123.22,59.24 123.1,59.12 122.62,59.12 122.45,59.28 122.45,59.44 121.52,60.36 121.52,60.87 121.57,60.92 122.4,60.92 122.46,60.97 122.79,60.97
N29796111 on BOTTOM (solid shape): 89.93,103.14 89.93,102.54 89.93,102.53 89.93,102.12 90.09,101.96 90.37,101.96 90.46,101.87 90.46,100.22 90.43,100.19 89.95,100.19 89.72,100.42 89.72,100.9 89.21,101.41 89.21,102.91 89.49,103.19 89.87,103.19
N39556609 on TOP: 77.02,63.94 69.4,63.94 68.26,65.09 68.26,68.87 65.28,71.86 65.28,74.35 65.59,74.66 67.24,74.66 68.56,73.34 78.04,73.34 78.41,72.97 78.41,68.12 77.53,67.25 77.53,64.45
N39556609 on BOTTOM: 73.92,72.27 74.23,72.27 74.38,72.42 74.58,72.42 74.89,72.12 75.04,72.12 75.96,73.03 76.64,73.03 77,72.67 77.4,72.67 77.58,72.85 77.81,72.85 78.04,72.62 78.32,72.62 78.5,72.8 78.78,72.8 78.98,72.6 79.18,72.6 79.33,72.75 79.77,72.75 79.87,72.65 80.07,72.65 80.5,73.08 83.68,73.08 83.8,73.21 83.8,75.16 83.68,75.29 74.28,75.29 74.28,74.84 73.39,73.95 73.39,73.34 73.86,72.88 73.86,72.34
N39920601 on TOP: 263.55,92.55 264.97,92.55 265.51,92.02 265.51,91.1 266.02,90.59 266.02,88.08 265.58,87.65 265.58,85.97 265.99,85.56 265.99,84.73 265.89,84.62 265.08,84.62 264.92,84.78 264.92,86.23 263.2,87.95 263.2,89.65 263.45,89.91 264.77,89.91 265,90.14 265,90.9 264.64,90.9 264.59,90.95 264.59,91.53 264.14,91.99 263.55,91.99 263.48,92.07 263.48,92.47
N40033673 on BOTTOM (solid shape): 275.9,138.63 275.9,137.3 275.79,137.2 274.89,137.2 274.8,137.28 274.8,137.74 275.3,138.1 274.8,138.47 274.8,138.73 274.91,138.83 275.69,138.83
N40088146 on TOP: 98.9,79.92 95.99,79.92 95.37,79.3 95.37,77.36 95.09,77.08 93.39,77.08 93.36,77.05 91.15,77.05 91.08,76.98 91.08,76.48 91.28,76.28 95.47,76.28 95.96,76.77 95.96,77.77 96.09,77.9 97.09,77.9 97.85,78.65 99.23,78.65 99.28,78.61 99.28,79.11 99.04,79.35 99.04,79.78
N40089937 on TOP: 96.45,84.16 96.45,88.56 97.44,89.55 97.44,95.29 96.38,96.35 96.38,100.39 96.83,100.85 98.49,100.85 98.69,100.65 98.69,98.34 99.04,97.98 99.96,97.98 100.82,97.12 100.82,95.54 100.59,95.31 99.93,95.31 99.73,95.11 99.73,89.19 98.59,88.06 98.59,84.49 98.05,83.94 96.67,83.94
N40263128 on TOP (solid shape): 127.49,79.23 127.49,77.56 127.75,77.3 127.75,76.97 127.67,76.9 127.11,76.9 126.63,76.42 125.75,76.42 125.57,76.59 125.57,76.78 125.58,76.79 126.04,76.79 126.04,78.29 126.04,78.29 126.04,78.43 125.55,78.43 125.55,79.06 125.86,79.37 127.36,79.37
N40263481 on TOP: 250.75,65.95 250.71,65.99 250.28,65.99 250.18,65.9 249.26,65.9 249.06,65.7 249.06,62.88 249.11,62.83 250.22,62.83 250.43,63.03 250.43,63.14 250.75,63.46
N40264076 on TOP: 265.26,80.94 266.99,80.94 267.09,80.83 267.09,79.36 266.94,79.21 265.72,79.21 265.62,79.31 264.96,79.31 264.09,80.17 264.09,81.76 264.19,81.86 264.77,81.86 264.92,81.7 264.92,81.27
N40660374 on TOP: 222.16,46.01 222.08,46.09 222.08,48.35 222.89,49.16 225.66,49.16 225.68,49.17 226.04,48.81 226.84,48.81 226.84,48.67 226.86,48.65 226.86,48.42 226.91,48.37 226.91,45.58 225.71,44.39 222.13,44.39 222.02,44.49 222.02,45.32 222.16,45.46
N40660374 on BOTTOM: 226.42,46.16 225.79,46.8 225.79,47.54 226.17,47.92 227.19,47.92 227.77,47.33 228.13,47.33 228.71,47.92 229.74,47.92 229.92,48.1 229.92,48.93 229.85,49.01 229.41,49.01 229.21,49.22 229.21,50.03 229.36,50.18 230.23,50.18 230.38,50.03 230.38,49.34 230.63,49.09 230.94,49.09 231.52,48.51 231.52,46.77 231.34,46.6 229.22,46.6 228.79,46.16
N40660374 on IN4: 231.5,47.29 230.76,46.55 229.29,46.55 228.98,46.25 226.32,46.25 225.76,46.8 225.76,48.61 226.34,49.19 231.34,49.19 231.5,49.04
N41608255 on TOP (solid shape): 168.41,82.79 168.41,81.55 168.31,81.44 166.66,81.44 166.48,81.62 166.48,82.71 166.84,83.07 168.13,83.07
N41608262 on BOTTOM: 154.42,79.84 154.42,81.19 154.57,81.34 154.77,81.34 154.92,81.19 154.92,80.83 155.05,80.71 156.27,80.71 156.42,80.56 156.42,79.87 156.27,79.72 154.54,79.72
N41611184 on BOTTOM: 88.82,110.73 88.82,109.94 86.98,109.94 86.86,110.06 86.86,110.79 86.95,110.88 88.66,110.88
N41615282 on BOTTOM: 117.1,52.06 118.65,52.06 118.75,51.96 118.75,50.18 118.65,50.08 117.15,50.08 117,50.23 117,51.96
N41768122 on BOTTOM: 141.87,95.8 143.65,95.8 144.19,95.25 144.19,90.75 143.74,90.29 136.31,90.29 136.08,90.52 136.08,96.91 135.65,96.91 135.63,96.93 135.63,97.48 135.92,97.78 135.92,98.92 136,99 136.56,99 136.64,98.92 136.64,96.68 136.84,96.48 139.86,96.48 139.99,96.61 141.41,96.61 141.46,96.56 141.46,96.2
N41768359 on BOTTOM (solid shape): 146.97,99.81 146.97,98.31 147.3,97.98 147.3,97.22 148.88,95.64 152.1,95.64 152.36,95.39 152.36,92.75 150.4,90.79 146.01,90.79 145.07,91.73 145.07,99.22 145.7,99.86 146.92,99.86
N41769790 on BOTTOM: 147.43,98.95 147.43,99.68 147.25,99.86 147.13,99.86 147.02,99.76 147.02,98.49 147.46,98.06 147.46,97.32 147.81,96.96 148.17,96.96 148.24,97.04 148.24,98.13
N41769795 on BOTTOM (solid shape): 149.21,97.83 149.21,97.12 149.42,96.9 152.17,96.9 152.36,96.71 152.36,96.1 152.26,96 149.16,96 148.62,96.54 148.62,97.85 148.64,97.88 149.16,97.88
N41772153 on BOTTOM: 138.13,100.47 138.13,100.09 137.73,99.7 137.15,99.7 137.15,101.99 138.16,103 141.69,103 142.87,104.18 145.7,104.18 146.54,103.34 146.54,102.3 144.41,102.3 144.18,102.07 144.18,101.56 143.72,101.1 141.89,101.1 141.61,100.82 138.48,100.82
N41773891 on BOTTOM (solid shape): 151.55,101.59 151.55,100.09 151.52,100.06 150.81,100.06 150,100.88 148.95,100.88 148.89,100.94 148.89,101.12 148.93,101.15 150.25,101.15 150.76,101.66 151.47,101.66
N41773970 on BOTTOM: 151.41,101.88 151.72,101.56 151.72,101.08 151.77,101.03 152.46,101.03 152.61,101.18 152.61,102.37 152.49,102.5 150.71,102.5 150.42,102.21 150.42,101.88
N41775214 on BOTTOM (solid shape): 150.45,99.83 151.32,99.83 151.39,99.76 151.39,99.28 151.3,99.19 150.64,99.19 149.84,99.99 149.17,99.99 149.14,100.01 148.95,100.01 148.85,100.11 148.85,100.22 149.01,100.37 149.92,100.37
N41952574 on TOP: 249.68,51.17 249.68,52.55 249.84,52.72 250.22,52.72 250.66,53.15 251.55,53.15 252.03,52.67 252.03,51.29 251.75,51.02 249.83,51.02
N42801106 on TOP: 111.77,100.22 111.77,100.04 111.6,99.87 110.28,99.87 109.76,99.35 108.94,99.35 108.81,99.48 108.81,100.01 109.41,100.61 109.41,103.44 109.66,103.69 110.55,103.69 110.63,103.62 110.63,103.19 110.63,103.18 110.63,102.49 111.57,101.55 111.57,100.42
N43195754 on BOTTOM (solid shape): 131.99,73.95 133.01,73.95 133.07,74.01 134.95,74.01 135.01,74.07 136.22,74.07 136.36,73.93 136.36,72.83 136.2,72.68 135.24,72.68 134.78,72.22 133.49,72.22 133.42,72.25 133.39,72.33 133,72.71 132.62,72.33 132.59,72.25 132.52,72.22 131.4,72.22 131.35,72.28 131.35,74.13 131.4,74.18 131.76,74.18
N43196090 on TOP (solid shape): 140.09,73.21 140.09,71.11 139.99,71.01 139.48,71.01 139.28,71.21 139.28,73.11 139.46,73.29 140.01,73.29
N43196090 on BOTTOM (solid shape): 141.77,79.72 141.77,75.04 140.95,74.23 140.95,72.83 140.85,72.73 138.72,72.73 138.52,72.94 138.52,79.9 138.82,80.2 141.28,80.2
N43196119 on TOP: 137.39,71.09 136.98,71.5 136.98,71.97 137.05,72.05 137.76,72.05 137.8,72.08 138.55,72.08 138.63,72.01 138.63,71.17 138.55,71.09
N43196335 on BOTTOM (solid shape): 137.88,79.44 137.88,76.03 137.52,75.68 132.78,75.68 132.39,75.3 131.89,75.3 131.76,75.42 131.76,79.34 131.79,79.37 132.92,79.37 133.02,79.47 135.39,79.47 135.74,79.82 137.5,79.82
N43202964 on TOP (solid shape): 160.26,64.86 160.26,63.66 159.22,62.62 158.23,62.62 158.18,62.67 158.18,65.16 158.48,65.47 159.65,65.47
N43202964 on BOTTOM: 158.1,66.33 158.1,62.88 158.26,62.71 160.19,62.71 160.26,62.78 160.26,64.99 160.12,65.13 159.46,65.13 159.24,65.34 159.24,66.2 158.99,66.46 158.23,66.46
N43202984 on BOTTOM: 155.79,66.51 155.86,66.43 155.86,64.83 155.46,64.83 155.2,64.58 155.2,62.88 154.82,62.5 152,62.5 151.37,63.13 151.37,67.2 151.7,67.53 153.4,67.53 153.58,67.35 153.58,67.09 154.16,66.51
N43203016 on BOTTOM: 145.5,63.64 145.45,63.69 144.74,63.69 144.51,63.92 144.51,65.21 144.92,65.21 144.92,65.77 144.51,65.77 144.51,67.02 144.66,67.17 148.02,67.17 148.45,67.6 150.3,67.6 150.47,67.44 150.47,63.72 150.39,63.64
N43203049 on TOP: 155.25,66.56 154.16,66.56 154.06,66.66 154.06,70.14 154.26,70.34 155.41,70.34 155.64,70.12 155.64,68.92 155.43,68.72 155.43,66.74
N43203071 on BOTTOM: 155.48,64.53 155.48,62.8 155.56,62.72 156.63,62.72 156.68,62.78 156.68,63.49 156.57,63.59 156.17,63.59 156.04,63.72 156.04,64.45 155.91,64.58 155.53,64.58
N43980886 on TOP (solid shape): 104.41,61.63 104.41,61.6 104.51,61.29 104.83,61.18 104.86,61.18 105.05,60.99 105.05,60.68 105.3,60.43 105.3,59.67 105.28,59.65 104.7,59.65 104.34,60.01 104.34,60.89 104.08,61.15 103.96,61.15 103.82,61.18 103.68,61.15 103.13,61.15 102.98,61.3 102.98,61.51 103.14,61.66 104.37,61.66
N45551848 on TOP: 19.01,65.35 19.01,59.44 18.57,59 12.68,59 12.09,59.58 12.09,61.03 11.43,61.69 11.43,62.76 11.56,62.88 13.54,62.88 13.91,63.25 13.91,65.49 14.05,65.63 18.73,65.63
N45551858 on TOP: 13.77,68.01 14.12,68.01 14.81,67.33 14.81,66.51 14.66,66.36 14.05,66.36 13.67,66.74 13.67,67.91
N45551870 on BOTTOM: 6.1,66.51 8.36,66.51 8.59,66.29 8.59,64.74 8.43,64.58 7.98,64.58 7.82,64.74 7.82,65.57 7.55,65.85 6.12,65.85 6.02,65.96 6.02,66.44
N45551892 on BOTTOM: 4.09,66.44 4.17,66.51 5.69,66.51 5.77,66.44 5.77,64.8 5.61,64.65 4.69,64.65 4.09,65.24
N45551908 on BOTTOM: 3.43,62.96 5.67,62.96 5.79,62.83 5.79,62.35 5.59,62.15 3.38,62.15 3.28,62.25 3.28,62.81
N45959248 on BOTTOM: 237.32,47.79 242.5,47.79 243.01,47.28 243.01,44.54 242.73,44.26 239.99,44.26 239.43,44.82 239.43,45.68 239.33,45.78 239.33,45.93 239.04,46.22 237.52,46.22 237.11,46.63 237.11,47.58
N45959248 on BOTTOM: 234.15,49.9 234.15,49.19 234.73,48.6 234.73,47.45 234.06,46.78 234.06,45.84 233.91,45.69 233.2,45.69 232.59,46.3 232.59,46.68 231.92,47.35 231.92,47.8 232.17,48.04 232.27,48.04 232.29,48.07 232.29,48.9 232.23,48.96 231.4,48.96 231.17,49.19 231.17,50.23 231.32,50.39 233.66,50.39
N45959248 on IN1: 231.88,48.58 232.22,48.91 235.87,48.91 235.88,48.91 236.22,48.91 236.96,48.18 239.52,48.18 240.95,46.75 242.62,46.75 242.76,46.62 242.76,45.58 242.55,45.38 240.85,45.38 240.85,45.38 232.46,45.38 231.88,45.96
N45959248 on IN3: 233.24,47.88 233.26,47.89 233.84,47.89 233.97,48.02 233.97,48.53 234.35,48.91 237.04,48.91 237.5,48.45 241.18,48.45 242.38,47.26 242.38,45.78 241.94,45.35 232.85,45.35 232.04,46.16 232.01,46.16 232.01,46.17 231.83,46.35 231.83,48.15 232.11,48.43 232.69,48.43
N45959248 on IN4: 234.32,48.91 236.84,48.91 237.83,47.92 237.83,46.95 236.97,46.09 237.12,45.94 237.12,45.73 239.86,45.73 240.85,46.72 242.05,46.72 242.27,46.49 242.27,45.2 242.1,45.02 233.49,45.02 232.64,45.87 232.64,46.3 232.08,46.86 232.08,48.3 232.97,49.19 234.04,49.19
N46508024 on TOP: 18.21,70.2 19.18,70.2 19.33,70.04 19.33,69.74 19.1,69.51 19.1,68.72 19,68.62 18.01,68.62 17.88,68.5 17.63,68.5 17.5,68.62 17.5,69.49
N46508038 on TOP: 21.15,75.02 21.26,74.91 21.26,73.5 21.16,73.4 21.16,71.47 21.06,71.37 19,71.37 18.67,71.7 18.67,74.86 18.72,74.92 19.81,74.92 19.89,74.85 20.37,74.85 20.55,75.02
N46508050 on TOP: 18.85,76.27 20.47,76.27 20.52,76.22 20.52,75.3 20.25,75.02 19.86,75.02 19.71,75.18 18.82,75.18 18.72,75.28 18.72,76.14
N46508065 on TOP: 18.31,75.48 18.31,72.68 18.3,72.67 18.3,70.38 18.04,70.12 14.2,70.12 13.72,70.6 13.72,75.25 14.07,75.61 18.18,75.61
N46562271 on BOTTOM (solid shape): 187.77,58.69 187.77,57.16 187.66,57.06 187.23,57.06 187.08,57.21 187.08,58.69 187.33,58.94 187.51,58.94
N46562298 on TOP (solid shape): 148.37,113.02 148.37,111.77 148.27,111.67 147.3,111.67 146.77,112.2 146.77,113.07 146.87,113.17 148.22,113.17
N46562316 on BOTTOM (solid shape): 185.94,64.03 185.94,63.14 185.86,63.07 185.38,63.07 184.92,63.52 184.92,63.83 185.25,64.16 185.81,64.16
N46562349 on TOP: 222.23,100.16 222.46,100.16 222.61,100.01 222.61,99 222.51,98.89 221.93,98.89 221.47,99.35 220.99,99.35 220.7,99.64 220.7,100.73 220.88,100.91 221.49,100.91
N46562358 on TOP: 226.15,96.66 226.91,96.66 227.09,96.48 227.09,95.47 227.34,95.21 227.34,94.96 227.26,94.88 226.93,94.88 226.78,95.03 226.25,95.03 226.22,95.06 226.22,95.9 225.97,96.15 225.97,96.48
N47749037 on TOP: 172.58,64.99 173.06,64.5 173.06,63.54 172.81,63.28 171.38,63.28 171.15,63.51 171.15,64.96 171.18,64.99
N47749037 on BOTTOM: 172.25,64.68 175.24,64.68 175.65,64.27 175.65,62.72 175.24,62.32 174.74,62.32 173.76,63.3 173.55,63.3 172.68,62.42 172.04,62.42 171.84,62.62 171.84,64.27
N47750172 on TOP: 136.41,62.9 136.57,62.74 138.39,62.74 138.61,62.53 138.61,62.07 138.41,61.87 138.16,61.87 137.78,61.49 137.75,61.49 137.36,61.1 136.65,61.1 136.35,61.41 136.35,61.54 135.62,62.27 135.62,62.85 135.67,62.9
N47750172 on BOTTOM: 134.05,62.47 135.7,62.47 135.85,62.62 135.85,62.85 135.95,62.95 136.38,62.95 136.53,62.8 136.53,61.51 136.41,61.38 134.71,61.38 133.94,62.14 133.94,62.37
N47750211 on TOP: 134.83,66.97 136.08,66.97 136.31,66.74 136.31,66.51 135.77,65.98 135.7,65.98 135.52,65.8 135.52,65.54 135.21,65.24 134.6,65.24 134.5,65.34 134.5,66.64
N48013537 on TOP: 252.56,62.27 252.87,61.96 252.87,61.58 252.64,61.35 252.13,61.35 252.06,61.28 249.82,61.28 249.58,61.05 249.58,60.65 249.43,60.49 248.36,60.49 248.29,60.57 248.29,62.09 248.46,62.27
N49159192 on TOP: 33.94,50.16 35.05,50.16 35.16,50.06 35.16,49.14 35,48.99 34.11,48.99 33.78,49.32 33.78,50
N49159192 on TOP: 29.31,49.95 29.87,49.95 30.23,50.31 30.66,50.31 30.84,50.49 31.4,50.49 31.47,50.41 31.47,49.7 31.32,49.55 31.24,49.55 30.99,49.29 30.05,49.29 29.74,48.99 29.74,48.73 29.62,48.61 29.34,48.61 29.29,48.66 29.29,48.96 29.16,49.09 28.93,49.09 28.78,49.24 28.78,49.42
N49159192 on IN1: 30.43,50.41 32.46,50.41 32.84,50.79 33.66,50.79 34.44,50 34.44,49.78 34.14,49.47 33.63,49.47 32.62,48.45 31.14,48.45 30.76,48.84 30.38,48.84 29.9,49.32 29.9,49.88
N50065958 on TOP: 126.36,55.25 124.52,57.09 124.52,57.11 121.52,60.11 121.52,62.27 122.31,63.05 126.96,63.05 127.49,63.59 129.12,63.59 129.24,63.46 129.24,63.31 129.52,63.03 131.45,63.03 131.89,63.46 133.53,63.46 134.15,62.85 135.19,62.85 135.44,62.6 135.44,61.81 135.77,61.48 136.03,61.48 136.14,61.37 136.14,60.55 136.03,60.44 135.06,60.44 134.86,60.24 134.55,60.24 134.5,60.29 134.5,60.74 134.2,61.05 134.2,61.56 133.64,62.12 127.96,62.12 127.81,61.96 127.81,61.09 127.93,60.98 127.93,60.52 127.75,60.34 126.33,60.34 125.97,59.98 125.97,58.3 126.94,57.33 127.86,57.33 127.97,57.22 127.97,57.11 127.41,56.54 126.97,56.54 126.6,56.18 126.58,56.04 126.6,55.91 126.6,55.87 126.81,55.66 129.75,55.66 130.51,56.43 130.51,56.93 130.74,56.93 130.84,56.83 130.84,56.1 130.84,56.1 130.92,56.07 130.95,56 130.95,55.97 130.23,55.25
N50672395 on TOP: 142.5,111.32 143.49,111.32 143.6,111.43 143.6,111.61 143.77,111.78 144.1,111.78 144.22,111.9 144.22,112.29 144.2,112.31 143.71,112.31 143.64,112.39 142.42,112.39 142.27,112.23 142.27,111.55
N50672400 on TOP: 145.96,106.79 144,108.75 142.67,108.75 142.4,109.03 142.4,111.05 142.52,111.17 144.05,111.17 144.43,111.55 144.83,111.55 145.24,111.96 146.74,111.96 146.74,111.93 147.27,111.4 147.83,111.4 148.08,111.14 148.08,106.92 147.96,106.79
N50675461 on TOP (solid shape): 159.82,98.82 159.82,98.24 159.46,97.88 159.46,97.35 159.44,97.32 159.08,97.32 159.03,97.38 159.03,98.75 159.16,98.87 159.77,98.87
N50760102 on TOP (solid shape): 129.52,85.92 129.52,84.27 129.39,84.14 127.38,84.14 127.13,84.4 127.13,85.82 127.31,86 129.44,86
N50760102 on BOTTOM (solid shape): 130.33,86.93 130.33,84.19 130.29,84.14 129.57,84.14 129.47,84.04 129.47,82.77 129.03,82.34 129.03,81.22 128.73,80.92 124.69,80.92 124.51,81.09 124.51,82.24 124.7,82.44 126.63,82.44 126.73,82.54 126.73,83.1 126.6,83.22 125.08,83.22 124.88,83.43 124.88,86.07 125.6,86.79 127.29,86.79 127.59,87.09 130.18,87.09
N50760177 on BOTTOM: 133.35,84.55 133.35,86.96 133.83,87.44 137.09,87.44 138.23,87.44 138.61,87.06 138.61,85.06 138.51,84.95 134.7,84.95 134.24,84.5 133.4,84.5
N50760367 on BOTTOM (solid shape): 134.93,83.53 135.43,83.53 135.54,83.43 135.54,83.08 135.46,83 134.39,83 134.29,82.9 133.43,82.9 133.35,82.97 133.35,83.13 133.4,83.18 134.24,83.18 134.34,83.28 134.34,83.58 134.22,83.71 133.45,83.71 133.38,83.79 133.38,83.96 133.4,83.99 134.47,83.99
N50767551 on TOP (solid shape): 129.26,81.42 129.26,81.3 129.69,80.87 129.69,79.9 129.45,79.66 128.97,79.66 128.55,80.08 128.55,81.32 128.55,81.4 128.6,81.45 129.24,81.45
N50767551 on BOTTOM (solid shape): 130.99,81.91 130.99,81.25 130.32,80.57 130.32,79.96 129.92,79.57 129.26,79.57 129.08,79.75 129.08,80.36 130.68,81.96 130.94,81.96
N50767593 on TOP (solid shape): 130.63,83.58 130.63,82.57 130.56,82.49 128.37,82.49 128.27,82.59 128.27,83.61 128.37,83.71 130.51,83.71
N50768257 on TOP (solid shape): 60,107.33 60,106.64 60.36,106.29 61.67,106.29 62.38,105.57 62.38,104.93 62.29,104.84 57.07,104.84 56.85,105.05 56.85,107.33 57.08,107.56 59.78,107.56
N50768257 on BOTTOM: 61.77,104.11 62.48,104.11 62.61,104.24 62.61,106.48 62.57,106.51 59.39,106.51 59.13,106.78 59.13,107.57 58.78,107.91 57.31,107.91 56.69,107.29 56.69,104.98 56.85,104.81 60.26,104.81 60.44,104.63 61.25,104.63
